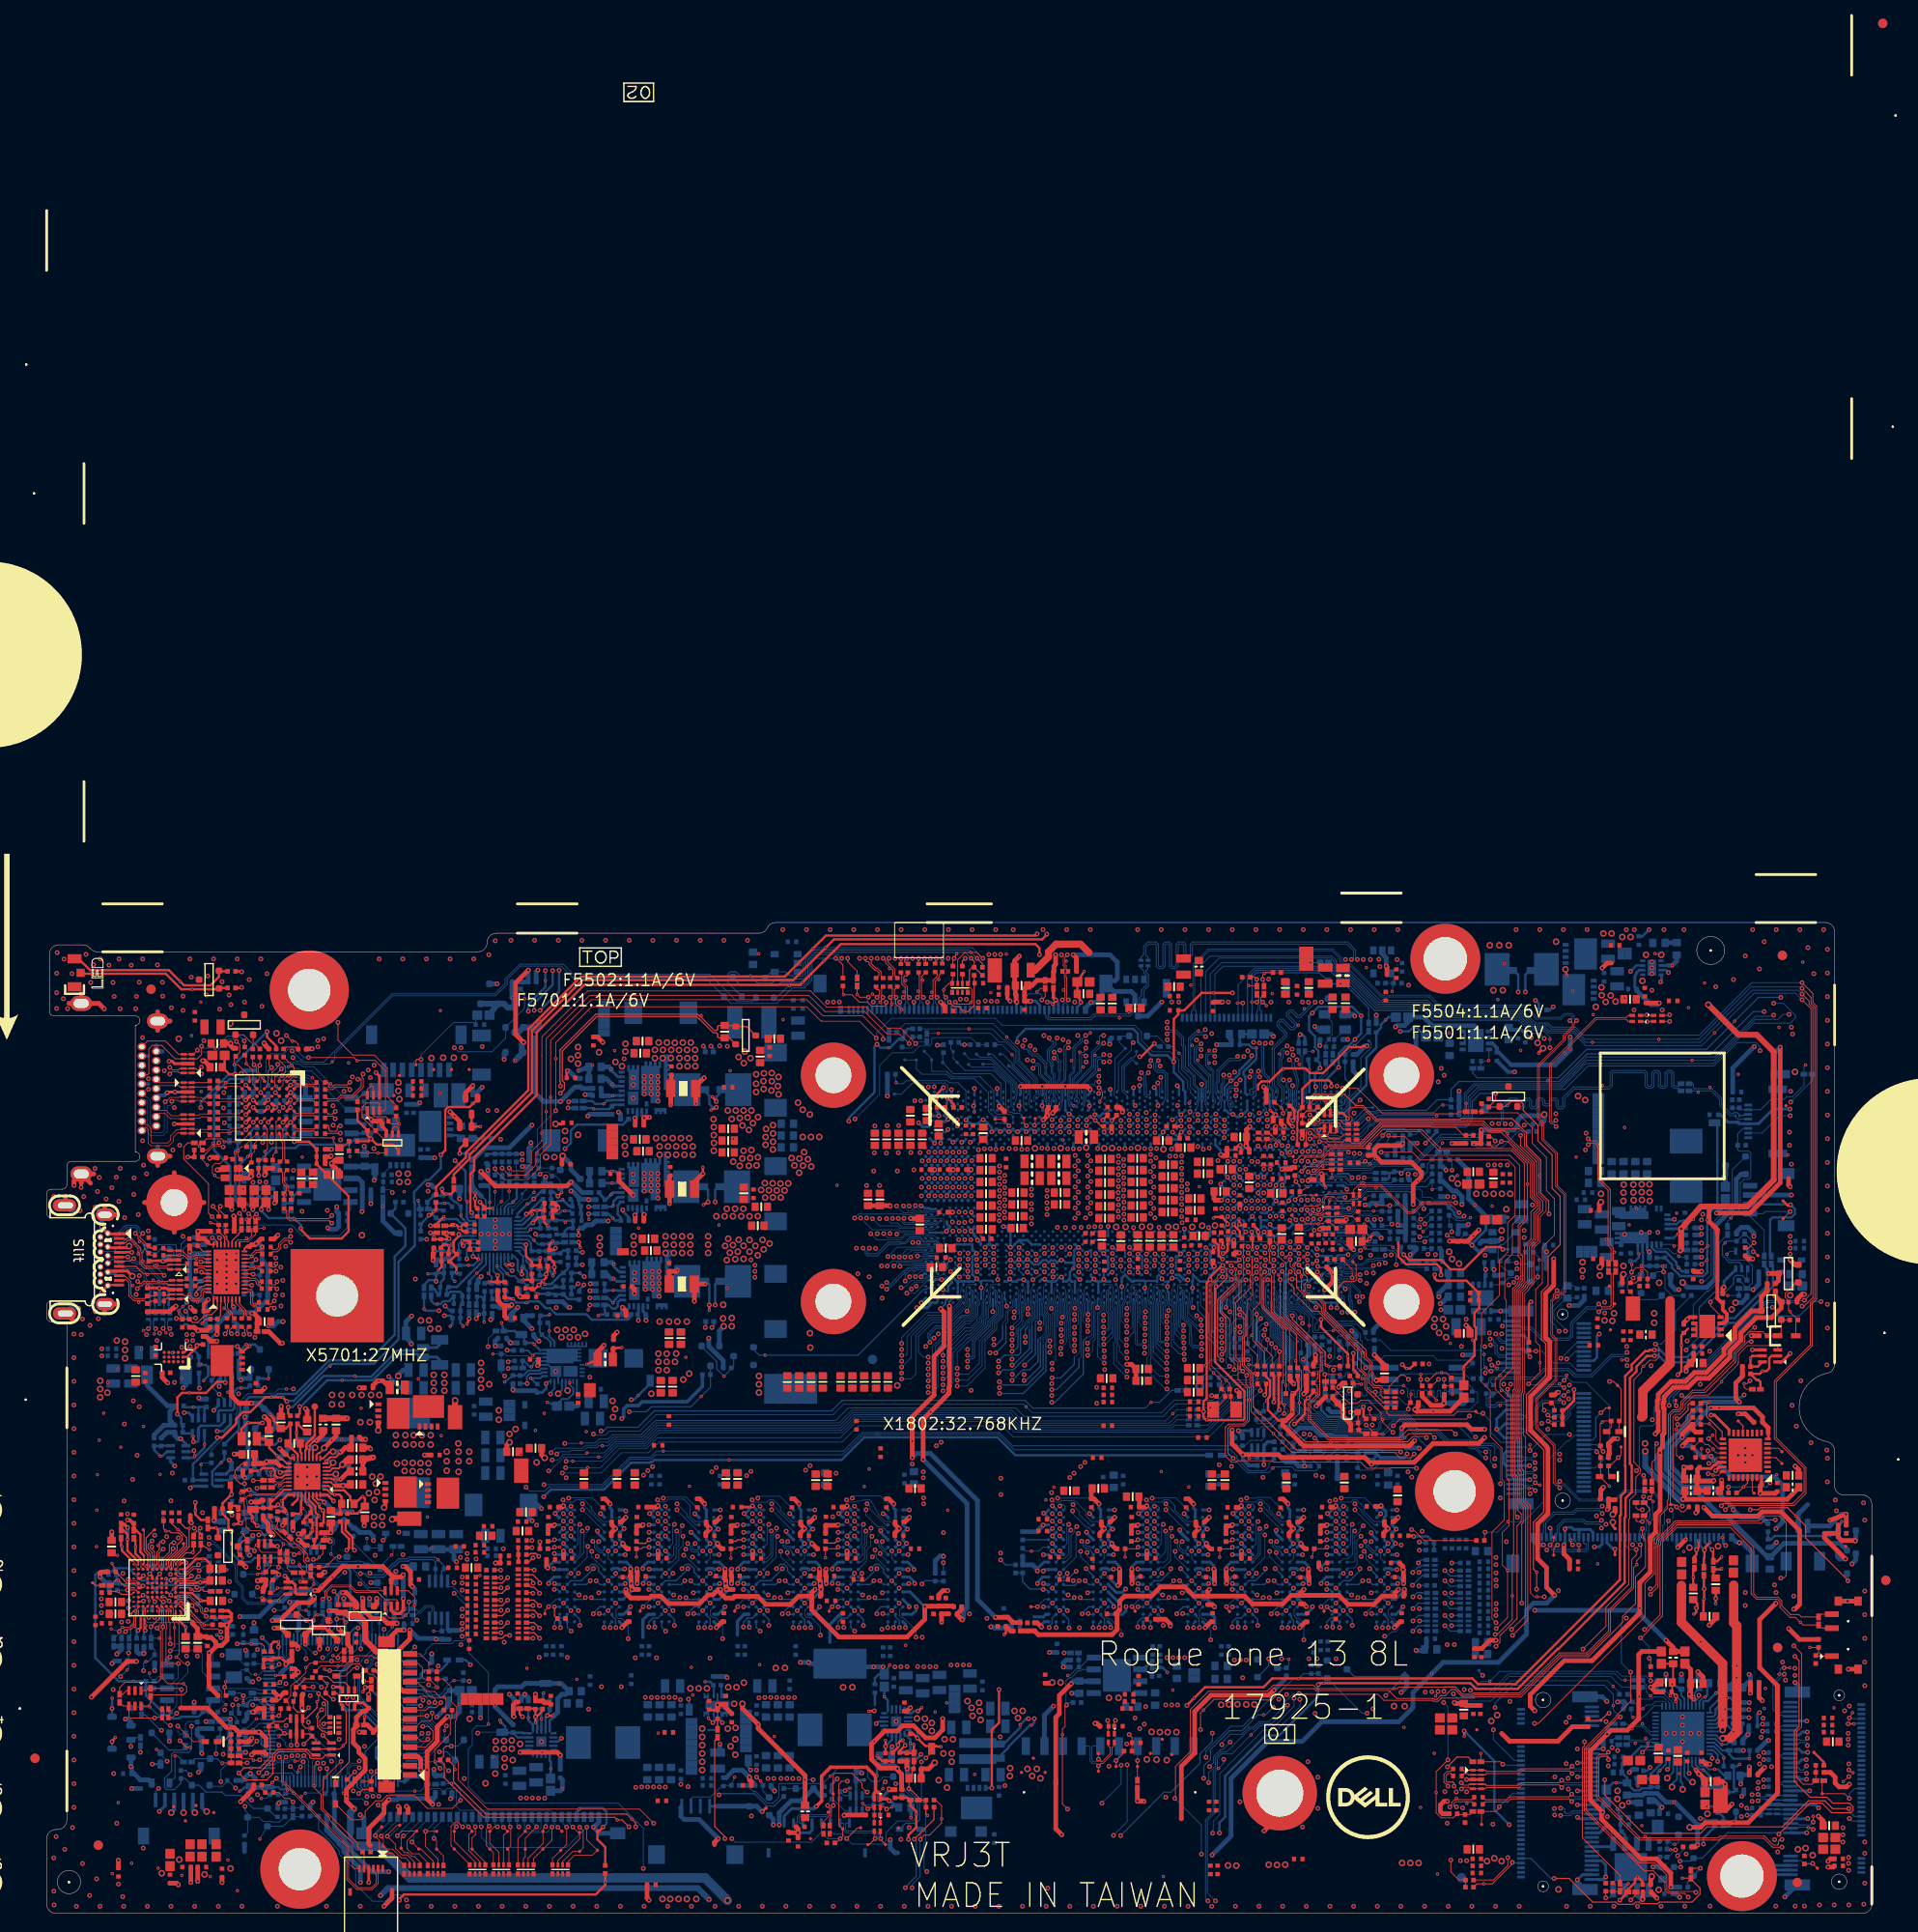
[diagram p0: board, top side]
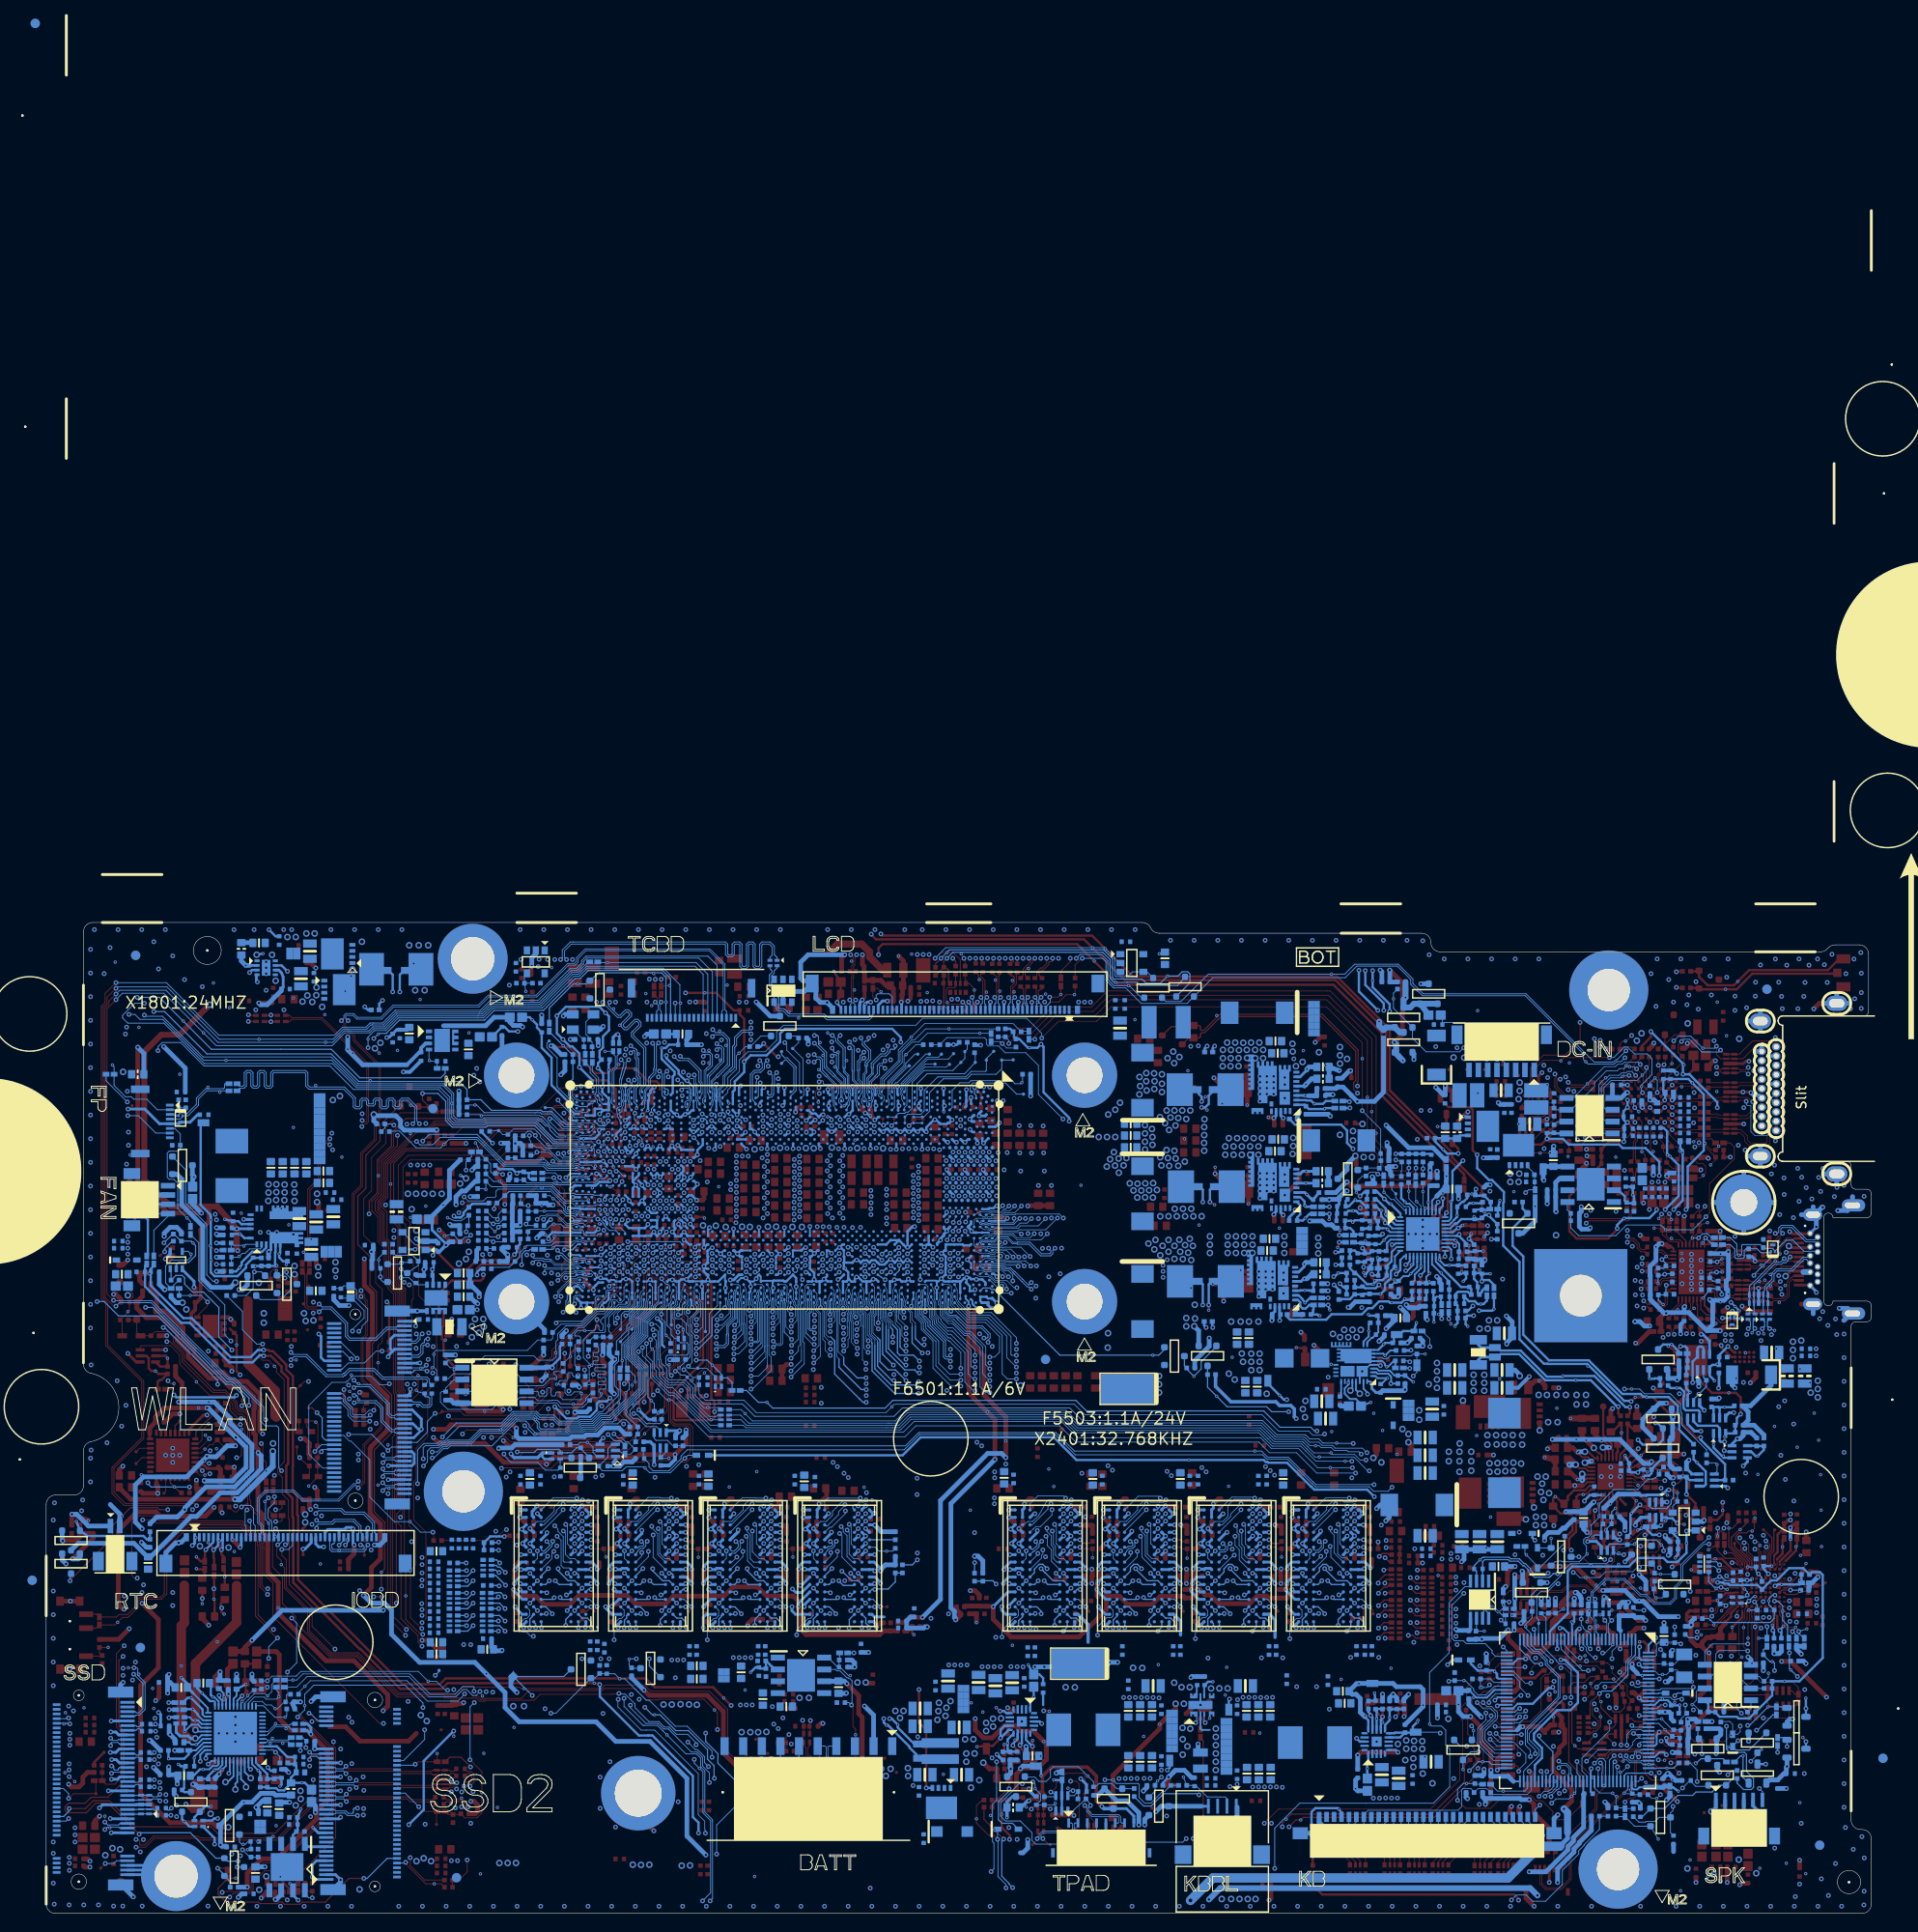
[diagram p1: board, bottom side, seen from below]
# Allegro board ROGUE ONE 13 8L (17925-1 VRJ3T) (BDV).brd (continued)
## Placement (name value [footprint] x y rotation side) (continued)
TP1804  TPAD14-OP-GP  [TPAD14-OP]  133.69 74.92 90 top
TP1806  TPAD14-OP-GP  [TPAD14-OP]  136.34 77.11 90 top
TP1807  TPAD14-OP-GP  [TPAD14-OP]  117.03 92.5 180 bottom
TP1808  TPAD14-OP-GP  [TPAD14-OP]  117.03 91.23 180 bottom
TP1903  TPAD14-OP-GP  [TPAD14-OP]  125.21 62.45 180 bottom
TP2201  TPAD14-OP-GP  [TPAD14-OP]  133.11 62.71 180 bottom
TP2202  TPAD14-OP-GP  [TPAD14-OP]  134.33 61.36 180 bottom
TP2402  TPAD14-OP-GP  [TPAD14-OP]  35.73 31.13 0 bottom
TP4401  TPAD28-2-GP  [TPAD28]  28.79 54.4 270 top
TP4601  TPAD14-OP-GP  [TPAD14-OP]  51.07 77.23 0 bottom
TP7202  TPAD14-OP-GP  [TPAD14-OP]  14.69 39.69 180 top
TP7203  TPAD14-OP-GP  [TPAD14-OP]  11.6 41.17 0 top
TP7204  TPAD14-OP-GP  [TPAD14-OP]  10.38 41.17 0 top
TP7205  TPAD14-OP-GP  [TPAD14-OP]  4.94 35.48 0 top
TP8304  TPAD14-OP-GP  [TPAD14-OP]  26.4 43.88 180 top
TP9101  TPAD14-OP-GP  [TPAD14-OP]  186.35 48.28 270 top
TP9102  TPAD14-OP-GP  [TPAD14-OP]  186.35 49.55 270 top
TP9103  TPAD14-OP-GP  [TPAD14-OP]  183.35 45.1 270 top
TP9104  TPAD14-OP-GP  [TPAD14-OP]  181.65 52.85 0 top
TPAD1  PTWO-CON8-16-GP  [196574-08021-3]  82.7 6.5 180 bottom
U2401  MEC1416-NU-D0-GP  [TQFP128-2H48]  31.54 21.79 180 bottom
U2502  SY6288C20AAC-GP  [SOT-23-5H56]  156.5 72.15 90 bottom
U2601  NCT7718W-GP  [MSOP8-1H44]  42.08 33.67 0 bottom
U2701  ALC3254-VA3-CG-GP  [QFN48J6-G465H40]  175.68 19.32 270 bottom
U4001  TPS22976DPUR-GP  [SON14J3020-G2610H34]  72.05 22.37 0 bottom
U4002  G5027RD1D-GP-U  [DFN8F3-G2517H32]  178.35 63.01 270 top
U4003  G5027RD1D-GP-U  [DFN8F3-G2517H32]  154.13 66.06 180 bottom
U4006  G5027RD1D-GP-U  [DFN8F3-G2517H32]  153.48 93.69 90 bottom
U4008  74LVC1G08GW-1-GP  [SC70-5H44]  182.03 70.12 0 bottom
U4302  S-1004NA23I-M5T1U-GP  [SOT-23-5H52]  20.11 42.06 90 bottom
U5501  SY6288C20AAC-GP  [SOT-23-5H56]  79.41 102 270 bottom
U5503  APL5324BI-TRG-GP  [SOT-23-5H58]  143.42 102.13 0 bottom
U5701  PS175HDMBGA64GTR2-B2-GP  [BGA64D7H51]  23.79 86.51 270 top
U5702  MX25L2006EM1I-12G-GP-U  [SOIC8H69]  30.27 85.62 90 bottom
U5703  TC7SZ08FU-LJ-CT-GP  [SC70-5H44]  37.12 82.7 0 top
U5801  APL5934KAI-TRG-GP-U  [SOIC8-G3530H63]  30.14 78.25 90 bottom
U6402  74LVC1G08GW-1-GP  [SC70-5H44]  32.42 23.06 0 top
U7101  TUSB546-DCIRNQR-1-GP  [QFN40J4060-G2848H32]  19.32 68.85 180 top
U7201  SN1703018ZQZR-GP  [BGA96G60-1H40]  11.85 34.94 180 top
U7202  W25Q80DVSNIG-GP-U  [SOIC8H69]  15.41 24.78 90 bottom
U7418  AON7403-GP-U  [PPAK-8P-3232H36]  18.84 59.33 90 top
U7419  NX20P5090UK-GP  [CSP15G154256H24]  13.63 59.71 270 top
U9102  NPCT750JAAYX-GP  [QFN32G5-G3D6H32]  182.41 49.17 270 top
USB1  SKT-USB30-63-GP  [SKT-USB30-118098-4]  2.02 70.19 270 top
WLAN1  SKT-NGFF75P-70-GP-U1  [40-42258-06741RHF-U1]  162.8 54.3 270 bottom
X1801  XTAL-24MHZ-182-GP  [OSC-3225-4P-3H36]  138.34 95.67 180 bottom
X1802  XTAL-32D768KHZ-98-GP  [SMD49-12H34]  126.51 54.07 90 top
X2401  XTAL-32D768KHZ-98-GP  [SMD49-12H34]  20.11 26.56 0 bottom
X5701  XTAL-27MHZ-192-GP  [SMD-OSC38H32]  19.88 79.44 180 top

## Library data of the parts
AFTP2507 AFTP2508 AFTP2601-AFTP2604 AFTP2901-AFTP2904 AFTP4301-AFTP4316 AFTP5001 AFTP6108-AFTP6114 AFTP6301-AFTP6306 AFTP6501-AFTP6525 AFTP6529-AFTP6539 AFTP6601 AFTP6602 AFTP6607-AFTP6609 = AFTE14P-75: tolerance: ZZ.AFT14.101
BATT1 = 50299-01001-002-U: tolerance: 20.F2460.010
BIOS1 = SOIC8-1H86: tolerance: 072.25128.0D61
C501 C805 C1139-C1142 C1711 C2201 C2206 C2207 C2221 C2406-C2408 C2410-C2414 C2416 C2420-C2423 C2428 C2429 C2502 C2602 C2605 C2608-C2610 C2612 C2614 C2714 C2721 C2722 C2726 C2729 C2740 C2742 C2744 C2746 C4007 C4010 C4034 C4037 C4039 C4040 C5507 C5726 C5736 C5744 C5750-C5752 C5755 C5756 C5761 C5765-C5767 C5773 C5774 C5777 C6101-C6104 C6106 C6307 C6309 C6501 C6502 C6504-C6506 C6605 C7115-C7118 C7206 C7244 C9108 C9112 C9113 EC1707 EC1712 EC1804 PC4438 PC4445 PC4518 PC5215 = C402H22: tolerance: 78.10421.2FLDL
C801-C804 C806 C1102-C1111 C1114 C1116 C1117 C1119 C1121 C1204-C1235 C1255 C1257-C1274 C1280-C1284 C1292-C1299 C1304-C1335 C1337-C1342 C1344-C1369 C1805 C1806 C2202-C2205 C2209-C2217 C2219 C2222-C2224 C2418 C2525 C4031 C4032 C4035 C4038 C4043 C5508 C5535 C5743 C7210 C9201 EC8905 PC4607 PC4708 PC4766 PC4809 PC4812 PC4866 PC4877 PC5108 PC5122 PC5202 PC5401 = C402H22: tolerance: 78.10523.5FLDL
C1112 C1113 C1115 C1118 C1122 C1128-C1135 C2208 C2220 C4041 C4042 C6317 C6318 C7205 PC1001-PC1032 PC1034 PC1036-PC1084 PC4509-PC4512 PC4514-PC4517 PC4525 PC4527 PC4529 PC4542 PC5104 PC5105 PC5107 PC5109 PC5201 PC5203 PC5205 PC5206 PC5404 PC5412 = C603H40: tolerance: 78.22610.5BLDL
C1120 C1123 C1136-C1138 C1237-C1246 C1275-C1279 C1288-C1291 C1371-C1379 C1390-C1399 C2501 C2601 C2727 C2730 C2732 C2733 C2745 C2907-C2909 C4006 C4008 C4012 C4013 C5502 C5517 C5518 C5742 C5746 C5747 C5749 C5764 C6105 C6320 C6323 C7119 C7208 C7211 C9106 C9109 PC5124 PC5402 PC5403 PC5413 PC5414 = C603H36: tolerance: 78.10610.5BLDL
C1201 C1203 C1236 C1286 C1301 C1303 C1336 C1343 C6306 C6308 C6310 C6319 PC4605 PC4630 PC4634 PC4653 = C402H22: tolerance: 078.47322.02FD
C1202 C1302 C2517 PC4420 PC4608 PC4625 PC4626 PC4628 PC4652 = C402H22: tolerance: 78.22321.2FLDL
C1256 C1370 C2409 C4303 C5757 C5758 C5762 C5768-C5770 C5775 C5776 PC4431 PC4613 PC4622 PC4635 PC4637 PC4654 PC5213 = C402H22: tolerance: 78.10322.2FLDL
C1285 C1388 = C402H22: tolerance: 78.3R374.1FL
C1701 C7217 C7218 PC5212 = C402H22: tolerance: 78.22124.2FLDL
C1710 C5753 C5759 C5763 C5771 = C402H22: tolerance: 078.47423.05FD
C1803 C1804 C1807 C1808 = C402H22: tolerance: 78.15034.1FLDL
C2218 C2604 C5503 C5515 C5521 PC4415 PC4421 PC4422 PC4507 PC4520 = C603H36: tolerance: 78.47520.5BLDL
C2405 C2613 = C402H22: tolerance: 78.10134.1FLDL
C2424 C2425 FC1103 FC5501 FC5502 FC5505 FC8911 FC8913 FC8932 FC8934 FC8943 FC8945 FC8946 FC8948 FC8949 FC8951-FC8954 = C402H22: tolerance: 78.18034.1FLDL
C2427 C2737 C4009 C7201-C7203 PC4524 PC5001 = C603H36: tolerance: 78.22523.5BLDL
C2435 C2436 C2441 C2603 C2607 PC4601 PC4611 PC4612 PC4623 PC4632 PC4640 = C402H22: tolerance: 78.22224.2FLDL
C2503 C5748 = C603H36: tolerance: 78.47422.5BLDL
C2606 = C603H36: tolerance: 78.47134.1BL
C2731 C2734-C2736 C2743 C5754 C5760 C5772 = C402-TO0D2H28: tolerance: 078.10610.05FD
C2739 C2741 C4301 C5778 C7301 C7306 PC4416 PC4417 PC4419 PC4425 PC4439 PC4440 PC5410 = C603H36: tolerance: 78.10522.5BLDL
C4001 C4002 PC4614 PC4618 = C402H22: tolerance: 78.47124.2FLDL
C4003 = C402H22: tolerance: 78.22423.5FL
C4004 C4005 C4306 C5514 EC4301 PC4401-PC4405 PC4407-PC4414 PC4427 PC4428 PC4502-PC4505 PC4519 PC4523 PC5002 PC5003 PC5111 PC5115 PC5209-PC5211 PC5216 = C805H58: tolerance: 78.10622.51LDL
C4302 C5512 C5516 C7302-C7304 C7307 EC2201 EC2402 EC2403 EC2712-EC2714 EC4302 EC4308 EC4311 EC4313 EC4701 EC5001 EC5505 EC8901-EC8904 EC8906-EC8934 EC8937-EC8950 PC4406 PC4501 PC4506 PC4508 PC4513 PC4521 PC4522 PC4528 PC4530-PC4532 PC4543 PC4602 PC4603 PC4631 PC4633 PC5004 PC5113 PC5114 PC5116 PC5204 PC5208 PC5214 PC5427 = C402H22: tolerance: 78.10422.5FLDL
C4304 C4305 EC2709-EC2711 PC4615 PC4620 PC4644 = C402H22: tolerance: 78.10324.2FLDL
C4343 C7401 = C402H22: tolerance: 78.15224.2FLDL
C4344 C5513 EC1706 EC2901-EC2904 EC4307 EC4312 PC4432 PC4433 PC4435 PC4526 PC4533 PC4616 PC4617 PC4619 PC4642 PC4643 PC4651 PC4706 PC4810 PC4813 = C402H22: tolerance: 78.10224.2FLDL
C5501 = C402H22: tolerance: 78.10421.2FLDL; signal model: Graser_C5501
C5504 = C402H22: tolerance: 78.10421.2FLDL; signal model: Graser_C5504
C5506 = C402H22: tolerance: 78.10421.2FLDL; signal model: Graser_C5506
C5509 = C402H22: tolerance: 78.10421.2FLDL; signal model: Graser_C5509
C5510 = C402H22: tolerance: 78.10421.2FLDL; signal model: Graser_C5510
C5511 = C402H22: tolerance: 78.10421.2FLDL; signal model: Graser_C5511
C5519 = C402H22: tolerance: 78.10421.2FLDL; signal model: Graser_C5519
C5531 = C402H22: tolerance: 78.10421.2FLDL; signal model: Graser_C5531
C5532 = C402H22: tolerance: 78.10421.2FLDL; signal model: Graser_C5532
C5533 = C402H22: tolerance: 78.10421.2FLDL; signal model: Graser_C5533
C5724 = C0201H13: tolerance: 078.R7574.01S1
C5727 = C402H22: tolerance: 78.10421.2FLDL; signal model: Graser_C5727
C5728 = C402H22: tolerance: 78.10421.2FLDL; signal model: Graser_C5728
C5729 C5730 = C402H22: tolerance: 78.20034.1FLDL
C5731 = C402H22: tolerance: 78.10421.2FLDL; signal model: Graser_C5731
C5732 = C402H22: tolerance: 78.10421.2FLDL; signal model: Graser_C5732
C5733 = C402H22: tolerance: 78.10421.2FLDL; signal model: Graser_C5733
C5734 = C402H22: tolerance: 78.10421.2FLDL; signal model: Graser_C5734
C5735 = C402H22: tolerance: 78.10421.2FLDL; signal model: Graser_C5735
C5737 = C402H22: tolerance: 78.10421.2FLDL; signal model: Graser_C5737
C5738 = C402H22: tolerance: 78.10421.2FLDL; signal model: Graser_C5738
C5739 = C402H22: tolerance: 78.10421.2FLDL; signal model: Graser_C5739
C5740 = C402H22: tolerance: 78.10421.2FLDL; signal model: Graser_C5740
C5741 = C402H22: tolerance: 78.10421.2FLDL; signal model: Graser_C5741
C5745 PC5405 PC5411 = C402H22: tolerance: 78.68034.1FLDL
C6107 = C402H22: tolerance: 78.10421.2FLDL; signal model: Graser_C6107
C6108 = C402H22: tolerance: 78.10421.2FLDL; signal model: Graser_C6108
C6302 = C402H22: tolerance: 078.22423.05FD; signal model: Graser_C6302
C6303 = C402H22: tolerance: 078.22423.05FD; signal model: Graser_C6303
C6304 C6305 C6321 C6322 EC1903 EC5503 EC5504 EC5506 EC6501-EC6504 PC4610 PC4624 PC4639 = C402H22: tolerance: 78.33034.1FLDL
C6311 = C402H22: tolerance: 078.22423.05FD; signal model: Graser_C6311
C6312 = C402H22: tolerance: 078.22423.05FD; signal model: Graser_C6312
C6313 = C402H22: tolerance: 078.22423.05FD; signal model: Graser_C6313
C6314 = C402H22: tolerance: 078.22423.05FD; signal model: Graser_C6314
C6315 = C402H22: tolerance: 078.22423.05FD; signal model: Graser_C6315
C6316 = C402H22: tolerance: 078.22423.05FD; signal model: Graser_C6316
C6324 = C402H22: tolerance: 078.22423.05FD; signal model: Graser_C6324
C6325 = C402H22: tolerance: 078.22423.05FD; signal model: Graser_C6325
C6326 = C402H22: tolerance: 078.22423.05FD; signal model: Graser_C6326
C6327 = C402H22: tolerance: 078.22423.05FD; signal model: Graser_C6327
C6401 = C402H22: tolerance: 78.10421.2FL
C7101 = C402H22: tolerance: 78.10421.2FLDL; signal model: Graser_C7101
C7102 = C402H22: tolerance: 78.10421.2FLDL; signal model: Graser_C7102
C7103 = C402H22: tolerance: 78.10421.2FLDL; signal model: Graser_C7103
C7104 = C402H22: tolerance: 78.10421.2FLDL; signal model: Graser_C7104
C7105 = C402H22: tolerance: 78.10421.2FLDL; signal model: Graser_C7105
C7106 = C402H22: tolerance: 78.10421.2FLDL; signal model: Graser_C7106
C7107 = C402H22: tolerance: 78.10421.2FLDL; signal model: Graser_C7107
C7108 = C402H22: tolerance: 78.10421.2FLDL; signal model: Graser_C7108
C7109 = C402H22: tolerance: 78.10421.2FLDL; signal model: Graser_C7109
C7110 = C402H22: tolerance: 78.10421.2FLDL; signal model: Graser_C7110
C7111 = C402H22: tolerance: 78.10421.2FLDL; signal model: Graser_C7111
C7112 = C402H22: tolerance: 78.10421.2FLDL; signal model: Graser_C7112
C7113 = C402H22: tolerance: 78.10421.2FLDL; signal model: Graser_C7113
C7114 = C402H22: tolerance: 78.10421.2FLDL; signal model: Graser_C7114
C7120 = C402H22: tolerance: 78.33420.5FL; signal model: Graser_C7120
C7121 = C402H22: tolerance: 78.33420.5FL; signal model: Graser_C7121
C7122 = C402H22: tolerance: 78.33420.5FL; signal model: Graser_C7122
C7123 = C402H22: tolerance: 78.33420.5FL; signal model: Graser_C7123
C7161 = C402H22: tolerance: 78.10422.5FLDL; signal model: Graser_C7161
C7162 = C402H22: tolerance: 78.10422.5FLDL; signal model: Graser_C7162
C7163 = C402H22: tolerance: 78.10422.5FLDL; signal model: Graser_C7163
C7164 = C402H22: tolerance: 78.10422.5FLDL; signal model: Graser_C7164
C7204 = C603H40: tolerance: 78.22610.L4L
C7212 = C402H22: tolerance: 078.22423.05FD
C7305 = C805H54: tolerance: 78.47522.51LDL
CN6601 = 300E40-1010RA-G3: tolerance: 020.F0847.0040
CPU1 = BGA1528M2446-1H52: tolerance: ZZ.00CPU.271
D1701 D2403 D4002 D4003 D6101 D6102 = SOD523AKH26: tolerance: 83.R2003.A8M
D2401 D2404 PD4407 = SOD323AKH38: tolerance: 83.R2004.G8F
D2402 D4001 PD4404 = SOD323AKH44: tolerance: 83.00355.G1F
D2501 D2702 D5501 D5502 PD4401 PD4408 = SOT-23-9H44: tolerance: 75.00054.A7D
D2502 = SOD323-2513AKH36: tolerance: 83.R2004.J8F
D2503 D6401 = SOT-23-9H44: tolerance: 75.BAT54.07D
D2601 = SOD323AKH38: tolerance: 83.R5003.H8H
D4301 = D4724AKH44: tolerance: 083.00624.00AM
D4302 ED4304-ED4306 = SOT23-2D4-312H44: tolerance: 75.00099.O7D
D4303 = SOT23-2D4-312H60: tolerance: 83.03024.0A1
D4304 = SOD123AK-2H43: tolerance: 83.SMF18.AAH
D4305 = SOD323AKH38: tolerance: 83.R2004.B8F
D5701 = SOT23-2D4-312H44: tolerance: 83.00056.Y11
D7301 = D4724AKH44: tolerance: 83.3R010.C8M
DB1 = DM-87212-1400N-01: tolerance: ZZ.F0765.01401
DB3 = 50696-00601-001: tolerance: 20.K0691.006
DCIN1 = 3703K-Q08N-03R-U: tolerance: 20.F2120.008
EC1801 EC1901 EC2503 EC2601 EC2602 EC4306 EC4309 EC4310 FC6101 PC4430 = C402H22: tolerance: 78.10034.1FLDL
EC1803 EC2501 EC2502 FC1801 FC8905-FC8910 FC8912 FC8914-FC8931 FC8933 FC8935-FC8942 FC8944 FC8947 FC8950 = C402H22: tolerance: 078.4R7B4.01FD
EC4534 = C805H54: tolerance: 78.22522.21L
EC5501 = C402H22: tolerance: 78.8R064.1FLDL
ED301 ED1701-ED1704 ED1801 ED2403 ED5502 ED6401 = SOT23-2D4-312H46: tolerance: 75.05125.07D
ED5501 = SOT-6H58: tolerance: 075.09904.0A7C
ED5701-ED5703 = DFN10G2510H22: tolerance: 075.01043.0073
ED6301 ED6302 ED7301-ED7303 = SLP2510P8-1H22: tolerance: 075.00550.0071
ED7305 ED7306 ED9202 = SOT883-1D0-321H20: tolerance: 83.05315.0A0
EL4301-EL4304 R2739 R5127 R5509 R5546 R6114 = 0R0805-PAD-1-U: tolerance: ZZ.00PAD.M31
EL5501 = LD85D65-4P-1H20: tolerance: 068.09002.2001; signal model: Graser_EL5501
EL7201 = LD85D65-4P-1H20: tolerance: 068.09002.2001; signal model: Graser_EL7201
EL7202 = LD85D65-4P-1H20: tolerance: 068.09002.2001; signal model: Graser_EL7202
ER2901-ER2904 PR4501 PR4502 PR5111 R1103 R1104 R2202-R2205 R2446 R2516 R2612 R2705 R2707 R2712 R2724 R2749 R2751 R2908 R2910 R4036 R4043 R4317 R5511 R5780-R5785 R6302 R6306-R6308 R9213 = 0R0603-PAD-1-U: tolerance: ZZ.00PAD.M21
ER7301 ER7302 R2522 R5508 = R805H24: tolerance: 63.R0031.16L
F5501 F5502 F5504 F5701 F6501 = POLYSW-2114H30: tolerance: 69.48001.081
F5503 = POLYSW-4633-UH43: tolerance: 69.50007.A31
FAN1 = 50224-0040N-001: tolerance: 20.F1639.004
FC1102 = C402H22: tolerance: 78.22510.5FLDL
FC2738 FC5701-FC5704 = C402H22: tolerance: 78.12034.1FLDL
FP1 = FH52-8S-D5SH: tolerance: 20.K0767.008
FSW1 = MSS3-Q-T-R: tolerance: 62.40018.641
G1801 = CON2O-U: tolerance: ZZ.CON2O.XXX
G5701 PG4401 PG4402 PG4405 PG4406 PG4408 PG4501-PG4513 PG4515-PG4531 PG4707-PG4713 PG4808 PG4809 PG4813 PG4815-PG4825 PG5001-PG5003 PG5011 PG5101-PG5103 PG5110 PG5113 PG5114 PG5116 PG5122 PG5201-PG5212 PG5214 PG5401-PG5404 = GAP-CLOSE-PWR-3: tolerance: ZZ.CLOSE.001
H1 H2 H10 = HOLE335R178: tolerance: ZZ.00PAD.7F1
H3 H5 = HOLE296R182: tolerance: ZZ.00PAD.Y51
H4 = HOLE394X394R174: tolerance: ZZ.00PAD.R61
H6-H9 = HOLE276R150: tolerance: ZZ.00PAD.H91
H12 = STF237R113H62: tolerance: 34.4SE26.201
H13 = HOLE315R197: tolerance: ZZ.00PAD.T61
HDMI1 = SKT-HDMI23-188142: tolerance: 022.10025.00P1
KB1 = 196528-30041-3: tolerance: 020.K0236.0030
KBBL1 = 50698-00401-W01-U: tolerance: 020.K0298.0004
LCD1 = 300E50-1030RA-G4: tolerance: 020.F0688.0050
LED1 = LED3020-3P-19H44: tolerance: 083.1212A.0070
PC4418 PC4434 PC4437 = C805H58: tolerance: 78.22612.51L
PC4423 PC4436 PC4606 PC4707 PC4808 PC4811 PC5005 = C603H36: tolerance: 78.22422.2BLDL
PC4424 PC4426 = C603H36: tolerance: 078.10524.05BD
PC4429 = C402H22: tolerance: 078.47222.02FD
PC4604 PC4629 PC4638 PC4641 = C402H22: tolerance: 78.33124.2FLDL
PC4621 = C402H22: tolerance: 78.68124.2FL
PC4701-PC4704 PC4802-PC4805 PC4814-PC4817 = C603H40: tolerance: 78.10612.5BL
PC5112 = C603H36: tolerance: 78.47520.L0L
PC5117 = C603H38: tolerance: 78.10610.L0L
PC5118 = C402H22: tolerance: 78.15224.2FL
PC5406 = C402H22: tolerance: 78.47224.2FL
PD5101 = SOD323AKH40: tolerance: 083.04024.0AA1
PG5223 = GAP-CLOSE-PWR: tolerance: ZZ.CLOSE.011
PL4401 = L109100-2430-UH119: tolerance: 068.2R210.2351
PL4501 PL4502 = L7066-1830-UH119: tolerance: 68.1R510.10K
PL4701 PL4801 PL4802 = L7366-1930H95: tolerance: 068.R1510.2091
PL5001 = L7066-1830-UH119: tolerance: 68.R4710.10M
PL5101 = L4947-1115H119: tolerance: 68.1R010.20R
PL5201 = L7066-1830-UH95: tolerance: 68.1R010.20G
PQ4405 PQ4415 PQ4416 PQ4418 Q401 Q1702 Q2416 Q2417 Q2601 Q4349 Q5705 Q6504 Q7404 Q7405 = SOT-363H44: tolerance: 75.27002.F7C
PQ4408 = SOT23CBE2D4H44: tolerance: 84.03906.R11
PQ4417 Q502 Q1802 Q2408 Q2414 Q2505 Q2510 Q2602 Q4001 Q6102 Q6503 Q9202 = SOT23DGS2D4H44: tolerance: 84.2N702.J31
PR2455 = R402H16: tolerance: 64.15035.6DL
PR4401 = R1206H24: tolerance: 64.R0205.81L
PR4402 PR4408 PR4705 PR4804 PR4810 PR5001 = R603H22: tolerance: 64.2R205.55L
PR4403 PR4416 = R805H24: tolerance: 63.2R231.16L
PR4404 = R402H16: tolerance: 64.40235.6DL
PR4405 = R402H16: tolerance: 64.4R705.6DL
PR4406 PR4409 PR4417 PR4427 PR4429 PR4435 PR4472 PR4474 PR4487 PR4608 PR4629 PR4821-PR4824 PR5203 PR5402 R1506 R1508 R1510 R1524 R1716 R1718 R1731 R2441 R2444 R4311 R4369 R4370 R4379 R6005 R6305 R7215 R7405 R7406 R7423-R7428 = R402H16: tolerance: 64.10035.6DL
PR4407 = R3720H40: tolerance: 64.R0105.7FL
PR4410 = R402H16: tolerance: 64.10535.60L
PR4411 PR4636 PR4658 R302 R6401 = R402H16: tolerance: 64.49905.6DL
PR4412 PR4462 PR4476 PR4477 PR4483 PR4485 PR4488-PR4494 PR4504 PR4515 PR4516 PR4613 PR5113 PR5209 PR5406 PR5408 PR5417 R504 R709 R732 R1704 R1706 R1713 R1728 R1804 R1806 R1839 R1840 R2019 R2025-R2027 R2119 R2402 R2425 R2440 R2445 R2447 R2459 R2462 R2467 R2468 R2473 R2482 R2602 R2611 R2613 R2614 R2721 R2738 R2754 R2907 R2909 R2921-R2923 R4002 R4010 R4011 R4024 R4029 R4030 R4039 R4301 R4368 R5501 R5503 R5510 R5521-R5523 R6301 R6310 R6311 R6316 R6421 R6422 R6510 R6512 R7009 R7010 R7012 R7013 R7114 R7116 R7124 R7149 R7151 R7153 R7201 R7211 R7212 R7216 R7217 R7220 R7221 R7227 R7229 R7235 R7236 R7403 R9216 R9218 R9806 = 0R0402-PAD-1: tolerance: ZZ.00PAD.M11
PR4413 = R402H16: tolerance: 64.60415.6DL
PR4414 PR4420 = 0R0805-PAD: tolerance: ZZ.R0805.ZZZ
PR4422-PR4425 PR4610 = R402H16: tolerance: 64.1R005.6DL
PR4426 = R402H16: tolerance: 64.19635.6DL
PR4436 PR4513 PR4514 PR5114 R1841 R2567 R7208 R7214 R7231 R7237 R7241 R7242 R7245 R7250 = R402H16: tolerance: 63.10534.1DL
PR4450 PR4486 PR5204 PR5410 R506 R507 R2001 R2448 R2449 R2465 R4333 R5542 R5774 = R402H16: tolerance: 64.10025.6DL
PR4463 PR4484 PR4495 PR4503 PR4530 PR4614 PR4669 PR5112 R404 R1220 R1221 R1339 R1340 R1601 R1602 R1708 R2028 R2102 R2409 R2410 R2418 R2461 R2472 R2479 R2481 R2494 R2495 R2498 R2505 R2512 R2513 R2601 R2615 R2616 R2728 R2746 R4014 R4018 R4019 R4033 R4040 R5502 R5761 R6107 R6108 R6110 R6314 R6315 R6419 R6420 R6505 R6506 R6801-R6803 R7204 R7218 R7219 R9136 R9137 R9139 R9141 R9214 R9217 = R402H16: tolerance: 63.R0034.1DL
PR4473 PR4479 PR4505 PR4510 PR5104 PR5208 R303 R403 R407 R1715 R1727 R1737 R2417 R2434 R2451-R2456 R2480 R2489 R2496 R2497 R2499 R2518 R2520 R2742 R2744 R2747 R4031 R4032 R4309 R4318 R4378 R5504 R5507 R5733 R5764 R6508 R6509 R7101 R7102 R7202 R9212 R9215 = R402H16: tolerance: 63.10434.1DL
PR4475 = R402H16: tolerance: 64.68035.6DL
PR4478 PR4604 PR4607 PR4627 PR4631 PR4639 PR4659 PR4663 R503 R719 R720 R726 R807-R810 R1604 = R402H14: tolerance: 64.10005.6DL
PR4506 PR4507 PR4509 PR4511 PR4603 PR4615 PR4635 PR4645 PR4651 R5760 R9805 = R402H16: tolerance: 64.10015.6DL
PR4508 PR4512 = R402H16: tolerance: 64.20035.L0L
PR4551 = R402H16: tolerance: 64.56035.6DL
PR4601 PR4602 PR4612 PR4623 PR4647 PR4649 PR4665-PR4668 PR4701 PR4702 PR4706 PR4802 PR4806 PR4811 PR4812 PR5004 R5801 = 0R0402-PAD: tolerance: ZZ.R0402.001
PR4605 = R402H16: tolerance: 64.75R05.6DL
PR4606 = R402H16: tolerance: 64.45R35.6DL
PR4609 = R402H15: tolerance: 64.10025.L0L
PR4611 PR4646 PR4650 = NTC-402H22-U: tolerance: 69.60011.201
PR4616 PR4618 PR4643 PR4652 PR4662 = R402H16: tolerance: 64.11025.6DL
PR4617 PR4654 = NTC-402H22-U: tolerance: 069.60012.0001
PR4620 = R402H16: tolerance: 64.43005.6DL
PR4621 = R402H16: tolerance: 64.27425.6DL
PR4622 PR4809 PR4815 PR5108 R2609 = R402H14: tolerance: 64.10R05.6DL
PR4624 R304 R305 R601 R1208 R1330 = R402H16: tolerance: 64.49R95.6DL
PR4625 PR4641 PR4653 = R402H16: tolerance: 64.26115.6DL
PR4626 = R402H16: tolerance: 64.33015.6DL
PR4628 = R402H16: tolerance: 64.93115.6DL
PR4630 PR4657 = R402H16: tolerance: 64.20015.6DL
PR4632 = R402H16: tolerance: 64.30105.6DL
PR4633 = R402H16: tolerance: 64.25515.6DL
PR4637 = R402H16: tolerance: 64.17815.6DL
PR4638 = R402H16: tolerance: 64.20015.L0L
PR4640 = R402H16: tolerance: 64.24915.6DL
PR4642 = R402H16: tolerance: 64.53605.6DL
PR4644 = R402H16: tolerance: 64.41225.6DL
PR4648 = R402H16: tolerance: 64.35705.6DL
PR4655 = R402H16: tolerance: 64.23225.6DL
PR4656 = R402H16: tolerance: 64.28715.6DL
PR4660 = R402H16: tolerance: 64.19115.6DL
PR4661 R4377 = R402H16: tolerance: 64.84525.6DL
PR4703 PR4805 PR4814 = R1206H28: tolerance: 63.2R232.11L
PR4704 PR4803 PR4813 = R402H16: tolerance: 64.2R205.6DL
PR4708 PR4808 PR4816 PR5003 = R402H16: tolerance: 64.36515.6DL
PR4712 PR4817 PR4818 = R402H16: tolerance: 64.51115.6DL
PR5101 = R402H16: tolerance: 64.10225.6DL
PR5102 = R402H16: tolerance: 64.64915.6DL
PR5103 = R402H16: tolerance: 64.51035.6DL
PR5107 = R402H16: tolerance: 64.62015.6DL
PR5110 = R805H24: tolerance: 64.2R205.16L
PR5201 = R402H16: tolerance: 64.88725.6DL
PR5202 = R402H16: tolerance: 64.31615.6DL
PR5210 R1719 R2517 R4308 = R402H16: tolerance: 64.47025.6DL
PR5401 PR5409 = R402H16: tolerance: 63.47334.1DL
PR5403 = R402H16: tolerance: 64.16525.6DL
PR5404 = R402H16: tolerance: 64.13325.6DL
PR5419 = R402H16: tolerance: 64.29425.6DL
PR5420 = R402H16: tolerance: 64.13725.6DL
PT4701 PT4801 PT4803 = CT7343H83: tolerance: 79.33719.20C
PT4805-PT4807 = CT7343H119: tolerance: 080.1073H.0001
PU4301 PU4302 U7418 = PPAK-8P-3232H36: tolerance: 84.07403.037
PU4401 = QFN32J4-G2D85H34: tolerance: 074.09538.0073
PU4403-PU4406 = PPAK-8P-3232H36: tolerance: 084.07380.0037
PU4412 = PPAK-8P-3232H36: tolerance: 84.07401.037
PU4501 = QFN20Z3-G1D1H36: tolerance: 074.08286.0043
PU4502 = QFN20Z3-G1D1H36: tolerance: 074.08288.0B43
PU4601 = QFN40J5-G3D6-DIFF-H34: tolerance: 074.95859.0D33
PU4701 PU4801 PU4802 = QFN31G5-G4P-9H34: tolerance: 074.05038.0A73
PU5001 = DFN8G2-G1710-U1H40: tolerance: 074.95808.0B73
PU5002 PU5003 = PPAK-8P-3232H36: tolerance: 084.07408.0037
PU5101 = QFN32J4-G3PH32: tolerance: 074.05388.0043
PU5201 = QFN22G4-G2PH42: tolerance: 074.02262.0043
PU5401 PU5403 U5801 = SOIC8-G3530H63: tolerance: 074.05934.003D
Q501 Q4301 Q6403 = SOT23DGS2D4H44: tolerance: 084.00138.0A31
Q1701 Q2001 Q6404 Q7406 Q7407 = SOT-363H44: tolerance: 075.00138.0A7C
Q2507 Q4002 Q4348 Q6101 Q6502 Q7401 Q9201 = SOT23DGS2D4H44: tolerance: 084.03415.0031
Q2603 Q4302 = SOT23CBE2D4H46-U: tolerance: 84.T3904.K11
Q4304 = SOT323CBE2D2H40: tolerance: 84.05212.B11
Q4305 = SC70-2D2-312H44: tolerance: 84.00024.01K
Q6401 Q6402 Q6505 = SOT23CBE2D6H62: tolerance: 084.02418.0011
Q6501 = SOT23DGS2D4H44: tolerance: 084.03402.0031
R301 R308 R1502 R1503 R1507 R1517 R1518 R1527 R1702 R1909 R2432 R2463 R2510 R4005 R6513 R7140-R7147 R7152 R7170-R7174 = R402H16: tolerance: 63.10234.1DL
R310 R317 = R402H16: tolerance: 63.51034.1DL
R401 R1203 R1303 = R402H16: tolerance: 64.24R95.6DL
R402 R405 R406 R1519 R1606 R1608 R1701 R1707 R1714 R1717 R1721-R1723 R1726 R1738 R1816 R1819-R1821 R1910 R1911 R2002 R2005 R2008-R2018 R2022 R2029-R2035 R2037 R2038 R2041 R2043-R2046 R2050-R2053 R2107 R2109-R2118 R2414 R2415 R2430 R2431 R2514 R2607 R2743 R4004 R4009 R4034 R4303 R5505 R5741 R5744-R5747 R6106 R6109 R6111 R6118 R6303 R6304 R6312 R6313 R6405 R6406 R6511 R7118 R7222 R7224 R9140 R9148 R9149 = R402H16: tolerance: 63.10334.1DL
R501 = R402H16: tolerance: 64.12105.6DL
R502 = R402H16: tolerance: 64.80R65.6DL
R505 = R402H16: tolerance: 64.47005.6DL
R723 = R402H16: tolerance: 64.54R95.6DL
R727 = R402H16: tolerance: 63.56034.1DL
R728 = R402H16: tolerance: 63.22134.1DL
R811-R815 = R805H16: tolerance: 063.R0007.0101
R1201 R1204 R1205 R1234 R1301 R1304-R1306 = R402H16: tolerance: 64.24006.6DL
R1202 R1302 = R402H16: tolerance: 64.2R705.6DL
R1211 R1224 R1311 R1312 = R402H16: tolerance: 64.36R05.6DL
R1212-R1215 R1331-R1334 = R402H16: tolerance: 64.24005.6DL
R1222 R1223 R1320 R1321 = R402H16: tolerance: 64.18015.6DL
R1225 R1226 R1313 R1314 R1912 R1913 = R402H16: tolerance: 64.33R05.6DL
R1501 R1505 R1515 R1523 R1525 R1552-R1555 R4035 R4041 R4042 R4316 R6112 R6121-R6123 = R402H16: tolerance: 63.20334.1DL
R1504 R1512 R1516 R1521 R1522 R1551 R2511 R2519 R5517 R5518 R5735 R5738-R5740 R5742 R5743 R5754 R5756 R5757 R7121 = R402H16: tolerance: 63.47234.1DL
R1509 R1511 R1513 R1514 R1520 = R402H15: tolerance: 63.47234.L0L
R1603 = R402H16: tolerance: 64.11305.6DL
R1730 = R402H16: tolerance: 63.33434.1DL
R1803 = R402H16: tolerance: 64.60R45.6DL
R1805 = R402H16: tolerance: 64.33R05.6DL; signal model: Graser_R1805
R1815 R2504 = R402H16: tolerance: 63.10634.1DL
R1818 = R402H16: tolerance: 64.82015.6DL
R1837 = R402H16: tolerance: 63.15434.1DL
R1901 R2108 = R402H16: tolerance: 64.20005.6DL
R1908 = 0R0402-PAD-1: tolerance: ZZ.00PAD.M11; signal model: Graser_R1908
R1920 = R402H16: tolerance: 64.33R05.6DL; signal model: Graser_R1920
R1921 = R402H16: tolerance: 64.33R05.6DL; signal model: Graser_R1921
R2048 R2049 R6507 = R402H16: tolerance: 63.51334.1DL
R2101 = R402H16: tolerance: 64.15005.6DL
R2421 R2423 = R402H16: tolerance: 63.33134.1DL
R2424 R4006 R6504 = R402H16: tolerance: 64.20025.6DL
R2437 = R402H16: tolerance: 63.43034.1DL
R2442 R2608 = R402H16: tolerance: 64.27025.6DL
R2443 = R402H16: tolerance: 64.37425.6DL
R2457 = R402H16: tolerance: 64.11535.6DL
R2503 = R402H16: tolerance: 64.15R05.6DL; signal model: Graser_R2503
R2506 = R402H16: tolerance: 64.33R05.6DL; signal model: Graser_R2506
R2507 = R402H16: tolerance: 64.33R05.6DL; signal model: Graser_R2507
R2508 = R402H16: tolerance: 64.33R05.6DL; signal model: Graser_R2508
R2509 = R402H16: tolerance: 64.33R05.6DL; signal model: Graser_R2509
R2603 R2604 = R402H16: tolerance: 64.75015.6DL
R2610 = NTC-603H38: tolerance: 69.60035.041
R2730 = 0R0402-PAD-1: tolerance: ZZ.00PAD.M11; signal model: Graser_R2730
R2741 R7402 R7408-R7410 = R402H16: tolerance: 64.20035.6DL
R2745 R4304 R5751 R5755 = R402H16: tolerance: 63.22234.1DL
R2748 R2750 R5515 R6113 R6502 R9126 R9127 R9143 R9211 = R603H22: tolerance: 63.00000.00L
R4045 = R1206H26: tolerance: 63.R0037.L0L
R4302 R7206 = R402H16: tolerance: 64.15025.6DL
R4305 R4306 R6117 = R402H16: tolerance: 63.33034.1DL
R4307 = R603H22: tolerance: 63.24434.15L
R4315 = R402H16: tolerance: 64.18725.6DL
R4327 R5506 R5543-R5545 = R402H14: tolerance: 63.10134.1DL
R4376 = R402H16: tolerance: 64.47035.6DL
R5541 = R402H16: tolerance: 64.31625.6DL
R5734 = R402H16: tolerance: 64.43015.6DL
R5748 = R402H16: tolerance: 64.15015.6DL
R5749 = R402H15: tolerance: 63.R0034.L0L
R5750 = R402H16: tolerance: 63.10534.L1L
R5762 R5763 = R402H16: tolerance: 64.68R05.6DL
R5765 = R402H16: tolerance: 64.5R105.6DL; signal model: Graser_R5765
R5766 = R402H16: tolerance: 64.5R105.6DL; signal model: Graser_R5766
R5767 = R402H16: tolerance: 64.5R105.6DL; signal model: Graser_R5767
R5768 = R402H16: tolerance: 64.5R105.6DL; signal model: Graser_R5768
R5769 = R402H16: tolerance: 64.5R105.6DL; signal model: Graser_R5769
R5770 = R402H16: tolerance: 64.5R105.6DL; signal model: Graser_R5770
R5771 = R402H16: tolerance: 63.3R034.1DL; signal model: Graser_R5771
R5772 = R402H16: tolerance: 63.3R034.1DL; signal model: Graser_R5772
R5773 = R402H16: tolerance: 64.51015.6DL
R6104 = 0R0402-PAD-1: tolerance: ZZ.00PAD.M11; signal model: Graser_R6104
R6105 = 0R0402-PAD-1: tolerance: ZZ.00PAD.M11; signal model: Graser_R6105
R6119 R6120 = R402H16: tolerance: 64.71525.6DL
R6402 = R402H16: tolerance: 64.68005.6DL
R6503 = R603H22: tolerance: 63.10133.15L
R7119 R7120 R7122 R7123 = R402H16: tolerance: 64.22035.L1L
R7223 = R402H16: tolerance: 64.43025.6DL
R7225 R7226 R7228 R7230 = R402H16: tolerance: 63.33234.1DL
R7243 R7247 = R402H15: tolerance: 63.10334.L0L
R7330 R7331 = R402H16: tolerance: 64.20045.6DL
R7404 R7407 R7411 R7422 = R402H16: tolerance: 64.10045.6DL
R9130 = R402H16: tolerance: 63.R0034.1DL; signal model: Graser_R9130
R9132 = R402H16: tolerance: 63.33034.1DL; signal model: Graser_R9132
R9133 = R402H16: tolerance: 63.33034.1DL; signal model: Graser_R9133
R9138 = R402H16: tolerance: 63.33034.1DL; signal model: Graser_R9138
R9209 = 0R0402-PAD-1: tolerance: ZZ.00PAD.M11; signal model: Graser_R9209
R9210 = 0R0402-PAD-1: tolerance: ZZ.00PAD.M11; signal model: Graser_R9210
R9804 = R402H16: tolerance: 64.47015.6DL
RAM1-RAM8 = BGA96D0914H48-COLAY-4: tolerance: ZZ.00PAD.0Q2
RN401 RN403 RN1811 RN2413 RN2602 RN2703 RN2901 RN6503 RN7206 = ARES2H16: tolerance: 66.22236.04L
RN1202-RN1207 RN1302-RN1307 = ARES8-CN24-UH20: tolerance: 66.36036.08L
RN1601 RN1813 RN2403 RN2404 = ARES8-CN24-MUH20: tolerance: 66.10336.08L
RN1703 RN1704 RN6501 RN7202 = SMD-ARES4H16: tolerance: 66.10336.L0L
RN1801 = SMD-ARES4H20: tolerance: 66.20336.04L
RN1806 = ARES8-CN24-MUH20: tolerance: 66.15035.A8L; signal model: Graser_RN1806
RN1807 = ARES8-CN24-UH20: tolerance: 66.22236.A8L
RN2007 RN2008 RN2702 = SMD-ARES4H18: tolerance: 66.10236.04L
RN2402 = SMD-ARES4H18: tolerance: 66.47236.04L
RN2405 RN2409-RN2412 RN5502 RN7207 = ARES8-CN24H20: tolerance: 66.10436.A8L
RN4302 = SMD-ARES4H18: tolerance: 66.10136.04L
RN5503 RN5504 RN6502 = SMD-ARES4H18: tolerance: 66.33036.04L
RTC1 = 3703K-Q02N-11L-U: tolerance: 20.F1841.002
SPK1 = 50224-0060N-W01: tolerance: 20.F1639.006
SPR1 SPR2 = SPR6035H166: tolerance: 34.49U24.001
SSD1 SSD2 = NFSM0-S6701-TP20: tolerance: 062.10003.00A1
TCBD1 = 51530-02001-W01-U: tolerance: 20.K0637.020
TP302-TP317 TP402 TP618-TP621 TP1201-TP1204 TP1301-TP1304 TP1603 TP1705-TP1714 TP1804 TP1806-TP1808 TP1903 TP2201 TP2202 TP2402 TP4601 TP7202-TP7205 TP8304 TP9101-TP9104 = TPAD14-OP: tolerance: ZZ.PAD14.001
TP4401 = TPAD28: tolerance: ZZ.PAD28.XXX
TPAD1 = 196574-08021-3: tolerance: 020.K0255.0008
U2401 = TQFP128-2H48: tolerance: 071.01416.000G
U2502 U5501 = SOT-23-5H56: tolerance: 074.06288.007B
U2601 = MSOP8-1H44: tolerance: 74.07718.0B9
U2701 = QFN48J6-G465H40: tolerance: 071.03254.M001
U4001 = SON14J3020-G2610H34: tolerance: 074.22976.0091
U4002 U4003 U4006 = DFN8F3-G2517H32: tolerance: 074.05027.0093
U4008 U6402 = SC70-5H44: tolerance: 73.01G08.L04
U4302 = SOT-23-5H52: tolerance: 074.01004.00BF
U5503 = SOT-23-5H58: tolerance: 074.05324.003F
U5701 = BGA64D7H51: tolerance: 071.17564.0C0U
U5702 = SOIC8H69: tolerance: 72.25200.001
U5703 = SC70-5H44: tolerance: 073.7SZ08.000G
U7101 = QFN40J4060-G2848H32: tolerance: 071.00546.M001
U7201 = BGA96G60-1H40: tolerance: 071.17030.000U
U7202 = SOIC8H69: tolerance: 072.25Q80.0C01
U7419 = CSP15G154256H24: tolerance: 074.20509.007Z
U9102 = QFN32G5-G3D6H32: tolerance: 071.00750.0003
USB1 = SKT-USB30-118098-4: tolerance: 062.10009.M028
WLAN1 = 40-42258-06741RHF-U1: tolerance: 062.10003.0401
X1801 = OSC-3225-4P-3H36: tolerance: 082.30006.0531
X1802 X2401 = SMD49-12H34: tolerance: 082.30003.0301
X5701 = SMD-OSC38H32: tolerance: 082.30008.0421

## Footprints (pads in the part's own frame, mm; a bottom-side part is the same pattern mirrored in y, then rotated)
0R0402-PAD
  custom 0.127x0.127 smd: 1(0,0.432) 2(0,-0.432)
0R0402-PAD-1
  custom 0.127x0.127 smd: 1(0,0.432) 2(0,-0.432)
0R0603-PAD-1-U
  custom 0.254x0.254 smd: 1(0,0.66) 2(0,-0.66)
0R0805-PAD
  rect 1.549x1.346 smd: 1(0,0.838) 2(0,-0.838)
0R0805-PAD-1-U
  rect 1.549x1.333 smd: 1(0,0.838) 2(0,-0.838)
40-42258-06741RHF-U1
  round 0.254 hole 1.168 unplated: (-10,0)
  round 0.254 hole 1.651 unplated: (10,0)
  rect 0.305x1.549 smd: 1(-9.25,5.275) 2(-9,-2.275) 3(-8.75,5.275) 4(-8.5,-2.275) 5(-8.25,5.275) 6(-8,-2.275) 7(-7.75,5.275) 8(-7.5,-2.275) 9(-7.25,5.275) 10(-7,-2.275) 11(-6.75,5.275) 12(-6.5,-2.275) 13(-6.25,5.275) 14(-6,-2.275) 15(-5.75,5.275) 16(-5.5,-2.275) 17(-5.25,5.275) 18(-5,-2.275) 19(-4.75,5.275) 20(-4.5,-2.275) 21(-4.25,5.275) 22(-4,-2.275) 23(-3.75,5.275) 32(-1.5,-2.275) 33(-1.25,5.275) 34(-1,-2.275) 35(-0.75,5.275) 36(-0.5,-2.275) 37(-0.25,5.275) 38(0,-2.275) 39(0.25,5.275) 40(0.5,-2.275) 41(0.75,5.275) 42(1,-2.275) 43(1.25,5.275) 44(1.5,-2.275) 45(1.75,5.275) 46(2,-2.275) 47(2.25,5.275) 48(2.5,-2.275) 49(2.75,5.275) 50(3,-2.275) 51(3.25,5.275) 52(3.5,-2.275) 53(3.75,5.275) 54(4,-2.275) 55(4.25,5.275) 56(4.5,-2.275) 57(4.75,5.275) 58(5,-2.275) 59(5.25,5.275) 60(5.5,-2.275) 61(5.75,5.275) 62(6,-2.275) 63(6.25,5.275) 64(6.5,-2.275) 65(6.75,5.275) 66(7,-2.275) 67(7.25,5.275) 68(7.5,-2.275) 69(7.75,5.275) 70(8,-2.275) 71(8.25,5.275) 72(8.5,-2.275) 73(8.75,5.275) 74(9,-2.275) 75(9.25,5.275)
  rect 1.194x2.743 smd: 76(-10.35,4.5) 77(10.35,4.5)
300E40-1010RA-G3
  rect 0.305x0.889 smd: 1(-9.75,2.82) 2(-9.25,2.82) 3(-8.75,2.82) 4(-8.25,2.82) 5(-7.75,2.82) 6(-7.25,2.82) 7(-6.75,2.82) 8(-6.25,2.82) 9(-5.75,2.82) 10(-5.25,2.82) 11(-4.75,2.82) 12(-4.25,2.82) 13(-3.75,2.82) 14(-3.25,2.82) 15(-2.75,2.82) 16(-2.25,2.82) 17(-1.75,2.82) 18(-1.25,2.82) 19(-0.75,2.82) 20(-0.25,2.82) 21(0.25,2.82) 22(0.75,2.82) 23(1.25,2.82) 24(1.75,2.82) 25(2.25,2.82) 26(2.75,2.82) 27(3.25,2.82) 28(3.75,2.82) 29(4.25,2.82) 30(4.75,2.82) 31(5.25,2.82) 32(5.75,2.82) 33(6.25,2.82) 34(6.75,2.82) 35(7.25,2.82) 36(7.75,2.82) 37(8.25,2.82) 38(8.75,2.82) 39(9.25,2.82) 40(9.75,2.82)
  rect 0.559x0.889 smd: 41(-10.65,2.82) 42(10.65,2.82)
  rect 1.397x1.905 smd: 43(-12.849,0) 44(12.849,0)
300E50-1030RA-G4
  rect 0.305x0.889 smd: 1(-12.25,2.82) 2(-11.75,2.82) 3(-11.25,2.82) 4(-10.75,2.82) 5(-10.25,2.82) 6(-9.75,2.82) 7(-9.25,2.82) 8(-8.75,2.82) 9(-8.25,2.82) 10(-7.75,2.82) 11(-7.25,2.82) 12(-6.75,2.82) 13(-6.25,2.82) 14(-5.75,2.82) 15(-5.25,2.82) 16(-4.75,2.82) 17(-4.25,2.82) 18(-3.75,2.82) 19(-3.25,2.82) 20(-2.75,2.82) 21(-2.25,2.82) 22(-1.75,2.82) 23(-1.25,2.82) 24(-0.75,2.82) 25(-0.25,2.82) 26(0.25,2.82) 27(0.75,2.82) 28(1.25,2.82) 29(1.75,2.82) 30(2.25,2.82) 31(2.75,2.82) 32(3.25,2.82) 33(3.75,2.82) 34(4.25,2.82) 35(4.75,2.82) 36(5.25,2.82) 37(5.75,2.82) 38(6.25,2.82) 39(6.75,2.82) 40(7.25,2.82) 41(7.75,2.82) 42(8.25,2.82) 43(8.75,2.82) 44(9.25,2.82) 45(9.75,2.82) 46(10.25,2.82) 47(10.75,2.82) 48(11.25,2.82) 49(11.75,2.82) 50(12.25,2.82)
  rect 1.397x1.905 smd: 51(-15.35,0) 52(15.35,0)
  rect 0.559x0.889 smd: 53(-13.15,2.82) 54(13.15,2.82)
3703K-Q02N-11L-U
  rect 0.61x1.549 smd: 1(-0.5,3.775) 2(0.5,3.775)
  rect 1.194x2.007 smd: 3(-1.8,0) 4(1.8,0)
3703K-Q08N-03R-U
  rect 0.61x1.549 smd: 1(-3.5,3.775) 2(-2.5,3.775) 3(-1.5,3.775) 4(-0.5,3.775) 5(0.5,3.775) 6(1.5,3.775) 7(2.5,3.775) 8(3.5,3.775)
  rect 1.194x2.007 smd: 9(-4.8,0) 10(4.8,0)
50224-0040N-001
  rect 0.61x1.549 smd: 1(-1.5,3.875) 2(-0.5,3.875) 3(0.5,3.875) 4(1.5,3.875)
  rect 1.194x1.803 smd: 5(-2.797,0) 6(2.797,0)
50224-0060N-W01
  rect 0.406x1.549 smd: 1(-2.5,3.875) 2(-1.5,3.875) 3(-0.5,3.875) 4(0.5,3.875) 5(1.5,3.875) 6(2.5,3.875)
  rect 1.194x1.803 smd: 7(-3.8,0) 8(3.8,0)
50299-01001-002-U
  round 0.254 hole 1.803 unplated: (-9.2,0) (9.2,0)
  rect 0.889x1.905 smd: 1(9,4.95) 2(7,4.95) 3(5,4.95) 4(3,4.95) 5(1,4.95) 6(-1,4.95) 7(-3,4.95) 8(-5,4.95) 9(-7,4.95) 10(-9,4.95)
50696-00601-001
  rect 0.305x0.813 smd: 1(1.25,2.5) 2(0.75,2.5) 3(0.25,2.5) 4(-0.25,2.5) 5(-0.75,2.5) 6(-1.25,2.5)
  rect 0.406x0.813 smd: 7(2.25,0) 8(-2.25,0)
50698-00401-W01-U
  rect 0.305x1.6 smd: 1(1.5,5.2) 2(0.5,5.2) 3(-0.5,5.2) 4(-1.5,5.2)
  rect 1.803x2.007 smd: 5(4.21,0) 6(-4.21,0)
51530-02001-W01-U
  rect 0.305x0.838 smd: 1(-4.75,3.175) 2(-4.25,3.175) 3(-3.75,3.175) 4(-3.25,3.175) 5(-2.75,3.175) 6(-2.25,3.175) 7(-1.75,3.175) 8(-1.25,3.175) 9(-0.75,3.175) 10(-0.25,3.175) 11(0.25,3.175) 12(0.75,3.175) 13(1.25,3.175) 14(1.75,3.175) 15(2.25,3.175) 16(2.75,3.175) 17(3.25,3.175) 18(3.75,3.175) 19(4.25,3.175) 20(4.75,3.175)
  rect 0.813x2.007 smd: 21(-6.45,0) 22(6.45,0)
196528-30041-3
  rect 0.508x1.092 smd: 1(-11.6,1.75) 2(-10.8,1.75) 3(-10,1.75) 4(-9.2,1.75) 5(-8.4,1.75) 6(-7.6,1.75) 7(-6.8,1.75) 8(-6,1.75) 9(-5.2,1.75) 10(-4.4,1.75) 11(-3.6,1.75) 12(-2.8,1.75) 13(-2,1.75) 14(-1.2,1.75) 15(-0.4,1.75) 16(0.4,1.75) 17(1.2,1.75) 18(2,1.75) 19(2.8,1.75) 20(3.6,1.75) 21(4.4,1.75) 22(5.2,1.75) 23(6,1.75) 24(6.8,1.75) 25(7.6,1.75) 26(8.4,1.75) 27(9.2,1.75) 28(10,1.75) 29(10.8,1.75) 30(11.6,1.75)
  rect 1.651x1.295 smd: 31(-13.625,0) 32(13.625,0)
196574-08021-3
  rect 0.305x0.991 smd: 1(-3.5,3.2) 2(-2.5,3.2) 3(-1.5,3.2) 4(-0.5,3.2) 5(0.5,3.2) 6(1.5,3.2) 7(2.5,3.2) 8(3.5,3.2)
  rect 0.406x0.991 smd: 9(-5.185,0) 10(5.185,0)
AFTE14P-75
  round 0.356 smd: 1(0,0)
ARES2H16
  rect 0.457x0.635 smd: 1(-0.335,-0.44) 2(0.335,-0.44) 3(0.335,0.44) 4(-0.335,0.44)
ARES8-CN24-MUH20
  rect 0.457x0.61 smd: 1(-0.838,-0.445) 4(0.838,-0.445) 5(0.838,0.445) 8(-0.838,0.445)
  rect 0.305x0.61 smd: 2(-0.25,-0.445) 3(0.25,-0.445) 6(0.25,0.445) 7(-0.25,0.445)
ARES8-CN24-UH20
  rect 0.457x0.61 smd: 1(-0.838,-0.445) 4(0.838,-0.445) 5(0.838,0.445) 8(-0.838,0.445)
  rect 0.305x0.61 smd: 2(-0.25,-0.445) 3(0.25,-0.445) 6(0.25,0.445) 7(-0.25,0.445)
ARES8-CN24H20
  rect 0.457x0.559 smd: 1(-0.838,-0.483) 4(0.838,-0.483) 5(0.838,0.483) 8(-0.838,0.483)
  rect 0.305x0.559 smd: 2(-0.25,-0.483) 3(0.25,-0.483) 6(0.25,0.483) 7(-0.25,0.483)
BGA64D7H51
  round 0.406 smd: A1(-2.8,2.8) A2(-2,2.8) A3(-1.2,2.8) A6(1.2,2.8) A7(2,2.8) A8(2.8,2.8) B1(-2.8,2) B2(-2,2) B3(-1.2,2) B6(1.2,2) B7(2,2) B8(2.8,2) C1(-2.8,1.2) C2(-2,1.2) C3(-1.2,1.2) C6(1.2,1.2) C7(2,1.2) C8(2.8,1.2) F1(-2.8,-1.2) F2(-2,-1.2) F3(-1.2,-1.2) F6(1.2,-1.2) F7(2,-1.2) F8(2.8,-1.2) G1(-2.8,-2) G2(-2,-2) G3(-1.2,-2) G6(1.2,-2) G7(2,-2) G8(2.8,-2) H1(-2.8,-2.8) H2(-2,-2.8) H3(-1.2,-2.8) H6(1.2,-2.8) H7(2,-2.8) H8(2.8,-2.8)
  round 0.356 smd: A4(-0.4,2.8) A5(0.4,2.8) B4(-0.4,2) B5(0.4,2) C4(-0.4,1.2) C5(0.4,1.2) D1(-2.8,0.4) D2(-2,0.4) D3(-1.2,0.4) D4(-0.4,0.4) D5(0.4,0.4) D6(1.2,0.4) D7(2,0.4) D8(2.8,0.4) E1(-2.8,-0.4) E2(-2,-0.4) E3(-1.2,-0.4) E4(-0.4,-0.4) E5(0.4,-0.4) E6(1.2,-0.4) E7(2,-0.4) E8(2.8,-0.4) F4(-0.4,-1.2) F5(0.4,-1.2) G4(-0.4,-2) G5(0.4,-2) H4(-0.4,-2.8) H5(0.4,-2.8)
BGA96D0914H48-COLAY-4
  round 0.356 smd: A1(-3.2,6) A2(-2.4,6) A3(-1.6,6) A7(1.6,6) A8(2.4,6) A9(3.2,6) B1(-3.2,5.2) B2(-2.4,5.2) B3(-1.6,5.2) B7(1.6,5.2) B8(2.4,5.2) B9(3.2,5.2) C1(-3.2,4.4) C2(-2.4,4.4) C3(-1.6,4.4) C7(1.6,4.4) C8(2.4,4.4) C9(3.2,4.4) D1(-3.2,3.6) D2(-2.4,3.6) D3(-1.6,3.6) D7(1.6,3.6) D8(2.4,3.6) D9(3.2,3.6) E1(-3.2,2.8) E2(-2.4,2.8) E3(-1.6,2.8) E7(1.6,2.8) E8(2.4,2.8) E9(3.2,2.8) F1(-3.2,2) F2(-2.4,2) F3(-1.6,2) F7(1.6,2) F8(2.4,2) F9(3.2,2) G1(-3.2,1.2) G2(-2.4,1.2) G3(-1.6,1.2) G7(1.6,1.2) G8(2.4,1.2) G9(3.2,1.2) H1(-3.2,0.4) H2(-2.4,0.4) H3(-1.6,0.4) H7(1.6,0.4) H8(2.4,0.4) H9(3.2,0.4) J1(-3.2,-0.4) J2(-2.4,-0.4) J3(-1.6,-0.4) J7(1.6,-0.4) J8(2.4,-0.4) J9(3.2,-0.4) K1(-3.2,-1.2) K2(-2.4,-1.2) K3(-1.6,-1.2) K7(1.6,-1.2) K8(2.4,-1.2) K9(3.2,-1.2) L1(-3.2,-2) L2(-2.4,-2) L3(-1.6,-2) L7(1.6,-2) L8(2.4,-2) L9(3.2,-2) M1(-3.2,-2.8) M2(-2.4,-2.8) M3(-1.6,-2.8) M7(1.6,-2.8) M8(2.4,-2.8) M9(3.2,-2.8) N1(-3.2,-3.6) N2(-2.4,-3.6) N3(-1.6,-3.6) N7(1.6,-3.6) N8(2.4,-3.6) N9(3.2,-3.6) P1(-3.2,-4.4) P2(-2.4,-4.4) P3(-1.6,-4.4) P7(1.6,-4.4) P8(2.4,-4.4) P9(3.2,-4.4) R1(-3.2,-5.2) R2(-2.4,-5.2) R3(-1.6,-5.2) R7(1.6,-5.2) R8(2.4,-5.2) R9(3.2,-5.2) T1(-3.2,-6) T2(-2.4,-6) T3(-1.6,-6) T7(1.6,-6) T8(2.4,-6) T9(3.2,-6)
BGA96G60-1H40
  oval 0.178x0.33 smd rot 45: A1(-2.5,2.5) L11(2.5,-2.5)
  oval 0.178x0.33 smd: A2(-2,2.5) A3(-1.5,2.5) A4(-1,2.5) A5(-0.5,2.5) A6(0,2.5) A7(0.5,2.5) A8(1,2.5) A9(1.5,2.5) A10(2,2.5) L2(-2,-2.5) L3(-1.5,-2.5) L4(-1,-2.5) L5(-0.5,-2.5) L6(0,-2.5) L7(0.5,-2.5) L8(1,-2.5) L9(1.5,-2.5) L10(2,-2.5)
  oval 0.33x0.178 smd rot 45: A11(2.5,2.5) L1(-2.5,-2.5)
  oval 0.33x0.178 smd: B1(-2.5,2) B11(2.5,2) C1(-2.5,1.5) C11(2.5,1.5) D1(-2.5,1) D11(2.5,1) E1(-2.5,0.5) E11(2.5,0.5) F1(-2.5,0) F11(2.5,0) G1(-2.5,-0.5) G11(2.5,-0.5) H1(-2.5,-1) H11(2.5,-1) J1(-2.5,-1.5) J11(2.5,-1.5) K1(-2.5,-2) K11(2.5,-2)
  round 0.356 smd: B2(-2,2) B3(-1.5,2) B4(-1,2) B5(-0.5,2) B6(0,2) B7(0.5,2) B8(1,2) B9(1.5,2) B10(2,2) C2(-2,1.5) C10(2,1.5) D2(-2,1) D5(-0.5,1) D6(0,1) D7(0.5,1) D8(1,1) D10(2,1) E2(-2,0.5) E4(-1,0.5) E5(-0.5,0.5) E6(0,0.5) E7(0.5,0.5) E8(1,0.5) E10(2,0.5) F2(-2,0) F4(-1,0) F5(-0.5,0) F6(0,0) F7(0.5,0) F8(1,0) F10(2,0) G2(-2,-0.5) G4(-1,-0.5) G5(-0.5,-0.5) G6(0,-0.5) G7(0.5,-0.5) G8(1,-0.5) G10(2,-0.5) H2(-2,-1) H4(-1,-1) H5(-0.5,-1) H6(0,-1) H7(0.5,-1) H8(1,-1) H10(2,-1) J2(-2,-1.5) J10(2,-1.5) K2(-2,-2) K3(-1.5,-2) K4(-1,-2) K5(-0.5,-2) K6(0,-2) K7(0.5,-2) K8(1,-2) K9(1.5,-2) K10(2,-2)
BGA1528M2446-1H52
  round 0.356 smd: A3(-10.396,22.315) A36(10.855,22.315) B2(-10.855,21.855) B37(11.315,21.855) C1(-11.315,21.396) CP1(-11.315,-21.855) CP37(11.315,-21.855) CR2(-10.855,-22.315) CR36(10.855,-22.315)
  round 0.33 smd: A4(-9.746,22.315) A35(10.205,22.315) B3(-10.227,21.687) B36(10.687,21.687) C2(-10.687,21.227) C37(11.315,21.205) CN1(-11.315,-21.205) CN37(11.315,-21.205) CP2(-10.687,-21.687) CP36(10.687,-21.687) CR3(-10.205,-22.315) CR35(10.205,-22.315) D1(-11.315,20.746)
  round 0.305 smd: A5(-9.096,22.292) A6(-8.232,22.315) A32(8.228,22.315) A34(9.555,22.315) AA4(-9.365,10.421) AA9(-6.21,10.624) AA24(3.679,10.481) AA26(4.606,10.481) AA34(9.365,10.719) AB3(-10.334,9.763) AB4(-9.325,9.763) AB5(-8.617,10.162) AB6(-7.967,10.162) AB7(-7.317,10.162) AB8(-6.668,10.162) AB9(-6.21,9.7) AB10(-5.753,10.162) AB25(4.142,10.025) AB27(5.069,10.025) AB28(5.719,10.025) AB29(6.369,10.025) AB30(7.019,10.025) AB31(7.669,10.025) AB32(8.32,10.025) AB33(9.04,10.068) AB34(9.69,10.068) AC4(-9.365,9.106) AC5(-8.617,9.238) AC6(-7.967,9.238) AC7(-7.317,9.238) AC8(-6.668,9.238) AC10(-5.753,9.238) AC24(3.679,9.57) AC25(4.142,9.114) AC26(4.606,9.57) AC27(5.069,9.114) AC28(5.719,9.114) AC29(6.369,9.114) AC30(7.019,9.114) AC31(7.669,9.114) AC32(8.32,9.114) AC34(9.365,9.417) AD4(-9.69,8.543) AD9(-6.21,8.776) AD24(3.679,8.658) AD26(4.606,8.658) AD33(9.04,8.809) AD35(10.245,8.809) AE4(-9.365,7.98) AE5(-8.617,8.314) AE6(-7.967,8.314) AE7(-7.317,8.314) AE8(-6.668,8.314) AE9(-6.21,7.852) AE10(-5.753,8.314) AE24(3.679,7.747) AE25(4.142,8.203) AE26(4.606,7.747) AE27(5.069,8.203) AE28(5.719,8.203) AE29(6.369,8.203) AE30(7.019,8.203) AE31(7.669,8.203) AE32(8.32,8.203) AE34(9.365,8.202) AF3(-10.334,7.322) AF4(-9.325,7.322) AF5(-8.617,7.39) AF6(-7.967,7.39) AF7(-7.317,7.39) AF8(-6.668,7.39) AF10(-5.753,7.39) AF25(4.142,7.291) AF27(5.069,7.291) AF28(5.719,7.291) AF29(6.369,7.291) AF30(7.019,7.291) AF31(7.669,7.291) AF32(8.32,7.291) AF33(9.04,7.551) AF34(9.69,7.551) AG4(-9.365,6.665) AG5(-8.617,6.467) AG6(-7.967,6.467) AG7(-7.317,6.467) AG8(-6.668,6.467) AG9(-6.21,6.929) AG10(-5.753,6.467) AG24(3.679,6.835) AG26(4.606,6.835) AG34(9.365,6.9) AH4(-9.69,6.102) AH9(-6.21,6.005) AH24(3.679,5.924) AH25(4.142,6.38) AH26(4.606,5.924) AH27(5.069,6.38) AH28(5.719,6.38) AH29(6.369,6.38) AH30(7.019,6.38) AH31(7.669,6.38) AH32(8.32,6.38) AH33(9.04,6.293) AH35(10.245,6.293) AJ4(-9.365,5.539) AJ5(-8.617,5.543) AJ6(-7.967,5.543) AJ7(-7.317,5.543) AJ8(-6.668,5.543) AJ10(-5.753,5.543) AJ25(4.142,5.468) AJ27(5.069,5.468) AJ28(5.719,5.468) AJ29(6.369,5.468) AJ30(7.019,5.468) AJ31(7.669,5.468) AJ32(8.32,5.468) AJ34(9.365,5.685) AK3(-10.334,4.882) AK4(-9.325,4.882) AK9(-6.21,5.081) AK24(3.679,5.013) AK26(4.606,5.013) AK33(9.04,5.034) AK34(9.69,5.034) AL4(-9.365,4.224) AL5(-8.617,4.619) AL6(-7.967,4.619) AL7(-7.317,4.619) AL8(-6.668,4.619) AL9(-6.21,4.157) AL10(-5.753,4.619) AL24(3.679,4.101) AL25(4.142,4.557) AL26(4.606,4.101) AL27(5.069,4.557) AL28(5.719,4.557) AL29(6.369,4.557) AL30(7.019,4.557) AL31(7.669,4.557) AL32(8.32,4.557) AL34(9.365,4.383) AM4(-9.69,3.661) AM5(-8.617,3.695) AM6(-7.967,3.695) AM7(-7.317,3.695) AM8(-6.668,3.695) AM10(-5.753,3.695) AM25(4.142,3.646) AM27(5.069,3.646) AM28(5.719,3.646) AM29(6.369,3.646) AM30(7.019,3.646) AM31(7.669,3.646) AM32(8.32,3.646) AM33(9.04,3.775) AM35(10.245,3.775) AN4(-9.365,3.098) AN5(-8.617,2.771) AN6(-7.967,2.771) AN7(-7.317,2.771) AN8(-6.668,2.771) AN9(-6.21,3.233) AN10(-5.753,2.771) AN24(3.679,3.19) AN25(4.142,2.734) AN26(4.606,3.19) AN27(5.069,2.734) AN28(5.719,2.734) AN29(6.369,2.734) AN30(7.019,2.734) AN31(7.669,2.734) AN32(8.32,2.734) AN34(9.365,3.168) AP3(-10.334,2.441) AP4(-9.325,2.441) AP9(-6.21,2.31) AP24(3.679,2.278) AP26(4.606,2.278) AP33(9.04,2.517) AP34(9.69,2.517) AR4(-9.365,1.783) AR5(-8.617,1.848) AR6(-7.967,1.848) AR7(-7.317,1.848) AR8(-6.668,1.848) AR10(-5.753,1.848) AR25(4.142,1.823) AR27(5.069,1.823) AR28(5.719,1.823) AR29(6.369,1.823) AR30(7.019,1.823) AR31(7.669,1.823) AR32(8.32,1.823) AR34(9.365,1.866) AT4(-9.69,1.22) AT9(-6.21,1.386) AT24(3.679,1.367) AT26(4.606,1.367) AT33(9.04,1.259) AT35(10.245,1.259) AU4(-9.365,0.657) AU5(-8.617,0.924) AU6(-7.967,0.924) AU7(-7.317,0.924) AU8(-6.668,0.924) AU9(-6.21,0.462) AU10(-5.753,0.924) AU24(3.679,0.456) AU25(4.142,0.911) AU26(4.606,0.456) AU27(5.069,0.911) AU28(5.719,0.911) AU29(6.369,0.911) AU30(7.019,0.911) AU31(7.669,0.911) AU32(8.32,0.911) AU34(9.365,0.65) AV3(-10.334,0) AV4(-9.325,0) AV5(-8.617,0) AV6(-7.967,0) AV7(-7.317,0) AV8(-6.668,0) AV10(-5.753,0) AV25(4.142,0) AV27(5.069,0) AV28(5.719,0) AV29(6.369,0) AV30(7.019,0) AV31(7.669,0) AV32(8.32,0) AV33(9.04,0) AV34(9.69,0) AW4(-9.365,-0.657) AW5(-8.617,-0.924) AW6(-7.967,-0.924) AW7(-7.317,-0.924) AW8(-6.668,-0.924) AW9(-6.21,-0.462) AW10(-5.753,-0.924) AW24(3.679,-0.456) AW25(4.142,-0.911) AW26(4.606,-0.456) AW27(5.069,-0.911) AW28(5.719,-0.911) AW29(6.369,-0.911) AW30(7.019,-0.911) AW31(7.669,-0.911) AW32(8.32,-0.911) AW34(9.365,-0.65) AY4(-9.69,-1.22) AY9(-6.21,-1.386) AY24(3.679,-1.367) AY26(4.606,-1.367) AY33(9.04,-1.259) AY35(10.245,-1.259) B4(-9.515,21.707) B5(-8.866,21.684) B33(8.901,22.004) B34(9.396,21.582) B35(10.037,21.687) BA4(-9.365,-1.783) BA5(-8.617,-1.848) BA6(-7.967,-1.848) BA7(-7.317,-1.848) BA8(-6.668,-1.848) BA10(-5.753,-1.848) BA25(4.142,-1.823) BA27(5.069,-1.823) BA28(5.719,-1.823) BA29(6.369,-1.823) BA30(7.019,-1.823) BA31(7.669,-1.823) BA32(8.32,-1.823) BA34(9.365,-1.866) BB3(-10.334,-2.441) BB4(-9.325,-2.441) BB9(-6.21,-2.31) BB24(3.679,-2.278) BB26(4.606,-2.278) BB33(9.04,-2.517) BB34(9.69,-2.517) BC4(-9.365,-3.098) BC5(-8.617,-2.771) BC6(-7.967,-2.771) BC7(-7.317,-2.771) BC8(-6.668,-2.771) BC9(-6.21,-3.233) BC10(-5.753,-2.771) BC24(3.679,-3.19) BC25(4.142,-2.734) BC26(4.606,-3.19) BC27(5.069,-2.734) BC28(5.719,-2.734) BC29(6.369,-2.734) BC30(7.019,-2.734) BC31(7.669,-2.734) BC32(8.32,-2.734) BC34(9.365,-3.168) BD4(-9.69,-3.661) BD5(-8.617,-3.695) BD6(-7.967,-3.695) BD7(-7.317,-3.695) BD8(-6.668,-3.695) BD10(-5.753,-3.695) BD25(4.142,-3.646) BD27(5.069,-3.646) BD28(5.719,-3.646) BD29(6.369,-3.646) BD30(7.019,-3.646) BD31(7.669,-3.646) BD32(8.32,-3.646) BD33(9.04,-3.775) BD35(10.245,-3.775) BE4(-9.365,-4.224) BE5(-8.617,-4.619) BE6(-7.967,-4.619) BE7(-7.317,-4.619) BE8(-6.668,-4.619) BE9(-6.21,-4.157) BE10(-5.753,-4.619) BE24(3.679,-4.101) BE25(4.142,-4.557) BE26(4.606,-4.101) BE27(5.069,-4.557) BE28(5.719,-4.557) BE29(6.369,-4.557) BE30(7.019,-4.557) BE31(7.669,-4.557) BE32(8.32,-4.557) BE34(9.365,-4.383) BF3(-10.334,-4.882) BF4(-9.325,-4.882) BF9(-6.21,-5.081) BF24(3.679,-5.013) BF26(4.606,-5.013) BF33(9.04,-5.034) BF34(9.69,-5.034) BG4(-9.365,-5.539) BG5(-8.617,-5.543) BG6(-7.967,-5.543) BG7(-7.317,-5.543) BG8(-6.668,-5.543) BG10(-5.753,-5.543) BG25(4.142,-5.468) BG27(5.069,-5.468) BG28(5.719,-5.468) BG29(6.369,-5.468) BG30(7.019,-5.468) BG31(7.669,-5.468) BG32(8.32,-5.468) BG34(9.365,-5.685) BH4(-9.69,-6.102) BH9(-6.21,-6.005) BH24(3.679,-5.924) BH25(4.142,-6.38) BH26(4.606,-5.924) BH27(5.069,-6.38) BH28(5.719,-6.38) BH29(6.369,-6.38) BH30(7.019,-6.38) BH31(7.669,-6.38) BH32(8.32,-6.38) BH33(9.04,-6.293) BH35(10.245,-6.293) BJ4(-9.365,-6.665) BJ5(-8.617,-6.467) BJ6(-7.967,-6.467) BJ7(-7.317,-6.467) BJ8(-6.668,-6.467) BJ9(-6.21,-6.929) BJ10(-5.753,-6.467) BJ24(3.679,-6.835) BJ26(4.606,-6.835) BJ34(9.365,-6.9) BK3(-10.334,-7.322) BK4(-9.325,-7.322) BK5(-8.617,-7.39) BK6(-7.967,-7.39) BK7(-7.317,-7.39) BK8(-6.668,-7.39) BK10(-5.753,-7.39) BK25(4.142,-7.291) BK27(5.069,-7.291) BK28(5.719,-7.291) BK29(6.369,-7.291) BK30(7.019,-7.291) BK31(7.669,-7.291) BK32(8.32,-7.291) BK33(9.04,-7.551) BK34(9.69,-7.551) BL4(-9.365,-7.98) BL5(-8.617,-8.314) BL6(-7.967,-8.314) BL7(-7.317,-8.314) BL8(-6.668,-8.314) BL9(-6.21,-7.852) BL10(-5.753,-8.314) BL24(3.679,-7.747) BL25(4.142,-8.203) BL26(4.606,-7.747) BL27(5.069,-8.203) BL28(5.719,-8.203) BL29(6.369,-8.203) BL30(7.019,-8.203) BL31(7.669,-8.203) BL32(8.32,-8.203) BL34(9.365,-8.202) BM4(-9.69,-8.543) BM9(-6.21,-8.776) BM24(3.679,-8.658) BM26(4.606,-8.658) BM33(9.04,-8.809) BM35(10.245,-8.809) BN4(-9.365,-9.106) BN5(-8.617,-9.238) BN6(-7.967,-9.238) BN7(-7.317,-9.238) BN8(-6.668,-9.238) BN10(-5.753,-9.238) BN25(4.142,-9.114) BN27(5.069,-9.114) BN28(5.719,-9.114) BN29(6.369,-9.114) BN30(7.019,-9.114) BN31(7.669,-9.114) BN32(8.32,-9.114) BN34(9.365,-9.417) BP3(-10.334,-9.763) BP4(-9.325,-9.763) BP5(-8.617,-10.162) BP6(-7.967,-10.162) BP7(-7.317,-10.162) BP8(-6.668,-10.162) BP9(-6.018,-10.162) BP11(-5.093,-9.786) BP12(-4.253,-9.786) BP14(-3.413,-9.786) BP15(-2.574,-9.786) BP16(-1.734,-9.786) BP18(-0.894,-9.786) BP19(-0.054,-9.786) BP20(0.786,-9.786) BP22(1.626,-9.786) BP23(2.465,-9.786) BP24(3.305,-9.786) BP25(4.145,-9.786) BP27(5.069,-10.025) BP28(5.719,-10.025) BP29(6.369,-10.025) BP30(7.019,-10.025) BP31(7.669,-10.025) BP32(8.32,-10.025) BP33(9.04,-10.068) BP34(9.69,-10.068) BR4(-9.365,-10.421) BR11(-5.093,-10.436) BR12(-4.253,-10.436) BR14(-3.413,-10.436) BR15(-2.574,-10.436) BR16(-1.734,-10.436) BR18(-0.894,-10.436) BR19(-0.054,-10.436) BR20(0.786,-10.436) BR22(1.626,-10.436) BR23(2.465,-10.436) BR24(3.305,-10.436) BR25(4.145,-10.436) BR34(9.365,-10.719) BT4(-9.69,-10.984) BT5(-8.617,-11.086) BT6(-7.967,-11.086) BT7(-7.317,-11.086) BT8(-6.668,-11.086) BT9(-6.018,-11.086) BT11(-5.093,-11.086) BT12(-4.253,-11.086) BT14(-3.413,-11.086) BT15(-2.574,-11.086) BT16(-1.734,-11.086) BT18(-0.894,-11.086) BT19(-0.054,-11.086) BT20(0.786,-11.086) BT22(1.626,-11.086) BT23(2.465,-11.086) BT24(3.305,-11.086) BT25(4.145,-11.086) BT27(5.069,-10.937) BT28(5.719,-10.937) BT29(6.369,-10.937) BT30(7.019,-10.937) BT31(7.669,-10.937) BT32(8.32,-10.937) BT33(9.04,-11.327) BT35(10.245,-11.327) BU4(-9.365,-11.547) BU5(-8.617,-12.009) BU6(-7.967,-12.009) BU7(-7.317,-12.009) BU8(-6.668,-12.009) BU9(-6.018,-12.009) BU11(-5.093,-11.736) BU12(-4.253,-11.736) BU14(-3.413,-11.736) BU15(-2.574,-11.736) BU16(-1.734,-11.736) BU18(-0.894,-11.736) BU19(-0.054,-11.736) BU20(0.786,-11.736) BU22(1.626,-11.736) BU23(2.465,-11.736) BU24(3.305,-11.736) BU25(4.145,-11.736) BU27(5.069,-11.848) BU28(5.719,-11.848) BU29(6.369,-11.848) BU30(7.019,-11.848) BU31(7.669,-11.848) BU32(8.32,-11.848) BU34(9.365,-11.934) BV3(-10.334,-12.204) BV4(-9.325,-12.204) BV11(-5.093,-12.386) BV12(-4.253,-12.386) BV14(-3.413,-12.386) BV15(-2.574,-12.386) BV16(-1.734,-12.386) BV18(-0.894,-12.386) BV19(-0.054,-12.386) BV20(0.786,-12.386) BV22(1.626,-12.386) BV23(2.465,-12.386) BV24(3.305,-12.386) BV25(4.145,-12.386) BV27(5.069,-12.76) BV28(5.719,-12.76) BV29(6.369,-12.76) BV30(7.019,-12.76) BV31(7.669,-12.76) BV32(8.32,-12.76) BV33(9.04,-12.585) BV34(9.69,-12.585) BW4(-9.365,-12.861) BW5(-8.617,-12.933) BW6(-7.967,-12.933) BW7(-7.317,-12.933) BW8(-6.668,-12.933) BW9(-6.018,-12.933) BW11(-5.093,-13.036) BW12(-4.253,-13.036) BW14(-3.413,-13.036) BW15(-2.574,-13.036) BW16(-1.734,-13.036) BW18(-0.894,-13.036) BW19(-0.054,-13.036) BW20(0.786,-13.036) BW22(1.626,-13.036) BW23(2.465,-13.036) BW24(3.305,-13.036) BW25(4.145,-13.036) BW34(9.365,-13.236) BY4(-9.69,-13.424) BY5(-8.617,-13.857) BY6(-7.967,-13.857) BY7(-7.317,-13.857) BY8(-6.668,-13.857) BY9(-6.018,-13.857) BY11(-5.093,-13.686) BY12(-4.253,-13.686) BY14(-3.413,-13.686) BY15(-2.574,-13.686) BY16(-1.734,-13.686) BY18(-0.894,-13.686) BY19(-0.054,-13.686) BY20(0.786,-13.686) BY22(1.626,-13.686) BY23(2.465,-13.686) BY24(3.305,-13.686) BY25(4.145,-13.686) BY27(5.069,-13.671) BY28(5.719,-13.671) BY29(6.369,-13.671) BY30(7.019,-13.671) BY31(7.669,-13.671) BY32(8.32,-13.671) BY33(9.04,-13.844) BY35(10.245,-13.844) C3(-10.059,21.059) C4(-9.213,21.132) C9(-6.305,21.245) C21(1.275,21.245) C25(3.792,21.245) C29(6.309,21.245) C33(8.826,21.245) C34(9.396,20.932) C35(10.037,21.037) C36(10.687,21.037) CA4(-9.365,-13.988) CA11(-5.093,-14.336) CA12(-4.253,-14.336) CA14(-3.413,-14.336) CA15(-2.574,-14.336) CA16(-1.734,-14.336) CA18(-0.894,-14.336) CA19(-0.054,-14.336) CA20(0.786,-14.336) CA22(1.626,-14.336) CA23(2.465,-14.336) CA24(3.305,-14.336) CA25(4.145,-14.336) CA27(5.069,-14.582) CA28(5.719,-14.582) CA29(6.369,-14.582) CA30(7.019,-14.582) CA31(7.669,-14.582) CA32(8.32,-14.582) CA34(9.365,-14.451) CB3(-10.334,-14.645) CB4(-9.325,-14.645) CB5(-8.617,-14.781) CB6(-7.967,-14.781) CB7(-7.317,-14.781) CB8(-6.668,-14.781) CB9(-6.018,-14.781) CB11(-5.093,-14.985) CB12(-4.253,-14.985) CB14(-3.413,-14.985) CB15(-2.574,-14.985) CB16(-1.734,-14.985) CB18(-0.894,-14.985) CB19(-0.054,-14.985) CB20(0.786,-14.985) CB22(1.626,-14.985) CB23(2.465,-14.985) CB24(3.305,-14.985) CB25(4.145,-14.985) CB33(9.04,-15.102) CB34(9.69,-15.102) CC4(-9.365,-15.302) CC5(-8.617,-15.705) CC6(-7.967,-15.705) CC7(-7.317,-15.705) CC8(-6.668,-15.705) CC9(-6.018,-15.705) CC11(-5.093,-15.635) CC12(-4.253,-15.635) CC14(-3.413,-15.635) CC15(-2.574,-15.635) CC16(-1.734,-15.635) CC18(-0.894,-15.635) CC19(-0.054,-15.635) CC20(0.786,-15.635) CC22(1.626,-15.635) CC23(2.465,-15.635) CC24(3.305,-15.635) CC25(4.145,-15.635) CC27(5.069,-15.494) CC28(5.719,-15.494) CC29(6.369,-15.494) CC30(7.019,-15.494) CC31(7.669,-15.494) CC32(8.32,-15.494) CC34(9.365,-15.753) CD4(-9.69,-15.865) CD11(-5.093,-16.285) CD12(-4.253,-16.285) CD14(-3.413,-16.285) CD15(-2.574,-16.285) CD16(-1.734,-16.285) CD18(-0.894,-16.285) CD19(-0.054,-16.285) CD20(0.786,-16.285) CD22(1.626,-16.285) CD23(2.465,-16.285) CD24(3.305,-16.285) CD25(4.145,-16.285) CE4(-9.365,-16.428) CE5(-8.617,-16.628) CE6(-7.967,-16.628) CE7(-7.317,-16.628) CE8(-6.668,-16.628) CE9(-6.018,-16.628) CE27(5.069,-16.405) CE28(5.719,-16.405) CE29(6.369,-16.405) CE30(7.019,-16.405) CE31(7.669,-16.405) CE32(8.32,-16.405) CE33(9.04,-16.36) CE35(10.245,-16.36) CF3(-10.334,-17.086) CF4(-9.325,-17.086) CF11(-5.37,-17.115) CF12(-4.368,-17.115) CF14(-3.33,-17.115) CF15(-2.292,-17.115) CF17(-1.254,-17.115) CF19(-0.216,-17.115) CF20(0.822,-17.115) CF22(1.86,-17.115) CF23(2.898,-17.115) CF25(3.936,-17.115) CF27(5.069,-17.317) CF28(5.719,-17.317) CF29(6.369,-17.317) CF30(7.019,-17.317) CF31(7.669,-17.317) CF32(8.32,-17.317) CF34(9.365,-16.968) CG4(-9.365,-17.743) CG5(-8.617,-17.552) CG6(-7.967,-17.552) CG7(-7.317,-17.552) CG8(-6.668,-17.552) CG9(-6.018,-17.552) CG11(-5.37,-17.765) CG12(-4.368,-17.765) CG14(-3.33,-17.765) CG15(-2.292,-17.765) CG17(-1.254,-17.765) CG19(-0.216,-17.765) CG20(0.822,-17.765) CG22(1.86,-17.765) CG23(2.898,-17.765) CG25(3.936,-17.765) CG33(9.04,-17.619) CG34(9.69,-17.619) CH4(-9.69,-18.306) CH5(-8.617,-18.476) CH6(-7.967,-18.476) CH7(-7.317,-18.476) CH8(-6.668,-18.476) CH9(-6.018,-18.476) CH11(-5.37,-18.415) CH12(-4.368,-18.415) CH14(-3.33,-18.415) CH15(-2.292,-18.415) CH17(-1.254,-18.415) CH19(-0.216,-18.415) CH20(0.822,-18.415) CH22(1.86,-18.415) CH23(2.898,-18.415) CH25(3.936,-18.415) CH27(5.069,-18.228) CH28(5.719,-18.228) CH29(6.369,-18.228) CH30(7.019,-18.228) CH31(7.669,-18.228) CH32(8.32,-18.228) CH34(9.365,-18.27) CJ4(-9.365,-18.869) CJ11(-5.37,-19.065) CJ12(-4.368,-19.065) CJ14(-3.33,-19.065) CJ15(-2.292,-19.065) CJ17(-1.254,-19.065) CJ19(-0.216,-19.065) CJ20(0.822,-19.065) CJ22(1.86,-19.065) CJ23(2.898,-19.065) CJ25(3.936,-19.065) CJ27(5.069,-19.139) CJ28(5.719,-19.139) CJ29(6.369,-19.139) CJ30(7.019,-19.139) CJ31(7.669,-19.139) CJ32(8.32,-19.139) CJ33(9.04,-18.833) CJ35(10.245,-18.878) CK1(-11.315,-19.561) CK3(-9.895,-19.83) CK4(-9.325,-19.518) CK5(-8.617,-19.4) CK6(-7.967,-19.4) CK7(-7.317,-19.4) CK8(-6.668,-19.4) CK9(-6.018,-19.4) CK11(-5.37,-19.715) CK12(-4.368,-19.715) CK14(-3.33,-19.715) CK15(-2.292,-19.715) CK17(-1.254,-19.715) CK19(-0.216,-19.715) CK20(0.822,-19.715) CK22(1.86,-19.715) CK23(2.898,-19.715) CK25(3.936,-19.715) CK33(9.15,-19.504) CK34(9.775,-19.326) CK36(10.612,-19.462) CK37(11.315,-19.374) CL2(-10.896,-20.058) CL35(10.061,-19.91) CL36(10.948,-20.019) CM1(-11.315,-20.555) CM3(-10.333,-20.383) CM4(-9.496,-20.343) CM5(-8.782,-20.365) CM6(-8.132,-20.371) CM7(-7.565,-20.69) CM8(-6.999,-20.371) CM9(-6.305,-20.365) CM10(-5.61,-20.371) CM11(-5.044,-20.69) CM12(-4.478,-20.371) CM13(-3.783,-20.365) CM14(-3.088,-20.371) CM15(-2.522,-20.69) CM16(-1.956,-20.371) CM17(-1.261,-20.365) CM18(-0.566,-20.371) CM19(0,-20.69) CM20(0.566,-20.371) CM21(1.261,-20.365) CM22(1.956,-20.371) CM23(2.522,-20.69) CM24(3.088,-20.371) CM25(3.783,-20.365) CM26(4.478,-20.371) CM27(5.044,-20.69) CM28(5.61,-20.371) CM29(6.305,-20.365) CM30(6.955,-20.365) CM31(7.531,-20.814) CM32(8.176,-20.365) CM33(8.826,-20.365) CM34(9.471,-20.286) CM35(10.447,-20.433) CM37(11.315,-20.555) CN2(-10.752,-20.88) CN3(-10.007,-20.946) CN4(-9.358,-20.978) CN5(-8.794,-21.367) CN9(-6.305,-21.245) CN13(-3.783,-21.245) CN17(-1.261,-21.245) CN21(1.261,-21.245) CN25(3.783,-21.245) CN29(6.305,-21.245) CN33(8.826,-21.245) CN34(9.396,-20.932) CN35(10.037,-21.037) CN36(10.687,-21.037) CP3(-10.037,-21.687) CP4(-9.39,-21.627) CP5(-8.942,-22.099) CP33(8.871,-21.968) CP34(9.396,-21.582) CP35(10.037,-21.687) CR4(-9.555,-22.315) CR6(-8.232,-22.315) CR32(8.321,-22.315) CR34(9.555,-22.315) D2(-10.64,20.579) D4(-9.594,20.605) D5(-8.782,20.365) D6(-8.132,20.371) D7(-7.565,20.69) D8(-6.999,20.371) D9(-6.305,20.505) D21(1.275,20.595) D22(1.883,20.365) D23(2.534,20.69) D24(3.184,20.365) D25(3.792,20.595) D26(4.4,20.365) D27(5.051,20.69) D28(5.701,20.365) D30(6.917,20.365) D31(7.568,20.69) D32(8.218,20.365) D34(9.396,20.282) D35(10.447,20.433) D37(11.315,20.555) E1(-11.315,20.096) E3(-10.008,20.089) E4(-9.365,19.995) E9(-6.21,19.862) E23(2.621,20.04) E27(5.051,20.04) E29(6.309,20.04) E31(7.568,20.04) E33(8.781,20.04) E35(10.061,19.91) E36(10.948,20.019) F2(-11.001,19.527) F3(-10.334,19.527) F4(-9.69,19.432) F5(-8.617,19.4) F6(-7.967,19.4) F7(-7.317,19.4) F8(-6.668,19.4) F21(1.149,19.715) F22(2.058,19.715) F24(3.184,19.715) F25(4.093,19.715) F33(9.15,19.504) F34(9.775,19.326) F36(10.612,19.462) F37(11.315,19.374) G1(-11.315,18.844) G4(-9.365,18.869) G9(-6.21,18.938) G21(1.149,19.065) G22(2.058,19.065) G24(3.184,19.065) G25(4.093,19.065) G27(5.069,19.139) G28(5.719,19.139) G29(6.369,19.139) G30(7.019,19.139) G31(7.669,19.139) G32(8.32,19.139) G33(9.04,18.833) G35(10.245,18.878) H4(-9.69,18.306) H5(-8.617,18.476) H6(-7.967,18.476) H7(-7.317,18.476) H8(-6.668,18.476) H9(-6.21,18.014) H21(1.149,18.415) H22(2.058,18.415) H24(3.184,18.415) H25(4.093,18.415) H27(5.069,18.228) H28(5.719,18.228) H29(6.369,18.228) H30(7.019,18.228) H31(7.669,18.228) H32(8.32,18.228) H34(9.365,18.27) J4(-9.365,17.743) J5(-8.617,17.552) J6(-7.967,17.552) J7(-7.317,17.552) J8(-6.668,17.552) J21(1.149,17.765) J22(2.058,17.765) J24(3.184,17.765) J25(4.093,17.765) J33(9.04,17.619) J34(9.69,17.619) K3(-10.334,17.086) K4(-9.325,17.086) K9(-6.21,17.09) K11(-5.322,17.115) K12(-4.38,17.115) K14(-3.438,17.115) K15(-2.496,17.115) K17(-1.554,17.115) K18(-0.613,17.115) K20(0.329,17.115) K21(1.149,17.115) K22(2.058,17.115) K24(3.184,17.115) K25(4.093,17.115) K27(5.069,17.317) K28(5.719,17.317) K29(6.369,17.317) K30(7.019,17.317) K31(7.669,17.317) K32(8.32,17.317) K34(9.365,16.968) L4(-9.365,16.428) L5(-8.617,16.628) L6(-7.967,16.628) L7(-7.317,16.628) L8(-6.668,16.628) L10(-5.753,16.628) L25(4.142,16.405) L27(5.069,16.405) L28(5.719,16.405) L29(6.369,16.405) L30(7.019,16.405) L31(7.669,16.405) L32(8.32,16.405) L33(9.04,16.36) L35(10.245,16.36) M4(-9.69,15.865) M9(-6.21,16.167) M24(3.679,15.949) M26(4.606,15.949) N4(-9.365,15.302) N5(-8.617,15.705) N6(-7.967,15.705) N7(-7.317,15.705) N8(-6.668,15.705) N9(-6.21,15.243) N10(-5.753,15.705) N25(4.142,15.494) N27(5.069,15.494) N28(5.719,15.494) N29(6.369,15.494) N30(7.019,15.494) N31(7.669,15.494) N32(8.32,15.494) N34(9.365,15.753) P3(-10.334,14.645) P4(-9.325,14.645) P5(-8.617,14.781) P6(-7.967,14.781) P7(-7.317,14.781) P8(-6.668,14.781) P10(-5.753,14.781) P24(3.679,15.038) P26(4.606,15.038) P33(9.04,15.102) P34(9.69,15.102) R4(-9.365,13.988) R9(-6.21,14.319) R24(3.679,14.127) R25(4.142,14.582) R26(4.606,14.127) R27(5.069,14.582) R28(5.719,14.582) R29(6.369,14.582) R30(7.019,14.582) R31(7.669,14.582) R32(8.32,14.582) R34(9.365,14.451) T4(-9.69,13.424) T5(-8.617,13.857) T6(-7.967,13.857) T7(-7.317,13.857) T8(-6.668,13.857) T9(-6.21,13.395) T10(-5.753,13.857) T25(4.142,13.671) T27(5.069,13.671) T28(5.719,13.671) T29(6.369,13.671) T30(7.019,13.671) T31(7.669,13.671) T32(8.32,13.671) T33(9.04,13.844) T35(10.245,13.844) U4(-9.365,12.861) U5(-8.617,12.933) U6(-7.967,12.933) U7(-7.317,12.933) U8(-6.668,12.933) U10(-5.753,12.933) U24(3.679,13.215) U26(4.606,13.215) U34(9.365,13.236) V3(-10.334,12.204) V4(-9.325,12.204) V9(-6.21,12.471) V24(3.679,12.304) V25(4.142,12.76) V26(4.606,12.304) V27(5.069,12.76) V28(5.719,12.76) V29(6.369,12.76) V30(7.019,12.76) V31(7.669,12.76) V32(8.32,12.76) V33(9.04,12.585) V34(9.69,12.585) W4(-9.365,11.547) W5(-8.617,12.009) W6(-7.967,12.009) W7(-7.317,12.009) W8(-6.668,12.009) W9(-6.21,11.548) W10(-5.753,12.009) W25(4.142,11.848) W27(5.069,11.848) W28(5.719,11.848) W29(6.369,11.848) W30(7.019,11.848) W31(7.669,11.848) W32(8.32,11.848) W34(9.365,11.934) Y4(-9.69,10.984) Y5(-8.617,11.086) Y6(-7.967,11.086) Y7(-7.317,11.086) Y8(-6.668,11.086) Y10(-5.753,11.086) Y24(3.679,11.392) Y25(4.142,10.937) Y26(4.606,11.392) Y27(5.069,10.937) Y28(5.719,10.937) Y29(6.369,10.937) Y30(7.019,10.937) Y31(7.669,10.937) Y32(8.32,10.937) Y33(9.04,11.327) Y35(10.245,11.327)
  oval 0.254x0.343 smd: A8(-6.915,22.315) A22(1.883,22.315) A24(3.184,22.315) A26(4.4,22.315) A28(5.701,22.315) A30(6.917,22.315) B6(-8.216,21.665) B7(-7.565,21.99) B8(-6.915,21.665) B9(-6.305,21.895) B21(1.275,21.895) B22(1.883,21.665) B23(2.534,21.99) B24(3.184,21.665) B25(3.792,21.895) B26(4.4,21.665) B27(5.051,21.99) B28(5.701,21.665) B29(6.309,21.895) B30(6.917,21.665) B31(7.568,21.99) B32(8.218,21.665) C6(-8.216,21.015) C7(-7.565,21.34) C8(-6.999,21.021) C22(1.883,21.015) C23(2.534,21.34) C24(3.184,21.015) C26(4.4,21.015) C27(5.051,21.34) C28(5.701,21.015) C30(6.917,21.015) C31(7.568,21.34) C32(8.218,21.015) CN6(-8.216,-21.015) CN7(-7.565,-21.34) CN8(-6.999,-21.021) CN10(-5.61,-21.021) CN11(-5.044,-21.34) CN12(-4.478,-21.021) CN14(-3.088,-21.021) CN15(-2.522,-21.34) CN16(-1.956,-21.021) CN18(-0.566,-21.021) CN19(0,-21.34) CN20(0.566,-21.021) CN22(1.956,-21.021) CN23(2.522,-21.34) CN24(3.088,-21.021) CN26(4.478,-21.021) CN27(5.044,-21.34) CN28(5.61,-21.021) CN30(6.912,-21.014) CN31(7.605,-21.461) CN32(8.219,-21.014) CP6(-8.216,-21.665) CP7(-7.565,-21.99) CP8(-6.915,-21.665) CP9(-6.305,-21.895) CP10(-5.694,-21.665) CP11(-5.044,-21.99) CP12(-4.393,-21.665) CP13(-3.783,-21.895) CP14(-3.172,-21.665) CP15(-2.522,-21.99) CP16(-1.871,-21.665) CP17(-1.261,-21.895) CP18(-0.65,-21.665) CP19(0,-21.99) CP20(0.65,-21.665) CP21(1.261,-21.895) CP22(1.871,-21.665) CP23(2.522,-21.99) CP24(3.172,-21.665) CP25(3.783,-21.895) CP26(4.393,-21.665) CP27(5.044,-21.99) CP28(5.694,-21.665) CP29(6.305,-21.895) CP30(6.983,-21.669) CP31(7.605,-22.19) CP32(8.296,-21.665) CR8(-6.915,-22.315) CR10(-5.694,-22.315) CR12(-4.393,-22.315) CR14(-3.172,-22.315) CR16(-1.871,-22.315) CR18(-0.65,-22.315) CR20(0.65,-22.315) CR22(1.871,-22.315) CR24(3.172,-22.315) CR26(4.393,-22.315) CR28(5.694,-22.315) CR30(6.912,-22.315)
  round 0.406 smd: A11(-5.322,22.315) A12(-4.38,22.315) A14(-3.438,22.315) A15(-2.496,22.315) A17(-1.554,22.315) A18(-0.613,22.315) A20(0.329,22.315) B11(-5.322,21.665) B12(-4.38,21.665) B14(-3.438,21.665) B15(-2.496,21.665) B17(-1.554,21.665) B18(-0.613,21.665) B20(0.329,21.665) C11(-5.322,21.015) C12(-4.38,21.015) C14(-3.438,21.015) C15(-2.496,21.015) C17(-1.554,21.015) C18(-0.613,21.015) C20(0.329,21.015) D11(-5.322,20.365) D12(-4.38,20.365) D14(-3.438,20.365) D15(-2.496,20.365) D17(-1.554,20.365) D18(-0.613,20.365) D20(0.329,20.365) F11(-5.322,19.715) F12(-4.38,19.715) F14(-3.438,19.715) F15(-2.496,19.715) F17(-1.554,19.715) F18(-0.613,19.715) F20(0.329,19.715) G11(-5.322,19.065) G12(-4.38,19.065) G14(-3.438,19.065) G15(-2.496,19.065) G17(-1.554,19.065) G18(-0.613,19.065) G20(0.329,19.065) H11(-5.322,18.415) H12(-4.38,18.415) H14(-3.438,18.415) H15(-2.496,18.415) H17(-1.554,18.415) H18(-0.613,18.415) H20(0.329,18.415) J11(-5.322,17.765) J12(-4.38,17.765) J14(-3.438,17.765) J15(-2.496,17.765) J17(-1.554,17.765) J18(-0.613,17.765) J20(0.329,17.765)
  oval 0.343x0.254 smd: AA1(-11.315,10.421) AA2(-10.665,10.421) AA3(-10.015,10.421) AA35(10.015,10.719) AA36(10.665,10.719) AA37(11.315,10.719) AB2(-10.99,9.763) AB35(10.34,10.068) AB36(10.99,10.068) AC1(-11.315,9.106) AC2(-10.665,9.106) AC3(-10.015,9.106) AC35(10.015,9.417) AC36(10.665,9.417) AC37(11.315,9.417) AD3(-10.34,8.543) AD36(10.895,8.809) AE1(-11.315,7.98) AE2(-10.665,7.98) AE3(-10.015,7.98) AE35(10.015,8.202) AE36(10.665,8.202) AE37(11.315,8.202) AF2(-10.99,7.322) AF35(10.34,7.551) AF36(10.99,7.551) AG1(-11.315,6.665) AG2(-10.665,6.665) AG3(-10.015,6.665) AG35(10.015,6.9) AG36(10.665,6.9) AG37(11.315,6.9) AH3(-10.34,6.102) AH36(10.895,6.293) AJ1(-11.315,5.539) AJ2(-10.665,5.539) AJ3(-10.015,5.539) AJ35(10.015,5.685) AJ36(10.665,5.685) AJ37(11.315,5.685) AK2(-10.99,4.882) AK35(10.34,5.034) AK36(10.99,5.034) AL1(-11.315,4.224) AL2(-10.665,4.224) AL3(-10.015,4.224) AL35(10.015,4.383) AL36(10.665,4.383) AL37(11.315,4.383) AM3(-10.34,3.661) AM36(10.895,3.775) AN1(-11.315,3.098) AN2(-10.665,3.098) AN3(-10.015,3.098) AN35(10.015,3.168) AN36(10.665,3.168) AN37(11.315,3.168) AP2(-10.99,2.441) AP35(10.34,2.517) AP36(10.99,2.517) AR1(-11.315,1.783) AR2(-10.665,1.783) AR3(-10.015,1.783) AR35(10.015,1.866) AR36(10.665,1.866) AR37(11.315,1.866) AT3(-10.34,1.22) AT36(10.895,1.259) AU1(-11.315,0.657) AU2(-10.665,0.657) AU3(-10.015,0.657) AU35(10.015,0.65) AU36(10.665,0.65) AU37(11.315,0.65) AV2(-10.99,0) AV35(10.34,0) AV36(10.99,0) AW1(-11.315,-0.657) AW2(-10.665,-0.657) AW3(-10.015,-0.657) AW35(10.015,-0.65) AW36(10.665,-0.65) AW37(11.315,-0.65) AY3(-10.34,-1.22) AY36(10.895,-1.259) BA1(-11.315,-1.783) BA2(-10.665,-1.783) BA3(-10.015,-1.783) BA35(10.015,-1.866) BA36(10.665,-1.866) BA37(11.315,-1.866) BB2(-10.99,-2.441) BB35(10.34,-2.517) BB36(10.99,-2.517) BC1(-11.315,-3.098) BC2(-10.665,-3.098) BC3(-10.015,-3.098) BC35(10.015,-3.168) BC36(10.665,-3.168) BC37(11.315,-3.168) BD3(-10.34,-3.661) BD36(10.895,-3.775) BE1(-11.315,-4.224) BE2(-10.665,-4.224) BE3(-10.015,-4.224) BE35(10.015,-4.383) BE36(10.665,-4.383) BE37(11.315,-4.383) BF2(-10.99,-4.882) BF35(10.34,-5.034) BF36(10.99,-5.034) BG1(-11.315,-5.539) BG2(-10.665,-5.539) BG3(-10.015,-5.539) BG35(10.015,-5.685) BG36(10.665,-5.685) BG37(11.315,-5.685) BH3(-10.34,-6.102) BH36(10.895,-6.293) BJ1(-11.315,-6.665) BJ2(-10.665,-6.665) BJ3(-10.015,-6.665) BJ35(10.015,-6.9) BJ36(10.665,-6.9) BJ37(11.315,-6.9) BK2(-10.99,-7.322) BK35(10.34,-7.551) BK36(10.99,-7.551) BL1(-11.315,-7.98) BL2(-10.665,-7.98) BL3(-10.015,-7.98) BL35(10.015,-8.202) BL36(10.665,-8.202) BL37(11.315,-8.202) BM3(-10.34,-8.543) BM36(10.895,-8.809) BN1(-11.315,-9.106) BN2(-10.665,-9.106) BN3(-10.015,-9.106) BN35(10.015,-9.417) BN36(10.665,-9.417) BN37(11.315,-9.417) BP2(-10.99,-9.763) BP35(10.34,-10.068) BP36(10.99,-10.068) BR1(-11.315,-10.421) BR2(-10.665,-10.421) BR3(-10.015,-10.421) BR35(10.015,-10.719) BR36(10.665,-10.719) BR37(11.315,-10.719) BT3(-10.34,-10.984) BT36(10.895,-11.327) BU1(-11.315,-11.547) BU2(-10.665,-11.547) BU3(-10.015,-11.547) BU35(10.015,-11.934) BU36(10.665,-11.934) BU37(11.315,-11.934) BV2(-10.99,-12.204) BV35(10.34,-12.585) BV36(10.99,-12.585) BW1(-11.315,-12.861) BW2(-10.665,-12.861) BW3(-10.015,-12.861) BW35(10.015,-13.236) BW36(10.665,-13.236) BW37(11.315,-13.236) BY3(-10.34,-13.424) BY36(10.895,-13.844) CA1(-11.315,-13.988) CA2(-10.665,-13.988) CA3(-10.015,-13.988) CA35(10.015,-14.451) CA36(10.665,-14.451) CA37(11.315,-14.451) CB2(-10.99,-14.645) CB35(10.34,-15.102) CB36(10.99,-15.102) CC1(-11.315,-15.302) CC2(-10.665,-15.302) CC3(-10.015,-15.302) CC35(10.015,-15.753) CC36(10.665,-15.753) CC37(11.315,-15.753) CD3(-10.34,-15.865) CE1(-11.315,-16.428) CE2(-10.665,-16.428) CE3(-10.015,-16.428) CE36(10.895,-16.36) CF2(-10.99,-17.086) CF35(10.015,-16.968) CF36(10.665,-16.968) CF37(11.315,-16.968) CG1(-11.315,-17.743) CG2(-10.665,-17.743) CG3(-10.015,-17.743) CG35(10.34,-17.619) CG36(10.99,-17.619) CH3(-10.34,-18.306) CH35(10.015,-18.27) CH36(10.665,-18.27) CH37(11.315,-18.27) CJ1(-11.315,-18.869) CJ2(-10.665,-18.869) CJ3(-10.015,-18.869) CJ36(10.895,-18.878) CK2(-10.485,-19.555) G2(-10.665,18.869) G3(-10.015,18.869) G36(10.895,18.878) H3(-10.34,18.306) H35(10.015,18.27) H36(10.665,18.27) H37(11.315,18.27) J1(-11.315,17.743) J2(-10.665,17.743) J3(-10.015,17.743) J35(10.34,17.619) J36(10.99,17.619) K2(-10.99,17.086) K35(10.015,16.968) K36(10.665,16.968) K37(11.315,16.968) L1(-11.315,16.428) L2(-10.665,16.428) L3(-10.015,16.428) L36(10.895,16.36) M3(-10.34,15.865) N1(-11.315,15.302) N2(-10.665,15.302) N3(-10.015,15.302) N35(10.015,15.753) N36(10.665,15.753) N37(11.315,15.753) P2(-10.99,14.645) P35(10.34,15.102) P36(10.99,15.102) R1(-11.315,13.988) R2(-10.665,13.988) R3(-10.015,13.988) R35(10.015,14.451) R36(10.665,14.451) R37(11.315,14.451) T3(-10.34,13.424) T36(10.895,13.844) U1(-11.315,12.861) U2(-10.665,12.861) U3(-10.015,12.861) U35(10.015,13.236) U36(10.665,13.236) U37(11.315,13.236) V2(-10.99,12.204) V35(10.34,12.585) V36(10.99,12.585) W1(-11.315,11.547) W2(-10.665,11.547) W3(-10.015,11.547) W35(10.015,11.934) W36(10.665,11.934) W37(11.315,11.934) Y3(-10.34,10.984) Y36(10.895,11.327)
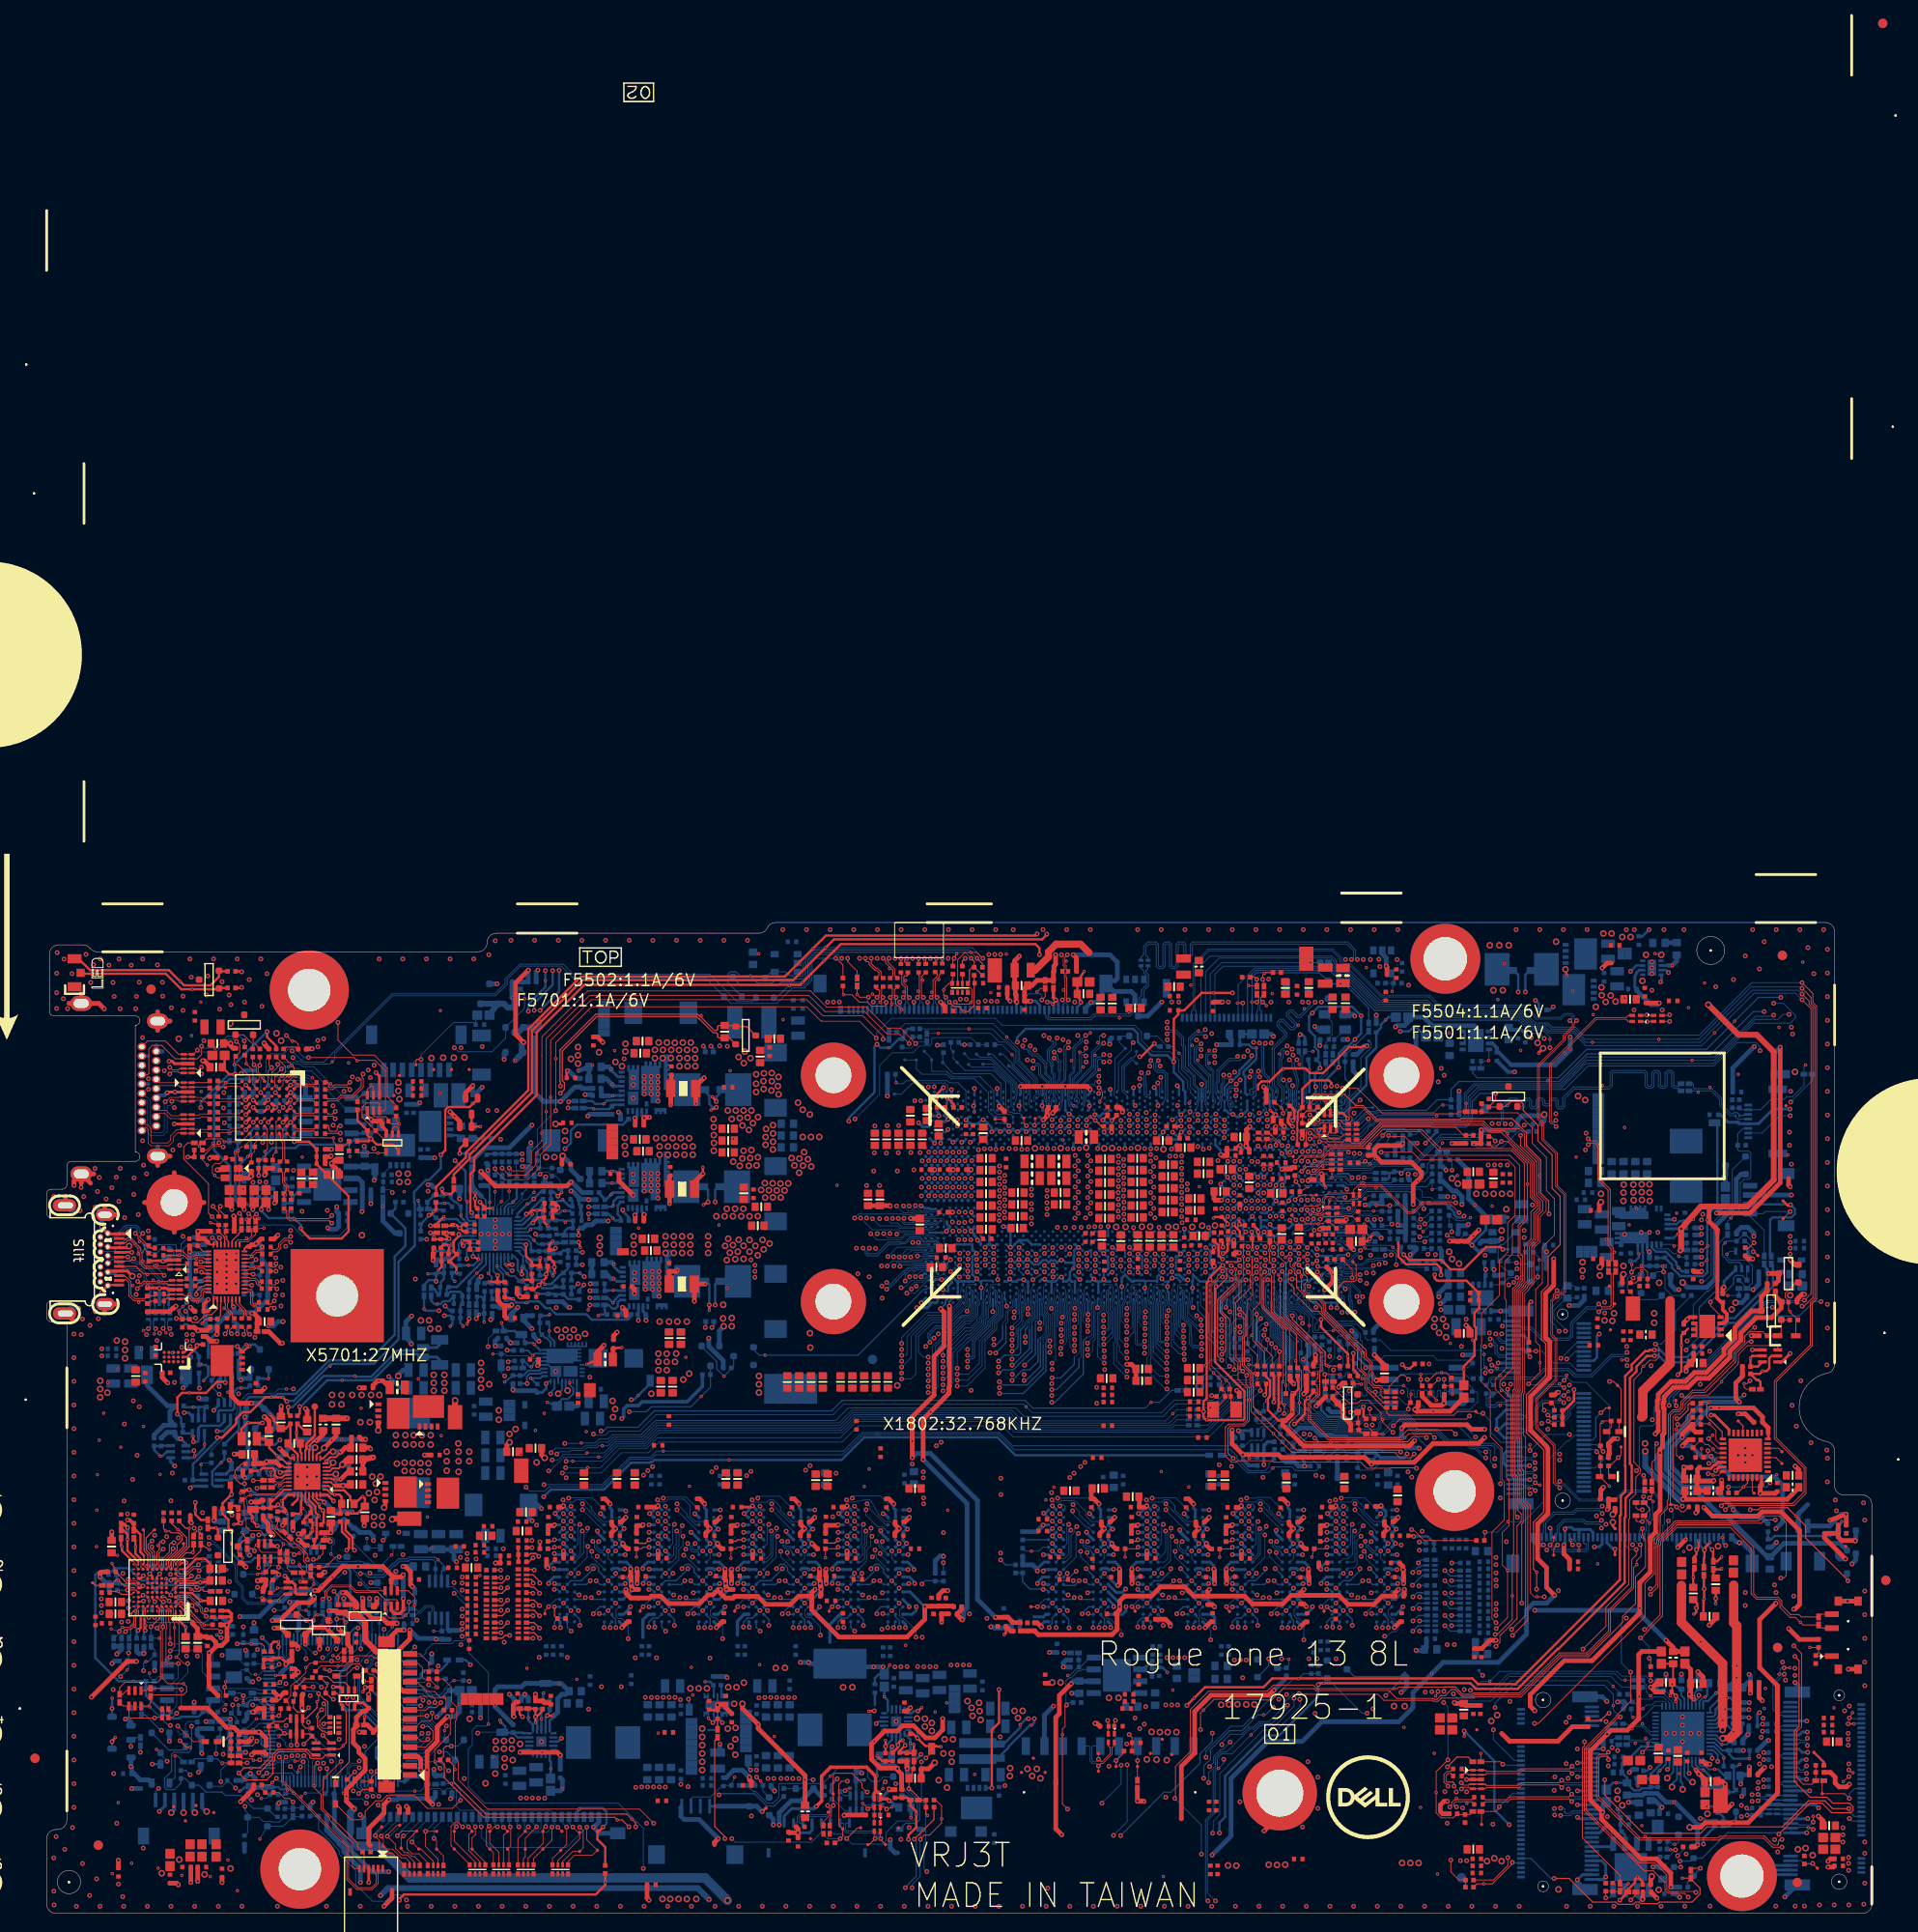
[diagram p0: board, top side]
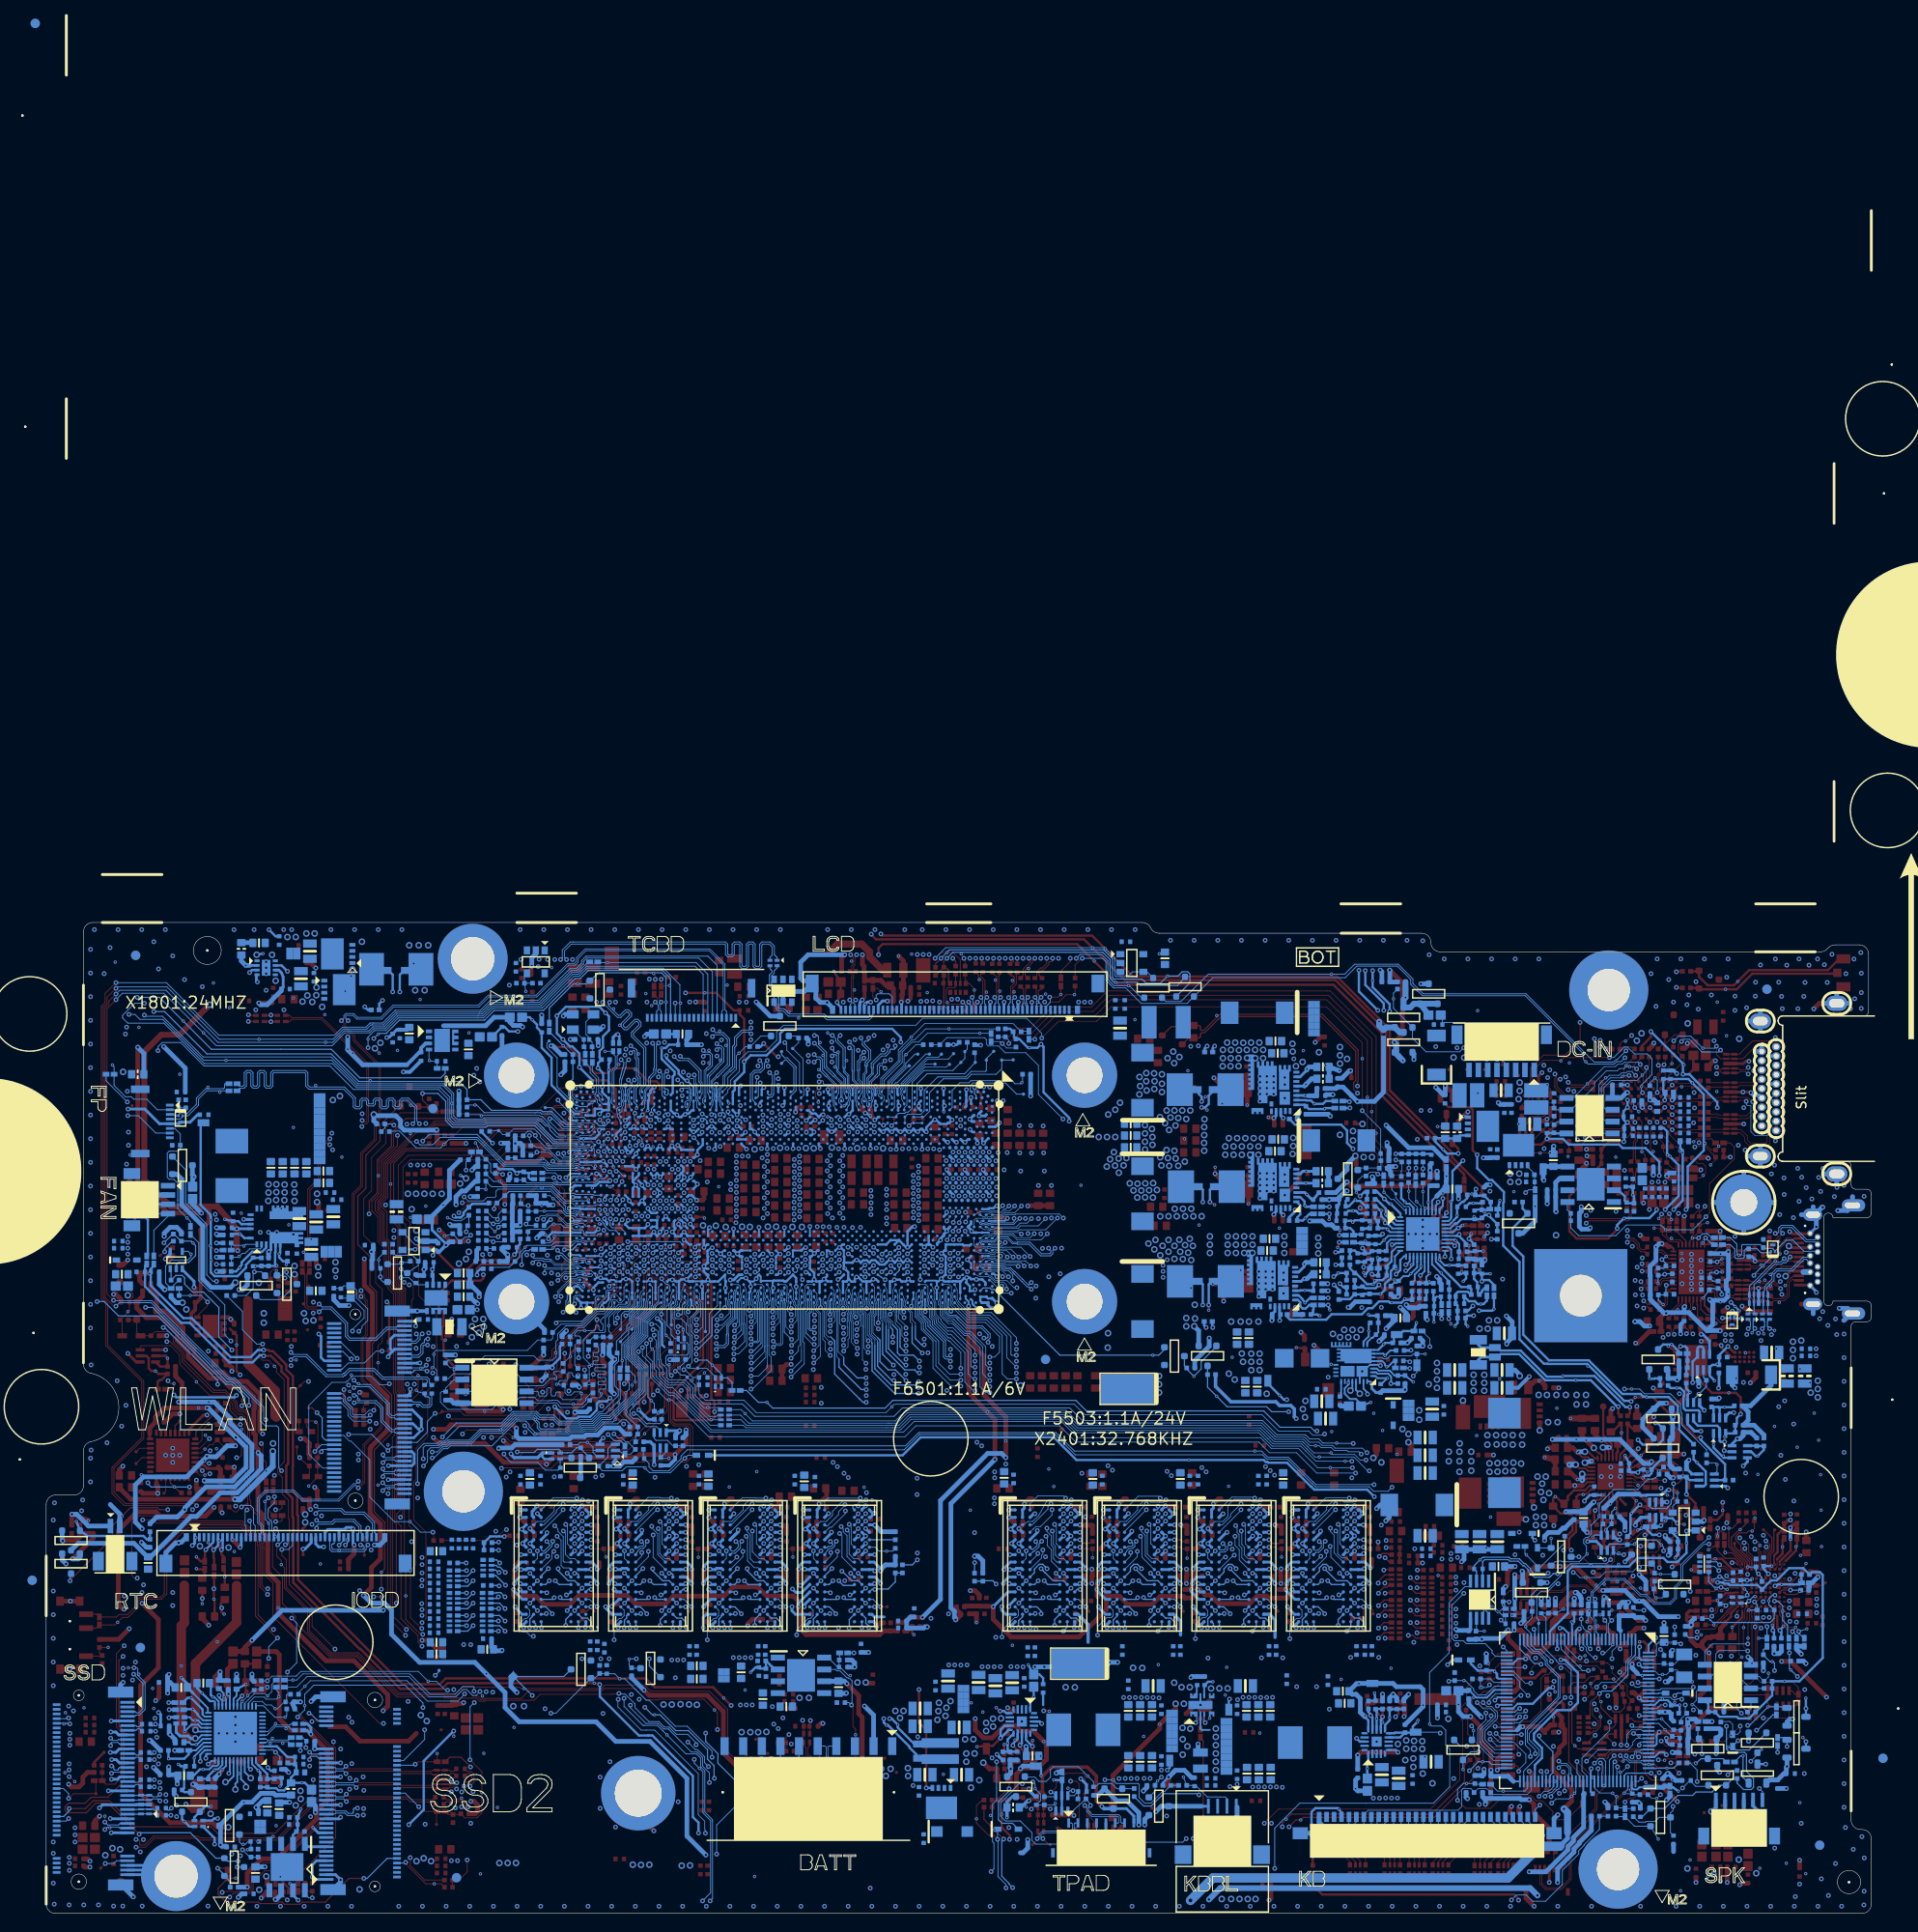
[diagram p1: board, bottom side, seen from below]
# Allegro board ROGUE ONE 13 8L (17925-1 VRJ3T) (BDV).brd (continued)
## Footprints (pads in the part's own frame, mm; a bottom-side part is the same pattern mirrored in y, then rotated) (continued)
C0201H13
  custom 0.076x0.076 smd: 1(0,0.279) 2(0,-0.279)
C402-TO0D2H28
  custom 0.14x0.14 smd: 1(0,0.457) 2(0,-0.457)
C402H22
  custom 0.114x0.114 smd: 1(0,0.457) 2(0,-0.457)
C603H36
  custom 0.197x0.197 smd: 1(0,0.66) 2(0,-0.66)
C603H38
  custom 0.197x0.197 smd: 1(0,0.66) 2(0,-0.66)
C603H40
  custom 0.197x0.197 smd: 1(0,0.66) 2(0,-0.66)
C805H54
  rect 1.473x0.889 smd: 1(0,0.838) 2(0,-0.838)
C805H58
  rect 1.473x0.889 smd: 1(0,0.838) 2(0,-0.838)
CON2O-U
  custom 0.159x0.159 smd: 1(0,0.254) 2(0,-0.254)
CSP15G154256H24
  round 0.356 smd: A1(0.5,1) A2(0,1) A3(-0.5,1) B1(0.5,0.5) B2(0,0.5) B3(-0.5,0.5) C1(0.5,0) C2(0,0) C3(-0.5,0) D1(0.5,-0.5) D2(0,-0.5) D3(-0.5,-0.5) E1(0.5,-1) E2(0,-1) E3(-0.5,-1)
CT7343H83
  rect 2.413x1.905 smd: 1(0,2.959) 2(0,-2.959)
CT7343H119
  rect 2.413x1.905 smd: 1(0,2.959) 2(0,-2.959)
D4724AKH44
  rect 2.007x1.295 smd: A(0,2.094) K(0,-2.094)
DFN8F3-G2517H32
  rect 0.406x0.686 smd: 1(0.975,1.411) 2(0.325,1.411) 3(-0.325,1.411) 4(-0.975,1.411) 5(-0.975,-1.411)
  rect 0.025x0.025 smd: 6(-0.325,-1.411) 8(0.975,-1.411)
  custom 0.171x0.171 smd: 7(0.325,-1.411)
  rect 2.489x1.676 smd: 9(0,0)
DFN8G2-G1710-U1H40
  rect 0.305x0.559 smd: 1(0.75,1.043) 2(0.25,1.043) 3(-0.25,1.043) 4(-0.75,1.043) 5(-0.75,-1.043) 6(-0.25,-1.043) 7(0.25,-1.043) 8(0.75,-1.043)
  rect 1.702x0.94 smd: 9(0,0)
DFN10G2510H22
  rect 0.305x0.66 smd: 1(1,0.43) 5(-1,0.43) 6(-1,-0.43) 10(1,-0.43)
  rect 0.254x0.66 smd: 2(0.521,0.43) 4(-0.521,0.43) 7(-0.521,-0.43) 9(0.521,-0.43)
  rect 0.025x0.025 smd: 3(0,0.43)
  rect 0.406x1.499 smd: 8(0,-0.43)
DM-87212-1400N-01
  rect 0.61x1.549 smd: 1(-6.5,-2.525) 2(-5.5,-2.525) 3(-4.5,-2.525) 4(-3.5,-2.525) 5(-2.5,-2.525) 6(-1.5,-2.525) 7(-0.5,-2.525) 8(0.5,-2.525) 9(1.5,-2.525) 10(2.5,-2.525) 11(3.5,-2.525) 12(4.5,-2.525) 13(5.5,-2.525) 14(6.5,-2.525)
  rect 1.194x1.803 smd: 15(-7.797,0) 16(7.797,0)
FH52-8S-D5SH
  rect 0.305x0.838 smd: 1(-1.75,3.175) 2(-1.25,3.175) 3(-0.75,3.175) 4(-0.25,3.175) 5(0.25,3.175) 6(0.75,3.175) 7(1.25,3.175) 8(1.75,3.175)
  rect 0.813x2.007 smd: 9(3.45,0) 10(-3.45,0)
GAP-CLOSE-PWR
  rect 0.66x0.762 smd: 1(-0.305,0) 2(0.305,0)
GAP-CLOSE-PWR-3
  rect 0.66x0.762 smd: 1(-0.305,0) 2(0.305,0)
HOLE276R150
  round 7.01 hole 3.81: 1(0,0)
HOLE296R182
  round 7.518 hole 4.623: 1(0,0)
HOLE315R197
  round 8.001 hole 5.004: 1(0,0)
HOLE335R178
  round 8.509 hole 4.521: 1(0,0)
HOLE394X394R174
  rect 10.008x10.008 hole 4.42: 1(0,0)
L4947-1115H119
  rect 2.007x2.007 smd: 1(0,1.922) 2(0,-1.922)
L7066-1830-UH95
  rect 3.505x2.667 smd: 1(0,2.653) 2(0,-2.653)
L7066-1830-UH119
  rect 3.505x2.667 smd: 1(0,2.653) 2(0,-2.653)
L7366-1930H95
  rect 3.505x2.819 smd: 1(0,2.729) 2(0,-2.729)
L109100-2430-UH119
  rect 3.505x3.302 smd: 1(0,4.27) 2(0,-4.27)
LD85D65-4P-1H20
  rect 0.533x0.33 smd: 1(0.382,0.29) 2(0.382,-0.29) 3(-0.382,-0.29) 4(-0.382,0.29)
LED3020-3P-19H44
  rect 1.499x0.991 smd: 1(0,1.5) 3(0,-1.5)
  rect 0.889x0.889 smd: 2(0.65,0)
MSOP8-1H44
  rect 0.356x1.397 smd: 1(-0.975,-1.991) 2(-0.325,-1.991) 3(0.325,-1.991) 4(0.975,-1.991) 5(0.975,1.991) 6(0.325,1.991) 7(-0.325,1.991) 8(-0.975,1.991)
MSS3-Q-T-R
  round 0.254 hole 0.965 unplated: (-1.5,0) (1.5,0)
  rect 0.61x1.499 smd: 1(-2.25,1.75) 2(0.751,1.75) 3(2.25,1.75)
  rect 0.991x0.813 smd: 4(-3.65,1.056) 5(-3.65,-1.056) 6(3.65,1.056) 7(3.65,-1.056)
NFSM0-S6701-TP20
  round 0.254 hole 1.168 unplated: (-10,0)
  round 0.254 hole 1.651 unplated: (10,0)
  rect 0.305x1.549 smd: 1(-9.25,5.225) 3(-8.75,5.225) 5(-8.25,5.225) 7(-7.75,5.225) 9(-7.25,5.225) 11(-6.75,5.225) 13(-6.25,5.225) 15(-5.75,5.225) 17(-5.25,5.225) 19(-4.75,5.225) 21(-4.25,5.225) 23(-3.75,5.225) 25(-3.25,5.225) 27(-2.75,5.225) 29(-2.25,5.225) 31(-1.75,5.225) 33(-1.25,5.225) 35(-0.75,5.225) 37(-0.25,5.225) 39(0.25,5.225) 41(0.75,5.225) 43(1.25,5.225) 45(1.75,5.225) 47(2.25,5.225) 49(2.75,5.225) 51(3.25,5.225) 53(3.75,5.225) 55(4.25,5.225) 57(4.75,5.225) 67(7.25,5.225) 69(7.75,5.225) 71(8.25,5.225) 73(8.75,5.225) 75(9.25,5.225)
  rect 0.305x0.838 smd: 2(-9,-2.375) 4(-8.5,-2.375) 6(-8,-2.375) 8(-7.5,-2.375) 10(-7,-2.375) 12(-6.5,-2.375) 14(-6,-2.375) 16(-5.5,-2.375) 18(-5,-2.375) 20(-4.5,-2.375) 22(-4,-2.375) 24(-3.5,-2.375) 26(-3,-2.375) 28(-2.5,-2.375) 30(-2,-2.375) 32(-1.5,-2.375) 34(-1,-2.375) 36(-0.5,-2.375) 38(0,-2.375) 40(0.5,-2.375) 42(1,-2.375) 44(1.5,-2.375) 46(2,-2.375) 48(2.5,-2.375) 50(3,-2.375) 52(3.5,-2.375) 54(4,-2.375) 56(4.5,-2.375) 58(5,-2.375) 68(7.5,-2.375) 70(8,-2.375) 72(8.5,-2.375) 74(9,-2.375)
  rect 1.194x2.743 smd: 76(-10.35,4.5) 77(10.35,4.5)
NTC-402H22-U
  custom 0.127x0.127 smd: 1(0,0.432) 2(0,-0.432)
NTC-603H38
  rect 0.914x0.787 smd: 1(0,0.66) 2(0,-0.66)
OSC-3225-4P-3H36
  rect 1.27x0.914 smd: 1(-1.108,-0.825) 2(1.108,-0.825) 3(1.108,0.825) 4(-1.108,0.825)
POLYSW-2114H30
  rect 1.6x0.889 smd: 1(0,0.865) 2(0,-0.865)
POLYSW-4633-UH43
  rect 3.505x1.626 smd: 1(0,1.834) 2(0,-1.834)
PPAK-8P-3232H36
  rect 0.406x0.66 smd: 1(-0.975,-2.142) 2(-0.325,-2.142) 3(0.325,-2.142) 4(0.975,-2.142)
  rect 3.353x2.438 smd: 5(0,0)
  rect 0.025x0.025 smd: 6(0.65,0.838) 7(0,0.838) 8(-0.65,0.838)
QFN20Z3-G1D1H36
  custom 0.064x0.064 smd: 1(0.9,1.297) 5(-0.9,1.297) 6(-1.297,0.9) 10(-1.297,-0.9) 11(-0.9,-1.297) 15(0.9,-1.297) 16(1.297,-0.9) 20(1.297,0.9)
  rect 0.254x0.914 smd: 2(0.45,1.297) 3(0,1.297) 4(-0.45,1.297) 12(-0.45,-1.297) 13(0,-1.297) 14(0.45,-1.297)
  rect 0.914x0.254 smd: 7(-1.297,0.45) 8(-1.297,0) 9(-1.297,-0.45) 17(1.297,-0.45) 18(1.297,0) 19(1.297,0.45)
  rect 1.092x1.092 smd: 21(0,0)
QFN22G4-G2PH42
  rect 0.305x0.66 smd: 1(1.25,1.924) 2(0.75,1.924) 3(0.25,1.924) 4(-0.25,1.924) 5(-0.75,1.924) 6(-1.25,1.924) 16(0.75,-1.924) 17(1.25,-1.924)
  custom 0.326x0.326 smd: 7(-1.924,1.25)
  rect 0.025x0.025 smd: 8(-1.924,0.75) 9(-1.924,0.25) 10(-1.924,-0.75) 13(-0.75,-1.924) 14(-0.25,-1.924) 15(0.25,-1.924)
  custom 0.232x0.232 smd: 11(-1.924,-1.25)
  custom 0.165x0.165 smd: 12(-1.25,-1.924)
  rect 0.66x0.305 smd: 18(1.924,-1.25) 19(1.924,-0.75) 20(1.924,-0.25) 21(1.924,0.25) 22(1.924,1.25)
QFN31G5-G4P-9H34
  rect 0.305x0.66 smd: 1(1.75,2.424) 2(1.25,2.424) 3(0.75,2.424) 4(0.25,2.424) 5(-0.25,2.424) 6(-0.75,2.424) 7(-1.25,2.424) 8(-1.75,2.424)
  rect 0.025x0.025 smd: 9(-2.424,1.75) 10(-2.424,1.25) 11(-2.424,0.75) 12(-2.424,-0.25) 13(-2.424,-0.75) 14(-2.424,-1.25) 15(-2.424,-1.75) 17(-1.25,-2.424) 18(-0.75,-2.424) 19(-0.25,-2.424) 20(0.25,-2.424) 21(0.75,-2.424) 22(1.25,-2.424) 23(1.75,-2.424) 25(2.424,-1.25) 26(2.424,-0.75)
  custom 0.165x0.165 smd: 16(-1.75,-2.424) 24(2.424,-1.75)
  rect 0.61x0.305 smd: 27(2.424,-0.25)
  rect 0.66x0.305 smd: 28(2.424,0.25) 29(2.424,0.75) 30(2.424,1.25) 31(2.424,1.75)
  rect 1.422x1.143 smd: 32(1.038,1.183)
  custom 0.326x0.326 smd: 33(-1.175,1.183)
  custom 0.542x0.542 smd: 34(-0.669,-0.742)
  rect 0.559x0.406 smd: 35(1.66,-0.25)
QFN32G5-G3D6H32
  rect 0.305x0.66 smd: 1(1.75,2.487) 8(-1.75,2.487) 17(-1.75,-2.487) 24(1.75,-2.487)
  rect 0.305x0.737 smd: 2(1.25,2.449) 3(0.75,2.449) 4(0.25,2.449) 5(-0.25,2.449) 6(-0.75,2.449) 7(-1.25,2.449) 18(-1.25,-2.449) 19(-0.75,-2.449) 20(-0.25,-2.449) 21(0.25,-2.449) 22(0.75,-2.449) 23(1.25,-2.449)
  rect 0.66x0.305 smd: 9(-2.487,1.75) 16(-2.487,-1.75) 25(2.487,-1.75) 32(2.487,1.75)
  rect 0.737x0.305 smd: 10(-2.449,1.25) 11(-2.449,0.75) 12(-2.449,0.25) 13(-2.449,-0.25) 14(-2.449,-0.75) 15(-2.449,-1.25) 26(2.449,-1.25) 27(2.449,-0.75) 28(2.449,-0.25) 29(2.449,0.25) 30(2.449,0.75) 31(2.449,1.25)
  rect 3.607x3.607 smd: 33(0,0)
QFN32J4-G2D85H34
  rect 0.203x0.61 smd: 1(1.4,1.958) 2(1,1.958) 3(0.6,1.958) 4(0.2,1.958) 5(-0.2,1.958) 6(-0.6,1.958) 7(-1,1.958) 8(-1.4,1.958) 17(-1.4,-1.958) 18(-1,-1.958) 19(-0.6,-1.958) 20(-0.2,-1.958) 21(0.2,-1.958) 22(0.6,-1.958) 23(1,-1.958) 24(1.4,-1.958)
  rect 0.61x0.203 smd: 9(-1.958,1.4) 10(-1.958,1) 11(-1.958,0.6) 12(-1.958,0.2) 13(-1.958,-0.2) 14(-1.958,-0.6) 15(-1.958,-1) 16(-1.958,-1.4) 25(1.958,-1.4) 26(1.958,-1) 27(1.958,-0.6) 28(1.958,-0.2) 29(1.958,0.2) 30(1.958,0.6) 31(1.958,1) 32(1.958,1.4)
  rect 2.845x2.845 smd: 33(0,0)
QFN32J4-G3PH32
  rect 0.203x0.559 smd: 1(1.4,1.975) 2(1,1.975) 3(0.6,1.975) 4(0.2,1.975) 5(-0.2,1.975) 6(-0.6,1.975) 7(-1,1.975) 8(-1.4,1.975) 21(0.2,-1.975) 22(0.6,-1.975) 23(1,-1.975) 24(1.4,-1.975)
  rect 0.559x0.203 smd: 9(-1.975,1.4) 10(-1.975,1) 25(1.975,-1.4) 26(1.975,-1) 27(1.975,-0.6) 28(1.975,-0.2) 29(1.975,0.2) 30(1.975,0.6) 31(1.975,1) 32(1.975,1.4)
  rect 0.025x0.025 smd: 11(-1.975,0.6) 12(-1.975,0.2) 13(-1.975,-0.2) 14(-1.975,-0.6) 15(-1.975,-1) 17(-1.4,-1.975) 18(-1,-1.975) 19(-0.6,-1.975) 20(-0.2,-1.975)
  custom 0.14x0.14 smd: 16(-1.975,-1.4)
  rect 1.168x1.219 smd: 33(0.895,0.86)
  rect 1.168x1.524 smd: 34(0.895,-0.72)
  custom 0.401x0.401 smd: 35(-0.762,0)
QFN40J5-G3D6-DIFF-H34
  rect 0.203x0.66 smd: 1(1.8,2.388) 10(-1.8,2.388) 21(-1.8,-2.388) 30(1.8,-2.388)
  rect 0.203x0.737 smd: 2(1.4,2.388) 3(1,2.388) 4(0.6,2.388) 5(0.2,2.388) 6(-0.2,2.388) 7(-0.6,2.388) 8(-1,2.388) 9(-1.4,2.388) 22(-1.4,-2.388) 23(-1,-2.388) 24(-0.6,-2.388) 25(-0.2,-2.388) 26(0.2,-2.388) 27(0.6,-2.388) 28(1,-2.388) 29(1.4,-2.388)
  rect 0.66x0.203 smd: 11(-2.388,1.8) 20(-2.388,-1.8) 31(2.388,-1.8) 40(2.388,1.8)
  rect 0.737x0.203 smd: 12(-2.388,1.4) 13(-2.388,1) 14(-2.388,0.6) 15(-2.388,0.2) 16(-2.388,-0.2) 17(-2.388,-0.6) 18(-2.388,-1) 19(-2.388,-1.4) 32(2.388,-1.4) 33(2.388,-1) 34(2.388,-0.6) 35(2.388,-0.2) 36(2.388,0.2) 37(2.388,0.6) 38(2.388,1) 39(2.388,1.4)
  rect 3.607x3.607 smd: 41(0,0)
QFN40J4060-G2848H32
  rect 0.203x0.635 smd: 1(1.4,2.936) 2(1,2.936) 3(0.6,2.936) 4(0.2,2.936) 5(-0.2,2.936) 6(-0.6,2.936) 7(-1,2.936) 8(-1.4,2.936) 21(-1.4,-2.936) 22(-1,-2.936) 23(-0.6,-2.936) 24(-0.2,-2.936) 25(0.2,-2.936) 26(0.6,-2.936) 27(1,-2.936) 28(1.4,-2.936)
  rect 0.635x0.203 smd: 9(-1.936,2.2) 10(-1.936,1.8) 11(-1.936,1.4) 12(-1.936,1) 13(-1.936,0.6) 14(-1.936,0.2) 15(-1.936,-0.2) 16(-1.936,-0.6) 17(-1.936,-1) 18(-1.936,-1.4) 19(-1.936,-1.8) 20(-1.936,-2.2) 29(1.936,-2.2) 30(1.936,-1.8) 31(1.936,-1.4) 32(1.936,-1) 33(1.936,-0.6) 34(1.936,-0.2) 35(1.936,0.2) 36(1.936,0.6) 37(1.936,1) 38(1.936,1.4) 39(1.936,1.8) 40(1.936,2.2)
  rect 2.794x4.801 smd: 41(0,0)
QFN48J6-G465H40
  rect 0.203x0.711 smd: 1(2.2,2.962) 2(1.8,2.962) 3(1.4,2.962) 4(1,2.962) 5(0.6,2.962) 6(0.2,2.962) 7(-0.2,2.962) 8(-0.6,2.962) 9(-1,2.962) 10(-1.4,2.962) 11(-1.8,2.962) 12(-2.2,2.962) 25(-2.2,-2.962) 26(-1.8,-2.962) 27(-1.4,-2.962) 28(-1,-2.962) 29(-0.6,-2.962) 30(-0.2,-2.962) 31(0.2,-2.962) 32(0.6,-2.962) 33(1,-2.962) 34(1.4,-2.962) 35(1.8,-2.962) 36(2.2,-2.962)
  rect 0.711x0.203 smd: 13(-2.962,2.2) 14(-2.962,1.8) 15(-2.962,1.4) 16(-2.962,1) 17(-2.962,0.6) 18(-2.962,0.2) 19(-2.962,-0.2) 20(-2.962,-0.6) 21(-2.962,-1) 22(-2.962,-1.4) 23(-2.962,-1.8) 24(-2.962,-2.2) 37(2.962,-2.2) 38(2.962,-1.8) 39(2.962,-1.4) 40(2.962,-1) 41(2.962,-0.6) 42(2.962,-0.2) 43(2.962,0.2) 44(2.962,0.6) 45(2.962,1) 46(2.962,1.4) 47(2.962,1.8) 48(2.962,2.2)
  rect 4.648x4.648 smd: 49(0,0)
R402H14
  custom 0.127x0.127 smd: 1(0,0.432) 2(0,-0.432)
R402H15
  custom 0.127x0.127 smd: 1(0,0.432) 2(0,-0.432)
R402H16
  custom 0.127x0.127 smd: 1(0,0.432) 2(0,-0.432)
R603H22
  custom 0.197x0.197 smd: 1(0,0.66) 2(0,-0.66)
R805H16
  rect 1.473x0.889 smd: 1(0,0.838) 2(0,-0.838)
R805H24
  rect 1.473x0.889 smd: 1(0,0.838) 2(0,-0.838)
R1206H24
  rect 1.854x1.016 smd: 1(0,1.346) 2(0,-1.346)
R1206H26
  rect 1.854x1.016 smd: 1(0,1.346) 2(0,-1.346)
R1206H28
  rect 1.854x1.016 smd: 1(0,1.346) 2(0,-1.346)
R3720H40
  rect 4.013x1.041 smd: 1(0,0.867) 2(0,-0.867)
SC70-2D2-312H44
  custom 0.152x0.152 smd: 1(-0.65,-0.864) 2(0.65,-0.864) 3(0,0.864)
SC70-5H44
  rect 0.356x0.762 smd: 1(0.65,0.935) 2(0,0.935) 3(-0.65,0.935) 4(-0.65,-0.935) 5(0.65,-0.935)
SKT-HDMI23-188142
  oval 0.813x0.914 hole 0.559: 1(-4.5,6.5) 2(-4,8.05) 3(-3.5,6.5) 4(-3,8.05) 5(-2.5,6.5) 6(-2,8.05) 7(-1.5,6.5) 8(-1,8.05) 9(-0.5,6.5) 10(0,8.05) 11(0.5,6.5) 12(1,8.05) 13(1.5,6.5) 14(2,8.05) 15(2.5,6.5) 16(3,8.05) 17(3.5,6.5) 18(4,8.05) 19(4.5,6.5)
  oval 1.626x2.311 hole 0.914x1.6: 20(-7.25,8.2) 21(7.25,8.2) 22(-9.15,0) 23(9.15,0)
SKT-USB30-118098-4
  round 0.254 hole 0.813 unplated: (-3.6,5.1) (3.6,5.1)
  oval 1.321x2.057 hole 0.61x1.473: 13(-4.8,4.225) 14(4.8,4.225)
  oval 1.321x2.515 hole 0.61x1.6: 15(-5.8,0) 16(5.8,0)
  rect 0.305x1.092 smd: A1(-2.75,5.76) A2(-2.25,5.76) A3(-1.75,5.76) A4(-1.25,5.76) A5(-0.75,5.76) A6(-0.25,5.76) A7(0.25,5.76) A8(0.75,5.76) A9(1.25,5.76) A10(1.75,5.76) A11(2.25,5.76) A12(2.75,5.76)
  round 0.66 hole 0.406: B1(2.8,4.55) B2(2.4,3.75) B3(1.6,3.75) B4(1.35,4.55) B5(0.8,3.75) B6(0.4,4.55) B7(-0.4,4.55) B8(-0.8,3.75) B9(-1.35,4.55) B10(-1.6,3.75) B11(-2.4,3.75) B12(-2.8,4.55)
SLP2510P8-1H22
  rect 0.305x0.635 smd: 1(-1,-0.437) 5(1,-0.437) 6(1,0.437) 10(-1,0.437)
  rect 0.203x0.635 smd: 2(-0.5,-0.437) 4(0.5,-0.437) 7(0.5,0.437) 9(-0.5,0.437)
  rect 0.406x0.635 smd: 3(0,-0.437) 8(0,0.437)
SMD49-12H34
  rect 1.753x1.27 smd: 1(0,1.231) 2(0,-1.231)
SMD-ARES4H16
  rect 0.356x0.61 smd: 1(-0.325,-0.457) 2(0.325,-0.457) 3(0.325,0.457) 4(-0.325,0.457)
SMD-ARES4H18
  rect 0.356x0.61 smd: 1(-0.325,-0.457) 2(0.325,-0.457) 3(0.325,0.457) 4(-0.325,0.457)
SMD-ARES4H20
  rect 0.356x0.61 smd: 1(-0.325,-0.457) 2(0.325,-0.457) 3(0.325,0.457) 4(-0.325,0.457)
SMD-OSC38H32
  rect 0.965x0.737 smd: 1(-0.706,-0.495) 2(0.706,-0.495) 3(0.706,0.495) 4(-0.706,0.495)
SOD123AK-2H43
  rect 1.143x1.245 smd: A(0,1.631) K(0,-1.631)
SOD323-2513AKH36
  rect 0.559x1.041 smd: A(0,0.987) K(0,-0.987)
SOD323AKH38
  rect 0.559x0.813 smd: A(0,1.1) K(0,-1.1)
SOD323AKH40
  rect 0.559x0.813 smd: A(0,1.1) K(0,-1.1)
SOD323AKH44
  rect 0.559x0.813 smd: A(0,1.1) K(0,-1.1)
SOD523AKH26
  rect 0.559x0.813 smd: A(0,0.66) K(0,-0.66)
SOIC8-1H86
  rect 0.635x1.524 smd: 1(-1.905,-3.442) 2(-0.635,-3.442) 3(0.635,-3.442) 4(1.905,-3.442) 5(1.905,3.442) 6(0.635,3.442) 7(-0.635,3.442) 8(-1.905,3.442)
SOIC8-G3530H63
  rect 0.635x1.524 smd: 1(-1.905,-2.492) 2(-0.635,-2.492) 3(0.635,-2.492) 4(1.905,-2.492) 5(1.905,2.492) 6(0.635,2.492) 7(-0.635,2.492) 8(-1.905,2.492)
  rect 3.505x2.997 smd: 9(0,0)
SOIC8H69
  rect 0.635x1.524 smd: 1(-1.905,-2.477) 2(-0.635,-2.477) 3(0.635,-2.477) 4(1.905,-2.477) 5(1.905,2.477) 6(0.635,2.477) 7(-0.635,2.477) 8(-1.905,2.477)
SON14J3020-G2610H34
  rect 0.025x0.025 smd: 1(1.2,0.978) 6(-0.8,0.978) 9(-0.8,-0.978) 14(1.2,-0.978)
  custom 0.14x0.14 smd: 2(0.8,0.978) 7(-1.2,0.978) 8(-1.2,-0.978) 13(0.8,-0.978)
  rect 0.203x0.559 smd: 3(0.4,0.978) 4(0,0.978) 5(-0.4,0.978) 10(-0.4,-0.978) 11(0,-0.978) 12(0.4,-0.978)
  rect 2.591x0.889 smd: 15(0,0)
SOT23-2D4-312H44
  custom 0.171x0.171 smd: 1(-0.95,-1.069) 2(0.95,-1.069) 3(0,1.069)
SOT23-2D4-312H46
  custom 0.171x0.171 smd: 1(-0.95,-1.069) 2(0.95,-1.069) 3(0,1.069)
SOT23-2D4-312H60
  custom 0.171x0.171 smd: 1(-0.95,-1.069) 2(0.95,-1.069) 3(0,1.069)
SOT23CBE2D4H44
  custom 0.165x0.165 smd: B(-0.95,-1.073) C(0,1.073) E(0.95,-1.073)
SOT23CBE2D4H46-U
  custom 0.165x0.165 smd: B(-0.95,-1.073) C(0,1.073) E(0.95,-1.073)
SOT23CBE2D6H62
  custom 0.165x0.165 smd: B(-0.95,-1.016) C(0,1.016) E(0.95,-1.016)
SOT23DGS2D4H44
  custom 0.171x0.171 smd: D(0,1.069) G(-0.95,-1.069) S(0.95,-1.069)
SOT323CBE2D2H40
  custom 0.152x0.152 smd: B(-0.65,-0.864) C(0,0.864) E(0.65,-0.864)
SOT883-1D0-321H20
  rect 0.203x0.305 smd: 1(0.203,-0.35) 2(-0.203,-0.35)
  rect 0.559x0.305 smd: 3(0,0.35)
SOT-6H58
  rect 0.61x0.813 smd: 1(-0.95,-1.219) 2(0,-1.219) 3(0.95,-1.219) 4(0.95,1.219) 5(0,1.219) 6(-0.95,1.219)
SOT-23-5H52
  rect 0.686x0.864 smd: 1(-0.953,-1.232) 2(0,-1.232) 3(0.953,-1.232) 4(0.953,1.232) 5(-0.953,1.232)
SOT-23-5H56
  rect 0.686x0.864 smd: 1(-0.953,-1.232) 2(0,-1.232) 3(0.953,-1.232) 4(0.953,1.232) 5(-0.953,1.232)
SOT-23-5H58
  rect 0.686x0.864 smd: 1(-0.953,-1.232) 2(0,-1.232) 3(0.953,-1.232) 4(0.953,1.232) 5(-0.953,1.232)
SOT-23-9H44
  custom 0.165x0.165 smd: 1(-0.953,-1.056) 2(0.953,-1.056) 3(0,1.056)
SOT-363H44
  rect 0.356x0.965 smd: 1(-0.65,-0.826) 2(0,-0.826) 3(0.65,-0.826) 4(0.65,0.826) 5(0,0.826) 6(-0.65,0.826)
SPR6035H166
  rect 5.69x3.2 smd: 1(-1.6,0)
STF237R113H62
  round 6.02 hole 2.87: 1(0,0)
TPAD14-OP
  round 0.356 smd: 1(0,0)
TPAD28
  round 0.711 smd: 1(0,0)
TQFP128-2H48
  rect 0.203x1.27 smd: 1(6.2,7.62) 2(5.8,7.62) 3(5.4,7.62) 4(5,7.62) 5(4.6,7.62) 6(4.2,7.62) 7(3.8,7.62) 8(3.4,7.62) 9(3,7.62) 10(2.6,7.62) 11(2.2,7.62) 12(1.8,7.62) 13(1.4,7.62) 14(0.999,7.62) 15(0.599,7.62) 16(0.199,7.62) 17(-0.199,7.62) 18(-0.599,7.62) 19(-0.999,7.62) 20(-1.4,7.62) 21(-1.8,7.62) 22(-2.2,7.62) 23(-2.6,7.62) 24(-3,7.62) 25(-3.4,7.62) 26(-3.8,7.62) 27(-4.2,7.62) 28(-4.6,7.62) 29(-5,7.62) 30(-5.4,7.62) 31(-5.8,7.62) 32(-6.2,7.62) 65(-6.2,-7.62) 66(-5.8,-7.62) 67(-5.4,-7.62) 68(-5,-7.62) 69(-4.6,-7.62) 70(-4.2,-7.62) 71(-3.8,-7.62) 72(-3.4,-7.62) 73(-3,-7.62) 74(-2.6,-7.62) 75(-2.2,-7.62) 76(-1.8,-7.62) 77(-1.4,-7.62) 78(-0.999,-7.62) 79(-0.599,-7.62) 80(-0.199,-7.62) 81(0.199,-7.62) 82(0.599,-7.62) 83(0.999,-7.62) 84(1.4,-7.62) 85(1.8,-7.62) 86(2.2,-7.62) 87(2.6,-7.62) 88(3,-7.62) 89(3.4,-7.62) 90(3.8,-7.62) 91(4.2,-7.62) 92(4.6,-7.62) 93(5,-7.62) 94(5.4,-7.62) 95(5.8,-7.62) 96(6.2,-7.62)
  rect 1.27x0.203 smd: 33(-7.62,6.2) 34(-7.62,5.8) 35(-7.62,5.4) 36(-7.62,5) 37(-7.62,4.6) 38(-7.62,4.2) 39(-7.62,3.8) 40(-7.62,3.4) 41(-7.62,3) 42(-7.62,2.6) 43(-7.62,2.2) 44(-7.62,1.8) 45(-7.62,1.4) 46(-7.62,0.999) 47(-7.62,0.599) 48(-7.62,0.199) 49(-7.62,-0.199) 50(-7.62,-0.599) 51(-7.62,-0.999) 52(-7.62,-1.4) 53(-7.62,-1.8) 54(-7.62,-2.2) 55(-7.62,-2.6) 56(-7.62,-3) 57(-7.62,-3.4) 58(-7.62,-3.8) 59(-7.62,-4.2) 60(-7.62,-4.6) 61(-7.62,-5) 62(-7.62,-5.4) 63(-7.62,-5.8) 64(-7.62,-6.2) 97(7.62,-6.2) 98(7.62,-5.8) 99(7.62,-5.4) 100(7.62,-5) 101(7.62,-4.6) 102(7.62,-4.2) 103(7.62,-3.8) 104(7.62,-3.4) 105(7.62,-3) 106(7.62,-2.6) 107(7.62,-2.2) 108(7.62,-1.8) 109(7.62,-1.4) 110(7.62,-0.999) 111(7.62,-0.599) 112(7.62,-0.199) 113(7.62,0.199) 114(7.62,0.599) 115(7.62,0.999) 116(7.62,1.4) 117(7.62,1.8) 118(7.62,2.2) 119(7.62,2.6) 120(7.62,3) 121(7.62,3.4) 122(7.62,3.8) 123(7.62,4.2) 124(7.62,4.6) 125(7.62,5) 126(7.62,5.4) 127(7.62,5.8) 128(7.62,6.2)
unnamed#2
  round 0.254 hole 4.013 unplated: (0,0)

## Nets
1.8V_RUN_FB: PC5405.2 PR5403.2 PR5404.1 PU5401.2
1V_CPU_CORE: CPU1.AN9 CPU1.AN10 CPU1.AN24 CPU1.AN26 CPU1.AN27 CPU1.AP2 CPU1.AP9 CPU1.AP24 CPU1.AP26 CPU1.AR5 CPU1.AR6 CPU1.AR7 CPU1.AR8 CPU1.AR10 CPU1.AR25 CPU1.AR27 CPU1.AT9 CPU1.AT24 CPU1.AT26 CPU1.AU5 CPU1.AU6 CPU1.AU7 CPU1.AU8 CPU1.AU9 CPU1.AU24 CPU1.AU25 CPU1.AU26 CPU1.AU27 CPU1.AV2 CPU1.AV5 CPU1.AV7 CPU1.AV10 CPU1.AV27 CPU1.AW5 CPU1.AW6 CPU1.AW7 CPU1.AW8 CPU1.AW9 CPU1.AW10 CPU1.AW24 CPU1.AW25 CPU1.AW26 CPU1.AW27 CPU1.AY24 CPU1.AY26 CPU1.BA5 CPU1.BA7 CPU1.BA8 CPU1.BA25 CPU1.BA27 CPU1.BB2 CPU1.BB26 CPU1.BC5 CPU1.BC6 CPU1.BC7 CPU1.BC9 CPU1.BC10 CPU1.BC26 CPU1.BC27 CPU1.BD5 CPU1.BD8 CPU1.BD10 CPU1.BD25 CPU1.BD27 CPU1.BE9 CPU1.BE24 CPU1.BE25 CPU1.BE26 CPU1.BE27 CPU1.BF2 CPU1.BF9 CPU1.BF24 CPU1.BF26 CPU1.BG27 EC8902.1 EC8903.1 EC8904.1 EC8937.1 EC8938.1 PC1002.1 PC1003.1 PC1004.1 PC1005.1 PC1006.1 PC1007.1 PC1008.1 PC1009.1 PC1010.1 PC1011.1 PC1012.1 PC1013.1 PC1014.1 PC1015.1 PC1016.1 PC1017.1 PC1018.1 PC1019.1 PC1020.1 PC1021.1 PC1022.1 PC1023.1 PC1024.1 PC1025.1 PC1026.1 PC1027.1 PC1028.1 PC1029.1 PC1030.1 PC1031.1 PC1032.1 PC1034.1 PC1036.1 PC1079.1 PC1080.1 PC1081.1 PC1082.1 PC1083.1 PC1084.1 PG4809.2 PG4815.2 PL4801.2 PL4802.2 PR4631.2 PT4801.1 PT4803.1 R719.1 R811.1 R813.1 R814.1
1V_GT_CORE: CPU1.AA9 CPU1.AB2 CPU1.AB8 CPU1.AB9 CPU1.AB10 CPU1.AC8 CPU1.AD9 CPU1.AE8 CPU1.AE9 CPU1.AE10 CPU1.AF2 CPU1.AF8 CPU1.AF10 CPU1.AG8 CPU1.AG9 CPU1.AH9 CPU1.AJ8 CPU1.AJ10 CPU1.AK2 CPU1.AK9 CPU1.AL8 CPU1.AL9 CPU1.AL10 CPU1.AM8 CPU1.V2 CPU1.Y8 CPU1.Y10 R811.2 R812.1 R813.2 R814.2 R815.1
1V_VCCGT: C1102.1 C1103.1 C1104.1 C1105.1 C1106.1 C1107.1 CPU1.A5 CPU1.A6 CPU1.A8 CPU1.A11 CPU1.A12 CPU1.A14 CPU1.A15 CPU1.A17 CPU1.A18 CPU1.A20 CPU1.B3 CPU1.B4 CPU1.B6 CPU1.B8 CPU1.B11 CPU1.B14 CPU1.B17 CPU1.B20 CPU1.C2 CPU1.C3 CPU1.C6 CPU1.C7 CPU1.C8 CPU1.C11 CPU1.C12 CPU1.C14 CPU1.C15 CPU1.C17 CPU1.C18 CPU1.C20 CPU1.D4 CPU1.D7 CPU1.D11 CPU1.D12 CPU1.D14 CPU1.D15 CPU1.D17 CPU1.D18 CPU1.D20 CPU1.E4 CPU1.F5 CPU1.F6 CPU1.F7 CPU1.F8 CPU1.F11 CPU1.F14 CPU1.F17 CPU1.F20 CPU1.G11 CPU1.G12 CPU1.G14 CPU1.G15 CPU1.G17 CPU1.G18 CPU1.G20 CPU1.H5 CPU1.H6 CPU1.H7 CPU1.H8 CPU1.H11 CPU1.H12 CPU1.H14 CPU1.H15 CPU1.H17 CPU1.H18 CPU1.H20 CPU1.J7 CPU1.J8 CPU1.J11 CPU1.J14 CPU1.J17 CPU1.J20 CPU1.K2 CPU1.K11 CPU1.L7 CPU1.L8 CPU1.L10 CPU1.M9 CPU1.N7 CPU1.N8 CPU1.N9 CPU1.N10 CPU1.P2 CPU1.P8 CPU1.R9 CPU1.T8 CPU1.T9 CPU1.T10 CPU1.U8 CPU1.U10 CPU1.V9 CPU1.W8 CPU1.W9 EC4701.1 EC8905.1 EC8906.1 PC1001.1 PC1037.1 PC1038.1 PC1039.1 PC1040.1 PC1041.1 PC1042.1 PC1043.1 PC1044.1 PC1045.1 PC1046.1 PC1047.1 PC1048.1 PC1049.1 PC1050.1 PC1051.1 PC1052.1 PC1053.1 PC1054.1 PC1055.1 PC1056.1 PC1057.1 PC1058.1 PC1059.1 PC1060.1 PC1061.1 PC1062.1 PC1063.1 PC1064.1 PC1065.1 PC1066.1 PC1067.1 PC1068.1 PC1069.1 PC1070.1 PG4708.2 PL4701.2 PR4663.1 PT4701.1 R807.1 R812.2 R815.2
1V_VCCIO: C1108.1 C1109.1 C1110.1 C1111.1 C1133.1 C1134.1 C1135.1 CPU1.AK24 CPU1.AK26 CPU1.AL24 CPU1.AL25 CPU1.AL26 CPU1.AL27 CPU1.AM25 CPU1.AM27 CPU1.BH24 CPU1.BH25 CPU1.BH26 CPU1.BH27 CPU1.BJ24 CPU1.BJ26 CPU1.BP16 CPU1.BP18 R401.1 R4045.2
1V_VCCIO_R: C4010.1 R4043.1 R4045.1 U4003.6 U4003.7 U4003.8
1V_VCCSA: CPU1.BG8 CPU1.BG10 CPU1.BH9 CPU1.BJ8 CPU1.BJ9 CPU1.BJ10 CPU1.BK8 CPU1.BK25 CPU1.BK27 CPU1.BL8 CPU1.BL9 CPU1.BL10 CPU1.BL24 CPU1.BL26 CPU1.BM24 CPU1.BN25 EC5001.1 EC8901.1 EC8907.1 PC1071.1 PC1072.1 PC1073.1 PC1074.1 PC1075.1 PC1076.1 PC1077.1 PC1078.1 PG5001.2 PL5001.2 R810.1
1V_VCCST_CPU: C801.1 C805.2 C806.2 CPU1.BP2 CPU1.BP11 CPU1.BR11 CPU1.BT11 PC4602.1 PR4603.1 PR4604.1 PR4605.1 PR4606.1 R308.1 R723.1 R726.1 R727.1 R4036.2
1V_VCCST_CPU_R: C4012.1 R4036.1 U4006.6 U4006.7 U4006.8
1V_VCCSTG: C802.1 CPU1.BG1 CPU1.BG2 CPU1.BG3 R301.1 R310.2 R4043.2
1V_VREF_CPU: C2406.1 R2402.2 U2401.95
3V5V_CT1: C4001.1 U4001.12
3V5V_CT2: C4002.1 U4001.10
3V5V_S0_ON: C4003.2 R4010.2 U4001.3 U4001.5
3V_5V_DSW_OK: D2503.3 PR5210.1 PR5406.1 R2513.2 R2514.2 U2502.4
3V_5V_EN: C4009.1 D4001.A PR4515.1 PR4516.1 R4006.1 R4009.1 R4014.1
3V_5V_POK#: Q1701.5 Q1701.6 R1726.1
3V_5V_POK_C: Q1701.2 R1727.2 R1728.1
3V_5V_PWRGD: C1710.1 D2503.1 ED1703.1 PG4529.1 PG4531.1 R1728.2 R2513.1 R4033.1
3V_S5_EN: PC4532.1 PR4514.1 PR4516.2 PU4501.12
5V_AUX_S5: PG4528.2 PR4510.2
5V_FAN_VCC: AFTP2603.1 C2603.1 C2604.1 C2605.1 D2601.K FAN1.1 R2612.2
5V_HDMI_S0: C5736.2 F5701.2 HDMI1.18
5V_KB_BL: AFTP6529.1 C6501.1 C6506.1 F6501.2 KBBL1.1
5V_S0: C4004.1 C5535.1 D5701.3 EC5505.2 F5701.1 F6501.1 R2612.1 R2705.2 R2707.1 R2712.1 R6510.1 U4001.8 U4001.9 U5503.1 U5503.3
5V_S5: AFTP6608.1 C4031.1 C4032.1 C4043.1 C5743.1 C7204.1 C7205.1 C7206.1 CN6601.23 CN6601.24 CN6601.25 EC8918.1 EC8919.1 EC8920.1 EC8927.1 EC8928.1 EC8929.1 FC8925.1 FC8926.1 FC8927.1 FC8928.1 FC8929.1 FC8930.1 FC8931.1 FC8932.1 FC8933.1 FC8934.1 PC4766.1 PC4866.1 PC4877.1 PC5001.1 PC5112.1 PC5202.1 PC5401.1 PC5410.1 PG4510.2 PG4511.2 PG4512.2 PG4513.2 PG4522.2 PG4523.2 PG4524.2 PG4525.2 PR4610.1 PR4635.2 PR4704.2 PR4803.2 PR4813.2 PR5108.1 PU4701.29 PU4801.29 PU4802.29 PU5001.6 PU5201.21 PU5401.6 PU5403.6 Q6401.E Q6402.E Q6505.E R4303.1 U4001.4 U4001.6 U4001.7 U4002.3 U4003.3 U4006.3 U5801.6 U7201.A11 U7201.B11 U7201.C11 U7201.D11 U7201.H10
5V_S5_EN: PC4531.1 PR4504.2 PR4513.1 PU4502.12
19V_AD+: C4303.1 C4304.1 C4305.1 C4306.1 PD4401.1 PD4408.1 PR4473.1 PU4301.5 PU4301.6 PU4301.7 PU4301.8 PU4302.5 PU4302.6 PU4302.7 PU4302.8 R4311.1 R4316.1
19V_AD_JK: C4301.1 C4302.1 EL4301.2 EL4302.2 PU4301.1 PU4301.2 PU4301.3 Q4305.2 R4307.1 R4376.1
19V_DCBATOUT: PC4402.1 PC4403.1 PC4404.1 PC4405.1 PG4402.1 PR4401.2 PU4403.5 PU4403.6 PU4403.7 PU4403.8
19V_DCBATOUT_LCD: C5512.1 C5513.1 C5514.1 F5503.1 LCD1.1 LCD1.2 LCD1.3 LCD1.4
20V_VCCPD_VBUS: C7302.1 C7303.1 C7304.1 C7305.1 C7306.1 C7307.1 D7301.K ER7301.2 ER7302.2 R7423.1 R7425.1 R7426.1 U7419.B2 U7419.C2 U7419.D2 U7419.E1 U7419.E2 USB1.A4 USB1.A9 USB1.B4 USB1.B9
20V_VCCPD_VBUS_L: C7301.1 ER7301.1 ER7302.1 R7216.1 R7217.1 U7201.H11 U7201.J10 U7201.J11 U7201.K11
+5V_AVDD: C2721.1 C2727.1 R2705.1 U2701.40
+5V_PVDD: C2714.1 C2732.1 C2733.1 C2742.1 R2707.2 R2712.2 U2701.41 U2701.46
DVSS: R2746.2 U2701.13
GND: AFTP2507.1 AFTP2604.1 AFTP4306.1 AFTP4307.1 AFTP4308.1 AFTP6525.1 BATT1.8 BATT1.9 BATT1.10 BIOS1.4 C501.2 C801.2 C802.2 C803.1 C804.2 C805.1 C806.1 C1102.2 C1103.2 C1104.2 C1105.2 C1106.2 C1107.2 C1108.2 C1109.2 C1110.2 C1111.2 C1112.2 C1113.2 C1114.2 C1115.2 C1116.2 C1117.2 C1118.2 C1119.2 C1120.2 C1121.2 C1122.2 C1123.2 C1128.2 C1129.2 C1130.2 C1131.2 C1132.2 C1133.2 C1134.2 C1135.2 C1136.2 C1137.2 C1138.2 C1139.2 C1140.2 C1141.2 C1142.2 C1201.2 C1203.2 C1204.2 C1205.2 C1206.2 C1207.2 C1208.2 C1209.2 C1210.2 C1211.2 C1212.2 C1213.2 C1214.2 C1215.2 C1216.2 C1217.2 C1218.2 C1219.2 C1220.2 C1221.2 C1222.2 C1223.2 C1224.2 C1225.2 C1226.2 C1227.2 C1228.2 C1229.2 C1230.2 C1231.2 C1232.2 C1233.2 C1234.2 C1235.2 C1236.2 C1237.2 C1238.2 C1239.2 C1240.2 C1241.2 C1242.2 C1243.2 C1244.2 C1245.2 C1246.2 C1255.2 C1257.2 C1258.2 C1259.2 C1260.2 C1261.2 C1262.2 C1263.2 C1264.2 C1265.2 C1266.2 C1267.2 C1268.2 C1269.2 C1270.2 C1271.2 C1272.2 C1273.2 C1274.2 C1275.2 C1276.2 C1277.2 C1278.2 C1279.2 C1280.2 C1281.2 C1282.2 C1283.2 C1284.2 C1286.2 C1288.2 C1289.2 C1290.2 C1291.2 C1292.2 C1293.2 C1294.2 C1295.2 C1296.2 C1297.2 C1298.2 C1299.2 C1301.2 C1303.2 C1304.2 C1305.2 C1306.2 C1307.2 C1308.2 C1309.2 C1310.2 C1311.2 C1312.2 C1313.2 C1314.2 C1315.2 C1316.2 C1317.2 C1318.2 C1319.2 C1320.2 C1321.2 C1322.2 C1323.2 C1324.2 C1325.2 C1326.2 C1327.2 C1328.2 C1329.2 C1330.2 C1331.2 C1332.2 C1333.2 C1334.2 C1335.2 C1336.2 C1337.2 C1338.2 C1339.2 C1340.2 C1341.2 C1342.2 C1343.2 C1344.2 C1345.2 C1346.2 C1347.2 C1348.2 C1349.2 C1350.2 C1351.2 C1352.2 C1353.2 C1354.2 C1355.2 C1356.2 C1357.2 C1358.2 C1359.2 C1360.2 C1361.2 C1362.2 C1363.2 C1364.2 C1365.2 C1366.2 C1367.2 C1368.2 C1369.2 C1371.2 C1372.2 C1373.2 C1374.2 C1375.2 C1376.2 C1377.2 C1378.2 C1379.2 C1390.2 C1391.2 C1392.2 C1393.2 C1394.2 C1395.2 C1396.2 C1397.2 C1398.2 C1399.2 C1701.2 C1710.2 C1711.2 C1803.2 C1804.1 C1805.2 C1806.2 C1807.1 C1808.1 C2201.2 C2202.2 C2203.2 C2204.2 C2205.2 C2206.2 C2207.2 C2208.2 C2209.2 C2210.2 C2211.2 C2212.2 C2213.2 C2214.2 C2215.2 C2216.2 C2217.2 C2218.2 C2219.2 C2220.2 C2221.2 C2222.2 C2223.2 C2224.2 C2405.2 C2406.2 C2409.2 C2410.2 C2411.2 C2412.2 C2413.2 C2414.2 C2416.2 C2418.2 C2420.2 C2421.2 C2423.2 C2424.2 C2425.2 C2427.2 C2428.2 C2429.2 C2436.2 C2501.2 C2502.2 C2503.2 C2517.2 C2525.2 C2601.2 C2602.2 C2603.2 C2604.2 C2605.2 C2608.2 C2609.2 C2610.2 C2614.2 C2714.2 C2722.2 C2729.1 C2732.2 C2733.2 C2736.2 C2742.2 C2743.2 C2744.2 C2745.2 C2746.2 C4001.2 C4002.2 C4003.1 C4004.2 C4005.2 C4006.2 C4007.2 C4008.2 C4009.2 C4010.2 C4012.2 C4013.2 C4031.2 C4032.2 C4034.2 C4035.2 C4037.2 C4039.2 C4040.2 C4041.2 C4042.2 C4043.2 C4302.2 C4303.2 C4304.2 C4305.2 C4306.2 C4344.2 C5502.2 C5503.2 C5507.1 C5508.1 C5512.2 C5513.2 C5514.2 C5515.2 C5516.2 C5517.2 C5518.2 C5521.2 C5535.2 C5726.1 C5729.2 C5730.2 C5736.1 C5742.2 C5743.2 C5744.2 C5746.2 C5747.2 C5748.2 C5749.2 C5750.2 C5751.2 C5752.2 C5753.2 C5754.2 C5755.2 C5756.2 C5757.2 C5758.2 C5759.2 C5760.2 C5761.2 C5762.2 C5763.2 C5764.2 C5765.2 C5766.2 C5767.2 C5768.2 C5769.2 C5770.2 C5771.2 C5772.2 C5773.2 C5774.2 C5775.2 C5776.2 C5777.1 C5778.2 C6101.2 C6103.2 C6104.2 C6105.2 C6106.2 C6304.2 C6305.2 C6306.2 C6307.2 C6308.2 C6309.2 C6310.2 C6317.2 C6318.2 C6319.2 C6320.2 C6321.2 C6322.2 C6323.2 C6401.2 C6501.2 C6504.2 C6505.2 C6506.2 C6605.2 C7115.1 C7116.1 C7117.1 C7118.1 C7119.2 C7201.1 C7202.1 C7203.1 C7204.2 C7205.2 C7206.2 C7208.2 C7210.2 C7211.2 C7212.1 C7217.2 C7218.2 C7244.2 C7301.2 C7302.2 C7303.2 C7304.2 C7305.2 C7306.2 C7307.2 C9106.2 C9108.2 C9109.2 C9112.1 C9113.2 C9201.2 CN6601.29 CN6601.32 CN6601.35 CN6601.38 CN6601.41 CN6601.42 CN6601.43 CN6601.44 CPU1.A3 CPU1.A4 CPU1.A32 CPU1.A36 CPU1.AB3 CPU1.AB4 CPU1.AB7 CPU1.AB27 CPU1.AB30 CPU1.AB33 CPU1.AB36 CPU1.AC5 CPU1.AC10 CPU1.AC27 CPU1.AC30 CPU1.AD33 CPU1.AD35 CPU1.AE7 CPU1.AE24 CPU1.AE25 CPU1.AE26 CPU1.AE27 CPU1.AE30 CPU1.AF3 CPU1.AF4 CPU1.AF7 CPU1.AF25 CPU1.AF27 CPU1.AF30 CPU1.AF33 CPU1.AF36 CPU1.AG5 CPU1.AG10 CPU1.AG24 CPU1.AG26 CPU1.AH24 CPU1.AH25 CPU1.AH27 CPU1.AH28 CPU1.AH29 CPU1.AH30 CPU1.AH31 CPU1.AH33 CPU1.AH35 CPU1.AJ7 CPU1.AJ25 CPU1.AJ28 CPU1.AK3 CPU1.AK4 CPU1.AK33 CPU1.AK36 CPU1.AL7 CPU1.AL28 CPU1.AL29 CPU1.AL32 CPU1.AM5 CPU1.AM10 CPU1.AM28 CPU1.AM33 CPU1.AM35 CPU1.AN7 CPU1.AN8 CPU1.AN25 CPU1.AN28 CPU1.AN29 CPU1.AN30 CPU1.AN31 CPU1.AP3 CPU1.AP4 CPU1.AP33 CPU1.AP36 CPU1.AR4 CPU1.AR28 CPU1.AT4 CPU1.AT33 CPU1.AT35 CPU1.AT36 CPU1.AU4 CPU1.AU10 CPU1.AU28 CPU1.AU29 CPU1.AU32 CPU1.AV3 CPU1.AV4 CPU1.AV6 CPU1.AV8 CPU1.AV25 CPU1.AV28 CPU1.AV33 CPU1.AV36 CPU1.AW1 CPU1.AW3 CPU1.AW4 CPU1.AW28 CPU1.AW29 CPU1.AW30 CPU1.AW31 CPU1.AY4 CPU1.AY33 CPU1.AY35 CPU1.B2 CPU1.B5 CPU1.B7 CPU1.B9 CPU1.B12 CPU1.B15 CPU1.B18 CPU1.B21 CPU1.B23 CPU1.B25 CPU1.B27 CPU1.B29 CPU1.B31 CPU1.B34 CPU1.B36 CPU1.B37 CPU1.BA3 CPU1.BA4 CPU1.BA6 CPU1.BA10 CPU1.BA28 CPU1.BB3 CPU1.BB4 CPU1.BB33 CPU1.BB36 CPU1.BC4 CPU1.BC8 CPU1.BC25 CPU1.BC29 CPU1.BC32 CPU1.BD4 CPU1.BD6 CPU1.BD7 CPU1.BD28 CPU1.BD33 CPU1.BD35 CPU1.BD36 CPU1.BE3 CPU1.BE4 CPU1.BE8 CPU1.BE10 CPU1.BE28 CPU1.BE29 CPU1.BE30 CPU1.BE31 CPU1.BF3 CPU1.BF4 CPU1.BF33 CPU1.BF36 CPU1.BG4 CPU1.BG25 CPU1.BG28 CPU1.BH28 CPU1.BH29 CPU1.BH32 CPU1.BH33 CPU1.BH35 CPU1.BJ7 CPU1.BK2 CPU1.BK3 CPU1.BK4 CPU1.BK7 CPU1.BK10 CPU1.BK28 CPU1.BK33 CPU1.BL7 CPU1.BL25 CPU1.BL28 CPU1.BL29 CPU1.BL30 CPU1.BL31 CPU1.BL32 CPU1.BM9 CPU1.BM33 CPU1.BM35 CPU1.BM36 CPU1.BN7 CPU1.BN30 CPU1.BP3 CPU1.BP4 CPU1.BP7 CPU1.BP12 CPU1.BP15 CPU1.BP19 CPU1.BP25 CPU1.BP32 CPU1.BP33 CPU1.BP36 CPU1.BR16 CPU1.BR19 CPU1.BR22 CPU1.BR25 CPU1.BT5 CPU1.BT14 CPU1.BT15 CPU1.BT16 CPU1.BT25 CPU1.BT28 CPU1.BT33 CPU1.BT35 CPU1.BT36 CPU1.BU7 CPU1.BU11 CPU1.BU16 CPU1.BU20 CPU1.BU23 CPU1.BU24 CPU1.BU25 CPU1.BV3 CPU1.BV4 CPU1.BV11 CPU1.BV31 CPU1.BV33 CPU1.BW7 CPU1.BW11 CPU1.BW15 CPU1.BW24 CPU1.BY5 CPU1.BY11 CPU1.BY15 CPU1.BY18 CPU1.BY19 CPU1.BY22 CPU1.BY25 CPU1.BY28 CPU1.BY33 CPU1.BY35 CPU1.BY36 CPU1.C1 CPU1.C4 CPU1.C9 CPU1.C21 CPU1.C25 CPU1.C29 CPU1.C33 CPU1.C36 CPU1.C37 CPU1.CA11 CPU1.CA15 CPU1.CA22 CPU1.CA25 CPU1.CB2 CPU1.CB3 CPU1.CB4 CPU1.CB7 CPU1.CB11 CPU1.CB18 CPU1.CB19 CPU1.CB20 CPU1.CB24 CPU1.CB25 CPU1.CB33 CPU1.CC7 CPU1.CC11 CPU1.CC14 CPU1.CC16 CPU1.CC20 CPU1.CC24 CPU1.CC25 CPU1.CC28 CPU1.CC31 CPU1.CD11 CPU1.CD12 CPU1.CD14 CPU1.CD20 CPU1.CD24 CPU1.CD25 CPU1.CE7 CPU1.CE33 CPU1.CE35 CPU1.CE36 CPU1.CF2 CPU1.CF3 CPU1.CF4 CPU1.CF11 CPU1.CF14 CPU1.CF19 CPU1.CF23 CPU1.CF28 CPU1.CG7 CPU1.CG33 CPU1.CH31 CPU1.CJ2 CPU1.CJ3 CPU1.CJ4 CPU1.CJ11 CPU1.CJ14 CPU1.CJ19 CPU1.CJ23 CPU1.CJ28 CPU1.CJ33 CPU1.CJ35 CPU1.CJ36 CPU1.CK1 CPU1.CK4 CPU1.CK7 CPU1.CK37 CPU1.CL2 CPU1.CM1 CPU1.CM4 CPU1.CM5 CPU1.CM9 CPU1.CM13 CPU1.CM17 CPU1.CM21 CPU1.CM25 CPU1.CM29 CPU1.CM31 CPU1.CM33 CPU1.CM37 CPU1.CN1 CPU1.CN2 CPU1.CN5 CPU1.CN9 CPU1.CN13 CPU1.CN17 CPU1.CN21 CPU1.CN25 CPU1.CN29 CPU1.CN37 CPU1.CP1 CPU1.CP2 CPU1.CP9 CPU1.CP11 CPU1.CP13 CPU1.CP15 CPU1.CP19 CPU1.CP21 CPU1.CP27 CPU1.CP35 CPU1.CP37 CPU1.CR2 CPU1.CR6 CPU1.CR34 CPU1.CR36 CPU1.D1 CPU1.D5 CPU1.D6 CPU1.D8 CPU1.D9 CPU1.D21 CPU1.D25 CPU1.E9 CPU1.E23 CPU1.E27 CPU1.E29 CPU1.E31 CPU1.E33 CPU1.E35 CPU1.F2 CPU1.F3 CPU1.F4 CPU1.F12 CPU1.F15 CPU1.F18 CPU1.F21 CPU1.F24 CPU1.F33 CPU1.G9 CPU1.G21 CPU1.G27 CPU1.G33 CPU1.G35 CPU1.G36 CPU1.H9 CPU1.H21 CPU1.H27 CPU1.J5 CPU1.J6 CPU1.J12 CPU1.J15 CPU1.J18 CPU1.J21 CPU1.J24 CPU1.J33 CPU1.J36 CPU1.K3 CPU1.K4 CPU1.K9 CPU1.K21 CPU1.K22 CPU1.K24 CPU1.K25 CPU1.K27 CPU1.K28 CPU1.K29 CPU1.K30 CPU1.K31 CPU1.K32 CPU1.L6 CPU1.L27 CPU1.L33 CPU1.L35 CPU1.L36 CPU1.N6 CPU1.N25 CPU1.N27 CPU1.P3 CPU1.P4 CPU1.P7 CPU1.P10 CPU1.P33 CPU1.P36 CPU1.R27 CPU1.R28 CPU1.R29 CPU1.R30 CPU1.R31 CPU1.T7 CPU1.T27 CPU1.T30 CPU1.T33 CPU1.T35 CPU1.T36 CPU1.U7 CPU1.U24 CPU1.U26 CPU1.V3 CPU1.V4 CPU1.V26 CPU1.V27 CPU1.V30 CPU1.V33 CPU1.V36 CPU1.W7 CPU1.W10 CPU1.W27 CPU1.W30 CPU1.Y7 CPU1.Y26 CPU1.Y27 CPU1.Y30 CPU1.Y33 CPU1.Y35 D2601.A D4301.A D4302.1 D4303.3 D4304.A D7301.A DB1.3 DB1.15 DB1.16 DB3.4 DB3.7 DB3.8 DCIN1.9 DCIN1.10 EC1706.2 EC1707.2 EC1712.2 EC1801.2 EC1803.1 EC1804.2 EC1901.1 EC1903.2 EC2201.2 EC2402.2 EC2403.2 EC2501.2 EC2502.2 EC2503.2 EC2601.2 EC2602.2 EC2709.2 EC2710.2 EC2711.2 EC2712.2 EC2713.2 EC2714.2 EC2901.2 EC2902.2 EC2903.2 EC2904.2 EC4306.2 EC4307.2 EC4308.2 EC4309.2 EC4310.2 EC4311.2 EC4534.2 EC4701.2 EC5001.2 EC5501.2 EC5503.2 EC5504.2 EC5505.1 EC5506.2 EC6501.2 EC6502.2 EC6503.2 EC6504.2 EC8901.2 EC8902.2 EC8903.2 EC8904.2 EC8905.2 EC8906.2 EC8907.2 EC8908.2 EC8909.2 EC8910.2 EC8911.2 EC8912.2 EC8913.2 EC8914.2 EC8915.2 EC8916.2 EC8917.2 EC8918.2 EC8919.2 EC8920.2 EC8921.2 EC8922.2 EC8923.2 EC8924.2 EC8925.2 EC8926.2 EC8927.2 EC8928.2 EC8929.2 EC8930.2 EC8931.2 EC8932.2 EC8933.2 EC8934.2 EC8937.2 EC8938.2 EC8939.2 EC8940.2 EC8941.2 EC8942.2 EC8943.2 EC8944.2 EC8945.2 EC8946.2 EC8947.2 EC8948.2 EC8949.2 EC8950.2 ED301.3 ED1701.3 ED1702.3 ED1703.3 ED1704.3 ED1801.3 ED2403.3 ED4304.1 ED4305.1 ED4306.1 ED5501.2 ED5502.3 ED5701.3 ED5701.8 ED5702.3 ED5702.8 ED5703.3 ED5703.8 ED6301.3 ED6301.8 ED6302.3 ED6302.8 ED6401.3 ED7301.3 ED7301.8 ED7302.3 ED7302.8 ED7303.3 ED7303.8 ED7305.3 ED7306.3 ED9202.3 EL4303.2 EL4304.2 FAN1.2 FAN1.5 FAN1.6 FC1102.2 FC1103.2 FC1801.1 FC2738.1 FC5501.2 FC5502.2 FC5505.2 FC5701.2 FC5702.2 FC5703.2 FC5704.2 FC6101.2 FC8905.2 FC8906.2 FC8907.2 FC8908.2 FC8909.2 FC8910.2 FC8911.2 FC8912.2 FC8913.2 FC8914.2 FC8915.2 FC8916.2 FC8917.2 FC8918.2 FC8919.2 FC8920.2 FC8921.2 FC8922.2 FC8923.2 FC8924.2 FC8925.2 FC8926.2 FC8927.2 FC8928.2 FC8929.2 FC8930.2 FC8931.2 FC8932.2 FC8933.2 FC8934.2 FC8935.2 FC8936.2 FC8937.2 FC8938.2 FC8939.2 FC8940.2 FC8941.2 FC8942.2 FC8943.2 FC8944.2 FC8945.2 FC8946.2 FC8947.2 FC8948.2 FC8949.2 FC8950.2 FC8951.2 FC8952.2 FC8953.2 FC8954.2 FP1.5 FP1.8 FP1.9 FP1.10 FSW1.4 FSW1.5 FSW1.6 FSW1.7 G1801.1 H1.1 H2.1 H3.1 H4.1 H5.1 H6.1 H7.1 H8.1 H9.1 H10.1 H12.1 H13.1 HDMI1.2 HDMI1.5 HDMI1.8 HDMI1.11 HDMI1.17 HDMI1.20 HDMI1.21 HDMI1.22 HDMI1.23 KB1.1 KB1.31 KB1.32 KBBL1.5 KBBL1.6 LCD1.12 LCD1.15 LCD1.18 LCD1.24 LCD1.25 LCD1.26 LCD1.27 LCD1.28 LCD1.42 LCD1.45 LCD1.51 LCD1.52 LCD1.53 LCD1.54 LED1.3 PC1001.2 PC1002.2 PC1003.2 PC1004.2 PC1005.2 PC1006.2 PC1007.2 PC1008.2 PC1009.2 PC1010.2 PC1011.2 PC1012.2 PC1013.2 PC1014.2 PC1015.2 PC1016.2 PC1017.2 PC1018.2 PC1019.2 PC1020.2 PC1021.2 PC1022.2 PC1023.2 PC1024.2 PC1025.2 PC1026.2 PC1027.2 PC1028.2 PC1029.2 PC1030.2 PC1031.2 PC1032.2 PC1034.2 PC1036.2 PC1037.2 PC1038.2 PC1039.2 PC1040.2 PC1041.2 PC1042.2 PC1043.2 PC1044.2 PC1045.2 PC1046.2 PC1047.2 PC1048.2 PC1049.2 PC1050.2 PC1051.2 PC1052.2 PC1053.2 PC1054.2 PC1055.2 PC1056.2 PC1057.2 PC1058.2 PC1059.2 PC1060.2 PC1061.2 PC1062.2 PC1063.2 PC1064.2 PC1065.2 PC1066.2 PC1067.2 PC1068.2 PC1069.2 PC1070.2 PC1071.2 PC1072.2 PC1073.2 PC1074.2 PC1075.2 PC1076.2 PC1077.2 PC1078.2 PC1079.2 PC1080.2 PC1081.2 PC1082.2 PC1083.2 PC1084.2 PC4401.2 PC4402.2 PC4403.2 PC4404.2 PC4405.2 PC4406.2 PC4407.2 PC4408.2 PC4409.2 PC4410.2 PC4411.2 PC4412.2 PC4413.2 PC4414.2 PC4416.1 PC4417.1 PC4418.2 PC4419.2 PC4420.1 PC4421.2 PC4422.2 PC4424.1 PC4426.1 PC4427.2 PC4428.2 PC4429.2 PC4430.2 PC4431.2 PC4432.2 PC4433.2 PC4434.2 PC4435.2 PC4437.2 PC4439.1 PC4440.1 PC4501.2 PC4502.2 PC4503.2 PC4504.2 PC4505.2 PC4507.2 PC4508.2 PC4509.2 PC4510.2 PC4511.2 PC4512.2 PC4513.2 PC4514.2 PC4515.2 PC4516.2 PC4517.2 PC4518.2 PC4519.2 PC4520.2 PC4522.2 PC4523.2 PC4524.2 PC4525.2 PC4527.2 PC4528.2 PC4529.2 PC4530.2 PC4531.2 PC4532.2 PC4542.2 PC4543.2 PC4601.2 PC4602.2 PC4603.1 PC4604.1 PC4606.2 PC4607.2 PC4610.1 PC4612.2 PC4613.2 PC4614.2 PC4615.1 PC4620.2 PC4621.1 PC4622.2 PC4624.2 PC4629.1 PC4631.2 PC4633.2 PC4637.2 PC4638.2 PC4639.2 PC4640.2 PC4641.2 PC4644.2 PC4651.2 PC4701.2 PC4702.2 PC4703.2 PC4704.2 PC4706.2 PC4708.2 PC4766.2 PC4802.2 PC4803.2 PC4804.2 PC4805.2 PC4809.2 PC4810.2 PC4812.2 PC4813.2 PC4814.2 PC4815.2 PC4816.2 PC4817.2 PC4866.2 PC4877.2 PC5001.2 PC5002.2 PC5003.2 PC5004.2 PC5104.2 PC5105.2 PC5107.2 PC5108.2 PC5109.2 PC5111.2 PC5112.2 PC5113.2 PC5115.2 PC5116.2 PC5117.2 PC5118.2 PC5122.2 PC5124.2 PC5201.2 PC5202.2 PC5203.2 PC5205.2 PC5206.2 PC5208.2 PC5209.2 PC5210.2 PC5211.2 PC5213.2 PC5214.2 PC5215.2 PC5216.2 PC5401.2 PC5402.2 PC5403.2 PC5404.2 PC5406.2 PC5410.2 PC5412.2 PC5413.2 PC5414.2 PC5427.2 PD5101.A PQ4405.1 PQ4405.4 PQ4415.1 PQ4415.4 PQ4416.1 PQ4416.4 PQ4417.S PQ4418.1 PQ4418.4 PR4406.2 PR4410.1 PR4413.2 PR4417.1 PR4426.2 PR4436.2 PR4474.1 PR4475.2 PR4487.1 PR4508.2 PR4512.2 PR4513.2 PR4514.2 PR4530.2 PR4551.2 PR4608.1 PR4614.2 PR4617.2 PR4621.1 PR4627.1 PR4628.2 PR4629.2 PR4639.2 PR4644.2 PR4654.2 PR4655.1 PR4659.1 PR4661.2 PR4712.2 PR4817.2 PR4818.2 PR5101.2 PR5114.2 PR5203.2 PR5204.2 PR5401.2 PR5404.2 PR5409.2 PR5420.2 PT4701.2 PT4801.2 PT4803.2 PT4805.2 PT4806.2 PT4807.2 PU4401.33 PU4404.1 PU4404.2 PU4404.3 PU4406.1 PU4406.2 PU4406.3 PU4501.7 PU4501.8 PU4501.18 PU4501.21 PU4502.7 PU4502.8 PU4502.18 PU4502.21 PU4601.41 PU4701.12 PU4701.13 PU4701.14 PU4701.15 PU4701.28 PU4701.32 PU4701.34 PU4801.12 PU4801.13 PU4801.14 PU4801.15 PU4801.28 PU4801.32 PU4801.34 PU4802.12 PU4802.13 PU4802.14 PU4802.15 PU4802.28 PU4802.32 PU4802.34 PU5001.4 PU5001.9 PU5003.1 PU5003.2 PU5003.3 PU5101.4 PU5101.11 PU5101.12 PU5101.13 PU5101.14 PU5101.15 PU5101.16 PU5101.30 PU5101.32 PU5101.33 PU5201.4 PU5201.12 PU5201.13 PU5201.14 PU5201.15 PU5201.19 PU5401.1 PU5403.1 Q401.1 Q401.4 Q501.S Q502.S Q1701.1 Q1701.4 Q1702.1 Q1702.4 Q1802.S Q2001.1 Q2001.4 Q2408.S Q2505.S Q2510.S Q4001.S Q4302.E Q4304.E Q4349.1 Q4349.4 Q5705.1 Q5705.4 Q6102.S Q6501.S Q6503.S Q7404.1 Q7404.4 Q7405.4 Q7406.1 Q7406.4 Q7407.1 Q7407.4 Q9202.S R304.2 R305.2 R317.2 R403.1 R407.1 R501.2 R502.2 R503.2 R601.2 R720.2 R808.2 R809.2 R1201.2 R1203.2 R1204.2 R1205.2 R1212.2 R1213.2 R1214.2 R1215.2 R1221.1 R1223.1 R1234.2 R1301.2 R1303.2 R1304.2 R1305.2 R1306.2 R1321.1 R1331.2 R1332.2 R1333.2 R1334.2 R1340.1 R1501.1 R1503.2 R1505.2 R1507.2 R1509.1 R1511.1 R1514.2 R1516.2 R1517.2 R1518.2 R1519.2 R1521.2 R1523.2 R1525.2 R1527.2 R1552.2 R1553.2 R1555.2 R1601.2 R1602.2 R1603.2 R1714.2 R1715.2 R1717.2 R1719.2 R1723.2 R1803.2 R1816.2 R1901.2 R1911.2 R2002.1 R2008.2 R2009.2 R2012.2 R2014.2 R2015.2 R2017.2 R2022.2 R2030.2 R2032.2 R2034.2 R2037.2 R2051.2 R2101.2 R2108.2 R2112.2 R2114.2 R2116.2 R2118.2 R2417.2 R2445.1 R2448.2 R2453.1 R2454.2 R2455.2 R2457.2 R2504.2 R2517.2 R2518.2 R2611.2 R2739.2 R2745.2 R2746.1 R4006.2 R4301.1 R4302.2 R4308.2 R4315.1 R4316.2 R4377.2 R4379.2 R5501.2 R5507.2 R5510.2 R5542.2 R5733.1 R5734.2 R5735.1 R5741.2 R5743.1 R5754.1 R5757.1 R5762.2 R5763.2 R5764.1 R5774.2 R6118.2 R6119.2 R6120.2 R6304.2 R6313.2 R6508.2 R6509.2 R7102.1 R7119.1 R7120.1 R7122.1 R7123.1 R7141.2 R7143.2 R7144.2 R7146.2 R7170.2 R7172.2 R7173.2 R7201.1 R7202.2 R7206.2 R7208.1 R7214.1 R7218.2 R7219.2 R7223.2 R7231.1 R7236.2 R7237.1 R7241.1 R7242.1 R7245.1 R7250.1 R7330.2 R7331.2 R7407.2 R7408.2 R7409.2 R7410.2 R7411.2 R7422.2 R7428.2 R9217.2 R9804.2 RAM1.A2 RAM1.A8 RAM1.B2 RAM1.C9 RAM1.D2 RAM1.D8 RAM1.E1 RAM1.E3 RAM1.E8 RAM1.F1 RAM1.G8 RAM1.H1 RAM1.H9 RAM1.K1 RAM1.K9 RAM1.N1 RAM1.T1 RAM2.A2 RAM2.A8 RAM2.B2 RAM2.C9 RAM2.D2 RAM2.D8 RAM2.E1 RAM2.E3 RAM2.E8 RAM2.F1 RAM2.G8 RAM2.H1 RAM2.H9 RAM2.K1 RAM2.K9 RAM2.N1 RAM2.T1 RAM3.A2 RAM3.A8 RAM3.B2 RAM3.C9 RAM3.D2 RAM3.D8 RAM3.E1 RAM3.E3 RAM3.E8 RAM3.F1 RAM3.G8 RAM3.H1 RAM3.H9 RAM3.K1 RAM3.K9 RAM3.N1 RAM3.T1 RAM4.A2 RAM4.A8 RAM4.B2 RAM4.C9 RAM4.D2 RAM4.D8 RAM4.E1 RAM4.E3 RAM4.E8 RAM4.F1 RAM4.G8 RAM4.H1 RAM4.H9 RAM4.K1 RAM4.K9 RAM4.N1 RAM4.T1 RAM5.A2 RAM5.A8 RAM5.B2 RAM5.C9 RAM5.D2 RAM5.D8 RAM5.E1 RAM5.E3 RAM5.E8 RAM5.F1 RAM5.G8 RAM5.H1 RAM5.H9 RAM5.K1 RAM5.K9 RAM5.N1 RAM5.T1 RAM6.A2 RAM6.A8 RAM6.B2 RAM6.C9 RAM6.D2 RAM6.D8 RAM6.E1 RAM6.E3 RAM6.E8 RAM6.F1 RAM6.G8 RAM6.H1 RAM6.H9 RAM6.K1 RAM6.K9 RAM6.N1 RAM6.T1 RAM7.A2 RAM7.A8 RAM7.B2 RAM7.C9 RAM7.D2 RAM7.D8 RAM7.E1 RAM7.E3 RAM7.E8 RAM7.F1 RAM7.G8 RAM7.H1 RAM7.H9 RAM7.K1 RAM7.K9 RAM7.N1 RAM7.T1 RAM8.A2 RAM8.A8 RAM8.B2 RAM8.C9 RAM8.D2 RAM8.D8 RAM8.E1 RAM8.E3 RAM8.E8 RAM8.F1 RAM8.G8 RAM8.H1 RAM8.H9 RAM8.K1 RAM8.K9 RAM8.N1 RAM8.T1 RN1703.1(A) RN1703.2(A) RN5502.1(A) RN5502.2(A) RN5502.3(A) RN5502.4(A) RN7202.3(B) RN7202.4(B) RN7207.2(A) RN7207.3(A) RN7207.4(A) RTC1.2 RTC1.3 RTC1.4 SPK1.5 SPK1.7 SPK1.8 SPR1.1 SPR2.1 SSD1.1 SSD1.3 SSD1.9 SSD1.15 SSD1.21 SSD1.27 SSD1.33 SSD1.39 SSD1.45 SSD1.51 SSD1.57 SSD1.71 SSD1.73 SSD1.75 SSD1.76 SSD1.77 SSD2.1 SSD2.3 SSD2.9 SSD2.15 SSD2.21 SSD2.27 SSD2.33 SSD2.39 SSD2.45 SSD2.51 SSD2.57 SSD2.71 SSD2.73 SSD2.75 SSD2.76 SSD2.77 TCBD1.9 TCBD1.10 TCBD1.11 TCBD1.12 TCBD1.21 TCBD1.22 TPAD1.5 TPAD1.9 TPAD1.10 U2401.17 U2401.51 U2401.64 U2401.84 U2401.100 U2401.124 U2502.2 U2601.5 U2701.49 U4001.11 U4001.15 U4002.5 U4003.5 U4006.5 U4008.3 U4302.3 U5501.2 U5503.2 U5701.B3 U5701.B6 U5701.D4 U5701.D5 U5701.E4 U5701.E5 U5701.G3 U5701.G6 U5702.4 U5703.3 U5801.1 U6402.3 U7101.41 U7201.A1 U7201.A6 U7201.A7 U7201.A8 U7201.B7 U7201.B8 U7201.D8 U7201.E5 U7201.E6 U7201.E7 U7201.E8 U7201.F5 U7201.F6 U7201.F7 U7201.F8 U7201.G5 U7201.G6 U7201.G7 U7201.G8 U7201.H4 U7201.H5 U7201.H8 U7201.L1 U7202.4 U7419.B3 U7419.C3 U7419.D3 U7419.E3 U9102.16 U9102.23 U9102.32 U9102.33 USB1.13 USB1.14 USB1.15 USB1.16 USB1.A1 USB1.A12 USB1.B1 USB1.B12 WLAN1.1 WLAN1.7 WLAN1.13 WLAN1.18 WLAN1.19 WLAN1.33 WLAN1.39 WLAN1.45 WLAN1.51 WLAN1.57 WLAN1.63 WLAN1.69 WLAN1.75 WLAN1.76 WLAN1.77 X1801.2 X1801.4 X5701.2 X5701.4
V0.85A_VID0: CPU1.CB36 TP2201.1
V0.85A_VID1: CPU1.CB35 TP2202.1
VBUS_P_CTRL: Q7404.2 U7201.D7
VBUS_P_CTRL_R: Q7404.5 Q7404.6 R7409.1 R7423.2
VCCCORE_SENSE: CPU1.AN6 PR4665.1 R719.2
VCCDSW_ON: C2525.1 D2503.2 R2520.2 U2401.88
VCCGT_SENSE: CPU1.E3 PR4667.1 R807.2
VCCPD_VBUS_ACK: PR4488.2 R7424.2 U7419.A2
VCCRTCEXT: C2201.1 CPU1.BP24
VCCSA_SENSE: CPU1.BG7 PR4601.2 R810.2
VCCST_PWRGD: D4002.A D4003.A ED1704.1 R1716.1 R2482.2 R4002.1 R4005.2 R4011.2
VCCST_PWRGD_R: C1711.1 CPU1.BJ2 ED1704.2 R1716.2 R1718.1 R1719.1
VCCSTG_EN_L1: R4018.2 R4039.1 U4008.4
VCCSTG_EN_R1: C4040.1 R4004.2 R4039.2 U4002.4 U4003.4
VCCSTU_EN_R: C4034.1 R4024.2 U4006.4
VDD: PC4422.1 PR4405.2 PR4427.1 PR4429.1 PU4401.18
VDDQ_PWRGD: PG5114.1 R4011.1
VSSCORE_SENSE: CPU1.AN5 PR4666.1 R720.1
VSSGT_SENSE: CPU1.D2 PR4668.1 R808.1
VSSSA_SENSE: CPU1.BE7 PR4602.2 R809.1
0D6V_VREF_S0: C1255.1 C1257.1 C1258.1 C1280.1 C1281.1 C1282.1 C1283.1 C1284.1 C1288.1 C1289.1 C1290.1 C1291.1 C1292.1 C1293.1 C1294.1 C1295.1 C1296.1 C1297.1 C1298.1 C1299.1 C1354.1 C1355.1 C1356.1 C1357.1 C1358.1 C1359.1 C1360.1 C1361.1 C1362.1 C1363.1 C1364.1 C1365.1 C1366.1 C1367.1 C1368.1 C1369.1 C1376.1 C1377.1 C1378.1 C1379.1 R1211.2 R1224.2 R1311.2 R1312.2 R5127.1 RN1202.5(B) RN1202.6(B) RN1202.7(B) RN1202.8(B) RN1203.5(B) RN1203.6(B) RN1203.7(B) RN1203.8(B) RN1204.5(B) RN1204.6(B) RN1204.7(B) RN1204.8(B) RN1205.5(B) RN1205.6(B) RN1205.7(B) RN1205.8(B) RN1206.5(B) RN1206.6(B) RN1206.7(B) RN1206.8(B) RN1207.5(B) RN1207.6(B) RN1207.7(B) RN1207.8(B) RN1302.5(B) RN1302.6(B) RN1302.7(B) RN1302.8(B) RN1303.5(B) RN1303.6(B) RN1303.7(B) RN1303.8(B) RN1304.5(B) RN1304.6(B) RN1304.7(B) RN1304.8(B) RN1305.5(B) RN1305.6(B) RN1305.7(B) RN1305.8(B) RN1306.5(B) RN1306.6(B) RN1306.7(B) RN1306.8(B) RN1307.5(B) RN1307.6(B) RN1307.7(B) RN1307.8(B)
1D0V_PWR: PC5201.1 PC5203.1 PC5205.1 PC5206.1 PC5208.1 PG5201.1 PG5202.1 PG5203.1 PG5204.1 PG5205.1 PG5206.1 PG5207.1 PG5208.1 PG5209.1 PG5211.1 PG5223.2 PL5201.2
1D0V_S5: C1112.1 C1114.1 C1115.1 C1116.1 C1117.1 C1118.1 C1119.1 C1120.1 C1121.1 C1128.1 C1129.1 C2212.1 C2214.1 C2215.1 C2216.1 C2217.1 C2223.1 C4008.1 C4013.1 C4041.1 C4042.1 CPU1.BP14 CPU1.BP20 CPU1.BP22 CPU1.BR12 CPU1.BR14 CPU1.BR15 CPU1.BR20 CPU1.BT12 CPU1.BT18 CPU1.BT19 CPU1.BT22 CPU1.BU12 CPU1.BU14 CPU1.BU15 CPU1.BU18 CPU1.BU19 CPU1.BU22 CPU1.BV15 CPU1.BV16 CPU1.BV18 CPU1.BV19 CPU1.BV20 CPU1.BV22 CPU1.BW16 CPU1.BW18 CPU1.BW19 CPU1.BW20 CPU1.BW22 CPU1.BY16 CPU1.BY20 CPU1.CA12 CPU1.CA14 CPU1.CA16 CPU1.CA18 CPU1.CA19 CPU1.CA20 CPU1.CB12 CPU1.CB14 CPU1.CB15 CPU1.CC12 EC2201.1 FC8945.1 PG5201.2 PG5202.2 PG5203.2 PG5204.2 PG5205.2 PG5206.2 PG5207.2 PG5208.2 PG5209.2 PG5211.2 R2202.1 R2203.1 R2205.1 R2402.1 U4003.1 U4003.2 U4003.9 U4006.1 U4006.2 U4006.9
1D0V_S5_EN: PC5215.1 PR5210.2 PU5201.2
1D0V_S5_PWRGD: PR5209.1 R4029.1
1D0V_VCCA_XTAL: C2219.1 CPU1.CP5 R2202.2
1D0V_VCCAMPHYPLL: C2208.1 C2209.1 CPU1.BV2 R2205.2
1D0V_VCCDSW: C2213.1 CPU1.BT24
1D0V_VCCPRIM_MPHY: C2220.1 CPU1.BV12 CPU1.BV14 CPU1.BW12 CPU1.BW14 CPU1.BY12 CPU1.BY14 R2203.2
1D2V_HDMI: C5753.1 C5759.1 C5763.1 C5771.1 FC5704.1 R5781.1 R5782.1 R5783.1 R5784.1 R5785.2
1D2V_HDMI_EN: R5801.1 U5701.G8
1D2V_HDMI_EN_R: C5744.1 FC5702.1 R5801.2 U5801.8
1D2V_HDMI_FB: C5745.2 FC5703.1 R5773.2 R5774.1 U5801.2
1D2V_HDMI_R: C5745.1 C5746.1 C5747.1 R5773.1 R5785.1 U5801.3 U5801.4
1D2V_HDMI_VDD: C5754.1 C5755.1 C5756.1 C5757.1 C5758.1 R5781.2 U5701.D6 U5701.F5
1D2V_HDMI_VDDA: C5760.1 C5761.1 C5762.1 R5782.2 U5701.F4
1D2V_HDMI_VDDRX: C5764.1 C5765.1 C5766.1 C5767.1 C5768.1 C5769.1 C5770.1 R5783.2 U5701.B4 U5701.B5 U5701.B7
1D2V_HDMI_VDDTX: C5772.1 C5773.1 C5774.1 C5775.1 C5776.1 R5784.2 U5701.G5 U5701.G7
1D2V_HDMI_VIN: C5742.1 G5701.2 U5801.5 U5801.9
1D2V_S3: C804.1 C1130.1 C1131.1 C1132.1 C1136.1 C1137.1 C1138.1 C1139.1 C1140.1 C1141.1 C1142.1 C1204.1 C1205.1 C1206.1 C1207.1 C1208.1 C1209.1 C1210.1 C1211.1 C1212.1 C1213.1 C1214.1 C1215.1 C1216.1 C1217.1 C1218.1 C1219.1 C1220.1 C1221.1 C1222.1 C1223.1 C1224.1 C1225.1 C1226.1 C1227.1 C1228.1 C1229.1 C1230.1 C1231.1 C1232.1 C1233.1 C1234.1 C1235.1 C1237.1 C1238.1 C1239.1 C1240.1 C1241.1 C1242.1 C1243.1 C1244.1 C1245.1 C1246.1 C1256.2 C1304.1 C1305.1 C1306.1 C1307.1 C1308.1 C1309.1 C1310.1 C1311.1 C1312.1 C1313.1 C1314.1 C1315.1 C1316.1 C1317.1 C1318.1 C1319.1 C1320.1 C1321.1 C1322.1 C1323.1 C1324.1 C1325.1 C1326.1 C1327.1 C1328.1 C1329.1 C1330.1 C1331.1 C1332.1 C1333.1 C1334.1 C1335.1 C1370.2 C1390.1 C1391.1 C1392.1 C1393.1 C1394.1 C1395.1 C1396.1 C1397.1 C1398.1 C1399.1 C4006.1 C4035.1 CPU1.AD36 CPU1.AH32 CPU1.AH36 CPU1.AM36 CPU1.AN32 CPU1.AW32 CPU1.AY36 CPU1.BE32 CPU1.BH36 CPU1.R32 CPU1.Y36 EC8930.1 EC8931.1 EC8932.1 EC8933.1 EC8934.1 EC8939.1 EC8940.1 EC8941.1 EC8942.1 FC1102.1 FC1103.1 PC5104.1 PC5105.1 PC5107.1 PC5109.1 PG5110.1 PG5113.2 PG5116.1 PL5101.2 R505.1 R1208.2 R1222.1 R1320.1 R1330.2 R4019.1 RAM1.A1 RAM1.A9 RAM1.B3 RAM1.B9 RAM1.C1 RAM1.D1 RAM1.D9 RAM1.E2 RAM1.E7 RAM1.F2 RAM1.F8 RAM1.G1 RAM1.G7 RAM1.G9 RAM1.J1 RAM1.J2 RAM1.J8 RAM1.J9 RAM1.L1 RAM1.L9 RAM1.R1 RAM1.T9 RAM2.A1 RAM2.A9 RAM2.B3 RAM2.B9 RAM2.C1 RAM2.D1 RAM2.D9 RAM2.E2 RAM2.E7 RAM2.F2 RAM2.F8 RAM2.G1 RAM2.G7 RAM2.G9 RAM2.J1 RAM2.J2 RAM2.J8 RAM2.J9 RAM2.L1 RAM2.L9 RAM2.R1 RAM2.T9 RAM3.A1 RAM3.A9 RAM3.B3 RAM3.B9 RAM3.C1 RAM3.D1 RAM3.D9 RAM3.E2 RAM3.E7 RAM3.F2 RAM3.F8 RAM3.G1 RAM3.G7 RAM3.G9 RAM3.J1 RAM3.J2 RAM3.J8 RAM3.J9 RAM3.L1 RAM3.L9 RAM3.R1 RAM3.T9 RAM4.A1 RAM4.A9 RAM4.B3 RAM4.B9 RAM4.C1 RAM4.D1 RAM4.D9 RAM4.E2 RAM4.E7 RAM4.F2 RAM4.F8 RAM4.G1 RAM4.G7 RAM4.G9 RAM4.J1 RAM4.J2 RAM4.J8 RAM4.J9 RAM4.L1 RAM4.L9 RAM4.R1 RAM4.T9 RAM5.A1 RAM5.A9 RAM5.B3 RAM5.B9 RAM5.C1 RAM5.D1 RAM5.D9 RAM5.E2 RAM5.E7 RAM5.F2 RAM5.F8 RAM5.G1 RAM5.G7 RAM5.G9 RAM5.J1 RAM5.J2 RAM5.J8 RAM5.J9 RAM5.L1 RAM5.L9 RAM5.R1 RAM5.T9 RAM6.A1 RAM6.A9 RAM6.B3 RAM6.B9 RAM6.C1 RAM6.D1 RAM6.D9 RAM6.E2 RAM6.E7 RAM6.F2 RAM6.F8 RAM6.G1 RAM6.G7 RAM6.G9 RAM6.J1 RAM6.J2 RAM6.J8 RAM6.J9 RAM6.L1 RAM6.L9 RAM6.R1 RAM6.T9 RAM7.A1 RAM7.A9 RAM7.B3 RAM7.B9 RAM7.C1 RAM7.D1 RAM7.D9 RAM7.E2 RAM7.E7 RAM7.F2 RAM7.F8 RAM7.G1 RAM7.G7 RAM7.G9 RAM7.J1 RAM7.J2 RAM7.J8 RAM7.J9 RAM7.L1 RAM7.L9 RAM7.R1 RAM7.T9 RAM8.A1 RAM8.A9 RAM8.B3 RAM8.B9 RAM8.C1 RAM8.D1 RAM8.D9 RAM8.E2 RAM8.E7 RAM8.F2 RAM8.F8 RAM8.G1 RAM8.G7 RAM8.G9 RAM8.J1 RAM8.J2 RAM8.J8 RAM8.J9 RAM8.L1 RAM8.L9 RAM8.R1 RAM8.T9 U4002.1 U4002.2 U4002.9
1D2V_VCCSFR_OC: C803.2 C4007.1 CPU1.BL27 CPU1.BM26 R4019.2 U4002.6 U4002.7 U4002.8
1D8V_CPVDD: C2730.1 C2740.2 R2724.2 U2701.20
1D8V_EN#: Q4001.D R4034.2 R4035.1
1D8V_EN_R#: C4038.2 Q4002.G R4035.2
1D8V_PWR: PC5402.1 PC5404.1 PC5405.1 PG5403.1 PG5404.1 PR5403.1 PU5401.3 PU5401.4
1D8V_S0: C4039.1 Q4002.D R2052.1 R2724.1 R2748.1 R2750.1 R6406.1
1D8V_S5: C4037.1 C4038.1 C6401.1 PG5403.2 PG5404.2 Q4002.S R1104.2 R1515.1 R2011.1 R2013.1 R2016.1 R2018.1 R2029.1 R2031.1 R2033.1 R2456.1 R2462.2 R4034.1 R6121.2 R6122.2 R6123.2 U6402.5
1D8V_S5_EN: PC5406.1 PR5401.1 PR5406.2 PU5401.8
1D8V_S5_KBC: C2423.1 R2462.1 U2401.54
1D8V_VCCPRIM: C1122.1 C2210.1 C2211.1 CPU1.CC15 CPU1.CC18 CPU1.CC19 CPU1.CD15 CPU1.CD16 CPU1.CD18 CPU1.CD19 CPU1.CP17 CPU1.CP23 R1104.1 R1512.1 R1738.1 R1821.1 R2053.1 R2111.1 R2113.1 R2115.1 R2117.1
1D24V_VCCDPHY: CPU1.BY23 CPU1.BY24 CPU1.CA23 CPU1.CA24
1D24V_VCCDPHY_EC: C2218.1 CPU1.CP25
2D5V_S3: C1259.1 C1260.1 C1261.1 C1262.1 C1263.1 C1264.1 C1265.1 C1266.1 C1267.1 C1268.1 C1269.1 C1270.1 C1271.1 C1272.1 C1273.1 C1274.1 C1275.1 C1276.1 C1277.1 C1278.1 C1279.1 C1337.1 C1338.1 C1339.1 C1340.1 C1341.1 C1342.1 C1344.1 C1345.1 C1346.1 C1347.1 C1348.1 C1349.1 C1350.1 C1351.1 C1352.1 C1353.1 C1371.1 C1372.1 C1373.1 C1374.1 C1375.1 FC8946.1 FC8947.1 FC8948.1 FC8949.1 FC8950.1 FC8951.1 FC8952.1 FC8953.1 FC8954.1 PG5401.2 PG5402.2 RAM1.B1 RAM1.R9 RAM2.B1 RAM2.R9 RAM3.B1 RAM3.R9 RAM4.B1 RAM4.R9 RAM5.B1 RAM5.R9 RAM6.B1 RAM6.R9 RAM7.B1 RAM7.R9 RAM8.B1 RAM8.R9
2D5V_S3_EN: PC5427.1 PR5409.1 PR5417.2 PU5403.8
2D5V_S3_PWRGD: PG5122.1 PR5410.2 PU5403.7
3D3V_1D8V_AVDD: C2722.1 C2729.2 C2743.1 R2742.1 R2743.2 R2744.2 R2748.2 R2749.2 U2701.3
3D3V_1D8V_AVDD_IO: C2744.1 C2745.1 R2750.2 R2751.2 U2701.18
3D3V_AUX_KBC: ED4304.2 ED4305.2 ED4306.2
3D3V_AUX_S5: PG4519.2 PR4503.1 PR4505.1 R1726.2 R1727.1 R1737.1 R2463.1 R2472.2 R2505.1 R2728.1
3D3V_CAMERA_S0: C5503.1 F5502.2 FC5502.1 LCD1.37
3D3V_ECVBAT: C2428.1 R2451.2 R2472.1 R2473.1 R2497.2 U2401.122
3D3V_FLASH: C7211.1 C7244.1 R7204.1 R7222.1 R7225.2 R7226.2 R7228.2 R7230.2 U7201.G1 U7202.8
3D3V_FPR_VDD: C9201.1 FP1.1 R9211.1 R9213.1 R9214.2 R9215.1
3D3V_HDMI_VDD: C5726.2 C5749.1 C5750.1 C5751.1 C5752.1 R5738.1 R5739.1 R5740.2 R5742.2 R5745.1 R5746.1 R5747.2 R5756.1 R5780.2 U5701.B2 U5701.G2 U5701.G4 U5702.8 U5703.5
3D3V_LCDVDD_R: FC5505.1 R5546.2 U5501.1
3D3V_LCDVDD_S0: C5507.2 C5508.2 FC5501.1 LCD1.30 LCD1.31 LCD1.32 LCD1.33 R5546.1
3D3V_LDO_SET: R5541.2 R5542.1 U5503.4
3D3V_MIC_VCC: C5521.1 LCD1.50 R5511.2
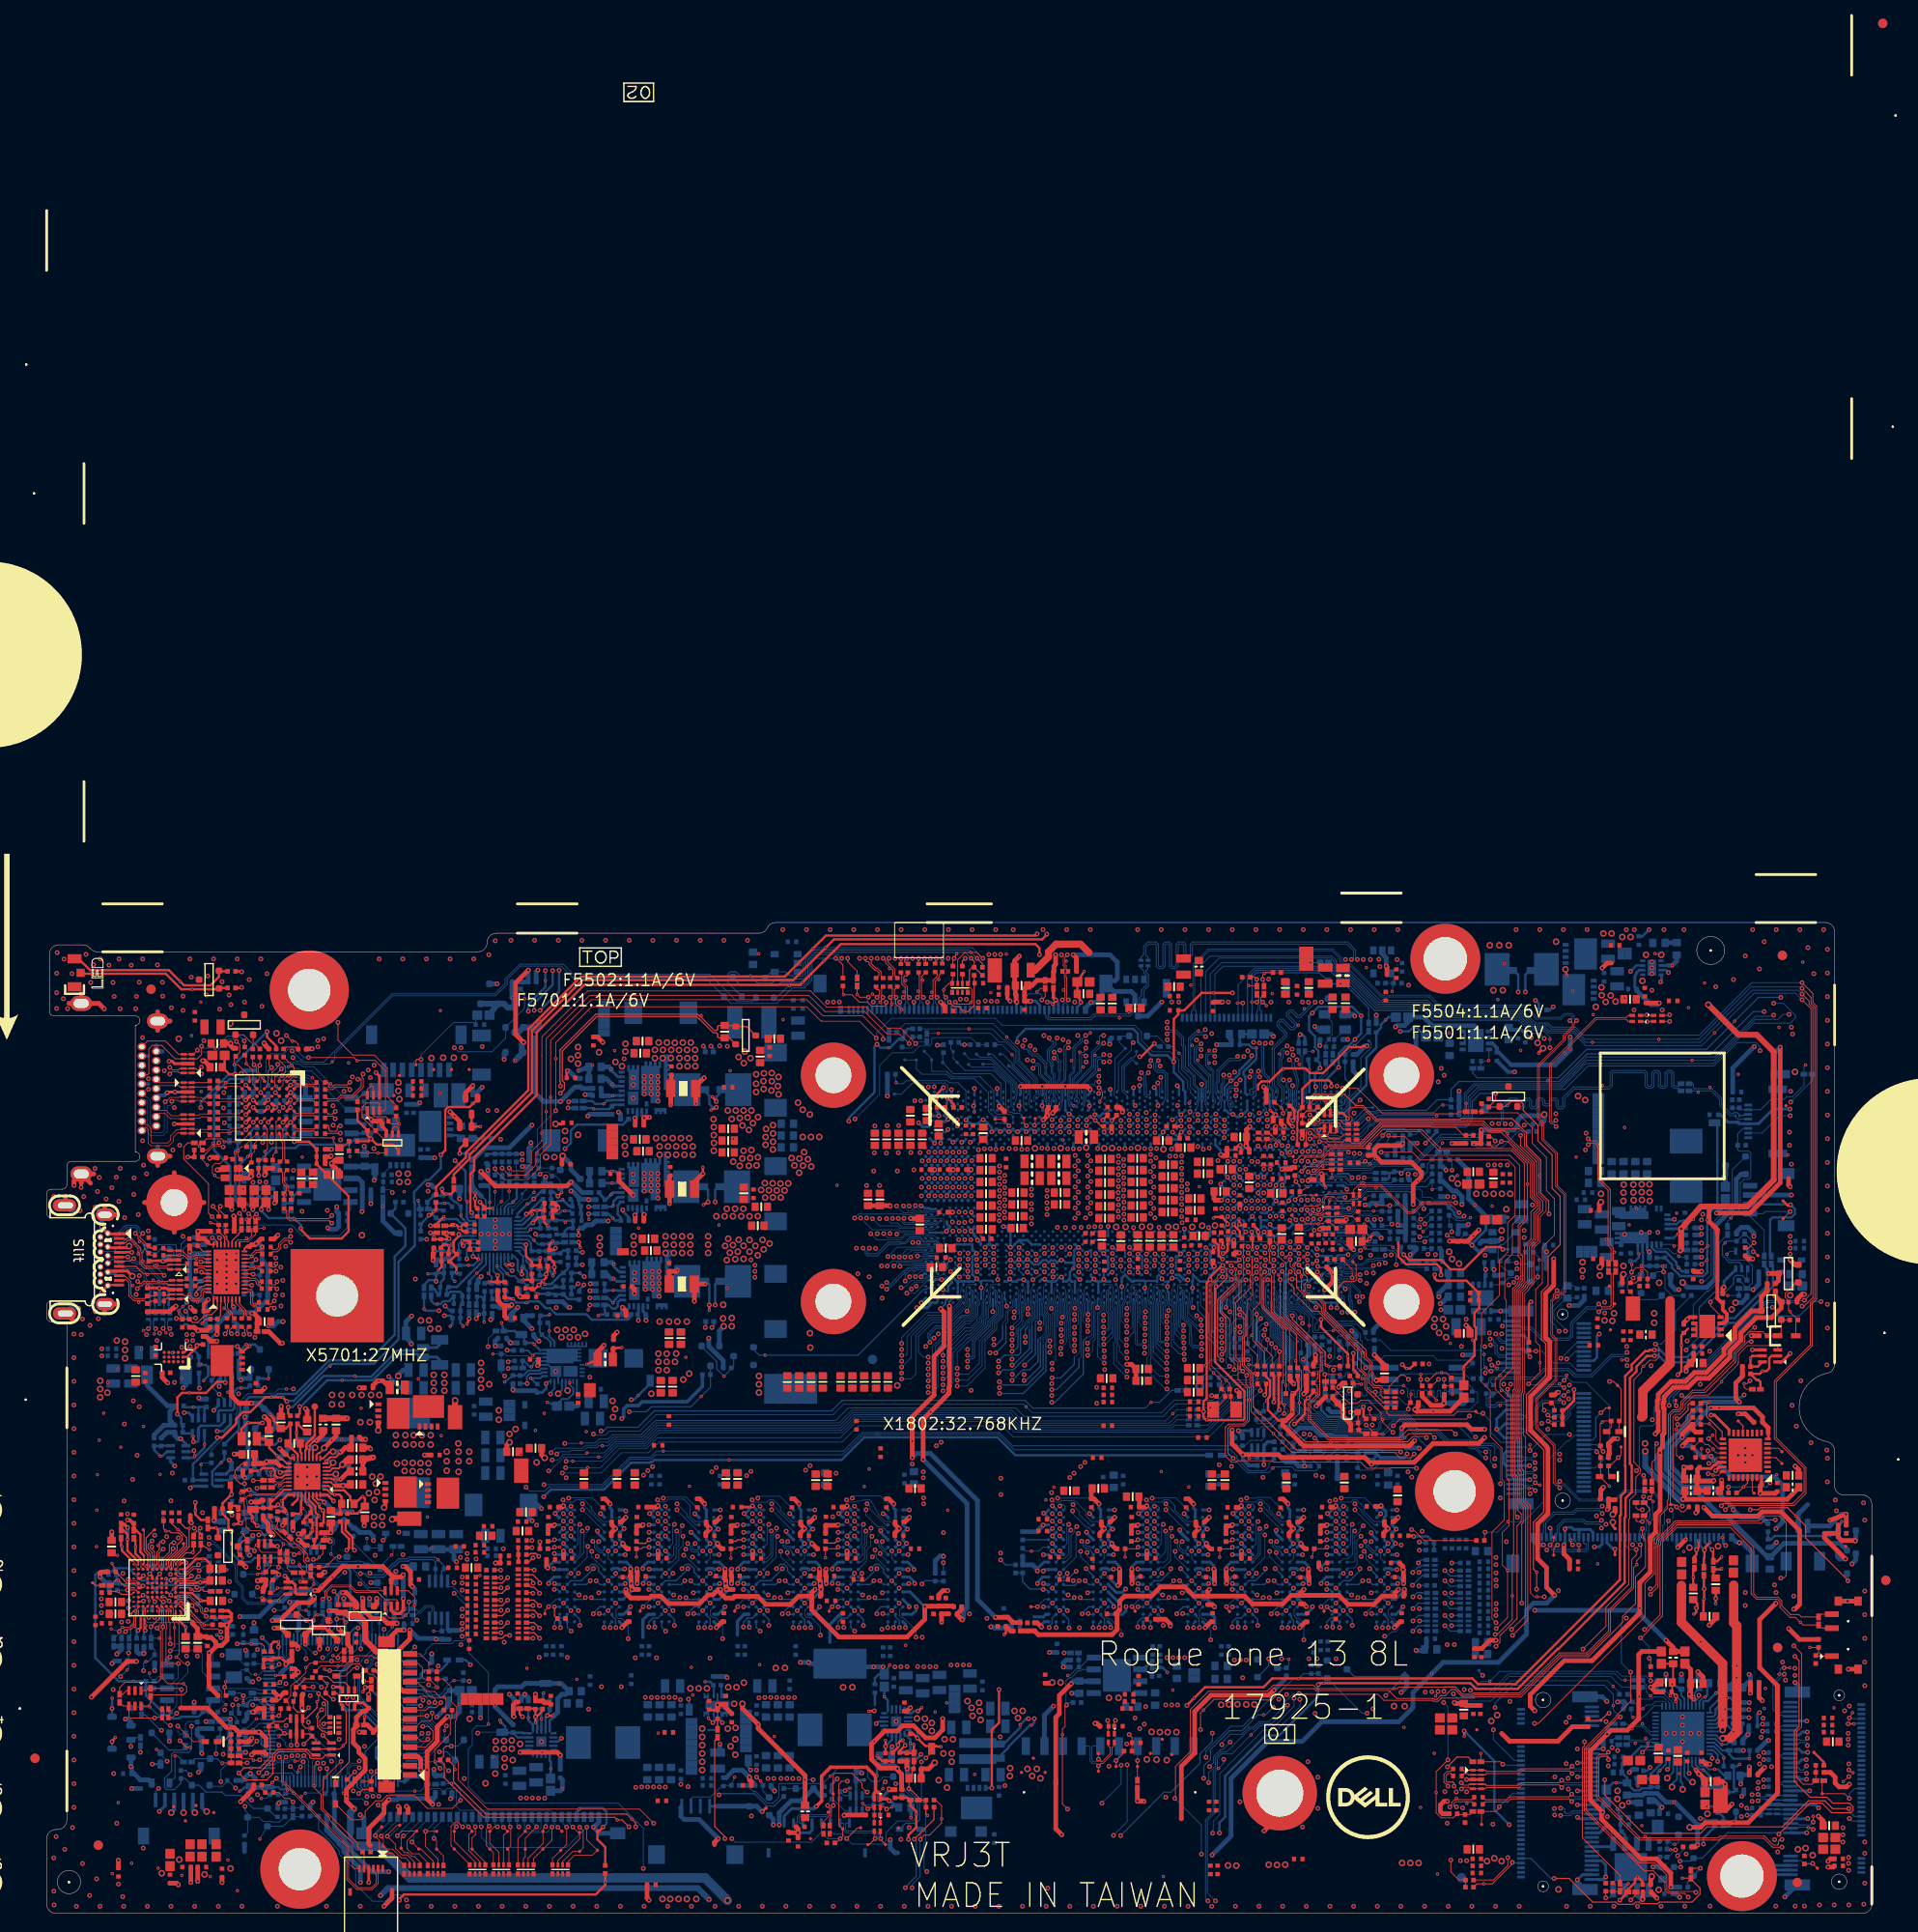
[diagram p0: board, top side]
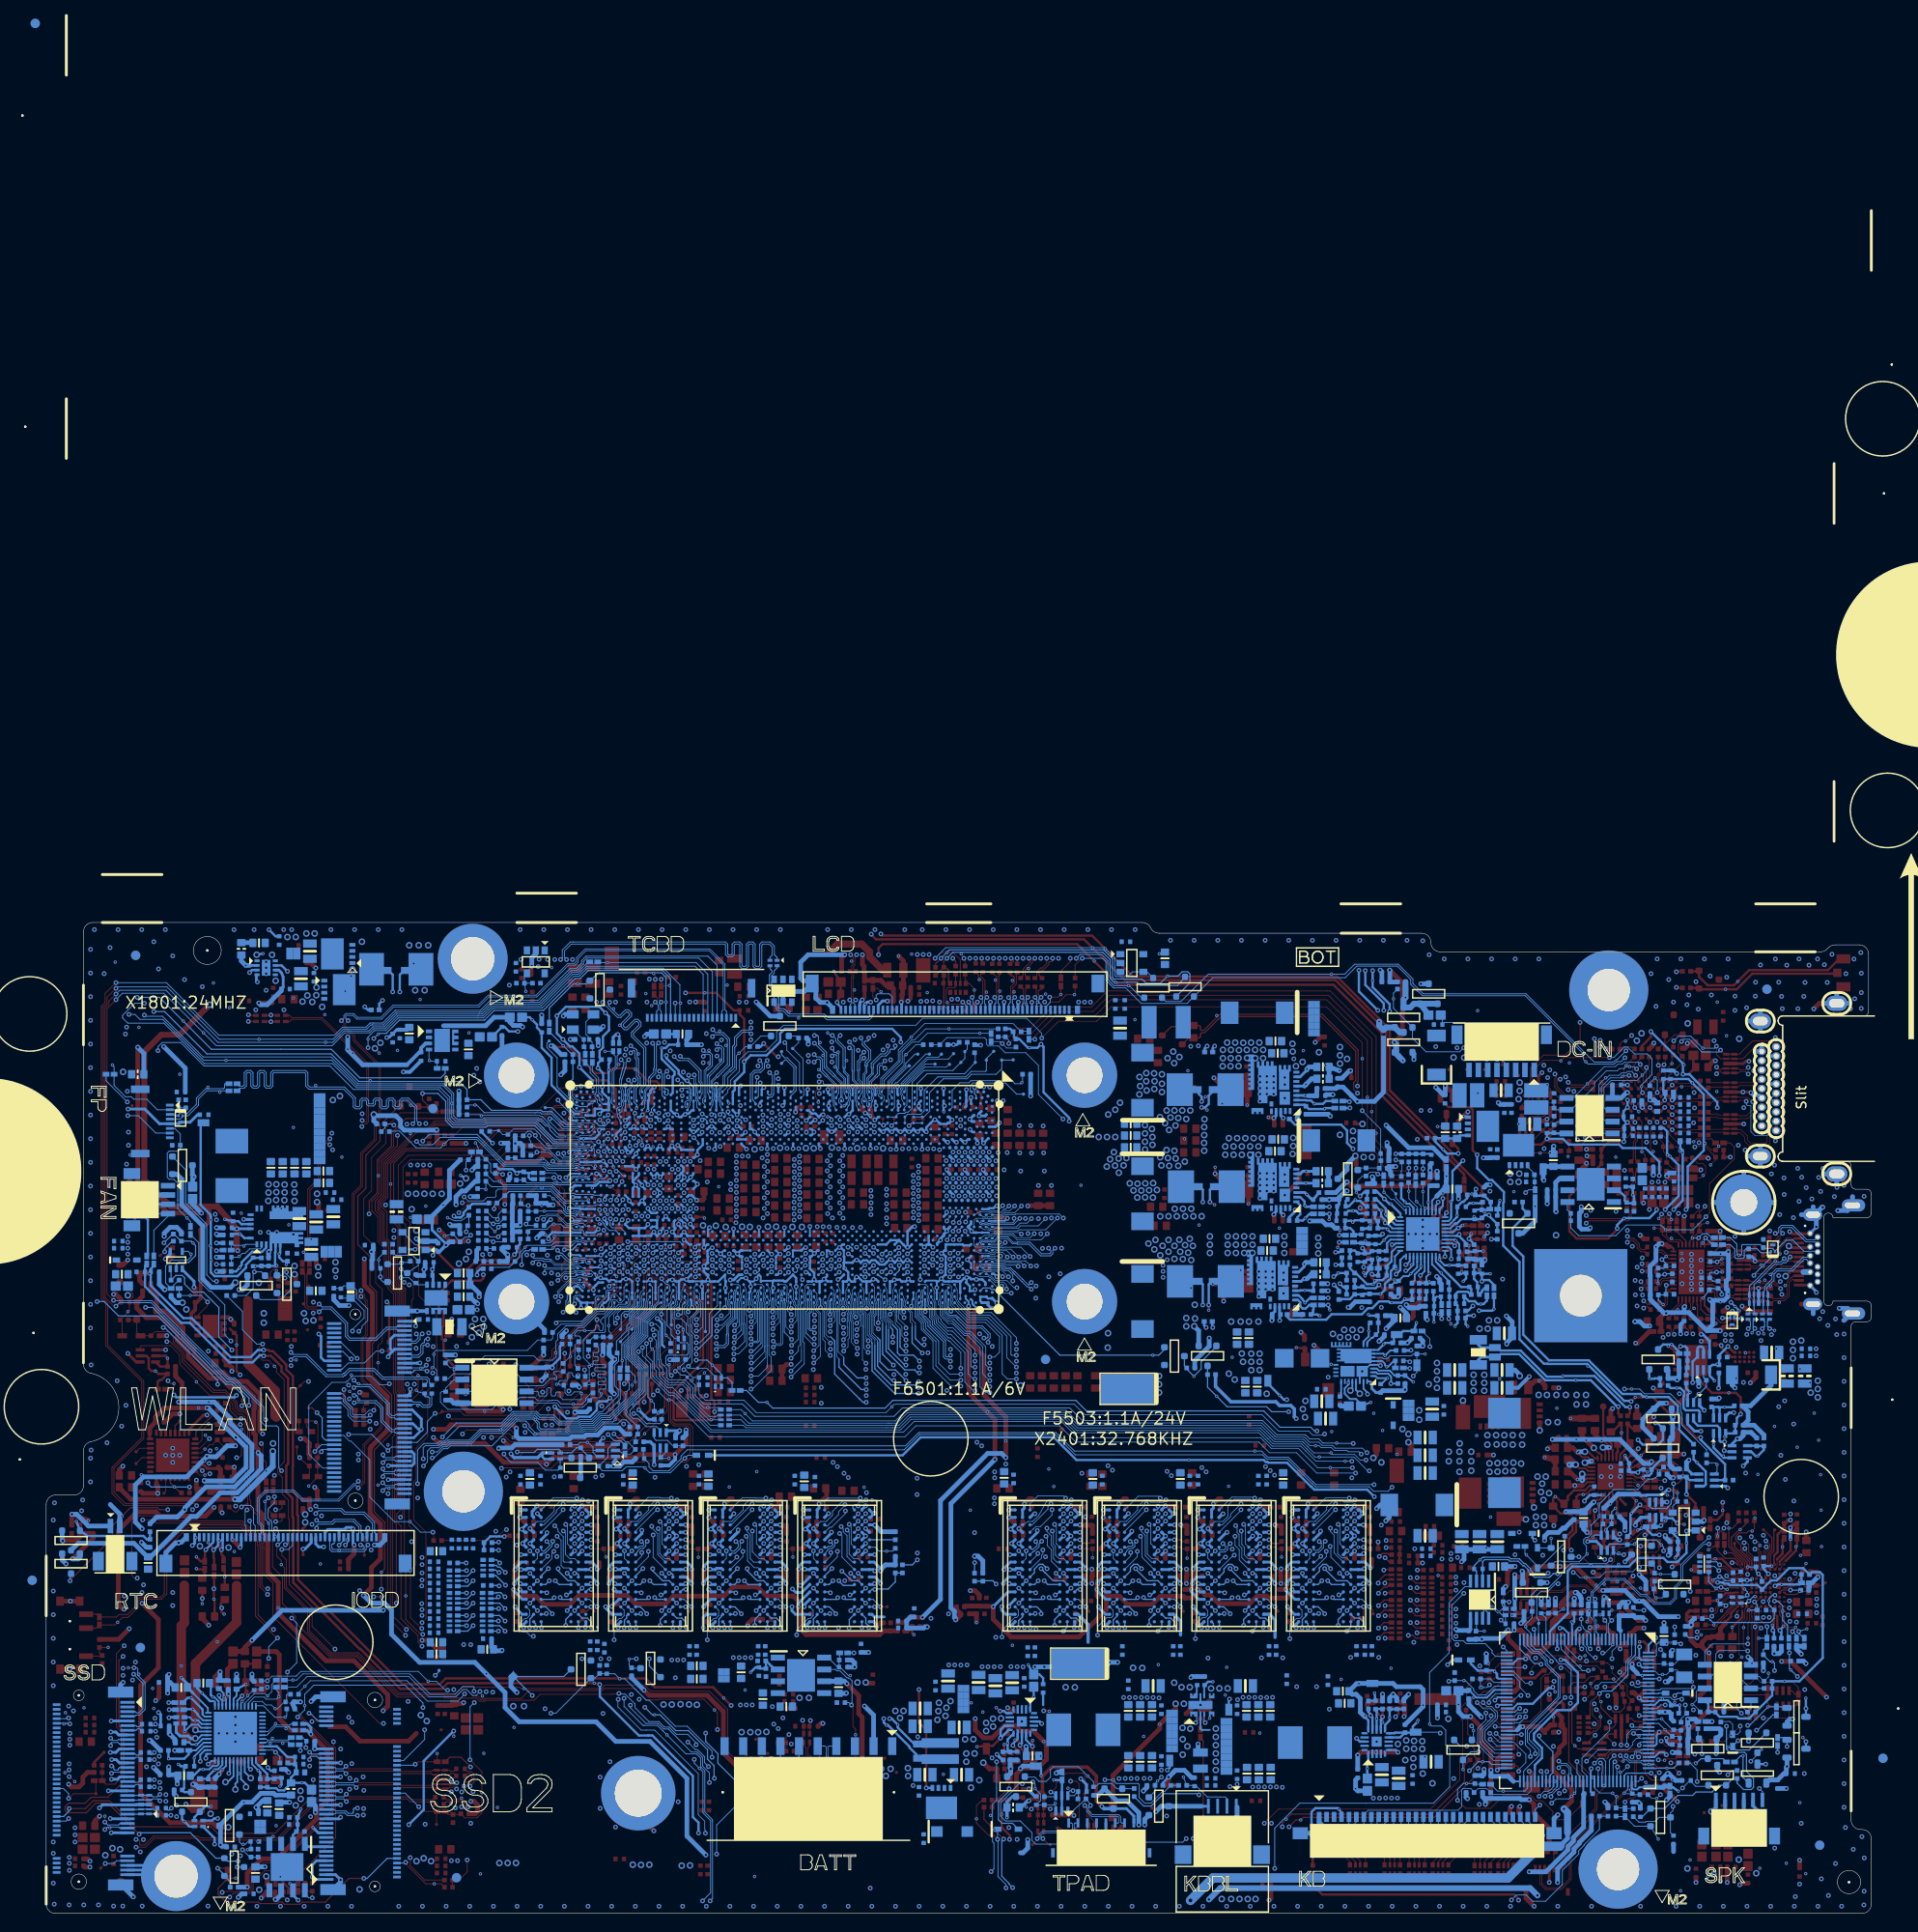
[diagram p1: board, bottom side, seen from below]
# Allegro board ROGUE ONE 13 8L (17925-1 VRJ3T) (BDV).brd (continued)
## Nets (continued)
SSD_SATA_TX_P: C6302.2 CPU1.BJ3
SSD_SATA_TX_P11: C6324.2 CPU1.BN1
SSD_SCP#: R2449.2 R6314.1 R6315.1 U2401.21
SSD_SCP#_1: R6314.2 SSD1.8
SSD_SCP#_2: R6315.2 SSD2.8
SSEQ0_A0: R7145.2 R7146.1 U7101.11
SSEQ1: R7144.1 R7152.2 U7101.3
SUS_CLK: CPU1.BT32 EC1803.2 FC1801.2 R2461.1 R6117.1
SUSACK#_R: CPU1.BY32 R1708.2
SUSCLK_WLAN: R6117.2 WLAN1.50
SVID_ALERT#_CPU: PR4605.2 PR4623.1 R727.2 R728.1
SVID_ALERT#_CPU_R: CPU1.AA3 R728.2
SVID_ALERT#_VR: PR4623.2 PU4601.36
SVID_CLK_CPU: PR4606.2 PR4624.1 R723.2 R732.2
SVID_CLK_CPU_R: CPU1.AA1 R732.1
SVID_CLK_VR: PR4624.2 PU4601.37
SVID_DATA_CPU: PR4604.2 PR4622.1 R709.2
SVID_DATA_CPU_R: CPU1.AA2 R709.1 R726.2
SVID_DATA_VR: PR4622.2 PU4601.35
SYS_LED_MASK#: C2436.1 PR2455.2 R2410.1 R2457.1 U2401.55
SYS_LED_MASK#_R: R2410.2 R2456.2 R6419.1 U6402.2
SYS_PRES1#: AFTP4315.1 BATT1.7 R4301.2
SYS_PWROK: CPU1.CR10 ED1702.1 R1717.1 U2401.28
SYSPWR_PRES: R2454.1 R2463.2 U2401.120
T_CRIT#: R2601.1 R2604.2 U2601.4
TBTA_SENSEN: R7217.2 U7201.A10
TBTA_SENSEP: R7216.2 U7201.B10
TCH_INTR#: ED5502.1 R5523.1 TCBD1.16
TCH_PNL_3D3V_5V: F5501.1 R5508.1 R5509.2 R5541.1 U5503.5
TEST_MODE_1: RAM4.N9 TP1201.1
TEST_MODE_2: RAM1.N9 TP1202.1
TEST_MODE_3: RAM3.N9 TP1203.1
TEST_MODE_4: RAM2.N9 TP1204.1
TEST_MODE_5: RAM6.N9 TP1301.1
TEST_MODE_6: RAM8.N9 TP1302.1
TEST_MODE_7: RAM5.N9 TP1303.1
TEST_MODE_8: RAM7.N9 TP1304.1
THERM_SYS_SHDN#: Q2602.S R2601.2 R2602.1
THERMTRIP#_CPU: CPU1.BJ1 ED301.1 R308.2
TOUCH_DETECT: R2102.1 R5504.1 TCBD1.13
TOUCH_DETECT_R: CPU1.CN14 R2102.2
TOUCH_PANEL_INTR#: CPU1.CN3 R5505.1 R5507.1 R5523.2
TOUCH_PANEL_PD#: CPU1.CC35 TCBD1.15
TOUCH_REPORT_SW: D2402.A TCBD1.14
TP_65982D_RESET_N: R7229.2 TP7205.1
TP_EN#: R6504.1 RN2405.4(A) U2401.49
TP_ON#_GATE: C6502.2 Q6502.G Q6503.G R6504.2
TP_TPM_GPIO1: TP9103.1 U9102.30
TP_TPM_GPIO3: TP9102.1 U9102.6
TP_TPM_PP: TP9101.1 U9102.4
TP_WAKE_KBC#: AFTP6536.1 CPU1.CB34 R303.2 R6511.2 TPAD1.4 U2401.33
TPM_GPIO0: R9141.1 U9102.29
TPM_GPIO4: TP9104.1 U9102.13
TPM_ID: CPU1.CK25 R1910.2 R1911.1
TPM_SPI_IRQ#: CPU1.CF20 R9139.1
TYPEC_DCIN1_EN#: Q7406.2 Q7407.2 R7428.1 U2401.63
TYPEC_SMBCLK: Q2417.1 R2468.2 RN2413.4(B) U2401.91
TYPEC_SMBCLK_Q: Q2417.6 R2468.1 R7220.1 U7201.B5
TYPEC_SMBDA: Q2417.4 R2467.2 RN2413.3(B) U2401.89
TYPEC_SMBDA_Q: Q2417.3 R2467.1 R7221.1 U7201.A5
U3_PD#_EC: CN6601.22 R2479.2
U5703_OUT: R5744.2 U5703.4
UART_2_CRXD_DTXD: CPU1.CR12 R2048.2 R6803.1
UART_2_CRXD_DTXD_CON: DB1.14 R6803.2
UART_2_CTXD_DRXD: CPU1.CP12 R2049.2 R6802.1
UART_2_CTXD_DRXD_CON: DB1.13 R6802.2
UPD1_ALERT_R: R7235.2 U7201.B6
UPD1_SMBINT#: R7215.1 R7235.1 U2401.32
USB1_CC1: C7217.1 ED7305.2 R7211.1 U7201.L9 USB1.A5
USB1_CC2: C7218.1 ED7305.1 R7212.1 U7201.L10 USB1.B5
USB1_SBU1: ED7306.2 R7153.2 R7330.1 USB1.A8
USB1_SBU1_R: R7153.1 U7101.27
USB1_SBU2: ED7306.1 R7151.2 R7331.1 USB1.B8
USB1_SBU2_R: R7151.1 U7101.26
USB1_SSRX_CON_N1: C7121.2 R7120.2 USB1.B10
USB1_SSRX_CON_N2: C7122.2 R7122.2 USB1.A10
USB1_SSRX_CON_P1: C7120.2 R7119.2 USB1.B11
USB1_SSRX_CON_P2: C7123.2 R7123.2 USB1.A11
USB1_SSRX_MUX_N1: C7121.1 ED7301.4 ED7301.7 U7101.31
USB1_SSRX_MUX_N2: C7122.1 ED7302.2 ED7302.9 U7101.39
USB1_SSRX_MUX_P1: C7120.1 ED7301.5 ED7301.6 U7101.30
USB1_SSRX_MUX_P2: C7123.1 ED7302.1 ED7302.10 U7101.40
USB1_SSTX_CON_N1: C7163.1 ED7301.1 ED7301.10 USB1.A3
USB1_SSTX_CON_N2: C7162.1 ED7302.5 ED7302.6 USB1.B3
USB1_SSTX_CON_P1: C7164.1 ED7301.2 ED7301.9 USB1.A2
USB1_SSTX_CON_P2: C7161.1 ED7302.4 ED7302.7 USB1.B2
USB1_SSTX_MUX_N1: C7163.2 U7101.34
USB1_SSTX_MUX_N2: C7162.2 U7101.36
USB1_SSTX_MUX_P1: C7164.2 U7101.33
USB1_SSTX_MUX_P2: C7161.2 U7101.37
USB1_USB20_N: CN6601.34 CPU1.CE3
USB1_USB20_P: CN6601.33 CPU1.CE4
USB1_USB30_RX_N: CN6601.37 CPU1.CB5
USB1_USB30_RX_P: CN6601.36 CPU1.CB6
USB1_USB30_TX_N: CN6601.40 CPU1.CA4
USB1_USB30_TX_P: CN6601.39 CPU1.CA3
USB2_ID: CPU1.CE8 R1601.1
USB2_VBUSSENSE: CPU1.CC6 R1602.1
USB4_USB20_CMC_N1: EL7201.1 U7201.L6
USB4_USB20_CMC_N2: EL7202.1 U7201.L7
USB4_USB20_CMC_P1: EL7201.4 U7201.K6
USB4_USB20_CMC_P2: EL7202.4 U7201.K7
USB4_USB20_CON_N1: ED7303.1 ED7303.10 EL7201.2 USB1.A7
USB4_USB20_CON_N2: ED7303.4 ED7303.7 EL7202.2 USB1.B7
USB4_USB20_CON_P1: ED7303.2 ED7303.9 EL7201.3 USB1.A6
USB4_USB20_CON_P2: ED7303.5 ED7303.6 EL7202.3 USB1.B6
USB4_USB20_N: CPU1.CD3 U7201.K5
USB4_USB20_P: CPU1.CD4 U7201.L5
USB4_USB30_RX_C_N: C7106.2 U7101.4
USB4_USB30_RX_C_P: C7105.2 U7101.5
USB4_USB30_RX_N: C7106.1 CPU1.BW6
USB4_USB30_RX_P: C7105.1 CPU1.BW5
USB4_USB30_TX_C_N: C7104.2 U7101.7
USB4_USB30_TX_C_P: C7103.2 U7101.8
USB4_USB30_TX_N: C7104.1 CPU1.BW2
USB4_USB30_TX_P: C7103.1 CPU1.BW1
USB_ADT: PD4401.2 PD4408.2 R7411.1 U7418.5 U7418.6 U7418.7 U7418.8 U7419.A1 U7419.B1 U7419.C1 U7419.D1
USB_EN#: CN6601.13 R2434.2 U2401.13
USB_OC0#: CN6601.12 CPU1.CK6 RN1601.5(B)
USB_OC1#: CPU1.CK5 RN1601.6(B)
USB_OC2#: CPU1.CK8 RN1601.7(B)
USB_OC3#: CPU1.CK9 RN1601.8(B) U7201.B2
USBCOMP: CPU1.CC5 R1603.1
V_SM_VREF_CNTA: C1202.1 CPU1.F36 R1202.2
V_SM_VREF_CNTB: C1302.1 CPU1.E36 R1302.2
VCI_IN1#: R2497.1 U2401.126
VCREF0: C2409.1 R2424.1 R2448.1 U2401.25
VD_IN1_C: C2612.2 C2613.2 R2610.2 R2611.1
VR_CAP: C2418.1 U2401.18
VR_EN: PU4601.40 R4002.2
VR_RDY: PR4609.2 PU4601.39 TP4601.1
VRALERT#: CPU1.CC36 TP1708.1
VRAM_ID1: CPU1.CE27 R2034.1 R2035.2
VRAM_ID2: CPU1.CN23 R2037.1 R2038.2
VTT_CNTL: PR5113.1 Q502.D R507.2
WHITE_LED_BAT: Q6401.C R6402.2
WIFI_RF_EN: AFTP6110.1 CPU1.CG25 D6102.K R2107.2 R6108.2
WIFI_RF_EN_R: D6102.A R6108.1 R6109.2 WLAN1.56
WLAN_CLK_CPU_N: CPU1.BC1 WLAN1.49
WLAN_CLK_CPU_P: CPU1.BC2 WLAN1.47
WLAN_CLKREQ_CPU_N: AFTP6109.1 CPU1.CE32 RN1813.8(B) WLAN1.53
WLAN_EN#: Q6102.D R6111.2 R6112.1
WLAN_EN_R#: C6102.2 Q6101.G R6112.2
WLAN_PCIE_RX_N: CPU1.BN6 WLAN1.43
WLAN_PCIE_RX_P: CPU1.BN5 WLAN1.41
WLAN_PCIE_TX_CON_N: C6107.1 WLAN1.37
WLAN_PCIE_TX_CON_P: C6108.1 WLAN1.35
WLAN_PCIE_TX_N: C6107.2 CPU1.BR4
WLAN_PCIE_TX_P: C6108.2 CPU1.BR3
XCLK_BIASREF: CPU1.CJ1 R1803.1
XDP_CLK_CPU_N: CPU1.AU1 TP1808.1
XDP_CLK_CPU_P: CPU1.AU2 TP1807.1
XDP_DBRESET#: CPU1.CN10 EC1706.1 R1701.2 TP1712.1
XDP_PRDY#: CPU1.W1 TP306.1
XDP_PREQ#: CPU1.W2 TP305.1
XDP_TCLK: CPU1.P6 CPU1.T6 R317.1 TP309.1
XDP_TDI: CPU1.U5 CPU1.U6 TP310.1 TP315.1
XDP_TDO_CPU: CPU1.W5 CPU1.Y5 R310.1 TP311.1 TP316.1
XDP_TMS: CPU1.P5 CPU1.T5 TP312.1 TP317.1
XDP_TRST#: CPU1.AB6 CPU1.Y6 TP313.1
XTL_24M_X1_CPU: CPU1.CK3 R1839.1
XTL_24M_X1_R: C1807.2 R1839.2 R1841.1 X1801.1
XTL_24M_X2_CPU: CPU1.CK2 R1840.1
XTL_24M_X2_R: C1808.2 R1840.2 R1841.2 X1801.3
XTL_27M_X1_HDMI: C5729.1 R5750.1 U5701.E8 X5701.1
XTL_27M_X2_HDMI: R5748.1 R5750.2 U5701.F8
XTL_27M_X2_R: C5730.1 R5748.2 X5701.3
XTL_32K_X1_CPU: C1804.2 CPU1.BN31 R1815.1 X1802.1
XTL_32K_X2_CPU: C1803.1 CPU1.BN32 R1815.2 X1802.2

Pads without a net: CN6601 28; CPU1 A34 A35 AA4 AA24 AA26 AB25 AC24 AC25 AC26 AD24 AD26 AE28 AE29 AF31 AF32 AG6 AG7 AH26 AJ27 AL1 AL2 AL3 AL4 AL34 AL35 AM3 AM4 AM7 AN1 AN2 AN3 AN4 AR3 AT3 AU3 AW2 AY3 AY9 B35 BB9 BB24 BC24 BC28 BE1 BE2 BH3 BH4 BJ34 BJ36 BK34 BK35 BK36 BL34 BL36 BL37 BP5 BP6 BP8 BP9 BP28 BP29 BP34 BP35 BR1 BR2 BR18 BT3 BT4 BT6 BT7 BT8 BT9 BT31 BU1 BU2 BU3 BU4 BU5 BU6 BU8 BU9 BU29 BV24 BV25 BV30 BW3 BW4 BW8 BW9 BW36 BY3 BY4 BY6 BY7 BY8 BY9 BY31 C34 CA1 CA2 CA32 CB8 CB9 CC27 CC29 CC30 CE1 CE2 CE28 CE31 CF12 CF17 CF22 CF31 CG1 CG2 CG3 CG4 CG14 CG35 CH5 CH6 CH7 CH8 CH9 CH17 CH25 CH30 CH32 CH35 CH36 CJ17 CJ25 CJ29 CK17 CK23 CK34 CL35 CL36 CM16 CM18 CM19 CM20 CM23 CM24 CM27 CM28 CM35 CN16 CN18 CN19 CN22 CN26 CN28 CN35 CN36 CP3 CP4 CP6 CP16 CP18 CP20 CP28 CR3 CR4 CR16 CR18 CR20 CR22 CR24 CR26 CR28 CR35 D34 D35 D37 F34 F37 G1 G2 G3 G4 H3 H4 J1 J2 J3 K12 K14 K15 K17 K18 K20 L1 L2 L3 L4 L5 L25 M3 M4 M24 M26 N1 N2 N3 N4 N5 P24 P26 R1 R2 R4 R24 R25 R26 T3 T4 T25 T29 T31 T32 U34 U35 U37 V24 V25 V28 V29 W3 W25 Y3 Y24 Y25; DB1 1 12; DCIN1 5; ED1701 2; ED1702 2; ED2403 2; ED5501 3 4 5; ED5502 2; HDMI1 14; KB1 2 3; KBBL1 3; LCD1 5 29 34 35 36 38 40 41 49; PU4501 15; PU4701 4 6 27 30 31 35; PU4801 4 6 27 30 31 35; PU4802 4 6 27 30 31 35; PU5101 26; RAM1 T7; RAM2 T7; RAM3 T7; RAM4 T7; RAM5 T7; RAM6 T7; RAM7 T7; RAM8 T7; RN7207 1 8; SSD1 6 20 22 24 26 28 30 32 34 36 40 42 44 46 48 54 56 58 67 68; SSD2 5 6 7 11 13 17 19 20 22 23 24 25 26 28 30 32 34 36 40 42 44 46 48 54 56 58 67 68; TCBD1 2 19; U2401 3 4 10 23 35 70; U2502 3; U2701 1 8 9 10 11 12; U5501 3; U5701 C5 D3 D7 D8 F3 F7; U5801 7; U7201 F4 G4 L11; U9102 2 3 5 7 9 10 11 12 14 15 25 26 27 28 31; WLAN1 6 8 12 16 20 38 40 42 44 46 48 58 60 62 66 68 70

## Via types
v1: diameter 0.356, hole 0.178, TOP to BOTTOM, 982 vias
v2: diameter 0.508, hole 0.254, TOP to BOTTOM, 4201 vias
v3: diameter 0.711, hole 0.406, TOP to BOTTOM, 542 vias

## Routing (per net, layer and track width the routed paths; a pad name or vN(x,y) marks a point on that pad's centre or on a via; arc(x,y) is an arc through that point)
1.8V_RUN_FB: length 4
  BOTTOM w0.254: PU5401.2 169.5,8.41 PR5404.1 169,8.91 PC5405.2 169.03,9.57 PR5403.2 v1(168.64,11.19)
1V_CPU_CORE: length 25.9
  L4SGND w0.508: 77.43,74.72 76.34,73.63 68.29,73.63 67.35,74.57 65.52,74.57 64.89,73.93 61.35,73.93 60.97,74.31 v2(60.31,74.31)
  BOTTOM w0.254: CPU1.AP2 114.28,88.34 114.21,88.41 v2(114.21,88.44) ; CPU1.BB2 119.16,88.41 v2(118.93,88.64) ; CPU1.BF2 121.6,88.64 v2(121.41,88.83) ; CPU1.AV2 v2(116.72,88.62) ; CPU1.BF9 CPU1.BE9
  BOTTOM w0.508: v2(60.31,74.31) 58.97,74.31 58.56,73.91 57.96,73.91 57.91,73.86 57.9,73.86 57.6,73.55 PR4631.2
  vias: v1(73.75,83.13) v2(110.45,81.35) v2(110.43,80.23) v2(110.45,79.14) v2(110.45,77.97) v2(110.45,76.83) v2(110.45,75.71) v2(110.43,74.62) v2(110.78,80.76) v2(110.78,79.7) v2(110.78,78.55) v2(110.78,77.41) v2(110.78,76.27) v2(110.78,75.15) v2(111.57,74.64) v2(111.8,81.35) v2(111.77,80.23) v2(111.8,79.14) v2(111.8,77.97) v2(111.8,76.83) v2(111.8,75.71) v2(112.08,75.1) v2(112.13,80.76) v2(112.13,79.7) v2(112.13,78.55) v2(112.13,77.41) v2(112.13,76.27) v2(112.98,88) v2(115.18,82.09) v2(115.36,85.11) v2(115.36,84.47) v2(115.36,83.84) v2(116.24,85.13) v2(116.45,82.11) v2(117.16,85.16) v2(117.18,84.5) v2(117.16,83.84) v2(117.92,82.09) v2(118.1,85.21) v2(118.12,83.84) v2(118.56,81.45) v2(118.56,80.74) v2(118.53,79.62) v2(118.56,78.53) v2(118.56,77.36) v2(118.56,76.22) v2(118.56,75.1) v2(118.89,80.16) v2(118.89,79.09) v2(118.89,77.95) v2(118.89,76.8) v2(118.89,75.66) v2(119.04,85.08) v2(119.01,84.45) v2(119.01,83.81) v2(119.01,74.64) v2(119.19,82.09) v2(119.11,81.09) v3(73.14,86.17) v3(73.57,85.26) v3(73.72,80.69) v3(74,86.17) v3(74.43,85.36) v3(74.44,80.23) v3(74.73,84.56) v3(74.71,81.03) v3(74.84,86.17) v3(74.84,81.85) v3(75.27,85.42) v3(75.41,84.08) v3(75.4,80.23) v3(75.54,81.07) v3(75.68,86.17) v3(75.69,81.93) v3(75.85,84.81) v3(76.19,90.06) v3(76.18,89.05) v3(76.18,88.16) v3(76.24,80.28) v3(76.39,85.46) v3(76.38,81.16) v3(76.72,77.64) v3(76.98,89.32) v3(77.03,90.16) v3(77,88.48) v3(77.13,78.38) v3(77.15,76.83) v3(77.26,84.19) v3(77.2,83.33) v3(77.2,82.49) v3(77.56,77.62) v3(77.86,90.19) v3(77.87,89.31) v3(77.83,88.32) v3(77.99,81.98) v3(77.97,78.35) v3(77.99,76.85) v3(78,84.6) v3(78,83.71) v3(78,82.82) v3(78.4,77.59) v3(78.59,89.77) v3(78.53,88.79) v3(78.6,87.9) v3(78.8,78.33) v3(78.83,76.83) v3(79.24,77.59) v3(79.64,78.35) v3(80,81.07) v3(80.3,80.28) v3(80.84,81.02) v3(80.81,79.49) v3(81.22,80.26) v3(81.34,81.7) v3(81.75,80.94) v3(82.11,80.16) v3(113.58,82.11) v3(114.42,82.14) v3(114.85,73.68) v3(115.86,73.68) v3(117.18,82.16) v3(117.62,73.7) v3(118.5,73.7) v3(119.93,82.01) v3(120.44,73.68) v3(121.27,73.7)
1V_GT_CORE: length 11.1
  TOP w0.508: v2(104.58,88.76) 104.59,88.77 v2(106.92,88.77) v2(109.4,88.77) 111.72,88.77 112.05,88.44 v2(112.05,88.42)
  BOTTOM w0.203: v2(106.92,88.77) 106.96,88.73 106.96,87.85 CPU1.AB2 ; CPU1.AF2 v2(109.4,88.77)
  BOTTOM w0.254: v2(112.05,88.42) 112.05,88.06 CPU1.AK2 ; v2(104.58,88.76) 104.58,87.92 CPU1.V2
  vias: v1(109.15,83) v1(110.3,86.68) v2(106.87,82.14) v2(107.94,83.86) v2(108.17,82.09) v2(108.88,83.86) v2(109.64,82.06) v2(109.82,83.86) v2(110.91,82.06) v3(106.14,82.11) v3(108.9,82.14) v3(111.64,82.19)
1V_VCCGT: length 32.7
  L3SGND w0.508: v2(47.69,63.72) 48.3,63.72 48.91,64.33 72.07,64.33 72.33,64.59 72.99,64.59 76.06,67.66 v2(76.06,68.27)
  BOTTOM w0.254: CPU1.P2 v2(102.08,88.54) ; CPU1.K2 v2(99.63,88.54)
  BOTTOM w0.508: PR4663.1 47.84,63.87 v2(47.69,63.72)
  vias: v1(84.88,78.15) v2(75.63,70.15) v2(76.06,69.56) v2(76.06,68.9) v2(88.05,78.12) v2(88.89,81.63) v2(88.81,79.67) v2(89.45,78.12) v2(90.18,81.6) v2(91.35,79.67) v2(91.45,81.63) v2(92.8,81.65) v2(93.13,79.8) v2(93.79,81.65) v2(93.94,77.95) v2(93.94,77.01) v2(94.02,80.77) v2(94.02,78.89) v2(94.73,81.71) v2(94.73,78.89) v2(94.73,77.95) v2(95.39,81.71) v2(95.37,80.77) v2(95.37,78.89) v2(95.39,77.95) v2(95.39,77.01) v2(96.03,81.71) v2(96.03,80.77) v2(96.03,78.89) v2(96.03,77.95) v2(96.03,77.01) v2(96.69,81.71) v2(96.69,78.89) v2(96.69,77.95) v2(97.33,81.7) v2(97.35,80.77) v2(97.35,78.89) v2(97.33,77.93) v2(97.33,76.99) v2(97.8,85.18) v2(97.8,84.5) v2(97.98,81.71) v2(97.98,80.77) v2(97.98,78.89) v2(97.98,77.95) v2(97.98,77.01) v2(98.62,81.71) v2(98.62,78.89) v2(98.62,77.95) v2(99.35,80.79) v2(99.3,78.89) v2(99.33,77.95) v2(99.3,77.01) v2(100.06,81.96) v2(100.7,82.06) v2(101.33,82.07) v2(102.63,82.09) v2(103.37,82.09) v2(104.05,82.06) v2(105.32,82.01) v2(105.75,77.72) v2(105.75,77.08) v2(105.75,76.17) v2(105.75,75.53) v2(105.75,74.64) v2(105.75,74.01) v3(72.86,71.64) v3(73.04,70.12) v3(73.19,72.41) v3(73.37,70.91) v3(73.7,71.72) v3(73.94,70.22) v3(74.22,71.01) v3(74.32,72.3) v3(74.84,71.65) v3(74.84,70.25) v3(75.48,72.28) v3(75.48,71.01) v3(76.11,71.65) v3(76.37,70.63) v3(76.87,72.28) v3(77,71.27) v3(77.64,71.9)
1V_VCCIO: length 16.6
  TOP w0.508: R401.1 v2(114.36,83.84)
  L6 w0.508: v2(126.07,78.28) 126.07,79.44 124.35,81.17 123.76,81.17 122.29,82.64 120.53,82.64 120.05,83.13 115.08,83.13 v2(114.36,83.84)
  BOTTOM w0.254: CPU1.BP16 126.39,78.59 v2(126.07,78.28) 126.07,78.19 CPU1.BP18
  vias: v1(150.74,61.18) v2(111.92,73.68) v2(112.56,73.7) v2(113.2,73.7) v2(131.38,74.82) v2(132.68,70.81) v2(136.11,73.32) v3(123.03,73.68) v3(149.06,63.79) v3(149,62.96) v3(149.53,62.31) v3(149.95,63.78) v3(150.28,63.01) v3(150.28,61.84)
1V_VCCIO_R:
  vias: v1(153.13,61.54)
1V_VCCSA:
  vias: v1(122.7,86.96) v1(123.79,78) v1(155.84,98.09) v1(156.53,101.95) v2(122.72,83.81) v2(123.66,83.81) v2(123.62,82.31) v2(124.52,83.84) v2(124.85,82.14) v3(124.09,73.81) v3(125.46,73.83) v3(154.98,103.9) v3(155.36,99.08) v3(156,103.9) v3(156.38,99.08) v3(157.01,103.9)
1V_VCCST_CPU: length 155.4
  TOP w0.254: v2(117.39,91.94) 117.53,91.94 v2(118.95,93.36) ; C806.2 128.23,82.39 v2(128.18,82.44) 128,82.44 C805.2
  L3SGND w0.254: v2(145.35,94.66) 142,91.31 136.36,91.31 135.85,90.8 133.08,90.8 131.81,92.07 v2(129.4,92.07)
  L4SGND w0.254: v2(117.39,91.94) 115.66,91.94 114.67,92.93 114.67,93.78 113.71,94.74 113.29,94.74 113.29,94.73 89.16,94.73 88.58,94.16 88.58,93.74 89.03,93.29 v2(89.17,93.29) ; v2(51.07,81.52) 51,81.52 49.95,82.57 49.95,87.77 57.93,95.75 70.04,95.75 72.28,93.52 v2(72.28,93.11) ; v2(128.18,82.44) 128.18,84.17 126.9,85.45 126.9,87.99 127.17,88.26 v2(127.17,89.37) 124.48,89.37 120.59,93.25 120.12,93.25 120.02,93.36 v2(118.95,93.36)
  L6 w0.254: v2(86.15,85.03) 81.42,85.03 79.71,86.74 79.71,91.49 77.46,93.74 72.91,93.74 v2(72.28,93.11)
  BOTTOM w0.203: CPU1.BP2 126.48,87.85 126.48,88.69 127.17,89.37
  BOTTOM w0.254: v2(128.18,82.44) 127.81,82.06 CPU1.BT11 CPU1.BR11 CPU1.BP11 ; PC4602.1 47.36,81.51 PR4604.1 PR4605.1 PR4606.1 PR4603.1 50.44,81.52 v2(51.07,81.52) ; v2(129.4,92.07) 129.4,91.79 128.08,90.47 128.08,90.11 127.34,89.38 127.17,89.38 127.17,89.37 v2(127.17,89.37) ; R727.1 92.47,94.94 R726.1 92.07,94.54 92.07,94.05 R723.1 91.5,93.85 90.56,92.91 v1(90.41,92.91) 89.55,92.91 v2(89.17,93.29) 88.89,93.01 88.89,88.13 86.15,85.38 v2(86.15,85.03) ; v2(118.95,93.36) 118.95,93.36 119.28,93.03 R308.1 ; R4036.2 C801.1 146.77,95.14 146.29,94.66 v2(145.35,94.66)
1V_VCCST_CPU_R:
  vias: v1(150.6,94.51)
1V_VCCSTG: length 118.8
  TOP w0.254: v2(121.04,91.41) 121.04,96 121.53,96.49 C802.1 122.16,96.92 124.04,98.8 v1(125.26,98.8) v2(127.34,98.8)
  L3SGND w0.254: v2(127.34,98.8) 131.28,98.8 134.2,95.88 138.67,95.88 139.03,95.52 143.65,95.52 144.26,96.13 145.99,96.13 152.57,89.55 154.81,89.55 160.06,84.3 160.06,75.1 159.4,74.44 159.4,68.09 158.01,66.71 158.01,62.39 v2(156.27,60.65)
  L4SGND w0.254: v2(98.57,93.24) 103.95,93.24 v2(104.23,93.52)
  L6 w0.254: v2(149.72,64.79) 150.23,64.79 150.94,64.08 150.94,62.6 153.2,60.34 154.21,60.34 154.23,60.32 154.65,60.32 154.68,60.34 155.97,60.34 v2(156.27,60.65)
  BOTTOM w0.254: CPU1.BG3 CPU1.BG2 CPU1.BG1 122.06,88.37 122.06,89.27 121.04,90.29 v2(121.04,91.41) 120.36,92.09 118.63,92.09 117.18,93.54 117.18,94.43 116.67,94.94 105.15,94.94 104.23,94.02 v2(104.23,93.52) ; R4043.2 v2(149.72,64.79) ; R310.2 98.21,93.24 v2(98.57,93.24) R301.1
1V_VREF_CPU: length 6.1
  BOTTOM w0.203: U2401.95 25.74,13.51 25.53,13.3 25.14,13.3 24.91,13.53 24.32,13.53
  BOTTOM w0.254: v1(20.73,13.12) 21.27,13.51 R2402.2
  BOTTOM w0.508: 24.32,13.53 C2406.1 22.26,13.66 R2402.2
3V5V_CT1: length 1.2
  BOTTOM w0.203: U4001.12 72.45,24.46 C4001.1
3V5V_CT2: length 2.2
  BOTTOM w0.203: U4001.10 71.65,24.45 C4002.1
  BOTTOM w0.254: C4002.1 71.24,24.86 v1(70.7,24.86)
3V5V_S0_ON: length 5.1
  TOP w0.127: C4003.2 72.12,20.9 v2(72.56,20.47) ; C4003.2 R4010.2 ; C4003.2 71.97,20.9 v2(71.54,20.47) v1(71.06,20.95)
  BOTTOM w0.127: v2(72.56,20.47) 72.45,20.57 U4001.3 ; U4001.5 71.65,20.57 v2(71.54,20.47)
3V_5V_DSW_OK: length 108.9
  TOP w0.102: PR5406.1 168.95,4.08 164.93,8.1 164.93,17.76 165.15,17.99 v2(165.15,18.42) ; v2(177.71,69.66) v1(178.3,70.12)
  L4SGND w0.102: v2(157.9,69.18) 157.95,69.23 161.46,69.23 163.64,67.05 166.25,67.05 166.36,67.15 171.07,67.15 171.18,67.05 174.59,67.05 175.12,66.52 175.63,66.52 177.08,67.96 177.08,69.03 v2(177.71,69.66)
  L6 w0.102: v2(177.71,69.66) 177.2,69.16 177.2,67.33 175.68,65.8 175.68,61.74 174.77,60.83 174.77,58.06 173.65,56.94 173.65,52.6 174.16,52.09 174.16,48.92 174.97,48.11 174.97,44.73 173.34,43.1 173.34,37.58 173.34,33.93 166.46,27.04 166.46,19.73 v2(165.15,18.42)
  BOTTOM w0.102: R2513.2 156.05,69.55 D2503.3 157.39,68.73 157.85,69.18 v2(157.9,69.18) ; R2513.2 155.88,70.16 155.88,71.53 156.12,71.77 156.4,71.77 U2502.4 ; R2513.2 156.68,70.63 158.46,70.63 R2514.2 ; PR5210.1 v2(177.71,69.66)
3V_5V_EN: length 13.8
  TOP w0.127: PR4516.1 93.13,15.56 R4006.1 92.94,15.37 92.94,14.94 92.6,14.6 C4009.1 v2(92.6,13.38) 92.77,13.2 92.88,13.2 93.61,12.46 PR4515.1 R4014.1 R4009.1 94.43,10.69 94.53,10.58 94.53,10.57 v1(94.6,10.5)
  BOTTOM w0.127: D4001.A 92.23,9.67 93.36,9.67 93.74,10.05 93.74,11.98 92.6,13.12 v2(92.6,13.38)
3V_5V_POK#: length 3.8
  TOP w0.254: Q1701.6 183.76,58.69 R1726.1 v1(182.97,59.58) 182.97,59.63 183.15,59.81 183.15,59.82 183.17,59.84 Q1701.5
3V_5V_POK_C: length 6.6
  TOP w0.254: Q1701.2 185.23,59.84 184.99,59.59 184.99,58.5 184.7,58.21 v1(184.27,58.21) 183.96,57.9 R1727.2 183.63,57.24 183.83,57.24 184.04,57.04 R1728.1
3V_5V_PWRGD: length 275
  TOP w0.102: v2(186.23,35.98) 186.53,35.98 186.81,36.26 186.81,41.93 186.07,42.66 184.39,42.66 183.86,42.13 175.1,42.13 175.07,42.11 174.89,42.11 172.91,40.12 172.91,39.79 172.85,39.73 172.85,39.67 172.85,35.23 172.48,34.87 172.2,34.87 v2(172.2,34.84) ; v2(22.57,18.5) 22.57,18.46 22.09,17.98 20.97,17.98 R4033.1 ; v2(94.43,16.68) 95.04,17.29 PG4531.1 ; R1728.2 182.51,56.25 182.28,56.48 v1(182.28,56.86) 182.61,56.86 v2(182.92,57.17)
  L4SGND w0.102: v2(172.2,34.84) 171.04,34.84 168.32,32.12 167.31,32.12 163.83,28.64 160.83,28.64 157.3,25.11 143.97,25.11 137.71,18.85 130.99,18.85 129.78,17.65 123.14,17.65 123.1,17.61 100.89,17.61 98.85,15.56 95.22,15.56 94.43,16.36 v2(94.43,16.68) ; v2(46.29,19.35) 45.78,18.84 42.43,18.84 41.44,17.85 38.06,17.85 v2(37.61,18.31) ; v2(20.28,13.45) 20.46,13.45 21.3,14.29 21.3,15.26 22.04,15.99 22.04,16.43 22.57,16.96 v2(22.57,18.5) ; v2(186.23,35.98) 185.56,35.98 185.21,36.33 185.21,45.47 184.44,46.24 184.44,49.71 182.92,51.24 v2(182.92,57.17) 182.16,57.93 182.16,65.8 181.65,66.31 174.6,66.31 174.24,66.67 171.27,66.67 170.99,66.95 166.44,66.95 166.16,66.67 163.56,66.67 161.5,68.73 161.36,68.73 161.13,68.95 158.35,68.95 158.12,68.73 157.65,68.73 157.39,68.98 157.39,69.36 v2(157.85,69.82)
  L6 w0.102: v2(94.43,16.68) 94.35,16.6 94.35,16.11 94.11,15.87 93.68,15.87 92.84,16.71 90.9,16.71 88.61,14.42 86.86,14.42 86.4,14.88 84.7,14.88 84.24,14.42 83.15,14.42 82.61,14.95 77.13,14.95 77.03,14.85 77.03,14.5 76.19,13.66 75.11,13.66 74.17,14.6 68.71,14.6 68.43,14.88 63.07,14.88 62.58,14.39 55.36,14.39 54.79,14.95 53.89,14.95 53.89,14.95 50.03,14.95 49.16,14.09 48.33,14.09 46.29,16.13 v2(46.29,19.35) ; v2(37.61,18.31) 34.97,18.31 34.91,18.36 32.47,18.36 31.92,17.8 28.81,17.8 28.64,17.62 26.43,17.62 26.43,17.62 24.7,17.62 23.83,18.5 v2(22.57,18.5)
  BOTTOM w0.102: PG4529.1 46.39,19.45 v2(46.29,19.35) ; ED1703.1 17.62,13.63 18.86,13.63 19.39,14.17 C1710.1 19.47,14.27 v2(20.28,13.45) ; R2513.1 156.91,69.97 157.01,69.87 157.8,69.87 v2(157.85,69.82) 157.95,69.82 158.09,69.68 D2503.1
3V_S5_EN: length 5
  TOP w0.254: v1(93.12,18.13) 93.12,17.92 PR4516.2 PR4514.1 92.34,17.24 PC4532.1 91.61,17.43 91.68,17.51 91.68,17.52 v2(92.19,18.03)
  BOTTOM w0.254: v2(92.19,18.03) 92.19,18.2 91.68,18.72 PU4501.12
5V_AUX_S5: length 10
  BOTTOM w0.508: PR4510.2 48.13,22.2 v1(48.13,22.34) 48.13,24.01 48.45,24.33 51.02,24.33 51.37,24.68 PG4528.2
5V_FAN_VCC: length 0.9
  TOP w0.508: AFTP2603.1 187.06,78.16 v2(187.23,77.99)
5V_HDMI_S0: length 1.2
  BOTTOM w0.508: 11.77,93.1 HDMI1.18 12.41,92.52
  vias: v1(15.56,94.2) v3(14.19,93.87)
5V_KB_BL: length 6.8
  TOP w0.508: v2(72.12,8.02) 71.72,7.61 AFTP6529.1
  BOTTOM w0.508: v2(72.12,8.02) 70.07,10.08 68.47,10.08 68.11,10.44 68.11,11.41
5V_S0: length 319.2
  L3SGND w0.635: v2(71.13,1.49) 72.43,2.79 72.43,5.73 74.36,7.66 74.36,9.14 v2(75.68,10.46)
  L3SGND w1.016: v3(178.35,10.69) 180.23,10.69 181.42,9.49 182.94,9.49 187.11,13.66 187.11,22.75 188.63,24.28 188.63,33.04 v2(187.62,34.05)
  L4SGND w0.635: v3(19.72,95.52) 19.72,95.19 18.2,93.67 18.2,92.13 18.21,92.11 18.21,89.64 17.31,88.74 17.31,82.75 16.8,82.24 16.8,75.38 15.34,73.92 15.34,72.37 13.88,70.91 13.88,66.7 13.68,66.5 13.33,66.5 12.75,65.92 12.55,65.72 12.55,65.37 10.02,62.84 10.02,56.91 5.69,52.58 5.69,45.73 5.03,45.07 5.03,24.16 5.64,23.55 5.64,22.87 5.17,22.4 5.17,15.84 7.53,13.48 v2(7.53,9.67)
  L4SGND w0.762: v2(145.02,102.38) 145.02,99.79 149.8,95.01 161,95.01 163.03,92.98 173.4,92.98 174.77,94.35 186.39,94.35 188.99,91.75 188.99,89.8 188.61,89.42 188.61,67.71 v3(187.24,66.34)
  L4SGND w1.016: v2(187.62,34.05) 187.88,34.31 187.88,46.24 186.78,47.34 186.78,49.76 185.26,51.29 185.26,61.54 187.24,63.53 v3(187.24,66.34)
  L6 w0.635: v2(35.85,1.92) 35.73,1.8 12.92,1.8 7.53,7.18 v2(7.53,9.67)
  BOTTOM w0.508: F6501.1 72.3,17.52 v2(72.3,18.18) ; R6510.1 87.34,15.18 87.47,15.05 v2(87.54,15.05)
  BOTTOM w0.635: v2(35.85,1.92) 36.64,2.71 69.91,2.71 v2(71.13,1.49)
  vias: v1(69.38,23.44) v3(69.13,24.15) v3(70.02,24.15) v3(70.91,24.15) v3(168.7,13.15) v3(168.67,12.29) v3(169.2,11.59)
5V_S5: length 418.8
  TOP w0.152: U7201.A11 v2(8.93,32.02)
  TOP w0.254: U7201.H10 10.08,35.94 v2(10.38,36.24) ; AFTP6608.1 168.19,41.55 168.19,41.67
  TOP w0.305: v3(168.19,41.98) 168.19,41.67
  TOP w0.406: 179.41,72.99 179.41,66.01 179.82,65.6 C4032.1 180,64.79 180.23,64.56 180.23,64.55 180.43,64.35 180.43,63.65 180.12,63.34 U4002.3
  TOP w0.508: EC8927.1 v2(7.71,5.71) ; v2(56.3,78.5) 55.87,78.07 48.16,78.07 46.65,79.59 v2(46.65,79.65) ; v2(63.16,85.36) 63.21,85.31 PC4877.1 ; 179.41,72.99 179.41,73.37 178.52,74.26 178.52,75.86 ; PC4866.1 63.21,74.9 v2(63.16,74.95) ; v2(110.02,24.66) 108.75,23.39 108.75,21.43 108.37,21.05 108.37,14.32 108.37,14.32 108.37,13.96 108.37,9.09 v2(109.01,8.45) ; EC8919.1 168.42,43.05 v3(168.19,42.82) ; PC5401.1 171.41,1.54 171.39,1.52 v2(171.39,1.49) ; v2(173.17,97.71) 171.72,97.71
  TOP w0.635: v3(178.45,97.53) 181.67,94.3 183.64,94.3 185.47,92.47 185.47,78.71 182.62,75.86 177.62,75.86 v2(175.53,73.48) 175.53,71.24 v2(175.43,71.14)
  L3SGND w0.508: v3(33.86,72.79) v2(33.86,75.32) 33.97,75.43 35.19,75.43 36.11,76.35 42.15,76.35 45.45,79.65 v2(46.65,79.65) ; v2(107.51,2.71) 107.66,2.71 109.01,4.06 v2(109.01,8.45)
  L3SGND w0.635: 168.5,44.4 169.47,45.37 169.47,50.54 169.6,50.67 169.6,54.71 169.91,55.02 169.91,56.38 v2(172.3,58.77) 172.84,58.77 174.16,60.09 174.16,61.49 175.05,62.38 176.95,62.38 177.4,61.93 177.4,59.96 178.03,59.33 178.92,59.33 179.54,59.95 179.54,63.47 176.82,66.19 176.82,69.74 v2(175.43,71.14)
  L4SGND w0.305: v2(154.54,69.12) 154.54,67.39 156.76,65.17 158.28,65.17 161.88,61.57 163.32,61.57 163.32,61.58 164.29,61.58 165.27,60.6 167.15,60.6 169.49,58.25 171.79,58.25 v2(172.3,58.77)
  L4SGND w0.508: v2(63.54,63.65) 62.34,63.65 61.2,64.78 61.2,64.85 60.31,65.75 ; v2(56.3,78.5) 57.8,80 57.8,83.95 55.93,85.82 55.73,85.82 55.36,86.19 55.36,86.99 v2(55.2,87.15) 55.88,87.83 55.92,87.83 56.6,88.51 60.01,88.51 v2(63.16,85.36) 61.35,83.56 61.35,76.91 ; v2(171.39,1.49) 170.58,2.3 166.51,2.3 165.96,1.76 128.7,1.76 126.86,3.6 v3(126.86,5.15) ; 60.31,65.75 59.22,64.66 56.55,64.66 v2(56.17,65.04) 55.23,64.1 53.46,64.1 v2(52.11,62.76) ; 60.31,65.75 58.47,67.58 v2(58.38,67.58) 60.92,70.12 60.92,72.66 59.6,73.98 59.6,75.74 60.78,76.91 61.35,76.91 ; v2(163.62,94.07) 164.28,94.07 165.24,95.04 172.1,95.04 172.56,95.5 172.56,97.1 v2(173.17,97.71) ; 61.35,76.91 63.16,75.11 v2(63.16,74.95) ; v2(8.8,33.55) 9.67,34.41 9.67,35.53 v2(10.38,36.24) ; v3(33.86,72.79) 34.63,72.02 34.63,64.88 32.62,62.87 32.62,62.87 32.54,62.79 29.5,62.79 26.52,59.82 24.66,59.82 v2(20.61,55.77)
  L4SGND w0.635: v2(173.17,97.71) 174.11,97.71 174.26,97.55 178.42,97.55 v3(178.45,97.53)
  L6 w0.508: v2(20.61,55.77) 20.61,55.68 17.62,52.68 17.62,46.84 14.9,44.12 14.9,39.56 13.79,38.45 12.83,38.45 12.79,38.42 11.92,38.42 10.38,36.87 v2(10.38,36.24)
  BOTTOM w0.203: 71.05,19.69 71.9,19.69 72.05,19.83 U4001.4
  BOTTOM w0.254: FC8933.1 154.39,69.26 v2(154.54,69.12)
  BOTTOM w0.305: FC8934.1 170.55,99.41 170.55,100.51 170.73,100.94 171.03,101.24 PU5001.6 ; PU5201.21 v2(175.53,73.48) 175.96,73.48 PC5202.1 ; v2(154.54,69.12) 154.52,69.12 C4043.1 154.45,68.4 U4003.3 ; PU4802.29 63.42,75.21 v2(63.16,74.95) ; v2(63.54,63.65) 63.54,64.18 PC4766.1 63.55,64.39 PU4701.29 ; PU4801.29 63.42,85.63 v2(63.16,85.36)
  BOTTOM w0.406: U4006.3 155.25,93.37 155.74,92.88 C4031.1 155.92,92.42 157.27,91.08
  BOTTOM w0.508: PU5401.6 170.77,2.01 171.29,1.49 v2(171.39,1.49) ; Q6402.E v2(9.06,15.77) 9.13,15.69 FC8929.1 9.39,15 FC8931.1 10.95,14.32 Q6505.E ; v2(56.17,65.04) 56.17,65.04 56.03,65.04 55.41,65.65 53.91,65.65 PR4635.2 ; PR4610.1 46.62,79.62 v2(46.65,79.65) ; Q6401.E 9.06,20.54 8.75,20.85 v2(8.45,20.85) ; PU5403.6 110.94,24.91 PC5410.1 110.3,24.94 v2(110.02,24.66) ; 157.27,91.08 162.01,91.08 163.62,92.68 v1(163.62,92.75) v2(163.62,94.07) ; v2(33.86,75.32) 33.9,75.35 FC8930.1 C5743.1 33.9,78.45 33.47,78.89 U5801.6 ; PR4813.2 57.52,77.36 56.38,78.5 v2(56.3,78.5) ; PR4803.2 57.49,88.54 FC8932.1 57.29,88.69 56.73,88.69 55.82,87.78 55.82,87.77 v2(55.2,87.15) 53.37,87.15 52.39,88.13 R4303.1 ; FC8934.1 170.75,99.04 172.27,97.53 172.99,97.53 v2(173.17,97.71) ; v2(52.11,62.76) 51.25,63.62 PC5112.1 51.5,64.15 PR5108.1 ; PR4704.2 v2(58.38,67.58)
  vias: v2(8.04,31.26) v2(8.75,31.34) v2(8.8,32.78) v3(66.13,1.54) v3(66.97,1.54) v3(67.86,1.54) v3(68.75,1.54) v3(69.76,1.54) v3(70.4,19.83) v3(70.4,18.94) v3(70.4,18.05) v3(70.4,17.16) v3(70.4,16.27) v3(70.4,15.39) v3(127.75,5.12)
5V_S5_EN: length 5
  TOP w0.254: v2(52.49,21.1) 52.62,21.1 53.25,21.74 PR4513.1 ; v2(52.49,21.1) PC4531.1 52.41,21.99 PR4504.2 ; v2(52.49,21.1) v1(52.49,20.49)
  BOTTOM w0.254: PU4502.12 52.68,20.79 52.49,20.97 v2(52.49,21.1)
19V_AD+: length 45.4
  L4SGND w0.508: v2(35.14,82.09) 35.93,81.3 35.93,75.43 35.39,74.89 35.39,64.56 32.94,62.11 32.93,62.11 32.86,62.03 29.82,62.03 26.84,59.05 25.18,59.05 21.27,55.15 v2(21.27,53.28)
  BOTTOM w0.508: R4311.1 21.25,47.69 PR4473.1 21.65,48.1 21.65,50.79 PD4408.1 21.35,51.1 21.35,53.21 v2(21.27,53.28) 21.44,53.45 PD4401.1
  vias: v1(35.57,81.6)
19V_AD_JK: length 66.2
  TOP w0.508: v2(43.32,86.03) v1(43.81,85.54) 44.35,85.01 Q4305.2
  L6 w0.508: v2(43.32,86.03) 40.3,83.01 40.3,77.74 39.45,76.89 39.45,70.59 31.61,62.76 24.08,62.76 23.58,62.26 23.58,57.93 24.05,57.46 24.05,55.86 21.91,53.71 21.91,49.31 21,48.4 20.95,48.4 19.22,46.67 19.22,44.71 21.5,42.43 21.5,38.75 v2(21.81,38.45)
  BOTTOM w0.508: R4376.1 21.63,38.55 21.73,38.45 v2(21.81,38.45)
19V_DCBATOUT: length 1.8
  BOTTOM w0.305: PG4402.1 41.9,59.71 42.2,59.4 42.2,59.2
  vias: v1(39.92,57.37) v3(41.57,57.8) v3(41.57,56.94) v3(41.57,56.1) v3(42.71,57.8) v3(42.71,56.94) v3(42.71,56.1)
19V_DCBATOUT_LCD:
  vias: v1(79.08,95.93)
20V_VCCPD_VBUS: length 18.1
  TOP w0.305: USB1.B4 6.67,68.94 USB1.A9 8.66,68.94 v3(9.21,68.39) ; USB1.B9 6.67,71.44 USB1.A4 8.67,71.44 v3(8.86,71.62)
  L4SGND w0.635: USB1.B9 7.26,71.54 ; USB1.B4 7.27,68.84
  BOTTOM w0.508: R7423.1 11.55,51.35 12.59,52.39 R7425.1 13.23,52.91 13.23,53.85 R7426.1 12.97,54.48 10.77,56.67 D7301.K
  BOTTOM w0.635: USB1.B4 7.29,68.84
  vias: v1(7.66,58.44) v1(10.2,60.6) v3(7.53,61.49) v3(8.42,61.36) v3(8.42,60.47) v3(8.42,59.58)
20V_VCCPD_VBUS_L: length 11.1
  L6 w0.508: v2(7.53,27.83) 7.16,28.2 7.16,31.28 7.51,31.62 7.51,35.81 v2(8.19,36.49)
  BOTTOM w0.508: R7216.1 R7217.1 8.04,28.34 v2(7.53,27.83)
  vias: v1(5.4,43.27) v1(5.35,39.36) v1(5.45,47.08) v1(5.65,50.79) v1(6.14,53.69) v1(6.57,56.96) v3(5.75,57.17) v3(5.75,56.28) v3(5.75,55.39) v3(6.52,55.89)
+5V_AVDD: length 5.2
  TOP w0.508: R2705.1 178.09,14.12 C2727.1 178.04,14.45 177.53,14.95 v2(177.43,14.95) v1(177.1,15.41)
  BOTTOM w0.203: U2701.40 176.68,15.83 177.43,15.08 v2(177.43,14.95)
  BOTTOM w0.508: v2(177.43,14.95) 177.84,14.55 C2721.1
+5V_PVDD: length 2.4
  BOTTOM w0.203: v2(174.05,15.46) 174.28,15.69 U2701.46 ; U2701.41 176.28,15.14 v2(176.39,15.03)
  vias: v1(175.35,15)
DVSS: length 4.6
  BOTTOM w0.102: U2701.13 172.67,22.28 171.44,21.05 v1(170.35,21.05) 170.17,21.23 R2746.2
GND: length 1651.4
  TOP w0.127: v2(125.59,67.28) 125.85,67.28 126.05,67.48 126.71,68.14 126.71,68.49 126.7,68.5 126.7,69.1 126.3,69.5 v2(126.3,69.54)
  TOP w0.178: v2(14.44,31.9) 14.44,32.35 U7201.A1 ; v2(14.96,37.64) 14.55,37.64 U7201.L1
  TOP w0.254: Q401.1 136.84,84.26 136.65,84.06 v2(136.61,84.06) ; v2(130.8,55.64) 130.95,55.8 EC1801.2 ; R305.2 130.1,72.62 v2(130.1,73.13) 130.1,73.36 C2213.2 ; v2(139.71,85.31) 139.71,85.36 139.17,85.91 Q401.4 ; v2(23.77,86.49) 23.76,86.49 23.76,86.48 U5701.E5 ; v2(5.91,66.64) 5.91,66.73 USB1.B1 6.62,67.44 USB1.A12 ; v2(125.11,55.57) 125.19,55.49 C1804.1 ; v2(26.19,88.11) U5701.B3 ; v2(126.3,69.54) 126.2,69.54 124.93,68.26 v2(124.93,68.01) 124.58,67.66 124.58,55.26 124.23,54.92 v2(124.23,53.85) 124.23,53.24 124.53,52.94 128.48,52.94 128.63,53.09 128.63,56.03 125.46,59.19 125.46,67.15 v2(125.59,67.28) ; U5701.E4 v2(23.78,87.3)
  TOP w0.305: C1255.2 C1257.2 ; v2(55.92,90.44) 55.84,90.37 EC8945.2 ; v2(35.37,90.24) 35.74,89.87 Q5705.4 ; PQ4405.4 26.38,35.57 26.71,35.24 26.71,34.41 26.85,34.27 PQ4405.1 ; R7122.1 12.09,67.12 v2(12.12,67.1) 12.87,67.1 13.02,66.95 ED7302.8 ED7302.3 ; v2(5.91,73.68) 5.91,73.65 USB1.B12 6.62,72.94 6.69,72.93 7.71,72.93 USB1.A1 8.47,72.94 8.6,73.07 8.68,73.07 v2(8.78,73.17) ; 184.16,46.2 U9102.32 ; Q5705.1 34.44,85.63 v2(34.84,85.24) ; v2(30.78,24.3) 31.46,24.3 U6402.3 ; ED5701.8 v2(13.7,84.73) ; U9102.16 180.66,51.93 179.11,53.49 v2(178.73,53.49) ; v3(54.65,84.73) 55.33,84.73 EC8909.2 ; C4003.1 71.21,21.81 EC8912.2 ; ED5703.8 13.73,91.2 13.48,91.46 v2(13.15,91.46) ; ED7301.3 ED7301.8 12.87,70.12 12.74,70 v2(12.49,70) 12.43,70.05 11.01,70.05 R7120.1 ; R1201.2 v2(52.97,39.87) ; v2(75.8,43.75) 75.66,43.6 C1234.2 ; PC4604.1 PC4610.1 ; v2(187.23,60.09) 187.24,60.09 187.24,60.09 186.33,59.18 Q1701.1 ; v2(12.94,88.08) 13.02,88.16 v2(13.78,88.16) ED5702.3 ED5702.8 ; U9102.23 179.65,47.92 179.58,47.85 179.54,47.85 179.24,47.54 v2(179.24,47.52) ; Q1701.4 v2(183.17,60.49) ; v2(131.79,54.88) 131.79,57.7 R1723.2 ; v2(34.59,3.32) DB3.4 ; ED6302.8 ED6302.3 v2(152.47,14.37)
  TOP w0.356: v2(24.78,39.41) 24.35,39.41 PQ4416.1 ; 36.03,84.47 36.47,84.03 U5703.3 ; v2(22.76,37.1) PQ4416.4 ; v2(24.93,36.37) 24.65,36.64 PR4474.1 ; PQ4405.4 25.91,35.9 v2(25.59,36.21) ; v2(21.39,84.91) U5701.G6 ; v2(21.39,87.28) 21.79,87.68 U5701.G3 ; U5701.D4 24.19,86.9 v2(24.58,86.5) U5701.D5 ; v2(25.39,84.9) U5701.B6
  TOP w0.406: v2(176.19,63.77) 176.4,63.99 U4002.5 ; C5508.1 103.16,98.21 v2(103.47,97.91)
  TOP w0.508: C1396.2 112.19,45.52 C1331.2 112.47,44.49 v2(113.01,43.96) ; 143.93,100.73 143.93,101.59 v2(143.85,101.67) ; v2(23.41,79.24) 23.51,79.34 R5757.1 R5734.2 ; v2(150.41,12.03) 150.07,12.03 149.67,11.63 149.67,10.94 149.92,10.69 R6313.2 ; 15.43,42.74 15.43,42.02 v2(15.53,41.91) ; v2(38.37,30.4) 37.66,30.4 36.49,29.23 DB1.16 ; C1306.2 138.31,43.6 v2(138.45,43.75) ; C1213.2 65.51,43.6 v2(65.65,43.75) ; C9112.1 183.3,52.72 182.41,53.61 v2(181.65,53.61) ; R403.1 134.84,83.21 134.82,83.19 v2(134.8,83.19) ; v2(33.57,19.45) 34.13,19.45 C2423.2 ; R2739.2 180.51,11.24 v2(180.99,11.73) ; PC4430.2 25.59,41.9 v2(25.34,41.65) ; C5765.2 C5767.2 30.47,81.22 v2(30.54,81.3) ; R2009.2 v2(150.92,82.64) ; v2(135.49,36.95) 135.49,36.13 C1324.2 135.57,36.05 v2(135.57,35.4) ; v2(112.59,20.39) 112.79,20.39 113.09,20.08 EC4310.2 ; HDMI1.21 13.25,95.77 ; HDMI1.21 11.92,96.76 ; HDMI1.21 11.92,94.78 ; R1334.2 136.79,41.59 C1307.2 137.41,41.62 v2(137.49,41.7) ; R2457.2 27.42,23.41 C2436.2 v2(27.42,22.07) ; C1203.2 62.85,34.77 v2(62.85,34.76) 62.85,35.06 62.77,35.14 v2(62.77,35.4) C1211.2 62.65,36.21 62.72,36.29 v2(62.72,36.98) ; C6306.2 191.86,4.97 v2(191.3,4.97) ; v2(72.05,39.7) 72.05,39.56 72.47,39.13 R1234.2 ; v2(143.3,43.76) 143.22,43.68 C1305.2 ; v2(90.46,13.35) 90.54,13.28 PR4530.2 ; v2(126.26,97.82) 125.32,97.82 EC8901.2 ; v2(60.51,43.96) 59.97,44.49 C1204.2 ; v2(18.28,62.15) 18.32,62.19 R7144.2 ; v2(177.71,68.9) 177.67,68.86 176.95,68.86 EC8921.2 ; C1210.2 53.68,37.2 v2(53.81,37.08) ; C1104.2 v2(95.37,79.82) ; v2(36.74,15.26) 36.49,15 DB1.15 ; v2(132.65,79.86) 132.69,79.9 C2211.2 133.64,79.9 133.8,80.05 R2118.2 ; v2(136.72,73.43) 136.73,73.43 136.83,73.53 R2114.2 ; X5701.4 21.68,78.9 21.9,79.11 v2(21.96,79.11) 21.98,79.14 C5729.2 ; v2(59.73,93.49) 59.14,94.07 FC8914.2 ; v2(184.47,15.66) 183.76,14.95 EC2714.2 ; v1(117.84,12.01) 117.79,12.06 v2(117.13,12.06) R4301.1 ; R6120.2 147.71,55.5 148.69,54.53 149.82,54.53 v2(150.05,54.76) 150.08,54.78 R6119.2 ; v2(61.77,30.68) 62.41,31.31 C1208.2 ; v2(145.8,34.76) 145.8,34.15 C1301.2 ; 13.7,73.11 H12.1 ; H12.1 10.51,76.3 ; H12.1 16.89,76.3 ; H12.1 13.7,79.49 ; v2(115.53,86) 115.53,86.2 115.2,86.53 R720.2 ; C4007.2 175.81,63.39 v2(176.19,63.77) ; C1209.2 60.64,40.84 v2(61.1,41.3) 60.67,41.72 C1265.2 ; C2517.2 187.97,65.9 188.13,66.06 188.5,66.43 188.51,66.44 v2(188.76,66.44) ; 2.39,97.67 HDMI1.23 ; HDMI1.23 3.72,98.66 ; HDMI1.23 5.59,97.67 v2(6.18,97.08) ; v2(155.64,29.3) 154.98,29.3 FC8905.2 EC8915.2 ; C7117.1 24.42,72.38 v2(24.83,72.79) ; v2(41.49,70.12) PC4621.1 41.57,70.83 PC4620.2 ; v2(82.99,36.95) 82.99,36.26 C1230.2 82.95,35.83 83.07,35.71 v2(83.07,35.4) 83.07,35.14 83.15,35.06 v2(83.15,34.76) 83.15,34.13 C1201.2 ; v2(167.6,43.35) 167.73,43.48 C6104.2 167.81,44.39 EC8919.2 ; C1236.2 73,34.77 v2(73,34.76) 73,35.06 72.92,35.14 v2(72.92,35.4) 72.92,35.77 72.8,35.9 C1217.2 72.84,36.26 v2(72.84,36.95) ; v2(21.94,44.15) 22.81,44.15 23,44.34 PR4426.2 ; EC8922.2 79.74,8.65 v2(80.68,8.65) ; C5766.2 v2(30.6,82.01) ; C1803.2 128.08,55.85 127.81,56.13 v2(127.81,56.13) ; v3(166.92,76.35) 166.74,76.17 FC8908.2 ; C1214.2 70.12,44.49 v2(70.66,43.96) ; C1259.2 91.12,41.72 v2(91.55,41.3) 91.09,40.84 C1226.2 ; v2(31.36,30.55) 31.92,29.99 C2429.2 C2410.2 32.35,28.82 32.7,28.47 R2611.2 ; v2(27.8,54.18) 27.98,53.99 PC4417.1 ; PC4866.2 64.12,74.95 v2(64.17,75) ; C1341.2 123.4,41.64 v2(123.75,41.3) 123.28,40.83 C1313.2 ; v2(35.45,33.8) 35.45,33.26 D4302.1 ; C1330.2 113.1,40.8 v2(113.6,41.3) 113.25,41.64 C1337.2 ; C1216.2 72.56,31.31 v2(71.92,30.68) ; v2(84.99,41.7) 84.94,41.65 C1220.2 83.65,41.62 R1214.2 ; v2(25.19,54.42) PC4416.1 ; C5749.2 17.54,90.9 16.93,91.51 v2(16.75,91.51) ; v2(180.13,67.2) 180,67.07 C4032.2 ; C1207.2 55.51,38.88 v2(55.5,38.89) ; v3(55.41,81.3) 55.33,81.22 EC8917.2 ; R7102.1 20.16,73.25 20.16,74.77 v2(20.08,74.85) ; v2(27.03,40.09) 27.13,40.09 27.73,39.49 PC4431.2 ; PR4608.1 54.5,76.22 54.9,75.81 v2(54.9,75.71) 54.65,75.46 PC4604.1 ; v2(135.46,78.64) 135.57,78.76 R2108.2 ; PC5117.2 49.42,50.27 v3(49.71,50.56) ; v2(23.36,53.28) 23.44,53.28 23.89,52.83 23.89,51.88 PC4419.2 ; R1555.2 136.03,59.02 136.26,59.25 v2(136.26,59.94) ; PC4640.2 49,65.22 48.43,65.8 PC4639.2 ; PC4640.2 49.19,64.08 FC8917.2 ; PC4640.2 49.85,65.22 v2(49.95,65.32) ; H13.1 132.42,10.53 v2(130.74,8.85) ; EC2901.2 13.96,3.24 v2(14.14,3.07) ; EC8903.2 96.46,97.35 v2(96,97.81) ; ED4306.1 v2(29.32,28.39) ; v2(90.59,75.93) 90.55,75.96 PC1063.2 PC1047.2 ; C5730.2 18.28,81.15 17.62,81.15 v2(17.51,81.04) ; R304.2 127.61,70.9 v2(128.1,70.9) ; C1205.2 55.36,43.6 v2(55.5,43.75) ; EC8913.2 62.22,64.66 v2(61.84,65.04) ; C7115.1 15.84,64.64 v2(15.44,65.04) ; C1229.2 80.94,40.84 v2(81.4,41.3) 80.97,41.72 C1268.2 ; v3(95.37,16.17) 94.7,15.51 R4006.2 93.92,15.49 C4009.2 ; C2744.2 172.78,23.77 172.28,24.28 ; C9106.2 188.15,47.62 v2(187.77,48) ; C5778.2 30.99,80.84 30.66,80.51 v2(30.6,80.51) 30.6,80.35 30.88,80.07 30.96,80.07 31.43,79.6 C5764.2 ; EC8943.2 166.99,69.56 v3(166.79,69.36) ; v2(50.18,21.13) 50.1,21.2 50.1,22.38 50.4,22.67 EC8911.2 ; v2(13.88,65.17) 13.68,64.97 13.56,64.97 13.17,64.58 R7123.1 ; v2(23.36,93.41) 23.36,93.34 23.53,93.17 23.53,93.11 R5741.2 ; EC2902.2 v2(15.48,3.32) ; C805.1 EC2201.2 126.15,81.35 v2(126.07,81.43) ; C1257.2 v2(48.2,37.61) ; C1327.2 132.8,44.47 v2(133.31,43.96) ; v2(132.9,84.45) 132.58,84.77 R1603.2 ; v2(134.57,30.68) 135.18,31.29 C1323.2 ; v2(85.95,43.75) 85.81,43.6 C1221.2 ; C1322.2 128.29,38.89 v2(128.3,38.89) ; v2(193.48,26.21) FSW1.5 ; v2(120.66,30.85) 120.66,31.06 120.16,31.56 C1335.2 ; v2(115.02,35.2) 115.23,35.4 C1332.2 115.23,36.86 115.19,36.9 v2(115.19,36.95) ; DB3.7 37.09,1.63 v2(36.21,0.76) ; v2(191.3,5.61) 191.56,5.86 C6308.2 ; C1392.2 117.34,44.67 C1316.2 118.01,43.6 v2(118.15,43.75) ; 7.52,74.99 USB1.13 6.25,75.83 ; R1601.2 131.94,84.41 v2(131.98,84.45) ; v2(129.2,84.45) 128.84,84.09 PC1072.2 128.84,82.42 v2(128.79,82.36) 129.15,82.01 C806.1 ; C2218.2 139.97,71.62 v2(140.36,71.23) ; C1325.2 133.43,40.83 v2(133.9,41.3) 133.43,41.77 C1346.2 ; v2(18.84,3.32) EC2904.2 ; v2(29.88,36.62) 29.79,36.62 29.46,36.29 PR4475.2 ; v2(177.1,42.99) 177.25,43.15 C6605.2 ; R1602.2 130.98,88.42 v2(130.7,88.7) ; PR4413.2 29.52,40.87 v2(30.52,40.87) PC4426.1 ; PC4435.2 v2(33.57,56.41) ; v2(126.68,36.95) 126.68,36.9 126.67,36.88 126.67,36.16 C1326.2 126.71,36.12 v2(126.71,35.4) ; 20.31,92.86 20.03,92.86 19.76,93.12 v2(19.76,93.39) 19.7,93.39 19.67,93.36 C5748.2 ; v2(172.25,24.28) 172.28,24.28 ; 172.28,24.28 172.46,24.28 172.97,24.78 C2745.2 ; v2(82.2,39.7) 82.21,39.7 R1205.2 ; R1204.2 62.32,39.13 61.9,39.56 v2(61.9,39.7) ; v2(187.24,70.12) 187.74,69.62 Q2510.S ; v2(114.4,39.7) 114.4,39.55 114.81,39.13 R1304.2 ; 6.25,64.55 USB1.14 7.52,65.39 ; v2(18.31,79.8) 18.55,79.8 18.58,79.82 19.06,79.82 X5701.2 ; PC4433.2 27.57,40.94 27.35,40.72 v2(27.01,40.72) ; v2(124.55,39.7) 124.55,39.52 124.96,39.11 R1305.2 ; C803.1 125.26,69.56 v2(125.38,69.45) ; DB1.3 39.84,16.85 40.17,16.53 v2(40.17,15.39) ; v2(63.41,35.4) C1218.2 63.44,36.19 63.44,36.69 63.39,36.74 v2(63.39,36.98) ; C1228.2 80.27,44.49 v2(80.81,43.96) ; v2(92.78,74.6) 92.79,74.59 PC1056.2 ; v2(39.28,35.07) 39.08,35.27 EC8910.2 39.08,36.67 38.52,37.23 v2(38.27,37.23) ; PC5124.2 53.15,49.22 v3(53.48,48.89) ; C1134.2 152.85,62.71 v2(152.43,63.12) ; C4003.1 v2(72.05,22.37) 72.1,22.42 FC8922.2 72.94,22.07 FC8935.2 ; v2(116.01,58.92) 116.5,58.92 C1132.2 C1131.2 ; v2(162.93,39.54) 162.93,38.6 163.54,37.99 FC8906.2 EC8916.2 ; 3.72,78.38 HDMI1.22 ; HDMI1.22 2.93,78.58 v2(2.93,78.15) ; HDMI1.22 5.05,79.37 ; HDMI1.22 4.71,78.38 ; v2(45.76,88.84) 44.98,88.07 Q4304.E ; C1222.2 90.42,44.49 v2(90.96,43.96) ; v2(176.06,58.18) 176.06,58.59 C4006.2 176.87,59.4 C4035.2 ; C501.2 138.11,55.29 ED1701.3 139.23,54.17 v2(139.23,53.76) 139.23,53.33 C1701.2 140.04,52.52 R1715.2 ; v2(145.72,35.4) 145.72,36.07 C1310.2 145.71,36.84 v2(145.64,36.9) 145.64,37.24 C1311.2 ; R7411.2 12.41,57.52 v2(12.99,56.94) ; EC6502.2 85.69,10.56 v2(85.64,10.51) ; v2(172.91,1.64) 172.33,2.23 PC5401.2 ; v2(65.65,38.89) 65.66,38.88 C1215.2 ; PC4532.2 92.34,16.32 PR4514.2 92.37,15.64 92.42,15.59 v2(92.42,15.51) ; v2(125.34,36.95) 125.34,36.9 125.41,36.84 C1312.2 125.42,36.08 v2(125.42,35.4) ; C1106.2 v2(99.28,79.82) ; v2(20.13,49.3) 20.96,49.3 PC4422.2 ; C1231.2 75.81,38.88 v2(75.8,38.89) ; C1315.2 122.62,44.49 v2(123.16,43.96) ; C1107.2 v2(97.35,79.82) ; FC8926.2 64.48,1.62 v2(64.68,1.42) ; C7301.2 v2(7,40.94) ; R1306.2 135.11,39.13 134.7,39.55 v2(134.7,39.7) ; C1336.2 125.18,33.14 v2(125.41,32.91) ; v2(83.71,35.4) 83.71,36.16 C1227.2 83.66,36.85 83.71,36.9 v2(83.71,36.95) ; R1525.2 139.18,56.91 v2(138.75,56.48) ; R7208.1 5.83,36.62 5.73,36.52 v2(5.73,36.11) ; EC5503.2 110.58,101.14 110.58,102.56 v2(110.25,102.89) ; EC8925.2 75.68,14.12 75.48,14.32 v2(75.48,14.62) ; v2(34.84,85.24) 35.04,85.03 C5777.1 36.03,84.8 36.03,84.47 ; EC8908.2 v2(50.84,66.19) 50.51,66.52 PC4633.2 ; C9108.2 185.64,45.08 v2(184.01,45.08) 184.01,45.84 184.16,45.99 184.16,46.2 ; v2(116.53,36.95) 116.53,36.18 C1319.2 116.56,36.15 v2(116.56,35.4) ; C6103.2 169.2,68.47 v3(169.33,68.6) ; v2(190.26,10.43) 190.77,9.92 C6317.2 ; FC8921.2 53.96,22.6 53.46,22.6 PR4513.2 52.52,22.8 PC4531.2 v2(52.49,23.51) ; v2(21.27,46.75) 21.07,46.96 PR4417.1 ; EC2903.2 v2(16.22,3.45) ; v2(126.15,76.55) C2223.2 125.36,76.7 C1128.2 ; R1212.2 53.85,41.59 C1206.2 54.46,41.62 v2(54.54,41.7) ; 2.02,76.9 USB1.15 ; v2(144.72,30.68) 145.36,31.31 C1309.2 ; PC4421.2 34.66,49.98 v2(34.79,49.85) ; v2(118.15,38.89) 118.15,38.89 C1314.2 ; FSW1.7 v2(193.4,33.51) FSW1.6 ; C2501.2 143.65,57.27 142.88,57.27 142.83,57.21 v2(142.79,57.21) ; R1332.2 116.49,41.59 C1317.2 117.11,41.62 v2(117.19,41.7) ; v2(52.72,58.79) 52.82,58.9 FC8918.2 ; 2.83,63.65 2.09,64.39 USB1.16 ; v2(108.34,102.89) 108.34,101.85 108.17,101.67 EC5504.2 108.12,101.06 R5501.2 R5510.2 106.37,100.14 105.81,99.59 C5503.2 105.02,99.26 FC5502.2 EC8904.2 v2(105.68,97.91) ; v2(127.34,41.7) 127.24,41.6 C1320.2 126.64,41.56 R1333.2 ; 13.25,81.27 HDMI1.20 11.92,80.28 ; R7407.2 23.05,56.03 v2(23.42,56.39) ; v2(136.83,36.95) 136.61,37.17 C1308.2 ; R1213.2 63.35,41.59 C1212.2 63.96,41.62 v2(64.04,41.7) ; v2(22.01,17.02) 22.02,17.02 22.29,17.29 23.36,17.29 EC2402.2 ; v2(24.47,76.24) 24.6,76.37 R5763.2 ; v2(80.68,8.65) FC8936.2 ; v2(80.68,8.65) 80.68,9.09 C6505.2 ; v2(34.1,41.61) 34.1,42.31 PC4424.1 ; R6304.2 191.56,15.13 192.06,14.62 192.06,13.99 192.48,13.57 193.3,13.57 v2(193.59,13.86) ; C1103.2 97.28,75.25 v2(97.28,75.26) ; v2(30.47,39.92) 30.32,40.07 PC4432.2 ; R1516.2 161.94,55.64 162.22,55.92 v2(162.35,55.92) ; C1321.2 128.13,43.58 v2(128.3,43.75) ; v2(26.45,41.12) 26.45,41.29 26.43,41.32 PR4410.1 ; R317.2 v2(102.28,86.65) ; ED4305.1 25.2,30.63 v2(24.42,30.63) ; v2(63.12,66.54) 63.12,67.01 FC8916.2 ; FC8915.2 61.46,78.62 v2(62.99,77.09) ; C5507.1 C5508.1 ; C1303.2 134.99,33.22 v2(135.27,32.94) ; v2(28.51,92.8) 27.92,92.8 R5733.1 ; v2(38.65,11.47) 38.65,11.45 38.8,11.3 FC8941.2 ; EC8914.2 107.91,24.71 v3(107.99,24.78) ; v2(73.56,36.95) 73.51,36.9 C1233.2 73.56,36.16 v2(73.56,35.4) ; v2(151.17,22.62) 151.27,22.52 C6323.2 152.39,22.32 C6321.2 C6322.2 ; R2518.2 183.32,61.99 183.31,62.01 v2(183.05,62.01) ; PC4877.2 64.12,85.31 v2(64.17,85.36) 64.25,85.44 v1(64.76,85.44) ; C1318.2 125.06,31.31 v2(124.42,30.68) ; FC8910.2 v2(40.58,49.19) ; C6401.2 v2(34.58,23.51) ; v2(85.95,38.89) 85.96,38.88 C1225.2 ; R601.2 108.42,86.3 108.04,85.92 v2(108.04,85.9) ; v2(184.24,22.83) 183.88,23.18 EC2711.2 ; C1219.2 70.79,40.84 v2(71.25,41.3) 70.82,41.72 C1262.2 ; R1553.2 133.52,57.24 v2(133.92,56.84) ; C1114.2 v2(128.13,75.63) ; v2(92.75,22.07) 92.39,21.71 FC8923.2 ; R1215.2 73.5,41.59 C1235.2 74.09,41.62 v2(74.17,41.7) ; C9109.2 175.81,46.73 v2(175.81,47.9) 175.85,47.85 176.57,47.85 C9113.2 ; C1351.2 143.65,41.69 v2(144.05,41.3) 143.58,40.83 C1304.2 ; v2(61.25,62.38) 60.87,61.99 PC5118.2
  L2SGND w0.381: HDMI1.11 11.06,89.02 ; HDMI1.8 12.05,87.8 12.66,87.8 v2(12.94,88.08) ; HDMI1.17 10.89,92.02 ; HDMI1.5 10.94,86.02
  L2SGND w0.457: 8.24,72.51 7.05,72.51 USB1.B12 5.91,73.65 v2(5.91,73.68) ; v2(5.91,66.64) 5.91,66.73 USB1.B1 7.07,67.89 7.68,67.89
  L2SGND w0.508: HDMI1.2 12.41,84.52 ; HDMI1.2 11.13,84.52 ; HDMI1.2 11.77,83.94 ; HDMI1.21 11.92,96.76 ; HDMI1.21 11.92,94.78 ; HDMI1.21 13.25,95.77 ; 5.05,79.37 HDMI1.22 3.72,78.38 ; 2.02,76.83 USB1.15 3.35,75.99 ; HDMI1.23 5.05,97.67 ; HDMI1.23 2.39,97.67 ; HDMI1.23 3.72,98.66 ; 11.92,80.28 HDMI1.20 ; HDMI1.20 11.92,82.26 ; HDMI1.20 13.25,81.27 ; 6.25,75.83 USB1.13 7.52,74.99 ; USB1.16 2.09,64.39 3.09,63.39 ; H12.1 15.52,76.3 ; H12.1 13.7,78.12 ; H12.1 11.88,76.3 ; H12.1 13.7,74.48 ; 7.52,65.39 USB1.14 6.25,64.55
  L3SGND w0.381: HDMI1.8 12.05,87.8 12.66,87.8 v2(12.94,88.08) ; HDMI1.17 10.89,92.02 ; HDMI1.5 10.94,86.02 ; HDMI1.11 10.94,89.02
  L3SGND w0.457: 7.22,68.04 USB1.B1 5.91,66.73 v2(5.91,66.64) ; 6.97,72.59 USB1.B12 5.91,73.65 v2(5.91,73.68)
  L3SGND w0.508: HDMI1.21 11.92,96.76 ; HDMI1.21 13.25,95.77 ; HDMI1.21 11.92,94.78 ; HDMI1.20 11.92,82.26 ; HDMI1.20 13.25,81.27 ; HDMI1.20 11.92,80.28 ; 13.7,74.48 H12.1 ; H12.1 15.52,76.3 ; H12.1 13.7,78.12 ; H12.1 11.88,76.3 ; USB1.15 1.06,76.95 v2(0.78,76.95) ; USB1.15 2.02,76.83 ; USB1.15 3.35,75.99 ; HDMI1.23 5.05,97.67 ; HDMI1.23 3.72,98.66 ; HDMI1.23 2.39,97.67 ; 7.52,74.99 USB1.13 6.25,75.83 ; HDMI1.2 12.41,84.52 ; HDMI1.2 11.13,84.52 ; HDMI1.2 11.77,83.94 ; 3.72,78.38 HDMI1.22 5.05,79.37 ; 7.52,65.39 USB1.14 6.25,64.55 ; 3.39,63.11 2.11,64.39 USB1.16
  L4SGND w0.381: HDMI1.5 11.19,86.02 ; HDMI1.8 12.05,87.8 12.66,87.8 v2(12.94,88.08) ; HDMI1.11 11.06,89.02 ; HDMI1.17 10.89,92.02
  L4SGND w0.457: v2(5.91,73.68) 5.91,73.65 USB1.B12 6.77,72.79 8.29,72.79 ; v2(5.91,66.64) 5.91,66.73 USB1.B1
  L4SGND w0.508: USB1.15 2.02,76.83 ; USB1.15 3.35,75.99 ; USB1.15 1.06,76.95 v2(0.78,76.95) ; 11.88,76.3 H12.1 ; H12.1 13.7,78.12 ; H12.1 13.7,74.48 ; 5.05,79.37 HDMI1.22 3.72,78.38 ; HDMI1.2 12.41,84.52 ; HDMI1.2 11.77,83.94 ; HDMI1.2 11.13,84.52 ; HDMI1.23 3.72,98.66 ; HDMI1.23 5.05,97.67 ; HDMI1.23 2.39,97.67 ; 6.25,64.44 USB1.14 5.91,65.73 v2(5.91,66.64) ; HDMI1.20 13.25,81.27 ; HDMI1.20 11.92,80.28 ; HDMI1.20 11.92,82.26 ; HDMI1.21 13.25,95.77 ; HDMI1.21 11.92,94.78 ; HDMI1.21 11.92,96.76 ; 3.34,63.16 2.11,64.39 USB1.16 ; 6.25,75.83 USB1.13 7.52,74.99
  L6 w0.381: HDMI1.11 10.94,89.02 ; HDMI1.5 11.07,86.02
  L6 w0.406: v2(5.91,66.64) 5.91,66.73 USB1.B1 ; v2(5.91,73.68) 5.91,73.65 USB1.B12 7.03,72.54
  L6 w0.508: 11.88,76.3 H12.1 ; H12.1 13.7,74.48 ; H12.1 13.7,78.12 ; H12.1 15.52,76.3 ; v2(12.94,88.08) 12.49,88.08 11.93,87.52 HDMI1.8 11.09,87.52 ; 7.52,65.39 USB1.14 6.25,64.55 ; HDMI1.23 3.72,98.66 ; HDMI1.23 2.39,97.67 ; HDMI1.23 5.05,97.67 ; HDMI1.21 13.25,95.77 ; HDMI1.21 11.92,96.76 ; HDMI1.21 11.92,94.78 ; 11.92,82.26 HDMI1.20 11.92,80.28 ; USB1.15 3.35,75.99 ; USB1.15 1.74,75.99 v2(0.78,76.95) ; USB1.15 2.02,76.83 ; 5.05,79.37 HDMI1.22 3.72,78.38 ; HDMI1.2 12.41,84.52 ; HDMI1.2 11.13,84.52 ; HDMI1.2 11.77,83.94 ; USB1.16 2.09,64.39 3.34,63.14 ; 6.25,75.83 USB1.13 7.52,74.99
  BOTTOM w0.09: CPU1.B29 93.51,70.55 v2(93.51,70.55)
  BOTTOM w0.102: v2(109.09,63.99) 109.17,64.08 CPU1.AF36 ; CPU1.AP36 114.2,64.77 114.37,64.61 114.37,62.27 113.78,61.69 v2(113.52,61.69) ; v2(92.2,67.88) 92.2,68.52 92.67,68.99 93.1,68.99 93.41,69.3 94.72,69.3 CPU1.B31 ; CPU1.BD36 120.5,64.73 v2(120.48,64.71) ; v2(106.65,63.39) 106.65,64.18 106.63,64.2 106.63,65.51 106.65,65.57 CPU1.AB36 ; v2(120.31,60.34) 120.05,60.34 119.24,61.16 CPU1.BB36 ; CPU1.CL2 136.59,87.57 136.59,87.24 136.23,86.88 136.13,86.88 ; CPU1.B27 93.82,71.81 v2(93.62,72.01) ; CPU1.AV36 116.72,65.57 116.74,65.52 116.74,62.39 v2(115.95,61.61) ; CPU1.BF36 121.75,63.46 v2(122.08,63.13)
  BOTTOM w0.127: CPU1.J36 99.1,65.05 98.84,64.79 v2(98.84,64.63) ; CPU1.CF4 CPU1.CF3 CPU1.CF2 v2(133.81,88.84) ; CPU1.G36 CPU1.G35
  BOTTOM w0.152: CPU1.BP3 CPU1.BP4 ; v2(140.36,71.23) 139.5,71.23 138.91,71.82 CPU1.CP27 ; CPU1.V36 104.12,65.85 104.12,64.78 v2(103.9,64.56) ; v2(115.46,67.26) 115.46,67.26 CPU1.AT35 CPU1.AT36 ; v2(103.09,65.17) 103.01,65.26 103.01,65.83 CPU1.T36 CPU1.T35
  BOTTOM w0.178: v2(140.2,78.96) 139.75,79.41 139.16,79.41 138.83,79.41 138.81,79.38 CPU1.CP15 ; PU5101.4 53.85,58.87 54.55,58.18 v2(54.68,58.18) ; CPU1.CP11 139.61,81.9 v2(139.81,81.7)
  BOTTOM w0.18: v2(101.6,64.58) 101.62,64.58 CPU1.P36 ; CPU1.B23 94.18,74.33 93.05,74.33 v2(92.78,74.6) ; v2(111.85,64.28) 111.82,64.31 111.82,65.73 CPU1.AK36
  BOTTOM w0.2: CPU1.B25 CPU1.C25 CPU1.D25 ; CPU1.C29 CPU1.B29
  BOTTOM w0.203: CPU1.V30 103.68,70.12 v2(103.52,70.12) 103.33,70.12 CPU1.T30 ; v2(30.09,15.54) 30.14,15.49 U2401.84 30.14,13.05 C2420.2 ; CPU1.CJ33 135.38,67.99 135.01,67.99 134.85,67.82 CPU1.CG33 134.08,68.08 v2(133.74,68.08) 133.34,68.08 CPU1.CE33 CPU1.CE35 133.08,66.19 133.07,66.14 133.08,66.11 CPU1.CE36 ; CPU1.AT33 115.46,67.27 v2(115.46,67.26) ; v2(40.17,15.39) 39.97,15.59 U2401.64 ; v2(124.47,71.44) 124.62,71.44 CPU1.BL28 ; v2(110.81,71.47) 110.92,71.47 CPU1.AJ28 ; CPU1.AU29 CPU1.AU28 CPU1.AR28 ; v2(136.49,69.44) 136.49,69.44 136.49,69.46 136.62,69.33 CPU1.CM31 ; CPU1.CM33 136.88,68.24 136.51,68.24 136.46,68.19 v2(136.46,68.22) ; CPU1.AL29 CPU1.AL28 111.97,71.14 v2(111.67,70.84) ; CPU1.BY28 130.59,71.14 130.81,70.92 130.81,70.92 v2(130.84,70.88) ; 117.25,70.76 117.37,70.76 CPU1.AW29 CPU1.AW30 CPU1.AW31 ; 117.25,70.76 v2(117.18,70.76) ; 117.25,70.76 CPU1.AW28 ; CPU1.E35 96.43,66.8 96.28,66.95 v2(96.25,66.95) ; PU5101.32 53.87,57.1 v2(53.63,56.86) ; PU5101.4 52.87,58.87 52.79,58.79 v2(52.72,58.79) ; CPU1.CP35 138.86,67.28 138.95,67.28 138.97,67.3 CPU1.CR34 139.26,67.3 139.46,67.1 v2(139.46,67.02) ; v2(31.36,30.55) 31.53,30.55 31.73,30.35 U2401.17 ; v2(128.1,70.9) 128.09,70.9 127.85,71.14 CPU1.BT28 ; CPU1.AV25 v2(116.72,73.6) ; U2401.100 23.26,16.79 22.75,17.29 22.29,17.29 22.02,17.02 v2(22.01,17.02) ; v2(135.4,69.49) 135.1,69.19 CPU1.CH31 ; CPU1.CM37 CPU1.CN37 ; v2(124.04,88.99) CPU1.BK2 124.04,87.69 124.04,87.69 124.04,87.2 CPU1.BK3 CPU1.BK4 ; CPU1.BD28 CPU1.BE28 ; CPU1.R28 102.07,71.14 ; CPU1.CC31 132.31,69.19 v2(132.68,69.56) ; v2(117.92,67.12) 117.92,67.3 117.98,67.36 CPU1.AY33 118.05,67.89 119.17,67.89 CPU1.BB33 119.27,67.85 119.27,68.35 CPU1.BC32 119.75,68.25 v2(119.75,68.12) 120.04,67.82 CPU1.BD33 ; CPU1.BC25 v2(119.45,73.63) ; CPU1.BN30 126,69.84 v2(126.3,69.54) ; 126.52,67.85 125.55,67.85 CPU1.BM33 ; CPU1.BD36 CPU1.BD35 120.36,66.75 v2(120.36,67.28) 120.36,67.68 CPU1.BD33 ; CPU1.BE29 CPU1.BE30 CPU1.BE31 ; CPU1.CC28 132.32,71.14 v2(132.67,71.49) ; CPU1.CB33 131.47,67.82 131.28,68.01 v2(131.13,68.01) 130.93,67.82 CPU1.BY33 CPU1.BY35 CPU1.BY36 ; CPU1.AH29 CPU1.AH28 ; PU5101.30 54.94,57.92 v2(54.68,58.18) ; CPU1.CJ35 135.6,66.33 135.61,66.32 135.61,66.05 135.6,66.05 CPU1.CJ36 135.6,65.88 135.94,65.55 CPU1.CK37 136.09,65.54 136.31,65.33 v2(136.31,65.04) ; v2(97.08,70.16) 96.68,69.76 CPU1.E31 ; U2401.124 24.6,26.39 v2(24.96,26.74) ; CPU1.P33 101.53,67.91 100.45,67.91 CPU1.L33 ; U4001.11 v2(72.05,22.37) ; CPU1.CF28 134.17,71.14 v2(134.48,70.83) ; CPU1.L36 CPU1.L35 v2(100.36,67.15) CPU1.L33 ; CPU1.L33 100.18,67.82 v2(99.89,68.12) ; CPU1.BD33 v2(120.87,68.19) 121.38,68.19 CPU1.BF33 ; CPU1.K30 99.4,69.84 CPU1.K29 ; U2401.51 38.07,20.79 v2(37.76,21.1) ; CPU1.BH29 123.24,70.49 123.53,70.78 v2(123.58,70.78) ; CPU1.BV31 129.76,69.47 v2(129.91,69.47) ; CPU1.CN29 CPU1.CM29 136.61,70.56 136.51,70.66 v2(136.44,70.66) 136.31,70.78 136.22,70.78 CPU1.CJ28 ; CPU1.BK28 123.94,71.14 v2(123.58,70.78) ; v2(123.58,70.78) 123.23,71.14 CPU1.BH28 ; CPU1.AN25 v2(113.99,73.73) ; CPU1.BH33 123.1,67.91 CPU1.BH32
  BOTTOM w0.254: v2(106.11,83.89) 105.82,84.18 CPU1.Y7 ; CPU1.BT15 128.11,79.13 128.11,79.04 v2(128.13,79.02) 128.13,79 128.46,78.67 CPU1.BU16 ; CPU1.BT15 127.48,79.11 v2(127.48,78.99) 127.48,78.92 CPU1.BT16 ; CPU1.BT15 127.57,79.67 127.57,80.04 CPU1.BT14 ; CPU1.BP36 126.71,65.79 126.71,65.12 v2(126.63,65.04) ; v2(97.17,88.41) 97.19,88.39 CPU1.F2 CPU1.F3 97.19,86.64 CPU1.F4 ; v2(118.11,84.54) 118.28,84.54 CPU1.BA6 ; v2(128.13,75.63) 128.13,75.75 CPU1.BU20 ; CPU1.BR19 127.01,77.06 126.65,77.06 CPU1.BP19 126.15,76.56 v2(126.15,76.55) ; CPU1.BT33 CPU1.BT35 CPU1.BT36 ; CPU1.BT33 127.82,68.05 v2(127.24,68.05) ; CPU1.BT33 128.39,67.82 128.59,68.01 128.74,68.01 128.76,67.99 v2(128.77,67.99) 128.77,67.99 128.79,68.01 129.11,68.01 CPU1.BV33 ; v2(125.38,69.45) 124.99,69.84 124.96,69.84 ; v2(125.38,69.45) 125.38,69.43 125.39,69.42 125.39,68.92 125.01,68.54 CPU1.BL32 124.92,68.02 v2(124.93,68.01) ; v2(125.38,69.45) 125.12,69.19 CPU1.BL31 ; CPU1.CK4 136.41,86.36 CPU1.CM4 137.09,86.33 CPU1.CM5 138.07,85.64 CPU1.CN5 ; CPU1.CK4 136.24,86.13 136.57,85.8 v2(136.58,85.8) ; CPU1.CK4 136.2,86.23 CPU1.CJ4 CPU1.CJ3 ; CPU1.V26 104.87,71.8 CPU1.W27 ; CPU1.V26 104.42,72.25 CPU1.V27 103.66,71.49 v2(103.5,71.49) ; CPU1.V26 CPU1.Y26 105.78,71.8 CPU1.Y27 CPU1.AB27 ; CPU1.BY22 130.46,75.18 131,75.18 CPU1.CA22 131.38,75.56 v2(131.38,75.66) ; CPU1.CD20 133.01,76.09 v2(133.39,76.47) 133.44,76.52 133.44,76.68 CPU1.CF19 ; CPU1.BW15 129.76,79.32 v2(130.06,79.01) 130.06,79.09 CPU1.BY15 130.71,79.13 v2(130.71,79.01) 131.06,79.36 CPU1.CA15 ; v2(113.53,68.04) 113.31,67.82 CPU1.AM33 ; v2(113.53,68.04) 113.53,68.73 CPU1.AN31 CPU1.AN30 113.96,69.86 113.96,70.47 CPU1.AN29 113.84,70.49 v2(113.5,70.83) ; v2(113.53,68.04) 113.75,67.82 CPU1.AP33 ; v2(124.93,68.01) 124.98,68.01 125.18,67.82 CPU1.BM33 125.59,67.76 v2(125.59,67.28) 125.53,67.22 CPU1.BM35 CPU1.BM36 ; v2(124.93,68.01) 124.74,67.82 CPU1.BK33 123.82,67.82 CPU1.BH32 ; CPU1.AM35 CPU1.AM33 ; CPU1.AM33 112.72,67.82 v2(112.47,68.07) ; v2(89.09,20.37) 89.32,20.59 PU4501.18 ; CPU1.D8 96.53,83.86 96.79,84.11 v2(96.79,84.14) ; CPU1.AY33 117.89,67.91 116.81,67.91 CPU1.AV33 116.53,67.82 CPU1.AU32 115.46,68.19 CPU1.AT33 ; CPU1.CJ14 135.79,80.34 v2(136.18,80.74) 136.22,80.7 136.59,80.7 136.69,80.7 136.69,80.69 136.74,80.64 CPU1.CM13 CPU1.CN13 CPU1.CP13 ; CPU1.AW1 v2(117.38,88.86) ; v2(97.17,68.24) 96.84,68.24 CPU1.E33 96.15,68.08 v2(96.1,68.03) CPU1.C33 95.14,67.7 CPU1.B34 ; v2(97.17,68.24) 97.17,68.24 97.24,68.17 97.43,68.17 97.77,67.82 97.88,67.82 CPU1.G33 ; v2(97.17,68.24) 97.17,67.76 CPU1.F33 96.81,67.3 CPU1.E35 ; CPU1.J6 99.27,84.73 99.99,84.73 CPU1.L6 100.45,85.18 v2(100.57,85.18) 100.66,85.18 CPU1.N6 101.49,84.36 v2(101.49,83.89) ; CPU1.CB18 132.02,78.07 132.02,78.15 v2(132.02,78.15) 132.02,78.26 CPU1.CC16 ; v2(122.75,84.45) 122.92,84.45 CPU1.BJ7 ; v2(172.07,105.58) 171.36,104.87 FC8913.2 ; CPU1.CP9 CPU1.CN9 CPU1.CM9 136.61,83.64 v2(136.61,84.06) 136.5,84.18 CPU1.CK7 ; CPU1.BH33 123.05,67.78 v2(123.05,67.12) 123.05,66.66 CPU1.BH35 ; v2(131.38,73.96) 131.38,73.88 CPU1.CB24 CPU1.CC24 ; CPU1.CC24 CPU1.CD24 133.43,73.56 CPU1.CF23 133.51,74.28 v2(133.51,74.39) ; CPU1.CC24 CPU1.CC25 ; v2(103.5,71.49) CPU1.U26 CPU1.U24 ; v2(103.5,71.49) 103.35,71.49 CPU1.T27 ; CPU1.CC25 CPU1.CB25 CPU1.CA25 131.06,72.83 v2(130.74,73.14) 130.74,73.05 CPU1.BY25 130.1,73.02 v2(130.1,73.13) 129.76,73.48 CPU1.BW24 ; CPU1.CC25 CPU1.CD25 ; PU4502.18 54.93,18.43 v2(55.28,18.79) ; v2(104.71,82.01) CPU1.W10 ; CPU1.AV3 116.72,86.89 v2(116.9,86.71) ; v2(75.48,14.62) 76.09,14.01 R6508.2 ; CPU1.AU10 v2(115.8,82.08) ; CPU1.AC5 107.48,85.49 107.86,85.87 108.01,85.87 v2(108.04,85.9) ; CPU1.CJ33 135.85,68.12 136.36,68.12 v2(136.46,68.22) ; Q1702.4 136.53,50.68 v2(136.18,51.02) ; CPU1.T33 103.15,67.82 v2(103.42,68.09) 103.69,67.82 CPU1.V33 104.33,68.01 v2(104.92,68.01) 105.11,67.82 CPU1.Y33 CPU1.Y35 ; CPU1.BW11 129.76,82.03 v2(130.09,82.36) ; v2(113.5,70.83) 113.19,71.14 CPU1.AM28 ; v2(113.5,70.83) 113.81,71.14 CPU1.AN28 ; CPU1.AV8 116.61,83.53 v2(116.29,83.84) ; CPU1.BL7 124.76,84.45 v2(124.55,84.45) 124.38,84.45 CPU1.BK7 ; CPU1.CP37 138.58,65 v2(138.57,64.99) ; CPU1.CP37 CPU1.CR36 ; CPU1.CP37 CPU1.CN37 v2(137.93,65.02) ; CPU1.CE7 133.17,84.18 v2(132.9,84.45) 132.63,84.18 CPU1.CC7 ; CPU1.C9 95.47,82.8 v2(95.34,82.67) 94.84,83.16 CPU1.B9 ; v2(96.64,73.22) 96.48,73.07 CPU1.D25 ; v2(118.1,70.76) 118.12,70.76 118.17,70.81 118.21,70.81 CPU1.BA28 ; CPU1.K3 99.63,86.79 v2(99.53,86.68) 99.63,86.58 CPU1.K4 ; v2(103.33,83.89) 103.15,83.89 CPU1.T7 ; v2(137.33,88.68) 137.33,89.4 v2(138.74,90.81) 138.74,92.28 139.51,93.06 139.76,93.06 v2(140.5,93.79) 141.16,94.46 v2(141.16,96.33) 140.2,97.3 136.58,97.3 v2(135.93,96.64) 135.57,96.28 135.57,94.77 136.21,94.13 136.21,92.92 136.57,92.56 136.57,91.85 R1803.2 136.74,91.25 v2(136.74,90.72) 136.19,90.17 136.19,88.8 v2(136.28,88.71) CPU1.CK1 136.28,88.13 135.68,87.53 CPU1.CJ2 CPU1.CJ3 ; CPU1.G33 97.84,67.78 CPU1.G35 ; CPU1.G33 98.25,67.82 98.3,67.86 98.6,67.86 98.65,67.82 CPU1.J33 99.56,67.82 99.85,68.12 v2(99.89,68.12) 99.46,68.54 CPU1.K32 99.43,68.57 99.43,69.16 CPU1.K31 99.4,69.31 99.4,69.31 99.4,69.79 99.4,69.79 CPU1.K30 ; CPU1.E9 97.03,83.07 v2(97.33,82.77) ; v2(131.98,84.45) 131.71,84.18 CPU1.CB7 ; CPU1.AH30 CPU1.AH31 110.23,69.19 109.87,68.83 109.87,68.16 109.79,68.09 ; CPU1.AH30 CPU1.AF30 109.17,70.1 108.98,70.1 v2(108.95,70.12) 108.93,70.1 108.77,70.1 CPU1.AE30 108.27,70.09 107.86,70.09 CPU1.AC30 107.35,70.1 106.97,70.1 106.72,69.84 CPU1.AB30 106.49,69.64 105.98,69.64 CPU1.Y30 105.43,70.2 v2(105.32,70.2) 105.23,70.2 CPU1.W30 104.51,70.2 v2(104.41,70.2) 104.32,70.2 CPU1.V30 ; CPU1.AH30 110.3,69.88 110.3,70.45 CPU1.AH29 ; v2(136,76.62) 136,76.62 136,76.86 CPU1.CJ19 ; v2(114.44,71.47) 114.57,71.47 CPU1.AR28 ; CPU1.A36 94.86,66 CPU1.B36 CPU1.C36 95.68,65.71 CPU1.C37 ; CPU1.CC11 132.65,81.66 v2(132.65,81.54) 132.66,81.53 132.66,81.46 CPU1.CD12 ; CPU1.BL25 124.92,73.46 v2(124.78,73.6) ; CPU1.AD33 107.5,67.82 107.25,68.06 v2(107.18,68.06) 106.9,68.06 CPU1.AB33 ; CPU1.AD33 108.32,67.82 108.8,68.29 v2(108.98,68.29) 109.17,68.1 CPU1.AF33 109.18,67.81 109.54,67.81 109.79,68.06 109.79,68.09 ; CPU1.AD33 CPU1.AD35 ; 136.13,86.88 CPU1.CJ3 ; CPU1.AN8 113.81,83.53 113.55,83.79 113.55,83.86 v2(113.55,83.86) 113.55,83.86 113.55,83.92 113.81,84.18 CPU1.AN7 ; CPU1.BL30 124.96,69.84 ; 124.96,69.84 124.96,69.84 124.96,70.45 CPU1.BL29 124.98,70.55 124.98,71.08 CPU1.BL28 ; CPU1.BY18 130.09,77.44 v2(130.09,77.34) 130.09,77.23 CPU1.BY19 ; CPU1.BN7 126.26,83.88 v2(126.47,83.88) 126.48,83.88 126.48,83.88 126.49,83.89 126.59,83.89 CPU1.BP7 ; CPU1.P4 102.28,86.39 v2(102.28,86.65) 102.28,86.99 CPU1.P3 ; CPU1.V3 104.52,86.79 v2(104.41,86.68) 104.52,86.58 CPU1.V4 ; CPU1.AK4 111.98,86.32 v2(111.98,86.68) 111.98,87.06 CPU1.AK3 ; CPU1.K22 99.3,75.1 v2(99.3,75.25) ; CPU1.BC29 119.16,70.78 v2(119.01,70.78) ; CPU1.N27 101.07,71.79 v2(100.78,71.49) ; CPU1.N27 CPU1.N25 ; CPU1.N27 101.42,71.79 v2(101.69,71.52) 101.96,71.79 CPU1.R27 ; v2(136.72,73.43) 136.72,73.43 136.73,73.42 136.74,73.42 CPU1.CM25 CPU1.CN25 ; CPU1.CC14 132.36,80.14 132.64,79.86 v2(132.65,79.86) 133.01,80.22 CPU1.CD14 133.09,80.19 CPU1.CF14 ; v2(93.9,68.33) 94.2,68.63 CPU1.A32 ; CPU1.AF3 CPU1.AF4 v2(109.8,85.78) 109.95,85.78 CPU1.AG5 ; v2(136.05,74.57) 136.05,74.44 135.79,74.17 CPU1.CJ23 ; CPU1.AP4 114.12,86.19 113.78,85.84 113.39,85.84 CPU1.AM5 112.76,85.74 112.58,85.74 v2(112.56,85.72) ; CPU1.E27 96.79,71.7 97.49,71.7 CPU1.G27 CPU1.H27 CPU1.K27 CPU1.K28 99.55,71.14 v2(99.86,70.83) 99.75,70.83 CPU1.K29 ; CPU1.BP4 126.65,86.19 126.99,85.85 127.29,85.85 v2(127.38,85.76) 127.53,85.76 CPU1.BT5 128.04,85.48 v2(128.27,85.7) 128.41,85.85 128.58,85.85 CPU1.BV4 CPU1.BV3 ; CPU1.BG4 122.26,86.17 v2(121.81,85.72) 121.6,85.92 CPU1.BF4 ; v2(102.4,83.9) 102.12,84.18 CPU1.P7 ; CPU1.BB3 119.34,87.01 v2(119.34,86.71) ; v2(120.92,83.84) 121.23,83.53 CPU1.BE8 ; CPU1.BC8 119.62,83.53 119.9,83.81 v2(119.9,83.86) 119.9,83.89 120.19,84.18 CPU1.BD7 CPU1.BD6 ; CPU1.AH28 110.67,71.47 v2(110.81,71.47) 110.49,71.79 CPU1.AH27 ; CPU1.AH35 CPU1.AH33 110.42,67.81 110.04,67.81 110.04,67.84 109.79,68.09 ; CPU1.AT4 115.5,86.03 v2(115.53,86) ; v2(131.39,82.36) 131.06,82.03 CPU1.CA11 ; CPU1.CB4 CPU1.CB3 131.27,87.28 131.27,87.76 CPU1.CB2 131.1,88.11 131.1,88.31 130.85,88.56 130.84,88.56 v2(130.7,88.7) ; v2(139.71,85.31) 139.5,85.09 CPU1.CR6 ; v2(130.14,85.16) 130.46,85.48 CPU1.BY5 ; CPU1.AB4 106.96,86.58 106.9,86.64 106.9,86.69 v2(106.89,86.69) 106.9,86.69 106.9,86.73 106.96,86.79 CPU1.AB3 ; CPU1.CN17 CPU1.CM17 137.01,78.12 136.92,78.21 136.88,78.21 136.58,78.5 135.59,78.5 v2(135.46,78.64) ; v2(127.24,68.05) 127.02,67.82 CPU1.BP33 126.55,67.82 126.52,67.85 ; v2(127.24,68.05) 126.75,68.54 CPU1.BP32 ; v2(112.47,68.07) 112.16,68.38 CPU1.AL32 ; v2(112.47,68.07) 112.34,68.07 112.09,67.82 CPU1.AK33 ; CPU1.AV28 116.65,71.14 116.3,71.49 v2(116.29,71.49) ; CPU1.BK10 124.11,82.12 v2(124.22,82.01) ; v2(128.79,82.36) 128.46,82.03 CPU1.BU11 ; CPU1.AY35 117.98,67.07 v2(117.92,67.12) ; CPU1.CG7 134.8,83.65 v2(134.8,83.19) ; v2(139.84,75.66) 139.82,75.68 138.72,75.68 138.64,75.6 CPU1.CP21 CPU1.CN21 CPU1.CM21 ; v2(93.89,75.93) 94.03,75.93 94.27,75.68 94.72,75.68 CPU1.B21 CPU1.C21 ; CPU1.AV6 116.42,84.52 v2(116.29,84.52) ; CPU1.BP12 126.39,81.11 v2(126.07,81.43) 126.07,81.91 125.5,82.49 CPU1.BM9 ; CPU1.BR16 126.81,78.94 v2(126.81,79.01) 126.51,79.32 CPU1.BP15 ; CPU1.W7 104.89,84.18 v2(105.18,83.89) ; CPU1.BU7 128.93,84.18 v2(129.2,84.45) 129.47,84.18 CPU1.BW7 ; v2(112.87,82.09) 112.87,82.26 113.02,82.42 CPU1.AM10 ; CPU1.BG25 v2(122.19,73.47) ; v2(139.43,76.86) CPU1.CP19 ; CPU1.BR22 126.81,75.58 v2(126.81,75.66) ; v2(135.45,81.78) 135.6,81.93 135.6,81.98 135.79,82.17 CPU1.CJ11 ; CPU1.AG10 v2(110.25,82.06) ; CPU1.P10 v2(101.94,82) ; CPU1.U7 104.08,83.89 v2(104.26,83.89) ; CPU1.BU23 128.59,74.26 128.59,73.69 CPU1.BU24 128.46,73.46 v2(128.77,73.14) 128.46,72.83 CPU1.BU25 128.4,72.66 127.86,72.66 CPU1.BT25 127.81,72.85 127.8,72.85 127.52,73.13 v2(127.5,73.13) 127.49,73.13 127.16,72.79 CPU1.BR25 CPU1.BP25 ; CPU1.BE10 121.34,82.58 v2(120.79,82.03) ; CPU1.AC10 v2(107.48,82.09) ; CPU1.BA10 v2(118.57,82.06)
  BOTTOM w0.279: v2(132.02,76.48) 131.71,76.17 CPU1.CB20 ; v2(166.73,62.18) 166.49,61.94 166.49,59.66 166.13,59.3 WLAN1.18 ; 157.57,48.05 WLAN1.63 156.72,48.05 156.48,48.29 156.48,49.31 156.72,49.55 156.73,49.55 ; WLAN1.51 156.52,51.05 155.72,51.86 v2(155.72,51.96) 156.02,51.96 156.61,52.55 WLAN1.45
  BOTTOM w0.305: v2(121.77,70.78) 121.42,71.14 CPU1.BE28 ; v2(121.77,70.78) 122.13,71.14 CPU1.BG28 ; v2(121.77,70.78) 121.48,70.49 CPU1.BE29 ; RAM1.K1 92.64,36.1 93.22,35.52 v2(93.22,35.4) ; RAM2.B2 RAM2.A2 80.81,43.49 v2(80.81,43.96) ; 65.69,40.5 v2(65.65,40.5) ; 65.69,40.5 65.69,40.46 RAM3.E8 ; 65.69,40.5 65.69,40.54 RAM3.D8 ; RAM6.E8 108.01,40.49 v2(108.01,40.5) 108.06,40.55 108.06,40.56 RAM6.D8 ; v2(98.62,80.78) 98.62,80.9 CPU1.J12 ; v2(133.9,41.3) RAM8.D2 ; 164.65,41.2 165.75,41.2 166.05,40.9 CN6601.29 ; 164.65,41.2 163.98,41.2 163.77,41.42 163.2,41.42 v2(163.05,41.27) CN6601.35 163.05,39.64 162.95,39.54 v2(162.93,39.54) ; 164.65,41.2 164.55,41.11 CN6601.32 ; CPU1.B7 94.07,84.43 v2(93.64,84.85) ; SSD2.1 167.17,3.65 v2(167.43,3.9) 167.43,5.2 166.97,5.65 SSD2.9 ; LCD1.12 91.65,97.76 v2(91.61,97.81) ; RAM8.H1 135.05,37.7 135.49,37.26 v2(135.49,36.95) ; Q2001.1 129.21,51.81 v2(127.98,51.81) ; CPU1.J24 99.28,73.35 v2(99.28,73.22) ; Q1702.1 134.88,48.67 135.09,48.46 v2(135.09,48) ; SSD2.21 166.79,8.65 v1(167.35,9.21) ; RAM8.F1 134.7,39.7 v2(134.7,39.7) RAM8.E1 ; RAM2.E3 79.42,40.88 v2(79.42,41.01) ; v2(180.13,67.2) 180.13,67.84 181.38,69.09 U4008.3 ; CPU1.U7 103.5,83.89 v2(103.33,83.89) ; PU4701.28 64.05,64.61 64.35,64.31 PC4766.2 ; v2(84.36,36.95) 84.36,37.09 84.97,37.7 RAM1.H9 ; CPU1.CC20 132.36,76.14 v2(132.02,76.48) 131.71,76.79 CPU1.CB19 ; v2(80.68,8.65) 81.93,8.65 82.2,8.93 TPAD1.5 ; SSD2.51 v2(164.39,16.15) ; RAM3.B2 RAM3.A2 70.66,43.49 v2(70.66,43.96) ; RAM5.F1 124.55,39.7 v2(124.55,39.7) RAM5.E1 ; v2(97.33,82.77) 97.48,82.77 CPU1.G9 ; RAM8.E3 132.03,40.77 132.03,41.11 v2(132.03,41.11) ; 156.52,63.55 WLAN1.1 ; v2(134.57,30.68) 134.57,31.03 RAM8.T1 ; RAM8.E8 128.31,40.49 v2(128.31,40.5) 128.36,40.55 128.36,40.56 RAM8.D8 ; v2(5.91,73.68) 5.91,73.65 USB1.B12 ; CPU1.J15 99.28,79.68 v2(99.28,79.82) ; v2(105.18,83.89) 105.35,83.89 CPU1.Y7 ; v2(92.22,30.68) 92.22,31.03 RAM1.T1 ; SSD1.39 v2(189.32,13.15) ; v2(15.43,45.66) 15.62,45.85 Q4349.1 ; v2(93.14,36.9) 93.14,37.02 92.46,37.7 RAM1.H1 ; v2(75.8,38.89) 75.81,38.89 RAM2.G8 ; RAM2.E8 75.81,40.49 75.81,40.5 ; RAM8.A8 128.7,43.35 v2(128.3,43.75) ; 158.2,94.84 158.36,94.84 C2215.2 159.12,94.07 159.35,94.07 v2(159.42,94) ; v2(136.83,36.95) 136.83,37.14 137.39,37.7 RAM7.H9 ; v2(85.95,38.89) 85.96,38.89 RAM1.G8 ; v2(95.37,79.82) 95.37,79.67 CPU1.B15 ; RAM6.K1 114.9,35.2 v2(115.02,35.2) ; CPU1.J6 99.05,84.83 v2(98.72,85.16) 99.04,85.48 CPU1.J5 ; 182.2,4.15 SSD1.75 ; 182.2,4.15 H3.1 ; 182.2,4.15 182.7,4.65 ; CPU1.K24 99.61,73.55 v2(99.28,73.22) ; RAM3.E1 v2(72.05,39.7) 72.05,39.7 RAM3.F1 ; v2(52.49,72.92) 52.67,72.74 PC4622.2 53.28,72.71 PR4639.2 ; v2(118.15,43.75) 118.55,43.35 RAM5.A8 ; v2(71.92,30.68) 71.92,31.03 RAM3.T1 ; v2(96.67,77.01) 96.67,77.14 CPU1.F18 ; v2(55.5,38.89) 55.51,38.89 RAM4.G8 ; v2(73,34.76) 73,34.49 72.21,33.7 RAM3.N1 ; v2(183.94,21.56) 183.71,21.33 EC2710.2 ; v2(91.55,41.3) RAM1.D2 ; v2(101.49,83.89) 101.65,83.89 CPU1.P7 ; RAM5.H1 124.94,37.7 125.34,37.3 v2(125.34,36.95) ; v2(64.17,75) 64.17,75.08 64.16,75.09 64.16,75.09 63.99,75.25 63.99,75.26 63.92,75.32 PU4802.28 ; RAM7.C9 v2(137.49,41.7) ; RAM3.H1 72.21,37.7 72.84,37.07 v2(72.84,36.95) ; v2(60.51,43.96) 60.51,43.49 RAM4.A2 RAM4.B2 ; CPU1.T7 102.59,83.9 v2(102.4,83.9) ; v2(93.13,97.81) 93.15,97.79 LCD1.15 ; RAM1.E1 v2(92.35,39.7) 92.35,39.7 RAM1.F1 ; v2(30.47,39.92) 29.53,39.92 29.01,39.4 PQ4418.1 ; v2(53.91,35.4) 53.91,35.52 54.49,36.1 RAM4.K9 ; RAM6.H1 114.73,37.7 115.19,37.24 v2(115.19,36.95) ; v2(62.72,36.98) 62.72,37.24 62.26,37.7 RAM4.H1 ; v2(136.86,35.4) 136.86,35.52 137.44,36.1 RAM7.K9 ; v2(65.65,43.75) 65.65,43.7 RAM3.A8 ; SSD1.71 183.2,5.15 182.7,4.65 ; RAM2.K9 74.79,36.1 74.21,35.52 v2(74.21,35.4) ; CPU1.L27 100.32,71.9 v2(99.96,72.26) 99.96,72.41 CPU1.K25 99.61,72.89 v2(99.28,73.22) ; Q7407.1 18.67,57.31 18.58,57.22 ; v2(75.8,43.75) 76.2,43.35 RAM2.A8 ; RAM3.K1 72.43,36.1 72.92,35.61 v2(72.92,35.4) ; RAM7.A8 138.85,43.35 v2(138.45,43.75) ; v2(83.07,35.4) 83.07,35.52 82.49,36.1 RAM2.K1 ; 158.79,60.34 158.58,60.55 WLAN1.13 ; 158.79,60.34 159.04,60.6 159.04,61.61 158.61,62.05 WLAN1.7 ; 158.79,60.34 159.27,59.86 159.27,59.74 v2(159.28,59.73) ; CPU1.CD11 133.28,81.68 v2(133.52,81.68) 133.64,81.81 133.64,81.97 133.84,82.16 CPU1.CF11 ; RAM7.G8 138.46,38.89 v2(138.45,38.89) ; Q7404.4 13.31,48.47 v2(13.76,48.02) ; v2(99.18,82.77) 99.33,82.77 CPU1.K9 ; RAM5.G8 118.16,38.89 v2(118.15,38.89) ; RAM4.E3 59.14,40.86 v2(59.14,41.04) ; RAM6.E3 111.67,40.83 111.67,40.92 v2(111.67,40.92) ; RAM6.G8 108.01,38.89 v2(108,38.89) ; RAM7.E8 138.46,40.49 v2(138.46,40.5) 138.51,40.55 138.51,40.56 RAM7.D8 ; v2(128.79,82.36) 129.11,82.05 CPU1.BV11 ; C4043.2 v2(155.44,69.11) ; RAM7.E1 v2(144.85,39.7) 144.85,39.7 RAM7.F1 ; PU4801.28 63.92,85.61 v2(64.17,85.36) ; RAM1.D8 85.97,40.52 85.97,40.5 ; v2(109.79,84.5) 109.65,84.5 CPU1.AF7 ; v2(89.57,41.09) 89.57,40.88 RAM1.E3 ; RAM6.E1 v2(114.4,39.7) 114.4,39.7 RAM6.F1 ; PC4615.1 57.44,75.04 PC4614.2 PC4612.2 57.16,76.09 57.16,76.64 ; CPU1.AL7 111.81,83.89 v2(111.65,83.89) 111.47,83.89 CPU1.AJ7 ; v2(96.67,80.78) 96.67,80.9 CPU1.F12 ; SSD2.15 167.91,7.15 PU5401.1 ; v2(61.77,30.68) 61.77,31.03 RAM4.T1 ; v2(144.72,30.68) 144.72,31.03 RAM7.T1 ; RAM2.E1 82.2,39.7 v2(82.2,39.7) RAM2.F1 ; 85.97,40.5 85.97,40.48 RAM1.E8 ; 85.97,40.5 v2(85.95,40.5) ; RAM5.B2 RAM5.A2 123.16,43.49 v2(123.16,43.96) ; v2(135.27,32.94) 134.5,33.7 RAM8.N1 ; RAM5.K1 124.84,36.1 125.42,35.52 v2(125.42,35.4) ; v2(189.02,8.65) SSD1.57 ; RAM8.K1 134.99,36.1 135.57,35.52 v2(135.57,35.4) ; CPU1.U24 102.97,73.72 v2(102.74,73.72) ; v2(164.38,3.6) 164.93,4.15 SSD2.3 ; v2(69.19,40.9) 69.23,40.9 69.23,40.86 69.29,40.86 RAM3.E3 ; RAM1.A8 86.35,43.35 v2(85.95,43.75) ; v2(92.62,32.91) 92.62,33.03 RAM1.N1 ; v2(55.5,43.75) 55.9,43.35 RAM4.A8 ; v2(133.31,43.96) 133.31,43.49 RAM8.A2 RAM8.B2 ; v2(142.23,40.86) 142.23,40.72 RAM7.E3 ; v2(64.06,35.4) 64.06,35.52 64.64,36.1 RAM3.K9 ; v2(27.03,40.09) 27.15,40.09 27.18,40.11 27.28,40.11 27.71,40.54 PQ4418.4 ; v2(143.3,43.76) 143.46,43.59 143.46,43.49 RAM7.A2 143.81,43.14 143.81,42.67 143.65,42.51 RAM7.B2 ; v2(84.36,35.4) 84.36,35.65 84.8,36.1 RAM1.K9 ; CPU1.AE7 108.73,84.5 v2(108.9,84.5) ; R4315.1 19.79,47.69 19.32,47.23 19.32,47.16 19.31,47.15 Q4349.4 ; v2(5.91,66.64) 5.91,66.73 USB1.B1 ; v2(75.8,40.5) 75.81,40.5 ; 75.81,40.5 76.2,40.89 RAM2.D8 ; CPU1.D5 96.41,85.64 v2(96.81,85.24) 96.57,84.99 CPU1.D6 ; v2(106.39,36.75) 106.41,36.76 106.41,37.02 107.09,37.7 RAM6.H9 ; CPU1.AB7 106.27,83.89 v2(106.11,83.89) ; v2(155.87,59.07) 156.12,59.07 156.14,59.05 WLAN1.19 ; WLAN1.33 157.21,55.55 156.91,55.86 156.91,56.25 v2(156.89,56.25) ; v2(62.85,34.76) 62.85,34.65 61.9,33.7 RAM4.N1 ; v2(164.39,10.32) 164.56,10.15 SSD2.27 ; CPU1.W7 104.42,83.89 v2(104.26,83.89) ; v2(189.07,19.47) 188.52,19.47 188.21,19.15 SSD1.15 ; Q7406.1 18.44,54.49 v2(17.95,53.99) ; RAM6.N1 114.59,33.11 v2(114.59,32.91) ; v2(94.6,97.81) 94.65,97.76 LCD1.18 ; CPU1.E29 v2(97.08,70.16) ; CPU1.B12 94.72,80.9 v2(94.72,80.78) ; WLAN1.69 v2(159.27,46.55) ; RAM2.H9 74.84,37.7 74.21,37.07 v2(74.21,36.95) ; RAM7.K1 145.14,36.1 145.72,35.52 v2(145.72,35.4) ; SSD1.27 188.13,16.15 188.48,16.5 v2(188.96,16.5) ; v2(114.27,30.68) 114.27,31.03 RAM6.T1 ; v2(190.29,11.32) 189.96,11.65 SSD1.45 186.35,11.65 186.32,11.68 ED6301.8 ED6301.3 ; v2(113.01,43.96) 113.01,43.49 RAM6.A2 RAM6.B2 ; Q7405.4 15.64,53.35 15.25,53.74 v2(14.77,53.74) ; v2(189.12,17.28) 188.52,17.28 188.15,17.65 SSD1.21 ; 182.7,4.65 SSD1.73 ; v2(105.68,97.91) 105.7,97.94 106.19,97.94 106.65,97.47 LCD1.42 ; v2(155.72,51.96) 155.72,53.07 156.7,54.05 WLAN1.39 ; RAM3.H9 64.52,37.7 64.02,37.2 v2(64.02,37) ; v2(108,43.75) 108.4,43.35 RAM6.A8 ; v2(172.09,71.01) 171.87,71.23 PU5201.4 ; RAM8.G8 128.31,38.89 v2(128.3,38.89) ; WLAN1.57 156.73,49.55 ; v2(161.46,41.34) 161.55,41.25 CN6601.38 ; v2(82.07,30.68) 82.07,31.03 RAM2.T1 ; v2(84.89,14.45) 84.27,13.82 EC6504.2 ; RAM4.D8 55.56,40.56 55.56,40.55 v2(55.51,40.5) 55.51,40.49 RAM4.E8 ; ED7303.3 ED7303.8 12.1,67.09 v2(12.12,67.1) ; v2(18.3,51.76) 18.99,51.76 19.74,52.51 Q7406.4 ; v2(174.79,74.49) 174.78,74.48 PU5201.19 ; v2(126.71,35.4) 126.71,35.52 127.29,36.1 RAM8.K9 ; PU5001.4 173.42,100.07 v2(173.32,99.97) ; RAM5.K9 117.14,36.1 116.56,35.52 v2(116.56,35.4) ; v2(64.69,41.7) RAM3.C9 ; 62.52,74.36 62.52,74.69 61.86,75.35 v2(61.86,75.51) ; v2(98.62,77.01) 98.62,77.14 CPU1.J18 ; v2(82.99,36.95) 82.99,37.33 82.63,37.7 RAM2.H1 ; CPU1.C37 CPU1.B37 94.86,65.3 94.55,64.99 93.46,64.99 v2(93.43,65.02) ; v2(62.77,35.4) 62.77,35.52 62.19,36.1 RAM4.K1 ; SSD2.39 v2(164.39,13.15) ; RAM1.B2 RAM1.A2 90.96,43.49 v2(90.96,43.96) ; CPU1.A36 94.4,66 v2(93.92,65.52) ; RAM7.H1 144.96,37.7 145.64,37.02 v2(145.64,36.9) ; RAM8.H9 127.18,37.7 126.68,37.2 v2(126.68,36.95) ; v2(84.99,41.7) RAM1.C9 ; CPU1.CB11 131.71,82.03 131.49,82.25 131.49,82.26 v2(131.39,82.36) ; v2(145.8,34.76) 145.8,34.65 144.85,33.7 RAM7.N1 ; RAM5.E8 118.16,40.49 v2(118.16,40.5) 118.21,40.55 118.21,40.56 RAM5.D8 ; v2(188.99,14.39) 188.35,14.39 188.1,14.65 SSD1.33 ; v2(159.25,48.05) 157.57,48.05 ; v2(18.28,62.15) 18.1,62.15 17.37,61.42 Q7407.4 ; v2(53.81,37.08) 53.81,37.13 54.38,37.7 RAM4.H9 ; RAM8.C9 v2(127.34,41.7) ; v2(113.6,41.3) RAM6.D2 ; v2(116.53,36.95) 116.53,37.19 117.05,37.7 RAM5.H9 ; v2(71.25,41.3) RAM3.D2 ; PC5113.2 53.2,55.9 53.63,56.33 v2(53.63,56.86) ; v2(12.49,70) 12.49,70.17 12.79,70.48 R7330.2 ; SSD2.33 v2(164.39,11.65) ; CPU1.H9 98.41,82.77 v2(98.25,82.77) ; PC5208.2 179.74,85.72 180.55,84.91 ED9202.3 181.73,84.75 FP1.5 183.83,84.75 185.41,86.33 v2(187.21,86.33) ; v2(130.09,82.36) 130.41,82.05 CPU1.BY11 ; v2(167.17,17.65) SSD2.57 ; RAM6.K9 106.99,36.1 106.41,35.52 v2(106.41,35.4) ; CPU1.B18 94.72,77.14 v2(94.72,77.01) ; v2(144.05,41.3) RAM7.D2 ; RAM4.C9 v2(54.54,41.7) ; v2(107.02,41.67) 107.05,41.7 RAM6.C9 ; CPU1.D9 96,82.95 v2(96,82.67) ; CPU1.E23 96.68,74 CPU1.F24 96.64,73.31 v2(96.64,73.22) ; CPU1.F15 97.35,79.7 v2(97.35,79.82) ; RAM2.C9 v2(74.82,41.7) ; RAM2.N1 82.2,33.7 83.15,34.65 v2(83.15,34.76) ; LCD1.45 108.15,97.49 107.84,97.81 107.46,97.81 107.46,97.81 v2(107.46,97.81) ; SSD2.45 v2(164.39,14.65) ; v2(125.41,32.91) 125.44,32.91 124.65,33.7 RAM5.N1 ; RAM3.G8 65.66,38.89 v2(65.65,38.89) ; RAM4.F1 61.9,39.7 v2(61.9,39.7) RAM4.E1 ; CPU1.C4 95.82,85.84 v2(95.82,85.59) 95.17,85.59 CPU1.B5 ; SSD1.9 v2(189.02,20.65) ; v2(14.39,50.95) 14.96,50.37 Q7404.1 ; RAM5.C9 v2(117.19,41.7) ; SSD1.51 189.09,10.15 v2(189.12,10.18) ; v2(124.42,30.68) 124.42,31.03 RAM5.T1 ; v2(61.1,41.3) RAM4.D2 ; v2(81.4,41.3) RAM2.D2 ; v2(123.75,41.3) RAM5.D2
  BOTTOM w0.356: U2601.5 43.05,30.49 ; v2(121.69,41.15) 121.69,40.96 RAM5.E3 ; v2(25.34,41.65) 25.31,41.65 25.31,41.93 24.74,42.5 PQ4415.4 ; PQ4415.1 v2(21.94,44.15) ; v2(12.1,10.94) 12.7,11.54 SPK1.5 ; v2(26.46,37.74) 25.75,38.45 ED2403.3 ; EC6503.2 89.83,12.57 90.46,13.2 v2(90.46,13.35) ; R2051.2 131.13,50.61 130.71,50.2 Q2001.4 v2(130.71,48.15)
  BOTTOM w0.381: HDMI1.17 10.91,92.02 ; HDMI1.8 12.05,87.8 12.66,87.8 v2(12.94,88.08) ; v2(95.64,93.19) 96.25,93.19 R1517.2 ; C5761.2 C5762.2 21.22,90.47 v2(20.89,90.14) ; HDMI1.11 10.94,89.02
  BOTTOM w0.406: v2(157.65,90.32) 156.93,90.32 C4031.2 ; PC4404.2 37.95,56.41 v2(36.74,57.61) ; C4013.2 157.27,94.84 FC8945.2 158.2,94.84 ; EC1707.2 v2(135.09,48) ; 43.05,30.49 C2602.2 ; v2(156.13,64.65) 156.13,64.65 U4003.5
  BOTTOM w0.457: C7118.1 20.49,63.19 v2(20.49,62.2)
  BOTTOM w0.508: v2(140.73,90.01) 140.3,90.44 R5507.2 ; X1801.4 140.28,96.5 v2(140.47,96.31) ; R5754.1 23.78,87.97 v2(23.78,87.3) 23.31,87.3 C5754.2 ; EC2501.2 137.96,53.82 139.18,53.82 v2(139.23,53.76) ; 2.02,76.93 USB1.15 2.58,75.43 v2(3.6,75.43) ; C4042.2 149.92,65.6 149.83,65.6 v2(149.66,65.44) ; v2(52.01,82.72) 52.01,82.34 51.78,82.11 C1711.2 51.8,81.53 R1719.2 ; v2(146.22,79.37) 146.22,78.86 R1552.2 ; C1710.2 21.02,14.27 21.76,15 v2(21.88,15) 22.39,14.5 C2406.2 ; R7219.2 9.65,28.14 9.78,28 9.89,27.88 v2(10.43,27.88) 10.45,27.91 R7218.2 ; v2(7.02,26.82) 7.29,27.08 R407.1 ; EC2714.2 183.76,14.95 v2(184.47,15.66) ; v2(127.98,51.81) 128.41,51.38 R2002.1 ; USB1.13 6.25,75.83 ; USB1.13 5.91,74.65 v2(5.91,73.68) ; USB1.13 6.09,74.99 5.3,75.79 v2(5.22,75.79) ; USB1.13 7.52,74.99 ; H9.1 147.05,91.52 C801.2 ; v2(160.74,39.54) 160.16,39.54 159.65,40.05 CN6601.42 ; R2032.2 145.91,72.99 R2012.2 ; R2032.2 R2022.2 ; R2032.2 145.78,73.17 R1911.2 ; PC5427.2 v2(109.18,26.43) 109.18,26.89 109.49,27.2 PR5409.2 ; ED301.3 118.25,96.31 v2(119.75,97.81) ; v2(167.17,17.65) 167.17,18.46 FC2738.1 ; v2(53.13,43.45) 52.74,43.83 PT4805.2 51.77,42.5 v2(52.13,42.13) ; R2014.2 R1514.2 146.52,70.02 146.44,70.1 v2(146.44,70.7) 146.52,70.7 147.05,71.23 R2030.2 146.93,71.49 FC8943.2 ; HDMI1.20 13.25,81.27 ; HDMI1.20 11.92,82.26 ; HDMI1.20 11.92,80.28 ; FC8931.2 v2(9.13,13.4) ; R2022.2 145.15,73.83 v2(145.1,73.88) R1503.2 R2037.2 ; R2022.2 R2017.2 R2015.2 145.94,76.12 R2034.2 R1519.2 ; C2214.2 160.87,71.21 v2(161.08,71.01) 160.95,70.89 160.95,70.17 161.02,70.1 C2525.2 ; PR4512.2 51.73,23.13 v2(51.35,23.51) 50.97,23.13 PC4530.2 ; PR4436.2 21.55,46.75 v2(21.27,46.75) ; v2(193.87,37.51) 194.26,37.9 Q2505.S ; PC4602.2 47.38,80.37 v2(47.38,79.75) PC4607.2 ; v2(43.37,12.31) 43.52,12.46 R2453.1 ; FC8940.2 48.17,61.44 v2(48.17,60.9) PR5114.2 ; v2(182.03,12.57) 182.26,12.79 R2745.2 ; C5742.2 34.15,82.29 v2(34.1,82.34) ; PC4651.2 57.16,76.82 56.44,77.54 v2(56.3,77.54) ; PC4651.2 57.16,76.64 ; PC4651.2 57.18,76.64 58.17,76.64 v2(58.21,76.6) PC4812.2 ; 11.92,94.78 HDMI1.21 ; HDMI1.21 11.92,96.76 ; HDMI1.21 13.25,95.77 ; CN6601.43 183.15,38.72 182.1,39.77 v2(181.78,39.77) 181.7,39.85 181.47,39.85 CN6601.41 ; v2(49.95,65.32) 49.62,64.99 PR4655.1 48.65,64.99 PC4641.2 48.48,65.17 PC4644.2 ; v2(40.95,78.2) 41.31,78.2 PC4603.1 ; RTC1.2 188.1,42.87 189.12,43.88 ; v2(19.6,48.66) 19.85,48.41 R4315.1 ; R1507.2 136.18,60.01 v2(136.26,59.94) ; v2(177.71,73.6) 177.69,73.58 PC5202.2 ; C4043.2 156.2,68.47 C4040.2 ; v2(186.65,1.77) 187.93,3.05 SSD1.77 ; EC2601.2 183.86,67.51 183.3,66.95 v2(183.25,66.95) ; PC4507.2 90.74,17.82 90.79,17.87 90.79,17.89 v2(90.78,17.89) ; C2746.2 170.3,15.46 v2(169.97,15.13) ; v2(21.36,28.24) 21.36,28.22 21.5,28.09 C2424.2 ; Q6501.S 78.03,10.1 v2(78.03,9.49) ; v2(16.3,15.15) 16.55,15.4 ED1703.3 ; PC4440.1 30.9,41.25 v2(30.52,40.87) ; v3(72.71,63.01) 72.24,62.54 Q502.S ; PC5113.2 52.49,56.1 50.18,56.1 v2(50.08,56.2) PR5101.2 ; 91.39,6.5 91.1,6.5 90.59,7.01 v2(90.59,7.92) ; LCD1.52 114.6,98.95 116.47,98.95 116.88,98.54 ED5501.2 ; LCD1.52 113.35,99.4 113.35,98.24 112.88,97.77 v2(112.14,97.77) 111.55,97.18 LCD1.54 ; LCD1.52 114.04,100.09 114.72,100.09 114.97,100.35 114.97,102.09 114.17,102.89 v2(110.25,102.89) ; v2(167.55,22.75) 167.05,23.25 SSD2.77 ; v2(49.13,91.65) 49.13,92.26 Q4302.E ; HDMI1.23 3.72,98.66 ; HDMI1.23 5.05,97.67 ; HDMI1.23 2.39,97.67 ; v2(5.73,36.11) 6.36,35.48 R7236.2 6.64,35.07 6.72,34.99 R7250.1 ; v2(52.87,61.41) 52.79,61.49 52.75,61.49 52.29,61.95 PC5108.2 ; H12.1 16.89,76.3 ; H12.1 10.51,76.3 ; H12.1 13.7,73.11 ; H12.1 13.7,79.49 ; R1527.2 142.84,72.97 v2(143.32,72.48) ; v2(147.05,28.24) 147.1,28.19 147.82,28.19 C1379.2 148.17,28.54 C1357.2 ; PC4766.2 64.35,63.67 v2(64.38,63.65) ; R1301.2 R1340.1 105.88,37.41 106.39,36.9 v2(106.39,36.75) ; v2(149.5,66.17) 149.5,66.56 150.4,67.46 C4008.2 C4041.2 ; R2116.2 v2(150.46,76.93) ; FC8933.2 155.31,69.23 v2(155.44,69.11) ; R7409.2 12.92,51.63 R7408.2 13.76,51.3 14.11,50.95 v2(14.39,50.95) ; v2(110.07,23.64) 110.1,23.61 PC5410.2 ; PC4402.2 38.27,58.31 37.76,57.8 v3(37.76,57.68) ; PR4621.1 53.39,78.3 PR4614.2 53.51,78.49 53.51,78.96 v2(53.6,79.05) ; PC4624.2 42.66,70.25 PC4601.2 41.54,70.17 v2(41.49,70.12) 41.82,69.79 PC4631.2 ; C6504.2 72.99,14.57 73.78,15.36 74.74,15.36 74.97,15.13 74.97,15.12 75.34,14.75 75.35,14.75 v2(75.48,14.62) ; v2(14.64,56.41) 14.96,56.72 D7301.A ; C1808.1 136.72,93.74 v2(136.72,93.13) ; KB1.1 59.3,9.77 58.79,9.26 v2(58.71,9.26) 59.38,8.6 KB1.31 ; PC5402.2 170.92,11.92 v2(169.86,11.92) ; C9201.2 181.06,90.72 v2(183.38,93.03) ; v2(187.75,24.78) 188,24.53 SSD1.76 ; R6509.2 77.79,13.54 78.17,13.16 v2(78.17,13.13) ; ED1801.3 138.6,46.8 C1806.2 ; C5771.2 21.71,79.47 21.96,79.22 v2(21.96,79.11) ; v1(23.79,63.04) 24.36,63.04 24.85,63.52 25.39,63.52 25.39,63.51 v2(25.39,63.51) ; C2416.2 C2421.2 v2(46.6,20.97) ; FC8932.2 56.86,89.63 56.05,90.44 v2(55.92,90.44) ; C2418.2 31.92,33.8 v2(31.89,33.8) ; C2614.2 24.8,11.7 v2(24.93,11.83) 25.03,11.93 C2405.2 ; v2(142.79,57.21) 142.83,57.21 C2502.2 ; R4316.2 40.91,81.12 C4303.2 v2(41.67,81.09) ; v2(44.01,37.74) 43.74,38 43.74,38.82 PC4418.2 PC4412.2 PC4411.2 ; v2(156.25,72.41) 156.15,72.41 155.89,72.15 U2502.2 154.14,72.15 C2224.2 ; PC5215.2 v2(177.71,70.43) ; H8.1 142.48,62.65 R1511.1 ; v2(45.76,88.84) 45.76,87.88 C4302.2 45.96,87.85 v2(46.78,88.66) ; v2(147.18,82.67) EC1706.2 R2008.2 ; v2(61.84,65.04) 61.84,64.31 PR4654.2 PR4712.2 ; FC8950.2 103.16,31.82 C1340.2 C1338.2 101.77,30.63 101.64,30.75 v2(101.39,30.75) ; R1518.2 v2(90.29,87.72) ; v2(135.09,48) 134.43,48 133.97,48.46 133.06,48.46 EC1712.2 ; PR4817.2 58.31,85.77 v2(58.1,85.57) ; v3(55.41,81.3) 56.3,80.41 56.3,79.83 ED1704.3 ; v2(172.09,71.01) 172.12,70.98 PR5204.2 ; v2(143.85,101.67) 143.85,102.56 143.42,103 U5503.2 ; v2(177.71,72.92) 177.61,72.81 PC5213.2 ; EC2502.2 152.54,55.09 152.21,54.76 BIOS1.4 v2(150.05,54.76) ; FAN1.2 v2(187.36,77.1) ; v2(22.14,40.56) 22.14,40.4 R4377.2 ; v2(39.19,64.11) 38.57,63.49 PC4401.2 38.57,61.82 39.16,61.23 v2(39.16,61.11) ; PR4661.2 51.32,66.19 v2(50.84,66.19) 50.76,66.26 PC4638.2 ; v2(175.3,66.95) 174.9,66.95 174.39,67.46 Q6102.S ; v2(40.07,87.01) 40.04,87.01 39.87,86.84 C4304.2 C4305.2 ; v2(33.67,10.58) 34.08,10.18 34.08,8.6 ; PC5403.2 v2(172.51,5) ; C4037.2 173.19,11.11 v2(173.46,11.38) 172.73,12.11 PC5404.2 ; PC4508.2 91.76,16.48 PR4508.2 92.5,15.59 v2(92.42,15.51) 92.42,15.07 92.5,14.99 Q6503.S ; PC5112.2 49.92,64.38 v2(50.59,65.04) ; G1801.1 146.09,24.35 v2(145.45,23.72) ; PC4809.2 58.54,87.88 v2(57.82,87.88) ; v2(168.7,22.7) EC1901.1 169.53,22.55 R2746.1 ; R5735.1 24.65,86.57 v2(24.58,86.5) ; 5.05,79.37 HDMI1.22 3.72,78.38 ; v2(52.74,101.24) 52.57,101.06 R4302.2 ; v2(140.15,62.53) 140.6,62.07 R1509.1 ; PC4708.2 v2(58.33,66.82) ; ED4304.1 v2(34.81,35.5) ; v2(125.64,93.24) C2209.2 127.22,93.77 127.01,93.97 C2208.2 ; C2219.2 v2(142.79,96.41) ; v2(46.67,68.34) 46.34,68.02 PC4637.2 46.19,67.56 PR4659.1 ; 2.96,63.65 2.22,64.39 USB1.16 2.57,64.94 v2(3.44,64.94) ; R2455.2 41.82,14.8 C2413.2 41.59,14.93 v2(41.59,15.46) ; v2(114.16,93.3) 114.16,93.77 R1714.2 ; v2(34.81,76.17) FC8930.2 C5743.2 ; WLAN1.76 v2(156.13,64.65) ; PR4551.2 v2(52.49,23.51) ; v2(185.76,39.82) 185.23,39.29 R2517.2 ; v2(61.41,86) 61.63,85.77 PR4617.2 ; v2(136.18,95.19) 136.53,94.85 X1801.2 ; v2(96.31,38.32) 96.28,38.32 96.28,38.35 95.92,38.35 95.42,37.84 R1221.1 ; U7202.4 12.93,27.21 v2(13.25,27.53) ; v2(175.38,1.72) 174.99,2.1 EC8926.2 ; v2(16.35,55.31) 16.45,55.21 R7410.2 ; EC1903.2 173.9,25.11 v2(173.9,25.67) ; PR5203.2 v2(177.71,68.9) ; C5760.2 21.25,87.43 v2(21.39,87.28) ; v2(23.41,79.24) 23.41,80.16 ; C1807.1 v2(139.71,93.79) ; v2(80.94,26.94) v2(81.83,26.94) 81.97,26.8 SPR2.1 84.94,26.46 v2(88.81,26.46) v2(89.83,26.46) ; C2427.2 v2(22.26,31.2) ; v2(107.02,41.67) 106.31,40.96 R1331.2 ; USB1.14 6.25,64.35 ; v2(44.62,30.5) 44.49,30.37 43.27,30.37 C2602.2 ; v2(138.75,56.48) 138.95,56.69 EC2503.2 ; C2414.2 26.33,33.14 26.09,33.38 v2(26.09,33.39) 26.72,33.39 27.09,33.03 C2412.2 ; C2425.2 21.86,24.86 v2(22.14,24.86) ; R1521.2 151.6,72.99 R1523.2 152.52,73.81 v2(152.67,73.96) ; v2(24.93,36.37) 24.22,35.65 R2417.2 ; PC4606.2 v2(44.34,76.7) ; v2(26.19,88.11) 26.29,88.11 26.87,87.52 U5702.4 27.8,87.53 C5752.2 ; C2409.2 v2(35.45,33.8) ; v2(175.55,25.67) C2736.2 ; FC8953.2 v2(107.68,28.01) ; v2(26.45,41.12) 26.45,41.98 PR4487.1 ; 18.58,57.22 18.53,57.17 v2(18.53,56.56) ; v2(31.15,75.84) 31.15,75.33 FC5702.2 C5744.2 31.36,73.7 31.1,73.44 30.32,73.44 v2(30.19,73.58) ; v2(164.38,3.6) 164.38,3.37 SSD2.76 ; EC2403.2 43.22,22.4 v2(41.9,21.08) ; R2448.2 v2(34.68,33.8) ; C2601.2 v2(38.27,37.23) ; D4303.3 v2(48.38,99.77) ; Q4001.S v2(13.18,18.47) ; v2(39.28,35.07) 39.54,34.82 C2609.2 ; v2(150.28,79.77) 149.9,80.16 R2112.2 R1505.2 ; R2445.1 v2(17.11,20.59) ; v2(73.06,25.32) 72.96,25.42 C4001.2 C4002.2 ; C7244.2 v2(15.84,22.67) ; C2610.2 21.25,6.62 ; C2608.2 v2(38.37,30.4)
  vias: v1(7.05,4.26) v1(7.61,38.42) v1(7.68,11.88) v1(7.96,50.03) v1(9.13,5.38) v1(10.4,52.27) v1(11.8,17.59) v1(12.18,47.11) v1(12.51,42.44) v1(13.5,60.17) v1(15.69,38.75) v1(16.4,82.34) v1(16.55,97.81) v1(16.6,88.21) v1(19.34,36.87) v1(20.38,70.83) v1(20.49,2.43) v1(32.42,91.28) v1(33.77,54.22) v1(42.28,96.89) v1(50.94,49.27) v1(72.2,73.88) v1(73.06,67.12) v1(73.39,90.44) v1(76.47,102.99) v1(88.33,47.69) v1(99.61,86.02) v1(107.3,44.38) v1(108.17,45.74) v1(110.2,69.23) v1(119.7,47.41) v1(119.93,3.96) v1(125.85,15.56) v1(149.37,4.23) v1(163.89,98.98) v1(169.46,98.24) v1(170.75,75.66) v1(178.04,99.87) v1(184.44,21.99) v1(184.57,24.15) v1(186.04,95.09) v1(186.98,81.4) v1(188.58,102.1) v2(0.76,5.95) v2(0.78,2.38) v2(0.8,0.91) v2(1.08,100.91) v2(1.08,98.82) v2(1.08,97.12) v2(1.01,8.24) v2(1.13,103.12) v2(1.79,98.16) v2(1.87,102.43) v2(1.94,6.88) v2(2.25,97.1) v2(2.73,100.86) v2(2.78,9.21) v2(2.93,62.18) v2(2.93,59.64) v2(2.93,57.1) v2(2.93,54.56) v2(2.93,52.02) v2(2.93,49.48) v2(2.93,46.94) v2(2.93,44.4) v2(2.93,41.86) v2(2.93,39.32) v2(2.93,36.78) v2(2.93,34.24) v2(2.93,31.7) v2(2.93,29.16) v2(2.93,26.62) v2(2.93,24.08) v2(2.93,21.54) v2(2.93,19) v2(2.93,16.46) v2(2.93,13.92) v2(2.93,11.38) v2(3.19,0.76) v2(3.7,77.92) v2(3.72,62.12) v2(3.85,63.8) v2(3.85,5.35) v2(3.98,76.93) v2(4.23,102.94) v2(4.66,63.11) v2(4.61,1.92) v2(4.74,99.92) v2(5.04,101.82) v2(5.2,79.95) v2(5.22,64.58) v2(5.37,3.7) v2(5.45,77.49) v2(5.55,63.82) v2(5.65,78.99) v2(5.78,102.43) v2(5.73,0.76) v2(5.87,33.75) v2(5.88,33.04) v2(5.88,32.28) v2(5.93,60.6) v2(5.93,59.84) v2(6.39,76.68) v2(6.69,101.77) v2(7,77.89) v2(7.13,99.92) v2(7.15,24.02) v2(7.25,98.42) v2(7.2,15) v2(7.48,79.01) v2(7.77,102.44) v2(7.76,76.42) v2(7.71,3.14) v2(7.89,97.1) v2(7.91,79.96) v2(8.17,1.8) v2(8.27,0.76) v2(8.37,74.67) v2(8.34,52.52) v2(8.32,44.26) v2(8.68,42.87) v2(9.08,101.77) v2(9.23,46.58) v2(9.39,78.94) v2(9.36,77.16) v2(9.31,55.01) v2(9.56,97.1) v2(9.64,98.42) v2(9.61,66.43) v2(9.72,49.17) v2(9.84,75) v2(9.95,99.94) v2(9.95,68.45) v2(9.95,54.37) v2(10.31,102.44) v2(10.3,94) v2(10.3,82.92) v2(10.38,7) v2(10.4,80.31) v2(10.73,79.37) v2(10.73,62.12) v2(10.81,0.76) v2(10.93,89.59) v2(10.93,88.45) v2(10.91,73.25) v2(10.96,31.77) v2(11.6,40.58) v2(11.6,31.77) v2(11.85,61.49) v2(11.9,101.8) v2(12.13,62.27) v2(12.43,99.94) v2(12.46,98.44) v2(12.64,90.44) v2(12.89,40.43) v2(13.3,36.39) v2(13.4,97.2) v2(13.38,62.14) v2(13.35,44.29) v2(13.35,0.76) v2(13.5,47.26) v2(13.7,86.48) v2(13.73,56.99) v2(14.14,40.3) v2(14.52,60.76) v2(14.64,98.44) v2(14.64,96.92) v2(14.64,72.66) v2(15.05,62.12) v2(15.05,61.44) v2(15.03,27.62) v2(15.39,102.44) v2(15.53,100.48) v2(15.69,62.12) v2(15.69,61.49) v2(15.89,0.76) v2(16.19,27.62) v2(16.74,43.01) v2(17.18,98.57) v2(17.31,100.6) v2(17.93,102.44) v2(18.3,70.12) v2(18.3,68.85) v2(18.3,67.58) v2(18.43,0.76) v2(18.58,97.05) v2(18.84,99.99) v2(18.85,27.7) v2(18.99,86.45) v2(19.03,88.1) v2(19.09,84.85) v2(19.32,70.76) v2(19.32,70.12) v2(19.32,69.49) v2(19.32,68.85) v2(19.32,68.22) v2(19.32,67.58) v2(19.32,66.95) v2(19.45,34.56) v2(19.6,98.57) v2(19.65,35.6) v2(19.7,33.55) v2(19.8,97.53) v2(20.33,70.12) v2(20.33,68.85) v2(20.33,67.58) v2(20.47,102.44) v2(20.97,0.76) v2(21.25,97.81) v2(21.76,100.22) v2(22.37,61.82) v2(23.01,102.44) v2(23.13,97.35) v2(23.21,82.75) v2(23.66,100.86) v2(23.84,75.54) v2(24.14,82.77) v2(24.58,66.36) v2(24.6,70.35) v2(24.78,0.76) v2(25.15,69.36) v2(25.16,65.19) v2(25.37,67.93) v2(25.34,66.38) v2(25.67,71.6) v2(26.2,73.3) v2(26.96,46.88) v2(27.42,75.35) v2(27.98,47.9) v2(27.98,46.88) v2(27.98,45.99) v2(29,46.88) v2(29.75,93.88) v2(30.05,0.76) v2(30.14,75.46) v2(30.75,86.68) v2(30.77,84.6) v2(31.56,83.03) v2(31.94,88.23) v2(32.83,89.78) v2(33.67,0.76) v2(34.53,90.52) v2(34.76,89.71) v2(35.17,91.03) v2(35.71,102.44) v2(38.25,102.44) v2(38.27,38.5) v2(38.75,0.76) v2(39.6,68.08) v2(40.79,102.44) v2(40.95,77.51) v2(41.29,0.76) v2(43.33,102.44) v2(43.83,0.76) v2(44.5,92.91) v2(44.63,36.1) v2(44.62,35.45) v2(44.62,34.69) v2(44.62,31.9) v2(44.62,31.13) v2(45.15,38.63) v2(45.15,37.99) v2(45.87,102.44) v2(46.37,0.76) v2(46.65,72.92) v2(46.78,93.03) v2(47.38,86.17) v2(47.49,102.89) v2(47.41,72.92) v2(48.17,104.39) v2(48.17,74.44) v2(48.17,73.68) v2(48.17,72.92) v2(48.17,72.15) v2(48.17,71.39) v2(48.35,86.17) v2(48.76,83.08) v2(48.93,72.92) v2(48.91,0.76) v2(49.7,72.92) v2(49.86,104.44) v2(50.89,12.38) v2(51.45,0.76) v2(51.53,12.38) v2(52.11,40.02) v2(52.16,12.39) v2(52.4,104.44) v2(52.62,65.04) v2(52.62,41.67) v2(52.9,27.48) v2(52.82,12.36) v2(53.13,18.43) v2(53.48,12.36) v2(53.99,0.76) v2(54.73,65.02) v2(54.94,104.44) v2(55.79,46.75) v2(55.92,27.48) v2(56.53,0.76) v2(57.48,104.44) v2(58.21,21.91) v2(59.07,0.76) v2(59.58,24.33) v2(60.02,104.44) v2(61.61,0.76) v2(61.71,24.33) v2(62.56,104.44) v2(62.99,87.5) v2(63.21,27.42) v2(63.26,13.53) v2(63.89,13.57) v2(64.1,47.03) v2(64.18,89.84) v2(64.18,89.21) v2(64.18,88.57) v2(64.18,87.94) v2(64.18,79.43) v2(64.18,78.79) v2(64.18,78.16) v2(64.18,77.52) v2(64.15,0.76) v2(64.31,68.89) v2(64.31,68.25) v2(64.31,67.62) v2(64.31,66.98) v2(64.3,23.18) v2(64.56,47.52) v2(64.53,13.57) v2(64.92,89.84) v2(64.92,89.21) v2(64.92,88.57) v2(64.92,87.94) v2(64.92,79.43) v2(64.92,78.79) v2(64.92,78.16) v2(64.92,77.52) v2(64.94,23.17) v2(65.04,68.89) v2(65.04,68.25) v2(65.04,67.62) v2(65.04,66.98) v2(65.06,47.95) v2(65.1,104.44) v2(65.16,13.57) v2(65.49,27.42) v2(65.57,23.17) v2(65.65,89.84) v2(65.65,89.21) v2(65.65,88.57) v2(65.65,87.94) v2(65.65,87.17) v2(65.65,79.43) v2(65.65,78.79) v2(65.65,78.16) v2(65.65,77.52) v2(65.65,76.76) v2(65.78,68.89) v2(65.78,68.25) v2(65.78,67.62) v2(65.78,66.98) v2(65.78,66.22) v2(65.8,13.57) v2(66.21,23.18) v2(66.43,13.56) v2(66.69,0.76) v2(66.84,23.18) v2(67.48,23.18) v2(67.64,104.44) v2(68.06,22.93) v2(68.11,13.86) v2(68.63,39.1) v2(68.87,13.61) v2(69.23,0.76) v2(70.18,104.44) v2(71.24,27.4) v2(71.44,47.39) v2(71.77,0.76) v2(71.9,47.85) v2(72.72,104.44) v2(74.31,0.76) v2(75.17,46.98) v2(75.26,104.44) v2(75.63,47.44) v2(76.24,15.39) v2(76.49,23.13) v2(76.85,0.76) v2(77.13,23.17) v2(77.46,14.48) v2(77.76,23.17) v2(78.09,14.48) v2(78.4,23.17) v2(78.86,14.48) v2(79.06,105.59) v2(79.03,23.17) v2(79.39,0.76) v2(79.49,14.48) v2(79.67,23.17) v2(80.13,14.48) v2(80.3,23.17) v2(80.79,14.47) v2(81.5,47.57) v2(81.6,105.59) v2(81.98,48.05) v2(81.93,0.76) v2(83.86,97.81) v2(84.14,105.59) v2(84.49,97.81) v2(84.47,0.76) v2(84.77,47.24) v2(85.13,97.81) v2(86.68,105.59) v2(86.96,71.39) v2(87.01,0.76) v2(87.11,68.65) v2(87.29,102.51) v2(88.05,74.63) v2(88.33,68.32) v2(88.69,38.27) v2(88.78,97.81) v2(88.94,84.51) v2(89.02,71.37) v2(89.19,102.51) v2(89.19,72.94) v2(89.22,105.59) v2(89.45,74.57) v2(89.55,0.76) v2(89.66,69.49) v2(89.7,67.33) v2(89.73,66.03) v2(89.7,30.5) v2(90.26,84.55) v2(90.56,72.97) v2(90.84,74.59) v2(90.95,70.48) v2(91.1,102.51) v2(91.1,26.46) v2(91.23,20.59) v2(91.5,84.55) v2(91.76,105.59) v2(91.73,26.47) v2(91.73,7.94) v2(91.81,60.54) v2(91.81,59.27) v2(91.81,58) v2(92.09,0.76) v2(92.39,26.48) v2(92.62,9.21) v2(92.95,48.23) v2(93,102.51) v2(93.23,87.22) v2(93.38,67.33) v2(93.54,26.48) v2(93.87,87.22) v2(94.02,88.66) v2(94.02,29.63) v2(94.15,47.39) v2(94.15,46.75) v2(94.17,44.6) v2(94.17,43.96) v2(94.2,26.47) v2(94.3,105.59) v2(94.41,60.85) v2(94.68,88.69) v2(94.67,59.07) v2(94.67,57.8) v2(94.67,56.53) v2(94.63,0.76) v2(94.86,26.47) v2(94.91,102.51) v2(95.31,88.71) v2(95.49,26.47) v2(95.54,50.18) v2(95.75,62.2) v2(96.05,50.56) v2(96.26,59.27) v2(96.26,58) v2(96.26,56.73) v2(96.31,40.86) v2(96.84,105.59) v2(96.81,102.51) v2(97.12,26.66) v2(97.17,0.76) v2(97.78,26.65) v2(97.98,75.28) v2(98.12,98.13) v2(98.44,26.66) v2(98.64,75.25) v2(98.76,98.11) v2(98.89,60.54) v2(98.89,58.63) v2(99.1,32.15) v2(99.07,26.66) v2(99.28,56.13) v2(99.38,105.59) v2(99.71,0.76) v2(100.06,97.81) v2(100.98,31.67) v2(101.31,60.17) v2(101.72,61.64) v2(101.92,105.59) v2(102.3,75.66) v2(102.3,74.97) v2(102.3,74.34) v2(102.22,58.64) v2(102.25,0.76) v2(102.32,80.21) v2(102.32,79.57) v2(102.32,78.91) v2(102.32,78.25) v2(102.32,77.59) v2(102.32,76.95) v2(102.32,76.29) v2(102.32,56.43) v2(102.48,46.7) v2(102.48,44.95) v2(102.45,38.68) v2(102.88,79.22) v2(102.88,78.55) v2(102.88,77.89) v2(102.88,77.26) v2(102.88,76.6) v2(102.88,75.94) v2(102.86,75.28) v2(102.88,74.64) v2(102.91,13.72) v2(103.67,62.2) v2(103.67,60.95) v2(103.67,59.48) v2(103.69,57.86) v2(103.8,105.58) v2(104.79,0.76) v2(104.97,57.83) v2(105.04,93.72) v2(105.09,61.28) v2(105.32,91.61) v2(106.13,92.68) v2(107,105.59) v2(107.09,94.23) v2(107.33,0.76) v2(107.44,77.59) v2(107.42,76.95) v2(107.42,76.27) v2(107.44,75.63) v2(107.43,75) v2(107.74,60.85) v2(107.99,58.39) v2(107.94,56.85) v2(107.94,55.58) v2(107.91,45.15) v2(108.04,71.47) v2(108.55,73.63) v2(108.8,92.63) v2(108.98,71.49) v2(108.95,62.02) v2(108.92,60.02) v2(109.15,93.78) v2(109.41,73.6) v2(109.54,105.59) v2(109.87,46.78) v2(109.87,0.76) v2(110.24,35.71) v2(110.33,73.63) v2(110.38,63.7) v2(110.38,62.25) v2(110.38,60.97) v2(110.33,47.24) v2(110.4,97.81) v2(110.91,30.65) v2(111.09,73.63) v2(111.04,47.95) v2(111.49,48.41) v2(111.65,93.54) v2(111.62,91.38) v2(111.8,62.45) v2(111.77,60.55) v2(112.08,105.59) v2(112.41,0.76) v2(112.76,56.46) v2(112.76,54.76) v2(112.99,89.86) v2(113.49,63.61) v2(113.58,59.71) v2(113.62,58.37) v2(114.16,92.09) v2(114.15,91.42) v2(114.95,0.76) v2(115.08,77.36) v2(115.08,76.68) v2(115.08,75.38) v2(115.1,81.27) v2(115.1,80.61) v2(115.1,79.95) v2(115.1,79.29) v2(115.1,78.66) v2(115.1,78) v2(115.1,76.04) v2(115.1,74.74) v2(115.66,80.92) v2(115.66,80.26) v2(115.66,79.6) v2(115.66,78.96) v2(115.66,78.3) v2(115.66,77.64) v2(115.63,76.98) v2(115.69,76.35) v2(115.69,75.68) v2(115.69,75.05) v2(115.69,74.41) v2(115.99,60.27) v2(116.29,85.77) v2(116.88,20.97) v2(117.16,105.59) v2(117.15,85.77) v2(117.39,89.58) v2(117.39,19.83) v2(117.49,0.76) v2(117.9,60.12) v2(117.87,20.31) v2(117.95,62.09) v2(118.08,85.95) v2(118.02,22.19) v2(118.15,41.29) v2(118.47,90.93) v2(118.95,69.51) v2(118.95,39.71) v2(119.03,85.69) v2(119.57,90.95) v2(119.7,105.59) v2(119.9,70.76) v2(120.03,0.76) v2(120.18,22.37) v2(120.33,95.67) v2(120.33,93.76) v2(120.34,62.28) v2(120.31,57.04) v2(120.31,27.45) v2(120.61,81.27) v2(120.82,97.81) v2(120.82,22.37) v2(120.94,27.45) v2(121.25,81.27) v2(121.45,86.7) v2(121.45,22.37) v2(121.58,27.45) v2(121.88,81.3) v2(121.88,80.64) v2(121.88,79.98) v2(121.88,79.34) v2(121.88,78.68) v2(121.88,78.02) v2(121.88,77.39) v2(121.88,76.73) v2(121.88,76.09) v2(121.88,75.43) v2(121.88,74.77) v2(121.93,74.14) v2(122.17,59.43) v2(122.24,105.59) v2(122.21,27.45) v2(122.49,78.3) v2(122.49,77.67) v2(122.57,0.76) v2(123.49,93.74) v2(123.51,64.15) v2(123.97,92.02) v2(123.99,59.84) v2(124.03,61.86) v2(124.78,105.59) v2(125.01,78.5) v2(125.11,94.43) v2(125.11,0.76) v2(125.44,91.31) v2(125.54,84.52) v2(125.77,80.79) v2(125.92,48.15) v2(126.89,97.82) v2(127.24,47.97) v2(127.32,105.59) v2(127.57,90.29) v2(127.55,27.2) v2(127.7,87.75) v2(127.65,0.76) v2(128.18,89.45) v2(128.18,27.2) v2(128.14,11.98) v2(128.44,25.29) v2(128.82,27.2) v2(128.99,92.57) v2(129.2,89.78) v2(129.6,93.49) v2(129.86,105.59) v2(130.19,0.76) v2(130.25,89.78) v2(130.62,46.8) v2(131.22,100.27) v2(131.51,93.41) v2(132.4,105.59) v2(132.73,0.76) v2(133.39,97.81) v2(133.74,92.75) v2(133.85,92.12) v2(134.86,97.81) v2(134.86,9.26) v2(134.94,105.59) v2(135.27,0.76) v2(135.45,16.27) v2(135.55,27.32) v2(136.31,47.01) v2(136.44,27.32) v2(136.51,14.62) v2(136.51,11.27) v2(136.89,97.81) v2(137,46.85) v2(137.48,105.59) v2(137.78,44.24) v2(137.81,0.76) v2(138.46,41.3) v2(138.47,27.32) v2(138.57,88.79) v2(139.1,64.51) v2(139.25,39.69) v2(139.49,102.38) v2(140.02,105.59) v2(140.35,0.76) v2(140.97,65.65) v2(141.16,39.44) v2(141.16,38.3) v2(141.39,102.38) v2(141.44,46.86) v2(141.73,68.74) v2(141.75,67.61) v2(142.18,70.64) v2(142.56,105.59) v2(142.89,0.76) v2(143.1,69.67) v2(144.39,70.68) v2(145.1,105.59) v2(145.46,39.54) v2(145.43,0.76) v2(146.19,47.39) v2(146.26,99.63) v2(146.6,46.83) v2(147.97,0.76) v2(148.45,58.97) v2(149.44,89.25) v2(149.77,90.7) v2(150.08,89.96) v2(150.15,13.07) v2(150.41,9.67) v2(150.51,0.76) v2(151.37,13.03) v2(151.83,5.66) v2(152.06,11.32) v2(152.49,13.05) v2(152.49,5.66) v2(153.05,0.76) v2(154.44,60.83) v2(154.49,58) v2(154.8,80.32) v2(154.93,62.3) v2(155.23,84.78) v2(155.49,80.32) v2(155.59,0.76) v2(155.64,38.19) v2(155.64,37.43) v2(155.64,36.54) v2(155.64,35.78) v2(155.66,35.15) v2(155.66,33.24) v2(155.64,32.61) v2(155.64,31.97) v2(156.12,80.32) v2(156.1,44.59) v2(156.33,63.04) v2(156.86,80.32) v2(157.27,84.7) v2(157.8,105.59) v2(158.13,0.76) v2(159.3,45.05) v2(160.34,105.59) v2(161.2,51.96) v2(161.89,13.2) v2(161.96,14.65) v2(161.91,11.24) v2(161.94,10.56) v2(162.07,85.82) v2(162.88,105.59) v2(163.16,20.52) v2(163.18,16.07) v2(163.21,0.76) v2(163.39,14.5) v2(163.45,55.22) v2(163.41,13.33) v2(163.53,56.7) v2(163.51,21.04) v2(164.38,17.65) v2(165.25,81.95) v2(165.32,83.74) v2(165.42,105.59) v2(165.75,0.76) v2(166.43,42.66) v2(167.3,65.6) v2(167.32,64.43) v2(167.46,41.76) v2(167.6,10.38) v2(167.7,15.82) v2(168.29,0.76) v2(169.63,105.58) v2(169.68,60.85) v2(169.71,58.79) v2(170.47,96.97) v2(170.5,105.59) v2(170.83,0.76) v2(172.38,102.13) v2(172.38,101.49) v2(172.38,100.86) v2(172.38,99.08) v2(173.37,0.76) v2(173.5,96.97) v2(173.67,105.58) v2(173.9,19.32) v2(174.79,19.32) v2(175.68,21.1) v2(175.68,20.21) v2(175.68,19.32) v2(175.68,18.43) v2(175.83,105.58) v2(175.91,0.76) v2(176.06,6.37) v2(176.57,19.32) v2(177.46,19.32) v2(178.63,0.78) v2(179.24,99.46) v2(181.14,100.22) v2(181.65,49.17) v2(182,10.38) v2(182,11.59) v2(182.41,102.76) v2(182.41,49.93) v2(182.41,49.17) v2(182.41,48.41) v2(182.41,34.44) v2(182.41,33.04) v2(183.17,49.17) v2(183.15,12.74) v2(183.15,12.03) v2(183.2,105.59) v2(183.76,13.4) v2(183.86,16.86) v2(183.81,14.06) v2(183.94,101.36) v2(183.95,16.05) v2(184.12,18.9) v2(184.32,20.95) v2(184.44,104.29) v2(185.23,15.74) v2(185.55,35.26) v2(185.56,7.92) v2(185.69,0.78) v2(185.74,105.59) v2(185.71,34.44) v2(185.89,6.6) v2(186.42,26.97) v2(186.73,25.04) v2(187.16,83.85) v2(187.16,82.44) v2(187.28,88.23) v2(187.24,72.66) v2(187.24,72.03) v2(187.24,71.39) v2(187.24,70.76) v2(187.36,95.12) v2(187.36,80.41) v2(187.49,94.38) v2(187.44,54.53) v2(187.75,26.31) v2(187.75,25.55) v2(187.77,0.78) v2(187.9,52.29) v2(188.28,105.59) v2(188.38,57.17) v2(188.76,0.78) v2(189.14,103.65) v2(189.47,50.51) v2(189.78,100.86) v2(190.39,0.91) v2(190.82,105.59) v2(191.17,58.87) v2(191.17,49.73) v2(191.24,103.47) v2(191.24,100.93) v2(191.24,98.39) v2(191.24,95.85) v2(191.24,93.31) v2(191.24,90.77) v2(191.24,88.23) v2(191.24,85.69) v2(191.24,83.15) v2(191.24,80.61) v2(191.24,78.07) v2(191.24,75.53) v2(191.24,72.99) v2(191.24,70.45) v2(191.24,67.91) v2(191.24,65.37) v2(191.24,62.83) v2(191.24,48.85) v2(191.24,46.31) v2(191.96,0.91) v2(192.09,44.37) v2(192.2,43.21) v2(193.54,16.05) v2(193.54,0.91) v2(195.11,44.06) v2(195.14,0.98) v2(195.24,42.22) v2(195.24,34.6) v2(195.24,32.06) v2(195.24,29.52) v2(195.24,26.98) v2(195.24,24.44) v2(195.24,7.66) v2(195.24,6.44) v2(195.24,3.24) v3(30.65,55.64) v3(30.65,54.63) v3(31.66,55.64) v3(31.66,54.63) v3(32.81,55.64) v3(33.69,52.72) v3(33.82,55.64) v3(34.61,45.1) v3(34.71,52.72) v3(34.84,55.64) v3(34.96,46.88) v3(35.14,42.56) v3(35.14,41.67) v3(35.22,44.37) v3(35.35,46.12) v3(35.47,45.23) v3(35.73,55.64) v3(35.85,46.88) v3(36.03,42.56) v3(36.03,41.67) v3(46.65,59.07) v3(46.65,58.18) v3(46.65,57.3) v3(46.65,56.41) v3(47.13,13.96) v3(47.54,56.79) v3(48.22,18.48) v3(48.22,17.65) v3(49.11,18.51) v3(49.11,17.67) v3(49.71,51.45) v3(49.95,18.56) v3(49.95,17.67) v3(50.36,51.98) v3(50.84,18.18) v3(52.62,48.41) v3(53.63,81.17) v3(54.52,81.17) v3(54.83,62.63) v3(55.28,61.84) v3(55.67,83.97) v3(55.67,82.95) v3(55.72,62.63) v3(56.17,61.84) v3(56.6,62.63) v3(57.06,61.84) v3(57.82,62.19) v3(60.77,55.01) v3(60.82,53.26) v3(61.05,54.12) v3(64.94,55.77) v3(65.32,92.68) v3(65.32,91.79) v3(65.44,83.2) v3(65.72,93.46) v3(65.83,82.31) v3(65.83,81.43) v3(65.83,63.52) v3(66.18,92.68) v3(66.16,91.79) v3(66.33,83.2) v3(66.46,72.66) v3(66.46,71.77) v3(66.46,70.88) v3(66.61,93.46) v3(66.71,82.31) v3(66.71,81.43) v3(66.84,63.52) v3(67.07,92.68) v3(67.04,91.81) v3(67.22,83.2) v3(67.35,72.66) v3(67.35,71.77) v3(67.35,70.88) v3(67.45,93.44) v3(67.6,82.31) v3(67.6,81.43) v3(67.73,63.52) v3(67.91,92.65) v3(67.96,91.79) v3(67.96,90.92) v3(68.11,83.2) v3(68.24,72.66) v3(68.24,71.77) v3(68.24,70.88) v3(68.31,93.46) v3(68.37,57.3) v3(68.49,82.31) v3(68.49,81.43) v3(68.77,92.68) v3(68.8,91.79) v3(68.75,63.52) v3(68.82,90.92) v3(69,83.2) v3(69,57.93) v3(69.18,93.46) v3(69.13,72.66) v3(69.13,71.77) v3(69.13,70.88) v3(69.38,82.31) v3(69.38,81.43) v3(69.64,92.68) v3(69.64,91.79) v3(69.66,90.92) v3(71.03,72.66) v3(71.03,71.77) v3(71.03,70.88) v3(71.62,85.24) v3(71.64,84.4) v3(71.64,83.53) v3(71.65,82.7) v3(71.64,81.86) v3(71.92,74.82) v3(72.66,65.32) v3(72.63,63.85) v3(72.81,74.82) v3(73.03,75.63) v3(73.57,63.9) v3(73.57,63.01) v3(73.7,74.82) v3(73.92,75.63) v3(74.31,91.92) v3(74.59,74.82) v3(74.87,91.25) v3(74.81,75.63) v3(74.97,92.5) v3(75.48,74.82) v3(75.58,91.79) v3(76.37,74.82) v3(76.49,57.68) v3(76.49,56.79) v3(76.49,55.9) v3(80.68,87.01) v3(81.19,86.25) v3(81.19,83.33) v3(81.95,85.74) v3(81.97,62.27) v3(82.08,83.33) v3(82,60.72) v3(82.97,83.33) v3(91.35,56.66) v3(93.46,20.92) v3(94.32,20.9) v3(94.32,20.06) v3(95.06,20.44) v3(95.06,19.58) v3(95.8,14.29) v3(96.31,17.16) v3(96.43,18.69) v3(96.69,13.51) v3(97.19,17.16) v3(97.19,16.27) v3(97.32,18.69) v3(103.47,15.59) v3(103.44,14.75) v3(103.94,21.74) v3(104.31,20.97) v3(104.81,21.74) v3(108.88,24.78) v3(118.15,16.53) v3(118.66,19.47) v3(119.19,16.5) v3(119.55,19.45) v3(120.28,16.45) v3(120.38,19.45) v3(121.32,19.45) v3(166.79,68.47) v3(166.97,99.38) v3(166.99,98.54) v3(166.92,77.23) v3(167.17,105.17) v3(167.42,97.83) v3(167.96,98.52) v3(168.06,105.17) v3(168.48,97.86) v3(169.36,78.22) v3(169.33,77.36) v3(169.33,76.47) v3(169.33,69.49) v3(170.4,78.22) v3(170.4,77.39) v3(170.42,76.55) v3(171.29,78.25) v3(171.29,77.41) v3(171.31,76.57) v3(172.12,78.25) v3(172.12,77.36) v3(172.15,76.47)
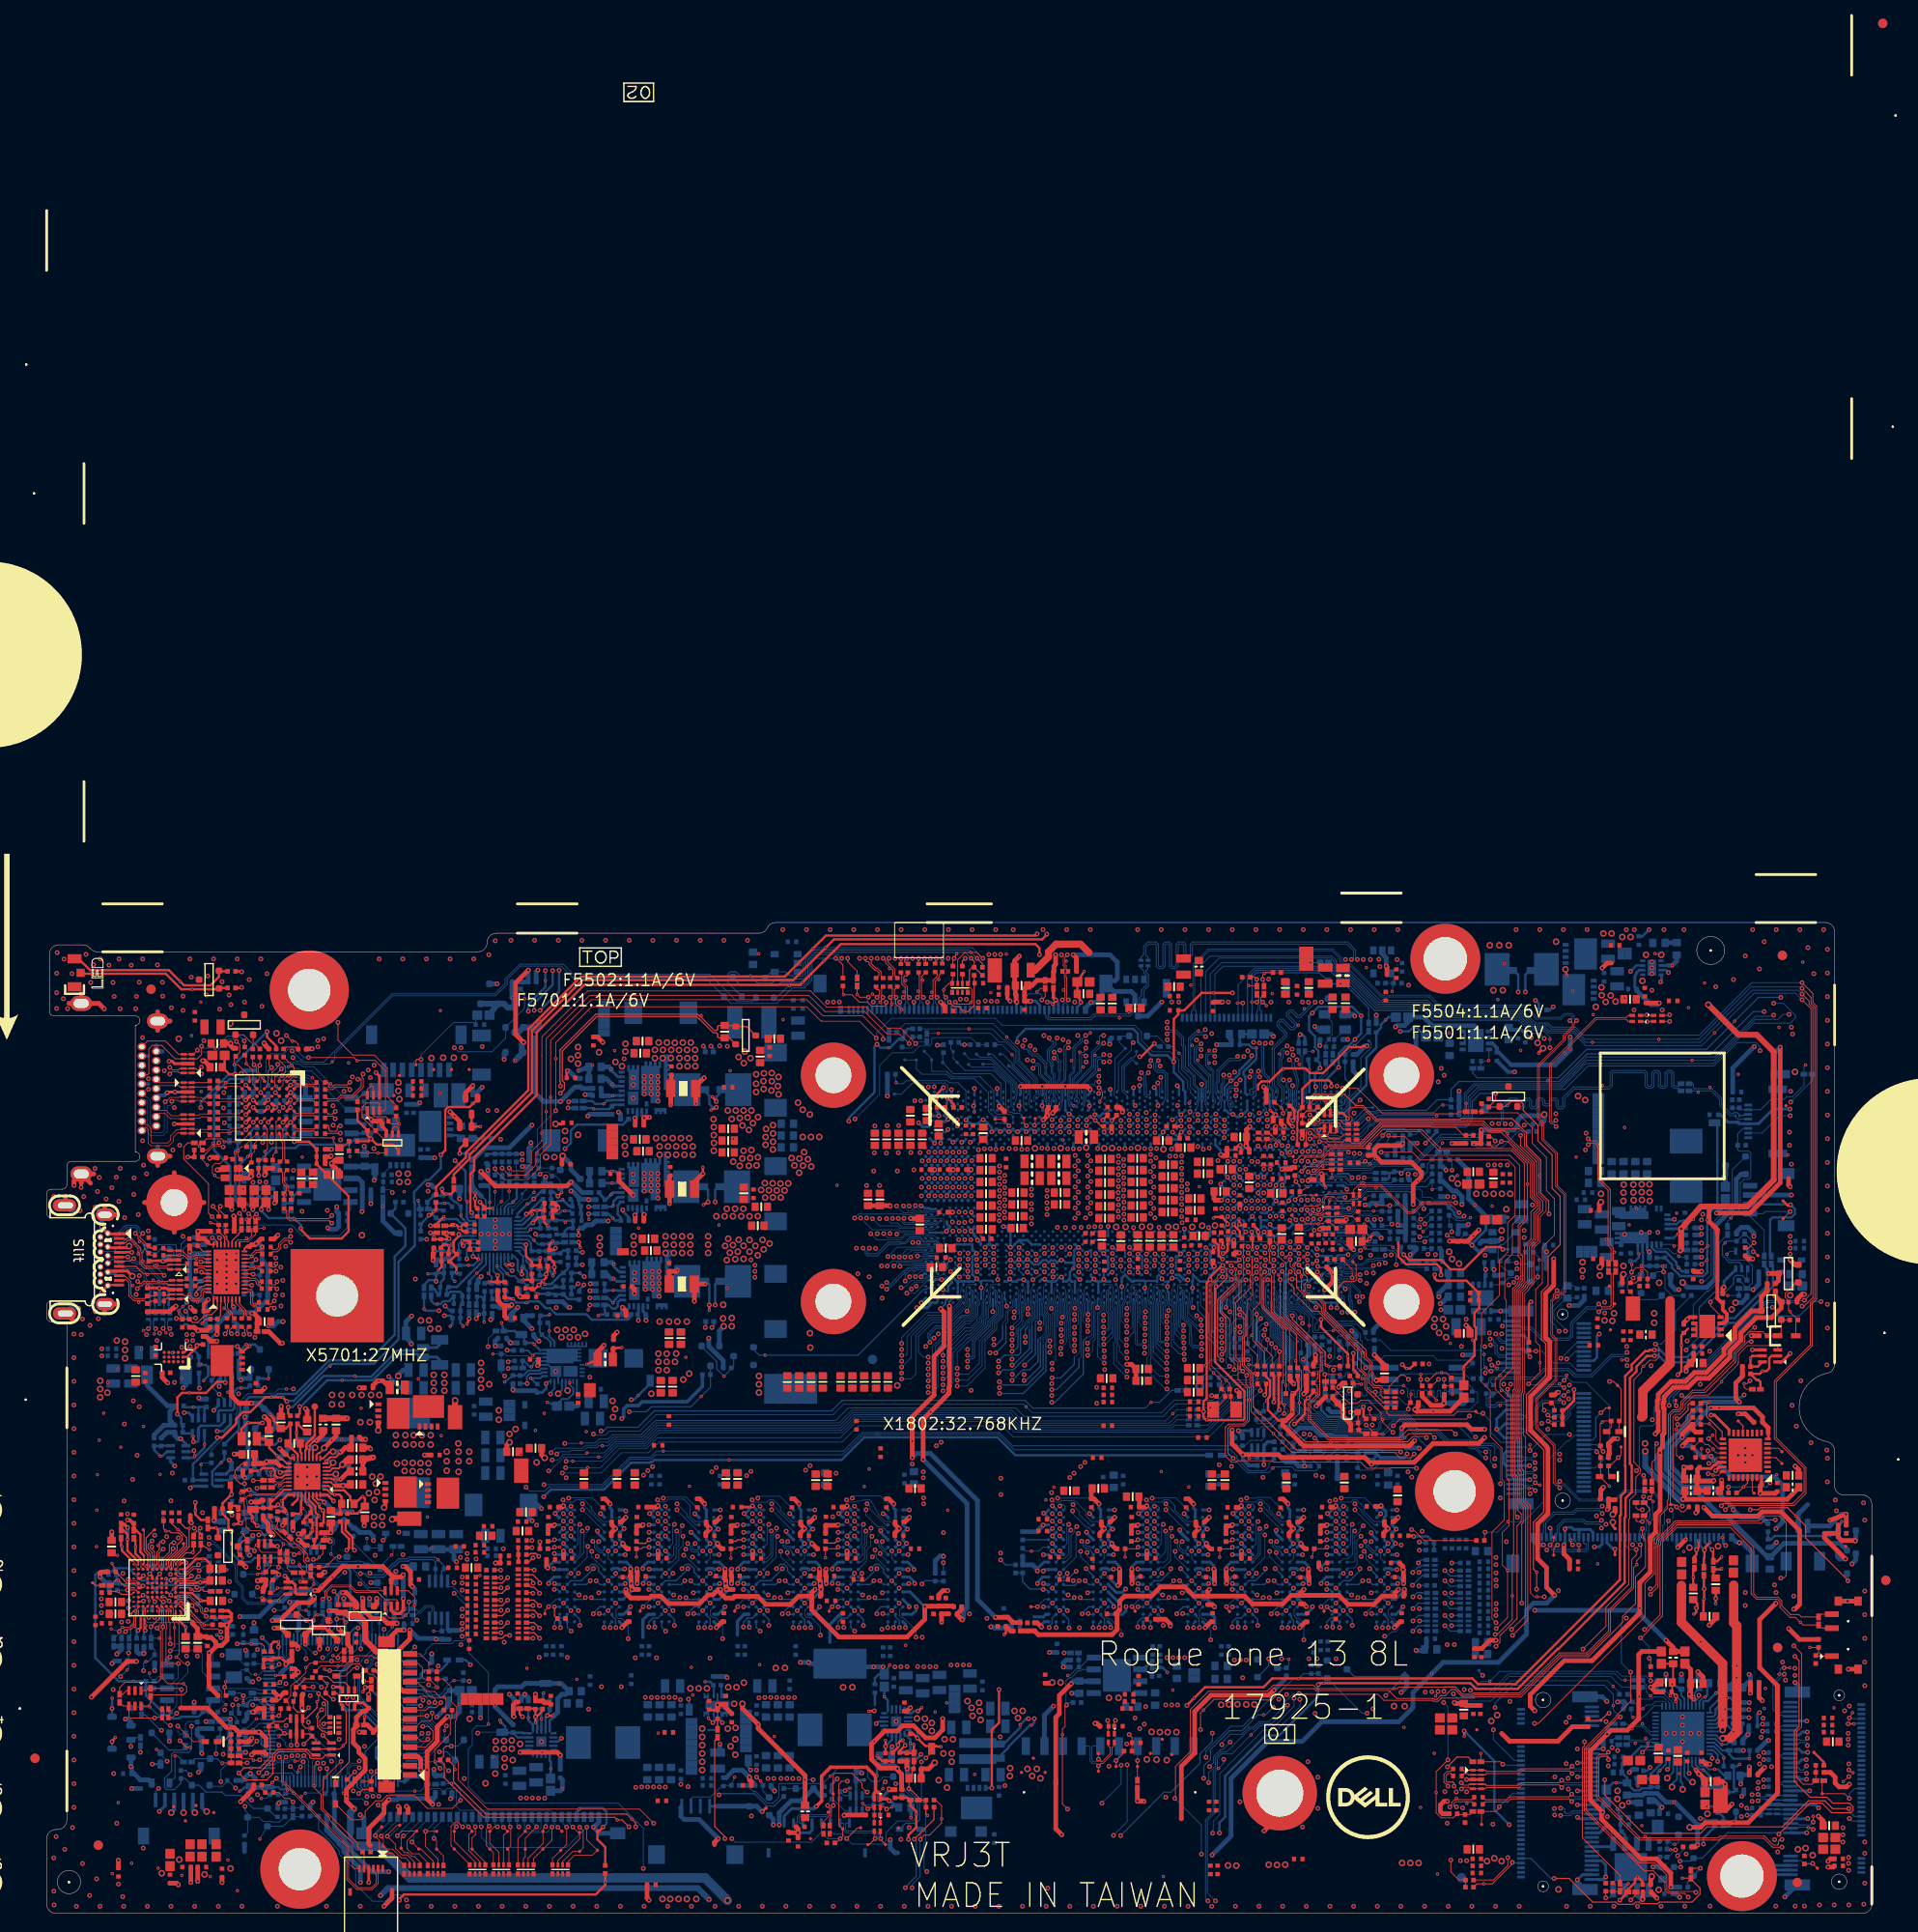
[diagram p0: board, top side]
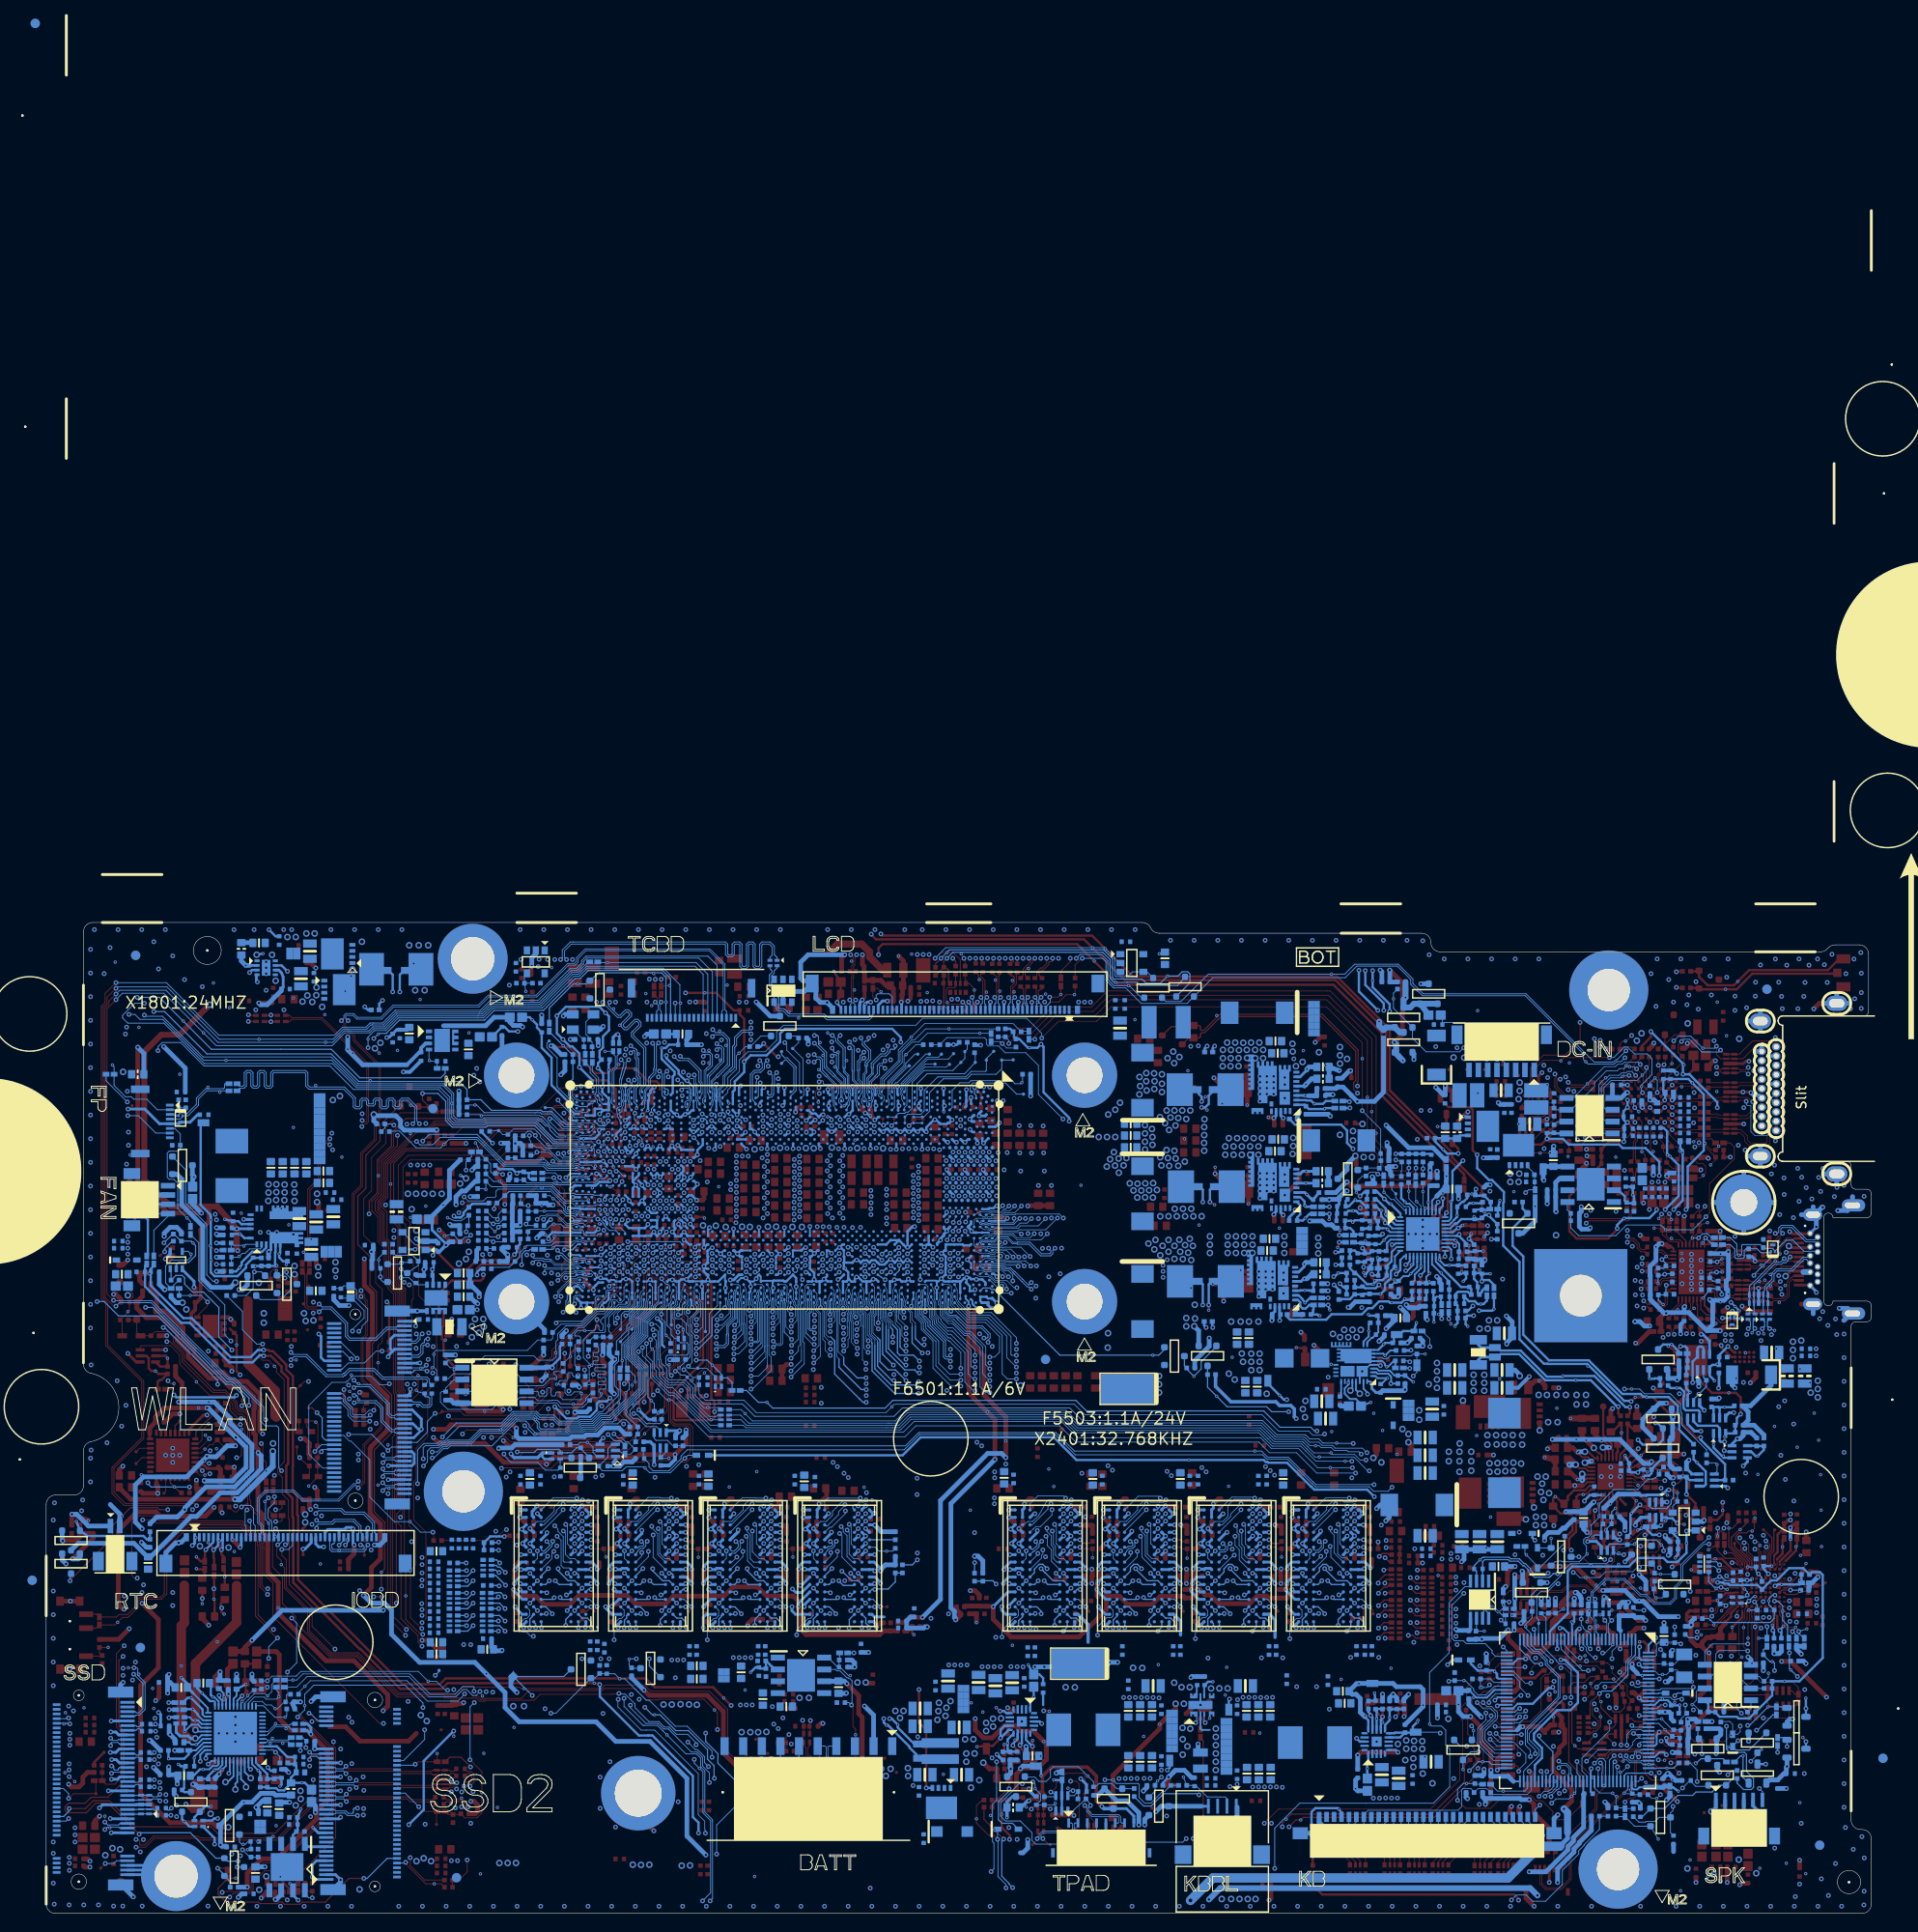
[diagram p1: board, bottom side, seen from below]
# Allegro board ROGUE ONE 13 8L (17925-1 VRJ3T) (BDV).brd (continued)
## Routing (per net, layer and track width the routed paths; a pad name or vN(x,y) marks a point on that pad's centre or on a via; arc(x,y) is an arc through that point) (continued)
V0.85A_VID0: length 3.7
  BOTTOM w0.102: CPU1.CB36 131.82,65.66 131.84,65.63 131.84,65.12 132.98,63.98 132.98,62.83 TP2201.1
V0.85A_VID1: length 6.2
  BOTTOM w0.076: CPU1.CB35 132.05,66.3 132.05,66.08 132.08,65.97 132.09,65.96 132.09,65.78 132.03,65.62 132.03,65.21
  BOTTOM w0.102: TP2202.1 133.44,62.25 133.44,62.86 133.17,63.12 133.17,64.06 133.1,64.13 133.1,64.14 132.03,65.21
VBUS_P_CTRL: length 20
  TOP w0.127: v2(15.81,49.68) v1(15.89,49.09) ; U7201.D7 11.35,33.73 v2(11.62,33.46)
  L4SGND w0.127: v2(11.62,33.46) 12.76,34.61 12.76,37.1 14.67,39.01 14.67,47.29 15.34,47.96 15.34,49.1 15.81,49.57 v2(15.81,49.68)
  BOTTOM w0.127: Q7404.2 15.71,49.55 15.81,49.65 v2(15.81,49.68)
VBUS_P_CTRL_R: length 4.4
  BOTTOM w0.254: Q7404.6 12.35,50.2 R7409.1 R7423.2 11.55,49.74 v1(12.19,49.09) 12.43,49.09 12.89,49.55 Q7404.5
VCCCORE_SENSE: length 64.4
  TOP w0.254: v1(57.07,73.34) v2(57.14,72.79) ; R719.2 113.93,85.66 v2(113.42,85.15)
  L6 w0.254: v2(113.42,85.15) 113.42,84.98 111.8,83.36 107.25,83.36 107.25,83.35 106.85,83.35 106.85,83.36 100.83,83.36 100.53,83.66 89.11,83.66 79.38,73.93 61.53,73.93 61.33,73.73 58.3,73.73 57.36,72.79 v2(57.14,72.79)
  BOTTOM w0.254: PR4665.1 v2(57.14,72.79) ; CPU1.AN6 113.86,84.83 113.59,85.1 113.47,85.1 v2(113.42,85.15)
VCCDSW_ON: length 203.2
  L6 w0.102: v2(29.73,16.12) 30.19,16.12 30.8,15.51 31.28,15.51 32.68,14.12 33.44,14.12 33.81,13.74 38.77,13.74 41.36,11.14 41.53,11.14 41.53,11.14 41.7,11.14 41.7,11.14 41.82,11.14 42.07,10.89 65.75,10.89 66.31,10.33 66.49,10.33 66.52,10.31 74.21,10.31 74.52,10.3 75.08,9.75 76.96,9.75 77.9,10.69 82.24,10.69 82.9,10.03 90.98,10.03 91.89,10.94 94.32,10.94 95.61,9.64 96,9.64 96.04,9.6 105.36,9.6 106.34,9.6 106.34,9.6 106.48,9.6 106.53,9.64 106.55,9.64 107.63,10.73 110.72,10.73 113.24,13.25 113.76,13.25 114.56,13.25 115.73,13.25 117.92,13.25 118.54,13.25 119.35,13.25 119.35,13.25 119.52,13.25 119.69,13.25 119.69,13.25 120.75,13.25 121.06,13.25 122.89,15.08 123.12,15.08 123.16,15.12 123.45,15.12 123.67,15.33 126.05,15.33 129.16,18.45 143.66,18.45 144.38,17.72 148.5,17.72 148.68,17.54 148.95,17.54 149.45,17.04 156.4,17.04 159.27,19.91 159.27,24.48 161.66,26.87 161.66,32.3 163.33,33.97 163.33,35.38 160.31,38.4 160.31,41.25 161.45,42.39 163.45,42.39 164.53,43.47 164.53,43.77 164.53,47.11 163.79,47.85 163.79,49.9 162.73,50.96 162.73,53.49 161.13,55.09 161.13,55.09 160.99,55.23 160.99,60.72 159.96,61.74 159.96,68.17 v2(160.11,68.32)
  BOTTOM w0.102: R2520.2 160.29,70.35 v1(160.29,70.12) 160.29,69.41 C2525.1 v2(160.11,68.32) 160.11,68.06 159.82,67.77 D2503.2 ; U2401.88 28.54,16.32 28.84,16.63 29.22,16.63 v2(29.73,16.12)
VCCGT_SENSE: length 90.3
  TOP w0.254: R807.2 97.4,86.86 v2(96.69,87.57) ; v2(46.14,63.82) v1(46.47,64.31)
  L6 w0.254: v2(46.14,63.82) 45.92,64.04 45.92,66.08 42.46,69.54 42.46,74.47 43.47,75.48 43.47,78.57 45.48,80.58 45.48,85.72 55.13,95.37 77.38,95.37 80.61,92.14 80.61,88.1 82.72,86 90.27,86 92.07,87.8 96.45,87.8 v2(96.69,87.57)
  BOTTOM w0.254: CPU1.E3 96.69,86.92 v2(96.69,87.57) ; v2(46.14,63.82) PR4667.1
VCCPD_VBUS_ACK: length 23.6
  TOP w0.254: v2(15.96,44.11) v1(15.96,43.25) 15.96,42.82 16.55,42.23 PR4488.2 ; R7424.2 16.22,61.05 v2(16.12,60.95) 16.12,60.77 15.05,59.71 U7419.A2
  L4SGND w0.254: v2(15.96,44.11) 15.96,48.89 16.32,49.24 16.32,53.36 15.15,54.53 15.15,56.2 16.12,57.17 v2(16.12,60.95)
VCCRTCEXT: length 2.5
  TOP w0.254: v1(125.31,74.62) 125.43,74.74 C2201.1 126.84,74.11 v2(126.84,73.98)
  BOTTOM w0.254: CPU1.BP24 126.51,73.65 v2(126.84,73.98)
VCCSA_SENSE: length 109.4
  TOP w0.254: v2(121.86,83.85) 121.65,83.65 R810.2 ; PR4601.2 v2(41.21,73.04)
  L4SGND w0.254: v2(121.86,83.85) 121.69,83.85 121.22,84.32 120.25,84.32 119.67,84.9 119.67,86.16 120.13,86.61 120.13,91.47 119.55,92.04 118.47,92.04 117.99,92.52 116.34,92.52 115.58,93.28 115.58,94.35 114.31,95.62 80.83,95.62 79.31,97.15 56.23,97.15 48.5,89.42 48.5,88.43 45.58,85.51 45.58,78.94 42.42,75.78 42.42,73.69 41.96,73.23 41.4,73.23 v2(41.21,73.04)
  BOTTOM w0.254: v2(41.21,73.04) 41.56,72.66 41.56,72.63 v1(41.59,72.6) ; v2(121.86,83.85) 121.93,83.85 CPU1.BG7
VCCST_PWRGD: length 101.3
  TOP w0.089: v2(34.08,24.91) 34.74,24.91 34.86,25.04 ; v2(14.09,20.11) v1(15.09,19.1) 15.76,18.43 D4002.A
  L4SGND w0.089: v2(53,79.34) 53,73.93 52.49,73.42 52.28,73.42 48.93,70.08 48.93,63.24 47.41,61.71 v2(47.41,60.83) 47.41,60.32 48.3,59.43 48.3,56.44 47,55.14 47,48 38.77,39.77 37.89,39.77 36.23,38.12 36.23,33.84 36.23,33.54 34.46,31.77 34.46,27.91 33.85,27.3 33.85,26.66 34.08,26.43 v2(34.08,24.91)
  L6 w0.089: v2(34.08,24.91) 33.69,25.29 24.85,25.29 24.55,25 24.55,24.69 23.25,23.39 21.92,23.39 21.43,23.87 20.53,23.87 19.4,22.74 17.81,22.74 17.06,21.99 15.96,21.99 v2(14.09,20.11)
  BOTTOM w0.089: R4005.2 16.12,20.59 15.2,20.59 14.9,20.29 D4003.A 14.36,19.22 14.09,19.5 v2(14.09,20.11) ; R4002.1 52.5,79.16 52.7,79.22 52.88,79.32 52.98,79.32 v2(53,79.34) 53.05,79.34 53.26,79.56 53.85,79.56 R1716.1 54.65,79.14 55.15,78.63 ED1704.1 ; R4011.2 47.41,61.66 v2(47.41,60.83)
VCCST_PWRGD_R: length 95
  TOP w0.089: v2(54.67,86.15) v1(54.67,91.74) 54.67,93.46 58.51,97.3 81.62,97.3 83.15,95.78 83.22,95.78 83.25,95.75 87.29,95.75 v2(89.09,93.95)
  BOTTOM w0.089: v2(54.67,86.15) 52.69,84.17 C1711.1 52.69,80.82 R1719.1 52.67,80.16 R1718.1 52.95,80 R1716.2 54.94,80 ED1704.2 ; v2(89.09,93.95) 89.09,94.46 90.71,96.07 101.87,96.07 102.62,95.32 116.83,95.32 117.56,94.59 117.56,93.7 118.79,92.47 120.66,92.47 121.58,91.56 121.58,90.34 122.52,89.4 122.52,88.66 122.82,88.36 122.82,88.09 CPU1.BJ2
VCCSTG_EN_L1: length 8.4
  BOTTOM w0.102: R4018.2 181.76,67.96 182.33,67.39 182.33,67.35 182.59,67.1 R4039.1 183.17,67.66 183.17,69.5 182.56,70.12 180.79,70.12 180.45,70.46 v1(180.45,70.75) 180.75,71.06 U4008.4
VCCSTG_EN_R1: length 31.8
  TOP w0.102: U4002.4 179.76,64.14 178.68,65.22 v2(178.68,65.63)
  L4SGND w0.102: v2(178.68,65.63) 178.5,65.8 174.82,65.8 174.16,66.47 171.18,66.47 170.91,66.74 166.52,66.74 166.25,66.47 163.33,66.47 161.05,68.75 158.43,68.75 v2(157.91,68.23)
  BOTTOM w0.102: v2(178.68,65.63) 179.36,66.31 v1(180.53,66.31) R4004.2 R4039.2 ; v2(157.91,68.23) 157.02,68.23 156.45,67.66 C4040.1 156.11,67.47 U4003.4
VCCSTU_EN_R: length 2.8
  BOTTOM w0.102: U4006.4 154.89,91.57 v1(154.85,91.53) 154.78,91.46 C4034.1 154.01,91.43 R4024.2
VDD: length 28.9
  TOP w0.203: PU4401.18 25.52,47.88 25.37,48.03 25.05,48.03
  TOP w0.508: PR4405.2 33.82,50.87 v2(34.25,50.87) ; v2(24.32,40.61) 24.22,40.71 24.22,40.71 23.89,41.04 23.89,41.04 23.79,41.14 23.79,41.8 23.28,42.31 PR4429.1 ; PC4422.1 22.3,48.26 PR4427.1 22.92,48.26 22.96,48.3 23.44,48.3 v2(23.61,48.48) 24.6,48.48 25.05,48.03
  L6 w0.508: v2(24.32,40.61) 23.79,41.14 23.79,43.69 24.3,44.2 24.3,47.8 v2(23.61,48.48)
  BOTTOM w0.508: v2(34.25,50.87) v1(31.69,50.87) 27.01,50.87 24.42,48.28 23.81,48.28 v2(23.61,48.48)
VDDQ_PWRGD: length 2.6
  BOTTOM w0.254: PG5114.1 50.28,62.5 R4011.1 v1(48.86,63.39)
VSSCORE_SENSE: length 65.5
  TOP w0.254: R720.1 114.9,85.61 v2(114.38,85.09) ; v2(57.14,72.03) v1(57.31,71.47)
  L6 w0.254: v2(57.14,72.03) 58.46,73.35 61.49,73.35 61.69,73.55 79.54,73.55 89.27,83.28 100.37,83.28 100.67,82.97 106.69,82.97 106.69,82.97 107.41,82.97 111.96,82.97 114.07,85.09 v2(114.38,85.09)
  BOTTOM w0.254: PR4666.1 v2(57.14,72.03) ; v2(114.38,85.09) 114.36,85.09 113.98,85.48 CPU1.AN5
VSSGT_SENSE: length 92.2
  TOP w0.254: v2(96.31,88.64) 95.62,87.95 R808.1 ; v2(45.38,63.82) v1(45.14,63.26)
  L6 w0.254: v2(45.38,63.82) 45.54,63.98 45.54,65.92 42.08,69.39 42.08,74.62 43.09,75.64 43.09,78.73 45.1,80.74 45.1,85.88 54.97,95.75 77.54,95.75 81,92.3 81,88.26 82.87,86.38 90.11,86.38 91.91,88.18 95.85,88.18 v2(96.31,88.64)
  BOTTOM w0.127: CPU1.D2 96.14,87.8 96.31,87.97 v2(96.31,88.64)
  BOTTOM w0.254: v2(45.38,63.82) PR4668.1
VSSSA_SENSE: length 110
  TOP w0.254: v2(41.21,73.81) PR4602.2 41.9,74.01 v1(42.66,74.77) ; v2(121.82,84.49) 121.81,84.47 R809.1
  L4SGND w0.254: v2(41.21,73.81) 41.4,73.61 41.8,73.61 42.03,73.85 42.03,75.94 45.2,79.1 45.2,85.67 48.12,88.59 48.12,89.57 56.07,97.53 79.46,97.53 80.99,96.01 114.47,96.01 115.96,94.51 115.96,93.44 116.5,92.91 118.15,92.91 118.63,92.43 119.71,92.43 120.51,91.62 120.51,86.45 120.05,86 120.05,85.06 120.41,84.7 121.38,84.7 121.54,84.54 121.6,84.49 v2(121.82,84.49)
  BOTTOM w0.254: CPU1.BE7 121.65,84.49 v2(121.82,84.49)
0D6V_VREF_S0: length 114.9
  L3SGND w0.508: v2(150.41,28.85) 149.82,28.26 148.15,28.26 147.44,27.55 146.11,27.55 145.58,28.09 111.72,28.09 110.94,27.3 106.31,27.3 105.47,28.14 50.1,28.14 v2(49.14,29.1) 48.91,29.1 47.54,30.47 47.54,38.17 48.5,39.13 v2(49.04,39.13)
  vias: v1(92.24,28.77) v2(151.17,28.85)
1D0V_PWR:
  vias: v1(169.46,84.35)
1D0V_S5: length 231.1
  TOP w0.305: v1(160.24,92.32) 160.24,92.38 v3(160.7,92.85)
  TOP w0.508: v2(161.84,70.25) 161.84,67.4 160.97,66.53 160.97,61.79 161.16,61.6 161.42,61.34 161.42,57.54 159.35,55.47 159.35,51.85 161.09,50.12 161.09,50.04 161.21,49.91 161.21,42.91 160.11,41.8 160.11,38.07 161.08,37.1 161.08,34.99 v2(161.94,34.13)
  L3SGND w0.508: v2(144.84,95.14) 141.54,91.84 136.13,91.84 133.82,94.15 131.76,94.15 v2(131.74,94.13)
  L4SGND w0.508: v2(22.01,12.16) 23.08,11.09 28.92,11.09 34.28,5.73 54.22,5.73 55.36,6.88 64.5,6.88 67.68,3.7 92.9,3.7 93.97,2.63 106.36,2.63 107.07,3.35 122.26,3.35 125.16,6.24 v2(125.16,6.27)
  BOTTOM w0.508: v2(144.84,95.14) 145.06,95.29 145.84,95.29 146.22,95.67 R2202.1 147.89,96.18 148.81,95.27 153.33,95.27 ; v2(22.01,12.16) 21.63,12.54 R2402.1 ; v2(125.16,6.27) 127.19,8.3 127.19,14.49 131.16,18.46 134.84,18.46 136.95,20.57 145.2,20.57 146.72,22.09 146.72,23.7 v1(148.74,25.71) 149.97,26.94 155.9,26.94 158.92,29.96 158.92,32.54 159.67,33.29 161.08,33.29 161.91,34.13 v2(161.94,34.13) ; R2205.1 131.48,94.38 v2(131.74,94.13)
  vias: v1(158.28,92.63) v1(160.34,79.16) v1(164.25,81.17) v2(126.18,75.66) v2(126.84,80.71) v2(126.81,76.5) v2(127.48,80.72) v2(127.5,78.17) v2(127.47,76.5) v2(127.51,77.34) v2(128.13,80.71) v2(128.13,79.85) v2(128.13,78.15) v2(128.77,79.86) v2(128.77,76.5) v2(128.79,75.66) v2(129.4,76.5) v2(129.43,75.67) v2(130.06,78.17) v2(130.06,76.5) v2(130.09,75.66) v2(130.7,77.34) v2(130.72,79.88) v2(130.75,78.17) v2(130.72,76.5) v2(130.72,75.66) v2(131.4,79.87) v3(150.62,71.01) v3(150.92,70.23) v3(151.68,69.74) v3(153.53,77.23) v3(154.5,77.23) v3(155.39,77.23) v3(156.27,77.23) v3(157.16,77.23) v3(160.11,93.44) v3(164.45,87.72) v3(165.22,87.29)
1D0V_S5_EN: length 4.8
  BOTTOM w0.102: PR5210.2 176.11,69.69 PC5215.1 175.37,70.43 v1(175.28,70.51) 174.96,70.83 174.64,70.83 174.15,71.32 172.99,71.32 172.87,71.44 PU5201.2
1D0V_S5_PWRGD: length 223.7
  TOP w0.102: R4029.1 21.51,16.15 v2(21.53,16.16) ; v1(178.4,71.65) 178.39,71.59 v2(177.71,71.14)
  L3SGND w0.102: v2(155.31,9.57) 155.31,9.47 154.09,8.25 143.7,8.25 138.75,3.29 124.75,3.29 122.06,5.99 122.06,10.58 v2(120.18,12.46)
  L6 w0.102: v2(177.71,71.14) 176.95,70.38 176.95,67.46 175.48,65.98 175.48,61.82 174.56,60.91 174.56,58.14 173.44,57.02 173.44,52.51 173.91,52.04 173.91,48.88 174.75,48.04 174.75,44.8 173.14,43.19 173.14,37.5 173.14,34.15 165.82,26.84 165.82,19.91 158.13,12.21 158.13,11.93 155.77,9.57 v2(155.31,9.57) ; v2(120.18,12.46) 119.6,13.05 119.44,13.05 119.27,13.05 118.46,13.05 117.83,13.05 115.64,13.05 114.65,13.05 113.67,13.05 113.33,13.05 110.8,10.52 110.63,10.52 108.5,10.52 107.71,10.52 106.63,9.44 106.61,9.44 106.57,9.4 106.42,9.4 95.96,9.4 95.91,9.44 95.53,9.44 94.26,10.71 92.04,10.71 91.15,9.82 82.82,9.82 82.16,10.48 77.99,10.48 77.05,9.54 74.84,9.54 74.39,10 66.26,10 65.57,10.68 41.99,10.68 41.73,10.94 41.44,10.94 41.28,10.94 38.74,13.48 38.34,13.48 33.57,13.48 33.31,13.73 32.3,13.73 31.21,14.83 30.93,14.83 30.91,14.85 25.58,14.85 25.04,15.4 24.41,15.4 24.22,15.59 23.45,15.59 23.19,15.84 22.43,15.84 22.22,16.05 21.64,16.05 v2(21.53,16.16)
  BOTTOM w0.102: PR5209.1 177.66,71.19 v2(177.71,71.14)
1D0V_VCCA_XTAL: length 13.6
  BOTTOM w0.254: CPU1.CP5 139.25,85.8 139.94,86.49 139.94,87.11 141.73,88.9 141.73,91.85 142.79,92.91 C2219.1 143.09,94.86 143.3,95.06 143.3,95.4 v1(143.8,95.9) 144.08,96.18 R2202.2
1D0V_VCCAMPHYPLL: length 10
  BOTTOM w0.254: CPU1.BV2 128.72,88.06 128.72,89.82 128.53,90.01 128.53,90.33 129.91,91.71 v1(129.91,92.88) 129.48,92.88 129.12,93.24 C2209.1 128.13,94.18 C2208.1 R2205.2
1D0V_VCCDSW: length 1.8
  TOP w0.254: v1(128.05,74.53) v2(128.09,73.97) 128.21,73.86 C2213.1
  BOTTOM w0.254: CPU1.BT24 128.08,73.83 128.08,73.97 v2(128.09,73.97)
1D0V_VCCPRIM_MPHY: length 0.7
  BOTTOM w0.254: v3(150.92,78.89) v1(151.5,79.2)
  vias: v2(129.42,80.71) v2(130.06,80.69) v3(151.55,78.33)
1D2V_HDMI:
  vias: v1(21.12,77.74) v2(22.16,78.48) v2(22.87,78.53) v2(23.56,78.48)
1D2V_HDMI_EN: length 5.7
  TOP w0.102: U5701.G8 20.9,82.82 v1(19.08,82.82) 18.77,83.13 17.16,83.13 R5801.1
1D2V_HDMI_EN_R: length 29.1
  TOP w0.102: R5801.2 15.15,82.7 14.72,82.26 14.72,80.97 17.38,78.3 17.38,75.15 v2(17.77,74.77)
  BOTTOM w0.102: v2(17.77,74.77) 19.17,73.37 v1(22.09,73.37) 22.59,73.88 26.3,73.88 27.45,72.74 31.43,72.74 32.27,73.58 C5744.1 FC5702.1 32.66,75.51 U5801.8
1D2V_HDMI_FB: length 5.6
  BOTTOM w0.254: U5801.2 27.14,77.62 26.48,76.95 26.48,76.5 FC5703.1 26.2,76.22 R5774.1 25.49,76.95 v1(25.64,77.11) 25.62,77.13 R5773.2 25.67,78 C5745.2
1D2V_HDMI_R:
  vias: v1(27.45,81.17) v2(26.51,79.75)
1D2V_HDMI_VDD: length 12.3
  TOP w0.254: v2(22.14,75.54) 22.29,75.7 R5781.2 ; U5701.F5 v2(22.18,86.51) ; v2(23.79,84.91) 24.18,85.31 U5701.D6
  BOTTOM w0.254: C5758.1 22.29,84.3 21.93,83.94 21.93,81.55 v1(21.61,81.23) 20.69,80.31 20.69,76.99 v2(22.14,75.54)
1D2V_HDMI_VDDA: length 22
  TOP w0.254: v2(19.9,75.54) 19.62,75.82 R5782.2 ; U5701.F4 22.21,87.28 v2(22.19,87.28)
  BOTTOM w0.254: v2(19.9,75.54) 19.72,75.72 19.72,80.15 18,81.88 18,87.9 v1(19.22,89.12) 19.65,89.55 C5762.1 C5761.1 22.34,88.26 C5760.1 22.14,88.05 22.14,87.34 v2(22.19,87.28)
1D2V_HDMI_VDDRX: length 32.1
  TOP w0.254: v2(23.05,75.53) 23.05,75.81 R5783.2 ; v2(27.29,73.53) 27.29,73.4 28.26,72.43 31.66,72.43 32.42,73.2 32.42,76.98 C5764.1 29,80.41 C5765.1 C5767.1 C5766.1 28.18,82.82 v2(26.58,82.82) ; v2(26.19,84.91) U5701.B7 ; v2(26.19,87.31) U5701.B4 ; v2(26.19,86.51) U5701.B5
  BOTTOM w0.254: 26.56,74.62 23.84,74.62 23.05,75.41 v2(23.05,75.53) ; 26.56,74.62 v1(26.56,74.59) ; 26.56,74.62 27.29,73.89 v2(27.29,73.53) ; v2(26.58,82.82) 26.58,82.87 26.53,82.92 C5769.1 C5768.1 26.53,84.56 v2(26.19,84.91) 26.33,84.91 26.61,85.18 C5770.1 26.61,86.09 v2(26.19,86.51) v2(26.19,87.31)
1D2V_HDMI_VDDTX: length 9.9
  TOP w0.254: v2(21.39,84.1) U5701.G7 ; R5784.2 20.94,75.82 v2(21.22,75.54) ; v2(21.38,85.73) 21.41,85.73 U5701.G5
  BOTTOM w0.254: v2(21.22,75.54) 20.26,76.51 v1(20.26,81.65) 20.26,81.91 20.52,82.17 20.52,82.88
1D2V_HDMI_VIN: length 2.7
  BOTTOM w0.508: G5701.2 C5742.1 34.1,80.18 34.13,80.16 U5801.5
  vias: v1(32.58,81.25)
1D2V_S3: length 184.9
  TOP w0.254: C1256.2 v2(52.11,39.26)
  TOP w0.508: v2(106.83,30.74) 106.39,31.18 R1320.1 ; R1222.1 95.8,34.18 96.25,34.64 v2(96.76,34.64) ; v2(136.34,54.45) R505.1
  L3SGND w0.762: 146.22,48.53 147.87,48.53 149.65,50.31 151.3,50.31 153.81,52.82 157.34,52.82 163.13,58.62 163.59,58.62 165.7,60.72 165.7,65.49 166.68,66.46 174.66,66.46 178.59,62.54 v2(178.59,60.34)
  BOTTOM w0.09: CPU1.Y36 105.39,64.93 v2(105.38,64.92) ; CPU1.AD36 107.91,64.94 v2(107.9,64.92) ; CPU1.AH36 v2(110.43,64.95)
  BOTTOM w0.102: CPU1.BH36 123.01,65.12 v2(123.11,65.02) ; v2(118,64.57) 117.98,64.57 CPU1.AY36
  BOTTOM w0.152: v2(112.85,65.02) 112.85,65.87 CPU1.AM36
  BOTTOM w0.203: CPU1.R32 v2(102.14,68.02)
  BOTTOM w0.254: RAM5.B3 122.15,42.9 v2(122.15,42.9) ; v2(114.41,68.82) 114.26,68.82 CPU1.AN32 ; CPU1.AH32 110.71,68.17 110.83,68.17 v2(110.96,68.04) ; v2(117.18,68.83) 117.47,68.54 CPU1.AW32
  BOTTOM w0.305: RAM6.R1 115.53,32.1 115.91,32.48 v2(115.91,32.91) ; v2(72.84,32.91) 72.84,32.84 72.11,32.1 RAM3.R1 ; v2(74.84,36.95) 75.35,36.95 RAM2.J9 RAM2.J8 ; v2(64.69,35.4) 64.79,35.3 RAM3.L9 ; v2(134.86,36.95) 134.81,36.9 RAM8.J1 134.17,37.03 133.63,37.03 RAM8.J2 ; v2(137.49,35.4) 137.59,35.3 RAM7.L9 ; RAM7.G9 v2(137.49,38.5) ; RAM2.R1 82.26,32.1 82.99,32.84 v2(82.99,32.91) ; RAM2.L9 74.94,35.3 v2(74.84,35.4) ; RAM7.G1 v2(145.01,38.5) ; v2(66.45,38.91) 66.47,38.89 66.47,38.88 RAM3.G7 ; RAM2.G7 76.62,38.88 76.62,38.89 v2(76.6,38.91) ; v2(82.36,36.95) 82.31,36.9 RAM2.J1 81.67,37.03 81.13,37.03 RAM2.J2 ; v2(127.32,36.95) 127.37,36.9 RAM8.J9 RAM8.J8 ; RAM7.A9 137.67,42.92 v2(137.55,42.92) 137.96,42.5 RAM7.B9 ; RAM3.D1 71.65,40.92 72.05,41.32 ; RAM3.J8 RAM3.J9 64.73,36.9 v2(64.68,36.95) ; v2(66.44,40.5) 66.46,40.48 66.47,40.48 RAM3.E7 ; v2(93.38,32.91) 93.38,32.53 92.95,32.1 RAM1.R1 ; RAM3.A1 v2(72.34,43.3) ; RAM8.E2 133.5,40.09 v2(133.9,39.69) 133.5,39.3 RAM8.F2 ; v2(106.83,30.74) 106.83,31 107.14,31.3 RAM6.T9 ; 134.7,41.32 134.3,40.92 RAM8.D1 ; 134.7,41.32 134.32,41.7 RAM8.C1 ; 134.7,41.32 v2(134.78,41.24) ; v2(139.25,38.91) 139.27,38.89 139.27,38.88 RAM7.G7 ; RAM5.D9 v2(117.19,40.9) ; RAM5.G9 v2(117.19,38.5) ; v2(72.21,36.95) 71.7,36.95 RAM3.J1 71.52,37.03 70.98,37.03 RAM3.J2 ; RAM8.G9 v2(127.34,38.5) ; RAM2.D9 v2(74.84,40.9) ; v2(129.1,38.91) 129.12,38.89 129.12,38.88 RAM8.G7 ; RAM3.C1 71.67,41.7 72.05,41.32 ; RAM8.A9 127.52,42.92 v2(127.4,42.92) 127.81,42.5 RAM8.B9 ; v2(115.86,34.82) 115.48,34.44 114.87,34.44 RAM6.L1 ; RAM5.R1 125.11,32.1 125.44,31.77 v2(125.44,30.66) ; RAM6.E2 113.2,40.09 v2(113.6,39.69) 113.21,39.3 RAM6.F2 ; CPU1.BE32 121.61,68.54 122.16,67.99 v2(122.54,67.99) ; RAM3.F8 65.65,39.7 v2(65.65,39.71) ; v2(62.07,36.98) 61.99,36.9 RAM4.J1 61.37,37.03 60.83,37.03 RAM4.J2 ; v2(145.01,43.3) RAM7.A1 ; RAM6.J2 113.33,37.03 113.87,37.03 RAM6.J1 114.51,36.9 v2(114.56,36.95) ; v2(92.59,35.4) 92.48,35.3 RAM1.L1 ; RAM6.D9 v2(108,41.3) ; 72.05,41.32 v2(72.13,41.24) ; RAM5.L1 124.68,35.3 v2(124.79,35.4) ; v2(62.14,35.4) 62.03,35.3 RAM4.L1 ; RAM2.D1 81.8,40.92 82.2,41.32 ; RAM7.C1 144.47,41.7 v2(144.93,41.24) 144.59,40.9 RAM7.D1 ; RAM3.E2 70.85,40.09 v2(71.25,39.69) 70.86,39.3 RAM3.F2 ; RAM7.D9 v2(137.49,40.9) ; v2(107.04,35.4) 107.14,35.3 RAM6.L9 ; v2(117.17,36.95) 117.22,36.9 RAM5.J9 RAM5.J8 ; RAM4.C1 61.66,41.7 62.02,41.34 v2(62.02,41.29) 61.62,40.9 RAM4.D1 ; RAM1.F8 85.95,39.7 v2(85.95,39.71) ; RAM6.E7 108.82,40.48 108.81,40.48 v2(108.79,40.5) ; v2(135.93,32.91) 135.93,32.78 135.25,32.1 RAM8.R1 ; v2(108,39.71) 108,39.7 RAM6.F8 ; RAM4.E7 56.32,40.48 56.31,40.48 v2(56.29,40.5) ; RAM4.L9 54.64,35.3 v2(54.54,35.4) ; v2(59.49,42.91) RAM4.B3 ; RAM6.G9 v2(107.04,38.5) ; v2(124.71,36.95) 124.66,36.9 RAM5.J1 124.02,37.03 123.48,37.03 RAM5.J2 ; RAM4.J8 RAM4.J9 54.55,36.9 v2(54.45,37) ; RAM8.T9 127.9,30.77 v2(127.96,30.72) ; RAM3.G9 v2(64.69,38.5) ; RAM2.B9 75.31,42.5 v2(74.9,42.92) 75.02,42.92 RAM2.A9 ; RAM6.B9 107.51,42.5 v2(107.06,42.95) 107.25,42.95 RAM6.A9 ; 82.2,41.32 81.82,41.7 RAM2.C1 ; 82.2,41.32 v2(82.28,41.24) ; RAM3.L1 72.18,35.3 v2(72.29,35.4) ; RAM4.T9 55.13,31.27 55.13,30.72 v2(55.18,30.67) ; v2(111.99,42.91) RAM6.B3 ; v2(145.64,32.91) 145.64,32.84 144.91,32.1 RAM7.R1 ; RAM7.F2 143.66,39.3 v2(144.05,39.69) 143.65,40.09 RAM7.E2 ; RAM8.L9 127.44,35.3 v2(127.34,35.4) ; RAM1.E2 91.15,40.09 v2(91.55,39.69) 91.16,39.3 RAM1.F2 ; v2(85.61,30.69) 85.55,30.75 RAM1.T9 ; RAM6.J8 RAM6.J9 107.18,36.9 v2(107.02,36.75) ; RAM7.F8 138.45,39.7 v2(138.45,39.71) ; v2(118.15,39.71) 118.15,39.7 RAM5.F8 ; RAM6.C1 114.02,41.7 114.4,41.32 ; v2(114.69,43.3) RAM6.A1 ; v2(132.29,42.91) RAM8.B3 ; v2(117.81,30.72) 117.75,30.77 RAM5.T9 ; RAM4.G1 v2(62.14,38.5) ; RAM7.L1 144.98,35.3 v2(145.09,35.4) ; RAM4.R1 61.96,32.1 62.69,32.84 v2(62.69,32.91) ; RAM6.G1 v2(114.56,38.5) ; v2(139.24,40.5) 139.26,40.48 139.27,40.48 RAM7.E7 ; RAM2.L1 82.33,35.3 v2(82.44,35.4) ; RAM5.D1 124.15,40.92 124.55,41.32 ; v2(54.52,38.63) 54.65,38.5 RAM4.G9 ; v2(76.59,40.5) 76.61,40.48 76.62,40.48 RAM2.E7 ; RAM2.F2 81,39.3 v2(81.4,39.69) 81,40.09 RAM2.E2 ; RAM1.B9 85.46,42.5 v2(85.05,42.92) 85.17,42.92 RAM1.A9 ; RAM6.G7 108.82,38.88 108.82,38.89 v2(108.8,38.91) ; RAM5.G7 118.97,38.88 118.97,38.89 v2(118.95,38.91) ; RAM2.T9 75.4,30.77 v2(75.46,30.72) ; RAM1.D1 92.02,40.9 92.35,41.23 92.35,41.32 ; v2(92.64,43.3) RAM1.A1 ; RAM1.G7 86.77,38.88 86.77,38.89 v2(86.75,38.91) ; 114.4,41.32 v2(114.48,41.24) ; 114.4,41.32 114,40.92 RAM6.D1 ; RAM5.B9 117.66,42.5 v2(117.25,42.92) 117.37,42.92 RAM5.A9 ; v2(129.09,40.5) 129.11,40.48 129.12,40.48 RAM8.E7 ; 92.35,41.32 v2(92.43,41.24) ; 92.35,41.32 91.97,41.7 RAM1.C1 ; RAM1.D9 v2(84.99,40.9) ; RAM5.E7 118.97,40.48 118.96,40.48 v2(118.94,40.5) ; RAM4.F8 55.5,39.7 v2(55.5,39.71) ; v2(65.31,30.72) 65.25,30.77 RAM3.T9 ; RAM2.G1 v2(82.36,38.5) ; 124.55,41.32 v2(124.63,41.24) ; 124.55,41.32 124.17,41.7 RAM5.C1 ; RAM1.G9 v2(84.99,38.5) ; v2(128.3,39.71) 128.3,39.7 RAM8.F8 ; v2(84.99,35.4) 85.09,35.3 RAM1.L9 ; RAM3.B9 65.16,42.5 v2(64.75,42.92) 64.87,42.92 RAM3.A9 ; v2(143.25,42.9) RAM7.B3 ; RAM5.G1 v2(124.71,38.5) ; v2(117.19,35.4) 117.29,35.3 RAM5.L9 ; RAM1.G1 v2(92.51,38.5) ; RAM8.L1 134.83,35.3 v2(134.94,35.4) ; RAM7.T9 138.05,30.77 v2(138.11,30.72) ; v2(75.8,39.71) 76.2,39.31 RAM2.F8 ; RAM1.J2 91.28,37.03 91.82,37.03 RAM1.J1 v2(92.51,36.9) ; RAM5.E2 123.35,40.09 v2(123.75,39.69) 123.36,39.3 RAM5.F2 ; v2(89.83,42.89) 89.96,42.89 RAM1.B3 ; v2(145.01,36.9) RAM7.J1 144.32,37.03 143.78,37.03 RAM7.J2 ; RAM1.E7 86.77,40.48 86.76,40.48 v2(86.74,40.5) ; RAM2.G9 v2(74.84,38.5) ; v2(137.47,36.95) 137.52,36.9 RAM7.J9 RAM7.J8 ; v2(72.21,38.5) RAM3.G1 ; v2(79.79,42.91) RAM2.B3 ; RAM1.J8 RAM1.J9 85.04,36.9 v2(84.99,36.95) ; RAM3.D9 v2(64.69,40.9) ; RAM5.A1 v2(124.84,43.3) ; v2(134.99,43.3) RAM8.A1 ; RAM8.D9 v2(127.34,40.9) ; RAM4.F2 60.7,39.3 v2(61.1,39.69) 60.7,40.09 RAM4.E2 ; RAM4.D9 v2(55.5,41.3) ; RAM8.G1 v2(134.86,38.5) ; RAM2.A1 v2(82.49,43.3) ; RAM4.G7 56.32,38.88 56.32,38.89 v2(56.3,38.91)
  BOTTOM w0.356: v2(69.62,42.89) 69.61,42.89 69.61,42.89 69.66,42.89 RAM3.B3 ; RAM4.A9 54.98,43.3 v2(54.6,42.92) 55.01,42.5 RAM4.B9 ; v2(62.19,43.17) 62.07,43.3 RAM4.A1
  vias: v1(68.64,59.68) v2(84.42,42.56) v3(65.7,60.08) v3(65.7,59.2) v3(65.7,58.31) v3(66.59,60.08) v3(66.59,59.2) v3(66.59,58.31) v3(67.48,59.2) v3(67.6,60.09)
1D2V_VCCSFR_OC: length 68.1
  TOP w0.254: v2(125.36,71.47) 125.26,71.37 C803.2 ; 176.26,62.76 C4007.1 175.55,62.04 v1(175.55,61) 175.55,58.18 v2(175.17,57.8)
  L4SGND w0.254: v2(125.36,71.47) 125.87,71.98 127.12,71.98 127.3,71.8 127.7,71.8 128.2,72.31 130.44,72.31 130.45,72.31 131.22,72.31 131.34,72.43 131.43,72.43 131.59,72.59 133.77,72.59 134.35,72 134.68,72 134.73,71.95 136.48,71.95 139.15,69.28 139.15,68.09 140.46,66.78 142.6,66.78 144.09,68.27 146.58,68.27 148.1,66.75 149.95,66.75 150.41,66.29 150.41,65.07 151.83,63.64 151.83,62.81 152.18,62.45 154.36,62.45 155.45,63.54 158.89,63.54 161.52,60.91 164.02,60.91 165.32,59.61 167.2,59.61 169.22,57.59 174.96,57.59 v2(175.17,57.8)
  BOTTOM w0.254: CPU1.BM26 125.38,71.48 v2(125.36,71.47) 125.04,71.79 CPU1.BL27
1D8V_CPVDD: length 6.2
  TOP w0.508: v1(176.9,22.98) 176.44,23.44 176.44,23.51 v2(176.42,23.54) 176.54,23.67 C2730.1 176.54,26.18 R2724.2
  BOTTOM w0.203: v2(176.42,23.54) 176.42,23.49 176.28,23.35 U2701.20
  BOTTOM w0.508: C2740.2 176.44,23.56 v2(176.42,23.54)
1D8V_EN#: length 173.9
  TOP w0.102: v2(174.92,6.83) v1(174.38,6.83)
  L4SGND w0.102: v2(64.43,9.67) 64.43,9.6 68.82,5.2 95.34,5.2 95.57,4.97 113.39,4.97 113.39,4.98 116.6,4.98 117.01,4.98 119.88,7.84 124.58,7.84 124.76,8.02 126.57,8.02 127.63,6.95 140.58,6.95 141.2,7.58 141.57,7.58 141.57,7.57 157.09,7.57 157.09,7.58 157.26,7.58 157.26,7.57 157.43,7.57 158.05,6.95 174.79,6.95 v2(174.92,6.83)
  L6 w0.102: v2(12.94,16.32) 13.5,15.77 19.52,15.77 19.77,15.51 19.77,15.18 20.38,14.57 23.78,14.57 24.4,15.19 24.95,15.19 25.5,14.65 30.83,14.65 33.03,12.44 33.43,12.44 33.69,12.44 34.24,13 38.54,13 41.08,10.46 41.24,10.46 41.24,10.46 41.53,10.46 41.79,10.2 63.9,10.2 v2(64.43,9.67)
  BOTTOM w0.102: R4034.2 R4035.1 174.13,6.04 v2(174.92,6.83) ; Q4001.D 12.23,17.04 v2(12.94,16.32)
1D8V_EN_R#: length 3.1
  BOTTOM w0.102: R4035.2 174,7.66 C4038.2 174.31,7.71 174.61,7.41 v1(174.84,7.41) 174.99,7.41 175.25,7.66 Q4002.G
1D8V_PWR:
  vias: v1(171.31,9.42)
1D8V_S0: length 99.9
  TOP w0.508: v2(154.42,51.96) 153.02,51.96 152.54,52.44 145.89,52.44 v2(145.5,52.06) ; C4039.1 177.05,7.13 v2(177.28,7.36) ; R2724.1 R2750.1 174.66,28.54 v2(173.9,29.3)
  L3SGND w0.508: v2(173.9,29.3) 173.67,29.08 173.67,26.34 173.27,25.94 173.27,13.45 175.35,11.37 175.35,9.24 177.23,7.36 v2(177.28,7.36)
  L6 w0.508: v2(154.42,51.96) 154.73,51.96 155.61,51.07 155.61,50.44 156.38,49.68 156.38,47.26 158.61,45.03 158.61,34.36 159.81,33.16 v2(159.81,32.53)
  BOTTOM w0.508: v2(173.9,29.3) 170.68,32.53 v2(159.81,32.53) ; R2748.1 171.39,12.69 171.59,12.88 172.95,12.88 173.9,11.93 v1(174.77,11.93) 174.87,11.93 Q4002.D 177.28,9.31 v2(177.28,7.36) 177.14,7.22 176.71,7.22 R6406.1 ; v2(145.5,52.06) 145.5,51.22 145.23,50.95 139.77,50.95 139.55,51.17 138.2,51.17 138.02,51.35 136.77,51.35 136.02,52.1 134.49,52.1 133.82,51.43 R2052.1
1D8V_S5: length 280.1
  TOP w0.254: v2(159.4,65.63) 159.17,65.4 R6121.2 ; R1515.1 162.99,53.99 164.02,55.03 v2(164.02,56.21)
  TOP w0.305: R1515.1 R6122.2 R6123.2 ; U6402.5 33.07,22.46 33.21,22.6 33.98,22.6 34.54,22.04 C6401.1
  TOP w0.508: v3(176.44,9.24) 177.62,9.24 178.11,9.73 182.71,9.73 185.87,12.89 185.87,24.45 183.96,26.36 183.96,31.53 v2(185.7,33.28) ; C6401.1 34.24,21.7 33.93,21.7 33.26,21.03 R2462.2 33.26,20.04 32.93,19.71 32.93,18.3 33.5,17.73 33.5,17.71 33.53,17.68 33.53,17.28 34.2,16.61 34.2,15.37 33.2,14.37 R2456.1 33.11,14.2 32.65,13.73 32.62,13.73 32.2,13.31 v1(32.2,12.57) 32.2,12.03 v2(33.01,11.22) ; v2(150.66,72.15) 152.6,72.15 v2(153.8,73.35)
  L3SGND w1.016: v3(73.11,1.39) 73.55,1.82 116.78,1.82 117.18,2.23 158.87,2.23 159.59,1.5 161.2,1.5 161.43,1.66 v3(162.35,2.58)
  L4SGND w0.254: v2(164.02,56.21) 164.65,55.59 175.57,55.59 v2(175.58,55.59)
  L4SGND w0.508: v2(153.8,73.35) 153.83,73.32 153.83,72.88 156.25,70.46 156.25,67.32 157.18,66.39 158.64,66.39 v2(159.4,65.63) 161.89,63.14 166.15,63.14 166.46,62.82 167.29,62.82 167.84,62.27 176.42,62.27 177.08,61.61 177.08,60.47 181.9,55.64 v2(182.28,55.64) 182.41,55.52 182.41,50.83 183.94,49.3 183.94,46.05 184.78,45.21 184.78,34.2 v2(185.7,33.28)
  BOTTOM w0.254: v2(175.58,55.59) 175.78,55.39 182.03,55.39 v2(182.28,55.64)
  BOTTOM w0.508: R2013.1 149.77,70.17 149.77,71.19 ; 33.46,7.21 32.63,8.04 32.63,8.68
  BOTTOM w0.762: 32.63,8.68 32.63,10.84 v2(33.01,11.22)
  BOTTOM w1.016: v3(73.11,1.39) 70.7,3.8 39.03,3.8 35.62,7.21 33.46,7.21
1D8V_S5_EN: length 4.8
  TOP w0.102: v2(167.43,1.67) PR5401.1 168.16,2.38 PC5406.1 168.92,2.35 PR5406.2 169.03,2.38 v1(169.84,3.19)
  BOTTOM w0.102: PU5401.8 168.23,2.09 167.81,1.67 v2(167.43,1.67)
1D8V_S5_KBC: length 6.8
  TOP w0.254: R2462.1 v1(34.13,21.1)
  TOP w0.508: v2(37.45,20.03) 35.68,20.03 C2423.1 35.07,19.61 34.46,20.21 R2462.1
  BOTTOM w0.203: U2401.54 38.13,19.59 38.01,19.7
  BOTTOM w0.508: v2(37.45,20.03) 37.68,20.03 38.01,19.7
1D8V_VCCPRIM: length 62.4
  TOP w0.254: v2(134,52.52) 134.05,52.52 135.12,53.59 135.12,54.97 v2(135.45,55.31) 135.45,55.31 135.45,55.31 136.03,55.9 R2053.1 ; R1821.1 132.3,57.8 132.3,54.12 v2(132.37,54.04) ; v2(141.39,54.37) 141.39,54.27 141.41,54.25 141.41,53.37 R1512.1
  TOP w0.508: v2(139.56,74.47) 139.41,74.31 R2113.1
  L3SGND w0.508: 153.71,72.28 153.71,66.79 153.46,66.54 153.46,63.34 153.06,62.95 153.06,62.86 152.69,62.49 152.69,62.49 151.68,61.49 151.67,61.49 151.3,61.11 151.3,61.1 150.79,60.59 150.79,57.13 150.31,56.66 145.14,56.66 143.36,54.88 141.9,54.88 v2(141.39,54.37)
  L6 w0.305: v2(132.37,54.04) 132.37,53.33 133.19,52.52 v2(134,52.52)
  BOTTOM w0.203: CPU1.CP23 139.43,74.34 v2(139.56,74.47)
  BOTTOM w0.254: v2(141.39,54.37) 140.15,53.13 139.01,53.13 138.83,53.31 137.59,53.31 136.87,54.02 136.87,54.7 136.61,54.96 135.8,54.96 v2(135.45,55.31) ; v2(132.68,78.17) 133.01,77.85 CPU1.CD18 CPU1.CD19 ; v2(132.68,78.17) 133.01,78.5 CPU1.CD16 ; v2(132.68,78.17) 132.68,78.08 CPU1.CC18 CPU1.CC19 ; 139.16,78.12 CPU1.CP17 ; CPU1.CD16 132.36,79.24 CPU1.CC15 ; CPU1.CD16 CPU1.CD15
  BOTTOM w0.305: 139.16,78.12 139.26,78.12 139.64,77.74 v2(139.64,77.72) ; R1738.1 131.36,53.03 v2(132.37,54.04)
  BOTTOM w0.508: R2111.1 R2115.1 149.93,78.58 150.97,77.54 151.38,77.54 151.99,76.93 151.99,76.09 v2(151.98,76.08)
  vias: v1(156.88,74.69) v3(156.25,73.3)
1D24V_VCCDPHY: length 2.3
  BOTTOM w0.254: CPU1.CA24 130.91,73.7 130.55,73.7 CPU1.BY24 CPU1.BY23 CPU1.CA23
1D24V_VCCDPHY_EC: length 5.4
  TOP w0.254: C2218.1 141.8,72.13 v2(142.05,72.38) v1(142.38,72.84)
  BOTTOM w0.254: CPU1.CP25 141.27,73.08 141.28,73.09 141.62,73.09 141.63,73.08 141.65,73.08 142.05,72.67 v2(142.05,72.38)
2D5V_S3: length 20.9
  TOP w0.508: v2(62.19,42.5) 61.71,42.02 C1265.1 ; v2(72.34,42.5) 71.86,42.02 C1262.1 ; v2(92.64,42.5) 92.16,42.02 C1259.1 ; C1341.1 124.34,42 v2(124.84,42.5) ; v2(114.69,42.5) 114.22,42.03 C1337.1 ; C1268.1 82.01,42.02 v2(82.49,42.5) ; v2(134.99,42.5) 134.49,42 C1346.1 ; C1351.1 144.69,42.06 v2(145.14,42.5)
  BOTTOM w0.305: v2(114.69,42.5) RAM6.B1 ; v2(92.64,42.5) RAM1.B1 ; RAM6.R9 107.32,32.1 107.04,31.82 106.01,31.82 ; v2(145.14,42.5) RAM7.B1 ; RAM8.B1 v2(134.99,42.5) ; 136.83,30.73 136.83,30.73
  BOTTOM w0.356: RAM1.R9 85.21,32.1 84.11,31.01 84.11,29.1 ; 64.03,29.62 64.03,31.5 64.63,32.1 RAM3.R9 ; RAM2.R9 74.92,32.1 74.18,31.37 74.18,29.89
  vias: v1(69.03,45.84) v1(87.8,45.81) v1(96.76,43.27) v1(122.64,45.76)
2D5V_S3_EN: length 5.1
  BOTTOM w0.102: PR5417.2 110.8,27.23 PR5409.1 110.86,27.17 PC5427.1 ; PC5427.1 110.76,26.43 109.85,25.52 v1(109.66,25.52) ; PC5427.1 111.01,26.43 112.03,27.45 PU5403.8
2D5V_S3_PWRGD: length 147.4
  TOP w0.102: v2(109.64,11.19) 109.08,11.75 v1(109.08,19.17) 109.08,19.78 109.36,20.06 109.36,22.19 v2(109.53,22.36)
  L4SGND w0.102: v2(49.19,57.68) 49.19,56.58 47.64,55.03 47.64,47.84 39.01,39.21 38.12,39.21 37.25,38.34 37.25,37.1 36.97,36.82 36.97,34.26 36.79,34.08 36.79,32.83 35.04,31.08 35.04,24.03 35.27,23.8 35.27,23.05 34.82,22.6 34.82,16.92 36.23,15.5 36.23,15.16 36.56,14.83 37.15,14.83 38.44,13.53 40.27,13.53 v2(42.1,11.7)
  L6 w0.102: v2(109.64,11.19) 109.31,11.52 108.14,11.52 106.46,9.85 106.45,9.85 106.4,9.8 106.25,9.8 96.13,9.8 96.08,9.85 95.7,9.85 94.32,11.22 91.89,11.22 90.89,10.23 86.63,10.23 85.92,10.94 77.86,10.94 76.87,9.95 75.2,9.95 74.61,10.53 74.31,10.53 66.61,10.53 66.06,11.09 65.87,11.09 65.85,11.12 42.69,11.12 v2(42.1,11.7)
  BOTTOM w0.102: PU5403.7 111.23,26.18 111.07,26.03 110.76,26.03 110.02,25.29 109.89,25.29 109.79,25.19 109.69,25.19 109.46,24.96 109.46,22.62 109.53,22.56 v2(109.53,22.36) 109.79,22.62 PR5410.2 ; PG5122.1 48.81,58.06 v2(49.19,57.68)
3D3V_1D8V_AVDD: length 14.1
  BOTTOM w0.203: 172.28,17.92 U2701.3
  BOTTOM w0.254: R2748.2 v1(168.54,14.01) 168.21,14.01 167.5,13.3 R2749.2 ; R2748.2 169.71,13.96 170.24,13.43 170.45,13.2 171.06,13.2 171.29,13.43 172.12,13.43 R2742.1 R2744.2 ; R2748.2 169.71,14.57 C2743.1 169.15,15.89 C2729.2 ; C2729.2 C2722.1 170.09,16.78 171.23,17.92 172.28,17.92 ; C2729.2 169.91,16.02 R2743.2
3D3V_1D8V_AVDD_IO: length 6.9
  TOP w0.203: R2751.2 R2750.2 174.66,24.88 C2745.1 174.56,23.84 C2744.1 174.54,23.77 v2(174.97,23.34)
  TOP w0.254: v1(174.97,22.75) v2(174.97,23.34)
  BOTTOM w0.203: U2701.18 175.48,22.82 v2(174.97,23.34)
3D3V_AUX_KBC: length 18.2
  TOP w0.508: v1(27.79,28.87) ED4305.2 28.52,30.68 v2(30.21,30.68) 30.21,30.42 31.22,29.42 ED4306.2
  L3SGND w0.508: v2(37.5,36.72) 37.5,34.96 34.9,32.35 31.02,32.35 30.21,31.55 v2(30.21,30.68)
  BOTTOM w0.508: v2(37.5,36.72) 37.44,36.65 ED4304.2
3D3V_AUX_S5: length 339.5
  TOP w0.508: v2(96.23,20.9) 96.23,19.7 95.37,18.84 94.4,18.84 93.1,20.13 PR4505.1 91.91,20.13 91.35,19.58 89.99,19.58 v1(88.87,18.45) 88.58,18.17 88.58,16.53 89.52,15.59 91.33,15.59 v2(91.38,15.54) 91.38,15.39 91.81,14.95 91.81,13.33 PR4503.1 ; R2463.1 26.56,25.6 26.73,25.6 v2(27.01,25.88) 26.63,26.26 R2472.2 ; R1726.2 R1727.1 182.11,57.65 181.4,56.94 181.4,55.26 v2(181.78,54.88)
  L3SGND w0.508: v2(184.93,18.56) 185.08,18.71 185.08,23.32 184.95,23.44 184.95,30.8 183.43,32.33 183.43,41.19 181.29,43.33 v2(181.12,43.33) 181.12,43.05 180.43,42.36 175.6,42.36 174.18,40.94 174.18,31.67 169.2,26.69 169.2,25.66 152.3,8.76 143.42,8.76 138.42,3.75 125.39,3.75 123.05,6.09 123.05,10.94 121.83,12.16 121.83,13.58 123.13,14.88 123.13,23.09 122.35,23.87 113.68,23.87 111.16,21.35 110.97,21.35 110.46,20.85 107.47,20.85 105.57,22.75 101.23,22.75 100.37,23.61 97.3,23.61 96.23,22.55 ; v2(96.23,20.9) 96.23,22.55 ; 96.23,22.55 95.31,23.46 85.03,23.46 84.11,24.38 76.5,24.38 75.63,23.5 75.63,22.14 75.22,21.74 70.58,21.74 70.33,21.48 65.06,21.48 62.85,23.69 62.17,23.69 62.17,23.69 57.52,23.69 56.88,24.33 49.61,24.33 48.92,23.64 48.82,23.64 39.79,23.64 38.14,25.29 38.14,27.32 36.44,29.02 28.66,29.02 27.01,27.38 v2(27.01,25.88)
  L4SGND w0.508: v2(147.41,49.9) 147.69,50.18 154.05,50.18 154.1,50.13 154.26,50.13 154.28,50.16 154.81,50.16 154.84,50.13 156.07,50.13 158.05,48.15 158.05,45.39 159.11,44.34 160.44,44.34 161.08,44.98 161.08,46.37 162.09,47.39 166.03,47.39 166.59,47.95 169.73,47.95 169.98,48.2 171.87,48.2 174.56,45.51 179.11,45.51 181.12,43.5 v2(181.12,43.33)
  BOTTOM w0.508: R1737.1 145.66,50.31 146.01,49.95 147.36,49.95 v2(147.41,49.9) ; v2(184.93,18.56) 184.79,18.56 183.86,17.63 183.86,17.62 R2728.1 ; PG4519.2 91.1,15.82 v2(91.38,15.54) ; R2505.1 184.14,42.54 181.9,42.54 v2(181.12,43.33) 181.12,43.5 178.84,45.78 175.75,45.78 173.9,47.62 173.9,50.3 176.23,52.63 176.23,53.16 177.96,54.88 v2(181.78,54.88)
3D3V_CAMERA_S0: length 6.1
  TOP w0.508: v2(104.18,97.81) 104.1,97.88 FC5502.1 104.03,98.65 C5503.1 103.95,99.66 F5502.2 103.95,102.23 104.46,102.74 v1(104.46,102.74)
  BOTTOM w0.305: v2(104.18,97.81) 104.15,97.78 LCD1.37
3D3V_ECVBAT: length 7.9
  TOP w0.305: C2428.1 23.28,27.17 R2451.2 R2497.2 24.3,27.42 25.21,27.42 v1(25.25,27.39) 25.69,26.94 v2(25.69,26.75)
  TOP w0.508: v2(25.69,26.75) 26.06,27.12 R2472.1 R2473.1
  BOTTOM w0.203: U2401.122 24.95,25.59 25.11,25.75
  BOTTOM w0.508: 25.11,25.75 25.69,26.33 v2(25.69,26.75)
3D3V_FLASH: length 42.9
  TOP w0.178: 16.13,35.5 16.07,35.44 15.77,35.44 15.76,35.44 14.43,35.44 14.43,35.44 U7201.G1
  TOP w0.254: 16.13,35.5 16.15,35.53 v2(16.51,35.53) 17.23,35.53 C7211.1
  BOTTOM w0.254: v2(16.51,35.53) 15.93,35.53 15.87,35.46 15.86,35.46 15.79,35.39 15.37,35.39 15.21,35.22 13.83,35.22 13.81,35.25 13.45,35.25 12.23,35.25 R7222.1 10.78,35.73 10.17,35.73 8.85,37.05 7.33,37.05 R7204.1 6.39,36.62 5.52,36.62 5.22,36.32 5.22,27.42 7.73,24.91 v1(9.34,24.91) R7225.2 R7230.2 10.66,23.39 R7228.2 13.12,20.92 14.26,20.92 14.44,21.1 16.3,21.1 16.75,21.56 C7244.1 R7226.2 17.51,22.51 U7202.8
3D3V_FPR_VDD: length 27.8
  TOP w0.508: v2(179.33,75.16) 182.91,75.16 186.17,78.42 v2(186.17,92.96)
  BOTTOM w0.508: R9211.1 185.51,92.3 v2(186.17,92.96) ; R9213.1 180.28,76.12 v2(179.33,75.16)
  vias: v1(181.65,90.06)
3D3V_HDMI_VDD: length 69
  TOP w0.254: R5738.1 R5739.1 v2(15.15,81.17) ; v2(34.84,83.13) 35.45,82.52 37.2,82.52 37.77,81.94 U5703.5 ; v2(34.84,83.13) 34.46,83.51 R5746.1 33.39,85.08 R5747.2 ; v2(34.84,83.13) 34.58,82.87 R5745.1 ; U5701.G4 21.39,86.51 v2(21.38,86.51) ; v2(23.67,94.65) 23.67,94.06 24.65,93.08 R5740.2 ; v2(20.23,90.06) 19.62,90.06 C5749.1 19.11,91.08 R5780.2 ; U5701.B2 v2(26.19,88.91) ; v2(21.39,88.91) U5701.G2 ; v2(22.77,79.19) R5756.1
  L3SGND w0.254: v2(26.19,88.91) v2(21.39,88.91) 21.16,88.91 20.56,89.5 20.56,89.6 20.23,89.93 v2(20.23,90.06) ; v2(22.77,79.19) 20.41,81.55 15.53,81.55 v2(15.15,81.17)
  L4SGND w0.254: v2(16.55,86.48) 16.55,82.97 16.07,82.49 16.07,82.09 v2(15.15,81.17)
  BOTTOM w0.254: v2(26.19,88.91) 26.2,88.92 C5752.1 ; v2(22.77,79.19) 22.77,80.66 24.25,82.14 26.71,82.14 27.09,82.52 32.5,82.52 33.11,83.13 v2(34.84,83.13) C5726.2 34.1,83.76 R5742.2 34,83.71 U5702.8 ; v2(16.55,86.48) 16.55,87.07 19.55,90.06 v2(20.23,90.06) 20.23,91.2 v2(23.67,94.65)
  vias: v1(20.37,88.71)
3D3V_LCDVDD_R:
  vias: v1(103.06,102.96) v2(101.18,102.91) v2(101.82,102.91) v2(102.45,102.91)
3D3V_LCDVDD_S0:
  vias: v1(101.39,98.82) v2(100.8,97.94) v2(101.44,97.91) v2(102.07,97.88)
3D3V_LDO_SET: length 2.9
  BOTTOM w0.102: R5542.1 144.64,100.63 U5503.4 ; R5542.1 v1(144.49,98.95) ; R5542.1 R5541.2
3D3V_MIC_VCC: length 4.7
  TOP w0.254: v2(111.06,97.78) 110.96,97.88 110.96,98.11 110.68,98.39 C5521.1 R5511.2 v1(111.42,101.11)
  BOTTOM w0.254: v2(111.06,97.78) 110.96,97.68 110.96,97.55 110.65,97.24 LCD1.50
3D3V_MUX: length 48.3
  TOP w0.203: U7101.20 21.25,71.36 21.46,71.57 21.65,71.57 ; v2(20.05,65.12) 19.92,65.25 U7101.6 ; U7101.1 17.92,65.24 17.51,64.84 ; U7101.28 17.55,71.79 17.34,72
  TOP w0.381: 17.51,64.84 17.31,64.64 C7115.2 16.85,65.37 v2(17.36,65.88)
  TOP w0.508: R7101.1 v2(16.24,73.22) C7116.2 16.93,72.41 17.34,72 ; R7118.1 v2(15.36,71.01) ; 21.65,71.57 21.82,71.57 22.02,71.77 22.39,71.77 v2(22.49,71.87) 23,72.38 C7117.2 ; R7152.1 17.23,62.6 16.32,62.6 v2(16.24,62.53) 15.86,62.91 R7147.1 ; R7124.2 22.59,63.37 C7119.1 22.75,63.9 22.24,64.41 v2(22.04,64.41)
  L4SGND w0.508: v2(15.36,71.01) 16.24,71.9 v2(16.24,73.22)
  BOTTOM w0.508: v2(16.24,62.53) 16.27,62.55 17.67,62.55 ; 17.67,62.55 19.6,64.48 C7118.2 ; 17.67,62.55 17.03,63.19 17.03,65.55 17.29,65.8 ; C7118.2 21.96,64.48 v2(22.04,64.41) 22.24,64.41 23.74,65.91 R7145.1 23.74,68.47 R7171.1 R7174.1 23.76,69.45 23.13,70.09 v1(23.13,71.53) 22.79,71.87 v2(22.49,71.87) ; C7118.2 20.11,65.07 v2(20.05,65.12) ; 17.29,65.8 v2(17.36,65.88) ; 17.29,65.8 15.8,65.8 15.43,66.18 15.43,66.92 R7142.1 R7140.1 15.36,68.09 v2(15.36,71.01) 15.56,70.81 R7121.1
3D3V_OPT: length 10.3
  TOP w0.508: R6005.1 163.84,20.03 162.29,18.48 157.09,18.48 156.25,19.32
  vias: v1(147.54,11.37) v1(149.01,17.18) v3(154.67,5.61) v3(155.13,20.64) v3(155.46,5.91) v3(155.77,21.28) v3(156.24,5.6)
3D3V_RTC: length 236.6
  TOP w0.508: v2(159.82,21.75) 159.32,22.25 159.32,23.47 162.96,27.12 165.89,27.12 165.99,27.14 171.08,32.24 v1(171.08,32.78) 171.08,35.5 172.21,36.63 172.21,39.07 172.21,40.34 172.78,40.91 172.78,42.82 173.27,43.3 173.27,49.12 173.24,49.14 v2(173.24,49.45) 173.24,49.8 173.53,50.09 173.53,51.35 173.7,51.52 173.7,54.16 173.6,54.26 173.6,54.79 173.7,54.89 173.7,55.44 174.71,56.46 176.25,56.46 177.21,57.42 178.49,57.42 180.76,59.69 180.76,60.33 181.93,61.5 181.93,62.28 183.58,63.94 185.24,63.94 186.27,64.97 Q2507.S 185.64,66.25 R2512.1 ; R2473.2 26.71,28.9 26.98,28.63 v2(26.98,28.39)
  L3SGND w0.508: v2(26.98,28.39) 26.98,29.23 27.49,29.74 36.62,29.74 38.77,27.59 38.77,26.94 40.3,25.42 43.97,25.42 45.11,24.28 48.55,24.28 49.24,24.96 70.21,24.96 70.24,24.94 71.34,24.94 72.73,23.54 74.77,23.54 76.24,25.01 87.09,25.01 87.58,24.53 100.52,24.53 101.67,23.39 105.83,23.39 107.74,21.48 110.2,21.48 113.22,24.5 128.87,24.5 130.85,26.48 140.6,26.48 142.43,24.66 v2(142.43,21.96)
  L4SGND w0.508: v2(159.82,21.75) 158.42,21.75 155.74,19.07 154.98,19.07 153.2,20.85 143.55,20.85 v2(142.43,21.96)
  BOTTOM w0.508: v2(173.24,49.45) 172.91,49.12 172.91,47.72 175.49,45.14 177.3,45.14 179.85,42.59 180.46,42.59 184.77,38.27 C2503.1 185.13,38.27 186.58,39.72 192.56,39.72 D2501.3
3D3V_RTC_SYS: length 9.7
  BOTTOM w0.254: v1(192.76,42.07) D2501.1 191.55,40.51 185.56,40.51 185.21,40.15 R2517.1 R2505.2
3D3V_S0: length 662.8
  TOP w0.254: 130.09,88.41 130.09,88.92 130.47,89.3 131.36,89.3 132.75,90.7 135.17,90.7 135.68,90.19 137.07,90.19 139.87,92.98 141.24,92.98 141.36,93.11 v2(141.8,93.11) ; 132.73,52.9 132.27,52.9 131.15,54.02 131.15,55.28 131.31,55.43 131.31,55.47 131.36,55.52 131.36,57.19 130.8,57.75 R1820.1 ; R1818.2 134.43,56.28 134.43,57.05 134.33,57.15 R2043.1
  TOP w0.305: 37.86,25.27 36.13,25.27 35.32,26.08 R2449.1 ; Q2601.5 37,35.49
  TOP w0.356: v2(38.3,33.78) 38.3,32.54 37.95,32.19 37.34,32.19 37,32.53 Q2601.2
  TOP w0.508: 142.61,81.37 143.37,80.61 146.58,80.61 147.61,79.58 147.61,79.05 146.75,78.19 v2(146.75,76.09) ; 142.61,81.37 142.61,81.4 142.6,81.41 142.6,82 143.01,82.41 145.4,82.41 v2(145.63,82.64) ; 142.61,81.37 141.95,81.37 R2044.1 ; v2(4.81,23.21) 8.65,27.04 v2(9.64,27.04) ; v2(28.82,34.66) 29.19,34.66 31.75,37.23 v2(33.44,37.23) 36.1,37.23 37.24,36.09 ; v2(38.3,36.34) 38.04,36.09 37.24,36.09 ; v3(74.72,22.5) 74.72,21.99 v1(76.42,20.29) 76.42,19.83 81.45,14.8 R6502.1 ; R9127.1 179.87,45.59 v2(179.87,46.5) ; v2(39,30.42) 39,29.46 38.09,28.54 38.08,28.54 37.86,28.32 37.86,24.26 38.27,23.85 DB1.10 ; v2(174.41,2.81) 174.41,4.31 172.86,5.86 171.23,5.86 166.97,10.12 166.97,10.71 v2(167.09,10.84) 165.76,12.17 165.76,17.42 v2(167.57,19.23) 168,19.65 169.74,19.65 170.97,20.88 170.97,27.77 171.31,28.11 R2751.1 ; 37.24,36.09 37,35.84 37,35.49 ; R1818.2 133.77,55.62 133.77,53.6 133.07,52.9 132.73,52.9 132.73,52.42 134.99,50.16 146.32,50.16 v2(146.9,50.74) ; v2(154.06,84.09) 154.06,83.84 154.01,83.79 R2109.1 R2110.1 153.99,82.64 R2010.1
  TOP w0.762: F5502.1 106.16,101.24 107.58,102.66 107.58,103.2 108.41,104.03 111.04,104.03 111.93,103.14
  L3SGND w0.508: v2(141.57,76.04) 143.26,76.04 143.97,75.33 144.5,75.33 145.26,76.09 v2(146.75,76.09) ; v2(134.61,94.33) 135.14,93.79 136.98,93.79 138.2,92.58 140.83,92.58 141.36,93.11 v2(141.8,93.11) ; v3(73.19,24.28) 71.87,25.6 49.05,25.6 45.56,25.6 43.3,27.86 v2(41.36,27.86) ; v2(154.06,84.09) 152.95,84.09 152.39,84.65 147.64,84.65 v2(145.63,82.64) ; v2(145.58,55.97) 146.17,55.39 154.6,55.39 155.44,56.23 155.44,57.35 156.76,58.67 156.76,59.87 162.33,65.44 163.29,65.44 v2(163.49,65.25) ; v2(179.87,46.5) 180.13,46.75 180.13,59.54 180.24,59.66 180.24,64.39 ; v2(183.33,72.66) 181.9,72.66
  L3SGND w1.524: 181.9,66.77 181.9,90.32 ; 181.9,90.32 v3(187.75,90.32) ; 181.9,90.32 170.17,90.32 165.9,86.05 163.82,86.05 162.86,87.01 161.2,87.01
  L4SGND w0.508: v2(141.8,93.11) 141.8,93.44 142.15,93.79 v2(142.15,102.38) ; v3(172.63,64.41) 170.6,64.41 168.7,66.31 166.7,66.31 165.78,65.38 163.63,65.38 v2(163.49,65.25) ; v2(51.09,80.16) 51.09,79.75 45.19,73.84 45.19,72.92 44.55,72.28 44.48,72.28 42.96,70.76 41.23,70.76 37.31,66.84 37.31,63.77 33.73,60.19 33.73,60.19 33.65,60.11 32.05,60.11 28.46,56.53 28.46,55.47 28.46,52.36 24.78,48.68 24.78,47.93 24.44,47.59 24.44,47.06 25.03,46.47 25.03,45.69 25.37,45.35 29.21,41.51 29.69,41.51 31.43,41.51 33.69,39.24 33.69,37.48 v2(33.44,37.23) ; v2(151.67,88.27) 151.67,87.47 154.2,84.95 154.2,84.23 v2(154.06,84.09) ; v2(39,30.42) 39,31.6 38.27,32.33 38.27,33.75 v2(38.3,33.78) ; v2(33.69,3.32) 32.55,4.46 32.55,5.28 28.85,8.98 22.34,8.98 17.76,13.57 17.76,16.08 v2(16.68,17.16) 12.23,17.16 9.74,19.65 9.74,26.94 v2(9.64,27.04) ; v2(4.81,23.21) 4.2,23.82 4.2,52.27 9.2,57.26 9.2,63.19 11.48,65.47 11.48,71.23 15.72,75.46 15.72,80.1 15.34,80.49 14.64,80.49 14.44,80.69 14.44,81.58 15.84,82.98 15.84,88.43 17.39,89.98 17.39,91.77 17.37,91.78 17.37,93.34 17.06,93.66 17.06,93.67 v2(16.89,93.67) ; v2(61.76,53.1) 61.13,52.47 52.88,52.47 48.65,48.25 48.65,48.14 48.36,47.84 48.25,47.84 38.9,38.49 38.9,36.95 38.3,36.35 v2(38.3,36.34) ; v2(41.36,27.86) 41.82,28.31 v2(41.82,29.43)
  L4SGND w0.635: v3(188.06,6.87) 187.09,5.9 185.6,5.9 183.83,7.66 180.28,7.66 178.55,5.94 178.55,4.41 177.71,3.57 175.17,3.57 v2(174.41,2.81)
  L6 w0.508: v2(20.74,31.84) 18.73,31.84 17.84,30.96 15.2,30.96 13.81,29.56 13.01,29.56 10.49,27.04 v2(9.64,27.04) ; v2(146.9,50.74) 146.9,51.66 147.79,52.55 147.79,54.12 145.94,55.97 v2(145.58,55.97)
  BOTTOM w0.254: v2(134.61,94.33) 134.45,94.17 RN403.1
  BOTTOM w0.305: v2(166.21,39.34) 166.74,39.34 167.05,39.65 CN6601.27 ; RN2703.4 167.97,20.34 167.57,19.95 v2(167.57,19.23) 167.97,19.63 168.36,19.63 168.41,19.67 RN2703.3 ; v2(134.61,94.33) 134.82,94.33 135.12,94.02 RN403.2
  BOTTOM w0.381: R507.1 70.42,56.56 68.77,54.91 63.95,54.91 63.54,54.5 62.35,54.5 61.96,54.12 61.96,53.31 v2(61.76,53.1)
  BOTTOM w0.406: RN2602.2 38.36,32.69 38.3,32.75 v2(38.3,33.78)
  BOTTOM w0.508: v2(38.3,36.34) v2(38.3,33.78) ; PR4609.1 51.63,79.29 51.63,79.62 R1718.2 51.8,80.16 v2(51.09,80.16) ; C2602.1 42.48,29.41 R2603.1 v2(41.82,29.43) 41.75,29.51 39.92,29.51 v2(39,30.42) ; v3(181.36,65.55) 182.04,65.55 182.59,66.1 R4004.1 ; v2(141.57,76.04) 142.08,76.04 142.25,76.22 R2038.1 143.37,76.24 R2046.1 R2035.1 ; v2(167.09,10.84) 167.09,11.55 R2749.1 ; v2(163.49,65.25) 164.5,65.25 165.11,65.85 R2609.1 ; R2045.1 v2(145.63,82.64) ; v2(145.63,82.64) R2005.1 ; v2(145.63,82.64) 145.07,82.64 R2048.1 R2049.1 ; R2430.2 41.34,27.83 v2(41.36,27.86) ; R2489.2 16.32,19.83 R4005.1 16.17,19.19 Q2414.G 16.62,17.22 v2(16.68,17.16) ; R6405.1 v2(174.41,2.81) ; R1608.1 R402.2 R1606.1 v2(151.67,88.27) ; R2604.1 30.06,8.91 31.36,7.61 31.36,7.51 31.93,6.93 31.93,6.57 33.69,4.81 v2(33.69,3.32) ; v2(28.82,34.66) 26.46,34.66 25.29,33.5 24.49,33.5 22.84,31.84 v2(20.74,31.84) ; R4041.1 181.47,73.12 181.98,73.63 182.7,73.63 183.33,73.01 v2(183.33,72.66) ; v2(154.06,84.09) 154.09,84.07 157.55,84.07 157.95,84.46 157.95,85.11 158.46,85.62 160.69,85.62 v3(160.82,85.74) 160.82,85.06 R5504.2 ; v2(141.8,93.11) 141.62,93.11 140.68,92.17 R5505.2
  vias: v1(145.71,56.63) v1(145.76,19.96) v2(143.07,102.41) v2(161.1,39.01) v3(73.83,22.5) v3(74.08,24.28) v3(74.87,24.76) v3(126.13,22.39) v3(126.96,22.42) v3(127.88,22.45) v3(128.82,22.42) v3(129.71,22.42) v3(144.69,22.24) v3(145.56,5.41) v3(145.84,22.24) v3(146.44,5.41) v3(147.33,5.4) v3(172.63,63.39) v3(180.95,64.82) v3(188.89,7) v3(189.65,6.24)
3D3V_S5: length 348.4
  TOP w0.178: 14.74,32.55 U7201.B1 ; v2(15.55,36.22) 15.27,35.94 U7201.H1
  TOP w0.254: v2(156.38,71.27) 156.12,71.52 154.57,71.52 152.19,69.13 150.76,69.13 149.77,70.12 146.3,70.12 145.73,70.69 v2(145.73,70.7) ; AFTP6607.1 v2(168.42,39.11) ; 15.66,31.27 15.08,31.86 15.08,32.22 14.74,32.55
  TOP w0.305: PR4435.1 21.24,45.28 21.42,45.46 v2(21.76,45.46) ; Q2416.5 26.84,18.13 v2(26.89,18.08)
  TOP w0.356: RN7206.1 18.75,31.82 19.8,31.82 19.83,31.79 ; v2(19.34,30.96) 19.83,31.45 19.83,31.79 ; Q2416.2 Q2416.5 ; 19.83,31.79 19.83,32.17 19.53,32.47 18.75,32.47 RN7206.2
  TOP w0.508: 18.16,28.75 18.16,29.12 17.67,29.61 17.26,29.61 FC8944.1 17.16,29.7 16.23,29.7 C7208.1 16.2,30.58 15.66,31.12 15.66,31.27 ; 18.16,28.75 18.16,28.61 17.51,27.96 v2(17.44,27.96) 17.44,24.35 R2499.1 ; 18.16,28.75 18.79,28.75 19.37,29.32 19.37,30.93 v2(19.34,30.96) 18.71,30.96 R7224.1 ; v2(31.79,34.44) 32.16,34.44 33.25,33.34 D4302.2 33.08,33.14 R4304.1 ; v2(22.02,18.81) 21.64,18.43 R4031.1 ; v2(20.83,11.99) 22.24,13.4 R2431.2 ; v2(25.31,61.21) 25.08,61.21 23.84,62.45 R7124.1 ; R7424.1 17.13,61.92 17.64,61.41 v2(18.28,61.41) ; v2(183.2,70.25) 182.74,70.25 R4042.1 ; v2(154.42,51.07) 153.79,50.44 148.88,50.44 146.85,48.41 142.48,48.41 v2(142.28,48.2) 141.54,48.94 132.58,48.94 132.27,49.24 v2(128.46,49.24) 127.29,50.41 v2(127.29,51.88) ; v2(17.95,42.18) 18.02,42.26 R4378.1 ; v2(131.8,23.96) 131.26,23.41 125.03,23.41 123.28,21.66 123.28,17.21 121.86,15.79 121.86,10.18 121.83,10.15 ; PR5402.1 172.25,3.7 172.35,3.8 172.35,3.98 v3(172.37,3.98) ; R9143.2 188.15,45.68 186.92,44.44 v2(175.73,44.44) 175.91,44.62 R9126.1 ; FC8941.1 37.89,11.32 37.76,11.45 v2(37.76,11.47) ; v2(22.65,35.71) 22.62,35.71 22.64,35.73 22.96,35.73 23.07,35.84 23.47,35.84 PR4472.1 23.53,35.22 23.28,34.97 23.28,34.74 23.23,34.69 PR4450.2 ; v2(21.4,37.18) 20.97,37.61 PR4479.1
  TOP w1.016: 171.29,53.27 171.41,53.4 171.41,56.08 174.33,59 174.33,65.75
  L4SGND w0.508: v2(71.11,61.74) 69.86,61.74 68.9,62.71 62.26,62.71 61.57,63.39 53.66,63.39 51.5,61.23 v2(49.82,61.23) ; v2(154.42,51.07) 154.45,51.05 155.18,51.05 155.2,51.02 159.34,51.02 160.38,49.98 160.74,49.98 162.22,49.98 162.88,50.64 167.72,50.64 168.25,50.11 169.53,50.11 169.86,50.44 v3(171.64,50.44) ; v2(25.31,61.21) 25.61,60.91 26.72,60.91 29.24,63.43 32.28,63.43 32.35,63.51 32.36,63.51 33.99,65.14 33.99,71.04 33.12,71.91 33.12,75.48 35.16,77.52 v2(35.16,78.69)
  L6 w0.254: v2(129.02,59.43) 129.02,59.38 137.63,50.77 137.83,50.77
  L6 w0.508: v2(17.44,27.96) 15.53,26.05 v2(11.6,26.05) ; v2(21.76,45.46) 21.01,45.46 20.61,45.86 20.61,46.99 21.26,47.64 21.33,47.64 24.25,50.55 24.25,54.68 24.82,55.25 24.82,60.71 v2(25.31,61.21) 26.43,60.09 48.27,60.09 48.38,60.19 48.38,60.21 48.81,60.64 48.81,60.71 49.33,61.23 v2(49.82,61.23) ; v2(31.79,34.44) 31.79,34.77 31.26,35.3 25.34,35.3 24.93,35.71 v2(22.65,35.71) ; 137.83,50.77 139.71,50.77 v2(142.28,48.2)
  BOTTOM w0.254: v2(22.02,18.81) 22.02,18.41 21.73,18.13 R2442.1 ; v2(156.38,71.27) 157.01,71.27 ; R1910.1 145.12,71.82 FC8943.1 145.45,70.98 v2(145.73,70.7)
  BOTTOM w0.305: v2(16.41,56.37) 16.36,56.43 16.36,57.99 R7427.1 ; CN6601.26 167.55,39.77 168.21,39.11 v2(168.42,39.11) ; 24.96,45 24.81,44.85 24.16,44.85 24.1,44.91 22.58,44.91 22.39,45.1 22.27,45.1 21.92,45.46 v2(21.76,45.46)
  BOTTOM w0.356: v2(183.2,70.25) 182.68,70.77 U4008.5
  BOTTOM w0.381: PR5208.2 v2(177.71,71.95)
  BOTTOM w0.406: R2001.1 129.1,48.07 128.46,48.71 v2(128.46,49.24)
  BOTTOM w0.508: R7243.1 19.44,30.8 19.34,30.9 v2(19.34,30.96) 19.34,31.31 R7247.1 ; v2(129.02,59.43) 128.23,59.43 R1721.1 ; R2050.2 127.29,51.38 v2(127.29,51.88) ; v2(131.8,23.96) 133.14,25.29 R9212.1 ; v2(71.11,61.74) 71.11,60.87 72.66,59.32 R506.1 ; v2(31.79,34.44) 31.63,34.44 31.26,34.06 31.26,33.9 31.15,33.8 R2434.1 ; PR4486.2 27.2,45 24.96,45 ; G5701.1 35.24,78.77 v2(35.16,78.69) ; C6502.1 83.06,12.67 Q6502.S 81.05,12.08 79.95,12.08 78.67,10.8 v2(78.67,9.49) ; R7215.2 v2(11.6,26.05) ; FC8940.1 49.39,61.66 v2(49.82,61.23) PR5104.1 ; v3(175.68,67.71) 176.2,67.19 178.28,67.19 179.19,68.09 179.19,73.78 181.45,76.04 181.45,78.81 181.97,79.33 Q9201.S ; v2(28.61,11.95) 28.28,11.62 R2607.1 ; v2(17.95,42.18) 18.07,42.06 U4302.2
  BOTTOM w0.635: v2(175.73,44.44) 175.2,44.44 171.67,47.97 v3(171.67,49.6)
  vias: v2(31.41,18.69) v2(158.66,73.3) v2(158.66,72.54) v3(24.68,94.46) v3(25.19,93.67) v3(45.43,20.88) v3(73.14,19.83) v3(73.45,17.93) v3(73.98,19.91) v3(73.95,18.69) v3(73.95,17.04) v3(114.09,23.13) v3(115.1,23.13) v3(131.23,5.23) v3(132.12,5.2) v3(133.01,5.23) v3(173.17,67.68) v3(173.12,2.53)
3D3V_S5_KBC: length 139.6
  TOP w0.508: v2(28.72,33.98) 28.72,33.8 28.7,33.79 28.7,33.77 28.68,33.74 28.68,33.72 28.31,33.35 26.96,33.35 25.05,31.45 v2(24.24,31.45) ; v2(24.93,23.13) 24.94,23.13 25.5,23.69 R2608.1 ; v2(24.93,23.13) 24.68,22.88 R2443.1 ; v2(24.93,23.13) 24.93,23.24 24.4,23.77 C2411.1 ; 14.36,22.04 17.23,22.04 19.32,19.96 20.11,19.96 20.66,19.4 R4032.1 20.92,19.45 v2(22.77,19.45) 22.9,19.45 23.56,18.79 EC2402.1 ; v2(41.44,11.7) 40.86,12.29 v2(40.86,15.39) 40.86,17.37 41.94,18.45 41.94,20.02 v2(43.04,21.13) ; v2(37.63,31.13) 36.58,31.13 36.07,31.64 34.96,31.64 33.98,32.63 33.98,33.77 v2(33.92,33.83) ; v2(36.74,12.21) 36.23,11.7 36.23,10.76 34.58,9.11 34.58,7.46 34.76,7.28
  L3SGND w0.508: v2(28.72,33.98) 28.72,33.7 29.38,33.04 33.14,33.04 v2(33.92,33.83)
  L4SGND w0.508: v2(36.74,12.21) 36.74,12.4 35.91,13.23 34.13,13.23 33.25,14.11 33.21,14.11 32.7,14.11 32.64,14.17 32.55,14.17 31.94,14.78 31.94,15.64 32.25,15.94 32.25,18.75 30.02,20.97 29.52,20.97 28.87,21.62 28.87,22.8 v2(28.31,23.36) ; 24.89,23.13 v2(24.93,23.13) ; 24.89,23.13 24.42,23.6 24.42,25.57 23.41,26.59 23.41,27.69 24.04,28.33 24.04,28.86 23.79,29.11 23.79,31 v2(24.24,31.45) ; 24.89,23.13 24.3,22.54 24.3,20.64 23.1,19.45 v2(22.77,19.45) 21.76,19.45 21.13,18.83 21.13,17.53 v2(21.38,17.29) ; v2(33.44,30.63) 33.92,31.11 v2(33.92,33.83)
  L6 w0.508: v2(24.93,23.13) 28.08,23.13 v2(28.31,23.36)
  BOTTOM w0.203: v2(33.44,30.63) 33.09,30.63 32.53,30.07 U2401.19 ; U2401.22 v2(33.73,28.39) ; U2401.43 40.46,23.99 41.29,23.16 42.41,23.16 EC2403.1 ; v2(24.93,23.13) 24.58,22.79 U2401.115 ; v2(22.77,19.45) 23.05,19.17 23.05,18.19 23.26,17.99 U2401.103 ; C2420.1 30.94,12.93 U2401.82 ; U2401.5 26.94,30.34 ; U2401.65 38.44,14.17
  BOTTOM w0.356: RN2402.1 28.16,33.61 28.48,33.93 28.66,33.93 v2(28.72,33.98) 28.72,33.7 28.81,33.61 RN2402.2
  BOTTOM w0.508: v2(43.04,21.13) 43.83,21.13 44.34,21.63 v1(44.34,22.42) R2446.2 43.3,23.89 EC2403.1 ; 41.57,12.34 37.73,12.34 37.61,12.21 v2(36.74,12.21) ; 41.57,12.34 41.75,12.51 R2452.2 ; 41.57,12.34 41.44,12.21 v2(41.44,11.7) ; R2424.2 v2(33.92,33.83) ; v2(37.63,31.13) 37.3,31.46 R2415.2 ; v2(40.86,15.39) C2413.1 40.82,14.71 38.99,14.71 38.44,14.17 ; C2422.1 20.64,17.26 21.35,17.26 v2(21.38,17.29) ; 26.94,30.34 27.09,30.5 C2412.1 C2414.1 25.59,31.95 R2414.2 25.36,31.77 24.56,31.77 v2(24.24,31.45) ; v2(36.74,4.46) 34.94,4.46 32.57,6.84 32.57,7.2 31.99,7.77 31.99,8.15 30.9,9.24 30.9,12.79 C2420.1
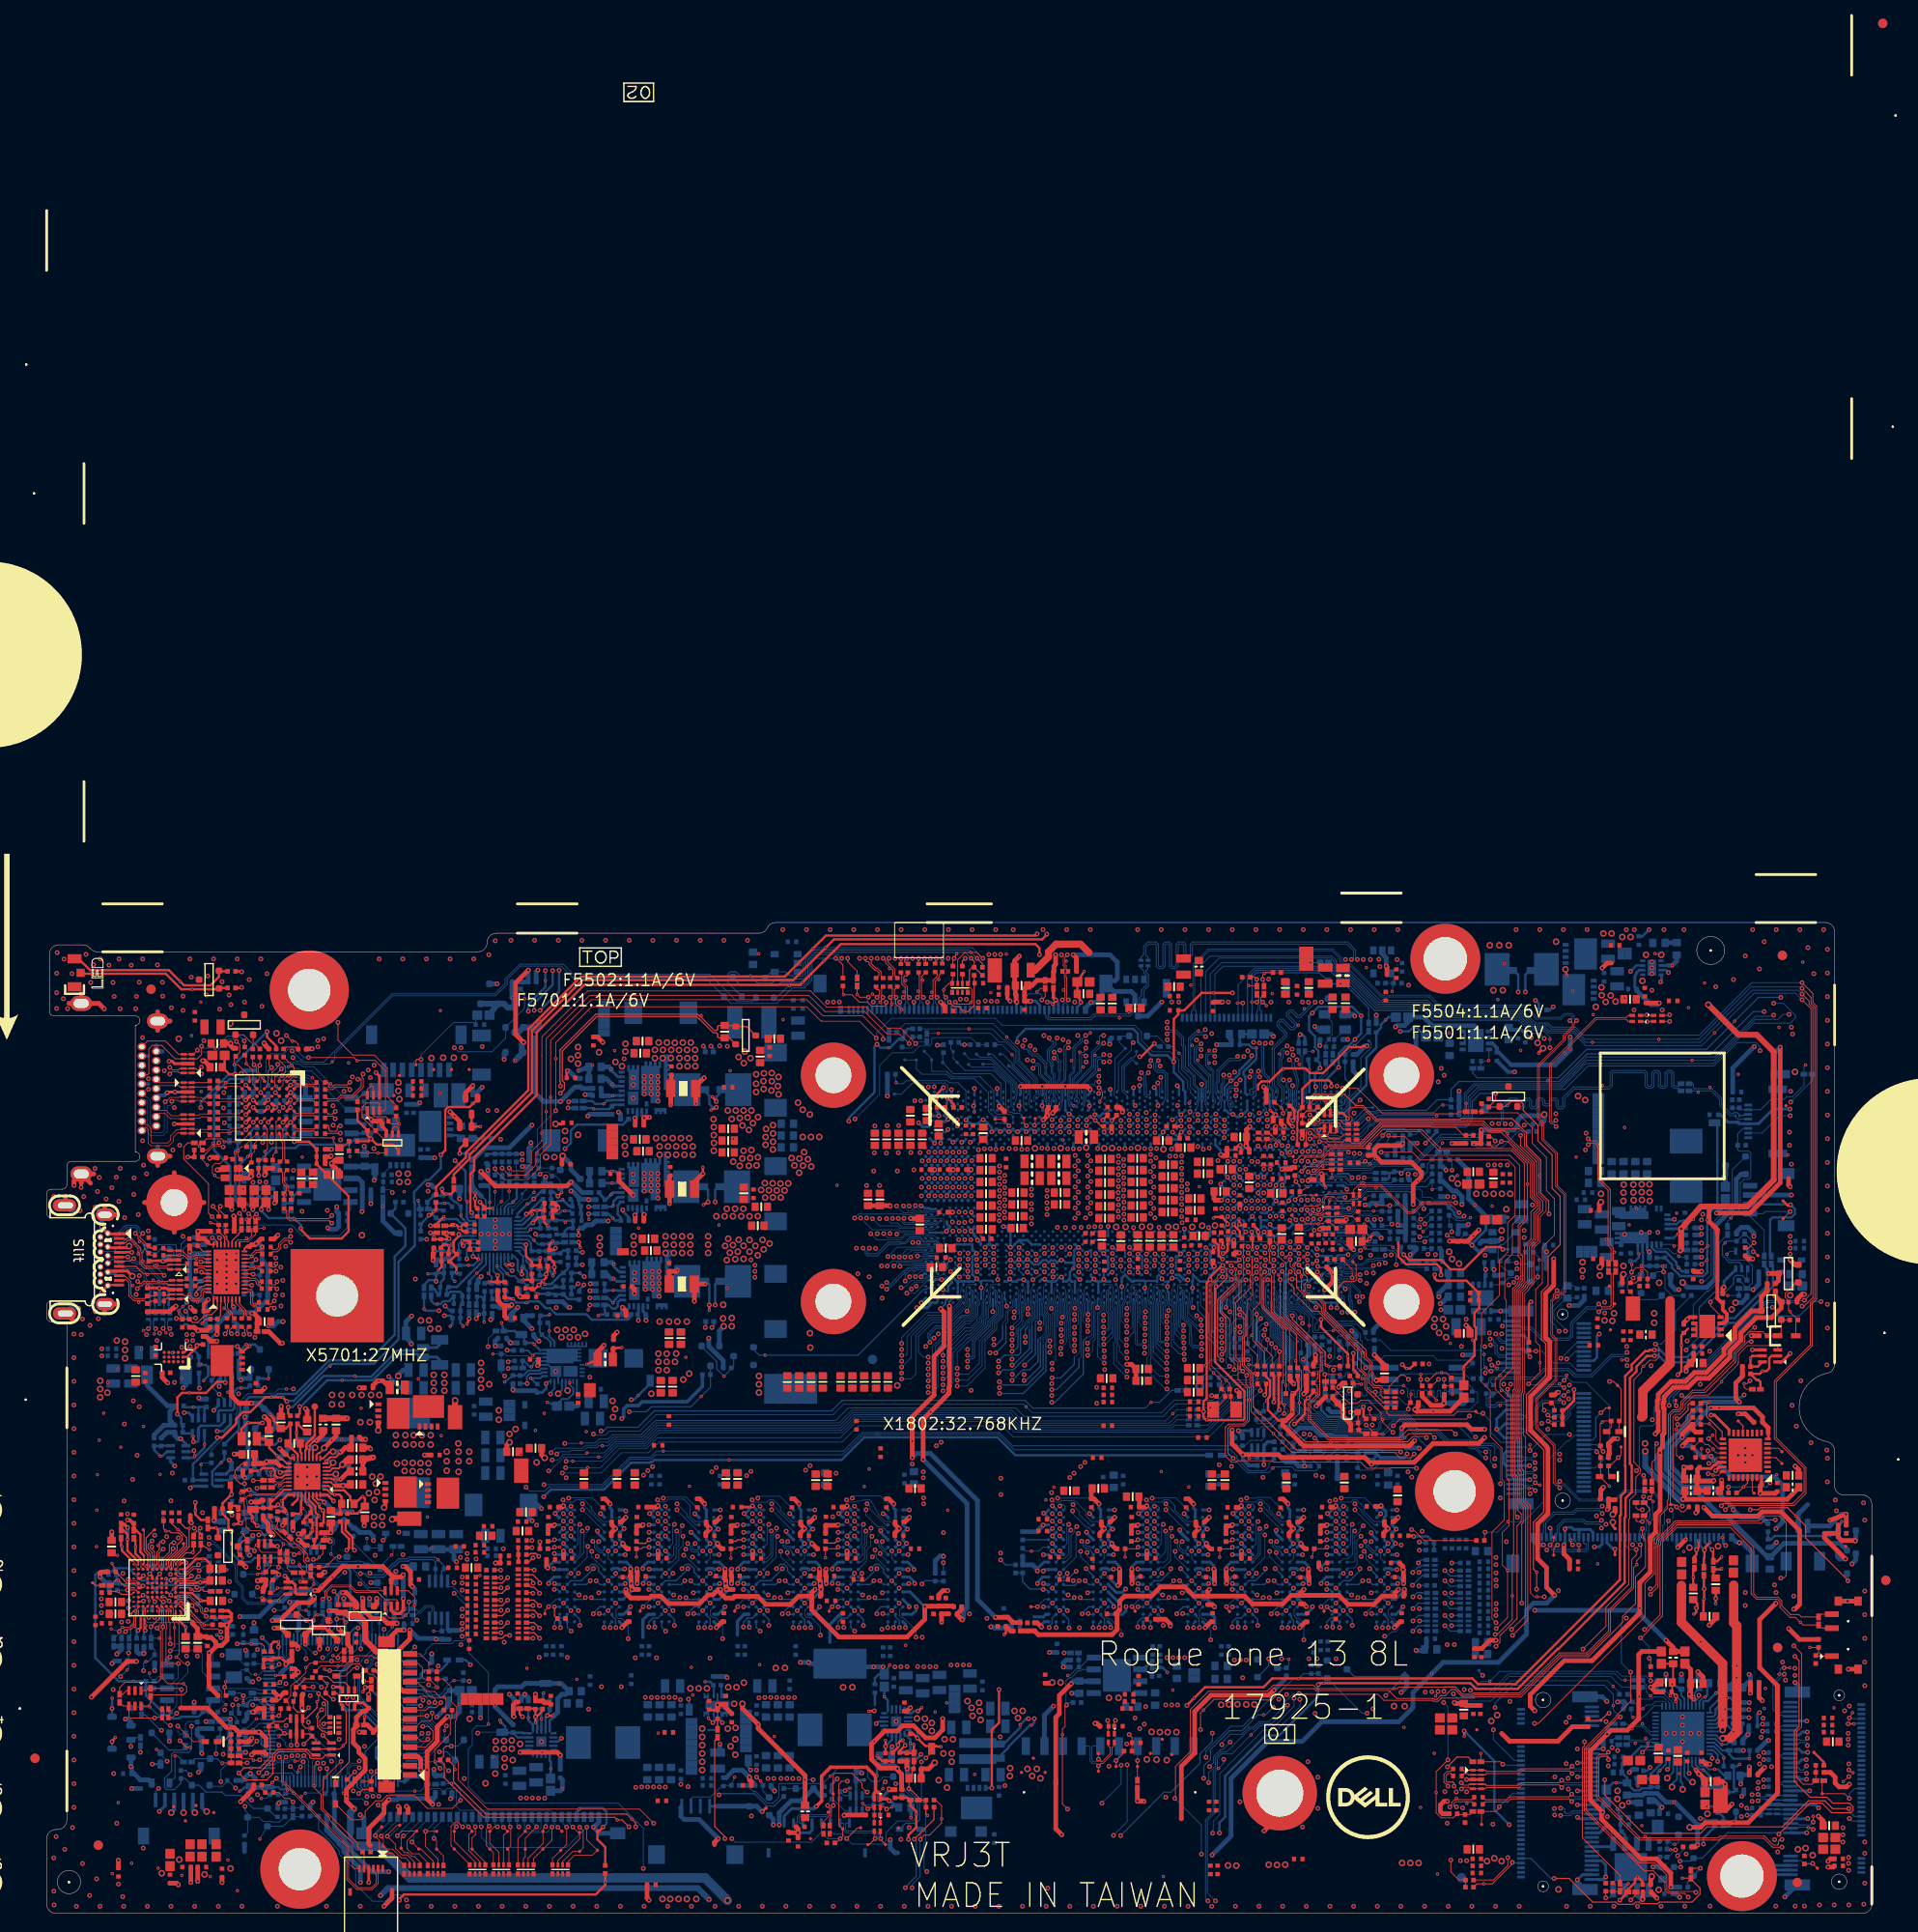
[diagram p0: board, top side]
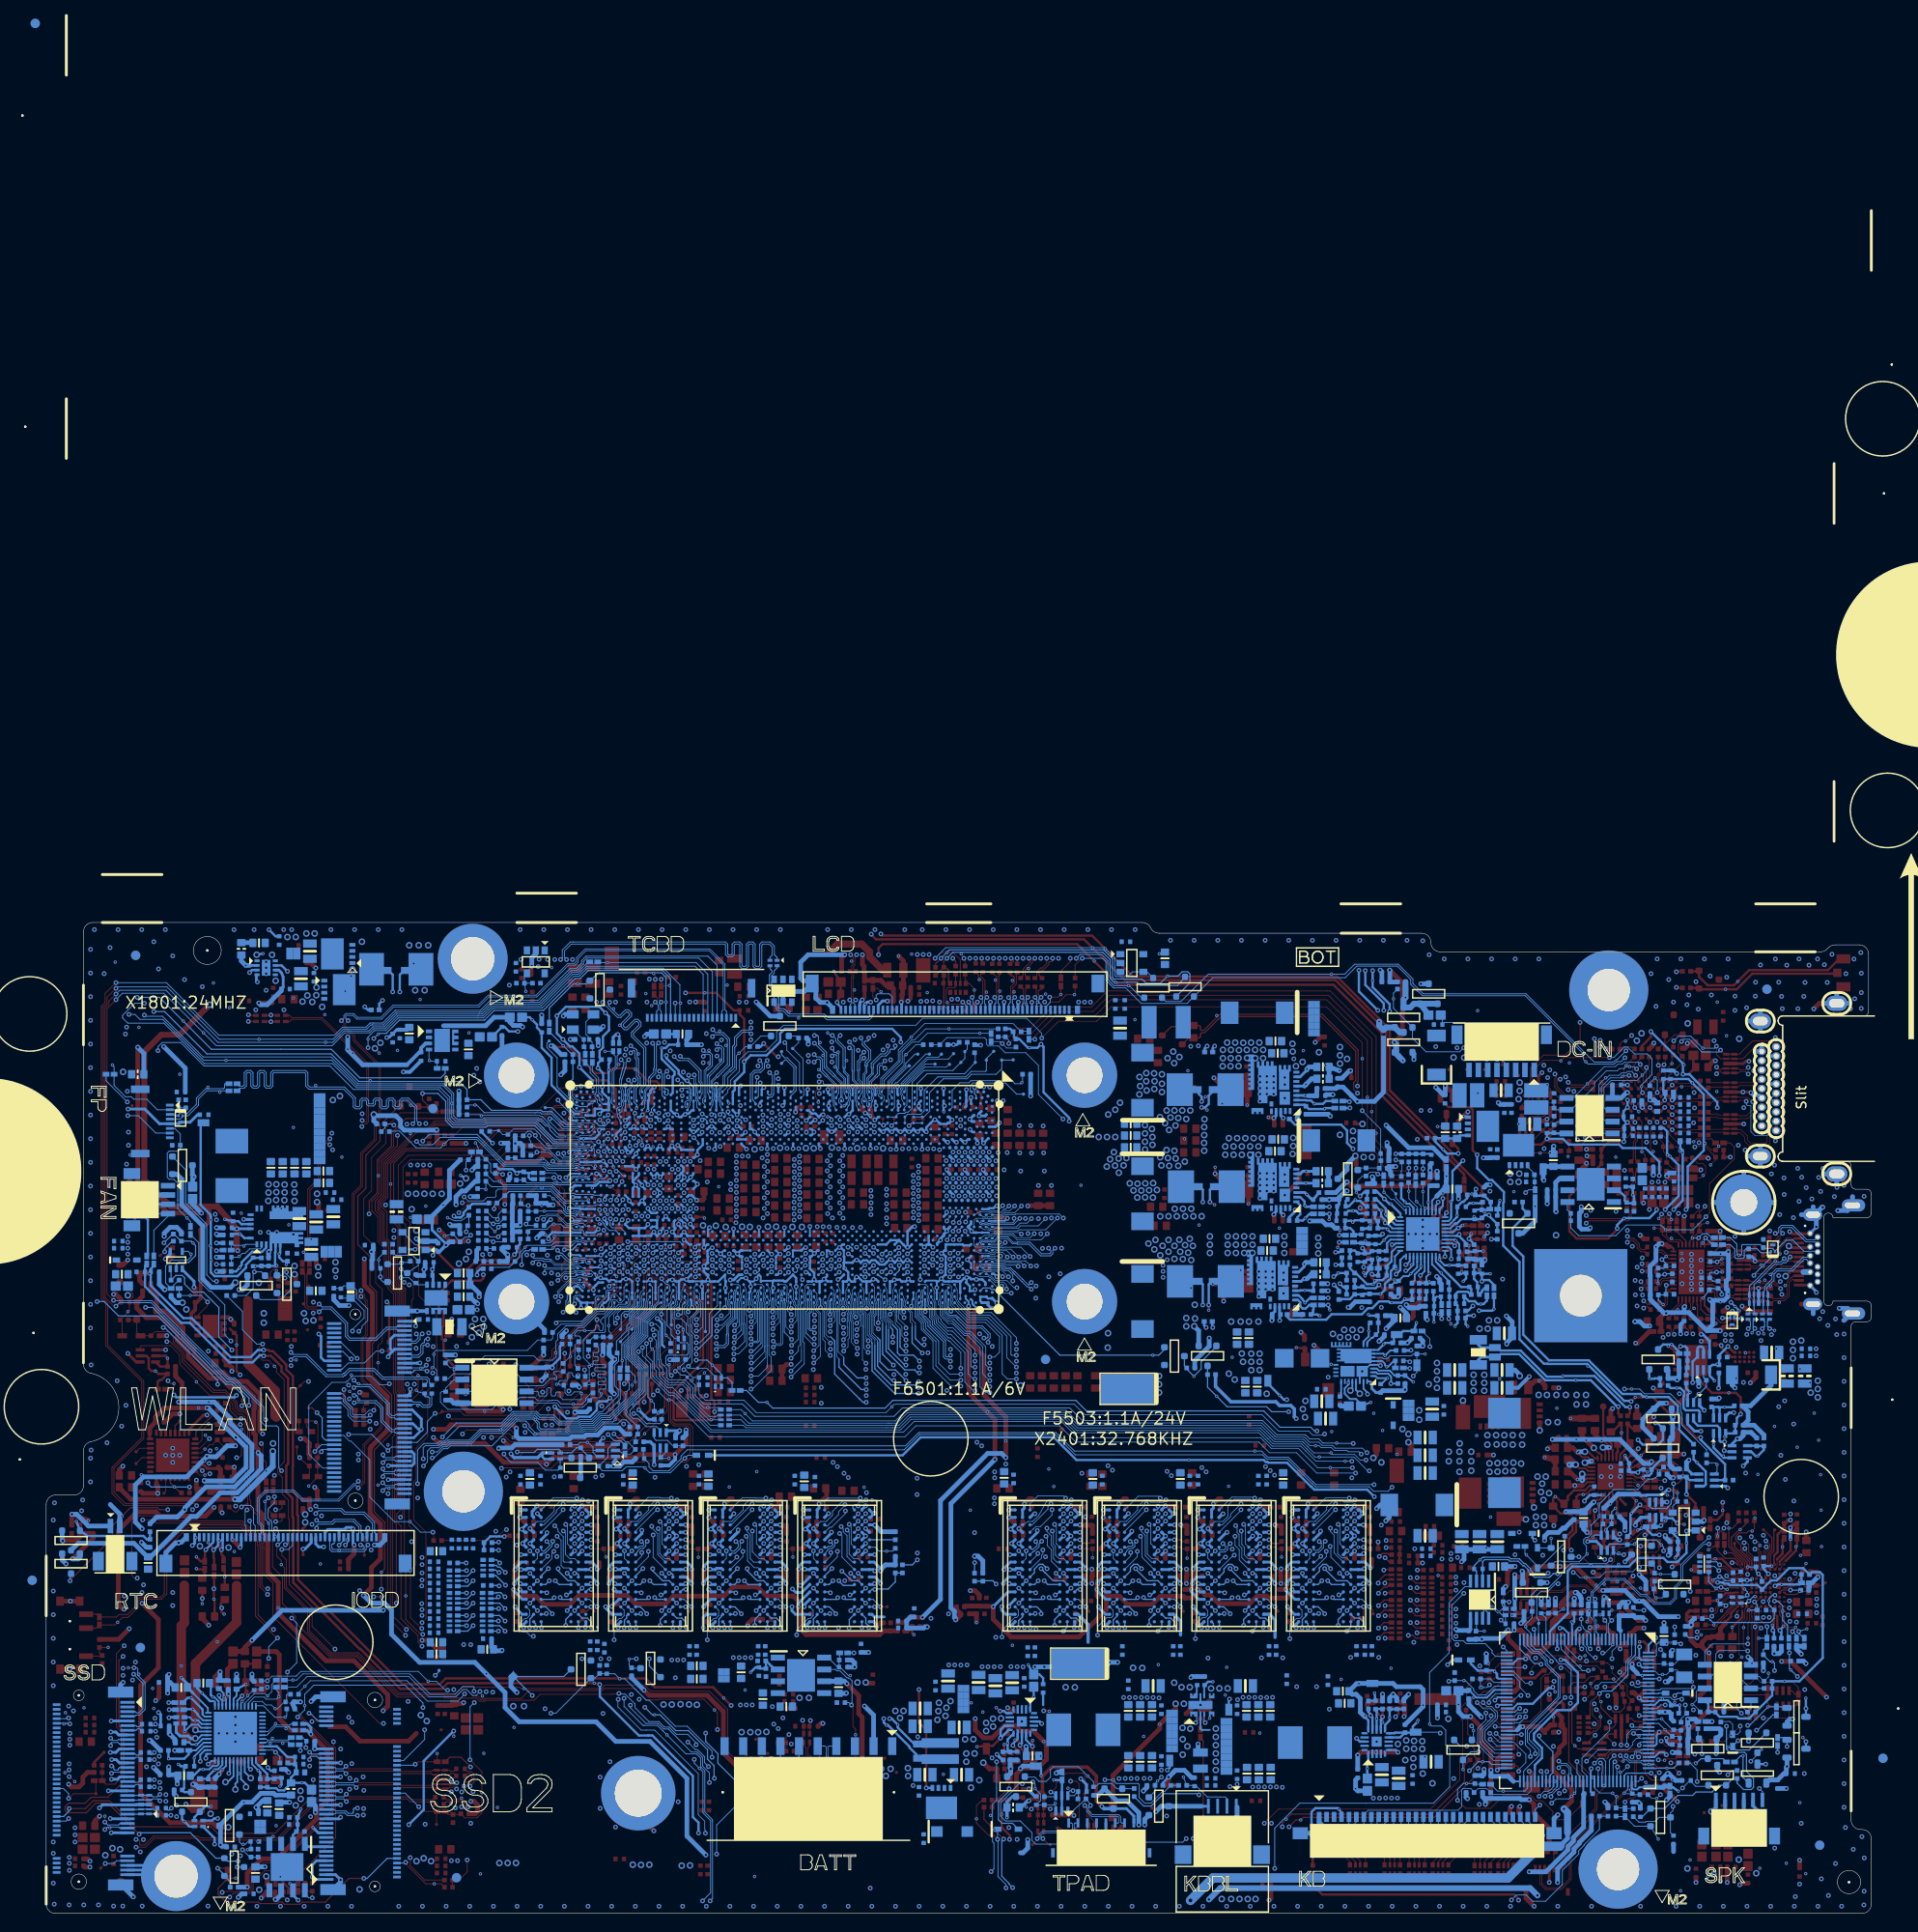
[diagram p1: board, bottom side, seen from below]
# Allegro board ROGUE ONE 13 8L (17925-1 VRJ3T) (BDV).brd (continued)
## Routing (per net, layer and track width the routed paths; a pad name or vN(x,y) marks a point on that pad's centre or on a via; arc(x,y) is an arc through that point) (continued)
3D3V_S5_PCH: length 205.2
  TOP w0.203: R405.1 134.35,86.02 134.35,85.12 134.3,85.07 134.3,82.57 R406.1
  TOP w0.254: v2(137.96,88.79) 137.96,89.15 137.71,89.4 135.78,89.4 134.84,88.46 R405.1 ; v2(149.73,68.52) 149.73,69.22 149.29,69.66 145.99,69.66 145.15,70.5 145.15,72.03
  TOP w0.508: v2(135,55.76) 135.27,56.03 135.27,57.65 R1837.1 ; R9148.1 176.3,50.84 175.68,50.22 v2(175.68,50.18) ; v2(187.08,30.55) 188.23,29.41 R9805.1 ; C2501.1 143.68,58.84 v2(142.58,59.94)
  L3SGND w0.508: v2(134.94,59.45) 135.39,59 141.2,59 v2(141.64,58.57) 141.64,59 v2(142.58,59.94) ; v2(137.96,88.79) 137.96,88.03 140.09,85.9 v2(140.4,85.9) 153.18,85.9 154.98,84.09 156.38,84.09 159.55,80.92 v2(159.55,76.04)
  L3SGND w1.016: v2(152.06,59.94) 152.62,59.94 153.55,60.87 153.55,62.1 153.95,62.49 153.95,62.58 154.34,62.97 154.34,66.17 156.33,68.15 156.33,69.55 157.77,71 157.77,74.55 v3(156.75,75.58)
  L4SGND w0.508: v2(142.58,59.94) 143.21,60.56 150.82,60.56 151.45,59.94 v2(152.06,59.94) 152.21,60.09 155.72,60.09 155.87,59.94 156.43,59.94 157.29,59.07 160.57,59.07 161.9,60.41 163.81,60.41 165.37,58.84 167.25,58.84 169.01,57.09 176.29,57.09 177.7,55.67 177.7,53.06 179.42,51.34 179.42,49.73 178.75,49.06 v2(178.74,49.06) ; v2(187.08,30.55) 186.58,31.06 186.58,34.66 186.86,34.94 186.86,40.12 v2(185.7,41.28) ; v2(159.55,76.04) 159.55,79.62 157.29,81.88 147.83,81.88 145.45,79.5 v2(145.45,79.42)
  BOTTOM w0.254: 142.53,73.83 141.9,74.47 v2(141.82,74.47) ; v2(149.73,68.52) 149.73,68.83 149.35,69.18 R1513.1 ; v2(141.64,58.57) 141.64,58.79 140.83,59.61 140.83,60.88 R1508.1 ; R1504.1 147.36,79.88 145.91,79.88 v2(145.45,79.42) 145.28,79.6 R1551.1 144.6,79.47 144.18,79.47 ; 144.18,79.47 144.18,78.98 144,78.8 RN1811.2 ; 144.18,79.47 RN1811.1 ; R1554.1 148.55,76.14 150.25,76.14 R1522.1 151.17,75.23 151.17,74.99 151.45,74.71 151.47,74.69 152.06,74.69 v2(152.21,74.85)
  BOTTOM w0.508: BIOS1.8 142.38,58.57 C2502.1 141.72,58.64 v2(141.64,58.57) ; R1510.1 v2(142.58,59.94) ; v2(135,55.76) 135.39,56.15 135.39,59 v2(134.94,59.45) 135,59.45 135.53,59.94 R303.1 135.55,60.85 R1506.1 ; v2(175.68,50.18) 176.57,50.18 177.73,49.02 178.69,49.02 v2(178.74,49.06) 178.74,49.06 178.74,49.03 180.92,46.85 185.56,46.85 186.42,45.99 186.42,42 v2(185.7,41.28) ; v2(152.06,59.94) R2519.1
  vias: v1(155.23,75.91)
3D3V_SEN_S0:
  vias: v1(122.87,99.64) v2(121.58,97.81)
3D3V_SSD: length 1.8
  TOP w0.254: R6303.1 190.84,16.22 AFTP6304.1
  vias: v1(191.94,22.07) v2(192.9,9.19) v2(192.9,8.43) v2(192.9,7.66) v2(193.08,21.74) v2(193.46,19.32) v2(193.46,18.69) v2(193.46,18.05) v2(193.59,22.24) v2(193.51,6.01) v2(193.51,5.38) v2(193.51,4.62)
3D3V_TBT: length 1.9
  TOP w0.254: U7201.H2 13.54,35.94 v2(13.35,35.76)
  BOTTOM w0.254: v1(12.79,35.91) 12.94,35.76 v2(13.35,35.76) C7210.1
3D3V_TP_VDD: length 20.7
  TOP w0.356: v2(90.47,12.08) 90.26,12.29 RN6501.1 89.52,12.78 89.27,13.02 89.02,13.02 88.87,12.88 RN6501.2
  TOP w0.381: 89.02,13.02 89.02,14.72 88.05,15.69 84.18,15.69 83.22,14.73 83.22,12.06 v2(82.64,11.47)
  BOTTOM w0.305: Q6502.D 80,11.24 79.2,10.45 TPAD1.8
  BOTTOM w0.381: Q6502.D 82.41,11.24 v2(82.64,11.47) ; v2(90.47,12.08) 90.59,12.08 91.3,11.37 R6503.1
3D3V_TPAN_VDD:
  vias: v1(131.61,98.72) v2(131.48,97.81)
3D3V_TPM: length 33.8
  TOP w0.305: U9102.8 184.9,51.48 184.87,51.5 ; U9102.22 179.5,48.42 179.19,48.11 179.07,48.11 178.71,47.74 177.64,47.74 C9113.1
  TOP w0.508: R9140.1 177.64,51.66 177.08,51.66 176.77,51.96 R9149.2 176.67,52.47 175.63,51.43 v2(175.63,51.07) ; C9109.1 177.46,46.4 178.98,46.4 v2(179.03,46.45) ; C9109.1 177.28,46.68 177.28,47.64 C9113.1 ; C9109.1 R9126.2 R9127.2 ; 184.87,51.5 184.87,52.11 C9112.2 184.27,53.28 183.3,54.25 v1(179.62,54.25) v2(178.73,54.25)
  BOTTOM w0.508: v2(179.03,46.45) 178.99,46.41 176.01,46.41 174.54,47.89 174.54,50.04 175.57,51.07 v2(175.63,51.07) 177.33,52.77 177.33,52.99 178.59,54.25 v2(178.73,54.25)
3D3V_TPM_VSB:
  vias: v1(185.79,47.08)
3D3V_VCCDSW: length 91.8
  TOP w0.254: v2(127.46,73.96) 127.46,73.91 127.47,73.91 127.47,73.89 128.13,73.22 128.13,72.69 R1707.1 ; R1524.1 140.81,57.88 140.32,58.36 v2(140.32,60.11)
  L3SGND w0.305: v2(152.44,63.77) 152.32,63.77 151.42,62.88 151.42,62.03 149.8,60.41
  L3SGND w0.381: v2(153.07,71.72) 152.95,71.6 152.95,67.58 152.44,67.07 v2(152.44,63.77) ; 149.8,60.41 148.44,60.41 146.2,58.17 145.28,58.17 142.94,60.51 140.72,60.51 v2(140.32,60.11) 139.81,60.62 135.39,60.62 132.17,63.85 v2(130.39,63.85)
  L4SGND w0.254: v2(127.46,73.96) 127.46,73.91 127.47,73.91 127.47,73.87 128.26,73.08 128.26,72.97 128.57,72.66 129.2,72.66 129.89,72.66 129.9,72.65 130.3,72.65 130.31,72.66 131.08,72.66 131.2,72.77 131.29,72.77 131.45,72.93 133.91,72.93 134.49,72.34 134.82,72.34 134.87,72.29 136.63,72.29 139.51,69.41 139.51,68.22 140.61,67.12 142.41,67.12 144.01,68.73 146.66,68.73 148.25,67.13 150.35,67.13 150.92,66.57 150.92,65.3 v2(152.44,63.77)
  BOTTOM w0.254: CPU1.BR24 127.44,73.84 127.44,73.94 v2(127.46,73.96) 127.47,73.96 127.47,74.06 CPU1.BT23 ; 129.6,60.77 129.86,61.03 129.86,63.32 v2(130.39,63.85)
  BOTTOM w0.305: v2(153.07,71.72) 153.07,71.87 154.56,73.36 154.56,74.2 R2516.1
  BOTTOM w0.381: v2(153.07,71.72) 153.79,71.01 C2224.1 154.1,71.2 U2502.1
  BOTTOM w0.508: v2(153.07,71.72) 152.72,72.08 R1520.1 ; R2516.1 v1(153.36,76.03) 152.69,76.7 152.69,79.72 R1819.1
3D3V_VCCPRIM: length 67.7
  TOP w0.254: R1731.1 139.74,60.04 136.86,62.92 v2(136.86,63.73)
  L3SGND w0.254: v2(148.07,82.67) 148.65,83.25 152.64,83.25 153.71,82.19 154.85,82.19 154.95,82.09 157.04,82.09 158.48,80.64 158.48,77.03 157.92,76.47 156.14,76.47 155.77,76.09 155.77,75.1 156.86,74.01 156.86,72.28 156.48,71.9 155.74,71.9 v2(154.47,70.63)
  L4SGND w0.254: v2(154.47,70.63) 151.74,67.9 148.57,67.9 146.47,70 145.58,70 144.9,70.68 144.9,70.91 144.6,71.21 144.18,71.21 144.11,71.14 143.54,71.14 143.5,71.09 143.38,71.09 142.41,70.12 141.5,70.12 141.29,69.91 140.56,69.91 v2(139.76,70.71)
  L6 w0.254: v2(136.86,63.73) 136.86,63.76 137.33,64.23 137.33,66.11 139.76,68.55 v2(139.76,70.71)
  L6 w0.305: v2(131.37,78.2) 131.37,76.39 132.02,75.74 v2(132.02,74.84)
  BOTTOM w0.203: v2(139.76,70.71) 139.71,70.66 138.72,70.66 CPU1.CP29
  BOTTOM w0.254: CPU1.CB16 131.37,78.26 v2(131.37,78.2) ; R1701.1 149.24,83.84 v2(148.07,82.67) ; v2(126.84,74.79) 126.84,74.79 126.51,74.46 CPU1.BP23 ; CPU1.BT20 127.47,75.74 v2(127.47,75.63) ; CPU1.BW23 129.76,74.5 129.46,74.79 v2(129.46,74.81) 129.11,74.46 CPU1.BV23
  vias: v1(130.32,74.72) v2(132.68,74.82)
3D3V_VCCPRTC: length 41.7
  TOP w0.254: R2204.2 v1(152.19,58.36) 152.19,58.72 153.33,59.86 153.33,61.47 153.49,61.63 153.49,62.86 153.33,63.03 153.33,64.46 153.84,64.97 153.84,65.75 C2221.1 C2222.1 152.46,67.91 149.31,67.91 149.06,68.17 v2(149.06,68.55)
  L4SGND w0.254: v2(127.49,74.8) 127.52,74.82 127.95,74.82 129.1,73.68 130.48,73.68 130.53,73.62 130.94,73.62 131.29,73.27 134.05,73.27 134.63,72.69 134.97,72.69 135.02,72.64 136.92,72.64 137.78,71.77 141.9,71.77 142.03,71.65 143.89,71.65 143.97,71.72 144.81,71.72 144.92,71.6 146.39,71.6 146.98,71.01 146.98,70.25 148.68,68.55 v2(149.06,68.55)
  BOTTOM w0.254: CPU1.BR23 127.49,74.73 v2(127.49,74.8)
3D3V_WLAN: length 4.2
  TOP w0.508: v2(168.7,50.95) 168.24,50.95 167.73,50.44 R6106.1 167.81,50.11 167.81,49.29 167.73,49.22 R6109.1 ; v2(167.17,45.74) 167.04,45.61 167.04,45.56 166.89,45.41 166.89,44.54 C6104.1
  vias: v3(167.3,63.65) v3(168.13,63.59) v3(168.31,64.41)
65982D_BUSPWR: length 4.5
  TOP w0.254: v2(10.35,35.15) 10.3,35.15 10.1,34.94 U7201.F10
  BOTTOM w0.254: R7204.2 R7236.1 7.68,35.3 v1(9.64,35.3) 10.06,35.3 10.21,35.15 v2(10.35,35.15)
65982D_DBG_CTL1: length 2.2
  TOP w0.127: v2(13.32,34.16) 13.04,34.44 U7201.E4
  BOTTOM w0.127: RN7202.2 13.53,33.95 v2(13.32,34.16) 13.32,34.51 v1(13.63,34.82)
65982D_DBG_CTL2: length 2.8
  TOP w0.127: v2(13.15,33.53) 12.74,33.94 U7201.D5
  BOTTOM w0.127: v1(12.5,34.01) 12.66,34.01 13.14,33.53 v2(13.15,33.53) 13.39,33.29 14,33.29 RN7202.1
65982D_DEBUG1: length 3.4
  TOP w0.127: U7201.L2 13.85,37.59 14.96,38.7 v1(15.71,38.7) 15.79,38.78 R7220.2
65982D_DEBUG2: length 5.5
  TOP w0.089: 14.27,37.7 14.07,37.51 14.07,37.17 U7201.K2
  TOP w0.127: v1(17.49,39.03) R7221.2 16.55,38.95 15.73,38.13 15.7,38.09 14.66,38.09 14.27,37.7
65982D_DIG_AUD_N: length 6.7
  TOP w0.127: R7241.2 14.24,42.03 14.92,41.34 v1(15.3,41.34) 15.3,39.35 13.6,37.65 13.6,37.2 U7201.K3
65982D_DIG_AUD_P: length 6.1
  TOP w0.127: U7201.L3 13.35,37.7 15.04,39.39 15.04,40.32 14.16,41.19 v1(14.09,41.19) 13.42,41.85 R7242.2
65982D_GND: length 2.6
  TOP w0.254: v2(11.05,36.44) 11.04,36.44 11.04,36.42 11.1,36.42 11.35,36.16 U7201.H7
  BOTTOM w0.254: v1(10.68,37.28) C7212.2 11.57,36.96 v2(11.05,36.44)
65982D_GPIO1: length 3.6
  TOP w0.127: v1(16.09,32.48) v2(15.62,33.03) 14.97,33.68 14.09,33.68 U7201.C2
  BOTTOM w0.127: v2(15.62,33.03) 15.78,33.19 R7245.2
65982D_GPIO2: length 11.8
  TOP w0.127: U7201.D10 10.15,33.94 v2(10.35,34.15)
  BOTTOM w0.127: v2(10.35,34.15) 10.64,34.15 11.01,33.77 v1(11.01,33.55) 11.01,33.13 R7231.2 10.44,31.65 10.86,31.22 17.02,31.22 17.27,31.47 17.31,31.47 17.47,31.64 R7247.2
65982D_GPIO3: length 3.4
  TOP w0.127: U7201.G11 8.6,35.44 8.36,35.69 8.36,35.73 7.77,36.32 7.77,36.33 7.48,36.62 R7208.2 v1(7.02,37.55)
65982D_GPIO8: length 3.3
  TOP w0.127: U7201.H6 11.85,36.15 v2(12.13,36.43)
  BOTTOM w0.127: R7222.2 11.75,36.05 v2(12.13,36.43) 12.38,36.69 R7223.1 v1(13.27,37.18)
65982D_HPD_CON: length 5.4
  TOP w0.127: U7201.C10 10.32,33.44 v2(10.4,33.52)
  BOTTOM w0.127: R7227.2 9.01,29.69 9.01,30.93 9.52,31.45 v1(9.52,32.43) 9.52,32.99 10.05,33.52 v2(10.4,33.52)
65982D_HRESET: length 2.8
  TOP w0.127: U7201.D6 12.36,33.44 v2(12.55,33.44)
  BOTTOM w0.127: v2(12.55,33.44) 12.26,33.14 R7202.1 v1(13.15,32.56)
65982D_I2C_ADDR: length 3.7
  TOP w0.127: U7201.F1 15.46,34.94 15.82,34.58 16.39,34.58 v1(16.66,34.85) 16.66,34.8 16.9,34.56 R7201.2
65982D_LDO_1V8A: length 4.4
  TOP w0.178: U7201.K1 14.7,36.94
  TOP w0.254: C7203.2 17.54,37.56 17.06,38.04 16.78,38.04 v1(16.77,38.05) 16.05,38.05 14.94,36.94 14.7,36.94
65982D_LDO_1V8D: length 3.2
  TOP w0.178: U7201.A2 13.85,32.21
  TOP w0.254: C7202.2 14.92,30.6 14.95,30.63 v1(14.95,30.74) 14.91,30.74 13.85,31.8 13.85,32.21
65982D_LDO_BMC: length 3.7
  TOP w0.178: U7201.E1 14.66,34.44 14.72,34.38
  TOP w0.254: C7201.2 16.68,33.55 16.6,33.62 v1(16.54,33.62) 16.54,33.56 16.52,33.55 16.52,33.52 16.52,33.58 16.19,33.85 15.61,34.38 14.72,34.38
65982D_LSRX: length 3.5
  TOP w0.127: U7201.K4 13.09,37.19 13.09,37.77 14.69,39.37 TP7202.1
65982D_LSTX: length 6.9
  TOP w0.127: U7201.L4 12.85,37.83 14.01,38.99 14.01,39.53 14.56,40.08 14.56,40.48 14.18,40.85 13.39,40.85 13.2,41.03 v1(12.81,41.03) 12.56,41.28 R7237.2
65982D_MRESET: length 2.9
  TOP w0.127: U7201.E11 9.14,34.23 8.01,34.23 v1(7.68,34.56) 6.9,34.56 R7214.2
65982D_RESET_N: length 3.1
  TOP w0.127: R7229.1 7.43,35.78 v1(7.68,35.78) 8.34,35.12 8.85,35.12 9.03,34.94 U7201.F11
65982D_ROSC: length 5.2
  TOP w0.127: U7201.G2 14.09,35.68 15.84,35.68 v2(16.3,36.14)
  BOTTOM w0.127: R7206.1 15.66,35.71 15.73,35.78 15.73,35.78 16,36.04 16,36.04 16.09,36.14 v2(16.3,36.14) v1(17.01,35.78)
65982D_SBU1_R: length 4.9
  TOP w0.127: TP7203.1 11.55,41.17 10.68,40.3 10.68,39.01 11.09,38.6 11.09,37.18 U7201.K8
65982D_SBU2_R: length 3.9
  TOP w0.127: TP7204.1 10.47,41.08 10.47,38.89 10.85,38.51 U7201.L8
65982D_UART_RX: length 6.3
  TOP w0.127: v2(16.15,35) 15.97,35.18 14.09,35.18 U7201.F2 U7201.E2
  BOTTOM w0.127: v1(15.48,34.77) v2(16.15,35) 16.86,35 17.46,35.6 RN7207.5
+DC_IN_C:
  vias: v1(42.25,88.03) v3(41.33,91.8) v3(42.58,91.84) v3(43.73,91.84) v3(44.87,91.86)
+RTC_VCC: length 10.9
  TOP w0.508: v2(194.22,39.97) 194.18,40.02 192.75,40.02 192.39,40.38 R2504.1 ; v2(193.18,38.04) 190.92,40.3 AFTP2508.1 R2504.1 ; R2504.1 R2510.1
  BOTTOM w0.508: v2(193.18,38.04) 192.55,38.04 192.36,38.23 Q2505.G ; v2(194.22,39.97) 194.29,40.04 D2501.2
+SDC_IN: length 17.5
  TOP w0.203: PU4401.16 26.15,48.84 25.74,49.24
  TOP w0.508: v2(25.03,49.88) 25.67,49.24 25.74,49.24
  L3SGND w0.508: v2(25.03,49.88) 24.42,50.49 24.42,52.38 24.55,52.51 24.55,53.17 20.87,56.85 v2(20.87,57.25)
  BOTTOM w0.305: PG4401.1 41.9,60.72 42.2,61.03 PR4401.1
  BOTTOM w0.508: Q7401.S 21.83,58.27 R7406.1 21.03,57.42 v2(20.87,57.25) 20.66,57.46 R7404.2 20.66,58.59 C7401.1
  vias: v1(30.44,58.74) v1(38.39,77.46) v3(37.81,79.39) v3(37.89,78.5) v3(38.77,79.39) v3(38.77,78.5) v3(40.18,63.65) v3(41.06,63.65) v3(41.2,62.76) v3(42.08,62.76)
+SDC_IN_SW: length 43.9
  L4SGND w0.102: v2(26.51,56.28) 31.5,61.27 31.91,61.27 33.17,61.27 33.25,61.35 33.25,61.35 36.15,64.25 36.15,74.11 37.12,75.08 v2(37.12,77.36)
  BOTTOM w0.102: PU4302.4 36.91,80.12 36.18,79.39 R4318.2 36.16,79.24 C4343.2 36.16,77.72 R4368.1 36.82,77.67 v2(37.12,77.36) ; R4333.2 17.69,49.75 20.33,52.39 20.33,53.67 20.48,53.81 20.48,54.68 21.57,55.77 24.37,55.77 24.88,56.28 v1(25.74,56.28) v2(26.51,56.28)
+SDC_IN_SW_R1: length 2.3
  BOTTOM w0.102: R4333.1 16.75,48.35 v1(16.57,48.18) 16.57,47.44 Q4349.3
+V_VREF_PATH1: length 1.7
  TOP w0.508: C1202.2 R1203.1 v1(96.1,31.23)
+V_VREF_PATH2: length 2
  TOP w0.254: R1303.1 103.01,30.1 v1(102.82,29.91)
  TOP w0.508: C1302.2 103.54,30.29 103.12,30.71 103.11,30.71 R1303.1
A_ZQ_RAM1: length 3
  TOP w0.102: v2(84.99,39.3) 84.83,39.13 R1205.1 v1(83.63,38.17)
  BOTTOM w0.102: RAM1.F9 v2(84.99,39.3)
A_ZQ_RAM2: length 3
  TOP w0.102: v2(74.84,39.3) 74.19,39.3 74.03,39.13 R1234.1 v1(73.48,38.12)
  BOTTOM w0.102: RAM2.F9 v2(74.84,39.3)
A_ZQ_RAM3: length 2.9
  TOP w0.102: v1(63.33,38.25) R1204.1 63.88,39.13 64.04,39.3 v2(64.69,39.3)
  BOTTOM w0.102: RAM3.F9 v2(64.69,39.3)
A_ZQ_RAM4: length 1.9
  TOP w0.102: v1(55.11,39.31) 55.09,39.3 v2(54.54,39.3) 54.38,39.13 R1201.1
  BOTTOM w0.102: RAM4.F9 v2(54.54,39.3)
AC_DIS: length 114.9
  TOP w0.254: Q4304.B 46.28,87.41 45.41,86.54 43.11,86.54 42.81,86.24 42.81,81.91 v2(42.33,81.43) ; v2(25.8,54.95) v1(25.36,55.39) 23.46,55.39 21.86,53.79 21.06,53.79 20.36,53.09 20.36,52.6 18.84,51.07 v2(18.33,51.07)
  L4SGND w0.254: v2(33.34,27.22) 33.29,27.22 32.93,27.58 32.93,30.84 33.29,31.19 33.29,34.91 33.1,35.1 32.74,35.1 30.22,37.61 30.22,38.29 26.12,42.39 24.87,42.39 23.41,43.86 23.41,46.26 22.82,46.84 22.82,49.85 24.05,51.08 24.05,54.16 24.85,54.95 v2(25.8,54.95)
  BOTTOM w0.203: 36.14,15.54 U2401.69
  BOTTOM w0.254: v2(42.33,81.43) 42.33,79.98 41.06,78.71 40.74,78.71 39.46,77.43 39.46,76.34 39.54,76.27 39.54,71.67 37.78,69.92 37.78,61.61 35.17,59 34.8,59 34.78,58.97 30.5,58.97 26.53,55.01 25.85,55.01 v2(25.8,54.95) ; v2(33.34,27.22) 32.91,27.22 31.52,25.83 31.52,22.61 32.32,21.81 33.72,21.81 36.23,19.3 36.23,18.61 35.37,17.75 35.37,16.68 36.14,15.92 36.14,15.54 ; Q4349.2 R4379.1 15.71,48.21 18.33,50.83 v2(18.33,51.07)
AC_IN#: length 124.9
  TOP w0.254: PR4493.2 20.32,43.75 D4305.K 19.72,42.92 v2(19.9,42.74)
  L4SGND w0.254: v2(44.62,32.66) 47.66,35.71 47.66,38.67 51.03,42.03 51.03,42.37 v2(53.38,44.72)
  L6 w0.254: v2(19.9,42.74) 19.9,41.85 20.31,41.45 20.31,41.3 20.36,41.25 20.36,40.83 20.31,40.78 20.31,39.05 20.41,38.95 20.41,37.05 20.99,36.47 20.99,35.94 22.75,34.18 26.51,34.18 28.03,32.66 v2(44.62,32.66)
  BOTTOM w0.254: D1701.K 104.03,49.17 102.1,51.1 89.58,51.1 89.58,51.1 89.37,51.1 89.37,51.1 89.17,51.1 87.79,51.1 85.36,48.66 v1(73.29,48.66) 65.25,48.66 65.04,48.46 64.85,48.46 64.76,48.37 62.74,48.37 60.19,45.81 60.16,45.81 59.83,45.48 59.58,45.48 54.14,45.48 v2(53.38,44.72)
AC_IN#_G: length 3.3
  BOTTOM w0.254: U4302.5 21.34,40.82 20.77,40.25 R4377.1 R4376.2 20.77,38.52 21.04,38.25 v1(21.04,38.14)
AC_PRESENT: length 39.7
  TOP w0.102: v2(128.86,57.75) 128.8,57.68 128.8,56.76 129.13,56.42 129.13,52.88 128.57,52.32 127.11,52.32 126.86,52.06 126.86,49.4 v2(127.42,48.84)
  BOTTOM w0.076: CPU1.BU35 128.75,66.75 128.84,66.49 128.84,66.49 128.91,66.31 128.91,66.08 128.88,65.99 128.88,65.75 128.94,65.58
  BOTTOM w0.102: Q1702.3 135.2,50.35 135.68,49.88 135.68,48.96 EC1707.1 136.64,47.87 136.28,47.52 134.13,47.52 133.72,47.92 131.81,47.92 v1(131.69,47.8) 131.2,47.31 128.94,47.31 v2(127.42,48.84) 127.09,49.17 D1701.A ; 128.94,65.58 129.11,65.4 129.11,64.96 129.33,64.75 129.33,63.11 128.89,62.68 128.89,62.09 128.49,61.69 RN1704.4 128.13,61.49 127.88,61.24 127.2,61.24 127.04,61.09 127.04,60.1 127.23,59.91 129.27,59.91 129.45,59.73 129.45,59 129.07,58.62 129.07,57.9 128.91,57.75 v2(128.86,57.75)
ACOK#: length 9.6
  TOP w0.127: PR4427.2 20.97,48.25 20.23,47.52 v1(20.23,46.95) 20.23,46.69 20.8,46.12 v2(21.25,46.12)
  BOTTOM w0.127: 23.15,43.45 23.58,43.45 23.8,43.67 PQ4415.3 ; 23.15,43.45 PQ4415.2 ; 23.15,43.45 21.98,43.45 21.86,43.58 21.86,43.61 21.5,43.97 21.5,44.34 21.25,44.6 v2(21.25,46.12)
AD_IA: length 31.3
  TOP w0.102: PR2455.1 28.49,24.28 28.52,24.3 v2(28.61,24.3) ; PR4412.2 29.66,38.6 v1(29.26,38.2) 29.05,37.99 v2(28.64,37.99)
  L4SGND w0.102: v2(28.61,24.3) 28.61,27.08 29.75,28.21 29.75,31.5 31.26,33 31.26,34.73 31.02,34.97 29.67,34.97 28.56,36.07 28.56,37.91 v2(28.64,37.99)
  L6 w0.102: v2(28.61,24.3) 27.04,24.3 26.51,23.77 24.42,23.77 23.43,22.78 21.53,22.78 21.12,22.37 v2(19.98,22.37)
  BOTTOM w0.102: R2421.1 20.44,20.87 R2423.1 19.98,21.63 v2(19.98,22.37)
AD_OFF_L: length 2.3
  TOP w0.254: Q4304.C 45.63,84.46 Q4305.1 v1(46.6,84.45)
AD_OFF_R: length 8.5
  TOP w0.254: v2(44.36,81.55) 44.36,82.09 Q4305.3
  BOTTOM w0.254: PU4301.4 44.17,83.5 R4307.2 C4301.2 45.78,83.2 R4308.1 46.85,82.85 v1(45.99,81.98) 45.56,81.55 v2(44.36,81.55)
ALERT#: length 2.3
  BOTTOM w0.102: U2601.6 42.4,30.35 R2603.2 v1(41.57,30.29)
ALWON: length 104.8
  TOP w0.127: R4009.2 95.29,10.08 v1(94.14,8.93) v2(93.18,7.97)
  L4SGND w0.127: v2(22.77,25.16) 22.94,25 22.94,21.15 22.55,20.77 21.2,20.77 19.77,19.35 19.77,18.63 19.65,18.51 19.65,14.46 19.26,14.07 19.26,12.89 21.92,10.23 28.61,10.23 34.82,4.02 53.67,4.02 55.7,6.05 64.16,6.05 67.34,2.88 67.82,2.88 67.98,2.71 91.05,2.71 91.1,2.76 v2(92.22,2.76)
  BOTTOM w0.127: U2401.121 22.79,25.19 v2(22.77,25.16) ; v2(93.18,7.97) 93.38,7.77 93.38,4 92.61,3.22 92.61,3.15 v2(92.22,2.76)
AMBER_LED_BAT: length 97.7
  TOP w0.254: v2(20.94,101.06) 20.89,101.11 R6401.2 ; v2(7.02,18.43) v1(7.36,18.88)
  L4SGND w0.254: v2(20.94,101.06) 20.94,100.55 20.74,100.35 19.95,100.35 15.18,95.58 15.18,95.26 15.18,92.98 14.39,92.19 14.39,83.71 13.55,82.87 v2(13.55,81.93)
  L6 w0.254: v2(13.55,81.93) 13.55,80.36 16.22,77.69 16.22,74.92 14.87,73.58 13.68,73.58 10.71,70.6 10.71,65.07 9.41,63.77 7.07,63.77 3.98,60.67 3.98,22.62 7.02,19.58 v2(7.02,18.43)
  BOTTOM w0.254: v2(7.02,18.43) Q6402.C
AUD_AGND: length 25.8
  TOP w0.508: v1(176.01,40.11) 175.18,39.29 v2(175.17,39.29) ; 179.36,14.17 179.95,14.17 v2(180.25,13.86) 180.25,13.43 R2739.1 ; C2909.2 179.24,31.64 178.55,30.96 v2(178.55,30.93) ; EC2711.1 182.97,23.65 v2(182.96,23.64) ; EC2714.1 v2(182.84,15.72) ; C2730.2 177.86,25.39 v2(177.33,25.93) ; EC2713.1 177.86,16.32 178.17,16.02 v2(178.6,16.02)
  BOTTOM w0.203: U2701.22 177.08,22.82 177.43,23.17 v2(177.43,23.4) ; U2701.37 178.26,16.36 v2(178.6,16.02)
  BOTTOM w0.305: v2(175.17,39.29) 175.05,39.41 CN6601.11 ; CN6601.1 180.05,39.74 v2(180.3,39.49)
  BOTTOM w0.508: v2(182.82,25.65) 182.97,25.49 EC2711.1 ; v2(180.25,13.86) 180.11,13.86 180,13.76 179.9,13.76 179.67,13.53 C2731.1 179.46,13.56 R2747.1 177.86,13.56 C2721.2 ; C2740.1 177.23,24.99 177.28,25.04 C2734.1 177.33,25.16 v2(177.33,25.93) ; EC2711.1 182.97,23.65 v2(182.96,23.64) ; EC2711.1 182.69,24.78 C2741.2 ; EC2710.1 182.79,19.3 v2(182.68,19.18) 182.18,18.69 182.18,18.41 C2735.2 ; v2(182.84,15.72) EC2714.1 181.98,14.88 181.88,14.78 C2737.1 181.85,14.75 181.93,14.67 v2(181.93,13.89)
AUD_HP1_JACK_L1: length 24
  TOP w0.254: v1(177.38,40) 177.38,39.24 v2(177.18,39.03) 177.18,38.53 176.95,38.3 R2922.2
  L6 w0.254: v2(182.79,21.86) 182.69,21.96 182.52,21.96 181.65,22.83 181.65,28.18 180.94,28.89 180.56,29.27 180.56,32.03 179.9,32.69 179.9,34.92 177.74,37.08 177.74,38.52 177.22,39.03 v2(177.18,39.03)
  BOTTOM w0.254: CN6601.7 177.05,39.2 177.18,39.08 v2(177.18,39.03) ; R2907.1 v2(182.79,21.86)
AUD_HP1_JACK_R1: length 23.2
  TOP w0.254: v1(179.87,38.26) 179.4,37.79 R2921.2 178.96,37.81 178.96,38.85 178.93,38.88 178.93,38.96 v2(178.86,39.04)
  L6 w0.254: v2(182.84,22.62) 182.79,22.62 182.31,23.11 182.31,27.91 182.31,28.46 181.22,29.55 181.22,32.3 180.56,32.96 180.56,35.19 178.4,37.35 178.4,38.4 178.78,38.78 178.78,38.93 178.86,39.01 v2(178.86,39.04)
  BOTTOM w0.254: R2909.1 v2(182.84,22.62) ; v2(178.86,39.04) 178.05,39.84 CN6601.5
AUD_HPJD_N: length 31.3
  TOP w0.254: R2923.2 177.97,34.87 v2(177.99,34.84) v1(177.99,33.72) 177.92,33.65 C2909.1
  L6 w0.254: v2(177.99,34.84) 177.96,34.84 176.57,33.45 176.57,31.92 178.52,29.96 178.52,17.39 177.66,16.53 173.28,16.53 172.42,15.66 v2(172.2,15.66)
  BOTTOM w0.254: R2741.2 171.9,15.31 172.2,15.61 v2(172.2,15.66)
AUD_HPOUT_L: length 3.2
  BOTTOM w0.203: 179.76,21.32 179.16,20.72 U2701.27
  BOTTOM w0.254: R2907.2 181.19,21.91 v1(180.25,21.91) 179.76,21.42 179.76,21.32
AUD_HPOUT_R: length 4
  BOTTOM w0.203: U2701.26 178.99,21.12 179.21,21.35
  BOTTOM w0.254: 179.21,21.35 179.21,21.89 v1(180.46,23.13) 180.81,23.13 R2909.2
AUD_PC_BEEP_C: length 4.6
  BOTTOM w0.254: v1(181.8,15.99) 181.75,15.99 181.55,15.79 C2726.1 181.19,15.61 181.19,13.45 R2745.1 181.16,13.01 D2702.3
AUD_PC_BEEP_R: length 3
  BOTTOM w0.203: C2726.2 v1(180.1,16.68) 180.1,16.85 179.03,17.92 U2701.34
AUD_RING: length 23.3
  TOP w0.508: v3(179.97,19.68) 179.97,20.24
  TOP w1.016: 179.97,20.24 179.97,26.81 v1(177.62,29.16) 175.55,31.23 175.55,35.2
  L3SGND w0.508: v3(179.97,19.68) 182.18,19.68 182.82,20.31 v2(182.82,21)
  BOTTOM w0.203: v3(179.97,19.68) 179.82,19.52 U2701.30
  BOTTOM w0.305: RN2901.3 182.76,21.05 v2(182.82,21)
AUD_SELEEVE: length 22.5
  TOP w0.635: 180.81,18.81 180.13,18.81 180.08,18.77 180,18.77 v3(179.98,18.78)
  TOP w1.016: 181.17,35.22 181.17,31.18 181.5,30.85 v1(181.5,26.56) 181.5,19.5 180.81,18.81
  BOTTOM w0.203: U2701.31 179.32,19.12 179.66,18.78 v3(179.98,18.78)
  BOTTOM w0.305: RN2901.4 182.04,19.43 181.65,19.04 180.75,19.04 180.47,18.77 180,18.77 v3(179.98,18.78)
AUD_SENSE_A: length 5
  BOTTOM w0.203: U2701.48 173.48,16.16 173.2,15.88
  BOTTOM w0.254: 173.2,15.88 173.18,15.88 172.25,14.95 R2742.2 172.23,14.45 R2741.1 171.39,14.55 C2746.1 170.73,13.81 v1(170.88,13.66)
AUD_SPK_L+: length 171
  L6 w0.635: v3(176.75,14.09) 176.82,14.01 176.82,11.32 176.75,11.25
  L6 w1.016: v3(19.75,4.82) 22.61,4.82 23.17,5.38 25.64,7.85 28.49,7.85 32.13,4.21 35.73,4.21 37.53,2.41 65.59,2.41 65.72,2.53 70.17,2.53 70.32,2.38 73.53,2.38 74.24,1.67 121.2,1.67 121.76,2.23 126.2,2.23 126.61,1.82 157.62,1.82 160.62,4.82 170.52,4.82 176.75,11.05 176.75,11.25
  BOTTOM w0.203: U2701.42 175.88,14.73 176.52,14.09 v3(176.75,14.09)
  vias: v1(19.47,5.73)
AUD_SPK_L+_C: length 1.5
  BOTTOM w0.406: v3(17.18,10.94) 17.11,10.94 16.7,11.35 SPK1.1
AUD_SPK_L-: length 171.2
  L6 w0.635: v3(175.68,13.3) 175.68,12.34 175.2,11.85 175.2,11.65
  L6 w1.016: 175.2,11.65 169.89,6.34 159.99,6.34 157.4,3.75 99.19,3.75 99.04,3.6 93.32,3.6 93.3,3.62 92.81,3.62 92.61,3.83 90.61,3.83 75.94,3.81 74.25,3.81 74.16,3.9 70.96,3.9 70.8,4.06 65.09,4.06 64.96,3.93 38.55,3.93 36.74,5.73 32.76,5.73 29.12,9.37 25.01,9.37 24.32,8.69 21.98,6.34 19.12,6.34 v3(16.96,4.18)
  BOTTOM w0.203: v3(175.68,13.3) 175.68,13.91 175.48,14.11 U2701.43
  vias: v1(17.58,3.95)
AUD_SPK_L-_C: length 1.5
  BOTTOM w0.406: v3(15.91,10.81) 15.7,11.03 SPK1.2
AUD_SPK_R+: length 171
  L6 w0.635: 173.19,14.52 v3(174.03,14.52)
  L6 w1.016: v3(14.24,5.77) 14.24,5.78 18.4,9.95 21.27,9.95 24.04,12.72 25.7,12.72 25.82,12.85 30,12.85 33.6,9.24 38.95,9.24 41.19,7 62.55,7 62.78,7.23 71.32,7.23 71.43,7.13 72.04,7.13 72.07,7.1 72.22,6.95 75.42,6.95 75.45,6.93 122.31,6.93 123.08,7.69 130.14,7.69 130.19,7.74 134.05,7.74 134.1,7.69 134.56,7.69 135.29,8.43 136.56,8.43 157.54,8.43 158.51,9.39 168.59,9.39 170.75,11.55 170.75,12.08 173.19,14.52
  BOTTOM w0.203: U2701.45 174.68,15.17 v3(174.03,14.52)
  vias: v1(14.52,4.08)
AUD_SPK_R+_C: length 1.4
  BOTTOM w0.406: SPK1.3 v3(14.7,10.81)
AUD_SPK_R-: length 174.4
  L6 w1.016: v3(12.36,4.31) 12.59,4.08 14.69,4.08 14.86,4.25 14.87,4.25 15.76,5.14 15.76,5.15 19.03,8.43 21.9,8.43 22.8,9.32 24.38,10.9 29.75,10.9 33.39,7.26 37.65,7.26 39.43,5.48 63.48,5.48 63.7,5.71 70.69,5.71 70.79,5.61 71.41,5.61 71.59,5.43 74.79,5.43 74.89,5.33 75.61,5.33 90.61,5.35 90.71,5.35 90.97,5.35 93.83,5.35 93.85,5.38 125.53,5.38 125.55,5.4 125.62,5.4 126.38,6.16 130.77,6.16 130.82,6.22 133.42,6.22 133.47,6.16 135.19,6.16 135.93,6.9 158.18,6.9 158.4,7.13 158.44,7.13 159.18,7.87 169.22,7.87 172.28,10.92 172.28,11.45 173.88,13.05 174.03,13.05 v3(174.54,13.56)
  BOTTOM w0.203: U2701.44 175.08,14.4 174.54,13.86 v3(174.54,13.56)
  vias: v1(11.97,4.85)
AUD_SPK_R-_C: length 1.5
  BOTTOM w0.406: SPK1.4 13.7,11.14 v3(13.37,10.81)
AUD_VREF: length 3.9
  BOTTOM w0.203: U2701.38 177.48,16.01 177.67,15.82 178.11,15.82 178.29,15.64 178.3,15.64 178.48,15.46 v1(179.13,15.46) 179.49,15.46
  BOTTOM w0.254: C2737.2 180.18,14.78 179.49,15.46
AUDIO_47: length 2.3
  BOTTOM w0.203: 173.22,15.33 v1(173.24,15.33) 173.24,15.36 173.88,16 U2701.47
  BOTTOM w0.254: 173.22,15.33 173.01,15.13 R2744.1
AUX_EN_WOWL: length 304.3
  TOP w0.089: 128.27,66.73 128.27,68.08 128.53,68.34 128.53,68.99 128.14,69.37 v2(128.14,69.5)
  TOP w0.102: v2(164.99,28.36) 167.44,30.82 167.44,32.87 169.89,35.32 169.89,42.29 169.99,42.39 169.99,44.36 170.65,45.02 170.65,46.81 171.13,47.29 171.13,47.74 170.45,48.43 170.45,57.27 171.26,58.08 171.26,58.49 v1(171.49,58.71) 172.14,59.36 172.8,59.36 173.14,59.71 173.14,60.72 v2(172.76,61.11) ; 128.27,66.73 127.51,65.97 127.51,59.54 127.94,59.12 127.94,57.33 128.93,56.34 128.93,52.96 128.49,52.52 126.94,52.52 126.58,52.16 126.58,49.1 127.25,48.43 127.75,48.43 127.9,48.58 131.61,48.58 131.76,48.43 141.11,48.43 141.77,47.77 144.29,47.77 144.34,47.82 147.05,47.82 v2(147.11,47.77)
  L4SGND w0.102: v2(152.24,24.02) 152.59,24.38 157.7,24.38 159.55,26.23 162.85,26.23 v2(164.99,28.36)
  L6 w0.102: v2(147.11,47.77) 147.23,47.64 147.23,44.72 153.2,38.75 153.2,28.21 152.24,27.25 v2(152.24,24.02) ; v2(164.99,28.36) 164.99,19.86 155.5,10.37 154.78,10.37 154.45,10.04 150.99,10.04 143.08,17.96 129.36,17.96 125.49,14.09 125.49,13.56 125.49,13.56 125.49,12.29 122.38,9.17 108.02,9.17 107.12,8.27 107.1,8.27 107.05,8.23 106.9,8.23 95.47,8.23 95.43,8.27 95.04,8.27 94.66,8.65 81.65,8.65 80.99,9.31 80.66,9.31 79.67,8.32 74.41,8.32 74.05,8.68 69.75,8.68 69.61,8.54 42.2,8.54 41.16,9.57 40.71,9.57 39.79,10.48 39.54,10.48 39.49,10.53 34.65,10.53 33.23,11.96 32.83,11.96 30.63,14.17 25.24,14.17 25.11,14.04 18.81,14.04 v2(18.71,14.14)
  BOTTOM w0.102: R2409.2 19.47,16.15 18.71,15.39 v2(18.71,14.14) ; CPU1.BT30 127.8,69.84 v2(128.14,69.5) ; v2(172.76,61.11) 173.39,61.11 174.92,62.63 174.92,64.61 R6110.2
AUX_EN_WOWL_R: length 6.1
  TOP w0.102: v2(173.65,68.85) v1(173.52,69.46)
  BOTTOM w0.102: R6110.1 174.54,66.31 173.78,67.07 173.78,68.73 v2(173.65,68.85) 172.9,68.85 Q6102.G
AUX_MODE: length 6.1
  BOTTOM w0.203: R2754.2 179.92,17.49 179.09,18.32 U2701.33
  BOTTOM w0.254: R2754.2 180.68,17.09 181.17,16.6 v1(182.86,16.6) 182.87,16.61 R2728.2
B_ZQ_RAM1: length 2.9
  TOP w0.102: v2(117.19,39.3) 117.03,39.13 R1304.1 v1(115.81,38.25)
  BOTTOM w0.102: RAM5.F9 v2(117.19,39.3)
B_ZQ_RAM2: length 3.1
  BOTTOM w0.102: R1301.1 105.12,38.88 v1(105.75,38.88) 106.57,38.88 106.99,39.3 RAM6.F9
B_ZQ_RAM3: length 2.9
  TOP w0.102: v2(137.49,39.3) 137.33,39.13 R1306.1 v1(135.88,38.25)
  BOTTOM w0.102: RAM7.F9 v2(137.49,39.3)
B_ZQ_RAM4: length 2.9
  TOP w0.102: v2(127.34,39.3) 127.15,39.11 R1305.1 v1(125.97,38.22)
  BOTTOM w0.102: RAM8.F9 v2(127.34,39.3)
BAT1_LED#: length 9.5
  TOP w0.127: v2(25.54,19.31) 25.59,19.26 Q2416.4 ; v2(25.54,19.31) v1(24.96,19.04) ; v2(25.54,19.31) 24.77,20.08 R2498.1 ; v2(29.76,20.34) 29.88,20.46 RN2405.2
  L6 w0.127: v2(25.54,19.31) 25.91,19.68 29.1,19.68 v2(29.76,20.34)
  BOTTOM w0.127: v2(25.54,19.31) 25.42,19.19 U2401.106
BAT2_LED#: length 16.6
  TOP w0.127: R2495.2 27.83,19.88 27.49,20.22 Q2416.1 27.87,20.91 29.03,22.07 v1(29.03,22.72) 29.2,22.89 v2(29.2,23.59) 29.85,22.93 29.94,22.93 30.2,22.67 30.2,21.27 RN2405.1
  BOTTOM w0.127: v2(29.2,23.59) 28.93,23.86 27.86,23.86 26.14,25.58 26.14,26.94 25.34,27.73 25.34,28.81 25.33,28.82 U2401.1
BAT_AMBER: length 18.6
  TOP w0.254: R6401.1 18.57,101.11 ED6401.2 18.51,100.53 17.59,99.61 14.75,99.61 v1(14.34,100.02) 13.12,101.24 4.66,101.24 3.45,102.45 LED1.1
BAT_WHITE: length 16.6
  TOP w0.254: LED1.2 3.98,100.95 4.08,100.86 12.79,100.86 14.47,99.18 v1(15.66,99.18) 18.42,99.18 ED6401.1 18.57,99.33 R6402.1
BATT_WHITE_LED#: length 41
  TOP w0.127: Q2416.6 28.25,19.26 R2495.1 ; R2495.1 28.93,18.57 Q6404.4 ; R2495.1 28.41,18.94 28.39,18.94 v2(27.61,18.16)
  L6 w0.127: v2(42.18,17.34) 39.33,17.34 37.92,18.75 36.2,18.75 36.07,18.62 35.31,18.62 35.19,18.74 32.35,18.74 31.77,18.16 v2(27.61,18.16) 27.25,18.52 25.17,18.52 23.8,19.89 20.89,19.89 20.32,19.32 12.66,19.32 v2(12.33,19.65)
  BOTTOM w0.127: v2(42.18,17.34) 42.99,17.34 Q6403.D v1(43.85,15.44) ; R6422.2 10.58,21.3 12.23,19.65 v2(12.33,19.65)
BATT_WHITE_LED_R#: length 23.9
  TOP w0.127: Q6404.3 30.48,18.3 v2(29.66,19.12)
  L6 w0.127: v2(29.66,19.12) 29.4,18.86 25.26,18.86 25.15,18.98 23.98,20.15 20.78,20.15 20.21,19.58 13.88,19.58 v2(13.29,20.17)
  BOTTOM w0.127: Q6401.B 9.17,22.17 R6422.1 v1(11.09,22.17) 13.02,20.24 13.22,20.24 v2(13.29,20.17)
BEEP: length 158.4
  TOP w0.254: v2(152.24,19.58) v1(152.23,19.02)
  L4SGND w0.254: v2(157.06,9.52) 159.2,7.38 174.54,7.38 175.1,7.94 177.41,7.94 177.48,7.87 177.49,7.87 177.79,7.57 177.79,7.56 v2(177.92,7.43)
  L6 w0.254: v2(40.43,22.88) 40.68,23.13 42.74,23.13 43.9,21.96 54.34,21.96 55.18,22.8 61.08,22.8 63.27,22.8 64.43,21.63 68.8,21.63 69.46,20.97 73.95,20.97 79.31,15.61 88.91,15.61 90.63,17.34 93.03,17.34 93.26,17.57 94.96,17.57 97.14,15.39 99.34,15.39 100.74,16.78 101.27,16.78 106.79,16.78 107.09,17.09 113.21,17.11 114.34,17.11 114.47,16.98 116.1,16.98 116.47,16.98 116.93,17.44 122.14,17.44 122.54,17.84 123.52,18.83 124.23,18.83 125.4,18.83 125.88,19.31 127.55,19.31 128.44,20.2 144.39,20.2 144.78,19.8 152.01,19.8 v2(152.24,19.58)
  BOTTOM w0.203: U2401.45 40.12,23.19 v2(40.43,22.88)
  BOTTOM w0.254: RN2702.1 177.92,8.07 v2(177.92,7.43) ; v2(152.24,19.58) 155.46,16.35 155.46,11.12 v2(157.06,9.52)
BKLT_CTRL: length 33.4
  TOP w0.127: RN5502.5 99.1,99.99 99.1,101.24 99.4,101.54 R5545.2 ; R5545.2 99.61,102.18 v2(99.28,102.51) ; R5545.2 100.47,100.68 R5502.1
  BOTTOM w0.127: D5502.3 74.5,99.59 78.5,99.59 78.84,99.93 79.92,99.93 79.94,99.92 v1(81.17,99.92) 81.32,99.92 81.73,100.32 81.73,100.44 81.73,100.44 81.73,101.01 81.75,101.03 81.75,102.36 82.54,103.15 98.63,103.15 v2(99.28,102.51)
BKLT_IN_EC: length 5.1
  BOTTOM w0.102: U2401.67 36.94,13.41 37.22,13.13 37.32,13.13 37.33,13.12 v1(39.54,13.12) 40.15,13.12 R2440.1
BLON_OUT_C: length 6.8
  TOP w0.102: v2(97.58,97.81) 97.79,97.59 99.06,97.59 99.23,97.76 v1(99.24,97.76) 99.25,97.76 99.25,97.85 99.37,97.96 99.37,99.16 99.17,99.36 98.46,99.36 98.33,99.49 RN5502.6 98.33,100.8 R5544.1
  BOTTOM w0.102: LCD1.23 97.15,97.38 v2(97.58,97.81)
BLUETOOTH_EN: length 69.8
  TOP w0.102: D6101.K 168.85,52.82 R6107.2 169.08,53.05 169.08,56.28 AFTP6112.1 168.26,57.09 v2(167.83,57.09) ; R2109.2 155.08,83.38 v2(155.56,82.9)
  L3SGND w0.102: v2(155.56,82.9) 156,83.33 156.5,83.33 159.04,80.79 159.04,76.85 158.18,75.99 158.18,75.84 159.04,74.97 159.04,73.53 159.09,73.48 159.09,68.22 157.71,66.83 157.71,62.69 155.84,60.83 155.84,60.57 154.98,59.71 v2(154.98,59.45)
  L4SGND w0.102: v2(154.98,59.45) 155.03,59.5 156.05,59.5 157.04,58.51 160.77,58.51 162.23,59.97 163.6,59.97 166.03,57.55 167.37,57.55 v2(167.83,57.09)
  BOTTOM w0.076: CPU1.CP14 138.63,80.03 138.82,80.22 arc(138.89,80.27) 138.97,80.29 139.2,80.29 139.35,80.13 141.98,80.13 142.46,80.61
  BOTTOM w0.102: v2(155.56,82.9) 154.85,83.61 149.73,83.61 146.73,80.61 142.46,80.61
BLUETOOTH_EN_R: length 8.1
  TOP w0.102: v2(167.15,49.57) 166.87,49.85 R6106.2 166.83,50.22 166.83,52.51 v1(167.04,52.72) 167.17,52.85 R6107.1 168.01,52.19 D6101.A
  BOTTOM w0.102: v2(167.15,49.57) 167.15,49.6 166.44,50.3 WLAN1.54
BPM_CPU_N0: length 5
  BOTTOM w0.089: CPU1.U1 103.76,88.27 103.76,88.99 101.59,91.15 TP307.1
BPM_CPU_N1: length 8.4
  BOTTOM w0.076: CPU1.U2 104.01,87.83 104.02,87.85 104.11,88.05 104.11,88.33 104.1,88.37 104.05,88.42 104.05,88.44
  BOTTOM w0.089: 104.05,88.44 104.05,88.45 103.99,88.51 103.99,89.02 101.33,91.69 99.12,91.69 TP308.1
BPM_CPU_N2: length 8
  BOTTOM w0.076: CPU1.U3 104.1,87.35 104.14,87.39 104.14,87.7 104.16,87.75 104.17,87.78 104.28,88.02 104.28,88.42 104.25,88.49 104.24,88.5
  BOTTOM w0.089: TP302.1 100.19,91.89 101.4,91.89 104.18,89.11 104.18,88.58 104.23,88.52 104.23,88.51 104.24,88.5
BPM_CPU_N3: length 8.3
  BOTTOM w0.089: CPU1.U4 103.86,86.45 103.57,86.74 103.57,88.91 101.65,90.82 99.34,90.82 TP303.1
BT+: length 96.3
  L3SGND w0.508: v2(46.11,38.04) 46.11,27.78 47.16,26.74 76.06,26.74 76.54,27.22 79.76,27.22 80.83,26.15 87.57,26.15 87.92,25.8 102.27,25.8 103.93,24.15 106.21,24.15 v2(108.12,22.24)
  L6 w0.508: v2(35.09,40.02) 35.09,39.9 35.73,39.26 45.59,39.26 46.11,38.74 v2(46.11,38.04)
  BOTTOM w0.508: v2(108.12,22.24) 107.15,21.28 BATT1.2 ; v2(35.09,40.02) 35.09,40.48 34.68,40.89 33.6,40.89 33.14,41.34 PR4495.2 32.02,42.26 PR4478.2
  vias: v3(105.32,15.51) v3(105.83,14.75) v3(106.34,15.51) v3(106.72,14.5)
BT_PCMFRM_RSTN: length 20.4
  TOP w0.102: v1(149.24,55.09) 148.58,55.75 R6120.1 R1913.1 148.76,56.61 v2(149.47,57.32)
  L4SGND w0.102: v2(149.47,57.32) 149.87,57.73 150.74,57.73 150.89,57.57 155.21,57.57 155.95,58.31 160.95,58.31 162.21,59.57 v2(162.61,59.57)
  BOTTOM w0.102: WLAN1.10 164.34,61.3 v2(162.61,59.57)
BT_PCMOUT_CLKREQ0: length 19.1
  TOP w0.102: v1(150.97,55.69) 150.97,56.51 R1912.1 150.13,56.61 R6119.1 v2(150.08,57.32)
  L4SGND w0.102: v2(163.23,59.5) 163.23,59.4 162.9,59.07 162.22,59.07 161.18,58.04 155.97,58.04 154.96,57.03 150.36,57.03 v2(150.08,57.32)
  BOTTOM w0.102: WLAN1.14 164.13,60.3 163.34,59.5 v2(163.23,59.5)
BT_USB20_CON_N: length 17.8
  TOP w0.102: R6104.1 168.23,68.64 168.23,65.42 ; 168.23,65.42 AFTP6111.1 ; 168.23,65.42 168.23,65.14 167.95,64.86 166.99,64.86 v2(166.69,64.56)
  BOTTOM w0.102: WLAN1.5 158.2,62.55 158.34,62.69 159.37,62.69 160.54,61.51 163.46,61.51 163.87,61.92 163.87,63.27 165.46,64.86 166.38,64.86 v2(166.69,64.56)
BT_USB20_CON_P: length 17.5
  TOP w0.102: 168,67.33 168,68.64 R6105.1 ; 168,67.33 AFTP6114.1 ; 168,67.33 168,65.24 167.85,65.09 166.99,65.09 v2(166.69,65.4)
  BOTTOM w0.102: WLAN1.3 158.27,63.05 158.4,62.91 159.46,62.91 160.64,61.74 163.36,61.74 163.64,62.02 163.64,63.37 165.37,65.09 166.38,65.09 v2(166.69,65.4)
BT_USB20_N: length 64
  TOP w0.102: v2(165.53,83.14) 165.78,82.9 166.35,82.9 166.8,82.45 166.8,78.82 167.91,77.71 167.91,71.77 168.23,71.46 168.23,70.96 ; 168.23,70.96 v1(168.36,70.96) ; 168.23,70.96 168.23,70.03 R6104.2
  L6 w0.089: v2(130.87,93.39) 130.82,93.39 130.43,93 130.43,92.84 130.57,92.7 131.48,92.7 131.94,93.16 131.94,93.64 132.69,94.39 133.94,94.39 135.65,92.68 141.76,92.68 141.99,92.45 143.92,92.45 148.91,92.45 153.13,88.23 153.13,88.23 154.52,86.85 156.53,86.85 157.3,86.07 159.73,86.07 162.88,82.92 165.32,82.92 165.43,83.04 v2(165.53,83.14)
  BOTTOM w0.076: CPU1.CC3 131.92,86.97 131.92,87.19 131.81,87.31 131.76,87.43 131.76,87.62 131.79,87.71 131.79,87.99 131.76,88.08 131.76,88.37 131.29,88.83 131.29,89.64 131.27,89.67 131.27,89.68 131.26,89.69
  BOTTOM w0.102: 131.26,89.69 131.25,89.7 131.25,89.76 130.77,90.24 130.77,90.65 130.7,90.73 130.7,93.21 v2(130.87,93.39)
BT_USB20_P: length 64.5
  TOP w0.102: 167.68,72.36 167.68,77.62 166.57,78.72 166.57,82.36 166.26,82.67 165.72,82.67 v2(165.55,82.51) ; 167.68,72.36 167.68,71.68 168,71.36 168,70.03 R6105.2 ; 167.68,72.36 v1(167.53,72.36)
  L6 w0.089: v2(130.24,93.41) 130.24,92.76 130.49,92.51 131.56,92.51 132.13,93.08 132.13,93.56 132.77,94.2 133.86,94.2 135.57,92.49 141.68,92.49 141.91,92.26 144,92.26 144,92.26 148.83,92.26 153.05,88.04 153.05,88.04 154.44,86.66 156.45,86.66 157.22,85.88 159.65,85.88 162.8,82.73 165.32,82.73 v2(165.55,82.51)
  BOTTOM w0.076: CPU1.CC4 131.74,86.5 131.74,87.05 131.72,87.11 131.67,87.21 131.67,87.22 131.59,87.39 131.59,87.65 131.63,87.74 131.63,87.96 131.59,88.05 131.59,88.3 131.13,88.77 131.13,89.56 131.02,89.66
  BOTTOM w0.102: 131.02,89.66 130.54,90.14 130.54,90.56 130.47,90.64 130.47,93.18 130.24,93.41 v2(130.24,93.41)
CAD_SNK: length 1.4
  TOP w0.127: R7118.2 16.81,71.05 U7101.29
CAP_LED: length 10.7
  TOP w0.254: R6513.2 59.98,7.1 59.14,7.94 AFTP6538.1 59.3,8.81 v2(59.75,9.26)
  BOTTOM w0.254: v2(59.75,9.26) 60.12,9.63 60.12,10.88 59.7,11.3 57.34,11.3 56.9,10.85 KB1.4
CAP_LED#: length 13.4
  TOP w0.127: v2(23.64,15.05) v1(23.2,14.71)
  L6 w0.127: v2(18.2,17.11) 18.76,16.55 20.46,16.55 21.3,15.72 22.22,15.72 22.33,15.6 23.09,15.6 v2(23.64,15.05)
  BOTTOM w0.127: v2(18.2,17.11) 18.2,18.43 Q2414.S 18.63,18.86 R2489.1 ; v2(23.64,15.05) 26.28,15.05 26.54,14.8 U2401.93
CAP_LED#_R: length 3.6
  BOTTOM w0.127: R6512.1 15.91,16.6 Q2414.D 18.3,16.6 v1(18.84,16.07)
CAP_LED_Q: length 60.9
  TOP w0.254: R6513.1 v1(59.98,3.32) 59.98,3.04 58.97,2.02 38.37,2.02 37.89,1.54 v2(37.89,1.42)
  L4SGND w0.254: v2(37.89,1.42) 37.76,1.42 37.62,1.28 25.83,1.28 18.33,8.78 13.12,8.78 11.34,10.56 v2(11.34,16.02)
  BOTTOM w0.254: Q6505.C v2(11.34,16.02)
CAP_LED_R#: length 4.4
  BOTTOM w0.127: R6512.2 14.03,16.91 v1(13.78,16.91) 13.78,14.59 Q6505.B
CARD1_USB20_N: length 79.6
  TOP w0.102: AFTP6602.1 161.84,39.13 v2(162.24,39.54)
  L6 w0.089: v2(133.85,83.84) 134.38,83.3 134.38,82.89 134.88,82.39 137.17,82.39 138.25,83.47 141.8,83.47 142.88,82.39 144.49,82.39 144.73,82.15 151.36,82.15 153.75,79.76 157.76,79.76 160.83,76.69 160.83,72.52 162.55,70.81 162.55,67.38 164.66,65.27 164.66,48.48 165.24,47.9 165.24,42.49 165.24,42.33 163.4,40.49 162.25,40.49 161.94,40.19 161.94,39.85 v2(162.24,39.54)
  BOTTOM w0.102: CPU1.CG8 v2(133.85,83.84) ; v2(162.24,39.54) 162.02,39.54 161.86,39.39 161.86,39.16 161.96,39.06 165.22,39.06 165.32,39.16 165.32,39.59 165.25,39.67 165.13,39.67 165.05,39.74 CN6601.31
CARD1_USB20_P: length 79.3
  TOP w0.102: AFTP6601.1 161.84,39.92 v2(161.45,39.54)
  L6 w0.089: v2(133.82,83.2) 133.94,83.32 134.07,83.31 134.19,83.19 134.19,82.81 134.8,82.2 137.25,82.2 138.33,83.28 141.72,83.28 142.8,82.2 144.41,82.2 144.65,81.96 151.28,81.96 153.67,79.57 157.68,79.57 160.64,76.61 160.64,72.44 162.36,70.73 162.36,67.3 164.47,65.19 164.47,48.4 165.05,47.82 165.05,42.41 163.32,40.68 162.17,40.68 161.75,40.26 161.75,39.83 v2(161.45,39.54)
  BOTTOM w0.102: CPU1.CG9 v2(133.82,83.2) ; v2(161.45,39.54) 161.63,39.36 161.63,39.07 161.87,38.83 165.31,38.83 165.55,39.07 CN6601.30
CBN: length 3.5
  BOTTOM w0.203: U2701.24 177.88,22.68 177.98,22.79 178.15,22.79
  BOTTOM w0.254: 178.15,22.79 178.41,22.79 v1(179.26,23.64) 179.79,24.17 C2739.1
CBP: length 2.9
  BOTTOM w0.203: v1(178.1,23.22) 177.95,23.22 177.48,22.75 U2701.23
  BOTTOM w0.254: v1(178.1,23.22) 178.32,23.44 178.32,24.55 C2739.2
CCD_USB20_CON_N: length 16.5
  BOTTOM w0.102: LCD1.44 107.65,96.58 107.55,96.48 107.55,96.28 107.7,96.13 112.05,96.13 112.45,96.53 116.19,96.53 116.34,96.67 ; EL5501.2 117.51,101.47 117.83,101.15 117.83,100.91 118.07,100.66 118.07,100.49 ED5501.6 118.1,99.98 118.1,99.63 117.89,99.42 117.89,99.42 117.58,99.11 117.58,98.52 117.35,98.29 117.35,97.33 117.36,97.31 117.36,97.17 117.28,97.09 116.76,97.09 116.34,96.67 ; 116.34,96.67 v1(116.24,96.77)
CCD_USB20_CON_P: length 17.1
  BOTTOM w0.102: 115.2,96.3 116.29,96.3 116.86,96.86 117.38,96.86 117.59,97.08 117.59,97.27 117.83,97.51 ED5501.1 117.83,99.03 118.12,99.32 118.12,99.32 118.33,99.54 118.33,100.73 118.06,101 118.06,101.17 118.28,101.39 EL5501.3 ; 115.2,96.3 v1(115.2,96.11) ; 115.2,96.3 112.54,96.3 112.15,95.91 107.61,95.91 107.32,96.19 107.32,96.39 107.15,96.56 LCD1.43
CCD_USB20_N: length 71.4
  L4SGND w0.089: v2(140.76,102.38) 140.53,102.6 140.53,102.81 140.33,103.01 139.02,103.01 138.72,102.71 138.72,101.88 139.09,101.52 140.12,101.52 140.34,101.29 140.34,100.14 140.06,99.86 139.94,99.86 138.9,100.9 138.62,100.9 138.3,100.58 138.3,100.3 139.34,99.26 139.34,99.13 139.13,98.93 139,98.93 137.96,99.97 137.68,99.97 137.36,99.65 137.36,98.94 137.19,98.76 136.21,98.76 135.77,98.32 135.77,98.19 135.77,98.06 v2(135.5,97.79)
  BOTTOM w0.076: 131.61,88.98 131.61,88.91 132.02,88.5 CPU1.CC1
  BOTTOM w0.102: v2(135.5,97.79) 135.61,97.67 135.61,97.44 135.16,96.99 ; 135.16,96.99 134.56,96.39 134.38,96.39 133.8,96.97 133.47,96.97 133.13,96.64 133.13,96.3 134.03,95.41 134.03,95.27 133.83,95.07 133.68,95.07 132.79,95.96 132.46,95.96 132.26,95.77 132.13,95.63 132.13,95.24 132.93,94.43 132.93,94.23 131.61,92.9 131.61,88.98 ; 135.16,96.99 v1(135.07,97.09) ; EL5501.1 117.51,102.61 117.8,102.9 117.8,103.81 118.26,104.26 119.15,104.26 119.38,104.02 119.38,101.75 119.48,101.64 119.76,101.64 119.86,101.75 119.86,104.02 120.1,104.26 120.57,104.26 120.8,104.02 120.8,101.75 120.91,101.64 121.19,101.64 121.29,101.75 121.29,104.02 121.52,104.26 122.1,104.26 122.34,104.02 122.34,102.99 122.44,102.89 122.72,102.89 122.82,102.99 122.82,104.02 123.05,104.26 139.42,104.26 139.71,104.26 140.58,103.39 140.58,102.56 v2(140.76,102.38)
CCD_USB20_P: length 70.9
  L4SGND w0.089: v2(136.24,97.79) 135.96,98.06 135.96,98.19 135.96,98.24 136.28,98.57 137.27,98.57 137.55,98.86 137.55,99.57 137.76,99.78 137.89,99.78 138.93,98.74 139.21,98.74 139.53,99.05 139.53,99.34 138.49,100.38 138.49,100.5 138.7,100.71 138.82,100.71 139.86,99.67 140.14,99.67 140.53,100.06 140.53,101.37 140.2,101.71 139.17,101.71 138.91,101.96 138.91,102.63 139.1,102.82 140.25,102.82 140.34,102.73 140.34,102.6 v2(140.12,102.38)
  BOTTOM w0.076: 131.84,88.98 131.84,88.93 132.2,88.57 132.2,88.4 132.28,88.32 132.28,88.03 132.28,88.02 132.26,87.94 CPU1.CC2
  BOTTOM w0.102: 134.25,95.32 134.25,95.18 133.92,94.84 133.59,94.84 132.7,95.73 132.55,95.73 132.36,95.54 132.36,95.34 133.03,94.66 133.16,94.53 133.16,94.13 131.84,92.81 131.84,88.98 ; 134.25,95.32 134.25,95.51 133.36,96.4 133.36,96.54 133.56,96.74 133.7,96.74 134.28,96.16 134.66,96.16 136.24,97.74 v2(136.24,97.79) ; 134.25,95.32 v1(134.41,95.32) ; EL5501.4 118.28,102.61 118.03,102.85 118.03,103.71 118.35,104.03 119.05,104.03 119.15,103.93 119.15,101.65 119.39,101.41 119.86,101.41 120.09,101.65 120.09,103.93 120.19,104.03 120.47,104.03 120.58,103.93 120.58,101.65 120.81,101.41 121.28,101.41 121.52,101.65 121.52,103.93 121.62,104.03 122,104.03 122.11,103.93 122.11,102.89 122.34,102.66 122.81,102.66 123.05,102.89 123.05,103.93 123.15,104.03 139.61,104.03 140.35,103.29 140.35,102.61 v2(140.12,102.38)
CFG3: length 10.6
  BOTTOM w0.102: R1517.1 96.23,92.3 TP621.1 97.37,90.11 101.41,90.11 102.48,89.04 102.48,88.37 102.47,88.35 102.47,87.35 102.73,87.09 CPU1.R3
CFG4: length 11.2
  BOTTOM w0.102: CPU1.J4 98.71,86.49 98.71,88.32 97.88,89.15 96.92,89.15 96.7,89.38 92.29,89.38 91.96,89.05 91.35,89.05 v1(91.23,89.17) 91.15,89.25 R1518.1
CFG_RCOMP: length 2.2
  TOP w0.508: v2(107.02,85.16) v1(107.48,85.62) 107.43,85.67 107.43,86.2 107.56,86.33 R601.1
  BOTTOM w0.254: CPU1.AB5 106.65,85.48 106.97,85.16 v2(107.02,85.16)
CHG_AMBER_LED#: length 35.6
  TOP w0.127: Q2416.3 25.76,20.91 25.44,20.59 24.37,20.59 R2498.2 23.86,19.17 24,19.03 24,16.73 22.91,15.64 21.22,15.64 v2(20.64,15.05) 21.35,14.34 v1(21.35,14.32) 23.61,14.32 24.3,15 24.3,16.24 24.51,16.45 24.51,16.94 24.92,17.35 26.75,17.35 26.78,17.38 27.83,17.38 28.26,16.96 28.26,16.74 28.37,16.63 29.59,16.63 29.96,17 Q6404.1
  L6 w0.127: v2(10.07,17.29) 10.58,16.78 13.5,16.78 14.26,16.02 19.98,16.02 20.64,15.36 v2(20.64,15.05)
  BOTTOM w0.127: R6421.1 v2(10.07,17.29)
CHG_AMBER_LED_R#: length 24.6
  TOP w0.127: v2(22.77,15.1) 22.87,15.1 23.74,15.97 v1(23.89,15.97) 23.89,16.19 24.26,16.56 24.26,17.05 24.82,17.61 26.65,17.61 26.67,17.64 27.94,17.64 28.58,17 Q6404.6
  L6 w0.127: v2(22.77,15.1) 22.47,15.1 22.11,15.46 21.17,15.46 20.35,16.27 14.77,16.27 13.75,17.29 10.96,17.29 10.34,17.91 v2(9.06,17.91)
  BOTTOM w0.127: v2(9.06,17.91) Q6402.B 9.3,18.86 R6421.2
CHGR_PSYS_IMVP: length 57.4
  TOP w0.203: v1(29.28,43.93) 29.18,43.93 28.58,44.53 PU4401.30
  TOP w0.254: PR4413.1 29.76,41.98 29.76,43.15 v2(29.66,43.25) 29.28,43.63 v1(29.28,43.93)
  L4SGND w0.254: v2(52.3,76.69) 52.1,76.69 50.76,75.35 50.76,72.56 47.71,69.51 44.36,69.51 40.37,65.52 39.43,65.52 38.62,64.71 38.62,63.29 34.26,58.92 34.25,58.92 34.18,58.84 33.81,58.84 32.58,58.84 29.73,56 29.73,51.83 26.3,48.41 26.3,46.3 29.35,43.25 v2(29.66,43.25)
  BOTTOM w0.203: PU4601.1 50.56,75.09
  BOTTOM w0.254: 50.56,75.09 v1(51.61,76.14) 51.75,76.14 v2(52.3,76.69) 53.09,77.48 PR4614.1
CLK_PCIE_PEG_REQ#: length 19.1
  TOP w0.102: v2(134.43,68.87) 134.74,68.57 v1(134.74,68.34) 134.74,66.95 135.8,65.88 136.59,65.88 137.15,65.32 137.15,64.57 141.35,60.37 141.36,60.37 141.49,60.24 141.49,59.66 142.13,59.02 142.13,58.34 141.97,58.18 141.97,56.96 142.51,56.43 143.07,56.43 143.3,56.2 143.3,55.57 143.5,55.36 RN1813.6
  BOTTOM w0.102: v2(134.43,68.87) 134.1,68.54 CPU1.CF32
CLK_TP_SIO: length 66.1
  TOP w0.089: v1(90.77,11.41) v2(90.21,11.19) 90.01,11.39 89.53,11.39 RN6501.4 89.5,11.35 EC6501.1 89.52,10.54 RN6502.1
  L6 w0.089: v2(90.21,11.19) 89.83,10.81 86.56,10.81 86.07,11.3 85.33,11.3 84.65,11.98 82.48,11.98 81.88,11.38 75.78,11.38 75.3,10.9 74.92,10.9 67.19,10.9 66.63,11.45 66.02,11.45 66,11.48 43.1,11.48 40.38,14.19 36.52,14.19 35.92,14.8 35.92,15.41 35.43,15.89 33.83,15.89 v2(33.57,15.63)
  BOTTOM w0.089: U2401.78 32.53,14.92 32.45,15.01 32.45,15.54 32.81,15.89 33.31,15.89 v2(33.57,15.63)
CLKIN_XTAL_LCP: length 19
  TOP w0.089: v2(139.18,88.59) 140.73,88.59 143.5,85.82 151.4,85.82 151.63,86.05 R1804.1 v1(152.44,86.94)
  BOTTOM w0.089: v2(139.18,88.59) 139.49,88.28 139.49,87.73 139.12,87.36 138.91,87.36 138.74,87.19 CPU1.CM3
CLKRUN#: length 15.6
  TOP w0.102: R1818.1 v1(133.08,56.69) 133.08,62.7 130.72,65.06 130.72,68.18 131.2,68.66 131.2,69.13 v2(130.81,69.53)
  BOTTOM w0.102: CPU1.BY30 130.5,69.84 v2(130.81,69.53)
CMP_VIN0: length 4.6
  TOP w0.089: R2425.2 31.74,28.16 31.28,27.7 v2(31.28,27.42) v1(30.75,27.65)
  BOTTOM w0.089: v2(31.28,27.42) 31.64,27.42 32.93,28.72 U2401.20
CMP_VIN0_R: length 222.3
  TOP w0.089: R2494.1 26,22.52 R2608.2 25.69,22.84 26.21,23.35 26.21,24.39 26.64,24.81 26.81,24.81 27.84,25.85 v1(27.84,26.38) 28.35,26.89 C2613.1 29,27.02 30.52,27.02 v2(30.6,27.09) 30.69,27 31.46,27 31.76,27.3 R2425.1
  L4SGND w0.089: v2(102.4,18.94) 102.63,18.71 114.11,18.71 114.11,18.72 118.1,18.72 118.1,18.71 123.59,18.71 124.3,19.43 124.45,19.78 124.6,19.93 124.63,20 124.71,20.04 124.91,20.24 125.39,20.24 125.39,20.24 125.85,20.24 126.14,19.96 137.33,19.96 143.56,26.19 153.06,26.19 153.28,26.41 156.61,26.41 160.06,29.86 163.56,29.86 166.87,33.17 167.88,33.17 173.6,38.89 173.6,39.97 173.6,40.31 173.6,40.97 174.84,42.2 182.4,42.2 182.41,42.21 182.43,42.21 183.37,43.15 183.37,43.94 180.09,47.22 180.09,54.88 176.25,58.72 173.36,58.72 172.76,59.33 172,59.33 171.11,60.22 171.11,60.98 170.81,61.27 165.3,61.27 164.5,62.08 163.28,62.08 162.52,62.08 162.42,62.17 v2(162.42,62.48)
  L6 w0.089: v2(30.6,27.09) 30.75,26.94 33.02,26.94 33.16,26.8 33.66,26.8 34.48,25.98 35.09,25.98 35.14,25.93 35.81,25.93 35.85,25.98 36.06,25.98 36.31,26.22 36.66,26.22 36.91,25.98 36.91,25.93 37.27,25.57 43.18,25.57 44.27,24.48 57.02,24.48 57.29,24.75 66.65,24.75 66.88,24.75 66.9,24.73 72.6,24.73 72.77,24.89 73.24,24.89 73.63,25.28 76.06,25.28 76.99,24.36 82.22,24.36 83.07,25.2 87.36,25.2 88.06,24.5 94.46,24.5 100.02,18.94 v2(102.4,18.94)
  BOTTOM w0.089: R2609.2 164.4,67.1 C2612.1 164.05,67.35 R2610.1 163.13,67.35 162.68,66.9 162.68,66.08 161.47,64.88 161.47,63.63 162.09,63.01 162.09,62.81 v2(162.42,62.48)
CMP_VOUT0: length 6.5
  BOTTOM w0.089: R2615.2 R2602.2 26.53,11.32 R2607.2 27.42,12.53 v1(27.78,12.9) 27.81,12.92 29.17,12.92 29.74,13.48 U2401.85
CNV_BRI_DT: length 49.6
  TOP w0.089: R6123.1 161.61,52.47 v2(161.25,52.82)
  L6 w0.089: v2(161.25,52.82) 160.97,53.1 160.57,53.1 159.58,54.1 159.58,57.1 158.24,58.44 158.24,60.92 158.24,60.92 158.24,64.22 156.56,65.9 156.13,65.9 153.28,68.75 153.28,70.23 152.61,70.9 152.61,72.98 150.77,74.83 150.77,74.94 148.26,77.46 148.11,77.6 147.86,77.6 142.92,77.6 142.78,77.46 142.35,77.02 141.05,77.02 140.5,76.47 139.61,76.47 139.6,76.46 139.27,76.46 139.26,76.47 136.74,76.47 136.66,76.55 v2(136.61,76.55)
  BOTTOM w0.089: v2(136.61,76.55) 136.51,76.55 135.99,76.04 CPU1.CJ20 ; WLAN1.36 164.31,54.8 163.59,54.08 163.59,53.42 162.99,52.82 v2(161.25,52.82)
CNV_BRI_RSP: length 44.2
  TOP w0.089: R6121.1 159.25,60.34 v2(159.93,60.34)
  L6 w0.089: v2(151.12,76.9) 151.75,76.9 154.93,73.73 155,73.73 155.33,73.4 155.33,71.67 156.95,70.05 156.95,69.42 157.65,68.73 158.13,68.73 158.41,68.45 158.41,65.19 159.06,64.55 159.06,61.22 v2(159.93,60.34)
  BOTTOM w0.089: v2(159.93,60.34) 160.57,60.34 161.84,59.07 163.55,59.07 164.19,58.44 164.25,58.44 164.38,58.3 WLAN1.22 ; v2(151.12,76.9) 150.69,76.47 149.04,76.47 148.65,76.85 147.8,76.85 147.69,76.97 147.69,77.51 147.47,77.74 141.82,77.74 140.3,76.22 139.46,76.22 139.19,75.95 137.03,75.95 136.94,76.04 CPU1.CK20
CNV_RGI_DT: length 53.7
  TOP w0.089: R1515.2 161.91,54.45 R1516.1 160.85,54.78 160.67,54.6 160.67,54.15 v2(160.82,54)
  L6 w0.089: v2(134.74,76.55) 135.78,77.59 137.05,77.59 137.58,78.12 142.28,78.12 142.79,78.63 147.76,78.63 148.31,78.08 151.25,75.14 151.25,75.03 151.89,74.39 152.84,74.39 153.09,74.13 153.09,73.18 153.09,72.85 154.43,71.51 154.43,71.29 156.02,69.71 156.02,67.24 158.81,64.45 158.81,61.12 158.85,61.08 158.85,58.81 160.06,57.6 160.06,57.3 160.08,57.28 160.08,54.74 160.82,54 v2(160.82,54)
  BOTTOM w0.089: CPU1.CG19 134.74,76.83 v2(134.74,76.55) ; WLAN1.32 164.21,55.8 163.87,55.46 163.87,55.04 163.11,54.28 163.11,53.62 163.01,53.52 161.8,53.52 161.32,54 v2(160.82,54)
CNV_RGI_RSP: length 50.6
  TOP w0.089: v2(161.2,53.49) 161.46,53.23 R6122.1
  L6 w0.089: v2(161.2,53.49) 160.53,53.49 159.84,54.18 159.84,57.18 158.48,58.54 158.48,60.82 158.48,60.82 158.48,64.32 156.66,66.14 156.23,66.14 153.52,68.85 153.52,72.08 152.85,72.75 152.85,73.08 151.01,74.93 151.01,75.04 148.5,77.56 148.21,77.84 147.96,77.84 142.82,77.84 142.67,77.69 142.25,77.27 135.98,77.27 135.39,76.67 v2(135.39,76.55)
  BOTTOM w0.089: v2(135.39,76.55) 135.14,76.8 CPU1.CH19 ; v2(161.2,53.49) 161.41,53.28 163.11,53.28 163.35,53.52 163.35,54.18 164.11,54.94 164.11,55.2 164.21,55.3 WLAN1.34
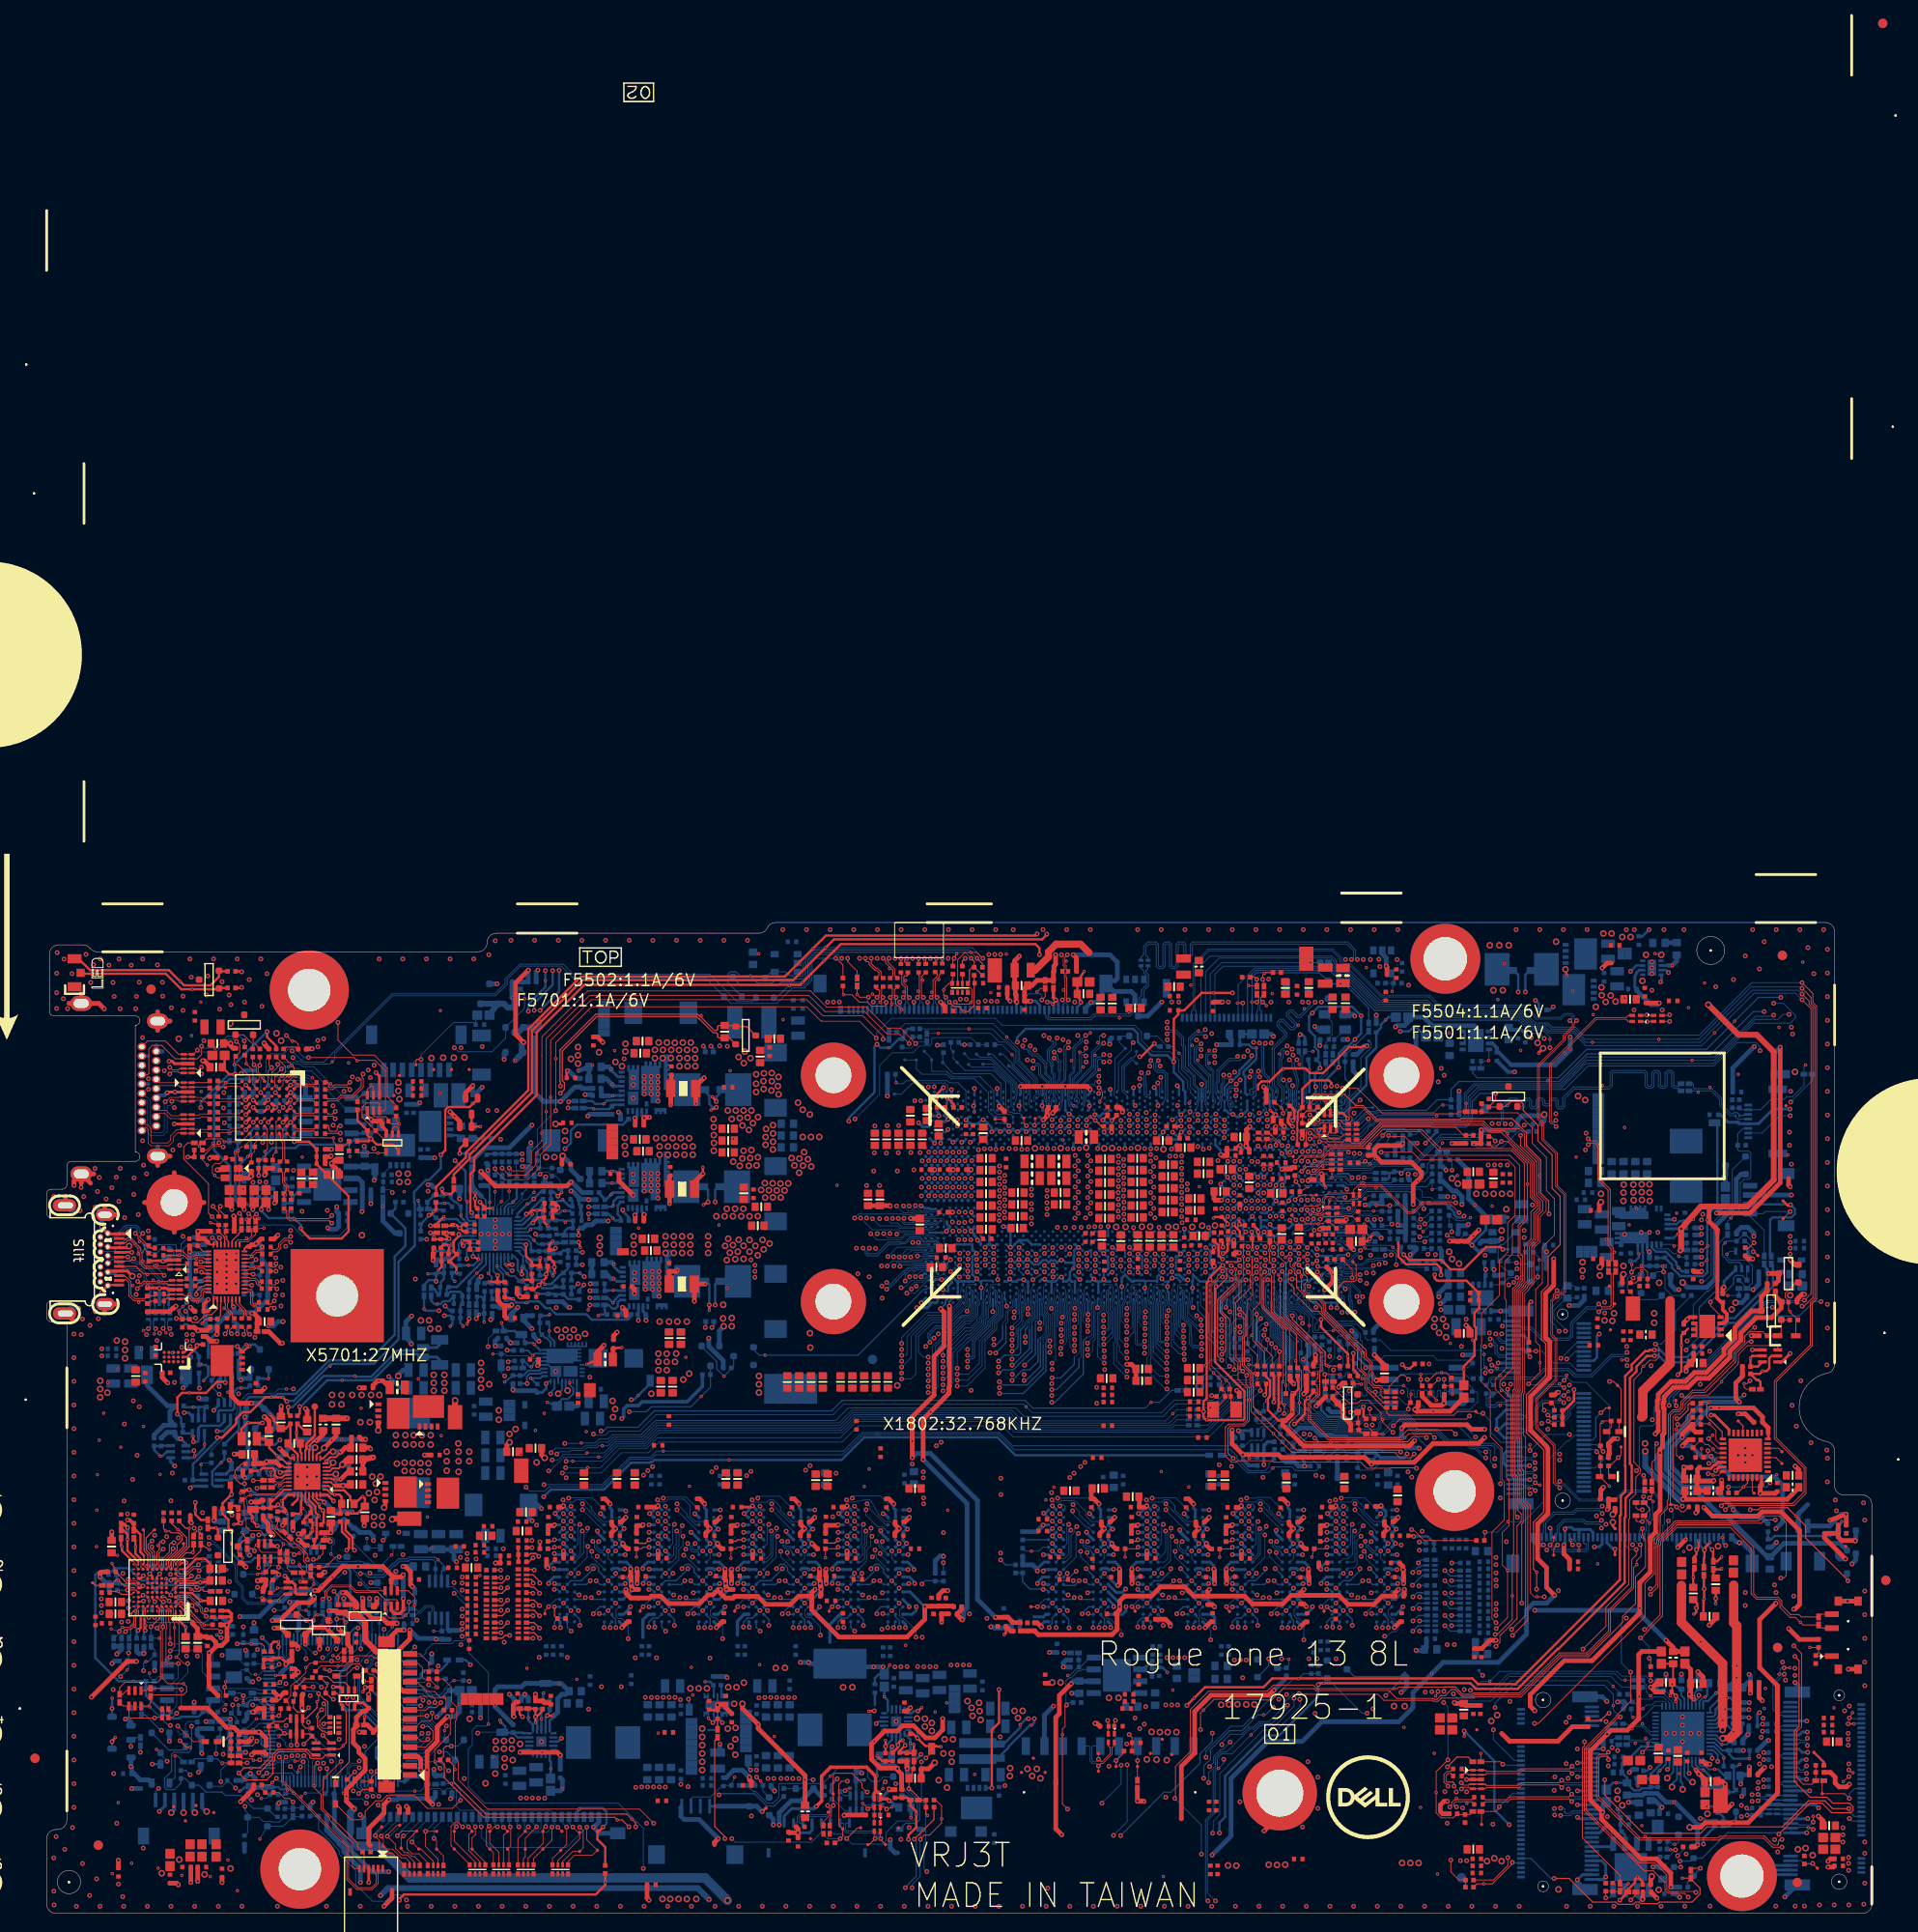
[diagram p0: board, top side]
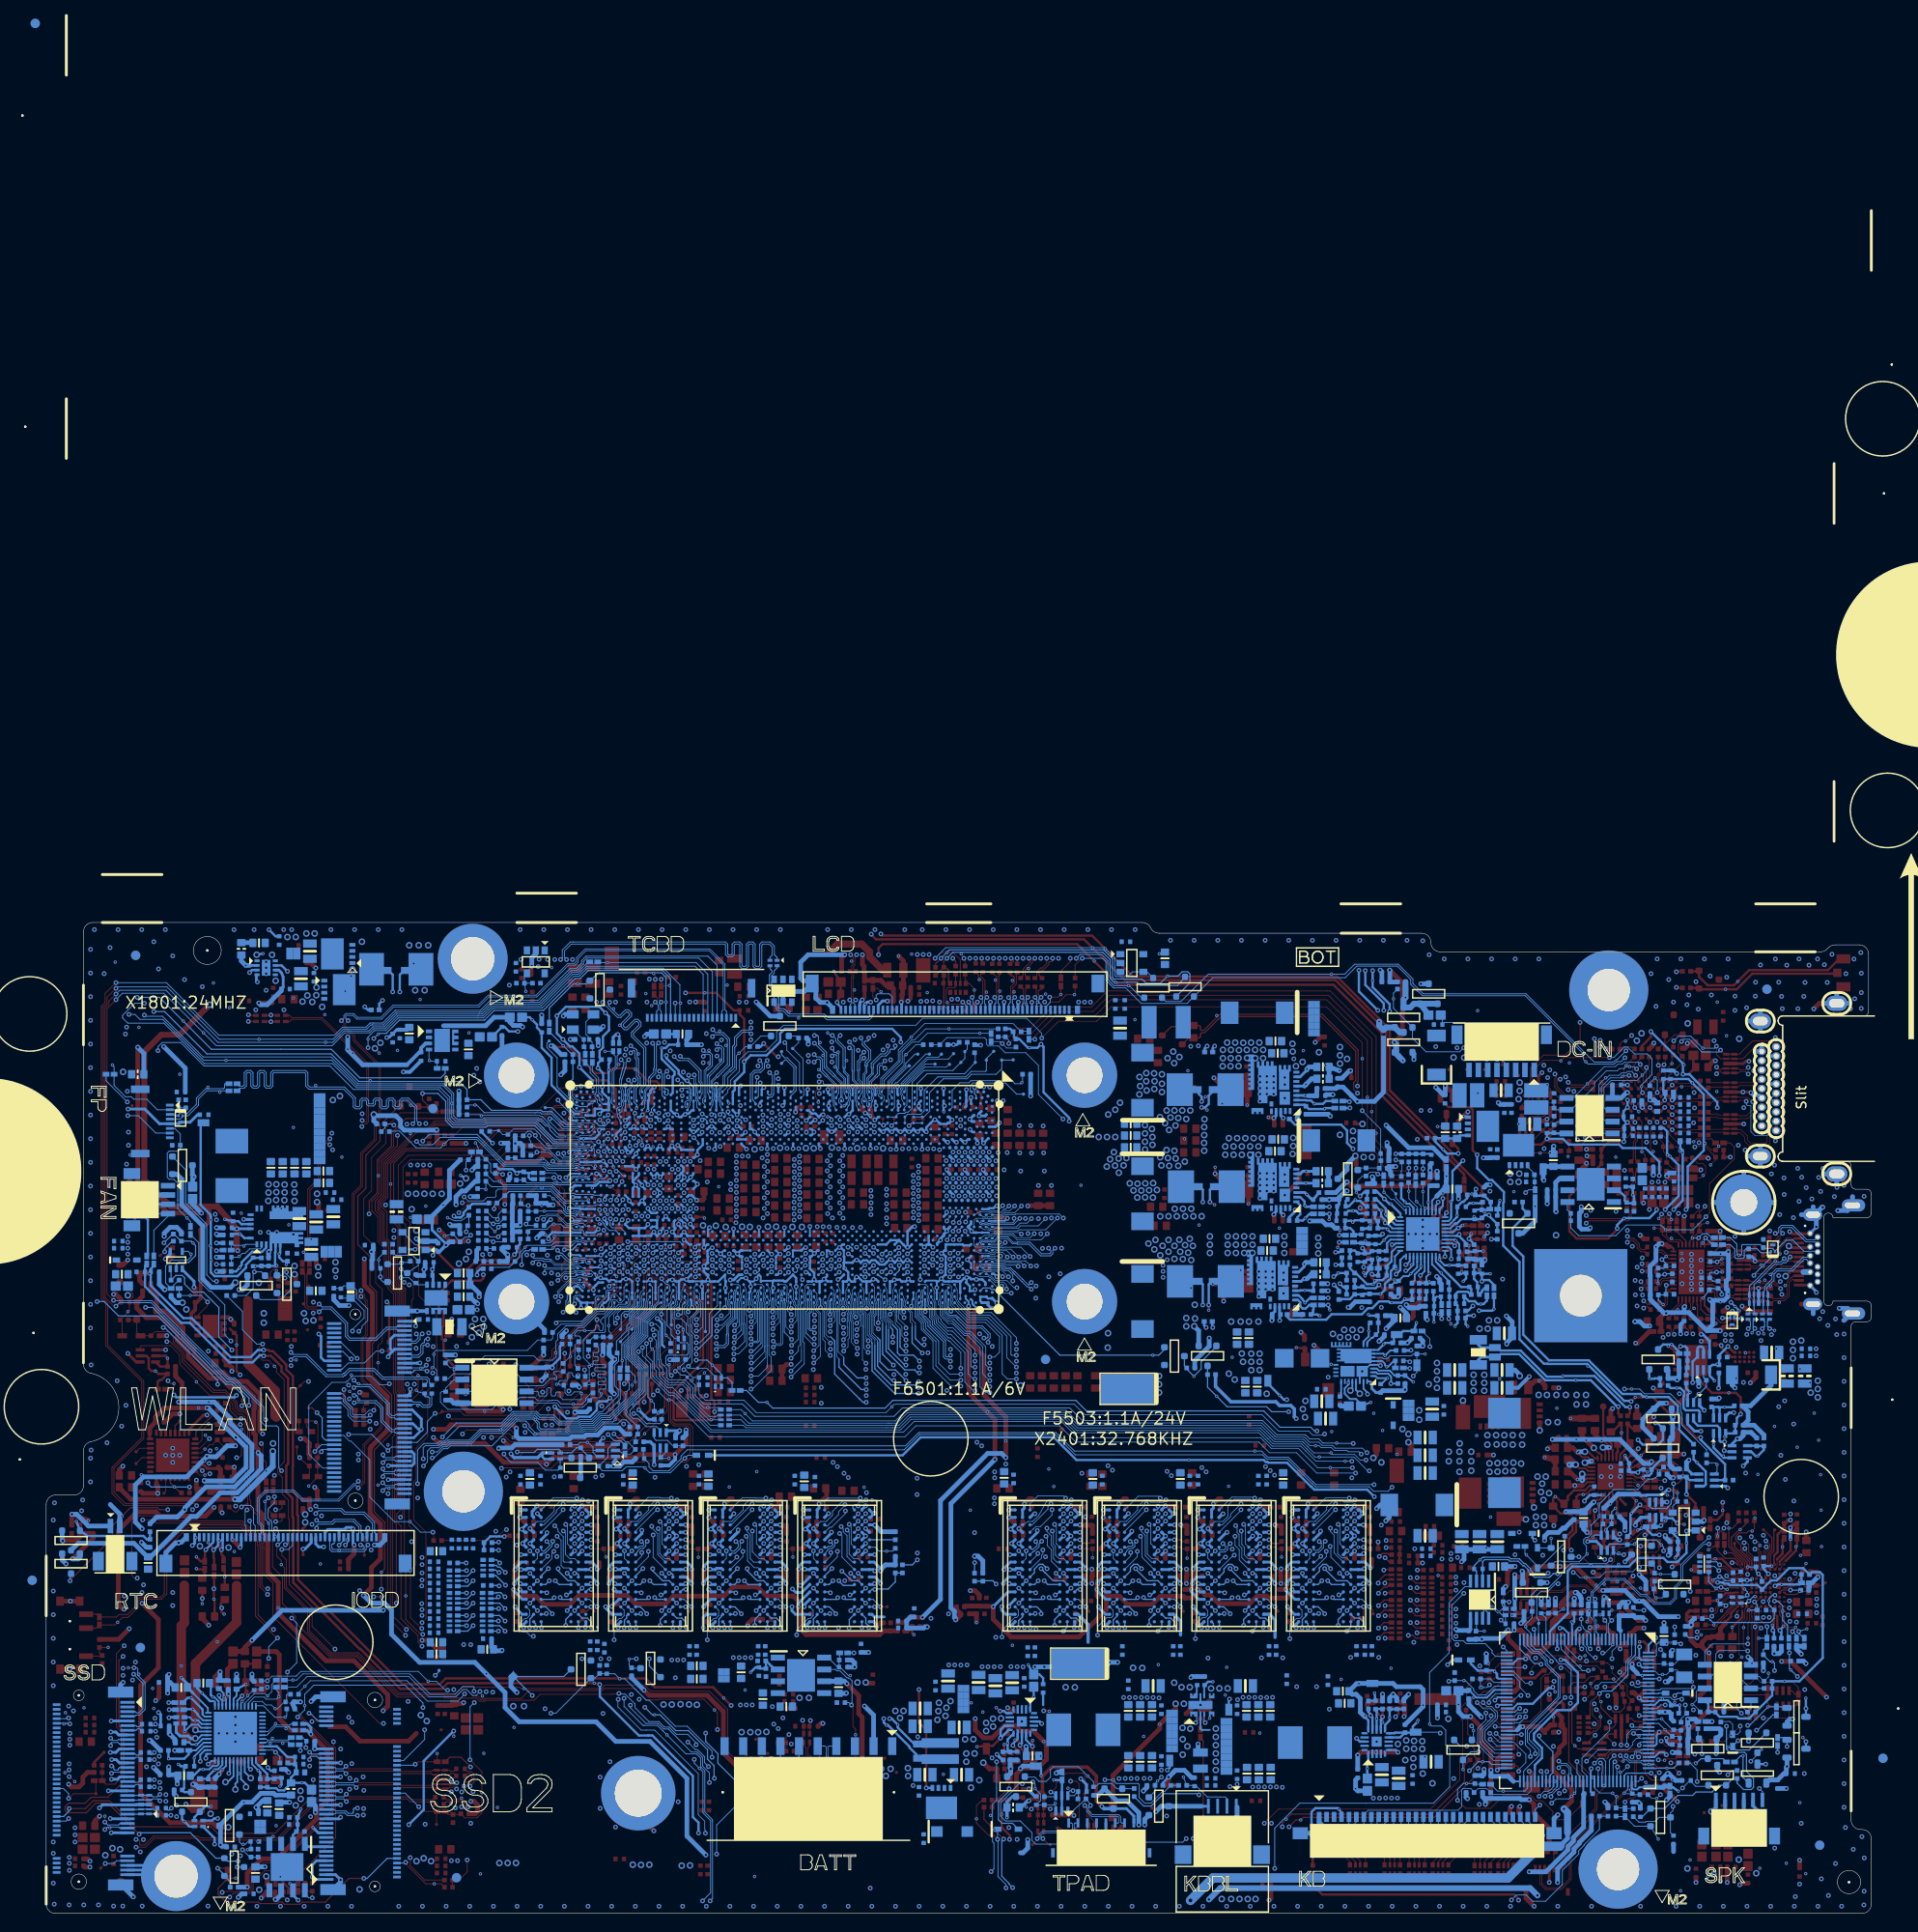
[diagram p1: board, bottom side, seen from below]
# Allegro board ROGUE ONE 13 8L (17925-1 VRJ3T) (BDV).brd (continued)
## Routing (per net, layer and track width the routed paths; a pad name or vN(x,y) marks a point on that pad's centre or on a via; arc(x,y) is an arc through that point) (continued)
CNV_WR_CLK_DN: length 27.7
  TOP w0.102: v1(155.76,58.51) 155.43,58.84 v2(155.18,58.84)
  L6 w0.089: v2(142.48,69.53) 142.78,69.23 143.65,69.23 143.83,69.06 146.83,69.06 148.48,67.4 148.48,62.58 152.21,58.84 v2(155.18,58.84)
  BOTTOM w0.076: v2(142.48,69.53) 142.26,69.31 139.38,69.31 139.17,69.52 138.81,69.52 138.81,69.52 138.76,69.52 138.6,69.36 CPU1.CN31
  BOTTOM w0.102: WLAN1.21 155.47,58.55 v2(155.18,58.84)
CNV_WR_CLK_DP: length 27.6
  TOP w0.102: v2(155.11,58.2) 154.92,58.2 v1(154.55,58.57)
  L6 w0.089: v2(142.48,68.72) 142.48,68.9 142.62,69.04 143.57,69.04 143.75,68.86 146.75,68.86 148.29,67.33 148.29,62.5 152.13,58.65 154.76,58.65 154.85,58.57 154.85,58.45 v2(155.11,58.2)
  BOTTOM w0.076: CPU1.CP31 138.99,69.34 139.1,69.34 139.31,69.13 142.41,69.13 142.48,69.06 v2(142.48,68.72)
  BOTTOM w0.102: v2(155.11,58.2) 155.23,58.32 156.44,58.32 156.54,58.22 156.54,58.16 156.65,58.05 WLAN1.23
CNV_WR_DN0: length 26.4
  L6 w0.089: v2(155.02,61.66) 154.81,61.45 153.38,61.45 151.69,63.14 151.69,66.19 151.69,66.35 150.03,68.01 149.79,68.01 148.95,68.01 146.73,70.23 143.95,70.23 143.75,70.43 v2(143.75,70.63)
  BOTTOM w0.076: 141.91,70.21 141.9,70.21 141.86,70.17 141.83,70.17 141.82,70.16 141.76,70.16 141.33,69.73 139.47,69.73 139.33,69.87 139.11,69.87 CPU1.CR30
  BOTTOM w0.102: WLAN1.15 156.9,60.05 156.76,59.91 156.07,59.91 155.77,60.22 155.77,61 155.53,61.23 155.44,61.23 155.39,61.28 155.39,61.56 155.28,61.66 v2(155.02,61.66) ; 141.91,70.21 142.5,70.21 142.62,70.33 143.65,70.33 143.75,70.43 v2(143.75,70.63)
CNV_WR_DN1: length 27.2
  L6 w0.089: v2(141.09,71.16) 141.37,70.88 141.54,70.88 142.03,71.37 146.98,71.37 148.25,70.1 149.04,70.1 152.49,66.64 152.49,65.27 154.7,63.06 155.4,63.06 155.4,63.06 155.64,63.06 156.02,62.68 156.02,62.43 v2(156.25,62.2)
  BOTTOM w0.076: CPU1.CM30 137.39,70.21 138.03,70.21 138.12,70.31 138.48,70.31 138.54,70.29 138.73,70.29 138.88,70.38 139.36,70.38 139.64,70.1 139.84,70.1 140.17,70.43
  BOTTOM w0.102: v2(156.25,62.2) 156.07,62.02 156.07,61.72 156.37,61.41 156.76,61.41 156.9,61.55 WLAN1.9 ; v2(141.09,71.16) 140.79,70.87 140.61,70.87 140.17,70.43
CNV_WR_DP0: length 26.3
  L6 w0.089: v2(155.06,61) 154.8,61.26 153.3,61.26 151.5,63.06 151.5,66.27 149.95,67.82 149.87,67.82 148.87,67.82 146.65,70.04 143.97,70.04 v2(143.75,69.82)
  BOTTOM w0.076: 141.91,69.98 141.83,69.98 141.4,69.55 139.54,69.55 139.4,69.55 139.3,69.65 139.26,69.68 138.98,69.68 CPU1.CP30
  BOTTOM w0.102: WLAN1.17 156.91,59.55 156.78,59.69 155.97,59.69 155.54,60.12 155.54,60.9 155.44,61 v2(155.06,61) ; v2(143.75,69.82) 143.47,70.1 142.71,70.1 142.6,69.98 141.91,69.98
CNV_WR_DP1: length 27.2
  L6 w0.089: v2(141.09,70.39) 141.39,70.69 141.62,70.69 142.1,71.18 146.9,71.18 148.17,69.91 148.96,69.91 152.3,66.56 152.3,65.19 154.62,62.87 155.48,62.87 155.56,62.87 155.83,62.6 155.83,62.41 v2(155.61,62.2)
  BOTTOM w0.076: CPU1.CN30 137.66,69.95 137.58,69.87 137.58,69.75 137.66,69.68 137.88,69.68 138.04,69.84 138.04,69.99 138.19,70.14 138.46,70.14 138.53,70.13 138.77,70.13 138.92,70.21 139.28,70.21 139.56,69.93 139.95,69.93 140.23,70.21
  BOTTOM w0.102: WLAN1.11 156.89,61.05 156.75,61.19 156.28,61.19 155.84,61.62 155.84,61.99 155.64,62.2 v2(155.61,62.2) ; 140.23,70.21 140.27,70.21 140.7,70.64 140.83,70.64 v2(141.09,70.39)
CNV_WT_CLK_DN: length 40.3
  TOP w0.102: v2(159.86,46.22) 159.96,46.22 160.21,45.97 v1(160.36,45.97)
  L6 w0.089: v2(159.86,46.22) 159.54,45.9 159.17,45.9 157.25,47.83 157.25,50.04 156.49,50.79 156.49,52.67 154.29,54.87 150.96,54.87 148.97,56.86 148.97,57.71 145.9,60.78 145.03,60.78 141.25,64.56 141.25,64.94 140.95,65.25 140.21,65.25 140.21,65.24 140.01,65.04 140.01,64.75 139.96,64.63 v2(139.71,64.53)
  BOTTOM w0.076: 139.82,66.24 139.87,66.33 139.87,67.19 139.63,67.43 139.48,67.58 138.99,67.58 arc(138.93,67.57) 138.87,67.53 138.84,67.51 138.77,67.51 138.74,67.5 138.39,67.15 138.22,67.15 138.14,67.23 138.14,67.39 138.22,67.46 CPU1.CP34
  BOTTOM w0.102: v2(139.71,64.53) 139.97,64.78 139.97,65.61 139.82,65.75 139.82,66.24 ; v2(159.86,46.22) 159.55,45.91 158.63,45.91 158.5,46.05 WLAN1.71
CNV_WT_CLK_DP: length 40.4
  TOP w0.102: v2(159.86,45.38) 159.63,45.61 v1(159.2,45.61)
  L6 w0.089: v2(159.86,45.38) 159.52,45.71 159.09,45.71 157.06,47.75 157.06,49.96 156.3,50.71 156.3,52.59 154.21,54.68 150.88,54.68 148.78,56.78 148.78,57.64 145.83,60.59 144.95,60.59 141.06,64.48 141.06,64.86 140.87,65.05 140.29,65.05 140.2,64.96 140.2,64.82 v2(140.49,64.53)
  BOTTOM w0.076: CPU1.CN34 138.15,67.76 138.27,67.75 138.42,67.75 138.48,67.69 138.74,67.69 138.77,67.7 138.78,67.7 138.79,67.71 138.8,67.71 arc(138.86,67.75) 138.93,67.76 139.55,67.76 139.75,67.56 140.03,67.28 140.05,67.21 140.05,66.24
  BOTTOM w0.102: v2(159.86,45.38) 159.55,45.69 158.63,45.69 158.5,45.55 WLAN1.73 ; 140.05,66.24 140.05,65.85 140.2,65.7 140.2,64.82 v2(140.49,64.53)
CNV_WT_DN0: length 39.5
  L6 w0.089: v2(159.83,47.72) 159.83,47.53 160.05,47.31 160.18,47.31 160.4,47.53 160.4,47.71 160.4,49.48 157.93,51.96 157.93,52.91 154.67,56.16 153.17,56.16 147.19,62.15 145.4,62.15 142.63,64.91 142.63,67.36 141.9,68.1 141.21,68.1 v2(141.05,67.94)
  BOTTOM w0.076: v2(141.05,67.94) 140.32,68.66 139.85,68.66 139.54,68.66 139.38,68.66 139.15,68.81 139.11,68.82 138.98,68.82 138.8,68.79 138.69,68.79 138.6,68.8 138.54,68.8 138.47,68.83 138.41,68.83 138.4,68.82 138.27,68.82 138.2,68.8 138.16,68.77 138.09,68.69 137.99,68.47 137.9,68.4 137.75,68.38 137.43,68.38 137.35,68.46 137.35,68.57 137.43,68.64 CPU1.CN32
  BOTTOM w0.102: WLAN1.65 158.5,47.55 158.63,47.41 159.73,47.41 159.83,47.52 v2(159.83,47.72)
CNV_WT_DN1: length 39.4
  L6 w0.089: v2(159.83,49.22) 159.83,48.98 159.74,48.89 158.32,48.89 157.95,49.26 157.95,50.58 157.35,51.18 157.35,52.78 154.46,55.67 152.92,55.67 152.71,55.88 152.43,55.88 152.12,55.57 151.97,55.57 151.7,55.84 151.7,55.96 151.99,56.24 151.99,56.6 151.68,56.91 151.31,56.91 151.02,56.63 150.9,56.63 150.68,56.84 150.68,56.97 151.01,57.3 151.01,57.58 150.18,58.41 149.82,58.41 149.66,58.25 149.5,58.25 149.17,58.58 149.17,58.7 149.39,58.92 149.39,59.2 148.43,60.16 148.15,60.16 147.86,59.88 147.74,59.88 147.5,60.12 147.5,60.25 147.78,60.53 147.78,60.81 146.99,61.6 145.18,61.6 142.08,64.7 142.08,66.03 141.52,66.59 141.17,66.59 v2(140.7,66.21)
  BOTTOM w0.076: v2(140.7,66.21) 140.92,66.43 140.92,66.68 139.61,67.98 138.69,67.98 CPU1.CP33
  BOTTOM w0.102: v2(159.83,49.22) 159.83,49.02 159.73,48.91 158.63,48.91 158.5,49.05 WLAN1.59
CNV_WT_DP0: length 39.5
  L6 w0.089: v2(159.83,46.88) 160.07,47.12 160.26,47.12 160.59,47.45 160.59,47.79 160.59,49.56 158.12,52.04 158.12,52.98 154.75,56.36 153.25,56.36 147.27,62.34 145.47,62.34 142.83,64.99 142.83,67.44 141.97,68.29 141.3,68.29 v2(141.05,68.55)
  BOTTOM w0.076: CPU1.CM32 137.47,68.96 138.05,69 138.33,69 138.33,69 138.5,69 138.57,68.98 138.61,68.98 138.7,68.97 138.79,68.97 138.97,69 139.17,69 139.19,68.99 139.23,68.98 139.23,68.98 139.44,68.84 139.54,68.84 139.85,68.84 140.4,68.84 140.82,68.41 140.91,68.41 v2(141.05,68.55)
  BOTTOM w0.102: WLAN1.67 158.5,47.05 158.63,47.19 159.73,47.19 159.83,47.08 v2(159.83,46.88)
CNV_WT_DP1: length 39.5
  L6 w0.089: v2(141.31,66.18) 141.5,66.26 141.64,66.2 141.89,65.95 141.89,64.62 145.1,61.41 145.12,61.41 146.91,61.41 147.59,60.73 147.59,60.61 147.31,60.33 147.31,60.04 147.66,59.69 147.94,59.69 148.22,59.97 148.35,59.97 149.2,59.12 149.2,59 148.98,58.78 148.98,58.5 149.42,58.06 149.73,58.06 149.9,58.22 150.1,58.22 150.82,57.5 150.82,57.38 150.49,57.05 150.49,56.76 150.82,56.44 151.1,56.44 151.39,56.72 151.6,56.72 151.8,56.52 151.8,56.32 151.51,56.04 151.51,55.76 151.89,55.38 152.2,55.38 152.51,55.69 152.63,55.69 152.84,55.48 154.38,55.48 157.16,52.7 157.16,51.1 157.76,50.5 157.76,49.18 158.24,48.7 159.51,48.7 v2(159.83,48.38)
  BOTTOM w0.076: CPU1.CN33 138.57,68.28 138.86,68.28 138.98,68.16 139.68,68.16 141.1,66.76 141.1,66.4 v2(141.31,66.18)
  BOTTOM w0.102: WLAN1.61 158.5,48.55 158.63,48.69 159.52,48.69 v2(159.83,48.38)
CNV_WT_RCOMP: length 4.4
  TOP w0.089: v2(140.2,68.22) 140.2,69.11 139.18,70.12 R2101.1
  BOTTOM w0.089: v2(140.2,68.22) 140.04,68.37 139.2,68.37 CPU1.CR32 139.01,68.56 CPU1.CP32
CPU_D4_TP: length 1.3
  TOP w0.102: TP1804.1 133.69,74.9 v2(134.15,74.44)
  BOTTOM w0.102: CPU1.CG23 134.49,74.11 v2(134.15,74.44)
CPU_D6_TP: length 3.2
  TOP w0.102: TP1806.1 134.91,77.11 134.87,77.07 134.54,77.07 v2(134.07,76.6)
  BOTTOM w0.102: CPU1.CG20 134.2,76.32 134.2,76.47 v2(134.07,76.6)
CPU_DP1_CTRL_CLK: length 3.6
  TOP w0.089: v2(132,82.46) 132,82.77 131.65,83.12 RN401.3 v1(130.82,82.26)
  BOTTOM w0.089: v2(132,82.46) 132,83.11 CPU1.CC8
CPU_DP1_CTRL_DATA: length 3
  TOP w0.089: v2(132.68,82.42) 132.63,82.42 132.23,82.81 ; 132.23,82.81 v1(132.35,82.92) ; 132.23,82.81 131.53,83.51 131.53,83.58 131.31,83.79 RN401.4
  BOTTOM w0.089: CPU1.CC9 132.42,82.67 v2(132.68,82.42)
CPU_DP2_CTRL_CLK: length 7.2
  BOTTOM w0.089: v1(135.98,92.51) RN403.3 135.12,92.25 134.88,92.01 134.88,90.86 135.22,90.52 135.22,88.18 135.22,88.05 135.22,87.51 135.32,87.26 135.32,87.01 135.03,86.72 CPU1.CH4
CPU_DP2_CTRL_DATA: length 5.8
  BOTTOM w0.089: 134.68,91.13 134.68,92.03 134.45,92.26 RN403.4 ; 134.68,91.13 v1(134.51,91.13) ; 134.68,91.13 134.68,90.78 135.03,90.44 135.03,88.18 135.03,87.96 CPU1.CH3
CPU_DP_HPD_P: length 7
  TOP w0.102: Q401.3 138.51,83.85 138.39,83.73 137.96,83.73 137.86,83.83 137.86,83.89 ; v1(136.13,82.5) R406.2 135.25,82.55 135.25,83.91 135.54,84.19 135.9,84.19 136.49,83.61 137.58,83.61 137.86,83.89 ; 137.86,83.89 Q401.2
CPU_I2C_SCL_ISH0: length 161.7
  TOP w0.089: v2(134.74,75.51) 135.14,75.91 136.53,75.91 137.01,76.39 137.01,76.7 137.62,77.32 140.12,77.32 RN2007.2 140.33,77.62 140.92,78.21 141.24,78.21 ; v2(151.32,76.27) 150.97,76.27 150.88,76.36 147.76,76.36 146.72,75.32 146.19,75.32 143.3,78.21 141.24,78.21 ; v1(141.24,78.35) 141.24,78.21 ; v2(163.58,95.82) 163.84,95.55 163.84,95.19 162.85,94.2 162.85,93.77 160.1,91.02 160.1,85.27 160.57,84.8 160.57,83.02 162.05,81.54 162.05,78.04 162.94,77.15 162.94,66.78 162.79,66.63 162.41,66.63 v2(162.19,66.85) 162.19,66.78 161.79,66.37 161.79,66.04 161.53,65.79 161.53,62.03 161.98,61.58 161.98,57.3 159.92,55.24 159.92,52.09 161.79,50.22 161.79,46.22 162.08,45.93 162.38,45.93 162.48,45.83 v2(162.48,45.67)
  L4SGND w0.089: v2(162.19,66.85) 162.05,66.7 160.56,66.7 159.68,67.58 157.7,67.58 v2(157.56,67.73)
  L6 w0.089: v2(157.56,67.73) 157.54,67.71 157.39,67.71 156.57,68.53 156.57,69.93 154.98,71.52 154.98,73.04 152.42,75.6 151.53,75.6 151.32,75.81 v2(151.32,76.27)
  BOTTOM w0.089: TCBD1.4 123.45,96.83 123.3,96.98 123.3,101.81 124.8,103.32 138.04,103.32 138.87,102.49 138.87,102.12 139.23,101.76 139.91,101.76 143.31,98.36 144.21,98.36 145.68,98.36 148.45,98.36 149.52,97.29 158.67,97.29 159.98,95.98 162.65,95.98 163.06,96.39 163.74,96.39 163.84,96.28 163.84,96.08 v2(163.58,95.82) ; CN6601.16 172.55,40.7 172.72,40.87 172.72,41.64 173.1,42.02 173.1,44.5 172.38,45.23 169.46,45.23 168.49,44.26 164.57,44.26 162.9,45.93 162.74,45.93 v2(162.48,45.67) ; CPU1.CH20 134.74,75.64 v2(134.74,75.51)
CPU_I2C_SCL_ISH1: length 3.8
  TOP w0.089: v2(135.97,75.51) 135.97,75.29 136.06,75.2 136.32,75.2 136.42,75.11 136.8,75.11 137.12,75.43 137.12,75.63 137.27,75.78 RN2008.1 v1(137.78,76.59)
  BOTTOM w0.089: CPU1.CJ22 135.97,75.19 v2(135.97,75.51)
CPU_I2C_SCL_P0: length 166.7
  L6 w0.089: v2(140.42,81.58) 140.64,81.35 140.64,80.66 141.62,79.69 144.8,79.69 144.98,79.87 147.98,79.87 150.39,77.45 151.71,77.45 155.08,74.08 156.57,74.08 157.31,73.34 157.31,70.97 158.76,69.52 158.76,65.34 159.41,64.69 159.41,61.51 159.96,60.97 160.43,60.49 160.43,55 162,53.44 162,50.91 163.24,49.67 163.24,47.57 163.97,46.84 163.97,43.7 163.22,42.94 161.22,42.94 159.76,41.48 159.76,38.17 162.78,35.15 162.78,34.2 161.11,32.53 161.11,27.15 158.72,24.76 158.72,20.14 156.17,17.59 149.68,17.59 149.17,18.1 148.9,18.1 148.73,18.27 144.61,18.27 143.89,19 128.93,19 127.53,17.59 124,17.59 122.69,16.28 122.68,16.28 122.64,16.24 122.41,16.24 120.58,14.41 120.27,14.41 119.97,14.41 119.8,14.41 118.4,14.41 109.69,14.41 109.22,14.41 105.77,10.97 96.71,10.97 93.15,14.53 90.46,14.53 v2(90.05,14.12)
  BOTTOM w0.076: v2(140.42,81.58) 140.48,81.51 140.49,81.39 140.4,81.22 139.74,81.22 139.27,81.69 138.9,81.69 arc(138.89,81.69) 138.89,81.69 arc(138.85,81.66) 138.8,81.65 arc(138.79,81.65) 138.78,81.65 138.65,81.65 arc(138.57,81.67) 138.49,81.72 138.31,81.9 CPU1.CN11
  BOTTOM w0.089: Q6504.1 87.58,11.55 87.68,11.65 R6505.1 EC6503.1 89.21,12.11 89.21,12.79 v1(89.8,13.38) 89.8,13.87 v2(90.05,14.12)
CPU_I2C_SCL_P1: length 27.4
  TOP w0.089: R5521.2 130.72,100.12 v2(130.59,100.26) 130.59,100.7 v1(130.77,100.88) 130.87,100.98 R5517.2
  L4SGND w0.089: v2(136.09,81.79) 136.31,82.01 136.31,82.21 136.52,82.42 137.05,82.42 137.49,82.86 137.49,85.84 135.4,87.94 135.4,92.61 131.93,96.07 131.93,100.63 131.69,100.88 130.64,100.88 130.37,100.6 130.37,100.48 v2(130.59,100.26)
  BOTTOM w0.089: CPU1.CJ12 135.79,81.43 136.08,81.73 136.08,81.79 v2(136.09,81.79)
CPU_I2C_SCL_TP: length 17.8
  TOP w0.089: v2(88.12,13.02) 88.05,13.02 87.56,13.52 87.56,13.95 86.48,15.03 84.62,15.03 84.47,14.88 AFTP6534.1 v2(84.47,11.58) 84.27,11.38 84.27,10.43 84.09,10.25 RN6503.3
  BOTTOM w0.089: v2(88.12,13.02) 87.98,13.02 Q6504.6 87.7,12.51 R6505.2 ; v2(84.47,11.58) 84.26,11.37 84.26,10.93 83.73,10.41 80.9,10.41 80.8,10.31 80.8,9.79 80.88,9.7 TPAD1.6
CPU_I2C_SCL_TS: length 3.5
  TOP w0.089: v1(130.98,97.43) v2(130.6,97.81) 130.37,98.03 130.37,98.3 R5521.1
  BOTTOM w0.089: TCBD1.18 130.45,96.82 130.3,96.97 130.3,97.51 v2(130.6,97.81)
CPU_I2C_SDA_ISH0: length 160.7
  TOP w0.089: v2(164.3,95.82) 164.03,95.55 164.03,95.11 163.04,94.12 163.04,93.69 160.29,90.94 160.29,85.35 160.76,84.88 160.76,83.1 162.24,81.62 162.24,78.12 163.13,77.23 163.13,66.7 162.87,66.44 162.42,66.44 v2(162.19,66.21) 162.19,66.18 161.72,65.71 161.72,62.11 162.17,61.65 162.17,57.23 160.11,55.16 160.11,52.16 161.98,50.3 161.98,46.3 162.16,46.12 162.38,46.12 162.48,46.22 v2(162.48,46.38) ; v2(136.58,75.51) 137.21,76.14 137.21,76.64 137.5,76.93 138.22,76.93 138.68,76.46 139.89,76.46 140.1,76.67 140.73,76.67 140.98,76.92 RN2007.1 140.98,77.47 140.86,77.59 140.86,77.88 141,78.02 142.76,78.02 ; v2(151.68,75.2) 150.71,76.17 147.84,76.17 146.8,75.13 146.11,75.13 143.22,78.02 142.76,78.02 ; 142.76,78.02 v1(142.76,77.87)
  L4SGND w0.089: v2(162.19,66.21) 161.89,66.51 160.48,66.51 159.79,67.2 157.27,67.2 v2(157.01,67.46)
  L6 w0.089: v2(151.68,75.2) 151.8,75.33 152.42,75.33 154.79,72.96 154.79,71.44 156.38,69.85 156.38,68.09 v2(157.01,67.46)
  BOTTOM w0.089: v2(164.3,95.82) 164.03,96.08 164.03,96.36 163.82,96.58 162.98,96.58 162.57,96.17 160.06,96.17 158.75,97.48 149.6,97.48 148.53,98.55 145.68,98.55 144.21,98.55 143.39,98.55 139.99,101.95 139.31,101.95 139.06,102.2 139.06,102.57 138.12,103.51 124.72,103.51 123.1,101.89 123.1,96.97 122.95,96.82 TCBD1.3 ; CN6601.15 173.05,40.7 172.91,40.84 172.91,41.56 173.3,41.94 173.3,44.58 172.46,45.42 169.38,45.42 168.41,44.45 164.65,44.45 162.98,46.12 162.74,46.12 v2(162.48,46.38) ; CPU1.CK22 136.58,75.15 v2(136.58,75.51)
CPU_I2C_SDA_ISH1: length 3.3
  TOP w0.089: v2(135.36,75.51) 135.36,75.36 v1(135.7,75.02) 135.71,75.01 136.24,75.01 136.34,74.92 136.88,74.92 137.09,75.13 RN2008.2
  BOTTOM w0.089: v2(135.36,75.51) 135.36,75.23 CPU1.CH22
CPU_I2C_SDA_P0: length 171.2
  TOP w0.089: v2(85.73,13.17) 85.99,13.43 v1(86.27,13.43)
  L6 w0.089: v2(141.02,81.55) 140.83,81.36 140.83,80.74 141.7,79.88 144.72,79.88 144.9,80.06 148.05,80.06 150.47,77.64 151.79,77.64 155.15,74.27 156.65,74.27 157.5,73.42 157.5,71.05 158.95,69.6 158.95,65.42 159.6,64.77 159.6,61.59 160.03,61.16 160.62,60.57 160.62,55.08 162.19,53.52 162.19,50.99 163.43,49.75 163.43,47.65 164.17,46.91 164.17,43.62 163.3,42.75 161.3,42.75 159.95,41.4 159.95,38.25 162.97,35.23 162.97,34.12 161.3,32.45 161.3,27.07 158.91,24.68 158.91,20.06 156.25,17.4 149.6,17.4 149.1,17.91 148.83,17.91 148.65,18.08 144.53,18.08 143.81,18.81 129.01,18.81 127.61,17.4 124.08,17.4 122.77,16.09 122.76,16.09 122.72,16.05 122.48,16.05 120.66,14.22 120.35,14.22 120.35,14.22 119.89,14.22 119.73,14.22 119.72,14.22 118.95,14.22 118.94,14.22 118.32,14.22 118.32,14.22 114.16,14.22 114.16,14.22 109.61,14.22 109.61,14.22 109.3,14.22 105.85,10.77 96.63,10.77 93.07,14.34 90.84,14.34 89.12,12.62 86.9,12.62 86.7,12.83 86.08,12.83 v2(85.73,13.17)
  BOTTOM w0.076: v2(141.02,81.55) 141.02,81.54 140.52,81.04 139.67,81.04 139.2,81.51 138.98,81.51 138.97,81.51 138.92,81.51 138.86,81.49 138.85,81.47 138.65,81.47 138.62,81.47 138.61,81.47 138.53,81.49 arc(138.5,81.5) 138.48,81.5 138.47,81.5 arc(138.45,81.51) 138.43,81.51 138.05,81.51 137.66,81.9 CPU1.CM11
  BOTTOM w0.089: R6506.1 85.18,12.31 EC6504.1 85.62,12.63 Q6504.4 86.28,12.94 86.05,13.17 v2(85.73,13.17)
CPU_I2C_SDA_P1: length 28
  TOP w0.089: R5518.2 129.73,100.48 v2(129.95,100.26) 129.96,100.25 R5522.2 v1(129.07,99.59)
  L4SGND w0.089: v2(136.72,81.78) 136.72,81.79 136.5,82.01 136.5,82.13 136.6,82.23 137.13,82.23 137.68,82.78 137.68,85.92 135.59,88.02 135.59,92.69 132.13,96.15 132.13,100.71 131.77,101.07 130.56,101.07 130.18,100.68 130.18,100.48 v2(129.95,100.26)
  BOTTOM w0.089: v2(136.72,81.78) 136.72,81.73 136.44,81.45 CPU1.CK12
CPU_I2C_SDA_TP: length 11.4
  TOP w0.089: 84.08,10.86 84.08,10.51 83.42,9.85 RN6503.4 ; 84.08,10.86 AFTP6535.1 ; 84.08,10.86 84.08,11.35 v2(83.86,11.58)
  BOTTOM w0.089: TPAD1.7 80.52,9.7 80.6,9.79 80.6,10.38 80.82,10.6 83.65,10.6 84.07,11.01 84.07,11.37 v2(83.86,11.58) 83.86,11.73 R6506.2 85.78,10.98 Q6504.3
CPU_I2C_SDA_TS: length 3.4
  TOP w0.089: R5522.1 130.18,98.42 130.18,98.03 v2(129.96,97.81) v1(129.43,97.81)
  BOTTOM w0.089: TCBD1.17 129.95,96.82 130.1,96.97 130.1,97.66 v2(129.96,97.81)
CPU_POPIRCOMP: length 1.6
  TOP w0.508: v2(127.5,72.28) 127.5,71.65 R304.1
  BOTTOM w0.254: CPU1.BP27 126.96,71.79 127.45,72.28 v2(127.5,72.28)
CPU_SMB_ALERT#: length 10.3
  BOTTOM w0.102: R1552.1 144.74,78.71 R1551.2 144.38,78.4 142.75,78.4 142.74,78.4 v1(141.41,78.4) 141.21,78.2 139.71,78.2 139.45,78.46 137.05,78.46 137.03,78.48 136.99,78.48 136.61,78.86 136.08,78.86 CPU1.CJ15
CPU_SMB_ALERT#_P0: length 18.7
  L6 w0.102: v2(134.84,78.63) 134.84,78.66 135.27,79.09 136.11,79.09 136.64,78.55 142.2,78.55 142.53,78.89 146.55,78.89 v2(146.98,79.32)
  BOTTOM w0.102: v1(149.9,82.7) 149.81,82.66 R1806.1 149.47,81.63 R1505.1 148.27,80.43 148.27,79.6 148.1,79.42 R1504.2 147.08,79.42 v2(146.98,79.32) ; v2(134.84,78.63) 134.49,78.98 CPU1.CG15
CPU_SMB_ALERT#_P1: length 12.8
  TOP w0.102: v1(132.3,68.52) v2(132.47,68.02) 132.47,64.12 135.34,61.24 135.34,58.64 R1837.2 135.9,57.88 R1555.1
  BOTTOM w0.102: CPU1.CC34 v2(132.47,68.02)
CPU_SMB_SCL: length 3.1
  TOP w0.089: 136.93,80.3 137.03,80.41 138.02,80.41 RN1807.7 ; 136.93,80.3 v1(137.02,80.21) ; 136.93,80.3 136.35,79.72 v2(136.08,79.72)
  BOTTOM w0.089: v2(136.08,79.72) 136.08,79.75 136.21,79.75 136.44,79.98 CPU1.CK14
CPU_SMB_SCL_P0: length 3.9
  TOP w0.089: v2(135.45,80.71) 135.55,80.71 135.92,80.34 136.41,80.34 137.57,81.5 RN1807.5
  BOTTOM w0.089: v2(135.45,80.71) 135.14,80.4 CPU1.CH14
CPU_SMB_SCL_P1: length 236.4
  TOP w0.089: v2(30.36,33.76) 30.09,34.03 30.09,34.49 30.64,35.04 32.57,35.04 33.18,34.44 35.6,34.44 36.36,33.67 37.56,33.67 37.65,33.58 Q2601.3
  L4SGND w0.089: v2(140.86,78.98) 141.08,79.2 141.08,79.42 142.11,80.46 142.11,80.98 142.57,81.44 142.57,85.47 142.17,85.88 141.56,85.88 140.18,87.25 140.18,89.35 139.97,89.56 139.97,92.64 136.59,96.01 134.66,96.01 133.82,96.85 133.82,100.72 131.93,102.62 127.69,102.62 126.88,101.81 105.7,101.81 102.97,104.54 84.88,104.54 82.96,102.62 49.18,102.62 47.72,101.16 34.83,101.16 28.7,95.03 27.86,95.03 27.05,94.21 27.05,91.03 27.44,90.65 27.41,83.88 27.36,83.83 27.36,75.92 24.65,73.21 24.65,73.21 24.4,72.97 23.92,72.48 23.92,67.67 20.75,64.5 18.94,64.5 17.44,62.99 17.44,42.59 17.12,42.27 17.12,40.67 v2(17.44,40.35)
  BOTTOM w0.076: v2(140.86,78.98) 140.86,78.83 140.56,78.54 140.05,78.54 139.44,79.16 138.92,79.16 138.8,79.12 138.62,79.12 138.39,79.2 CPU1.CN15
  BOTTOM w0.089: 29.43,35.12 30.07,34.48 30.07,34.04 v2(30.36,33.76) 30.14,33.55 30.14,33.34 R2459.2 ; 29.43,35.12 v1(29.53,35.22) ; 29.43,35.12 28.61,35.94 26.46,35.94 24.77,34.25 24.18,34.25 23.29,33.36 21.65,33.36 21.12,33.89 21.12,35.07 20.45,35.74 20.45,37.42 18.04,39.82 17.96,39.82 v2(17.44,40.35) ; RN1811.4 141.35,79.47 v2(140.86,78.98)
CPU_SMB_SCL_THM: length 10.1
  TOP w0.089: v2(39.77,31.47) 39.54,31.7 v1(39.54,33.11) 39.54,33.93 38.84,34.63 Q2601.4
  BOTTOM w0.089: v2(39.77,31.47) 39.38,31.08 C2608.1 39.28,32.01 RN2602.4 39.66,32.02 39.88,32.24 40.13,32.24 40.74,32.85 41.36,32.85 41.42,32.79 41.42,32.51 41.1,32.19 U2601.8
CPU_SMB_SDA: length 4.4
  TOP w0.089: v1(138.01,78.96) 138.01,79.06 RN1807.8 138,79.85 136.77,79.85 136.25,79.32 136.24,79.32 136.23,79.31 135.76,79.31 v2(135.47,79.6)
  BOTTOM w0.089: v2(135.47,79.6) 135.14,79.26 CPU1.CH15
CPU_SMB_SDA_P0: length 5.1
  TOP w0.089: 135.18,79.99 135.34,80.15 136.48,80.15 137.28,80.94 138,80.94 RN1807.6 ; 135.18,79.99 v1(135.07,80.1) ; 135.18,79.99 134.84,79.65 v2(134.79,79.65)
  BOTTOM w0.089: v2(134.79,79.65) 134.53,79.65 134.04,79.15 CPU1.CF15
CPU_SMB_SDA_P1: length 235.9
  TOP w0.089: Q2601.6 33.25,34.63 32.65,35.23 30.56,35.23 29.9,34.56 29.9,33.96 v2(29.66,33.72)
  L4SGND w0.089: v2(17.44,39.64) 17.44,39.69 16.93,40.21 16.93,42.34 17.25,42.67 17.25,63.07 18.86,64.69 20.67,64.69 23.72,67.74 23.72,72.56 24.21,73.04 27.16,76 27.16,83.91 27.22,83.96 27.25,90.57 26.86,90.95 26.86,94.29 27.79,95.22 28.62,95.22 34.75,101.35 47.64,101.35 49.1,102.81 82.88,102.81 84.8,104.73 103.05,104.73 105.78,102 126.8,102 127.61,102.81 132.01,102.81 134.01,100.8 134.01,96.93 134.74,96.2 136.67,96.2 140.16,92.72 140.16,89.64 140.37,89.43 140.37,87.33 141.64,86.07 142.25,86.07 142.76,85.55 142.76,81.36 142.3,80.9 142.3,80.38 141.27,79.35 141.27,79.19 v2(141.49,78.96)
  BOTTOM w0.076: CPU1.CM15 137.71,79.08 138.24,79.08 138.31,79.06 138.32,79.05 138.59,78.95 138.83,78.95 138.94,78.99 139.37,78.99 139.98,78.38 140.91,78.38 v2(141.49,78.96)
  BOTTOM w0.089: 27.27,35.75 28.53,35.75 29.88,34.4 29.88,33.95 v2(29.66,33.72) 29.66,33.7 29.89,33.47 29.89,33.34 R2447.2 ; 27.27,35.75 26.54,35.75 24.85,34.06 24.26,34.06 23.36,33.17 21.57,33.17 20.93,33.81 20.93,34.99 20.26,35.66 20.26,37.34 17.96,39.63 17.44,39.63 v2(17.44,39.64) ; 27.27,35.75 v1(27.27,35.6) ; RN1811.3 142.57,78.96 v2(141.49,78.96)
CPU_SMB_SDA_THM: length 10.4
  TOP w0.089: Q2601.1 36.35,32.16 36.81,31.7 38.27,31.7 v1(38.57,32) 38.9,32.33 v2(38.9,33.42)
  BOTTOM w0.089: U2601.7 41.75,32.22 41.62,32.36 41.62,32.86 41.44,33.04 40.66,33.04 40.05,32.43 39.89,32.43 39.63,32.69 RN2602.3 39.29,33.05 39.54,33.29 C2609.1 38.95,33.47 v2(38.9,33.42)
CPVEE: length 5
  BOTTOM w0.203: 180.23,23.64 178.64,22.06 U2701.25
  BOTTOM w0.305: 180.23,23.64 C2741.1 180.84,24.63 v1(181.5,25.29)
DAT_TP_SIO: length 64.5
  TOP w0.089: RN6502.2 88.87,10.54 EC6502.1 88.89,11.35 RN6501.3 88.33,11.37 v2(88.18,11.22) 88.18,11.28 v1(87.64,11.81)
  L6 w0.089: v2(33.57,16.35) 33.83,16.08 35.51,16.08 36.11,15.49 36.11,14.88 36.6,14.38 40.46,14.38 43.18,11.67 66.08,11.67 66.1,11.64 66.71,11.64 67.26,11.09 74.54,11.09 75.22,11.09 75.7,11.57 81.81,11.57 82.4,12.17 84.73,12.17 85.4,11.49 86.15,11.49 86.63,11 87.96,11 v2(88.18,11.22)
  BOTTOM w0.089: v2(33.57,16.35) 33.31,16.08 32.73,16.08 32.26,15.62 32.26,14.96 32.13,14.84 U2401.79
DBC_EN_R: length 3.8
  TOP w0.102: R5503.1 v1(87.03,98.62) 87.33,98.33 v2(88.24,98.33)
  BOTTOM w0.102: LCD1.6 88.65,97.31 88.18,97.78 88.18,98.19 88.24,98.25 v2(88.24,98.33)
DBC_PANEL_EN: length 168
  TOP w0.102: v2(131.8,68.88) 131.8,64.52 134.23,62.09 134.23,58.67 R2043.2 134.43,58.57 134.74,58.26 134.74,58.08 134.76,58.05 134.76,57.35 134.66,57.25 134.74,57.17 134.74,56.15 134.53,55.95 v1(134.53,54.81) 134.53,53.69 133.8,52.95 133.79,52.95 133.54,52.7 133.49,52.65 133.49,52.27 135.14,50.61 136.03,50.61 136.05,50.59 136.41,50.59 136.44,50.61 145.64,50.61 146.14,50.61 146.7,51.17 148.07,51.17 v2(148.17,51.07) ; v2(86.02,102.51) 86.02,102.15 87.03,101.14 R5503.2
  L3SGND w0.102: v2(86.02,102.51) 86.04,102.51 86.04,102.58 86.96,103.5 102.6,103.5 104.64,101.47 131.43,101.47 131.74,101.16 131.74,98.77 134.33,96.18 138.8,96.18 139.1,95.88 143.02,95.88 143.68,96.54 146.22,96.54 152.57,90.19 154.85,90.19 162,83.04 162,71.07 161.3,70.38 161.3,70.12 162,69.43 162,68.17 164.2,65.96 164.2,62.68 160.08,58.57 157.26,58.57 155.87,57.17 155.87,55.77 154.57,54.48 151.02,54.48 148.17,51.63 v2(148.17,51.07)
  BOTTOM w0.102: v2(131.8,68.88) 131.61,68.88 CPU1.CA31
DC_IN_OFF: length 4.8
  BOTTOM w0.254: R4369.2 19.09,48.74 v1(18.73,48.38) 17.78,47.43 17.78,46.03 17.96,45.85 Q4349.6
DCBATOUT: length 37.9
  TOP w0.203: 31.03,45.92 30.87,45.92 30.51,46.28 PU4401.3
  TOP w0.508: PC4439.2 32.5,45.92 v2(31.84,45.92) 31.03,45.92
  L3SGND w0.508: v2(31.84,45.92) 32.75,45 32.75,41.86 33.93,40.68 37.58,40.68 v2(37.81,40.91)
  L4SGND w0.508: v3(57.06,83.56) 56.4,84.22 56.4,84.27 55.97,84.7 55.72,84.7 54.95,85.46 52.97,85.46 v2(52.11,84.6) ; v3(100.29,20.77) 100.29,18.99 99.24,17.94 94.77,17.94 v2(93.89,17.06)
  BOTTOM w0.305: PR4509.1 93.33,16.48 93.64,16.78 93.64,16.79 93.89,17.04 93.89,17.06 v2(93.89,17.06)
  BOTTOM w0.508: v2(49.7,23.51) 50.2,23.01 PR4511.1 ; PR4612.1 45.82,80.92 47.08,82.17 49.68,82.17 v2(52.11,84.6)
  vias: v1(41.34,39.24) v1(46.52,36.26) v1(51.58,26.31) v1(56.94,25.11) v1(58.61,91.03) v1(69.23,26.41) v1(76.57,26.69) v1(96.66,22.6) v1(166.56,37.51) v1(176.32,97.2) v2(164.91,68.27) v3(42.97,49.55) v3(42.97,48.53) v3(42.97,47.52) v3(44.21,50.44) v3(44.24,49.55) v3(44.24,48.53) v3(44.24,47.39) v3(45.38,49.55) v3(45.38,48.53) v3(48.55,53.99) v3(48.55,52.98) v3(56.3,91.71) v3(57.06,92.98) v3(57.06,92.09) v3(57.06,91.2) v3(59.32,92.42) v3(59.4,72.51) v3(59.4,71.67) v3(59.4,70.83) v3(78.29,26.34) v3(79.29,26.36) v3(85.53,24.26) v3(86.53,24.28) v3(98.89,22.78) v3(99.33,22.07) v3(99.43,21.2) v3(100.13,22.6) v3(100.19,21.71) v3(164.94,69.89) v3(164.94,69) v3(169.2,104.79) v3(170.09,104.79)
DIAGLOOP: length 6.2
  TOP w0.102: v1(106.35,98.91) 106.72,99.28 R5510.1 107.23,98.39 v2(106.87,98.04)
  BOTTOM w0.102: v2(106.87,98.04) 106.87,98.54 106.72,98.7 105.47,98.7 105.15,98.37 LCD1.39
DMIC_SCL_CODEC: length 132.4
  TOP w0.089: v2(193.54,14.68) v1(192.93,14.14) ; v2(174.28,96.44) 174.22,96.38 RN5503.4
  L4SGND w0.089: v2(168.11,17.79) 168.2,17.7 168.21,17.7 168.3,17.61 168.3,17.33 168.31,17.31 168.31,17.3 168.61,17 168.61,15.1 175.33,8.38 179.26,8.38 179.69,8.81 180.2,8.81 180.2,8.81 184.72,8.81 188.41,12.5 188.71,12.5 188.72,12.5 188.91,12.5 189.87,12.5 192.32,14.94 193.27,14.94 v2(193.54,14.68)
  L6 w0.089: v2(193.54,14.68) 193.8,14.94 194.06,14.94 194.5,15.39 194.5,38.24 190.56,42.18 190.56,48.13 186.78,51.91 186.78,58.54 188.08,59.84 188.08,89.19 184.59,92.68 184.59,92.84 182.03,95.4 175.78,95.4 174.99,96.18 174.54,96.18 v2(174.28,96.44)
  BOTTOM w0.089: v2(168.11,17.79) 168.11,17.79 168.11,18.43 FC2738.2 168.44,18.86 R2721.1
DMIC_SCL_CODEC_R: length 3.4
  BOTTOM w0.089: 171.72,18.61 169.94,18.61 R2721.2 ; 171.72,18.61 172.26,18.61 172.37,18.72 U2701.5 ; 171.72,18.61 v1(171.72,18.79)
DMIC_SCL_CON: length 78.7
  TOP w0.089: 109.35,99.1 109.35,98.31 v2(109.08,98.04) ; 109.35,99.1 v1(109.21,99.1) ; 109.35,99.1 109.35,100.34 109.29,100.4 109.29,100.9 EC5504.1 109.3,101.33 109.3,101.63 109.17,101.76 109.17,102.7 v2(108.98,102.89) ; RN5503.1 171.9,96.38 v2(171.86,96.42) 171.83,96.38 RN5504.2
  L6 w0.089: v2(108.98,102.89) 109.42,103.33 109.42,103.64 110.61,104.82 123.41,104.82 123.67,105.08 148.66,105.08 148.95,105.36 151.5,105.36 153.12,103.74 153.12,100.29 156.69,96.72 164.23,96.72 165.58,95.37 169.96,95.37 170.75,96.16 171.6,96.16 v2(171.86,96.42)
  BOTTOM w0.089: v2(109.08,98.04) 109.3,97.82 109.3,97.69 109.15,97.54 LCD1.47
DMIC_SCL_CPU: length 86.7
  TOP w0.089: 161.38,89.38 161.38,91.17 166.36,96.15 169.62,96.15 169.84,96.38 RN5504.3 ; 161.38,89.38 161.38,84.96 161.59,84.75 161.8,84.75 v2(162.1,84.45) ; 161.38,89.38 v1(161.2,89.38)
  L3SGND w0.089: v2(157.22,56.8) 156.94,57.08 156.94,57.35 157.58,57.99 160.29,57.99 164.75,62.45 164.75,66.19 162.55,68.39 162.55,83.33 161.64,84.24 161.64,84.58 161.73,84.67 161.85,84.68 v2(162.1,84.45)
  L6 w0.089: v2(157.22,56.8) 156.94,57.08 156.94,63.29 156.51,63.72 155.91,63.72 155.07,63.72 153.4,65.39 153.4,66.79 152.75,67.45 151.93,68.27 149.87,70.32 149.87,71.4 148.74,72.53 148.74,74.13 147.56,75.3 143.04,75.3 142.84,75.1 142.84,74.73 v2(142.59,74.48)
  BOTTOM w0.076: v2(142.59,74.48) 142.54,74.48 142.16,74.86 141.15,74.86 140.17,73.88 140.02,73.88 140.02,73.88 139.31,73.88 139.25,73.94 138.99,73.94 arc(138.93,73.94) 138.88,73.92 arc(138.84,73.9) 138.81,73.87 138.63,73.69 CPU1.CP24
DMIC_SDA_CODEC: length 129.8
  TOP w0.089: RN5503.3 v2(174.28,95.73) ; v1(193.98,15.1) 193.98,15.1 193.97,15.11 193.82,15.11 v2(193.54,15.39)
  L4SGND w0.089: v2(168.71,17.47) 168.72,17.47 168.8,17.39 168.8,15.18 175.41,8.57 179.18,8.57 179.61,9 180.28,9 184.64,9 188.33,12.69 188.79,12.69 188.99,12.69 189.79,12.69 192.24,15.13 193.27,15.13 v2(193.54,15.39)
  L6 w0.089: v2(174.28,95.73) 174.54,95.99 174.92,95.99 175.7,95.2 181.95,95.2 184.4,92.76 184.4,92.6 187.89,89.11 187.89,59.92 186.59,58.62 186.59,51.83 190.37,48.05 190.37,42.1 194.31,38.17 194.31,15.46 193.98,15.13 193.8,15.13 v2(193.54,15.39)
  BOTTOM w0.089: R2738.1 168.71,17.99 v2(168.71,17.47)
DMIC_SDA_CODEC_R: length 3.4
  BOTTOM w0.089: R2738.2 170,18.42 170.6,18.42 ; 170.6,18.42 172.29,18.42 172.39,18.32 U2701.4 ; 170.6,18.42 v1(170.6,18.26)
DMIC_SDA_CON: length 78.2
  TOP w0.089: v2(109.72,98.04) 109.54,98.21 109.54,100.42 109.48,100.48 109.48,100.9 EC5503.1 109.49,101.31 109.49,101.71 109.36,101.84 109.36,102.2 ; 109.36,102.2 v1(109.51,102.2) ; 109.36,102.2 109.36,102.63 v2(109.61,102.89) ; RN5504.1 171.84,95.73 v2(171.86,95.7) 171.89,95.73 RN5503.2
  L6 w0.089: v2(109.61,102.89) 109.61,103.56 110.68,104.63 123.49,104.63 123.75,104.89 148.74,104.89 149.03,105.17 151.42,105.17 152.93,103.66 152.93,100.21 156.61,96.53 164.15,96.53 165.5,95.18 170.04,95.18 170.83,95.97 171.6,95.97 v2(171.86,95.7)
  BOTTOM w0.089: v2(109.72,98.04) 109.49,97.81 109.49,97.71 109.65,97.54 LCD1.48
DMIC_SDA_CPU: length 87.1
  TOP w0.089: 162.93,92.45 166.44,95.96 169.62,95.96 169.84,95.73 RN5504.4 ; 162.93,92.45 161.57,91.09 161.57,85.04 161.67,84.94 161.9,84.94 v2(162.07,85.11) ; 162.93,92.45 v1(163.05,92.33)
  L3SGND w0.089: v2(156.47,56.8) 156.75,57.08 156.75,57.43 157.5,58.18 160.22,58.18 164.56,62.53 164.56,66.11 162.36,68.32 162.36,83.25 161.45,84.16 161.45,84.66 161.64,84.86 161.84,84.87 v2(162.07,85.11)
  L6 w0.089: v2(156.47,56.8) 156.75,57.08 156.75,63.21 156.43,63.53 155.83,63.53 154.99,63.53 153.21,65.31 153.21,66.71 152.67,67.26 149.68,70.24 149.68,71.32 148.55,72.45 148.55,74.05 147.48,75.11 143.12,75.11 143.03,75.02 143.03,74.73 v2(143.28,74.48)
  BOTTOM w0.076: CPU1.CN24 138.04,73.77 138.33,74.06 138.73,74.06 arc(138.77,74.06) 138.8,74.08 arc(138.86,74.1) 138.93,74.11 139.34,74.11 139.38,74.06 140.1,74.06 141.08,75.04 142.23,75.04 142.39,74.88 142.88,74.88 v2(143.28,74.48)
DP1_AUX_ALS_N: length 3.3
  TOP w0.102: U5701.C8 25.14,83.55 25.14,82.9 25.34,82.71 25.34,80.97 C5741.2
DP1_AUX_ALS_P: length 4.2
  TOP w0.102: U5701.C7 25.37,84.12 25.37,83 25.57,82.8 25.57,80.94 C5740.2
DP1_AUX_C_N: length 3.6
  TOP w0.102: C5741.1 25.32,79.51 25.32,78.4 25.76,77.96 25.76,77.58 R5763.1 25.46,76.62 C5739.2
DP1_AUX_C_P: length 3.6
  TOP w0.102: C5740.1 25.55,79.51 25.55,78.49 25.99,78.06 25.99,77.58 R5762.1 26.28,76.62 C5738.2
DP1_AUX_CPU_N: length 108
  TOP w0.102: v2(30.62,74.08) 30.36,74.34 26.11,74.34 25.78,74.67 25.78,75.4 C5739.1
  L6 w0.089: v2(107.05,83.84) 106.67,84.22 106.67,84.67 105.42,85.91 101.18,85.91 97.84,89.25 88.12,89.25 86.12,87.25 83.14,87.25 81.8,88.59 81.8,92.63 77.87,96.56 77.21,96.56 77.21,96.56 54.57,96.56 52.48,94.47 41.65,94.47 35.82,88.64 35.82,78.47 31.75,74.4 30.95,74.4 v2(30.62,74.08)
  BOTTOM w0.102: v2(107.05,83.84) 107.39,84.18 CPU1.AC7
DP1_AUX_CPU_P: length 107.2
  TOP w0.102: C5738.1 26.01,75.44 26.01,74.77 26.21,74.56 30.28,74.56 v2(30.62,74.91)
  L6 w0.089: v2(107.07,84.53) 105.5,86.1 101.26,86.1 97.92,89.44 88.04,89.44 86.04,87.44 83.22,87.44 81.99,88.67 81.99,92.71 77.95,96.75 77.13,96.75 54.49,96.75 52.4,94.66 41.57,94.66 35.62,88.72 35.62,78.55 31.67,74.59 30.94,74.59 v2(30.62,74.91)
  BOTTOM w0.102: CPU1.AC6 107.37,84.83 v2(107.07,84.53)
DP1_HPD_CPU: length 361.1
  TOP w0.127: 135.62,86.91 136.08,87.37 137.66,87.37 137.86,87.17 Q401.5 ; 135.62,86.91 R404.2 ; 135.62,86.91 135.62,87.44 136.08,87.9 139.38,87.9 140.58,86.7 141.37,86.7 142.87,85.2 151.8,85.2 151.91,85.31 157.37,85.31 158.92,83.76 158.92,82.4 160.44,80.87 160.44,77.31 161.3,76.45 161.3,75.11 v2(161.33,75.08) ; v2(20.71,75.13) 20.92,74.92 R7149.2
  L4SGND w0.127: v2(161.33,75.08) 161.58,74.82 166.89,74.82 167.77,73.93 176.57,73.93 177.08,74.44 v2(177.71,74.44)
  L6 w0.127: v2(20.71,75.13) 20.87,74.97 20.87,65.3 18.72,63.16 18.72,62.01 18.98,61.75 19.31,61.75 20.04,61.02 20.04,60.67 20.3,60.41 20.4,60.41 21.31,59.49 21.31,55.74 20.17,54.6 19.95,54.38 19.95,51.07 18.09,49.21 18.09,42.67 18.34,42.42 18.39,42.37 18.39,42 18.34,41.95 18.34,36.4 15.03,33.09 15.03,31.64 13.39,30 12.83,30 11.92,29.1 9.95,29.1 v2(8.8,27.96) ; v2(7.94,25.42) 7.94,18.4 11.71,14.62 14.26,14.62 16.04,12.85 21.38,12.85 22.28,13.75 23.54,13.75 23.59,13.8 25.17,13.8 25.33,13.95 30.54,13.95 32.82,11.66 33.22,11.66 34.56,10.32 39.4,10.32 39.45,10.27 39.7,10.27 40.62,9.35 41.07,9.35 42.11,8.32 69.7,8.32 69.84,8.46 73.96,8.46 74.4,8.03 81.43,8.03 81.84,8.44 94.57,8.44 94.95,8.06 95.34,8.06 95.39,8.01 104.7,8.01 107.14,8.01 107.19,8.06 107.21,8.06 108.11,8.96 122.46,8.96 125.71,12.2 125.71,14 129.45,17.75 142.99,17.75 150.91,9.83 151.08,9.83 154.54,9.83 154.87,10.16 155.59,10.16 165.61,20.18 165.61,26.93 171.29,32.61 171.29,34.98 172.92,36.62 172.92,37.41 172.92,43.28 174.5,44.85 174.5,47.99 173.7,48.79 173.7,51.95 173.23,52.42 173.23,57.11 174.35,58.23 174.35,61 175.17,61.83 175.17,66.19 176.7,67.72 176.7,73.42 v2(177.71,74.44)
  BOTTOM w0.127: R7227.1 8.85,28.01 v2(8.8,27.96) 8.8,27.22 R407.2 8.8,26.94 8.8,26.28 v1(8.65,26.13) v2(7.94,25.42)
DP1_HPD_CPU_R: length 7.9
  TOP w0.127: v1(137.38,87.03) Q401.6 136.59,86.53 R404.1 136.08,86.12 135.32,86.12 R405.2 R403.2 135.37,84.8 v2(135.65,85.08)
  BOTTOM w0.127: v2(135.65,85.08) 135.65,84.87 135.99,84.52 136.62,84.52 CPU1.CM6
DP2_AUX_C2_N: length 4.3
  TOP w0.102: v2(16.38,36.78) 16.34,36.78 16.3,36.83 16.3,36.84 16.14,37 15.75,37 14.94,36.19 14.11,36.19 U7201.J2
  BOTTOM w0.102: v2(16.38,36.78) 16.83,37.23 RN7207.6
DP2_AUX_C2_P: length 3.7
  TOP w0.102: v2(16.3,37.41) 16.11,37.22 15.66,37.22 14.85,36.42 14.38,36.42 U7201.J1
  BOTTOM w0.102: v2(16.3,37.41) 16.62,37.73 RN7207.7
DP2_AUX_C_N: length 3.3
  TOP w0.102: U7101.25 19.12,72.56 18.46,73.22 R7101.2 18.48,73.25 C7102.1 v1(17.59,74.14)
DP2_AUX_C_P: length 2.3
  TOP w0.102: C7101.1 19.24,73.25 R7102.2 19.1,73.05 19.1,72.91 19.35,72.66 19.35,72.32 19.52,72.15 U7101.24
DP2_AUX_CPU_N: length 130.1
  TOP w0.102: v2(17.87,75.89) 17.87,75.85 18.48,75.23 C7102.2
  L6 w0.089: v2(108.51,93.96) 108.51,94.64 105.86,97.3 102.45,97.3 101.73,97.3 101.57,97.3 99.49,97.3 99.37,97.3 99.29,97.3 99.29,97.3 98.8,97.3 98.76,97.3 88.67,97.3 82.43,103.54 49.3,103.54 47.36,101.59 36.4,101.59 31.13,96.32 18.55,96.32 15.04,92.81 15.04,84.06 15.98,83.12 15.98,79.42 18.16,77.23 18.16,76.18 v2(17.87,75.89)
  BOTTOM w0.076: 108.05,90.94 108.05,90.92 108.02,90.89 108.02,90.31 108.25,90.08 108.25,87.69 108.25,87.62 108.25,87.54 108.44,87.35 108.44,87.09 CPU1.AD4
  BOTTOM w0.102: 108.05,90.94 108.05,91.08 108.05,91.36 107.68,91.73 107.68,92.54 108.37,93.23 108.37,93.81 v2(108.51,93.96)
DP2_AUX_CPU_P: length 130.1
  TOP w0.102: v2(18.66,75.89) 18.48,75.71 18.48,75.56 C7101.2
  L6 w0.089: v2(18.66,75.89) 18.35,76.19 18.35,77.31 16.17,79.49 16.17,83.2 15.23,84.14 15.23,92.73 18.63,96.13 31.2,96.13 36.48,101.4 47.44,101.4 49.38,103.35 82.35,103.35 88.59,97.11 98.84,97.11 98.88,97.11 99.37,97.11 99.49,97.11 99.49,97.11 101.57,97.11 101.73,97.11 102.35,97.11 105.78,97.11 108.32,94.57 108.32,94.37 108.23,94.28 107.76,94.28 107.67,94.2 v2(107.67,93.96)
  BOTTOM w0.076: CPU1.AD3 108.11,87.13 108,87.13 107.92,87.2 107.92,87.38 108.09,87.55 108.09,87.62 108.09,87.65 108.09,90.01 107.86,90.24 107.86,90.89 107.82,90.92 107.82,90.94
  BOTTOM w0.102: 107.82,90.94 107.82,91.17 107.82,91.17 107.82,91.27 107.46,91.64 107.46,92.64 108.14,93.32 108.14,93.52 108.04,93.62 107.77,93.62 107.67,93.71 v2(107.67,93.96)
DP2_DDI_TX_C_N0: length 3.1
  TOP w0.102: C7113.2 22.8,65.55 22.57,65.32 22.31,65.32 22.14,65.5 22.14,66.73 21.9,66.97 21.53,66.97 21.45,67.05 U7101.10
DP2_DDI_TX_C_N1: length 2.4
  TOP w0.102: U7101.13 21.74,68.25 21.82,68.17 22.44,68.17 22.75,67.85 22.75,67.68 22.85,67.58 23,67.58 23.1,67.68 C7107.2
DP2_DDI_TX_C_N2: length 2.1
  TOP w0.102: C7108.2 22.9,69.46 22.34,69.46 22.21,69.33 21.78,69.33 21.66,69.45 U7101.16
DP2_DDI_TX_C_N3: length 2.3
  TOP w0.102: U7101.19 21.74,70.65 21.75,70.64 21.89,70.64 22.44,71.19 22.82,71.19 C7110.2
DP2_DDI_TX_C_P0: length 3.1
  TOP w0.102: U7101.9 21.56,66.65 21.65,66.74 21.81,66.74 21.91,66.64 21.91,65.4 22.22,65.09 22.54,65.09 22.8,64.84 C7112.2
DP2_DDI_TX_C_P1: length 2.5
  TOP w0.102: U7101.12 21.74,67.85 21.82,67.94 22.34,67.94 22.52,67.76 22.52,67.59 22.75,67.35 22.98,67.35 23.1,67.23 C7114.2
DP2_DDI_TX_C_P2: length 2.1
  TOP w0.102: C7109.2 22.82,69.23 22.44,69.23 22.31,69.11 21.71,69.11 21.65,69.05 U7101.15
DP2_DDI_TX_C_P3: length 2.3
  TOP w0.102: C7111.2 22.95,70.96 22.54,70.96 21.99,70.41 21.89,70.41 21.74,70.25 U7101.18
DP2_DDI_TX_N0: length 122.3
  TOP w0.102: C7113.1 23.92,65.37 24.08,65.37 v2(24.45,65.74)
  L6 w0.089: v2(24.45,65.74) 24.18,65.47 24.13,65.47 23.89,65.47 23.52,65.1 23.52,64.56 23.88,64.19 24.04,64.19 25.17,64.19 27.13,66.16 27.13,68.11 29.64,70.63 29.64,70.79 29.64,89.52 35.28,95.17 36.87,95.17 39.92,98.21 49.61,98.21 51.3,99.9 56.71,99.9 57,100.2 79.5,100.2 83.25,96.45 85.51,96.45 87.57,94.39 99.85,94.39 103.24,91 105.63,91 v2(105.93,90.7)
  BOTTOM w0.076: CPU1.AC4 107.49,86.52 107.33,86.67 107.33,87.05 107.31,87.12 107.29,87.15 107.19,87.39 107.19,87.64 107.22,87.74 107.22,87.96 107.21,87.99 107.19,88.06 107.19,88.43 107.38,88.62 107.38,89.21 106.87,89.71 106.83,89.71 106.81,89.73
  BOTTOM w0.102: v2(105.93,90.7) 106.22,90.99 106.42,90.99 106.52,90.89 106.52,90.02 106.74,89.8 106.81,89.73
DP2_DDI_TX_N1: length 118.5
  TOP w0.102: C7107.1 24.02,67.58 24.12,67.48 24.58,67.48 24.75,67.65 v2(24.75,67.81)
  L6 w0.089: v2(104.82,93.11) 105.12,92.81 105.12,92.63 104.75,92.26 103.28,92.26 100.27,95.27 100.03,95.27 87.89,95.27 85.86,97.3 83.65,97.3 79.8,101.15 56.54,101.15 56.15,100.75 50.95,100.75 49.3,99.1 39.57,99.1 36.51,96.04 34.81,96.04 28.79,90.02 28.79,71.29 26.23,68.73 26.23,67.84 25.74,67.35 25.01,67.35 24.75,67.62 v2(24.75,67.81)
  BOTTOM w0.076: 107.17,90.8 107.17,90.78 107.21,90.74 107.21,90.09 107.71,89.58 107.71,88.27 CPU1.AC1
  BOTTOM w0.102: 107.17,90.8 107.17,91.14 106.29,92.02 105.81,92.02 105.39,92.43 105.39,92.65 105.29,92.75 104.92,92.75 104.82,92.86 v2(104.82,93.11)
DP2_DDI_TX_N2: length 123.3
  TOP w0.102: C7108.1 24.04,69.47 24.15,69.36 24.52,69.36 24.63,69.47 v2(24.63,69.72)
  L6 w0.089: v2(24.63,69.72) 24.28,69.37 23.88,69.37 23.71,69.54 23.71,69.62 23.71,72.54 27.61,76.44 27.61,90.48 34.36,97.22 35.88,97.22 39.35,100.69 47.72,100.69 49.66,102.63 82.13,102.63 88.33,96.44 103.97,96.44 107.33,93.07 109.56,93.07 v2(109.73,92.89)
  BOTTOM w0.076: 109.47,90.44 109.47,90.42 109.44,90.38 109.44,89.43 108.98,88.97 108.98,88.59 109.17,88.41 109.17,88.05 109.13,87.96 109.13,87.74 109.17,87.65 109.17,87.39 109.06,87.13 109.04,87.1 109.02,87.05 109.02,86.74 108.98,86.7 CPU1.AE4
  BOTTOM w0.102: 109.47,90.44 109.47,92.73 109.63,92.89 v2(109.73,92.89)
DP2_DDI_TX_N3: length 116.3
  TOP w0.102: v2(26.2,72.66) 26.15,72.66 25.95,72.46 25.52,72.46 24.92,71.86 24.92,71.5 24.66,71.24 24.35,71.24 C7110.1
  L6 w0.089: v2(108.19,92.43) 107.97,92.21 107.53,92.21 103.77,95.97 88.13,95.97 81.93,102.16 49.87,102.16 47.79,100.08 39.58,100.08 36.26,96.75 34.55,96.75 28.08,90.28 28.08,73.35 27.18,72.45 26.42,72.45 v2(26.2,72.66)
  BOTTOM w0.076: CPU1.AE1 108.6,88.32 108.6,89.17 108.85,89.43 108.85,90.44 108.88,90.47 108.88,90.56
  BOTTOM w0.102: v2(108.19,92.43) 108.6,92.03 108.6,91.72 108.88,91.43 108.88,90.56
DP2_DDI_TX_P0: length 122.3
  TOP w0.102: v2(24.45,64.96) 24.27,65.14 24.04,65.14 C7112.1
  L6 w0.089: v2(24.45,64.96) 24.13,65.28 23.97,65.28 23.71,65.02 23.71,64.64 23.96,64.38 25.09,64.38 26.94,66.24 26.94,68.19 29.45,70.71 29.45,89.6 35.21,95.36 36.79,95.36 39.84,98.4 49.53,98.4 51.22,100.09 56.63,100.09 56.92,100.39 79.58,100.39 83.33,96.64 85.59,96.64 87.65,94.58 99.93,94.58 103.32,91.19 105.62,91.19 v2(105.93,91.51)
  BOTTOM w0.076: 106.97,89.89 106.99,89.88 106.99,89.83 107.54,89.27 107.54,88.55 107.35,88.36 107.35,88.08 107.39,87.99 107.39,87.71 107.35,87.62 107.35,87.43 107.43,87.25 107.53,87.22 107.68,87.22 107.89,87.01 107.89,86.68 107.8,86.59 107.69,86.59 107.61,86.67 CPU1.AC3
  BOTTOM w0.102: 106.97,89.89 106.75,90.11 106.75,90.98 106.52,91.22 106.22,91.22 v2(105.93,91.51)
DP2_DDI_TX_P1: length 118.5
  TOP w0.102: v2(24.73,67.02) 24.5,67.25 24.22,67.25 C7114.1
  L6 w0.089: v2(105.62,93.11) 105.31,92.8 105.31,92.55 104.83,92.07 103.2,92.07 100.19,95.08 100.11,95.08 87.82,95.08 85.78,97.11 83.57,97.11 79.72,100.96 56.62,100.96 56.23,100.56 51.03,100.56 49.37,98.91 39.65,98.91 36.59,95.85 34.89,95.85 28.98,89.94 28.98,71.21 26.42,68.65 26.42,67.76 25.82,67.16 24.87,67.16 v2(24.73,67.02)
  BOTTOM w0.076: CPU1.AC2 107.63,87.53 107.88,88.1 107.88,89.65 107.37,90.16 107.37,90.74 107.4,90.78 107.4,90.8
  BOTTOM w0.102: v2(105.62,93.11) 105.62,92.53 105.91,92.25 106.39,92.25 107.4,91.23 107.4,90.8
DP2_DDI_TX_P2: length 123.3
  TOP w0.102: v2(24.63,68.93) C7109.1
  L6 w0.089: v2(109.73,93.53) 109.72,93.53 109.45,93.26 107.41,93.26 104.05,96.63 88.4,96.63 82.21,102.82 49.58,102.82 47.64,100.88 39.27,100.88 35.8,97.41 34.28,97.41 27.42,90.56 27.42,76.52 23.52,72.62 23.52,69.7 23.52,69.46 23.8,69.18 24.37,69.18 v2(24.63,68.93)
  BOTTOM w0.076: 109.24,90.44 109.24,90.42 109.27,90.38 109.27,89.49 108.81,89.04 108.81,88.52 109,88.34 109,88.08 108.97,87.99 108.97,87.71 109,87.62 109,87.43 108.91,87.2 CPU1.AE3
  BOTTOM w0.102: v2(109.73,93.53) 109.24,93.03 109.24,90.44
DP2_DDI_TX_P3: length 116.2
  TOP w0.102: v2(26.2,72.03) 26,72.23 25.61,72.23 25.15,71.77 25.15,71.4 24.75,71.01 24.32,71.01 C7111.1
  L6 w0.089: v2(26.2,72.03) 26.43,72.26 27.26,72.26 28.27,73.27 28.27,90.2 34.63,96.56 36.34,96.56 39.66,99.89 47.87,99.89 49.95,101.97 81.85,101.97 88.05,95.78 103.69,95.78 107.45,92.02 107.97,92.02 v2(108.19,91.8)
  BOTTOM w0.076: 108.66,90.56 108.66,90.54 108.67,90.52 108.67,89.5 108.42,89.25 108.42,88.11 CPU1.AE2
  BOTTOM w0.102: v2(108.19,91.8) 108.66,91.33 108.66,90.56
DPEQ0_A1: length 3.4
  TOP w0.127: v2(22.19,68.6) 22.13,68.65 U7101.14
  BOTTOM w0.127: R7172.1 22.14,68.65 v2(22.19,68.6) 22.29,68.5 22.9,68.5 v1(22.9,67.61)
DPEQ1: length 6.6
  TOP w0.127: v1(14.19,64.67) 14.19,64.28 14.57,63.9 R7170.1 R7147.2 15.69,63.42 16.22,63.42 16.93,64.13 17.13,64.13 17.24,64.24 17.7,64.24 18.32,64.85 U7101.2
EC_AGND: length 13.4
  TOP w0.508: v2(22.14,21.61) 22.27,21.61 22.65,21.99 R2444.2 23.36,21.13 C2408.2
  L6 w0.508: v2(19.72,20.85) 20.49,21.61 v2(22.14,21.61)
  BOTTOM w0.203: 22.77,21.59 U2401.112
  BOTTOM w0.508: 22.77,21.59 22.75,21.61 v2(22.14,21.61) 21.71,21.61 C2441.2 21.5,20.9 C2435.2 ; C2422.2 19.67,18 R2441.2 19.7,18.76 C2407.2 19.65,20.01 v1(19.57,20.08) 19.72,20.24 v2(19.72,20.85) 18.89,20.85 R2445.2
EDP_AUX_CON_N: length 3.3
  TOP w0.102: v1(89.55,97.79) v2(89.8,98.32) 89.68,98.44 89.68,99.32 C5511.1
  BOTTOM w0.102: v2(89.8,98.32) 89.62,98.13 89.62,97.61 89.65,97.57 LCD1.8
EDP_AUX_CON_P: length 3.7
  TOP w0.102: C5510.1 89.07,99.23 89.17,99.13 89.35,99.13 89.45,99.03 89.45,98.6 v2(89.17,98.32) v1(88.68,98.67)
  BOTTOM w0.102: LCD1.7 89.15,97.51 89.39,97.75 89.39,98.1 v2(89.17,98.32)
EDP_AUX_CPU_N: length 52.6
  TOP w0.102: C5511.2 89.6,100.61 89.6,101.06 89.2,101.47 89.03,101.47 88.56,101.94 v2(88.56,102.51)
  L6 w0.089: v2(113.5,93.39) 113.55,93.39 114.35,94.19 114.35,98.43 114.35,99.39 111.37,102.37 108.08,102.37 105.37,105.07 88.36,105.07 86.54,103.25 86.54,101.87 86.92,101.49 87.91,101.49 88.42,102 88.42,102.37 v2(88.56,102.51)
  BOTTOM w0.076: CPU1.AH4 110.62,86.78 110.88,87.05 110.88,87.35 110.7,87.54 110.7,87.62 110.7,87.69 110.7,89.1 111.38,89.79 111.42,89.79 111.44,89.8
  BOTTOM w0.102: 112.43,92.09 112.43,92.32 v2(113.5,93.39) ; 112.43,92.09 v1(112.59,92.09) ; 112.43,92.09 112.43,90.8 111.44,89.8
EDP_AUX_CPU_P: length 52.2
  TOP w0.102: v2(87.92,102.51) 87.92,102.25 88.02,102.15 88.23,102.15 88.33,102.05 88.33,101.84 88.93,101.24 89.1,101.24 89.37,100.97 89.37,100.69 C5510.2
  L6 w0.089: v2(87.92,102.51) 88.23,102.2 88.23,102.08 87.83,101.68 87,101.68 86.73,101.95 86.73,103.17 88.44,104.88 105.29,104.88 108,102.18 111.29,102.18 114.16,99.31 114.16,98.51 114.16,94.26 113.81,93.91 113.59,93.91 113.5,94 v2(113.5,94.23)
  BOTTOM w0.076: 111.28,89.96 111.26,89.95 111.26,89.91 110.53,89.17 110.53,87.69 110.53,87.62 110.53,87.55 110.36,87.38 110.36,87.21 110.44,87.13 110.55,87.13 CPU1.AH3
  BOTTOM w0.102: 111.28,89.96 112.21,90.89 112.21,92.41 113.07,93.28 113.07,93.46 ; v1(112.89,93.46) 113.07,93.46 ; 113.07,93.46 113.07,94.13 113.17,94.23 v2(113.5,94.23)
EDP_HPD_CON: length 4.7
  TOP w0.102: R5506.1 97.32,100.3 97.24,100.22 RN5502.8 96.89,99.81 96.33,99.26 v1(96.33,99.1) 96.33,98.54 v2(96.56,98.32)
  BOTTOM w0.102: v2(96.56,98.32) 96.48,98.24 96.48,97.68 96.18,97.38 96.18,97.38 96.15,97.35 LCD1.21
EDP_HPD_CPU: length 64
  TOP w0.102: R5506.2 97.32,102.38 v2(97.45,102.51) v1(97.73,102.99)
  L4SGND w0.102: v2(141.92,85.29) 141.62,85.29 139.64,87.27 139.64,88.84 137.31,91.17 137.31,93.35 136.77,93.9 135.68,93.9 132.5,97.07 132.5,100.96 131.61,101.85 128,101.85 127.22,101.07 105.39,101.07 103.09,103.37 98.31,103.37 v2(97.45,102.51)
  BOTTOM w0.076: CPU1.CM7 137.7,84.13 138.75,84.13 arc(138.82,84.18) 138.91,84.19 140.53,84.19 140.62,84.28
  BOTTOM w0.102: v2(141.92,85.29) 141.62,85.29 140.62,84.28
EDP_RCOMP_CPU: length 2.4
  TOP w0.127: v1(112.07,85.52) v2(112.6,85.11) 113.24,84.47 R401.2
  BOTTOM w0.127: CPU1.AM6 112.89,84.83 v2(112.6,85.11)
EDP_TX_CON_N0: length 4.7
  TOP w0.102: C5506.1 95.64,100.81 95.64,100.59 95.19,100.13 95.19,98.87 ; 95.19,98.87 95.19,98.52 v2(94.98,98.32) ; 95.19,98.87 v1(95.04,98.87)
  BOTTOM w0.102: LCD1.19 95.15,97.57 95.24,97.66 95.24,98.07 v2(94.98,98.32)
EDP_TX_CON_N1: length 4.4
  TOP w0.102: 93.71,98.98 93.71,98.52 v2(93.51,98.32) ; 93.71,98.98 v1(93.59,98.98) ; 93.71,98.98 93.71,100.63 93.64,100.7 C5501.1
  BOTTOM w0.102: v2(93.51,98.32) 93.79,98.04 93.79,97.71 93.65,97.57 LCD1.16
EDP_TX_CON_N2: length 4.6
  TOP w0.102: 92.19,98.9 92.19,99.38 91.82,99.75 91.82,100.91 C5533.1 ; 92.19,98.9 92.19,98.52 v2(91.99,98.32) ; 92.19,98.9 v1(92.06,98.9)
  BOTTOM w0.102: v2(91.99,98.32) 92.24,98.06 92.24,97.66 92.15,97.57 LCD1.13
EDP_TX_CON_N3: length 3.6
  TOP w0.102: v1(90.75,97.58) v2(90.59,98.32) 90.82,98.54 90.82,99.24 C5532.1
  BOTTOM w0.102: LCD1.10 90.65,97.57 90.79,97.71 90.79,98.12 v2(90.59,98.32)
EDP_TX_CON_P0: length 4.7
  TOP w0.102: v2(95.62,98.32) 95.42,98.52 95.42,100.04 95.7,100.32 ; v1(95.8,100.22) 95.7,100.32 ; 95.7,100.32 95.87,100.49 95.87,100.73 C5509.1
  BOTTOM w0.102: v2(95.62,98.32) 95.46,98.16 95.46,97.71 95.65,97.52 LCD1.20
EDP_TX_CON_P1: length 4.5
  TOP w0.102: v2(94.15,98.32) 93.94,98.52 93.94,100.17 ; 93.94,100.17 93.94,100.54 C5504.1 ; 93.94,100.17 v1(94.07,100.17)
  BOTTOM w0.102: v2(94.15,98.32) 94.01,98.18 94.01,97.71 94.15,97.57 LCD1.17
EDP_TX_CON_P2: length 4.9
  TOP w0.102: v2(92.65,98.29) 92.42,98.52 92.42,99.48 92.05,99.85 92.05,100.12 ; 92.05,100.12 92.05,100.5 92.18,100.63 92.39,100.63 92.5,100.73 C5519.1 ; 92.05,100.12 v1(92.24,100.12)
  BOTTOM w0.102: LCD1.14 92.65,97.57 92.47,97.75 92.47,98.11 v2(92.65,98.29)
EDP_TX_CON_P3: length 4.4
  TOP w0.102: C5531.1 91.05,99.17 91.05,98.49 v2(91.23,98.32) 91.17,97.83 91.17,97.63 91.43,97.38 v1(91.83,97)
  BOTTOM w0.102: LCD1.11 91.15,97.57 91.01,97.71 91.01,98.11 v2(91.23,98.32)
EDP_TX_CPU_N0: length 52.7
  TOP w0.102: C5506.2 v2(95.54,102.51)
  L6 w0.089: v2(95.54,102.51) 95.54,102.05 94.58,101.08 89.14,101.08 88.9,100.84 88.9,99.94 89.18,99.66 97.14,99.66 97.34,99.86 97.34,101.54 97.43,101.63 97.72,101.63 97.81,101.54 97.81,99.86 98.01,99.66 98.46,99.66 98.66,99.86 98.66,101.54 98.75,101.63 99.04,101.63 99.13,101.54 99.13,99.86 99.33,99.66 105.98,99.66 106.83,98.81 110.64,98.81 111.49,97.97 111.49,96.89 110.74,96.14 v2(110.74,94.23)
  BOTTOM w0.076: 110.2,90.75 110.23,90.72 110.23,90.38 109.81,89.95 109.81,88.61 109.63,88.43 109.63,88.02 109.65,87.99 109.66,87.96 109.66,87.74 109.63,87.64 109.63,87.39 109.78,87.05 109.78,86.8 109.8,86.75 109.8,86.75 109.8,86.73 109.88,86.65 CPU1.AG4
  BOTTOM w0.102: 110.2,91.53 110.2,92.92 110.99,93.71 110.99,93.96 111,93.97 v2(110.74,94.23) ; 110.2,91.53 110.2,90.75 ; 110.2,91.53 v1(110.05,91.53)
EDP_TX_CPU_N1: length 49.6
  TOP w0.102: C5501.2 v2(93.64,102.51)
  L6 w0.089: v2(93.64,102.51) 93.85,102.29 93.85,102.01 93.68,101.83 88.94,101.83 87.61,100.5 87.61,99.25 88.05,98.81 105.82,98.81 106.16,98.47 106.16,97.7 107.09,96.77 107.37,96.77 107.82,97.23 107.95,97.23 108.15,97.02 108.15,96.89 107.7,96.44 107.7,96.16 108.02,95.84 108.3,95.84 109.54,97.08 109.67,97.08 109.88,96.87 109.88,96.75 108.64,95.51 108.64,95.22 108.96,94.9 109.24,94.9 109.69,95.36 109.82,95.36 110.02,95.15 110.02,95.02 109.63,94.63 109.63,94.35 110.49,93.49 110.49,92.76 110.49,92.61 110.81,92.28 111.34,92.28 v2(111.6,92.03)
  BOTTOM w0.076: 111.14,90.7 111.13,90.68 111.13,90.35 110.32,89.54 110.32,88.1 110.07,87.53 CPU1.AG2
  BOTTOM w0.102: 111.14,90.7 111.14,90.85 ; 111.14,90.85 111.14,92.09 111.21,92.17 111.45,92.17 v2(111.6,92.03) ; 111.14,90.85 v1(111.32,90.85)
EDP_TX_CPU_N2: length 50.8
  TOP w0.102: v1(113.1,87.06) 113.38,87.71 113.4,87.92 113.38,88.08 113.26,88.4 v2(113.02,88.61) ; C5533.2 v2(91.73,102.51)
  L6 w0.089: v2(91.73,102.51) 91.8,102.57 91.8,103.14 92.41,103.75 103.16,103.75 103.76,103.15 103.76,102 103.45,101.68 100.5,101.68 100.25,101.44 100.25,100.96 100.54,100.68 106.2,100.68 107.13,99.75 111.24,99.75 112.87,98.13 112.87,96.13 112.28,95.55 112.28,91.02 112.54,90.76 113.61,90.76 114.15,90.22 114.15,88.96 113.81,88.61 v2(113.02,88.61)
  BOTTOM w0.076: v2(113.02,88.61) 112.65,88.82 111.78,88.82 111.61,88.65 111.61,88.05 111.58,87.96 111.58,87.74 111.61,87.65 111.61,87.39 111.5,87.13 111.48,87.1 111.46,87.05 111.46,86.74 111.42,86.7 CPU1.AJ4
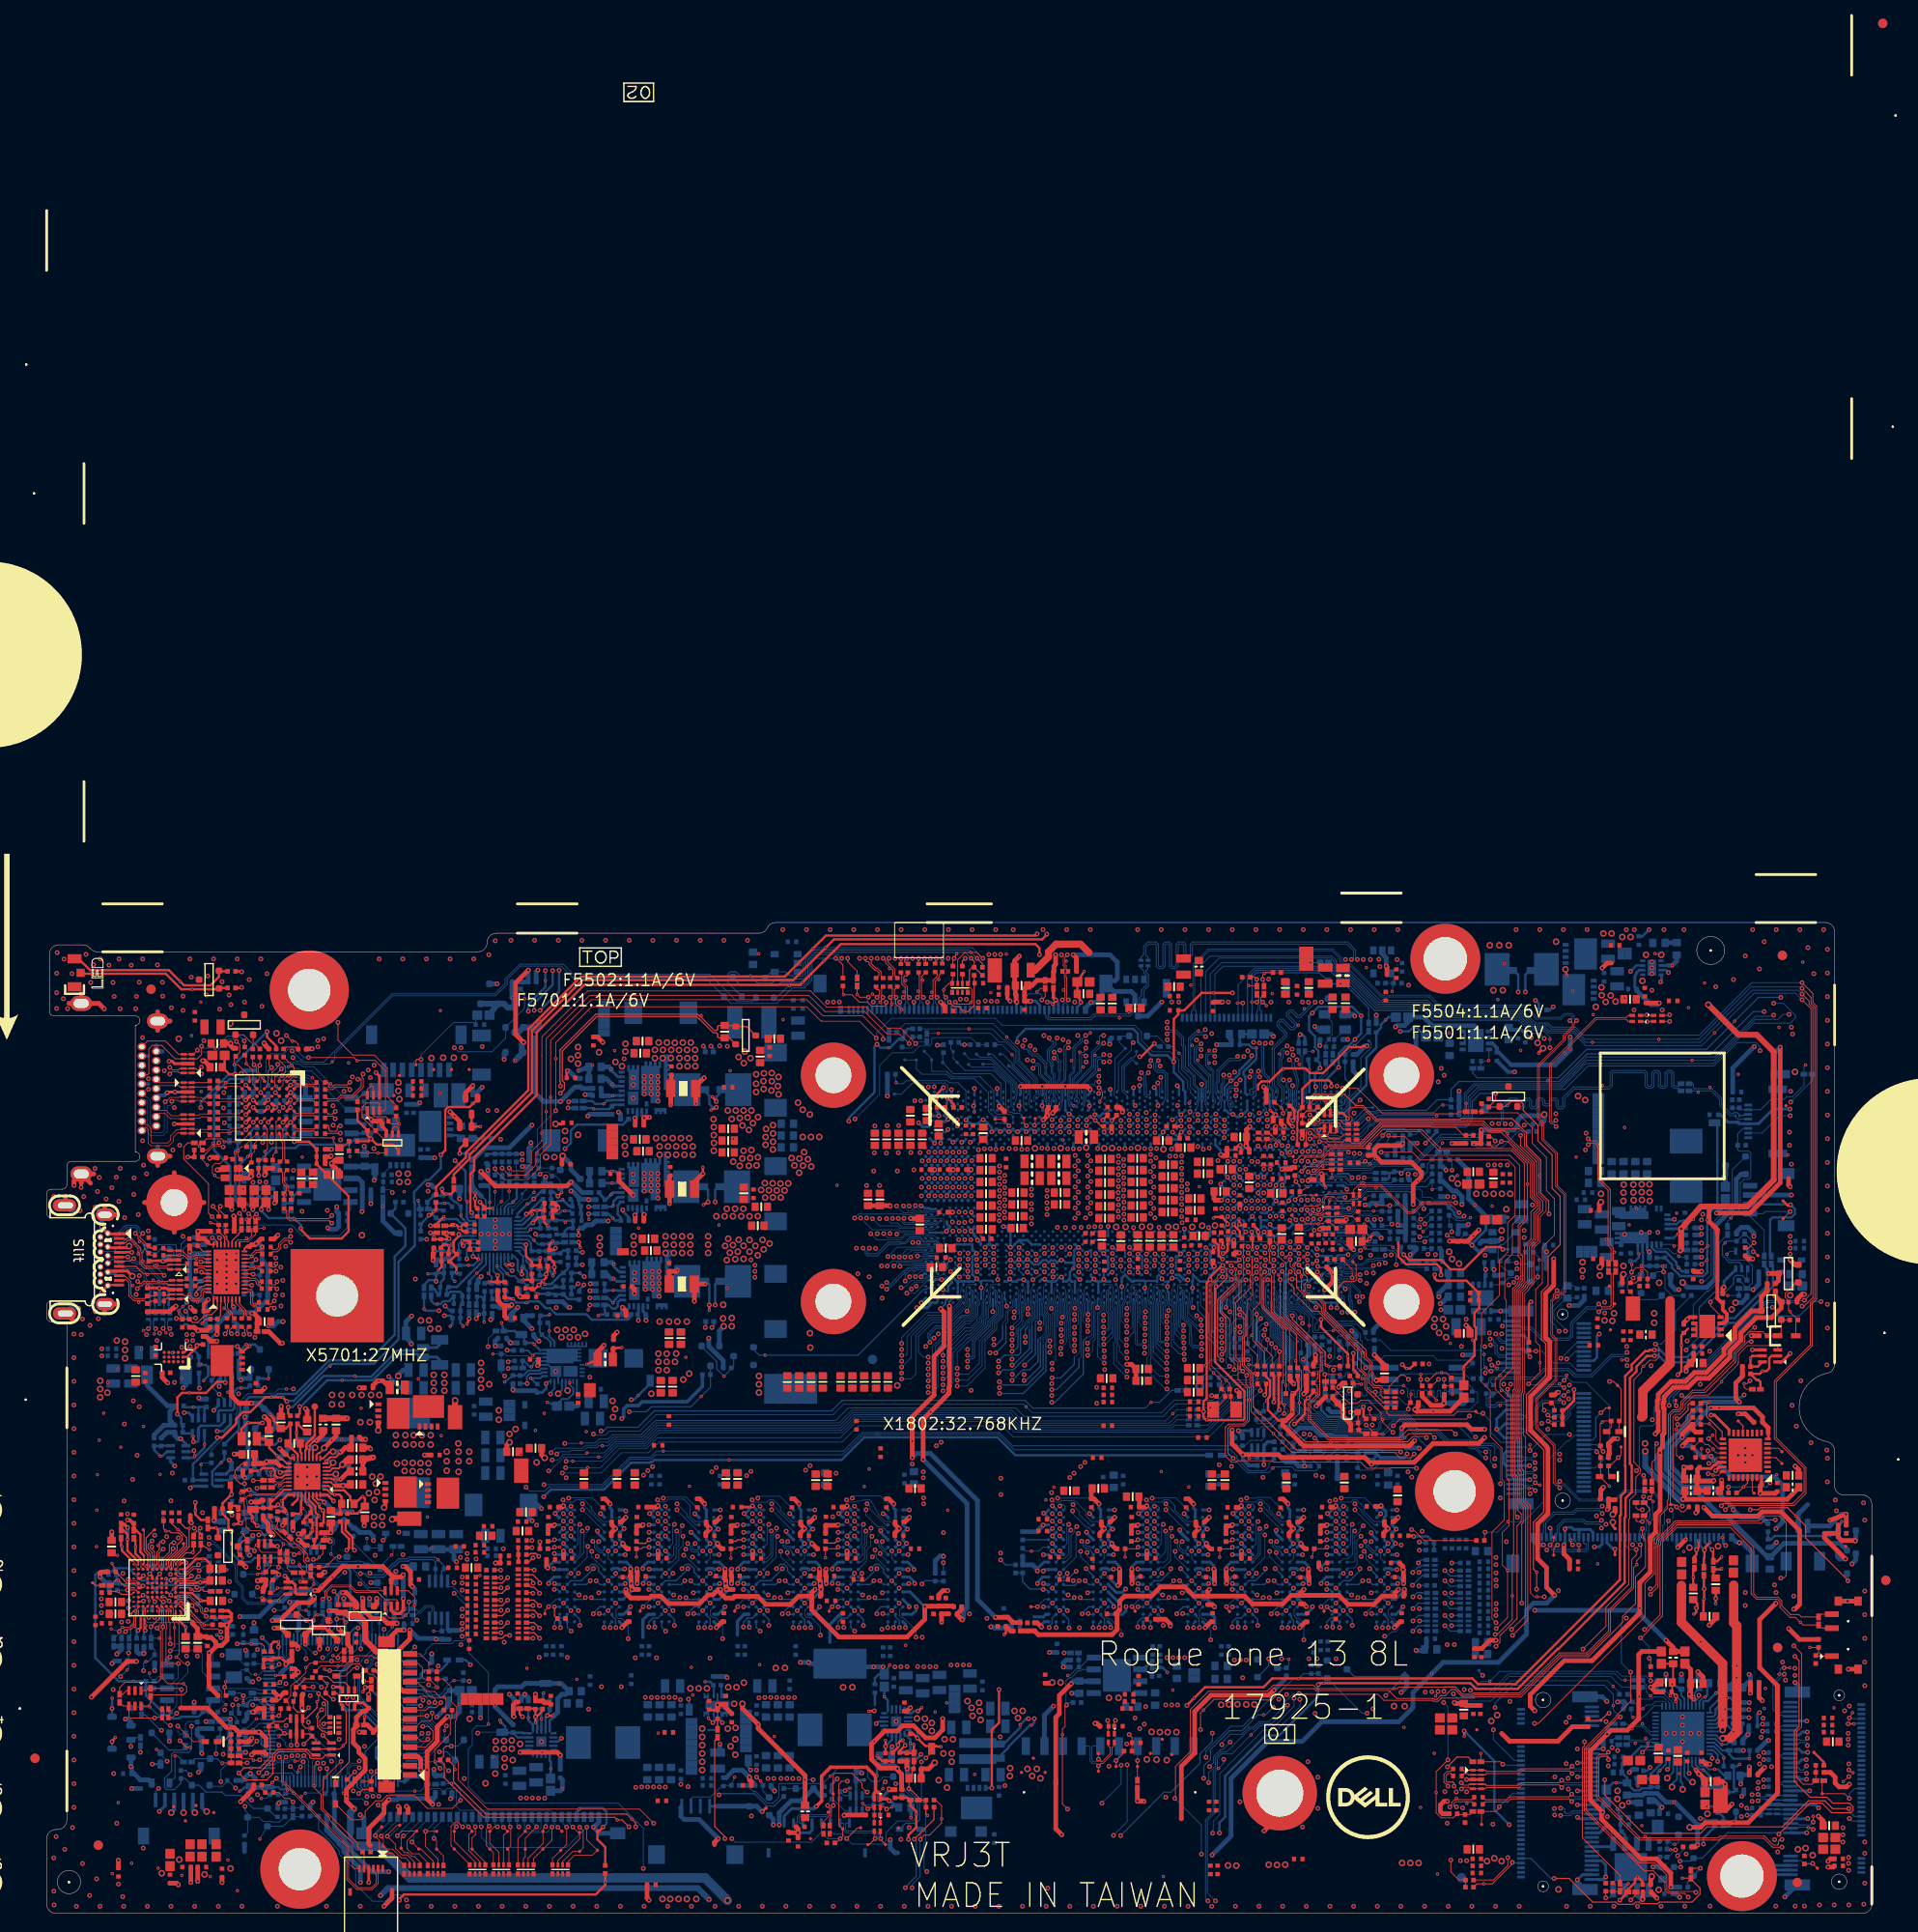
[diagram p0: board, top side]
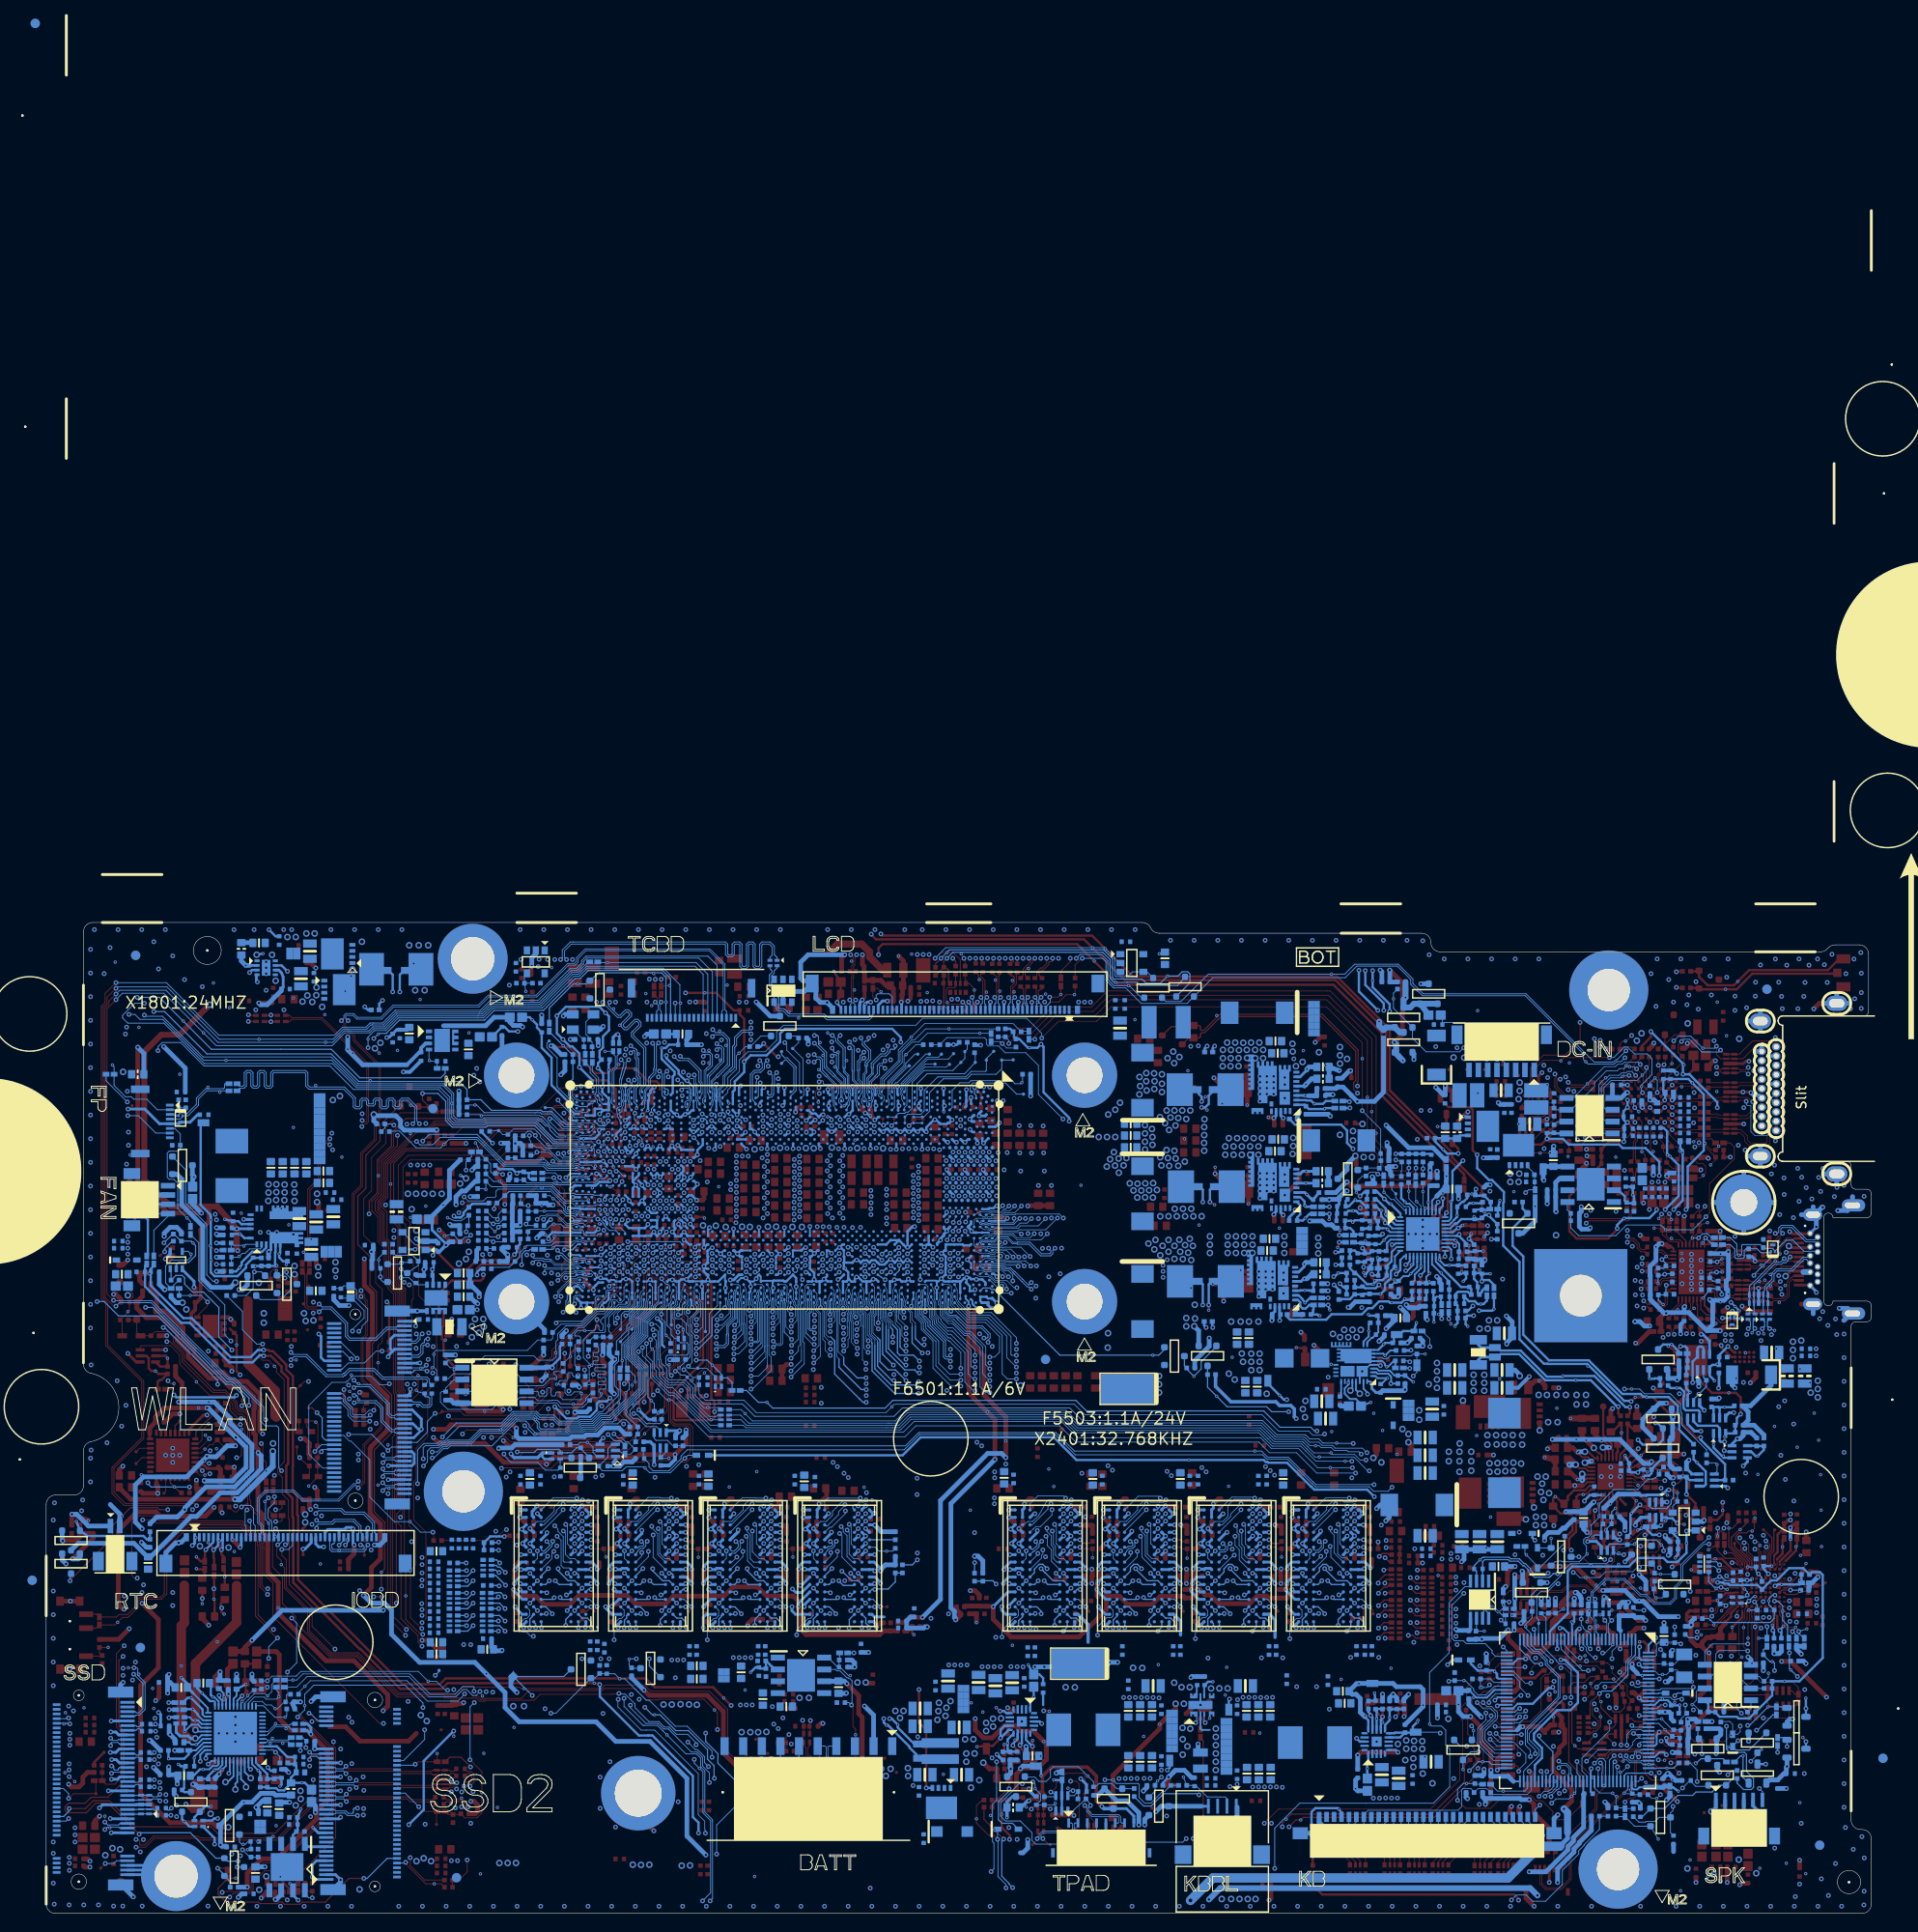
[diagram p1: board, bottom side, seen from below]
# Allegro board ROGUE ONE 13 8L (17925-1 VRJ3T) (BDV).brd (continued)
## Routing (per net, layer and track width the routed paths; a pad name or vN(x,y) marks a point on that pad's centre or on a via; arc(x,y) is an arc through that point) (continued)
EDP_TX_CPU_N3: length 49.2
  TOP w0.102: v2(89.83,102.51) 90.11,102.23 90.11,102.01 90.59,101.52 ; C5532.2 90.87,100.67 90.87,101.24 90.59,101.52 ; 90.59,101.52 v1(90.51,101.41)
  L6 w0.089: v2(89.83,102.51) 89.83,103.39 90.85,104.41 103.51,104.41 107.43,100.49 107.7,100.49 107.79,100.58 107.79,101.44 107.99,101.64 108.44,101.64 108.64,101.44 108.64,100.58 108.73,100.49 109.02,100.49 109.11,100.58 109.11,101.44 109.31,101.64 109.76,101.64 109.96,101.44 109.96,100.58 110.05,100.49 110.34,100.49 110.43,100.58 110.43,101.44 110.63,101.64 111.08,101.64 111.28,101.44 111.28,100.58 111.37,100.49 111.88,100.49 113.53,98.84 113.53,95.66 112.94,95.07 112.94,92.76 v2(113.52,92.18)
  BOTTOM w0.076: CPU1.AJ2 110.91,88.03 110.91,88.74 112.1,89.93 112.1,89.98 112.11,89.99
  BOTTOM w0.102: 112.11,89.99 112.64,90.51 112.64,91.65 112.9,91.92 113.26,91.92 v2(113.52,92.18)
EDP_TX_CPU_P0: length 53.2
  TOP w0.102: C5509.2 v2(96.18,102.51)
  L6 w0.089: v2(111.58,94.23) 111.58,94.47 111.42,94.63 111.02,94.63 110.93,94.72 110.93,96.07 111.68,96.82 111.68,98.05 110.72,99 106.91,99 106.06,99.85 99.41,99.85 99.32,99.94 99.32,101.62 99.12,101.82 98.67,101.82 98.47,101.62 98.47,99.94 98.38,99.85 98.09,99.85 98,99.94 98,101.62 97.8,101.82 97.35,101.82 97.15,101.62 97.15,99.94 97.06,99.85 89.26,99.85 89.09,100.02 89.09,100.77 89.22,100.89 94.66,100.89 95.73,101.97 95.73,101.98 95.75,101.99 95.75,102.08 v2(96.18,102.51)
  BOTTOM w0.076: 110.43,90.75 110.4,90.72 110.4,90.31 109.97,89.88 109.97,88.57 109.96,88.53 109.79,88.36 109.79,88.1 109.81,88.03 109.83,87.99 109.83,87.71 109.79,87.62 109.79,87.43 109.88,87.22 CPU1.AG3
  BOTTOM w0.102: v1(112.08,94.51) 111.8,94.23 v2(111.58,94.23) 111.21,93.86 111.21,93.62 110.43,92.83 110.43,90.75
EDP_TX_CPU_P1: length 49.5
  TOP w0.102: v2(94.27,102.51) 94.4,102.38 C5504.2
  L6 w0.089: v2(111.6,92.87) 111.6,92.56 111.51,92.47 110.89,92.47 110.68,92.69 110.68,93.57 109.82,94.43 109.82,94.55 110.21,94.94 110.21,95.23 109.9,95.55 109.61,95.55 109.16,95.09 109.03,95.09 108.83,95.3 108.83,95.43 110.07,96.67 110.07,96.95 109.75,97.27 109.46,97.27 108.22,96.03 108.1,96.03 107.89,96.24 107.89,96.36 108.34,96.81 108.34,97.1 108.03,97.42 107.74,97.42 107.29,96.96 107.16,96.96 106.35,97.78 106.35,98.55 105.9,99 88.13,99 87.8,99.33 87.8,100.42 89.02,101.64 93.76,101.64 94.04,101.93 94.04,102.28 v2(94.27,102.51)
  BOTTOM w0.076: 110.91,90.7 110.96,90.65 110.96,90.42 110.15,89.61 110.15,88.64 CPU1.AG1
  BOTTOM w0.102: v2(111.6,92.87) 111.45,92.72 111.45,92.5 111.35,92.4 111.12,92.4 111.05,92.33 ; 110.91,90.7 110.91,92.19 111.05,92.33 ; v1(110.94,92.44) 111.05,92.33
EDP_TX_CPU_P2: length 48.8
  TOP w0.102: C5519.2 92.15,102.14 92.12,102.28 92.25,102.48 v2(92.37,102.51)
  L6 w0.089: v2(92.37,102.51) 91.99,102.89 91.99,103.06 92.49,103.56 103.08,103.56 103.57,103.08 103.57,102.08 103.37,101.87 100.42,101.87 100.06,101.52 100.06,100.88 100.46,100.49 106.12,100.49 107.05,99.56 111.16,99.56 112.68,98.05 112.68,96.21 112.09,95.63 112.09,90.94 112.46,90.57 113.53,90.57 113.96,90.14 113.96,89.04 113.73,88.8 113.48,88.8 113.42,88.86 113.42,89.15 113.33,89.25 v2(112.99,89.25)
  BOTTOM w0.076: v2(112.99,89.25) 112.87,89.38 112.64,89.38 112.56,89.3 112.56,89.07 112.48,88.99 111.72,88.99 111.44,88.71 111.44,88.08 111.41,87.99 111.41,87.71 111.45,87.62 111.45,87.43 111.35,87.2 111.34,87.18 CPU1.AJ3
EDP_TX_CPU_P3: length 49.2
  TOP w0.102: v2(90.46,102.51) 90.34,102.38 90.34,102.1 91.1,101.34 91.1,100.64 C5531.2
  L6 w0.089: v2(113.52,91.37) 113.21,91.37 113.12,91.46 113.12,92.31 112.75,92.68 112.75,95.15 113.34,95.74 113.34,98.76 111.8,100.3 111.29,100.3 111.09,100.5 111.09,101.36 111,101.45 110.71,101.45 110.62,101.36 110.62,100.5 110.42,100.3 109.97,100.3 109.77,100.5 109.77,101.36 109.68,101.45 109.39,101.45 109.3,101.36 109.3,100.5 109.1,100.3 108.65,100.3 108.45,100.5 108.45,101.36 108.36,101.45 108.07,101.45 107.98,101.36 107.98,100.5 107.78,100.3 107.35,100.3 103.43,104.22 90.93,104.22 90.02,103.31 90.02,103.03 90.11,102.94 90.56,102.94 90.64,102.85 90.64,102.69 v2(90.46,102.51)
  BOTTOM w0.076: 112.28,89.83 112.26,89.81 112.22,89.81 111.07,88.67 111.07,88.43 CPU1.AJ1
  BOTTOM w0.102: 112.87,90.54 112.87,90.42 112.28,89.83 ; 112.87,90.54 v1(113.04,90.54) ; 112.87,90.54 112.87,91.56 112.99,91.69 113.21,91.69 v2(113.52,91.37)
EDP_VDD_EN: length 76.5
  L4SGND w0.102: v2(85.38,102.51) 86.14,101.75 99.31,101.75 99.31,101.75 99.71,101.75 100.87,100.58 126.93,100.58 129.55,97.96 129.55,97.58 134.67,92.47 134.67,87.88 133.34,86.56 133.34,83.08 133.77,82.64 133.77,82.14 v2(134.15,81.76)
  BOTTOM w0.102: CPU1.CG11 134.49,82.04 134.2,81.76 v2(134.15,81.76) ; v2(85.38,102.51) 84.98,102.91 82.64,102.91 81.99,102.26 81.99,100.93 81.97,100.91 81.97,100.34 81.97,100.34 81.97,100.22 81.52,99.77 81.52,99.77 81.31,99.56 v1(79.77,99.56) 79.67,99.56 78.39,98.28 D5501.1
EMMC_RCOMP: length 2.2
  TOP w0.254: v1(137.35,77.87) R2108.1
  TOP w0.508: v2(136.9,79.39) 137,79.3 R2108.1
  BOTTOM w0.254: v2(136.9,79.39) 136.9,79.39 136.67,79.39 CPU1.CK15
EQ0: length 4.9
  TOP w0.127: U7101.38 17.05,67.45 16.9,67.3 16.6,67.3 16.07,66.77 v2(16.07,66.44)
  BOTTOM w0.127: v2(16.07,66.44) 16.07,66.74 16.4,67.07 R7142.2 17.26,67.07 R7143.1 v1(18.06,66.04)
EQ1: length 3.8
  TOP w0.127: v2(16.62,68.83) 16.8,68.65 U7101.35
  BOTTOM w0.127: R7140.2 17.01,67.86 R7141.1 17.36,68.7 17.26,68.8 16.65,68.8 v2(16.62,68.83) v1(16.02,68.83)
ESPI_ALERT#: length 15.5
  TOP w0.089: v2(132.4,60.29) 132.37,60.27 R1821.2 ; v2(129.91,70.86) v1(130.38,70.39)
  L6 w0.089: v2(129.91,70.86) 129.46,70.41 129.46,67.15 129.15,66.84 129.15,62.78 129.81,62.12 129.81,62.12 130.51,61.42 130.58,61.42 131.71,60.29 v2(132.4,60.29)
  BOTTOM w0.089: CPU1.BV28 129.68,71.14 129.91,70.91 v2(129.91,70.86)
ESPI_CLK: length 126.1
  TOP w0.089: DB1.2 38.1,15.85 37.87,15.62 v2(37.87,15.26) ; R1805.2 130.01,56.86 EC1801.1 130.34,56.53 v2(130.34,56.1)
  L4SGND w0.089: v2(40.98,19.32) 41.95,19.32 42.15,19.52 43.11,19.52 44.43,20.83 44.43,26.75 44.04,27.13 44.04,33.23 47.11,36.3 47.11,40.11 52.55,45.54 53.77,45.54 55.39,47.16 v2(55.39,47.26)
  BOTTOM w0.089: v2(55.39,47.26) 59.55,47.26 61.73,49.44 64.64,49.44 65.78,50.58 85.42,50.58 87.16,52.32 102.6,52.32 103.77,51.15 124.86,51.15 128.82,55.11 v1(129.15,55.11) 129.35,55.11 v2(130.34,56.1) ; v2(37.87,15.26) 37.87,15.41 37.1,16.18 37.1,17.09 38.4,18.39 U2401.57 39.96,18.39 40.9,19.32 v2(40.98,19.32)
ESPI_CPU_CLK_R: length 12.4
  TOP w0.089: v2(129.93,68.82) 129.51,68.4 129.51,66.37 128.96,65.82 128.96,60.96 129.07,60.86 129.07,60.86 130.01,59.91 R1805.1 v1(129.1,58.9)
  BOTTOM w0.089: CPU1.BV32 129.65,68.54 v2(129.93,68.82)
ESPI_CPU_IO0_R: length 22.9
  L4SGND w0.089: v2(130.98,63.24) 131.42,63.24 131.69,63.52 131.69,68.22 131.36,68.55 131.36,69.69 v2(131.8,70.13)
  BOTTOM w0.089: CPU1.CA29 131.44,70.49 v2(131.8,70.13) ; RN1806.1 123.75,54.27 v1(124.96,54.27) 125.37,54.27 126.57,55.47 126.57,56.41 127.43,57.27 129.12,57.27 129.38,57.53 129.38,58.51 129.96,59.1 129.96,59.4 130.08,59.53 130.08,60.89 130.12,60.92 130.12,62.86 130.5,63.24 v2(130.98,63.24)
ESPI_CPU_IO1_R: length 23.5
  L6 w0.089: v2(130.9,70.15) 130.9,70.15 130.9,70.02 131.2,69.72 131.2,69.7 131.21,69.69 131.21,69.36 131.21,69.36 131.21,69.26 131.21,68.7 130.7,68.18 130.7,67.53 131.38,66.85 131.38,63.41 131.38,63.41 131.38,63.08 131.38,63.08 131.38,62.58 130.86,62.06 v2(130.71,62.06)
  BOTTOM w0.089: v2(130.9,70.15) 130.9,70.18 130.58,70.49 CPU1.BY29 ; RN1806.3 v1(124.6,52.98) 124.83,52.98 127.1,55.25 127.1,56.19 127.62,56.71 129.24,56.71 130.14,57.61 130.14,58.36 130.44,58.67 130.44,60.74 130.47,60.77 130.47,61.47 130.72,61.71 130.72,62.05 130.72,62.06 v2(130.71,62.06)
ESPI_CPU_IO2_R: length 26.2
  L4SGND w0.089: v2(130.85,71.54) 131.13,71.54 131.53,71.95 131.92,71.95 132.2,71.66 132.2,68.45 131.99,68.24 131.99,63.57 131.08,62.65 v2(130.83,62.65)
  BOTTOM w0.089: RN1806.2 123.89,53.48 124.04,53.33 124.81,53.33 126.84,55.36 126.84,56.3 127.51,56.98 129.17,56.98 129.76,57.57 v1(129.76,57.98) 129.76,58.41 130.19,58.84 130.19,59.38 130.26,59.45 130.26,60.81 130.3,60.85 130.3,62.44 130.51,62.65 v2(130.83,62.65) ; v2(130.85,71.54) 130.6,71.79 CPU1.BY27
ESPI_CPU_IO3_R: length 25.5
  L6 w0.089: v2(131.1,61.59) 131.09,61.6 130.58,61.6 129.33,62.86 129.33,66.77 130.32,67.76 130.32,68.64 130.33,68.66 130.33,68.99 130.32,69.01 130.32,71.14 130.04,71.42 130.04,71.43 v2(129.99,71.48)
  BOTTOM w0.089: CPU1.BV27 129.66,71.79 129.93,71.52 129.95,71.52 v2(129.99,71.48) ; RN1806.4 124.68,52.39 128.74,56.44 129.32,56.44 130.47,57.6 130.47,58.21 130.7,58.44 130.7,60.34 v1(130.92,60.56) 131.1,60.75 v2(131.1,61.59)
ESPI_CS#: length 138.9
  TOP w0.089: DB1.5 39.8,18.85 40.2,18.46 40.7,18.46 v2(40.93,18.69)
  L4SGND w0.089: v2(40.93,18.69) 39.84,18.69 39.69,18.83 39.69,20.11 40.23,20.65 42.07,20.65 42.09,20.67 42.33,20.91 42.33,21.61 43.07,22.34 43.07,38.51 51.51,46.95 54.08,46.95 55.23,48.09 55.35,48.09 v2(55.79,48.53)
  L6 w0.089: v2(131.53,61.16) 131.79,61.41 131.79,68.19 131.39,68.59 131.39,69.93 131.36,69.96 131.36,70.43 v2(131.76,70.83)
  BOTTOM w0.089: v2(131.53,61.16) 131.53,59.89 130.87,59.23 130.87,57.66 129.09,55.87 128.54,55.87 124.56,51.89 104.25,51.89 103.11,53.03 86.87,53.03 85.43,51.6 65.78,51.6 65.05,50.86 65.05,50.86 64.34,50.15 61.27,50.15 60.73,49.61 59.65,48.53 v1(56.5,48.53) v2(55.79,48.53) ; v2(131.76,70.83) 131.46,71.14 CPU1.CA28 ; v2(40.93,18.69) 40.23,17.99 U2401.58
ESPI_IO0: length 117.2
  TOP w0.089: DB1.9 39.72,22.85 40.16,23.3 41.4,23.3 41.7,23.01 v2(41.7,22.62)
  L4SGND w0.089: v2(54.17,49.45) 54.12,49.5 52.48,49.5 49.08,46.1 49.06,46.1 41.87,38.91 41.87,31.1 40.29,29.52 40.29,24.03 v2(41.7,22.62)
  BOTTOM w0.089: RN1806.8 121.37,54.07 v1(120.94,53.64) 120.16,52.86 104.81,52.86 103.66,54 86.47,54 85.1,52.64 65.46,52.64 64.09,51.26 63.94,51.12 60.87,51.12 60.47,50.72 60.33,50.57 59.32,50.57 58.98,50.23 57.87,50.23 57.57,49.93 54.65,49.93 v2(54.17,49.45) ; U2401.59 40.47,17.59 41.49,18.6 41.49,19.58 40.15,20.92 40.15,21.58 40.76,22.2 41.27,22.2 v2(41.7,22.62)
ESPI_IO1: length 117.7
  TOP w0.089: DB1.8 39.05,21.82 40.71,21.82 41.01,22.12 41.82,22.12 v2(42.33,22.62)
  L4SGND w0.089: v2(54.27,48.66) 54.05,48.66 53.19,47.79 51.15,47.79 42.15,38.8 42.15,30.98 40.57,29.4 40.57,24.34 41.36,23.55 41.4,23.55 v2(42.33,22.62)
  BOTTOM w0.089: v2(42.33,22.62) 41.66,21.96 40.86,21.96 40.39,21.48 40.39,21.02 41.75,19.66 41.75,18.49 40.45,17.19 U2401.60 ; v2(54.27,48.66) 54.9,48.66 55.49,49.25 57.86,49.25 v1(58.03,49.42) 59.86,49.42 60.53,50.09 60.95,50.52 60.95,50.52 61.07,50.63 64.14,50.63 64.57,51.06 65.61,52.1 85.25,52.1 86.67,53.52 103.31,53.52 104.45,52.37 105.26,52.37 120.78,52.37 121.38,52.98 RN1806.6
ESPI_IO2: length 117
  TOP w0.089: DB1.7 39.54,20.85 39.89,21.2 v2(40.83,21.2)
  L4SGND w0.089: v2(40.83,21.2) 40.4,21.2 39.66,21.94 39.66,28.11 39.96,28.42 39.96,28.77 39.94,28.79 39.94,29.57 41.54,31.17 41.54,38.98 48.9,46.34 48.98,46.34 52.57,49.93 54.52,49.93 54.78,49.68 54.78,49.29 v2(54.78,49.29)
  BOTTOM w0.089: v2(40.83,21.2) 40.83,20.92 41.97,19.78 41.97,19.78 41.99,19.76 41.99,18.39 41.97,18.37 41.97,18.2 40.56,16.79 U2401.61 ; RN1806.7 121.43,53.48 120.56,52.61 105.56,52.61 104.62,52.61 103.47,53.76 86.57,53.76 85.18,52.37 65.54,52.37 64.33,51.16 64.04,50.88 60.97,50.88 60.71,50.62 60.29,50.19 v1(59.68,50.19) 59.29,50.19 59.08,49.99 57.97,49.99 57.67,49.69 57.47,49.69 56.31,49.69 56.17,49.55 55.03,49.55 54.78,49.29 54.78,49.29 v2(54.78,49.29)
ESPI_IO3: length 115.7
  TOP w0.089: v2(41.39,21.51) 41.39,20.87 41.15,20.63 40.26,20.63 39.48,19.85 DB1.6
  L4SGND w0.089: v2(53.91,47.49) 53.65,47.23 51.4,47.23 42.77,38.61 42.77,22.43 42.53,22.19 41.8,22.19 41.39,21.79 v2(41.39,21.51)
  BOTTOM w0.089: v2(41.39,21.51) 41.39,20.74 42.28,19.86 42.28,18.13 40.54,16.39 U2401.62 ; v2(53.91,47.49) 54.08,47.49 55.57,48.98 v1(59.27,48.98) 59.76,48.98 60.63,49.85 61.17,50.39 64.24,50.39 64.81,50.96 65.69,51.84 65.88,51.84 85.33,51.84 86.77,53.28 103.21,53.28 104.35,52.13 105.09,52.13 120.88,52.13 121.14,52.39 RN1806.5
ESPI_RESET#: length 138.6
  TOP w0.089: DB1.4 40.7,17.85 41.49,18.64 41.49,19.58 41.01,20.06 v2(40.4,20.06)
  L4SGND w0.089: v2(55.73,47.83) 55.31,47.83 54.18,46.71 54.04,46.71 54,46.67 51.6,46.67 43.33,38.4 43.33,22.25 42.57,21.49 42.57,20.81 42.17,20.41 40.75,20.41 v2(40.4,20.06)
  L6 w0.089: v2(131.74,71.49) 132.2,71.03 132.2,68.55 132.07,68.42 132.07,67.84 132.14,67.77 132.14,60.9 v2(131.97,60.72)
  BOTTOM w0.089: v2(40.4,20.06) 40.33,19.99 U2401.53 ; CPU1.CA27 131.44,71.79 v2(131.74,71.49) ; v2(131.97,60.72) 131.97,59.86 131.12,59.01 131.12,57.56 129.13,55.58 128.62,55.58 128.61,55.57 128.58,55.57 124.66,51.65 103.94,51.65 102.8,52.79 86.97,52.79 85.23,51.05 65.97,51.05 65.97,51.05 65.58,51.05 65.29,50.76 65.29,50.76 64.44,49.91 61.56,49.91 61.53,49.91 59.46,47.83 v1(58.1,47.83) v2(55.73,47.83)
EXT_PWR_GATE#: length 10.3
  TOP w0.127: v2(133.77,64.15) 133.77,63.77 137.3,60.24 137.3,58.94 137.4,58.83 v1(137.42,58.83) 137.5,58.76 138.36,58.76 138.38,58.74 R1731.2
  BOTTOM w0.127: CPU1.CC37 132.47,65.31 133.63,64.15 v2(133.77,64.15)
FAN1_PWM: length 186.6
  TOP w0.254: v2(122.44,22.32) v1(123.23,23.11) 124.4,24.28 130.67,24.28 131.61,25.21 153.1,25.21 153.71,24.61 157.75,24.61 168.95,35.81 168.95,42.68 169.05,42.78 169.05,44.8 169.53,45.28 169.53,48.02 169.51,48.04 169.51,57.66 170.22,58.37 170.22,58.9 171.66,60.34 172.02,60.34 172.14,60.47 v2(172.65,60.47)
  L3SGND w0.254: v2(40.17,22.27) 40.32,22.12 53,22.12 54.56,23.68 56.63,23.68 57.26,23.06 62.59,23.06 64.8,20.85 70.59,20.85 70.85,21.1 75.68,21.1 77.24,22.66 80.51,22.66 80.68,22.83 94.78,22.83 95.59,22.01 95.59,20.74 96.2,20.13 101.7,20.13 101.78,20.21 110.73,20.21 111.23,20.72 111.43,20.72 111.8,21.09 112.72,22.01 116.45,22.01 117.31,22.88 121.88,22.88 v2(122.44,22.32)
  BOTTOM w0.203: U2401.47 40.05,22.39 v2(40.17,22.27)
  BOTTOM w0.254: R2614.1 184.44,69.49 184.77,69.16 EC2601.1 184.77,67.39 181.27,63.89 180.37,63.89 176.19,59.71 174.03,59.71 173.27,60.47 v2(172.65,60.47)
FAN1_TACH: length 5.2
  BOTTOM w0.203: U2401.40 40.07,25.19 40.17,25.29
  BOTTOM w0.254: 40.17,25.29 40.2,25.32 40.2,25.7 v1(40.45,25.95) 40.58,26.08 R2430.1 41.36,26.05 42.26,26.05 43.02,26.81 D2403.A
FAN_PWM1_C: length 10.7
  TOP w0.102: AFTP2602.1 v2(187.24,75.33)
  BOTTOM w0.102: v2(187.24,75.33) 184.57,75.33 184.34,75.1 FAN1.4 182.93,74.81 184.44,73.3 R2614.2
FAN_TACH1: length 197.8
  TOP w0.254: v2(172.65,59.84) 171.87,59.84 170.73,58.69 170.73,58.16 170.02,57.45 170.02,48.25 170.22,48.05 170.22,45.22 169.56,44.56 169.56,42.57 169.46,42.47 169.46,35.49 162.35,28.39 162.27,28.39 157.98,24.1 153.5,24.1 152.89,24.71 v1(137.15,24.71) 136.72,24.71 v2(136.56,24.55)
  L4SGND w0.254: v2(45.51,26.69) 48.68,23.51 48.68,21.2 51.45,18.43 51.45,17.49 56.66,12.29 57.83,12.29 58.8,11.32 71.29,11.32 71.29,11.32 71.64,11.32 71.64,11.32 71.79,11.32 76.23,6.89 96.04,6.89 96.27,6.66 111.46,6.66 113.78,8.98 124.07,8.98 124.35,9.26 125.46,9.26 125.95,8.78 v2(125.95,8.63)
  BOTTOM w0.254: R2613.1 185.38,69.51 EC2602.1 185.38,67.28 181.48,63.38 180.58,63.38 176.35,59.15 173.83,59.15 173.07,59.91 172.71,59.91 172.63,59.84 v2(172.65,59.84) ; v2(125.95,8.63) 125.95,9.74 126.56,10.34 126.56,14.75 130.9,19.09 131.34,19.09 132.36,19.09 136.54,23.27 136.54,24.53 v2(136.56,24.55) ; D2403.K 45,27.2 v2(45.51,26.69)
FAN_TACH1_C: length 13.5
  TOP w0.254: AFTP2601.1 186.98,75.96 187.19,75.96 v2(187.28,76.05)
  BOTTOM w0.254: FAN1.3 187.23,76.1 v2(187.28,76.05) 187.75,75.58 187.75,75.08 187.36,74.69 185.33,74.69 185.08,74.44 185.08,70.68 R2613.2
FFS_INT1: length 66.5
  TOP w0.102: v2(172.9,50.43) 172.73,50.27 172.73,48.76 172.38,48.41 v1(172.38,47.49) R7012.1
  L4SGND w0.102: v2(162.47,49.29) 163.39,50.21 167.54,50.21 168.2,49.55 169.48,49.55 169.99,49.04 172.38,49.04 172.81,49.47 172.81,49.63 172.9,49.71 v2(172.9,50.43)
  L6 w0.102: v2(162.47,49.29) 162.47,49.8 159.68,52.6 159.68,53.36 158.34,54.69 158.34,57.35 157.79,57.91 157.79,64.04 156.38,65.45 155.94,65.45 153.1,68.3 152.71,68.68 152.71,70.16 152.16,70.71 152.16,72.8 150.15,74.8 150.15,74.92 147.92,77.15 147.67,77.15 147.67,77.15 147.16,77.15 143.11,77.15 142.56,76.6 141.52,76.6 139.94,75.02 139.85,75.02 139.81,75.06 139.31,75.06 139.28,75.02 134.56,75.02 v2(134.07,75.51)
  BOTTOM w0.102: CPU1.CG22 134.07,75.41 v2(134.07,75.51)
FFS_INT2: length 83.9
  TOP w0.102: v2(157.95,42.51) 157.74,42.73 157.74,45.43 157.75,45.45 157.75,46.79 157.48,47.07 157.48,56.16 157.63,56.31 157.63,58.29 157.63,66.94 158.17,67.48 158.17,67.61 158.51,67.96 158.51,67.97 158.52,67.97 158.52,68.48 158.51,68.49 158.51,70.47 158.51,70.55 158.23,70.83 158.23,73.7 159.02,74.49 v1(159.02,78.28) 159.02,80.46 157.39,82.09 149.7,82.09 147.66,84.12 143.45,84.12 141.92,82.59 R2044.2 141.82,82.11 137.9,82.11 136.95,81.16 135.18,81.16 v2(134.76,80.74) ; R7013.1 170.68,42.18 170.8,42.06 v2(171.36,42.06)
  L4SGND w0.102: v2(171.36,42.06) 169.03,44.39 166.66,44.39 164.22,41.95 159.05,41.95 158.49,42.51 v2(157.95,42.51)
  BOTTOM w0.102: v2(134.76,80.74) 135.14,81.11 CPU1.CH12
FP1_USB20_CON_N: length 8.7
  BOTTOM w0.102: 178.63,88.51 178.86,88.51 179.87,87.5 179.87,86.84 180.87,85.84 181.09,85.84 181.19,85.94 181.54,85.94 181.65,85.84 181.65,85.84 181.78,85.72 ED9202.1 181.78,85.62 182.16,85.62 182.29,85.75 FP1.3 ; 178.63,88.51 176.95,88.51 176.85,88.61 176.85,88.97 176.77,89.05 R9209.2 ; 178.63,88.51 v1(178.63,88.66)
FP1_USB20_CON_P: length 8.2
  BOTTOM w0.102: 177.36,88.28 178.76,88.28 179.64,87.4 179.64,86.74 180.77,85.61 ED9202.2 181.37,85.49 181.61,85.25 FP1.4 ; 177.36,88.28 v1(177.36,88.13) ; 177.36,88.28 R9210.2
FP1_USB20_N: length 70.5
  L6 w0.089: v2(133.46,91.62) 133.8,91.28 133.8,91.1 134.29,90.61 135.81,90.61 136.44,91.23 140.82,91.23 141.38,90.67 141.38,90.59 141.38,90.59 141.38,89.45 144.04,86.78 144.28,86.78 152.44,86.78 154,85.22 156.01,85.22 156.14,85.1 156.14,84.97 v2(155.92,84.75)
  BOTTOM w0.076: CPU1.CG5 134.45,85.66 134.48,85.79 134.48,85.9 134.43,85.95 134.3,85.95 134.18,86.07 134.18,86.41 134.03,86.73 134.03,87.01 134.07,87.1 134.09,87.14 134.09,87.25 134.03,87.39 134.03,87.61 134.06,87.78 134.06,87.92 134.03,88.09 134.03,88.3 134.2,88.75 134.23,89.4
  BOTTOM w0.102: 167.07,88.69 163.95,88.69 162.8,87.53 162.8,86.68 162.7,86.58 162.42,86.58 162.31,86.68 162.31,87.26 162.08,87.5 161.61,87.5 161.37,87.26 161.37,86.94 161.32,86.89 160.94,86.89 160.89,86.94 160.89,87.26 160.66,87.5 160.19,87.5 159.95,87.26 159.95,86.68 159.85,86.58 159.57,86.58 159.47,86.68 159.47,87.26 159.23,87.5 158.77,87.5 158.53,87.26 158.53,86.68 158.43,86.58 158.15,86.58 158.05,86.68 158.05,87.26 157.81,87.5 157.09,87.5 156.2,86.6 156.2,85.03 v2(155.92,84.75) ; 167.07,88.69 167.7,88.69 167.9,88.89 167.9,90.23 168.14,90.47 171.65,90.47 171.89,90.23 171.89,88.89 171.99,88.79 172.27,88.79 172.37,88.89 172.37,90.23 172.61,90.47 173.07,90.47 173.31,90.23 173.31,88.89 173.41,88.79 173.69,88.79 173.79,88.89 173.79,90.23 174.03,90.47 174.5,90.47 174.73,90.23 174.73,88.89 174.83,88.79 175.25,88.79 R9209.1 ; 167.07,88.69 v1(167.07,88.87) ; v2(133.46,91.62) 133.74,91.33 133.74,90.86 134.23,89.4
FP1_USB20_P: length 70.8
  L6 w0.089: v2(134.26,91.62) 133.99,91.35 133.99,91.18 134.37,90.8 135.74,90.8 136.36,91.42 140.89,91.42 141.57,90.75 141.57,90.51 141.57,89.53 144.12,86.97 144.2,86.97 144.2,86.98 152.52,86.98 154.08,85.41 156.09,85.41 156.33,85.18 156.33,85.05 v2(156.63,84.75)
  BOTTOM w0.076: CPU1.CG6 134.55,85.36 134.59,85.46 134.73,86.1 134.74,86.11 134.74,86.34 134.58,86.5 134.28,86.61 134.21,86.78 134.21,86.97 134.24,87.04 134.25,87.08 134.26,87.11 134.26,87.28 134.21,87.42 134.21,87.59 134.24,87.77 134.24,87.93 134.21,88.11 134.21,88.26 134.37,88.71 134.42,89.39 134.42,89.46
  BOTTOM w0.102: v2(156.63,84.75) 156.43,84.96 156.43,86.5 156.76,86.83 ; R9210.1 175.22,88.56 174.74,88.56 174.5,88.8 174.5,90.14 174.4,90.24 174.12,90.24 174.02,90.14 174.02,88.8 173.79,88.56 173.32,88.56 173.08,88.8 173.08,90.14 172.98,90.24 172.7,90.24 172.6,90.14 172.6,88.8 172.36,88.56 171.89,88.56 171.66,88.8 171.66,90.14 171.56,90.24 168.23,90.24 168.13,90.14 168.13,88.8 167.79,88.46 164.05,88.46 163.03,87.44 163.03,86.59 162.79,86.35 162.32,86.35 162.09,86.59 162.09,87.17 161.98,87.27 161.71,87.27 161.6,87.17 161.6,86.84 161.42,86.66 160.85,86.66 160.66,86.84 160.66,87.17 160.56,87.27 160.28,87.27 160.18,87.17 160.18,86.59 159.95,86.35 159.48,86.35 159.24,86.59 159.24,87.17 159.14,87.27 158.86,87.27 158.76,87.17 158.76,86.59 158.52,86.35 158.05,86.35 157.82,86.59 157.82,87.17 157.72,87.27 157.19,87.27 156.76,86.83 ; 134.42,89.46 133.97,91.14 133.97,91.33 v2(134.26,91.62) ; 156.76,86.83 v1(156.86,86.73)
FP_3D3V: length 2.4
  BOTTOM w0.508: Q9201.D 180.3,79.26 180.13,79.09 v1(180.13,79.04) 180.28,78.89 R9213.2
FP_EN#: length 113.1
  L4SGND w0.102: v2(167.46,20.59) 167.4,20.65 167.4,20.69 167.3,20.8 166.43,20.8 162.37,24.86 159.78,24.86 158.61,23.69 155.87,23.69 153.73,21.56 149.57,21.56 148.04,23.08 v2(148.04,23.74)
  L6 w0.102: v2(167.46,20.59) 167.4,20.65 167.4,20.69 166.97,21.13 166.97,26.76 173.55,33.34 173.55,43.02 175.17,44.65 175.17,48.19 175.12,48.24 175.12,51.66 175.6,52.14 175.6,54.91 174.87,55.64 174.87,56.32 176.62,58.07 176.62,66.4 177.71,67.49 v2(177.71,67.84) ; v2(148.04,23.74) 147.49,24.3 147.49,25.93 145.58,27.83 133.39,27.83 132.88,27.32 v2(132.63,27.32)
  BOTTOM w0.102: Q9202.D 133.08,26.31 R9212.2 133.4,26.62 133.4,27.11 133.4,27.11 v1(133.4,27.27) 133.38,27.27 133.33,27.32 v2(132.63,27.32) ; Q9201.G 181.01,79.81 181.01,76.22 178.75,73.96 178.75,68.52 178.07,67.84 v2(177.71,67.84)
FPR_CL_SIO#: length 13.8
  BOTTOM w0.102: FP1.6 182.19,84.25 181.6,83.66 R9217.1 181.6,81.98 181.78,81.81 182.79,81.81 183,81.6 183,78.99 182.79,78.78 182.28,78.78 181.88,78.38 181.88,76.58 181.88,75.64 v1(180.87,74.63) 180.51,74.26 R9216.1
FPR_PWRBTN#: length 11.1
  BOTTOM w0.102: v1(188.89,91.06) 188.71,90.88 R9218.1 188.71,88.87 187.49,87.65 186.86,87.65 186.6,87.39 185.21,87.39 184.06,86.25 FP1.2 181.98,86.25 R9214.1 R9215.2
FPR_SCAN#: length 232.4
  TOP w0.102: v2(172.23,34.23) 173.05,35.05 173.05,39.42 173.05,39.58 173.11,39.65 173.11,39.87 173.11,40.04 174.98,41.9 181,41.9 181.02,41.88 184.14,41.88 184.49,42.23 v2(185.64,42.23)
  L4SGND w0.102: v2(116.04,15.94) 116.28,15.7 120.72,15.7 122.42,17.4 136.55,17.4 144.05,24.91 157.39,24.91 160.92,28.44 163.91,28.44 167.39,31.92 168.4,31.92 170.71,34.23 v2(172.23,34.23) ; v2(114.57,8.37) 112.42,6.23 96.09,6.23 95.86,6.46 75.9,6.46 71.46,10.89 58.62,10.89 57.66,11.85 50.42,11.85 47.31,14.96 47.31,22.98 v2(45.38,24.91) ; v2(185.64,42.23) 185.84,42.44 185.84,49.55 184.23,51.16 184.23,65.6 185.22,66.58 185.22,83.6 v2(187.24,85.62)
  BOTTOM w0.102: U2401.42 40.46,24.39 41.4,23.44 42.25,23.44 42.71,23.89 42.71,24.1 43.6,24.99 v1(43.75,24.99) R2465.2 45.3,24.99 v2(45.38,24.91) ; v2(187.24,85.62) 186.09,85.62 184.23,83.75 FP1.7 ; v2(114.57,8.37) 116.04,9.85 v2(116.04,15.94)
GPD11/LANPHYPC: length 10.9
  BOTTOM w0.076: CPU1.BU34 128.35,67.19 128.35,66.46 128.32,66.43 128.31,66.36 128.31,65.87 128.23,65.66 128.23,65.3 128.53,65 128.53,63.99 128.36,63.82
  BOTTOM w0.102: v1(128.05,58.55) 127.34,59.25 R1721.2 127.13,59.45 126.85,59.73 126.85,61.93 127.27,62.35 127.27,63.11 127.29,63.14 127.29,63.31 127.8,63.82 128.36,63.82
GPD_7: length 23.9
  TOP w0.102: R1524.2 140.27,57.35 R1525.1 ; v2(139.86,56.06) 140.27,56.47 R1525.1 ; R1525.1 v1(141.19,56.8)
  L4SGND w0.102: v2(129.91,68.12) 129.93,68.12 130.79,67.26 130.79,63.65 130.31,63.17 130.31,61.81 132.23,59.89 133.93,59.89 137.82,56 139.8,56 v2(139.86,56.06)
  BOTTOM w0.102: v2(129.91,68.12) 129.91,68.01 129.43,67.53 129.25,67.53 129.01,67.29 129.01,66.88 129.31,66.59 CPU1.BV35
GPP_B22_GSPI1_MOSI: length 15.5
  TOP w0.102: R2019.2 131.31,72.1 131.31,71.18 131.31,71.18 v1(131.31,71.17) 131.32,71.15 131.32,69.98 v2(131.79,69.5) 131.4,69.11 131.4,68.59 131.53,68.45 131.53,64.51 133.52,62.53 R1553.1
  BOTTOM w0.102: v2(131.79,69.5) 131.79,69.49 131.78,69.5 131.43,69.84 CPU1.CA30
GPP_E1/SATAXPCIE1/SATAGP1: length 7.1
  BOTTOM w0.076: CPU1.CN8 137.58,83.86 137.13,84.31 137.13,84.54 137.34,84.75 137.53,84.82 138.5,84.82 138.59,84.86 138.83,84.86 138.95,84.81 139.52,84.81 139.55,84.84 140.05,84.84 140.23,85.02
  BOTTOM w0.102: 140.23,85.02 141.69,86.48 TP1603.1
GPP_E3/CPU_GP0: length 2.3
  TOP w0.102: v2(133.32,82.37) 133.11,82.16 133.11,81.51 133.37,81.25 TP304.1
  BOTTOM w0.102: v2(133.32,82.37) 133.35,82.39 CPU1.CE9
GPP_E23_STRAP: length 10.5
  BOTTOM w0.102: CPU1.CN4 137.96,85.96 138.49,85.96 138.64,86.11 139.14,86.11 139.66,86.63 139.66,87.26 141.14,88.73 141.14,91.84 142.23,92.93 142.23,93.4 TP402.1
GPP_H1_SFRM: length 22.2
  TOP w0.102: R1913.2 147.56,56.76 v2(147.56,57.32) v1(147.56,57.85)
  L6 w0.102: v2(147.56,57.32) 147.56,57.74 145.57,59.73 143.93,59.73 140.59,63.07 136.26,63.07 135.56,63.77 135.56,66.48 135.14,66.9 135.14,67.48 135.4,67.74 v2(135.4,68.85)
  BOTTOM w0.102: CPU1.CJ32 135.71,68.54 135.4,68.85 135.4,68.85 v2(135.4,68.85)
GPP_H2_CLKREQ0: length 25.7
  TOP w0.102: R1912.2 150.31,58.03 v1(149.8,58.03) 149.26,58.03 148.53,57.3 v2(148.25,57.3)
  L6 w0.102: v2(148.25,57.3) 148.25,57.47 145.6,60.11 143.91,60.11 140.76,63.26 136.34,63.26 135.75,63.85 135.75,66.69 136.01,66.95 136.01,69.56 135.45,70.12 v2(135.4,70.12)
  BOTTOM w0.102: CPU1.CH29 135.03,70.49 v2(135.4,70.12)
GPP_H17_STRAP: length 4.9
  BOTTOM w0.102: CPU1.CP26 138.66,72.75 141.38,72.75 v1(141.45,72.68) 141.45,72.41 141.89,71.96 142.52,71.96 R1527.1
GPP_H21: length 26.1
  L6 w0.102: v2(150.9,73.15) 150.89,73.15 150.75,73.29 150.54,73.29 149.65,74.19 149.65,74.69 148.53,75.81 148.53,75.88 148.16,76.25 148.09,76.25 147.59,76.75 147.5,76.75 143.28,76.75 141.86,75.33 141.01,75.33 139.61,73.93 139.27,73.93 138.89,74.31 137.45,74.31 137.25,74.11 136.94,74.11 136.93,74.11 135.88,74.11 135.45,74.54 v2(135.42,74.54)
  BOTTOM w0.102: v1(152.9,74.67) 152.13,74.34 151.45,74.34 R1522.2 150.61,73.93 R1523.1 150.9,73.65 v2(150.9,73.15) ; v2(135.42,74.54) 135.45,74.52 135.45,73.83 135.19,73.58 134.3,73.58 133.84,73.11 CPU1.CF25
GPP_H23: length 12.8
  BOTTOM w0.076: 139.49,72.05 139.32,72.21 138.96,72.21 arc(138.92,72.22) 138.88,72.23 arc(138.81,72.27) 138.74,72.28 138.67,72.28 arc(138.61,72.27) 138.55,72.23 arc(138.51,72.22) 138.47,72.21 138.07,72.21 137.99,72.13 137.34,72.13 CPU1.CM26
  BOTTOM w0.102: R1513.2 148.04,69.34 146.28,69.34 R1514.1 145.15,70.48 145.15,70.91 v1(144.56,71.49) 144.36,71.7 141.74,71.7 141.39,72.05 139.49,72.05
GPPC_H18_BOOTMPC: length 5
  BOTTOM w0.076: CPU1.CN27 138.24,72 138.37,72 arc(138.44,72.01) 138.51,72.04 arc(138.57,72.06) 138.63,72.07 138.81,72.07 arc(138.85,72.07) 138.88,72.05 138.88,72.05 139.16,72.05 139.33,71.87
  BOTTOM w0.127: R2119.1 141.71,71.27 v1(141.56,71.42) 141.33,71.65 139.56,71.65 139.33,71.87
GPPC_H18_VCCIO_LPM: length 69.8
  TOP w0.127: v2(183.35,71.98) 182.82,71.44 R4042.2
  L4SGND w0.127: v2(183.43,62.88) 183.43,66.5 184.71,67.78 184.71,71.63 184.37,71.98 v2(183.35,71.98) ; v2(144.95,69.61) 145.33,69.23 146.6,69.23 148.38,67.45 152.44,67.45 155.69,64.21 158.68,64.21 161.65,61.23 164.15,61.23 165.34,60.04 167.22,60.04 169.35,57.91 173.73,57.91 174.07,58.25 175.37,58.25 175.88,57.74 176.63,57.74 v2(177.59,56.79)
  BOTTOM w0.127: v2(177.59,56.79) 177.59,57.18 183.29,62.88 v2(183.43,62.88) ; v2(144.95,69.61) 144.91,69.65 144.91,70.79 144.57,71.13 144.16,71.13 144.02,71.27 R2119.2 ; U4008.2 182.03,69.61 181.78,69.87 180.7,69.87 179.96,70.61 179.96,71.68 v1(180.23,71.95) 180.43,72.15 R4040.2 181.52,72.15 182.28,72.92 R4041.2 182.41,72.92 v2(183.35,71.98)
GPU_THM_SMBCLK: length 3.9
  BOTTOM w0.089: 30.39,32.05 29.74,31.39 U2401.12 ; 30.39,32.05 R2459.1 ; 30.39,32.05 30.39,31.46 v1(30.54,31.31)
GPU_THM_SMBDAT: length 3.2
  BOTTOM w0.089: 29.55,30.85 29.55,30.18 29.34,29.97 U2401.11 ; 29.55,30.85 29.55,31.47 29.81,31.73 29.81,32.05 R2447.1 ; 29.55,30.85 v1(29.4,30.85)
GSEN2_INT1: length 6.8
  TOP w0.102: R7009.2 R7012.2 172.38,44.85 v2(172.12,44.6) v1(172.52,44.2)
  BOTTOM w0.102: v2(172.12,44.6) 172.45,44.27 172.45,42.28 172.05,41.88 CN6601.17
GSEN2_INT1_C: length 50.5
  TOP w0.102: v2(171.49,47.01) 171.62,46.88 R7009.1
  L4SGND w0.102: v2(171.49,47.01) 167.7,47.01 163.61,42.92 159.63,42.92 157.42,45.13 157.42,46.83 155.51,48.74 v2(155.51,48.79)
  BOTTOM w0.102: R2025.2 133.59,57.12 133.39,56.91 133.39,56.25 v1(133.77,55.87) 133.77,55.18 135.54,53.41 136.48,53.41 137.29,52.6 138.53,52.6 138.71,52.42 140.99,52.42 141.6,53.03 143.12,53.03 143.55,53.46 145.71,53.46 147.21,51.96 149.39,51.96 150.56,50.79 152.84,50.79 153.14,50.49 153.61,50.49 153.89,50.21 155.28,50.21 155.51,49.98 v2(155.51,48.79)
GSEN2_INT1_ISH: length 10.8
  BOTTOM w0.076: CPU1.CA36 131.17,66.14 131.32,65.86 131.32,65.86 131.43,65.66 131.43,65 131.62,64.81
  BOTTOM w0.102: v1(132.75,57.04) 132.75,57.65 133.52,58.41 R2025.1 133.74,58.57 133.74,59.45 133.95,59.65 133.95,60.99 132.53,62.4 132.53,63.89 132.53,63.89 132.53,63.91 131.62,64.81
GSEN2_INT2: length 8.5
  TOP w0.102: v2(171.49,44.72) 171.49,44.14 R7010.2 172.12,43.5 172.12,43.27 R7013.2 171.54,42.51 172.12,41.93 v1(172.12,41.88)
  BOTTOM w0.102: CN6601.18 171.55,40.87 171.77,41.09 171.77,42.03 172.17,42.44 172.17,43.38 171.49,44.06 v2(171.49,44.72)
GSEN2_INT2_C: length 51.3
  TOP w0.102: R7010.1 170.68,43.55 170.9,43.33 v2(171.36,43.33)
  L4SGND w0.102: v2(171.36,43.33) 169.97,44.72 166.63,44.72 164.06,42.16 159.14,42.16 156.81,44.49 156.81,45.43 v2(156.12,46.12)
  BOTTOM w0.102: v2(156.12,46.12) 156.12,49.75 155.44,50.44 153.96,50.44 153.71,50.69 153.23,50.69 151.65,52.27 147.19,52.27 145.79,53.66 143.42,53.66 142.99,53.23 141.52,53.23 140.91,52.62 138.8,52.62 138.62,52.8 137.38,52.8 136.56,53.61 135.93,53.61 v1(135.44,54.1) 134.35,55.19 134.35,56.91 134.38,56.94 R2026.2
GSEN2_INT2_ISH: length 9.8
  BOTTOM w0.076: 132.72,63.97 131.65,65.04 131.63,65.07 131.63,65.64 131.49,65.9 131.49,66.53 CPU1.CA35
  BOTTOM w0.102: R2026.1 134.14,58.65 v1(134.14,59.33) 134.18,59.37 134.18,61.04 132.75,62.47 132.75,63.94 132.72,63.97
GSEN_INT1: length 216.3
  TOP w0.102: v2(180.28,43.33) 180.71,43.76 183.9,43.76 183.93,43.78 187.64,43.78 188.93,45.06 188.93,47.86 185.74,51.05 185.74,57.07 189.6,60.93 189.6,65.45 190.08,65.93 190.08,97.35 189.68,97.76 189.68,98.72 v2(188.51,99.89)
  L4SGND w0.102: v2(180.28,43.33) 179.68,43.33 178.13,44.87 174.3,44.87 173.94,45.23 170.76,45.23 170.63,45.1 166.72,45.1 163.98,42.36 159.22,42.36 157.01,44.57 157.01,45.87 154.55,48.33 v2(154.55,48.89)
  BOTTOM w0.102: v2(154.55,48.89) 154.35,48.89 153.35,49.88 152.89,49.88 152.58,50.18 150.81,50.18 150.81,50.18 150.31,50.18 150.31,50.18 148.12,50.18 145.45,52.85 144.55,52.85 144.47,52.77 144.44,52.77 144.18,52.52 144.18,52.49 144.13,52.43 144.13,52.24 143.47,51.58 140.04,51.58 139.81,51.81 138.46,51.81 138.28,51.99 137.04,51.99 136.28,52.75 136.11,52.75 135.14,52.75 v1(134.89,53) 134.89,53.2 131.98,56.1 131.98,58.49 133.38,59.89 133.38,60.75 131.96,62.17 131.96,63.65 131.95,63.66 131.95,63.67 130.79,64.83 130.79,65.14 130.25,65.69 130.25,67.2 CPU1.BW34 ; v2(188.51,99.89) 183.1,99.89 177.46,94.25 165.04,94.25 164.17,95.12 161.67,95.12 161.22,95.56 160.88,95.56 159.87,95.56 158.51,96.93 149.37,96.93 148.3,98 145.68,98 144.21,98 143.16,98 139.76,101.4 139.08,101.4 138.51,101.97 138.51,102.26 138.03,102.74 124.93,102.74 123.95,101.75 TCBD1.5
GSEN_INT2: length 212
  TOP w0.102: v2(188.51,99.28) 189.47,98.32 189.47,97.67 189.88,97.27 189.88,66.02 189.4,65.53 189.4,61.01 185.54,57.15 185.54,50.96 188.72,47.77 188.72,45.22 187.49,43.99 180.07,43.99 v2(179.85,43.76)
  L4SGND w0.102: v2(155.49,48.02) 157.21,46.3 157.21,44.65 159.31,42.56 163.89,42.56 166.64,45.31 170.55,45.31 170.73,45.48 173.98,45.48 174.38,45.08 178.52,45.08 v2(179.85,43.76)
  BOTTOM w0.102: CPU1.CA37 131.17,64.99 132.34,63.83 132.34,63.82 132.34,63.81 132.34,62.32 133.76,60.91 133.76,59.73 132.39,58.36 132.39,56.27 135.46,53.21 136.39,53.21 137.21,52.39 138.45,52.39 138.63,52.22 139.98,52.22 140.21,51.99 142.87,51.99 143.07,52.18 143.07,52.68 143.64,53.26 145.62,53.26 147.12,51.76 149.31,51.76 150.48,50.59 152.75,50.59 153.06,50.28 153.52,50.28 153.83,49.98 154.7,49.98 155.06,49.63 155.06,48.46 v2(155.49,48.02) ; TCBD1.6 124.45,101.06 125.92,102.53 137.94,102.53 138.3,102.17 138.3,101.89 139,101.2 139.62,101.2 143.03,97.79 144.21,97.79 145.68,97.79 148.22,97.79 149.29,96.72 149.46,96.72 158.43,96.72 159.79,95.36 160.97,95.36 160.97,95.36 161.14,95.36 161.58,94.91 164.09,94.91 165.18,93.82 v1(173.14,93.82) 177.4,93.82 183.02,99.43 188.35,99.43 v2(188.51,99.28)
GYRO_DRDY: length 172.3
  TOP w0.102: v2(144.62,52.34) 145.33,53.05 152.46,53.05 v2(152.79,53.38) ; v2(188.77,65.8) 188.76,65.8 188.76,65.8 189.47,66.51 189.47,97.1 v2(188.51,98.06)
  L4SGND w0.102: v2(172.43,52.98) 172.3,53.1 166.92,53.1 166.54,52.72 162.99,52.72 161.54,51.28 160.92,51.28 158.96,53.23 152.95,53.23 v2(152.79,53.38)
  BOTTOM w0.102: v2(144.62,52.34) 143.65,51.38 139.95,51.38 139.72,51.61 138.37,51.61 138.2,51.78 136.95,51.78 136.19,52.55 134.63,52.55 134.2,52.98 133.74,52.98 133.34,52.57 R2028.2 ; TCBD1.8 125.45,100.79 126.31,101.65 137.97,101.65 138.83,100.79 139.46,100.79 142.86,97.39 144.21,97.39 145.67,97.39 148.05,97.39 149.12,96.32 149.62,96.32 158.26,96.32 159.62,94.95 160.83,94.95 161.27,94.51 163.92,94.51 165.29,93.13 177.74,93.13 v1(179.11,94.51) 183.36,98.76 187.81,98.76 v2(188.51,98.06) ; v2(188.77,65.8) 188.72,65.75 184.65,65.75 176.38,57.49 175.77,57.49 172.63,54.35 172.63,53.18 v2(172.43,52.98)
GYRO_DRDY_ISH: length 18.4
  BOTTOM w0.102: R2051.1 132.7,51.2 R2052.2 R2028.1 133.74,53.49 v1(133.74,53.82) 133.74,54.05 131.78,56.02 131.78,58.56 133.19,59.97 133.19,60.67 131.77,62.09 131.77,63.57 131.76,63.58 131.76,63.59 130.6,64.75 130.6,65.07 130.12,65.55 CPU1.BW37
GYRO_INT_C: length 17
  BOTTOM w0.102: TCBD1.7 124.95,100.8 126.2,102.05 v1(135.72,102.05) 136.69,102.05 R2027.2
GYRO_INT_ISH: length 182.2
  TOP w0.102: v2(188.51,98.67) 188.68,98.49 188.69,98.49 188.94,98.24 188.94,98.24 189.27,97.91 189.27,97.59 189.68,97.18 189.68,66.1 188.74,65.17 v2(188.51,65.17)
  L4SGND w0.102: v2(170.73,47.52) 169.12,47.52 169.11,47.5 167.91,47.5 163.53,43.12 159.72,43.12 157.62,45.22 157.62,47.97 156.07,49.52 v2(154.55,49.52)
  BOTTOM w0.102: v2(188.51,98.67) 188.1,99.08 183.14,99.08 177.55,93.49 v1(166.01,93.49) 165.23,93.49 164,94.71 161.36,94.71 160.91,95.15 159.71,95.15 158.34,96.52 149.54,96.52 149.2,96.52 148.13,97.59 145.67,97.59 144.21,97.59 142.94,97.59 139.54,101 138.91,101 137.78,102.13 R2027.1 ; v2(170.73,47.52) 171.03,47.82 171.03,52.11 171.24,52.32 172.45,52.32 173.01,52.88 173.01,54.44 175.86,57.28 176.47,57.28 184.74,65.55 188.13,65.55 v2(188.51,65.17) ; CPU1.CA34 130.9,67.23 130.9,65.3 130.98,65.22 130.98,64.91 132.14,63.75 132.14,63.74 132.15,63.73 132.15,62.24 133.57,60.83 133.57,59.81 132.19,58.43 132.19,56.19 135.37,53 136.31,53 137.12,52.19 138.37,52.19 138.54,52.01 139.89,52.01 140.12,51.78 142.96,51.78 143.27,52.1 143.27,52.6 143.73,53.05 145.54,53.05 147.04,51.55 149.22,51.55 150.39,50.39 150.73,50.39 152.67,50.39 152.97,50.08 153.44,50.08 154,49.52 v2(154.55,49.52)
H_CPUPWRGD: length 8.5
  BOTTOM w0.089: ED301.2 115.43,94.17 R1714.1 115.2,93.46 TP1705.1 114.72,91.71 114.72,88.56 114.64,88.48 114.64,87.82 CPU1.AR2
H_PECI: length 3.2
  BOTTOM w0.089: R2437.1 25.57,12.74 C2405.1 26.51,12.85 v1(26.56,12.9) 26.14,13.32 U2401.94
HDA_BITCLK_CODEC: length 5.8
  BOTTOM w0.089: U2701.14 173.88,22.6 173.72,22.75 172.78,22.75 172.4,22.37 171.82,22.37 v1(171.41,21.96) 171.16,21.96 170.42,22.7 EC1901.2 170.22,22.78 170.22,23.42 170.13,23.51 R1920.1
HDA_BITCLK_CPU: length 79.1
  L6 w0.089: v2(151.07,23.56) 150.61,24.02 150.61,26.29 152.69,28.38 152.69,28.99 152.69,38.59 143.75,47.53 143.75,52.97 143.03,53.69 141.24,53.69 140.06,54.87 136.96,54.87 133.29,58.54 131.58,58.54 129.29,60.83 128.03,60.83 126.58,62.28 126.58,62.72 v2(126.16,63.14)
  BOTTOM w0.076: v2(126.16,63.14) 126.33,63.14 126.58,63.39 126.58,63.9 125.9,64.58 125.9,65.3 CPU1.BN37
  BOTTOM w0.089: R1920.2 168.9,23.69 v1(168.22,24.37) 167.62,24.97 157.26,24.97 155.07,22.78 151.8,22.78 151.07,23.51 v2(151.07,23.56)
HDA_RST_N_CPU: length 4.5
  BOTTOM w0.089: TP1903.1 125.21,66.56 CPU1.BL35
HDA_SDIN0_CODEC: length 5.3
  BOTTOM w0.089: R2730.2 171.79,24.53 171.79,23.77 172.23,23.34 v1(172.23,23.34) 172.48,23.59 173.64,23.59 174.27,22.96 174.28,22.96 174.68,22.56 U2701.16
HDA_SDIN0_CPU: length 81.9
  L6 w0.089: v2(126.18,62.53) 126.18,62.43 127.98,60.62 129.24,60.62 131.65,58.21 131.95,58.21 137.05,53.11 142.64,53.11 142.65,53.1 142.66,53.1 143.27,52.49 143.27,52.27 143.27,47.35 152.22,38.39 152.22,28.79 152.22,28.57 150.05,26.4 v2(150.05,23.84)
  BOTTOM w0.076: CPU1.BN35 125.82,66.53 125.82,65.9 125.73,65.74 125.49,65.5 125.49,63.85
  BOTTOM w0.089: v2(150.05,23.84) 150.05,24.26 150.14,24.35 151.27,24.35 152.1,23.52 154.77,23.52 156.95,25.7 168.43,25.7 169.1,25.04 v1(169.51,25.04) R2730.1 ; 125.49,63.85 125.49,62.96 125.92,62.53 v2(126.18,62.53)
HDA_SDOUT_CODEC: length 3.2
  BOTTOM w0.089: U2701.17 175.08,22.59 174.41,23.26 174.41,23.31 v1(174.36,23.36) 173.75,23.97 EC1903.1 173.55,24.1 R1921.1
HDA_SDOUT_CPU: length 83.4
  TOP w0.089: v2(142.08,54.16) 142.08,53.56 R1512.2 ; R1909.2 v2(172.25,24.96)
  L6 w0.089: v2(152.9,23.94) 152.95,24 152.95,27.57 153.64,28.26 153.64,38.7 147.76,44.58 147.76,47.72 147.15,48.32 145.77,48.32 144.99,49.1 144.99,51.65 145.04,51.7 145.04,52.52 143.4,54.16 v2(142.08,54.16) 142.08,54.29 140.91,55.46 137.05,55.46 133.67,58.84 131.53,58.84 129.36,61 128.1,61 126.79,62.32 126.79,63.12 v2(126.16,63.75)
  BOTTOM w0.076: CPU1.BN36 126.14,66.14 125.72,65.37 125.72,64.08 126.05,63.75 v2(126.16,63.75)
  BOTTOM w0.089: v2(152.9,23.94) 153.12,23.94 154.09,24.91 v1(154.98,24.91) 156.04,25.97 168.65,25.97 169.15,25.47 169.15,25.46 171.75,25.46 v2(172.25,24.96) R1921.2
HDA_SPKR_R: length 2.6
  BOTTOM w0.254: v1(178.3,11.47) 178.93,11.47 D2702.2 180.07,10.33 RN2702.3
HDA_SYNC_CODEC: length 5.2
  BOTTOM w0.089: U2701.15 174.28,22.58 174.17,22.69 174.15,22.69 173.63,23.22 172.61,23.22 172.37,22.99 171.28,22.99 v1(171.01,23.26) 171.01,23.7 171.29,23.97 R1908.1
HDA_SYNC_CPU: length 84.4
  TOP w0.089: v2(149.42,23.82) v1(149.16,23.32)
  L6 w0.089: v2(149.42,23.82) 149.42,26.14 151.96,28.68 151.96,38.27 143,47.22 143,47.47 143,52.38 142.69,52.7 142.68,52.7 142.53,52.84 141.52,52.84 141.37,52.7 137.08,52.7 131.8,57.98 131.62,57.98 130.11,59.49 130.11,59.5 129.19,60.42 127.73,60.42 126.28,61.87 v2(126.16,61.87)
  BOTTOM w0.089: R1908.2 169.13,24.28 167.97,25.44 157.06,25.44 154.88,23.25 151.99,23.25 151.22,24.02 150.84,24.02 150.2,23.39 149.85,23.39 v2(149.42,23.82) ; CPU1.BN34 126.4,67.23 126.4,65.39 126.12,65.12 126.12,64.61 126.84,63.9 126.84,63.21 126.72,63.09 126.72,62.43 126.15,61.87 v2(126.16,61.87)
HDMI_CEC: length 4.2
  TOP w0.102: U5701.F2 22.15,88.95 22.15,90.48 v1(21.42,91.2) 21.42,91.97 R5761.1
HDMI_CEC_CON: length 17
  TOP w0.102: R5761.2 21.25,93.62 v2(21.22,93.64) ; v2(16.63,93.07) 16.63,92.18 16.18,91.72 ED5703.4 ED5703.7 13.79,91.72 12.34,93.17 11.37,93.17 10.98,92.78 10.98,90.14 10.86,90.02 HDMI1.13
  BOTTOM w0.102: v2(21.22,93.64) 20.71,94.15 19.39,94.15 v1(18.1,92.86) 16.85,92.86 v2(16.63,93.07)
HDMI_DDI_TX_ALS_N0: length 2.6
  TOP w0.102: U5701.A7 26.9,84.19 28.72,84.19 C5731.2
HDMI_DDI_TX_ALS_N1: length 2.6
  TOP w0.102: C5734.2 28.69,85.84 26.85,85.84 U5701.A5
HDMI_DDI_TX_ALS_N2: length 2.6
  TOP w0.102: U5701.A3 26.87,87.42 28.74,87.42 C5727.2
HDMI_DDI_TX_ALS_N3: length 2.6
  TOP w0.102: U5701.A1 26.92,88.97 28.77,88.97 C5733.2
HDMI_DDI_TX_ALS_P0: length 2.6
  TOP w0.102: U5701.A8 26.85,83.97 28.72,83.97 C5737.2
HDMI_DDI_TX_ALS_P1: length 2.6
  TOP w0.102: U5701.A6 26.9,85.62 28.74,85.62 C5732.2
HDMI_DDI_TX_ALS_P2: length 2.6
  TOP w0.102: U5701.A4 26.87,87.19 28.69,87.19 C5728.2
HDMI_DDI_TX_ALS_P3: length 2.6
  TOP w0.102: C5735.2 28.67,88.74 26.82,88.74 U5701.A2
HDMI_DDI_TX_CMC_N0: length 2.8
  TOP w0.076: R5770.1 18.61,87.44 20.73,87.44 U5701.H3
HDMI_DDI_TX_CMC_N1: length 2.8
  TOP w0.076: R5768.1 18.56,85.81 20.7,85.81 U5701.H5
HDMI_DDI_TX_CMC_N2: length 2.9
  TOP w0.076: R5766.1 18.61,84.09 19.63,84.09 19.8,84.26 20.74,84.26 U5701.H7
HDMI_DDI_TX_CMC_N3: length 2.8
  TOP w0.076: R5772.1 18.48,89.24 19.17,89.24 C5724.2 19.34,89.07 20.75,89.07 U5701.H1
HDMI_DDI_TX_CMC_P0: length 2.8
  TOP w0.076: U5701.H4 20.75,87.14 18.61,87.14 R5769.1
HDMI_DDI_TX_CMC_P1: length 2.8
  TOP w0.076: R5767.1 18.65,85.51 20.78,85.51 U5701.H6
HDMI_DDI_TX_CMC_P2: length 2.9
  TOP w0.076: R5765.1 18.61,83.79 19.76,83.79 19.93,83.95 20.74,83.95 U5701.H8
HDMI_DDI_TX_CMC_P3: length 2.8
  TOP w0.076: R5771.1 18.48,88.69 19.16,88.69 C5724.1 19.34,88.77 20.73,88.77 U5701.H2
HDMI_DDI_TX_CON_N0: length 14.5
  TOP w0.076: R5770.2 17.21,87.67 17,87.46 16.75,87.46 16.64,87.57 16.04,87.57 15.98,87.64 ED5702.7 ED5702.4 14.25,87.64 14.19,87.57 13.26,87.57 12.85,87.16 v2(12.74,87.11)
  BOTTOM w0.076: HDMI1.9 10.63,87.61 10.79,87.61 11.15,87.25 11.15,83.95 11.29,83.81 12.4,83.81 12.63,84.04 12.63,87.01 v2(12.74,87.11)
HDMI_DDI_TX_CON_N1: length 6.3
  TOP w0.076: HDMI1.6 12.09,86.2 12.81,86.2 13.4,85.61 14.23,85.61 14.35,85.73 ED5701.6 ED5701.5 15.62,85.73 15.7,85.65 16.33,85.65 16.47,85.79 17.31,85.79 R5768.2
HDMI_DDI_TX_CON_N2: length 10.1
  TOP w0.076: R5766.2 17.34,84.14 15.65,84.14 ED5701.2 ED5701.9 14.4,84.21 14.31,84.12 13.98,84.12 13.31,83.45 13.31,82.99 13.01,82.69 11.32,82.69 11.2,82.81 11.2,83.88 11.2,84.26 10.79,84.66 10.58,84.66 HDMI1.3
HDMI_DDI_TX_CON_N3: length 6
  TOP w0.076: HDMI1.12 12.13,89.16 ED5702.1 ED5702.10 17.32,89.16 R5772.2
HDMI_DDI_TX_CON_P0: length 14.5
  TOP w0.076: R5769.2 17.26,86.91 17.02,87.15 16.63,87.15 16.61,87.17 16.6,87.17 16.5,87.27 16.02,87.27 15.9,87.16 ED5702.6 ED5702.5 14.25,87.16 14.14,87.27 13.55,87.27 v2(13.43,87.15)
  BOTTOM w0.076: v2(13.43,87.15) 13.42,87.14 13.42,86.84 13.3,86.71 13,86.71 12.94,86.64 12.94,83.91 12.53,83.5 11.16,83.5 10.84,83.82 10.84,87.13 10.67,87.3 10.5,87.3 HDMI1.7
HDMI_DDI_TX_CON_P1: length 6.4
  TOP w0.076: HDMI1.4 12.14,85.89 12.68,85.89 13.27,85.31 14.21,85.31 14.27,85.25 ED5701.7 ED5701.4 15.68,85.34 16.45,85.34 16.6,85.49 17.26,85.49 R5767.2
HDMI_DDI_TX_CON_P2: length 10.2
  TOP w0.076: R5765.2 17.23,83.84 15.69,83.84 ED5701.1 ED5701.10 14.37,83.73 14.29,83.81 14.11,83.81 13.62,83.32 13.62,82.87 13.14,82.39 12.89,82.39 12.89,82.39 11.19,82.39 10.9,82.68 10.9,84 10.9,84.13 10.67,84.36 10.56,84.36 HDMI1.1
HDMI_DDI_TX_CON_P3: length 6
  TOP w0.076: HDMI1.10 12.1,88.85 14.15,88.85 14.33,88.68 ED5702.2 ED5702.9 15.6,88.69 17.41,88.69 R5771.2
HDMI_DDI_TX_N0: length 103.2
  TOP w0.102: C5731.1 30.01,84.57 30.24,84.57 30.32,84.5 30.32,84.1 30.47,83.94 31.08,83.94 31.2,84.07 31.2,84.42 31.31,84.52 v2(31.54,84.52)
  L6 w0.089: v2(111.67,85.16) 111.8,85.16 111.9,85.26 111.9,85.82 111.2,86.52 111.2,87.79 109.11,89.88 102.87,89.88 102.87,89.88 102.72,89.88 100.39,92.21 88.82,92.21 85.24,95.79 82.76,95.79 79.04,99.51 57.81,99.51 57.55,99.24 51.58,99.24 49.86,97.53 40.2,97.53 37.17,94.51 35.56,94.51 30.3,89.25 30.3,84.31 30.69,83.92 31.05,83.92 31.15,84.02 31.15,84.38 31.3,84.52 v2(31.54,84.52)
  BOTTOM w0.102: CPU1.AL5 111.77,85.48 111.67,85.38 v2(111.67,85.16)
HDMI_DDI_TX_N1: length 96.9
  TOP w0.102: C5734.1 30.24,85.79 30.71,85.79 v2(30.99,86.07)
  L6 w0.089: v2(30.99,86.07) 31.28,85.78 31.43,85.78 31.64,85.99 31.64,87.1 30.94,87.8 30.94,89.22 35.73,94.01 37.48,94.01 40.44,96.97 49.98,96.97 51.78,98.77 57.82,98.77 58.01,98.96 78.89,98.96 82.54,95.32 85.04,95.32 88.62,91.74 99.84,91.74 102.17,89.4 107.8,89.4 110.52,86.68 110.52,85.39 v2(110.73,85.18)
  BOTTOM w0.102: v2(110.73,85.18) 110.73,85.48 110.88,85.63 111.03,85.63 CPU1.AJ5
HDMI_DDI_TX_N2: length 93.1
  TOP w0.102: C5727.1 30.14,87.42 31.18,87.42 31.56,87.8 32.81,87.8 33.77,88.76 33.77,89.5 33.67,89.6 33.49,89.6 v2(33.41,89.53)
  L6 w0.089: v2(109.82,85.16) 109.61,85.16 109.36,85.41 109.36,86.4 107.74,88.03 101.89,88.03 98.96,90.96 88.46,90.96 84.77,94.66 82.16,94.66 78.54,98.28 58.52,98.28 58.36,98.11 52.06,98.11 50.1,96.16 40.96,96.16 40.96,96.16 40.81,96.16 37.91,93.26 36.01,93.26 33.27,90.51 33.27,90.13 33.41,89.98 v2(33.41,89.53)
  BOTTOM w0.102: CPU1.AF6 v2(109.82,85.16)
HDMI_DDI_TX_N3: length 89
  TOP w0.102: v2(32.55,89.2) 32.27,88.92 30.91,88.92 30.64,88.65 30.37,88.65 30.27,88.75 30.27,89.08 30.16,89.18 C5733.1
  L6 w0.089: v2(32.55,89.2) 32.85,88.91 34.88,88.91 41.38,95.41 52.18,95.41 54.23,97.45 58.71,97.45 58.83,97.57 78.31,97.57 81.88,94 84.49,94 88.33,90.16 99.06,90.16 101.86,87.37 107.27,87.37 107.57,87.07 107.57,85.53 107.91,85.18 v2(107.96,85.18)
  BOTTOM w0.102: CPU1.AE5 v2(107.96,85.18)
HDMI_DDI_TX_P0: length 103.2
  TOP w0.102: C5737.1 29.91,83.71 31.18,83.71 v2(31.54,83.73)
  L6 w0.089: v2(31.54,83.73) 30.61,83.73 30.11,84.23 30.11,89.33 35.48,94.7 37.09,94.7 40.12,97.72 49.79,97.72 51.5,99.43 57.47,99.43 57.74,99.7 79.12,99.7 82.84,95.98 85.32,95.98 88.9,92.4 100.47,92.4 102.79,90.07 109.19,90.07 111.39,87.87 111.39,86.6 112.09,85.9 112.09,84.99 v2(111.65,84.55)
  BOTTOM w0.102: CPU1.AL6 v2(111.65,84.55)
HDMI_DDI_TX_P1: length 96.9
  TOP w0.102: v2(30.99,85.28) 30.71,85.57 30.09,85.57 C5732.1
  L6 w0.089: v2(110.71,84.5) 110.53,84.82 110.33,85.02 110.33,85.35 110.33,86.6 107.72,89.21 102.09,89.21 99.76,91.55 88.54,91.55 84.96,95.13 82.46,95.13 78.81,98.77 58.09,98.77 57.9,98.58 51.86,98.58 50.06,96.78 40.52,96.78 37.56,93.82 35.81,93.82 31.13,89.14 31.13,87.88 31.83,87.18 31.83,85.91 31.5,85.59 31.29,85.59 v2(30.99,85.28)
  BOTTOM w0.102: CPU1.AJ6 v2(110.71,84.5)
HDMI_DDI_TX_P2: length 93.1
  TOP w0.102: C5728.1 30.19,87.19 31.27,87.19 31.66,87.57 32.91,87.57 34,88.66 34,89.6 33.85,89.75 33.85,89.96 v2(33.97,90.09)
  L6 w0.089: v2(33.97,90.09) 33.58,90.09 33.46,90.21 33.46,90.43 36.09,93.07 37.99,93.07 40.89,95.97 50.18,95.97 52.14,97.92 58.44,97.92 58.6,98.09 78.46,98.09 82.08,94.47 84.69,94.47 88.38,90.77 98.88,90.77 101.81,87.84 107.66,87.84 109.17,86.32 109.17,85.37 v2(108.9,85.11)
  BOTTOM w0.102: CPU1.AF5 109.19,85.61 109.05,85.61 108.9,85.47 v2(108.9,85.11)
HDMI_DDI_TX_P3: length 89
  TOP w0.102: C5735.1 30.74,88.42 31,88.69 32.27,88.69 v2(32.55,88.41)
  L6 w0.089: v2(32.55,88.41) 32.86,88.71 34.96,88.71 41.46,95.22 52.26,95.22 54.31,97.26 58.79,97.26 58.91,97.38 78.24,97.38 81.8,93.81 84.42,93.81 88.25,89.97 98.98,89.97 101.78,87.18 107.19,87.18 107.38,86.99 107.38,85.45 107.53,85.3 107.53,84.96 v2(107.96,84.52)
  BOTTOM w0.102: v2(107.96,84.52) CPU1.AE6
HDMI_HPD_ALS: length 3.5
  TOP w0.102: R5760.2 v1(26.34,91.01) 26.56,90.8 26.56,89.89 25.97,89.31 U5701.B1
HDMI_HPD_CON: length 42.6
  TOP w0.102: HDMI1.19 10.83,93.63 12.76,93.63 14.18,92.2 ED5703.6 ED5703.5 15.75,92.2 v2(16.19,92.65) ; v2(31.28,95.62) 31.28,93.72 32.88,92.12 35.19,92.12 36.59,90.72 36.59,87.67 37.53,86.73 R5749.1 ; v2(20.38,93.58) 20.4,93.58 20.74,93.24 20.74,92.42 R5764.2 20.13,91.81 v1(20.13,91.08) 20.56,91.08 21.79,89.85 U5701.G1
  L6 w0.102: v2(31.28,95.62) 22.16,95.62 20.38,93.85 v2(20.38,93.58)
  BOTTOM w0.102: v2(16.19,92.65) 16.4,92.45 18.17,92.45 19.55,93.82 20.16,93.82 20.38,93.59 v2(20.38,93.58)
HDMI_HPD_CPU: length 142.6
  TOP w0.102: v2(25.74,94.22) 26.34,93.62 v1(26.4,93.62) 26.68,93.62 27.01,93.29 R5733.2 26.79,92.98 25.79,92.98 25.59,92.78 R5760.1
  L4SGND w0.102: v2(141.04,87.29) 141.26,87.52 141.26,90.54 140.93,90.87 140.93,94.58 138.44,97.07 134.88,97.07 134.37,97.58 134.37,100.95 131.91,103.42 108.07,103.42 107.1,102.46 106,102.46 103.36,105.1 84.62,105.1 82.74,103.22 48.76,103.22 47.33,101.8 34.68,101.8 28.51,95.62 27.14,95.62 v2(25.74,94.22)
  BOTTOM w0.102: v2(141.04,87.29) 141.04,87.21 139.27,85.44 138.28,85.44 137.92,85.08 CPU1.CN6
HDMI_SCL_CON: length 22.2
  TOP w0.089: R5755.2 22.9,91.05 v2(22.87,91.03) 22.74,90.89 22.74,90.3 23.01,90.03 23.01,89.75 23.39,89.37 U5701.E1 ; v2(13.23,90.09) 13.49,90.35 14.13,90.35 14.27,90.2 ED5703.10 ED5703.1 16.03,90.2 16.18,90.35 16.38,90.35 v2(16.62,90.11)
  L6 w0.089: HDMI1.15 10.82,91.21 10.88,91.33 10.85,91.41 10.85,93.14 11.26,93.55 12.56,93.55 13.89,92.22 13.89,90.55 13.69,90.35 13.49,90.35 v2(13.23,90.09) ; v2(16.62,90.11) 16.88,90.37 17.73,90.37 18.02,90.67 22.52,90.67 v2(22.87,91.03)
HDMI_SCL_R: length 1.8
  TOP w0.089: D5701.2 22.17,93.53 22.9,92.8 R5755.1
HDMI_SDA_CON: length 20.6
  TOP w0.089: U5701.F1 22.82,89.53 22.82,89.95 22.55,90.22 22.55,90.8 v2(22.26,91.08) 22.14,91.2 R5751.2 ; v2(16.62,90.83) 16.33,90.54 16.18,90.54 16.03,90.68 ED5703.2 ED5703.9 14.27,90.68 14.13,90.54 13.49,90.54 v2(13.23,90.8)
  L6 w0.089: v2(16.62,90.83) 16.88,90.56 17.65,90.56 17.94,90.86 22.05,90.86 v2(22.26,91.08) ; HDMI1.16 11.17,91.33 11.06,91.38 11.04,91.44 11.04,93.06 11.34,93.36 12.49,93.36 13.7,92.15 13.7,90.63 13.61,90.54 13.49,90.54 v2(13.23,90.8)
HDMI_SDA_R: length 2.8
  TOP w0.089: R5751.1 22.14,93.3 21.13,94.3 D5701.1
HOST_DEBUG_TX: length 35.2
  TOP w0.102: DB3.5 34.09,6.43 R2480.1 33.39,7.13 33.39,7.54 29.66,11.26 29.66,14.35 v1(29.91,14.6) v2(31.61,16.3) ; R6801.1 43.52,21 43.35,20.82 43.35,19.25 41.67,17.57 41.67,16.15 v2(42.25,15.56)
  L6 w0.102: v2(42.25,15.56) 41.85,15.97 36.56,15.97 35.83,16.7 35.83,16.71 35.47,17.06 32.93,17.06 32.7,16.83 32.14,16.83 v2(31.61,16.3)
  BOTTOM w0.102: U2401.81 31.31,14.2 31.31,14.72 31.61,15.03 v2(31.61,16.3)
HOST_DEBUG_TX_CON: length 5.9
  TOP w0.102: DB1.11 39.77,24.85 40.81,23.82 41.64,23.82 42.28,23.18 v1(42.71,23.18) 42.89,23.01 42.89,22.04 R6801.2
HPDIN: length 2.2
  TOP w0.127: U7101.32 16.64,69.85 v2(16.56,69.92)
  BOTTOM w0.127: v1(16.04,70.25) v2(16.56,69.92) 16.57,69.92 16.57,69.94 R7121.2
HVA_GATE1: length 4.2
  TOP w0.102: 10.5,31.59 10.5,31.9 10.58,31.97 10.58,32.71 U7201.B9
  TOP w0.254: v2(10.58,30.37) 10.5,30.45 10.5,31.59
  BOTTOM w0.254: R7218.1 10.45,30.24 v2(10.58,30.37) v1(10.64,30.93)
HVA_GATE2: length 3.8
  TOP w0.178: U7201.A9 10.35,32.12 10.1,31.87
  TOP w0.254: v2(9.82,30.37) 10.1,30.65 10.1,31.87
  BOTTOM w0.254: R7219.1 9.67,30.22 v2(9.82,30.37) v1(9.42,30.83)
HW_ACAV_IN: length 17.7
  L4SGND w0.254: v2(23.15,29.58) 23.15,32.43 20.77,34.82 20.77,36.78 20.7,36.84 20.7,38.22 22.77,40.29 v2(22.77,40.62)
  BOTTOM w0.203: v2(23.15,29.58) 23.92,28.82 U2401.128
  BOTTOM w0.254: v1(25.08,41.14) PR4492.2 24.17,41.27 23.53,40.62 v2(22.77,40.62)
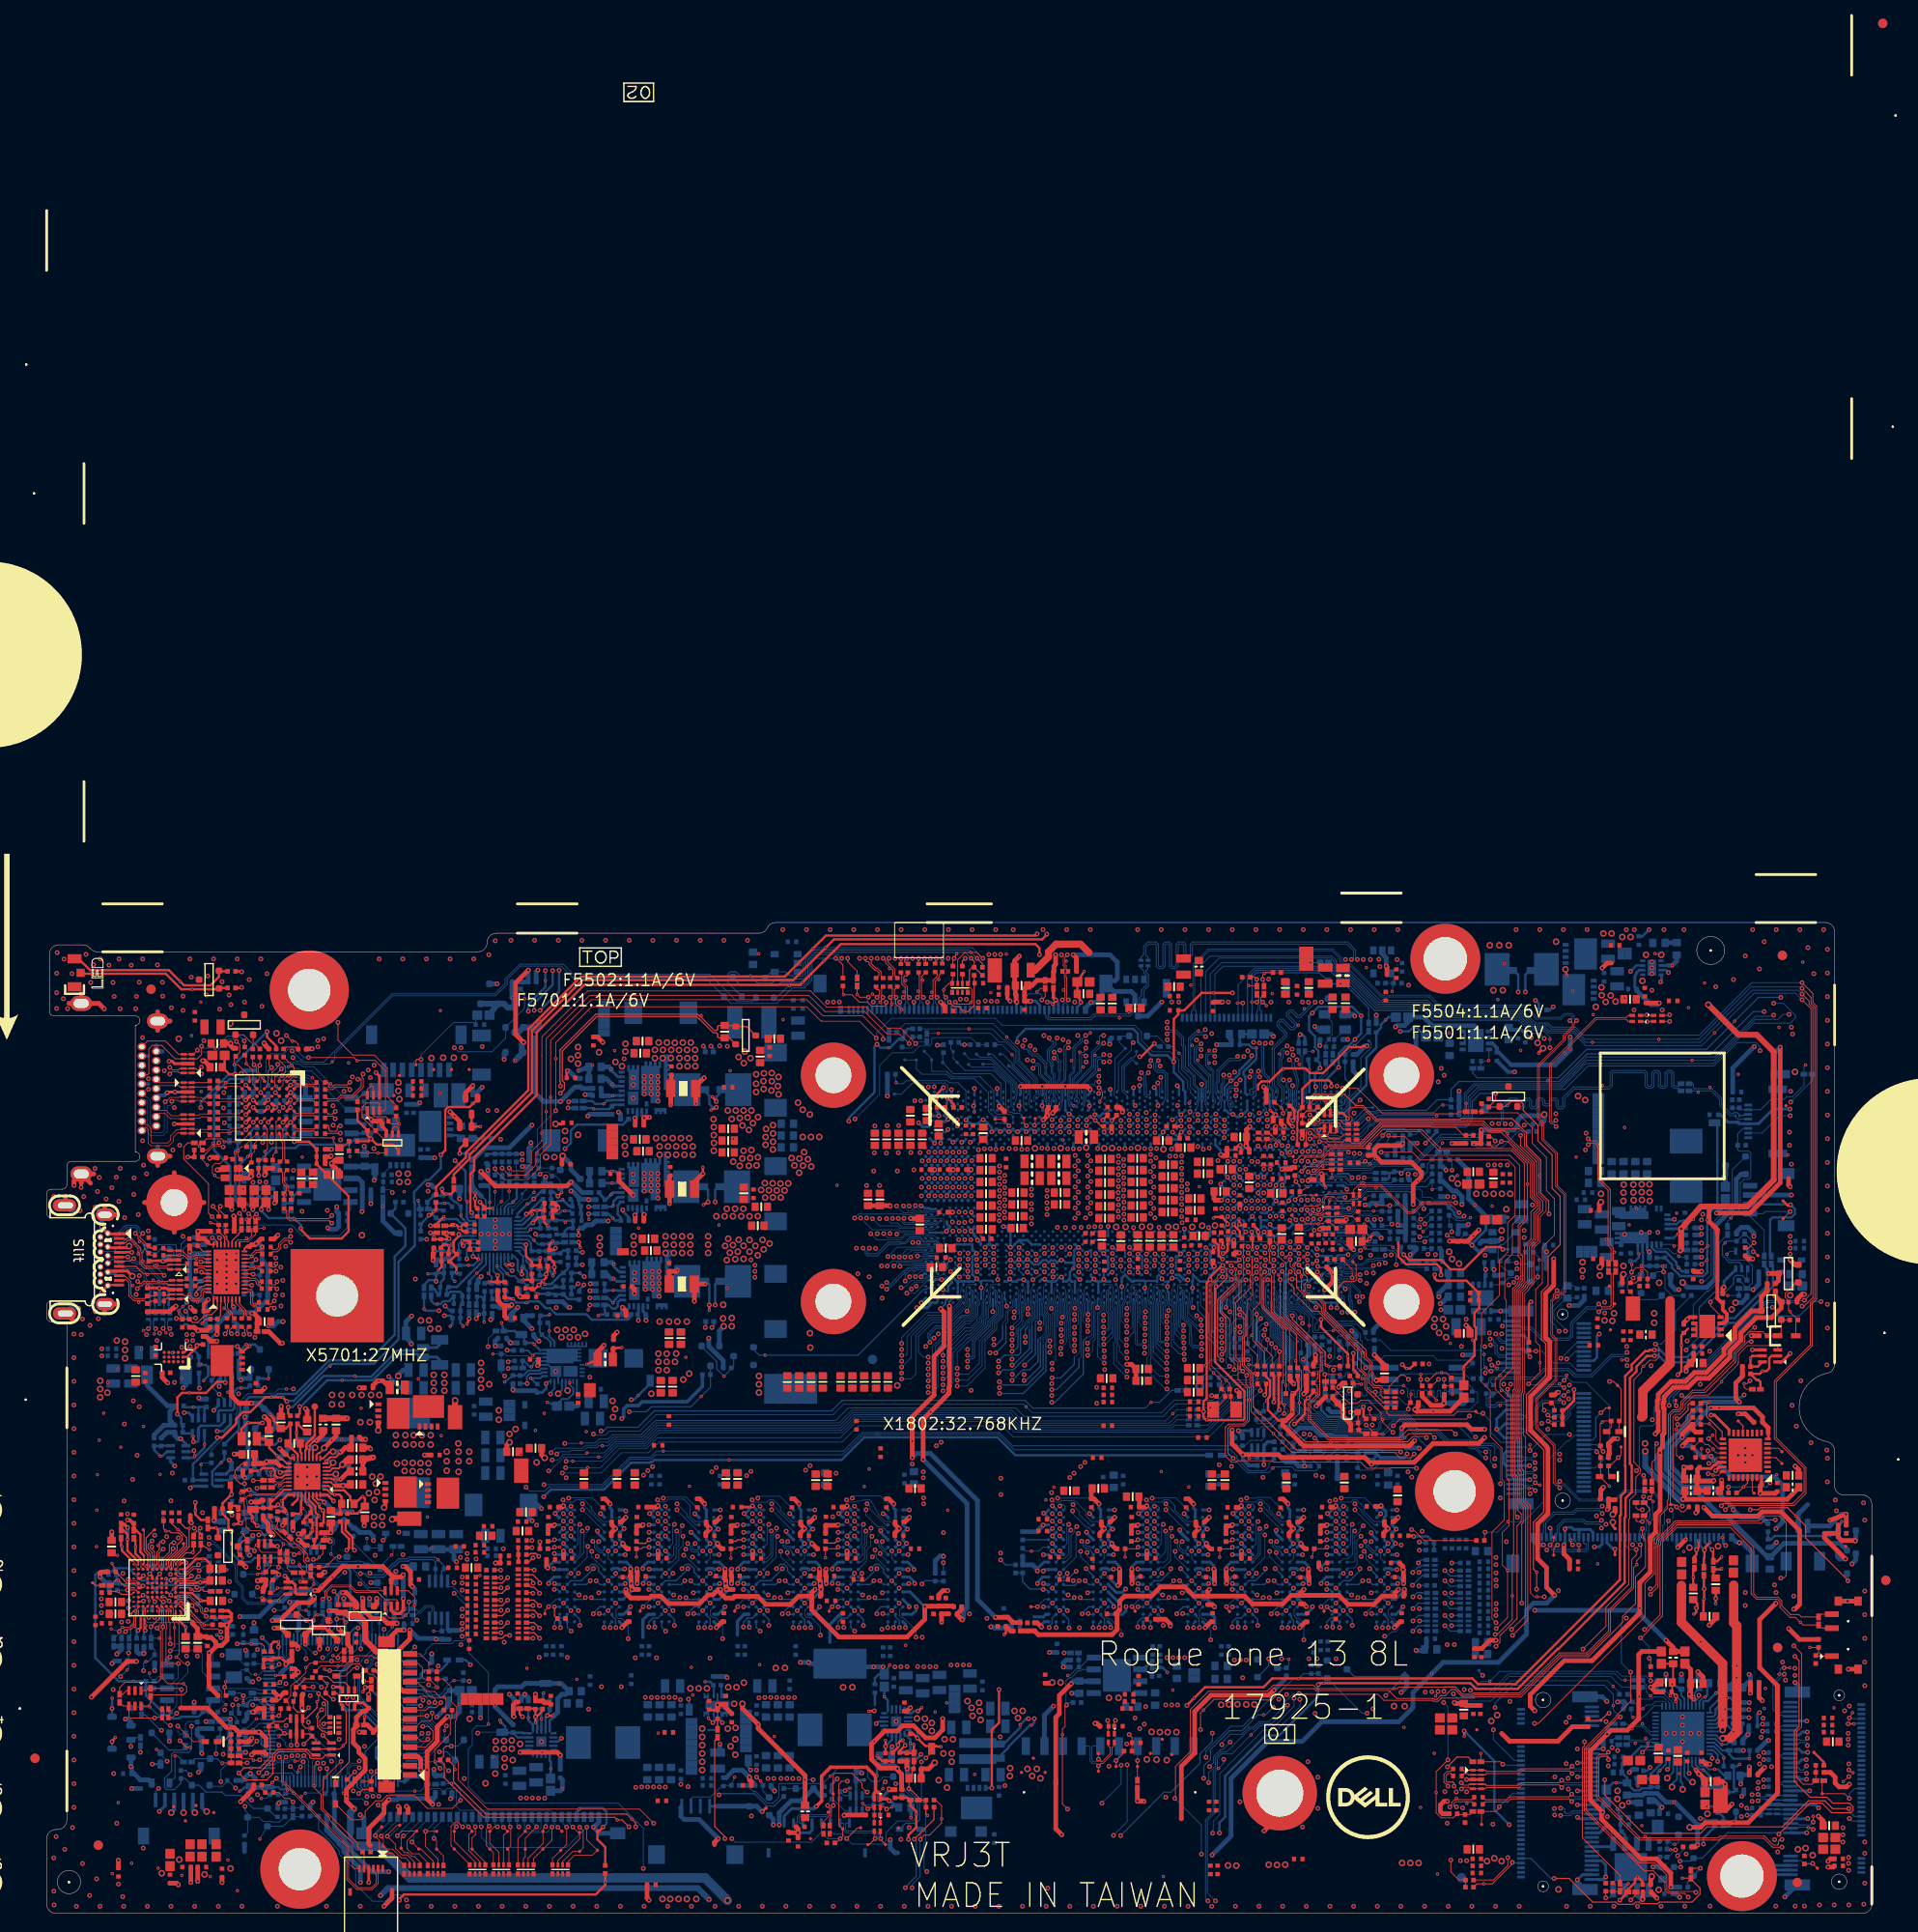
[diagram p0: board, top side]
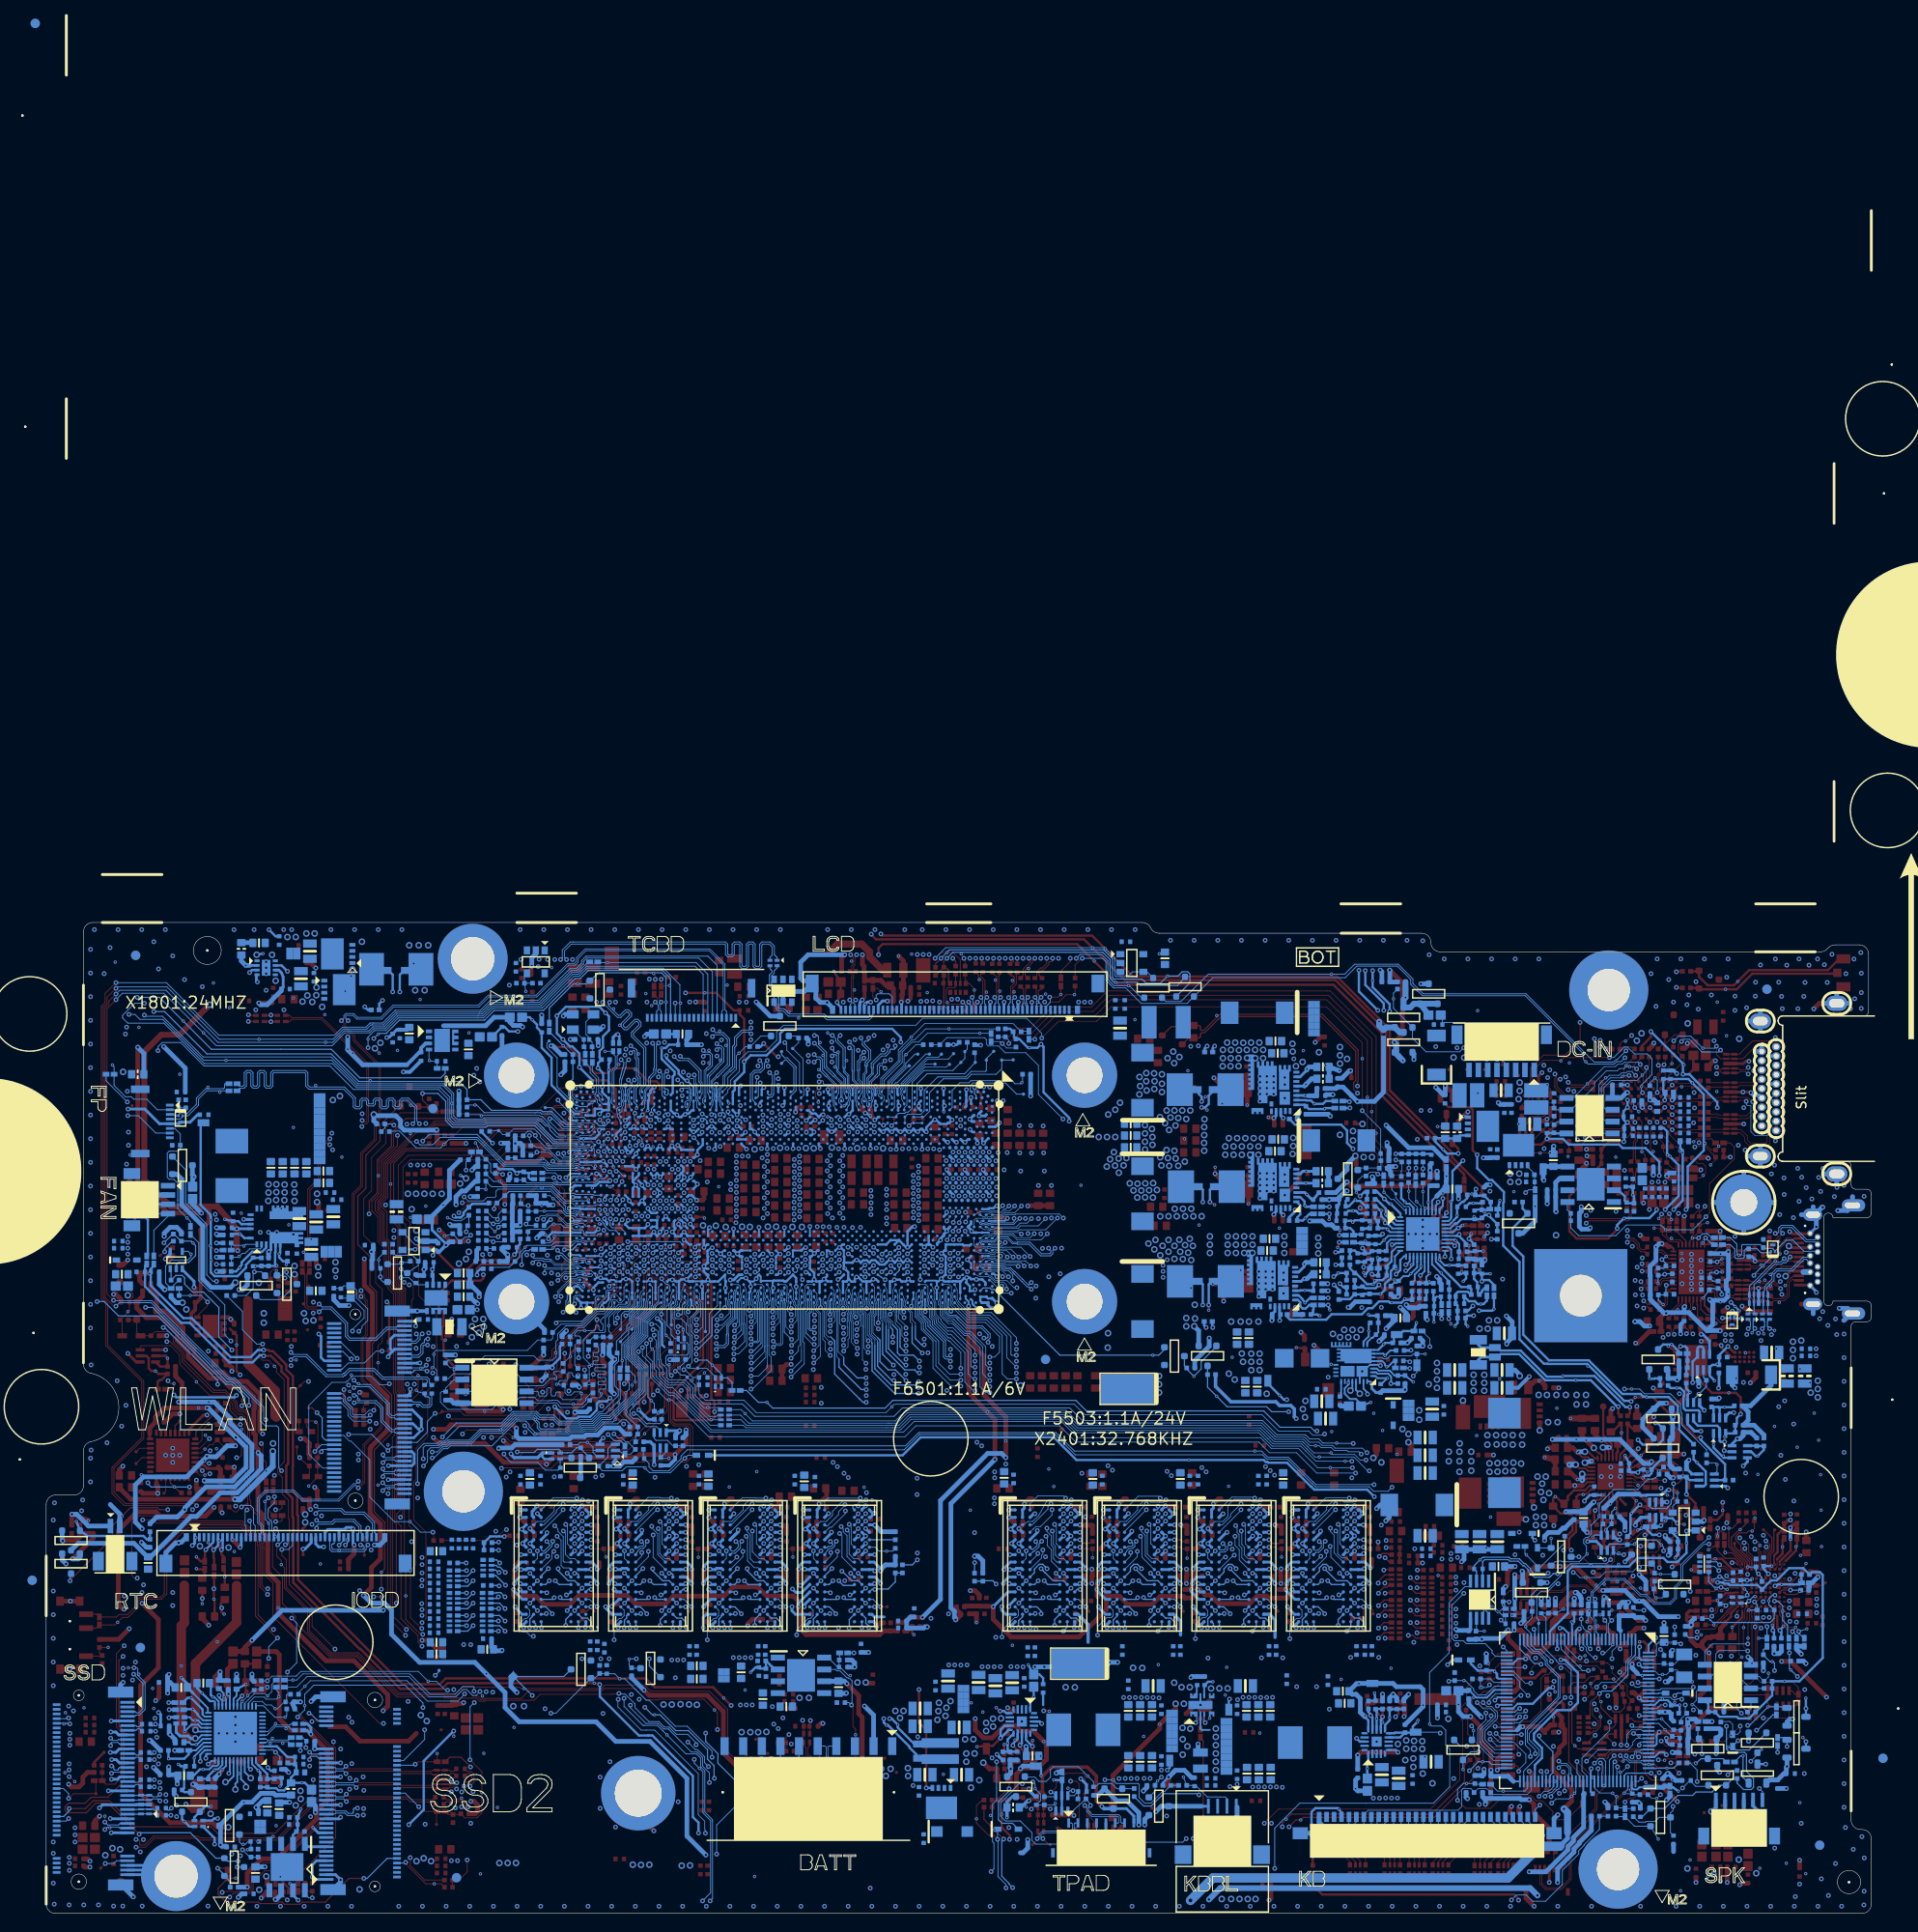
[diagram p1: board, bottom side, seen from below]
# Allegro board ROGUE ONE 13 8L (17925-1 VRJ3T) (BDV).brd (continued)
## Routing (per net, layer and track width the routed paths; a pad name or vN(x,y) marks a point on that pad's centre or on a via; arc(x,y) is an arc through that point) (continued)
HW_ACAVIN_NB: length 35.3
  TOP w0.254: v2(19.85,41.04) 19.52,41.37 19.52,42.26 18.89,42.89 R4378.2 18.89,44.01 v2(19.85,44.98) 19.85,45.82 D4305.A
  BOTTOM w0.203: U2401.24 34.53,30.27
  BOTTOM w0.254: Q4349.5 19.52,46.5 R4315.2 ; R4311.2 R4315.2 ; R4315.2 v2(19.85,44.98) ; U4302.1 19.79,41.1 v2(19.85,41.04) v1(19.85,39.72) 19.85,38.69 20.83,37.71 21.89,37.71 22.33,38.15 25.12,38.15 26.04,37.23 32.13,37.23 32.6,36.75 32.6,32.2 34.53,30.27
I2C_CLK_PD: length 56.2
  TOP w0.089: U7201.D2 14.07,34.17 14.52,34.17 14.56,34.12 15.39,34.12 16.71,32.8 16.71,32.48 16.82,32.38 16.96,32.38 v2(17.16,32.58) 17.25,32.48 RN7206.3 ; v2(22.53,75.05) 22.44,75.05 22.18,74.78 22.18,74.58 R7114.2
  L6 w0.089: v2(22.53,75.05) 22.52,75.05 22.1,74.62 22.1,72.99 22,72.89 22,69.65 23.01,68.64 23.01,56.76 22.31,56.07 22.31,55.95 20.51,54.15 20.51,50.84 18.65,48.98 18.65,44.48 19.17,43.96 19.17,41.74 18.9,41.47 18.9,40.65 19.43,40.13 19.43,37.27 20.49,36.21 20.49,35.57 19.9,34.99 18.39,34.99 16.38,32.98 16.38,32.51 16.47,32.42 16.77,32.42 16.93,32.58 v2(17.16,32.58)
  BOTTOM w0.089: v1(22.83,74.58) v2(22.53,75.05)
I2C_CLK_PD_MUX: length 3.7
  TOP w0.089: v1(23.33,73.55) R7114.1 22.44,72.89 21.65,72.1 20.84,72.1 20.72,71.98 U7101.21
I2C_DATA_PD: length 56
  TOP w0.089: R7116.2 21.98,74.62 21.98,74.8 v2(21.69,75.09) ; U7201.D1 14.36,33.93 15.31,33.93 16.52,32.72 16.52,32.4 16.74,32.19 16.83,32.19 17.13,31.89 v2(17.13,31.89) 17.21,31.81 RN7206.4
  L6 w0.089: v2(17.13,31.89) 16.9,31.89 16.57,32.23 16.39,32.23 16.19,32.43 16.19,33.06 18.31,35.18 19.82,35.18 20.3,35.65 20.3,36.13 19.24,37.19 19.24,40.05 18.71,40.57 18.71,41.55 18.98,41.82 18.98,43.88 18.46,44.4 18.46,49.05 20.32,50.91 20.32,54.22 22.12,56.03 22.12,56.15 22.82,56.84 22.82,68.56 21.81,69.57 21.81,72.97 21.91,73.07 21.91,74.74 21.71,74.95 21.71,75.08 v2(21.69,75.09)
  BOTTOM w0.089: v1(21.46,74.46) v2(21.69,75.09)
I2C_DATA_PD_MUX: length 3.3
  TOP w0.089: R7116.1 22.04,73.09 22.04,72.75 21.57,72.29 21.48,72.29 ; 21.48,72.29 20.55,72.29 20.32,72.05 U7101.22 ; 21.48,72.29 v1(21.48,72.46)
I2CEN: length 3.7
  TOP w0.127: U7101.17 22.17,69.85 v2(22.49,70.17)
  BOTTOM w0.127: 22.9,69.26 22.29,69.26 R7173.1 22.06,69.74 v2(22.49,70.17) v1(22.04,70.5)
I_ADP: length 4
  BOTTOM w0.102: R2421.2 20.49,19.7 C2435.1 21.35,19.7 v1(22.52,20.87) 22.98,20.87 23.06,20.79 U2401.110
I_BATT: length 4.8
  BOTTOM w0.203: U2401.114 23.26,22.39 22.76,22.88 21.88,22.88
  BOTTOM w0.254: 21.88,22.88 21.5,22.5 C2441.1 20.64,22.32 v1(20.59,22.37) 20.59,21.58 R2423.2
IC_DELAY: length 2.3
  BOTTOM w0.102: U4302.4 21.34,43.69 C4344.1 v1(20.82,45.13)
ICSP_CLK: length 24.1
  TOP w0.089: 25.98,13.36 32.23,7.11 32.23,3.62 33.3,2.55 34.96,2.55 35.59,3.18 DB3.2 ; 25.98,13.36 25.24,14.1 25.24,16.52 v2(24.98,16.78) ; 25.98,13.36 v1(25.85,13.23)
  BOTTOM w0.089: U2401.101 24.7,17.19 24.8,17.29 25.21,17.29 25.25,17.25 25.25,16.9 25.13,16.78 v2(24.98,16.78)
ICSP_CLR: length 37.3
  TOP w0.102: DB3.6 33.1,4.8 32.86,5.05 32.86,7.54 30.37,10.03 30.37,10.27 29.46,11.18 29.46,12.76 28.72,13.51 v1(28.72,13.71) 28.72,15.77 v2(29.1,16.15)
  L4SGND w0.102: v2(29.1,16.15) 29.1,17.97 27.03,20.04 26.9,20.04 25.67,21.27 25.67,22.87 26.5,23.7 26.5,24.89 25.08,26.31 24.78,26.31 24.52,26.56 24.52,27.17 25.59,28.24 25.59,31.36 v2(24.42,32.53)
  BOTTOM w0.102: v2(29.1,16.15) 28.89,15.94 28.89,15.11 28.94,15.06 U2401.87 ; v2(24.42,32.53) 25.26,32.53 R2414.1
ICSP_DAT: length 23.8
  TOP w0.089: DB3.3 35.09,4.47 35.4,4.16 35.4,3.26 34.88,2.74 33.38,2.74 32.42,3.7 32.42,7.19 27.21,12.41 ; v2(25.7,16.78) 25.43,16.52 25.43,14.18 27.21,12.41 ; 27.21,12.41 v1(27.34,12.54)
  BOTTOM w0.089: U2401.102 24.7,17.59 24.8,17.48 25.29,17.48 25.44,17.33 25.44,17.04 v2(25.7,16.78)
INPUT3VSEL: length 30.5
  L6 w0.102: v2(133.54,72.09) 133.84,72.09 134.61,72.87 136.97,72.87 138.04,73.93 139,73.93 139.19,73.74 139.69,73.74 141.02,75.08 141.9,75.08 143.36,76.54 147.42,76.54 147.91,76.05 148.08,76.05 148.33,75.79 148.33,75.63 149.39,74.57 149.39,73.81 v2(150.41,72.79)
  BOTTOM w0.102: CPU1.BT27 127.96,72.09 v2(133.54,72.09) ; v2(150.41,72.79) 150.61,72.59 151.04,72.59 R1521.1 R1520.2 v1(153.24,72.69)
IR_CAM_DET#: length 6.8
  BOTTOM w0.076: 139.93,75.09 139.85,75.09 139.84,75.08 139.41,75.08 139.4,75.09 139.35,75.09 139.27,75.16 arc(139.18,75.22) 139.08,75.24 138.99,75.24 arc(138.96,75.24) 138.92,75.23 arc(138.92,75.23) 138.92,75.23 arc(138.87,75.21) 138.82,75.18 138.68,75.04 138.68,74.88 138.61,74.81 arc(138.53,74.75) 138.44,74.73 138.03,74.73 137.93,74.64 137.36,74.64 CPU1.CM22
  BOTTOM w0.102: 139.93,75.09 140.08,75.09 140.41,75.42 140.41,75.64 141.47,76.7 v1(141.57,76.7) 141.9,77.03 R2046.2
ISH_KB_DISABLE: length 20.3
  BOTTOM w0.076: 131.22,63.86 129.95,65.13 129.92,65.13 129.7,65.35 129.7,65.66 129.72,65.72 129.72,66.02 129.7,66.08 129.7,66.31 129.74,66.43 129.74,66.63 CPU1.BW35
  BOTTOM w0.102: 131.22,63.86 131.57,63.51 131.57,63.5 131.58,63.49 131.58,62.01 133,60.59 133,60.04 131.58,58.63 131.58,55.73 v1(132.5,54.8) 133.31,53.99 133.31,53.47 132.97,53.13 132.45,53.13 131.56,52.24 130.47,52.24 130.06,51.83 Q2001.2
IST_TRIG: length 8.2
  TOP w0.102: TP620.1 140.63,69.59 140.63,67.99 140.45,67.81 139.28,67.81 138.72,67.25 138.72,65.96 v2(139.26,65.42)
  BOTTOM w0.102: CPU1.CP36 138.56,66.32 139.17,66.32 139.35,66.14 139.35,65.52 v2(139.26,65.42)
ITP_PMODE: length 8
  BOTTOM w0.102: CPU1.W4 104.91,86.49 104.91,88.51 104.99,88.59 104.99,88.93 104.75,89.16 104.61,89.16 101.55,92.22 TP618.1
JACK_PLUG: length 4.5
  TOP w0.254: v1(178.62,39.8) 178.15,39.33 178.15,39.14 v2(178.02,39.01) 178.02,38.15 177.97,38.09 R2923.1
  BOTTOM w0.254: v2(178.02,39.01) 177.55,39.48 CN6601.6
JGND:
  vias: v3(37.77,89.17) v3(37.77,88.28) v3(37.89,87.39)
JIO3_PCIE_WAKE#: length 44.6
  TOP w0.102: v2(159.3,49.68) v1(159.3,50.28)
  L6 w0.102: v2(163.54,51.4) 163.54,53.03 161.23,55.34 161.23,60.85 160.19,61.89 160.19,67.79 160.54,68.14 160.54,68.53 157.98,71.09 157.98,73.73 157.01,74.69 155.26,74.69 152.31,77.64 152.31,78.35 150.92,79.75 v2(150.92,79.77)
  BOTTOM w0.102: R1806.2 150.33,81.22 R1819.2 150.92,80.64 v2(150.92,79.77) ; WLAN1.55 158.92,50.05 v2(159.3,49.68) 161.02,51.4 v2(163.54,51.4)
KB_BL_CTRL#: length 6.5
  TOP w0.254: AFTP6530.1 77.22,11.3 v2(76.84,10.91)
  BOTTOM w0.305: 71.92,11.5 KBBL1.4
  BOTTOM w0.508: 71.92,11.5 75.31,11.5 75.31,11.5 Q6501.D 76.25,11.5 v2(76.84,10.91)
KB_DET#: length 220.1
  TOP w0.102: v2(155.56,29.94) 155.77,29.94 155.9,30.07 155.91,30.07 157.39,31.55 v1(157.39,34.08) 157.39,38.4 157.53,38.54 157.53,45.52 157.54,45.53 157.54,46.71 157.27,46.98 157.27,55.27 156.06,56.47 156.06,57.11 157.42,58.47 157.42,67.02 157.96,67.56 157.96,67.71 158.31,68.06 158.31,68.4 158.31,68.4 158.31,70.22 158.03,70.5 158.03,73.84 158.69,74.5 158.69,80.5 157.33,81.86 149.54,81.86 147.48,83.92 143.9,83.92 v2(143.47,83.49)
  L6 w0.102: v2(124.78,14.04) 124.78,13.58 125.01,13.35 125.01,12.49 122.18,9.66 107.82,9.66 106.92,8.76 106.9,8.76 106.85,8.71 106.7,8.71 106.7,8.71 104.99,8.71 104.99,8.71 95.67,8.71 95.63,8.76 95.24,8.76 94.66,9.34 93.84,9.34 93.16,10.03 92.32,10.03 91.43,9.14 82.13,9.14 81.47,9.8 80.24,9.8 79.3,8.86 74.56,8.86 74.13,9.29 69.68,9.29 69.43,9.04 64.17,9.04 63.41,9.79 41.62,9.79 41.36,10.05 41.07,10.05 40.91,10.05 39.99,10.97 39.74,10.97 39.69,11.02 36.21,11.02 v2(35.6,11.63) ; v2(155.56,29.94) 155.46,29.94 155.21,29.69 155.21,28.74 155.23,28.72 155.23,24.39 155.23,23.97 152.41,21.15 152.41,21.15 152.23,20.98 145.13,20.98 144.84,21.28 143.96,21.28 142.71,22.52 135.14,22.52 134.96,22.34 v2(133.26,22.34)
  BOTTOM w0.076: 141.14,82.14 138.88,82.14 138.88,82.14 arc(138.85,82.15) 138.81,82.16 138.63,82.16 arc(138.57,82.15) 138.51,82.12 arc(138.44,82.1) 138.37,82.09 arc(138.3,82.1) 138.24,82.13 arc(138.2,82.15) 138.15,82.16 138.13,82.18 137.53,82.18 137.53,82.18 137.29,82.18 137.28,82.18 137.11,82.01 137.11,81.36 CPU1.CM12
  BOTTOM w0.102: R2045.2 144.27,83.95 143.94,83.95 v2(143.47,83.49) 143.47,83.33 142.28,82.14 141.14,82.14 ; v2(35.6,11.63) 36.1,11.12 KB1.30 ; v2(133.26,22.34) 133.26,22.06 131.57,20.38 130.28,20.38 129.7,19.79 129.19,19.79 126.71,17.32 126.08,17.32 125.52,16.75 125.52,15.81 124.79,15.09 124.78,15.06 v2(124.78,14.04)
KB_DISABLE_CPU_R: length 3.2
  BOTTOM w0.102: R2001.2 129.41,49.54 Q2001.6 ; R2001.2 129.91,48.84 v1(129.12,48.84) ; R2001.2 130.06,48.99 Q2001.5
KB_LED_BL_DET: length 161.7
  L4SGND w0.102: v2(141.24,63.37) 143.55,61.05 151.73,61.05 v2(151.93,60.85)
  L6 w0.102: v2(82.31,14.34) 82.87,13.78 88.84,13.78 91.15,16.1 92.5,16.1 93.43,15.16 96.19,15.16 99.72,11.63 105.63,11.63 108.98,14.98 109.76,14.98 109.76,14.98 109.93,14.98 109.93,14.98 113.85,14.98 120.04,14.98 121.87,16.81 122.4,16.81 122.96,17.37 122.98,17.37 123.8,18.19 123.97,18.19 123.97,18.19 125.71,18.19 126.13,18.62 126.27,18.62 126.93,17.96 127.38,17.96 128.78,19.36 144.04,19.36 144.76,18.64 148.88,18.64 149.05,18.46 149.32,18.46 149.83,17.96 155.52,17.96 158.2,20.64 158.2,24.96 160.31,27.07 160.31,33.29 159.06,34.55 159.06,41.69 160.31,42.94 160.31,46.5 161.08,47.26 161.08,49.8 158.66,52.22 158.66,53.14 156.06,55.74 156.06,58.13 156.3,58.36 156.3,59.25 155.59,59.96 152.82,59.96 v2(151.93,60.85)
  BOTTOM w0.102: v2(82.31,14.34) 81.45,14.34 v1(81.42,14.32) 81.04,13.94 78.74,13.94 78.64,13.84 78.64,12.45 78.02,11.83 77.37,11.83 76.11,13.09 75.87,13.09 75.22,13.73 R6507.1 ; v2(141.24,63.37) 141.06,63.54 138.44,63.54 136.97,65.01 136.97,65.73 137.05,65.81 137.05,66.06 136.86,66.25 CPU1.CK36
KB_LED_DET_C: length 6.7
  BOTTOM w0.102: v1(73.88,14.62) R6507.2 72.76,13.73 C6504.1 72.48,13.66 71.31,12.49 69.38,12.49 69.2,12.31 KBBL1.2
KB_LED_PWM: length 47.6
  TOP w0.102: v2(76.24,14.62) v1(76.66,14.2)
  L6 w0.102: v2(41.06,22.62) 41.06,22.32 41.24,22.14 42.97,22.14 44.88,20.22 53.37,20.22 55.51,22.37 60.9,22.37 63.09,22.37 64.26,21.2 64.98,21.2 68.62,21.2 69.36,20.47 70.78,20.47 71.44,19.8 71.44,18.05 75.3,14.19 75.81,14.19 v2(76.24,14.62)
  BOTTOM w0.102: Q6501.G 76.92,13.11 R6509.1 76.92,13.94 v2(76.24,14.62) ; U2401.44 40.35,23.59 41.06,22.88 v2(41.06,22.62)
KBC_BEEP_R: length 2.5
  BOTTOM w0.254: D2702.1 181.41,10.11 v1(181.16,9.86) 180.62,9.32 RN2702.4
KBC_PS2_SCL_TP: length 7.1
  TOP w0.089: RN6502.4 89.52,8.07 v2(89.57,8.02) 89.57,7.89 AFTP6532.1
  BOTTOM w0.089: v2(89.57,8.02) 89.36,8.23 89.36,8.51 89.03,8.84 85.94,8.84 85.8,8.99 85.8,9.61 85.88,9.7 TPAD1.1
KBC_PS2_SDA_TP: length 7.3
  TOP w0.089: RN6502.3 88.87,8.12 v2(88.96,8.02) 88.33,7.38 AFTP6533.1
  BOTTOM w0.089: v2(88.96,8.02) 89.17,8.23 89.17,8.43 88.95,8.65 85.87,8.65 85.61,8.91 85.61,9.61 85.52,9.7 TPAD1.2
KBC_PWRBTN#: length 238.3
  TOP w0.102: v2(183.05,61.37) 182.7,61.37 181.4,60.07 181.4,59.2 178.09,55.9 176.8,55.9 175.69,54.79 175.69,54.25 175.29,53.84 174.73,53.84 174.36,53.47 174.36,53.24 174.36,53.24 174.36,53.04 174.36,53.04 174.36,43.93 AFTP6609.1 174.77,43.88 v2(175.03,43.62) 175.54,43.11 175.82,43.11 C6605.1
  L4SGND w0.102: v2(187.29,87.09) 184.95,84.75 184.95,67.07 183.87,65.99 183.87,61.8 183.44,61.37 v2(183.05,61.37) ; v2(132.32,22.98) 132.32,21.99 133.31,21 136.79,21 142.55,26.75 142.87,26.75 143.19,27.07 151.86,27.07 152.09,27.3 152.76,27.3 152.96,27.3 153.16,27.3 155.97,27.3 160.31,31.64 160.31,34.33 163.46,37.48 170.24,37.48 172.07,39.32 172.07,42.03 173.8,43.76 174.84,43.76 174.98,43.62 v2(175.03,43.62)
  L6 w0.102: v2(132.32,22.98) 132.12,22.78 131.15,22.78 130.83,22.47 130.7,22.47 130.53,22.47 129.93,21.86 128.28,21.86 127.75,21.86 127.44,21.56 126.45,21.56 126.04,21.15 124.4,21.15 124.22,20.97 117.63,20.97 117.12,20.47 115.83,20.47 115.83,20.47 115.66,20.47 115,19.8 103.91,19.8 102.62,21.09 102.62,21.16 101.97,21.81 101.97,23.52 100.09,25.39 97.32,25.39 95.81,26.9 93.77,26.9 93.63,26.92 82.48,26.92 81.7,26.14 80.98,26.14 80.1,27.02 72.45,27.02 71.78,26.35 70.62,26.35 70.61,26.36 66.89,26.36 66.08,26.36 56.6,26.36 56.55,26.32 46.84,26.32 45.51,27.65 43.75,27.65 43.04,28.36 40.53,28.36 40.3,28.14 38.22,28.14 37.58,28.78 35.75,28.78 35.06,29.47 32.23,29.47 32.19,29.43 25.94,29.43 25.25,30.12 24.04,30.12 23.41,30.75 v2(21.12,30.75)
  BOTTOM w0.102: R9218.2 189.57,89.38 v2(187.29,87.09) ; R2432.2 v2(21.12,30.75) ; CN6601.14 173.55,41.61 173.74,41.8 173.74,43.47 174.05,43.78 174.87,43.78 v2(175.03,43.62)
KBC_SMB_SCL_BAT: length 7.5
  TOP w0.089: AFTP4311.1 112.94,15.81 v2(112.96,15.83) 113.22,16.09 113.42,16.09 114.4,17.07 114.4,17.79 114.66,18.05 RN4302.4
  BOTTOM w0.089: v2(112.96,15.83) 112.7,16.08 112.3,16.08 112.05,16.33 112.05,17.86 111.97,17.95 BATT1.4
KBC_SMB_SDA_BAT: length 6.9
  TOP w0.089: RN4302.3 114.01,17.97 114.21,17.77 114.21,17.15 113.34,16.28 113.22,16.28 v2(112.96,16.54) 112.94,16.55 AFTP4310.1
  BOTTOM w0.089: BATT1.5 112.33,17.95 112.25,17.86 112.25,16.41 112.38,16.27 112.69,16.27 v2(112.96,16.54)
KSI0: length 29.8
  TOP w0.089: RN2403.5 42.61,6.16 AFTP6512.1 41.87,7.78 v2(41.59,8.06)
  L4SGND w0.089: v2(26.96,16.94) 26.81,16.78 26.81,15.14 29.59,12.36 29.59,12.03 34.08,7.54 35.76,7.54 35.83,7.61 38.57,7.61 39.16,8.2 40.42,8.2 40.42,8.19 40.93,8.19 40.94,8.2 41.45,8.2 v2(41.59,8.06)
  BOTTOM w0.089: KB1.22 42.5,9.99 41.59,9.09 v2(41.59,8.06) ; U2401.98 24.52,15.99 24.7,16.17 25.97,16.17 26.28,16.48 26.5,16.48 26.96,16.94 v2(26.96,16.94)
KSI1: length 27.8
  TOP w0.089: RN2403.7 41.52,5.58 40.2,6.9 AFTP6501.1 39.23,7.64 v2(39.23,7.66)
  L4SGND w0.089: v2(39.23,7.66) 38.99,7.42 35.91,7.42 35.84,7.35 34,7.35 29.4,11.95 29.4,12.28 26.61,15.07 26.61,16.63 v2(26.33,16.91)
  BOTTOM w0.089: v2(26.33,16.91) 26.33,16.81 25.87,16.36 24.72,16.36 24.69,16.39 U2401.99 ; KB1.24 40.9,10.07 39.41,8.58 39.41,7.85 v2(39.23,7.66)
KSI2: length 39.6
  TOP w0.089: RN2403.8 40.93,5.43 39.97,6.39 39.24,6.39 38.7,6.94 38.7,7.79 AFTP6508.1 38.16,8.83 v2(37.66,8.32)
  L4SGND w0.089: v2(27.85,27.32) 27.47,26.94 27.47,23.3 26.63,22.47 26.63,21.72 27.28,21.08 28.15,21.08 28.61,20.61 28.61,19.45 30.16,17.91 30.16,16.15 30.79,15.52 30.79,13.69 30.85,13.63 30.85,12.12 33.76,9.2 35.27,9.2 37.57,9.2 37.66,9.11 v2(37.66,8.32)
  BOTTOM w0.089: KB1.26 39.3,10.07 37.66,8.43 v2(37.66,8.32) ; v2(27.85,27.32) 27.85,28.12 27.34,28.64 U2401.6
KSI3: length 38.4
  TOP w0.089: RN2403.6 42.02,5.84 40.68,7.18 v2(40.68,8.81) AFTP6509.1
  L4SGND w0.089: v2(40.68,8.81) 39.51,8.81 38.73,9.58 35.43,9.58 31.18,13.84 31.18,18.28 28.86,20.6 28.86,20.78 28.31,21.32 28.11,21.32 27.3,21.32 26.82,21.8 26.82,22.32 27.71,23.2 27.71,25.38 27.7,25.38 27.7,25.57 27.69,25.58 27.69,26.55 28.86,27.72 v2(28.86,27.95)
  BOTTOM w0.089: U2401.7 27.74,28.81 28.6,27.95 v2(28.86,27.95) ; v2(40.68,8.81) 41.7,9.83 KB1.23
KSI4: length 29.1
  TOP w0.089: RN2404.6 39.48,5.51 38.72,6.27 38.16,6.27 37.48,6.95 37.48,7.38 v2(36.59,8.27) 36.59,8.43 37.63,9.47 AFTP6505.1
  L4SGND w0.089: v2(36.59,8.27) 36.12,7.8 35.75,7.8 35.68,7.73 34.16,7.73 29.78,12.11 29.78,13.28 28.28,14.78 28.28,17.24 27.98,17.54 25.44,17.54 v2(24.93,18.05)
  BOTTOM w0.089: v2(36.59,8.27) 36.84,8.27 38.5,9.93 KB1.27 ; U2401.104 24.79,18.39 24.88,18.3 24.88,18.1 v2(24.93,18.05)
KSI5: length 28.8
  TOP w0.089: v2(38.32,8.32) 38.06,8.07 AFTP6506.1 38.06,6.9 38.44,6.52 38.79,6.52 39.2,6.11 39.49,6.11 40.07,5.53 RN2404.5
  L4SGND w0.089: v2(30.59,16.33) 30.98,15.94 30.98,13.77 31.04,13.71 31.04,12.2 33.84,9.39 35.35,9.39 37.91,9.39 38.32,8.98 v2(38.32,8.32)
  BOTTOM w0.089: KB1.25 40.1,9.93 38.49,8.32 v2(38.32,8.32) ; v2(30.59,16.33) 29.37,17.54 26.16,17.54 25.62,18.09 25.62,18.38 25.21,18.79 U2401.105
KSI6: length 28.7
  TOP w0.089: RN2404.7 38.98,5.53 38.55,5.96 38.09,5.96 37.15,6.9 36.46,6.9 AFTP6503.1 36.16,8.07 v2(35.93,8.3)
  L4SGND w0.089: v2(35.93,8.3) 35.93,8.25 35.61,7.92 34.24,7.92 30.28,11.88 30.28,12.36 30.28,13.09 28.49,14.88 28.49,14.89 28.47,14.9 28.47,17.9 27.79,18.59 26.79,18.59 v2(26.25,18.05)
  BOTTOM w0.089: U2401.107 24.59,19.59 24.74,19.73 25.72,19.73 26.25,19.2 v2(26.25,18.05) ; KB1.28 37.7,10.02 35.98,8.3 v2(35.93,8.3)
KSI7: length 28.1
  TOP w0.089: AFTP6502.1 35.29,8.6 v2(35.29,8.35) 35.29,8.27 35.73,7.84 35.73,6.75 36.01,6.47 37.12,6.47 38.39,5.2 RN2404.8
  L4SGND w0.089: v2(35.29,8.35) 35.29,8.64 35.11,8.82 33.61,8.82 30.47,11.96 30.47,12.28 30.47,13.18 28.66,14.98 28.66,18.06 26.92,19.8 26.8,19.8 26.43,20.16 v2(25.72,20.16)
  BOTTOM w0.089: v2(35.29,8.35) 36.9,9.96 KB1.29 ; U2401.108 25.54,19.99 v2(25.72,20.16)
KSO0: length 44.7
  TOP w0.089: RN2412.5 49.65,6.75 AFTP6507.1 49.84,7.25 49.84,9.23 v2(49.78,9.28)
  L4SGND w0.089: v2(29.5,24.28) 30.13,23.65 30.13,22.72 30.27,22.58 30.27,22.36 30.26,22.36 30.26,22.2 30.27,22.2 30.27,21.79 32.67,19.38 32.67,15.77 32.37,15.46 32.37,14.95 32.73,14.59 32.82,14.59 32.87,14.53 33.03,14.53 33.42,14.53 34.28,13.68 36.17,13.68 37.89,11.96 39.21,11.96 41.18,9.99 41.46,9.99 42.01,9.44 42.21,9.44 42.82,8.83 42.82,8.82 43.51,8.13 43.52,8.13 43.78,7.87 48.38,7.87 49.77,9.26 49.77,9.28 v2(49.78,9.28)
  BOTTOM w0.089: v2(29.5,24.28) 29,24.78 27.5,24.78 26.37,25.91 26.37,27.03 25.74,27.67 U2401.2 ; v2(49.78,9.28) 49.7,9.37 KB1.13
KSO1: length 40.9
  TOP w0.089: RN2412.7 48.56,6.57 47.59,7.54 AFTP6511.1 48.08,9.29 v2(48.4,9.29)
  L4SGND w0.089: v2(30.19,28.39) 30.17,28.37 30.17,26.89 31.2,25.85 31.2,23.17 31.22,23.16 31.22,22.8 31.2,22.78 31.2,21.79 32.69,20.31 33.32,20.31 33.99,19.64 33.99,19.26 33.5,18.77 33.5,17.1 34.02,16.58 34.02,15.22 34.02,14.91 34.84,14.1 36.51,14.1 38.15,12.46 39.09,12.46 39.25,12.46 41.34,10.37 41.61,10.37 42.17,9.82 42.37,9.82 43.2,8.99 43.2,8.98 43.67,8.51 43.67,8.51 43.94,8.25 47.51,8.25 48.4,9.14 v2(48.4,9.29)
  BOTTOM w0.089: U2401.14 30.54,28.74 v2(30.19,28.39) ; v2(48.4,9.29) 48.1,9.59 KB1.15
KSO2: length 42.4
  TOP w0.089: v2(49.06,9.24) AFTP6513.1 49.06,8.37 RN2412.6
  L4SGND w0.089: v2(49.06,9.24) 47.88,8.06 43.86,8.06 43.59,8.32 43.59,8.32 43.01,8.9 43.01,8.91 42.29,9.63 42.09,9.63 41.54,10.18 41.26,10.18 39.17,12.27 37.92,12.27 36.28,13.91 34.76,13.91 34.75,13.92 34.68,13.92 33.87,14.72 32.95,14.72 32.89,14.78 32.81,14.78 32.56,15.03 32.56,15.38 32.86,15.69 32.86,19.47 30.46,21.87 30.46,22.66 30.32,22.8 30.32,24.16 29.15,25.33 29.15,26.97 v2(29.63,27.45)
  BOTTOM w0.089: KB1.14 48.9,9.4 v2(49.06,9.24) ; U2401.15 30.94,28.83 30.61,28.51 30.61,28.18 29.88,27.45 v2(29.63,27.45)
KSO3: length 37.6
  TOP w0.089: v2(47.53,9.36) 47.23,9.06 47.23,7.26 AFTP6518.1 47.97,6.52 RN2412.8
  L4SGND w0.089: v2(31.1,28.39) 31.71,27.79 31.71,26.53 31.6,26.42 31.6,21.66 32.77,20.5 33.47,20.5 34.18,19.79 34.18,18.57 33.71,18.1 33.71,17.63 35.98,15.36 35.98,15.13 36.53,14.58 36.91,14.58 38.24,13.25 39.03,13.25 41.51,10.77 41.78,10.77 42.36,10.2 42.53,10.2 43.58,9.14 43.58,9.14 43.83,8.89 43.83,8.89 44.09,8.63 47.02,8.63 47.53,9.14 v2(47.53,9.36)
  BOTTOM w0.089: v2(47.53,9.36) 47.3,9.59 KB1.16 ; v2(31.1,28.39) 31.34,28.62 U2401.16
KSO4: length 33.3
  TOP w0.089: v2(44.67,9.29) 44.21,9.74 43.83,9.74 43.43,9.34 43.43,7.25 AFTP6514.1 45.43,5.25 RN2409.8
  L4SGND w0.089: v2(37.2,26.46) 37.2,24.32 35.95,23.07 35.95,19.79 36.29,19.44 36.29,18.73 35.36,17.8 35.36,16.95 36.34,15.97 37.85,15.97 39.73,14.09 40.59,14.09 44.67,10.01 v2(44.67,9.29)
  BOTTOM w0.089: KB1.20 44.1,9.86 v2(44.67,9.29) ; v2(37.2,26.46) 37.27,26.39 U2401.37
KSO5: length 30.9
  TOP w0.089: RN2409.7 46.02,5.52 43.78,7.76 AFTP6510.1 43.78,9.09 v2(44,9.32)
  L4SGND w0.089: v2(44,9.32) 44,10.4 40.6,13.81 38.72,13.81 37.44,15.08 37.44,15.16 36.84,15.77 36.28,15.77 35.17,16.87 35.17,17.96 36.1,18.89 36.1,19.24 35.76,19.59 35.76,23.87 v2(36.59,24.71)
  BOTTOM w0.089: U2401.38 38.45,25.99 37.17,24.71 v2(36.59,24.71) ; KB1.21 43.3,10.02 v2(44,9.32)
KSO6: length 31.7
  TOP w0.089: RN2409.5 47.11,5.48 AFTP6517.1 45.68,8.1 46.04,8.45 v2(46.04,9.29)
  L4SGND w0.089: v2(46.04,9.29) 46.04,11.3 42.98,14.35 39.81,14.35 39.81,14.36 39.8,14.36 38,16.16 36.42,16.16 35.55,17.03 35.55,17.65 36.6,18.7 36.6,19.47 36.14,19.94 36.14,22.3 36.87,23.03 v2(36.87,23.39)
  BOTTOM w0.089: KB1.18 45.7,9.65 46.04,9.31 v2(46.04,9.29) ; v2(36.87,23.39) 37.76,24.28 37.76,24.89 38.45,25.59 U2401.39
KSO7: length 30
  TOP w0.089: v2(45.3,9.29) 45.68,8.91 AFTP6515.1 45.33,8.46 45.33,6.74 46.52,5.56 RN2409.6
  L4SGND w0.089: v2(37.12,21.74) 36.69,21.3 36.69,20.47 37.03,20.13 37.03,19.86 37.1,19.79 37.1,17.54 37.33,17.31 37.33,16.86 37.65,16.54 38.3,16.54 40.01,14.83 43.34,14.83 47.1,11.07 47.1,8.98 46.94,8.82 45.77,8.82 v2(45.3,9.29)
  BOTTOM w0.089: U2401.50 38.31,21.19 37.97,21.53 37.33,21.53 v2(37.12,21.74) ; KB1.19 44.9,9.69 v2(45.3,9.29)
KSO8: length 44.8
  TOP w0.089: RN2410.5 56,5.56 56.68,6.24 58.61,6.24 AFTP6516.1 58,7.92 v2(58,9.26)
  L4SGND w0.089: v2(37.63,23.39) 36.41,22.17 36.41,20 36.84,19.57 36.84,17.34 37.1,17.09 37.1,16.73 37.48,16.35 38.15,16.35 39.9,14.6 39.91,14.6 39.91,14.59 43.15,14.59 46.62,11.12 46.62,9.34 v2(46.67,9.29)
  BOTTOM w0.089: U2401.46 38.49,22.79 37.89,23.39 v2(37.63,23.39) ; KB1.17 46.5,9.46 v2(46.67,9.29) 46.67,8.17 47.77,7.08 55.82,7.08 v2(58,9.26)
KSO9: length 24.1
  TOP w0.089: AFTP6504.1 v2(54.9,9.24)
  BOTTOM w0.089: v2(54.9,9.24) 54.5,9.64 KB1.7 54.5,10.59 54.03,11.07 44.39,11.07 43.99,11.47 43.99,13.25 43.84,13.4 43.01,13.4 42.66,13.05 R2453.2 42.23,13.4 41.31,13.4 R2452.1 40.69,12.78 36.94,12.78 36.54,13.18 U2401.68
KSO10: length 34
  TOP w0.089: RN2410.7 54.91,5.66 57.24,7.99 AFTP6523.1 57.09,8.68 v2(56.5,9.26)
  L4SGND w0.089: v2(34.85,15.23) 35.71,14.36 36.82,14.36 38.15,13.03 38.94,13.03 41.42,10.56 41.69,10.56 42.24,10.01 42.45,10.01 43.39,9.07 43.39,9.06 43.75,8.7 43.75,8.7 44.02,8.44 47.21,8.44 47.96,9.19 47.96,9.75 48.73,10.51 55.25,10.51 v2(56.5,9.26)
  BOTTOM w0.089: v2(34.85,15.23) 34.85,15.12 34.93,15.03 U2401.72 ; v2(56.5,9.26) 56.1,9.67 KB1.5
KSO11: length 33.9
  TOP w0.089: v2(55.84,9.26) 55.84,7.41 AFTP6522.1 54.32,5.89 RN2410.8
  L4SGND w0.089: v2(35.68,12.57) 35.17,12.06 35.17,11.45 36.28,10.35 39.58,10.35 40.1,9.82 40.76,9.82 41.07,9.82 41.1,9.8 41.38,9.8 41.93,9.24 42.13,9.24 42.63,8.75 42.63,8.75 43.43,7.94 43.44,7.94 43.7,7.68 48.78,7.68 50.21,9.11 50.21,9.55 50.99,10.32 54.78,10.32 v2(55.84,9.26)
  BOTTOM w0.089: U2401.74 34.13,13.59 34.54,13.18 34.58,13.18 34.66,13.11 35.14,13.11 v2(35.68,12.57) ; KB1.6 55.3,9.81 v2(55.84,9.26)
KSO12: length 36.6
  TOP w0.089: v2(57.24,9.24) 57.62,8.86 57.62,7.03 AFTP6519.1 56.5,6.65 55.41,5.55 RN2410.6
  L4SGND w0.089: v2(57.24,9.24) 57.24,9.04 56.99,8.78 55.54,8.78 55.33,8.99 55.33,9.5 54.69,10.13 51.43,10.13 50.71,9.42 v2(50.71,9.29) 50.71,9.05 49.15,7.49 43.62,7.49 43.36,7.75 43.35,7.75 42.44,8.67 42.44,8.67 42.05,9.05 41.85,9.05 41.3,9.61 41.02,9.61 41,9.63 40.84,9.63 40.84,9.63 39.91,9.63 39.39,10.16 36.2,10.16 34.98,11.37 34.98,12.51 v2(35.04,12.57)
  BOTTOM w0.089: U2401.75 33.73,13.59 34.33,12.99 34.5,12.99 34.58,12.91 34.69,12.91 v2(35.04,12.57) ; v2(50.71,9.29) 50.5,9.5 KB1.12
KSO13: length 30.4
  TOP w0.089: RN2411.8 50.61,8.02 AFTP6520.1 51.4,8.96 v2(51.73,9.29)
  L4SGND w0.089: v2(34.4,12.53) 34.75,12.17 34.75,11.33 36.12,9.97 39.2,9.97 39.72,9.44 40.92,9.44 40.94,9.42 41.03,9.42 41.03,9.42 41.22,9.42 41.77,8.86 41.97,8.86 42.25,8.59 42.25,8.59 43.28,7.56 43.28,7.56 43.54,7.3 49.73,7.3 v2(51.73,9.29)
  BOTTOM w0.089: KB1.9 53.07,10.18 53.07,9.14 52.79,8.86 52.15,8.86 v2(51.73,9.29) ; U2401.76 33.33,13.59 33.37,13.55 33.37,13.55 33.56,13.36 33.58,13.36 33.59,13.34 33.77,13.27 34.4,12.64 v2(34.4,12.53)
KSO14: length 32
  TOP w0.089: RN2411.6 51.7,5.91 53.3,7.51 AFTP6521.1 53.3,9.04 v2(53.58,9.31)
  L4SGND w0.089: v2(53.58,9.31) 53.18,9.71 52.29,9.71 52.15,9.58 52.15,9.11 50.15,7.1 43.46,7.1 43.2,7.37 43.2,7.37 42.06,8.51 42.06,8.51 41.89,8.67 41.5,8.67 40.95,9.22 40.86,9.22 40.84,9.25 39.47,9.25 38.94,9.77 35.75,9.77 32.93,12.59 v2(32.93,13.15)
  BOTTOM w0.089: v2(53.58,9.31) 53.7,9.43 KB1.8 ; v2(32.93,13.15) U2401.77
KSO15: length 37.1
  TOP w0.089: RN2411.7 51.2,5.86 51.4,6.06 AFTP6524.1 51.4,8.07 v2(52.62,9.29)
  L4SGND w0.089: v2(52.62,9.29) 52.62,9.16 50.37,6.91 43.38,6.91 43.12,7.18 43.12,7.18 41.87,8.43 41.87,8.43 41.82,8.48 40.96,8.48 40.86,8.38 40.5,8.38 40.5,8.39 39.08,8.39 38.59,7.9 37.48,7.9 37.23,8.15 37.23,8.24 36.46,9.01 35.67,9.01 33.69,9.01 30.66,12.04 30.66,12.2 30.66,13.44 29.35,14.75 v2(29.35,15.54)
  BOTTOM w0.089: U2401.86 29.34,15.54 v2(29.35,15.54) ; v2(52.62,9.29) 52.1,9.81 KB1.10
KSO16: length 45
  TOP w0.089: RN2411.5 52.29,5.89 AFTP6539.1 54.27,7.87 v2(54.27,9.26)
  L4SGND w0.089: v2(26.18,15.77) 26.4,15.54 26.4,15.01 29.21,12.2 29.21,11.87 33.92,7.16 35.92,7.16 35.99,7.23 42.58,7.23 43.09,6.72 51.83,6.72 54.27,9.16 v2(54.27,9.26)
  BOTTOM w0.089: U2401.92 26.94,15.01 v2(26.18,15.77) ; KB1.11 51.3,8.92 51.55,8.67 53.68,8.67 v2(54.27,9.26)
L_BKLT_CTRL: length 86.6
  TOP w0.127: v2(99.91,102.51) 100.5,101.92 R5502.2
  L4SGND w0.127: v2(134.84,81.76) 134.28,82.31 134.28,86.62 134.96,87.31 134.96,92.51 131.04,96.44 131.04,98.01 128.23,100.82 101.59,100.82 v2(99.91,102.51)
  BOTTOM w0.127: CPU1.CH11 134.84,81.93 v2(134.84,81.76) ; v2(99.91,102.51) 99.01,103.41 82.85,103.41 82.44,103.41 81.5,102.47 81.5,101.48 81.47,101.46 81.47,100.42 81.33,100.28 78.33,100.28 77.89,99.84 76.34,99.84 v1(75.58,100.6) 74.46,100.6 74,101.06 73.41,101.06 73.18,100.83 73.18,99.88 D5502.1
L_BKLT_EN: length 230.2
  TOP w0.102: D2404.A 32.72,10.05 33.82,10.05 34.2,10.43 34.2,10.94 35.35,12.08 35.98,12.08 36.54,12.64 39.51,12.64 40.88,11.27 43.57,11.27 v2(44.44,12.13) ; v2(136.69,82.82) 137.3,82.82 137.63,82.49 141.13,82.49 143.23,84.59 154.17,84.59 154.24,84.52 154.24,84.52 154.5,84.27 154.5,84.26 154.94,83.82 156.23,83.82 159.55,80.5 159.55,76.94 160.19,76.3 160.19,75.63 159.7,75.15 159.7,72.39 159.02,71.71 159.02,67.9 158.57,67.45 158.57,67.31 158.03,66.77 158.03,56.14 157.91,56.01 157.91,50.81 158,50.72 158,49.93 158.01,47.3 158.15,47.15 158.15,43.96 158.56,43.55 158.56,41.95 158.41,41.8 v2(158.41,33.29)
  L6 w0.102: v2(158.41,33.29) 158.71,32.99 158.71,26.98 158.71,26.98 158.71,26.5 158.71,26.33 158,25.62 158,21.07 155.39,18.46 149.61,18.46 149.41,18.66 149.14,18.66 148.96,18.84 144.85,18.84 144.12,19.56 128.7,19.56 127.52,18.38 v2(127.09,18.38) ; v2(124.88,15.75) 123.8,15.75 123.37,15.32 123.07,15.32 123.04,15.28 122.8,15.28 120.97,13.45 120.67,13.45 119.61,13.45 118.63,13.45 118,13.45 115.81,13.45 114.48,13.45 113.84,13.45 109.61,13.45 106.17,10.01 105.53,10.01 96.21,10.01 96.17,10.05 95.78,10.05 94.23,11.6 89.7,11.6 89.65,11.65 86.5,11.65 86.3,11.85 85.55,11.85 84.88,12.53 82.25,12.53 81.66,11.93 75.55,11.93 75.07,11.45 67.41,11.45 66.81,12.06 66.58,12.28 54.48,12.28 53.72,13.05 50.8,13.05 49.88,12.13 v2(44.44,12.13)
  BOTTOM w0.102: v2(124.88,15.75) 125.31,16.19 125.31,16.83 126.05,17.57 126.28,17.57 v2(127.09,18.38) ; v2(136.69,82.82) 136.44,82.57 CPU1.CK11 ; v2(44.44,12.13) 44.44,13.3 43.8,13.94 v1(43.47,13.94) R2455.1 42.51,13.86 R2440.2
LAN_WAKE#: length 3.7
  TOP w0.102: v2(129.05,68.83) 128.55,69.32 128.55,69.99 128.51,70.03 128.51,70.47 v1(128.5,70.49) 128.51,70.51 128.51,71.44 R1707.2
  BOTTOM w0.102: CPU1.BU32 128.76,68.54 v2(129.05,68.83)
LCD_BRIGHTNESS: length 7.6
  TOP w0.127: v2(96.94,97.81) 97.4,97.35 97.93,97.35 v1(98.49,96.8) 98.95,96.8 99.61,97.45 99.61,99.79 EC5501.1 99.61,99.89 R5545.1
  BOTTOM w0.127: v2(96.94,97.81) 96.94,97.68 96.65,97.39 LCD1.22
LCD_TST: length 174.7
  TOP w0.102: v2(84.75,102.51) 84.8,102.51 85.51,101.8 R5543.2
  L4SGND w0.102: v2(26.46,91.84) 26.46,90.77 26.88,90.35 26.86,84.11 25.64,82.9 25.64,75.42 23.28,73.06 23.28,67.81 21.2,65.73 18.68,65.73 16.9,63.95 16.9,63.24 16.89,63.22 16.89,45.82 16.83,45.76 16.83,43.88 15.09,42.14 15.09,38.83 14.53,38.27 14.53,33.03 15.46,32.1 15.46,27.27 16.93,25.8 16.93,24.54 19.11,22.36 v2(19.11,21.84)
  L6 w0.102: v2(19.11,21.84) 19.24,21.71 19.24,20.72 19.55,20.41 20.16,20.41 20.54,20.8 23.31,20.8 25.08,22.57 29,22.57 29.32,22.9 29.99,22.9 30.77,22.12 32.51,22.12 32.76,22.37 32.76,22.73 32.31,23.18 v2(32.25,23.18)
  BOTTOM w0.102: v2(84.75,102.51) 82.54,102.51 82.2,102.17 82.2,100.85 82.17,100.83 82.17,100.14 81.73,99.69 81.73,99.68 81.4,99.36 81.39,99.36 81.37,99.33 80.07,99.33 78.41,97.67 73.48,97.67 D5502.2 70.72,100.42 56.5,100.42 55.26,101.67 50.9,101.67 49.47,100.24 49.47,99.71 48.71,98.95 48.66,98.95 48.21,98.49 37.17,98.49 30.92,92.25 30.92,91.66 v1(30.67,91.4) 30.42,91.16 27.6,91.16 27.35,91.41 26.88,91.41 v2(26.46,91.84) ; U2401.26 35.33,28.7 33.85,27.21 33.85,27.15 33.77,27.07 33.77,27.04 33.52,26.79 32.91,26.79 32.25,26.13 v2(32.25,23.18)
LCD_TST_C: length 7.2
  TOP w0.102: v2(90.15,97.78) 90.15,97.55 89.97,97.37 88.61,97.37 88.17,97.81 87.26,97.81 86.47,98.61 v1(85.57,98.61) 85.51,98.67 R5543.1
  BOTTOM w0.102: v2(90.15,97.78) LCD1.9
LCD_VCC_TEST_EN: length 143.5
  L4SGND w0.102: v2(22.14,22.37) 21.15,21.38 18.99,21.38 14.59,25.77 14.59,28.01 14.87,28.29 14.87,32.07 14.32,32.62 14.32,38.36 14.89,38.92 14.89,42.22 16.63,43.96 16.63,54.04 15.66,55.01 15.66,56.23 16.68,57.25 16.68,63.31 16.7,63.33 16.7,64.04 18.6,65.93 21.11,65.93 23.03,67.85 23.03,73.1 25.44,75.51 25.44,82.81 25.44,82.98 26.65,84.2 26.68,90.04 25.97,90.75 25.97,92.19 v2(26.35,92.58)
  BOTTOM w0.102: U2401.113 23.03,21.99 22.65,22.37 v2(22.14,22.37) ; D5501.2 75.77,97.87 74.14,97.87 71.21,100.81 v1(57.98,100.81) 56.55,100.81 55.49,101.87 50.81,101.87 49.23,100.29 49.23,99.81 48.12,98.7 37.09,98.7 29.75,91.36 27.68,91.36 27.43,91.62 27.31,91.62 v2(26.35,92.58)
LDO1_CAP: length 3.6
  BOTTOM w0.203: U2701.39 177.08,15.94 177.56,15.46 177.84,15.46 ; R2747.2 178.63,14.45 C2731.2
  BOTTOM w0.254: R2747.2 178.6,14.72 177.94,15.39 v1(177.92,15.39) 177.84,15.46
LDO2_CAP: length 2.2
  BOTTOM w0.203: U2701.21 176.68,22.99 176.89,23.19 v1(176.89,23.22) 176.95,23.29 176.95,23.61 C2734.2
LDO3_CAP: length 3
  BOTTOM w0.203: C2736.1 175.55,23.36 175.88,23.03 U2701.19
  BOTTOM w0.254: C2736.1 v1(174.56,24.58)
LID_CL_SIO#: length 227.6
  TOP w0.102: v2(29.76,22.49) 29.96,22.29 29.96,21.3 29.33,20.67 29.33,20.16 29.63,19.86 30.32,19.86 RN2405.3 ; D2402.K 33.07,25.25 U6402.1 33.07,23.38 32.87,23.17 v2(32.89,23.17) ; v2(171.36,41.3) v1(171.36,40.43) 171.69,40.1 171.69,37.18 170.63,36.11 170.63,33.26 169.23,31.86 169.23,31.22 165.56,27.55 162.65,27.55 158.32,23.22 153.36,23.22 153.24,23.11 149.77,23.11 149.43,22.76 148.92,22.76 148.82,22.86 143.61,22.86 142.96,23.51 135.27,23.51 135.24,23.54 134.56,23.54 v2(134.5,23.6)
  L3SGND w0.102: v2(171.36,41.3) 171.36,41.3 171.36,41.29 170.88,41.29 170.09,42.08 170.09,54.5 175.25,59.66 175.25,60.52 v2(176.16,61.44)
  L6 w0.102: v2(29.76,22.49) 30.33,21.91 32.59,21.91 32.97,22.28 32.97,23.1 v2(32.89,23.17) 33.27,23.17 34.02,22.42 37.94,22.42 38.77,21.58 38.77,18.84 39.57,18.04 42.73,18.04 45.61,15.16 45.61,13.63 46.01,13.23 49,13.23 50.32,14.55 54.06,14.55 54.06,14.55 54.62,14.55 55.19,13.98 62.75,13.98 63.19,14.42 68.25,14.42 68.55,14.12 74.08,14.12 74.97,13.23 76.54,13.23 76.89,13.58 88.94,13.58 90.29,14.93 96.13,14.93 99.63,11.42 105.71,11.42 109.07,14.78 109.84,14.78 119.95,14.78 120.12,14.78 121.95,16.6 122.49,16.6 123.05,17.16 123.06,17.16 123.88,17.99 126.09,17.99 v2(126.2,18.1)
  BOTTOM w0.102: v2(126.2,18.1) 126.2,18.31 127.12,19.22 128.33,19.22 129.1,20 129.61,20 130.2,20.58 131.27,20.58 132.77,22.08 132.77,22.48 133.83,23.54 134.44,23.54 v2(134.5,23.6) ; CN6601.19 171.05,40.99 v2(171.36,41.3) ; v2(32.89,23.17) 36.74,19.32 36.74,18.64 35.68,17.57 35.68,16.94 37.34,15.28 U2401.66 ; v2(176.16,61.44) 176.82,62.1 176.82,65.3 178.28,66.76 178.46,66.76 179.62,67.91 179.62,71.98 R9216.2
LID_CL_SIO_TAB#: length 156.7
  TOP w0.102: v2(123.91,19.73) 123.91,21.51 v1(124.23,21.82) 125.39,22.98 130.29,22.98 130.36,22.9 131.53,22.9 132.75,24.12 136.1,24.12 136.3,23.92 144.13,23.92 144.98,23.07 148.91,23.07 149.01,22.97 149.3,22.97 149.7,23.36 150.18,23.36 150.84,24.02 151.27,24.02 151.97,23.31 153.16,23.31 153.31,23.46 158.26,23.46 162.55,27.75 165.48,27.75 167.93,30.21 167.93,32.45 170.42,34.93 170.42,37.1 v1(170.75,37.43) 170.75,37.86 171.23,38.34 171.23,39.47 v2(171.13,39.57)
  L6 w0.102: v2(41.01,24.53) 41.72,23.82 43.22,23.82 44.29,22.75 53.4,22.75 54.14,23.49 61.36,23.49 62.85,23.49 63.03,23.67 68.14,23.67 68.49,23.31 68.49,22.8 68.8,22.5 69.53,22.5 70.09,21.94 79.77,21.94 81.32,23.49 94.35,23.49 100.06,17.78 106.81,17.78 106.82,17.78 106.83,17.8 114.62,17.8 114.75,17.67 116.19,17.67 116.65,18.13 121.86,18.13 123.46,19.73 v2(123.91,19.73)
  BOTTOM w0.102: v2(171.13,39.57) 171.01,39.57 170.55,40.02 CN6601.20 ; U2401.41 40.53,24.79 40.91,25.16 R2496.1 41.97,24.4 v1(41.82,24.25) 41.29,24.25 v2(41.01,24.53)
LINE1-L_C: length 2.1
  TOP w0.254: R2922.1 176.82,36.92 v1(176.82,36.11) C2907.2
LINE1-L_R: length 2
  TOP w0.254: v1(179.87,37) 179.82,37 179.82,36.92 R2921.1 178.98,36.24 C2908.2
LINE1_L: length 21.3
  TOP w0.254: v1(176.89,32.12) 176.95,32.12 177.15,32.32 v2(177.15,32.78) 177.25,32.78 177.25,33.24 C2907.1
  L6 w0.254: v2(177.15,32.78) 177.93,32.78 179.24,31.48 179.24,22.55 180.61,21.18 180.61,18.49 178.86,16.74 v2(178.86,16.64)
  BOTTOM w0.203: v2(178.86,16.64) 178.86,16.91 U2701.36
LINE1_R: length 22.2
  TOP w0.254: v1(179.24,33.24) v2(179.24,33.8) C2908.1
  L6 w0.254: v2(179.45,16.31) 181.27,18.13 181.27,21.51 179.9,22.88 179.9,31.75 179.24,32.41 v2(179.24,33.8)
  BOTTOM w0.203: v2(179.45,16.31) 179.45,17.03 178.96,17.52 U2701.35
LPS_SW: length 5.5
  TOP w0.254: v1(21.82,60.88) U7418.4 20.98,60.36 v2(20.49,60.85)
  BOTTOM w0.254: v2(20.49,60.85) 19.98,60.85 19.77,60.65 R7403.1 19.77,59.35 C7401.2 19.75,58.59 R7404.1 19.85,58.49 R7402.2
LPS_SW_A: length 2.4
  BOTTOM w0.254: R7402.1 19.88,56.34 v1(19.47,55.93) 19.72,55.68 19.72,54.83 Q7406.3
LPS_SW_B: length 3
  BOTTOM w0.254: Q7401.D 22.37,61.05 v1(21.45,61.05) 21.41,61.05 20.66,60.31 R7403.2
LPS_SW_C: length 2.9
  BOTTOM w0.254: Q7401.G 23.85,57.43 v1(23.8,57.38) 23.32,57.38 23.28,57.42 R7406.2 R7405.1
LPS_SW_D: length 6.4
  BOTTOM w0.254: R7405.2 21.55,56.38 v1(20.89,56.38) 20.5,56.38 20.11,55.98 20.11,55.56 20.17,55.49 20.17,54.23 19.93,53.99 18.58,53.99 18.44,53.85 Q7406.6
LVDS_VDD_EN_R: length 32.6
  TOP w0.102: v2(100.55,102.51) 100.52,102.51 99.89,103.14 v1(99.25,103.14) 98.62,103.14 97.83,102.36 RN5502.7
  BOTTOM w0.102: D5501.3 77.79,101.05 U5501.4 79.35,101.05 79.73,100.67 80.04,100.67 80.15,100.55 81.14,100.55 81.23,100.64 81.23,101.56 81.26,101.58 81.26,102.57 82.34,103.65 99.4,103.65 v2(100.55,102.51)
M2_OPT_PEDET: length 185.5
  TOP w0.102: v2(167.78,21.48) 167.68,21.48 AFTP6305.1 165.7,20.72 R6005.2
  L4SGND w0.102: v2(185.46,97.68) 187.17,97.68 190.46,94.39 190.46,68.75 190.03,68.32 190.03,60.99 186.75,57.72 186.75,51.92 189.38,49.3 189.38,23.75 188.05,22.42 188.05,13.28 184.46,9.7 180.45,9.7 179.13,11.01 179.13,11.01 178.67,11.47 178.67,11.47 178.52,11.63 175.71,11.63 173.33,14.01 173.33,17.73 173.32,18.05 169.89,21.48 v2(167.78,21.48)
  BOTTOM w0.076: 140.6,83.05 138.91,83.05 138.77,82.91 138.68,82.91 138.6,82.82 137.44,82.82 CPU1.CM10
  BOTTOM w0.102: 140.6,83.05 141.42,83.05 142.58,84.22 142.58,84.27 142.69,84.37 142.71,84.37 143.33,84.99 148.78,84.99 148.95,84.83 152.21,84.83 152.65,85.27 152.65,87.61 153.68,88.64 162.7,88.64 165.27,91.2 179.01,91.2 183.35,95.55 187.24,95.55 187.8,96.11 187.8,96.37 186.49,97.68 v2(185.46,97.68) ; SSD2.69 166.8,20.65 167.63,21.48 v2(167.78,21.48)
M2_PCIE_LED2#: length 24.9
  TOP w0.127: v2(161.89,3.75) 163.49,3.75 166.03,1.21 168.53,1.21 168.76,0.97 170.41,0.97 170.65,1.21 171.02,1.21 171.18,1.05 173.03,1.05 173.19,1.21 176.68,1.21 177.55,2.07 177.55,2.7 176.57,3.68 R6316.2 v1(175.65,3.78)
  BOTTOM w0.127: v2(161.89,3.75) 161.53,3.75 159.38,5.9 SSD2.10
M2_PCIE_LED#: length 34.2
  TOP w0.127: v2(177.59,4.84) 176.77,4.84 R6316.1 ; v2(193.46,20.34) v1(194.1,20.34)
  L4SGND w0.127: v2(177.59,4.84) 177.59,6.18 179.85,8.44 180.05,8.44 184.88,8.44 188.56,12.12 188.76,12.12 190.07,12.12 191.29,13.34 191.35,13.34 194.12,13.34 194.49,13.71 194.49,19.22 193.46,20.25 v2(193.46,20.34)
  BOTTOM w0.127: v2(177.59,4.84) 176.86,4.12 D6401.2 176.24,3.39 R6405.2 ; v2(193.46,20.34) 193.52,20.4 SSD1.10
M2_SSD_PEDET: length 182.5
  TOP w0.102: R6305.2 189.6,5.3 v2(189.65,5.35) AFTP6303.1 ; v2(176.29,1.75) 175.88,2.15 174.16,2.15 173.78,2.53 173.78,3.33 172.54,4.56 171.57,4.56 165.13,11.01 165.13,17.68 168.59,21.14 168.59,21.24 170.09,22.74 v2(170.09,25.9)
  L4SGND w0.102: v2(177.85,75.03) 178.51,75.03 184.7,81.22 184.7,91.66 184,92.36 v2(184,92.59)
  L6 w0.102: v2(176.29,1.75) 176.7,2.15 176.7,2.52 178.09,3.92 178.09,4.97 180.63,7.51 184.15,7.51 186.31,5.35 v2(189.65,5.35) ; v2(169.63,31.69) 171.07,33.13 171.07,35.07 172.71,36.71 172.71,36.75 172.71,43.37 174.28,44.94 174.28,47.77 173.48,48.57 173.48,48.95 173.42,49.01 173.06,49.01 172.81,49.27 172.81,49.63 173.06,49.88 173.42,49.88 173.48,49.94 173.48,51.86 173.01,52.33 173.01,57.2 174.13,58.32 174.13,61.09 174.87,61.83 174.87,72.17 177.7,75 177.8,75 177.84,75.03 v2(177.85,75.03)
  BOTTOM w0.076: 141.19,82.82 141.17,82.81 138.98,82.81 arc(138.89,82.79) 138.82,82.74 138.63,82.55 CPU1.CP10
  BOTTOM w0.102: v2(170.09,25.9) 169.1,26.89 169.1,31.16 v2(169.63,31.69) ; v2(189.65,5.35) 188.74,5.35 188.44,5.65 SSD1.69 ; v2(184,92.59) 184,93.02 183.56,93.46 181.56,93.46 179.04,90.95 165.52,90.95 163.01,88.44 153.86,88.44 152.86,87.43 152.86,85.19 152.29,84.63 148.86,84.63 148.7,84.79 143.42,84.79 142.91,84.29 142.91,84.28 141.46,82.82 141.19,82.82
M_A_A0: length 103.3
  TOP w0.14: v2(49.5,31.21) 48.91,30.62 RN1203.3
  L4SGND w0.142: v2(49.5,31.21) 52.27,31.21 52.53,31.47 53.51,31.47 53.76,31.72 58.27,31.72 v2(58.71,32.15) 59.15,31.71 68.42,31.71 v2(68.86,32.15) 69.3,31.71 78.57,31.71 v2(79.01,32.15) 79.45,31.71 84.14,31.71 84.15,31.72 88.72,31.72 v2(89.16,32.15) 89.58,31.73 97.1,31.73 97.36,31.98 97.36,32.18 96.81,32.73 96.81,32.93 97.01,33.13 97.21,33.13 97.76,32.58 97.96,32.58 98.16,32.78 98.16,32.99 97.61,33.53 97.61,33.74 97.81,33.94 98.01,33.94 98.56,33.39 98.76,33.39 98.96,33.59 98.96,33.79 98.42,34.34 98.42,34.54 98.62,34.74 98.82,34.74 99.37,34.19 99.57,34.19 99.77,34.39 99.77,34.6 99.22,35.14 99.22,35.34 99.42,35.55 99.62,35.55 100.17,35 100.37,35 101.15,35.78 101.15,48.34 105.62,52.82 105.62,56.69 105.12,57.19 v2(104.97,57.19)
  BOTTOM w0.076: 106.72,61.33 106.72,61.49 107.39,62.16 107.39,64.16 107.14,64.41 107.14,65.38 CPU1.AC37
  BOTTOM w0.14: v2(104.97,57.19) 105.18,57.19 106.72,58.73 106.72,61.33 ; v2(58.71,32.15) 58.71,32.21 59.4,32.9 RAM4.P3 ; RAM2.P3 79.7,32.9 79.01,32.21 v2(79.01,32.15) ; RAM3.P3 69.55,32.9 68.86,32.21 v2(68.86,32.15) ; v2(89.16,32.15) 89.16,32.44 89.61,32.9 RAM1.P3
M_A_A1: length 98.3
  TOP w0.14: v2(52.93,33.03) 52.34,33.62 RN1205.4
  L6 w0.142: v2(52.93,33.03) 53.05,33.03 54.05,32.04 56.64,32.04 v2(57.1,32.5) 57.94,32.5 58.4,32.96 60.64,32.96 61.49,32.11 65.81,32.11 65.88,32.04 66.79,32.04 v2(67.25,32.5) 68.09,32.5 68.55,32.96 70.79,32.96 71.64,32.11 75.96,32.11 76.03,32.04 76.94,32.04 v2(77.4,32.5) 78.24,32.5 78.7,32.96 80.94,32.96 81.86,32.04 87.09,32.04 v2(87.55,32.5) 88.39,32.5 88.84,32.95 91.1,32.95 91.59,32.46 94.49,32.46 94.75,32.72 94.75,33.57 95.9,34.71 95.9,36.83 96.04,36.98 96.34,36.98 96.48,36.83 96.48,35.63 96.58,35.53 97.58,35.53 98.03,35.98 98.03,36.32 97.89,36.47 97.32,36.47 97.17,36.62 97.17,36.88 97.31,37.03 98.16,37.03 98.34,37.2 98.34,37.48 98.19,37.62 97.01,37.62 96.86,37.76 96.86,38.07 96.99,38.19 98.19,38.19 98.34,38.33 98.34,52.29 101.88,55.83 101.88,56.24 101.87,56.24 101.87,56.63 v2(102.31,57.07)
  BOTTOM w0.076: 107.01,60.98 107.01,61.54 107.58,62.11 107.58,64.21 107.3,64.48 107.3,65.14 107.56,65.4 107.56,65.66 107.46,65.86 107.46,65.86 107.3,66.15 CPU1.AC36
  BOTTOM w0.14: v2(67.25,32.5) RAM3.P7 ; 107.01,60.98 107.01,58.45 105.27,56.71 102.68,56.71 102.51,56.88 102.49,56.88 v2(102.31,57.07) ; v2(77.4,32.5) RAM2.P7 ; v2(57.1,32.5) RAM4.P7 ; v2(87.55,32.5) RAM1.P7
M_A_A2: length 102.3
  TOP w0.14: RN1203.4 v2(48.79,31.21)
  L6 w0.142: v2(48.79,31.21) 49.25,31.67 49.69,31.67 49.92,31.45 58.66,31.45 59.34,32.13 v2(59.34,32.18) 59.8,31.72 60.94,31.72 61.14,31.52 65.57,31.52 65.64,31.45 68.81,31.45 69.49,32.13 v2(69.49,32.18) 69.95,31.72 71.09,31.72 71.29,31.52 75.72,31.52 75.79,31.45 78.96,31.45 79.64,32.13 v2(79.64,32.18) 80.1,31.72 81.24,31.72 81.51,31.45 89.07,31.45 89.34,31.72 89.38,31.72 89.79,32.13 v2(89.79,32.18) 90.25,31.72 95.68,31.72 95.82,31.86 95.82,32.3 95.96,32.44 96.25,32.44 96.39,32.3 96.39,31.86 96.53,31.72 97.14,31.72 97.4,31.97 97.4,32.17 96.53,33.04 96.53,33.24 96.73,33.44 96.93,33.44 97.8,32.57 98,32.57 98.2,32.78 98.2,32.98 97.34,33.84 97.34,34.04 97.54,34.24 97.74,34.24 98.6,33.38 98.81,33.38 99.18,33.75 99.18,34.36 99.03,34.5 98.61,34.5 98.46,34.64 98.46,34.93 98.61,35.07 99.03,35.07 99.18,35.21 99.18,49.93 103.67,54.42 v2(103.67,57.19)
  BOTTOM w0.076: CPU1.AC34 107.04,67.23 107.04,66.11 107.08,65.99 107.08,65.75 106.97,65.45 106.97,64.34 107.21,64.1 107.21,62.28 106.73,61.8
  BOTTOM w0.14: v2(69.49,32.18) 69.49,32.18 69.57,32.1 RAM3.R3 ; v2(89.79,32.18) 89.79,32.18 89.87,32.1 RAM1.R3 ; v2(79.64,32.18) 79.64,32.18 79.72,32.1 RAM2.R3 ; RAM4.R3 59.42,32.1 59.34,32.18 v2(59.34,32.18) ; v2(103.67,57.19) 104.81,58.34 105.58,58.34 106.47,59.23 106.47,61.54 106.73,61.8
M_A_A3: length 104
  TOP w0.14: RN1206.3 48.91,33.03 v2(49.5,33.62)
  L4SGND w0.142: v2(102.33,55.8) 102.33,51.81 99.66,49.14 99.66,43.55 98.47,42.37 98.47,42.17 99.58,41.06 99.58,40.86 99.38,40.66 99.18,40.66 98.07,41.77 97.87,41.77 97.59,41.49 97.59,41.29 98.64,40.24 98.64,40.04 98.44,39.84 98.23,39.84 97.19,40.89 96.99,40.89 96.79,40.68 96.79,40.48 97.51,39.76 97.51,39.56 97.31,39.36 97.11,39.36 96.39,40.08 96.19,40.08 95.39,39.28 95.39,35.17 94.18,33.96 93.08,33.96 92.94,33.82 92.94,33.51 92.79,33.37 92.51,33.37 92.37,33.51 92.37,33.82 92.22,33.96 89.53,33.96 89.15,34.34 88.75,34.34 v2(88.31,33.9) 88.13,33.72 86.19,33.72 86.14,33.76 85.76,33.76 85.71,33.72 82.05,33.72 81.71,34.06 80.82,34.06 80.71,33.95 79.39,33.95 78.99,34.35 78.6,34.35 78.16,33.9 v2(78.16,33.9) 77.98,33.72 77.29,33.72 77.25,33.76 74.74,33.76 74.7,33.72 71.9,33.72 71.72,33.9 71.56,34.06 70.67,34.06 70.52,33.9 69.29,33.9 68.84,34.35 68.45,34.35 68.01,33.9 v2(68.01,33.9) 67.83,33.72 65.89,33.72 65.84,33.76 65.46,33.76 65.41,33.72 61.75,33.72 61.41,34.06 60.52,34.06 60.41,33.95 59.09,33.95 58.69,34.35 58.3,34.35 57.86,33.9 v2(57.86,33.9) 57.68,33.72 55.74,33.72 55.69,33.76 55.31,33.76 55.26,33.72 54.22,33.72 54.06,33.88 49.76,33.88 v2(49.5,33.62)
  BOTTOM w0.076: CPU1.AC35 107.62,66.53 107.62,65.9 107.73,65.7 107.73,65.33 107.47,65.07 107.47,64.55 107.75,64.27 107.75,62.03 107.34,61.62 107.34,61.29 107.34,61.29 107.34,61.24
  BOTTOM w0.14: v2(68.01,33.9) 67.81,33.7 RAM3.N7 ; v2(57.86,33.9) 57.66,33.7 RAM4.N7 ; 107.34,61.24 107.31,61.21 107.31,58.23 104.88,55.8 v2(102.33,55.8) ; RAM1.N7 88.11,33.7 v2(88.31,33.9) ; v2(78.16,33.9) 77.96,33.7 RAM2.N7
M_A_A4: length 103.5
  TOP w0.14: RN1206.2 v2(48.79,32.53)
  L6 w0.142: v2(102.22,58.01) 101.46,58.01 101.16,57.7 101.16,56.18 97.58,52.6 97.58,48.79 97.43,48.64 96.41,48.64 96.27,48.5 96.27,48.22 96.41,48.07 97.43,48.07 97.58,47.93 97.58,47.65 97.43,47.51 96.41,47.51 96.27,47.36 96.27,47.08 96.41,46.94 97.43,46.94 97.58,46.79 97.58,46.51 97.43,46.37 96.41,46.37 96.27,46.22 96.27,45.94 96.41,45.8 97.43,45.8 97.58,45.66 97.58,45.37 97.43,45.23 96.41,45.23 96.27,45.09 96.27,44.8 96.41,44.66 97.43,44.66 97.58,44.52 97.58,40.07 97.09,39.59 95.95,39.59 95.04,38.68 95.04,35.07 93.77,33.8 90.2,33.8 90.09,33.69 89.14,33.69 v2(88.94,33.88) 88.94,33.88 88.5,33.43 86.47,33.43 86.14,33.76 85.76,33.76 85.71,33.72 81.64,33.72 81.59,33.76 80.02,33.76 79.91,33.65 79.02,33.65 v2(78.79,33.88) 78.79,33.88 78.35,33.43 76.32,33.43 75.99,33.76 75.61,33.76 75.56,33.72 71.49,33.72 71.44,33.76 69.87,33.76 69.76,33.65 68.87,33.65 v2(68.64,33.88) 68.64,33.88 68.2,33.43 66.17,33.43 65.84,33.76 65.46,33.76 65.41,33.72 61.34,33.72 61.29,33.76 59.72,33.76 59.61,33.65 58.72,33.65 v2(58.49,33.88) 58.49,33.88 58.05,33.43 56.02,33.43 55.69,33.76 55.31,33.76 55.26,33.72 53.69,33.72 53.54,33.88 50.53,33.88 49.81,33.16 49.42,33.16 v2(48.79,32.53)
  BOTTOM w0.076: CPU1.AA35 106.1,66.75 106.27,66.29 106.27,66.1 106.22,65.99 106.22,65.75 106.28,65.59 106.28,63.92 105.81,63.44 105.81,63.04
  BOTTOM w0.14: v2(102.22,58.01) 102.4,58.01 102.73,58.34 103.8,58.34 105.81,60.34 105.81,63.04 ; v2(68.64,33.88) 68.83,33.7 RAM3.N3 ; v2(58.49,33.88) 58.68,33.7 RAM4.N3 ; RAM1.N3 89.13,33.7 v2(88.94,33.88) ; v2(78.79,33.88) 78.98,33.7 RAM2.N3
M_A_A5: length 96.8
  TOP w0.14: RN1205.2 52.34,32.53 v2(52.93,31.95)
  L4SGND w0.142: v2(52.93,31.95) 53.13,32.15 54.9,32.15 55.02,32.03 55.83,32.03 55.87,32.07 v2(56.3,32.5) 56.77,32.03 57.29,32.03 57.9,32.64 59.53,32.64 59.8,32.37 59.8,32.33 60.1,32.03 65.98,32.03 66.02,32.07 v2(66.45,32.5) 66.92,32.03 67.44,32.03 68.05,32.64 69.68,32.64 69.95,32.37 69.95,32.33 70.26,32.02 76.12,32.02 v2(76.6,32.5) 77.07,32.03 77.59,32.03 78.2,32.64 79.83,32.64 80.1,32.37 80.1,32.33 80.4,32.03 86.28,32.03 86.32,32.07 v2(86.75,32.5) 87.2,32.05 87.76,32.05 88.34,32.63 89.98,32.63 90.25,32.35 90.25,32.35 90.56,32.04 95.46,32.04 100.79,37.37 100.79,48.49 105.25,52.95 105.25,53.34 105.1,53.48 103.99,53.48 103.85,53.62 103.85,54.01 103.99,54.15 105.12,54.15 105.27,54.29 105.27,54.57 105.12,54.72 103.94,54.72 103.8,54.86 103.8,55.14 103.94,55.29 105.12,55.29 105.27,55.43 105.27,55.71 105.12,55.85 104.47,55.85 104.33,56 104.33,61.92 105.14,62.73 v2(106.63,62.73)
  BOTTOM w0.076: v2(106.63,62.73) 107.04,63.14 107.04,63.22 107.05,63.23 107.05,63.55 107.04,63.56 107.04,63.66 107.05,63.67 107.05,64.02 107.04,64.02 107.04,64.04 106.81,64.27 106.81,65.48 106.92,65.78 106.92,65.96 106.75,66.42 CPU1.AB35
  BOTTOM w0.14: RAM4.P8 v2(56.3,32.5) ; RAM2.P8 v2(76.6,32.5) ; RAM1.P8 v2(86.75,32.5) ; RAM3.P8 v2(66.45,32.5)
M_A_A6: length 100.6
  TOP w0.14: RN1205.1 v2(52.22,31.95)
  L6 w0.142: v2(103.67,58.85) 103.16,58.34 103.16,54.42 102.91,54.17 102.71,54.17 101.81,55.06 101.61,55.06 101.41,54.86 101.41,54.66 102.31,53.77 102.31,53.57 102.1,53.36 101.9,53.36 101.01,54.26 100.81,54.26 100.61,54.06 100.61,53.86 101.5,52.96 101.5,52.76 101.3,52.56 101.1,52.56 100.21,53.45 100,53.45 99.8,53.25 99.8,53.05 100.7,52.16 100.7,51.96 100.5,51.76 100.29,51.76 99.4,52.65 99.2,52.65 99,52.45 99,52.25 99.89,51.35 99.89,51.15 98.79,50.05 98.79,36.01 97.55,34.77 97.35,34.77 96.97,35.15 96.61,35.15 96.28,34.82 96.28,34.44 96.66,34.05 96.66,33.88 96.35,33.56 96.15,33.56 95.87,33.84 95.66,33.84 95.46,33.64 95.46,33.44 95.74,33.16 95.74,32.96 94.88,32.1 91.14,32.1 v2(90.75,32.5) 90.6,32.64 88.95,32.64 88.05,31.74 81.63,31.74 80.88,32.5 v2(80.6,32.5) 80.45,32.64 78.8,32.64 77.9,31.74 75.91,31.74 75.84,31.82 71.4,31.82 70.73,32.5 v2(70.45,32.5) 70.3,32.64 68.65,32.64 67.75,31.74 65.76,31.74 65.69,31.82 61.25,31.82 60.58,32.5 v2(60.3,32.5) 60.15,32.64 58.5,32.64 57.6,31.74 53.79,31.74 53.12,32.41 52.68,32.41 v2(52.22,31.95)
  BOTTOM w0.076: CPU1.AA37 106.11,65.43 106.11,64 105.54,63.43 105.54,62.65
  BOTTOM w0.14: v2(60.3,32.5) RAM4.P2 ; v2(103.67,58.85) 103.79,58.85 105.54,60.6 105.54,62.65 ; v2(90.75,32.5) RAM1.P2 ; v2(70.45,32.5) RAM3.P2 ; v2(80.6,32.5) RAM2.P2
M_A_A7: length 99.1
  TOP w0.14: RN1204.3 v2(52.22,30.62)
  L4SGND w0.142: 84.97,30.7 85.63,31.36 97.32,31.36 98.78,32.82 98.99,32.82 99.16,32.64 99.37,32.64 99.57,32.85 99.57,33.05 99.39,33.23 99.39,33.43 99.59,33.63 99.79,33.63 99.99,33.42 100.2,33.42 100.4,33.63 100.4,33.83 100.19,34.03 100.19,34.23 100.39,34.43 100.59,34.43 100.8,34.23 101,34.23 101.2,34.43 101.2,34.63 101,34.84 101,35.04 101.51,35.55 101.51,48.19 105.98,52.67 105.98,61 v2(105.09,61.89) ; 84.97,30.7 84.73,30.7 84.07,31.36 75.44,31.36 v2(74.82,30.73) 74.65,30.9 74.65,30.92 74.2,31.37 65.3,31.37 65.12,31.18 65.11,31.18 64.84,30.91 64.84,30.9 v2(64.67,30.73) 64.67,30.89 64.19,31.37 55.14,31.37 54.78,31.01 54.78,30.91 v2(54.54,30.68) 54.33,30.89 54.33,30.94 54.13,31.14 53.72,31.14 53.67,31.09 52.69,31.09 v2(52.22,30.62) ; 84.97,30.7 v2(84.97,30.68)
  BOTTOM w0.076: 105.32,62.89 105.32,63.42 105.37,63.47 105.37,63.5 105.94,64.07 105.94,64.45 105.94,65.19 105.73,65.39 105.73,65.65 105.74,65.65 105.74,65.66 105.78,65.74 105.84,65.8 106,66.13 CPU1.AA36
  BOTTOM w0.14: RAM1.R8 85.94,31.69 85.39,31.69 84.97,31.28 84.97,30.71 85,30.68 85,30.68 v2(84.97,30.68) ; RAM2.R8 75.79,31.69 75.25,31.69 74.82,31.26 v2(74.82,30.73) ; 105.32,62.89 105.09,62.66 v2(105.09,61.89) ; v2(54.54,30.68) 54.54,31.28 54.95,31.69 55.49,31.69 RAM4.R8 ; v2(64.67,30.73) 64.67,31.28 65.09,31.69 65.64,31.69 RAM3.R8
M_A_A8: length 107.1
  TOP w0.14: RN1203.1 48.91,29.53 49.22,29.84 v2(49.72,29.84)
  L6 w0.142: v2(49.72,29.84) 51.89,29.84 52.03,29.98 53.12,29.98 53.27,29.84 56.76,29.84 59.09,30.55 59.67,31.14 60.69,31.14 61.14,30.7 v2(61.14,30.68) 61.14,30.66 61.58,30.21 61.96,30.21 62.01,30.25 65.78,30.25 66.28,30.76 66.66,30.76 66.98,30.44 69.13,30.44 69.82,31.14 70.84,31.14 71.29,30.7 v2(71.29,30.68) 71.29,30.66 71.69,30.25 71.7,30.25 71.73,30.22 72.11,30.22 72.14,30.25 75.79,30.25 76.3,30.76 76.81,30.76 77.18,30.4 79.23,30.4 79.97,31.14 80.99,31.14 81.44,30.7 v2(81.44,30.68) 81.44,30.66 81.88,30.21 82.27,30.21 82.72,30.66 83.57,30.66 84.02,30.21 86.03,30.21 86.58,30.76 86.96,30.76 87.28,30.44 88.88,30.44 89.58,31.14 91.14,31.14 91.59,30.7 v2(91.59,30.68) 91.59,30.67 92.03,30.22 92.42,30.22 92.71,30.5 95.47,30.5 95.75,30.78 96.37,30.78 96.64,30.5 96.94,30.5 97.21,30.78 97.51,30.78 97.78,30.5 98.14,30.5 99.99,32.35 99.99,48.6 100.44,49.06 100.44,49.26 100.19,49.5 100.19,49.7 100.4,49.9 100.6,49.9 100.84,49.66 101.04,49.66 101.24,49.86 101.24,50.06 100.95,50.36 100.95,50.56 101.15,50.76 101.35,50.76 101.65,50.47 101.85,50.47 102.05,50.67 102.05,50.87 101.75,51.16 101.75,51.36 101.95,51.56 102.16,51.56 102.45,51.27 102.65,51.27 102.85,51.47 102.85,51.67 102.56,51.97 102.56,52.17 102.76,52.37 102.96,52.37 103.25,52.07 103.46,52.07 103.66,52.28 103.66,52.48 103.41,52.72 103.41,52.92 103.61,53.12 103.82,53.12 104.06,52.88 104.26,52.88 104.51,53.13 104.51,58.7 104.66,58.84 v2(105.02,58.84)
  BOTTOM w0.076: CPU1.AB34 106.39,66.91 106.39,66.44 106.43,66.32 106.43,66.08 106.39,65.96 106.39,65.78 106.45,65.62 106.45,63.8 106.18,63.54 106.18,63.3
  BOTTOM w0.14: RAM4.R2 60.7,31.94 61.11,31.53 61.11,30.71 v2(61.14,30.68) ; 106.18,63.3 106.18,60.01 v2(105.02,58.84) ; RAM3.R2 70.85,32 71.26,31.6 71.26,30.71 v2(71.29,30.68) ; RAM1.R2 91.15,31.84 91.58,31.42 91.58,31.14 91.59,31.13 v2(91.59,30.68) ; v2(81.44,30.68) 81.41,30.71 81.41,31.5 81,31.91 RAM2.R2
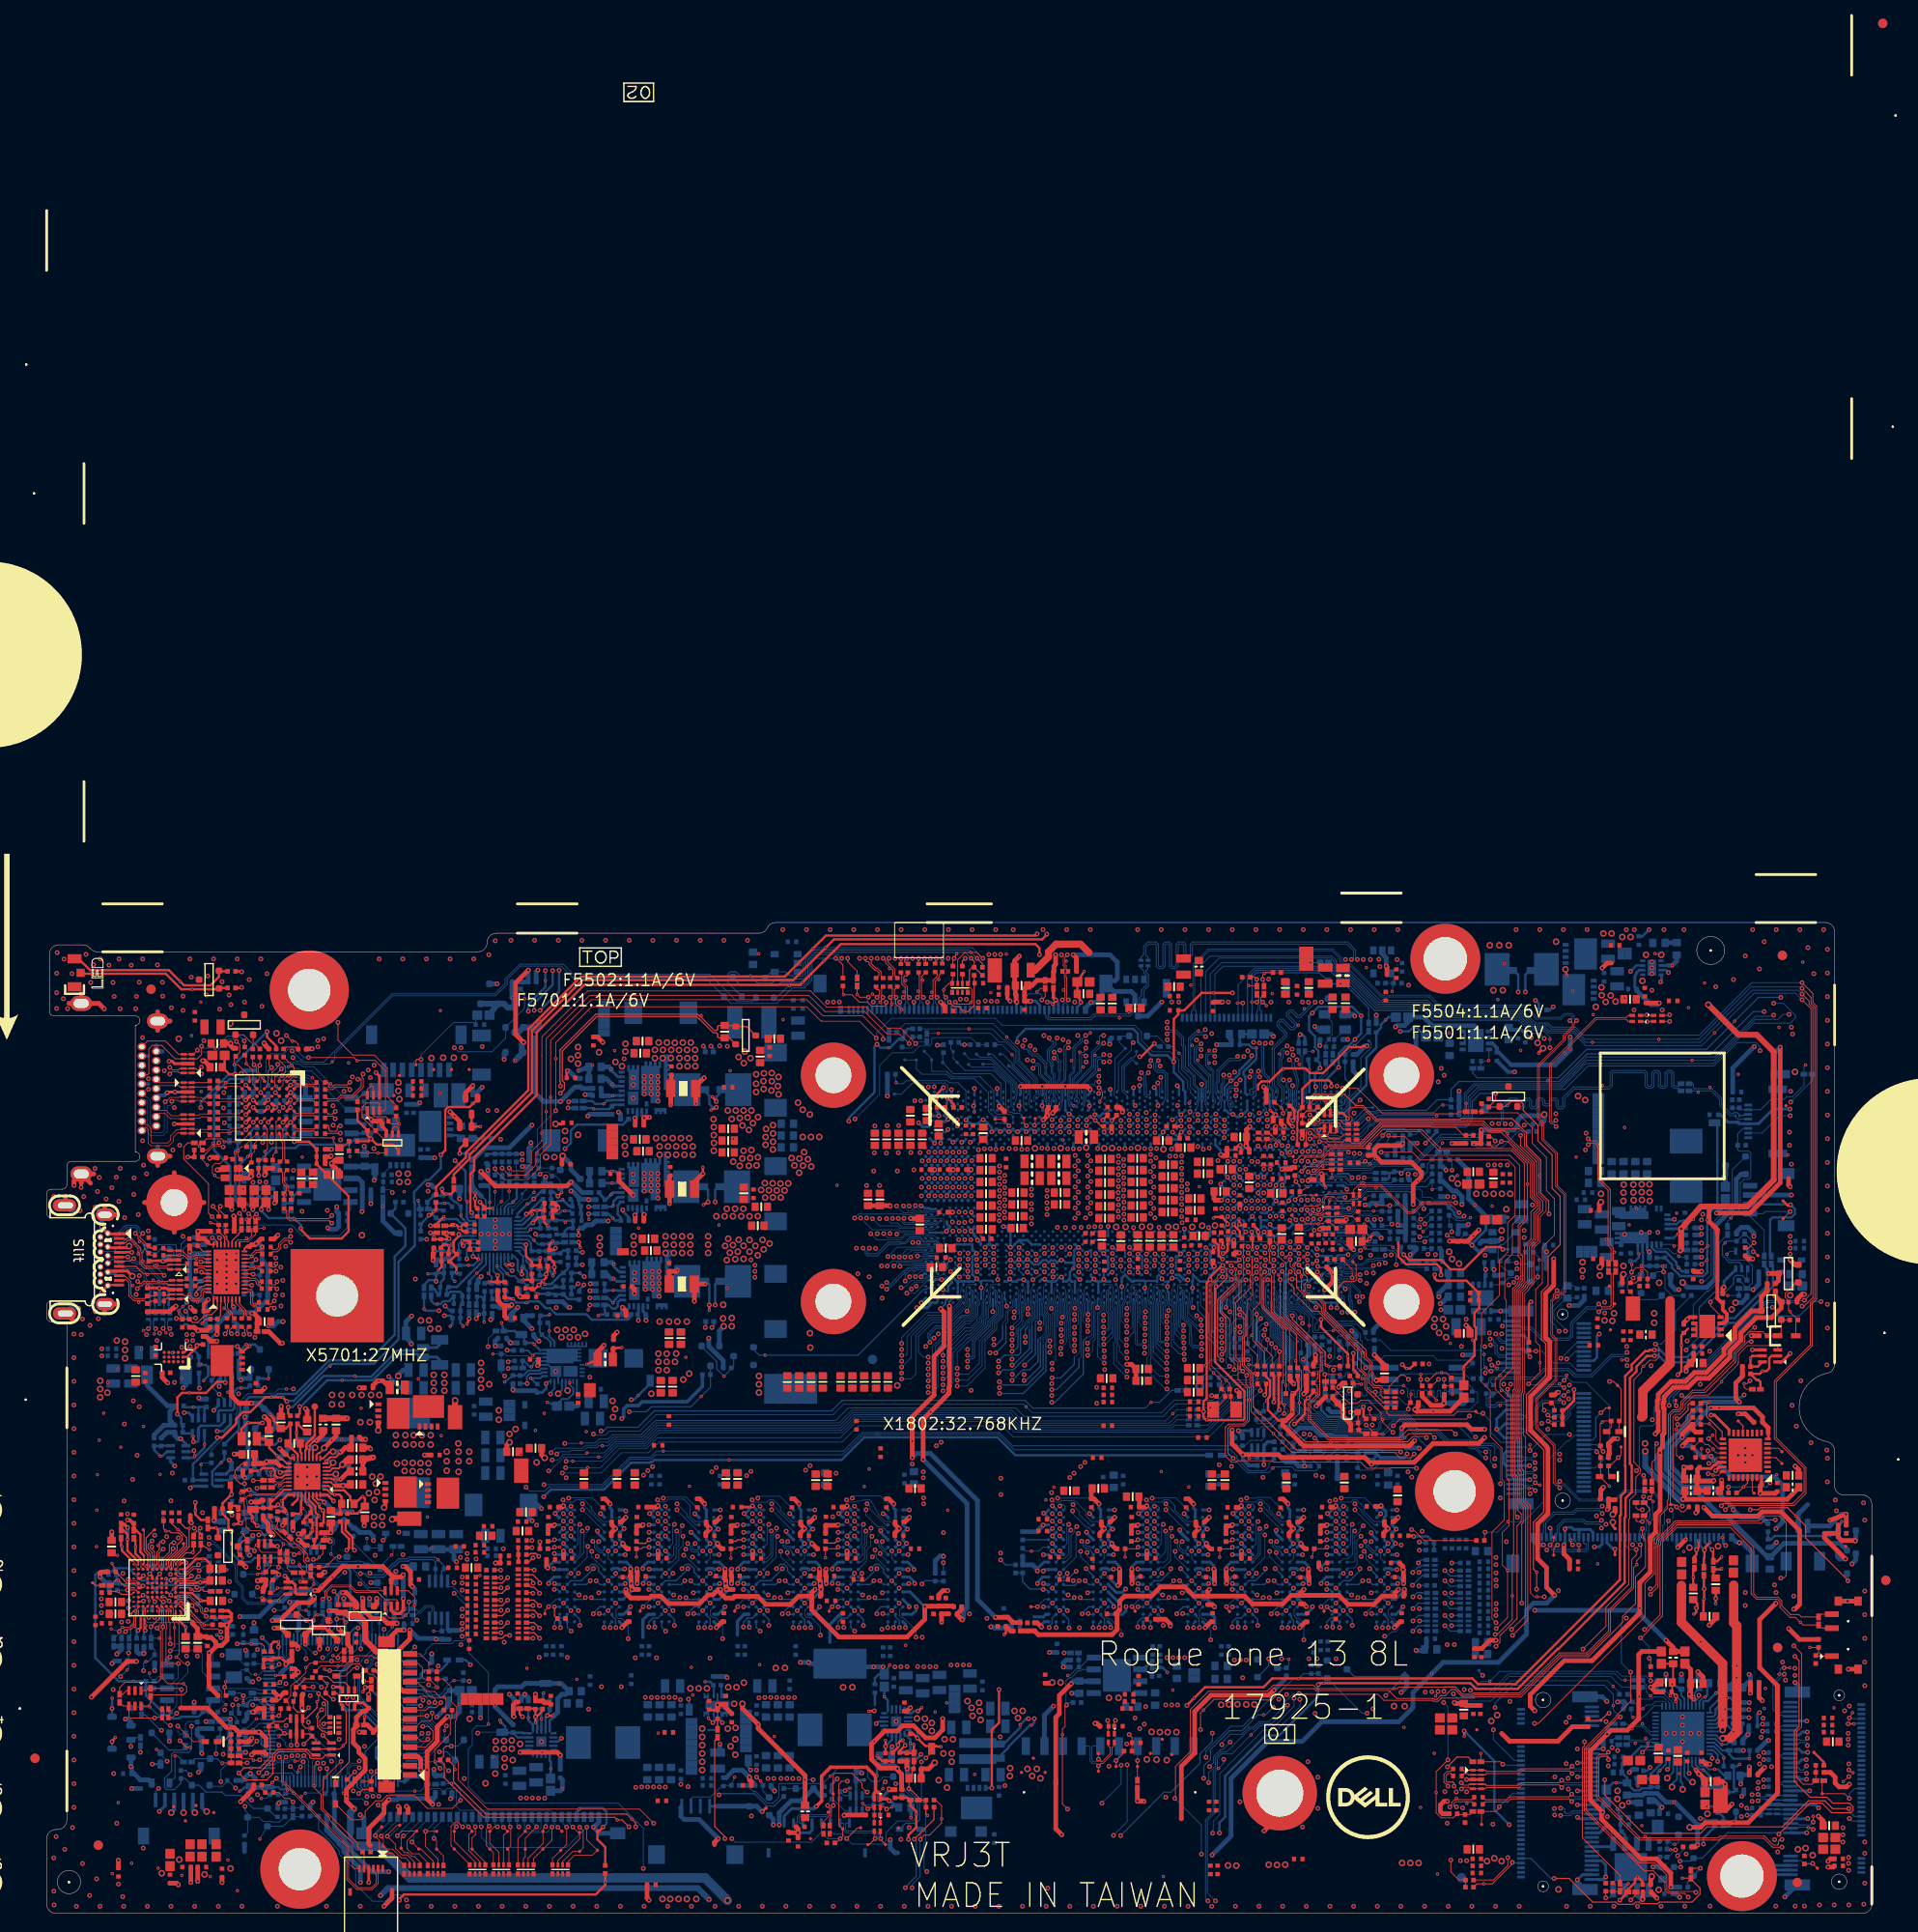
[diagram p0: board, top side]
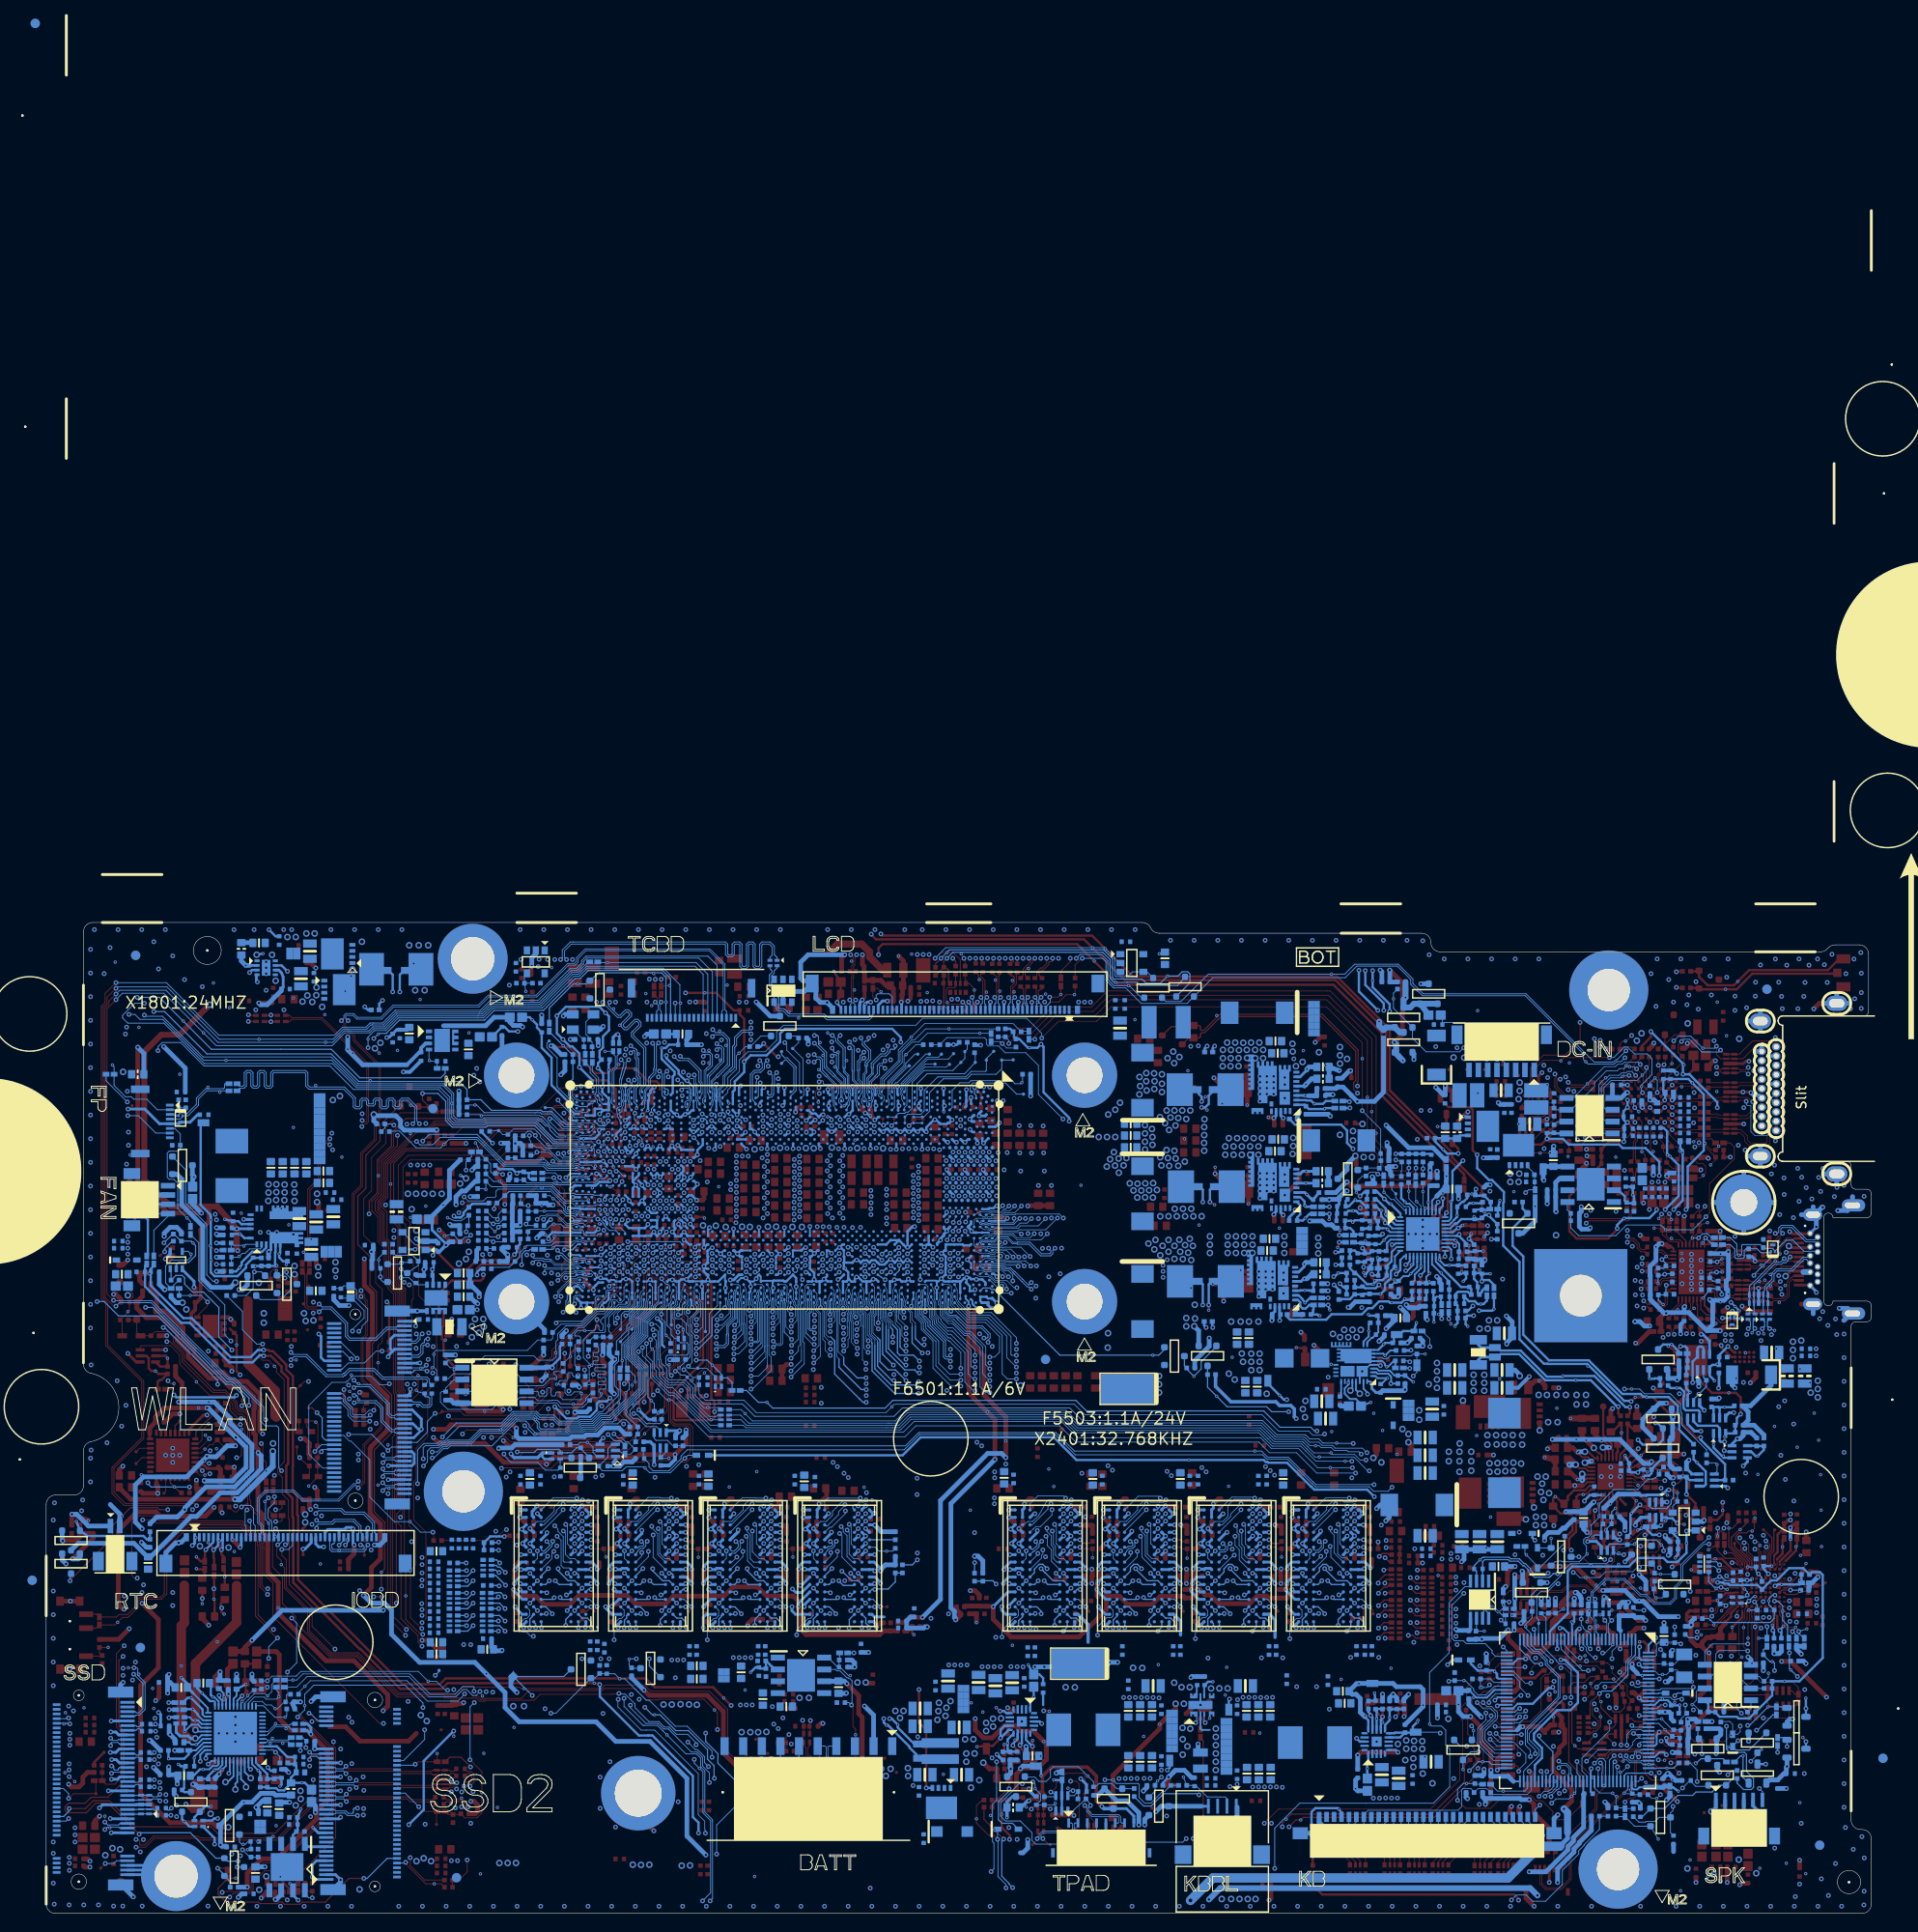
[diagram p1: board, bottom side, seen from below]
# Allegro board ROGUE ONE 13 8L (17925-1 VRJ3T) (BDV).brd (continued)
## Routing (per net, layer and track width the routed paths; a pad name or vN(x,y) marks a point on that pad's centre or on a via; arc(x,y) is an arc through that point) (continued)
M_A_A9: length 97.7
  TOP w0.14: RN1204.4 52.34,31.21 v2(52.93,30.62)
  L6 w0.142: v2(52.93,30.62) 53.46,31.15 57.02,31.15 v2(57.26,30.9) 59.03,30.9 59.55,31.43 60.81,31.43 61.02,31.23 65.45,31.23 65.52,31.16 67.15,31.16 v2(67.41,30.9) 69.18,30.9 69.7,31.43 70.96,31.43 71.17,31.23 75.6,31.23 75.67,31.16 77.3,31.16 v2(77.56,30.9) 79.33,30.9 79.85,31.43 81.11,31.43 81.39,31.16 87.45,31.16 v2(87.71,30.9) 88.93,30.9 89.44,31.41 91.29,31.41 91.43,31.27 97.26,31.27 99.56,33.57 99.56,49.78 104.12,54.34 104.12,59.6 105.55,61.03 105.55,62.07 105.3,62.32 104.76,62.32 104.38,61.94 104.38,61.05 v2(103.67,60.34)
  BOTTOM w0.076: 104.31,62.69 104.35,62.8 104.82,63.27 104.82,64.16 104.81,64.17 104.81,64.5 104.82,64.51 104.82,65.17 104.89,65.25 105.05,65.4 105.05,65.66 104.93,65.88 104.93,65.89 104.79,66.14 104.79,66.14 CPU1.W36
  BOTTOM w0.14: v2(77.56,30.9) 77.56,31.54 RAM2.R7 ; 104.31,62.69 104.31,60.8 103.84,60.34 v2(103.67,60.34) ; v2(57.26,30.9) 57.26,31.54 RAM4.R7 ; v2(67.41,30.9) 67.41,31.54 RAM3.R7 ; v2(87.71,30.9) 87.71,31.54 RAM1.R7
M_A_A10: length 97.2
  TOP w0.14: v2(52.93,34.36) 52.93,34.43 52.37,34.99 52.06,34.99 51.8,35.25 RN1202.1
  L4SGND w0.142: v2(106.26,68.85) 106.33,68.78 106.33,67.84 104.88,66.39 103.71,66.39 102.5,65.18 102.5,60.12 102.1,59.71 101.39,59.71 100.9,59.23 100.9,58.58 101.04,58.44 101.65,58.44 101.8,58.3 101.8,58.01 101.65,57.87 101.04,57.87 100.9,57.73 100.9,57.44 101.04,57.3 101.65,57.3 101.8,57.16 101.8,56.88 101.65,56.73 101.04,56.73 100.9,56.59 100.9,56.31 101.04,56.16 101.65,56.16 101.8,56.02 101.8,55.74 101.65,55.6 101.04,55.6 100.9,55.45 100.9,55.17 101.04,55.03 101.65,55.03 101.8,54.88 101.8,54.6 101.65,54.46 101.04,54.46 100.9,54.32 100.9,54.03 101.04,53.89 101.65,53.89 101.8,53.75 101.8,53.46 101.65,53.32 101.04,53.32 100.9,53.18 100.9,52.89 101.04,52.75 101.6,52.75 101.74,52.61 101.74,52.32 101.6,52.18 101.04,52.18 100.9,52.04 100.9,50.89 99.28,49.27 99.28,44.6 95.01,40.32 95.01,35.68 93.74,34.41 v2(89.74,34.41) 89.51,34.64 87.09,34.64 86.5,34.06 84.77,34.06 84.72,34.01 82.17,34.01 81.77,34.41 v2(79.59,34.41) 79.36,34.64 76.94,34.64 76.35,34.06 74.62,34.06 74.57,34.01 72.02,34.01 71.62,34.41 v2(69.44,34.41) 69.21,34.64 66.79,34.64 66.2,34.06 64.47,34.06 64.42,34.01 61.87,34.01 61.47,34.41 v2(59.29,34.41) 59.06,34.64 56.64,34.64 56.05,34.06 54.49,34.06 54.19,34.36 v2(52.93,34.36)
  BOTTOM w0.14: v2(89.74,34.41) 89.83,34.5 RAM1.M3 ; RAM4.M3 59.38,34.5 v2(59.29,34.41) ; v2(79.59,34.41) 79.68,34.5 RAM2.M3 ; CPU1.Y31 v2(106.26,68.85) ; RAM3.M3 69.53,34.5 v2(69.44,34.41)
M_A_A11: length 101.3
  TOP w0.14: RN1203.2 v2(48.79,30.12)
  L6 w0.142: 90.95,30.67 90.97,30.65 91.67,29.95 92.57,29.95 92.74,30.12 98.75,30.12 100.34,31.72 100.34,48.46 104.87,52.98 104.87,56.42 105.52,57.07 105.52,59.35 106.16,59.99 106.16,62.25 105.56,62.85 105.56,63.15 106.89,64.47 106.89,64.67 106.6,64.95 106.4,64.95 105.76,64.31 v2(105.37,64.31) ; 90.95,30.67 90.95,30.66 90.13,29.83 83.99,29.83 83.45,30.37 82.84,30.37 82.39,29.92 81.54,29.92 80.97,30.48 80.97,30.5 80.8,30.67 ; 90.95,30.67 v2(90.95,30.68) ; 80.8,30.67 80.8,30.66 79.98,29.83 73.36,29.83 73.35,29.84 73.15,29.84 73.05,29.95 72.26,29.95 72.23,29.92 71.39,29.92 70.65,30.66 70.65,30.66 ; 80.8,30.67 v2(80.8,30.68) ; 60.5,30.67 60.32,30.49 60.32,30.49 60.05,30.22 60.05,30.22 58.9,29.07 49.84,29.07 v2(48.79,30.12) ; 60.5,30.67 60.68,30.49 60.68,30.49 60.95,30.22 60.95,30.22 61.25,29.92 62.08,29.92 62.11,29.95 62.9,29.95 63.01,29.83 69.83,29.83 70.65,30.66 ; 60.5,30.67 v2(60.5,30.68) ; 70.65,30.66 v2(70.65,30.68)
  BOTTOM w0.076: v2(105.37,64.31) 104.98,64.7 104.98,65.11 105.2,65.33 105.21,65.34 105.21,65.7 105.09,65.92 105.09,66.87 104.79,67.49 CPU1.W34
  BOTTOM w0.14: v2(70.65,30.68) 70.65,31.1 RAM3.T2 ; RAM1.T2 v2(90.95,30.68) ; v2(80.8,30.68) 80.8,31.12 80.98,31.3 RAM2.T2 ; RAM4.T2 60.5,31.1 v2(60.5,30.68)
M_A_A12: length 99.7
  TOP w0.14: RN1206.4 v2(48.79,33.62)
  L6 w0.142: v2(102.22,59.28) 101.99,59.5 101.17,59.5 100.8,59.13 100.8,56.4 97.19,52.79 97.19,49.6 96.81,49.22 96.06,49.22 95.91,49.08 95.91,44.18 96.06,44.04 96.92,44.04 97.07,43.9 97.07,43.61 96.92,43.47 96.06,43.47 95.91,43.33 95.91,43.04 96.06,42.9 96.92,42.9 97.07,42.76 97.07,42.48 96.92,42.33 96.06,42.33 95.91,42.19 95.91,41.72 96.14,41.5 96.91,41.5 97.14,41.27 97.14,40.48 96.84,40.18 95.82,40.18 94.63,38.98 94.63,36.61 94.49,36.47 94,36.47 93.86,36.33 93.86,36.04 94,35.9 94.49,35.9 94.63,35.76 94.63,35.25 93.54,34.16 93.18,34.16 93.04,34.3 93.04,34.75 92.89,34.89 92.61,34.89 92.47,34.75 92.47,34.3 92.33,34.16 90.15,34.16 89.95,33.96 89.54,33.96 89.15,34.35 87.81,34.35 v2(87.64,34.18) 87.51,34.06 85.64,34.06 85.59,34.01 81.83,34.01 81.79,34.06 79.9,34.06 79.79,33.95 79.4,33.95 78.99,34.36 77.67,34.36 v2(77.49,34.18) 77.36,34.06 75.49,34.06 75.44,34.01 71.68,34.01 71.64,34.06 69.75,34.06 69.64,33.95 69.25,33.95 68.84,34.36 67.52,34.36 v2(67.34,34.18) 67.21,34.06 65.34,34.06 65.29,34.01 61.46,34.01 61.06,34.41 59.95,34.41 59.49,33.95 59.1,33.95 58.69,34.36 57.37,34.36 v2(57.19,34.18) 57.06,34.06 55.19,34.06 55.14,34.01 54.2,34.01 53.39,34.82 50.03,34.82 49.69,34.48 49.65,34.48 v2(48.79,33.62)
  BOTTOM w0.076: CPU1.AA34 106,67.49 105.69,66.84 105.69,65.9 105.66,65.86 105.65,65.84 105.57,65.71 105.57,65.69 105.57,65.69 105.57,65.33 105.78,65.12 105.78,64.15 105.12,63.49 105.12,63.19 105.07,63.14
  BOTTOM w0.14: v2(102.22,59.28) 102.86,59.91 104.33,59.91 104.59,60.17 104.59,62.65 105.07,63.14 ; v2(77.49,34.18) 77.32,34.18 RAM2.M7 ; RAM1.M7 v2(87.64,34.18) ; RAM3.M7 67.17,34.18 v2(67.34,34.18) ; RAM4.M7 57.02,34.18 v2(57.19,34.18)
M_A_A13: length 96.8
  TOP w0.14: RN1204.2 52.34,30.12 v2(52.93,29.53)
  L4SGND w0.142: v2(52.93,29.53) 53.01,29.61 53.45,29.61 53.58,29.74 55.76,29.74 v2(56.32,30.29) 56.7,29.92 62.08,29.92 62.13,29.96 66.14,29.96 v2(66.47,30.29) 66.85,29.92 72.23,29.92 72.28,29.96 76.29,29.96 v2(76.62,30.29) 77,29.92 82.39,29.92 82.84,30.37 83.41,30.37 83.86,29.92 86.2,29.92 86.58,30.29 v2(86.77,30.29) 87.09,29.98 92.59,29.98 92.83,30.22 98.01,30.22 101.87,34.08 101.87,48.04 106.36,52.55 106.36,61.23 107.15,62.02 107.15,67.3 107.64,67.79 107.64,68.48 v2(108.07,68.92)
  BOTTOM w0.14: v2(86.77,30.29) 86.35,30.72 RAM1.T8 ; RAM2.T8 76.2,30.72 v2(76.62,30.29) ; v2(66.47,30.29) 66.05,30.72 RAM3.T8 ; v2(56.32,30.29) 55.9,30.72 RAM4.T8 ; CPU1.AC32 v2(108.07,68.92)
M_A_A14: length 99.5
  TOP w0.14: v2(52.25,35.45) 52.25,35.64 52.05,35.84 RN1202.2
  L4SGND w0.142: v2(107.15,69.54) 106.35,69.54 105.78,68.97 105.78,68.6 105.4,68.22 105.4,67.89 104.58,67.07 104.07,67.07 102.2,65.21 102.2,60.91 101.89,60.6 101.14,60.6 100.54,60 100.54,51.03 98.92,49.42 98.92,48.56 98.78,48.42 98.17,48.42 98.03,48.27 98.03,47.99 98.17,47.85 98.78,47.85 98.92,47.71 98.92,47.42 98.78,47.28 98.17,47.28 98.03,47.14 98.03,46.85 98.17,46.71 98.78,46.71 98.92,46.57 98.92,46.28 98.78,46.14 98.17,46.14 98.03,46 98.03,45.71 98.17,45.57 98.78,45.57 98.92,45.43 98.92,44.77 98.47,44.32 98.27,44.32 97.82,44.76 97.62,44.77 97.42,44.56 97.42,44.36 97.86,43.92 97.86,43.71 97.66,43.51 97.46,43.51 97.01,43.96 96.81,43.96 96.61,43.76 96.61,43.56 97.06,43.11 97.06,42.91 96.86,42.71 96.66,42.71 96.21,43.16 96.01,43.16 95.81,42.95 95.81,42.75 96.25,42.31 96.25,42.11 96.05,41.9 95.85,41.9 95.4,42.35 95.2,42.35 95,42.15 95,41.95 95.45,41.5 95.45,41.3 95.25,41.1 95.05,41.1 94.6,41.55 94.4,41.55 94.2,41.35 94.2,41.14 94.64,40.7 94.64,40.5 94.53,40.38 94.53,37.27 93.17,35.91 90.96,35.91 v2(90.75,35.7) 90.29,35.24 86.29,35.24 85.66,35.87 80.77,35.87 v2(80.6,35.7) 80.14,35.24 76.14,35.24 75.51,35.87 70.62,35.87 v2(70.45,35.7) 69.99,35.24 65.99,35.24 65.36,35.87 60.47,35.87 v2(60.3,35.7) 59.84,35.24 55.84,35.24 55.13,35.95 52.74,35.95 v2(52.25,35.45)
  BOTTOM w0.14: v2(90.75,35.7) RAM1.L2 ; v2(70.45,35.7) RAM3.L2 ; v2(80.6,35.7) RAM2.L2 ; v2(60.3,35.7) RAM4.L2 ; CPU1.AC31 v2(107.15,69.54)
M_A_A15: length 98.9
  TOP w0.14: RN1207.2 v2(48.79,34.95)
  L6 w0.142: v2(48.79,34.95) 49.42,35.57 49.69,35.57 50.03,35.91 53.39,35.91 53.39,35.91 54.69,35.91 55.5,35.1 v2(55.5,34.91) 55.54,34.94 58.69,34.94 58.99,35.24 60.49,35.24 60.68,35.43 61.35,35.43 61.79,35.87 61.97,35.87 61.97,35.87 64.88,35.87 65.65,35.1 v2(65.65,34.91) 67.02,34.91 67.05,34.94 68.84,34.94 69.14,35.24 70.64,35.24 70.86,35.45 71.61,35.45 72.02,35.87 75.03,35.87 75.8,35.1 v2(75.8,34.91) 77.17,34.91 77.2,34.94 78.99,34.94 79.29,35.24 80.79,35.24 81.13,35.57 81.91,35.57 82.21,35.87 85.18,35.87 85.95,35.1 v2(85.95,34.91) 87.32,34.91 87.35,34.94 89.14,34.94 89.44,35.24 89.64,35.24 90.56,36.15 90.98,36.15 91.09,36.05 92.41,36.05 92.81,36.45 93.33,36.45 94.17,37.29 94.17,39.39 95.56,40.77 95.56,49.26 96.81,50.51 96.81,52.96 100.44,56.58 100.44,57.52 100.45,57.53 100.45,61.03 100.97,61.55 100.97,61.75 100.51,62.21 100.51,62.41 100.71,62.62 100.91,62.62 101.37,62.16 101.57,62.16 101.77,62.36 101.77,62.56 101.31,63.02 101.31,63.22 101.52,63.42 101.72,63.42 102.18,62.96 102.38,62.96 102.58,63.16 102.58,63.36 102.12,63.82 102.12,64.02 102.32,64.22 102.52,64.22 102.98,63.77 103.18,63.77 103.39,63.98 103.39,64.74 103.72,65.07 103.72,65.83 103.9,66.01 104.38,66.01 104.62,66.24 104.62,66.98 104.76,67.12 105.04,67.12 105.18,66.98 105.18,66.15 105.33,66.01 106.7,66.01 106.85,66.15 106.85,66.6 106.7,66.74 106.05,66.74 105.91,66.89 v2(105.91,68.01)
  BOTTOM w0.14: v2(65.65,34.91) 65.69,34.87 65.69,34.87 RAM3.M8 ; RAM4.M8 55.54,34.87 55.54,34.87 v2(55.5,34.91) ; RAM2.M8 75.84,34.87 75.84,34.87 v2(75.8,34.91) ; v2(85.95,34.91) 85.99,34.87 85.99,34.87 RAM1.M8 ; CPU1.AB32 v2(105.91,68.01)
M_A_A16: length 108.3
  TOP w0.14: R1211.1 v2(48.75,36.85)
  L4SGND w0.142: v2(105.32,68.83) 104.94,68.44 104.74,68.44 99.38,63.08 99.38,56.91 99.76,56.53 99.76,53.63 94.15,48.02 94.14,48.02 93.01,46.9 91.95,46.9 91.81,46.75 91.81,46.47 91.95,46.33 93.01,46.33 93.16,46.18 93.16,45.9 93.01,45.76 91.95,45.76 91.81,45.62 91.81,45.33 91.95,45.19 93.01,45.19 93.16,45.05 93.16,44.76 93.01,44.62 91.95,44.62 91.81,44.48 91.81,44.19 91.95,44.05 93.01,44.05 93.16,43.91 93.16,42.08 93,41.92 93,38.35 92.03,37.38 91.54,37.38 91.38,37.55 91.38,38.26 91.23,38.4 90.95,38.4 90.81,38.26 90.81,37.52 90.67,37.38 89.3,37.38 89.16,37.24 v2(89.16,37) 88.21,37.95 79.96,37.95 v2(79.01,37) 79.01,37.02 78.08,37.95 69.81,37.95 v2(68.86,37) 68.86,37.02 67.93,37.95 59.66,37.95 v2(58.71,37) 58.71,37.02 57.78,37.95 53.13,37.95 52.88,37.69 49.6,37.69 v2(48.75,36.85)
  BOTTOM w0.14: RAM3.L8 66.45,35.7 67.6,35.7 68.86,36.97 v2(68.86,37) ; RAM1.L8 86.75,35.7 87.86,35.7 88.7,36.54 88.71,36.54 88.98,36.81 88.98,36.82 v2(89.16,37) ; v2(58.71,37) 58.71,36.98 57.43,35.7 56.3,35.7 RAM4.L8 ; RAM2.L8 76.6,35.7 77.75,35.7 79.01,36.97 v2(79.01,37) ; CPU1.Y32 v2(105.32,68.83)
M_A_ACT_N: length 104.4
  TOP w0.14: v2(49.5,36.04) 48.91,35.45 RN1207.3
  L2SGND w0.089: v2(89.47,35.7) 90.18,35.7 90.31,35.83 90.31,36.12 90.22,36.21 89.33,36.21 89.24,36.29 89.24,36.47 89.33,36.56 90.2,36.56 90.31,36.67 90.31,37.22 90.4,37.31 90.59,37.31 90.68,37.22 90.68,36.25 90.77,36.16 90.95,36.16 91.04,36.25 91.04,37.22 91.12,37.31 91.56,37.31 91.65,37.22 91.65,37.01 91.74,36.92 91.92,36.92 92.01,37.01 92.01,37.24 92.1,37.33 94.07,37.33 99.31,42.57 99.31,42.87 99.22,42.96 98.83,42.96 98.74,43.05 98.74,43.23 98.83,43.32 99.22,43.32 99.31,43.41 99.31,43.59 99.22,43.67 98.83,43.67 98.74,43.76 98.74,43.94 98.83,44.03 99.22,44.03 99.31,44.12 99.31,44.3 99.22,44.39 98.83,44.39 98.74,44.47 98.74,44.65 98.83,44.74 99.22,44.74 99.31,44.83 99.31,45.01 99.22,45.1 98.83,45.1 98.74,45.19 98.74,45.36 98.83,45.45 99.22,45.45 99.31,45.54 99.31,45.72 99.22,45.81 98.83,45.81 98.74,45.9 98.74,46.08 98.83,46.16 99.22,46.16 99.31,46.25 99.31,46.43 99.22,46.52 98.83,46.52 98.74,46.61 98.74,46.79 98.83,46.88 99.22,46.88 99.31,46.96 99.31,47.14 99.22,47.23 98.83,47.23 98.74,47.32 98.74,47.5 98.83,47.59 99.22,47.59 99.31,47.68 99.31,47.85 99.22,47.94 98.83,47.94 98.74,48.03 98.74,48.21 98.83,48.3 99.22,48.3 99.31,48.39 99.31,48.56 99.22,48.65 98.83,48.65 98.74,48.74 98.74,48.92 98.83,49.01 99.22,49.01 99.31,49.1 99.31,49.28 99.22,49.36 98.83,49.36 98.74,49.45 98.74,49.63 98.83,49.72 99.22,49.72 99.31,49.81 99.31,49.99 99.22,50.08 98.83,50.08 98.74,50.16 98.74,50.34 98.83,50.43 99.22,50.43 99.31,50.52 99.31,50.7 99.22,50.79 98.83,50.79 98.74,50.88 98.74,53.41 101.21,55.87 101.21,59.43 v2(101.92,60.14)
  L6 w0.142: v2(89.47,35.7) 89.47,35.68 89.02,35.24 86.36,35.24 85.43,36.16 81.9,36.16 81.7,35.96 81.07,35.96 80.81,36.21 80.46,36.21 79.94,35.7 v2(79.32,35.7) 79.32,35.68 78.87,35.24 76.17,35.24 75.25,36.16 71.82,36.16 71.51,35.86 71.13,35.86 70.8,36.19 70.28,36.19 69.79,35.7 v2(69.17,35.7) 69.17,35.68 68.72,35.24 66.09,35.24 65.16,36.16 61.42,36.16 61.29,36.04 60.91,36.04 60.71,36.24 60.18,36.24 59.64,35.7 v2(59.02,35.7) 59.02,35.68 58.57,35.24 56,35.24 55.07,36.16 55.04,36.2 53.51,36.2 53.42,36.29 49.76,36.29 v2(49.5,36.04)
  BOTTOM w0.076: 103.01,62.98 103.01,63.32 103.21,63.51 103.21,64.48 103.91,65.19 103.91,65.67 103.87,65.78 103.87,65.97 104.04,66.42 CPU1.V35
  BOTTOM w0.14: RAM1.L3 89.86,35.3 v2(89.47,35.7) ; 103.01,62.98 103.01,61.23 v2(101.92,60.14) ; RAM2.L3 79.71,35.3 v2(79.32,35.7) ; RAM3.L3 69.57,35.3 v2(69.17,35.7) ; RAM4.L3 59.41,35.3 v2(59.02,35.7)
M_A_ALERT_N: length 80.6
  TOP w0.14: R1208.1 54.54,31.95 v2(54.54,32.9)
  L2SGND w0.089: v2(84.99,32.9) 85.02,32.87 86.47,32.87 86.56,32.96 90.21,32.96 91.17,33.93 93.23,33.93 100.67,41.37 100.67,53.13 103.11,55.57 103.11,61 v2(103.67,61.56)
  L4SGND w0.142: v2(54.54,32.9) 55.24,32.9 55.31,32.84 55.69,32.84 55.82,32.96 60.78,32.96 61.3,32.45 64.25,32.45 64.69,32.89 v2(64.69,32.9) 65.39,32.9 65.46,32.84 65.84,32.84 65.97,32.96 70.93,32.96 71.45,32.45 74.01,32.45 74.4,32.45 74.67,32.72 74.67,32.72 74.84,32.89 v2(74.84,32.9) 75.54,32.9 75.61,32.84 75.99,32.84 76.12,32.96 81.08,32.96 81.62,32.42 84.52,32.42 84.54,32.45 84.55,32.45 84.82,32.72 84.82,32.73 v2(84.99,32.9)
  BOTTOM w0.076: v2(103.67,61.56) 104.1,61.99 104.1,62.98 104.65,63.53 104.65,64.09 104.64,64.1 104.64,64.57 104.65,64.57 104.65,65.41 CPU1.W37
  BOTTOM w0.14: RAM3.P9 v2(64.69,32.9) ; RAM2.P9 v2(74.84,32.9) ; RAM1.P9 v2(84.99,32.9) ; v2(54.54,32.9) RAM4.P9
M_A_BA0: length 99.7
  TOP w0.14: v2(49.5,32.53) 48.91,31.95 RN1206.1
  L6 w0.142: v2(104.39,69.57) 104.89,69.06 104.89,68.65 105.15,68.4 105.5,68.4 105.54,68.44 106.08,68.44 107.07,67.46 107.61,67.46 107.91,67.15 107.91,65.8 107.62,65.51 105.14,65.51 104.74,65.11 104.74,63.87 104.28,63.42 103.52,63.42 102.86,62.76 102.86,58.04 102.34,57.52 102.12,57.52 101.51,56.91 101.51,56.03 97.96,52.47 97.96,39.44 97.47,38.96 96.13,38.96 95.44,38.27 95.44,34.94 93.89,33.39 91.64,33.39 v2(91.55,33.3) 88.78,33.3 88.62,33.14 86.45,33.14 85.74,32.44 82.26,32.44 v2(81.4,33.3) 78.63,33.3 78.47,33.14 76.3,33.14 75.59,32.44 72.11,32.44 v2(71.25,33.3) 68.48,33.3 68.32,33.14 66.15,33.14 65.44,32.44 61.96,32.44 v2(61.1,33.3) 58.33,33.3 58.17,33.14 56,33.14 55.69,32.84 55.31,32.84 54.77,33.38 53.62,33.38 53.5,33.5 50.69,33.5 49.73,32.53 v2(49.5,32.53)
  BOTTOM w0.14: v2(104.39,69.57) 104.39,69.03 CPU1.W32 ; v2(81.4,33.3) RAM2.N2 ; v2(61.1,33.3) RAM4.N2 ; v2(71.25,33.3) RAM3.N2 ; v2(91.55,33.3) RAM1.N2
M_A_BA1: length 93
  TOP w0.14: RN1205.3 v2(52.22,33.03)
  L4SGND w0.142: v2(52.22,33.03) 52.68,33.5 53.58,33.5 53.7,33.38 55.42,33.38 v2(55.5,33.3) 60.18,33.3 60.65,33.76 61.29,33.76 61.68,33.38 65.57,33.38 v2(65.65,33.3) 70.33,33.3 70.8,33.76 71.44,33.76 71.83,33.38 75.72,33.38 v2(75.8,33.3) 80.48,33.3 80.95,33.76 81.59,33.76 81.98,33.38 85.87,33.38 v2(85.95,33.3) 90.71,33.3 91.55,32.46 94.81,32.46 95.82,33.47 95.82,38.58 96.13,38.88 97,38.88 97.15,38.74 97.15,38.23 97.29,38.09 97.57,38.09 97.72,38.23 97.72,38.74 97.86,38.88 98.26,38.88 98.62,39.24 98.82,39.24 99.1,38.96 99.3,38.96 99.5,39.16 99.5,39.36 99.22,39.64 99.22,39.84 100.06,40.68 100.06,48.94 102.8,51.67 102.8,64.06 104.44,65.7 104.53,65.7 106.74,67.92 106.74,68.45 v2(107.15,68.85)
  BOTTOM w0.14: RAM3.N8 v2(65.65,33.3) ; CPU1.AB31 v2(107.15,68.85) ; RAM2.N8 v2(75.8,33.3) ; RAM4.N8 v2(55.5,33.3) ; RAM1.N8 v2(85.95,33.3)
M_A_BG0: length 99.6
  TOP w0.14: RN1202.3 52.24,36.34 52.96,35.62 v2(52.96,35.45)
  L2SGND w0.089: v2(103.87,63.95) 104.31,64.38 104.31,65.64 104.4,65.73 105.14,65.73 105.31,65.89 105.31,66.78 105.22,66.87 105.04,66.87 104.95,66.78 104.95,66.45 104.86,66.37 104.69,66.37 104.6,66.45 104.6,66.76 104.51,66.85 104.33,66.85 104.24,66.76 104.24,66.45 104.15,66.37 103.7,66.37 102.48,65.14 102.48,63.99 102.36,63.88 101.7,63.88 101.61,63.79 101.61,63.61 101.7,63.52 102.39,63.52 102.48,63.43 102.48,63.28 102.36,63.17 101.7,63.17 101.61,63.08 101.61,62.9 101.7,62.81 102.39,62.81 102.48,62.72 102.48,62.57 102.36,62.45 101.7,62.45 101.61,62.37 101.61,62.19 101.7,62.1 102.39,62.1 102.48,62.01 102.48,60.1 101.52,59.14 101.52,55.76 99.62,53.85 99.62,53.14 99.53,53.05 99.14,53.05 99.05,52.96 99.05,52.78 99.14,52.69 99.53,52.69 99.62,52.6 99.62,52.43 99.53,52.34 99.14,52.34 99.05,52.25 99.05,52.07 99.14,51.98 99.53,51.98 99.62,51.89 99.62,51.72 99.53,51.63 99.14,51.63 99.05,51.54 99.05,51.36 99.14,51.27 99.53,51.27 99.62,51.18 99.62,42.58 93.44,36.39 92.37,36.39 91.56,35.58 v2(91.56,34.9)
  L6 w0.142: v2(52.96,35.45) 53.18,35.45 54.32,34.3 54.99,34.3 55.05,34.36 56.71,34.36 56.97,34.62 56.99,34.62 57.02,34.65 58.81,34.65 59.07,34.9 v2(61.11,34.9) 61.71,34.3 65.14,34.3 65.2,34.36 66.86,34.36 67.12,34.62 67.14,34.62 67.17,34.65 68.96,34.65 69.22,34.9 v2(71.26,34.9) 71.86,34.3 75.29,34.3 75.35,34.36 77.01,34.36 77.27,34.62 77.29,34.62 77.32,34.65 79.11,34.65 79.37,34.9 v2(81.4,34.9) 82.01,34.3 85.44,34.3 85.5,34.36 87.16,34.36 87.42,34.62 87.44,34.62 87.47,34.65 89.26,34.65 89.52,34.9 v2(91.56,34.9)
  BOTTOM w0.076: CPU1.V34 104.39,66.92 104.39,66.4 104.35,66.3 104.35,66.08 104.37,66.05 104.39,65.99 104.39,65.75 104.32,65.57 104.32,64.71 104.31,64.7 104.31,64.39 v2(103.87,63.95)
  BOTTOM w0.14: v2(91.56,34.9) RAM1.M2 ; v2(71.26,34.9) RAM3.M2 ; v2(61.11,34.9) RAM4.M2 ; v2(81.4,34.9) RAM2.M2
M_A_BG1: length 35.2
  L4SGND w0.142: v2(103.67,62.83) 103.22,62.38 103.22,51.43 101.51,49.71 100.44,48.64 100.44,39.48 98.61,37.65 v2(96.29,37.65)
  BOTTOM w0.076: v2(103.67,62.83) 103.67,63.04 104.49,63.85 104.49,64.02 104.48,64.03 104.48,64.63 104.49,64.64 104.49,65.54 104.56,65.75 104.56,65.99 104.52,66.11 104.52,66.12 104.52,66.27 104.56,66.4 104.56,66.41 104.69,66.75 CPU1.W35
  BOTTOM w0.14: R1220.1 96.31,37.65 v2(96.29,37.65)
M_A_BG1_E9_1: length 1.3
  TOP w0.14: R1212.1 54.37,39.93 v2(54.54,40.1)
  BOTTOM w0.14: RAM4.E9 v2(54.54,40.1)
M_A_BG1_E9_2: length 2.1
  TOP w0.14: R1213.1 63.56,39.72 64.31,39.72 v2(64.69,40.1)
  BOTTOM w0.14: RAM3.E9 v2(64.69,40.1)
M_A_BG1_E9_3: length 2.1
  TOP w0.14: R1214.1 83.84,39.74 84.63,39.74 v2(84.99,40.1)
  BOTTOM w0.14: RAM1.E9 v2(84.99,40.1)
M_A_BG1_E9_4: length 2
  TOP w0.14: v2(74.84,40.1) 74.19,40.1 74.02,39.93 R1215.1
  BOTTOM w0.14: RAM2.E9 v2(74.84,40.1)
M_A_BG1_M9_R: length 53.2
  TOP w0.14: v2(52.22,34.36) 52.14,34.44 R1224.1
  L4SGND w0.142: v2(93.99,35.35) 93.99,35.04 93.82,34.87 92.25,34.87 91.75,35.37 91.36,35.37 90.94,34.94 86.64,34.94 86.14,34.45 85.29,34.45 v2(84.97,34.77) 84.5,34.3 82.33,34.3 81.98,34.65 81.98,34.99 81.6,35.37 81.21,35.37 80.79,34.94 76.49,34.94 75.99,34.45 75.14,34.45 v2(74.82,34.77) 74.35,34.3 72.18,34.3 71.83,34.65 71.83,34.99 71.45,35.37 71.06,35.37 70.64,34.94 66.34,34.94 65.84,34.45 64.99,34.45 v2(64.67,34.77) 64.2,34.3 62.03,34.3 61.68,34.65 61.68,34.99 61.3,35.37 60.91,35.37 60.49,34.94 56.19,34.94 55.69,34.45 54.84,34.45 v2(54.52,34.77) 54.46,34.82 52.68,34.82 v2(52.22,34.36)
  BOTTOM w0.14: RAM2.M9 75.12,34.78 74.83,34.78 v2(74.82,34.77) ; R1220.2 R1221.2 95.37,35.71 94.35,35.71 v2(93.99,35.35) ; v2(84.97,34.77) 84.98,34.78 85.27,34.78 RAM1.M9 ; v2(54.52,34.77) 54.53,34.78 54.82,34.78 RAM4.M9 ; RAM3.M9 64.97,34.78 64.68,34.78 v2(64.67,34.77)
M_A_CKE0: length 97.1
  TOP w0.14: RN1207.1 48.91,34.36 v2(49.5,34.95)
  L4SGND w0.142: v2(49.5,34.95) 49.5,35.38 50.43,36.31 55.46,36.31 56.04,35.74 57.45,35.74 57.9,36.19 60.79,36.19 v2(61.1,36.5) 61.21,36.39 64.99,36.39 65.13,36.54 65.13,36.96 65.28,37.1 65.84,37.1 65.98,36.96 65.98,35.97 66.21,35.74 67.34,35.74 67.82,36.21 70.96,36.21 v2(71.25,36.5) 71.42,36.33 75.47,36.33 76.05,35.74 77.49,35.74 77.97,36.21 81.11,36.21 v2(81.4,36.5) 81.57,36.33 85.62,36.33 86.2,35.74 87.64,35.74 88.37,36.47 89.81,36.47 90.19,36.85 91.2,36.85 v2(91.55,36.5) 91.6,36.45 93.33,36.45 93.73,36.84 93.73,42.3 95.35,43.92 95.35,44.12 94.92,44.54 94.92,44.74 95.13,44.94 95.33,44.94 95.75,44.52 95.95,44.52 96.15,44.72 96.15,44.92 95.73,45.34 95.73,45.54 95.93,45.74 96.13,45.74 96.55,45.32 96.75,45.32 97.12,45.69 97.12,46.46 96.98,46.6 95.43,46.6 95.29,46.75 95.29,47.03 95.43,47.17 96.98,47.17 97.12,47.32 97.12,47.6 96.98,47.74 95.43,47.74 95.29,47.88 95.29,48.17 95.43,48.31 96.69,48.31 100.14,51.76 100.14,60.37 100.8,61.03 v2(101.72,61.03)
  BOTTOM w0.076: CPU1.U36 103.48,65.97 103.71,65.75 103.75,65.64 103.75,65.26 103.03,64.54 103.03,63.72 102.66,63.35 102.66,63.01
  BOTTOM w0.14: RAM4.K2 60.96,36.1 61.1,36.24 v2(61.1,36.5) ; v2(81.4,36.5) RAM2.K2 ; v2(91.55,36.5) RAM1.K2 ; v2(101.72,61.03) 101.99,61.03 102.66,61.69 102.66,63.01 ; v2(71.25,36.5) RAM3.K2
M_A_CLK: length 1.5
  TOP w0.254: R1225.2 R1226.2 50.64,38.52 C1256.1
M_A_CLK0: length 87.7
  TOP w0.14: v2(52.22,38.17) 51.79,37.74 R1225.1 ; C1285.1 v2(87.55,36.5)
  L6 w0.089: v2(87.55,36.5) 87,36.06 86.54,36.06 85.08,37.52 78.17,37.52 77.71,37.05 77.7,37.05 v2(77.4,36.5) 76.84,36.05 76.84,36.05 76.45,36.05 74.97,37.53 68.08,37.53 67.51,36.96 v2(67.25,36.5) 66.7,36.06 66.3,36.06 64.75,37.61 57.66,37.61 57.46,37.41 57.46,37.01 57.1,36.66 v2(57.1,36.5) 56.66,36.06 56.12,36.06 54.59,37.58 52.92,37.58 52.34,38.17 v2(52.22,38.17)
  L6 w0.137: v2(87.55,36.5) 87.55,36.66 88.38,37.48 92.72,37.48 93.37,38.13 93.37,39.52 94.96,41.11 94.96,50.64 96.16,51.84 96.16,53.09 98.72,55.64 98.72,56.41 99.58,57.27 99.58,62.4 100.27,63.09 100.27,63.87 104.23,67.83 104.23,68.78 v2(103.52,69.49)
  BOTTOM w0.14: v2(103.52,69.49) 103.81,69.19 CPU1.V31 ; RAM4.K7 v2(57.1,36.5) ; RAM2.K7 v2(77.4,36.5) ; RAM1.K7 v2(87.55,36.5) ; RAM3.K7 v2(67.25,36.5)
M_A_CLK#0: length 86.9
  TOP w0.14: C1285.2 v2(86.75,36.5) ; R1226.1 51.85,38.5 51.97,38.63 52.53,38.63 v2(52.84,38.31)
  L6 w0.089: v2(52.84,38.31) 52.84,37.93 53,37.78 54.67,37.78 55.94,36.5 v2(56.3,36.5) 56.3,36.9 56.4,37 57.17,37 57.27,37.09 57.27,37.49 57.58,37.8 64.83,37.8 66.12,36.5 v2(66.45,36.5) 66.45,36.84 66.59,36.98 67.25,36.98 68,37.72 75.05,37.72 76.27,36.5 v2(76.6,36.5) 76.6,36.84 76.82,37.05 77.43,37.05 78.09,37.71 85.16,37.71 86.37,36.5 v2(86.75,36.5)
  L6 w0.137: v2(103.49,68.83) 103.84,68.83 103.99,68.68 103.99,67.93 100.03,63.97 100.03,63.19 99.34,62.5 99.34,57.37 98.48,56.51 98.48,55.74 95.93,53.19 95.93,52.99 95.93,51.94 94.72,50.74 94.72,41.21 93.13,39.62 93.13,38.23 92.62,37.72 88.28,37.72 87.53,36.98 87.03,36.98 86.75,36.7 v2(86.75,36.5)
  BOTTOM w0.14: v2(66.45,36.5) 66.22,36.5 66.05,36.34 RAM3.K8 ; CPU1.V32 103.78,68.54 v2(103.49,68.83) ; v2(56.3,36.5) 56.04,36.5 55.9,36.37 RAM4.K8 ; RAM1.K8 v2(86.75,36.5) ; RAM2.K8 v2(76.6,36.5)
M_A_CS#0: length 94.9
  TOP w0.14: v2(52.36,36.85) 52.16,36.85 52.08,36.92 RN1202.4
  L2SGND w0.089: v2(88.83,35.7) 89.59,34.94 89.98,34.94 90.44,34.48 91.73,34.48 92.01,34.76 92.01,35.43 92.41,35.83 93.94,35.83 95.57,37.46 95.57,38.19 96.24,38.85 96.91,38.85 100.14,42.08 100.14,53.36 101.84,55.06 101.84,57.2 102.14,57.5 102.48,57.5 102.79,57.82 102.79,62.52 103.54,63.26 103.82,63.26 104.84,64.28 104.84,64.94 105.27,65.37 105.73,65.37 108.07,67.71 v2(108.07,68.31)
  L6 w0.142: v2(52.36,36.85) 53.33,36.85 53.68,36.49 55.16,36.49 55.95,35.7 v2(58.38,35.7) 58.38,35.72 58.82,36.16 59.69,36.16 60.51,36.98 61.3,36.98 61.81,36.47 65.42,36.47 66.19,35.7 v2(68.53,35.7) 68.53,35.72 68.97,36.16 69.84,36.16 70.68,37 71.47,37 72,36.47 75.48,36.47 76.24,35.7 v2(78.68,35.7) 78.68,35.72 79.12,36.16 79.99,36.16 80.83,37 81.62,37 82.16,36.47 85.61,36.47 86.38,35.7 v2(88.83,35.7)
  BOTTOM w0.14: v2(88.83,35.7) 88.43,35.3 RAM1.L7 ; RAM3.L7 68.13,35.3 v2(68.53,35.7) ; CPU1.AE32 v2(108.07,68.31) ; RAM2.L7 78.28,35.3 v2(78.68,35.7) ; v2(58.38,35.7) 57.98,35.3 RAM4.L7
M_A_DQ0: length 59.6
  L4SGND w0.089: v2(55.45,44.38) 55.45,44.58 65.29,54.42 68.39,54.42 69.81,55.85 69.81,56.9 77.87,64.96 77.87,66.24 84.58,72.94 v2(88.49,72.94)
  BOTTOM w0.076: 89.98,72.3 91.76,72.3 92.2,72.75 94.12,72.75 CPU1.A26
  BOTTOM w0.089: RAM4.C2 60.34,42.06 59.74,42.06 58.5,43.3 58.5,43.6 57.72,44.39 56.83,44.39 56.58,44.14 55.69,44.14 v2(55.45,44.38) ; v2(88.49,72.94) 89.14,72.3 89.98,72.3
M_A_DQ1: length 59.6
  L4SGND w0.089: v2(55.5,42.1) 55.03,42.57 55.03,43.1 54.71,43.42 54.71,44.67 65.06,55.02 65.1,55.02 65.11,55.03 67.12,55.03 77.26,65.17 77.26,66.46 84.49,73.7 91.31,73.7 v2(93.01,72.01)
  BOTTOM w0.076: CPU1.D26 96.36,71.67 96.2,71.52 95.39,71.52 95.37,71.52 95.37,71.52 95.18,71.59 94.93,71.59 94.82,71.55 94.64,71.55 94.46,71.61 93.4,71.61 v2(93.01,72.01)
  BOTTOM w0.089: v2(55.5,42.1) RAM4.C8
M_A_DQ2: length 59.9
  L4SGND w0.089: v2(92.79,70.44) 92.24,69.89 89.05,69.89 88.23,69.08 84.16,69.08 80.41,65.33 80.41,62.48 75.05,57.12 75.05,57 75.41,56.64 75.41,56.52 75.28,56.39 75.16,56.39 74.8,56.75 74.68,56.75 74.55,56.62 74.55,56.5 74.91,56.14 74.91,56.01 74.78,55.89 74.65,55.89 74.3,56.24 74.17,56.24 74.05,56.12 74.05,55.99 74.4,55.64 74.4,55.51 74.28,55.38 74.15,55.38 73.79,55.74 73.67,55.74 73.54,55.62 73.54,55.49 73.9,55.13 73.9,55.01 73.77,54.88 73.65,54.88 73.29,55.24 73.17,55.24 69.81,51.88 66.2,51.88 58.74,44.42 58.74,43.61 57.71,42.58 57.49,42.58 56.74,41.83 56.74,41.74 v2(56.31,41.3)
  BOTTOM w0.076: v2(92.79,70.44) 93.3,70.95 93.97,70.95 94.18,70.73 94.56,70.73 94.81,70.87 95.75,70.87 CPU1.D28
  BOTTOM w0.089: v2(56.31,41.3) 56.7,40.91 RAM4.D7
M_A_DQ3: length 59.8
  L4SGND w0.089: v2(56.3,42.1) 57.1,42.89 57.71,42.89 58.41,43.59 58.41,44.54 66.05,52.19 69.7,52.19 78.27,60.75 78.27,60.88 77.57,61.57 77.57,61.7 77.7,61.82 77.82,61.82 78.52,61.13 78.64,61.13 78.77,61.26 78.77,61.38 78.08,62.08 78.08,62.2 78.2,62.33 78.33,62.33 79.02,61.63 79.15,61.63 79.35,61.84 79.35,61.96 79.04,62.28 79.04,62.41 79.16,62.53 79.29,62.53 79.61,62.22 79.73,62.22 80.1,62.59 80.1,65.45 84.03,69.37 88.09,69.37 89.01,70.29 90.13,70.29 v2(90.34,70.5)
  BOTTOM w0.076: CPU1.C28 95.7,71.16 95.6,71.26 95.18,71.41 94.94,71.41 94.9,71.4 94.88,71.38 94.61,71.38 94.43,71.45 93.25,71.45 93.2,71.5
  BOTTOM w0.089: 93.2,71.5 91.33,71.5 v2(90.34,70.5) ; RAM4.C7 v2(56.3,42.1)
M_A_DQ4: length 58
  L4SGND w0.089: v2(89.9,72.96) 88.84,71.9 83.94,71.9 78.18,66.13 78.18,64.87 78.16,64.86 78.16,64.84 70.69,57.36 70.69,57.24 70.97,56.95 70.97,56.83 70.85,56.7 70.72,56.7 70.44,56.99 70.31,56.99 70.11,56.78 70.11,55.73 68.49,54.11 65.4,54.11 56.07,44.78 v2(56.07,44.57)
  BOTTOM w0.076: CPU1.B26 94.85,72.55 94.5,72.73 94.17,72.91 92.13,72.91 91.74,72.52 90.34,72.52 90.31,72.54
  BOTTOM w0.089: v2(89.9,72.96) 90.31,72.54 ; RAM4.A3 58.6,44.6 56.1,44.6 v2(56.07,44.57)
M_A_DQ5: length 58.8
  L4SGND w0.089: v2(55.5,42.9) 55.5,43.13 55.03,43.6 55.03,44.57 65.18,54.73 68.21,54.73 68.64,55.15 68.64,55.28 68.27,55.64 68.27,55.77 68.4,55.9 68.52,55.9 68.89,55.53 69.01,55.53 69.14,55.66 69.14,55.78 68.77,56.15 68.77,56.27 68.98,56.48 69.11,56.48 69.23,56.36 69.36,56.36 69.48,56.48 69.48,56.61 69.36,56.73 69.36,56.86 77.56,65.06 77.56,66.34 84.59,73.37 90.82,73.37 v2(91.28,72.91)
  BOTTOM w0.076: CPU1.C26 95.22,72.78 94.76,72.78 94.21,73.08 91.45,73.08 v2(91.28,72.91)
  BOTTOM w0.089: RAM4.B8 v2(55.5,42.9)
M_A_DQ6: length 58.9
  L4SGND w0.089: v2(92.16,70.44) 92.16,70.71 91.56,71.32 89.62,71.32 89.19,70.88 88.78,70.88 87.85,69.96 83.72,69.96 79.49,65.72 79.49,64.44 75.52,60.47 75.52,60.34 76.03,59.83 76.03,59.7 75.91,59.58 75.78,59.58 75.27,60.09 75.14,60.09 75.02,59.97 75.02,59.84 75.59,59.26 75.59,59.14 75.47,59.01 75.34,59.01 74.76,59.59 74.64,59.59 74.51,59.46 74.51,59.34 75.09,58.76 75.09,58.64 69.26,52.8 65.76,52.8 57.54,44.59 v2(57.54,43.96)
  BOTTOM w0.076: CPU1.B28 95,71.16 94.72,71.01 94.72,71.01 94.52,70.9 94.25,70.9 94.03,71.12 92.84,71.12 92.52,70.8
  BOTTOM w0.089: v2(57.54,43.96) 58.26,43.24 58.26,43.18 59.74,41.7 RAM4.C3 ; v2(92.16,70.44) 92.52,70.8
M_A_DQ7: length 58.6
  L4SGND w0.089: v2(57.54,43.33) 58.09,43.88 58.09,44.69 65.9,52.49 69.6,52.49 76.77,59.66 76.77,59.79 76.07,60.48 76.07,60.61 76.2,60.74 76.32,60.74 77.02,60.04 77.14,60.04 77.27,60.17 77.27,60.29 76.57,60.99 76.57,61.11 76.7,61.24 76.83,61.24 77.27,60.79 77.4,60.79 77.52,60.92 77.52,61.04 77.08,61.49 77.08,61.62 79.8,64.33 79.8,65.62 83.85,69.67 87.97,69.67 88.89,70.59 89.31,70.59 89.63,70.9 91.09,70.9 v2(91.55,70.44)
  BOTTOM w0.076: CPU1.A28 94.28,71.28 92.4,71.28
  BOTTOM w0.089: v2(57.54,43.33) 59.9,40.97 RAM4.D3 ; v2(91.55,70.44) 92.4,71.28
M_A_DQ8: length 55.6
  L4SGND w0.089: v2(57.51,41.04) 57.51,41.37 59.06,42.92 59.06,43.14 66.1,50.17 73.45,50.17 89.01,65.73 89.01,67.62 89.99,68.6 90.39,68.6 90.97,69.18 v2(90.97,69.49)
  BOTTOM w0.076: CPU1.B30 95,70 94.52,70.2 94.2,70.2 93.99,69.99 93.13,69.99 92.99,69.85 92.57,69.85
  BOTTOM w0.089: v2(90.97,69.49) 91.33,69.85 92.57,69.85 ; v2(57.51,41.04) 57.31,40.84 57.31,38.62 56.84,38.15 56.35,38.15 RAM4.H8
M_A_DQ9: length 56.3
  L4SGND w0.089: v2(58.12,39.39) 59.36,39.39 59.73,39.75 59.73,40.15 60.36,40.79 60.36,41.95 62.02,43.6 62.29,43.6 66.26,47.57 70.12,47.57 71.12,48.57 73.93,48.57 91.35,65.99 91.35,67.6 92.08,68.32 v2(92.67,68.32)
  BOTTOM w0.076: CPU1.D30 96.36,69.21 96.16,69.01 95.49,69.01 95.34,69.01 95.33,69.02 95.21,69.06 94.9,69.06 94.83,69.04 94.62,69.04 94.55,69.07 94.52,69.08 93.45,69.08 92.69,68.32 v2(92.67,68.32)
  BOTTOM w0.089: v2(58.12,39.39) 58.04,39.31 58.04,38.24 RAM4.J7
M_A_DQ10: length 54.9
  L4SGND w0.089: v2(92.37,66.57) 92.37,65.37 73.59,46.59 70.17,46.59 70.08,46.5 70.08,46.11 69.99,46.02 69.82,46.02 69.73,46.11 69.73,46.5 69.64,46.59 69.42,46.59 69.33,46.5 69.33,45.67 69.24,45.59 69.07,45.59 68.98,45.67 68.98,46.55 68.89,46.64 68.71,46.64 68.62,46.55 68.62,45.67 68.53,45.59 68.36,45.59 68.27,45.67 68.27,46.55 68.18,46.64 68,46.64 67.91,46.55 67.91,45.67 67.82,45.59 65.79,45.59 63.3,43.09 63.3,41.61 61.86,40.17 60.97,40.17 60.66,39.86 60.66,39.26 v2(60.31,38.9)
  BOTTOM w0.089: v2(92.37,66.57) 93.24,66.57 94.63,67.96 CPU1.B33 ; RAM4.H2 60.31,38.09 v2(60.31,38.9)
M_A_DQ11: length 54.4
  L4SGND w0.089: v2(61.1,38.9) 61.7,38.9 63.61,40.81 63.61,42.99 65.91,45.28 70.37,45.28 70.46,45.37 70.46,46.21 70.55,46.3 70.73,46.3 70.82,46.21 70.82,45.37 70.91,45.28 71.09,45.28 71.17,45.37 71.17,46.21 71.26,46.3 71.44,46.3 71.53,46.21 71.53,45.37 71.62,45.28 71.8,45.28 71.89,45.37 71.89,45.45 71.97,45.53 72.15,45.53 72.24,45.45 72.24,45.37 72.33,45.28 72.71,45.28 92.86,65.43 v2(92.86,67.01)
  BOTTOM w0.076: v2(92.86,67.01) 92.86,67.43 93.19,67.75 94.12,67.75 94.46,68.1 94.46,68.11 94.57,68.21 94.87,68.35 95.76,68.35 CPU1.D32
  BOTTOM w0.089: RAM4.G2 v2(61.1,38.9)
M_A_DQ12: length 54.7
  L4SGND w0.089: v2(91.63,69.45) 91.63,69.15 90.69,68.22 90.02,68.22 89.3,67.49 89.3,65.61 73.57,49.88 66.32,49.88 65.8,49.36 65.8,49.24 65.96,49.07 65.96,48.95 65.84,48.82 65.71,48.82 65.55,48.98 65.42,48.98 61.02,44.59 61.02,43.84 58.52,41.34 v2(58.09,41.34)
  BOTTOM w0.076: CPU1.A30 94.29,69.83 93.2,69.83 92.97,69.6 92.72,69.6
  BOTTOM w0.089: v2(91.63,69.45) 91.78,69.6 92.72,69.6 ; v2(58.09,41.34) 58.09,40.99 57.69,40.6 57.69,38.69 RAM4.H7
M_A_DQ13: length 55.3
  L4SGND w0.089: v2(57.26,41.75) 66.3,50.79 72.04,50.79 72.12,50.7 72.12,50.55 72.21,50.46 72.39,50.46 72.48,50.55 72.48,50.7 72.57,50.79 72.75,50.79 72.84,50.7 72.84,50.55 72.92,50.46 73.1,50.46 73.19,50.55 73.19,50.7 73.28,50.79 73.66,50.79 88.72,65.85 88.72,67.93 v2(90.27,69.48)
  BOTTOM w0.076: CPU1.C30 95.56,69.94 95.21,70.3 94.71,70.3 94.56,70.36 94.13,70.36 93.93,70.16 93.06,70.16 92.94,70.03 92.8,70.03
  BOTTOM w0.089: RAM4.F7 57.08,39.68 57.08,41.56 v2(57.26,41.75) ; 92.8,70.03 90.82,70.03 v2(90.27,69.48)
M_A_DQ14: length 53.9
  L4SGND w0.089: v2(58.53,38.85) 59.25,38.85 60.23,39.84 60.23,40.04 60.8,40.6 61.01,40.6 61.53,41.13 61.53,41.41 61.87,41.75 62.04,41.75 62.64,42.35 62.64,43.26 66.61,47.22 70.26,47.22 71.31,48.28 72.59,48.28 72.68,48.19 72.68,47.73 72.77,47.64 72.95,47.64 73.04,47.73 73.04,48.11 73.2,48.28 74.05,48.28 91.61,65.83 91.61,67 v2(91.76,67.16)
  BOTTOM w0.076: CPU1.B32 95.04,68.65 94.77,68.49 94.49,68.36 94.47,68.35 94.3,68.18 94.3,68.17 94.05,67.92 92.83,67.92 92.07,67.16 v2(91.76,67.16)
  BOTTOM w0.089: v2(58.53,38.85) 58.53,38.27 RAM4.J3
M_A_DQ15: length 53.6
  L4SGND w0.089: v2(93.29,68.34) 93.29,68.12 91.86,66.69 91.86,65.3 73.49,46.93 67.55,46.93 67.46,46.84 67.46,46.31 67.38,46.22 67.2,46.22 67.11,46.31 67.11,46.84 67.02,46.93 66.73,46.93 62.99,43.2 62.99,41.67 61.71,40.39 60.89,40.39 60.45,39.95 60.45,39.65 v2(59.12,38.32)
  BOTTOM w0.076: CPU1.C32 95.43,68.8 95.24,68.87 95.24,68.88 95.18,68.9 94.93,68.9 94.87,68.88 94.86,68.87 94.85,68.86 94.6,68.86 94.57,68.88 94.57,68.88 94.49,68.91 93.87,68.91 v2(93.29,68.34)
  BOTTOM w0.089: RAM4.H3 59.74,37.7 v2(59.12,38.32)
M_A_DQ16: length 58.5
  L6 w0.089: v2(68.34,40.47) 68.34,41.09 69.3,42.06 70.07,42.06 70.49,42.47 70.49,43.52 70.23,43.77 70.23,44.22 81.15,55.14 81.15,66.3 86.73,71.87 91.83,71.87 92.83,72.87 93.33,72.87 93.36,72.9 93.67,72.9 94.82,74.06 96.13,74.06 96.14,74.06 96.79,74.06 97.17,73.68 98.92,73.68 99.28,74.03 v2(99.28,74.31)
  BOTTOM w0.089: RAM3.J7 67.88,37.93 67.88,39.03 68.34,39.49 v2(68.34,40.47) ; CPU1.J22 v2(99.28,74.31)
M_A_DQ17: length 60.6
  L6 w0.089: v2(98.59,72.31) 98.19,71.91 95.84,71.91 93.76,69.83 92.96,69.83 91.82,68.69 89.99,68.69 88.81,67.51 88.81,65.27 82.98,59.44 82.98,53.14 82.83,52.99 82.7,52.99 82.23,53.46 82.11,53.46 81.98,53.33 81.98,53.21 82.48,52.71 82.48,52.58 82.29,52.4 82.16,52.4 81.66,52.9 81.53,52.9 81.4,52.78 81.4,52.65 81.91,52.15 81.91,52.02 81.79,51.89 81.66,51.89 81.15,52.4 81.03,52.4 80.9,52.27 80.9,52.15 81.41,51.64 81.41,51.52 81.28,51.39 81.16,51.39 80.65,51.9 80.53,51.9 80.4,51.77 80.4,51.65 80.91,51.14 80.91,51.01 80.78,50.89 80.65,50.89 80.15,51.39 80.02,51.39 79.9,51.27 79.9,51.14 80.4,50.64 80.4,50.51 80.28,50.39 80.15,50.39 79.64,50.89 79.52,50.89 79.39,50.77 79.39,50.64 79.9,50.13 79.9,50.01 79.77,49.88 79.65,49.88 79.14,50.39 79.02,50.39 78.89,50.26 78.89,50.14 79.4,49.63 79.4,49.51 73.08,43.19 73.08,41.28 72.02,40.21 71.17,40.21 70.46,39.5 v2(70.46,38.9)
  BOTTOM w0.089: v2(70.46,38.9) 70.85,38.51 RAM3.G2 ; CPU1.H25 v2(98.59,72.31)
M_A_DQ18: length 57.8
  L6 w0.089: v2(67.67,41.04) 67.67,41.4 67.84,41.57 67.84,41.82 69.54,43.52 69.54,44.73 72.71,47.9 72.71,48.8 72.92,49.01 73.04,49.01 73.3,48.74 73.43,48.74 73.55,48.87 73.55,49 73.29,49.26 73.29,49.38 80.57,56.66 80.57,66.58 86.45,72.46 91.78,72.46 92.55,73.22 93.18,73.22 94.37,74.41 96.28,74.41 96.43,74.41 96.63,74.62 97.47,74.62 v2(97.96,74.14)
  BOTTOM w0.089: RAM3.H8 66.05,37.78 66.33,38.06 66.92,38.06 67.34,38.48 67.34,39.33 67.61,39.59 67.61,40.98 v2(67.67,41.04) ; CPU1.G22 v2(97.96,74.14)
M_A_DQ19: length 57.3
  L6 w0.089: v2(67.41,41.75) 67.46,41.75 69.25,43.53 69.25,45.86 69.46,46.07 69.58,46.07 69.8,45.85 69.92,45.85 70.05,45.97 70.05,46.1 69.83,46.32 69.83,46.44 69.96,46.57 70.08,46.57 70.33,46.33 70.45,46.33 70.58,46.45 70.58,46.58 70.33,46.82 70.33,46.95 80.28,56.89 80.28,66.72 86.45,72.89 87.62,72.89 88.13,73.4 93.1,73.4 94.3,74.59 96.36,74.59 96.58,74.82 97.93,74.82 v2(98.59,74.16)
  BOTTOM w0.089: RAM3.F7 67.22,39.67 67.22,41.56 v2(67.41,41.75) ; CPU1.H22 v2(98.59,74.16)
M_A_DQ20: length 60.9
  L6 w0.089: v2(97.32,73.22) 97.27,73.22 96.86,73.63 95.16,73.63 94.65,73.12 94.14,73.12 93.74,72.73 93.44,72.73 93.4,72.69 92.93,72.69 91.89,71.65 89.9,71.65 89.14,70.89 88.5,70.89 88.41,70.8 88.41,70.36 88.32,70.27 88.14,70.27 88.05,70.36 88.05,70.8 87.96,70.89 87.79,70.89 87.7,70.8 87.7,69.86 87.61,69.77 87.43,69.77 87.34,69.86 87.34,70.8 87.25,70.89 87.08,70.89 86.99,70.8 86.99,69.86 86.9,69.77 86.72,69.77 86.63,69.86 86.63,70.8 86.54,70.89 86.25,70.89 81.45,66.08 81.45,54.96 71.08,44.6 71.08,42.5 70.24,41.65 69.3,41.65 68.76,41.11 68.76,40.27 68.11,39.62 68.11,38.75 v2(68.42,38.45)
  BOTTOM w0.089: v2(68.42,38.45) 68.5,38.45 RAM3.J3 ; v2(97.32,73.22) CPU1.F25
M_A_DQ21: length 59.2
  L6 w0.089: v2(71.25,38.9) 71.85,38.9 73.39,40.44 73.39,43.08 74.22,43.91 74.34,43.91 74.45,43.81 74.58,43.81 74.7,43.93 74.7,44.06 74.6,44.17 74.6,44.29 74.72,44.42 74.85,44.42 74.96,44.31 75.08,44.31 75.21,44.43 75.21,44.56 75.1,44.67 75.1,44.79 75.22,44.92 75.35,44.92 75.46,44.81 75.58,44.81 75.71,44.94 75.71,45.06 75.6,45.17 75.6,45.3 75.73,45.42 75.85,45.42 75.96,45.31 76.09,45.31 76.21,45.44 76.21,45.57 76.1,45.67 76.1,45.8 76.31,46.01 76.44,46.01 76.61,45.83 76.74,45.83 76.86,45.96 76.86,46.08 76.69,46.26 76.69,46.38 76.81,46.51 76.94,46.51 77.12,46.33 77.24,46.33 77.37,46.46 77.37,46.59 77.19,46.76 77.19,46.89 77.32,47.01 77.44,47.01 77.62,46.84 77.74,46.84 77.87,46.96 77.87,47.09 77.69,47.26 77.69,47.39 77.82,47.52 77.95,47.52 78.12,47.34 78.25,47.34 78.37,47.47 78.37,47.59 78.2,47.77 78.2,47.89 78.32,48.02 78.45,48.02 78.62,47.84 78.75,47.84 78.88,47.97 78.88,48.09 78.7,48.27 78.7,48.4 78.83,48.52 78.95,48.52 79.13,48.35 79.25,48.35 79.38,48.47 79.38,48.6 79.2,48.77 79.2,48.9 79.33,49.02 79.45,49.02 79.63,48.85 79.76,48.85 79.88,48.97 79.88,49.1 79.71,49.28 79.71,49.4 79.83,49.53 79.96,49.53 80.13,49.35 80.26,49.35 80.38,49.48 80.38,49.6 80.21,49.78 80.21,49.9 80.34,50.03 80.46,50.03 80.64,49.85 80.76,49.85 80.89,49.98 80.89,50.11 80.71,50.28 80.71,50.41 80.84,50.53 80.96,50.53 81.14,50.36 81.26,50.36 81.39,50.48 81.39,50.61 81.21,50.78 81.21,50.91 81.34,51.04 81.47,51.04 81.64,50.86 81.77,50.86 81.89,50.99 81.89,51.11 81.72,51.29 81.72,51.41 83.29,52.98 83.29,59.32 89.12,65.15 89.12,67.4 90.19,68.47 91.86,68.47 93,69.61 93.8,69.61 95.88,71.7 98.67,71.7 v2(99.25,72.28)
  BOTTOM w0.089: RAM3.H2 71.25,38.1 v2(71.25,38.9) ; CPU1.J25 v2(99.25,72.28)
M_A_DQ22: length 58
  L6 w0.089: v2(97.93,72.31) 95.97,72.31 93.71,70.04 92.79,70.04 91.73,68.98 89.87,68.98 88.48,67.59 88.48,65.37 82.68,59.57 82.68,54.46 78.41,50.2 78.41,50.07 78.92,49.57 78.92,49.44 78.79,49.31 78.67,49.31 78.16,49.82 78.03,49.82 77.83,49.61 77.83,49.49 78.33,48.98 78.33,48.86 78.21,48.73 78.08,48.73 77.58,49.24 77.45,49.24 77.24,49.03 77.24,48.9 77.74,48.41 77.74,48.28 77.61,48.15 77.49,48.15 76.99,48.65 76.87,48.65 76.74,48.53 76.74,48.4 77.24,47.9 77.24,47.78 77.11,47.65 76.99,47.65 76.49,48.15 76.36,48.15 76.24,48.02 76.24,47.9 76.73,47.4 76.73,47.27 76.28,46.82 76.16,46.82 75.95,47.03 75.82,47.03 75.7,46.91 75.7,46.78 75.91,46.57 75.91,46.45 72.78,43.32 72.78,41.28 72,40.51 71.15,40.51 69.36,38.71 v2(69.36,38.25)
  BOTTOM w0.089: CPU1.G25 v2(97.93,72.31) ; RAM3.H3 69.51,38.25 v2(69.36,38.25)
M_A_DQ23: length 57.8
  L6 w0.089: v2(68.26,41.62) 69,42.36 69.79,42.36 70.14,42.72 70.14,43.45 69.94,43.65 69.94,44.34 75.38,49.78 75.38,49.91 75.07,50.21 75.07,50.34 75.2,50.47 75.33,50.47 75.63,50.16 75.76,50.16 75.88,50.29 75.88,50.41 75.54,50.75 75.54,50.88 75.67,51.01 75.79,51.01 76.13,50.66 76.26,50.66 80.86,55.26 80.86,66.44 86.59,72.17 91.8,72.17 92.67,73.04 93.25,73.04 94.45,74.24 96.21,74.24 96.86,74.24 96.89,74.21 v2(97.27,74.21)
  BOTTOM w0.089: v2(68.26,41.62) 68.11,41.47 68.11,40.87 67.9,40.65 67.9,39.49 67.6,39.19 67.6,38.17 67.13,37.7 RAM3.H7 ; CPU1.F22 v2(97.27,74.21)
M_A_DQ24: length 58.1
  L6 w0.089: v2(93.29,75.96) 91.8,77.44 86.03,77.44 76.65,68.05 76.65,62.39 73.5,59.24 73.5,57.85 67.41,51.76 67.41,51.63 67.53,51.51 67.53,51.38 67.41,51.26 67.28,51.26 67.16,51.38 67.03,51.38 66.9,51.25 66.9,51.13 67.08,50.95 67.08,50.83 66.95,50.7 66.83,50.7 66.65,50.88 66.53,50.88 66.4,50.75 66.4,50.63 66.6,50.43 66.6,50.31 66.47,50.18 66.34,50.18 66.15,50.37 66.02,50.37 65.6,49.95 65.6,47.32 64.89,46.6 64.89,43.38 65.17,43.09 65.17,42.58 v2(65.65,42.1)
  BOTTOM w0.076: CPU1.D22 95.7,75.29 95.7,75.3 94.76,75.3 94.57,75.4 93.84,75.4 93.58,75.66
  BOTTOM w0.089: v2(93.29,75.96) 93.58,75.66 ; RAM3.C8 v2(65.65,42.1)
M_A_DQ25: length 58.2
  L6 w0.089: v2(66.22,44.57) 66.52,44.87 66.52,48.36 68.61,50.45 68.61,50.58 68.43,50.76 68.43,50.88 68.56,51.01 68.68,51.01 68.86,50.83 68.99,50.83 69.11,50.96 69.11,51.08 68.93,51.26 68.93,51.39 69.06,51.51 69.18,51.51 69.36,51.33 69.49,51.33 69.61,51.46 69.61,51.58 69.44,51.76 69.44,51.89 69.56,52.01 69.69,52.01 69.87,51.84 69.99,51.84 70.12,51.96 70.12,52.09 69.94,52.27 69.94,52.39 70.06,52.52 70.19,52.52 70.37,52.34 70.49,52.34 70.62,52.46 70.62,52.59 70.44,52.77 70.44,52.89 70.57,53.02 70.69,53.02 70.87,52.84 71,52.84 71.12,52.97 71.12,53.09 70.94,53.27 70.94,53.4 74.37,56.83 74.37,58.88 77.56,62.06 77.56,67.72 86.19,76.35 90.84,76.35 v2(91.27,75.93)
  BOTTOM w0.076: CPU1.C22 95.45,74.82 95.34,74.78 95.33,74.78 95.17,74.72 94.94,74.72 94.88,74.75 94.58,74.75 94.52,74.72 93.49,74.72 93.02,75.19 92.96,75.19
  BOTTOM w0.089: RAM3.A3 68.68,44.67 66.32,44.67 v2(66.22,44.57) ; 92.96,75.19 92,75.19 v2(91.27,75.93)
M_A_DQ26: length 57.9
  L6 w0.089: v2(87.41,74.63) 86.83,74.06 86.02,74.06 79.11,67.15 79.11,61.49 75.96,58.34 75.96,54.42 70.59,49.05 70.47,49.05 70.09,49.42 69.97,49.42 69.84,49.3 69.84,49.17 70.21,48.8 70.21,48.67 70.09,48.54 69.96,48.54 69.5,49.01 69.38,49.01 69.25,48.88 69.25,48.76 69.71,48.29 69.71,48.17 69.59,48.04 69.46,48.04 69,48.5 68.87,48.5 68.75,48.38 68.75,48.25 69.21,47.79 69.21,47.67 69.08,47.54 68.96,47.54 68.49,48 68.37,48 68.24,47.88 68.24,47.75 68.71,47.29 68.71,47.16 68.13,46.59 68.13,43.76 v2(67.69,43.33)
  BOTTOM w0.076: CPU1.C24 95.25,73.38 94.8,73.38 94.57,73.26 91.65,73.26 91.54,73.37
  BOTTOM w0.089: 91.54,73.37 88.67,73.37 v2(87.41,74.63) ; RAM3.D3 67.69,43.26 v2(67.69,43.33)
M_A_DQ27: length 58.6
  L6 w0.089: v2(86.77,74.63) 86.17,74.63 78.81,67.27 78.81,61.61 75.58,58.38 75.58,54.45 72.27,51.14 72.15,51.14 71.75,51.54 71.63,51.54 71.5,51.41 71.5,51.29 71.9,50.89 71.9,50.77 71.77,50.64 71.64,50.64 71.16,51.13 71.03,51.13 70.91,51 70.91,50.87 71.39,50.39 71.39,50.26 71.27,50.14 71.14,50.14 70.66,50.62 70.53,50.62 70.41,50.5 70.41,50.37 70.89,49.89 70.89,49.76 70.76,49.63 70.64,49.63 70.15,50.12 70.03,50.12 67.83,47.92 67.83,44.63 67.69,44.5 v2(67.69,43.96)
  BOTTOM w0.076: 92.97,74.99 93.41,74.55 94.52,74.55 94.61,74.58 94.85,74.58 94.94,74.55 95.17,74.55 95.33,74.61 95.44,74.61 96.16,74.61 96.36,74.42 CPU1.D24
  BOTTOM w0.089: v2(86.77,74.63) 87.2,75.06 91.88,75.06 91.94,75 92.96,75 92.97,74.99 ; v2(67.69,43.96) 68.81,42.84 68.81,42.59 69.7,41.7 RAM3.C3
M_A_DQ28: length 57.2
  L6 w0.089: v2(65.6,44.38) 65.6,46.46 66.22,47.08 66.22,48.56 68.01,50.34 68.01,50.87 74.08,56.95 74.08,59 77.26,62.17 77.26,67.83 86.28,76.85 91.07,76.85 v2(92,75.92)
  BOTTOM w0.076: CPU1.A22 93.47,74.98 93.06,75.38 92.54,75.38 v2(92,75.92)
  BOTTOM w0.089: RAM3.C2 70.49,42.06 69.64,42.06 69.1,42.6 69.1,43.78 68.43,44.46 66.7,44.46 66.39,44.14 65.84,44.14 v2(65.6,44.38)
M_A_DQ29: length 57
  L6 w0.089: v2(65.65,42.9) 65.65,43.1 65.18,43.57 65.18,46.46 65.91,47.19 65.91,49.2 71.15,54.44 71.15,54.57 70.96,54.76 70.96,54.88 71.09,55.01 71.21,55.01 71.4,54.82 71.52,54.82 71.65,54.95 71.65,55.07 71.46,55.26 71.46,55.38 71.59,55.51 71.72,55.51 71.9,55.32 72.03,55.32 72.15,55.45 72.15,55.57 71.97,55.76 71.97,55.89 72.09,56.01 72.22,56.01 72.4,55.83 72.53,55.83 72.66,55.95 72.66,56.08 72.47,56.26 72.47,56.39 72.6,56.52 72.72,56.52 72.91,56.33 73.03,56.33 73.16,56.45 73.16,56.58 72.97,56.77 72.97,56.89 73.1,57.02 73.22,57.02 73.41,56.83 73.54,56.83 73.66,56.96 73.66,57.08 73.48,57.27 73.48,57.4 73.79,57.71 73.79,59.12 76.95,62.28 76.95,67.94 86.15,77.15 91.39,77.15 v2(92.61,75.93)
  BOTTOM w0.076: CPU1.B22 94.78,75.1 94.53,75.24 93.49,75.24 93.23,75.49
  BOTTOM w0.089: RAM3.B8 v2(65.65,42.9) ; 93.23,75.49 93.14,75.58 92.96,75.58 v2(92.61,75.93)
M_A_DQ30: length 56.7
  L6 w0.089: v2(90.2,74.57) 89.54,73.91 87.71,73.91 87.18,73.39 86.17,73.39 79.69,66.91 79.69,60.23 79.6,60.14 78.84,60.14 78.75,60.05 78.75,59.87 78.84,59.78 79.6,59.78 79.69,59.69 79.69,59.52 79.6,59.43 78.77,59.43 78.68,59.34 78.68,59.16 78.77,59.07 79.6,59.07 79.69,58.98 79.69,58.81 79.6,58.72 78.87,58.72 78.78,58.63 78.78,58.45 78.87,58.36 79.6,58.36 79.69,58.27 79.69,58.09 79.6,58.01 78.89,58.01 78.8,57.92 78.8,57.74 78.89,57.65 79.6,57.65 79.69,57.56 79.69,57.24 68.74,46.29 68.74,43.47 67.62,42.35 67.41,42.35 66.92,41.86 66.92,41.76 v2(66.46,41.3)
  BOTTOM w0.076: CPU1.A24 94.38,73.69 91.81,73.69 91.69,73.8
  BOTTOM w0.089: v2(90.2,74.57) 90.68,74.09 91.41,74.09 91.69,73.8 ; RAM3.D7 66.85,40.91 v2(66.46,41.3)
M_A_DQ31: length 57.9
  L6 w0.089: v2(88.69,74.57) 88.32,74.2 87.59,74.2 87.06,73.68 86.05,73.68 79.4,67.03 79.4,61.36 78.37,60.34 78.37,59.41 78.28,59.32 77.8,59.32 77.71,59.23 77.71,59.05 77.8,58.97 78.28,58.97 78.37,58.88 78.37,58.58 78.28,58.5 77.32,58.5 77.23,58.41 77.23,58.23 77.32,58.14 78.28,58.14 78.37,58.05 78.37,57.87 78.28,57.78 77.32,57.78 77.23,57.7 77.23,57.52 77.32,57.43 78.28,57.43 78.37,57.34 78.37,57.16 78.28,57.07 77.32,57.07 77.23,56.98 77.23,56.81 77.32,56.72 78.28,56.72 78.37,56.63 78.37,56.34 68.42,46.39 68.42,43.45 67.61,42.64 67,42.64 v2(66.46,42.1)
  BOTTOM w0.076: 91.62,73.54 91.64,73.52 94.16,73.52 94.26,73.42 94.53,73.42 94.58,73.45 94.83,73.58 CPU1.B24
  BOTTOM w0.089: v2(88.69,74.57) 89.46,73.79 91.37,73.79 91.62,73.54 ; RAM3.C7 v2(66.46,42.1)
M_A_DQ32: length 40.6
  L4SGND w0.089: v2(91.81,58.63) 88.33,58.63 75.75,46.05 v2(75.75,44.38)
  BOTTOM w0.076: 97.28,64.34 98.1,65.15 98.15,65.24 CPU1.H37
  BOTTOM w0.089: 97.28,64.34 96.9,63.95 94.84,63.95 92.85,61.97 92.85,59.67 v2(91.81,58.63) ; v2(75.75,44.38) 76,44.13 76.42,44.13 76.42,44.13 77.4,44.13 77.65,44.39 78.03,44.39 78.8,43.62 78.8,43.28 80.02,42.06 80.64,42.06 RAM2.C2
M_A_DQ33: length 41.1
  L4SGND w0.089: v2(91.81,61.17) 91.19,61.17 91.09,61.08 91.09,60.28 91.01,60.19 90.83,60.19 90.74,60.28 90.74,61.08 90.65,61.17 90,61.17 89.73,60.9 89.73,60.72 89.96,60.49 89.96,60.37 89.85,60.27 89.73,60.27 89.48,60.52 89.35,60.52 75.01,46.18 75.01,43.48 75.33,43.16 75.33,42.21 75.44,42.1 v2(75.8,42.1)
  BOTTOM w0.076: CPU1.H34 98.17,66.92 98.17,65.97 97.99,65.64 97.1,64.75
  BOTTOM w0.089: RAM2.C8 v2(75.8,42.1) ; 97.1,64.75 96.83,64.48 94.5,64.48 91.99,61.97 91.81,61.79 v2(91.81,61.17)
M_A_DQ34: length 43.1
  L4SGND w0.089: v2(94.67,59.71) 93.79,58.83 93.79,57.35 91.89,55.44 91.85,55.44 91.82,55.41 88.11,55.41 88.02,55.32 88.02,54.56 87.93,54.48 87.75,54.48 87.66,54.56 87.66,55.32 87.57,55.41 87.28,55.41 77.92,46.05 77.92,44.02 v2(77.86,43.96)
  BOTTOM w0.076: CPU1.K34 99.02,67.5 98.78,67.26 98.78,66.58 98.81,66.52 98.81,66.52 98.88,66.32 98.88,66.08 98.84,65.96 98.84,65.78 98.88,65.67 98.88,65.24 98.44,64.8
  BOTTOM w0.089: 98.44,64.8 97.08,63.43 95.15,63.43 93.62,61.91 93.62,60.23 94.14,59.71 v2(94.67,59.71) ; RAM2.C3 80.04,41.7 78.56,43.18 78.56,43.26 v2(77.86,43.96)
M_A_DQ35: length 42.1
  L4SGND w0.089: v2(94.67,55.9) 93.58,55.9 90.05,52.37 89.76,52.37 89.67,52.46 89.67,53.31 89.58,53.4 89.4,53.4 89.32,53.31 89.32,52.46 89.23,52.37 85.48,52.37 78.93,45.82 78.93,43.49 78.02,42.58 77.79,42.58 77.04,41.83 77.04,41.74 v2(76.61,41.3)
  BOTTOM w0.076: 98.69,63.32 99.14,63.32 100,64.18 100,65.15 100.18,65.32 100.18,65.69 100.04,65.94 100.04,66.55 CPU1.K35
  BOTTOM w0.089: v2(76.61,41.3) 77,40.91 RAM2.D7 ; v2(94.67,55.9) 95.1,55.9 95.71,56.51 95.71,60.71 97.02,62.01 97.39,62.01 98.69,63.32
M_A_DQ36: length 40.4
  L4SGND w0.089: v2(75.8,42.9) 75.8,43.13 75.32,43.61 75.32,46.05 88.44,59.17 88.64,59.17 88.73,59.09 88.85,59.09 88.98,59.21 88.98,59.34 88.89,59.42 88.89,59.63 89.17,59.9 89.84,59.9 89.93,59.81 89.93,59.11 90.02,59.02 90.2,59.02 90.28,59.11 90.28,59.81 90.37,59.9 90.55,59.9 90.64,59.81 90.64,59.01 90.73,58.92 90.91,58.92 91,59.01 91,59.81 91.08,59.9 v2(91.81,59.9)
  BOTTOM w0.076: 97.19,64.55 98.05,65.41 98.45,66.14 CPU1.H36
  BOTTOM w0.089: v2(91.81,59.9) 92.31,59.9 92.4,59.99 92.4,61.92 94.69,64.21 96.86,64.21 97.19,64.55 ; RAM2.B8 v2(75.8,42.9)
M_A_DQ37: length 42
  L4SGND w0.089: v2(91.81,57.36) 91.32,57.85 89.75,57.85 89.66,57.76 89.66,57.54 89.57,57.45 89.4,57.45 89.31,57.54 89.31,57.76 89.22,57.85 89.04,57.85 88.95,57.76 88.95,57.54 88.86,57.45 88.69,57.45 88.6,57.54 88.6,57.76 88.51,57.85 87.99,57.85 76.37,46.23 v2(76.37,44.57)
  BOTTOM w0.076: CPU1.H35 98.55,66.75 98.64,66.49 98.64,66.49 98.71,66.29 98.71,66.1 98.67,65.99 98.67,65.75 98.71,65.64 98.71,65.4 97.52,64.2
  BOTTOM w0.089: RAM2.A3 78.73,44.77 76.57,44.77 v2(76.37,44.57) ; 97.52,64.2 97.04,63.72 95.02,63.72 93.34,62.04 93.34,57.91 92.79,57.36 v2(91.81,57.36)
M_A_DQ38: length 41.6
  L4SGND w0.089: v2(94.67,57.17) 94.44,57.17 90.96,53.69 87.92,53.69 87.83,53.6 87.83,52.81 87.75,52.72 87.57,52.72 87.48,52.81 87.48,53.6 87.39,53.69 87.21,53.69 87.12,53.6 87.12,52.81 87.03,52.72 86.86,52.72 86.77,52.81 86.77,53.6 86.68,53.69 86.39,53.69 78.6,45.9 78.6,43.47 78.02,42.89 77.4,42.89 v2(76.6,42.1)
  BOTTOM w0.076: 98.68,63.57 99.15,63.57 99.84,64.25 99.84,65.21 100.02,65.39 100.02,65.64 99.75,66.13 CPU1.K36
  BOTTOM w0.089: RAM2.C7 v2(76.6,42.1) ; v2(94.67,57.17) 95.42,57.92 95.42,60.82 96.84,62.24 97.36,62.24 98.68,63.57
M_A_DQ39: length 40.7
  L4SGND w0.089: v2(94.67,58.44) 94.15,57.92 94.15,57.29 90.88,54.02 89.81,54.02 89.73,54.11 89.73,54.72 89.64,54.81 89.46,54.81 89.37,54.72 89.37,54.11 89.28,54.02 89.1,54.02 89.01,54.11 89.01,54.72 88.93,54.81 88.75,54.81 88.66,54.72 88.66,54.11 88.57,54.02 86.3,54.02 78.29,46.01 78.29,43.76 v2(77.86,43.33)
  BOTTOM w0.076: 98.52,63.74 98.6,63.82 99.13,63.82 99.66,64.35 99.66,65.45 CPU1.K37
  BOTTOM w0.089: v2(94.67,58.44) 95.11,58.88 95.11,60.83 96.75,62.47 97.25,62.47 98.52,63.74 ; RAM2.D3 80.2,40.98 v2(77.86,43.33)
M_A_DQ40: length 44.3
  L4SGND w0.089: v2(77.81,41.04) 77.81,41.38 79.36,42.93 79.36,43.09 79.8,43.53 79.8,44.74 84.49,49.43 86.66,49.43 86.75,49.52 86.75,49.79 86.84,49.88 87.02,49.88 87.11,49.79 87.11,49.52 87.19,49.43 87.49,49.43 87.58,49.52 87.58,49.94 87.66,50.03 87.84,50.03 87.93,49.94 87.93,49.52 88.02,49.43 88.2,49.43 88.29,49.52 88.29,49.94 88.38,50.03 89.1,50.03 93.54,54.48 93.57,54.49 94.27,54.49 95.52,55.74 95.52,57.89 v2(96.26,58.63)
  BOTTOM w0.076: CPU1.N36 100.97,66.14 100.64,65.53 100.64,64.22 100.19,63.78 100.19,63.52
  BOTTOM w0.089: RAM2.H8 76.36,37.7 76.72,38.06 77.25,38.06 77.76,38.57 77.76,40.98 v2(77.81,41.04) ; 100.19,63.52 99.17,62.5 98.7,62.5 96.69,60.49 96.69,58.72 96.6,58.63 v2(96.26,58.63)
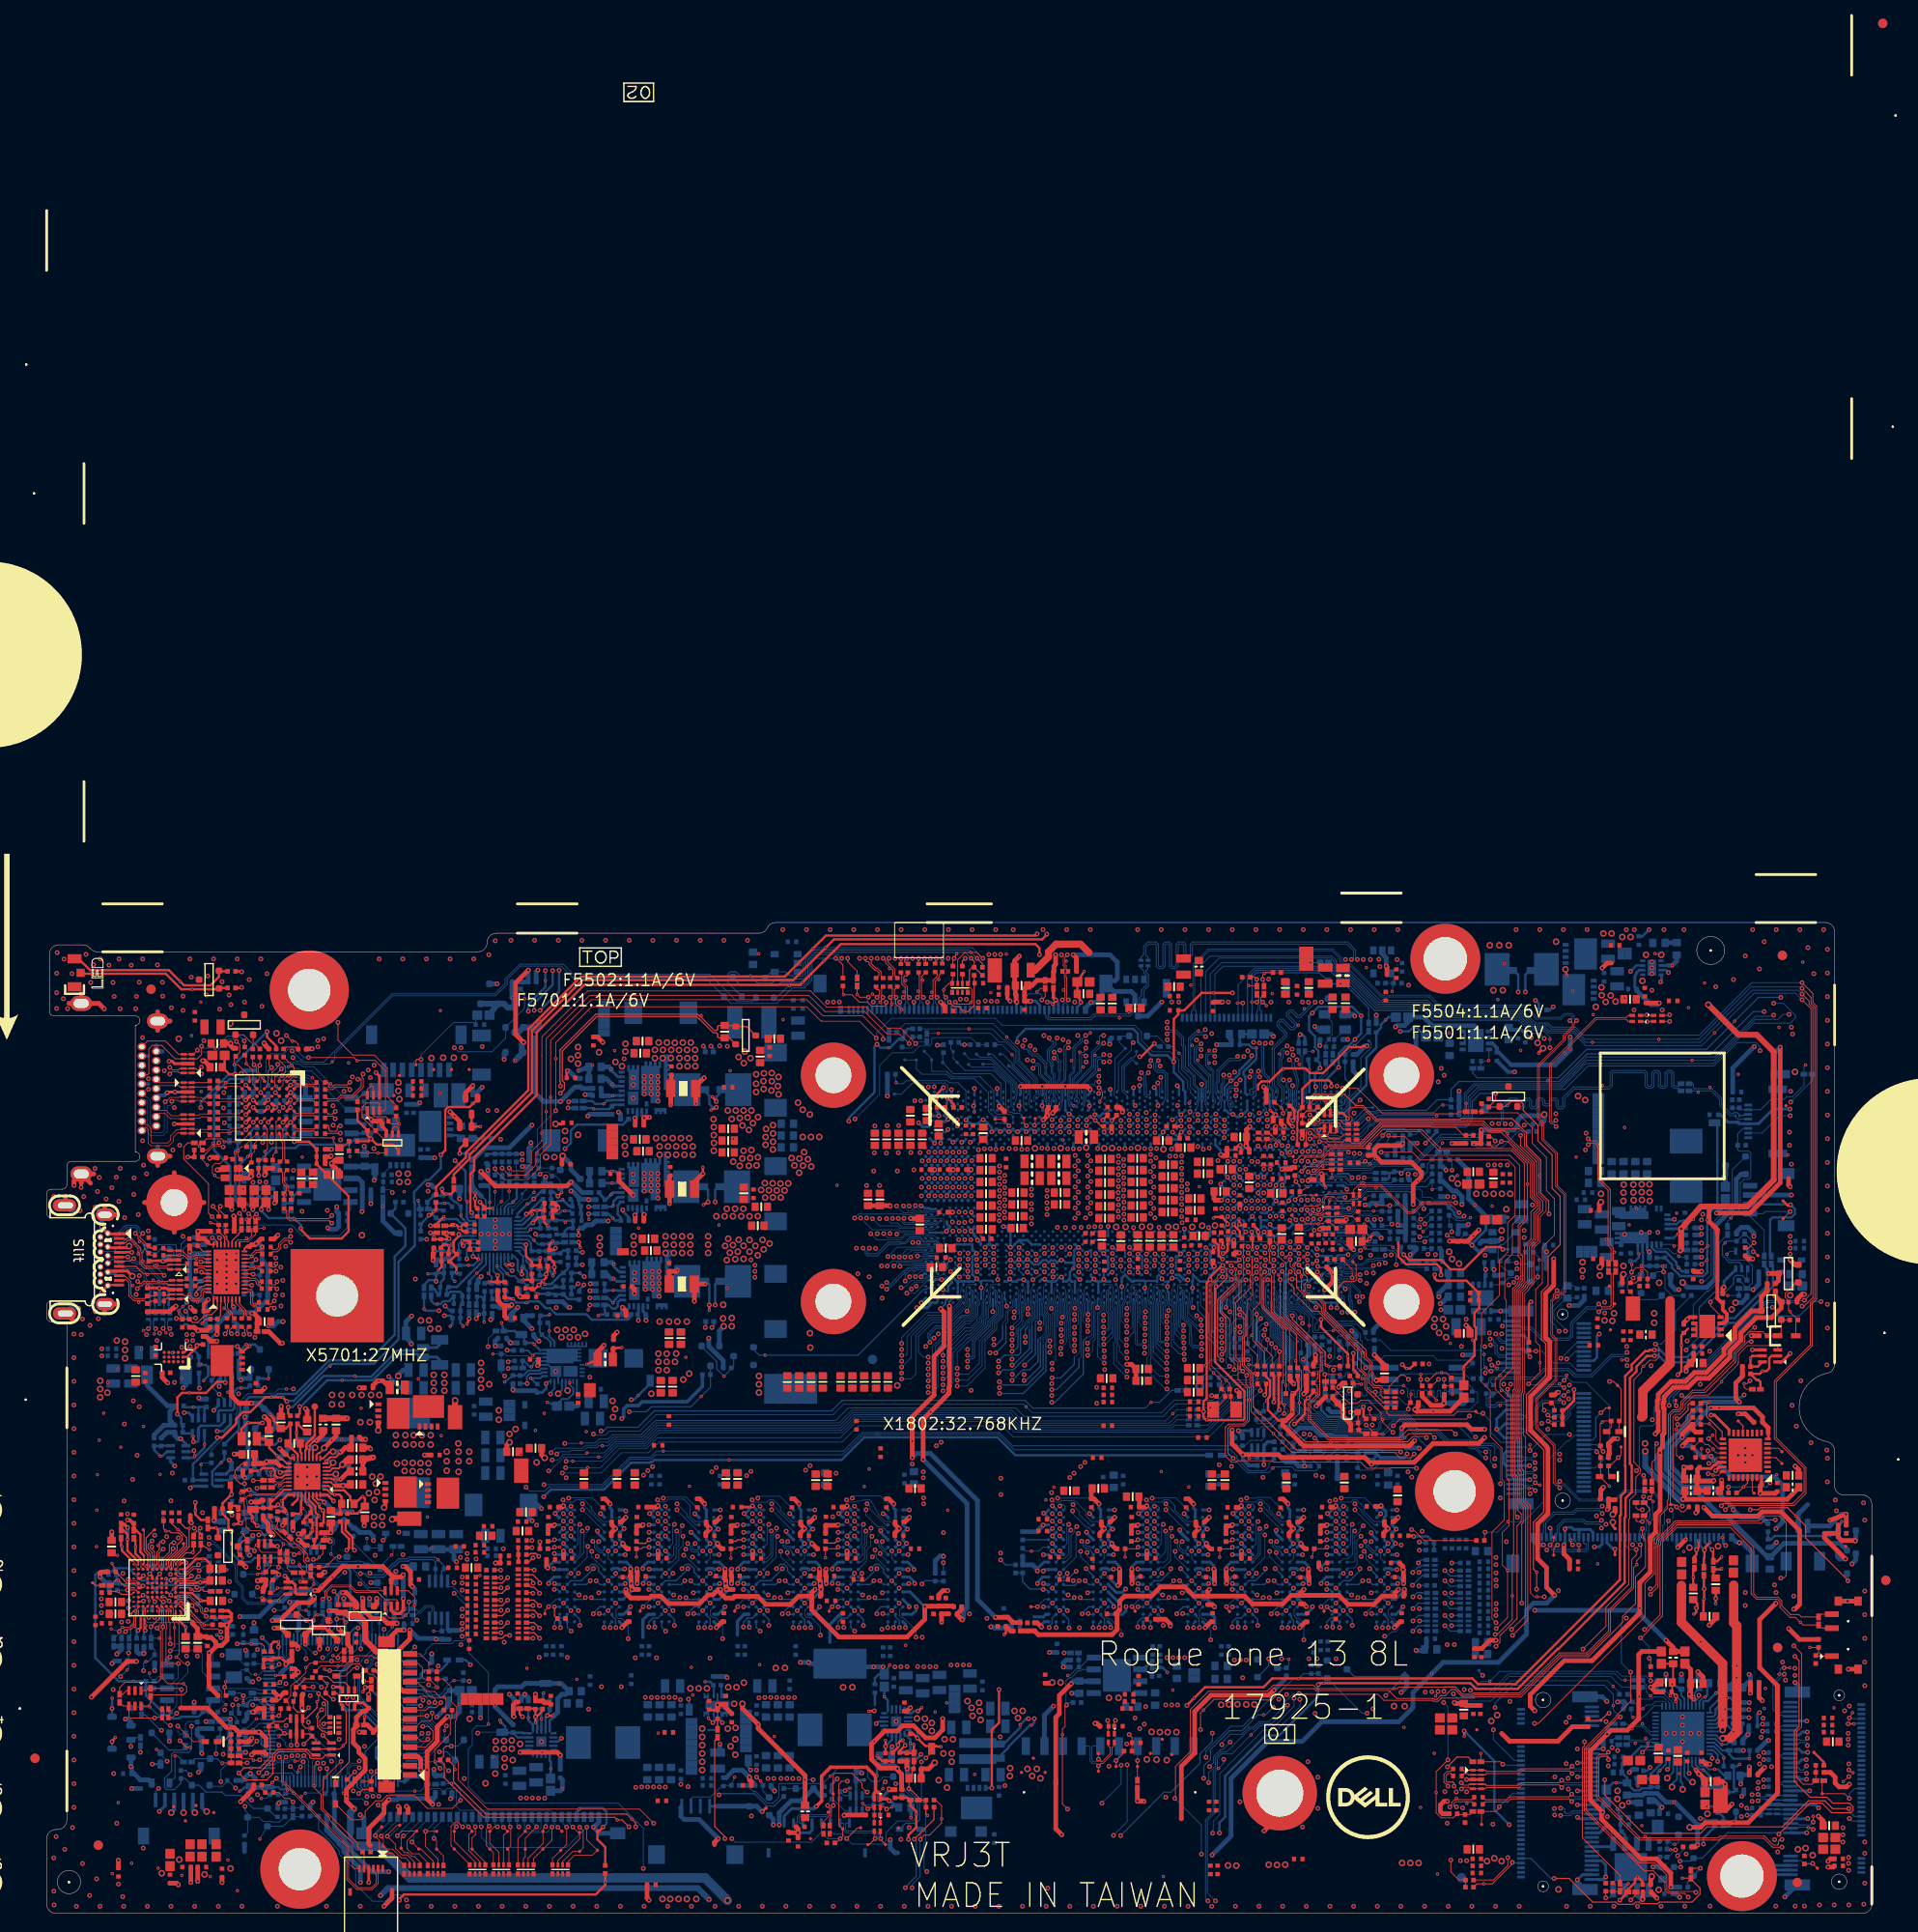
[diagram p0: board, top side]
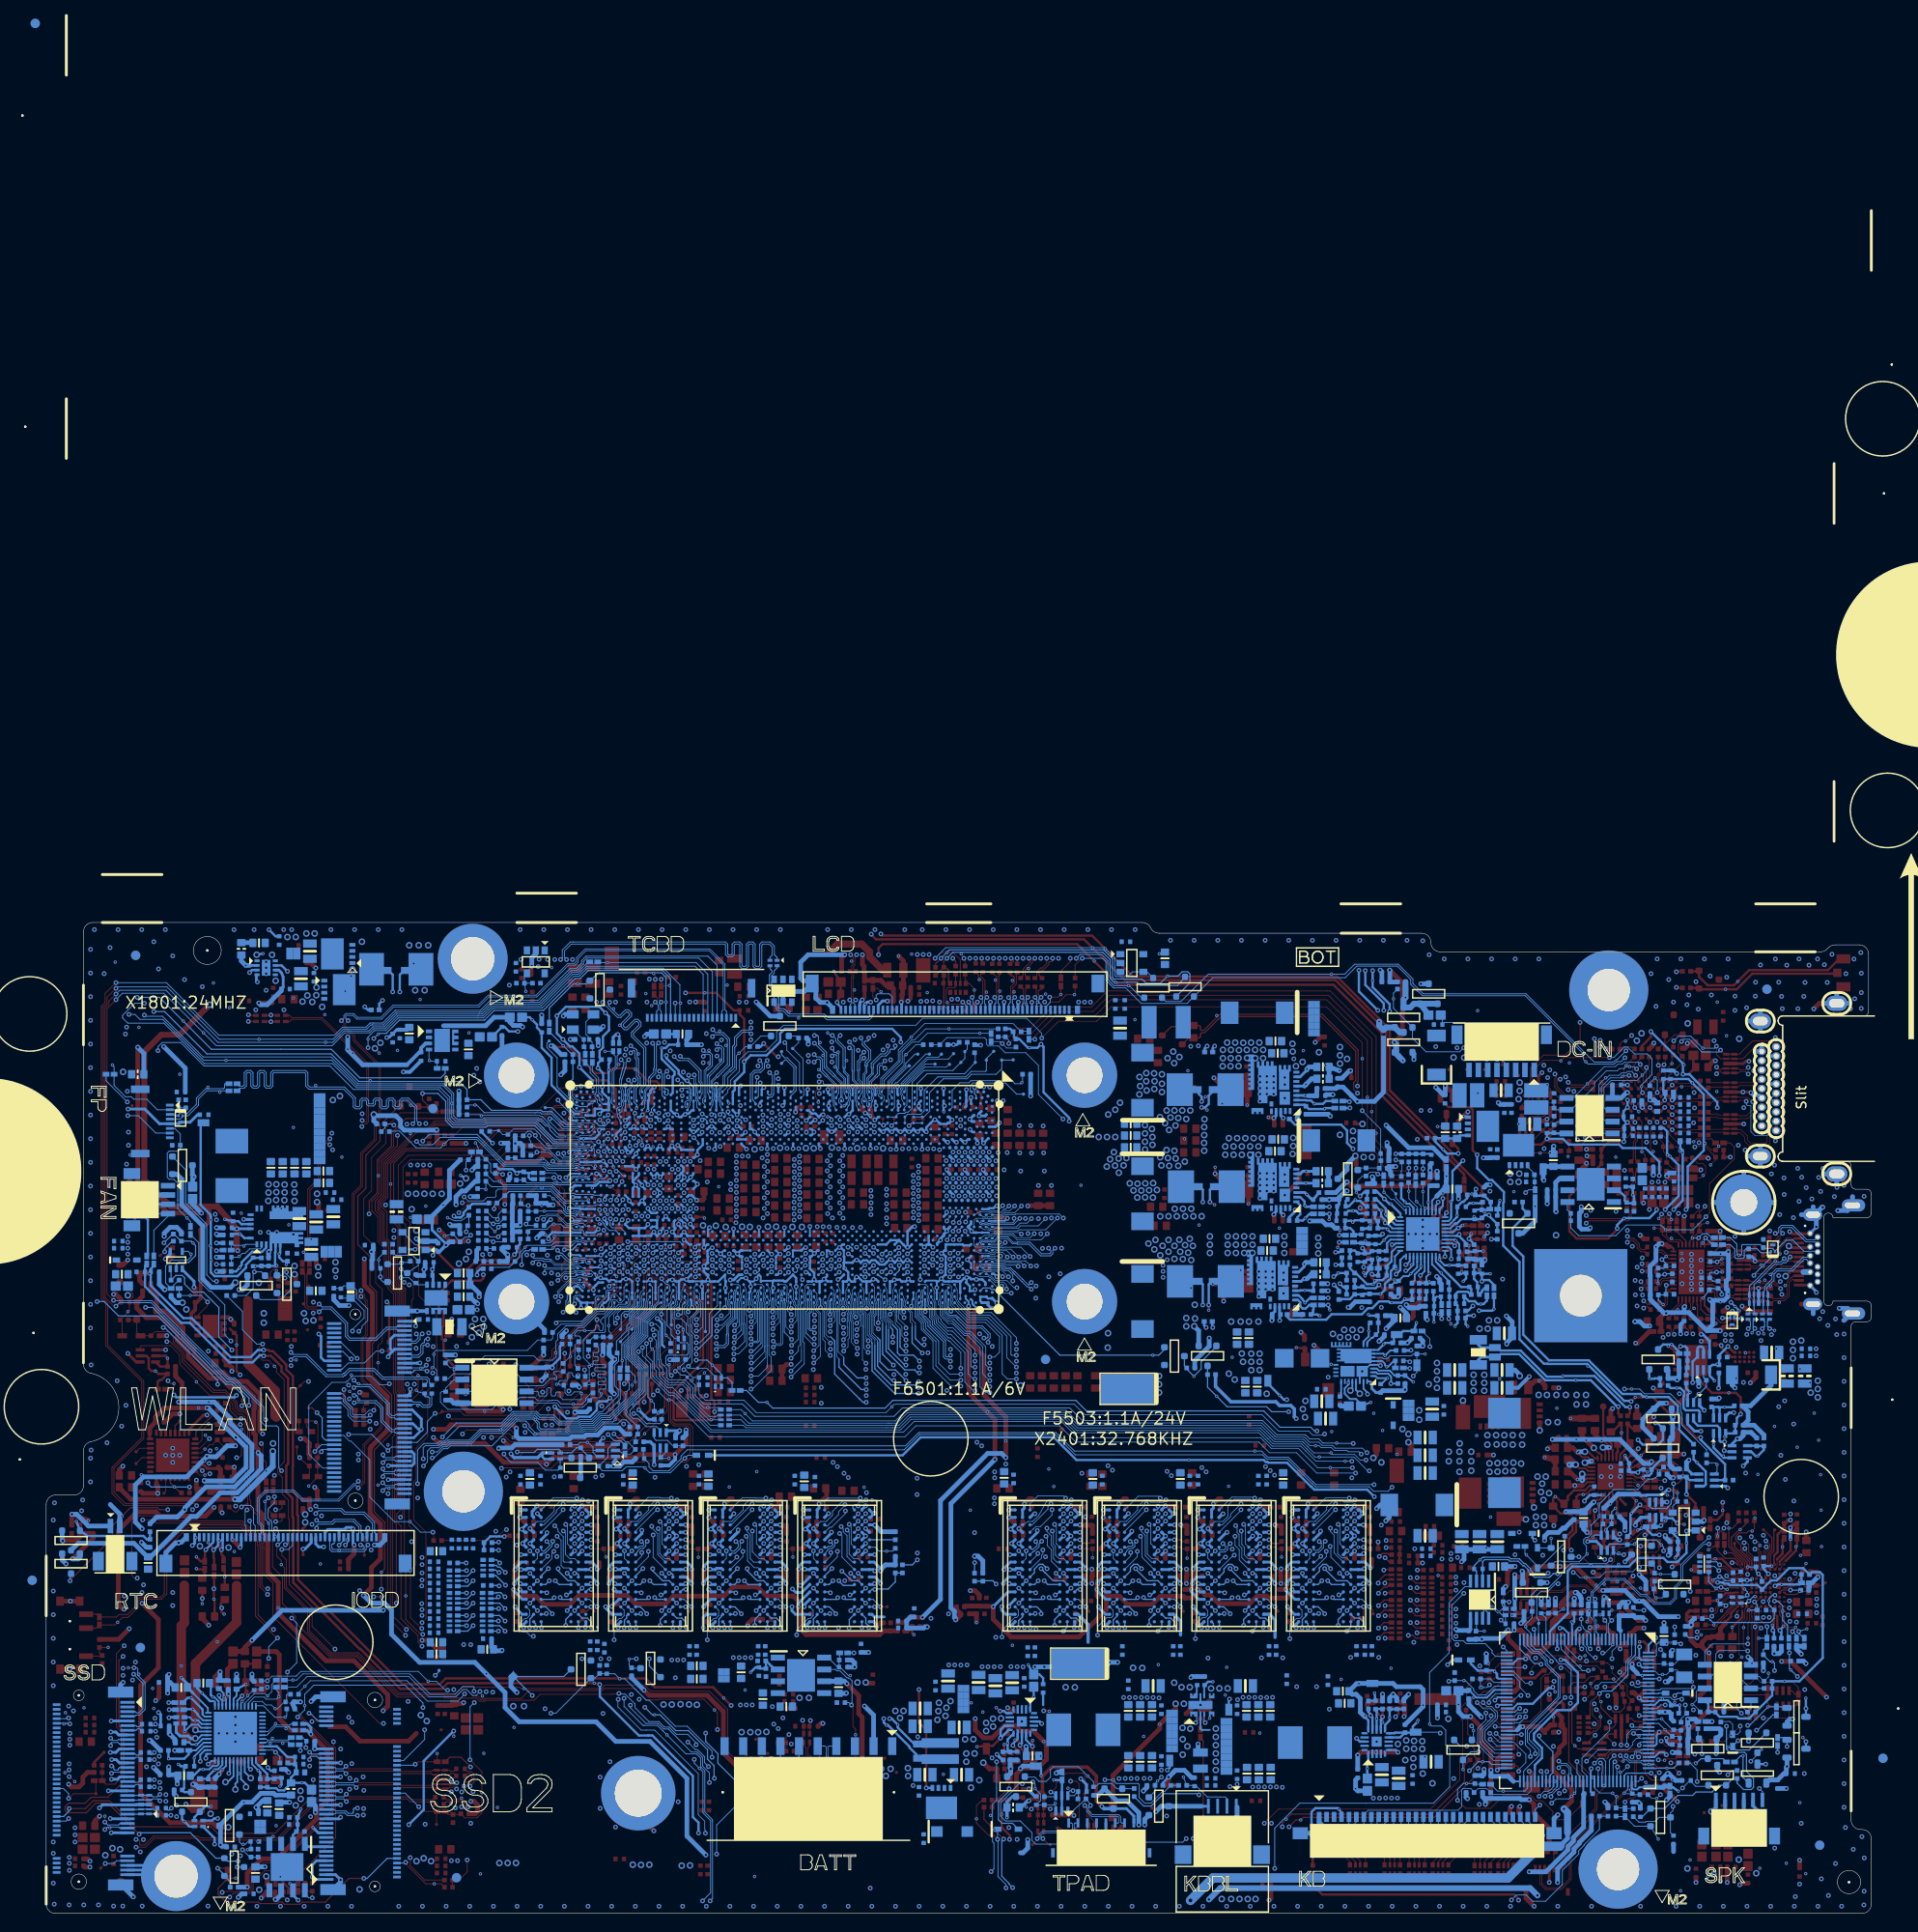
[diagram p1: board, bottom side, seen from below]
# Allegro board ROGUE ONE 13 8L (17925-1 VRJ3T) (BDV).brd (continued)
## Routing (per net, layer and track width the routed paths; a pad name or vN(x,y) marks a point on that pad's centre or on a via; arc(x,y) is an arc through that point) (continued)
M_A_DQ41: length 43.9
  L4SGND w0.089: v2(96.26,59.9) 95.53,59.9 95.23,59.6 95.23,55.86 94.15,54.78 93.43,54.78 88.97,50.32 86.58,50.32 86.46,50.2 86.46,49.78 86.4,49.73 86.17,49.73 86.11,49.79 86.11,50.41 86.02,50.5 85.83,50.5 85.74,50.41 85.74,49.83 85.65,49.74 85.42,49.74 85.33,49.83 85.33,50.23 85.24,50.32 84.97,50.32 79.46,44.82 79.46,43.65 v2(77.56,41.75)
  BOTTOM w0.076: 99.63,63.27 99.91,63.55 99.91,63.76 100.47,64.32 100.47,65.58 100.65,65.9 100.65,66.49 100.65,66.49 100.65,66.74 100.65,66.74 100.65,66.84 CPU1.N34
  BOTTOM w0.089: v2(77.56,41.75) 77.38,41.56 77.38,39.68 RAM2.F7 ; 99.63,63.27 99.22,62.86 98.63,62.86 96.26,60.48 v2(96.26,59.9)
M_A_DQ42: length 43.9
  L4SGND w0.089: v2(97.78,57.87) 98.5,57.15 98.5,54.58 96.05,52.14 94.53,52.14 89.02,46.63 87.14,46.63 86.63,46.12 86.5,46.12 86.12,46.5 85.99,46.5 85.87,46.37 85.87,46.25 86.25,45.87 86.25,45.74 86.12,45.62 86,45.62 85.62,46 85.49,46 85.36,45.87 85.36,45.75 85.75,45.36 85.75,45.24 85.62,45.11 85.5,45.11 85.11,45.49 84.99,45.49 84.86,45.37 84.86,45.24 85.24,44.86 85.24,44.74 83.24,42.73 83.24,41.05 82.38,40.2 81.3,40.2 80.96,39.86 80.96,39.26 v2(80.61,38.9)
  BOTTOM w0.089: v2(80.61,38.9) 81,38.51 RAM2.G2 ; CPU1.R37 102.35,65.47 102.35,64.19 101.54,63.38 101.54,62.81 100.16,61.43 100.16,59.05 98.98,57.87 v2(97.78,57.87)
M_A_DQ43: length 44.2
  L4SGND w0.089: v2(97.78,58.5) 98.79,57.49 98.79,54.46 96.16,51.83 94.69,51.83 88.58,45.73 88.41,45.73 88.1,46.04 87.97,46.04 87.85,45.92 87.85,45.79 88.16,45.48 88.16,45.35 87.83,45.03 87.01,45.03 86.92,45.12 86.92,45.47 86.84,45.56 86.66,45.56 86.57,45.47 86.57,45.12 86.48,45.03 85.95,45.03 83.54,42.62 83.54,40.44 82.01,38.9 v2(81.4,38.9)
  BOTTOM w0.076: 100.84,63.52 100.84,63.65 101.14,63.95 101.14,64.94 101.4,65.2 101.4,65.67 101.35,65.78 101.35,65.96 101.4,66.08 101.4,66.32 101.31,66.56 101.31,67.27 101.33,67.29 101.53,67.5 CPU1.R34
  BOTTOM w0.089: v2(97.78,58.5) 97.78,60.21 99.02,61.45 99.11,61.45 100.84,63.17 100.84,63.52 ; RAM2.H2 81.4,38.1 v2(81.4,38.9)
M_A_DQ44: length 44
  L4SGND w0.089: v2(78.39,41.34) 78.82,41.34 80.21,42.73 80.21,43.29 80.17,43.33 80.17,44.69 84.61,49.14 84.91,49.14 85,49.05 85,48.77 85.08,48.68 85.26,48.68 85.35,48.77 85.35,49.05 85.44,49.14 85.62,49.14 85.71,49.05 85.71,48.77 85.8,48.68 85.97,48.68 86.06,48.77 86.06,49.05 86.15,49.14 86.33,49.14 86.42,49.05 86.42,48.77 86.51,48.68 86.68,48.68 86.77,48.77 86.77,49.05 86.86,49.14 87.04,49.14 87.13,49.05 87.13,48.82 87.22,48.74 87.4,48.74 87.48,48.82 87.48,49.05 87.57,49.14 88.62,49.14 93.67,54.2 94.39,54.2 95.81,55.61 95.81,56.92 v2(96.26,57.36)
  BOTTOM w0.076: 100.41,63.61 100.41,63.74 100.81,64.14 100.81,65.38 CPU1.N37
  BOTTOM w0.089: 100.41,63.61 100.41,63.4 99.16,62.15 98.84,62.15 97,60.3 97,57.92 96.44,57.36 v2(96.26,57.36) ; v2(78.39,41.34) 78.39,40.99 77.97,40.58 77.97,38.39 77.28,37.7 RAM2.H7
M_A_DQ45: length 43.9
  L4SGND w0.089: v2(78.49,40.47) 78.91,40.89 78.91,41.11 80.61,42.81 80.61,43.45 80.38,43.68 80.38,44.5 82.65,46.76 82.77,46.76 82.95,46.58 83.08,46.58 83.2,46.71 83.2,46.83 83.02,47.01 83.02,47.14 84.28,48.39 84.69,48.39 88.28,48.39 93.8,53.9 94.52,53.9 96.26,55.65 v2(96.26,56.09)
  BOTTOM w0.076: CPU1.N35 101.06,66.75 101.23,66.28 101.23,66.1 101.19,65.99 101.19,65.75 101.23,65.64 101.23,65.31 100.97,65.05 100.97,64.04 100.63,63.69 100.63,63.62
  BOTTOM w0.089: RAM2.J7 78.34,38.24 78.34,40.33 v2(78.49,40.47) ; v2(96.26,56.09) 96.42,56.09 97.35,57.02 97.35,60.2 98.91,61.77 99.11,61.77 100.63,63.28 100.63,63.62
M_A_DQ46: length 44.8
  L4SGND w0.089: v2(97.78,57.23) 98.21,56.81 98.21,54.7 95.93,52.43 94.41,52.43 88.89,46.92 85.98,46.92 83.98,44.92 83.98,44.79 84.23,44.53 84.23,44.41 84.11,44.28 83.98,44.28 83.72,44.54 83.6,44.54 83.47,44.41 83.47,44.29 83.82,43.94 83.82,43.82 83.69,43.69 83.57,43.69 83.22,44.04 83.1,44.04 82.97,43.91 82.97,43.78 83.31,43.44 83.31,43.31 82.93,42.93 82.93,41.28 82.15,40.51 81.3,40.51 80.66,39.86 80.66,39.85 v2(79.54,38.73)
  BOTTOM w0.076: CPU1.R36 102.35,66.11 102.35,66 102.53,65.66 102.53,64.12 101.79,63.37
  BOTTOM w0.089: v2(79.54,38.73) 79.54,38.36 RAM2.H3 ; v2(97.78,57.23) 98.92,57.23 100.45,58.77 100.45,61.38 101.79,62.72 101.79,63.37
M_A_DQ47: length 44.2
  L4SGND w0.089: v2(97.78,56.6) 97.78,54.69 95.81,52.72 94.29,52.72 88.77,47.21 85.8,47.21 81.84,43.25 81.84,41.14 81.51,40.81 81.1,40.81 79.67,39.39 79.36,39.39 v2(78.83,38.85)
  BOTTOM w0.076: CPU1.R35 102.28,66.85 102.59,66.54 102.59,65.9 102.7,65.7 102.7,64.03 102.01,63.35
  BOTTOM w0.089: 102.01,63.35 102.01,62.67 100.77,61.43 100.77,58.52 98.84,56.6 v2(97.78,56.6) ; v2(78.83,38.85) 78.83,38.27 RAM2.J3
M_A_DQ48: length 41.4
  L6 w0.089: v2(88.1,43.97) 88.1,44.85 86.65,46.3 86.65,46.59 86.74,46.68 87.05,46.68 87.14,46.77 87.14,46.94 87.05,47.03 86.74,47.03 86.65,47.12 86.65,47.3 86.74,47.39 87.05,47.39 87.14,47.48 87.14,47.66 87.05,47.74 86.74,47.74 86.65,47.83 86.65,48.01 86.74,48.1 87.05,48.1 87.14,48.19 87.14,48.37 87.05,48.46 86.74,48.46 86.65,48.54 86.65,48.72 86.74,48.81 87.05,48.81 87.14,48.9 87.14,49.08 87.05,49.17 86.74,49.17 86.65,49.26 86.65,49.43 86.74,49.52 87.05,49.52 87.14,49.61 87.14,49.79 87.05,49.88 86.74,49.88 86.65,49.97 86.65,50.14 86.74,50.23 87.05,50.23 87.14,50.32 87.14,50.5 87.05,50.59 86.74,50.59 86.65,50.68 86.65,50.86 86.74,50.95 87.05,50.95 87.14,51.03 87.14,51.21 87.05,51.3 86.74,51.3 86.65,51.39 86.65,51.57 86.74,51.66 87.05,51.66 87.14,51.75 87.14,51.92 87.05,52.01 86.74,52.01 86.65,52.1 86.65,52.28 86.74,52.37 87.05,52.37 87.14,52.46 87.14,52.63 87.05,52.72 86.74,52.72 86.65,52.81 86.65,55.62 87.12,56.08 87.12,59.35 92.35,64.58 93.57,64.58 94.91,65.92 94.91,66.42 96.01,67.52 96.16,67.52 96.5,67.87 96.5,68.31 v2(97.07,68.88)
  BOTTOM w0.089: v2(88.1,43.97) 88.43,43.64 88.43,43.38 90.11,41.7 RAM1.C3 ; CPU1.G31 v2(97.07,68.88)
M_A_DQ49: length 43.7
  L6 w0.089: v2(87.99,43.33) 88.21,43.55 88.3,43.55 88.53,43.78 88.53,44.93 87.43,46.03 87.43,53.08 87.34,53.16 87.03,53.16 86.95,53.25 86.95,53.43 87.03,53.52 87.34,53.52 87.43,53.61 87.43,53.79 87.34,53.88 87.03,53.88 86.95,53.96 86.95,54.14 87.03,54.23 87.34,54.23 87.43,54.32 87.43,54.5 87.34,54.59 87.03,54.59 86.95,54.68 86.95,54.85 87.03,54.94 87.34,54.94 87.43,55.03 87.43,55.21 87.34,55.3 87.15,55.3 87.06,55.39 87.06,55.57 87.15,55.65 87.34,55.65 87.43,55.74 87.43,56.03 87.52,56.12 88.09,56.12 88.18,56.21 88.18,56.39 88.09,56.48 87.52,56.48 87.43,56.57 87.43,56.75 87.52,56.84 88.09,56.84 88.18,56.92 88.18,57.1 88.09,57.19 87.52,57.19 87.43,57.28 87.43,57.46 87.52,57.55 88.09,57.55 88.18,57.64 88.18,57.81 88.09,57.9 87.52,57.9 87.43,57.99 87.43,58.17 87.52,58.26 88.09,58.26 88.18,58.35 88.18,58.52 88.09,58.61 87.53,58.61 87.44,58.7 87.44,58.91 87.55,59.02 87.92,59.02 88.02,59.12 88.02,59.84 92.41,64.23 93.46,64.23 95.09,65.85 95.09,66.34 96.09,67.35 97.07,67.35 v2(98.03,68.31)
  BOTTOM w0.089: v2(87.99,43.33) 87.99,42.75 89.22,41.52 89.74,41.52 89.99,41.27 89.99,41.26 RAM1.D3 ; v2(98.03,68.31) CPU1.G32
M_A_DQ50: length 42.5
  L6 w0.089: v2(98.95,70.22) 98.54,70.63 98.54,70.95 98.24,71.26 97.06,71.26 94.53,68.72 94.53,67.91 92.78,66.16 91.34,66.16 84.25,59.07 84.25,48.67 84.19,48.6 83.82,48.6 83.73,48.52 83.73,48.34 83.82,48.25 84.19,48.25 84.25,48.19 84.25,47.93 83.94,47.62 83.57,47.62 83.48,47.53 83.48,47.35 83.57,47.26 83.94,47.26 84.02,47.17 84.02,47 83.94,46.91 83.57,46.91 83.48,46.82 83.48,46.64 83.57,46.55 83.94,46.55 84.02,46.46 84.02,46.28 83.94,46.2 83.57,46.2 83.48,46.11 83.48,45.93 83.57,45.84 83.94,45.84 84.02,45.75 84.02,45.05 85.95,43.13 v2(85.95,42.9)
  BOTTOM w0.089: CPU1.H29 v2(98.95,70.22) ; RAM1.B8 v2(85.95,42.9)
M_A_DQ51: length 42.3
  L6 w0.089: v2(85.95,42.1) 85.57,42.1 85.48,42.19 85.48,43.1 84.79,43.8 84.66,43.8 84.53,43.67 84.4,43.67 84.28,43.79 84.28,43.92 84.41,44.05 84.41,44.18 84.28,44.3 84.16,44.3 84.03,44.17 83.9,44.17 83.78,44.3 83.78,44.42 83.91,44.55 83.91,44.68 83.78,44.8 83.65,44.8 83.52,44.67 83.4,44.67 83.27,44.8 83.27,44.93 83.4,45.06 83.4,45.18 83.17,45.41 83.17,48.58 83.96,49.37 83.96,59.19 91.25,66.48 91.25,67.48 91.8,68.03 91.8,68.04 92.03,68.28 92.05,68.28 92.5,68.73 93.12,68.73 93.13,68.74 93.46,68.74 93.47,68.73 93.73,68.73 93.74,68.73 94.07,68.73 94.08,68.73 94.15,68.73 96.86,71.43 98.37,71.43 v2(98.95,70.86)
  BOTTOM w0.089: CPU1.H28 v2(98.95,70.86) ; v2(85.95,42.1) RAM1.C8
M_A_DQ52: length 41.5
  L6 w0.089: v2(98.07,70.86) 96.91,70.86 94.86,68.8 94.86,67.98 92.63,65.75 91.35,65.75 84.54,58.95 84.54,47.69 84.32,47.47 84.32,45.97 v2(85.9,44.38)
  BOTTOM w0.089: v2(85.9,44.38) 86.15,44.13 86.54,44.13 87.94,44.4 88.37,44.4 88.6,44.18 89.41,42.71 90.06,42.06 90.54,42.06 RAM1.C2 ; CPU1.G28 v2(98.07,70.86)
M_A_DQ53: length 43.1
  L6 w0.089: v2(86.52,44.57) 85.43,45.65 85.15,45.65 85.06,45.74 85.06,45.92 85.15,46 85.35,46 85.43,46.09 85.43,46.27 85.32,46.39 84.74,46.39 84.65,46.47 84.65,46.65 84.74,46.74 85.35,46.74 85.43,46.83 85.43,47.44 85.35,47.52 85.24,47.52 85.15,47.61 85.15,47.79 85.24,47.88 85.35,47.88 85.43,47.97 85.43,48.21 85.35,48.3 84.94,48.3 84.85,48.39 84.85,48.61 84.94,48.7 85.36,48.7 85.45,48.78 85.45,48.96 85.36,49.05 84.94,49.05 84.85,49.14 84.85,49.32 84.94,49.41 85.36,49.41 85.45,49.5 85.45,49.67 85.36,49.76 84.94,49.76 84.85,49.85 84.85,58.84 91.46,65.45 92.57,65.45 95.09,67.96 95.09,68.41 96.43,69.76 97.61,69.76 v2(98.06,70.2)
  BOTTOM w0.089: v2(86.52,44.57) 86.75,44.8 89.52,44.8 90.35,43.97 RAM1.A3 ; CPU1.G29 v2(98.06,70.2)
M_A_DQ54: length 42.7
  L6 w0.089: v2(98.92,68.92) 98.51,68.51 98.51,68.22 98.43,68.14 96.81,66.52 96.1,66.52 93.59,64 92.6,64 88.47,59.87 88.47,55.75 88.38,55.66 88.06,55.66 87.97,55.57 87.97,55.39 88.06,55.3 88.38,55.3 88.47,55.21 88.47,55.04 88.38,54.95 87.81,54.95 87.72,54.86 87.72,54.68 87.81,54.59 88.38,54.59 88.47,54.5 88.47,54.32 88.38,54.24 87.81,54.24 87.72,54.15 87.72,53.97 87.81,53.88 88.38,53.88 88.47,53.79 88.47,53.61 88.38,53.52 87.81,53.52 87.72,53.44 87.72,53.26 87.81,53.17 88.38,53.17 88.47,53.08 88.47,52.9 88.38,52.81 87.81,52.81 87.72,52.72 87.72,52.55 87.81,52.46 88.38,52.46 88.47,52.37 88.47,52.19 88.38,52.1 87.81,52.1 87.72,52.01 87.72,51.84 87.81,51.75 88.38,51.75 88.47,51.66 88.47,51.48 88.38,51.39 87.81,51.39 87.72,51.3 87.72,46.15 88.74,45.13 88.74,43.47 88.16,42.89 87.55,42.89 v2(86.75,42.1)
  BOTTOM w0.089: v2(98.92,68.92) CPU1.H31 ; RAM1.C7 v2(86.75,42.1)
M_A_DQ55: length 43.9
  L6 w0.089: v2(98.95,68.31) 96.88,66.24 96.07,66.24 93.66,63.82 92.83,63.82 88.76,59.75 88.76,51.03 88.67,50.95 88.14,50.95 88.05,50.86 88.05,50.68 88.14,50.59 88.67,50.59 88.76,50.5 88.76,50.32 88.67,50.23 88.14,50.23 88.05,50.15 88.05,49.97 88.14,49.88 88.67,49.88 88.76,49.79 88.76,49.61 88.67,49.52 88.14,49.52 88.05,49.43 88.05,49.26 88.14,49.17 88.67,49.17 88.76,49.08 88.76,48.9 88.67,48.81 88.14,48.81 88.05,48.72 88.05,48.55 88.14,48.46 88.67,48.46 88.76,48.37 88.76,48.19 88.67,48.1 88.14,48.1 88.05,48.01 88.05,47.83 88.14,47.75 88.67,47.75 88.76,47.66 88.76,47.48 88.67,47.39 88.14,47.39 88.05,47.3 88.05,47.12 88.14,47.03 88.67,47.03 88.76,46.95 88.76,46.77 88.67,46.68 88.19,46.68 88.1,46.59 88.1,46.41 88.19,46.32 88.67,46.32 88.76,46.23 88.76,45.56 89.05,45.27 89.05,43.48 88.24,42.66 88.02,42.66 87.29,41.93 87.29,41.57 87.49,41.37 87.49,41.14 87.31,40.96 86.97,40.96 86.85,41.08 v2(86.76,41.3)
  BOTTOM w0.089: v2(98.95,68.31) CPU1.H32 ; RAM1.D7 87.15,40.91 v2(86.76,41.3)
M_A_DQ56: length 45.5
  L6 w0.089: v2(88.54,41.34) 89.66,42.46 90.03,42.46 90.3,42.73 90.3,46.23 90.21,46.32 90.02,46.32 89.93,46.41 89.93,46.59 90.02,46.68 90.21,46.68 90.3,46.77 90.3,46.94 90.21,47.03 90.02,47.03 89.93,47.12 89.93,47.3 90.02,47.39 90.21,47.39 90.3,47.48 90.3,47.66 90.21,47.74 90.02,47.74 89.93,47.83 89.93,48.01 90.02,48.1 90.21,48.1 90.3,48.19 90.3,48.37 90.21,48.46 90.02,48.46 89.93,48.54 89.93,48.72 90.02,48.81 90.21,48.81 90.3,48.9 90.3,49.08 90.21,49.17 90.02,49.17 89.93,49.26 89.93,49.43 90.02,49.52 90.21,49.52 90.3,49.61 90.3,49.79 90.21,49.88 90.02,49.88 89.93,49.97 89.93,50.14 90.02,50.23 90.21,50.23 90.3,50.32 90.3,50.5 90.21,50.59 90.02,50.59 89.93,50.68 89.93,50.86 90.02,50.94 90.21,50.94 90.3,51.03 90.3,51.21 90.21,51.3 90.02,51.3 89.93,51.39 89.93,51.57 90.02,51.66 90.21,51.66 90.3,51.74 90.3,51.92 90.21,52.01 90.02,52.01 89.93,52.1 89.93,52.28 90.02,52.37 90.21,52.37 90.3,52.46 90.3,52.63 90.21,52.72 90.02,52.72 89.93,52.81 89.93,52.99 90.02,53.08 90.21,53.08 90.3,53.17 90.3,53.34 90.21,53.43 90.02,53.43 89.93,53.52 89.93,53.7 90.02,53.79 90.21,53.79 90.3,53.88 90.3,54.23 92.77,56.71 92.77,61.79 95.21,64.23 96.61,64.23 99.12,66.74 99.73,66.74 99.94,66.95 99.94,67.33 100.46,67.85 100.46,67.85 100.47,67.86 100.47,68.95 v2(99.89,69.54)
  BOTTOM w0.089: v2(88.54,41.34) 88.54,40.99 88.06,40.51 88.06,39.5 87.83,39.27 87.83,38.08 87.45,37.7 RAM1.H7 ; CPU1.L31 v2(99.89,69.54)
M_A_DQ57: length 46.4
  L6 w0.089: v2(99.91,68.88) 100.29,68.5 100.29,67.95 100.05,67.72 99.69,67.72 97.55,65.58 96.12,65.58 92.39,61.85 92.39,56.81 91.15,55.57 90.88,55.57 90.79,55.66 90.79,56.85 90.7,56.94 89.73,56.94 89.64,56.85 89.64,56.54 89.73,56.45 90.27,56.45 90.36,56.36 90.36,56.18 90.27,56.1 89.73,56.1 89.64,56.01 89.64,55.83 89.73,55.74 90.27,55.74 90.36,55.65 90.36,55.47 90.27,55.38 89.73,55.38 89.64,55.3 89.64,55.12 89.75,55 90.25,55 90.34,54.91 90.34,54.74 90.25,54.65 89.73,54.65 89.64,54.56 89.64,46.11 89.98,45.76 89.98,43.7 89.37,43.09 89.37,42.8 87.97,41.39 v2(87.97,41.04)
  BOTTOM w0.089: CPU1.L32 v2(99.91,68.88) ; RAM1.H8 86.71,38.06 87.21,38.06 87.62,38.47 87.62,39.39 87.84,39.61 87.84,40.92 v2(87.97,41.04)
M_A_DQ58: length 44.2
  L6 w0.089: v2(101.69,70.17) 102.32,70.17 102.6,69.89 102.6,67.33 97.8,62.52 97.8,62.4 98.07,62.13 98.07,62 97.94,61.88 97.81,61.88 97.55,62.14 97.42,62.14 97.27,61.99 97.27,61.87 97.76,61.37 97.76,61.24 97.64,61.12 97.51,61.12 97.02,61.61 96.89,61.61 96.74,61.46 96.74,60.83 96.83,60.74 97.21,60.74 97.3,60.65 97.3,60.47 97.21,60.38 96.83,60.38 96.74,60.29 96.74,55.52 93.31,52.1 93.31,50.51 93.22,50.42 93.09,50.42 93,50.33 93,50.15 93.09,50.07 93.22,50.07 93.31,49.98 93.31,49.8 93.22,49.71 92.91,49.71 92.82,49.62 92.82,49.44 92.91,49.35 93.22,49.35 93.38,49.19 93.38,41.27 92.57,40.45 91.33,40.45 90.76,39.89 v2(90.76,38.9)
  BOTTOM w0.089: CPU1.N29 v2(101.69,70.17) ; v2(90.76,38.9) 90.76,38.9 90.76,38.09 RAM1.H2
M_A_DQ59: length 44
  L6 w0.089: v2(91.55,38.9) 91.12,39.34 91.12,39.87 91.38,40.14 92.68,40.14 93.7,41.15 93.7,49.36 93.61,49.45 93.61,51.99 97.32,55.7 97.32,58.92 97.44,59.03 98.32,59.03 98.49,59.2 98.49,59.42 98.4,59.5 97.28,59.5 97.19,59.59 97.19,59.77 97.28,59.86 98.4,59.86 98.49,59.95 98.49,60.13 98.4,60.22 97.89,60.22 97.8,60.3 97.8,60.48 97.89,60.57 98.4,60.57 98.49,60.66 98.49,62.71 99.56,63.77 99.56,64.03 102.86,67.33 102.86,70.53 102.55,70.83 v2(101.69,70.83)
  BOTTOM w0.089: CPU1.N28 v2(101.69,70.83) ; RAM1.G2 v2(91.55,38.9)
M_A_DQ60: length 42.2
  L6 w0.089: v2(88.64,40.47) 89.06,40.89 89.06,41.31 89.88,42.13 90.18,42.13 90.53,42.47 90.53,44.15 90.62,44.24 90.62,54.09 93.23,56.71 93.23,61.82 95.31,63.9 96.58,63.9 99.1,66.41 100.27,66.41 100.85,67 100.85,68.93 100.37,69.41 100.37,70.4 v2(100.8,70.83)
  BOTTOM w0.089: CPU1.L28 v2(100.8,70.83) ; v2(88.64,40.47) 88.49,40.33 88.49,39.47 88.05,39.03 88.05,37.8 RAM1.J7
M_A_DQ61: length 43.3
  L6 w0.089: v2(99.86,70.2) 99.43,69.77 99.43,68.22 97.19,65.98 96.07,65.98 93.28,63.19 93.23,63.19 89.35,59.31 89.35,58.49 89.43,58.41 90.76,58.41 90.84,58.32 90.84,58.14 90.76,58.05 89.43,58.05 89.35,57.96 89.35,57.78 89.43,57.69 90.81,57.69 90.89,57.61 90.89,57.43 90.81,57.34 89.43,57.34 89.35,57.25 89.35,45.94 89.65,45.64 89.65,43.69 v2(87.71,41.75)
  BOTTOM w0.089: RAM1.F7 87.53,39.68 87.53,41.56 v2(87.71,41.75) ; CPU1.L29 v2(99.86,70.2)
M_A_DQ62: length 44.6
  L6 w0.089: v2(89.5,38.63) 89.71,38.63 90.46,39.38 90.46,39.99 91.33,40.86 91.76,40.86 91.98,41.08 91.98,41.49 92.19,41.7 92.55,41.7 93.07,42.22 93.07,47.5 92.53,48.04 92.53,50.9 92.62,50.99 92.93,50.99 93.02,51.07 93.02,51.25 92.93,51.34 92.62,51.34 92.53,51.43 92.53,51.61 92.62,51.7 92.93,51.7 93.02,51.79 93.02,51.96 92.93,52.05 92.62,52.05 92.53,52.14 92.53,52.6 92.73,52.81 92.86,52.81 93.17,52.5 93.3,52.5 93.42,52.62 93.42,52.75 93.11,53.06 93.11,53.19 93.24,53.31 93.36,53.31 93.67,53 93.8,53 93.93,53.13 93.93,53.25 93.61,53.56 93.61,53.69 93.74,53.82 93.87,53.82 94.18,53.5 94.3,53.5 94.81,54.01 96.13,55.33 96.13,55.57 95.77,55.92 95.77,61 99,64.23 99.17,64.23 101.74,66.8 101.74,68.19 102.32,68.78 102.32,69.58 102.24,69.67 101.87,69.67 v2(101.69,69.49)
  BOTTOM w0.089: RAM1.H3 89.5,38.55 v2(89.5,38.63) ; CPU1.N31 v2(101.69,69.49)
M_A_DQ63: length 46.1
  L6 w0.089: v2(101.69,68.8) 101.49,68.6 101.49,66.81 100.23,65.54 99.19,65.54 97.75,64.11 97.75,63.49 95.31,61.05 95.31,55.85 95.63,55.53 95.63,55.4 95.4,55.17 95.28,55.17 95.01,55.44 94.88,55.44 94.65,55.21 94.65,55.08 94.94,54.79 94.94,54.66 94.82,54.54 94.69,54.54 94.4,54.83 94.27,54.83 94.15,54.7 94.15,54.58 94.48,54.25 94.48,54.12 94.35,54 94.23,54 93.89,54.33 93.77,54.33 92.22,52.77 92.22,52.33 92.13,52.24 91.91,52.24 91.82,52.15 91.82,51.97 91.91,51.88 92.13,51.88 92.22,51.79 92.22,51.62 92.13,51.53 91.91,51.53 91.82,51.44 91.82,51.26 91.91,51.17 92.13,51.17 92.22,51.08 92.22,50.91 92.13,50.82 91.91,50.82 91.82,50.73 91.82,50.55 91.91,50.46 92.13,50.46 92.22,50.37 92.22,50.19 92.13,50.11 91.91,50.11 91.82,50.02 91.82,49.84 91.91,49.75 92.13,49.75 92.22,49.66 92.22,49.48 92.13,49.39 91.91,49.39 91.82,49.31 91.82,49.13 91.91,49.04 92.13,49.04 92.22,48.95 92.22,48.77 92.13,48.68 91.91,48.68 91.82,48.59 91.82,48.42 91.91,48.33 92.13,48.33 92.22,48.24 92.22,47.9 92.75,47.36 92.75,44.04 92.2,43.48 92.2,42.58 90.62,41 90.62,40.56 90.17,40.11 90.17,39.74 89.89,39.46 89.42,39.46 v2(88.97,39.01)
  BOTTOM w0.089: v2(88.97,39.01) 88.97,38.59 89.11,38.45 89.11,38.14 RAM1.J3 ; CPU1.N32 v2(101.69,68.8)
M_A_DQS_DN0: length 60
  L4SGND w0.089: v2(56.3,43.7) 56.3,43.45 56.41,43.35 56.84,43.35 56.93,43.44 56.93,44.7 56.93,44.94 65.47,53.49 65.47,53.49 65.63,53.49 65.63,53.49 68.77,53.49 71.9,56.61 71.9,56.74 71.48,57.17 71.48,57.45 71.84,57.82 72.17,57.82 72.62,57.36 72.75,57.36 72.97,57.59 72.97,57.71 72.48,58.2 72.48,58.46 72.85,58.82 73.13,58.82 73.59,58.36 73.72,58.36 73.94,58.58 73.94,58.71 73.55,59.1 73.55,59.47 78.78,64.7 78.78,65.98 83.44,70.64 87.57,70.64 87.67,70.75 v2(87.67,71.39)
  BOTTOM w0.076: 91.69,71.82 91.7,71.82 91.74,71.86 92.22,71.86 92.78,72.42 93.78,72.42 94.16,72.03 94.53,72.03 94.64,72.07 94.82,72.07 94.94,72.03 95.17,72.03 95.3,72.08 95.46,72.08 95.59,72.03 95.61,71.98 95.63,71.94 95.59,71.81 95.49,71.77 CPU1.C27
  BOTTOM w0.102: 91.69,71.82 90.45,71.82 89.21,70.57 88.13,70.57 87.9,70.81 87.9,71.16 v2(87.67,71.39) ; RAM4.A7 56.48,43.3 56.3,43.47 v2(56.3,43.7)
M_A_DQS_DN1: length 55.5
  L4SGND w0.089: v2(90.21,67.71) 90.45,67.47 90.72,67.47 90.97,67.22 90.97,66.31 73.78,49.12 68.58,49.12 68.49,49.03 68.49,48.59 68.29,48.39 67.81,48.39 67.61,48.59 67.61,49.03 67.52,49.12 67.11,49.12 59.98,41.99 59.98,40.9 59.47,40.39 59.38,40.39 59.29,40.3 v2(59.29,39.91)
  BOTTOM w0.076: CPU1.D31 95.94,69.29 95.81,69.43 95.71,69.65 95.5,69.72 95.26,69.72 95.15,69.68 94.96,69.68 94.83,69.73 94.63,69.73 94.4,69.64 93.27,69.64 92.96,69.33 92.46,69.33 92.04,68.91 91.99,68.91
  BOTTOM w0.102: v2(59.29,39.91) 59.07,39.73 59.07,39.34 59.43,38.98 59.8,38.98 59.9,39.08 RAM4.F3 ; 91.99,68.91 91.14,68.05 90.56,67.47 90.45,67.47 v2(90.21,67.71)
M_A_DQS_DN2: length 57.9
  L6 w0.089: v2(69.64,39.69) 69.37,39.96 69.37,40.18 71.64,42.45 71.64,44.14 72.45,44.95 72.59,44.95 72.93,44.61 73.24,44.61 73.58,44.95 73.58,45.24 73.24,45.58 73.24,45.74 73.47,45.97 73.61,45.97 74,45.57 74.3,45.57 74.63,45.9 74.63,46.22 74.25,46.6 74.25,46.79 82.18,54.72 82.18,59.8 82.96,60.58 82.96,60.88 82.39,61.45 82.39,61.61 82.61,61.83 82.75,61.83 83.33,61.25 83.63,61.25 83.97,61.59 83.97,61.91 83.43,62.44 83.43,62.6 83.64,62.81 83.81,62.81 84.37,62.25 84.65,62.25 87.89,65.49 87.89,68.66 90.34,71.11 93.98,71.11 95.41,72.55 97.52,72.55 97.72,72.75 98.15,72.75 v2(98.62,73.22)
  BOTTOM w0.102: RAM3.F3 70.05,39.12 69.95,39.01 69.5,39.01 69.36,39.16 69.36,39.41 v2(69.64,39.69) ; v2(98.62,73.22) 98.62,73.36 CPU1.H24
M_A_DQS_DN3: length 56.9
  L6 w0.089: v2(92.06,74.59) 91.83,74.82 91.83,75.01 91.46,75.39 85.93,75.39 78.12,67.58 78.12,61.89 74.87,58.63 74.87,56.55 74.14,55.82 74.14,55.56 74.66,55.03 74.66,54.88 74.43,54.65 74.3,54.65 73.78,55.17 73.43,55.17 73.11,54.85 73.11,54.57 73.65,54.03 73.65,53.87 73.45,53.68 73.27,53.68 72.77,54.17 72.45,54.17 72.12,53.84 72.12,53.68 72.12,53.54 72.63,53.03 72.63,52.85 72.44,52.65 72.24,52.65 72.05,52.85 71.79,52.85 70.76,51.81 70.75,51.81 67.02,48.08 67.02,43.48 66.84,43.3 66.65,43.3 66.46,43.49 v2(66.46,43.7)
  BOTTOM w0.076: v2(92.06,74.59) 92.06,74.22 92.17,74.11 94.33,74.11 94.52,74.11 94.64,74.06 94.81,74.06 94.95,74.11 95.15,74.11 95.28,74.06 95.47,74.06 95.58,74.1 95.63,74.2 95.59,74.32 95.55,74.34 CPU1.C23
  BOTTOM w0.102: v2(66.46,43.7) 66.46,43.51 66.66,43.3 RAM3.A7
M_A_DQS_DN4: length 40.9
  L4SGND w0.089: v2(94.85,61.3) 95.17,61.3 95.31,61.15 95.31,60.75 94.98,60.42 93.87,60.42 92.94,59.49 92.94,57.5 91.54,56.09 90.43,56.09 90.34,56.18 90.34,56.5 90.14,56.7 89.34,56.7 89.13,56.49 89.13,56.18 89.04,56.09 87,56.09 77.23,46.33 77.23,43.5 76.98,43.25 76.85,43.25 76.6,43.5 v2(76.6,43.7)
  BOTTOM w0.076: CPU1.J35 99.08,66.54 99.08,66.68 99.11,66.73 99.23,66.77 99.33,66.72 99.38,66.59 99.38,66.44 99.32,66.29 99.32,66.08 99.37,65.96 99.37,65.78 99.29,65.58 99.29,64.53 98.97,64.2 98.29,64.2 98.08,64 98.04,63.96 98.01,63.96 98,63.95
  BOTTOM w0.102: 98,63.95 97.09,63.05 95.47,63.05 94.63,62.21 94.63,61.76 94.85,61.54 v2(94.85,61.3) ; v2(76.6,43.7) 76.6,43.42 76.69,43.33 76.81,43.3 RAM2.A7
M_A_DQS_DN5: length 43.6
  L4SGND w0.089: v2(98.89,59.27) 98.6,59.27 98.51,59.36 98.51,59.65 98.45,59.71 97.57,59.71 97.27,59.41 97.27,54.88 95.61,53.22 94.08,53.22 88.57,47.71 84.56,47.71 84.14,47.28 84.14,46.46 81.46,43.78 81.46,42.18 79.45,40.18 79.45,40.05 v2(79.59,39.91)
  BOTTOM w0.076: CPU1.P34 101.62,67.08 101.75,66.95 101.97,66.85 102.05,66.64 102.05,66.4 102.01,66.29 102.01,66.1 102.05,65.99 102.05,65.75 102.03,65.69 102.01,65.64 102.01,65.28 102.16,65.13 102.16,64.34 101.8,63.98 101.8,63.93 101.79,63.92
  BOTTOM w0.102: v2(98.89,59.27) 99.12,59.5 99.41,59.5 99.65,59.73 99.65,61.36 101.31,63.02 101.31,63.44 101.63,63.76 101.79,63.92 ; RAM2.F3 80.12,39.22 79.98,39.22 79.81,39.39 79.42,39.39 79.32,39.49 79.32,39.7 79.38,39.76 79.38,39.76 79.54,39.91 v2(79.59,39.91)
M_A_DQS_DN6: length 42.3
  L6 w0.089: v2(98.05,69.54) 98.31,69.27 98.31,69.06 98.16,68.92 97.95,68.92 97.33,69.54 96.49,69.54 95.4,68.45 95.4,67.93 92.61,65.14 91.92,65.14 86.37,59.6 86.37,58.75 86.28,58.65 85.63,58.65 85.4,58.42 85.4,57.97 85.61,57.76 86.28,57.76 86.37,57.66 86.37,57.12 86.26,57 85.58,57 85.35,56.78 85.35,56.32 85.56,56.11 85.85,56.11 85.95,56.02 85.95,55.68 85.86,55.59 85.59,55.59 85.36,55.37 85.36,54.89 85.56,54.69 85.85,54.69 85.95,54.59 85.95,54.25 85.86,54.17 85.59,54.17 85.36,53.94 85.36,53.46 85.57,53.25 85.86,53.25 85.96,53.16 85.96,52.84 85.85,52.73 85.58,52.73 85.35,52.51 85.35,52.05 85.57,51.83 85.86,51.83 85.95,51.75 85.95,51.29 85.86,51.21 85.59,51.21 85.36,50.98 85.36,50.52 85.59,50.29 85.86,50.29 85.96,50.19 85.96,45.9 87.47,44.39 87.47,43.71 87.11,43.35 86.98,43.35 86.75,43.58 v2(86.75,43.7)
  BOTTOM w0.102: CPU1.G30 97.58,69.63 97.79,69.43 97.94,69.43 v2(98.05,69.54) ; v2(86.75,43.7) RAM1.A7
M_A_DQS_DN7: length 43.7
  L6 w0.089: v2(89.74,39.91) 89.74,40.23 90.25,40.74 90.25,41.33 91.61,42.68 91.61,44.23 91.75,44.38 92.03,44.38 92.23,44.57 92.23,45.5 92.02,45.7 91.42,45.7 91.31,45.82 91.31,46.12 91.4,46.21 92.02,46.21 92.23,46.42 92.23,47.1 91.97,47.36 91.44,47.36 91.31,47.49 91.31,52.63 91.81,53.14 91.81,53.44 91.45,53.81 91.45,53.93 91.69,54.18 91.84,54.18 92.18,53.83 92.52,53.83 92.85,54.16 92.85,54.47 92.48,54.84 92.48,54.96 92.73,55.21 92.87,55.21 93.22,54.85 93.54,54.85 93.94,55.25 93.94,57 93.94,57.01 93.94,61.42 95.25,62.73 96.06,62.73 99.07,65.74 100.14,65.74 101.22,66.82 101.22,69.55 101.23,69.56 101.23,69.77 v2(100.8,70.2)
  BOTTOM w0.102: v2(89.74,39.91) 89.74,39.84 89.6,39.7 89.6,39.47 89.99,39.08 90.13,39.06 90.27,39.14 RAM1.F3 ; CPU1.L30 v2(100.8,70.2)
M_A_DQS_DP0: length 60
  L4SGND w0.089: v2(88.35,71.39) 88.35,71.16 87.65,70.45 83.52,70.45 78.97,65.9 78.97,64.62 73.74,59.39 73.74,59.18 74.13,58.79 74.13,58.5 73.8,58.17 73.51,58.17 73.05,58.63 72.93,58.63 72.67,58.38 72.67,58.28 73.16,57.79 73.16,57.51 72.83,57.17 72.54,57.17 72.09,57.63 71.92,57.63 71.67,57.37 71.67,57.24 72.09,56.82 72.09,56.54 68.85,53.3 65.55,53.3 65.55,53.3 57.12,44.86 57.12,44.78 57.12,43.36 56.92,43.16 56.55,43.16 v2(56.3,42.9)
  BOTTOM w0.076: CPU1.D27 95.94,71.81 95.81,71.95 95.71,72.16 95.49,72.24 95.27,72.24 95.15,72.2 94.96,72.2 94.85,72.24 94.61,72.24 94.5,72.2 94.23,72.2 93.84,72.58 92.72,72.58 92.15,72.02 91.73,72.02 91.71,72.04 91.69,72.04
  BOTTOM w0.102: v2(56.3,42.9) RAM4.B7 ; 91.69,72.04 90.36,72.04 89.11,70.8 88.23,70.8 88.13,70.9 88.13,71.16 v2(88.35,71.39)
M_A_DQS_DP1: length 55.4
  L4SGND w0.089: v2(90.21,66.99) 90.5,67.28 90.64,67.28 90.78,67.14 90.78,66.39 73.7,49.31 68.5,49.31 68.3,49.11 68.3,48.67 68.21,48.58 67.89,48.58 67.8,48.67 67.8,49.11 67.6,49.31 67.03,49.31 59.79,42.07 59.79,40.97 59.4,40.58 59.3,40.58 59.09,40.37 59.09,40.37 v2(58.65,39.94)
  BOTTOM w0.076: 92.16,68.75 92.16,68.75 92.16,68.8 92.53,69.16 93.03,69.16 93.34,69.48 94.43,69.48 94.64,69.56 94.66,69.56 94.8,69.56 94.94,69.52 95.17,69.52 95.29,69.56 95.47,69.56 95.59,69.52 95.63,69.42 95.59,69.3 95.49,69.25 CPU1.C31
  BOTTOM w0.102: RAM4.G3 59.65,38.75 59.34,38.75 58.84,39.24 58.84,39.75 v2(58.65,39.94) ; v2(90.21,66.99) 90.46,67.24 90.65,67.24 91.23,67.82 92.02,68.61 92.16,68.75
M_A_DQS_DP2: length 57.9
  L6 w0.089: v2(68.85,39.69) 69.18,40.02 69.18,40.26 71.45,42.53 71.45,44.06 71.45,44.06 71.45,44.22 72.37,45.14 72.67,45.14 73.01,44.8 73.16,44.8 73.39,45.03 73.39,45.16 73.05,45.5 73.05,45.82 73.39,46.16 73.69,46.16 74.08,45.76 74.23,45.76 74.44,45.98 74.44,46.14 74.05,46.53 74.05,46.87 81.94,54.75 81.94,54.75 81.99,54.8 81.99,59.88 82.77,60.66 82.77,60.8 82.2,61.37 82.2,61.69 82.53,62.02 82.83,62.02 83.41,61.44 83.55,61.44 83.78,61.67 83.78,61.83 83.24,62.36 83.24,62.68 83.56,63 83.88,63 84.44,62.44 84.57,62.44 87.69,65.56 87.69,68.73 90.26,71.3 93.9,71.3 95.33,72.74 97.44,72.74 97.64,72.94 97.7,72.94 v2(98.01,73.25)
  BOTTOM w0.102: v2(68.85,39.69) 69.13,39.41 69.13,39.06 69.41,38.79 69.95,38.79 70.05,38.68 RAM3.G3 ; v2(98.01,73.25) 98.01,73.32 CPU1.G24
M_A_DQS_DP3: length 56.9
  L6 w0.089: v2(91.45,74.59) 91.64,74.78 91.64,74.94 91.38,75.2 86.01,75.2 78.31,67.5 78.31,61.81 75.06,58.56 75.06,56.47 74.33,55.74 74.33,55.64 74.85,55.11 74.85,54.81 74.51,54.46 74.35,54.46 74.22,54.46 73.7,54.98 73.51,54.98 73.3,54.77 73.3,54.65 73.84,54.11 73.84,53.79 73.53,53.49 73.19,53.49 72.7,53.98 72.53,53.98 72.31,53.76 72.31,53.62 72.82,53.11 72.82,52.77 72.52,52.46 72.16,52.46 71.97,52.66 71.87,52.66 70.83,51.62 70.83,51.62 67.21,48 67.21,43.4 66.92,43.11 66.65,43.11 v2(66.45,42.9)
  BOTTOM w0.076: v2(91.45,74.59) 92.1,73.94 94.33,73.94 94.49,73.94 94.61,73.89 94.84,73.89 94.98,73.94 95.12,73.94 95.25,73.9 95.5,73.9 95.71,73.97 95.81,74.19 95.87,74.25 CPU1.D23
  BOTTOM w0.102: v2(66.45,42.9) RAM3.B7
M_A_DQS_DP4: length 40.9
  L4SGND w0.089: v2(95.3,61.75) 95.3,61.43 95.5,61.23 95.5,60.67 95.06,60.23 93.95,60.23 93.13,59.41 93.13,57.42 91.62,55.9 90.35,55.9 90.15,56.1 90.15,56.42 90.06,56.51 89.42,56.51 89.32,56.41 89.32,56.1 89.12,55.9 87.08,55.9 77.42,46.25 77.42,43.43 77.05,43.06 76.88,43.06 v2(76.6,42.9)
  BOTTOM w0.076: CPU1.J34 99.1,67.08 99.23,66.95 99.46,66.84 99.54,66.62 99.54,66.41 99.49,66.26 99.49,66.1 99.53,65.99 99.53,65.75 99.46,65.55 99.46,64.46 99.04,64.04 98.36,64.04 98.16,63.84 98.16,63.79
  BOTTOM w0.102: v2(95.3,61.75) 94.97,61.75 94.86,61.85 94.86,62.12 95.56,62.82 97.19,62.82 98.16,63.79 ; v2(76.6,42.9) RAM2.B7
M_A_DQS_DP5: length 43.6
  L4SGND w0.089: v2(98.89,59.9) 97.49,59.9 97.08,59.49 97.08,54.96 95.53,53.41 94,53.41 88.49,47.9 84.48,47.9 83.95,47.36 83.95,46.54 81.27,43.86 81.27,42.26 78.95,39.95 v2(78.95,39.94)
  BOTTOM w0.076: CPU1.P35 101.62,66.7 101.66,66.74 101.75,66.77 101.84,66.73 101.88,66.61 101.88,66.43 101.84,66.32 101.84,66.08 101.88,65.96 101.88,65.78 101.86,65.73 101.86,65.72 101.84,65.67 101.84,65.22 101.99,65.06 101.99,64.4 101.69,64.1 101.64,64.1 101.63,64.08
  BOTTOM w0.102: v2(98.89,59.9) 99.07,59.72 99.32,59.72 99.42,59.83 99.42,61.46 101.08,63.12 101.08,63.53 101.63,64.08 ; v2(78.95,39.94) 79.09,39.8 79.09,39.4 79.33,39.16 79.72,39.16 79.97,38.91 79.97,38.86 RAM2.G3
M_A_DQS_DP6: length 42.3
  L6 w0.089: v2(86.74,42.9) 87,43.16 87.19,43.16 87.66,43.63 87.66,44.47 86.15,45.98 86.15,50.27 85.94,50.48 85.67,50.48 85.55,50.6 85.55,50.9 85.67,51.01 85.94,51.01 86.14,51.21 86.14,51.83 85.94,52.02 85.65,52.02 85.54,52.13 85.54,52.43 85.66,52.54 85.93,52.54 86.15,52.76 86.15,53.24 85.94,53.45 85.65,53.45 85.55,53.54 85.55,53.86 85.67,53.98 85.94,53.98 86.14,54.17 86.14,54.67 85.93,54.88 85.64,54.88 85.55,54.96 85.55,55.29 85.67,55.4 85.94,55.4 86.14,55.6 86.14,56.09 85.93,56.3 85.64,56.3 85.54,56.4 85.54,56.7 85.66,56.81 86.34,56.81 86.56,57.04 86.56,57.74 86.36,57.95 85.69,57.95 85.59,58.05 85.59,58.35 85.71,58.46 86.36,58.46 86.56,58.67 86.56,59.52 92,64.95 92.69,64.95 95.59,67.85 95.59,68.37 96.57,69.35 97.25,69.35 97.87,68.73 98.24,68.73 98.5,68.98 98.5,69.12 v2(98.92,69.54)
  BOTTOM w0.102: RAM1.B7 v2(86.74,42.9) ; v2(98.92,69.54) CPU1.H30
M_A_DQS_DP7: length 43.7
  L6 w0.089: v2(100.8,69.56) 100.93,69.56 101.03,69.46 101.03,66.9 100.06,65.93 98.99,65.93 95.98,62.92 95.17,62.92 93.75,61.5 93.75,57.01 93.75,57.01 93.75,55.33 93.46,55.04 93.3,55.04 92.95,55.4 92.65,55.4 92.29,55.04 92.29,54.76 92.66,54.4 92.66,54.23 92.44,54.02 92.26,54.02 91.91,54.37 91.61,54.37 91.26,54.01 91.26,53.73 91.62,53.36 91.62,53.22 91.12,52.71 91.12,47.41 91.36,47.17 91.89,47.17 92.04,47.03 92.04,46.5 91.94,46.4 91.32,46.4 91.12,46.2 91.12,45.74 91.34,45.51 91.94,45.51 92.04,45.42 92.04,44.65 91.95,44.57 91.67,44.57 91.42,44.31 91.42,42.76 90.06,41.41 90.06,40.82 89.58,40.35 89.51,40.35 v2(89.1,39.94)
  BOTTOM w0.102: v2(89.1,39.94) 89.37,39.67 89.37,39.37 89.88,38.86 90,38.85 RAM1.G3 ; v2(100.8,69.56) 101.08,69.84 CPU1.N30
M_A_ODT0: length 101.2
  TOP w0.14: RN1207.4 v2(48.79,36.04)
  L2SGND w0.089: v2(88.52,37) 89.27,37.74 93.84,37.74 98.29,42.18 98.29,53.74 100.52,55.97 100.52,64.08 104.05,67.61 107.33,67.61 107.58,67.86 107.58,69.11 v2(108.07,69.59)
  L4SGND w0.142: v2(48.79,36.04) 50.07,37.31 53.03,37.31 53.38,37.66 57.41,37.66 v2(58.07,37) 58.07,36.98 58.52,36.54 59.65,36.54 60.65,37.53 67.69,37.53 v2(68.22,37) 68.22,36.98 68.67,36.54 69.81,36.54 70.92,37.66 77.71,37.66 v2(78.37,37) 78.37,36.98 78.82,36.54 79.95,36.54 81.07,37.66 87.86,37.66 v2(88.52,37)
  BOTTOM w0.14: RAM1.K3 89.88,36.57 89.88,36.95 89.35,37.47 89,37.47 88.98,37.45 88.97,37.45 88.71,37.19 88.71,37.18 v2(88.52,37) ; v2(58.07,37) 58.07,37.01 58.52,37.46 58.9,37.46 59.27,37.09 59.27,36.73 RAM4.K3 ; v2(68.22,37) 68.22,37.01 68.67,37.46 69.05,37.46 69.52,36.99 69.52,36.63 RAM3.K3 ; CPU1.AE31 v2(108.07,69.59) ; v2(78.37,37) 78.37,37.03 78.81,37.47 79.2,37.47 79.57,37.11 79.57,36.73 RAM2.K3
M_A_PARITY: length 95.7
  TOP w0.14: RN1204.1 v2(52.22,29.53)
  L2SGND w0.089: v2(105.3,69.51) 106.25,69.51 106.75,70.02 108.21,70.02 108.48,69.75 108.48,66.83 104.46,62.81 104.46,56.36 100.98,52.88 100.98,41.34 93.13,33.5 92.6,33.5 90.32,31.22 v2(90.32,30.68)
  L4SGND w0.142: v2(90.32,30.68) 90.01,30.98 88.91,30.98 88.3,30.37 87.35,30.37 86.96,30.76 86.33,30.76 85.78,30.21 83.98,30.21 83.53,30.66 82.72,30.66 82.27,30.21 80.61,30.21 80.17,30.66 v2(80.17,30.68) 78.17,30.68 77.94,30.44 77.13,30.44 76.81,30.76 76.15,30.76 75.65,30.25 72.16,30.25 72.11,30.21 70.46,30.21 70.02,30.66 v2(70.02,30.68) 68.02,30.68 67.79,30.44 66.98,30.44 66.66,30.76 66,30.76 65.5,30.25 62.01,30.25 61.96,30.21 60.31,30.21 59.87,30.66 v2(59.87,30.68) 57.87,30.68 57.64,30.44 56.83,30.44 56.51,30.76 55.93,30.76 55.29,30.12 53.42,30.12 53.3,30 52.68,30 v2(52.22,29.53)
  BOTTOM w0.14: RAM1.T3 v2(90.32,30.68) ; RAM4.T3 59.87,31.27 v2(59.87,30.68) ; v2(80.17,30.68) 80.17,31.27 RAM2.T3 ; CPU1.W31 v2(105.3,69.51) ; RAM3.T3 70.02,31.27 v2(70.02,30.68)
M_B_A0: length 96.4
  L4SGND w0.142: v2(146.72,31.38) 146.64,31.46 146.08,31.46 145.82,31.72 142.38,31.72 142.37,31.71 142.1,31.71 v2(141.66,32.15) 141.23,31.72 132.23,31.72 132.22,31.71 131.95,31.71 v2(131.51,32.15) 131.07,31.72 122.08,31.72 122.07,31.71 121.8,31.71 v2(121.36,32.15) 120.93,31.72 111.93,31.72 111.92,31.71 111.65,31.71 v2(111.21,32.15) 110.82,31.76 106.92,31.76 105.31,33.37 105.31,45.24 109.38,49.31 109.38,49.52 108.92,49.98 108.92,50.2 109.16,50.44 109.36,50.44 109.83,49.97 110.03,49.97 110.27,50.21 110.27,51.16 110.13,51.31 109.6,51.31 109.46,51.45 109.46,51.73 109.6,51.87 110.13,51.87 110.27,52.02 110.27,52.3 110.13,52.44 109.6,52.44 109.46,52.59 109.46,52.87 109.6,53.01 110.13,53.01 110.27,53.15 110.27,53.51 110.12,53.66 109.6,53.66 109.46,53.81 109.46,61.51 109.39,61.58 109.39,63.52 109.5,63.64 109.81,63.64 109.95,63.49 109.95,62.01 v2(110.39,61.57)
  BOTTOM w0.076: CPU1.AG36 109.82,66.14 109.96,65.89 109.96,65.89 110.08,65.66 110.08,65.4 109.84,65.16 109.84,64.53 109.98,64.39 109.98,63.86 109.98,63.53 109.99,63.53 109.99,62.98 109.92,62.91 109.92,62.04 v2(110.39,61.57)
  BOTTOM w0.14: v2(131.51,32.15) 131.51,32.21 132.2,32.9 RAM8.P3 ; RN1304.4 147.31,31.97 v2(146.72,31.38) ; RAM6.P3 111.9,32.9 111.21,32.21 v2(111.21,32.15) ; RAM5.P3 122.05,32.9 121.36,32.21 v2(121.36,32.15) ; RAM7.P3 142.35,32.9 141.66,32.21 v2(141.66,32.15)
M_B_A1: length 98.5
  L6 w0.142: v2(108.89,60.65) 108.44,60.2 108.44,58.24 108.14,57.94 107.81,57.94 107.48,57.6 107.48,52.29 104.36,49.17 104.36,47.91 104.21,47.77 103.79,47.77 103.65,47.63 103.65,47.31 103.79,47.16 104.42,47.16 104.56,47.02 104.56,46.74 104.42,46.6 103.79,46.6 103.65,46.45 103.65,46.17 103.79,46.03 104.42,46.03 104.56,45.88 104.56,45.6 104.42,45.46 103.79,45.46 103.65,45.32 103.65,45.03 103.79,44.89 104.42,44.89 104.56,44.75 104.56,44.46 104.42,44.32 103.79,44.32 103.65,44.18 103.65,43.89 103.79,43.75 104.42,43.75 104.56,43.61 104.56,43.32 104.42,43.18 103.79,43.18 103.65,43.04 103.65,42.76 103.79,42.61 104.42,42.61 104.56,42.47 104.56,42.19 104.42,42.04 103.79,42.04 103.65,41.9 103.65,41.62 103.79,41.47 104.42,41.47 104.56,41.33 104.56,41.05 104.42,40.91 103.79,40.91 103.65,40.76 103.65,40.48 103.79,40.34 104.42,40.34 104.56,40.19 104.56,39.91 104.42,39.77 103.79,39.77 103.65,39.63 103.65,39.34 103.79,39.2 104.42,39.2 104.56,39.06 104.56,38.77 104.42,38.63 103.79,38.63 103.65,38.49 103.65,38.2 103.79,38.06 104.42,38.06 104.56,37.92 104.56,37.63 104.42,37.49 103.79,37.49 103.65,37.35 103.65,36.99 108.59,32.05 109.15,32.05 v2(109.6,32.5) 110.44,32.5 110.9,32.96 113.14,32.96 113.96,32.14 118.27,32.14 118.38,32.04 119.29,32.04 v2(119.75,32.5) 120.59,32.5 121.05,32.96 123.29,32.96 124.11,32.14 128.42,32.14 128.53,32.04 129.44,32.04 v2(129.9,32.5) 130.74,32.5 131.2,32.96 133.44,32.96 134.09,32.31 135.9,32.31 136.06,32.14 138.57,32.14 138.68,32.04 139.59,32.04 v2(140.05,32.5) 140.89,32.5 141.35,32.96 143.59,32.96 144.1,32.45 145.85,32.45 146.11,32.71 v2(146.72,32.71)
  BOTTOM w0.076: CPU1.AG35 109.72,66.75 109.6,66.41 109.6,66.4 109.56,66.29 109.56,66.1 109.6,65.99 109.6,65.75 109.51,65.51 109.51,64.38 109.65,64.24 109.65,63.63 109.51,63.49 109.51,61.69 109.56,61.64 109.56,61.31 108.9,60.65 v2(108.89,60.65)
  BOTTOM w0.14: RN1306.2 147.31,33.3 v2(146.72,32.71) ; v2(140.05,32.5) RAM7.P7 ; v2(119.75,32.5) RAM5.P7 ; v2(129.9,32.5) RAM8.P7 ; v2(109.6,32.5) RAM6.P7
M_B_A2: length 99.5
  L6 w0.142: v2(150.15,31.97) 150.03,31.85 142.62,31.85 v2(142.29,32.18) 142.29,32.13 141.61,31.45 138.44,31.45 138.33,31.56 134.36,31.56 134.2,31.72 132.6,31.72 v2(132.14,32.18) 132.14,32.13 131.46,31.45 128.29,31.45 128.18,31.56 123.75,31.56 123.28,32.03 122.75,32.03 122.61,32.18 v2(121.99,32.18) 121.99,32.13 121.49,31.63 120.22,31.63 120.04,31.45 118.14,31.45 118.03,31.56 113.6,31.56 113.13,32.03 112.6,32.03 112.46,32.18 v2(111.84,32.18) 111.84,32.15 111.19,31.5 106.68,31.5 101.85,36.33 101.85,39.1 101.99,39.25 102.79,39.25 102.93,39.38 102.93,39.68 102.79,39.81 102.02,39.81 101.85,39.98 101.85,40.32 101.99,40.46 102.84,40.46 102.93,40.55 102.93,40.93 102.84,41.03 102.02,41.03 101.85,41.19 101.85,41.45 101.99,41.6 102.84,41.6 102.93,41.69 102.93,42.07 102.84,42.16 102.02,42.16 101.85,42.33 101.85,42.59 101.99,42.73 102.84,42.73 102.93,42.83 102.93,43.21 102.84,43.3 102.02,43.3 101.85,43.47 101.85,45.34 101.99,45.48 102.34,45.48 102.48,45.63 102.48,46.02 102.32,46.17 101.99,46.17 101.85,46.32 101.85,47.72 106.69,52.57 106.69,58.57 108.17,60.04 108.17,60.55 v2(108.99,61.37)
  BOTTOM w0.076: v2(108.99,61.37) 109.35,61.73 109.35,63.56 109.48,63.69 109.48,64.16 109.35,64.29 109.35,65.54 109.43,65.78 109.43,65.96 109.39,66.08 109.39,66.32 109.43,66.43 109.43,66.91 CPU1.AF34
  BOTTOM w0.14: RN1307.3 150.74,31.38 v2(150.15,31.97) ; RAM5.R3 122.07,32.1 121.99,32.18 v2(121.99,32.18) ; v2(111.84,32.18) 111.84,32.18 111.92,32.1 RAM6.R3 ; RAM8.R3 132.22,32.1 132.14,32.18 v2(132.14,32.18) ; RAM7.R3 142.37,32.1 142.29,32.18 v2(142.29,32.18)
M_B_A3: length 99.2
  L4SGND w0.142: v2(110.36,60.36) 110.63,60.09 110.63,59.64 110.49,59.49 109.96,59.49 109.82,59.35 109.82,59.07 109.96,58.93 110.49,58.93 110.63,58.78 110.63,58.5 110.49,58.36 109.96,58.36 109.82,58.21 109.82,57.93 109.96,57.79 110.49,57.79 110.63,57.65 110.63,57.36 110.49,57.22 109.96,57.22 109.82,57.08 109.82,56.79 109.96,56.65 110.49,56.65 110.63,56.51 110.63,56.22 110.49,56.08 109.96,56.08 109.82,55.94 109.82,55.65 109.96,55.51 110.49,55.51 110.63,55.37 110.63,55.09 110.49,54.94 109.96,54.94 109.82,54.8 109.82,54.52 109.96,54.37 110.49,54.37 110.63,54.23 110.63,50.06 108.91,48.34 108.91,48.14 109.27,47.78 109.27,47.58 109.07,47.38 108.87,47.38 108.51,47.73 108.31,47.73 108.11,47.53 108.11,47.33 108.47,46.97 108.47,46.77 108.27,46.57 108.06,46.57 107.71,46.93 107.5,46.93 107.18,46.61 107.18,46.41 107.49,46.1 107.49,45.9 107.29,45.7 107.09,45.7 106.78,46.01 106.58,46.01 105.74,45.16 105.74,44.71 105.88,44.57 106.85,44.57 107.02,44.39 107.02,44.14 106.85,43.96 105.85,43.96 105.67,43.78 105.67,43.39 105.81,43.25 106.18,43.25 106.33,43.11 106.33,42.7 106.19,42.56 105.83,42.56 105.67,42.4 105.67,42.02 105.81,41.88 106.43,41.88 106.57,41.73 106.57,41.36 106.43,41.22 105.81,41.22 105.67,41.07 105.67,34.42 106.32,33.76 109.45,33.76 109.48,33.73 110.19,33.73 v2(110.36,33.9) 110.36,33.9 110.8,34.35 111.19,34.35 111.59,33.95 113.18,33.95 113.29,34.06 113.91,34.06 114.25,33.72 117.91,33.72 117.96,33.76 119.6,33.76 119.65,33.72 120.33,33.72 v2(120.51,33.9) 120.51,33.9 120.95,34.35 121.34,34.35 121.74,33.95 123.33,33.95 123.44,34.06 124.06,34.06 124.4,33.72 128.06,33.72 128.11,33.76 129.75,33.76 129.8,33.72 130.48,33.72 v2(130.66,33.9) 130.66,33.9 131.1,34.35 131.49,34.35 131.89,33.95 133.48,33.95 133.59,34.06 134.21,34.06 134.6,33.67 134.93,33.67 134.96,33.69 135.58,33.69 135.6,33.67 138.16,33.67 138.26,33.76 139.9,33.76 139.95,33.72 140.63,33.72 v2(140.81,33.9) 140.81,33.9 141.25,34.35 141.64,34.35 142.04,33.95 143.63,33.95 143.74,34.06 144.36,34.06 144.72,33.7 146.46,33.7 v2(146.73,33.97)
  BOTTOM w0.076: v2(110.36,60.36) 109.89,60.83 109.89,61.61 109.74,61.77 109.74,63.48 109.81,63.55 109.81,64.32 109.68,64.45 109.68,65.4 CPU1.AG37
  BOTTOM w0.14: RAM8.N7 130.46,33.7 v2(130.66,33.9) ; v2(110.36,33.9) 110.16,33.7 RAM6.N7 ; v2(140.81,33.9) 140.61,33.7 RAM7.N7 ; RAM5.N7 120.31,33.7 v2(120.51,33.9) ; v2(146.73,33.97) 147.19,34.43 147.63,34.43 147.67,34.38 RN1306.4
M_B_A4: length 103.1
  L2SGND w0.089: v2(110.99,33.88) 110.58,33.47 108.49,33.47 107.95,34 106.74,34 104.21,36.53 104.21,47.65 109.44,52.88 109.44,54.48 109.3,54.61 108.48,54.61 108.39,54.7 108.39,54.88 108.48,54.97 109.3,54.97 109.39,55.06 109.39,55.23 109.3,55.32 108.48,55.32 108.39,55.41 108.39,55.59 108.48,55.68 109.3,55.68 109.39,55.77 109.39,55.95 109.3,56.03 108.48,56.03 108.39,56.12 108.39,56.3 108.48,56.39 109.3,56.39 109.39,56.48 109.39,56.66 109.3,56.75 108.48,56.75 108.39,56.83 108.39,57.01 108.48,57.1 109.3,57.1 109.39,57.19 109.39,57.37 109.3,57.46 108.48,57.46 108.39,57.55 108.39,57.72 108.48,57.81 109.3,57.81 109.39,57.9 109.39,58.08 109.3,58.17 108.48,58.17 108.39,58.26 108.39,58.43 108.48,58.52 109.3,58.52 109.39,58.61 109.39,58.79 109.3,58.88 108.48,58.88 108.39,58.97 108.39,59.15 108.48,59.23 109.3,59.23 109.39,59.32 109.39,62.22 v2(108.95,62.65)
  L6 w0.142: v2(150.15,34.38) 149.29,33.52 146.92,33.52 146.92,33.52 146.54,33.52 146.54,33.52 146.52,33.52 146.33,33.72 144.74,33.72 144.73,33.72 144.69,33.76 143.86,33.76 143.75,33.65 141.67,33.65 v2(141.44,33.88) 141.44,33.88 141,33.43 138.97,33.43 138.64,33.76 138.26,33.76 138.21,33.72 134.14,33.72 134.09,33.76 132.52,33.76 132.41,33.65 131.52,33.65 v2(131.29,33.88) 131.29,33.88 130.85,33.43 128.82,33.43 128.49,33.76 128.11,33.76 128.06,33.72 123.99,33.72 123.94,33.76 122.37,33.76 122.26,33.65 121.37,33.65 v2(121.14,33.88) 121.14,33.88 120.7,33.43 118.67,33.43 118.34,33.76 117.96,33.76 117.91,33.72 113.84,33.72 113.79,33.76 112.22,33.76 112.11,33.65 111.22,33.65 v2(110.99,33.88)
  BOTTOM w0.076: CPU1.AE35 108.78,66.59 108.78,66.1 108.74,65.99 108.74,65.75 108.8,65.58 108.8,64.53 108.49,64.22 108.49,63.12 v2(108.95,62.65)
  BOTTOM w0.14: RAM7.N3 141.63,33.7 v2(141.44,33.88) ; v2(150.15,34.38) 150.74,33.8 RN1303.3 ; RAM8.N3 131.48,33.7 v2(131.29,33.88) ; RAM6.N3 111.18,33.7 v2(110.99,33.88) ; RAM5.N3 121.33,33.7 v2(121.14,33.88)
M_B_A5: length 101.7
  L2SGND w0.089: v2(108.8,32.5) 108.13,32.5 107.26,33.37 105.74,33.37 103.56,35.55 103.56,49.01 105.07,50.52 105.07,50.65 104.04,51.68 104.04,51.8 104.17,51.93 104.3,51.93 105.33,50.9 105.45,50.9 105.58,51.02 105.58,51.15 104.55,52.18 104.55,52.3 104.67,52.43 104.8,52.43 105.83,51.4 105.95,51.4 106.08,51.53 106.08,51.65 105.05,52.68 105.05,52.81 105.18,52.93 105.3,52.93 106.33,51.9 106.46,51.9 106.58,52.03 106.58,52.15 105.55,53.18 105.55,53.31 105.68,53.44 105.8,53.44 106.83,52.41 106.96,52.41 107.18,52.62 107.18,58.82 107.8,59.45 107.99,59.45 108.48,59.94 108.48,62.87 v2(108.95,63.34)
  L4SGND w0.142: v2(108.8,32.5) 109.27,32.03 109.79,32.03 110.4,32.64 112.03,32.64 112.3,32.37 112.3,32.33 112.6,32.03 118.48,32.03 v2(118.95,32.5) 119.42,32.03 119.94,32.03 120.55,32.64 122.18,32.64 122.45,32.37 122.45,32.33 122.75,32.03 128.63,32.03 v2(129.1,32.5) 129.57,32.03 130.09,32.03 130.7,32.64 132.33,32.64 132.6,32.37 132.6,32.33 132.9,32.03 138.78,32.03 v2(139.25,32.5) 139.72,32.03 140.24,32.03 140.85,32.64 142.48,32.64 142.75,32.37 142.75,32.33 143.05,32.03 147.88,32.03 148.65,32.81 150.38,32.81 v2(150.87,33.3)
  BOTTOM w0.076: v2(108.95,63.34) 108.93,63.34 108.66,63.61 108.66,64.14 108.97,64.45 108.97,65.61 108.9,65.78 108.9,65.96 109.07,66.42 CPU1.AF35
  BOTTOM w0.14: RAM7.P8 v2(139.25,32.5) ; RAM6.P8 v2(108.8,32.5) ; RN1303.2 v2(150.87,33.3) ; RAM5.P8 v2(118.95,32.5) ; RAM8.P8 v2(129.1,32.5)
M_B_A6: length 98.3
  L6 w0.142: v2(150.15,33.3) 149.06,32.2 146.12,32.2 146.07,32.16 143.58,32.16 v2(143.25,32.5) 143.1,32.64 141.45,32.64 140.55,31.74 138.56,31.74 138.45,31.85 135.07,31.85 134.7,31.85 134.54,32.02 133.58,32.02 v2(133.1,32.5) 132.95,32.64 131.3,32.64 130.4,31.74 128.41,31.74 128.3,31.85 123.87,31.85 123.23,32.5 v2(122.95,32.5) 122.8,32.64 121.15,32.64 120.43,31.92 120.1,31.92 119.92,31.74 118.26,31.74 118.15,31.85 113.72,31.85 113.08,32.5 v2(112.8,32.5) 112.66,32.63 110.99,32.63 110.47,32.11 109.86,32.11 109.52,31.77 106.91,31.77 105.61,33.07 105.61,33.28 106.1,33.76 106.1,33.97 105.9,34.17 105.69,34.17 105.2,33.68 105,33.68 104.8,33.88 104.8,34.08 105.29,34.57 105.29,34.77 105.09,34.97 104.89,34.97 104.4,34.48 104.2,34.48 103.95,34.74 103.95,34.94 104.47,35.46 104.47,35.66 104.27,35.86 104.07,35.86 103.54,35.34 103.34,35.34 103.14,35.54 103.14,35.74 103.66,36.27 103.66,36.47 103.46,36.67 103.26,36.67 102.74,36.14 102.54,36.14 102.24,36.44 102.24,36.64 103.29,37.68 103.29,43.64 103.15,43.78 102.34,43.78 102.21,43.92 102.21,44.22 102.34,44.35 103.15,44.35 103.29,44.49 103.29,45.73 103.15,45.88 103.07,45.88 102.93,46.02 102.93,46.3 103.07,46.44 103.15,46.44 103.29,46.59 103.29,46.87 103.15,47.01 103.07,47.01 102.93,47.16 102.93,48.3 107.1,52.47 107.1,58.18 v2(107.96,59.05)
  BOTTOM w0.076: v2(107.96,59.05) 107.96,59.05 108.34,59.43 108.34,63.03 108.33,63.05 108.33,64.28 108.34,64.3 108.34,64.35 108.63,64.63 108.63,65.43 CPU1.AE37
  BOTTOM w0.14: v2(133.1,32.5) RAM8.P2 ; v2(122.95,32.5) RAM5.P2 ; v2(150.15,33.3) 150.74,32.71 RN1303.1 ; v2(143.25,32.5) RAM7.P2 ; v2(112.8,32.5) RAM6.P2
M_B_A7: length 108.1
  L4SGND w0.142: v2(108.07,70.83) 108.85,70.83 109.41,70.27 109.41,67.88 108.44,66.91 108.44,59.51 108.58,59.37 108.96,59.37 109.1,59.23 109.1,58.94 108.96,58.8 108.58,58.8 108.44,58.66 108.44,58.38 108.58,58.23 108.96,58.23 109.1,58.09 109.1,57.81 108.96,57.66 108.58,57.66 108.44,57.52 108.44,57.24 108.58,57.1 108.96,57.1 109.1,56.95 109.1,56.67 108.96,56.53 108.58,56.53 108.44,56.38 108.44,56.1 108.58,55.96 108.96,55.96 109.1,55.82 109.1,55.53 108.96,55.39 108.58,55.39 108.44,55.25 108.44,54.96 108.58,54.82 108.96,54.82 109.1,54.68 109.1,54.39 108.96,54.25 108.58,54.25 108.44,54.11 108.44,53.82 108.58,53.68 108.96,53.68 109.1,53.54 109.1,53.26 108.96,53.11 108.58,53.11 108.44,52.97 108.44,52.69 108.58,52.54 108.96,52.54 109.1,52.4 109.1,52.12 108.96,51.98 108.58,51.98 108.44,51.83 108.44,48.88 105.19,45.63 105.19,45.61 105.17,45.61 104.95,45.39 104.95,33.22 106.91,31.26 107.07,31.26 v2(107.66,30.68) 108.41,31.42 112.04,31.42 112.05,31.43 116.5,31.43 117.17,30.76 v2(117.17,30.74) 117.85,31.42 122.19,31.42 122.2,31.43 126.63,31.43 127.32,30.75 v2(127.32,30.74) 128,31.42 130.6,31.42 130.76,31.26 130.76,30.92 130.93,30.75 131.26,30.75 131.42,30.92 131.42,31.26 131.59,31.42 132.34,31.42 132.35,31.43 136.78,31.43 137.47,30.75 v2(137.47,30.74) 138.15,31.42 142.49,31.42 142.5,31.43 145.64,31.43 146.15,30.92 147.78,30.92 148.37,31.51 150.4,31.51 v2(150.87,31.97)
  BOTTOM w0.14: RAM6.R8 107.98,31.68 107.98,31.14 107.66,30.82 v2(107.66,30.68) ; v2(117.17,30.74) 117.17,31.28 117.59,31.69 118.14,31.69 RAM5.R8 ; RN1307.4 v2(150.87,31.97) ; RAM7.R8 138.44,31.69 137.89,31.69 137.47,31.28 v2(137.47,30.74) ; v2(127.32,30.74) 127.32,31.28 127.74,31.69 128.29,31.69 RAM8.R8 ; CPU1.AC29 v2(108.07,70.83)
M_B_A8: length 100.6
  L6 w0.142: v2(150.15,30.88) 149.1,29.83 146.28,29.83 145.9,30.21 144.53,30.21 144.09,30.66 v2(144.09,30.68) 144.09,30.7 143.64,31.14 142.62,31.14 141.7,30.21 134.38,30.21 133.94,30.66 v2(133.94,30.68) 133.94,30.7 133.49,31.14 132.47,31.14 131.55,30.21 124.23,30.21 123.79,30.66 v2(123.79,30.68) 123.79,30.7 123.34,31.14 122.32,31.14 121.4,30.21 116.37,30.21 115.93,30.64 114.91,30.64 114.48,30.21 114.08,30.21 113.64,30.66 v2(113.64,30.68) 113.64,30.68 113.19,31.13 112.15,31.13 111.19,30.17 106.76,30.17 105.57,31.37 105.57,31.57 105.73,31.74 105.73,31.94 105.53,32.14 105.33,32.14 105.16,31.97 104.96,31.97 104.76,32.17 104.76,32.37 104.93,32.54 104.93,32.74 104.73,32.94 104.52,32.94 104.36,32.78 104.16,32.78 103.96,32.98 103.96,33.18 104.12,33.34 104.12,33.55 103.92,33.75 103.72,33.75 103.55,33.58 103.35,33.58 103.15,33.78 103.15,33.98 103.32,34.15 103.32,34.35 103.12,34.55 102.91,34.55 102.75,34.39 102.55,34.39 102.35,34.59 102.35,34.79 102.51,34.95 102.51,35.15 102.31,35.36 102.11,35.36 101.94,35.19 101.74,35.19 101.49,35.44 101.49,47.87 106.31,52.7 106.31,58.79 v2(107.74,60.22)
  BOTTOM w0.076: v2(107.74,60.22) 108.18,60.66 108.18,62.96 108.16,62.98 108.16,64.35 108.18,64.37 108.18,64.42 108.45,64.69 108.45,65.19 108.26,65.39 108.26,65.66 108.37,65.87 108.37,65.88 108.52,66.14 CPU1.AE36
  BOTTOM w0.14: v2(123.79,30.68) 123.76,30.71 123.76,31.6 123.52,31.84 123.52,31.94 RAM5.R2 ; RAM6.R2 113.2,32 113.61,31.6 113.61,30.71 v2(113.64,30.68) ; v2(133.94,30.68) 133.91,30.71 133.91,31.45 133.66,31.7 133.66,31.94 RAM8.R2 ; v2(150.15,30.88) 150.74,30.29 RN1307.1 ; v2(144.09,30.68) 144.06,30.71 144.06,31.6 143.82,31.84 143.82,31.94 RAM7.R2
M_B_A9: length 95.6
  L4SGND w0.142: v2(106.26,70.12) 108.14,70.12 108.5,69.76 108.5,67.63 107.47,66.6 107.47,61.8 107.28,61.61 107.28,52.16 104.23,49.12 104.23,32.19 106.47,29.95 109.12,29.95 v2(109.79,30.63)
  L6 w0.142: v2(109.79,30.63) 110.3,31.13 111.75,31.13 112.05,31.43 113.31,31.43 113.48,31.27 117.91,31.27 118.02,31.16 119.65,31.16 v2(119.91,30.9) 120.34,31.34 122.11,31.34 122.2,31.43 123.46,31.43 123.63,31.27 128.06,31.27 128.17,31.16 129.8,31.16 v2(130.06,30.9) 131.51,30.9 132.04,31.43 133.77,31.43 133.93,31.27 138.21,31.27 138.32,31.16 139.95,31.16 v2(140.21,30.9) 141.98,30.9 142.5,31.43 145.94,31.43 146.46,30.92 146.97,30.92 v2(147.44,31.38)
  BOTTOM w0.14: v2(130.06,30.9) 130.06,31.54 RAM8.R7 ; v2(119.91,30.9) 119.91,31.54 RAM5.R7 ; RAM7.R7 140.21,31.54 v2(140.21,30.9) ; RN1304.3 v2(147.44,31.38) ; RAM6.R7 109.76,31.54 109.76,30.66 v2(109.79,30.63) ; CPU1.AB29 v2(106.26,70.12)
M_B_A10: length 99.5
  L4SGND w0.142: v2(150.87,35.71) 150.33,35.17 148.48,35.17 147.74,34.44 146.54,34.44 146.11,34.01 144.85,34.01 144.45,34.41 v2(142.24,34.41) 142.01,34.64 139.59,34.64 139,34.06 138.14,34.06 138.09,34.01 134.67,34.01 134.27,34.41 v2(132.09,34.41) 131.86,34.64 129.44,34.64 128.85,34.06 127.12,34.06 127.07,34.01 124.52,34.01 124.12,34.41 v2(121.94,34.41) 121.71,34.64 119.29,34.64 118.7,34.06 116.97,34.06 116.92,34.01 114.37,34.01 113.97,34.41 v2(111.79,34.41) 111.57,34.63 109.12,34.63 108.67,34.18 106.57,34.18 105.94,34.81 105.94,37.08 106.08,37.22 106.08,37.23 106.65,37.23 106.8,37.37 106.8,37.79 106.62,37.97 106.35,37.97 106.21,38.11 106.21,39.07 106.35,39.21 107.3,39.21 107.51,39.42 107.51,39.83 107.37,39.97 106.26,39.97 106.11,40.12 106.11,40.65 106.25,40.8 107.37,40.8 107.51,40.94 107.51,44.18 107.46,44.23 107.46,45.36 107.99,45.89 108.19,45.89 109.45,44.63 109.65,44.63 110.02,45 110.02,45.26 108.9,46.37 108.9,46.7 109.91,47.71 109.91,48.14 110.99,49.22 110.99,63.75 111.27,64.03 111.27,64.71 109.86,66.12 109.65,66.12 109.21,65.68 109.21,65.48 v2(110.39,64.31)
  BOTTOM w0.076: v2(110.39,64.31) 110.01,64.69 110.01,65.08 110.25,65.32 110.25,65.7 110.12,65.93 110.12,66.87 CPU1.AG34
  BOTTOM w0.14: v2(121.94,34.41) 122.03,34.5 RAM5.M3 ; RN1305.2 v2(150.87,35.71) ; v2(111.79,34.41) 111.88,34.5 RAM6.M3 ; RAM8.M3 132.18,34.5 v2(132.09,34.41) ; RAM7.M3 142.33,34.5 v2(142.24,34.41)
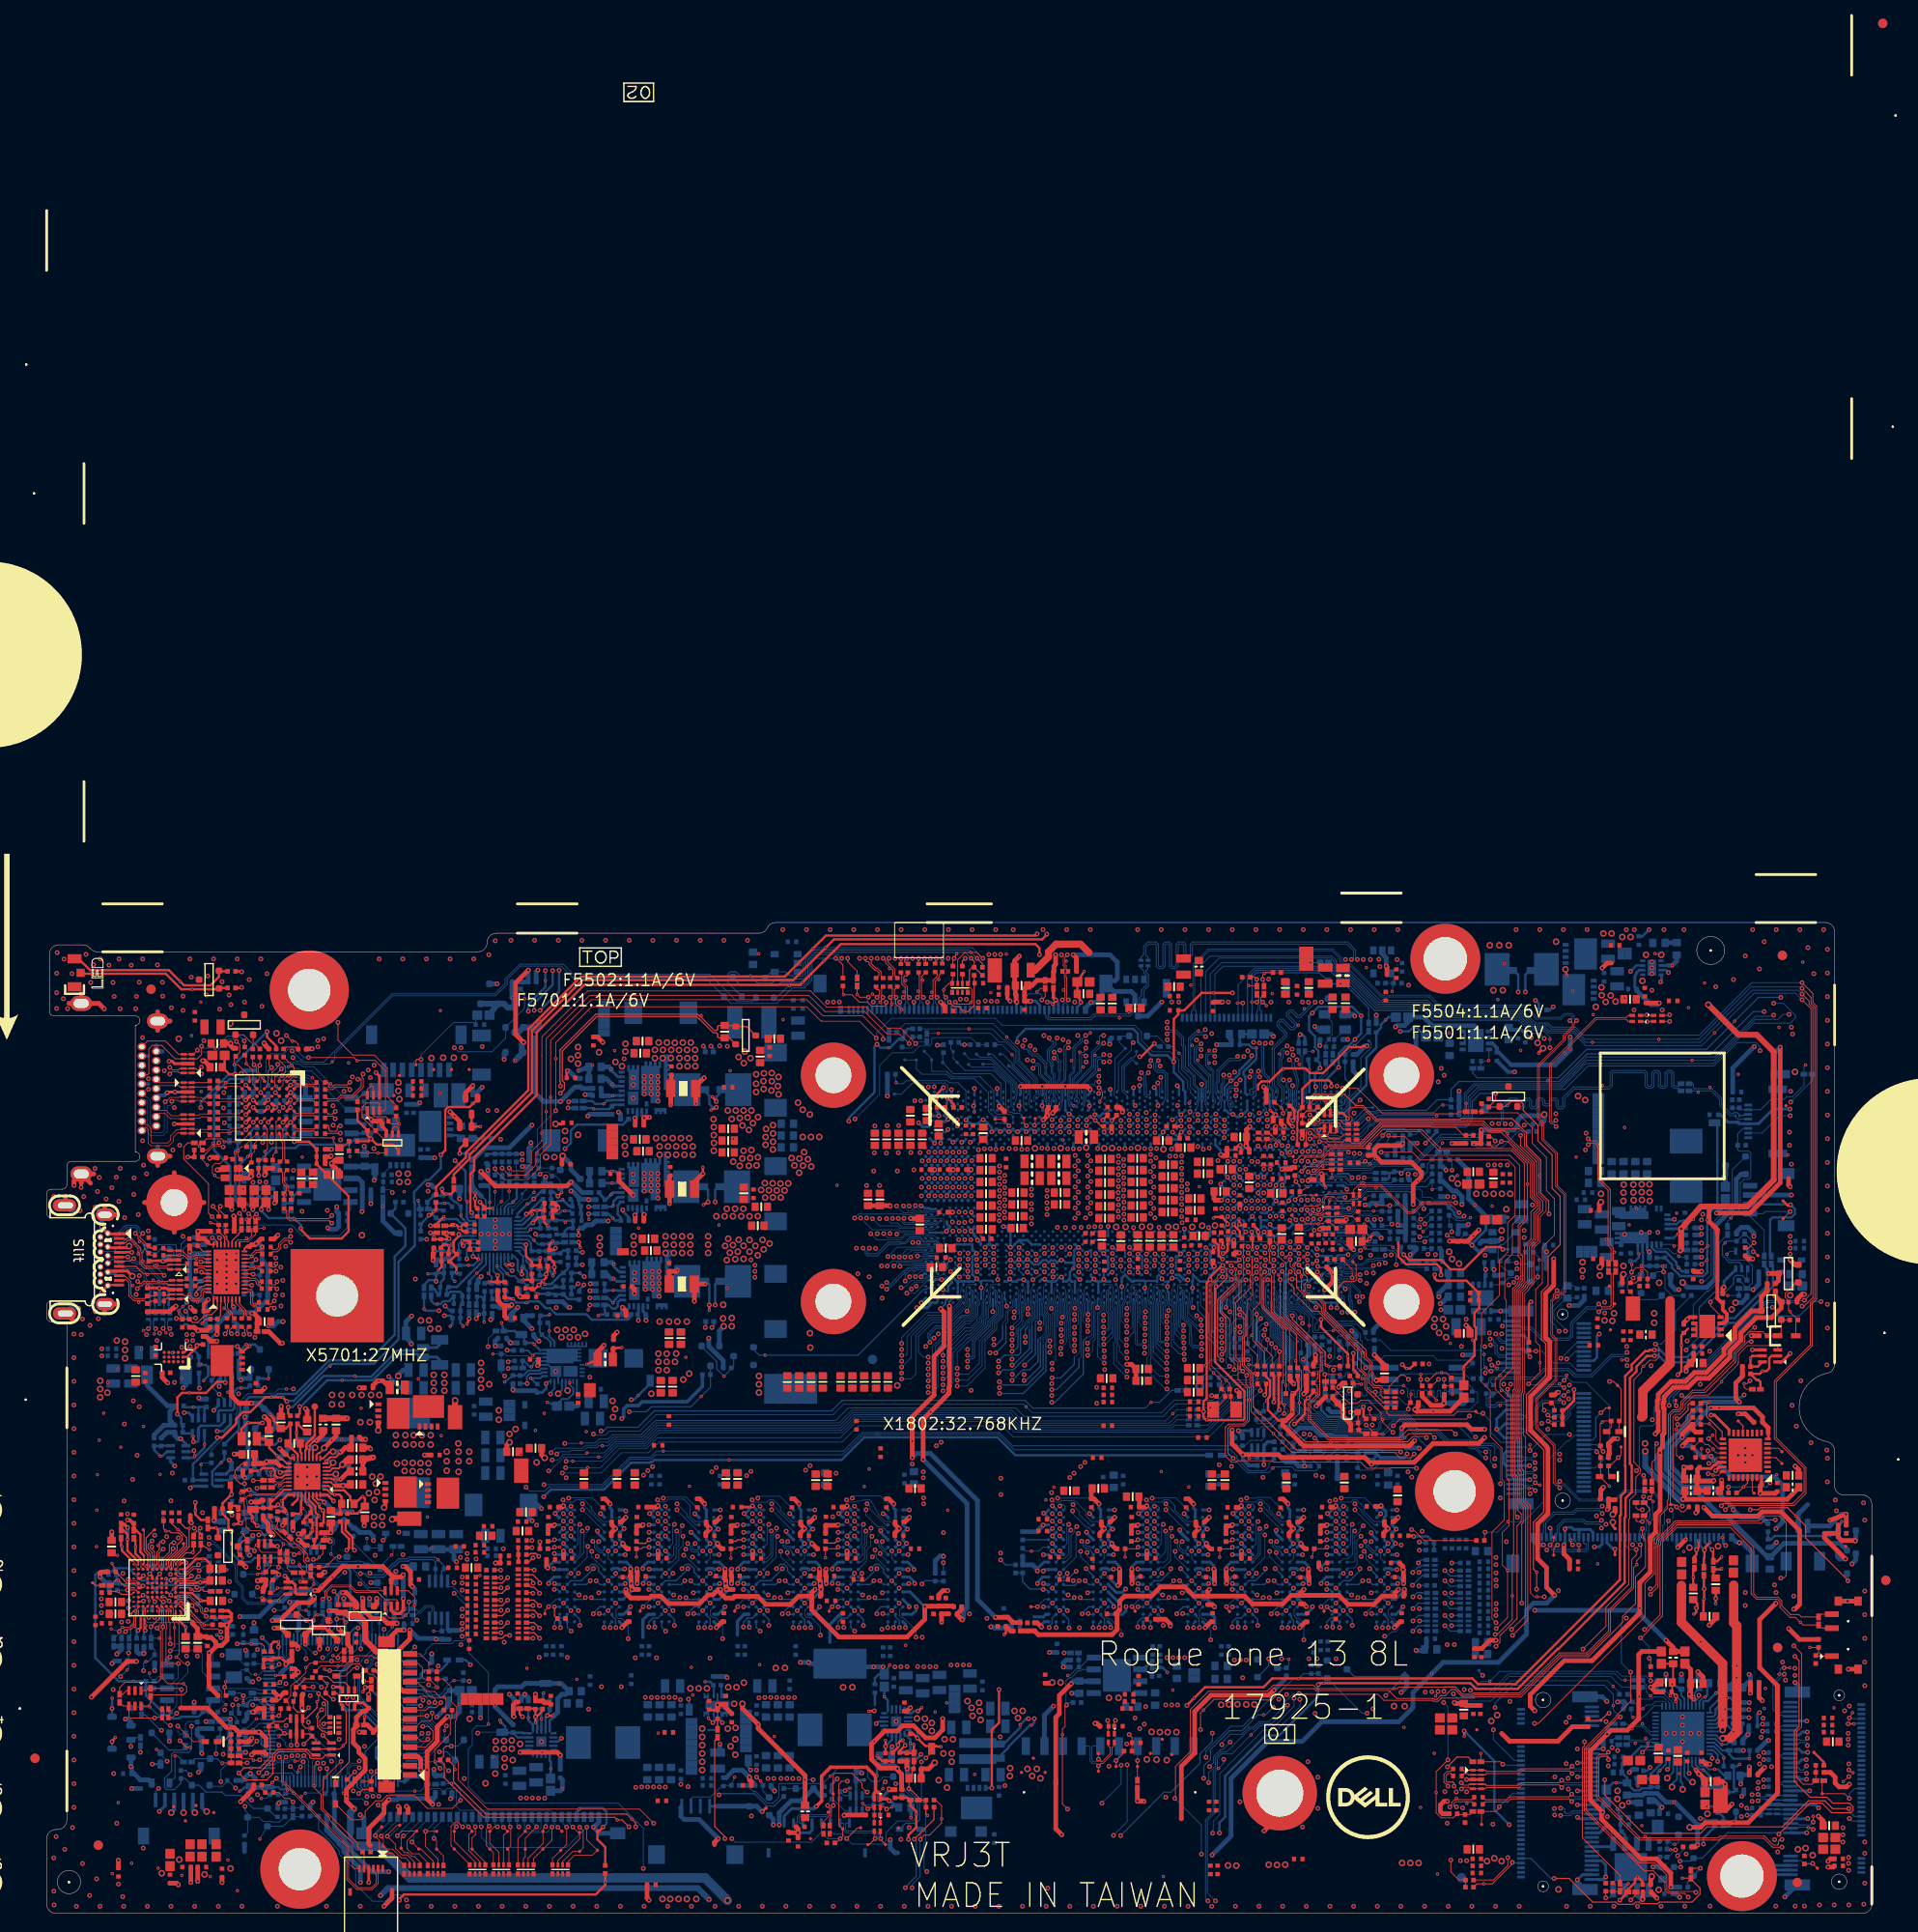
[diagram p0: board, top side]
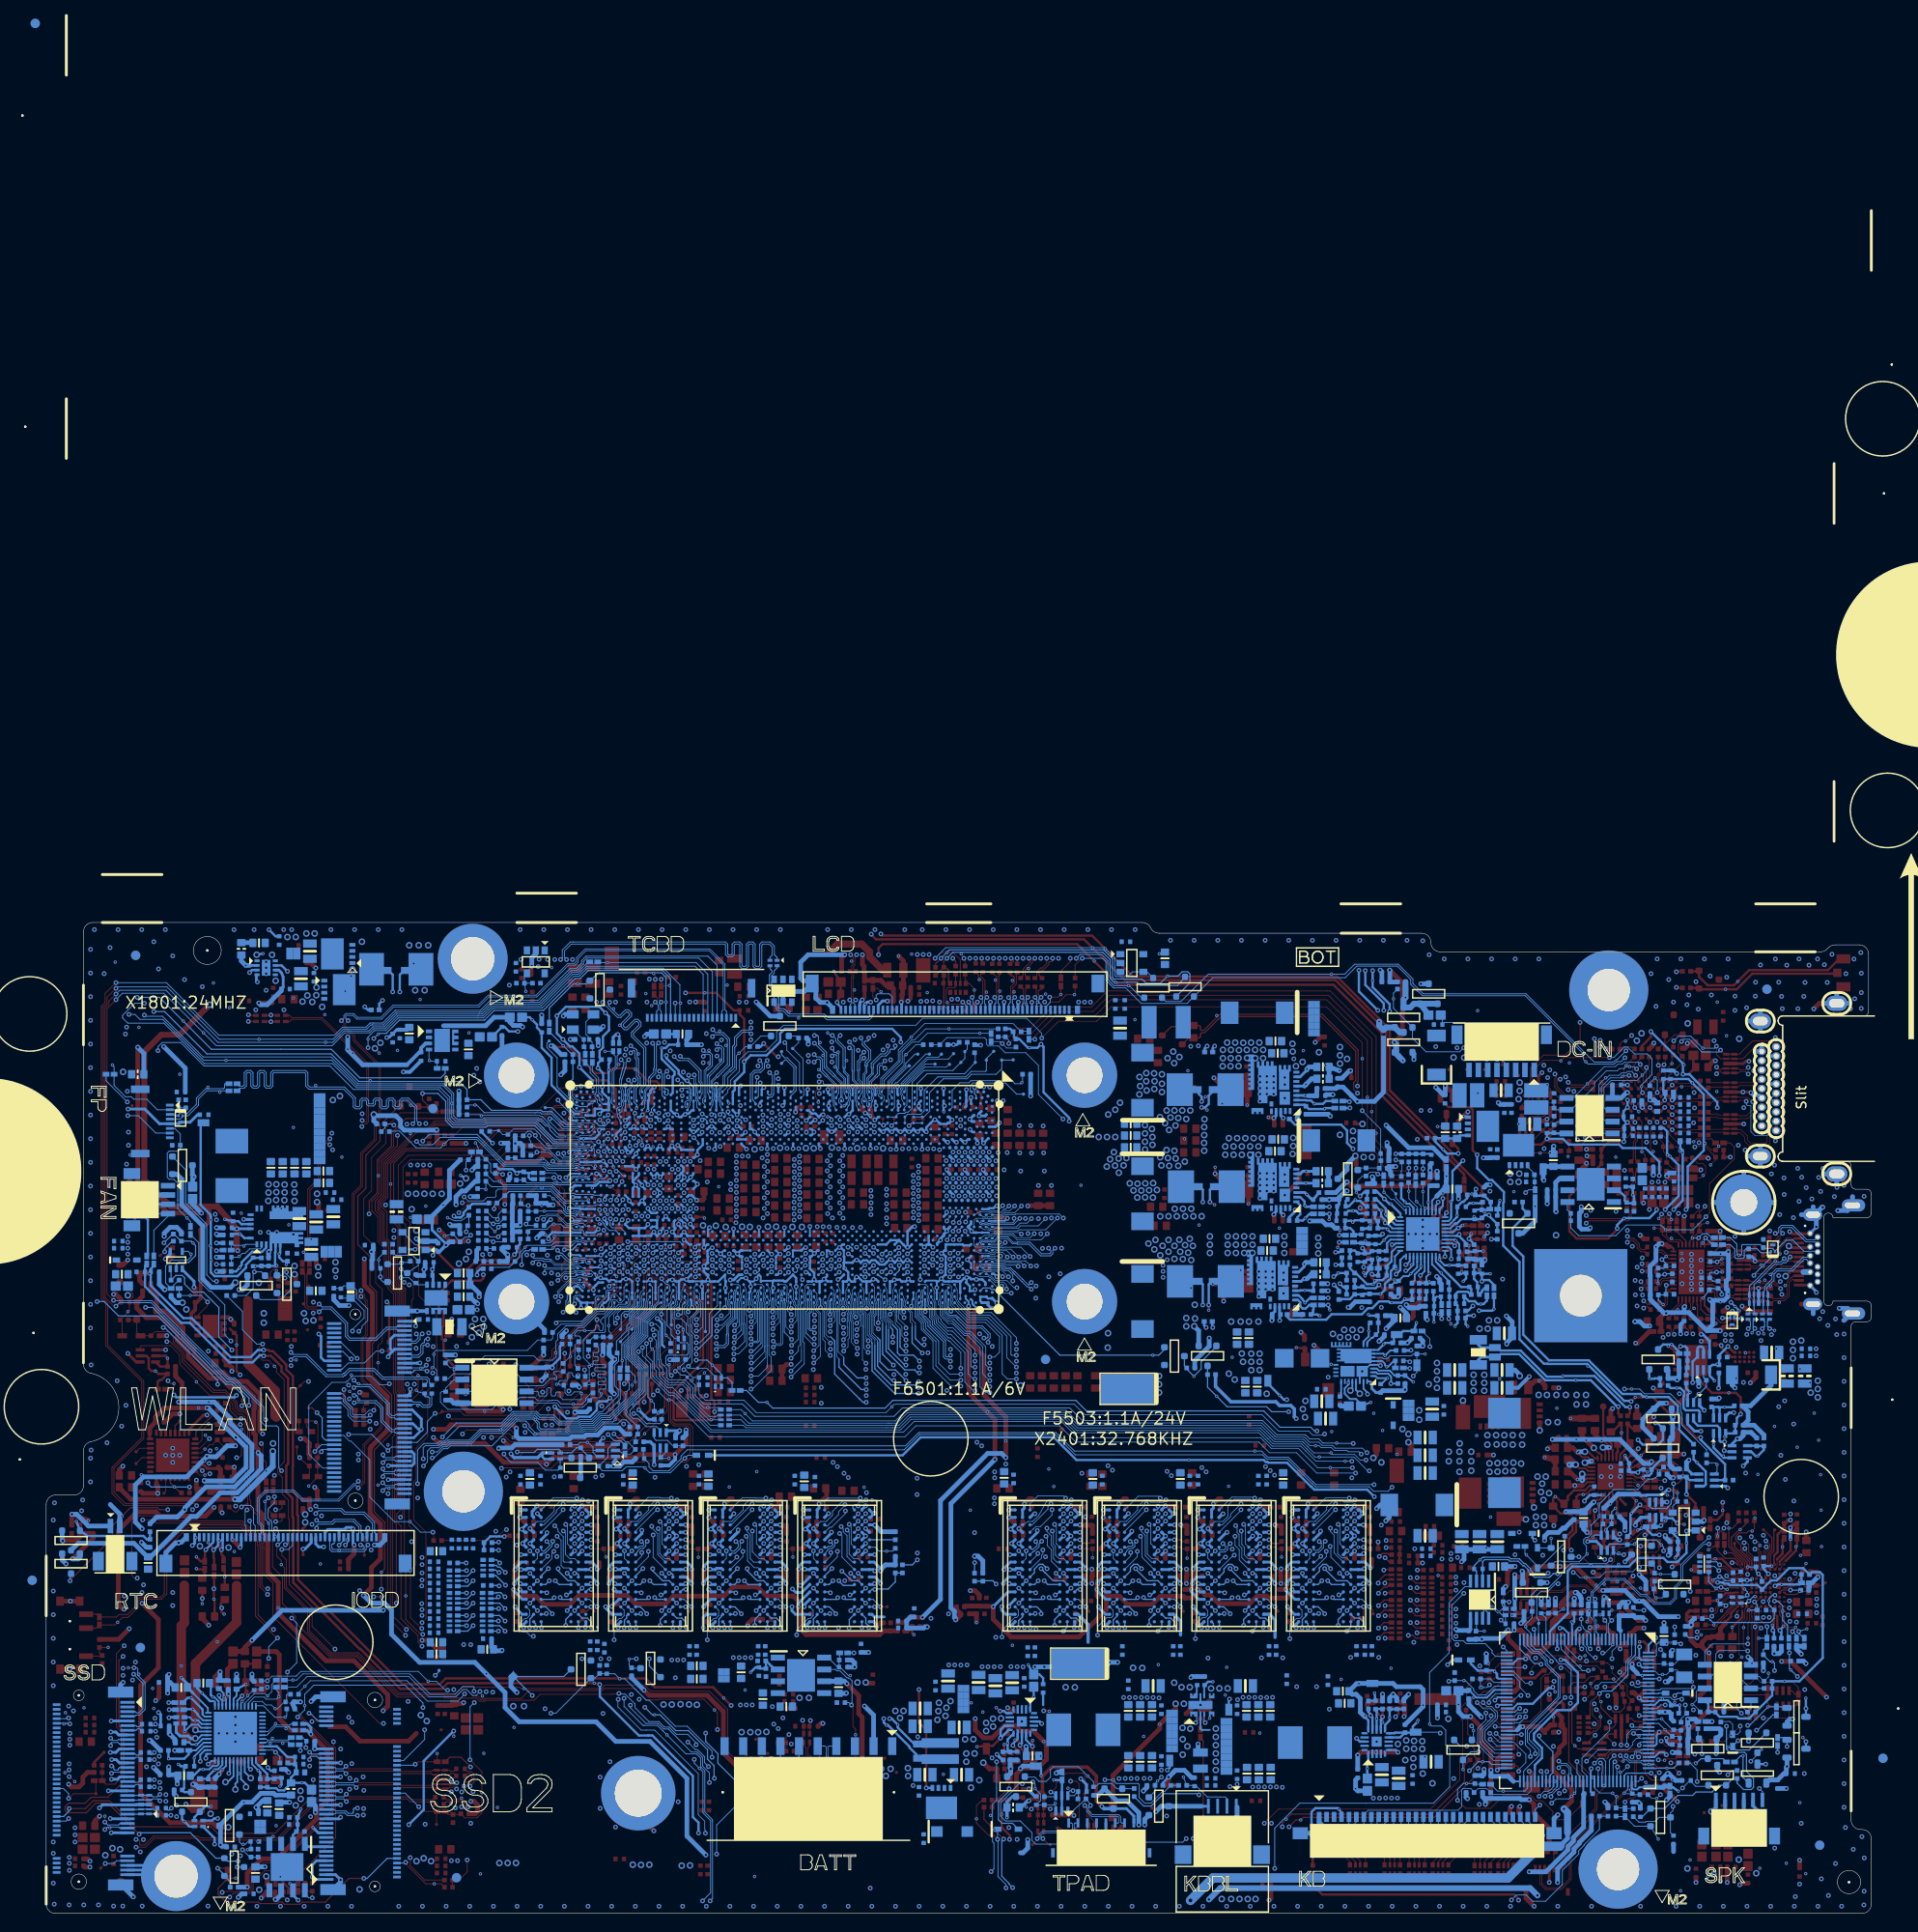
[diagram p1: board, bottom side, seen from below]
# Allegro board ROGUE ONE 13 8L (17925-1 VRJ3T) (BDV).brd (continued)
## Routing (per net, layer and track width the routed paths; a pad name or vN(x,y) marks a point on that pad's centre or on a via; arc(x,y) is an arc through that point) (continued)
M_B_A11: length 99.6
  L6 w0.142: 143.45,30.67 143.45,30.66 142.72,29.92 134.04,29.92 133.3,30.66 ; 143.45,30.67 143.62,30.5 143.62,30.48 144.19,29.92 145.65,29.92 146.12,29.45 149.43,29.45 v2(150.87,30.88) ; 143.45,30.67 v2(143.45,30.68) ; 133.3,30.66 v2(133.3,30.68) ; 133.3,30.66 132.57,29.92 123.9,29.92 123.6,30.22 123.6,30.22 123.33,30.49 123.33,30.49 123.15,30.67 ; v2(107.15,70.83) 107.15,70.81 107.66,70.3 108.07,70.3 108.52,69.84 108.52,63.82 107.2,62.5 107.2,60.42 105.96,59.17 105.96,57.52 105.95,57.52 105.95,52.87 101.13,48.05 101.13,35.22 106.56,29.79 112.14,29.79 113,30.66 113,30.67 ; 123.15,30.67 v2(123.15,30.68) ; 123.15,30.67 123.15,30.55 122.52,29.92 116.24,29.92 115.81,30.35 115.04,30.35 114.6,29.92 113.74,29.92 113.17,30.48 113.17,30.5 113,30.67 ; 113,30.67 v2(113,30.68)
  BOTTOM w0.14: RAM6.T2 113,31.1 v2(113,30.68) ; RAM5.T2 123.15,31.1 v2(123.15,30.68) ; CPU1.AC28 v2(107.15,70.83) ; v2(143.45,30.68) 143.45,31.1 RAM7.T2 ; RAM8.T2 133.3,31.1 v2(133.3,30.68) ; RN1307.2 v2(150.87,30.88)
M_B_A12: length 97.4
  L2SGND w0.089: v2(109.69,34.18) 109.6,34.27 106.92,34.27 104.52,36.67 104.52,47.5 104.73,47.72 104.86,47.72 105.17,47.41 105.29,47.41 105.42,47.54 105.42,47.66 105.11,47.97 105.11,48.1 105.23,48.22 105.36,48.22 105.67,47.91 105.8,47.91 105.92,48.04 105.92,48.16 105.61,48.47 105.61,48.6 105.74,48.72 105.86,48.72 106.17,48.42 106.3,48.42 106.42,48.54 106.42,48.67 106.11,48.98 106.11,49.1 106.24,49.23 106.37,49.23 106.68,48.92 106.8,48.92 106.93,49.04 106.93,49.17 106.62,49.48 106.62,49.6 106.74,49.73 106.87,49.73 107.18,49.42 107.3,49.42 107.43,49.55 107.43,49.67 107.12,49.98 107.12,50.11 107.25,50.23 107.37,50.23 107.68,49.92 107.81,49.92 107.93,50.05 107.93,50.18 107.62,50.48 107.62,50.61 107.75,50.74 107.88,50.74 108.18,50.43 108.31,50.43 108.44,50.55 108.44,50.68 108.13,50.99 108.13,51.11 108.25,51.24 108.38,51.24 108.61,51.01 108.74,51.01 108.86,51.13 108.86,51.26 108.63,51.49 108.63,51.62 108.76,51.74 108.88,51.74 109.01,51.61 109.14,51.61 109.26,51.74 109.26,51.86 109.13,51.99 109.13,52.12 109.77,52.75 109.77,70.14 108.57,71.33 108.57,71.5 108.21,71.87 107.53,71.87 v2(107.15,71.49)
  L6 w0.142: v2(109.69,34.18) 109.87,34.36 111.19,34.36 111.6,33.95 111.99,33.95 112.1,34.06 113.99,34.06 114.03,34.01 117.79,34.01 117.84,34.06 119.71,34.06 v2(119.84,34.18) 120.02,34.36 121.34,34.36 121.75,33.95 122.14,33.95 122.25,34.06 124.14,34.06 124.18,34.01 127.94,34.01 127.99,34.06 129.86,34.06 v2(129.99,34.18) 130.17,34.36 131.49,34.36 131.9,33.95 132.29,33.95 132.4,34.06 134.29,34.06 134.33,34.01 138.09,34.01 138.14,34.06 140.01,34.06 v2(140.14,34.18) 140.32,34.36 141.64,34.36 142.05,33.95 142.44,33.95 142.55,34.06 144.81,34.06 144.85,34.01 144.86,34.01 146.11,34.01 146.54,34.43 146.98,34.43 v2(147.44,33.97)
  BOTTOM w0.14: RAM7.M7 139.97,34.18 v2(140.14,34.18) ; CPU1.AB28 v2(107.15,71.49) ; v2(119.84,34.18) 119.67,34.18 RAM5.M7 ; RAM8.M7 129.82,34.18 v2(129.99,34.18) ; v2(147.44,33.97) 147.61,33.8 RN1306.3 ; RAM6.M7 109.52,34.18 v2(109.69,34.18)
M_B_A13: length 102.3
  L4SGND w0.142: v2(107.94,54.86) 107.94,52.24 106.25,50.56 106.25,50.36 106.59,50.02 106.79,50.02 107.39,50.63 107.59,50.63 107.8,50.43 107.8,50.23 107.19,49.62 107.19,49.42 107.73,48.88 107.73,48.68 107.53,48.48 107.33,48.48 105.85,49.95 105.65,49.95 105.45,49.75 105.45,49.55 106.93,48.08 106.93,47.87 106.73,47.67 106.52,47.67 105.05,49.15 104.85,49.15 104.59,48.89 104.59,48.23 104.74,48.09 105.15,48.09 105.3,47.95 105.3,47.67 105.15,47.52 104.74,47.52 104.59,47.38 104.59,47.1 104.74,46.95 105.41,46.95 105.55,46.81 105.55,46.53 105.41,46.39 104.74,46.39 104.59,46.24 104.59,32.34 106.71,30.22 107.95,30.22 v2(108.4,30.68) 108.84,31.11 112.15,31.11 112.17,31.14 115.47,31.14 116.35,30.25 118.13,30.25 v2(118.55,30.68) 118.88,30.35 121.53,30.35 122.32,31.14 125.62,31.14 126.5,30.25 128.28,30.25 v2(128.7,30.68) 129.03,30.35 131.68,30.35 132.47,31.14 135.77,31.14 136.65,30.25 138.43,30.25 v2(138.85,30.68) 139.18,30.35 141.83,30.35 142.62,31.14 144.97,31.14 145.63,30.47 146.55,30.47 v2(146.72,30.29)
  BOTTOM w0.076: 111.75,61.87 112,61.87 112.27,62.13 112.27,64.48 112.08,64.66 112.08,65.77 111.96,66.11 111.88,66.33 CPU1.AK35
  BOTTOM w0.14: v2(118.55,30.68) RAM5.T8 ; v2(146.72,30.29) 147.31,30.88 RN1304.2 ; v2(108.4,30.68) RAM6.T8 ; v2(107.94,54.86) 108.29,54.86 108.64,55.21 108.64,55.21 111.32,57.89 111.32,61.44 111.75,61.87 ; v2(128.7,30.68) RAM8.T8 ; v2(138.85,30.68) RAM7.T8
M_B_A14: length 93.4
  L4SGND w0.142: v2(111.8,63.06) 111.35,62.61 111.35,49.02 110.58,48.26 110.58,47.71 111.49,46.8 111.49,46.45 111.35,46.3 110.82,46.3 110.68,46.16 110.68,45.88 110.82,45.74 111.35,45.74 111.49,45.59 111.49,45.31 111.35,45.17 110.82,45.17 110.68,45.02 110.68,44.74 110.82,44.6 111.35,44.6 111.49,44.46 111.49,44.17 111.35,44.03 110.82,44.03 110.68,43.89 110.68,43.6 110.82,43.46 111.35,43.46 111.49,43.32 111.49,42.43 111.3,42.23 109.61,42.23 109.31,41.94 109.31,40.39 109.45,40.25 110.42,40.25 110.56,40.11 110.56,39.82 110.42,39.68 109.45,39.68 109.31,39.54 109.31,39.25 109.45,39.11 110.42,39.11 110.56,38.97 110.56,38.58 110.42,38.44 107.68,38.44 107.48,38.25 107.48,37.91 107.71,37.69 109.37,37.69 109.56,37.49 109.56,37.15 109.39,36.98 107.66,36.98 107.48,36.8 107.48,35.69 107.62,35.55 109.61,35.55 109.92,35.25 112.35,35.25 v2(112.8,35.7) 112.97,35.87 117.22,35.87 117.38,35.87 117.88,35.37 118.34,35.37 118.48,35.24 122.49,35.24 v2(122.95,35.7) 123.12,35.87 128.01,35.87 128.64,35.24 132.64,35.24 v2(133.1,35.7) 133.27,35.87 138.16,35.87 138.79,35.24 142.79,35.24 v2(143.25,35.7) 143.42,35.87 144.48,35.87 144.76,36.14 145.57,36.14 145.63,36.09 146.85,36.09 v2(147.36,36.59)
  BOTTOM w0.076: CPU1.AJ35 111.13,66.75 111.26,66.41 111.26,66.4 111.3,66.29 111.3,66.1 111.26,65.99 111.26,65.75 111.39,65.39 111.39,64.61 111.28,64.5 111.28,63.58 v2(111.8,63.06)
  BOTTOM w0.14: v2(112.8,35.7) RAM6.L2 ; v2(122.95,35.7) RAM5.L2 ; RN1302.2 147.72,36.85 147.46,36.59 v2(147.36,36.59) ; v2(143.25,35.7) RAM7.L2 ; v2(133.1,35.7) RAM8.L2
M_B_A15: length 101.2
  L2SGND w0.089: v2(108,34.91) 108.69,34.91 108.98,35.2 108.98,35.65 108.75,35.88 105.83,35.88 104.82,36.89 104.82,37.2 104.91,37.29 105.09,37.29 105.18,37.37 105.18,37.55 105.09,37.64 104.91,37.64 104.82,37.73 104.82,37.91 104.91,38 105.09,38 105.18,38.09 105.18,38.26 105.09,38.35 104.91,38.35 104.82,38.44 104.82,38.62 104.91,38.71 105.09,38.71 105.18,38.8 105.18,38.98 105.09,39.06 104.91,39.06 104.82,39.15 104.82,39.33 104.91,39.42 105.09,39.42 105.18,39.51 105.18,39.69 105.09,39.78 104.91,39.78 104.82,39.86 104.82,40.04 104.91,40.13 105.09,40.13 105.18,40.22 105.18,40.4 105.09,40.49 104.91,40.49 104.82,40.58 104.82,40.75 104.91,40.84 105.09,40.84 105.18,40.93 105.18,41.11 105.09,41.2 104.91,41.2 104.82,41.29 104.82,41.46 104.91,41.55 105.09,41.55 105.18,41.64 105.18,41.82 105.09,41.91 104.91,41.91 104.82,42 104.82,42.18 104.91,42.26 105.09,42.26 105.18,42.35 105.18,42.53 105.09,42.62 104.91,42.62 104.82,42.71 104.82,42.89 104.91,42.98 105.09,42.98 105.18,43.06 105.18,43.24 105.09,43.33 104.91,43.33 104.82,43.42 104.82,43.6 104.91,43.69 105.09,43.69 105.18,43.78 105.18,43.95 105.09,44.04 104.91,44.04 104.82,44.13 104.82,44.31 104.91,44.4 105.09,44.4 105.18,44.49 105.18,44.66 105.09,44.75 104.91,44.75 104.82,44.84 104.82,45.02 104.91,45.11 105.03,45.11 105.12,45.2 105.12,45.33 105.09,45.36 105.09,45.4 105.03,45.46 104.91,45.46 104.82,45.55 104.82,46.51 105.26,46.95 105.39,46.95 105.66,46.68 105.78,46.68 105.91,46.81 105.91,46.93 105.64,47.2 105.64,47.33 105.77,47.45 105.89,47.45 106.16,47.18 106.28,47.18 106.41,47.31 106.41,47.43 106.14,47.7 106.14,47.83 106.27,47.95 106.39,47.95 106.66,47.69 106.79,47.69 106.91,47.81 106.91,47.94 106.65,48.21 106.65,48.33 106.77,48.46 106.9,48.46 107.16,48.19 107.29,48.19 107.42,48.31 107.42,48.44 107.15,48.71 107.15,48.83 107.27,48.96 107.4,48.96 107.67,48.69 107.79,48.69 107.92,48.82 107.92,48.94 107.65,49.21 107.65,49.34 107.78,49.46 107.9,49.46 108.17,49.19 108.3,49.19 108.42,49.32 108.42,49.45 108.15,49.71 108.15,49.84 108.28,49.97 108.41,49.97 108.67,49.7 108.8,49.7 108.93,49.82 108.93,49.95 108.66,50.22 108.66,50.34 108.87,50.56 109,50.56 109.27,50.29 109.39,50.29 109.52,50.42 109.52,50.54 109.25,50.81 109.25,50.94 109.38,51.06 109.5,51.06 109.77,50.79 109.9,50.79 110.02,50.92 110.02,51.04 109.75,51.31 109.75,51.44 110.1,51.78 110.1,60.05 109.96,60.18 109.96,63.04 110.21,63.28 110.66,63.28 110.94,63.01 111.16,63.01 v2(111.82,63.67)
  L6 w0.142: v2(146.7,36.59) 146.31,36.21 146.02,36.21 145.9,36.09 144.29,36.09 143.44,35.24 141.94,35.24 141.64,34.94 139.85,34.94 139.82,34.91 v2(138.45,34.91) 137.96,35.4 137.96,35.59 137.68,35.87 134.74,35.87 134.3,35.43 133.49,35.43 133.29,35.24 131.79,35.24 131.49,34.94 129.7,34.94 129.67,34.91 v2(128.3,34.91) 127.8,35.4 127.8,35.59 127.53,35.87 124.52,35.87 124.15,35.49 123.39,35.49 123.14,35.24 121.64,35.24 121.34,34.94 119.55,34.94 119.52,34.91 v2(118.15,34.91) 117.66,35.4 117.66,35.59 117.38,35.87 114.39,35.87 113.99,35.46 113.46,35.46 113.24,35.24 111.49,35.24 111.19,34.94 108.04,34.94 v2(108,34.91)
  BOTTOM w0.076: CPU1.AK34 111.51,66.99 111.42,66.9 111.42,66.45 111.42,66.44 111.42,66.43 111.46,66.32 111.46,66.08 111.42,65.96 111.42,65.78 111.55,65.42 111.55,64.54 111.44,64.44 111.44,64.06 111.82,63.68 v2(111.82,63.67)
  BOTTOM w0.14: RAM8.M8 128.34,34.87 128.34,34.87 v2(128.3,34.91) ; RAM7.M8 138.49,34.87 138.49,34.87 v2(138.45,34.91) ; RAM5.M8 118.19,34.87 118.19,34.87 v2(118.15,34.91) ; RAM6.M8 108.04,34.87 108.04,34.87 v2(108,34.91) ; v2(146.7,36.59) 147.26,37.15 147.49,37.15 147.69,37.35 RN1302.3
M_B_A16: length 109.5
  L2SGND w0.089: v2(110.55,36.72) 110.33,36.95 108.42,36.95 107.76,36.29 106.03,36.29 105.4,36.92 105.4,45.87 111.19,51.66 111.19,52.1 111.1,52.19 110.49,52.19 110.4,52.28 110.4,52.46 110.49,52.55 111.1,52.55 111.19,52.63 111.19,52.81 111.1,52.9 110.49,52.9 110.4,52.99 110.4,53.17 110.49,53.26 111.1,53.26 111.19,53.35 111.19,53.52 111.1,53.61 110.49,53.61 110.4,53.7 110.4,53.88 110.49,53.97 111.1,53.97 111.19,54.06 111.19,54.23 111.1,54.32 110.49,54.32 110.4,54.41 110.4,54.59 110.49,54.68 111.1,54.68 111.19,54.77 111.19,54.95 111.1,55.03 110.49,55.03 110.4,55.12 110.4,55.3 110.49,55.39 111.1,55.39 111.19,55.48 111.19,55.66 111.1,55.75 110.49,55.75 110.4,55.83 110.4,56.01 110.49,56.1 111.1,56.1 111.19,56.19 111.19,56.37 111.1,56.46 110.49,56.46 110.4,56.55 110.4,56.72 110.49,56.81 111.1,56.81 111.19,56.9 111.19,57.08 111.1,57.17 110.49,57.17 110.4,57.26 110.4,57.43 110.49,57.52 111.1,57.52 111.19,57.61 111.19,57.79 111.1,57.88 110.49,57.88 110.4,57.97 110.4,58.15 110.49,58.23 111.08,58.23 111.16,58.32 111.16,58.58 111.08,58.67 110.58,58.67 110.5,58.74 110.5,58.96 110.79,59.24 110.79,62.47 v2(110.38,62.88)
  L4SGND w0.142: v2(150.15,36.8) 149.03,36.8 147.75,38.07 146.39,38.07 145.98,37.66 143.72,37.66 142.61,36.54 141.48,36.54 v2(141.02,37) 140.36,37.66 133.42,37.66 132.31,36.54 131.33,36.54 v2(130.87,37) 130.21,37.66 123.39,37.66 122.28,36.54 121.18,36.54 v2(120.72,37) 120.06,37.66 113.2,37.66 112.08,36.54 111.03,36.54 110.85,36.72 v2(110.55,36.72)
  BOTTOM w0.076: CPU1.AJ34 111.03,67.49 110.74,66.88 110.74,65.94 110.67,65.82 110.63,65.74 110.61,65.7 110.61,65.34 110.85,65.09 110.85,64.78 110.78,64.71 110.78,63.29 v2(110.38,62.88)
  BOTTOM w0.14: RAM8.L8 129.1,35.7 129.79,35.7 130.87,36.79 v2(130.87,37) ; v2(141.02,37) 141.02,36.79 139.94,35.7 139.25,35.7 RAM7.L8 ; v2(150.15,36.8) 150.74,36.21 RN1305.3 ; RAM6.L8 108.8,35.7 109.49,35.7 110.51,36.72 v2(110.55,36.72) ; v2(120.72,37) 120.72,36.79 119.64,35.7 118.95,35.7 RAM5.L8
M_B_ACT_N: length 99.9
  L6 w0.142: v2(104.43,71.47) 104.43,71.75 105.12,72.43 106.22,72.43 106.37,72.58 106.37,72.77 106.51,72.92 106.79,72.92 106.93,72.77 106.93,72.58 107.08,72.43 109.11,72.43 109.41,72.13 109.41,70.64 109.77,70.27 109.77,59.47 109.59,59.3 109.59,51.1 105.71,47.21 105.71,36.79 106.23,36.26 107.43,36.26 108.45,35.25 111.07,35.25 111.52,35.7 v2(111.52,35.7) 112.14,35.7 112.61,36.16 112.99,36.16 112.99,36.16 113.09,36.16 113.45,35.81 113.83,35.81 114.19,36.16 117.64,36.16 118.57,35.24 121.22,35.24 121.67,35.68 v2(121.67,35.7) 122.29,35.7 122.83,36.24 123.15,36.24 123.51,35.88 124.07,35.88 124.35,36.16 127.72,36.16 128.65,35.24 131.37,35.24 131.82,35.68 v2(131.82,35.7) 132.44,35.7 132.96,36.21 133.39,36.21 133.72,35.88 134.25,35.88 134.53,36.16 137.89,36.16 138.81,35.24 141.52,35.24 141.97,35.68 v2(141.97,35.7) 142.59,35.7 143.86,36.96 144.29,36.96 144.82,36.44 145.84,36.44 146.5,37.1 148.66,37.1 149.42,36.33 150.4,36.33 v2(150.87,36.8)
  BOTTOM w0.14: v2(121.67,35.7) 122.07,35.3 RAM5.L3 ; CPU1.W28 v2(104.43,71.47) ; RN1305.4 v2(150.87,36.8) ; RAM8.L3 132.21,35.3 v2(131.82,35.7) ; RAM6.L3 111.91,35.3 v2(111.52,35.7) ; v2(141.97,35.7) 142.36,35.3 RAM7.L3
M_B_ALERT_N: length 83.3
  TOP w0.14: R1330.1 137.94,32.45 v2(137.49,32.9)
  L2SGND w0.089: v2(107.04,32.9) 106.63,32.49 106.19,32.49 103.26,35.42 103.26,51.45 106.82,55.01 106.82,58.74 108.21,60.12 108.21,64.09 109.59,65.47 109.59,70.05 109.12,70.52 108.47,70.52 108.38,70.43 106.99,70.43 106.64,70.78 106.64,70.92 106.4,71.16 105.65,71.16 v2(105.35,70.86)
  L4SGND w0.142: v2(137.49,32.9) 137.49,32.89 137.05,32.45 136.12,32.45 133.8,32.45 133.28,32.96 128.8,32.96 128.68,32.84 127.4,32.84 v2(127.34,32.9) 127.34,32.89 126.9,32.45 126.17,32.45 126.16,32.45 125.78,32.45 125.78,32.45 125.63,32.45 125.25,32.45 125.25,32.45 123.79,32.45 123.27,32.96 118.47,32.96 118.34,32.84 117.37,32.84 117.31,32.9 117.2,32.9 ; 117.2,32.9 116.65,32.35 113.84,32.35 113.23,32.96 108.32,32.96 108.19,32.84 107.1,32.84 v2(107.04,32.9) ; 117.2,32.9 v2(117.19,32.9)
  BOTTOM w0.14: RAM5.P9 v2(117.19,32.9) ; RAM7.P9 v2(137.49,32.9) ; RAM8.P9 v2(127.34,32.9) ; RAM6.P9 v2(107.04,32.9) ; CPU1.Y29 v2(105.35,70.86)
M_B_BA0: length 94.3
  L6 w0.142: v2(147.41,32.71) 146.95,33.17 146.22,33.17 145.98,33.4 145.2,33.4 145.1,33.3 v2(144.06,33.3) 141.28,33.3 141.12,33.14 139.23,33.14 138.53,32.44 136.6,32.44 136.39,32.65 136.39,33.04 136.39,33.1 136.08,33.42 134.02,33.42 v2(133.9,33.3) 133.89,33.3 133.89,33.29 133.89,33.3 131.13,33.3 130.97,33.14 129.08,33.14 128.38,32.44 125,32.44 124.14,33.3 123.77,33.3 123.76,33.29 123.76,33.3 v2(123.75,33.3) 123.75,33.3 120.98,33.3 120.82,33.14 118.93,33.14 118.23,32.44 114.18,32.44 113.6,33.01 113.6,33.24 113.63,33.27 113.63,33.3 v2(113.61,33.3) 113.6,33.3 108.74,33.3 108.12,33.93 107.22,33.93 104.92,36.23 104.92,47.64 105.29,48.02 105.29,48.22 104.72,48.8 104.72,49 104.92,49.2 105.12,49.2 105.7,48.63 105.9,48.63 106.1,48.83 106.1,49.03 105.51,49.61 105.51,49.82 105.71,50.02 105.92,50.02 106.5,49.43 106.7,49.43 106.9,49.63 106.9,49.83 106.32,50.42 106.32,50.62 106.52,50.82 106.72,50.82 107.31,50.23 107.51,50.23 107.71,50.44 107.71,50.64 107.19,51.16 107.19,51.36 107.39,51.56 107.59,51.56 108.11,51.04 108.31,51.04 108.85,51.58 108.85,52.24 108.71,52.38 108.11,52.38 107.96,52.52 107.96,52.81 108.11,52.95 108.71,52.95 108.85,53.09 108.85,53.47 108.71,53.62 108.05,53.62 107.91,53.76 107.91,54.04 108.05,54.18 108.68,54.18 108.85,54.35 108.85,54.64 108.71,54.78 108.53,54.78 108.39,54.92 108.39,55.21 108.53,55.35 108.71,55.35 108.85,55.49 108.85,56.07 108.71,56.21 v2(107.94,56.21)
  BOTTOM w0.076: 110.86,59.5 111.11,59.76 111.11,64.57 111.19,64.65 111.19,65.39 CPU1.AJ37
  BOTTOM w0.14: RN1306.1 v2(147.41,32.71) ; 110.86,59.5 110.86,58.62 108.47,56.23 107.94,56.23 v2(107.94,56.21) ; v2(133.9,33.3) 133.89,33.3 133.89,33.31 RAM8.N2 ; RAM5.N2 v2(123.75,33.3) ; v2(144.06,33.3) RAM7.N2 ; v2(113.61,33.3) RAM6.N2
M_B_BA1: length 103.2
  L2SGND w0.089: v2(108,33.3) 107.6,33.7 105.86,33.7 103.88,35.68 103.88,48.89 104.1,49.11 104.22,49.11 104.67,48.66 104.79,48.66 104.92,48.79 104.92,48.92 104.47,49.36 104.47,49.49 104.6,49.61 104.73,49.61 105.17,49.17 105.3,49.17 105.42,49.29 105.42,49.42 104.98,49.87 104.98,49.99 105.1,50.12 105.23,50.12 105.67,49.67 105.8,49.67 105.93,49.8 105.93,49.92 105.48,50.37 105.48,50.49 105.61,50.62 105.73,50.62 106.18,50.17 106.3,50.17 106.43,50.3 106.43,50.42 105.98,50.87 105.98,51 106.11,51.12 106.23,51.12 106.68,50.68 106.81,50.68 106.93,50.8 106.93,50.93 106.49,51.37 106.49,51.5 106.61,51.63 106.74,51.63 107.18,51.18 107.31,51.18 107.43,51.3 107.43,51.43 106.99,51.88 106.99,52 107.11,52.13 107.24,52.13 107.69,51.68 107.81,51.68 107.94,51.81 107.94,51.93 107.51,52.36 107.51,53.02 107.6,53.11 109.04,53.11 109.13,53.2 109.13,53.37 109.04,53.46 107.6,53.46 107.51,53.55 107.51,53.73 107.6,53.82 109.04,53.82 109.13,53.91 109.13,54.09 109.04,54.17 107.6,54.17 107.51,54.26 107.51,57.03 v2(107.96,57.48)
  L4SGND w0.142: v2(108,33.3) 112.95,33.3 113.41,33.76 113.79,33.76 114.06,33.49 114.18,33.38 118.07,33.38 v2(118.15,33.3) 123.09,33.3 123.56,33.76 123.94,33.76 124.33,33.38 128.22,33.38 v2(128.3,33.3) 133.24,33.3 133.71,33.76 134.09,33.76 134.48,33.38 135.05,33.38 135.08,33.4 135.46,33.4 135.48,33.38 138.37,33.38 v2(138.45,33.3) 143.39,33.3 143.86,33.76 144.24,33.76 144.6,33.41 147.98,33.41 148.33,33.76 150.24,33.76 v2(150.87,34.38)
  BOTTOM w0.076: CPU1.AJ36 111.04,66.19 111.02,66.15 110.9,65.9 110.9,65.89 110.81,65.72 110.78,65.67 110.78,65.4 111.02,65.16 111.02,64.71 110.95,64.64 110.95,60.28 110.35,59.68
  BOTTOM w0.14: 110.35,59.68 110.35,58.92 108.9,57.47 107.97,57.47 v2(107.96,57.48) ; RAM5.N8 v2(118.15,33.3) ; RAM6.N8 v2(108,33.3) ; RAM7.N8 v2(138.45,33.3) ; RN1303.4 v2(150.87,34.38) ; RAM8.N8 v2(128.3,33.3)
M_B_BG0: length 92.3
  L6 w0.142: v2(104.41,70.83) 104.71,70.83 105.8,71.93 108.41,71.93 108.55,71.78 108.55,71.17 109.54,70.18 109.54,60.98 109.49,60.92 109.49,59.75 109.21,59.48 109.21,51.38 105.32,47.49 105.32,36.47 105.91,35.88 107.25,35.88 107.5,35.63 107.5,34.69 107.79,34.41 108.85,34.41 109.1,34.65 111.31,34.65 111.57,34.9 v2(113.61,34.9) 114.21,34.3 117.64,34.3 117.7,34.36 119.36,34.36 119.62,34.62 119.64,34.62 119.67,34.65 121.46,34.65 121.72,34.9 v2(123.76,34.9) 124.36,34.3 127.79,34.3 127.85,34.36 129.51,34.36 129.77,34.62 129.79,34.62 129.82,34.65 131.61,34.65 131.87,34.9 v2(133.9,34.9) 134.51,34.3 137.94,34.3 138,34.36 139.66,34.36 139.92,34.62 139.94,34.62 139.97,34.65 141.76,34.65 142.02,34.9 v2(144.06,34.9) 144.37,34.9 144.98,34.3 145.99,34.3 146.26,34.57 146.26,35.04 146.44,35.22 v2(146.67,35.22)
  BOTTOM w0.14: v2(133.9,34.9) RAM8.M2 ; v2(113.61,34.9) RAM6.M2 ; v2(146.67,35.22) 147.71,36.26 RN1302.1 ; v2(123.76,34.9) RAM5.M2 ; CPU1.W29 v2(104.41,70.83) ; v2(144.06,34.9) RAM7.M2
M_B_BG1: length 40.9
  L2SGND w0.089: v2(102.45,37.94) 101.82,38.58 101.82,51.99 105.75,55.92 105.75,63.59 109.41,67.25 109.41,69.09 108.29,70.21 106.78,70.21 v2(106.24,70.76)
  BOTTOM w0.14: v2(106.24,70.76) 105.85,71.14 CPU1.Y28 ; v2(102.45,37.94) 102.99,37.41 R1339.1
M_B_BG1_E9_1: length 2.8
  BOTTOM w0.14: R1331.1 RAM6.E9
M_B_BG1_E9_2: length 1.3
  TOP w0.14: R1332.1 117.02,39.93 v2(117.19,40.1)
  BOTTOM w0.14: RAM5.E9 v2(117.19,40.1)
M_B_BG1_E9_3: length 1.3
  TOP w0.14: v2(127.34,40.1) 127.15,39.9 R1333.1
  BOTTOM w0.14: RAM8.E9 v2(127.34,40.1)
M_B_BG1_E9_4: length 1.3
  TOP w0.14: R1334.1 137.32,39.93 v2(137.49,40.1)
  BOTTOM w0.14: RAM7.E9 v2(137.49,40.1)
M_B_BG1_M9_R: length 53.8
  L4SGND w0.142: v2(107.02,34.77) 107.34,34.45 108.19,34.45 108.69,34.94 112.99,34.94 113.41,35.37 113.8,35.37 114.18,34.99 114.18,34.65 114.53,34.3 116.7,34.3 v2(117.17,34.77) 117.49,34.45 118.34,34.45 118.84,34.94 123.14,34.94 123.56,35.37 123.95,35.37 124.33,34.99 124.33,34.65 124.68,34.3 126.85,34.3 v2(127.32,34.77) 127.64,34.45 128.49,34.45 128.99,34.94 133.29,34.94 133.71,35.37 134.1,35.37 134.48,34.99 134.48,34.65 134.83,34.3 137,34.3 v2(137.47,34.77) 137.79,34.45 138.64,34.45 139.14,34.94 143.44,34.94 143.86,35.37 144.25,35.37 144.53,35.08 144.53,34.74 144.98,34.3 145.99,34.3 146.26,34.57 146.26,34.58 146.41,34.73 146.94,34.73 v2(147.36,35.15)
  BOTTOM w0.14: v2(117.17,34.77) 117.43,34.5 RAM5.M9 ; v2(127.32,34.77) 127.33,34.78 127.62,34.78 RAM8.M9 ; RAM7.M9 137.77,34.78 137.48,34.78 v2(137.47,34.77) ; R1339.2 R1340.2 104.81,35.58 105.58,34.82 106.97,34.82 v2(107.02,34.77) 107.03,34.78 107.32,34.78 RAM6.M9 ; R1312.1 147.41,35.2 v2(147.36,35.15)
M_B_CKE0: length 93.3
  L4SGND w0.142: v2(150.15,35.71) 149.56,35.71 148.2,37.08 146.5,37.08 145.86,36.44 144.82,36.44 144.75,36.5 v2(144.05,36.5) 143.76,36.21 141.11,36.21 140.63,35.74 139.13,35.74 138.7,36.16 138.7,36.99 138.56,37.14 138.15,37.14 137.93,36.92 137.93,36.52 137.73,36.33 134.07,36.33 v2(133.9,36.5) 133.61,36.21 130.48,36.21 130,35.74 128.55,35.74 127.97,36.33 123.92,36.33 v2(123.75,36.5) 123.49,36.24 120.33,36.24 119.8,35.71 118.02,35.71 117.4,36.33 113.77,36.33 v2(113.6,36.5) 113.37,36.27 110.37,36.27 110.1,36.53 110.1,37.06 110.58,37.53 111.6,37.53 112.36,38.29 112.36,39.09 112.44,39.18 112.44,54.16 112.28,54.33 112.28,64.46 109.8,66.94 109.8,70.21 108.94,71.06 108.81,71.06 108.55,71.32 108.55,71.56 108.19,71.92 104.28,71.92 103.93,71.57 103.93,71.2 v2(103.52,70.78)
  BOTTOM w0.14: v2(144.05,36.5) RAM7.K2 ; v2(133.9,36.5) RAM8.K2 ; CPU1.T28 v2(103.52,70.78) ; v2(150.15,35.71) 150.74,35.12 RN1305.1 ; v2(123.75,36.5) RAM5.K2 ; v2(113.6,36.5) RAM6.K2
M_B_CLK: length 3.8
  TOP w0.254: v2(146.8,40.45) 146.72,40.53 C1370.1
  BOTTOM w0.254: v2(146.8,40.45) 148.31,40.45 R1314.2 R1313.2
M_B_CLK0: length 102.6
  TOP w0.14: C1388.1 v2(109.6,36.5)
  L6 w0.089: v2(109.6,36.5) 109.78,36.92 110.4,37.55 117.3,37.55 118.77,36.07 119.21,36.07 v2(119.75,36.5) 119.94,36.95 120.51,37.52 127.49,37.52 128.93,36.08 129.37,36.08 v2(129.9,36.5) 130.09,36.95 130.68,37.53 137.61,37.53 139.08,36.06 139.42,36.06 139.48,36.05 139.7,36.23 139.71,36.23 139.73,36.25 v2(140.05,36.5) 139.62,36.93 139.62,37.35 139.93,37.66 143.08,37.66 143.2,37.78 145.34,37.78 146.93,39.36 147.28,39.36 147.41,39.24 v2(147.41,38.98)
  L6 w0.137: v2(109.6,36.5) 108.92,35.98 108.29,35.98 107.8,36.48 107.8,36.77 107.8,36.77 107.8,37.31 107.66,37.45 106.53,37.45 106.25,37.72 106.25,39.07 106.54,39.36 107.09,39.36 107.23,39.5 107.23,40.65 107.06,40.82 106.53,40.82 106.25,41.1 106.25,46.64 110.26,50.66 110.26,57.7 110.85,58.29 110.85,65.97 111.13,66.25 114.12,66.25 114.43,65.94 114.43,64.11 114.56,63.98 115.07,63.98 115.2,64.11 115.2,66.55 114.53,67.22 110.51,67.22 110.05,67.68 110.05,70.6 109.87,70.78 v2(109.87,70.78)
  BOTTOM w0.14: v2(129.9,36.5) RAM8.K7 ; CPU1.AF29 v2(109.87,70.78) ; RAM6.K7 v2(109.6,36.5) ; R1313.1 147.43,38.99 v2(147.41,38.98) ; RAM7.K7 v2(140.05,36.5) ; RAM5.K7 v2(119.75,36.5)
M_B_CLK#0: length 102.8
  TOP w0.14: C1388.2 v2(108.8,36.5)
  L6 w0.089: v2(147.41,39.85) 147.13,39.55 146.85,39.55 145.26,37.97 143.12,37.97 143,37.85 139.85,37.85 139.43,37.43 139.43,36.68 v2(139.25,36.5) 138.9,36.5 137.68,37.72 130.6,37.72 129.91,37.04 129.21,37.04 129.1,36.94 v2(129.1,36.5) 128.77,36.5 127.57,37.71 120.44,37.71 119.76,37.04 119.12,37.04 118.95,36.87 v2(118.95,36.5) 118.61,36.5 117.38,37.74 110.33,37.74 109.63,37.04 108.94,37.04 108.8,36.9 v2(108.8,36.5)
  L6 w0.137: v2(108.8,36.5) 108.8,36.36 108.67,36.22 108.39,36.22 108.04,36.58 108.04,36.67 108.04,36.68 108.04,37.41 107.76,37.69 106.63,37.69 106.49,37.82 106.49,38.97 106.64,39.12 107.19,39.12 107.47,39.4 107.47,40.75 107.16,41.06 106.63,41.06 106.49,41.2 106.49,46.54 110.5,50.56 110.5,57.6 111.09,58.19 111.09,65.87 111.23,66.01 114.02,66.01 114.19,65.84 114.19,64.01 114.46,63.74 115.16,63.74 115.44,64.01 115.44,66.64 114.63,67.46 110.61,67.46 110.29,67.77 110.29,71.36 110.16,71.49 v2(109.89,71.49)
  BOTTOM w0.14: R1314.1 147.48,39.78 v2(147.41,39.85) ; RAM7.K8 138.85,36.37 138.99,36.5 v2(139.25,36.5) ; v2(109.89,71.49) 109.57,71.49 109.43,71.35 CPU1.AF28 ; RAM5.K8 v2(118.95,36.5) ; v2(129.1,36.5) 128.84,36.5 128.7,36.37 RAM8.K8 ; RAM6.K8 v2(108.8,36.5)
M_B_CS#0: length 99.9
  L2SGND w0.089: v2(110.88,35.7) 110.98,35.8 110.98,36.9 110.6,37.28 106.16,37.28 105.77,37.67 105.77,44.03 105.78,44.06 106.6,44.88 106.6,45.01 106.39,45.21 106.39,45.34 106.52,45.46 106.65,45.46 106.85,45.26 106.98,45.26 107.1,45.38 107.1,45.51 106.66,45.96 106.66,46.08 106.78,46.21 106.91,46.21 107.35,45.76 107.48,45.76 107.6,45.89 107.6,46.01 107.16,46.46 107.16,46.58 107.28,46.71 107.41,46.71 107.86,46.26 107.98,46.26 108.11,46.39 108.11,46.52 107.66,46.96 107.66,47.09 107.79,47.21 107.91,47.21 108.36,46.77 108.48,46.77 108.61,46.89 108.61,47.02 108.16,47.46 108.16,47.59 108.29,47.72 108.42,47.72 108.86,47.27 108.99,47.27 109.11,47.4 109.11,47.52 108.67,47.97 108.67,48.09 108.79,48.22 108.92,48.22 109.37,47.77 109.49,47.77 109.62,47.9 109.62,48.02 109.17,48.47 109.17,48.6 109.3,48.72 109.42,48.72 109.87,48.28 109.99,48.28 110.12,48.4 110.12,48.53 109.67,48.97 109.67,49.1 109.8,49.22 109.92,49.22 110.37,48.78 110.5,48.78 110.62,48.9 110.62,49.03 110.18,49.48 110.18,49.6 110.3,49.73 110.43,49.73 110.81,49.35 110.94,49.35 111.06,49.47 111.06,49.6 110.68,49.98 110.68,50.1 110.81,50.23 110.98,50.23 111.1,50.11 111.22,50.11 111.38,50.27 111.38,50.4 111.25,50.53 111.25,50.68 111.93,51.35 111.93,59.05 111.37,59.6 111.37,61.12 111.46,61.21 v2(111.77,61.21)
  L6 w0.142: v2(110.88,35.7) 110.88,35.72 111.32,36.16 112.19,36.16 113.01,36.98 113.83,36.98 114.34,36.47 117.87,36.47 118.64,35.7 v2(121.03,35.7) 121.03,35.72 121.47,36.16 122.31,36.16 123.21,37.07 123.85,37.07 124.45,36.47 127.93,36.47 128.7,35.7 v2(131.18,35.7) 131.18,35.72 131.62,36.16 132.49,36.16 133.31,36.98 134.15,36.98 134.66,36.47 138.16,36.47 138.93,35.7 v2(141.33,35.7) 141.33,35.72 141.77,36.16 142.64,36.16 143.86,37.38 145.89,37.38 146.11,37.61 v2(147.3,37.61)
  BOTTOM w0.076: v2(111.77,61.21) 111.77,61.26 112.43,61.92 112.43,64.61 112.25,64.8 112.25,65.45 CPU1.AL37
  BOTTOM w0.14: RAM5.L7 120.63,35.3 v2(121.03,35.7) ; RN1302.4 147.63,37.94 v2(147.3,37.61) ; v2(110.88,35.7) 110.88,35.68 110.4,35.2 109.3,35.2 RAM6.L7 ; v2(141.33,35.7) 140.93,35.3 RAM7.L7 ; v2(131.18,35.7) 130.78,35.3 RAM8.L7
M_B_DQ0: length 31.8
  L6 w0.089: v2(108.57,44.57) 108.88,44.88 108.88,46.42 112.46,50.01 112.46,54.17 112.61,54.32 113.13,54.32 113.22,54.41 113.22,55.35 113.13,55.43 112.55,55.43 112.46,55.52 112.46,55.7 112.55,55.79 113.13,55.79 113.22,55.88 113.22,58.98 113.31,59.07 v2(113.58,59.07)
  BOTTOM w0.076: 112.85,60.6 112.85,64.43 113.29,64.87 113.29,65.16 113.12,65.32 113.12,65.7 113.23,65.9 113.23,66.53 CPU1.AN35
  BOTTOM w0.089: v2(108.57,44.57) 112.08,44.57 112.4,44.25 RAM6.A3 ; v2(113.58,59.07) 112.85,59.8 112.85,60.6
M_B_DQ1: length 29.3
  L6 w0.089: v2(108,42.9) 108,43.13 107.49,43.64 107.49,45.9 111.88,50.28 111.88,57.45 112.64,58.21 112.64,58.43 112.64,58.43 112.64,60.18 v2(113.53,61.07)
  BOTTOM w0.076: CPU1.AN34 114.29,67.5 114.32,67.46 114.5,67.28 114.5,66.54 114.42,66.32 114.42,66.08 114.47,65.96 114.47,65.78 114.42,65.67 114.42,65.02 114.56,64.89 114.56,61.95 114.39,61.78
  BOTTOM w0.089: RAM6.B8 v2(108,42.9) ; v2(113.53,61.07) 113.68,61.07 114.39,61.78
M_B_DQ2: length 31.3
  L6 w0.089: v2(108.8,41.29) 109.24,41.73 109.24,41.83 109.95,42.54 110.42,42.54 110.83,42.95 110.83,43.21 111.27,43.64 111.27,45.13 116.01,49.87 116.01,50.16 115.92,50.25 115.41,50.25 115.32,50.34 115.32,50.52 115.41,50.61 115.92,50.61 116.01,50.69 v2(116.01,57.56)
  BOTTOM w0.076: 114.72,61.36 114.72,64.96 114.59,65.09 114.59,65.64 114.63,65.75 114.63,65.99 114.62,66.03 114.59,66.1 114.59,66.29 114.76,66.75 CPU1.AR35
  BOTTOM w0.089: 114.72,61.36 114.59,61.23 114.59,58.98 v2(116.01,57.56) ; v2(108.8,41.29) 108.81,41.29 RAM6.D7
M_B_DQ3: length 31.8
  L6 w0.089: v2(115.95,60.97) 114.82,59.84 114.82,57.7 114.44,57.32 114.44,51.51 114.35,51.43 113.97,51.43 113.88,51.34 113.88,51.16 113.97,51.07 114.35,51.07 114.44,50.98 114.44,50.8 114.35,50.71 113.95,50.71 113.86,50.63 113.86,50.45 113.95,50.36 114.35,50.36 114.44,50.27 114.44,49.6 110.22,45.39 v2(110.22,43.88)
  BOTTOM w0.076: CPU1.AR34 115.12,66.95 115.12,66 115.28,65.7 115.28,65.32 115.22,65.26 115.22,61.64 115.37,61.49
  BOTTOM w0.089: v2(110.22,43.88) 110.22,43.78 110.91,43.1 110.91,42.79 112.14,41.56 112.26,41.56 RAM6.C3 ; v2(115.95,60.97) 115.89,60.97 115.37,61.49
M_B_DQ4: length 30
  L6 w0.089: v2(113.49,64.22) 112.31,63.03 112.31,58.36 111.58,57.64 111.58,57.21 111.49,57.12 111.25,57.12 111.16,57.04 111.16,56.86 111.25,56.77 111.49,56.77 111.58,56.68 111.58,56.5 111.49,56.41 111.25,56.41 111.16,56.32 111.16,56.15 111.25,56.06 111.49,56.06 111.58,55.97 111.58,55.79 111.49,55.7 111.25,55.7 111.16,55.61 111.16,55.44 111.25,55.35 111.49,55.35 111.58,55.26 111.58,55.08 111.49,54.99 111.25,54.99 111.16,54.9 111.16,54.72 111.25,54.64 111.49,54.64 111.58,54.55 111.58,54.37 111.49,54.28 111.35,54.28 111.27,54.19 111.27,54.01 111.35,53.92 111.49,53.92 111.58,53.84 111.58,50.42 107.15,45.99 107.15,45.33 107.15,43.48 107.53,43.1 107.53,42.57 v2(108,42.1)
  BOTTOM w0.076: v2(113.49,64.22) 113.62,64.34 113.62,65.39 113.55,65.46 CPU1.AN37
  BOTTOM w0.089: v2(108,42.1) RAM6.C8
M_B_DQ5: length 31.5
  L6 w0.089: v2(113.58,60.39) 113.49,60.39 112.93,59.82 112.93,58.02 112.17,57.26 112.17,50.14 108.45,46.42 108.45,45.06 108.13,44.75 108.13,44.56 v2(107.95,44.38)
  BOTTOM w0.076: CPU1.AN36 113.55,66.14 113.29,65.66 113.29,65.39 113.45,65.23 113.45,64.8 113.01,64.36 113.01,60.95 v2(113.58,60.39)
  BOTTOM w0.089: v2(107.95,44.38) 108.19,44.14 108.74,44.14 108.91,44.31 110.4,44.31 111.56,43.15 111.56,42.72 112.22,42.06 112.84,42.06 RAM6.C2
M_B_DQ6: length 32
  L6 w0.089: v2(116.01,59.59) 115.29,58.87 115.29,56.89 115.2,56.8 114.82,56.8 114.73,56.71 114.73,56.54 114.82,56.45 115.2,56.45 115.29,56.36 115.29,56.18 115.2,56.09 114.82,56.09 114.73,56 114.73,55.83 114.82,55.74 115.2,55.74 115.29,55.65 115.29,55.47 115.2,55.38 114.82,55.38 114.73,55.29 114.73,55.11 114.82,55.03 115.11,55.03 115.2,54.94 115.2,54.76 115.11,54.67 114.82,54.67 114.73,54.58 114.73,49.46 110.66,45.39 110.66,43.68 v2(110.17,43.2)
  BOTTOM w0.076: CPU1.AR36 114.85,66.14 115.12,65.66 115.12,65.39 115.06,65.33 115.06,61 115.22,60.83
  BOTTOM w0.089: RAM6.D3 111.97,41.33 111.96,41.33 111.86,41.44 111.65,41.44 110.17,42.92 v2(110.17,43.2) ; 115.22,60.83 115.22,60.36 115.99,59.59 v2(116.01,59.59)
M_B_DQ7: length 31.6
  L6 w0.089: v2(116.02,58.21) 115.58,57.77 115.58,54.32 115.49,54.23 115.11,54.23 115.02,54.14 115.02,53.96 115.11,53.87 115.49,53.87 115.58,53.78 115.58,53.6 115.49,53.52 115.11,53.52 115.02,53.43 115.02,53.25 115.11,53.16 115.49,53.16 115.58,53.07 115.58,52.89 115.49,52.8 115.11,52.8 115.02,52.72 115.02,52.54 115.11,52.45 115.49,52.45 115.58,52.36 115.58,52.18 115.49,52.09 115.11,52.09 115.02,52 115.02,51.83 115.11,51.74 115.37,51.74 115.46,51.65 115.46,51.47 115.37,51.38 115.11,51.38 115.02,51.29 115.02,49.3 110.96,45.24 110.96,43.66 110.6,43.3 110.6,43.03 110.34,42.76 109.47,42.76 v2(108.8,42.1)
  BOTTOM w0.076: 114.89,60.34 114.89,65.51 CPU1.AR37
  BOTTOM w0.089: RAM6.C7 v2(108.8,42.1) ; 114.89,60.34 114.89,59.35 v2(116.02,58.21)
M_B_DQ8: length 34.9
  L6 w0.089: v2(110.8,40.78) 110.8,40.95 111.75,41.91 111.99,42.01 113.43,43.45 113.43,44.17 115.34,46.08 115.34,46.21 115.26,46.29 115.26,46.41 115.38,46.54 115.51,46.54 115.59,46.46 115.72,46.46 115.94,46.68 115.94,47.1 117.7,48.86 117.7,59.14 117.21,59.63 117.21,63.06 v2(115.99,64.28)
  BOTTOM w0.076: v2(115.99,64.28) 116.4,64.69 116.4,65.09 116.32,65.16 116.32,65.66 116.3,65.71 116.3,65.72 116.3,66.02 116.3,66.03 116.32,66.08 116.32,66.31 116.3,66.36 116.3,66.37 116.25,66.52 116.25,66.53 116.17,66.75 CPU1.AU35
  BOTTOM w0.089: v2(110.8,40.78) 110.54,40.52 110.54,38.24 RAM6.J7
M_B_DQ9: length 34.9
  L6 w0.089: v2(109.99,41.14) 110.1,41.14 110.19,41.23 110.19,41.68 110.49,41.98 110.79,41.98 111.52,42.71 111.52,43.07 112.15,43.71 112.15,44.14 117.12,49.1 117.12,58.7 116.7,59.12 116.7,62.3 v2(115.99,63.01)
  BOTTOM w0.076: v2(115.99,63.01) 115.39,63.61 115.39,65.19 115.57,65.38 115.57,65.57 115.58,65.58 115.64,65.69 115.64,65.7 115.74,65.88 115.78,65.95 115.78,66.89 116.07,67.49 CPU1.AU34
  BOTTOM w0.089: RAM6.H8 108.76,38.06 109.27,38.06 109.77,38.56 109.77,40.93 v2(109.99,41.14)
M_B_DQ10: length 36.4
  L6 w0.089: v2(117.97,63.96) 118.13,63.96 119.67,62.43 119.67,58.6 119.84,58.43 119.84,46.74 116.73,43.63 116.73,43.3 116.64,43.21 116.56,43.21 116.47,43.13 116.47,42.95 116.56,42.86 116.64,42.86 116.73,42.77 116.73,42.59 116.64,42.5 116.56,42.5 116.47,42.41 116.47,42.24 116.56,42.15 116.64,42.15 116.73,42.06 116.73,41.88 116.64,41.79 116.56,41.79 116.47,41.7 116.47,41.53 116.56,41.44 116.64,41.44 116.73,41.35 116.73,38.91 116.45,38.63 115.03,38.63 114.45,39.21 113.91,39.21 v2(113.6,38.9)
  BOTTOM w0.076: CPU1.AW35 117.68,66.54 117.68,65.92 117.7,65.88 117.79,65.72 117.79,65.04 117.61,64.85 117.61,64.33 v2(117.97,63.96)
  BOTTOM w0.089: v2(113.6,38.9) 113.6,38.1 RAM6.H2
M_B_DQ11: length 34.6
  L6 w0.089: v2(115.99,62.38) 116.45,61.92 116.45,58.92 116.83,58.54 116.83,49.39 116.37,48.92 116.24,48.92 116.15,49.02 116.02,49.02 115.89,48.89 115.89,48.77 115.99,48.67 115.99,48.55 115.86,48.42 115.74,48.42 115.64,48.52 115.52,48.52 115.39,48.39 115.39,48.26 115.49,48.17 115.49,48.04 115.36,47.92 115.23,47.92 115.14,48.01 115.01,48.01 114.89,47.89 114.89,47.76 114.98,47.67 114.98,47.54 114.86,47.42 114.73,47.42 114.64,47.51 114.51,47.51 114.38,47.38 114.38,47.26 114.48,47.16 114.48,47.04 111.7,44.26 111.7,43.75 111.06,43.12 111.06,42.84 110.53,42.31 110.32,42.31 v2(109.76,41.75)
  BOTTOM w0.076: CPU1.AW34 116.64,67.5 116.43,67.29 116.43,66.5 116.45,66.46 116.45,66.45 116.49,66.34 116.49,66.04 116.49,66.04 116.47,65.99 116.47,65.75 116.48,65.72 116.5,65.67 116.56,65.49 116.56,62.95 v2(115.99,62.38)
  BOTTOM w0.089: v2(109.76,41.75) 109.76,41.72 109.55,41.52 109.55,39.65 RAM6.F7
M_B_DQ12: length 34.7
  L6 w0.089: v2(116,64.93) 117.44,63.49 117.44,59.89 118.02,59.3 118.02,48.28 117.79,48.05 117.67,48.05 117.55,48.17 117.42,48.17 117.3,48.04 117.3,47.92 117.42,47.8 117.42,47.67 117.29,47.55 117.16,47.55 117.05,47.66 116.92,47.66 116.8,47.54 116.8,47.41 116.91,47.29 116.91,47.17 116.79,47.04 116.66,47.04 116.54,47.16 116.42,47.16 116.29,47.04 116.29,46.91 116.41,46.79 116.41,46.67 113.66,43.92 113.66,43.59 113.65,43.58 113.65,43.54 113.65,43.36 111.93,41.63 111.68,41.53 111.24,41.09 111.24,40.62 111.02,40.4 111.02,40.4 110.73,40.11 110.73,39.16 v2(111.03,38.85)
  BOTTOM w0.089: v2(111.03,38.85) 111.03,38.27 RAM6.J3 ; CPU1.AU37 116.07,64.99 v2(116,64.93)
M_B_DQ13: length 34.4
  L6 w0.089: v2(115.99,63.65) 116.96,62.68 116.96,59.4 117.41,58.95 117.41,48.98 114.53,46.1 114.53,45.97 114.61,45.89 114.61,45.77 114.49,45.64 114.36,45.64 114.28,45.72 114.16,45.72 114.03,45.59 114.03,45.47 114.11,45.39 114.11,45.26 113.98,45.14 113.86,45.14 113.78,45.22 113.65,45.22 113.53,45.09 113.53,44.96 113.61,44.89 113.61,44.76 113.48,44.63 113.36,44.63 113.28,44.71 113.15,44.71 112.54,44.1 112.54,42.85 112.16,42.48 111.59,42.48 v2(110.63,41.51)
  BOTTOM w0.076: v2(115.99,63.65) 115.55,64.08 115.55,65.13 115.74,65.31 115.74,65.53 115.8,65.65 115.8,65.66 115.85,65.74 116.08,66.15 CPU1.AU36
  BOTTOM w0.089: RAM6.H7 109.39,37.7 110,38.31 110,40.55 110.41,40.96 110.41,41.3 v2(110.63,41.51)
M_B_DQ14: length 34.9
  L6 w0.089: v2(112.81,38.9) 113.07,38.9 113.16,38.99 113.16,39.99 113.39,40.21 114.78,40.21 114.99,40.01 114.99,39.38 115.08,39.29 115.85,39.29 115.94,39.38 115.94,43.4 119.53,47 119.53,58.43 119.47,58.5 119.47,61.86 v2(117.97,63.35)
  BOTTOM w0.076: CPU1.AW36 117.37,66.14 117.6,65.72 117.62,65.68 117.62,65.28 117.44,65.09 117.44,63.89 v2(117.97,63.35)
  BOTTOM w0.089: RAM6.G2 113.2,38.51 v2(112.81,38.9)
M_B_DQ15: length 34.6
  L6 w0.089: v2(111.74,38.73) 112.48,39.48 112.48,39.87 113.3,40.68 114.72,40.68 114.91,40.87 114.91,41.53 115,41.62 115.49,41.62 115.58,41.71 115.58,41.89 115.49,41.97 115.21,41.97 115.12,42.06 115.12,42.24 115.21,42.33 115.55,42.33 115.63,42.42 115.63,42.6 115.55,42.69 115.21,42.69 115.12,42.77 115.12,43.07 119.24,47.19 119.24,61.47 v2(117.96,62.74)
  BOTTOM w0.076: CPU1.AW37 117.26,65.43 117.26,63.45 v2(117.96,62.74)
  BOTTOM w0.089: RAM6.H3 111.74,38.36 v2(111.74,38.73)
M_B_DQ16: length 37.1
  L4SGND w0.089: v2(110.83,70.81) 110.03,70 110.03,67.65 112.05,65.63 112.8,65.63 113.25,65.18 113.25,64.66 113.09,64.51 113.09,57.65 113.88,56.86 113.88,46.88 115.15,45.61 115.15,45.49 114.97,45.31 114.97,45.18 115.1,45.06 115.22,45.06 115.4,45.24 115.53,45.24 115.65,45.11 115.65,44.99 115.42,44.75 115.42,44.63 115.55,44.5 115.67,44.5 115.91,44.73 116.03,44.73 116.16,44.61 116.16,44.48 115.93,44.25 115.93,44.13 116.05,44 116.18,44 116.41,44.23 116.53,44.23 116.66,44.11 116.66,43.98 116.43,43.75 116.43,43.62 116.55,43.5 116.68,43.5 116.91,43.73 117.04,43.73 117.68,43.09 117.68,42.57 v2(118.15,42.1)
  BOTTOM w0.089: RAM5.C8 v2(118.15,42.1) ; CPU1.AJ29 v2(110.83,70.81)
M_B_DQ17: length 37.4
  L4SGND w0.089: v2(118.15,42.9) 118.15,43.13 117.32,43.95 117.32,44.07 117.6,44.35 117.6,44.45 117.43,44.62 117.31,44.62 117.03,44.34 116.91,44.34 116.78,44.46 116.78,44.59 117.06,44.87 117.06,44.99 116.93,45.12 116.81,45.12 116.53,44.84 116.4,44.84 116.28,44.97 116.28,45.09 116.55,45.37 116.55,45.5 116.43,45.62 116.3,45.62 116.03,45.34 115.9,45.34 115.77,45.47 115.77,45.6 116.05,45.87 116.05,46 115.93,46.12 115.8,46.12 115.52,45.85 115.4,45.85 115.27,45.97 115.27,46.1 115.55,46.38 115.55,46.5 115.42,46.63 115.3,46.63 115.02,46.35 114.89,46.35 114.77,46.48 114.77,46.6 115.05,46.88 115.05,47 114.2,47.85 114.2,64.48 112.72,65.96 111.97,65.96 110.21,67.73 110.21,69.93 110.42,70.15 v2(110.81,70.15)
  BOTTOM w0.089: CPU1.AJ30 v2(110.81,70.15) ; RAM5.B8 v2(118.15,42.9)
M_B_DQ18: length 38
  L4SGND w0.089: v2(120.19,43.96) 120.23,44 120.23,45.82 116.5,49.55 116.5,49.84 116.41,49.93 116.09,49.93 116,50.02 116,50.2 116.09,50.28 116.41,50.28 116.5,50.37 116.5,50.55 116.41,50.64 116.09,50.64 116,50.73 116,50.91 116.09,51 116.41,51 116.5,51.08 116.5,51.26 116.41,51.35 116.09,51.35 116,51.44 116,51.62 116.09,51.71 116.41,51.71 116.5,51.8 116.5,51.97 116.41,52.06 116.09,52.06 116,52.15 116,52.33 116.09,52.42 116.41,52.42 116.5,52.51 116.5,52.68 116.41,52.77 116.09,52.77 116,52.86 116,53.04 116.09,53.13 116.41,53.13 116.5,53.22 116.5,53.4 116.41,53.48 116.09,53.48 116,53.57 116,53.75 116.09,53.84 116.41,53.84 116.5,53.93 116.5,65 116.1,65.4 114.87,65.4 112.97,67.3 112.68,67.3 112.07,67.9 112.07,68.34 v2(112.61,68.88)
  BOTTOM w0.089: v2(120.19,43.96) 120.91,43.24 120.91,43.23 122.44,41.7 RAM5.C3 ; CPU1.AM32 v2(112.61,68.88)
M_B_DQ19: length 38.2
  L4SGND w0.089: v2(120.19,43.33) 120.62,43.75 120.62,44.34 120.57,44.39 120.57,45.89 119.9,46.56 119.9,46.68 120.07,46.85 120.07,46.97 119.94,47.1 119.81,47.1 119.65,46.93 119.53,46.93 119.4,47.06 119.4,47.19 119.55,47.34 119.55,47.46 119.42,47.59 119.3,47.59 119.15,47.44 119.02,47.44 118.9,47.56 118.9,47.69 119.06,47.85 119.06,47.98 118.93,48.1 118.81,48.1 118.64,47.94 118.52,47.94 118.39,48.07 118.39,48.19 118.57,48.37 118.57,48.49 118.44,48.62 118.32,48.62 118.14,48.44 118.02,48.44 117.89,48.57 117.89,48.69 118.07,48.87 118.07,49 117.94,49.12 117.81,49.12 117.64,48.95 117.51,48.95 117.39,49.07 117.39,49.2 117.6,49.41 117.6,49.53 117.47,49.66 117.35,49.66 117.14,49.45 117.01,49.45 116.8,49.66 116.8,64.95 116.15,65.6 115,65.6 112.95,67.65 112.95,68.65 113.01,68.71 113.01,69.14 v2(112.61,69.54)
  BOTTOM w0.089: RAM5.D3 120.19,43.26 v2(120.19,43.33) ; CPU1.AM31 v2(112.61,69.54)
M_B_DQ20: length 38.8
  L4SGND w0.089: v2(118.96,42.1) 119.23,42.1 120.03,42.89 120.36,42.89 120.86,43.39 120.86,46.69 120.85,46.69 120.85,46.69 120.53,47.01 120.53,47.14 120.66,47.27 120.66,47.39 120.53,47.52 120.41,47.52 120.28,47.39 120.16,47.39 119.95,47.6 119.95,47.72 120.17,47.95 120.17,48.07 120.05,48.2 119.92,48.2 119.7,47.97 119.57,47.97 119.45,48.1 119.45,48.23 119.67,48.45 119.67,48.58 119.55,48.7 119.42,48.7 119.19,48.48 119.07,48.48 118.94,48.6 118.94,48.73 119.17,48.95 119.17,49.08 119.04,49.21 118.92,49.21 118.69,48.98 118.57,48.98 118.44,49.11 118.44,49.23 118.67,49.46 118.67,49.58 118.54,49.71 118.41,49.71 118.19,49.48 118.06,49.48 117.94,49.61 117.94,49.73 118.16,49.96 118.16,50.09 118.04,50.21 117.91,50.21 117.69,49.99 117.56,49.99 117.1,50.45 117.1,64.9 115.97,66.03 114.97,66.03 113.13,67.87 113.13,68.57 113.19,68.64 113.19,69.59 v2(112.61,70.17)
  BOTTOM w0.089: CPU1.AM30 v2(112.61,70.17) ; RAM5.C7 v2(118.96,42.1)
M_B_DQ21: length 39.1
  L4SGND w0.089: v2(118.96,41.3) 119.48,41.83 119.48,41.92 120.22,42.66 120.43,42.66 121.07,43.3 121.07,44.01 121.15,44.09 121.15,47.51 120.02,48.64 120.02,48.77 120.23,48.97 120.23,49.1 120.1,49.22 119.97,49.22 119.79,49.04 119.62,49.04 119.48,49.18 119.48,49.31 119.63,49.46 119.63,49.59 119.51,49.71 119.38,49.71 119.23,49.56 119.1,49.56 118.98,49.68 118.98,49.81 119.16,49.99 119.16,50.12 119.03,50.24 118.91,50.24 118.73,50.06 118.6,50.06 118.47,50.19 118.47,50.31 118.65,50.49 118.65,50.62 118.53,50.74 118.4,50.74 118.22,50.56 118.1,50.56 117.97,50.69 117.97,50.82 118.2,51.05 118.2,51.17 118.08,51.3 117.95,51.3 117.72,51.07 117.59,51.07 117.39,51.27 117.39,64.86 116.04,66.21 115.19,66.21 114.88,66.52 114.88,66.52 114.14,67.27 114.14,68.02 113.63,68.53 113.63,69.81 v2(112.64,70.81)
  BOTTOM w0.089: v2(118.96,41.3) 119.35,40.91 RAM5.D7 ; CPU1.AM29 v2(112.64,70.81)
M_B_DQ22: length 36.6
  L4SGND w0.089: v2(110.83,69.49) 110.47,69.49 110.38,69.4 110.38,67.8 111.96,66.22 112.71,66.22 114.49,64.44 114.49,47.99 v2(118.1,44.38)
  BOTTOM w0.089: RAM5.C2 123.35,41.97 123.26,42.06 122.39,42.06 121.15,43.3 121.15,43.75 120.52,44.39 120,44.39 119.75,44.14 118.34,44.14 v2(118.1,44.38) ; CPU1.AJ31 v2(110.83,69.49)
M_B_DQ23: length 36.2
  L4SGND w0.089: v2(118.72,44.57) 118.48,44.81 118.12,44.81 117.92,45 117.92,45.13 118.07,45.27 118.07,45.4 117.94,45.53 117.82,45.53 117.67,45.38 117.54,45.38 117.42,45.5 117.42,45.63 117.56,45.78 117.56,45.9 117.44,46.03 117.31,46.03 117.17,45.88 117.04,45.88 116.91,46.01 116.91,46.13 117.06,46.28 117.06,46.41 116.94,46.53 116.81,46.53 116.66,46.38 116.54,46.38 116.41,46.51 116.41,46.64 116.49,46.71 116.49,46.84 116.36,46.97 116.24,46.97 116.16,46.89 116.03,46.89 115.91,47.01 115.91,47.14 116,47.23 116,47.35 115.87,47.48 115.75,47.48 115.66,47.39 115.53,47.39 115.41,47.52 115.41,47.64 115.5,47.73 115.5,47.86 115.37,47.98 115.24,47.98 115.15,47.89 115.03,47.89 114.82,48.1 114.82,64.36 112.69,66.49 111.94,66.49 110.56,67.87 110.56,68.56 v2(110.83,68.83)
  BOTTOM w0.089: RAM5.A3 121.25,44.6 119.87,44.6 119.84,44.57 v2(118.72,44.57) ; v2(110.83,68.83) CPU1.AJ32
M_B_DQ24: length 38.6
  L4SGND w0.089: v2(114.48,69.55) 114.72,69.31 114.72,69.07 115.37,68.43 115.37,68 117.86,65.51 118.39,65.51 119.27,64.63 119.27,58.74 119.11,58.59 119.11,54.32 122.59,50.84 122.59,42.66 121.27,41.33 121.27,41.24 120.84,40.81 v2(120.84,40.47)
  BOTTOM w0.089: RAM5.J7 119.55,37.1 119.95,37.1 120.69,37.84 120.69,40.33 v2(120.84,40.47) ; CPU1.AR31 v2(114.48,69.55)
M_B_DQ25: length 38.3
  L4SGND w0.089: v2(114.79,68.01) 114.79,67.12 115.23,66.67 115.34,66.57 116.3,66.57 117.72,65.15 118.24,65.15 118.66,64.73 118.66,59.17 118.34,58.86 118.34,54.27 118.69,53.92 118.69,53.8 118.47,53.57 118.47,53.45 118.59,53.32 118.72,53.32 118.94,53.55 119.07,53.55 119.19,53.42 119.19,53.29 118.97,53.07 118.97,52.95 119.09,52.82 119.22,52.82 119.44,53.04 119.57,53.04 121.94,50.67 121.94,43.79 121.51,43.35 121.51,43.12 121.5,43.12 121.5,43.1 120.35,41.94 120.35,41.57 120.17,41.39 v2(120.17,41.04)
  BOTTOM w0.089: v2(120.17,41.04) 120.17,38.82 119.41,38.06 118.91,38.06 RAM5.H8 ; v2(114.79,68.01) 114.77,68.01 114.9,68.14 CPU1.AR32
M_B_DQ26: length 41
  L4SGND w0.089: v2(122.96,38.9) 122.96,39.5 123.67,40.21 124.21,40.21 125.48,41.49 125.48,43.82 124.98,44.31 124.98,51.08 124.01,52.05 124.01,52.17 124.23,52.39 124.23,52.51 124.1,52.64 123.97,52.64 123.76,52.43 123.64,52.43 123.51,52.55 123.51,52.68 123.86,53.03 123.86,53.15 123.73,53.28 123.61,53.28 123.26,52.93 123.13,52.93 123.01,53.05 123.01,53.18 123.35,53.53 123.35,53.65 121.54,55.47 121.54,58.86 121.32,59.07 121.32,64.94 120.61,65.65 120.16,65.65 117.54,68.27 117.18,68.27 116.69,68.75 116.69,69.7 v2(116.27,70.12)
  BOTTOM w0.089: CPU1.AV30 116.44,70.12 v2(116.27,70.12) ; v2(122.96,38.9) 122.96,38.09 RAM5.H2
M_B_DQ27: length 41.9
  L4SGND w0.089: v2(116.29,70.81) 117.62,69.49 117.62,68.45 120.23,65.83 120.68,65.83 121.58,64.93 121.58,59.23 121.83,58.97 121.83,55.59 125.31,52.11 125.31,51.82 125.4,51.73 125.71,51.73 125.79,51.64 125.79,51.47 125.71,51.38 125.4,51.38 125.31,51.29 125.31,51.11 125.4,51.02 125.71,51.02 125.79,50.93 125.79,50.75 125.71,50.67 125.4,50.67 125.31,50.58 125.31,50.4 125.4,50.31 125.71,50.31 125.79,50.22 125.79,50.04 125.71,49.95 125.4,49.95 125.31,49.87 125.31,49.69 125.4,49.6 125.71,49.6 125.79,49.51 125.79,49.33 125.71,49.24 125.4,49.24 125.31,49.15 125.31,47.47 125.4,47.38 125.6,47.38 125.69,47.29 125.69,47.11 125.6,47.02 125.4,47.02 125.31,46.94 125.31,44.72 125.7,44.34 125.7,40.25 124.35,38.9 v2(123.75,38.9)
  BOTTOM w0.089: CPU1.AV29 116.61,70.49 v2(116.29,70.81) ; RAM5.G2 v2(123.75,38.9)
M_B_DQ28: length 39.9
  L4SGND w0.089: v2(114.47,70.17) 114.01,69.72 114.01,68.65 114.25,68.41 114.96,68.41 115.19,68.18 115.19,67.77 115.06,67.64 115.06,67.1 115.41,66.74 116.37,66.74 117.79,65.33 118.31,65.33 118.94,64.7 118.94,58.95 118.63,58.64 118.63,54.39 122.24,50.79 122.24,43.68 121.73,43.17 121.73,43.17 121.73,42.66 120.74,41.67 v2(120.74,41.34)
  BOTTOM w0.089: v2(120.74,41.34) 120.74,40.99 120.4,40.65 120.4,38.08 120.02,37.7 RAM5.H7 ; v2(114.47,70.17) 114.8,69.84 CPU1.AR30
M_B_DQ29: length 40.1
  L4SGND w0.089: v2(119.91,41.75) 120.13,41.97 120.13,42.05 121.29,43.21 121.29,43.5 121.65,43.86 121.65,49.79 120.68,50.75 120.68,50.88 120.85,51.04 120.85,51.17 120.72,51.29 120.59,51.29 120.43,51.13 120.3,51.13 120.18,51.25 120.18,51.38 120.43,51.64 120.43,51.76 120.31,51.89 120.18,51.89 119.93,51.63 119.8,51.63 119.67,51.76 119.67,51.88 119.93,52.14 119.93,52.27 119.81,52.39 119.68,52.39 119.42,52.13 119.3,52.13 118.05,53.38 118.05,59.07 118.4,59.42 118.4,64.74 118.17,64.97 117.63,64.97 116.22,66.39 115.27,66.39 115.06,66.6 114.39,67.26 114.39,68.02 113.83,68.58 113.83,70.23 v2(114.44,70.83)
  BOTTOM w0.089: v2(119.91,41.75) 119.73,41.56 119.73,39.68 RAM5.F7 ; CPU1.AR29 114.78,70.49 v2(114.44,70.83)
M_B_DQ30: length 39.2
  L4SGND w0.089: v2(116.28,68.81) 116.28,68.2 117.99,66.49 118.76,66.49 119.77,65.47 120.53,65.47 121.07,64.94 121.07,59.02 121.25,58.84 121.25,55.26 122.29,54.22 122.29,54.09 122.05,53.84 122.05,53.72 122.17,53.59 122.3,53.59 122.55,53.84 122.67,53.84 122.8,53.71 122.8,53.59 122.54,53.33 122.54,53.1 124.68,50.97 124.68,44.08 125.27,43.49 125.27,42.32 124.61,41.67 124.46,41.67 124.2,41.4 124.2,41.08 121.83,38.72 v2(121.83,38.25)
  BOTTOM w0.089: CPU1.AV32 116.56,68.54 v2(116.28,68.81) ; RAM5.H3 122.38,37.7 v2(121.83,38.25)
M_B_DQ31: length 39.9
  L4SGND w0.089: v2(121.18,38.85) 121.66,39.34 121.96,39.34 123,40.38 123,41.22 124.37,42.59 124.37,44.65 124.05,44.97 124.05,51.09 121.63,53.51 121.63,54.4 120.89,55.14 120.89,64.86 120.46,65.3 119.61,65.3 118.65,66.26 117.95,66.26 116.1,68.11 116.1,68.12 115.91,68.31 115.91,68.65 115.88,68.68 115.88,69.37 115.97,69.46 v2(116.29,69.46)
  BOTTOM w0.089: v2(121.18,38.85) 121.18,38.27 RAM5.J3 ; v2(116.29,69.46) 116.45,69.46 CPU1.AV31
M_B_DQ32: length 34.2
  L6 w0.089: v2(120.28,59.07) 120.31,59.07 120.31,58.95 121.37,57.88 121.37,49.85 126.85,44.38 v2(128.25,44.38)
  BOTTOM w0.076: 119.09,60.04 118.89,60.25 118.89,60.79 118.89,60.8 118.89,65.51 118.81,65.76 118.81,65.98 118.81,65.98 118.81,65.99 118.85,66.1 118.85,66.29 118.76,66.53 118.76,66.54 118.68,66.75 CPU1.BA35
  BOTTOM w0.089: v2(120.28,59.07) 120.31,59.07 120.06,59.07 119.09,60.04 ; v2(128.25,44.38) 128.49,44.14 129.9,44.14 130.15,44.39 130.52,44.39 131.3,43.6 131.3,43.3 132.54,42.06 133.14,42.06 RAM8.C2
M_B_DQ33: length 34
  L6 w0.089: v2(120.31,56.28) 120.47,56.12 120.47,48.5 125.13,43.84 125.25,43.84 125.48,44.07 125.61,44.07 125.73,43.94 125.73,43.82 125.5,43.59 125.5,43.46 125.63,43.34 125.76,43.34 125.95,43.53 126.07,43.53 126.2,43.4 126.2,43.28 126.01,43.09 126.01,42.96 126.48,42.49 127.24,42.49 128.43,41.3 v2(129.11,41.3)
  BOTTOM w0.076: 118.15,59.45 118.15,59.71 118.39,59.95 118.39,61 118.4,61.01 118.4,64.84 118.17,65.07 118.17,65.71 118.21,65.79 118.21,65.8 118.27,65.9 118.27,66.85 CPU1.BA34
  BOTTOM w0.089: v2(129.11,41.3) 129.5,40.91 RAM8.D7 ; 118.15,59.45 118.15,58.27 120.14,56.28 v2(120.31,56.28)
M_B_DQ34: length 33.4
  L6 w0.089: v2(120.32,64.11) 121.69,62.74 121.69,59.34 123.55,57.48 123.55,52.03 127.18,48.4 127.71,48.4 128.06,48.05 128.06,47.92 127.93,47.79 127.93,47.66 128.06,47.54 128.18,47.54 128.32,47.67 128.44,47.67 128.91,47.2 129.04,47.2 129.24,47.4 129.37,47.4 129.49,47.27 129.49,47.15 129.31,46.97 129.31,46.85 129.44,46.72 129.57,46.72 129.74,46.9 129.87,46.9 129.99,46.77 129.99,46.65 129.79,46.44 129.79,46.32 130.98,45.13 130.98,43.36 130.44,42.82 129.83,42.82 v2(129.1,42.1)
  BOTTOM w0.076: CPU1.BC35 120.21,66.53 120.21,65.9 120.31,65.71 120.31,65.31 120.09,65.09 120.09,64.34 v2(120.32,64.11)
  BOTTOM w0.089: RAM8.C7 v2(129.1,42.1)
M_B_DQ35: length 34.3
  L6 w0.089: v2(128.87,44.57) 128.53,44.9 127.94,44.9 127.85,44.99 127.85,45.38 127.76,45.46 127.58,45.46 127.49,45.38 127.49,44.99 127.41,44.9 126.86,44.9 121.76,50 121.76,51.36 121.76,57.82 120.68,58.9 120.68,59.33 v2(120.31,59.71)
  BOTTOM w0.076: CPU1.BC34 119.15,67.5 118.95,67.29 118.92,67.27 118.92,66.56 119.01,66.32 119.01,66.08 118.97,65.96 118.97,65.78 119.06,65.54 119.06,60.83 119.17,60.72
  BOTTOM w0.089: v2(128.87,44.57) 129.99,44.57 130.06,44.64 131.36,44.64 RAM8.A3 ; v2(120.31,59.71) 120.18,59.71 119.17,60.72
M_B_DQ36: length 32.2
  L6 w0.089: v2(120.28,58.38) 121.05,57.61 121.05,49.74 121.44,49.36 121.44,49.23 121.18,48.97 121.18,48.84 121.3,48.72 121.43,48.72 121.69,48.98 121.82,48.98 121.94,48.85 121.94,48.73 121.68,48.46 121.68,48.34 121.81,48.21 121.93,48.21 122.19,48.48 122.32,48.48 122.45,48.35 122.45,48.22 122.18,47.96 122.18,47.84 122.31,47.71 122.43,47.71 122.7,47.97 122.82,47.97 122.95,47.85 122.95,47.72 122.69,47.46 122.69,47.33 122.81,47.21 122.94,47.21 123.2,47.47 123.33,47.47 123.45,47.34 123.45,47.22 123.19,46.96 123.19,46.83 123.31,46.7 123.44,46.7 123.7,46.97 123.83,46.97 127.24,43.56 127.66,43.56 128.09,43.14 128.09,42.96 128.15,42.9 v2(128.3,42.9)
  BOTTOM w0.076: CPU1.BA37 118.73,65.4 118.73,60.87 118.72,60.86 118.72,59.69 118.83,59.58
  BOTTOM w0.089: 118.83,59.58 120.03,58.38 v2(120.28,58.38) ; RAM8.B8 v2(128.3,42.9)
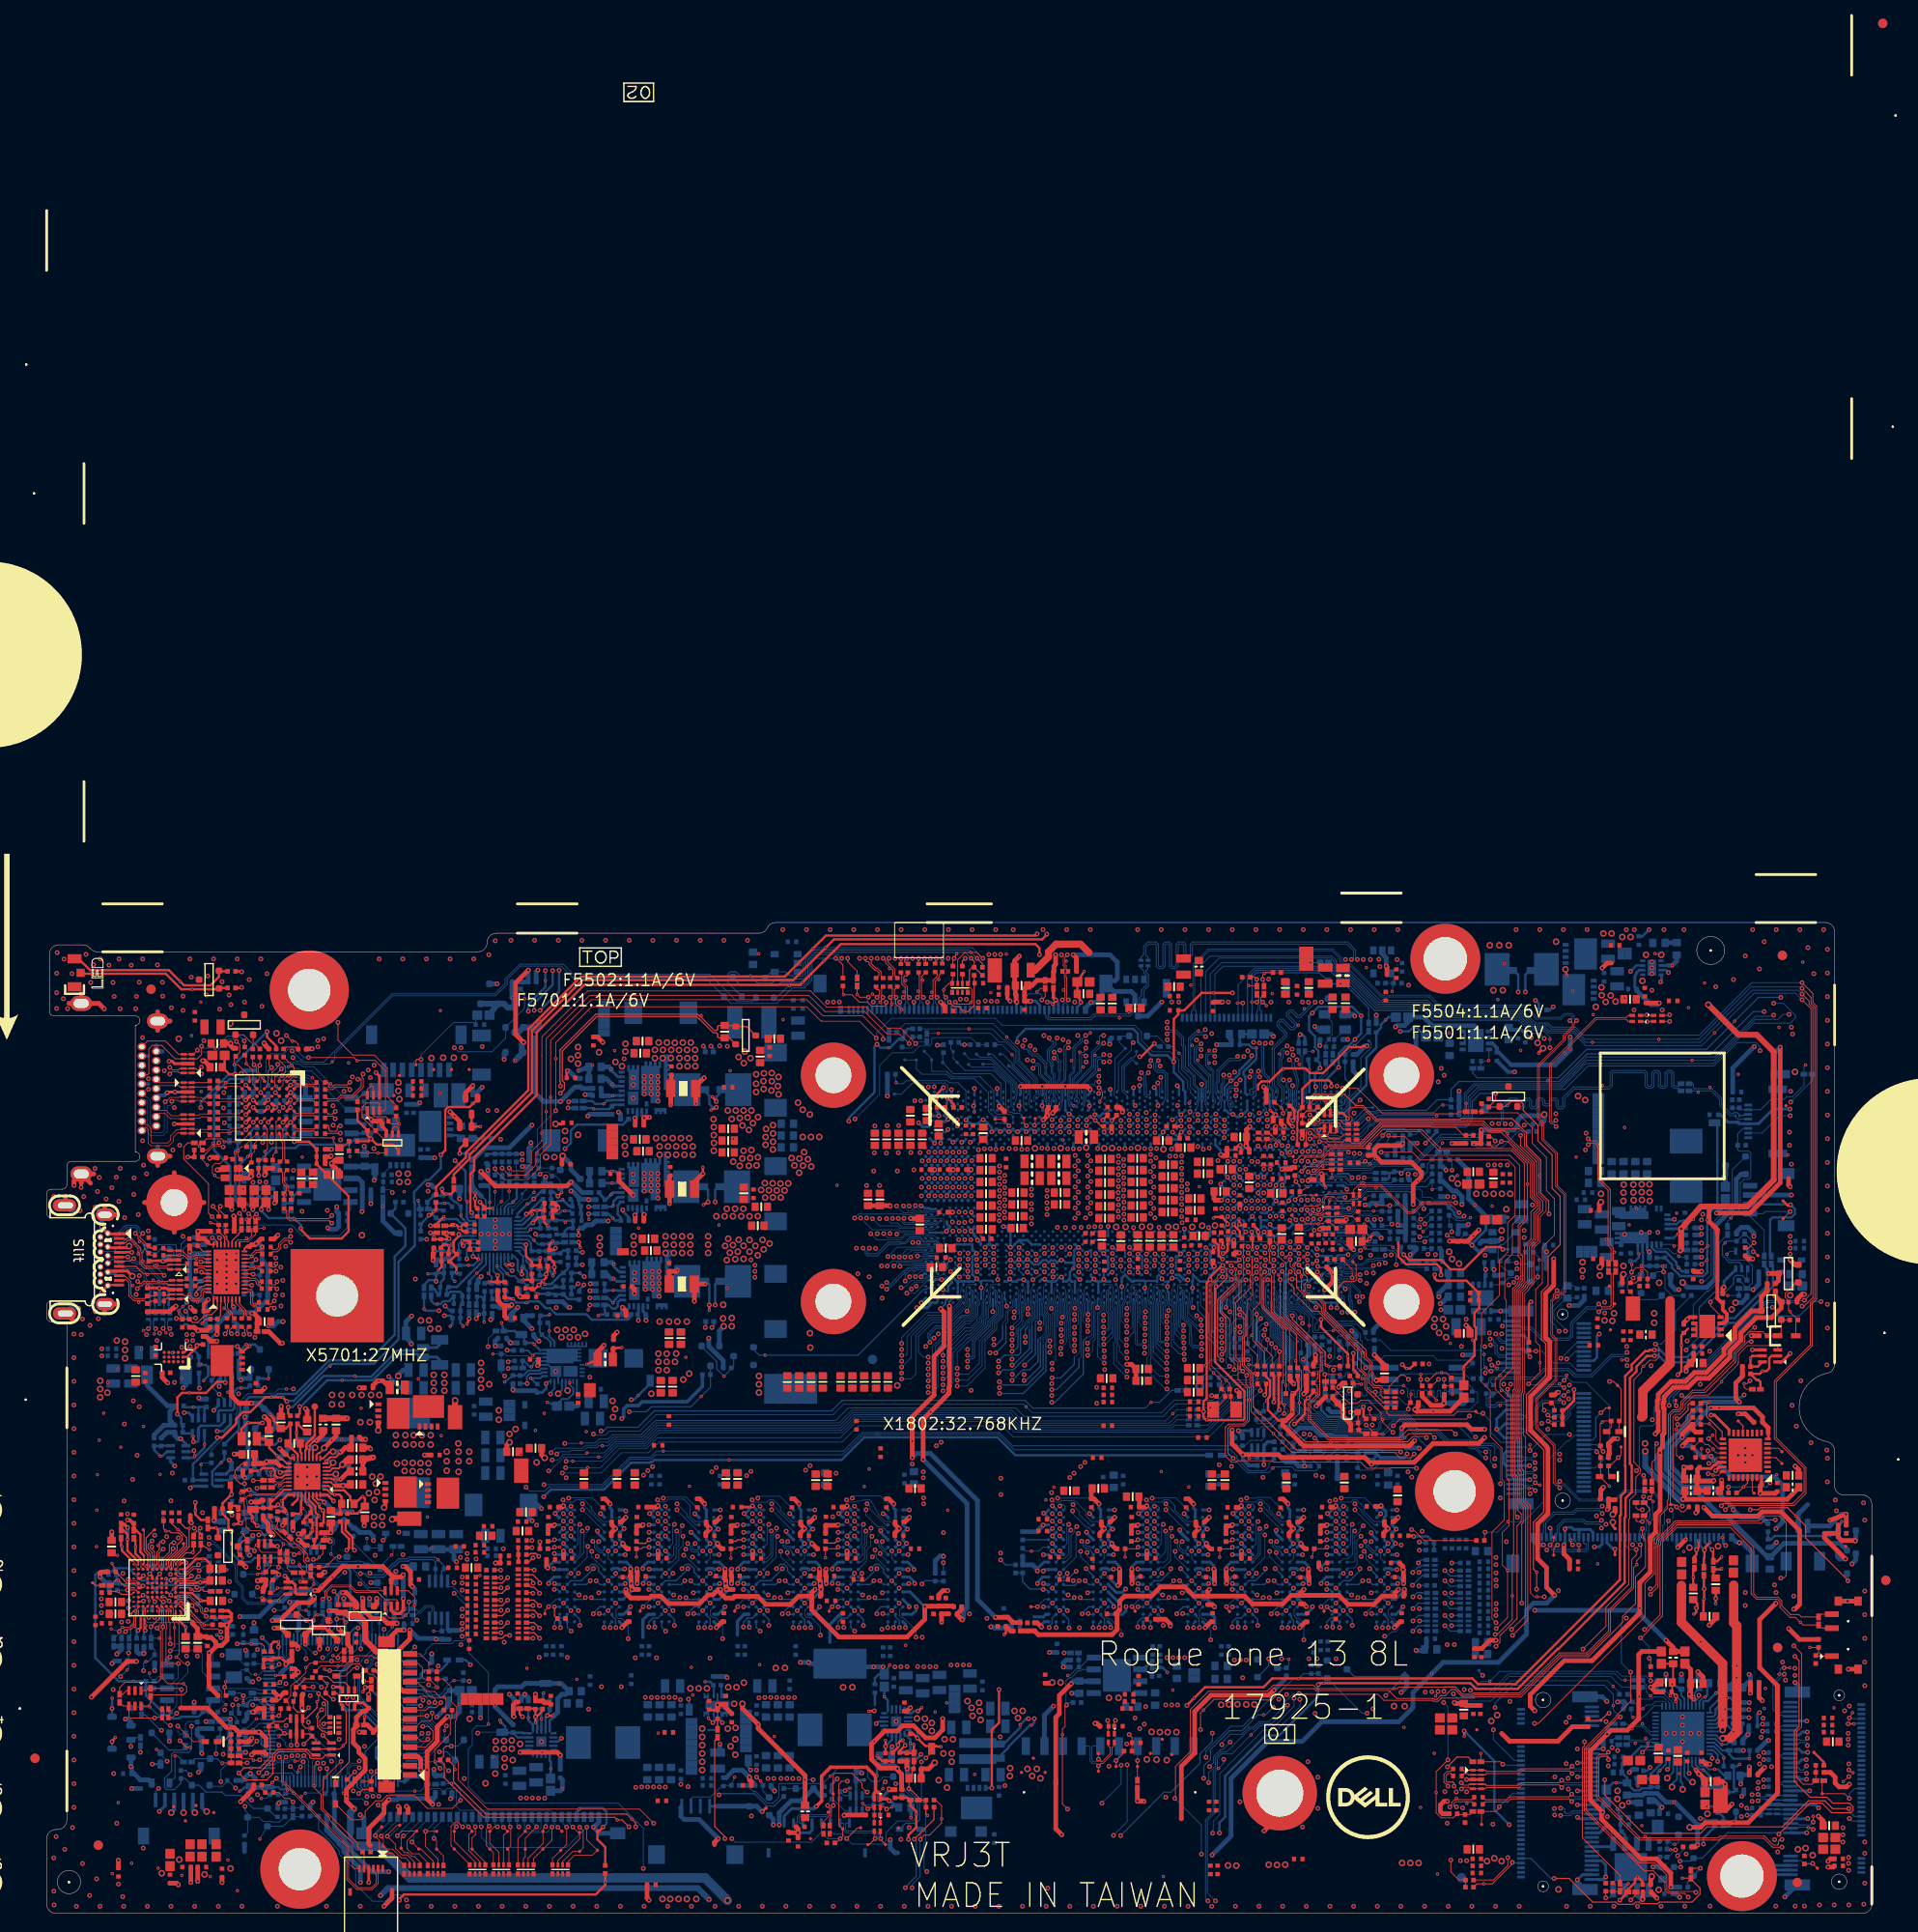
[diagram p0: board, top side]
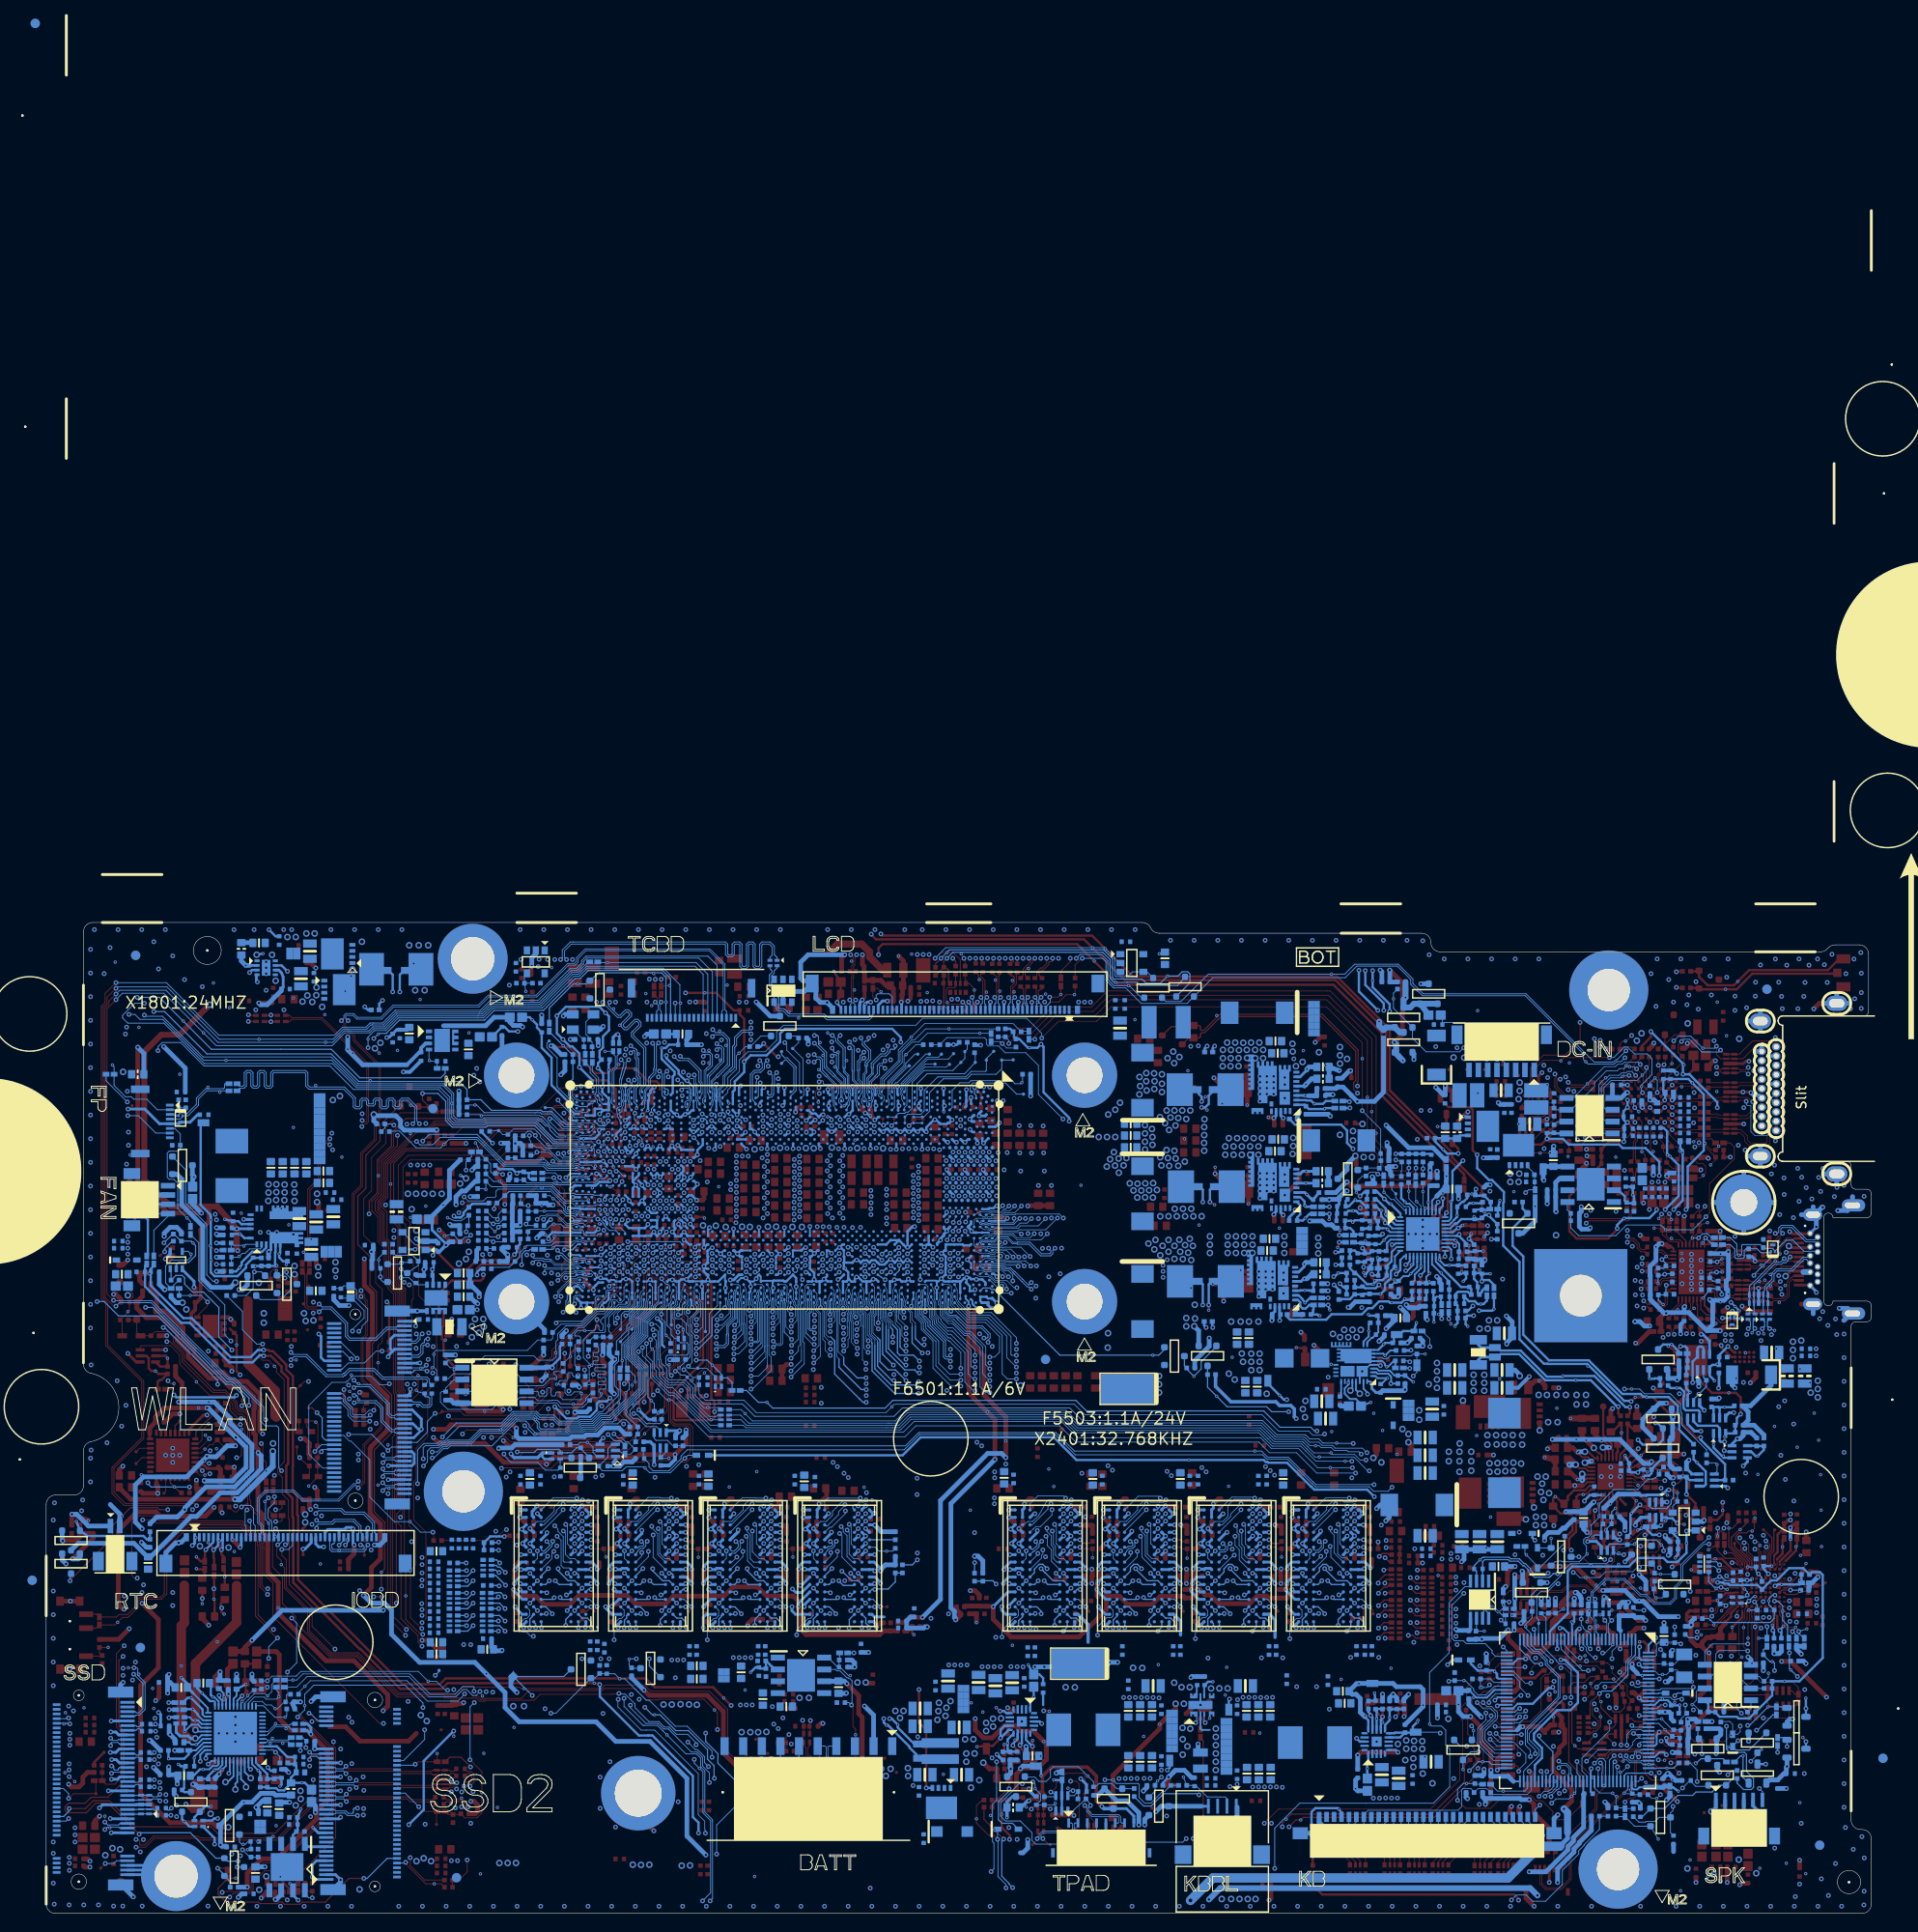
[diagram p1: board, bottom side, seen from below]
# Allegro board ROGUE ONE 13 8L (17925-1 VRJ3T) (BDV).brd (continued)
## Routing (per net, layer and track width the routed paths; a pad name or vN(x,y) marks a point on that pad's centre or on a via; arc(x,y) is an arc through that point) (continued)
M_B_DQ37: length 32.8
  L6 w0.089: v2(120.31,57.68) 120.76,57.23 120.76,48.69 123.05,46.4 123.89,46.4 124.1,46.19 124.1,46.07 123.84,45.81 123.84,45.68 123.97,45.56 124.09,45.56 124.35,45.81 124.47,45.81 124.6,45.69 124.6,45.56 124.34,45.31 124.34,45.18 124.47,45.06 124.6,45.06 124.85,45.31 124.98,45.31 125.1,45.19 125.1,45.06 124.85,44.8 124.85,44.68 124.97,44.55 125.1,44.55 125.35,44.81 125.48,44.81 126.94,43.34 127.57,43.34 127.87,43.05 127.87,42.53 v2(128.3,42.1)
  BOTTOM w0.076: CPU1.BA36 118.59,66.14 118.44,65.87 118.44,65.86 118.38,65.77 118.38,65.75 118.36,65.72 118.33,65.67 118.33,65.4 118.56,65.16 118.56,60.94 118.56,60.93 118.56,59.14
  BOTTOM w0.089: 118.56,59.14 118.56,58.62 119.5,57.68 v2(120.31,57.68) ; v2(128.3,42.1) RAM8.C8
M_B_DQ38: length 32
  L6 w0.089: v2(130.34,43.33) 130.77,43.75 130.77,44.93 128.7,47 127.24,47 126.73,47.5 126.73,48.43 123.26,51.9 123.26,57.52 121.45,59.33 121.45,62.33 v2(120.28,63.5)
  BOTTOM w0.076: CPU1.BC36 119.89,66.14 120.04,65.86 120.04,65.86 120.14,65.67 120.14,65.38 119.92,65.16 119.92,63.86 v2(120.28,63.5)
  BOTTOM w0.089: v2(130.34,43.33) 130.42,43.33 132.7,41.05 RAM8.D3
M_B_DQ39: length 31.3
  L6 w0.089: v2(130.34,43.96) 130.34,44.39 130.34,44.94 128.58,46.7 127.12,46.7 126.38,47.44 126.38,48.33 123.85,50.85 123.73,50.85 123.4,50.52 123.27,50.52 123.15,50.65 123.15,50.77 123.48,51.1 123.48,51.23 122.97,51.74 122.97,51.86 122.97,57.56 122.65,57.87 122.65,57.87 121.27,59.25 121.27,59.25 121.27,59.4 121.27,59.4 121.27,61.99 120.38,62.89 v2(120.3,62.89)
  BOTTOM w0.076: v2(120.3,62.89) 119.75,63.45 119.75,65.41 CPU1.BC37
  BOTTOM w0.089: v2(130.34,43.96) 131.06,43.24 131.06,43.23 132.59,41.7 RAM8.C3
M_B_DQ40: length 37.7
  L6 w0.089: v2(130.82,40.62) 131.39,41.19 131.39,41.38 132.72,42.7 132.72,43.11 132.5,43.33 132.5,47.57 128.79,51.28 127.27,51.28 126.58,51.96 126.58,52.51 126.67,52.59 126.85,52.59 126.94,52.68 126.94,52.86 126.85,52.95 126.67,52.95 126.58,53.04 126.58,53.52 126.15,53.96 126.15,56.08 125.05,57.18 125.05,57.73 123.36,59.42 123.36,61.05 122.54,61.87 v2(122.09,61.87)
  BOTTOM w0.076: CPU1.BE35 121.2,66.75 121.29,66.49 121.29,66.49 121.36,66.31 121.36,66.08 121.32,65.99 121.32,65.75 121.39,65.58 121.39,63.22
  BOTTOM w0.089: RAM8.J7 130.82,38.22 v2(130.82,40.62) ; v2(122.09,61.87) 121.39,62.57 121.39,63.22
M_B_DQ41: length 37.4
  L6 w0.089: v2(130.09,42.06) 131.48,43.45 131.48,47.04 131.12,47.4 130.43,47.4 129.68,48.15 129.68,49.09 128.46,50.31 126.82,50.31 125.16,51.97 125.16,52.1 125.25,52.19 125.5,52.19 125.59,52.28 125.59,52.46 125.5,52.55 124.94,52.55 124.85,52.63 124.85,52.81 124.94,52.9 125.5,52.9 125.59,52.99 125.59,53.17 125.5,53.26 124.94,53.26 124.85,53.35 124.85,54.9 124.17,55.59 124.17,57.47 122.72,58.92 122.72,59.47 v2(122.15,60.04)
  BOTTOM w0.076: 120.77,64.19 120.87,64.29 120.87,65.13 120.67,65.33 120.67,65.7 120.76,65.86 120.81,65.95 120.81,66.89 CPU1.BE34
  BOTTOM w0.089: RAM8.F7 129.85,39.65 129.85,41.82 v2(130.09,42.06) ; 120.77,64.19 120.77,60.91 121.65,60.04 v2(122.15,60.04)
M_B_DQ42: length 37.6
  L6 w0.089: v2(123.94,63.72) 124.37,63.72 125.74,62.34 125.74,59.12 126.59,58.28 127.04,58.28 127.36,57.96 127.5,57.96 129.17,56.28 129.17,54.83 132.07,51.94 132.07,51.07 134.63,48.51 134.63,45.85 135.94,44.53 135.94,39.71 135.4,39.16 134.16,39.16 v2(133.9,38.9)
  BOTTOM w0.076: 122.66,64.4 122.66,65.15 122.83,65.32 122.83,65.7 122.72,65.9 122.72,66.53 CPU1.BG35
  BOTTOM w0.089: v2(133.9,38.9) 133.9,38.1 RAM8.H2 ; v2(123.94,63.72) 123.33,63.72 122.66,64.4
M_B_DQ43: length 38.3
  L6 w0.089: v2(122.1,62.52) 122.71,62.52 123.59,61.63 123.59,59.6 125.34,57.85 125.34,57.3 126.45,56.18 126.45,54.15 132.8,47.8 132.8,43.86 132.96,43.71 132.96,42.46 132.17,41.67 131.99,41.67 131.61,41.29 131.61,40.78 130.85,40.02 130.85,39.26 131.26,38.85 v2(131.33,38.85)
  BOTTOM w0.076: CPU1.BG34 121.67,67.5 121.63,67.46 121.46,67.28 121.46,66.52 121.53,66.32 121.53,66.08 121.49,65.96 121.49,65.78 121.57,65.57 121.57,63.73
  BOTTOM w0.089: 121.57,63.73 121.57,63.05 v2(122.1,62.52) ; RAM8.J3 131.33,38.27 v2(131.33,38.85)
M_B_DQ44: length 36
  L6 w0.089: v2(130.98,41.55) 131.3,41.87 131.3,41.99 131.2,42.1 131.2,42.22 131.32,42.35 131.45,42.35 131.55,42.25 131.68,42.25 131.84,42.41 131.84,43.1 132.06,43.32 132.06,47.55 128.66,50.95 127.18,50.95 126.29,51.84 126.29,53.4 125.72,53.97 125.72,55.05 125.86,55.19 125.86,55.95 124.75,57.06 124.75,57.61 123.1,59.26 123.1,60.24 123,60.34 122.73,60.34 122.62,60.45 122.62,60.68 122.71,60.77 122.91,60.77 123.04,60.9 123.04,61.11 122.89,61.26 v2(122.12,61.26)
  BOTTOM w0.076: CPU1.BE37 121.22,65.43 121.22,63.31 121.18,63.27 121.18,63.22
  BOTTOM w0.089: 121.18,63.22 121.18,62.19 v2(122.12,61.26) ; v2(130.98,41.55) 130.98,41.39 130.33,40.75 130.33,38.53 RAM8.H7
M_B_DQ45: length 37.1
  L6 w0.089: v2(130.28,41.29) 130.28,41.65 130.51,41.88 130.51,42.07 131.77,43.33 131.77,47.23 131.31,47.69 130.55,47.69 130.17,48.08 130.17,48.2 130.29,48.33 130.29,48.33 130.39,48.43 130.39,48.8 128.54,50.65 127.06,50.65 126,51.72 126,53.28 125.43,53.85 125.43,55.17 125.57,55.31 125.57,55.83 125.1,56.3 124.97,56.3 124.84,56.17 124.71,56.17 124.59,56.29 124.59,56.42 124.72,56.55 124.72,56.68 124.46,56.94 124.46,57.59 122.92,59.12 122.92,59.87 v2(122.14,60.65)
  BOTTOM w0.076: 120.99,63.22 120.99,63.31 121.04,63.36 121.04,65.2 120.85,65.39 120.85,65.68 121.1,66.14 CPU1.BE36
  BOTTOM w0.089: 120.99,63.22 120.99,61.37 121.72,60.65 v2(122.14,60.65) ; RAM8.H8 129.06,38.06 129.56,38.06 130.12,38.62 130.12,41.13 v2(130.28,41.29)
M_B_DQ46: length 37.3
  L6 w0.089: v2(133.11,38.9) 133.11,39.92 133.39,40.2 135.34,40.2 135.64,40.49 135.64,44.28 134.34,45.58 134.34,48.39 131.49,51.23 131.49,51.36 131.73,51.59 131.73,51.72 131.6,51.84 131.48,51.84 131.24,51.61 131.11,51.61 130.91,51.81 130.91,51.94 131.2,52.23 131.2,52.36 128.84,54.71 128.84,56.2 126.94,58.1 126.51,58.1 125.39,59.23 125.39,61.71 v2(123.99,63.11)
  BOTTOM w0.076: CPU1.BG36 122.4,66.14 122.56,65.86 122.56,65.86 122.66,65.67 122.66,65.38 122.49,65.21 122.49,64.07 122.56,64
  BOTTOM w0.089: v2(123.99,63.11) 123.44,63.11 122.56,64 ; RAM8.G2 133.5,38.51 v2(133.11,38.9)
M_B_DQ47: length 36.2
  L6 w0.089: v2(123.99,62.5) 125.11,61.38 125.11,59.38 125.21,59.28 125.21,59.15 126.44,57.92 126.69,57.92 128.49,56.13 128.49,54.65 130.6,52.55 130.6,51.71 134.04,48.26 134.04,45.14 135.42,43.76 135.42,41.27 134.68,40.53 133.16,40.53 132.7,40.07 132.7,39.36 v2(132.04,38.73)
  BOTTOM w0.076: CPU1.BG37 122.27,65.41 122.27,63.99 122.53,63.73
  BOTTOM w0.089: RAM8.H3 132.04,38.36 v2(132.04,38.73) ; 122.53,63.73 123.76,62.5 v2(123.99,62.5)
M_B_DQ48: length 40.6
  L4SGND w0.089: v2(118.1,68.85) 118.1,68.22 120.31,66.01 120.76,66.01 122.01,64.75 122.01,63.9 122.75,63.16 122.75,58.36 124.61,56.5 124.61,55.21 124.98,54.83 125.79,54.83 128.79,51.83 128.79,50.72 133.44,46.07 133.57,46.07 133.71,46.21 133.83,46.21 133.96,46.08 133.96,45.96 133.82,45.82 133.82,45.69 133.94,45.57 134.07,45.57 134.22,45.71 134.34,45.71 134.47,45.59 134.47,45.46 134.32,45.31 134.32,45.19 134.45,45.06 134.57,45.06 134.71,45.2 134.84,45.2 134.96,45.08 134.96,44.95 134.82,44.81 134.82,44.69 134.95,44.56 135.07,44.56 135.2,44.68 135.32,44.68 135.45,44.56 135.45,44.43 135.33,44.31 135.33,44.18 135.45,44.06 135.58,44.06 135.66,44.14 135.79,44.14 135.91,44.01 135.91,43.89 135.83,43.81 135.83,43.68 136.06,43.45 136.18,43.45 136.27,43.54 136.39,43.54 136.52,43.41 136.52,43.29 136.43,43.2 136.43,43.08 137.38,42.13 137.67,42.13 137.69,42.1 v2(138.45,42.1)
  BOTTOM w0.089: RAM7.C8 v2(138.45,42.1) ; CPU1.BA32 v2(118.1,68.85)
M_B_DQ49: length 41.3
  L4SGND w0.089: v2(138.45,42.9) 136.55,44.8 135.69,44.8 133.75,46.74 133.62,46.74 133.59,46.71 133.46,46.71 133.33,46.83 133.33,46.96 133.37,46.99 133.37,47.12 133.24,47.25 133.12,47.25 132.98,47.11 132.86,47.11 132.73,47.24 132.73,47.36 132.87,47.5 132.87,47.62 132.74,47.75 132.61,47.75 132.48,47.61 132.35,47.61 132.23,47.74 132.23,47.86 132.36,48 132.36,48.12 132.24,48.25 132.11,48.25 131.98,48.12 131.85,48.12 131.72,48.24 131.72,48.37 131.86,48.5 131.86,48.63 131.73,48.75 131.61,48.75 131.47,48.62 131.35,48.62 131.22,48.74 131.22,48.87 131.36,49.01 131.36,49.13 131.23,49.26 131.11,49.26 130.97,49.12 130.84,49.12 130.72,49.25 130.72,49.37 130.85,49.51 130.85,49.63 130.73,49.76 130.6,49.76 130.47,49.62 130.34,49.62 130.22,49.75 130.22,49.88 130.35,50.01 130.35,50.14 130.23,50.26 130.1,50.26 129.96,50.13 129.84,50.13 129.71,50.25 129.71,50.38 129.85,50.51 129.85,50.64 129.72,50.77 129.6,50.77 129.46,50.63 129.34,50.63 129.21,50.76 129.21,50.88 129.35,51.02 129.35,51.14 129.08,51.4 129.08,52.45 122.98,58.56 122.98,63.33 122.29,64.02 122.29,64.73 120.83,66.19 120.38,66.19 118.99,67.57 118.99,68.57 v2(118.1,69.46)
  BOTTOM w0.089: CPU1.BA31 v2(118.1,69.46) ; RAM7.B8 v2(138.45,42.9)
M_B_DQ50: length 42.8
  L4SGND w0.089: v2(120.82,69.54) 121.18,69.54 121.27,69.45 121.27,68.67 121.55,68.39 121.55,67.49 122.78,66.26 122.93,66.26 122.93,66.26 123.59,66.26 123.61,66.24 125.52,64.33 125.52,58.93 125.92,58.53 125.92,58.41 125.84,58.33 125.84,58.2 125.96,58.08 126.09,58.08 126.17,58.15 126.29,58.15 127.5,56.94 127.63,56.94 127.74,57.06 127.97,57.06 129.02,56.01 129.02,55.79 128.9,55.67 128.9,55.54 129.03,55.42 129.15,55.42 129.27,55.53 129.4,55.53 129.52,55.41 129.52,55.28 129.41,55.17 129.41,55.04 129.53,54.92 129.66,54.92 129.77,55.03 129.9,55.03 130.02,54.9 130.02,54.78 129.91,54.66 129.91,54.54 130.04,54.41 130.16,54.41 130.28,54.53 130.4,54.53 130.53,54.4 130.53,54.28 130.41,54.16 130.41,54.04 130.54,53.91 130.66,53.91 130.78,54.03 130.9,54.03 136.27,48.66 137.28,48.66 137.77,48.16 140.8,45.14 140.8,44.27 140.92,44.14 140.92,43.47 140.78,43.33 v2(140.49,43.33)
  BOTTOM w0.089: v2(140.49,43.33) 140.49,43.26 RAM7.D3 ; v2(120.82,69.54) CPU1.BD31
M_B_DQ51: length 43.3
  L4SGND w0.089: v2(120.84,68.85) 121.37,68.32 121.37,67.42 122.73,66.06 123.5,66.06 125.31,64.24 125.31,58.36 125.99,57.68 126.35,57.68 127.38,56.65 127.97,56.65 128.52,56.1 128.52,55.52 130.42,53.62 130.73,53.62 131,53.35 131,53.04 131.12,52.91 131.25,52.91 131.36,53.03 131.49,53.03 131.62,52.9 131.62,52.78 131.5,52.66 131.5,52.53 131.63,52.41 131.75,52.41 131.87,52.52 131.99,52.52 132.12,52.4 132.12,52.27 132,52.16 132,52.03 132.13,51.91 132.25,51.91 132.37,52.02 132.5,52.02 132.62,51.89 132.62,51.77 132.51,51.65 132.51,51.53 132.63,51.4 132.76,51.4 132.87,51.52 133,51.52 133.12,51.39 133.12,51.27 133.01,51.15 133.01,51.03 133.13,50.9 133.26,50.9 133.38,51.01 133.5,51.01 133.63,50.89 133.63,50.76 133.51,50.65 133.51,50.52 133.64,50.4 133.76,50.4 133.88,50.51 134,50.51 134.13,50.39 134.13,50.26 134.01,50.14 134.01,50.02 134.14,49.89 134.27,49.89 134.38,50.01 134.51,50.01 134.63,49.88 134.63,49.76 134.52,49.64 134.52,49.52 134.64,49.39 134.77,49.39 134.88,49.51 135.01,49.51 135.14,49.38 135.14,49.25 135.02,49.14 135.02,49.01 135.15,48.89 135.27,48.89 135.39,49 135.51,49 135.64,48.88 135.64,48.75 135.52,48.64 135.52,48.51 135.73,48.3 137.2,48.3 140.49,45.01 v2(140.49,43.96)
  BOTTOM w0.089: v2(140.49,43.96) 141.21,43.24 141.21,43.05 142.56,41.7 RAM7.C3 ; v2(120.84,68.85) CPU1.BD32
M_B_DQ52: length 42.8
  L4SGND w0.089: v2(118.1,70.1) 118.5,69.69 118.5,69.37 119.17,68.7 119.17,67.65 120.46,66.36 120.9,66.36 122.57,64.7 122.57,64.43 123.31,63.7 123.31,58.65 129.38,52.57 129.38,51.53 135.82,45.08 137.71,45.08 v2(138.4,44.38)
  BOTTOM w0.089: v2(138.4,44.38) 138.64,44.14 140.05,44.14 140.3,44.39 140.67,44.39 141.45,43.6 141.45,43.16 142.55,42.06 143.29,42.06 RAM7.C2 ; CPU1.BA30 v2(118.1,70.1)
M_B_DQ53: length 43.3
  L4SGND w0.089: v2(139.02,44.57) 138.1,45.48 137.89,45.48 137.8,45.57 137.8,45.8 137.71,45.89 137.54,45.89 137.45,45.8 137.45,45.62 137.36,45.53 137.18,45.53 137.09,45.62 137.09,45.95 137,46.04 136.82,46.04 136.74,45.95 136.74,45.62 136.65,45.53 136.47,45.53 136.38,45.62 136.38,46.03 136.29,46.12 136.11,46.12 136.02,46.03 136.02,45.67 135.93,45.59 135.73,45.59 129.67,51.65 129.67,52.7 124.47,57.89 124.47,64.22 123.22,65.47 122.24,65.47 121.17,66.54 120.53,66.54 119.35,67.72 119.35,69.79 v2(119.01,70.12)
  BOTTOM w0.089: v2(139.02,44.57) 139.05,44.6 141.55,44.6 RAM7.A3 ; v2(119.01,70.12) CPU1.BA29
M_B_DQ54: length 43.8
  L4SGND w0.089: v2(139.26,41.3) 139.69,41.74 139.69,41.83 140.09,42.23 140.31,42.23 141.36,43.28 141.36,45.41 136.17,50.6 135.93,50.6 135.66,50.87 134.94,50.87 134.58,51.22 134.58,51.73 134.86,52.01 134.86,52.25 133.81,53.31 133.31,53.31 133.11,53.1 132.71,53.1 129.92,55.9 129.92,55.94 127.98,57.88 127.63,57.88 127.39,57.88 127.04,58.24 126.96,58.24 126.61,58.58 126.61,63.17 126.75,63.31 126.75,63.73 125.98,64.5 125.93,64.5 123.76,66.67 122.94,66.67 121.91,67.7 121.91,68.54 121.68,68.77 121.68,69.88 120.96,70.6 120.38,70.6 v2(119.93,70.15)
  BOTTOM w0.089: CPU1.BD29 v2(119.93,70.15) ; v2(139.26,41.3) 139.65,40.91 RAM7.D7
M_B_DQ55: length 43.5
  L4SGND w0.089: v2(139.25,42.1) 140.05,42.89 140.66,42.89 141.14,43.37 141.14,45.21 136.93,49.42 136.77,49.42 136.41,49.06 136.28,49.06 136.06,49.29 136.06,49.41 136.39,49.75 136.39,49.87 136.27,50 136.14,50 135.83,49.69 135.65,49.69 135.53,49.81 135.53,49.94 135.79,50.2 135.79,50.32 135.66,50.45 135.54,50.45 135.28,50.19 135.15,50.19 133.8,51.55 133.8,51.67 133.97,51.84 133.97,51.97 133.84,52.09 133.71,52.09 133.54,51.92 133.42,51.92 133.29,52.05 133.29,52.2 133.44,52.35 133.44,52.47 133.31,52.6 133.19,52.6 133.08,52.49 132.91,52.49 129.62,55.78 129.62,55.82 127.86,57.59 127.27,57.59 125.69,59.17 125.69,64.41 125.67,64.43 123.66,66.44 122.92,66.44 121.73,67.63 121.73,68.47 121.5,68.69 121.5,69.49 v2(120.79,70.2)
  BOTTOM w0.089: RAM7.C7 v2(139.25,42.1) ; v2(120.79,70.2) CPU1.BD30
M_B_DQ56: length 45.4
  L4SGND w0.089: v2(141.39,41.6) 142.82,43.03 142.82,45.39 142.91,45.48 143.13,45.48 143.22,45.57 143.22,45.75 143.13,45.84 142.91,45.84 142.82,45.93 142.82,46.1 142.91,46.19 143.08,46.19 143.17,46.28 143.17,46.46 143.08,46.55 142.91,46.55 142.82,46.64 142.82,46.98 141.75,48.05 141.75,48.71 139.21,51.25 137.9,51.25 135.41,53.74 135.38,53.74 132.79,56.32 131.5,57.61 131.5,57.61 129.78,59.33 129.78,59.8 127.66,61.93 127.66,65.62 127.09,66.19 125.33,66.19 123.6,67.91 123.6,68.24 123.13,68.71 123.13,69.06 v2(122.64,69.54)
  BOTTOM w0.089: CPU1.BG31 122.3,69.19 v2(122.64,69.54) ; v2(141.39,41.6) 141.04,41.25 141.04,40.99 140.48,40.43 140.48,37.81 140.36,37.7 RAM7.H7
M_B_DQ57: length 44.7
  L4SGND w0.089: v2(141.14,40.47) 140.96,40.64 140.96,41.78 142.53,43.34 142.53,46.82 141.39,47.95 141.39,48.56 139.52,50.43 139.39,50.43 139.3,50.34 139.18,50.34 139.05,50.46 139.05,50.59 139.09,50.63 139.09,50.75 138.95,50.89 137.81,50.89 131.38,57.32 131.29,57.32 131.27,57.34 130.89,57.34 129.53,58.7 129.53,59.76 127.47,61.82 127.47,65.45 126.96,65.96 125.3,65.96 123.42,67.84 123.42,68.03 122.66,68.79 v2(122.66,68.84)
  BOTTOM w0.089: CPU1.BG32 122.36,68.54 v2(122.66,68.84) ; RAM7.J7 139.83,37.08 140.45,37.08 140.7,37.33 140.7,40.04 v2(141.14,40.47)
M_B_DQ58: length 44.9
  L4SGND w0.089: v2(124.45,68.83) 124.45,67.85 125.51,66.79 127.42,66.79 128.99,65.22 128.99,61.43 132.19,58.23 133.18,58.23 137.36,54.05 137.36,53.63 138.54,52.46 139.74,52.46 144.43,47.77 144.43,42.32 143.32,41.22 142.72,39.79 142.49,39.56 v2(141.48,38.85)
  BOTTOM w0.089: v2(124.45,68.83) 124.16,68.54 CPU1.BK32 ; v2(141.48,38.85) 141.69,38.64 141.69,38.06 RAM7.J3
M_B_DQ59: length 45.3
  L4SGND w0.089: v2(142.16,38.33) 142.16,38.71 143.97,40.52 144.82,40.52 145.57,41.27 145.57,43.69 144.72,44.54 144.72,47.89 139.86,52.75 138.66,52.75 137.66,53.75 137.66,54.17 133.26,58.57 132.22,58.57 129.86,60.92 129.17,61.61 129.17,65.42 127.55,67.05 126.49,67.05 125.98,67.56 125.54,68 125.54,68 125.38,68.16 125.38,68.46 124.78,69.06 124.78,69.2 v2(124.47,69.51)
  BOTTOM w0.089: v2(142.16,38.33) 142.78,37.7 RAM7.H3 ; v2(124.47,69.51) 124.15,69.19 CPU1.BK31
M_B_DQ60: length 45.6
  L4SGND w0.089: v2(140.21,41.75) 141.94,43.48 141.94,45.67 140.37,47.24 140.37,47.36 140.61,47.61 140.61,47.73 140.49,47.86 140.36,47.86 140.12,47.62 139.99,47.62 139.87,47.74 139.87,47.87 140.11,48.11 140.11,48.24 139.99,48.36 139.86,48.36 139.62,48.12 139.49,48.12 139.37,48.25 139.37,48.37 139.61,48.61 139.61,48.74 139.48,48.86 139.36,48.86 139.11,48.62 138.99,48.62 138.86,48.75 138.86,48.87 139.03,49.04 139.03,49.17 138.9,49.29 138.78,49.29 138.61,49.12 138.49,49.12 136.79,50.82 136.79,51.06 131.15,56.71 130.52,56.71 126.99,60.24 126.99,63.77 123.23,67.53 122.43,67.53 122.37,67.59 122.09,67.88 122.09,68.61 121.88,68.82 121.88,70.02 v2(122.64,70.78)
  BOTTOM w0.089: RAM7.F7 140.03,39.68 140.03,41.56 v2(140.21,41.75) ; v2(122.64,70.78) 122.35,70.49 CPU1.BG29
M_B_DQ61: length 45.3
  L4SGND w0.089: v2(140.47,41.04) 140.74,41.32 140.74,41.87 142.23,43.36 142.23,46.7 140.66,48.28 140.66,48.4 140.82,48.57 140.82,48.69 140.7,48.82 140.57,48.82 140.4,48.65 140.28,48.65 140.15,48.78 140.15,48.9 140.32,49.07 140.32,49.2 140.19,49.32 140.07,49.32 139.9,49.16 139.78,49.16 138.67,50.26 138.03,50.26 131.26,57.03 130.71,57.03 127.17,60.57 127.17,63.84 123.13,67.88 123.13,67.97 122.66,68.44 122.49,68.44 122.26,68.67 122.26,68.69 122.24,68.71 122.24,69.75 v2(122.67,70.17)
  BOTTOM w0.089: v2(122.67,70.17) 122.34,69.84 CPU1.BG30 ; v2(140.47,41.04) 140.25,40.82 140.25,38.55 139.76,38.06 139.21,38.06 RAM7.H8
M_B_DQ62: length 46.4
  L4SGND w0.089: v2(124.47,70.17) 124.96,69.68 124.96,69.13 125.59,68.51 125.59,68.2 125.71,68.07 126.51,67.28 127.75,67.28 129.35,65.68 129.35,61.69 132.14,58.9 133.34,58.9 137.95,54.29 137.95,53.87 138.78,53.04 139.98,53.04 145.01,48.01 145.01,47.77 145.01,44.68 145.84,43.86 145.84,40.22 145.75,40.13 143.88,40.13 143.61,39.86 143.61,39.25 v2(143.26,38.9)
  BOTTOM w0.089: RAM7.H2 143.26,38.09 v2(143.26,38.9) ; v2(124.47,70.17) 124.14,69.84 CPU1.BK30
M_B_DQ63: length 46.9
  L4SGND w0.089: v2(124.5,70.83) 124.7,70.83 125.87,69.67 125.87,68.17 125.89,68.15 126.12,67.91 126.13,67.91 126.53,67.51 127.93,67.51 129.53,65.91 129.53,61.89 132.27,59.15 133.5,59.15 138.24,54.41 138.24,53.99 138.9,53.33 140.1,53.33 145.35,48.08 145.35,44.77 146.14,43.99 146.14,38.96 145.98,38.8 145.64,38.8 145.33,39.11 145,39.11 144.59,38.7 144.26,38.7 v2(144.05,38.9)
  BOTTOM w0.089: CPU1.BK29 124.35,70.83 v2(124.5,70.83) ; RAM7.G2 v2(144.05,38.9)
M_B_DQS_DN0: length 30.7
  L6 w0.089: v2(108.81,43.72) 109.11,43.43 109.24,43.43 109.45,43.63 109.45,45.57 109.64,45.76 109.64,45.77 112.97,49.11 112.97,52.02 113.19,52.23 113.53,52.23 113.63,52.33 113.63,52.65 113.51,52.77 113.24,52.77 113.02,52.99 113.02,53.45 113.23,53.66 113.62,53.66 113.73,53.77 113.73,57.64 114.18,58.08 114.18,60.84 114.82,61.48 114.82,62.08 114.36,62.53 113.72,62.53 v2(113.49,62.3)
  BOTTOM w0.076: CPU1.AP35 114.2,66.7 114.16,66.74 114.08,66.77 113.98,66.73 113.94,66.61 113.94,66.43 113.98,66.32 113.98,66.08 113.94,65.96 113.94,65.78 113.98,65.67 113.98,64.62 114.16,64.45 114.16,62.73 113.97,62.53 113.73,62.53 v2(113.49,62.3)
  BOTTOM w0.102: RAM6.A7 109.37,43.47 109.37,43.67 109.17,43.87 108.96,43.87 v2(108.81,43.72)
M_B_DQS_DN1: length 34.5
  L6 w0.089: v2(111.79,39.91) 111.95,40.08 111.95,40.33 114.07,42.45 114.07,43.33 114.63,43.88 115.16,43.88 115.62,44.35 115.62,44.75 116.09,45.22 116.18,45.22 116.49,45.22 116.84,45.56 116.84,45.94 117.1,46.19 117.47,46.19 117.77,46.49 117.77,46.87 117.97,47.07 118.35,47.07 118.74,47.46 118.74,60.23 118.33,60.65 118.33,61.01 v2(117.92,61.42)
  BOTTOM w0.076: v2(117.92,61.42) 117.9,61.42 117.62,61.13 117.18,61.13 117.1,61.22 117.1,65.58 117.14,65.71 117.15,65.72 117.16,65.74 117.16,66 117.15,66.02 117.12,66.1 117.12,66.29 117.15,66.37 117.16,66.39 117.16,66.62 117.12,66.75 117.12,66.79 116.98,66.92 116.8,66.92 116.72,67 CPU1.AV34
  BOTTOM w0.102: RAM6.F3 112.32,39.22 112.18,39.22 112.01,39.39 111.68,39.39 111.54,39.53 111.54,39.67 v2(111.79,39.91)
M_B_DQS_DN2: length 36.7
  L4SGND w0.089: v2(111.7,69.49) 111.78,69.4 111.78,69.13 111.58,68.93 111.58,67.35 112.16,66.77 112.82,66.77 115.32,64.28 115.32,48.85 115.69,48.48 115.97,48.48 116.22,48.73 116.34,48.73 116.57,48.5 116.57,48.38 116.32,48.13 116.32,47.85 116.69,47.47 116.98,47.47 117.23,47.72 117.35,47.72 117.58,47.5 117.58,47.37 117.33,47.12 117.33,46.84 117.66,46.5 117.95,46.5 118.2,46.75 118.32,46.75 118.55,46.53 118.55,46.4 118.3,46.15 118.3,45.87 118.64,45.53 118.92,45.53 119.17,45.78 119.29,45.78 119.52,45.56 119.52,45.43 119.27,45.18 119.27,44.9 119.54,44.63 119.54,43.37 119.45,43.28 119.16,43.28 118.96,43.48 v2(118.96,43.7)
  BOTTOM w0.102: RAM5.A7 119.46,43.41 119.46,43.56 119.21,43.81 119.07,43.81 v2(118.96,43.7) ; v2(111.7,69.49) 111.59,69.31 111.65,69.05 111.79,68.96 112.05,69.02 CPU1.AL31
M_B_DQS_DN3: length 39.2
  L4SGND w0.089: v2(115.33,69.46) 115.15,69.29 115.15,69.16 115.74,68.58 115.74,68.18 117.88,66.04 118.52,66.04 119.81,64.75 119.81,54.63 120.1,54.33 120.23,54.33 120.42,54.53 120.7,54.53 121.04,54.19 121.04,53.91 120.85,53.71 120.85,53.59 123.55,50.89 123.55,44.78 124,44.33 124,42.93 122.52,41.45 122.52,40.89 122.15,40.52 121.74,40.52 121.65,40.43 121.65,40.2 v2(121.94,39.91)
  BOTTOM w0.102: RAM5.F3 122.55,39.06 122.36,38.88 122.12,38.88 121.68,39.31 121.68,39.66 v2(121.94,39.91) ; CPU1.AU31 115.81,68.97 115.64,68.8 115.47,68.8 115.33,68.94 v2(115.33,69.46)
M_B_DQS_DN4: length 32.9
  L6 w0.089: v2(120.31,61.04) 120.56,61.29 120.76,61.29 120.87,61.18 120.87,58.99 122.28,57.58 122.28,53.35 122.28,50.26 123.94,48.6 124.17,48.6 124.28,48.6 124.59,48.91 124.7,48.91 124.94,48.67 124.94,48.54 124.64,48.24 124.64,47.94 126.6,45.98 128.16,45.98 129.71,44.43 129.71,43.53 129.62,43.44 129.36,43.44 v2(129.1,43.7)
  BOTTOM w0.076: CPU1.BB35 119.24,66.68 119.3,66.75 119.36,66.77 119.46,66.73 119.51,66.58 119.51,66.46 119.45,66.28 119.45,66.11 119.5,65.96 119.5,65.78 119.42,65.55 119.42,61.43 119.59,61.26 120.09,61.26 v2(120.31,61.04)
  BOTTOM w0.102: v2(129.1,43.7) 129.32,43.91 129.5,43.91 129.71,43.71 129.71,43.51 RAM8.A7
M_B_DQS_DN5: length 37.4
  L6 w0.089: v2(132.09,39.91) 131.89,40.1 131.89,40.33 132.03,40.46 132.28,40.46 134.04,42.22 134.04,44.16 133.54,44.65 133.54,48.06 129.66,51.93 129.66,52.07 129.82,52.22 129.82,52.59 129.52,52.89 129.21,52.89 129.02,52.7 128.88,52.7 128.66,52.92 128.66,53.06 128.8,53.2 128.8,53.59 128.51,53.87 128.19,53.87 128.03,53.71 127.89,53.71 127.14,54.46 127.14,56.47 126.99,56.62 126.99,56.63 126.03,57.59 126.03,57.66 126.03,57.66 126.03,57.81 124.73,59.11 124.73,60.13 124.48,60.39 124.48,60.74 v2(124.04,61.17)
  BOTTOM w0.076: CPU1.BF34 121.75,67.08 121.89,66.95 122.11,66.85 122.2,66.59 122.2,66.45 122.14,66.29 122.14,66.1 122.2,65.95 122.18,65.92 122.18,65.75 122.1,65.51 122.1,63.91 122.93,63.08 122.93,62.19 122.96,62.16 122.96,62.14
  BOTTOM w0.102: RAM8.F3 132.62,39.22 132.48,39.22 132.31,39.39 131.98,39.39 131.84,39.53 131.84,39.67 v2(132.09,39.91) ; 122.96,62.14 122.96,61.21 123.21,60.95 123.83,60.95 v2(124.04,61.17)
M_B_DQS_DN6: length 42.4
  L4SGND w0.089: v2(139.25,43.7) 139.25,43.48 139.45,43.29 139.62,43.29 139.8,43.47 139.8,44.52 139.8,44.52 139.8,44.63 139.8,44.73 139.18,45.35 136.94,47.59 136.14,47.59 135.58,47.03 134.98,47.03 134.13,47.89 134.13,48.17 134.39,48.43 134.39,48.56 134.17,48.78 134.04,48.78 133.78,48.52 133.5,48.52 133.16,48.86 133.16,49.14 133.39,49.37 133.39,49.5 133.16,49.72 133.04,49.72 132.81,49.49 132.52,49.49 132.19,49.83 132.19,50.11 132.39,50.32 132.39,50.44 132.17,50.67 132.04,50.67 131.84,50.46 131.55,50.46 131.22,50.8 131.22,51.08 131.44,51.3 131.44,51.43 131.21,51.65 131.09,51.65 130.87,51.43 130.58,51.43 130.2,51.81 130.2,52.86 124.85,58.21 124.85,64.18 123.36,65.68 122.75,65.68 122.67,65.68 122.55,65.68 120.23,67.99 120.23,68.83 120.12,68.94 119.99,68.94 v2(119.88,68.83)
  BOTTOM w0.102: v2(119.88,68.83) 119.58,68.81 119.4,68.97 119.39,69.11 CPU1.BC31 ; v2(139.25,43.7) 139.33,43.77 139.47,43.77 139.72,43.52 139.72,43.37 RAM7.A7
M_B_DQS_DN7: length 44.9
  L4SGND w0.089: v2(123.56,69.49) 123.56,68.97 123.97,68.56 123.97,68.07 125.47,66.57 127.28,66.57 128.75,65.1 128.75,61.36 138.15,51.96 139.54,51.96 143.93,47.56 143.93,42.5 143.07,41.64 142.33,41.64 141.75,41.06 141.75,40.57 141.96,40.35 142.35,40.35 142.45,40.25 142.45,40.13 v2(142.24,39.91)
  BOTTOM w0.102: CPU1.BH31 123.1,69.06 123.2,68.96 123.4,68.96 123.56,69.12 v2(123.56,69.49) ; v2(142.24,39.91) 141.94,39.62 141.94,39.47 142.43,38.99 142.43,38.99 142.54,38.88 142.66,38.88 142.85,39.07 RAM7.F3
M_B_DQS_DP0: length 30.7
  L6 w0.089: v2(113.49,62.94) 113.72,62.72 114.44,62.72 115.01,62.16 115.01,61.4 114.37,60.76 114.37,58 113.92,57.56 113.92,53.69 113.7,53.47 113.31,53.47 113.21,53.37 113.21,53.07 113.32,52.96 113.59,52.96 113.82,52.73 113.82,52.25 113.61,52.04 113.27,52.04 113.16,51.94 113.16,49.03 109.83,45.69 109.83,45.68 109.64,45.49 109.64,43.55 109.32,43.24 109.15,43.24 v2(108.8,42.89)
  BOTTOM w0.076: v2(113.49,62.94) 113.73,62.7 113.9,62.7 113.99,62.79 113.99,64.38 113.81,64.55 113.81,65.64 113.77,65.75 113.77,65.99 113.81,66.1 113.81,66.29 113.77,66.4 113.77,66.64 113.85,66.85 114.06,66.94 114.2,67.09 CPU1.AP34
  BOTTOM w0.102: RAM6.B7 108.81,42.89 v2(108.8,42.89)
M_B_DQS_DP1: length 34.5
  L6 w0.089: v2(111.15,39.94) 111.56,40.35 111.69,40.35 111.83,40.49 111.84,40.49 113.88,42.53 113.88,43.41 114.55,44.07 115.08,44.07 115.43,44.42 115.43,44.83 116.01,45.41 116.18,45.41 116.41,45.41 116.65,45.64 116.65,46.02 117.02,46.38 117.39,46.38 117.58,46.57 117.58,46.95 117.9,47.26 118.27,47.26 118.55,47.54 118.55,60.16 v2(117.92,60.78)
  BOTTOM w0.076: CPU1.AV35 116.72,66.66 116.8,66.74 116.91,66.74 116.94,66.72 116.94,66.7 116.98,66.59 116.98,66.46 116.97,66.45 116.97,66.42 116.97,66.4 116.94,66.32 116.94,66.06 116.94,66.05 116.98,65.94 116.98,65.8 116.97,65.77 116.94,65.69 116.94,65.68 116.94,65.68 116.92,65.62 116.92,61.14 117.11,60.95 117.75,60.95 v2(117.92,60.78)
  BOTTOM w0.102: RAM6.G3 112.12,38.96 111.92,39.16 111.58,39.16 111.31,39.43 111.31,39.78 v2(111.15,39.94)
M_B_DQS_DP2: length 36.7
  L4SGND w0.089: v2(111.7,70.15) 112.1,69.75 112.1,69.18 111.77,68.85 111.77,67.43 112.24,66.96 112.9,66.96 115.51,64.36 115.51,48.93 115.76,48.67 115.89,48.67 116.14,48.93 116.42,48.93 116.76,48.58 116.76,48.31 116.51,48.05 116.51,47.93 116.77,47.66 116.9,47.66 117.15,47.91 117.43,47.91 117.77,47.58 117.77,47.29 117.52,47.04 117.52,46.92 117.74,46.69 117.87,46.69 118.12,46.94 118.4,46.94 118.74,46.61 118.74,46.32 118.49,46.07 118.49,45.95 118.71,45.72 118.84,45.72 119.09,45.97 119.37,45.97 119.71,45.64 119.71,45.35 119.46,45.1 119.46,44.98 119.73,44.7 119.73,43.29 119.53,43.09 119.13,43.09 v2(118.95,42.9)
  BOTTOM w0.102: CPU1.AL30 v2(111.7,70.15) ; v2(118.95,42.9) RAM5.B7
M_B_DQS_DP3: length 39.2
  L4SGND w0.089: v2(115.36,70.15) 114.93,69.72 114.93,69.12 115.55,68.5 115.55,68.1 117.8,65.85 118.44,65.85 119.62,64.67 119.62,54.55 120.02,54.14 120.31,54.14 120.5,54.34 120.62,54.34 120.85,54.11 120.85,53.99 120.66,53.79 120.66,53.51 123.36,50.81 123.36,44.7 123.81,44.25 123.81,43.01 122.33,41.52 122.33,40.97 122.07,40.71 121.66,40.71 121.46,40.51 121.46,40.1 v2(121.3,39.94)
  BOTTOM w0.102: v2(121.3,39.94) 121.45,39.79 121.45,39.22 122.02,38.65 122.4,38.65 RAM5.G3 ; CPU1.AU30 v2(115.36,70.15)
M_B_DQS_DP4: length 32.8
  L6 w0.089: v2(120.31,61.67) 120.51,61.48 120.84,61.48 121.06,61.26 121.06,59.07 122.47,57.66 122.47,53.27 122.47,50.34 124.02,48.79 124.1,48.79 124.1,48.79 124.2,48.79 124.52,49.1 124.78,49.1 125.13,48.75 125.13,48.46 124.83,48.16 124.83,48.02 126.68,46.17 128.24,46.17 129.9,44.51 129.9,43.45 129.7,43.25 129.44,43.25 v2(129.1,42.9)
  BOTTOM w0.076: v2(120.31,61.67) 120.06,61.42 119.66,61.42 119.58,61.5 119.58,65.53 119.67,65.75 119.67,65.99 119.61,66.14 119.61,66.25 119.68,66.43 119.68,66.61 119.64,66.72 119.59,66.85 119.37,66.95 119.24,67.08 CPU1.BB34
  BOTTOM w0.102: v2(129.1,42.9) RAM8.B7
M_B_DQS_DP5: length 37.5
  L6 w0.089: v2(131.45,39.94) 131.7,40.19 131.7,40.41 131.95,40.66 132.2,40.66 133.85,42.3 133.85,44.08 133.35,44.58 133.35,47.98 129.47,51.85 129.47,52.15 129.63,52.3 129.63,52.51 129.44,52.7 129.29,52.7 129.1,52.51 128.8,52.51 128.47,52.84 128.47,53.14 128.61,53.28 128.61,53.51 128.44,53.68 128.27,53.68 128.11,53.51 127.81,53.51 126.95,54.38 126.95,56.39 126.8,56.54 126.8,56.55 125.84,57.51 125.84,57.58 125.84,57.73 124.54,59.03 124.54,60.06 124.29,60.31 124.29,60.45 124.2,60.54 v2(124.04,60.54)
  BOTTOM w0.076: 122.73,62.14 122.73,62.16 122.76,62.19 122.76,63.01 121.93,63.84 121.93,65.54 122.02,65.78 122.02,65.96 122.01,65.97 121.98,66.08 121.98,66.32 122.04,66.48 122.04,66.56 121.98,66.73 121.88,66.77 121.76,66.73 121.74,66.68 121.74,66.54 CPU1.BF35
  BOTTOM w0.102: v2(124.04,60.54) 123.86,60.72 123.12,60.72 122.73,61.12 122.73,62.14 ; RAM8.G3 132.42,38.96 132.22,39.16 131.88,39.16 131.61,39.44 131.61,39.76 131.6,39.77 131.6,39.79 v2(131.45,39.94)
M_B_DQS_DP6: length 42.4
  L4SGND w0.089: v2(139.25,42.9) 139.46,43.1 139.7,43.1 139.99,43.39 139.99,44.6 139.99,44.63 139.99,44.81 139.23,45.57 137.02,47.78 136.06,47.78 135.5,47.22 135.06,47.22 134.32,47.97 134.32,48.09 134.58,48.35 134.58,48.64 134.24,48.97 133.96,48.97 133.7,48.71 133.57,48.71 133.35,48.94 133.35,49.06 133.58,49.29 133.58,49.58 133.24,49.91 132.96,49.91 132.73,49.68 132.6,49.68 132.38,49.91 132.38,50.03 132.58,50.24 132.58,50.52 132.25,50.86 131.96,50.86 131.76,50.65 131.63,50.65 131.41,50.88 131.41,51 131.63,51.22 131.63,51.5 131.29,51.84 131.01,51.84 130.79,51.62 130.66,51.62 130.39,51.89 130.39,52.94 125.05,58.29 125.05,64.26 123.44,65.87 122.75,65.87 122.67,65.87 122.63,65.87 120.42,68.07 120.42,68.94 v2(119.85,69.51)
  BOTTOM w0.102: v2(139.25,42.9) 139.26,42.9 139.26,42.89 RAM7.B7 ; CPU1.BC30 v2(119.85,69.51)
M_B_DQS_DP7: length 44.9
  L4SGND w0.089: v2(141.6,39.94) 141.77,40.11 141.77,40.28 141.56,40.49 141.56,41.14 142.25,41.83 142.99,41.83 143.74,42.58 143.74,47.49 139.46,51.77 138.08,51.77 128.56,61.28 128.56,65.02 127.2,66.38 125.39,66.38 123.78,67.99 123.78,68.48 123.37,68.89 123.37,69.1 123.16,69.31 123.16,69.72 v2(123.56,70.12)
  BOTTOM w0.102: CPU1.BH30 v2(123.56,70.12) ; RAM7.G3 142.7,38.65 142.44,38.65 142.33,38.76 142.33,38.76 141.71,39.38 141.71,39.57 141.6,39.68 v2(141.6,39.94)
M_B_ODT0: length 101.5
  L2SGND w0.089: v2(111.8,59.89) 112.14,59.89 112.23,59.8 112.23,59.58 112.32,59.49 112.52,59.49 112.61,59.4 112.61,59.23 112.52,59.14 112.32,59.14 112.23,59.05 112.23,58.87 112.32,58.78 112.52,58.78 112.61,58.69 112.61,58.51 112.52,58.43 112.32,58.43 112.23,58.34 112.23,58.16 112.32,58.07 112.37,58.07 112.46,57.98 112.46,57.8 112.37,57.71 112.32,57.71 112.23,57.63 112.23,57.45 112.32,57.36 112.42,57.36 112.51,57.27 112.51,57.09 112.42,57 112.32,57 112.23,56.91 112.23,56.03 112.32,55.94 112.75,55.94 112.84,55.85 112.84,55.68 112.75,55.59 112.32,55.59 112.23,55.5 112.23,54.26 112.32,54.17 112.75,54.17 112.84,54.08 112.84,53.91 112.75,53.82 112.32,53.82 112.23,53.73 112.23,53.55 112.32,53.46 112.75,53.46 112.84,53.37 112.84,53.19 112.75,53.11 112.32,53.11 112.23,53.02 112.23,52.84 112.32,52.75 112.75,52.75 112.84,52.66 112.84,52.48 112.75,52.39 112.32,52.39 112.23,52.31 112.23,52.13 112.32,52.04 112.75,52.04 112.84,51.95 112.84,51.77 112.75,51.68 112.32,51.68 112.23,51.59 112.23,51.42 112.32,51.33 112.75,51.33 112.84,51.24 112.84,51.06 112.75,50.97 112.32,50.97 112.23,50.88 112.23,50.71 112.32,50.62 112.75,50.62 112.84,50.53 112.84,50.35 112.75,50.26 112.08,50.26 111.67,49.85 111.67,49.71 111.9,49.47 111.9,49.35 111.78,49.22 111.65,49.22 111.58,49.3 111.45,49.3 108.79,46.64 108.79,46.51 108.84,46.46 108.84,46.34 108.72,46.21 108.59,46.21 108.54,46.26 108.41,46.26 108.29,46.14 108.29,45.92 108.45,45.76 108.45,45.61 108.32,45.48 108.19,45.48 107.98,45.7 107.85,45.7 107.31,45.16 107.31,45.03 107.55,44.79 107.55,44.66 107.42,44.54 107.3,44.54 107.05,44.78 106.93,44.78 106.58,44.43 106.58,44.28 106.78,44.07 106.78,43.95 106.65,43.82 106.53,43.82 106.31,44.04 106.19,44.04 105.98,43.83 105.98,43.51 106.07,43.42 106.25,43.42 106.34,43.33 106.34,43.15 106.25,43.06 106.07,43.06 105.98,42.98 105.98,40.45 106.09,40.34 106.33,40.34 106.41,40.25 106.41,40.08 106.33,39.99 106.1,39.99 106.01,39.9 106.01,39.72 106.1,39.63 106.33,39.63 106.41,39.54 106.41,39.37 106.33,39.28 106.1,39.28 106.01,39.19 106.01,39.01 106.1,38.92 106.38,38.92 106.47,38.83 106.47,38.65 106.38,38.57 106.07,38.57 105.98,38.47 105.98,37.84 106.29,37.53 106.59,37.53 106.68,37.62 106.68,37.95 106.77,38.04 106.95,38.04 107.04,37.95 107.04,37.62 107.13,37.53 111.09,37.53 v2(111.62,37.01)
  L4SGND w0.142: v2(111.62,37.01) 112.57,37.95 120.83,37.95 v2(121.77,37.01) 122.72,37.95 130.98,37.95 v2(131.92,37.01) 132.87,37.95 140.75,37.95 141.69,37.01 v2(142.07,37.01) 143.02,37.95 145.73,37.95 146.24,38.45 147.91,38.45 148.76,37.61 v2(150.9,37.61)
  BOTTOM w0.076: v2(111.8,59.89) 112.33,60.42 112.33,61.36 112.6,61.63 112.6,64.68 112.41,64.87 112.41,65.21 112.59,65.4 112.59,65.82 112.45,66.09 CPU1.AL36
  BOTTOM w0.14: v2(142.07,37.01) 142.85,36.23 RAM7.K3 ; v2(111.62,37.01) 112.4,36.23 RAM6.K3 ; RAM5.K3 122.55,36.23 v2(121.77,37.01) ; RAM8.K3 132.7,36.23 v2(131.92,37.01) ; R1311.1 v2(150.9,37.61)
M_B_PARITY: length 92.5
  L2SGND w0.089: v2(107.73,61.46) 106.47,60.19 106.47,55.09 102.95,51.57 102.95,41.92 102.86,41.83 102.39,41.83 102.3,41.74 102.3,41.56 102.39,41.48 102.86,41.48 102.95,41.39 102.95,41.18 102.86,41.09 102.21,41.09 102.12,41.01 102.12,40.83 102.21,40.74 102.86,40.74 102.95,40.65 102.95,40.47 102.86,40.38 102.21,40.38 102.12,40.29 102.12,40.12 102.21,40.03 102.86,40.03 102.95,39.94 102.95,39.76 102.86,39.67 102.21,39.67 102.12,39.58 102.12,39.41 102.21,39.32 102.86,39.32 102.95,39.23 102.95,35.3 106.53,31.72 111.32,31.72 v2(112.37,30.68)
  L4SGND w0.142: v2(112.37,30.68) 112.37,30.65 112.54,30.48 112.81,30.21 114.46,30.21 114.75,30.5 115.48,30.5 116.02,29.96 121.8,29.96 v2(122.52,30.68) 122.52,30.66 123.21,29.96 131.95,29.96 v2(132.67,30.68) 132.67,30.66 133.36,29.96 142.1,29.96 v2(142.82,30.68) 142.82,30.66 143.26,30.21 144.6,30.21 144.98,29.83 146.97,29.83 v2(147.44,30.29)
  BOTTOM w0.076: CPU1.AE34 108.52,67.29 108.21,66.98 108.21,65.91 108.09,65.7 108.09,65.32 108.29,65.13 108.29,65.09 108.29,64.76 107.95,64.43 107.95,61.68 v2(107.73,61.46)
  BOTTOM w0.14: RN1304.1 v2(147.44,30.29) ; RAM7.T3 142.82,31.27 v2(142.82,30.68) ; v2(122.52,30.68) 122.52,31.27 RAM5.T3 ; RAM6.T3 112.37,31.27 v2(112.37,30.68) ; RAM8.T3 132.67,31.27 v2(132.67,30.68)
M_VREF_CA_DIMMA: length 49.5
  TOP w0.508: v2(62.22,34.77) 62.22,34.36 62.73,33.85 C1203.1 64.73,33.85 64.94,34.05 65.95,34.05 66.76,33.25 70.1,33.25 71.03,34.18 71.54,34.18 72.13,34.77 v2(72.37,34.77) 72.37,34.37 72.89,33.85 C1236.1 73.88,34.03 76.37,34.03 77.23,33.17 79.87,33.17 80.76,34.05 C1201.1 ; C1201.1 82.16,32.58 85.08,29.66 92.39,29.66 94.3,31.56 v2(94.3,32.91) 94.35,32.96 C1286.1 95.77,32.96 R1222.2 R1223.2 97.32,32.99 R1202.1 ; C1201.1 82.16,34.41 v2(82.52,34.77)
  BOTTOM w0.305: RAM4.M1 61.95,34.5 v2(62.22,34.77) ; v2(82.52,34.77) 82.25,34.5 RAM2.M1 ; v2(72.37,34.77) 72.1,34.5 RAM3.M1 ; RAM1.M1 92.71,34.5 v2(94.3,32.91)
M_VREF_CA_DIMMB: length 53.2
  TOP w0.508: C1336.1 124.7,34.6 v2(124.87,34.77) ; C1336.1 128.64,34.05 129.48,33.22 132.73,33.22 133.64,34.13 C1303.1 ; C1336.1 123.2,34.05 122.21,35.04 119.62,35.04 118.63,34.05 115.76,34.05 115.23,33.52 v2(115.23,32.91) 115.23,32.58 C1343.1 114.95,32 114.95,30.46 114.41,29.91 106.49,29.91 R1320.2 R1321.2 R1302.1 ; v2(135.02,34.77) 134.66,34.41 C1303.1 ; C1303.1 138.77,34.13 139.74,33.17 142.53,33.17 143.42,34.05 C1301.1 144.79,34.4 v2(145.17,34.77)
  BOTTOM w0.305: RAM8.M1 134.75,34.5 v2(135.02,34.77) ; v2(124.87,34.77) 124.6,34.5 RAM5.M1 ; v2(145.17,34.77) 144.9,34.5 RAM7.M1 ; v2(115.23,32.91) 115.23,33.27 RAM6.M1
MASK_BASE_LEDS#: length 9.6
  TOP w0.127: Q6404.5 Q6404.2 31.48,17.65 31.76,17.93 31.77,17.93 v1(31.84,17.99) 31.84,18 32.17,18.33 32.17,21.63 U6402.4 31.54,22.36 31.54,23.26 31.15,23.64 R6419.2
MASK_SATA_LED#: length 160.4
  L4SGND w0.102: v2(94.53,4.49) 105.73,4.49 106.01,4.77 113.47,4.77 113.48,4.77 116.51,4.77 117.1,4.77 119.96,7.64 124.66,7.64 124.84,7.82 126.48,7.82 127.55,6.75 127.72,6.75 140.66,6.75 141.28,7.37 141.48,7.37 157.18,7.37 157.34,7.37 157.97,6.75 174.16,6.75 174.71,6.19 v2(175.15,6.19)
  L6 w0.102: v2(93.94,16.27) 93.71,16.5 93.64,16.5 93.23,16.91 90.81,16.91 88.53,14.62 86.96,14.62 86.42,15.16 77.04,15.16 76.8,14.91 76.8,14.61 76.05,13.86 75.22,13.86 74.28,14.8 68.8,14.8 68.47,15.13 63.03,15.13 62.5,14.59 55.44,14.59 54.65,15.39 51.93,15.39 51.5,15.82 51.5,18.41 50.15,19.75 43.3,19.75 v2(42.93,20.12) 42.89,20.16 41.14,20.16 v2(40.3,19.32)
  BOTTOM w0.102: Q6403.G 42.74,18.78 v1(42.74,19.62) 42.74,20.01 42.89,20.16 42.89,20.12 v2(42.93,20.12) ; v2(40.3,19.32) 39.76,18.79 U2401.56 ; R6406.2 175.76,6.8 v2(175.15,6.19) ; v2(93.94,16.27) 93.94,12.12 94.38,11.68 94.38,7.7 94.22,7.54 94.22,4.79 v2(94.53,4.49)
ME_FWP: length 193.8
  TOP w0.102: v2(171.59,30.47) 171.69,30.47 173.25,32.03 173.25,39.5 173.32,39.57 173.32,39.95 175.06,41.7 180.91,41.7 183.32,39.3 183.32,34.3 183.7,33.91 185.96,33.91 186.34,33.54 186.34,33.02 187.28,32.07 188.18,32.07 188.43,31.82 R9806.2 190.58,32.11 FSW1.3
  L4SGND w0.102: v2(171.59,30.47) 170.78,31.29 167.7,31.29 167.61,31.37 167.13,31.37 163.99,28.24 163.11,27.35 160.11,27.35 157.47,24.71 144.14,24.71 136.63,17.2 122.5,17.2 120.8,15.5 115.79,15.5 v2(115.39,15.9)
  L6 w0.102: v2(113.32,11.83) 113.32,10.71 112.47,9.86 107.73,9.86 106.83,8.96 106.81,8.96 106.77,8.91 106.62,8.91 95.76,8.91 95.71,8.96 95.33,8.96 94.58,9.7 93.77,9.7 93.24,10.23 92.24,10.23 91.35,9.34 82.33,9.34 81.67,10 80.15,10 79.21,9.06 74.64,9.06 74.21,9.49 69.6,9.49 69.34,9.24 64.26,9.24 63.5,10 41.7,10 41.45,10.25 41.16,10.25 41.16,10.25 41,10.25 39.12,12.13 37.71,12.13 37.2,12.64 36.36,12.64 35.82,12.1 34.6,12.1 v2(34.33,11.83)
  BOTTOM w0.102: U2401.80 31.73,13.03 v1(31.87,12.9) 32.47,12.29 33.87,12.29 v2(34.33,11.83) ; v2(115.39,15.9) 115.39,13.9 v2(113.32,11.83)
ME_FWP_SW: length 41.4
  TOP w0.102: FSW1.2 190.63,30.61 R9806.1 188.61,30.96 v1(188.33,31.24) 187.8,31.77 187.21,31.77 186.13,32.85 186.13,33.46 185.88,33.71 183.62,33.71 183.05,34.28 183.05,39.18 180.81,41.42 175.07,41.42 173.52,39.87 173.52,31.92 172,30.4 172,30.3 171.25,29.56 v2(171.16,29.56) ; R1909.1 172.25,27.22 v2(172.1,27.37)
  BOTTOM w0.102: v2(172.1,27.37) 172.1,28.62 v2(171.16,29.56)
ME_SUS_PWR_ACK_R: length 16.4
  BOTTOM w0.076: CPU1.BV34 129.56,66.92 129.56,66.4 129.54,66.34 129.54,66.05 129.56,65.99 129.56,65.75 129.54,65.69 129.54,65.26 131.13,63.67
  BOTTOM w0.102: 131.13,63.67 131.14,63.67 131.38,63.43 131.38,63.42 131.39,63.41 131.39,61.93 132.8,60.51 132.8,60.12 131.37,58.69 131.37,55.38 v1(131.03,55.03) 130.7,54.7 R1738.2 R1708.1
MEC_XTAL1_R: length 4.5
  BOTTOM w0.089: X2401.1 20.9,26.13 C2425.1 21.99,25.64 v1(22.42,25.64) 22.87,25.64 23.21,25.99 U2401.123
MEC_XTAL2: length 4.3
  BOTTOM w0.089: U2401.125 22.29,26.79 R2461.2 22.19,26.74 C2424.1 21.16,26.74 X2401.2
MEM_CHA_EN: length 16.5
  TOP w0.102: v1(136.92,68.5) 136.79,68.5 v2(136.46,68.83)
  L6 w0.102: v2(148.34,70.74) 147.23,71.85 147.18,71.85 147.17,71.86 145.61,71.86 145.6,71.84 142.72,71.84 142.66,71.79 139.78,71.79 136.82,68.83 v2(136.46,68.83)
  BOTTOM w0.102: v2(136.46,68.83) 136.1,69.19 CPU1.CJ31 ; R2030.1 R2031.2 148.73,71.14 v2(148.34,70.74)
MEM_CHB_EN: length 15.9
  TOP w0.102: v2(136.41,71.32) v1(137.03,71.13)
  L6 w0.102: v2(147.46,72.61) 147.37,72.52 145.7,72.52 145.43,72.25 144.24,72.25 143.52,72.97 140.8,72.97 140.24,72.41 139.8,72.41 138.78,71.39 136.49,71.39 v2(136.41,71.32)
  BOTTOM w0.102: CPU1.CJ27 135.96,71.79 136.41,71.34 v2(136.41,71.32) ; R2032.1 147.05,73.02 v2(147.46,72.61) 148.32,72.61 R2033.2
MESW1_B: length 3.7
  TOP w0.102: v1(189.35,28.54) R9805.2 190.29,27.98 R9804.1 190.05,27.61 FSW1.1
MIC2_VREFO_L: length 2.8
  BOTTOM w0.203: RN2901.2 180.59,21.05 180.25,20.72 v1(180,20.72) 179.69,20.72 179.29,20.32 U2701.28
MIC2_VREFO_R: length 3.9
  BOTTOM w0.203: RN2901.1 v1(181.16,19.5) 180.4,20.26 179.7,20.26 179.36,19.92 U2701.29
MIC_CAP: length 2.9
  BOTTOM w0.203: U2701.32 179.2,18.72 179.79,18.13 179.89,18.13 v1(179.89,18.13) 179.92,18.13 179.92,18.13 180.4,18.13 180.63,18.36
  BOTTOM w0.254: C2735.1 180.63,18.36
MIC_GND: length 3.1
  TOP w0.254: v1(108.03,97.59) 108.37,97.94 v2(108.37,98.04)
  TOP w0.381: v2(108.37,98.04) 108.12,98.29 R5501.1
  BOTTOM w0.305: v2(108.37,98.04) 108.55,97.86 108.55,97.82 108.62,97.74 108.62,97.53 108.65,97.5 LCD1.46
MSATA_DEVSLP_R: length 6.6
  TOP w0.102: v2(193.59,12.34) 193.08,12.85 AFTP6301.1 190.67,14.06 R6301.2
  BOTTOM w0.102: v2(193.59,12.34) 193.59,12.85 194.14,13.4 SSD1.38
MUX_HPD_CON: length 2.1
  TOP w0.127: R7149.1 20.92,73.23 20.62,72.94 20.62,72.91 19.92,72.21 U7101.23
NB_MODE#: length 110.5
  L4SGND w0.102: v2(53.4,46.02) 52.35,46.02 46.6,40.27 46.6,37.64 45.91,36.95 44.49,36.95 44.08,36.54 44.08,36.03 44.16,35.96 44.16,34.75 v2(43.76,34.35)
  BOTTOM w0.102: v2(53.4,46.02) 59.65,46.02 59.95,46.32 59.98,46.32 62.62,48.96 64.83,48.96 65.49,49.62 v1(66.21,49.62) 85.57,49.62 87.56,51.6 88.96,51.6 88.96,51.6 89.16,51.6 89.16,51.61 89.37,51.61 102.31,51.61 103.73,50.18 R2050.1 R2002.2 128.69,50.18 129.27,50.77 130.49,50.77 130.71,50.99 Q2001.3 ; U2401.34 40.36,27.59 40.73,27.96 40.73,28.21 41.47,28.95 43.5,28.95 43.8,29.25 44.77,29.25 45.05,29.53 45.05,33.06 v2(43.76,34.35)
NB_MUTE#: length 165.2
  TOP w0.102: v2(171.36,17.29) 171.95,17.87 v1(171.95,18.26)
  L4SGND w0.102: v2(114.09,15.79) 114.58,15.3 120.98,15.3 121.98,16.3 124.85,16.3 125.54,16.99 137.77,16.99 139.22,18.43 163.49,18.43 164.12,19.07 166.84,19.07 167.5,18.41 170.24,18.41 v2(171.36,17.29)
  L6 w0.102: v2(114.09,15.79) 113.71,15.42 110.06,15.42 109.13,16.35 100.92,16.35 99.52,14.95 96.96,14.95 96.35,15.56 93.7,15.56 92.76,16.5 90.98,16.5 88.69,14.22 86.69,14.22 86.31,14.6 85.67,14.6 85.06,13.99 83.25,13.99 82.49,14.75 81.98,14.75 81.07,13.84 76.86,13.84 76.48,13.45 75.03,13.45 74.11,14.37 68.59,14.37 68.33,14.62 63.1,14.62 62.66,14.19 55.27,14.19 54.71,14.75 53.97,14.75 50.23,14.75 49.37,13.89 48.12,13.89 43.63,18.38 42.91,18.38 42.79,18.26 40.75,18.26 39.01,20 39.01,21.64 38.02,22.62 34.2,22.62 31.84,24.99 26.03,24.99 v2(25.69,24.66)
  BOTTOM w0.102: R2743.1 170.9,16.83 v2(171.36,17.29) 171.59,17.52 U2701.2 ; U2401.119 24.82,24.39 24.93,24.28 25.31,24.28 v2(25.69,24.66)
NC_EC_SLP_S0IX#: length 3.4
  TOP w0.102: v1(33.97,14.17) R2481.2 34.86,14.6 35.48,15.22 v2(35.48,15.26)
  BOTTOM w0.102: U2401.71 35.33,15.12 35.47,15.26 v2(35.48,15.26)
NC_SIO_SLP_S4#_EC: length 3.5
  BOTTOM w0.127: R2409.1 21.23,15.59 v1(21.96,15.59) U2401.97
NC_THERMAL_T8: length 6.5
  TOP w0.102: R2499.2 19.11,23.54 v2(19.11,24.28) 19.22,24.38 v1(19.22,24.86)
  BOTTOM w0.102: U2401.118 22.7,23.99 22.57,24.12 19.27,24.12 v2(19.11,24.28)
NC_U3_PD#_EC: length 3.6
  TOP w0.102: v2(24.68,14.5) 24.67,14.5 v1(24.22,14.05) 23.96,13.78 R2431.1 23.1,13.35 R2479.1
  BOTTOM w0.102: U2401.96 25.01,14.17 v2(24.68,14.5)
NCT7718_DXN: length 110.7
  TOP w0.127: v2(55.18,88.03) 55.6,88.45 55.6,89.16 55.37,89.39 55.37,92.55 59.08,96.26 69.81,96.26 70.08,95.99 70.11,95.99 71.59,94.52 71.92,94.52 72.05,94.39 72.05,94.1 72.17,93.97 C2606.2 73.3,93.97 Q2603.E
  L4SGND w0.127: v2(34.71,36.52) 34.37,36.86 34.37,36.99 34.52,37.14 34.52,39.59 31.77,42.33 29.55,42.33 25.86,46.03 25.86,48.22 25.86,48.22 25.86,48.59 29.29,52.02 29.29,55.82 29.29,55.82 29.29,56.18 32.39,59.29 33.99,59.29 34.07,59.37 34.07,59.37 38.13,63.43 38.13,65.19 42.43,69.49 43.71,69.49 44.18,69.96 44.2,69.96 46.01,71.77 46.01,73.5 51.92,79.41 51.92,79.45 52.16,79.69 52.16,81.7 50.94,82.92 50.94,86.61 52.57,88.23 54.98,88.23 v2(55.18,88.03)
  BOTTOM w0.127: U2601.3 42.4,36.72 C2607.2 42.66,37.32 v1(42.03,37.95) 41.78,38.19 41.66,38.19 41.63,38.22 38.89,38.22 38.73,38.05 37.8,38.05 37.3,37.55 37.16,37.55 36.61,37 36.61,36.86 36.08,36.33 34.9,36.33 v2(34.71,36.52)
NCT7718_DXP: length 113.3
  TOP w0.127: Q2603.C 75.19,95.18 Q2603.B 73.88,95.29 C2606.1 72.17,95.29 72.05,95.17 72.05,94.87 71.95,94.77 71.69,94.77 70.22,96.25 70.18,96.25 ; v2(55.18,88.79) 55.18,89.22 55.12,89.28 55.12,92.66 58.97,96.51 69.91,96.51 70.18,96.25 ; 70.18,96.25 v1(70.3,96.36)
  L4SGND w0.127: v2(33.69,36.47) 34.11,36.89 34.11,37.09 34.27,37.25 34.27,39.48 31.67,42.08 29.45,42.08 25.6,45.92 25.6,48.12 25.6,48.69 29.03,52.12 29.03,55.71 29.03,55.71 29.03,56.29 32.29,59.54 33.89,59.54 33.96,59.62 33.97,59.62 37.88,63.53 37.88,65.3 42.33,69.74 43.6,69.74 44.07,70.21 44.1,70.21 45.76,71.87 45.76,73.61 51.66,79.51 51.66,79.56 51.91,79.8 51.91,81.59 50.69,82.81 50.69,83.02 50.69,86.71 52.46,88.49 54.88,88.49 v2(55.18,88.79)
  BOTTOM w0.127: v2(33.69,36.47) 34.15,36.47 34.48,36.14 34.5,36.14 34.56,36.08 36.18,36.08 36.87,36.76 36.87,36.89 37.27,37.29 37.4,37.29 37.91,37.8 38.83,37.8 39,37.97 41.53,37.97 41.75,37.75 C2607.1 41.75,36.97 U2601.2
NRB_BIT: length 15.6
  TOP w0.102: v2(133.57,70.78) v1(133.02,70.4)
  L6 w0.102: v2(144.46,73.98) 144.46,74.01 144.44,73.98 140.47,73.98 139.85,73.36 138,73.36 137.13,72.48 134.87,72.48 133.95,71.56 133.95,71.16 v2(133.57,70.78)
  BOTTOM w0.102: v2(133.57,70.78) 133.28,70.49 CPU1.CE29 ; v2(144.46,73.98) 144.46,74.01 ; 144.46,74.01 144.29,73.83 R1502.2 ; 144.46,74.01 144.23,74.24 R1503.1
OPT_CLK_CPU_N: length 207
  TOP w0.102: v2(167.71,16.51) 167.71,16.76 167.61,16.86 166.9,16.86 166.68,16.63 166.68,12.55 171.13,8.1 171.64,8.1 ; v1(171.64,8.25) 171.64,8.1 ; 171.64,8.1 179.09,8.1 179.5,8.1 179.7,8.29 184.48,8.29 185.44,7.33 185.87,7.33 185.97,7.43 185.97,7.74 186.16,7.93 v2(186.35,7.93)
  L6 w0.089: v2(186.35,7.93) 186.64,7.93 186.69,7.88 186.69,7.38 186.78,7.29 187.12,7.29 188.33,8.5 188.33,8.58 188.33,10.55 191.71,13.93 191.71,22.22 191.21,22.71 191.21,25.94 191.7,26.43 191.7,36.89 189.02,39.58 189.02,47.54 185.27,51.28 185.27,59.71 185.8,60.24 185.8,88.4 181.05,93.15 163.14,93.15 161.08,95.21 156.01,95.21 152.33,98.89 148.53,98.89 145.84,101.59 145.84,102.48 144.77,103.55 124.36,103.55 118.99,98.18 118.99,94.55 119.64,93.9 119.64,93.17 118.76,92.3 118.76,92.05 118.85,91.96 119.4,91.96 119.54,91.82 119.54,91.7 v2(119.38,91.53)
  BOTTOM w0.102: v2(167.71,16.51) 167.71,16.73 167.59,16.86 166.94,16.86 166.73,16.65 SSD2.53 ; v2(119.38,91.53) 119.1,91.26 119.1,90.76 119.37,90.49 119.95,90.49 120.38,90.06 CPU1.BD3
OPT_CLK_CPU_P: length 207
  TOP w0.102: 173.27,7.87 179,7.87 179.6,7.87 179.79,8.06 184.39,8.06 185.34,7.1 v2(186.35,7.1) ; 173.27,7.87 171.04,7.87 166.45,12.45 166.45,16.73 166.81,17.09 167.5,17.09 v2(167.71,17.3) ; 173.27,7.87 v1(173.27,7.71)
  L6 w0.089: v2(118.57,91.53) 118.57,92.38 119.44,93.25 119.44,93.82 118.8,94.47 118.8,98.26 124.28,103.74 124.44,103.74 124.44,103.74 144.85,103.74 146.03,102.56 146.03,101.66 148.61,99.08 152.41,99.08 156.08,95.4 161.16,95.4 163.22,93.34 181.13,93.34 185.99,88.48 185.99,60.17 185.46,59.63 185.46,51.36 189.21,47.62 189.21,39.66 191.89,36.97 191.89,26.35 191.4,25.86 191.4,22.79 191.9,22.3 191.9,13.85 188.52,10.47 188.52,8.66 188.52,8.42 187.2,7.1 v2(186.35,7.1)
  BOTTOM w0.102: v2(167.71,17.3) 167.5,17.09 166.82,17.09 166.75,17.15 SSD2.55 ; CPU1.BC3 120.15,87.39 120.15,89.97 119.86,90.26 119.27,90.26 118.87,90.66 118.87,90.76 118.88,90.76 118.88,91.1 118.87,91.1 118.87,91.23 v2(118.57,91.53)
OPT_CLKREQ_CPU_N: length 70.2
  TOP w0.102: v2(146.24,57.32) 145.81,57.75 145.38,57.75 144.16,56.53 144.16,56.22 RN1813.5 143.19,56.65 142.62,56.65 142.36,56.91 v1(142.36,57.93) 142.36,59.1 141.69,59.76 141.69,60.45 140.66,61.49 140.52,61.49 137.35,64.65 137.35,65.41 136.67,66.08 135.89,66.08 135.12,66.85 135.12,67.57 135.37,67.82 135.37,68.27 134.95,68.69 134.95,69.1 134.93,69.12 134.93,69.13 134.76,69.3 134.76,69.31 v2(134.48,69.59)
  L6 w0.102: v2(146.24,57.32) 146.26,57.3 146.26,57.03 148.88,54.41 148.88,53.79 148.88,53.79 148.88,53.31 149.95,52.24 149.95,50.93 154.3,46.58 154.3,42.8 155.49,41.61 155.49,39.51 156.45,38.55 156.45,30.78 156.83,30.41 156.83,26.38 156.53,26.08 156.53,20.87 v2(155.36,19.7)
  BOTTOM w0.102: v2(134.48,69.59) 134.23,69.84 CPU1.CF30 ; SSD2.52 157.62,16.4 155.36,18.66 v2(155.36,19.7)
OPT_DEVSLP: length 209.9
  TOP w0.102: v2(150.48,16.48) 149.21,15.21 v1(149.21,12.97) 149.21,10.79 149.75,10.25 151.04,10.25 R6313.1 151.55,10.61 R6312.2 152.82,10.61 R6311.1
  L4SGND w0.102: v2(185.46,96.41) 185.94,96.89 187.28,96.89 189.98,94.19 189.98,68.95 189.5,68.47 189.5,61.14 186.27,57.92 186.27,52.32 186.27,51.72 188.89,49.1 188.89,29.36 187.24,27.7 187.24,23.89 187.85,23.28 187.85,13.37 184.38,9.9 180.53,9.9 179.34,11.09 179.34,11.1 178.76,11.68 178.75,11.68 178.6,11.83 176.4,11.83 175.15,13.08 175.15,16.51 169.44,22.22 165.69,22.22 162.57,25.34 159.58,25.34 158.41,24.17 155.45,24.17 153.4,22.12 150.53,22.12 v2(150.03,22.62)
  BOTTOM w0.076: 140.34,83.52 139.29,83.52 CPU1.CR8
  BOTTOM w0.102: v2(185.46,96.41) 185.33,96.28 183.51,96.28 179.14,91.92 165.4,91.92 162.53,89.05 153.29,89.05 152.25,88 152.25,85.6 151.88,85.24 149.12,85.24 148.95,85.4 143.16,85.4 143.03,85.26 142.84,85.26 142.27,84.69 142.04,84.69 141.37,84.02 141.37,83.97 140.91,83.52 140.34,83.52 ; v2(150.03,22.62) 150.48,22.17 v2(150.48,16.48)
OPT_DEVSLP_R: length 6.6
  TOP w0.102: v2(156,11.45) 156,11.32 155.61,10.94 R6311.2 154.09,10.86 AFTP6302.1
  BOTTOM w0.102: v2(156,11.45) 157.45,12.9 SSD2.38
OPT_RST#: length 5.4
  TOP w0.102: v1(154.01,17.16) R6310.2 156.1,16.27 156.35,16.02 156.35,16 v2(156.37,16)
  BOTTOM w0.102: SSD2.50 156.47,15.9 v2(156.37,16)
PANEL_BKEN: length 182.2
  TOP w0.127: v2(98.64,102.51) 98.34,102.2 R5544.2 ; D2404.K 31.03,14.75 32.49,16.21 32.49,22.39 v2(32.33,22.55) ; v1(21.12,22.62) v2(21.12,23.36)
  L4SGND w0.127: v2(98.64,102.51) 98.2,102.06 87.1,102.06 86.21,102.95 84.43,102.95 83.29,101.81 49.61,101.81 47.23,99.43 35.72,99.43 30.69,94.4 28.21,94.4 27.67,93.87 27.67,91.43 28.06,91.05 28.06,75.97 28.09,75.94 28.09,72.09 26.26,70.26 26.26,65.35 24.6,63.68 20.02,63.68 18.72,62.38 18.72,58.86 18.09,58.22 18.09,54.92 19.11,53.89 19.11,49.47 18.9,49.25 18.9,46.92 19.05,46.76 19.05,39.4 18.04,38.39 18.04,29.26 18.12,29.17 18.12,24.25 18.89,23.49 20.99,23.49 v2(21.12,23.36)
  L6 w0.127: v2(21.12,23.36) 21.41,23.07 23.38,23.07 24.46,24.15 26.07,24.15 26.67,24.75 31.11,24.75 31.51,24.35 31.51,23.29 32.25,22.55 v2(32.33,22.55)
  BOTTOM w0.127: v2(21.12,23.36) 20.84,23.64 D2401.K
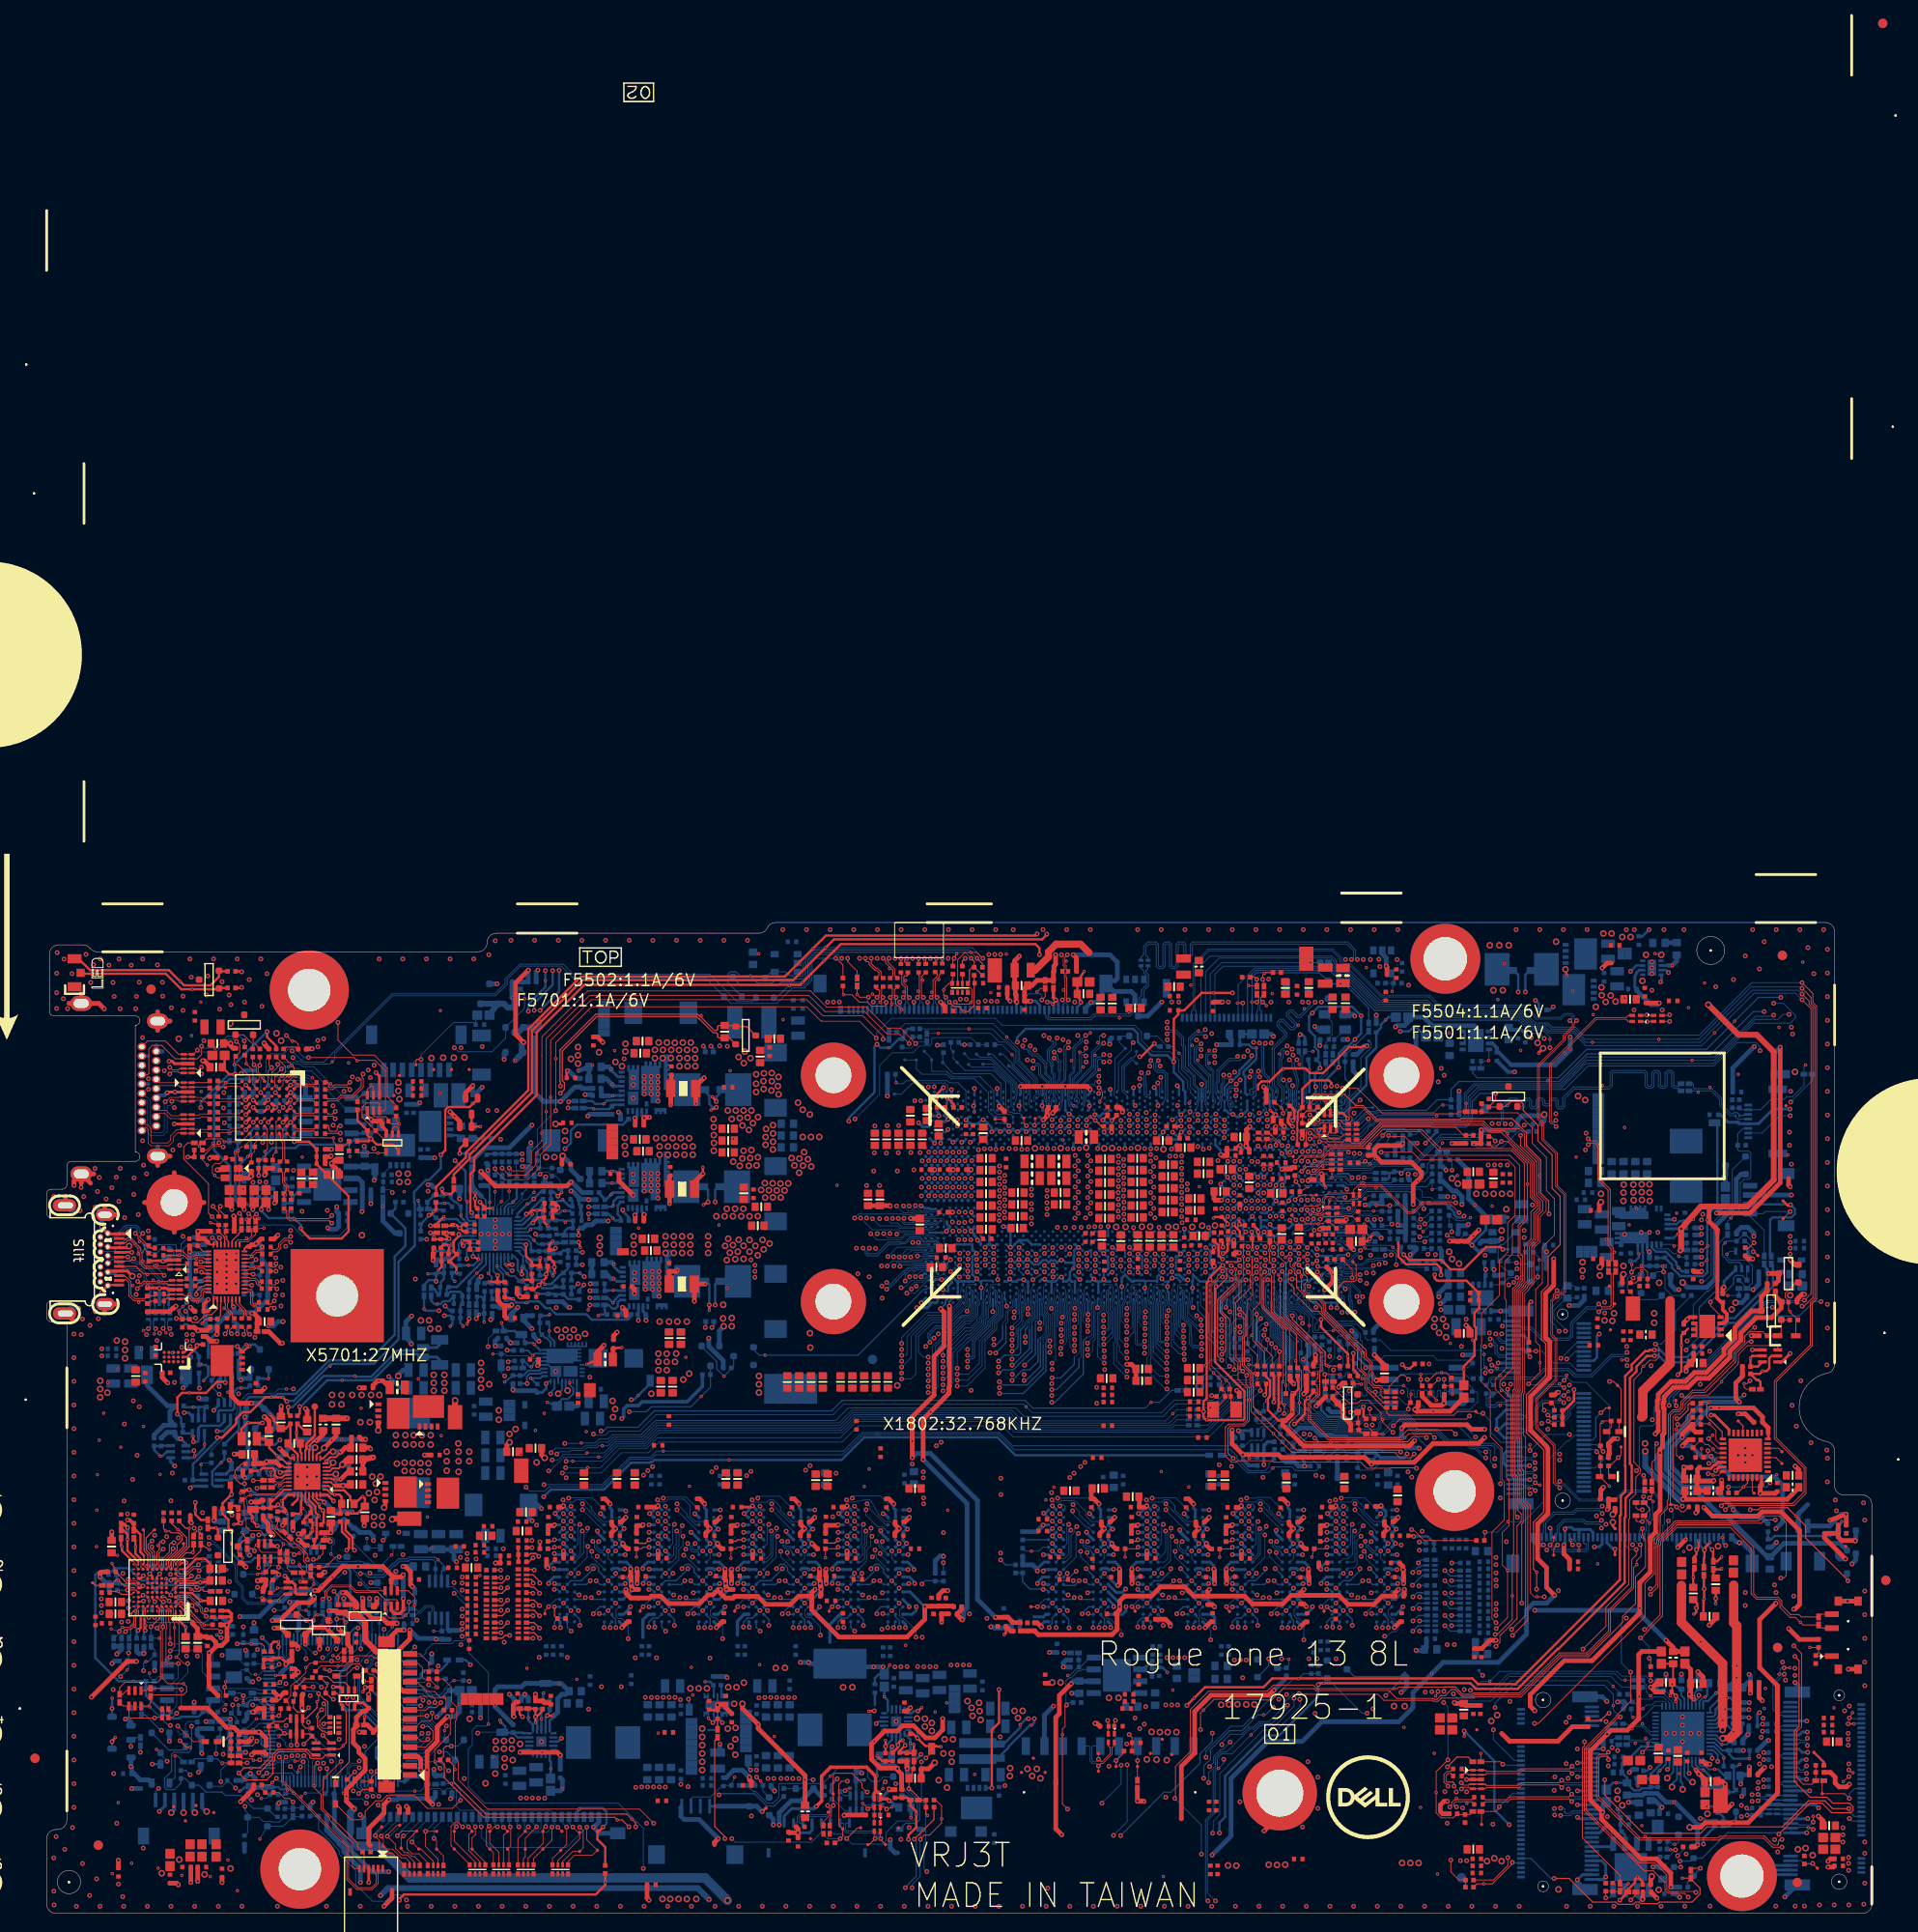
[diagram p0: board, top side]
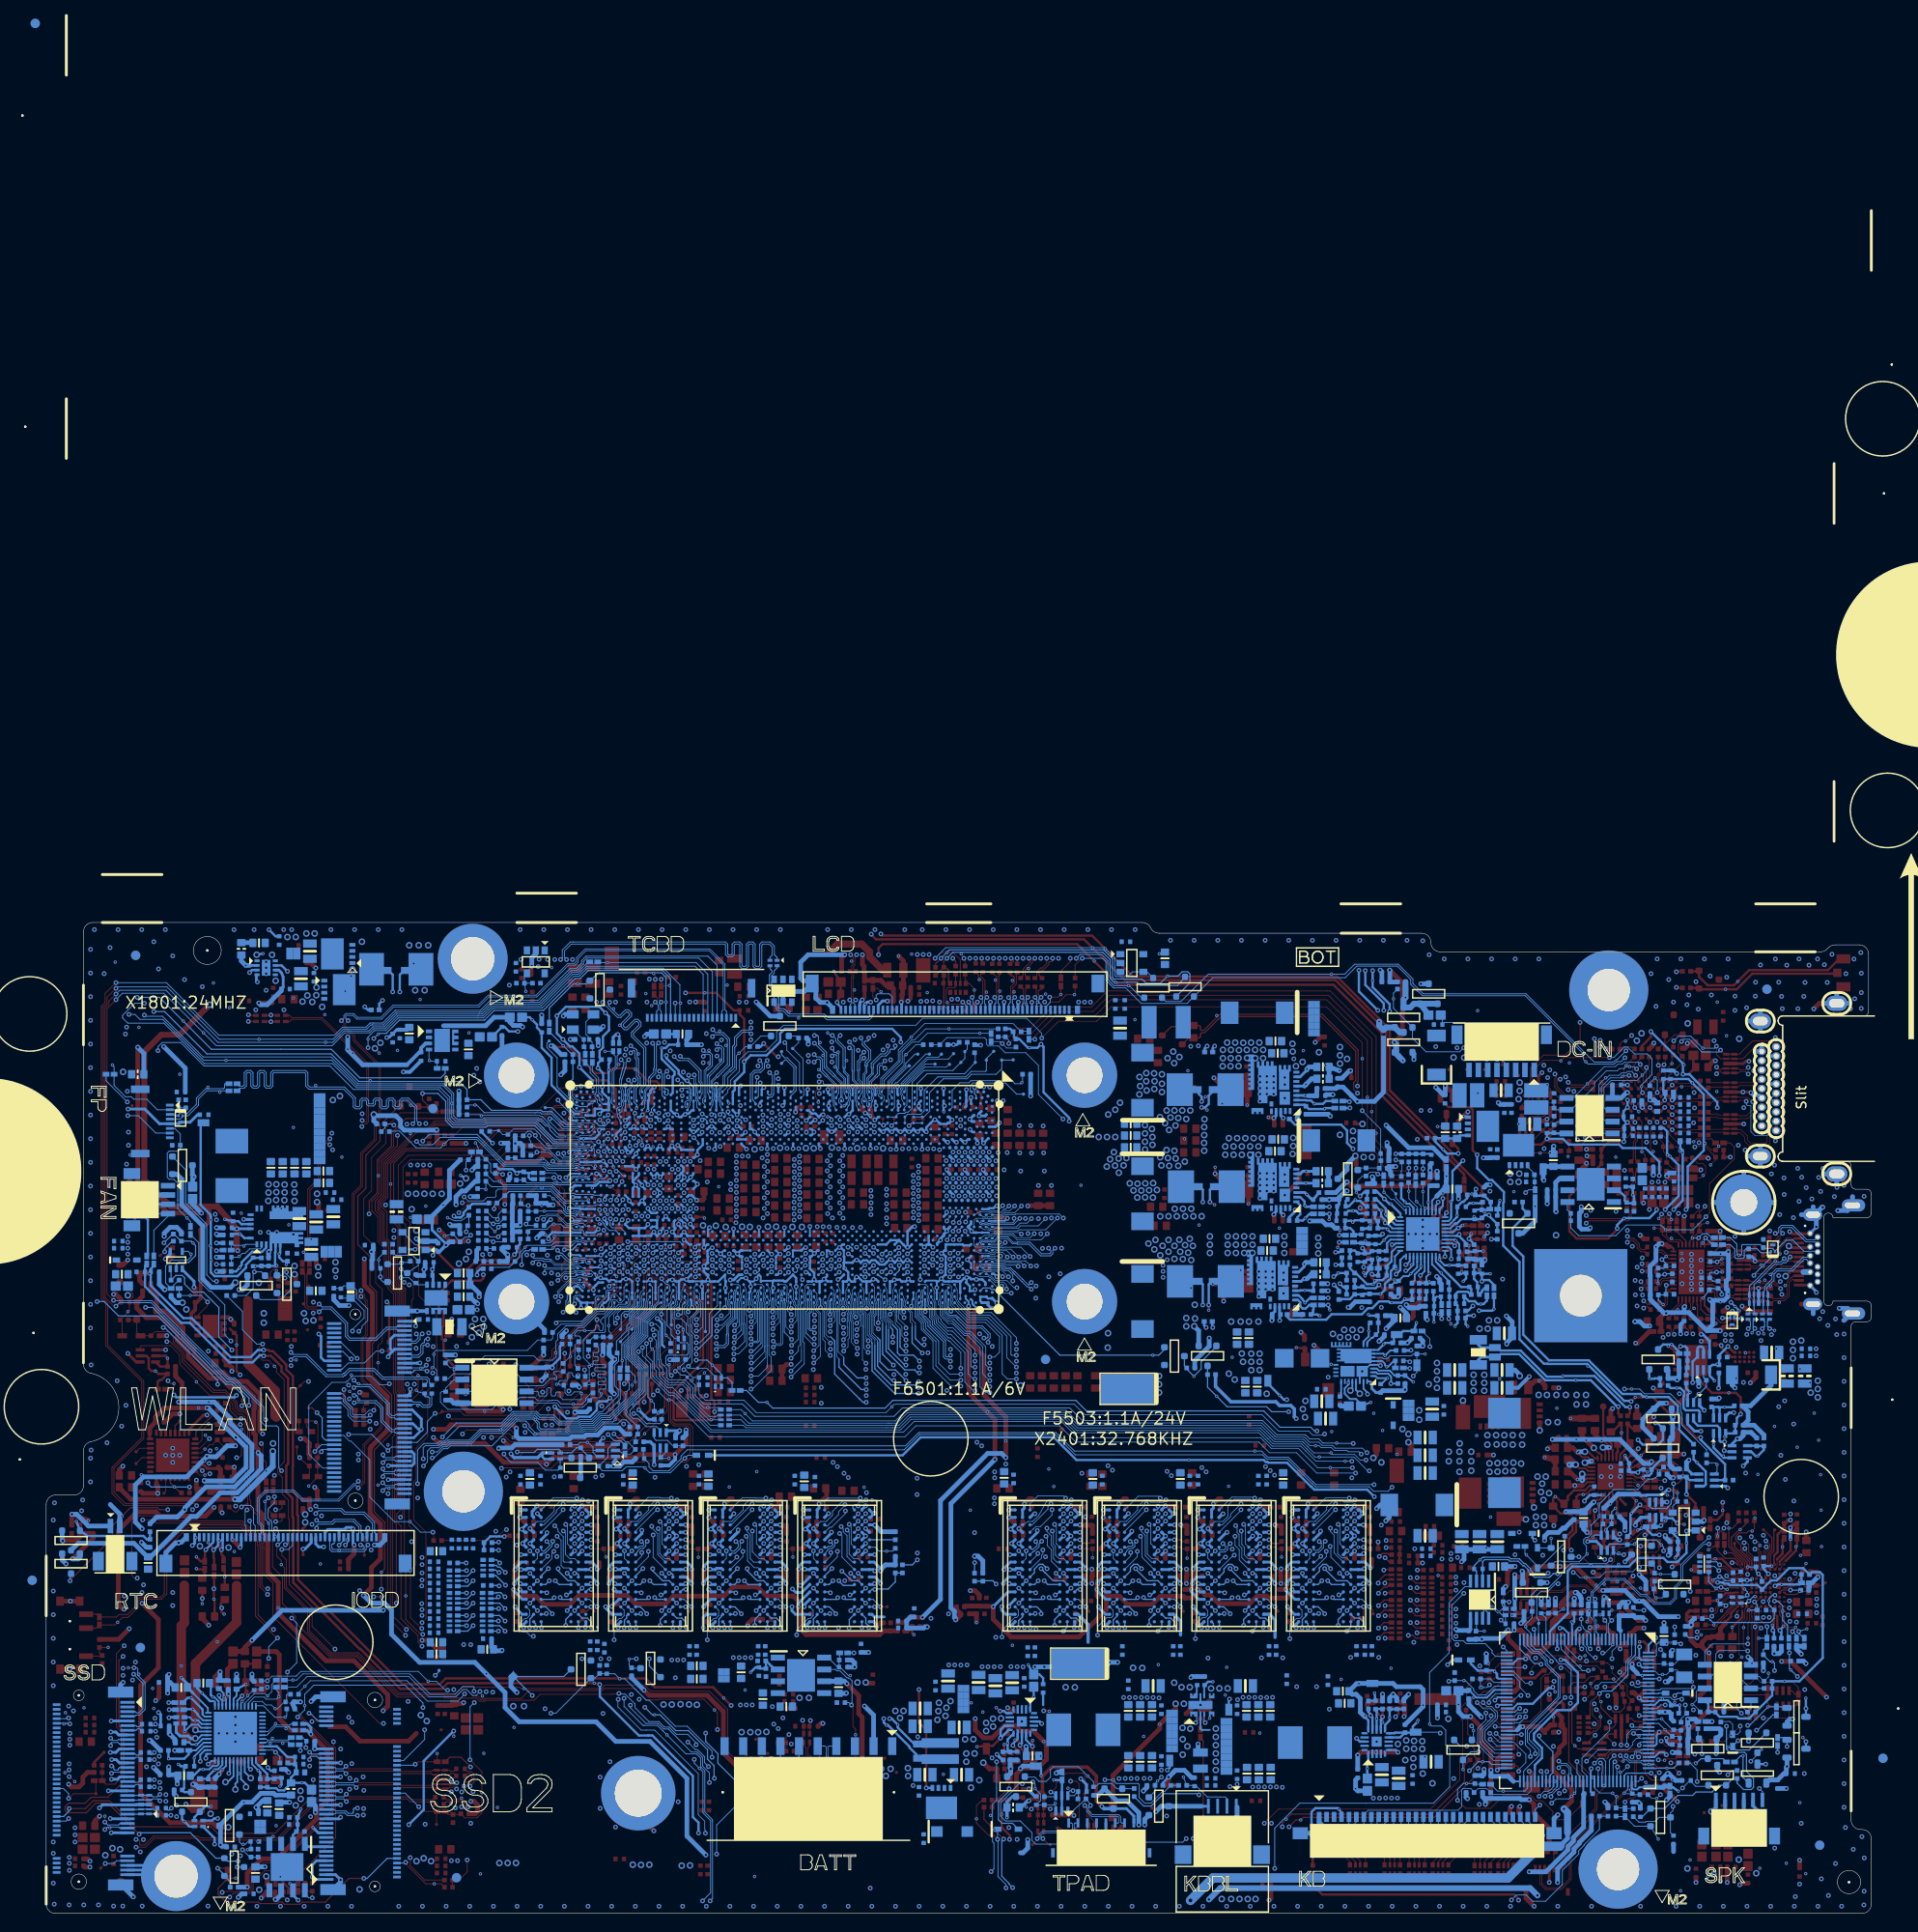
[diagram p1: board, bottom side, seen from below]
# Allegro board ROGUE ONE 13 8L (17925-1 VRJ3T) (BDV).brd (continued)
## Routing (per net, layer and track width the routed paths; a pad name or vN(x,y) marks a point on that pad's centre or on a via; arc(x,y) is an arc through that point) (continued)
PANEL_BKEN_EC: length 1.8
  BOTTOM w0.127: D2401.A 22.85,23.64 22.9,23.59 U2401.117
PBAT_CHG_SMBCLK: length 118.7
  TOP w0.089: v2(22.58,45.64) 22.66,45.71 PR4491.2 ; RN4302.1 114.66,20.06 EC4309.1 114.64,20.59 v2(114.77,20.72) ; ED4306.3 29.66,32.05 v1(29.12,32.05) 28.94,32.05 28.61,31.72 v2(28.61,31.44)
  L4SGND w0.089: v2(22.58,45.64) 22.37,45.43 22.37,44.59 22.56,44.41 22.56,43.79 24.69,41.66 24.73,41.64 25.02,41.35 27.47,38.9 27.47,34.23 28.36,33.34 28.36,31.69 v2(28.61,31.44)
  L6 w0.089: v2(28.61,31.44) 28.34,31.17 28.34,30.95 29.22,30.07 35.24,30.07 35.98,29.33 40.53,29.33 40.86,29 43.35,29 43.9,28.45 45.55,28.45 47.12,26.87 56.33,26.87 56.37,26.92 66.09,26.92 66.89,26.91 70.84,26.91 70.85,26.9 71.55,26.9 72.22,27.57 99.98,27.57 103.18,24.38 103.18,21.32 104.12,20.38 105.77,20.38 106.9,20.38 107.61,21.09 114.4,21.09 v2(114.77,20.72)
  BOTTOM w0.089: RN2402.3 28.81,31.64 v2(28.61,31.44) 28.41,31.24 28.41,30.14 28.54,30.02 U2401.9
PBAT_CHG_SMBDAT: length 119.6
  TOP w0.089: v2(22.19,46.45) 22.21,46.47 PR4490.2 ; v2(27.88,31.44) 27.24,32.08 ED4305.3 26.84,32.28 27.09,32.53 v1(27.88,32.53) ; RN4302.2 114.01,20.06 EC4310.1 114.03,20.59 v2(113.93,20.69)
  L4SGND w0.089: v2(22.19,46.45) 22.19,46.04 22.18,46.04 22.18,44.51 22.37,44.33 22.37,43.71 24.58,41.5 24.61,41.47 24.64,41.47 24.89,41.22 27.28,38.82 27.28,34.15 28.17,33.26 28.17,31.73 v2(27.88,31.44)
  L6 w0.089: v2(27.88,31.44) 28.15,31.17 28.15,30.87 29.14,29.88 35.16,29.88 35.9,29.14 40.45,29.14 40.78,28.81 43.27,28.81 43.82,28.26 45.47,28.26 47.05,26.68 56.4,26.68 56.45,26.73 66.09,26.73 66.89,26.72 70.76,26.72 70.77,26.71 71.63,26.71 72.3,27.38 99.91,27.38 102.99,24.3 102.99,21.24 104.04,20.19 105.77,20.19 106.98,20.19 107.69,20.9 113.72,20.9 v2(113.93,20.69)
  BOTTOM w0.089: U2401.8 28.14,30.04 28.22,30.13 28.22,31.1 v2(27.88,31.44) 28.16,31.72 RN2402.4
PBAT_PRES1#: length 3.7
  TOP w0.102: R4327.2 115.69,17.24 v2(114.85,16.4) AFTP4309.1
  BOTTOM w0.102: BATT1.6 115.15,16.7 v2(114.85,16.4)
PBAT_PRES#: length 111.8
  TOP w0.102: v2(28,37.97) 28,38.58 27.11,39.47 26.93,39.47 26.15,40.25 PR4494.2 ; R4327.1 EC4306.1 116.55,18.89 v2(116.24,19.2)
  L6 w0.102: v2(116.24,19.2) 115.65,18.6 103.41,18.6 102.53,19.47 100.3,19.47 94.86,24.91 88.22,24.91 87.53,25.6 82.89,25.6 82.06,24.76 77.15,24.76 76.11,25.81 72.95,25.81 72.28,25.14 70.12,25.14 70.11,25.15 66.88,25.15 66.65,25.15 57.11,25.15 57.07,25.11 46.01,25.11 45.54,25.57 45.02,25.57 44.61,25.98 37.93,25.98 37.63,26.28 37.63,26.64 37.38,26.89 37.02,26.89 36.75,26.62 36.15,26.62 35.9,26.38 35.68,26.38 35.64,26.33 35.3,26.33 35.26,26.38 35.02,26.38 v2(34.35,27.04)
  BOTTOM w0.102: v2(28,37.97) 28.44,37.53 32.3,37.53 33.29,36.54 33.29,36.3 33.81,35.78 33.81,35.78 34.05,35.54 34.05,35.54 34.63,34.96 35.71,34.96 36.49,34.18 ED4304.3 36.49,32.45 R2415.1 36.44,31.72 37.12,31.03 v1(37.12,30.78) 37.12,30.63 36.54,30.04 U2401.29 36.54,28.82 36.06,28.34 35.5,28.34 34.35,27.19 v2(34.35,27.04)
PCB_ID: length 5.7
  TOP w0.102: R2494.2 25.13,21.43 v2(24.93,21.23) 24.8,21.1 C2408.1 24.25,21.96 R2444.1 23.36,22.85 R2443.2 v1(22.44,23.03)
  BOTTOM w0.102: v2(24.93,21.23) 24.89,21.19 U2401.111
PCB_ID1: length 21.9
  TOP w0.102: R2010.2 R2009.1 152.16,83.51 151.28,84.39 143.36,84.39 141.28,82.3 137.43,82.3 137.35,82.23 v1(137.33,82.23) 137.33,82.21 137.17,82.06 137.17,81.65 136.87,81.35 134.71,81.35 v2(134.07,80.71)
  BOTTOM w0.102: v2(134.07,80.71) 134.49,81.12 CPU1.CG12
PCB_ID2: length 10
  BOTTOM w0.076: 139.43,80.31 139.28,80.46 138.84,80.46 138.81,80.43 arc(138.76,80.4) 138.7,80.39 138.61,80.3 137.44,80.3 CPU1.CM14
  BOTTOM w0.102: 139.43,80.31 141.85,80.31 142.52,80.98 v1(142.74,80.98) 142.85,80.87 145.4,80.87 R2005.2 R2008.1
PCH_BATLOW#: length 11.6
  TOP w0.102: v2(129.93,64.31) 129.99,64.25 129.99,64.02 129.98,64.02 129.98,61.46 131.61,59.83 R1723.1
  BOTTOM w0.102: R1722.2 128.94,61.56 v1(129.43,62.04) 129.53,62.15 129.53,63.44 129.93,63.85 v2(129.93,64.31) 129.93,64.61 129.31,65.24 CPU1.BV36
PCH_DPWROK: length 27.4
  TOP w0.089: 127.52,67.25 127.84,67.57 127.84,68.28 127.7,68.42 v1(127.7,69.13) 127.32,69.51 v2(127.21,69.51)
  TOP w0.127: 127.52,67.25 126.03,65.76 126.03,64.5 126.62,63.91 126.62,60.43 v2(126.2,60.01)
  L6 w0.127: v2(135.66,51.4) 135.66,52.15 128.26,59.56 126.84,59.56 126.38,60.01 v2(126.2,60.01)
  BOTTOM w0.127: CPU1.BP30 126.79,69.84 127.12,69.51 v2(127.21,69.51) ; R1704.2 133.85,50.25 134.31,50.72 134.98,50.72 v2(135.66,51.4)
PCH_JTAG_TCK: length 1.5
  TOP w0.102: TP314.1 104.94,84.82 v2(105.21,84.55)
  BOTTOM w0.102: v2(105.21,84.55) 104.93,84.83 CPU1.W6
PCH_PLTRST#: length 28.4
  TOP w0.089: v2(141.69,52.42) 142.23,51.88 142.29,51.88 142.58,51.58 R1713.2 143.48,51.45 v1(143.5,51.43)
  L6 w0.089: v2(141.69,52.42) 137.04,52.42 137.03,52.43 136.85,52.43 131.05,58.23 130.99,58.23 129.83,59.38 129.83,59.52 129.19,60.17 127.29,60.17 v2(126.2,61.26)
  BOTTOM w0.089: v2(126.2,61.26) 125.82,61.26 124.78,62.3 124.78,64.38 123.91,65.25 123.91,66.55 CPU1.BJ35
PCH_POPIRCOMP: length 2.5
  TOP w0.203: R305.1 129.5,72.36 129.5,71.3 v1(129.48,71.28)
  TOP w0.254: R305.1 129.43,73.12 129.4,73.14 v2(129.4,73.14)
  BOTTOM w0.203: CPU1.BW25 129.4,73.07 v2(129.4,73.14)
PCH_RSMRST#: length 120
  L4SGND w0.102: v2(43.75,35.5) 43.65,35.5 43.57,35.58 43.57,38.17 51.14,45.74 v2(51.47,45.74)
  L6 w0.102: v2(33.64,35.37) 34.08,35.81 34.51,35.81 34.64,35.94 34.99,35.94 35.12,35.81 37.86,35.81 38.01,35.65 38.58,35.65 38.74,35.81 40.58,35.81 42.08,34.31 43.14,34.31 43.65,34.82 43.65,35.4 v2(43.75,35.5)
  BOTTOM w0.102: U2401.27 35.74,31.12 TP2402.1 35.73,31.51 35.93,31.72 35.93,34.1 35.47,34.56 34.74,34.56 33.92,35.37 v2(33.64,35.37) ; R1702.2 131.87,48.89 EC1712.1 131.27,48.29 131.27,47.94 130.85,47.52 129.1,47.52 127.83,48.79 127.83,49.09 127.17,49.75 103.87,49.75 102.22,51.4 89.45,51.4 89.25,51.4 89.05,51.4 87.67,51.4 85.48,49.22 65.38,49.22 64.92,48.76 62.7,48.76 60.06,46.12 60.04,46.12 59.71,45.79 53.94,45.79 53.46,45.31 51.91,45.31 v2(51.47,45.74)
PCH_SATA_LED#: length 314.1
  TOP w0.127: v2(187.75,27.58) 188.19,27.13 188.19,20.08 187.68,19.57 187.68,14.16 189.38,12.46 191.17,12.46 191.81,11.83 193.58,11.83 193.98,11.43 193.98,11.06 193.72,10.8 191.69,10.8 190.67,11.83 189.35,11.83 v2(186.02,8.5) ; R6420.1 43.7,15.9 43.7,14.13 47.15,10.68 47.24,10.68 47.26,10.66 62.29,10.66 v1(62.84,10.11) 63.26,9.7 v2(63.26,9.29)
  L4SGND w0.127: v2(187.75,27.58) 189.13,28.97 189.13,49.2 186.51,51.82 186.51,52.22 186.51,52.22 186.51,57.82 189.78,61.08 189.78,68.41 190.22,68.85 190.22,94.29 187.38,97.13 184.79,97.13 v2(184.44,96.79) ; v2(63.26,9.29) 64.15,8.4 64.81,8.4 64.95,8.26 65.42,8.26 68.72,4.96 93.43,4.96 94.34,4.04 105.62,4.04 106.11,4.53 113.57,4.53 113.58,4.53 116.41,4.53 117.2,4.53 120.06,7.4 124.76,7.4 124.94,7.57 126.38,7.57 127.45,6.51 127.82,6.51 140.76,6.51 141.38,7.13 156.74,7.13 157.24,7.13 157.87,6.51 174.02,6.51 174.92,5.61 v2(175.4,5.61)
  BOTTOM w0.076: CPU1.CN7 138.28,84.65 138.5,84.65 138.62,84.69 138.8,84.69 138.95,84.64 139.64,84.64
  BOTTOM w0.127: 139.64,84.64 140.13,84.64 140.31,84.82 140.33,84.82 140.49,84.98 140.66,84.98 141.73,86.05 142.7,86.05 142.84,86.19 148.18,86.19 149.32,87.33 R1606.2 150.81,88.43 151.66,89.29 162.43,89.29 165.39,92.25 178.74,92.25 183.29,96.79 v2(184.44,96.79) ; v2(186.02,8.5) 185.87,8.65 180.51,8.65 177.78,5.92 D6401.1 176.55,5.61 v2(175.4,5.61)
PCIE_RCOMPN: length 2.2
  TOP w0.305: v2(133.8,84.47) 133.61,84.59 133.31,84.89 133.31,85.31 R1604.1
  BOTTOM w0.305: CPU1.CE6 133.61,84.59 v2(133.8,84.47)
PCIE_RCOMPP: length 2.5
  TOP w0.305: R1604.2 133.79,86.45 133.99,86.2 133.99,85.26 v2(133.82,85.1)
  BOTTOM w0.305: CPU1.CE5 v2(133.82,85.1)
PCIE_WAKE#_CPU: length 13.5
  L6 w0.102: v2(128.13,62.98) 128.33,62.98 128.69,63.34 128.69,66.95 127.67,67.96 127.67,71.11 127.95,71.39 128.39,71.39 128.61,71.16 128.61,70.58 v2(128.99,70.2)
  BOTTOM w0.102: RN1704.3 127.6,61.81 v1(127.6,62.63) 127.6,62.81 127.78,62.98 v2(128.13,62.98) ; v2(128.99,70.2) 128.94,70.2 128.59,69.84 CPU1.BU30
PD4403_A: length 2.5
  BOTTOM w0.102: PD4404.A 35.83,39.22 PQ4408.B v1(34.39,40.25)
PD4403_K: length 7.7
  BOTTOM w0.102: PR4477.2 37.2,38.63 v1(37.05,38.47) 35.85,37.28 PD4404.K 35.66,37.04 32.93,39.77 PR4495.1
PD_IRQ1: length 4.6
  TOP w0.127: R7224.2 17,30.96 v1(16.9,30.96) 15.55,32.31 15.55,32.43 14.54,33.44 U7201.C1
PD_OVP_TRIP_P1: length 24.1
  TOP w0.127: U7201.E10 9.59,34.7 v2(8.68,34.7) ; v2(18.73,29.58) v1(18.28,29.89)
  L6 w0.127: v2(8.68,34.7) 9.37,34 9.37,30.13 8.38,29.14 8.38,27.67 9.46,26.6 12.95,26.6 15.93,29.58 v2(18.73,29.58)
  BOTTOM w0.127: v2(18.73,29.58) 19.62,29.58 R7243.2 ; v2(8.68,34.7) 8.66,34.69 R7250.2
PD_VBUS_C_CTRL1: length 24.9
  TOP w0.089: U7201.G10 9.59,35.71 8.93,35.71 v2(8.78,35.86)
  TOP w0.254: v2(15.76,50.61) v1(15.74,51.17)
  L4SGND w0.254: v2(15.76,50.61) 15.76,50.41 15.03,49.68 15.03,48.09 14.35,47.42 14.35,42.78 12.38,40.81 12.38,40.48 11.82,39.92 11.82,38.91 v2(8.78,35.86)
  BOTTOM w0.254: v2(15.76,50.61) 16.19,50.61 16.3,50.72 Q7405.2 16.3,52.09 16.55,52.34 18.63,52.34 19.09,52.8 Q7406.5
PD_VBUS_C_CTRL1_A: length 4
  BOTTOM w0.254: Q7404.3 15.86,48.9 16.95,49.99 v1(16.95,50.34) Q7405.1
PD_VBUS_C_CTRL1_R: length 5
  BOTTOM w0.254: 16.45,54.33 16.3,54.18 Q7405.5 ; 16.45,54.33 16.47,54.35 R7410.1 16.95,54.14 Q7405.6 ; 16.45,54.33 v1(15.76,54.33) 14.87,54.33 R7426.2
PD_VBUS_C_EN: length 6.2
  TOP w0.254: v2(15.41,60.85) 14.76,60.21 U7419.A3
  BOTTOM w0.254: v2(15.41,60.85) 16.35,59.91 R7422.1 16.35,58.9 R7427.2 17.08,58.87 17.37,58.58 Q7407.3 17.37,57.72 16.85,57.2 v1(16.85,57.17)
PD_VBUS_C_EN_A: length 16.3
  TOP w0.254: v2(14.03,53.59) 14.03,55.36 14.53,55.86 v1(15.31,55.86) 17.12,55.86 18.32,57.07 19.09,57.07 v2(19.19,56.96)
  BOTTOM w0.254: Q7405.3 14.73,51.52 R7408.1 R7425.2 14.44,52.57 14.44,53.18 v2(14.03,53.59) ; Q7407.5 18.02,60.65 18.2,60.83 18.5,60.83 18.67,60.66 Q7407.6 18.67,59.74 19.19,59.23 v2(19.19,56.96)
PECI_CPU: length 187.7
  L4SGND w0.089: v2(22.65,12.74) 20.39,12.74 19.86,13.28 19.86,13.87 20.21,14.22 20.21,18.27 20.34,18.4 20.34,19.1 21.44,20.2 22.79,20.2 23.54,20.96 23.54,25.38 21.84,27.09 21.84,32.78 20.07,34.55 20.07,35.42 20.07,35.43 20.07,35.78 20.07,35.78 20.07,40.24 21.27,41.44 21.27,42.75 20.44,43.57 20.44,45 20.26,45.18 20.26,48.7 20.56,48.99 20.56,49.6 20.19,49.97 20.19,54.49 19.8,54.88 19.8,56.3 20.26,56.76 20.26,57.73 24.19,61.66 26.34,61.66 28.46,63.78 28.46,68.74 31.65,71.94 31.65,81.72 33.69,83.76 33.69,86.63 43.37,96.31 49.8,96.31 51.82,98.34 79.85,98.34 81.19,97 115.23,97 117.23,94.99 117.23,94.02 v2(116.68,93.46)
  BOTTOM w0.089: v2(22.65,12.74) v1(23.05,12.34) 23.58,12.34 R2437.2 ; v2(116.68,93.46) 116.47,93.25 116.47,92.65 115.1,91.28 115.1,88.34 CPU1.AR1
PIRQA#: length 68.7
  TOP w0.102: v2(175.55,48.91) 175.3,48.91 175.02,49.19 175.02,51.47 176.45,52.9 176.49,52.9 176.77,53.18 R9137.1 ; v2(132.68,68.9) 132.88,68.7 132.88,66.71 132.89,66.7 132.89,64.01 136.79,60.12 136.79,59.2 136.78,59.19 136.78,58.76 136.79,58.75 136.79,58.34 136.51,58.06 136.51,57.42 R2053.2 136.46,56.51 136.46,55.69 135.5,54.73 135.5,52.95 137.63,50.82 145.61,50.82 v1(145.85,51.06) 146.27,51.48 148.63,51.48 v2(149.04,51.07)
  L4SGND w0.102: v2(149.04,51.07) 149.16,50.95 152.7,50.95 153.29,51.53 159.44,51.53 160.56,50.41 161.9,50.41 163.32,51.83 166.92,51.83 167.09,52.01 171.44,52.01 172.5,50.95 173.52,50.95 v2(175.55,48.91)
  BOTTOM w0.102: CPU1.CC32 132.58,68.9 v2(132.68,68.9)
PLT_RST#_Q_TPM2: length 5.7
  TOP w0.127: R9136.2 177.76,54.88 v1(178.55,54.88) 178.28,54.62 178.28,53.29 178.66,52.91 178.7,52.91 179.92,51.69 U9102.17
PLTRST#_CPU: length 304.5
  TOP w0.127: v2(166.92,53.74) 167.43,54.25 AFTP6108.1 ; v2(167.32,14.34) 167.32,12.7 171.4,8.62 171.79,8.62 171.82,8.59 177.6,8.59 178.3,9.29 186.41,9.29 189.21,12.08 190.95,12.08 191.78,11.24 v2(193.54,11.24) ; v2(175.07,53.1) 175.08,53.1 175.34,53.1 176.26,54.02 176.26,54.57 176.45,54.76 R9136.1 ; v2(150.43,15.72) 150.43,15.74 151.46,16.77 152.66,16.77 R6310.1 ; v2(140.02,53.78) 140.08,53.84 140.75,53.84 ED1701.1 140.83,53.76 C1701.1 140.91,52.57 R1715.1 141.21,51.58 R1713.1
  L4SGND w0.127: v2(167.32,14.34) 165.07,16.59 152.63,16.59 151.75,15.72 v2(150.43,15.72) ; v2(140.02,53.78) 140.09,53.71 145,53.71 145.85,54.56 147.27,54.56 148.48,53.36 151.93,53.36 152.69,54.12 158.41,54.12 161.02,51.52 161.44,51.52 162.9,52.98 166.16,52.98 v2(166.92,53.74) 173.6,53.74 173.88,53.46 174.77,53.46 175.07,53.15 v2(175.07,53.1)
  L6 w0.127: v2(166.92,53.74) 166.83,53.65 166.83,50.53 167.59,49.76 167.59,49.39 167.5,49.3 167.5,46.5 168.34,45.66 168.34,43.81 168.73,43.41 168.73,41.75 167.56,40.58 164.2,40.58 163.41,39.79 163.41,38.32 164.35,37.38 164.35,33.93 161.91,31.5 161.91,22.37 160.67,21.13 160.67,20.65 156.47,16.45 155.84,16.45 155.11,15.72 v2(150.43,15.72) 148.85,17.3 148.58,17.3 148.4,17.48 144.28,17.48 143.56,18.2 129.26,18.2 125.25,14.19 125.25,13.66 125.25,12.39 122.28,9.42 107.92,9.42 107.02,8.51 107,8.51 106.95,8.47 106.8,8.47 95.57,8.47 95.53,8.51 95.14,8.51 94.56,9.1 93.7,9.1 93.14,9.66 92.41,9.66 91.64,8.9 81.84,8.9 81.18,9.56 80.47,9.56 79.53,8.62 75.17,8.62 74.97,8.62 74.46,8.62 74.15,8.92 69.65,8.92 69.51,8.78 42.3,8.78 41.26,9.81 40.81,9.81 39.89,10.72 39.64,10.72 39.59,10.77 34.75,10.77 33.33,12.2 33.13,12.2 32.93,12.2 30.73,14.41 25.4,14.41 24.87,14.94 24.49,14.94 23.88,14.33 19.64,14.33 19.29,14.67 15.61,14.67 v2(15.41,14.88)
  BOTTOM w0.127: SSD1.50 194.13,10.4 193.56,10.97 193.56,11.22 v2(193.54,11.24) ; WLAN1.52 166.01,50.8 166.36,51.15 166.36,53.18 v2(166.92,53.74) ; v2(15.41,14.88) 14.95,15.33 R2616.1
PM_PCH_PWROK: length 17.2
  TOP w0.089: v2(127.23,68.89) 127.23,68.64 127.66,68.2 127.66,67.75 127.32,67.4
  TOP w0.127: v2(126.2,59.38) 125.74,59.84 125.74,65.83 127.32,67.4
  BOTTOM w0.127: R1706.2 122.34,56.99 122.82,57.47 RN1703.3 123.49,57.86 v1(124.46,58.83) 125.01,59.38 v2(126.2,59.38) ; CPU1.BP31 126.9,69.19 127.22,68.88 127.22,68.89 v2(127.23,68.89)
PM_RSMRST#: length 104
  TOP w0.089: Q1701.3 185.9,60.81 185.79,60.93 182.64,60.93 181.67,59.96 181.67,59.09 181.64,59.05 181.64,58.93 179.87,57.17 v1(179.87,57.04) 178.46,55.62 176.91,55.62 175.97,54.68 175.97,54.14 175.4,53.57 174.94,53.57 174.65,53.28 174.65,44.72 v2(175.66,43.71)
  L4SGND w0.089: v2(175.66,43.71) 175.3,44.07 173.72,44.07 171.8,42.14 171.8,41.11 171.16,40.47 155.8,40.47 154.85,39.52 149.39,39.52 147.89,41.01 v2(147.71,41.01)
  L6 w0.089: v2(127.04,58.72) 127.04,58.95 127.19,59.1 128.31,59.1 135.09,52.32 135.09,51.53 v2(135.03,51.47) 135.03,51.11 136.03,50.11 139.59,50.11 146.09,43.6 146.09,42.64 v2(147.71,41.01)
  BOTTOM w0.076: CPU1.BR36 127.44,65.95 127.31,65.82 127.25,65.76 arc(127.2,65.69) 127.18,65.6 127.18,65.38 127.46,65.1 127.46,64.4 127.12,64.05 127.12,63.22 127.08,63.19 127.08,63.18 127.01,63.11
  BOTTOM w0.089: Q1702.2 134.48,49.7 134.08,49.29 R1704.1 133.24,49.29 R1702.1 133.55,50.63 133.79,50.63 134.19,51.02 134.59,51.02 v2(135.03,51.47) ; 127.01,63.11 126.91,63.01 126.91,62.25 126.66,62.01 126.66,62 126.65,61.98 126.65,59.11 v2(127.04,58.72) 126.84,58.51 TP1713.1 125.06,58.51 124.14,57.59 RN1703.4
PM_RSMRST#_M: length 5
  BOTTOM w0.102: 137.28,49.7 137.28,49.47 136.85,49.05 Q1702.6 ; 137.28,49.7 137.28,50.03 137.78,50.54 v1(137.88,50.54) 138.67,50.54 138.9,50.31 R1737.2 ; 137.28,49.7 Q1702.5
PM_SLP_A#: length 2.5
  BOTTOM w0.127: TP1706.1 128.88,63.18 128.88,65.32 CPU1.BU37
PM_SLP_S0#: length 280.2
  TOP w0.127: R2481.1 33.94,13.3 v2(33.51,12.87) ; TP1711.1 183.35,71.01 v2(183.27,71.01) ; R9141.2 v2(180.61,45.76)
  L4SGND w0.127: v2(142.36,52.42) 142.8,52.86 145.44,52.86 147.68,50.63 154.24,50.63 154.26,50.6 154.99,50.6 155.02,50.58 159.16,50.58 161.52,48.21 165.72,48.21 165.89,48.38 166.39,48.38 166.4,48.39 169.55,48.39 169.8,48.65 172.53,48.65 175.22,45.95 180.42,45.95 v2(180.61,45.76) 181.88,44.49 181.88,43.18 181.57,42.87 179.8,42.87 178.25,44.42 177.05,44.42 175.5,42.87 174.56,42.87 174.54,42.84 173.67,42.84 172.63,41.8 172.63,41.59 172.63,39.26 170.07,36.7 163.72,36.7 161.27,34.24 161.27,32.25 156.07,27.06 152.86,27.06 152.63,26.83 143.29,26.83 142.97,26.51 142.74,26.51 136.98,20.76 133.07,20.76 v2(131.71,22.12) ; v2(185.08,46.21) 185.08,49.42 183.97,50.53 183.97,56.88 182.6,58.25 182.6,67.01 183.64,68.05 183.64,70.64 v2(183.27,71.01)
  L6 w0.127: v2(126.18,60.62) 126.35,60.62 127.01,59.96 129.1,59.96 129.5,59.56 129.5,59.34 137.09,51.76 141.69,51.76 v2(142.36,52.42) ; v2(124.25,14.5) 124.12,14.5 123.74,14.88 123.26,14.88 123.22,14.84 122.99,14.84 120.63,12.48 120.63,12.28 120.28,11.93 118.61,11.93 117.73,12.81 116.42,12.81 116.42,12.81 115.54,12.81 115.54,12.81 114.75,12.81 114.75,12.81 113.57,12.81 113.43,12.81 110.9,10.28 110.53,10.28 109.81,10.28 109.8,10.27 107.8,10.27 106.73,9.2 106.71,9.2 106.67,9.16 106.52,9.16 95.86,9.16 95.81,9.2 95.43,9.2 94.57,10.05 93.76,10.05 93.34,10.47 92.14,10.47 91.25,9.58 82.58,9.58 81.92,10.24 78.11,10.24 77.17,9.3 74.74,9.3 74.3,9.75 66,9.75 65.31,10.44 41.89,10.44 41.63,10.7 41.34,10.7 41.34,10.7 41.18,10.7 38.64,13.24 38.44,13.24 33.87,13.24 v2(33.51,12.87)
  BOTTOM w0.127: v2(126.18,60.62) 125.9,60.62 124.5,62.02 124.5,63.85 123.62,64.73 CPU1.BJ37 ; v2(124.25,14.5) 124.25,14.62 124.28,14.66 124.28,15.85 124.98,16.55 124.98,17.57 127.03,19.61 128.38,19.61 130.07,21.3 v1(130.67,21.3) 130.9,21.3 v2(131.71,22.12) ; v2(180.61,45.76) 184.72,45.76 185.08,46.12 v2(185.08,46.21) ; v2(183.27,71.01) 183.27,71.34 182.46,72.15 R4040.1
PM_SLP_S3#: length 357.1
  TOP w0.127: v2(14.31,18.53) 15.03,17.82 v1(15.41,17.82) ; v2(72.84,8.02) 72.84,8.22 71.74,9.31 71.74,18.51 72.05,18.81 R4010.1
  L4SGND w0.127: v2(34.14,17.93) 34.58,18.37 34.58,22.7 35.03,23.15 35.03,23.7 34.8,23.93 34.8,31.35 36.55,33.1 36.55,33.98 36.55,37.98 38.02,39.45 38.91,39.45 47.32,47.87 47.32,55.06 48.62,56.35 48.62,58.25 v2(49.57,59.2) ; v2(125.18,19.35) 125.59,19.35 125.85,19.09 137.61,19.09 143.89,25.38 153.39,25.38 153.55,25.55 v2(154.22,25.55) 157.39,25.55 160.82,28.97 163.82,28.97 167.21,32.36 168.22,32.36 170.94,35.09 174.41,38.56 174.41,40.63 175.17,41.39 182.76,41.39 184.18,42.81 184.18,43.16 184.18,44.28 180.9,47.56 180.9,55.63 v2(176.06,60.47) ; v2(115.33,8.35) 112.97,5.99 95.99,5.99 95.76,6.22 73.98,6.22 72.84,7.36 v2(72.84,8.02) 72.84,8.25 70.97,10.11 58.64,10.11 58.44,10.11 57.32,11.23 47.61,11.23 44.87,13.97 44.87,14.45 v2(44.84,14.47)
  L6 w0.127: v2(128.16,62.38) 129.02,62.38 131.76,59.64 131.83,59.59 134.21,59.59 136.4,57.4 140.15,57.4 142.28,55.26 143.71,55.26 144.92,56.47 146.07,56.47 148.44,54.1 148.44,53.98 148.44,53.04 149.51,51.97 149.51,50.75 149.72,50.53 149.72,50.53 153.85,46.4 153.85,39.25 154.18,38.93 154.18,28.34 154.22,28.3 v2(154.22,25.55) ; v2(14.31,18.53) 14.54,18.31 21.76,18.31 22.02,18.05 23.93,18.05 24.6,17.38 26.53,17.38 26.53,17.38 28.74,17.38 28.9,17.54 32.17,17.54 32.55,17.93 v2(34.14,17.93) 34.28,17.79 38.21,17.79 39.18,16.82 43.21,16.82 44.84,15.18 v2(44.84,14.47)
  BOTTOM w0.076: v2(128.16,62.38) 128.54,62.76 128.54,63.72 128.69,63.87 128.69,65.07 128.39,65.37 128.39,65.62 128.48,65.84 128.48,66.02 CPU1.BU36
  BOTTOM w0.127: TP1707.1 153.81,25.95 v2(154.22,25.55) ; v2(176.06,60.47) 177.46,61.87 177.46,65.04 179.12,66.69 180.28,66.69 181.14,67.56 181.14,68.22 181.4,68.47 182.08,68.47 R4018.1 182.59,69.1 U4008.1 ; v2(125.18,19.35) 125.18,18.46 123.86,17.13 123.86,16.12 120.74,13 119.98,13 v2(115.33,8.35) ; PR5112.1 49.67,59.3 v2(49.57,59.2) ; Q4001.G 13.12,17.53 14.53,17.53 D4003.K 14.9,17.95 v2(14.31,18.53)
PM_SLP_S4#: length 309.6
  TOP w0.127: TP1709.1 174.94,54.58 175,54.52 v2(175,54.48)
  L4SGND w0.127: v2(186.22,98.32) 186.88,98.32 190.7,94.49 190.7,68.65 190.54,68.49 v2(190.54,65.67) 190.54,61.16 187,57.62 187,52.02 189.62,49.4 189.62,23.65 188.29,22.32 188.29,13.18 184.56,9.45 180.35,9.45 178.89,10.91 178.89,10.91 178.57,11.23 175.77,11.23 173.09,13.91 173.09,17.23 170.35,19.97 169.25,19.97 168.18,21.04 166.53,21.04 162.47,25.1 159.68,25.1 158.51,23.93 155.77,23.93 153.71,21.87 150.15,21.87 148.76,23.27 v2(148.76,23.79) ; v2(175,54.48) 174.58,54.06 173.96,54.06 173.8,54.22 173.6,54.22 172.87,54.22 172.68,54.41 172.48,54.41 165.48,54.41 164.63,53.57 164.38,53.57 164.37,53.57 162.39,53.57 160.96,55 152.34,55 151.34,53.99 148.38,53.99 147.38,54.98 145.17,54.98 144.94,54.76 142.22,54.76 139.91,57.07 137.4,57.07 135.8,58.67 135.8,59.96 133.1,62.67 133.1,71.81 132.82,72.09 132.05,72.09 132,72.15 131.45,72.15 131.33,72.03 129.49,72.03 129.05,71.59 129.05,71.58 v2(129.03,71.56)
  L6 w0.127: v2(109.26,27.96) 130.09,27.96 130.72,27.32 v2(131.23,27.32) 131.98,28.07 145.68,28.07 147.94,25.81 147.94,24.61 v2(148.76,23.79)
  BOTTOM w0.127: R4024.1 153.15,90.16 153.63,89.68 162.32,89.68 165.38,92.74 170.77,92.74 178.26,92.74 v1(181.28,95.77) 183.83,98.32 v2(186.22,98.32) ; v2(131.23,27.32) 131.23,26.55 Q9202.G ; v2(190.54,65.67) 189.77,65.67 188.22,64.12 184.03,64.12 176.7,56.79 176.06,56.79 174.67,55.39 174.67,54.81 v2(175,54.48) ; CPU1.BU27 128.79,71.79 129.01,71.57 129.02,71.57 v2(129.03,71.56) ; PR5417.1 v2(109.26,27.96)
PM_SLP_S5#: length 2
  TOP w0.127: TP1710.1 126.79,69.94 127.87,69.94 v2(128.08,70.15)
  BOTTOM w0.127: CPU1.BT29 127.74,70.49 v2(128.08,70.15)
POWER_SW_IN#: length 8.4
  TOP w0.102: R2451.1 23.36,28.69 23.13,28.92 v1(21.98,28.92) v2(20.46,28.92)
  BOTTOM w0.102: U2401.127 23.2,27.59 23.08,27.71 23.08,28.87 22.85,29.1 C2427.1 21.17,29.1 R2432.1 20.59,29.05 v2(20.46,28.92)
PQ3802_1: length 13.2
  TOP w0.508: v2(51.73,101.24) 50.36,99.87 50.36,94.35 v2(51.22,93.49)
  BOTTOM w0.508: R4309.2 R4302.1 51.7,101.21 v2(51.73,101.24)
  BOTTOM w0.635: v2(51.22,93.49) 51.03,93.3 51.03,92.57 Q4302.B 50.75,91.99 50.75,91.98 v1(50.32,91.55)
PQ4348_D: length 4.8
  BOTTOM w0.508: Q4348.D 37.43,72.99 36.11,74.31 v1(36.11,75.89) R4368.2
PQ4405_2: length 11.1
  TOP w0.102: PQ4405.2 28.36,34.92 28.69,35.25 v1(28.69,35.35) 28.69,35.96 PR4462.1 28.3,36.29 27.94,36.65 27.94,37.46 27.59,37.8 27.59,38.71 27.03,39.27 26.47,39.27 25.61,40.14 25.42,40.14 24.22,41.33 24.22,41.98 24.04,42.16 PR4463.1
PQ4405_3: length 2.1
  TOP w0.089: PQ4405.3 27.56,35.92 27.45,36.04 PR4476.1 27.45,36.9 27.15,37.19 v1(27.15,37.46)
PQ4405_5: length 3.6
  TOP w0.102: PQ4405.5 v1(24.79,34.92) 24.28,34.41 PC4438.1 24.02,35.5 PR4474.2
PQ4405_6: length 3.2
  TOP w0.102: PQ4405.6 25.45,34.27 24.93,33.75 v1(24.93,33.57) 24.85,33.5 PC4438.2 23.71,33.5 23.53,33.67 PR4450.1
PQ4408_C: length 4.3
  TOP w0.102: PR4462.2 PR4475.1 29.93,37.15 v1(30.14,37.36) 31.05,38.27 v2(31.41,38.27)
  BOTTOM w0.102: PQ4408.C v2(31.41,38.27)
PQ4408_E: length 19.5
  BOTTOM w0.102: PQ4408.E 33.97,37.74 33.7,37.74 33.62,37.81 33.26,37.81 33.18,37.74 31.37,37.74 v1(30.53,38.57) 30.6,38.63 30.6,39.44 30.9,39.74 30.9,40.1 30.65,40.35 30.42,40.35 30.09,40.68 30.09,41.65 29.22,42.51 29.22,43.93 27.67,45.48 25.08,45.48 23.97,46.6 23.47,46.6 23.41,46.66 23.34,46.66 23.25,46.75 23.18,46.75 PR4436.1 22.8,47.41 PR4473.2
PQ4415_5: length 3.9
  TOP w0.254: v2(22.59,41.62) 22.09,42.13 v1(22.09,42.16) 22.09,42.66 21.86,42.89 PG4408.2
  BOTTOM w0.254: PQ4415.5 23.15,41.95 23.31,41.8 PR4492.1 22.72,41.5 v2(22.59,41.62)
PQ4415_6: length 3.5
  TOP w0.254: PR4493.1 20.59,42.13 v2(20.84,41.88) v1(20.09,41.75)
  BOTTOM w0.254: v2(20.84,41.88) 21.38,42.41 21.87,42.41 21.96,42.5 PQ4415.6
PQ4416_3: length 4
  TOP w0.089: PQ4416.3 22.8,39.66 22.8,39.05 23.1,38.75 PR4489.1 v1(25.41,39.66)
PQ4417_D: length 3.3
  TOP w0.127: v1(21,40.87) PR4483.2 21.17,40.02 PQ4417.D 20.54,38.7 PR4479.2
PQ4417_G: length 2
  TOP w0.254: PQ4417.G 18.4,41.17 v1(18.2,41.37) PR4488.1
PQ4418_2: length 8.4
  TOP w0.127: v2(22.31,38.91) 22.06,39.16 PR4483.1
  BOTTOM w0.127: v2(22.31,38.91) 22.31,39.31 v1(22.54,39.54) 23.08,40.07 25.03,40.07 25.52,39.59 PR4484.1 26.25,39.64 28.11,39.64 28.36,39.39 PQ4418.2
PQ4418_3: length 2.7
  TOP w0.089: v1(27.12,38.68) v2(26.58,38.5) 26.33,38.75 PR4485.1
  BOTTOM w0.089: v2(26.58,38.5) 27.27,38.5 PQ4418.3
PQ4418_5: length 3.2
  BOTTOM w0.127: v1(27.5,43.48) 27.9,43.07 PR4487.2 PC4445.1 28.36,41.34 PQ4418.5
PQ4418_6: length 3.1
  BOTTOM w0.127: v1(29.92,40.39) 29.71,40.59 PQ4418.6 29.01,41.61 PC4445.2 28.82,42.51 PR4486.1
PRD_CC1: length 3.7
  TOP w0.089: U7201.K9 10.13,37.17 10.13,38.01
  TOP w0.254: 10.13,38.01 9.54,38.6 v1(9.54,39.34) 9.54,40.07 R7211.2
PRD_CC2: length 4.2
  TOP w0.089: 9.18,37.86 9.24,37.86 9.63,37.48 9.63,37.17 U7201.K10
  TOP w0.254: 9.18,37.86 9.16,37.86 8.09,38.93 v1(8.09,39.36) 7.99,39.46 R7212.2
PRIM_PWRGD: length 194.7
  TOP w0.102: v2(22.87,16.48) 22.83,16.43 v1(22.21,16.43) 22.06,16.58 20.99,16.58 R4030.1 ; PR5408.1 170.65,1.97 v2(170.12,1.44)
  L4SGND w0.102: v2(125.52,1.34) 125.62,1.24 167.57,1.24 168.18,1.85 169.71,1.85 v2(170.12,1.44)
  L6 w0.102: v2(22.87,16.48) 23.94,16.48 24.59,15.83 25.48,15.83 26.02,15.29 27.5,15.29 27.9,15.69 27.9,15.91 29.02,17.04 32.47,17.04 32.7,17.26 35.95,17.26 v2(36.08,17.14) 36.08,16.73 36.64,16.17 42.94,16.17 43.83,15.28 43.83,13.33 44.82,12.34 49.51,12.34 50.42,13.25 54.09,13.25 54.65,12.69 66.75,12.69 67.68,11.75 75.09,11.75 75.54,12.21 81.52,12.21 82.06,12.74 84.98,12.74 85.66,12.06 86.38,12.06 86.58,11.85 89.63,11.85 90.29,12.51 90.65,12.51 91.1,12.06 94.06,12.06 95.87,10.25 96.25,10.25 96.3,10.21 105.61,10.21 106.08,10.21 109.53,13.66 113.93,13.66 114.39,13.66 114.4,13.66 115.89,13.66 115.9,13.66 116.06,13.66 118.71,13.66 119.66,13.66 119.66,13.66 120.59,13.66 120.89,13.66 122.72,15.49 122.95,15.49 122.99,15.52 123.09,15.52 123.76,16.2 126.07,16.2 v2(126.4,16.53)
  BOTTOM w0.102: v2(36.08,17.14) 36.08,17.54 36.95,18.41 36.95,19.65 33.44,23.15 33.44,25.43 33.81,25.8 33.82,25.8 34.81,26.79 34.81,27.2 35.74,28.14 36.28,28.14 36.94,28.79 U2401.30 ; v2(126.4,16.53) 126.4,16.13 125.48,15.2 125.48,10.79 124.65,9.97 124.65,2.2 v2(125.52,1.34)
PROCHOT: length 30.4
  L4SGND w0.089: v2(28.11,20.52) 27.1,20.52 26.14,21.47 26.14,22.64 27,23.49 27,25.08 26.46,25.62 26.46,31.89 23.35,35 v2(22.65,35)
  BOTTOM w0.089: R2418.1 23.28,34.89 R2417.1 23.36,34.12 v1(23.1,33.86) 22.46,33.86 Q2408.G 22.07,34.43 v2(22.65,35) ; U2401.83 30.54,14.74 31.08,15.29 31.08,16.65 28.11,19.62 v2(28.11,20.52)
PROCHOT#_CPU: length 157.5
  TOP w0.089: v2(24.91,37.15) 24.91,37.74 PR4489.2 PR4485.2 25.82,37.05 26.3,36.57 PR4476.2
  L4SGND w0.089: v2(73.09,93.06) 73.17,93.13 73.17,93.44 70.3,96.3 58.15,96.3 57.7,96.3 49.4,88 49.4,82.34 49.95,81.79 49.95,81.58 50.66,80.87 v2(51.07,80.87) 51.07,80.77 49.36,79.06 47.75,79.06 43.24,74.56 43.24,73.37 42.02,72.15 41.66,72.15 36.63,67.12 36.63,64.05 33.45,60.87 33.45,60.87 33.37,60.79 31.77,60.79 27.78,56.81 27.78,56.68 27.78,56.33 26.61,55.16 26.61,51.77 25.15,50.3 24.86,50.3 24.1,49.55 24.1,48.21 23.76,47.87 23.76,46.78 24.35,46.19 24.35,45.05 30.77,38.63 30.77,37.84 v2(32.02,36.59)
  L6 w0.089: v2(73.09,93.06) 73.22,93.19 77.2,93.19 79.16,91.23 79.16,86.51 81.22,84.45 86.63,84.45 86.81,84.63 v2(86.81,85.26)
  BOTTOM w0.089: PR4607.1 50.48,79.68 50.41,79.75 50.41,80.63 PR4603.2 50.63,80.65 50.81,80.83 50.99,80.83 51.02,80.87 v2(51.07,80.87) ; v2(32.02,36.59) 31.87,36.59 31.31,36.04 v1(30.7,36.04) 29.17,36.04 28.54,36.68 25.61,36.68 25.13,37.15 v2(24.91,37.15) 24.7,37.36 23.8,37.36 ED2403.1 23.28,37.22 R2418.2 23.16,36.39 Q2408.D ; v2(86.81,85.26) 89.45,87.9 89.45,91.01 90.81,92.37 93.01,92.37 93.73,93.1 94.83,93.1 95.04,93.3 95.04,93.79 95.23,93.99 99.28,93.99 R301.2 R302.1
PROCHOT#_CPU_R: length 8.9
  BOTTOM w0.089: R302.2 102.6,93.24 v1(103.67,92.17) 103.87,91.97 103.87,91.01 105.62,89.26 105.62,87.5 105.48,87.35 105.48,86.81 CPU1.Y4
PROJECT_ID0: length 5
  TOP w0.102: v2(134.81,74.49) 135.29,74.01 v1(136.58,74.01) 136.59,74.01 136.61,74.03 137.05,74.03 137.33,74.31 R2113.2 137.68,74.31 138.03,73.96 138.09,73.96 R2114.1
  BOTTOM w0.102: CPU1.CH23 135.14,74.22 134.86,74.49 v2(134.81,74.49)
PROJECT_ID1: length 14.1
  BOTTOM w0.102: CPU1.CK19 137.17,77.08 137.25,77.16 139.16,77.16 139.28,77.28 140.77,77.28 141.67,78.19 146.92,78.19 v1(147.28,78.56) 147.97,78.56 R2111.2 R2112.1
PROJECT_ID2: length 3.5
  TOP w0.102: v1(135.45,77.97) R2117.2 134.58,78.11 v2(134.15,78.54) 134.15,78.54 134.05,78.64 R2118.1
  BOTTOM w0.102: CPU1.CG17 134.15,78.45 v2(134.15,78.54)
PROJECT_ID3: length 13.8
  BOTTOM w0.102: R2116.1 148.88,77.79 v1(148.78,77.69) R2115.2 148.19,77.99 141.74,77.99 140.2,76.45 139.28,76.45 139.26,76.48 137.92,76.48 CPU1.CN20
PS175_CEC_EN: length 4.7
  TOP w0.102: U5701.E7 23.71,84.19 23.71,82.03 v1(23.43,81.76) 23.51,81.67 R5757.2 R5756.2
PS175_CSCL: length 9.6
  TOP w0.089: U5701.E6 23.37,85.31 23.01,84.95 23.01,84.93 v2(23.01,84.93) ; v1(17.26,80.33) 16.73,80.87 R5739.2 17.88,82.32 18.82,82.32 v2(18.96,82.26)
  L6 w0.089: v2(18.96,82.26) 19.24,82.54 19.55,82.54 20.19,83.19 21.49,83.19 22.71,84.41 22.7,84.61 22.7,84.61 22.7,84.61 v2(23.01,84.93)
PS175_CSDA: length 8.1
  TOP w0.089: 17.87,82.51 18.26,82.51 18.32,82.54 v2(18.5,82.72) ; 17.87,82.51 v1(17.87,82.64) ; 17.87,82.51 17.8,82.51 17.22,81.93 R5738.2 ; v2(22.19,84.9) 22.19,84.93 22.57,85.31 U5701.F6
  L6 w0.089: v2(22.19,84.9) 22.51,84.6 22.52,84.48 21.42,83.38 20.11,83.38 19.47,82.73 18.52,82.73 v2(18.5,82.72)
PS175_GPIO0: length 2
  TOP w0.102: v2(25.41,86.49) U5701.C4
  BOTTOM w0.102: R5735.2 25.52,86.6 v2(25.41,86.49) v1(24.97,86.05)
PS175_GPIO2: length 3.3
  TOP w0.102: v2(22.99,88.11) U5701.E3
  BOTTOM w0.102: v2(22.99,88.11) 22.99,89.41 v1(23.24,89.67) 23.79,89.12 R5754.2
PS175_PD#: length 34.6
  TOP w0.102: U5701.C3 24.98,87.7 24.58,88.11 24.58,88.09 v2(24.57,88.08) ; v2(28.12,91.86) 32.99,91.86 v1(33.34,91.51) 33.39,91.56 35.24,91.56 36.39,90.42 36.39,86.33 36.18,86.12 35.78,86.12 Q5705.3 35.74,86.89 35.64,86.99 34.35,86.99 33.87,86.51 33.87,85.46 R5746.2 35.32,83.98 36.22,83.08 36.84,83.08 37.12,83.36 U5703.2 37.12,84.22 37.33,84.42 37.58,84.42 37.77,84.23 U5703.1
  BOTTOM w0.102: v2(28.12,91.86) 27.66,91.86 26.54,92.98 26.19,92.98 25.45,92.24 24.06,92.24 23.56,91.74 23.56,90.04 24.69,88.9 v1(24.69,88.75) 24.69,88.22 24.57,88.1 v2(24.57,88.08)
PS175_RST#: length 8.9
  TOP w0.102: R5744.1 R5745.2 31.76,82.16 C5778.1 30.79,82.8 v1(30.79,83.23) 29.68,83.23 29.66,83.25 26.24,83.25 U5701.B8
PS_ID: length 12.5
  TOP w0.508: v1(30.29,32.48) 31.13,32.48 R4305.2
  TOP w0.635: v2(37.12,27.32) 37.12,27.47 36.49,28.11 35.4,28.11 35.14,28.37 35.14,28.39 34.2,29.33 D4302.3 34.2,31.29 33.57,31.92 32.47,31.92 32.12,32.28 R4304.2 R4305.2
  BOTTOM w0.203: U2401.36 38.5,26.79 37.96,27.32 v2(37.12,27.32)
PS_ID_R: length 11.8
  TOP w0.102: v2(40.2,91.66) 39.76,91.66 39.66,91.56 AFTP4304.1
  BOTTOM w0.102: R4317.1 46.06,96.23 EC4311.1 45.84,95.62 43.7,95.62 40.2,92.12 v2(40.2,91.66) 39.74,91.66 39.2,91.12 DCIN1.4
PS_ID_R1: length 97
  TOP w0.102: R4305.1 31.33,34.08 v2(30.85,34.56)
  L4SGND w0.102: v2(43.78,92.91) 40.75,92.91 36.62,88.77 36.62,74.85 35.95,74.19 35.95,64.33 33.17,61.55 33.16,61.55 33.09,61.47 31.99,61.47 30.94,61.47 21.86,52.39 21.86,48.89 20.82,47.85 20.82,45.41 20.99,45.23 20.99,44.49 23.89,41.6 23.94,41.6 26.02,39.52 26.02,34.89 27.27,33.65 27.27,31.48 27.71,31.03 28.78,31.03 30.85,33.1 v2(30.85,34.56)
  BOTTOM w0.102: R4306.2 51.32,98.77 v1(51.32,98.16) 51.32,97.15 49.82,95.65 49.82,95.63 Q4301.S 49.28,93.94 47.82,92.47 44.21,92.47 v2(43.78,92.91)
PS_ID_R2: length 8.2
  BOTTOM w0.635: R4309.1 R4306.1 v1(50.03,98.29) 50.23,98.09 Q4301.D 49.52,97.23 49.11,97.63 D4303.1 ; D4303.2 D4303.1 ; D4303.1 48.11,97.21 R4317.2
PSID_DISABLE#_R_C: length 3.6
  BOTTOM w0.635: v1(52.86,95.71) 52.86,95.28 R4303.2 52.11,95.09 Q4301.G 50.65,94.56 Q4302.C
PTP_DIS#: length 91.5
  TOP w0.102: v2(85.92,8.02) 87.06,9.16 AFTP6537.1
  L6 w0.102: v2(91.17,13.91) 91.17,13.28 90.82,12.92 90.12,12.92 89.46,12.26 86.75,12.26 86.55,12.46 85.87,12.46 85.15,13.18 81.62,13.18 81.12,12.67 75.43,12.67 74.97,12.21 67.8,12.21 66.92,13.09 54.82,13.09 54.1,13.81 50.41,13.81 49.34,12.74 44.99,12.74 44.29,13.45 44.29,15.4 43.11,16.58 39.08,16.58 38.11,17.54 35.73,17.54 35.65,17.47 32.58,17.47 32.4,17.29 28.99,17.29 27.97,16.27 v2(27.55,16.27)
  BOTTOM w0.102: v2(27.55,16.27) 27.74,16.09 U2401.90 ; v2(91.17,13.91) 91.53,13.91 92.16,13.28 92.16,13.2 93.5,11.87 93.5,10.43 92.98,9.91 91.39,9.91 90.13,8.66 90.13,7.82 89.75,7.43 86.5,7.43 v2(85.92,8.02) 85.43,8.5 84.52,8.5 84.2,8.82 TPAD1.3
PU4348_G: length 40.1
  BOTTOM w0.254: R4370.2 37.45,75.65 Q4348.G 38.52,73.54 38.52,71.65 37.38,70.5 37.38,62.11 34.62,59.35 30.34,59.35 26.73,55.75 24.78,55.75 24.5,55.47 24.17,55.47 v1(24.12,55.42) 21.77,55.42 20.78,54.43 20.78,53.69 20.64,53.54 20.64,51.91 R4369.1
PULSAR_38P4M_REFCLK: length 55.9
  TOP w0.089: v2(159.14,56.84) 160.36,58.05 v1(160.36,59.1) 160.36,60.9 159.91,61.35 159.91,66.97 160.62,67.69 160.62,71.5 161.91,72.79 161.91,76.71 161.06,77.56 161.06,81.13 159.53,82.65 159.53,84.34 157.95,85.93 154.21,85.93 R6118.1 R1804.2
  BOTTOM w0.089: v2(159.14,56.84) 159.25,56.74 160.19,56.74 161.1,57.65 163.13,57.65 163.65,57.13 163.7,57.13 163.84,56.99 165.31,56.99 167.81,54.5 167.81,49.29 166.31,47.8 WLAN1.64
PURE_HW_SHUTDOWN#: length 96.7
  TOP w0.102: v2(93.84,7.94) 93.84,7.99 94.25,8.4 94.81,8.4 96.1,9.7 v1(96.1,10.15) 96.1,11.55 95.49,12.16 R4014.2
  L4SGND w0.102: v2(21.3,11.48) 22.2,10.58 28.71,10.58 34.19,5.1 54.3,5.1 55.57,6.37 64.29,6.37 67.47,3.19 92.47,3.19 v2(92.93,2.74)
  BOTTOM w0.102: Q2602.D 21.58,10.76 21.3,11.04 v2(21.3,11.48) ; Q2602.D 21.58,8.68 C2610.1 ; Q2602.D 22.8,10.31 23.23,9.88 24.16,9.88 24.23,9.8 24.98,9.8 R2615.1 ; v2(92.93,2.74) 92.93,3.09 93.79,3.96 93.79,7.89 v2(93.84,7.94) 93.84,8.99 D4001.K
PWR_1D0V_BT: length 2.9
  BOTTOM w0.254: v1(176.82,74.49) PC5204.1 175.35,74.29 175.05,73.98 174.97,73.98 174.96,73.98 PU5201.20
PWR_1D0V_FB: length 4.9
  BOTTOM w0.254: PC5212.2 173.75,69.49 PR5202.2 PR5204.1 171.27,69.49 v1(171.24,69.52) 171.42,69.7 171.42,70.93 171.37,70.97 PU5201.5
PWR_1D0V_FB_A: length 23.1
  BOTTOM w0.254: PR5202.1 173.75,70.35 PC5212.1 174.54,69.61 174.54,69.31 175.45,68.39 177.92,68.39 178.32,68.79 v1(178.32,74.44) 178.32,74.79 178.36,74.82 178.36,74.98 179.41,76.04 PG5223.1
PWR_1D0V_PFM: length 5.4
  BOTTOM w0.254: 175.22,69.3 175.62,68.9 PR5203.1 ; 175.22,69.3 v1(175.22,69.3) ; 175.22,69.3 175.22,69.39 175.01,69.6 175.01,69.88 173.87,71.01 172.81,71.01 172.37,71.45 PU5201.3
PWR_1D0V_PG: length 3.7
  BOTTOM w0.102: PR5209.2 PR5208.1 175.88,71.7 174.84,71.7 v1(174.77,71.62) 174.58,71.81 PU5201.1
PWR_1D0V_PH:
  vias: v1(175.05,75.15)
PWR_1D0V_SS: length 2.2
  BOTTOM w0.254: PC5213.1 175.96,72.92 v1(175.2,72.92) 175.15,72.92 174.71,72.48 PU5201.22
PWR_1D0V_TON: length 2.5
  BOTTOM w0.254: PR5201.2 170.57,70 170.98,70.4 v1(170.98,70.77) 170.87,70.88 PU5201.6
PWR_1D8V_POK: length 5.7
  TOP w0.254: PR5402.2 171.39,3.39 v1(170.85,3.93) 170.57,3.65 170.57,3.32 169.79,2.53 PR5408.2 169.79,2.25 168.95,1.42 v2(168.95,1.42)
  BOTTOM w0.254: v2(168.95,1.42) 168.95,1.42 169.5,1.96 PU5401.7
PWR_2D5V:
  vias: v1(120.94,23.97)
PWR_2D5V_FB: length 4.4
  BOTTOM w0.254: PU5403.2 117.59,26.18 118.2,26.6 118.2,26.62 118.65,27.07 118.7,27.07 118.73,27.09 PR5420.1 118.71,27.07 PR5419.2 119.34,26.28 PC5411.2 119.82,26.41 v1(120.35,25.88)
PWR_3D3V:
  vias: v1(78.14,18.99)
PWR_3D3V_BOOT: length 2.6
  BOTTOM w0.254: PU4501.1 90.33,22.86 89.96,23.23 v1(89.96,23.26) PR4501.1
PWR_3D3V_BOOT_A: length 3
  BOTTOM w0.254: PC4506.1 88.94,25.24 89.35,25.65 PR4501.2 v1(90.54,26.67)
PWR_3D3V_EN: length 3.9
  BOTTOM w0.254: PR4508.1 92.75,17.59 v1(92.75,18.26) 92.75,18.67 PU4501.11 ; PR4508.1 PR4509.2 ; PR4508.1 92.47,17.37 PC4508.1
PWR_3D3V_FB: length 3.2
  TOP w0.254: PC4533.1 91.1,17.49 91.1,17.5 91.43,17.83 v2(91.43,18.05) 91.59,18.46 v1(91.96,18.61)
  BOTTOM w0.254: v2(91.43,18.05) 91.23,18.26 PU4501.13
PWR_3D3V_FB2: length 1.9
  TOP w0.254: PC4533.2 90.82,16.35 PR4506.2 89.73,16.35 v1(89.19,16.88)
PWR_3D3V_LDO: length 1.1
  BOTTOM w0.254: v1(89.17,14.78) 89.17,15.56 PG4519.1
PWR_3D3V_PH: length 9.7
  TOP w0.254: v2(88.89,21.74) v1(88.28,21.7) ; v2(93.56,21.71) v1(93.98,22.08)
  L6 w0.508: v2(88.89,21.74) 90.03,22.88 93.18,22.88 93.56,22.5 v2(93.56,21.71)
  BOTTOM w0.254: 88.94,22.37 PC4506.2 ; PU4501.6 92.89,21.49 93.11,21.71 v2(93.56,21.71)
PWR_3D3V_VOUT: length 20.7
  TOP w0.254: v1(90.08,18.56) v2(90.08,17.93) PR4506.1
  L4SGND w0.254: v2(75.6,15.39) 75.6,15.59 75.91,15.89 76.98,15.89 77.43,15.44 86.2,15.44 86.6,15.84 89.47,15.84 90.08,16.45 v2(90.08,17.93)
  BOTTOM w0.254: PU4501.14 90.78,18.62 v2(90.08,17.93) ; v2(75.6,15.39) 75.35,15.64 PG4530.1
PWR_3V_PG: length 7.3
  TOP w0.254: v1(96.05,17.89) 95.54,17.93 95.45,17.95 PG4531.2 94.35,17.98 v2(93.51,18.81) 93.05,19.27 PR4505.2
  BOTTOM w0.254: PU4501.9 93.07,20.14 93.51,19.7 v2(93.51,18.81) 92.63,19.69 PU4501.10
PWR_5V:
  vias: v1(65.67,19.35)
PWR_5V_BOOT: length 2.7
  BOTTOM w0.254: PU4502.1 54.03,16.39 54.14,16.27 v1(54.14,15.54) 54.14,15.18 54.12,15.16 PR4502.1
PWR_5V_BOOT_A: length 2.6
  BOTTOM w0.508: PR4502.2 55.16,13.15 v1(55.39,13.38) 55.39,14.32 PC4521.1
PWR_5V_EN: length 4
  BOTTOM w0.254: PU4502.11 52.23,20.22 51.73,20.72 v1(51.73,21) PR4512.1 51.7,21.91 PC4530.1 50.23,21.91 PR4511.2
PWR_5V_EN1_R: length 56.4
  TOP w0.254: v2(51.09,21.1) 50.79,21.4 PR4504.1 ; PR4530.1 PR4503.2 92.5,12.41 PR4515.2 92.75,11.58 93.38,10.94 v1(93.38,10.64) 93.38,9.24 92.55,8.4 v2(92.55,7.94)
  L4SGND w0.254: v2(51.09,21.1) 51.09,19.51 51.96,18.64 51.96,17.7 56.87,12.79 58.05,12.79 59.01,11.83 71.07,11.83 71.07,11.83 72,11.83 72,11.83 72.05,11.83 76.48,7.4 92,7.4 v2(92.55,7.94)
PWR_5V_FB: length 3
  BOTTOM w0.254: PU4502.13 v1(53.13,20.87) 53.13,21.74 53.25,21.86 PC4526.1 53.23,21.94 PR4551.1
PWR_5V_FB_A: length 1.6
  BOTTOM w0.254: PR4507.1 53.99,22.83 PC4526.2 v1(53.35,23.64)
PWR_5V_LDO: length 7.8
  BOTTOM w0.254: 54.4,21.1 54.03,20.73 PU4502.15
  BOTTOM w0.508: 54.4,21.1 54.88,21.58 54.88,23.07 55.32,23.51 55.77,23.51 PC4520.1 55.28,24.66 v1(55.03,24.66) 55,24.68 PG4528.1
PWR_5V_PG: length 5.9
  BOTTOM w0.254: PU4502.9 50.59,18.88 PR4510.1 ; PR4510.1 49.29,19.4 PG4529.2 49.24,20.06 v1(48.77,20.53) ; PR4510.1 51.14,19.4 51.21,19.33 PU4502.10
PWR_5V_PH: length 7.1
  TOP w0.508: v2(55.16,16.99) 54.85,17.29 v1(53.23,17.29) v2(50.84,17.29)
  BOTTOM w0.254: v2(50.84,17.29) 51.08,17.53 PU4502.6
  BOTTOM w0.508: PC4521.2 v2(55.16,16.99)
PWR_5V_VOUT: length 20.1
  TOP w0.254: v2(53.76,21.23) v1(54.37,21.23)
  L4SGND w0.254: v2(68.92,23.01) 68.31,22.4 64.15,22.4 63.79,22.75 55.28,22.75 v2(53.76,21.23)
  BOTTOM w0.254: v2(68.92,23.01) 69,22.93 PG4527.1 ; PU4502.14 53.58,21.04 v2(53.76,21.23) 53.76,21.35 54.01,21.61 PR4507.2
PWR_CHG_ACIN: length 4.5
  TOP w0.203: PU4401.19 25.75,47.48 25.68,47.41 25.16,47.41 v2(25.07,47.33)
  BOTTOM w0.254: v1(26.46,49.14) PC4420.2 26.02,48.25 PR4406.1 25.83,47.33 v2(25.07,47.33) 25.03,47.37 25.03,47.41 24.8,47.64 PR4404.2
PWR_CHG_ACOK: length 9.8
  TOP w0.203: PU4401.24 25.5,45.48 24.36,44.34 PR4426.1
  TOP w0.254: PR4463.2 PR4429.2 22.62,43.5 PG4408.1 ; PR4463.2 24.19,43.66 24.65,43.66 v2(24.85,43.86) ; PR4463.2 24.04,44.29 PR4426.1
  BOTTOM w0.254: PR4484.2 25.87,40.79 25.87,42.84 v1(25.77,42.94) v2(24.85,43.86)
PWR_CHG_AIN: length 3.3
  BOTTOM w0.254: v1(24.55,46.73) 24.3,46.98 23.86,46.98 23.61,47.24 PR4404.1 23.61,47.68 PD4408.3
PWR_CHG_AMON: length 6.3
  TOP w0.203: PU4401.29 28.18,44.39 28.87,43.7 28.87,43.04 v1(29.25,42.66)
  TOP w0.254: v1(29.25,42.66) 29,42.41 29,40.33 PC4432.1 28.74,39.36 PR4412.1
PWR_CHG_ASGATE: length 6
  TOP w0.203: 27.85,49.78 27.78,49.71 PU4401.13
  TOP w0.254: 27.85,49.78 27.89,49.82 27.89,50.39 28.53,51.03 28.53,51.03 28.79,51.29 TP4401.1
PWR_CHG_BATGONE: length 3.7
  TOP w0.254: PU4401.25 25.89,44.92 25.29,44.32 25.29,44.28 v1(25.25,44.28) 25.36,44.17 25.36,43.66 25.59,43.43 PC4430.1 24.83,43.15 PR4409.1
PWR_CHG_BATGONE_L: length 2
  TOP w0.102: PR4409.2 24.8,41.83 24.68,41.7 v1(24.68,41.34) 25.11,40.91 PR4494.1
PWR_CHG_BGATE: length 103
  TOP w0.254: v2(101.5,13.46) 101.5,19.69 102.27,20.47 v2(102.27,24.02) ; PU4401.32 30.14,44.92 v2(30.81,44.25)
  L3SGND w0.254: v2(35.28,38.44) 31.08,42.64 31.08,44.14 30.96,44.25 v2(30.81,44.25) ; v2(102.27,24.02) 101.75,24.02 100.73,25.04 87.79,25.04 87.3,25.52 76.38,25.52 75.8,26.1 46.89,26.1 45.48,27.52 45.48,35.97 44.51,36.93 44.51,38.13 v2(44.44,38.21)
  L6 w0.254: v2(44.44,38.21) 44.44,38.22 44.29,38.37 42.66,38.37 41.72,37.43 38.78,37.43 38.48,37.74 38.06,37.74 37.75,37.43 36.29,37.43 v2(35.28,38.44)
  BOTTOM w0.254: v1(28.82,44.9) PC4429.1 30.24,44.9 30.81,44.33 v2(30.81,44.25) ; PU4412.4 v2(101.5,13.46)
PWR_CHG_BOOT1: length 3.8
  TOP w0.203: v1(28.97,50.74) 28.74,50.74 28.25,50.25 28.25,49.68 28.18,49.61 PU4401.12
  TOP w0.508: v1(28.97,50.74) 29.02,50.74 29.68,51.4 PR4402.2
PWR_CHG_BOOT2: length 3.1
  TOP w0.203: PU4401.4 30.57,46.68 30.67,46.58 v1(31.56,46.58)
  TOP w0.508: v1(31.56,46.58) 32.42,47.44 PR4408.2
PWR_CHG_BT1_R: length 2.6
  TOP w0.635: v1(32.27,53.13) PC4436.2 PR4402.1
PWR_CHG_BT2_R: length 2.4
  TOP w0.508: PR4408.1 PC4423.1
  TOP w0.635: PC4423.1 v1(35.07,48.94)
PWR_CHG_COMP: length 3.5
  TOP w0.203: PU4401.28 27.78,44.19 v1(28.02,43.95)
  TOP w0.254: v1(28.02,43.95) 28.39,43.59 28.39,43.02 PR4411.1 27.65,42.28 PC4433.1
PWR_CHG_COMP_R: length 2
  TOP w0.254: PR4411.2 28.54,41.95 v1(28.54,41.14) 28.54,40.96 PC4431.1
PWR_CHG_CSIN: length 5.4
  TOP w0.203: 27.38,49.39 PU4401.14
  TOP w0.254: 27.38,49.39 27.24,49.52 PC4415.1 26.84,50.84 v1(26.84,51.58) 26.84,52.39 26.96,52.52 ; 26.96,52.52 27.8,51.68 PC4417.2 ; 26.96,52.52 PR4423.2
PWR_CHG_CSIN_R: length 16.5
  TOP w0.254: v2(27.18,54.39) 27.18,53.65 PR4423.1
  BOTTOM w0.254: v2(27.18,54.39) 27.26,54.48 27.38,54.48 30.12,57.22 v1(31.74,57.22) 35.01,57.22 37.82,60.02 39.8,60.02 PG4402.2
PWR_CHG_CSIP: length 7.4
  TOP w0.203: 26.98,49.25 PU4401.15
  TOP w0.254: 26.98,49.25 25.92,50.3 PC4415.2 26.18,50.69 PR4422.2 25.67,52.04 PC4416.2 24.4,52.86 24.4,53.05 v1(24.02,53.56)
PWR_CHG_CSIP_R: length 17.9
  TOP w0.254: PR4422.1 25.94,53.65 v2(25.94,54.33)
  BOTTOM w0.254: PG4401.2 39.8,60.4 37.66,60.4 34.86,57.6 33.19,57.6 v1(33.11,57.68) 29.74,57.68 26.4,54.33 v2(25.94,54.33)
PWR_CHG_CSON: length 5.1
  TOP w0.203: 30.72,45.03 30.57,45.03 30.12,45.48 PU4401.1
  TOP w0.254: PC4426.2 30.85,42.89 31.54,42.89 PR4425.2 31.54,43.81 PC4425.2 31.66,43.99 31.66,44.72 31.43,44.95 v1(30.95,44.95) 30.8,44.95 30.72,45.03
PWR_CHG_CSON_R: length 98.9
  TOP w0.254: v2(32.23,38.98) 32.47,39.23 32.47,40.2 31.71,40.96 31.71,41.88 PR4425.1
  L6 w0.254: v2(106.06,20.9) 106.06,21.74 105.96,21.84 105.96,22.27 104.84,23.39 104.84,25.42 101.87,28.39 101.56,28.39 46.88,28.39 46.44,28.82 46.44,32.28 45,33.72 44.69,33.72 39.85,33.72 38.81,34.77 38.5,34.77 33.12,34.77 30.54,37.34 30.54,38.54 31.19,39.18 32.02,39.18 v2(32.23,38.98)
  BOTTOM w0.254: v2(106.06,20.9) 106.06,20.49 v1(105.77,20.2) 105.59,20.2 103.29,17.89 103.29,17.8 102.58,17.09 PG4406.2
PWR_CHG_CSOP: length 8.7
  TOP w0.203: 30.76,45.41 30.74,45.42 30.27,45.88 PU4401.2
  TOP w0.254: PR4424.2 33.39,42.92 PC4424.2 34.18,44.51 v1(33.95,44.73) 33.87,44.73 33.1,43.96 PC4425.1 32.6,44.37 32.6,44.75 31.94,45.41 30.76,45.41
PWR_CHG_CSOP_R: length 98.9
  TOP w0.254: v2(33.06,38.98) 32.86,39.18 32.86,40.36 32.09,41.12 32.09,41.85 PR4424.1
  L6 w0.254: v2(33.06,38.98) 32.47,39.57 31.03,39.57 30.16,38.7 30.16,38.39 30.16,37.18 32.96,34.38 38.65,34.38 39.7,33.34 44.84,33.34 46.06,32.12 46.06,28.66 46.72,28.01 101.72,28.01 104.46,25.27 104.46,23.23 105.58,22.12 105.58,21.13 105.55,21.11 105.55,21.02 v2(105.42,20.9)
  BOTTOM w0.254: v2(105.42,20.9) 105.2,20.9 v1(104.55,20.25) 104.55,19.95 102.78,18.18 PG4405.2
PWR_CHG_DCIN: length 4.8
  TOP w0.203: 25.33,48.74 25.78,48.28 PU4401.17
  TOP w0.254: PR4403.1 23.48,50.95 PC4419.1 23.92,49.95 v1(24.73,49.14) 25.13,48.74 25.33,48.74
PWR_CHG_DCIN_R: length 27.1
  TOP w0.254: PR4403.2 20.92,52.01 21.55,52.65 v1(21.65,52.65) v2(23.18,52.65)
  L6 w0.254: v2(36.13,40.05) 35.65,40.53 33.81,40.53 30.3,44.04 30.3,44.39 29.84,44.85 28.28,44.85 25.82,47.31 25.82,50.06 v2(25.06,50.82)
  BOTTOM w0.254: v2(25.06,50.82) 24.55,50.31 22.9,50.31 22.39,50.82 PD4401.3 22.99,52.65 v2(23.18,52.65) ; PD4407.K 36.4,40.32 v2(36.13,40.05)
PWR_CHG_HG1_R:
  vias: v1(42.38,51.28)
PWR_CHG_HG2_R:
  vias: v1(40.9,42.54)
PWR_CHG_LGATE1: length 9
  TOP w0.203: v3(30.76,49.55) 30.75,49.55 30.75,49.5 30.36,49.5 29.7,48.84 PU4401.9
  TOP w0.508: PU4404.4 v3(35.62,51.83)
  L6 w0.635: v3(30.76,49.55) 31.03,49.55 33.31,51.83 v3(35.62,51.83)
  BOTTOM w0.508: v3(30.76,49.55) v1(31.43,49.55)
PWR_CHG_LGATE2: length 12.2
  TOP w0.203: PU4401.7 30.35,47.88 30.77,48.3 v3(30.77,48.38)
  TOP w0.406: PU4406.4 36.38,43.72 36.23,43.58 v3(36.23,43.57)
  L6 w0.635: v3(36.23,43.57) 33.45,43.57 31.92,45.1 31.58,45.1 29.99,46.69 29.99,47.63 30.74,48.38 v3(30.77,48.38)
  BOTTOM w0.508: v3(30.77,48.38) v1(30.04,48.56)
PWR_CHG_OTGEN: length 5.1
  TOP w0.203: 24.78,46.78 25.27,46.78 25.56,47.07 25.8,47.07 25.81,47.08 PU4401.20
  TOP w0.254: PR4417.2 22.83,47.49 v1(22.85,47.47) 23.17,47.8 24.25,47.8 24.5,47.54 24.5,47.06 24.78,46.78
PWR_CHG_OTGPG: length 1.3
  TOP w0.203: 26.98,44.46 PU4401.26
  TOP w0.254: TP8304.1 26.98,44.46
PWR_CHG_PHASE1: length 16.4
  TOP w0.203: 29.81,49.9 29.3,49.4 29.18,49.4 28.98,49.19 PU4401.10
  TOP w0.508: PC4436.1 31.08,51.22 v1(30.63,50.78) v3(29.81,49.95) 29.81,49.9
  L6 w0.635: v3(29.81,49.95) 29.81,50.11 33.26,53.56 37.78,53.56 39.41,51.94 v3(39.41,51.33)
  vias: v3(37.5,51.33) v3(37.5,50.31) v3(38.52,51.33) v3(38.52,50.31) v3(39.41,50.34) v3(40.3,51.33) v3(40.25,50.34) v3(41.24,51.33) v3(41.24,50.31)
PWR_CHG_PHASE2: length 10.3
  TOP w0.203: v3(31.75,48.16) 31.36,47.77 30.71,47.77 30.42,47.48 PU4401.6
  TOP w0.635: PC4423.2 32.3,48.71 v3(31.75,48.16)
  L6 w0.635: v3(37.61,48.28) 37.06,48.82 32.41,48.82 v3(31.75,48.16)
  BOTTOM w0.635: v3(31.75,48.16) v1(32.45,48.16)
  vias: v3(38.44,48.38) v3(38.44,47.49) v3(39.31,48.35) v3(39.31,47.47) v3(40.15,48.33) v3(40.14,47.41) v3(41.01,48.3) v3(41.01,47.39)
PWR_CHG_PROCHOT#: length 12
  TOP w0.089: PQ4416.2 23.41,40.56 23.21,40.75 23.21,40.76 23.2,40.77 23.2,40.8 22.93,41.06 21.88,41.06 21.42,41.53 21.42,42.42 21.22,42.61 21.22,44.19 PR4435.2 21.2,44.42 21.61,44.83 21.84,44.83 v1(21.91,44.9) 22.6,44.9 22.73,45.03 24.66,45.03 25.52,45.88 PU4401.23
PWR_CHG_PROCHOT#_R: length 4.1
  TOP w0.089: v1(22.65,36.41) 22.68,36.41 22.79,36.52 23.41,36.52 PR4472.2 ; PQ4416.5 23.41,36.77 PR4472.2 ; PR4472.2 23.69,36.8 23.69,36.9 24.05,37.25 24.06,37.25 PQ4416.6
PWR_CHG_PROG: length 3
  TOP w0.203: PU4401.27 27.38,44.3
  TOP w0.254: 27.38,44.3 27.32,44.24 v1(27.32,42.89) 26.51,42.89 PR4410.2
PWR_CHG_SCL: length 2.3
  TOP w0.089: PR4491.1 24.3,45.71 24.69,46.11 25.06,46.11 ; 25.06,46.11 25.29,46.11 25.46,46.28 PU4401.22 ; 25.06,46.11 v1(25.06,45.94)
PWR_CHG_SDA: length 3
  TOP w0.089: v1(24.07,47.36) PR4490.1 24.47,46.47 24.65,46.3 25.21,46.3 25.59,46.68 PU4401.21
PWR_CHG_SNB: length 2.5
  TOP w0.508: PR4416.2 36.11,57.17 v1(35.65,57.17) 35.55,57.17 35.04,56.66 PC4435.1
PWR_CHG_UGATE1: length 20.3
  TOP w0.203: PU4401.11 28.58,49.75 v3(28.83,50.01)
  TOP w0.635: PR4414.1 v3(43.85,55.05)
  L6 w0.635: v3(43.85,55.05) 43.26,54.45 32.83,54.45 28.83,50.45 v3(28.83,50.01)
  BOTTOM w0.508: v3(28.83,50.01) v1(28.13,50.01)
PWR_CHG_UGATE2: length 14.4
  TOP w0.203: PU4401.5 30.97,47.08 31.05,47.16 v3(31.06,47.16)
  TOP w0.635: PR4420.2 37.17,42.36 v3(37.1,42.28)
  L6 w0.635: v3(31.06,47.16) 32.36,47.16 32.88,47.68 36.18,47.68 37.63,46.23 37.63,42.82 v3(37.1,42.28)
  BOTTOM w0.635: v3(31.06,47.16) v1(31.06,46.5)
PWR_CHG_VBAT1: length 4.8
  TOP w0.203: v2(29.79,44.14) 29.54,44.39 29.18,44.39 28.98,44.59 PU4401.31
  BOTTOM w0.508: v2(29.79,44.14) 29.86,44.14 PC4440.2 30.93,43.12 PR4478.1 32.81,43.12 v1(32.83,43.1)
PWR_CHG_VBATIN:
  vias: v1(99.66,14.93)
PWR_CHG_VDDP: length 4.7
  TOP w0.203: PU4401.8 29.94,48.46 30.44,48.96 31.05,48.96 31.54,49.45
  TOP w0.508: PR4405.1 32.73,50.08 PC4421.1 32.07,49.98 v1(31.55,49.46) 31.54,49.45
PWR_DCBATOUT_1D0V:
  vias: v1(169.94,73.91) v2(169.46,72.88) v2(171.24,73.09) v2(172.12,73.09) v2(173.01,73.09)
PWR_DCBATOUT_3D3V:
  vias: v1(95.42,21.61)
PWR_DCBATOUT_5V:
  vias: v1(47.94,16.81) v1(48.68,20.74) v3(48.17,15) v3(49.19,16.63) v3(49.19,15.72) v3(50.05,16.45)
PWR_DCBATOUT_VCCGTA:
  vias: v1(61,92.6) v2(62.02,91.71) v2(62.99,89.71) v2(62.99,88.95) v2(62.99,79.3) v2(62.99,78.54) v3(61.08,91.38) v3(61.79,90.92) v3(62.09,83.23) v3(62.09,82.36) v3(62.17,93.34) v3(62.14,92.5) v3(62.15,81.5)
PWR_DCBATOUT_VCCSA: length 1.2
  TOP w0.508: v2(167.04,101.47) 167.58,102 AFTP5001.1
PWR_DCBATOUT_VCORE:
  vias: v1(63.56,73.55) v2(63.12,68.76) v2(63.12,68) v3(63.04,72.66) v3(63.04,71.77) v3(63.04,70.88)
PWR_DCBATOUT_VDDQ: length 10.8
  L4SGND w0.305: v2(58.33,57.55) 52.62,57.55 49.72,60.44 v2(49.44,60.44)
  BOTTOM w0.305: PR5103.1 49.47,60.42 v2(49.44,60.44)
  vias: v1(53.43,53.67) v1(57.95,51.71)
PWR_VCCGT_BOOTA: length 2.6
  BOTTOM w0.305: PU4801.5 60.88,88.79
  BOTTOM w0.508: 60.72,88.97 v1(60.73,88.98) ; 60.72,88.97 60.11,89.58 PR4804.2 ; 60.72,88.97 60.72,88.94 60.88,88.79
PWR_VCCGT_BOOTA_RC: length 2.5
  BOTTOM w0.508: PR4804.1 PC4808.1 58.2,90.86 57.16,90.45 v1(57.11,90.47)
PWR_VCCGT_BOOTB: length 2.1
  BOTTOM w0.305: PR4810.2 59.63,78.37 v1(60.72,78.37) PU4802.5
PWR_VCCGT_BOOTB_RC: length 1.3
  BOTTOM w0.508: PC4811.1 PR4810.1
PWR_VCCGT_BOOTRA: length 2.7
  BOTTOM w0.305: PU4801.7 61.34,89.79 60.62,90.51
  BOTTOM w0.508: PC4808.2 60.39,90.85 v1(60.62,90.62) 60.62,90.51
PWR_VCCGT_BOOTRB: length 2.2
  BOTTOM w0.305: PC4811.2 60.64,79.65 60.66,79.66 v1(60.69,79.66) 61.04,79.66 61.32,79.37 PU4802.7
PWR_VCCGT_COMP: length 6.7
  TOP w0.254: v2(52.21,74.11) 52.79,74.69 PC4610.2 53.43,74.19 v1(53.81,73.81)
  BOTTOM w0.203: 51.74,73.82 51.44,73.52 PU4601.4
  BOTTOM w0.254: PR4626.2 53.17,75.88 52.64,75.35 52.64,74.81 52.6,74.81 52.21,74.41 v2(52.21,74.11) 52.03,74.11 51.74,73.82
PWR_VCCGT_COMP1: length 3.7
  BOTTOM w0.254: PC4651.1 56.45,76.45 PC4612.1 56.12,75.89 v1(55.41,76.6) 55.28,76.47 54.89,76.47 54.3,75.88 PR4626.1
PWR_VCCGT_FB: length 4.4
  BOTTOM w0.203: 52.46,73.54 52.07,73.54 v1(51.96,73.42) 51.96,73.4 51.67,73.12 PU4601.5
  BOTTOM w0.254: PR4630.2 53.3,74.55 53.05,74.3 PR4633.2 PR4636.2 52.46,73.54
PWR_VCCGT_FB1: length 2.5
  BOTTOM w0.254: PC4614.1 56.17,75.4 v1(55.63,75.4) 55.33,75.4 55.04,75.11 PR4630.1
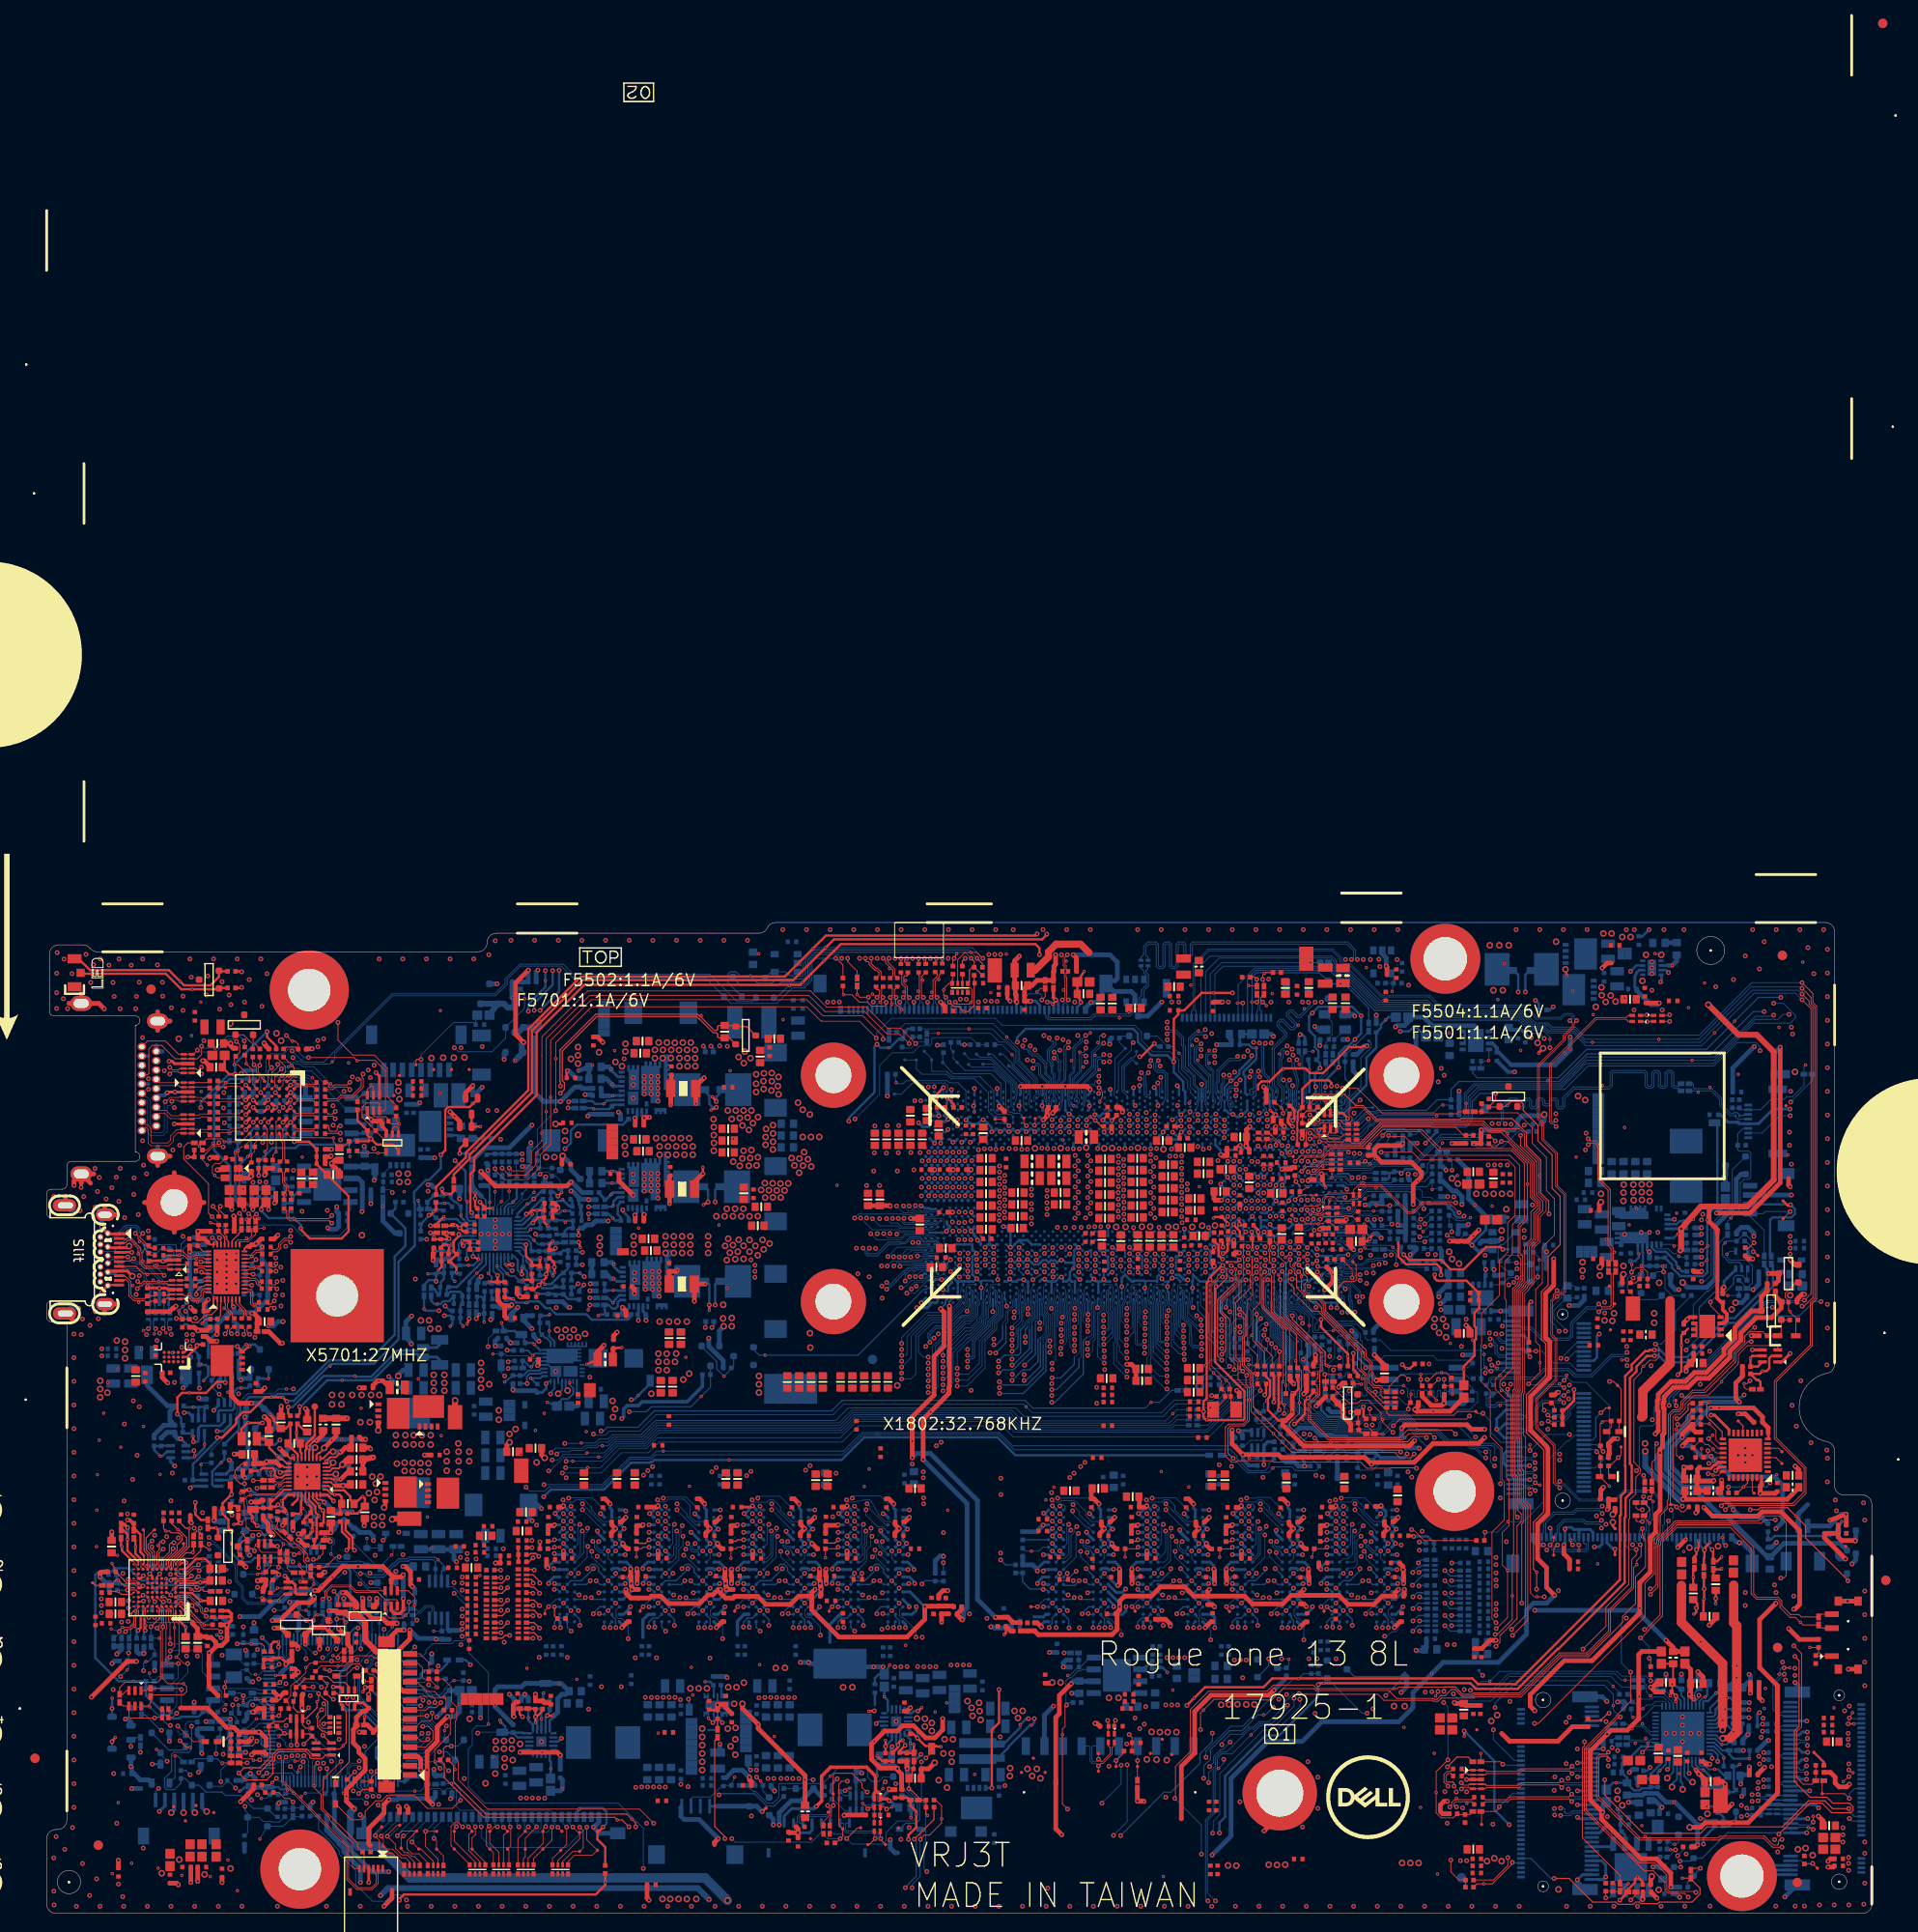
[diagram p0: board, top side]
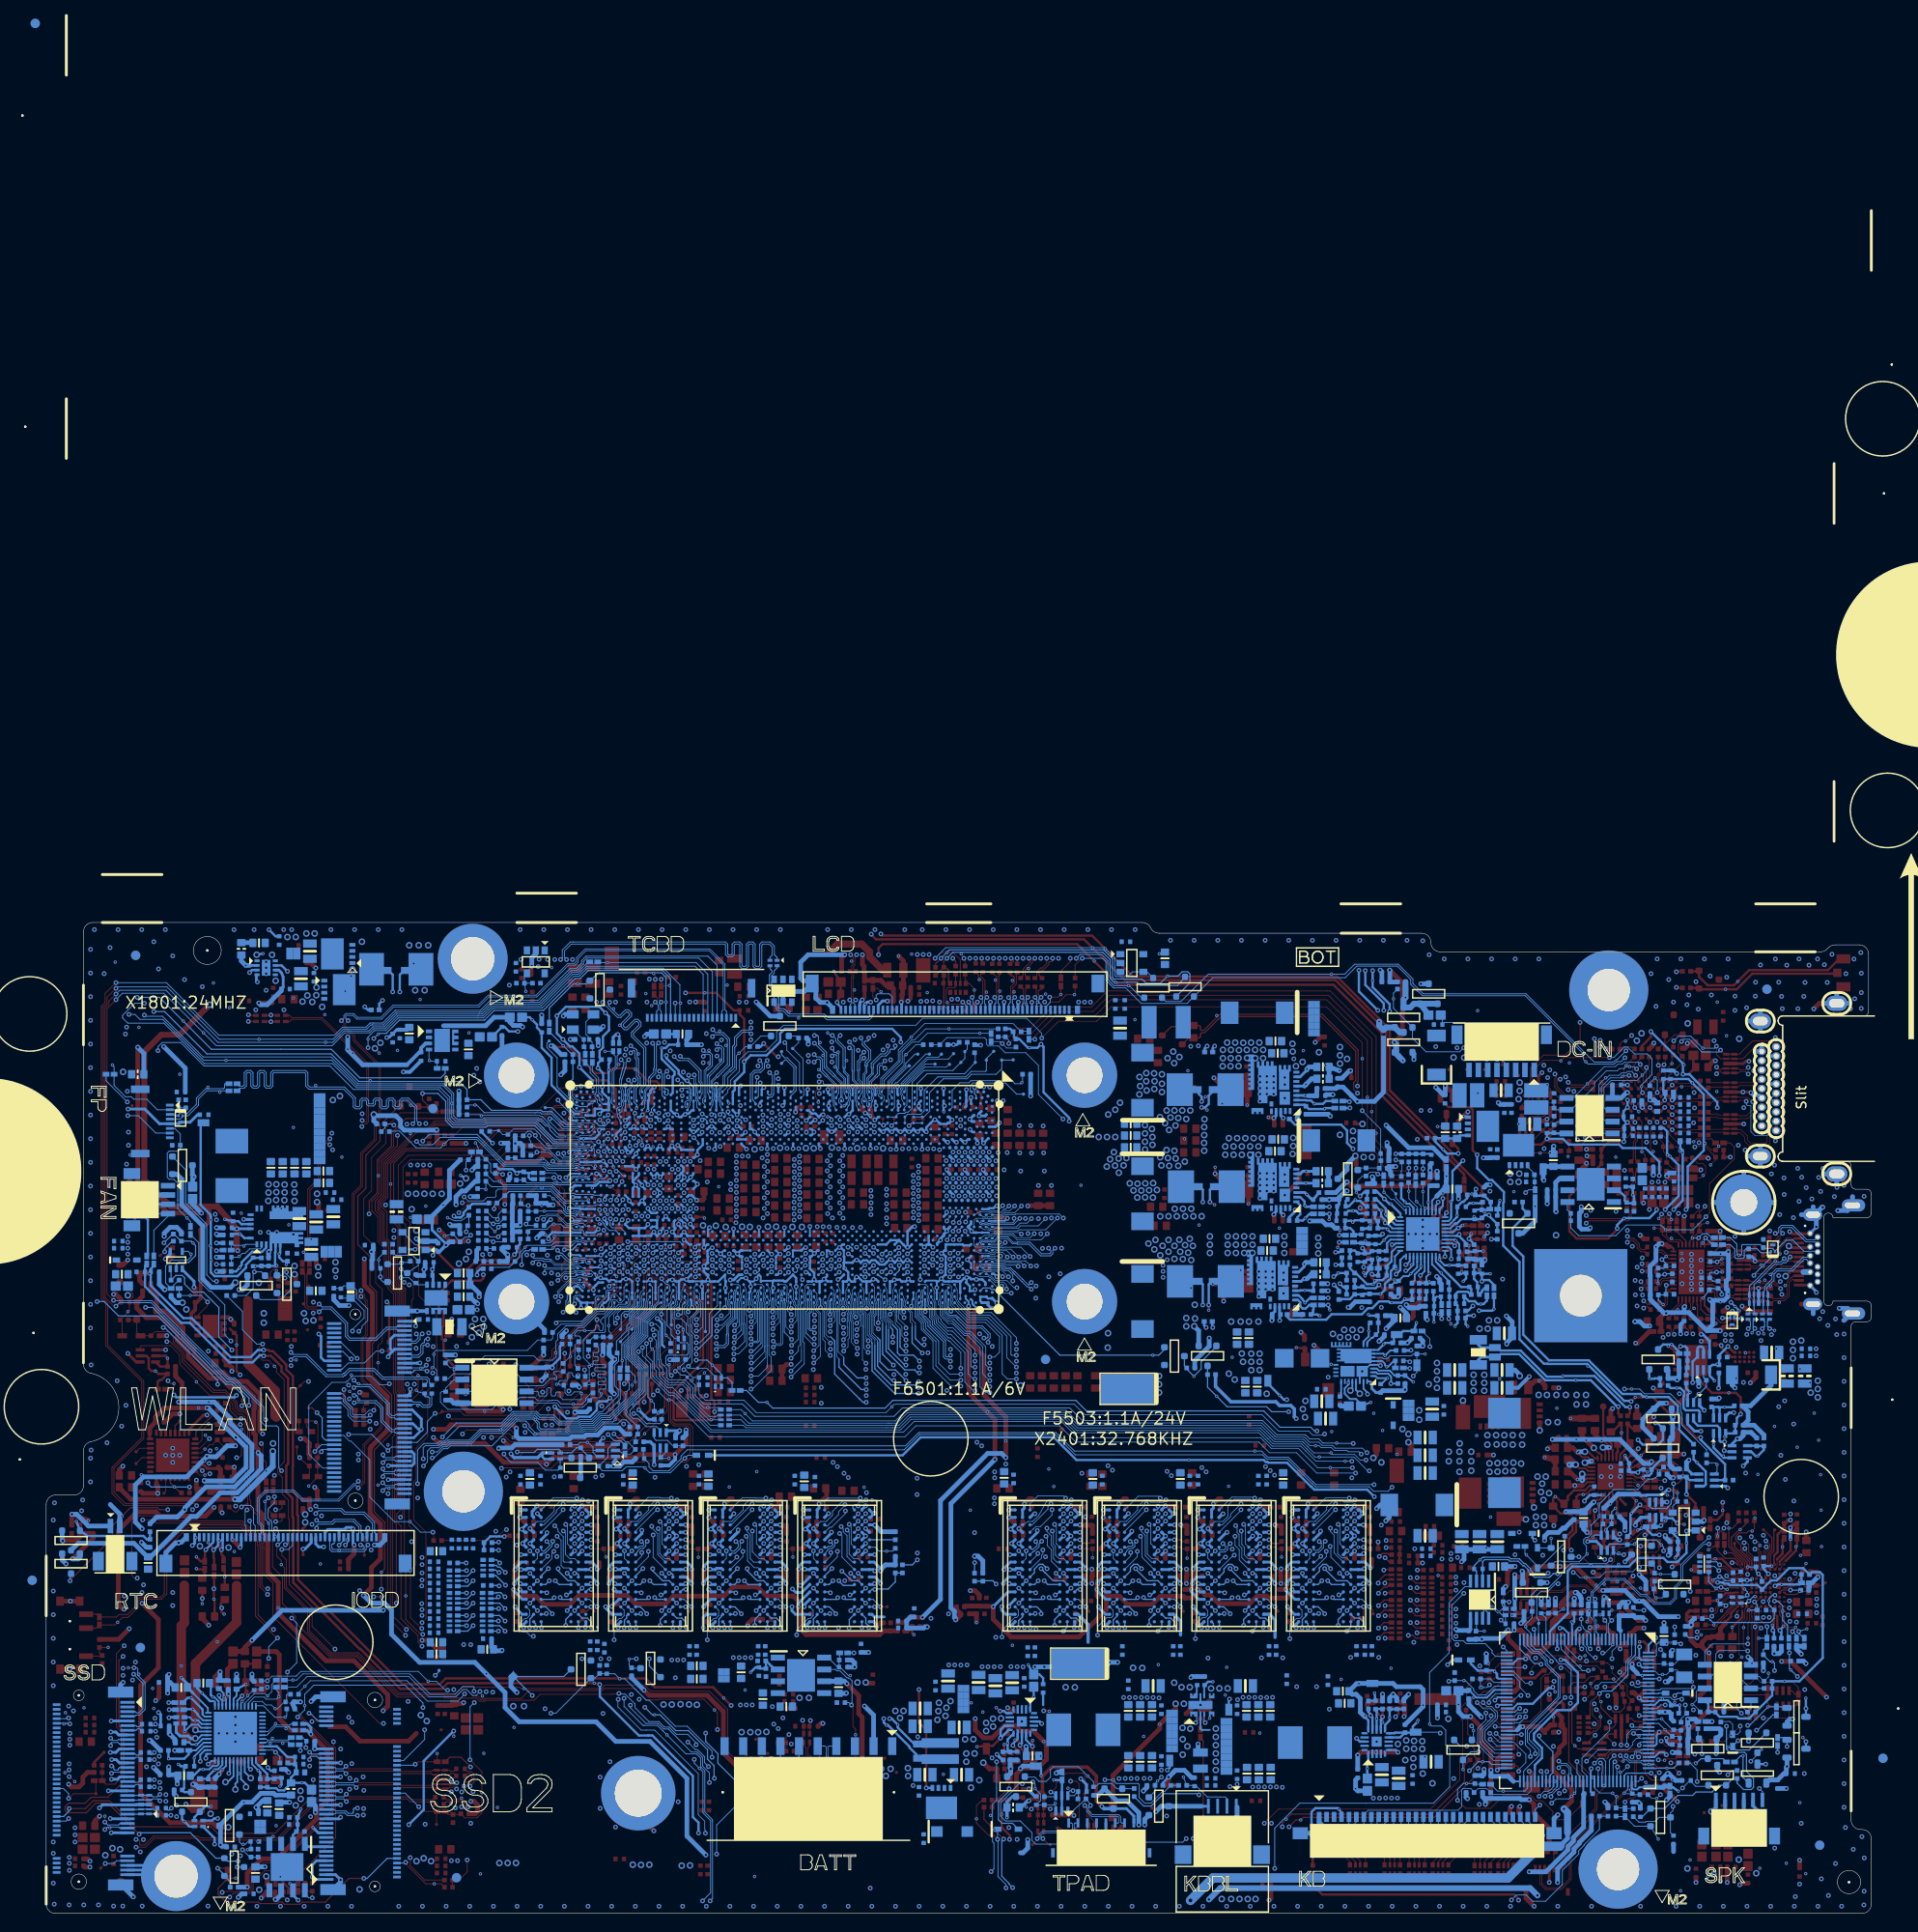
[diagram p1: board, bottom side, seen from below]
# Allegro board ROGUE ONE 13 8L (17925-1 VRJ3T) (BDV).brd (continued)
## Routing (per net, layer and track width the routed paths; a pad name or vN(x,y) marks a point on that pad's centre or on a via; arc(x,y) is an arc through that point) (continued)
PWR_VCCGT_FB2: length 6
  BOTTOM w0.254: PR4633.1 53.95,74.39 PC4618.2 55.49,74.39 v1(55.69,74.18) 55.85,74.34 PC4615.2 56.53,73.6 PR4631.1 55.97,73.55 55.61,73.2 PR4665.2 55.54,72.87 PC4619.1
PWR_VCCGT_FB_RC: length 0.8
  BOTTOM w0.254: PC4618.1 54.27,73.47 54.2,73.54 PR4636.1
PWR_VCCGT_FCCM#: length 29.4
  TOP w0.254: v2(51.04,68.6) v1(51.04,69.21)
  L4SGND w0.254: v2(56.06,87.11) 57.28,87.11 58.71,85.67 58.71,76.35 v2(58.21,75.84) 58.71,75.33 58.71,74.86 58.18,74.33 56.77,74.33 v2(51.04,68.6)
  BOTTOM w0.203: PU4601.11 50.18,70.53 50.59,70.12
  BOTTOM w0.254: v2(51.04,68.6) 50.59,69.05 50.59,70.12 ; v2(56.06,87.11) 56.14,87.19 PR4806.2 ; PR4812.2 v2(58.21,75.84)
PWR_VCCGT_FCCM#_RA: length 4.4
  BOTTOM w0.254: PR4806.1 58.59,87.19 58.89,86.89 v1(59.82,86.89) 60.18,87.24 60.68,87.24 60.72,87.29 PU4801.2
PWR_VCCGT_FCCM#_RB: length 2.5
  BOTTOM w0.254: PU4802.2 61.32,76.87 60.87,76.42 60.87,75.99 v1(60.82,75.94) 60.72,75.84 PR4812.1
PWR_VCCGT_IMON: length 4.4
  TOP w0.254: PR4608.2 53.46,75.48 PC4604.2 v1(52.64,75.46) 52.09,75.46 51.76,75.13 51.45,75.13 51.45,75.06 v2(51.51,75.06)
  BOTTOM w0.203: v2(51.51,75.06) 51.51,74.88 50.95,74.32 PU4601.2
PWR_VCCGT_ISEN1: length 9.4
  BOTTOM w0.203: 51.52,70.07 51.52,70.96 50.97,71.52 PU4601.9
  BOTTOM w0.254: PR4821.1 56,69.23 PR4824.2 55.36,68.73 54.16,67.53 v1(53.49,67.53) 53.49,67.56 53.08,67.96 52.49,67.96 52.03,68.42 PC4625.1 PR4669.2 52.03,69.49 51.52,70 51.52,70.07
PWR_VCCGT_ISEN2: length 10.4
  BOTTOM w0.203: PR4669.1 51.17,70.51 PU4601.10
  BOTTOM w0.254: PR4823.1 56.89,65.88 56.84,65.93 56,65.93 PR4822.2 54.73,66.44 PC4626.1 54.52,66.49 PR4635.1 v1(52.74,66.49) 52.67,66.49 52.24,66.92 52.24,67.56 51.83,67.96 51.8,67.96 51.6,68.17 51.6,68.93 PR4669.1
PWR_VCCGT_ISUMN: length 56.4
  TOP w0.254: PC4633.1 52.06,67.07 PR4645.2 52.44,67.02 v2(52.87,67.46) v1(53.33,67.91) 53.63,68.22 v2(53.63,68.6) 53.63,68.73 53.81,68.9 PR4642.2
  L6 w0.254: v2(71.34,93.08) 71.34,93.47 70.33,94.48 61.23,94.48 61.23,94.48 58.64,94.48 58.51,94.35 58.12,94.35 55.74,94.35 53,91.62 53,82.72 52.03,81.76 52.03,78.86 53.53,77.36 53.53,70.27 53.96,69.84 53.96,68.93 v2(53.63,68.6)
  BOTTOM w0.254: v2(71.34,93.08) 71.59,92.83 PR4646.2 ; PC4630.2 52.85,70.17 PR4643.2 52.95,70.12 PR4647.1 PC4625.2 53.51,68.47 v2(53.63,68.6) ; v2(52.87,67.46) 53.23,67.1 54.37,67.1 54.55,67.28 PC4626.2 54.73,67.2 PR4809.2 PR4815.2
PWR_VCCGT_ISUMN_GA: length 35.7
  TOP w0.254: v2(71.92,87.14) v1(71.5,87.64)
  L6 w0.254: v2(57.06,67.58) 56.94,67.71 56.94,69.61 55.64,70.91 55.64,76.05 57.6,78 57.6,81.58 60.68,84.67 62.39,84.67 69.37,84.67 71.84,87.14 v2(71.92,87.14)
  BOTTOM w0.254: v2(57.06,67.58) 56.68,67.2 PR4809.1 PR4822.1 ; PG4809.1 72.25,87.98 71.92,87.65 v2(71.92,87.14)
PWR_VCCGT_ISUMN_GB: length 24.1
  L3SGND w0.254: v2(57.74,68.34) 58.08,68.68 58.08,70.96 58.15,71.03 58.15,73.14 58.38,73.37 61.26,73.37 61.94,74.06 69.64,74.06 71.79,76.22 v2(71.79,76.35)
  BOTTOM w0.254: PR4815.1 PR4824.1 v1(57.27,68.73) 57.65,68.34 v2(57.74,68.34) ; PG4815.1 71.79,77.67 v2(71.79,76.35)
PWR_VCCGT_ISUMN_P_1: length 3.6
  BOTTOM w0.254: v1(54.37,68.42) 54.14,68.81 PR4647.2 53.81,69.54 53.63,69.72 PC4653.2 54.14,70.17 PC4628.2 PC4654.2
PWR_VCCGT_ISUMN_P_2: length 44.9
  TOP w0.254: v1(54.52,68.75) v2(54.52,69.36) 54.52,69.82 PR4641.2
  L6 w0.254: v2(70.52,93.08) 70.52,93.74 70.17,94.1 58.81,94.1 58.69,93.97 55.89,93.97 53.38,91.46 53.38,82.39 52.46,81.48 52.46,79.01 53.99,77.49 53.99,70.5 54.52,69.96 v2(54.52,69.36)
  BOTTOM w0.254: v2(70.52,93.08) 70.73,92.88 PR4646.1
PWR_VCCGT_ISUMN_RC: length 1.7
  TOP w0.254: v1(51.19,67.99) 52.01,67.99 PR4645.1 PC4623.1
PWR_VCCGT_ISUMNB: length 5.2
  TOP w0.254: v1(53.02,70.38) PR4642.1 52.87,69.56 PC4623.2 52.11,69.92 51.47,70.55 v2(51.47,71.77)
  BOTTOM w0.203: v2(51.47,71.77) 51.22,71.77 51.08,71.92 PU4601.8
PWR_VCCGT_ISUMP: length 9.9
  TOP w0.254: v1(54.34,72.15) 53.99,71.8 PR4641.1 54.46,71.21 v2(54.64,71.4)
  BOTTOM w0.203: PU4601.7 51.63,72.32 52,71.95
  BOTTOM w0.254: v2(54.64,71.4) 54.4,71.15 PC4628.1 ; PC4628.1 PC4654.1 55.46,71.14 PR4816.1 PR4808.1 ; PC4628.1 53.89,70.83 PC4653.1 52.9,71.09 PR4643.1 52.85,71.09 PC4630.1 52,71.19 52,71.95
PWR_VCCGT_ISUMP_GA: length 33.9
  TOP w0.254: v2(71.92,86.51) v1(71.34,86.22)
  L6 w0.254: v2(71.92,86.51) 71.74,86.51 69.52,84.29 60.84,84.29 57.98,81.42 57.98,77.84 56.02,75.89 56.02,71.11 v2(57.52,69.61)
  BOTTOM w0.254: PG4808.1 70.83,88.11 71.16,87.78 71.16,86.89 71.54,86.51 v2(71.92,86.51) ; PR4808.2 PR4821.2 v2(57.52,69.61)
PWR_VCCGT_ISUMP_GB: length 25.4
  TOP w0.254: v1(70.53,76.06) 70.77,76.19 v2(71.03,76.35)
  L3SGND w0.254: v2(57.7,67.46) 57.7,67.66 57.57,67.79 57.57,67.79 57.27,68.09 57.27,68.09 56.81,68.55 56.81,70.23 v2(57.54,70.95) 57.77,71.19 57.77,73.3 58.22,73.75 61.1,73.75 61.79,74.44 69.48,74.44 71.03,76 v2(71.03,76.35)
  BOTTOM w0.254: PR4823.2 57.19,66.95 v2(57.7,67.46) ; PG4813.1 71.03,77.67 v2(71.03,76.35) ; PR4816.2 56.99,71.14 57.17,70.95 v2(57.54,70.95)
PWR_VCCGT_NTC: length 4.3
  BOTTOM w0.203: 51.25,74.03 51.13,73.92 PU4601.3
  BOTTOM w0.254: 52.13,75.05 v1(52.16,75.05) ; 52.13,75.05 52.13,74.92 51.25,74.03 ; 52.13,75.05 52.13,75.63 53.14,76.64 PR4616.1
PWR_VCCGT_NTC1: length 17.2
  TOP w0.254: v2(54.9,76.98) v1(55.31,77.39)
  L6 w0.254: v2(54.9,76.98) 55.67,77.74 55.67,80.01 56.15,80.49 56.15,81.81 55.89,82.06 v2(55.67,82.06)
  BOTTOM w0.254: v2(54.9,76.98) 54.45,77.44 PR4621.2 54.14,76.66 PR4616.2 ; PR4617.1 61.89,84.65 56.94,84.65 56.3,84.02 56.3,82.7 v2(55.67,82.06)
PWR_VCCGT_PWMA: length 24
  TOP w0.254: v2(50,69.61) v1(49.37,69.61)
  L4SGND w0.254: v2(56,86.45) 56.3,86.45 58.31,84.45 58.31,77.89 50.03,69.61 v2(50,69.61)
  BOTTOM w0.203: PU4601.12 49.57,69.99 49.95,69.61 v2(50,69.61)
  BOTTOM w0.254: v2(56,86.45) 56.02,86.43 PR4802.2
PWR_VCCGT_PWMA_RA: length 4.4
  BOTTOM w0.254: PR4802.1 58.65,86.43 v1(58.72,86.36) 58.75,86.33 60.41,86.33 PR4817.1 60.87,86.79 PU4801.1
PWR_VCCGT_PWMB: length 14.2
  L4SGND w0.254: v2(50,68.98) 50.46,68.98 56.55,75.08 v2(58.21,75.08)
  BOTTOM w0.203: v2(50,68.98) 49.82,68.98 49.17,69.63 PU4601.13
  BOTTOM w0.254: v1(58.23,74.48) 58.21,74.5 v2(58.21,75.08) PR4811.2
PWR_VCCGT_PWMB_RA: length 4.4
  BOTTOM w0.254: PU4802.1 61.71,76.37 61.33,76 61.33,75.02 61.66,74.69 PR4818.1 61.05,74.36 v1(60.8,74.62) 60.34,75.08 PR4811.1
PWR_VCCGT_RTN: length 5.5
  BOTTOM w0.203: PU4601.6 51.88,72.72 v1(52.34,72.26) 52.77,71.82 PC4622.1
  BOTTOM w0.254: PC4622.1 53.28,71.85 PR4639.1 54.39,71.85 54.49,71.95 PC4619.2 55.54,71.95 PR4666.2
PWR_VCCGT_SNB1: length 3.3
  TOP w0.508: v1(67.02,86.76) PR4805.2 67.1,88.61 PC4810.1
PWR_VCCGT_SNB2: length 3.1
  TOP w0.508: v1(66.89,76.17) PR4814.2 66.89,79.11 PC4813.1
PWR_VCCGT_SWA: length 3.1
  TOP w0.508: v2(70.6,89.68) 69.71,88.79 PR4805.1 v1(69.71,86.91)
PWR_VCCGT_SWB: length 2.7
  TOP w0.254: v2(70.48,79.39) v1(70.47,80.08)
  TOP w0.508: v2(70.48,79.39) 69.58,78.5 PR4814.1
PWR_VCCGT_VCCDA: length 3
  BOTTOM w0.305: PU4801.3 60.91,87.79 60.87,87.75 v1(60.78,87.75) 60.47,87.75
  BOTTOM w0.508: PR4803.1 59.55,88.51 PC4809.1 59.79,87.78 59.82,87.75 60.47,87.75
PWR_VCCGT_VCCDB: length 3.1
  BOTTOM w0.305: PR4813.1 59.91,76.62 PC4812.1 60.07,76.6 v1(60.63,77.16) 60.84,77.37 PU4802.3
PWR_VCCSA_BST: length 2.5
  BOTTOM w0.305: PU5001.2 174.15,101.74
  BOTTOM w0.508: PR5001.2 175.05,102.22 v1(174.56,101.74) 174.15,101.74
PWR_VCCSA_BST_RC: length 1.3
  BOTTOM w0.508: PR5001.1 173.83,104.18 PC5005.1
PWR_VCCSA_COMP: length 3.3
  BOTTOM w0.203: PU4601.24 44.73,72.32 v1(44.61,72.2) 44.26,71.85 44.26,71.04 PR4640.1 44.31,70.99 PC4624.1
PWR_VCCSA_COMP_RC: length 1.8
  BOTTOM w0.254: PR4640.2 42.66,71.01 PC4601.1 v1(41.7,71.09)
PWR_VCCSA_DRVH: length 13
  L3SGND w1.016: v3(162.09,104.29) 162.57,103.8 170.59,103.8 170.94,104.16 172.27,104.16 173.39,103.03 v3(173.39,102.89)
  BOTTOM w0.254: v3(173.39,102.89) v1(172.71,103.02)
PWR_VCCSA_DRVL: length 7
  L6 w1.016: v3(166.36,97.3) 166.68,96.98 166.88,96.98 167.03,96.84 168.93,96.84 170.73,98.63 170.73,99.21 171.36,99.84 v3(171.36,100.09)
  vias: v1(166.08,96.46)
PWR_VCCSA_FB: length 8.1
  TOP w0.254: v2(44.26,72.89) 44.26,72.69 43.7,72.13 43.7,71.06 PR4632.2 44.01,70.71 PR4638.2 43.35,69.97 43.98,69.33 43.98,69.28 44.01,69.26 v1(44.01,68.83)
  BOTTOM w0.203: 44.62,72.72 PU4601.25
  BOTTOM w0.254: PR4637.1 43.52,71.95 44.26,72.69 v2(44.26,72.89) 44.44,72.72 44.62,72.72
PWR_VCCSA_FB1: length 1.8
  TOP w0.254: v1(42.08,69.06) 42.41,69.39 PR4638.1 PC4621.2
PWR_VCCSA_FB2: length 4.8
  TOP w0.254: PC4616.2 43.52,73.04 PR4601.1 42.76,72.87 v2(43.22,72.41) 43.17,72.36 PC4617.2 PC4620.1
  BOTTOM w0.254: v1(42.99,72.94) v2(43.22,72.41) 42.66,71.85 PR4637.2
PWR_VCCSA_FB_RC: length 2
  TOP w0.254: PC4617.1 42.33,71.52 42.58,71.77 43.05,71.77 43.18,71.65 v1(43.22,71.65) 43.22,71.24 43.14,71.16 PR4632.1
PWR_VCCSA_FCCM: length 159.1
  L3SGND w0.254: v2(170.09,101.11) 170.09,97.83 168.67,96.41 150.8,96.41 145.78,101.43 145.78,101.86 145.78,101.86 145.78,102.18 145.78,102.18 145.78,102.42 144.58,103.62 105.07,103.62 104.64,104.06 83.63,104.06 82.72,103.14 55.28,103.14 54.78,102.63 54.78,101.47 v2(55.03,101.22)
  L4SGND w0.254: v2(53,96.92) 53,96.84 43.85,87.69 v2(43.85,80.79)
  BOTTOM w0.203: 45.12,74.69 45.19,74.63 45.19,74.52 45.39,74.32 PU4601.29
  BOTTOM w0.254: PU5001.7 170.72,101.74 v2(170.09,101.11) ; 45.15,76.4 v1(45.17,76.4) ; 45.15,76.4 44.98,76.56 44.98,79.66 v2(43.85,80.79) ; 45.15,76.4 45.12,76.37 45.12,74.69 ; v2(55.03,101.22) 55.03,98.95 v2(53,96.92)
PWR_VCCSA_IMON: length 3.4
  TOP w0.254: PR4644.1 45.45,72 PC4629.2 45.26,72.19 v1(44.63,72.19) 44.59,72.16 44.59,71.8 v2(44.74,71.65)
  BOTTOM w0.203: v2(44.74,71.65) 45.01,71.92 PU4601.23
PWR_VCCSA_ISUMN: length 150.2
  TOP w0.254: PR5004.2 43.73,77.51 43.42,77.21 v1(42.91,77.21) 42.71,77.21 42.46,77.46 v2(42.46,77.74)
  L3SGND w0.254: v2(161.79,97.3) 160.19,97.3 159.93,97.05 150.71,97.05 146.17,101.59 146.17,102.02 146.17,102.02 146.17,102.58 144.53,104.21 105.17,104.21 104.94,104.44 83.25,104.44 82.36,103.55 55.15,103.55 54.34,102.74 v2(54.34,101.19)
  L4SGND w0.254: v2(52.36,96.92) 52.36,96.75 42.81,87.2 42.81,83.64 43.22,83.23 43.22,78.5 v2(42.46,77.74)
  BOTTOM w0.254: v2(52.36,96.92) 52.36,97.68 54.34,99.66 v2(54.34,101.19) ; PC4605.1 42.51,75.53 41.85,75.53 PR4618.2 41.06,75.51 PR4613.1 40.88,75.68 PR4615.1 PC4603.2 42.46,77.03 PR4620.1 42.53,77.67 v2(42.46,77.74) ; PR4611.1 161.46,96.97 v2(161.79,97.3)
PWR_VCCSA_ISUMN_P_1: length 1.7
  BOTTOM w0.254: PC4608.2 40.12,74.95 PR4613.2 v1(39.89,76.52)
PWR_VCCSA_ISUMN_P_2: length 149.3
  L3SGND w0.254: v2(159.88,97.99) 159.32,97.43 150.86,97.43 146.55,101.75 146.55,102.74 144.49,104.79 108.09,104.79 107.89,104.59 105.5,104.59 105.04,105.05 83.22,105.05 82.11,103.93 54.99,103.93 53.96,102.9 53.96,101.59 v2(53.56,101.19)
  L4SGND w0.254: v2(40.81,72.36) 40.51,72.65 40.51,76.18 41.82,77.49 41.82,78.25 42.84,79.27 42.84,83.08 42.43,83.48 42.43,87.53 v2(51.73,96.83)
  BOTTOM w0.254: v2(51.73,96.83) 51.73,97.59 53.56,99.41 v1(53.56,100.12) v2(53.56,101.19) ; PR4611.2 160.24,97.63 v2(159.88,97.99) ; PR4625.2 v2(40.81,72.36)
PWR_VCCSA_ISUMN_R: length 136.7
  TOP w0.254: v2(107.4,105.1) 107.4,105.05 106.9,104.54 84.54,104.54 v1(83.64,103.64) 80.18,100.17 57.54,100.17 52.11,94.74 52.11,88.11 45.4,81.4 45.4,80.99 43.73,79.32 PR5004.1
  L4SGND w0.254: v2(158.03,98.9) 157.44,98.32 149.8,98.32 147.31,100.81 147.31,103.12 145.35,105.07 107.43,105.07 v2(107.4,105.1)
  BOTTOM w0.254: PG5001.1 158.03,100.74 v2(158.03,98.9)
PWR_VCCSA_ISUMN_RC: length 2
  BOTTOM w0.254: PR4615.2 41.87,76.22 v1(42.74,76.22) 43.17,76.22 PC4611.1
PWR_VCCSA_ISUMNB: length 4.5
  BOTTOM w0.203: 44.83,74.41 45.32,73.92 PU4601.28
  BOTTOM w0.254: PR4620.2 43.4,76.78 43.8,76.37 43.95,76.37 44.46,75.86 PC4611.2 44.49,75.81 v1(44.49,74.92) 44.49,74.75 44.83,74.41
PWR_VCCSA_ISUMP: length 9.2
  TOP w0.254: v2(41.06,74.95) 41.21,74.95 v1(41.56,75.29) 41.82,75.56 PR5003.2
  BOTTOM w0.203: PU4601.27 45.21,73.52 44.7,74.03
  BOTTOM w0.254: PR4625.1 PC4608.1 41.06,74.87 v2(41.06,74.95) 41.52,74.95 PR4618.1 41.95,74.52 PC4605.2 44.03,74.52 44.49,74.06 44.66,74.06 44.7,74.03
PWR_VCCSA_ISUMP_R: length 140.4
  TOP w0.254: v2(106.36,105.12) 106.19,104.95 83.68,104.95 v1(82.28,103.54) 79.29,100.55 57.38,100.55 51.73,94.9 51.73,94.62 51.73,88.35 45.02,81.65 45.02,81.15 41.82,77.95 PR5003.1
  L4SGND w0.254: v2(106.36,105.12) 106.36,105.07 106.92,104.51 145.15,104.51 146.88,102.79 146.88,100.7 149.77,97.81 157.7,97.81 v2(158.79,98.9)
  BOTTOM w0.254: PG5011.1 158.79,100.74 v2(158.79,98.9)
PWR_VCCSA_PWM: length 157.7
  TOP w0.254: v2(106.62,102.89) 106.62,103.6 106.19,104.03 85.28,104.03 v1(83.45,102.2) 80.91,99.66 57.75,99.66 52.62,94.53 52.62,87.83 45.91,81.12 45.91,79.75 45.51,79.34 45.51,75.33 v2(45.63,75.2)
  L4SGND w0.254: v2(174.16,100.98) 174.16,99.69 170.8,96.33 150.29,96.33 146.2,100.42 146.2,102.66 144.93,103.93 107.66,103.93 v2(106.62,102.89)
  BOTTOM w0.203: PU4601.30 45.78,75.05 v2(45.63,75.2)
  BOTTOM w0.254: PU5001.3 173.9,101.24 174.16,100.99 v2(174.16,100.98)
PWR_VCCSA_RTN: length 5.6
  TOP w0.254: PC4613.1 44.74,73.93 v2(44.36,73.55) ; v2(44.36,73.55) 44.74,73.17 PR4627.2 ; v2(44.36,73.55) 44.03,73.88 PC4616.1 43.52,73.81 PR4602.1
  BOTTOM w0.203: PU4601.26 44.92,73.12 44.49,73.55 v2(44.36,73.55)
  BOTTOM w0.254: v2(44.36,73.55) 43.9,73.84 43.9,73.85 v1(43.89,73.85)
PWR_VCCSA_SW: length 10
  TOP w0.254: v3(163.11,101.32) v1(163.25,100.6)
  L3SGND w1.016: v3(171.74,102.89) 171.36,102.51 164.3,102.51 v3(163.11,101.32)
PWR_VCORE_BOOT: length 2.3
  BOTTOM w0.305: v1(60.88,68.12) 60.95,68.12 61.24,67.83 PU4701.5
  BOTTOM w0.508: PR4705.2 60.14,68.6 60.62,68.12 v1(60.88,68.12)
PWR_VCORE_BOOT_RC: length 1.3
  BOTTOM w0.508: PR4705.1 PC4707.1
PWR_VCORE_BOOTR: length 2.6
  BOTTOM w0.305: v1(60.9,69.69) 60.9,69.43 61.5,68.83 PU4701.7
  BOTTOM w0.508: PC4707.2 60.72,69.87 v1(60.9,69.69)
PWR_VCORE_COMP: length 4.7
  TOP w0.254: PR4656.1 49.16,67.79 PC4639.1 ; v2(48.43,68.47) PC4639.1 ; PC4639.1 v1(47.49,67.79)
  BOTTOM w0.203: PU4601.16 47.97,69.97 47.97,69.97 47.97,68.93 v2(48.43,68.47)
PWR_VCORE_COMP1: length 1.7
  TOP w0.254: PR4656.2 PC4640.1 v1(50.1,65.96)
PWR_VCORE_FB: length 4.6
  BOTTOM w0.203: PU4601.17 47.57,68.84 v1(47.43,68.69) 47.79,68.33 PR4658.1
  BOTTOM w0.254: PR4660.1 PR4658.1 PR4657.1
PWR_VCORE_FB1: length 0.8
  BOTTOM w0.254: PR4657.2 PC4641.1
PWR_VCORE_FB2: length 5.1
  BOTTOM w0.203: PR4667.2 46.22,65.42 PC4642.2 46.7,66.19 PC4643.2
  BOTTOM w0.254: PR4660.2 47.03,66.01 PC4643.2 PC4644.1 46.98,65.14 PR4663.2 v1(46.98,63.47)
PWR_VCORE_FB_RC: length 0.9
  BOTTOM w0.254: PR4658.2 47.79,66.01 PC4643.1
PWR_VCORE_FCCM#: length 17.6
  TOP w0.254: v2(45.78,70.5) v1(46.39,70.17)
  L6 w0.254: v2(45.78,70.5) 45.78,68.51 46.85,67.44 50.77,67.44 50.77,67.45 51.19,67.45 52.57,66.06 v2(58.33,66.06)
  BOTTOM w0.203: PU4601.21 v2(45.78,70.5)
  BOTTOM w0.254: PR4706.2 v2(58.33,66.06)
PWR_VCORE_FCCM#_R: length 2.6
  BOTTOM w0.254: PU4701.2 61.5,66.33 61.1,65.93 v1(60.82,65.52) 60.29,66.06 PR4706.1
PWR_VCORE_IMON: length 4.9
  BOTTOM w0.203: PU4601.14 48.77,69.97 48.78,69.97 48.78,69.34 v1(49.47,68.65) 49.72,68.39 50.25,68.39 PC4638.1 50.97,67.68 51.25,67.68 PR4661.1
PWR_VCORE_ISUMN: length 44.8
  L6 w0.254: v2(70.73,62.88) 70.43,62.88 70.07,62.53 63.01,62.53 62.27,63.26 50.39,63.26 48.62,61.49 44.29,61.49 41.57,64.21 41.57,67.58 v2(41.82,67.84)
  BOTTOM w0.254: PR4648.2 PR4651.2 ; PR4651.2 41.9,68.73 PC4631.1 ; PR4651.2 42.66,68.09 42.33,67.76 42.33,67.3 PC4634.1 42.25,66.57 PR4652.2 41.8,66.72 41.8,66.85 41.5,67.15 PR4649.2 ; PR4650.1 70.78,62.93 v2(70.73,62.88) ; v1(40.93,68.65) PC4631.1 ; PC4631.1 v2(41.82,67.84) 41.68,67.97 41.05,67.97 40.53,67.46 PR4701.2
PWR_VCORE_ISUMN_G: length 38.4
  L6 w0.254: v2(42.13,64.69) 42.94,64.69 43.35,64.28 43.35,63.51 44.61,62.25 48.3,62.25 50.2,64.15 54.33,64.15 54.36,64.13 55.09,64.13 55.12,64.15 70.37,64.15 71.06,64.15 71.68,64.77 71.68,65.18 v2(71.79,65.3)
  BOTTOM w0.254: v2(71.79,65.3) 71.79,67.51 PG4708.1 ; PR4701.1 v1(40.53,64.86) 40.7,64.69 v2(42.13,64.69)
PWR_VCORE_ISUMN_P_1: length 4.2
  BOTTOM w0.254: PR4649.1 41.29,65.75 41.64,65.4 v1(41.95,65.4) 42.27,65.4 42.58,65.7 43.22,65.7 PC4652.1 PC4635.1
PWR_VCORE_ISUMN_P_2: length 34.3
  L6 w0.254: v2(71.44,62.88) 71.44,63.14 71.18,63.39 70.4,63.39 69.91,62.91 63.16,62.91 62.43,63.65 50.24,63.65 48.46,61.87 44.45,61.87 42.96,63.35 42.96,63.9 v2(42.71,64.15)
  BOTTOM w0.254: v2(71.44,62.88) 71.64,63.09 PR4650.2 ; v1(43.35,63.01) 43.57,63.24 PR4653.2 43.57,64 43.42,64.15 v2(42.71,64.15)
PWR_VCORE_ISUMN_RC: length 1.9
  BOTTOM w0.254: PC4632.1 44.03,68.65 43.96,68.73 PR4651.1 43.52,68.14 v1(43.83,67.84)
PWR_VCORE_ISUMNA: length 3.5
  BOTTOM w0.203: 45.84,69.56 46.37,70.1 PU4601.20
  BOTTOM w0.254: PR4648.1 43.6,69.56 PC4632.2 v1(45.3,69.56) 45.84,69.56
PWR_VCORE_ISUMP: length 11.8
  BOTTOM w0.203: PU4601.19 46.77,69.94 46.57,69.74
  BOTTOM w0.254: v1(44.72,63.01) 44.72,63.11 44.69,63.11 44.44,63.37 PR4653.1 PR4708.2 44.44,65.25 PC4635.2 PC4652.2 44.64,66.46 44.39,66.72 43.35,66.72 43.04,66.41 PR4652.1 42.97,67.02 PC4634.2 44.05,67.23 46.57,69.74
PWR_VCORE_ISUMP_G: length 35.6
  TOP w0.254: v2(71.16,65.3) v1(71.16,64.74)
  L6 w0.254: v2(71.16,65.3) 71.23,65.22 71.23,64.86 70.91,64.53 54.96,64.53 54.94,64.51 54.51,64.51 54.49,64.53 50,64.53 48.1,62.63 44.77,62.63 43.73,63.67 43.73,64.44 43,65.17 42.79,65.17 42.79,65.19 v2(42.79,65.19)
  BOTTOM w0.254: PG4707.1 71.16,67.51 v2(71.16,65.3) ; PR4708.1 43.32,64.66 v2(42.79,65.19)
PWR_VCORE_NTC: length 3.3
  BOTTOM w0.203: PR4662.1 49.04,67.94 49.04,68.57 48.37,69.24 v1(48.37,69.49) PU4601.15
PWR_VCORE_NTC1: length 15.7
  BOTTOM w0.254: PR4654.1 62.73,64.03 62.42,63.72 58.54,63.72 57.96,64.31 54.7,64.31 54.05,64.95 53.59,64.95 52.87,65.68 51.83,65.68 51.7,65.55 v1(51.5,65.55) 50.46,65.55 50.15,65.85 PR4655.2 49.32,66.11 49.34,66.13 PR4662.2
PWR_VCORE_PROG1: length 2.9
  TOP w0.254: v1(47.89,75.67) PR4629.1 47,75.86 v2(46.52,76.35)
  BOTTOM w0.203: PU4601.32 46.77,75.97 46.52,76.22 v2(46.52,76.35)
PWR_VCORE_PROG2: length 3.3
  TOP w0.254: v1(46.01,77.31) v2(46.01,76.73) 46.01,75.9 PR4628.1
  BOTTOM w0.203: v2(46.01,76.73) 46.01,75.93 46.37,75.57 PU4601.31
PWR_VCORE_PWM: length 19.4
  L6 w0.254: v2(45.12,70.25) 45.12,68.45 46.64,66.94 50.98,66.94 52.36,65.55 58.08,65.55 v2(58.33,65.3)
  BOTTOM w0.203: PU4601.22 45.37,71.52 45.12,71.27 v2(45.12,70.25)
  BOTTOM w0.254: v1(58.16,64.77) v2(58.33,65.3) PR4702.2
PWR_VCORE_PWM_R: length 4.9
  BOTTOM w0.254: PU4701.1 61.57,65.83 61.33,65.59 61.33,65.17 61.08,64.92 60.75,64.92 60.36,65.3 PR4702.1 59.91,64.81 59.96,64.76 59.96,64.51 PR4712.1 59.5,64.28 59.37,64.15 v1(59.22,64.15)
PWR_VCORE_RTN: length 6
  BOTTOM w0.203: PR4668.2 45.3,65.42 PC4642.1 45.33,66.21 PR4659.2 45.33,67.61 PC4637.1 45.43,67.91 46.19,68.67 v1(46.19,68.73) 46.24,68.73 47.17,69.66 PU4601.18
PWR_VCORE_SNB: length 2.3
  TOP w0.508: PR4703.2 66.87,68.88 PC4706.1 67.6,68.9 v1(67.73,69.03)
PWR_VCORE_SW: length 3
  TOP w0.508: v1(70.73,67.54) PR4703.1 v2(69.56,65.7)
PWR_VCORE_VCC: length 3.6
  BOTTOM w0.203: PU4601.34 47.57,76.3 v1(47.59,76.32) 47.57,76.34 47.57,77.9 PC4607.1
  BOTTOM w0.508: PC4607.1 47.36,78.11 PR4610.2
PWR_VCORE_VCC_R: length 2.8
  BOTTOM w0.254: PU4701.3 61.34,66.83 61.3,66.87 v1(60.85,66.87) 60.35,66.87 60.3,66.82 PC4708.1 59.91,66.85 PR4704.1
PWR_VCORE_VIN: length 5.6
  BOTTOM w0.203: PU4601.33 47.17,76.51 46.7,76.98 46.65,76.98
  BOTTOM w0.508: PR4612.2 v1(45.63,79.11) 45.63,78.66 45.66,78.63 PC4606.1 45.9,77.74 46.65,76.99 46.65,76.98
PWR_VCORE_VRHOT#: length 3.7
  BOTTOM w0.203: PU4601.38 49.17,75.74 49.59,76.17 49.9,76.17 v1(50.08,76.35)
  BOTTOM w0.254: PR4607.2 50.48,76.75 v1(50.08,76.35)
PWR_VDDQ_BOOT: length 5
  BOTTOM w0.203: PU5101.27 56.14,56.77 56.55,56.36 56.55,55.77 56,55.21 55.35,55.21 54.8,54.66 PR5111.1 v1(53.76,54.85)
PWR_VDDQ_BOOTA: length 1
  BOTTOM w0.508: PR5111.2 56.96,54.45 PC5114.2
PWR_VDDQ_BOOTB: length 1.7
  BOTTOM w0.203: PC5114.1 56.94,55.59 PU5101.25
PWR_VDDQ_CS: length 2.6
  BOTTOM w0.203: PU5101.10 54.54,61.37 53.98,61.93 v1(53.98,62.5) 53.98,63.23 PR5102.2
PWR_VDDQ_EN: length 6.8
  BOTTOM w0.102: v1(47.92,60.04) PR5114.1 ; PR5114.1 PG5122.2 ; PR5114.1 49.2,60.04 49.4,59.84 51.7,59.84 52.02,59.51 52.36,59.51 52.4,59.56 52.43,59.56 52.55,59.67 PU5101.6
PWR_VDDQ_FB: length 4.9
  BOTTOM w0.203: PU5101.3 53.11,58.47 52.9,58.25 51.72,58.25 51.19,57.73 PR5107.2 PR5101.1 v1(49.19,57.04)
PWR_VDDQ_PG: length 3.4
  BOTTOM w0.203: PU5101.8 52.96,60.47
  BOTTOM w0.254: PG5114.2 51.27,61.36 PR5104.2 52.21,61.23 v1(52.36,61.08) 52.36,61.07 52.96,60.47
PWR_VDDQ_PH: length 3.1
  TOP w0.254: v1(58.01,58.93) PR5110.1
  TOP w0.508: PR5110.1 59.14,60.27 v2(59.86,60.98)
PWR_VDDQ_SNB: length 2.1
  TOP w0.254: PC5118.1 v1(61.76,60.72)
  TOP w0.508: PC5118.1 60.82,60.6 PR5110.2
PWR_VDDQ_TON: length 2.8
  BOTTOM w0.203: PR5103.2 51.67,60.42 v1(52.22,59.87) 52.42,60.07 PU5101.7
PWR_VDDQ_VCC: length 4.7
  BOTTOM w0.203: PR5102.1 52.95,62.38 PC5108.1 53.55,61.77 53.67,61.77 54.14,61.3 PU5101.9
  BOTTOM w0.254: PR5102.1 52.95,64.05 PR5108.2 53.91,64.15 54.01,64.25 v1(54.01,64.28)
PWR_VDDQ_VDDQ: length 19.6
  L4SGND w0.254: v2(62.78,55.14) 61.79,56.13 59.96,56.13 58.45,54.62 53.82,54.62 51.6,56.85 v2(51.6,56.86)
  BOTTOM w0.203: PU5101.2 53.18,58.07 53.03,57.92 51.89,57.92 51.57,57.61 51.57,56.89 v2(51.6,56.86) PR5107.1
  BOTTOM w0.254: PG5113.1 v1(63.54,55.6) 63.08,55.14 v2(62.78,55.14)
PWR_VDDQ_VLDOIN: length 1.1
  BOTTOM w0.203: v3(55.94,56.11) 55.93,56.11 55.74,56.31 PU5101.28
  vias: v1(56.17,56.94)
PWR_VDDQ_VTT: length 3
  BOTTOM w0.203: v3(54.94,55.78) 55.34,56.18 PU5101.29 ; PU5101.31 54.54,56.32 54.11,55.89 v2(54.11,55.73)
  vias: v1(52.49,51.83)
PWR_VDDQ_VTTREF: length 2.7
  BOTTOM w0.203: PU5101.1 53.25,57.67 53.02,57.44 v1(51.98,57.44) 52.61,56.81 PC5113.1
PWR_VTT_EN: length 3.8
  BOTTOM w0.203: PU5101.5 52.92,59.27 52.92,59.28 52.52,59.28 52.24,58.99 52.24,58.84 v1(52.05,58.66) 51.91,58.66 51.27,59.3 PR5112.2 PR5113.2
Q502_G: length 6.8
  BOTTOM w0.127: Q502.G 70.34,60.84 71.97,59.2 71.97,58.43 v1(72.75,57.65) 73.52,58.43 R506.2 73.77,58.79 Q501.D
Q5705_2: length 4.8
  TOP w0.102: R5749.2 37.53,85.06 v1(37.86,84.73) 37.02,84.73 C5777.2 36.72,85.21 36.41,85.51 35.21,85.51 35.09,85.63 Q5705.2
Q5705_5_6: length 4
  TOP w0.102: R5747.1 33.39,87.37 33.83,87.81 Q5705.6 34.44,88.42 34.81,88.79 v1(34.81,88.94) 35.09,88.66 Q5705.5
Q6204_G: length 4.2
  BOTTOM w0.254: Q6504.2 Q6504.5 R6510.2 v1(87.8,14.32)
Q6205_Q: length 2.9
  BOTTOM w0.305: R6503.2 92.83,11.96 92.24,12.54 Q6503.D
  BOTTOM w0.381: v1(92.83,10.28) R6503.2
RESET_OUT#: length 162.4
  L4SGND w0.127: v2(59.54,51.77) 59.54,51.52 58.92,50.89 52.85,50.89 48.78,46.83 48.67,46.83 40.76,38.91 40.76,35.91 39.07,34.23 38.11,34.23 37.82,33.94 37.82,32.15 38.08,31.9 38.08,30.95 36.55,29.43 36.55,26.63 35.28,25.35 35.28,24.13 35.51,23.9 35.51,22.95 35.4,22.83 35.4,19.35 v2(35.68,19.07)
  L6 w0.127: v2(15.56,20.08) 15.81,19.83 20.11,19.83 20.83,20.55 25.48,20.55 25.89,20.96 30.34,20.96 31.41,19.89 34.85,19.89 v2(35.68,19.07)
  BOTTOM w0.127: R1706.1 120.79,56.13 119.52,54.86 v1(118.61,54.86) 117.98,54.23 105.91,54.23 105.08,55.06 85.42,55.06 84.29,53.93 65.25,53.93 63.5,52.18 60.2,52.18 59.79,51.77 v2(59.54,51.77) ; v2(15.56,20.08) 15.56,17.6 15.23,17.28 13.63,17.28 13.41,17.06 13.41,15.25 12.66,14.49 12.66,13.52 12.89,13.29 13.72,13.29 14.42,13.99 R2616.2 14.89,14.47 ED1703.2 16.37,13.76 17.1,13.02 18.84,13.02 19.19,12.67 20.78,12.67 22.2,11.25 Q2602.G 24.61,10.36 C2614.1 ; U2401.73 34.53,14.78 34.2,15.11 34.2,17.36 35.7,18.86 35.7,19.04 v2(35.68,19.07)
REXT: length 4.8
  TOP w0.102: U5701.C6 24.65,84.96 v1(24.65,81.76) 24.3,81.41 24.3,80.87 R5734.1
RING2_R:
  vias: v1(175.81,38.83) v3(176.42,39.26)
RSMRST_PWRGD#: length 5.7
  TOP w0.102: v1(18.89,16.15) R4029.2 R4030.2 19.82,16.93 19.82,17.65 R4033.2 R4031.2 R4032.2 19.72,19.2 18.96,18.43 D4002.K
RTC_3P3_EN_D: length 2.3
  TOP w0.508: v1(184.9,68.67) Q2510.D 185.97,67.92 R2511.1
RTC_3P3_EN_G: length 7.1
  TOP w0.102: Q2510.G 187.87,67.72 186.7,66.56 186.7,66.12 187.06,65.76 C2517.1 187.06,64.75 v1(187.22,64.58) 187.22,64.52 R2567.2 187.84,63.49 D2502.A
RTC_AUX_S5: length 120.4
  TOP w0.508: v2(177.97,43.58) 178.91,42.64 183.76,42.64 184.21,43.1 186.25,43.1 188.25,41.09 188.25,33.17 187.75,32.66 v2(187.62,32.66) ; R2204.1 150.71,53.89 v1(148.91,53.89) 147.11,53.89 v2(146.93,54.07) 147.31,54.45 R1730.1 ; R2511.2 R2512.2 184.14,66.18 Q2507.D 183.09,64.66 181.29,62.87 181.29,61.77 180.13,60.6 180.13,59.95 178.23,58.06 176.95,58.06 175.98,57.09 174.98,57.09 174.45,57.09 173.06,55.7 173.06,55.15 172.96,55.05 172.96,54 173.06,53.9 173.06,51.78 v2(172.75,51.47)
  L3SGND w0.508: v2(177.97,43.58) 174.92,46.63 174.92,49.29 173.53,50.68 173.53,50.69 173.16,51.06 173.15,51.06 v2(172.75,51.47)
  L4SGND w0.508: v2(146.93,54.07) 148.27,52.72 158.86,52.72 160.74,50.84 161.72,50.84 163.17,52.29 166.72,52.29 166.87,52.44 171.77,52.44 v2(172.75,51.47) ; v2(187.62,32.66) 188.13,32.15 188.13,30.24 185.71,27.83 185.71,18.45 185.19,17.93 182.82,17.93 182.39,17.49 v2(182.21,17.49)
  L6 w0.508: v2(146.93,54.07) 146.93,52.59 146.09,51.75 v2(146.09,49.32)
  BOTTOM w0.254: 142.71,49.42 142.71,48.99 142.49,48.77 RN1801.2
  BOTTOM w0.356: RN1801.1 142.71,49.42 143.21,48.91 145.73,48.91 146.09,49.27 v2(146.09,49.32)
  BOTTOM w0.508: R2754.1 v2(182.21,17.49)
RTC_DET#: length 103.6
  TOP w0.127: v2(182.94,43.33) 183.81,43.33 184.03,43.54 186.95,43.54 v1(187.85,42.63) 188.89,41.6 188.89,40.3 193.43,35.76 v2(193.43,35.69)
  L4SGND w0.127: v2(162.35,34.64) 162.42,34.64 164.22,36.44 170.24,36.44 172.89,39.08 172.89,41.7 173.78,42.59 174.64,42.59 174.67,42.61 175.6,42.61 177.15,44.16 178.14,44.16 179.69,42.61 182.23,42.61 v2(182.94,43.33)
  L6 w0.127: v2(162.35,34.64) 161.96,35.02 161.96,35.32 159.39,37.9 159.39,41.64 161.32,43.57 161.32,49.94 159.04,52.22 159.04,53.23 157.9,54.37 157.9,57.17 157.32,57.75 157.32,63.45 156.67,64.1 156.06,64.1 154.34,65.81 154.34,66.42 152.23,68.53 152.23,69.96 151.23,70.96 151.23,71.2 150.79,71.65 150.15,71.65 149.11,72.69 149.11,74.4 v2(147.9,75.61)
  BOTTOM w0.076: CPU1.CP22 138.39,75.09 138.64,75.35 138.67,75.35 arc(138.76,75.36) 138.83,75.41 139.33,75.41 139.47,75.27 140,75.27 140.23,75.5 140.23,75.91 141.8,77.48 141.89,77.48
  BOTTOM w0.127: Q2505.D 193.43,35.93 v2(193.43,35.69) ; 141.89,77.48 146.31,77.48 R1519.1 146.8,77.03 R1554.2 147.9,75.93 v2(147.9,75.61)
RTC_RST#: length 91
  TOP w0.127: v2(128.11,64.86) 128.11,64.86 128.77,64.21 128.77,62.02 128.6,61.85 128.6,58.89 129.52,57.97 129.52,56.66 129.58,56.6 129.58,54.36 v1(130.25,53.69) 134.22,49.71 145.23,49.71 v2(145.42,49.52)
  L6 w0.127: v2(143.8,23.39) 143.9,23.28 145.12,23.28 145.53,22.88 147.99,22.88 148.76,22.12 151.7,22.12 153.44,23.86 153.44,26.9 153.93,27.38 153.93,38.82 148.04,44.7 148.04,47.84 147.27,48.61 145.89,48.61 145.42,49.08 v2(145.42,49.52)
  BOTTOM w0.076: 128,65.34 128,65.45 127.74,65.93 127.74,66.87 CPU1.BR34
  BOTTOM w0.127: v2(145.42,49.52) 145.42,49.53 145.36,49.47 143.6,49.47 143.27,49.8 140.93,49.8 140.81,49.68 RN1801.4 140.05,49.42 140.02,49.45 139.56,49.45 139.03,49.98 C1806.1 138.6,49.88 137.7,48.98 ED1801.1 ; v2(128.11,64.86) 128,64.97 128,65.34 ; Q1802.D 140.41,25.42 G1801.2 145.58,25.16 v2(143.8,23.39)
RTC_VCC_C: length 7.7
  TOP w0.508: R2510.2 193.26,42.82 v2(193.23,42.84) v1(191.48,42.18)
  BOTTOM w0.508: RTC1.1 191.47,41.57 192.73,42.84 v2(193.23,42.84)
RTCRST_ON: length 214.7
  TOP w0.102: v2(159.78,20.39) 160.19,20.39 171.64,31.84 171.64,35.45 172.64,36.45 172.64,39.25 172.64,39.25 172.64,39.75 172.64,40.16 173.27,40.78 173.27,42.69 174.03,43.45 174.03,44.26 174.16,44.39 174.16,53.33 174.16,53.55 174.65,54.05 175.2,54.05 175.49,54.34 175.49,54.87 176.77,56.15 177.97,56.15 181.19,59.38 181.19,60.16 182.36,61.32 182.36,61.93 182.87,62.44 184.3,62.44 R2518.1 D2502.K 186.27,62.4 Q2507.G 187.17,63.71 R2567.1
  L4SGND w0.102: v2(141.8,21.48) 143.07,20.21 153.23,20.21 154.8,18.64 158.03,18.64 v2(159.78,20.39)
  L6 w0.102: v2(36.62,16.83) 37.07,16.38 43.02,16.38 44.08,15.31 44.08,13.36 44.9,12.54 49.43,12.54 50.49,13.61 54.02,13.61 54.74,12.89 66.83,12.89 67.77,11.96 75,11.96 75.51,12.46 81.37,12.46 81.85,12.95 85.06,12.95 85.75,12.26 86.46,12.26 86.67,12.06 89.54,12.06 90.2,12.72 90.73,12.72 91.19,12.26 94.15,12.26 95.95,10.46 96.34,10.46 96.38,10.41 105.7,10.41 106,10.41 109.45,13.86 109.46,13.86 114.01,13.86 114.31,13.86 114.31,13.86 118.17,13.86 118.17,13.86 118.79,13.86 119.09,13.86 119.1,13.86 119.14,13.86 119.14,13.86 119.44,13.86 119.44,13.86 119.57,13.86 119.58,13.86 119.74,13.86 120.5,13.86 120.5,13.86 120.81,13.86 122.63,15.69 122.87,15.69 122.91,15.73 123,15.73 124.03,16.76 v2(124.5,16.76)
  BOTTOM w0.102: v2(141.8,21.48) 141.26,21.48 Q1802.G 137.07,25.24 R1816.1 136.54,25.72 EC1804.1 134.96,25.72 v1(134.41,25.18) 133.86,25.18 131.56,22.88 131.23,22.88 128.44,20.08 127.15,20.08 124.5,17.43 v2(124.5,16.76) ; U2401.31 37.34,28.8 36.46,27.93 35.83,27.93 35.01,27.12 35.01,26.71 33.91,25.6 33.9,25.6 33.64,25.34 33.64,23.24 37.15,19.73 37.15,18.05 36.62,17.52 v2(36.62,16.83)
RUNPWROK: length 7.2
  TOP w0.254: v1(33.96,23.77) v2(34.2,24.28) 34.23,24.3 34.74,24.3 R2482.1
  BOTTOM w0.203: U2401.48 38.5,21.99 37.98,22.5
  BOTTOM w0.254: v2(34.2,24.28) 34.3,24.17 34.68,24.17 36.36,22.5 37.98,22.5
SATA_PCIE_LED#: length 147.3
  TOP w0.127: v2(62.53,9.29) 61.79,10.03 v1(61.28,10.03) 61,10.31 46.95,10.31 42.7,14.56 42.7,16.03 R6420.2 42.62,16.85 42.62,17.68 42.89,17.95 v2(43.45,17.95)
  L4SGND w0.127: v2(62.53,9.29) 62.53,9.28 63.79,8.02 64.83,8.02 64.84,8.01 65.32,8.01 68.62,4.7 93.23,4.7 94.14,3.79 105.52,3.79 105.73,3.79 106.21,4.27 113.68,4.27 113.68,4.28 116.31,4.28 117.3,4.28 120.1,7.07 124.22,7.07 124.65,7.07 124.72,7.14 124.87,7.14 125.05,7.32 126.28,7.32 127.34,6.25 127.92,6.25 143.35,6.25 143.7,6.61 150.89,6.61 151.24,6.25 152.19,6.25 152.81,6.88 157.14,6.88 157.76,6.25 173.76,6.25 175.05,4.97 v2(175.49,4.97)
  BOTTOM w0.127: Q6403.S 44.14,17.95 v2(43.45,17.95) ; D6401.3 v2(175.49,4.97)
SD_RCOMP: length 4.6
  TOP w0.508: v2(137.24,66.91) 138.14,67.82 138.14,68.55 v1(138.14,68.55) 138.14,68.7 R1901.1
  BOTTOM w0.254: v2(137.24,66.91) 137.24,67.16 CPU1.CM34 136.68,67.71 CPU1.CK33
SD_READ_MODE#: length 68.5
  TOP w0.102: R2019.1 131.51,73.02 131.81,72.71 131.81,72.08 132.25,71.65 132.25,70.58 133.08,69.74 133.08,64.09 136.98,60.19 136.98,59.12 136.97,59.11 136.97,58.84 136.98,58.83 136.98,58.26 136.72,58 136.72,55.67 136.67,55.62 136.67,55.61 135.73,54.67 135.73,53.03 137.73,51.02 145.28,51.02 146.14,51.88 v1(147.18,51.88) 150.86,51.88 v2(151.3,51.45)
  L4SGND w0.102: v2(156.76,39.9) 156.87,40.01 169.7,40.01 170.14,39.57 v2(170.32,39.57)
  L6 w0.102: v2(151.3,51.45) 151.55,51.2 151.55,50.99 155.47,47.07 155.47,43.47 156.76,42.18 v2(156.76,39.9)
  BOTTOM w0.102: v2(170.32,39.57) 170.15,39.57 170.05,39.67 CN6601.21
SDRAM_ID0: length 18.9
  TOP w0.102: v2(134.48,71.52) v1(133.99,71.18)
  L6 w0.102: v2(147.54,74.49) 147.36,74.67 146.7,74.67 145.5,73.47 145.37,73.34 144.33,73.34 143.89,73.78 140.54,73.78 139.93,73.17 139.23,73.17 138.51,72.45 137.68,72.45 137.52,72.45 137.36,72.45 137.21,72.29 135.26,72.29 v2(134.48,71.52)
  BOTTOM w0.102: CPU1.CF27 134.21,71.79 v2(134.48,71.52) ; R2015.1 147.08,75.41 147.44,75.05 147.44,74.59 v2(147.54,74.49) 147.71,74.67 148.02,74.67 R2016.2
SDRAM_ID1: length 19.9
  TOP w0.102: v1(133.93,69.55) 134.12,69.81 v2(134.48,70.2)
  L6 w0.102: v2(134.48,70.2) 134.96,70.68 134.96,71.61 135.46,72.1 137.29,72.1 137.44,72.26 137.6,72.26 138.84,72.26 139.56,72.98 140.01,72.98 140.6,73.58 143.8,73.58 144.25,73.13 145.45,73.13 146.35,74.03 147.24,74.03 147.27,74.06 147.6,74.06 147.63,74.03 147.79,74.03 147.83,73.99 147.98,73.99 v2(147.99,74.01)
  BOTTOM w0.102: R2017.1 147.36,74.06 147.94,74.06 v2(147.99,74.01) 148.15,74.01 R2018.2 ; v2(134.48,70.2) 134.19,70.49 CPU1.CF29
SDRAM_ID2: length 16.8
  L6 w0.102: v2(135.38,71.46) 135.84,71.91 137.37,71.91 137.52,72.07 138.92,72.07 139.64,72.79 140.09,72.79 140.67,73.37 143.69,73.37 144.41,72.66 145.26,72.66 146.38,73.78 147.26,73.78 147.38,73.65 v2(147.44,73.65)
  BOTTOM w0.102: R2022.1 147.21,73.83 147.38,73.65 v2(147.44,73.65) 147.44,73.55 v1(147.82,73.17) 148.45,73.81 R2029.2 ; CPU1.CH27 135.05,71.79 v2(135.38,71.46)
SDRAM_ID3: length 18.2
  TOP w0.102: v2(135.42,70.78) v1(134.97,70.46)
  L6 w0.102: v2(147.99,72.08) 147.99,72.66 147.64,73.02 145.91,73.02 145.35,72.45 144.33,72.45 143.61,73.17 142.83,73.17 142.82,73.18 142.82,73.17 140.74,73.17 140.16,72.6 139.72,72.6 138.92,71.8 137.52,71.8 137.44,71.72 136.12,71.72 135.95,71.56 135.95,71.32 v2(135.42,70.78)
  BOTTOM w0.102: CPU1.CH28 135.06,71.14 v2(135.42,70.78) ; R2011.2 148.15,72.23 v2(147.99,72.08) 146.95,72.08 R2012.1
SDRAM_ID4: length 16.9
  TOP w0.102: v1(135.95,69.69) v2(136.41,70.05)
  L6 w0.102: v2(136.41,70.05) 137.71,70.05 139.64,71.98 142.58,71.98 142.65,72.05 145.51,72.05 145.53,72.06 147.44,72.06 147.83,71.67 148.17,71.67 v2(149.14,70.71)
  BOTTOM w0.102: v2(136.41,70.05) 136.21,69.84 CPU1.CJ30 ; v2(149.14,70.71) 149.01,70.58 R2013.2 R2014.1
SIO_EXT_SCI#: length 13.3
  BOTTOM w0.076: 140.95,84.03 138.98,84.03 arc(138.89,84.01) 138.82,83.96 138.63,83.78 CPU1.CP8
  BOTTOM w0.089: R1608.2 149.4,85.73 v1(149.26,85.59) 149.18,85.67 143.05,85.67 142.91,85.54 142.74,85.54 142.09,84.89 141.81,84.89 140.95,84.03
SIO_EXT_SMI#: length 13.2
  BOTTOM w0.102: CPU1.CP7 140.39,84.43 141.77,85.81 142.8,85.81 142.94,85.95 148.96,85.95 149.77,86.76 v1(149.95,86.76) 150.59,86.76 R402.1
SIO_EXT_WAKE#: length 228.6
  TOP w0.102: v1(142.13,80.43) v2(141.59,80.72) 141.44,80.56 R2041.2
  L4SGND w0.102: v2(20.36,22.98) 18.95,22.98 17.88,24.05 17.88,29.07 17.78,29.18 17.78,38.48 18.81,39.5 18.81,46.66 18.63,46.84 18.63,49.45 18.87,49.69 18.87,53.78 17.84,54.81 17.84,62.89 18.88,63.92 24.5,63.92 26.02,65.45 26.02,70.36 27.85,72.19 27.85,75.84 27.82,75.87 27.82,90.77 27.42,91.17 27.42,94.07 28.01,94.66 28.84,94.66 34.96,100.78 48.1,100.78 49.58,102.26 83.11,102.26 84.68,103.83 103.06,103.83 105.55,101.34 126.92,101.34 127.84,102.25 131.78,102.25 132.7,101.33 132.7,97.3 134.35,95.65 136.36,95.65 139.56,92.44 139.56,89.47 139.89,89.14 139.89,87.28 141.48,85.69 142.09,85.69 142.33,85.45 142.33,81.45 v2(141.59,80.72)
  BOTTOM w0.076: CPU1.CN12 138.09,80.99 138.66,80.99 138.73,80.92 arc(138.98,80.74) 139.28,80.67 139.31,80.67 139.49,80.49 141.36,80.49 v2(141.59,80.72)
  BOTTOM w0.102: U2401.116 22.58,23.19 22.57,23.18 21.55,23.18 21.3,22.93 20.94,22.93 20.84,23.03 20.36,23.03 v2(20.36,22.98)
SIO_PWRBTN#: length 133.2
  TOP w0.102: v2(129.02,70.9) 129.02,70.78 129.45,70.35 129.45,68.66 129.27,68.47 129.27,67.12 127.7,65.55 127.7,63.15 127.72,63.12 127.72,59.66 128.18,59.2 128.18,58.92 128.18,58.45 v2(128.44,58.19)
  L4SGND w0.102: v2(37.12,21.1) 37.55,21.53 37.91,21.53 38.3,21.92 38.3,28.85 41.01,31.56 41.01,38.82 48.77,46.59 48.88,46.59 52.73,50.44 v2(55.64,50.44)
  BOTTOM w0.102: CPU1.BU28 128.79,71.14 129.02,70.91 v2(129.02,70.9) ; v2(37.12,21.1) 37.76,20.47 38.27,20.47 38.34,20.39 U2401.52 ; v2(55.64,50.44) 57.38,50.44 v1(57.42,50.48) 58.88,50.48 59.32,50.92 60.32,50.92 60.77,51.36 63.84,51.36 65.37,52.9 84.74,52.9 86.08,54.25 104.05,54.25 104.95,53.35 119.9,53.35 121.24,54.68 124.65,54.68 124.66,54.69 125.39,54.69 126.3,55.59 126.3,56.68 TP1714.1 127.39,57.77 127.83,57.77 128.22,58.16 128.42,58.16 v2(128.44,58.19)
SIO_RCIN#: length 13
  TOP w0.089: v2(129.88,70.15) 130.34,69.69 130.34,69.16 v1(130.34,69.16) 130.34,69.16 130.34,69.08 130.33,69.07 130.33,65.54 129.53,64.74 129.53,61.48 130.8,60.22 R1820.2
  BOTTOM w0.089: CPU1.BV29 129.54,70.49 v2(129.88,70.15)
SKTOCC#: length 7
  BOTTOM w0.102: CPU1.E1 96.76,88.31 96.76,88.84 96.48,89.12 92.98,89.12 91.78,87.93 TP619.1
SKU_ID: length 4.8
  BOTTOM w0.102: U2401.109 22.84,20.39 v1(22.16,19.71) 21.45,18.99 R2442.2 20.74,18.99 C2407.1 R2441.1
SLEEVE_R:
  vias: v1(179.92,40.33) v3(179.49,39.41)
SM_DRAMRST#: length 160.1
  TOP w0.089: v2(144.57,51.63) 143.47,52.73 v1(143.47,53) 143.3,53.17 143.3,53.72 143.02,54 143.01,54 142.22,54.79 142.22,54.8 141.97,55.05 141.11,55.05 140.86,54.81 139.82,54.81 139.62,55.01 C501.1 138.11,57.02 R504.2
  L4SGND w0.089: v2(144.57,51.63) 144.57,49.72 146.63,47.66 146.63,47.65 146.68,47.6 146.68,47.59 146.93,47.34 146.93,47.34 147.14,47.14 147.14,40.85 149.76,38.23 151.16,38.23 151.53,37.87 151.53,37.35 151.33,37.15 151.33,30.74 149.95,29.37 144.07,29.37 v2(143.68,29.75)
  L6 w0.089: v2(62.44,29.48) 62.54,29.38 72.49,29.38 v2(72.59,29.48) 82.59,29.48 82.97,29.86 v2(83.1,29.86) 83.55,29.41 93.1,29.41 v2(93.36,29.66) 93.86,29.16 105.64,29.16 114.68,29.16 v2(115.41,29.89) 115.99,29.3 124.95,29.3 v2(125,29.36) v2(135.01,29.36) 143.29,29.36 v2(143.68,29.75)
  BOTTOM w0.089: v2(83.1,29.86) 83.1,30.75 82.11,31.74 81.61,31.74 81.44,31.91 81.44,32.54 RAM2.P1 ; v2(115.41,29.89) 115.41,30.41 114.15,31.66 113.93,31.66 113.64,31.95 113.64,32.54 RAM6.P1 ; v2(135.01,29.36) 135.01,31.1 134.45,31.66 134.23,31.66 133.94,31.95 133.94,32.54 RAM8.P1 ; RAM1.P1 91.6,32.55 91.6,31.96 91.81,31.75 91.99,31.75 93.36,30.39 v2(93.36,29.66) ; v2(72.59,29.48) 72.59,30.98 71.84,31.74 71.8,31.74 71.77,31.75 71.51,31.75 71.32,31.94 71.29,31.95 71.29,32.54 RAM3.P1 ; RAM5.P1 123.79,32.54 123.79,31.95 124.08,31.66 124.3,31.66 124.91,31.05 124.91,30.49 125,30.4 v2(125,29.36) ; RAM4.P1 61.14,32.54 61.14,31.88 61.37,31.66 61.75,31.66 62.44,30.96 v2(62.44,29.48) ; v2(143.68,29.75) 143.97,29.75 144.46,30.24 144.9,30.24 145.16,30.49 145.16,31.1 144.6,31.66 144.38,31.66 144.09,31.95 144.09,32.54 RAM7.P1
SM_DRAMRST#_CPU: length 21.6
  TOP w0.089: R505.2 R504.1 137.33,57.78 v2(137.25,57.85) v1(138.88,57.83)
  L6 w0.089: v2(137.25,57.85) 137.25,58.01 135.36,59.89 131.81,59.89 131.01,60.69 131,60.71 130.88,60.8 129.58,62.1 128.97,62.71 128.97,66.92 129.2,67.15 129.2,68.29 129.06,68.43 128.88,68.43 128.65,68.66 128.65,69.16 v2(129.02,69.54)
  BOTTOM w0.089: CPU1.BU31 128.67,69.19 v2(129.02,69.54)
SM_INTRUDER#: length 28.9
  TOP w0.102: v1(146.52,55.72) R1730.2 146.22,54.6 v2(146.22,54.12)
  L6 w0.102: v2(146.22,54.12) 143.83,54.12 143.51,54.43 142.45,54.43 139.76,57.12 136.11,57.12 133.84,59.38 131.73,59.38 129.7,61.41 128.13,61.41 127.22,62.32 127.22,64.42 v2(127.07,64.57)
  BOTTOM w0.076: CPU1.BR35 127.44,66.76 127.1,66.43 127.1,65.85 arc(127.04,65.74) 127.02,65.63 127.02,65.24 127.17,65.09 127.17,64.66 v2(127.07,64.57)
SM_PGCNTL: length 23.4
  BOTTOM w0.127: CPU1.C35 95.38,67.13 94.66,67.13 94.51,66.98 94.21,66.98 87.14,59.91 v1(77.15,59.91) 76.52,59.91 75.91,60.52 Q501.G
SM_RCOMP_0: length 2.5
  TOP w0.254: R501.1 126.84,72.28 126.84,71.16 126.53,70.86 126.33,70.86 126.3,70.83 126.3,70.83 v2(126.33,70.83)
  BOTTOM w0.203: CPU1.BN28 125.99,71.14 126.3,70.83 126.3,70.83 v2(126.33,70.83)
SM_RCOMP_1: length 1.4
  TOP w0.254: R502.1 126.31,72.02 126.31,71.51 v2(126.33,71.49)
  BOTTOM w0.203: v2(126.33,71.49) 126.32,71.51 126.32,71.53 126.06,71.79 CPU1.BN27
SM_RCOMP_2: length 2.9
  TOP w0.254: v2(126.28,70.22) 126.26,70.22 125.85,70.63 125.85,71.29 125.85,71.29 125.85,71.67 125.36,72.15 R503.1
  BOTTOM w0.203: CPU1.BN29 125.98,70.49 126.26,70.22 v2(126.28,70.22)
SPI_CLK_CPU: length 12.3
  BOTTOM w0.089: R2508.2 139.23,58.82 139.23,60.95 R9138.1 138.62,61.56 138.62,61.84 138.75,61.97 139.15,61.97 139.23,62.04 139.23,62.25 138.93,62.55 v1(138.16,62.55) 137.16,62.55 137.02,62.69 137.02,63.02 136.93,63.11 136.73,63.11 136.64,63.02 136.64,62.68 136.51,62.55 136.3,62.55 136.21,62.64 136.21,63.21 136.46,63.47 136.46,63.67 136.21,63.92 134.99,65.14 CPU1.CH37
SPI_CLK_HDMI: length 14.4
  TOP w0.089: U5701.D2 24.51,88.83 24.51,89.93 v2(25.22,90.64)
  BOTTOM w0.089: FC5701.1 R5743.2 33.9,86.25 U5702.6 32.23,86.25 29.73,88.75 29.73,89.16 28.47,90.42 27.29,90.42 27.04,90.67 26.55,90.67 26.35,90.87 v1(25.97,90.87) 25.45,90.87 v2(25.22,90.64)
SPI_CLK_PD: length 11.5
  TOP w0.089: U7201.A3 13.35,31.56 13.72,31.2 v1(13.72,30.68) 13.74,30.65 13.74,28.63 v2(13.27,28.16)
  BOTTOM w0.089: U7202.6 17.21,25.42 16.7,25.93 16.7,27.85 16.34,28.21 13.32,28.21 v2(13.27,28.16)
SPI_CLK_ROM: length 16.2
  BOTTOM w0.089: BIOS1.6 143.22,56.03 143.12,55.92 143.12,55.62 143.02,55.52 142.36,55.52 142.25,55.62 142.25,56.25 142.08,56.43 141.91,56.43 141.77,56.29 141.77,55.64 141.67,55.54 141.39,55.54 141.29,55.64 141.29,55.85 141.19,55.95 140.87,55.95 140.81,55.89 140.81,55.43 140.51,55.14 138.62,55.14 138.53,55.23 v1(138.53,55.8) 138.53,55.9 138.6,55.97 139.27,55.97 139.61,55.64 140.04,55.64 140.29,55.89 140.29,56.55 EC2503.1 140.83,56.69 140.93,56.79 140.93,57.07 140.81,57.19 140.09,57.19 139.99,57.3 139.99,57.93 139.89,58.03 139.59,58.03 139.49,57.93 139.49,57.75 139.36,57.63 R2508.1
SPI_CLK_TPM: length 49.3
  TOP w0.089: U9102.19 179.5,49.92 v2(178.47,50.95) 178.52,50.95 v1(178.91,51.33)
  L4SGND w0.089: v2(178.47,50.95) 178.47,50.95 176.75,52.67 176.75,55.28 175.9,56.14 166.39,56.14 164.88,57.65 162.14,57.65 161.79,57.3 156.27,57.3 155.27,56.29 147.91,56.29 146.04,58.16 144.87,58.16 144.01,59.02 139.43,59.02 v2(138.82,59.63)
  BOTTOM w0.089: R9138.2 v2(138.82,59.63)
SPI_CS2_TPM: length 5.4
  TOP w0.089: U9102.20 179.32,49.42 178.96,49.78 v1(178.96,49.83) 178.93,49.83 178.44,50.31 178.14,50.31 R9140.2 R9148.2 176.8,49.9 177.2,49.5 177.2,49.07 R9130.2
SPI_CS_CPU_N0: length 26.3
  BOTTOM w0.076: CPU1.CG36 134.34,65.95 134.88,66.49 135.1,66.49 135.31,66.28 135.31,65.9 135.6,65.36 135.6,65.14
  BOTTOM w0.089: 135.6,65.14 136.11,64.64 136.82,64.64 138.39,63.06 140.18,63.06 141.06,62.18 141.06,61.56 141.26,61.36 v1(141.26,60.17) 141.26,59.71 141.59,59.38 143.17,59.38 143.63,59.84 148.91,59.84 149.37,59.38 152.82,59.38 153.12,59.07 152.62,58.57 BIOS1.1
SPI_CS_CPU_N2: length 59.1
  TOP w0.089: v2(178.39,49.65) 178.39,49.34 177.99,48.94 R9130.1 177.71,49.17 v1(177.71,49.88)
  L4SGND w0.089: v2(135.54,67.31) 135.54,63.89 139.92,59.5 146.67,59.5 149.42,56.76 155.07,56.76 156.08,57.76 161.42,57.76 161.77,58.12 165.08,58.12 166.58,56.61 176.09,56.61 177.22,55.48 177.22,52.86 178.94,51.14 178.94,50.2 v2(178.39,49.65)
  BOTTOM w0.089: v2(135.54,67.31) 135.54,67.31 135.35,67.5 CPU1.CH34
SPI_CS_HDMI: length 14.4
  TOP w0.089: R5740.1 24.65,91.89 25.62,90.92 25.62,90.24 v2(25.31,89.93) 24.99,89.61 U5701.C1
  BOTTOM w0.089: U5702.1 28.74,83.71 29.26,84.23 29.26,88.96 v1(28.54,89.68) 28.41,89.68 28.15,89.95 27.1,89.95 26.84,90.2 26.36,90.2 26.2,90.36 25.74,90.36 v2(25.31,89.93)
SPI_CS_PD: length 14.9
  TOP w0.089: v2(15.15,26.82) 14.74,26.82 14.05,27.5 v1(13.91,27.5) 14.21,27.81 14.21,31.04 13.59,31.67 13.59,32.7 U7201.B3
  BOTTOM w0.089: v2(15.15,26.82) 15.15,25.8 13.96,24.61 13.96,22.27 R7228.1 12.93,21.98 U7202.1
SPI_HOLD_CPU: length 26.7
  BOTTOM w0.089: R2503.2 154.06,58.29 154.36,58.58 v1(154.36,59.99) 154.36,60.21 154.15,60.42 144.34,60.42 143.22,61.54 R1510.2 141.8,61.54 141.62,61.71 R1511.2 140.73,63.24 138.49,63.24 136.74,64.98 136.74,65.3 136.08,65.96 136.06,65.96 135.88,66.14 135.88,66.73 135.72,66.9 135.35,66.9 135.08,67.17 CPU1.CG34
SPI_HOLD_HDMI: length 1.5
  BOTTOM w0.089: U5702.7 33.74,84.98 R5742.1
SPI_HOLD_PD: length 3.9
  BOTTOM w0.089: R7226.1 18.38,21.7 19.07,22.4 v1(19.26,22.4) 18.82,22.84 18.82,23.27 18.81,23.27 18.81,23.79 18.45,24.15 U7202.7
SPI_HOLD_ROM: length 9.2
  BOTTOM w0.089: BIOS1.7 144.84,57.3 145.46,57.91 152.28,57.91 152.79,57.4 R2503.1
SPI_IRQ#_TPM2: length 5.4
  TOP w0.089: U9102.18 179.67,50.42 179.26,50.82 179.26,51.83 v1(178.55,52.55) 177.71,52.55 R9149.1 R9137.2 R9139.2
SPI_SI_CPU: length 8.4
  BOTTOM w0.076: CPU1.CF36 133.51,66.02 133.51,65.84 133.43,65.62 133.43,65.39 133.65,65.17 134.41,65.17 134.68,64.89
  BOTTOM w0.089: R9133.1 137.25,61.87 135.4,61.87 135.4,62.3 135.58,62.49 v1(135.58,63.09) 135.58,63.99 134.68,64.89
SPI_SI_HDMI: length 11.7
  TOP w0.089: U5701.D1 24.19,90.21 24.8,90.82 24.8,91.12 v2(24.81,91.12)
  BOTTOM w0.089: v2(24.81,91.12) 25.03,91.34 26.54,91.34 26.75,91.14 27.23,91.14 27.49,90.89 28.66,90.89 30.2,89.35 30.2,89.34 v1(30.5,89.04) 32.02,87.52 U5702.5
SPI_SI_PD: length 10.6
  TOP w0.089: U7201.B4 13.09,32.7 13.09,31.39 13.25,31.23 v1(13.25,29.53) 13.25,28.95 v2(13.27,28.92)
  BOTTOM w0.089: U7202.5 17.88,28.12 17.07,28.92 v2(13.27,28.92)
SPI_SI_ROM: length 22.8
  BOTTOM w0.089: R2509.1 136.69,60.72 136.69,60.29 136.79,60.19 137.17,60.19 137.24,60.13 137.24,59.85 137.15,59.76 136.78,59.76 136.69,59.67 136.69,59.4 136.79,59.3 137.19,59.3 137.28,59.21 137.28,59.05 137.15,58.93 136.02,58.93 135.93,58.84 135.93,58.66 136.02,58.57 136.98,58.57 137.1,58.46 137.1,58.3 137.01,58.22 136.01,58.22 135.92,58.13 135.92,57.92 135.98,57.86 136.68,57.86 136.77,57.77 136.77,57.59 136.68,57.5 135.99,57.5 135.9,57.42 135.9,57.25 136.06,57.1 136.65,57.1 136.74,57.01 136.74,56.83 136.65,56.74 135.98,56.74 135.9,56.65 135.9,56.37 135.98,56.28 136.55,56.28 136.64,56.19 136.64,56 v1(136.39,55.75) 136.39,55.54 136.59,55.34 137.35,55.34 EC2501.1 138.4,54.3 140.78,54.3 140.96,54.47 140.96,54.54 141.21,54.8 141.57,54.8 141.61,54.76 BIOS1.5
SPI_SI_TPM: length 49.9
  TOP w0.089: v2(178.5,48.3) 178.73,48.3 179,48.57 v1(179.01,48.57) 179.02,48.58 179.02,48.6 179.34,48.92 U9102.21
  L4SGND w0.089: v2(137.78,59.78) 139.51,58.06 140.04,57.92 142.07,57.92 144.99,56.94 147.69,55.82 161.28,55.82 162.73,54.37 164.04,54.37 164.73,55.06 164.88,55.22 172.15,55.22 172.15,55.22 173.02,55.22 175.24,55.22 175.39,55.06 176.28,54.17 176.28,52.2 176.83,51.65 v2(178.5,48.3)
  BOTTOM w0.089: v2(137.78,59.78) 137.76,59.81 R9133.2
SPI_SO_CPU: length 13.3
  BOTTOM w0.089: CPU1.CF37 133.69,65.46 133.78,65.37 134.51,65.37 135.95,63.93 135.95,62.45 136.08,62.32 137.55,62.32 138.32,61.56 138.32,59.66 137.68,59.02 v1(137.68,58.69) 137.68,57.19 R9132.1 138.09,56.74 R2506.1
SPI_SO_HDMI: length 10.1
  TOP w0.089: v2(26.02,89.93) 25.89,89.93 25.74,89.78 25.74,89.76 25.49,89.51 25.46,89.51 25.38,89.42 25.38,88.89 U5701.C2
  BOTTOM w0.089: U5702.2 28.49,84.98 28.99,85.48 28.99,88.73 28.04,89.68 26.87,89.68 v1(26.72,89.83) 26.61,89.93 v2(26.02,89.93)
SPI_SO_PD: length 11.6
  TOP w0.089: U7201.A4 12.85,31.88 12.82,31.85 12.82,31.02 12.91,30.93 12.91,30.58 12.82,30.49 v1(12.82,26.84) 12.85,26.82 v2(14.14,26.82)
  BOTTOM w0.089: R7230.1 U7202.2 12.98,24.15 14.14,25.3 v2(14.14,26.82)
SPI_SO_ROM: length 22.4
  BOTTOM w0.089: R2506.2 137.47,55.87 137.66,55.68 137.66,55.67 138.06,55.27 138.06,55.04 138.43,54.67 v1(139.39,54.67) 140.7,54.67 141.1,55.07 141.68,55.07 141.72,55.02 143.2,55.02 143.57,55.39 145.15,55.39 145.91,54.63 147.59,54.63 148.12,54.09 152.87,54.09 153.66,54.88 153.66,55.87 153.53,56 EC2502.1 153.1,56.38 152.19,57.3 BIOS1.2
SPI_SO_TPM: length 49.8
  TOP w0.089: U9102.24 179.54,47.03 v1(178.96,47.03) 178.96,47.04 178.82,47.19 v2(178.42,47.19)
  L4SGND w0.089: v2(178.42,47.19) 176.02,51.78 176.02,54.06 175.13,54.95 172.91,54.95 172.9,54.95 172.26,54.95 165,54.95 164.15,54.11 162.62,54.11 161.17,55.55 144.89,55.55 141.03,57.65 139.94,57.65 138.43,58.1 v2(138.19,58.34)
  BOTTOM w0.089: R9132.2 138.11,58.26 v2(138.19,58.34)
SPI_WP_CPU: length 13
  BOTTOM w0.076: CPU1.CF34 133.94,67.24 133.95,67.22 133.95,65.85 134.23,65.57 134.53,65.57 134.81,65.85 135.12,65.85 135.17,65.81 135.25,65.66 135.25,65.16
  BOTTOM w0.089: R2507.1 v1(139.71,59.78) 139.71,61.08 R1508.2 R1509.2 139.74,61.99 138.85,62.88 138.27,62.88 136.81,64.34 136.07,64.34 135.25,65.16
SPI_WP_HDMI: length 12.7
  TOP w0.089: U5701.E2 23.79,88.91 23.79,90.41 v2(24.16,90.78) 23.86,91.08 R5741.1
  BOTTOM w0.089: U5702.3 28.49,86.25 28.72,86.49 28.72,88.62 27.94,89.4 25.17,89.4 v1(24.6,89.96) 24.16,90.41 v2(24.16,90.78)
SPI_WP_PD: length 2.7
  BOTTOM w0.089: v1(11.05,25.78) 11.05,25.38 R7225.1 12.03,25.42 U7202.3
SPI_WP_ROM: length 20.5
  BOTTOM w0.089: R2507.2 141.38,58.16 141.48,58.06 141.48,57.89 141.38,57.79 141.29,57.79 141.18,57.69 141.18,57.49 v1(141.29,57.39) 141.86,57.39 142.61,56.64 144.94,56.64 144.97,56.61 145.84,56.61 146.14,56.31 146.14,55.48 146.23,55.39 146.41,55.39 146.49,55.48 146.49,56.06 146.58,56.15 146.76,56.15 146.85,56.06 146.85,55.48 146.94,55.39 147.12,55.39 147.21,55.48 147.21,56.06 147.29,56.15 147.47,56.15 147.56,56.06 147.56,55.48 147.65,55.39 147.83,55.39 147.92,55.48 147.92,56.06 148.01,56.15 148.18,56.15 148.27,56.06 148.27,55.48 148.36,55.39 148.54,55.39 148.63,55.48 148.63,56.06 148.72,56.15 148.89,56.15 148.98,56.06 148.98,55.48 149.07,55.39 149.25,55.39 149.34,55.48 149.34,56.06 149.43,56.15 149.61,56.15 149.69,56.06 149.69,55.48 149.78,55.39 149.96,55.39 150.05,55.48 150.05,56.06 150.14,56.15 150.28,56.15 150.41,56.03 BIOS1.3
SPK_ID: length 257.4
  TOP w0.102: v2(155.64,28.67) 156.07,29.1 156.07,29.81 157.9,31.64 157.9,41.58 158.36,42.04 158.36,42.87 157.95,43.27 157.95,46.88 157.68,47.15 157.68,50.7 157.7,50.73 157.7,56.1 157.83,56.23 157.83,66.85 158.37,67.39 158.37,67.53 158.72,67.88 158.72,71.69 159.4,72.37 159.4,75.28 159.98,75.86 159.98,76.22 159.35,76.85 159.35,80.42 156.92,82.85 v2(156.22,82.85) 155.66,82.29 155.21,82.29 R2110.2
  L4SGND w0.102: v2(155.64,28.67) 155.21,28.24 152.06,28.24 151.58,27.75 142.91,27.75 142.59,27.44 140.6,27.44 139.1,25.94 134.57,25.94 133.95,25.32 v2(133.95,23.08) ; v2(12.03,13.4) 11.65,13.02 11.65,10.76 13.3,9.11 20.74,9.11 21.42,8.43 28.72,8.43 32.12,5.02 32.12,3.08 32.52,2.69 52.68,2.69 55.6,5.61 64.27,5.61 67.24,2.63 67.7,2.63 68.14,2.2 107.76,2.2 108.47,2.91 122.44,2.91 122.67,3.14 122.9,3.14 v2(124.7,1.34)
  BOTTOM w0.102: v2(133.95,23.08) 133.95,22.22 131.9,20.17 131.79,20.17 131.79,20.17 130.37,20.17 129.78,19.59 129.77,19.59 v1(129.34,19.16) 127.29,17.11 126.17,17.11 125.72,16.66 125.72,15.73 125.27,15.29 125.27,10.88 124.45,10.05 124.45,9.88 124.45,1.59 v2(124.7,1.34) ; CPU1.CR14 139.11,79.96 142.08,79.96 142.53,80.41 146.82,80.41 149.69,83.28 153.69,83.28 154.48,82.49 155.87,82.49 v2(156.22,82.85) ; SPK1.6 11.7,13.08 v2(12.03,13.4)
SPK_SCL_CODEC: length 3.9
  BOTTOM w0.089: U2701.7 172.18,19.52 171.73,19.96 171.5,20.2 171.36,20.2 ; 171.36,20.2 v1(171.36,20.36) ; 171.36,20.2 169.85,20.2 169.71,20.34 RN2703.1
SPK_SDA_CODEC: length 4.1
  BOTTOM w0.089: 170.24,20.01 171.42,20.01 172.31,19.12 U2701.6 ; 170.24,20.01 169.94,20.01 169.6,19.67 RN2703.2 ; 170.24,20.01 v1(170.24,19.83)
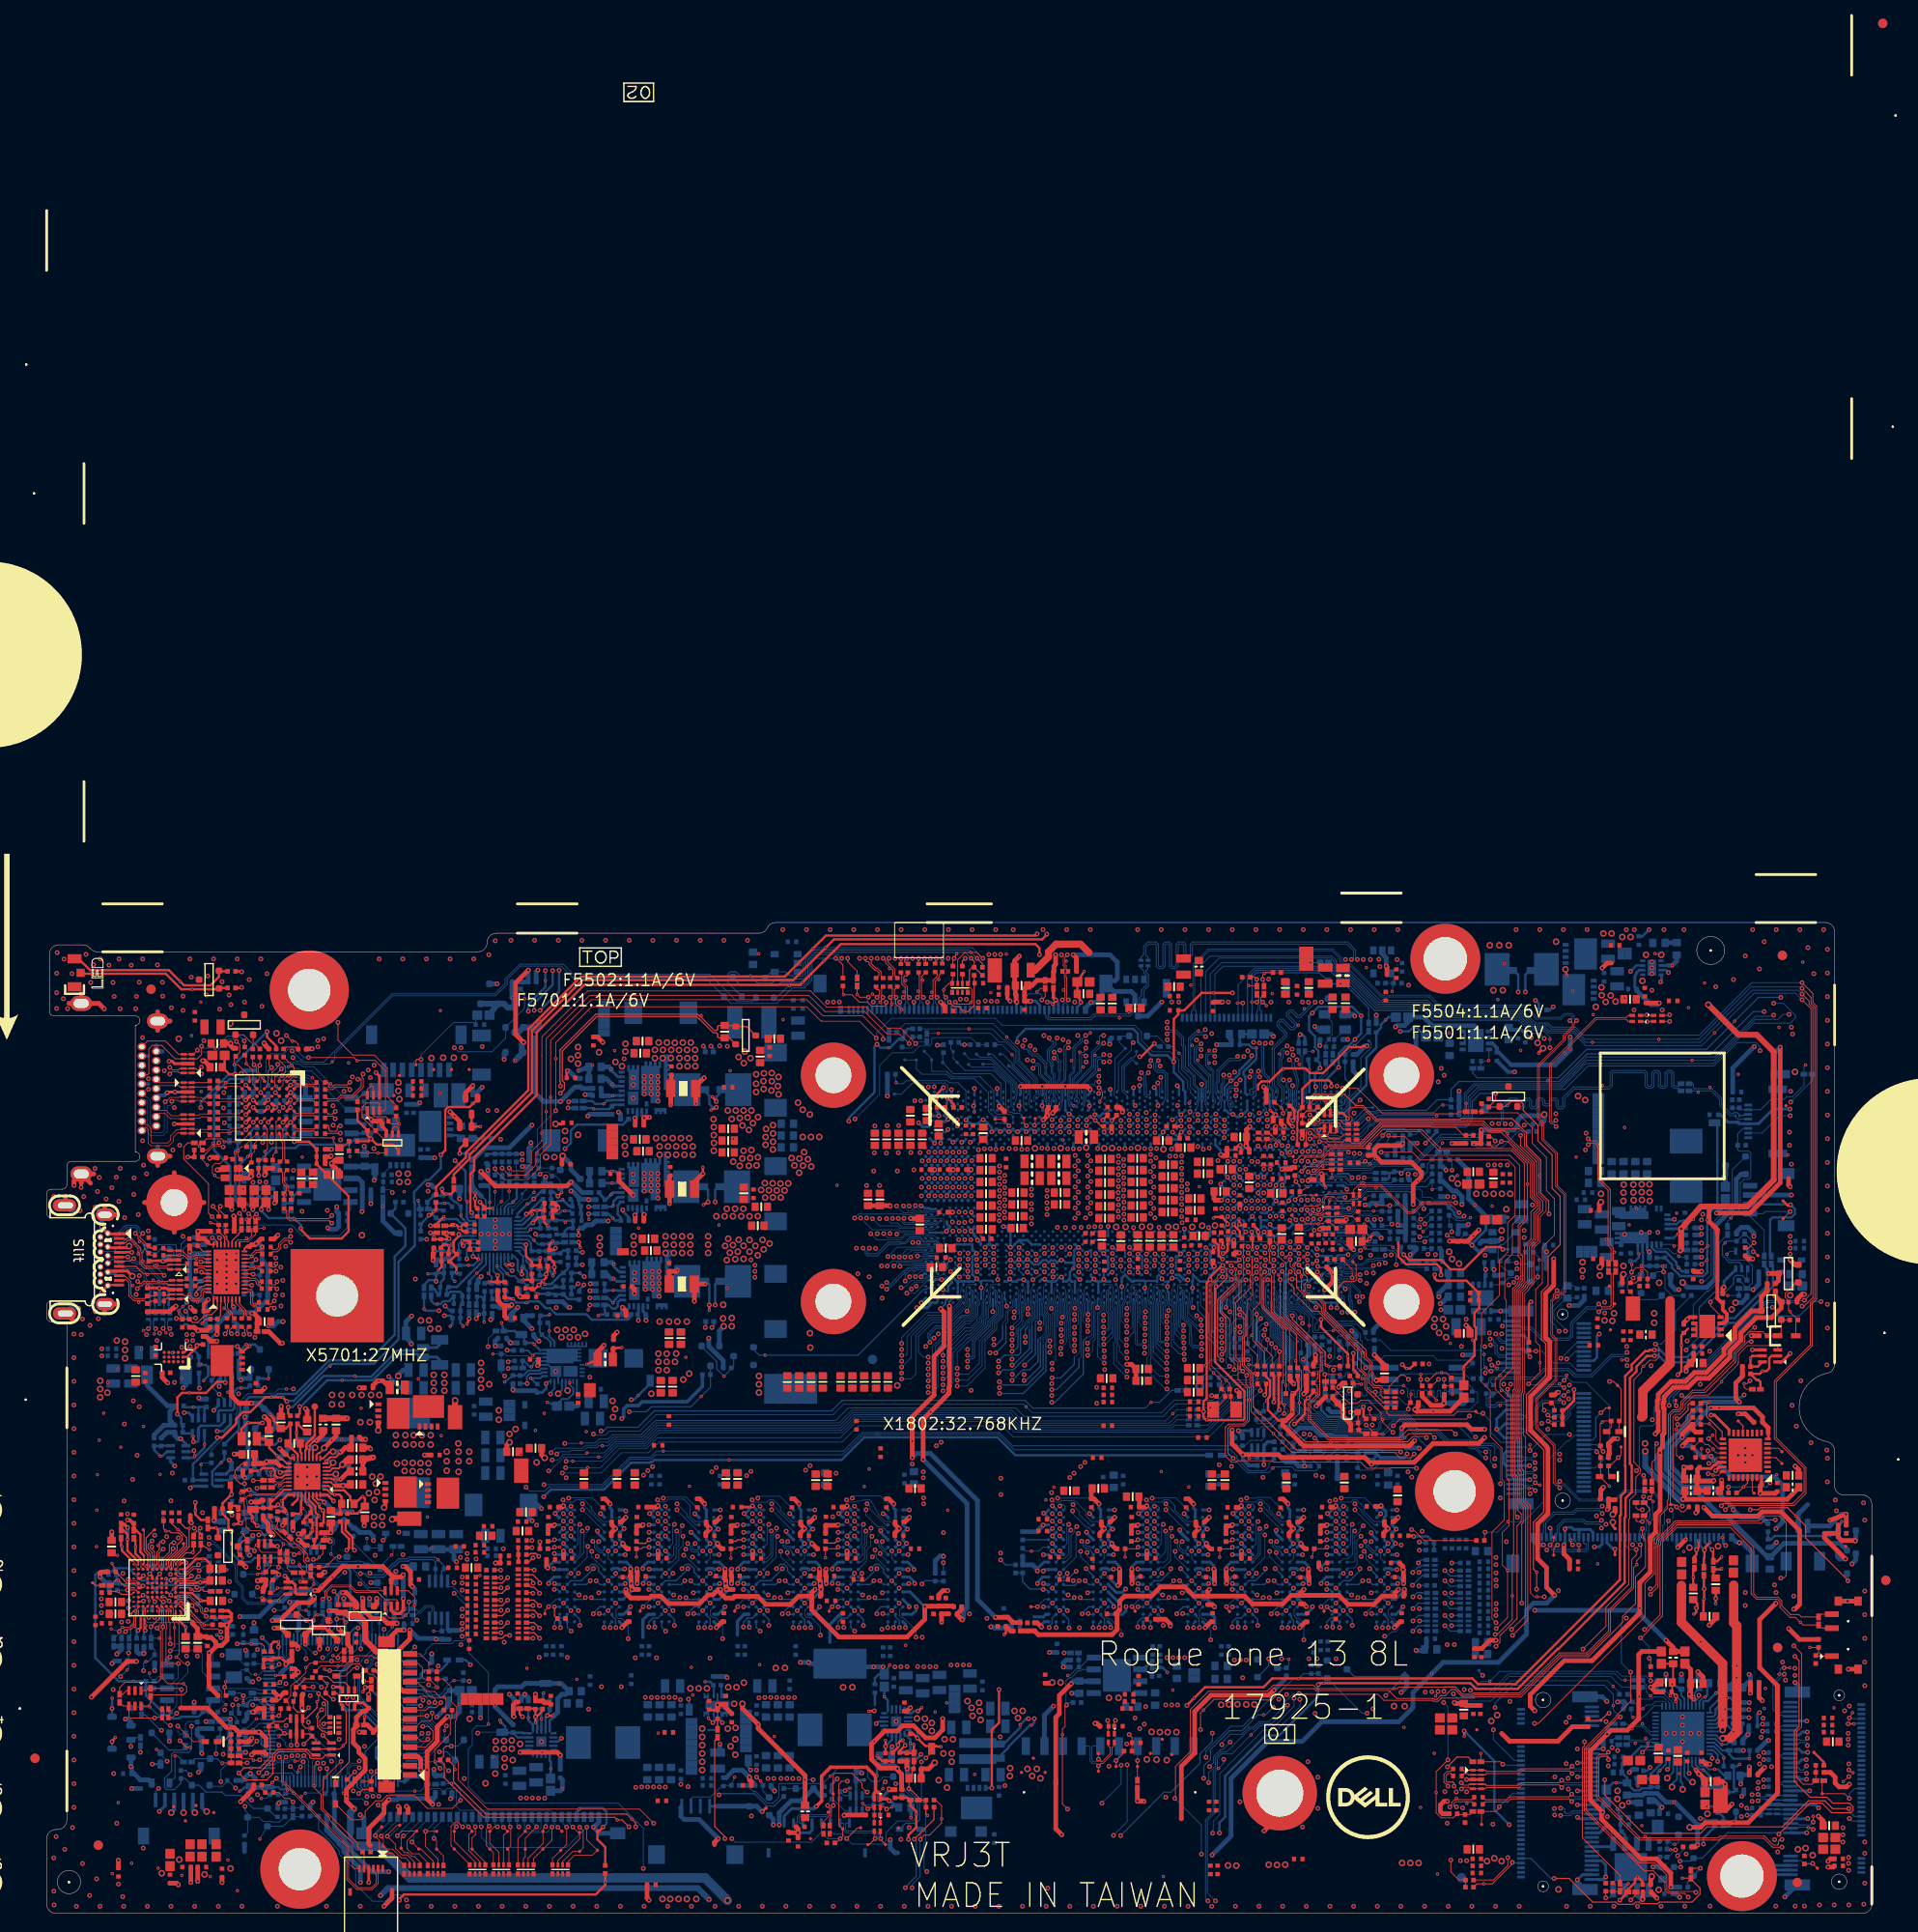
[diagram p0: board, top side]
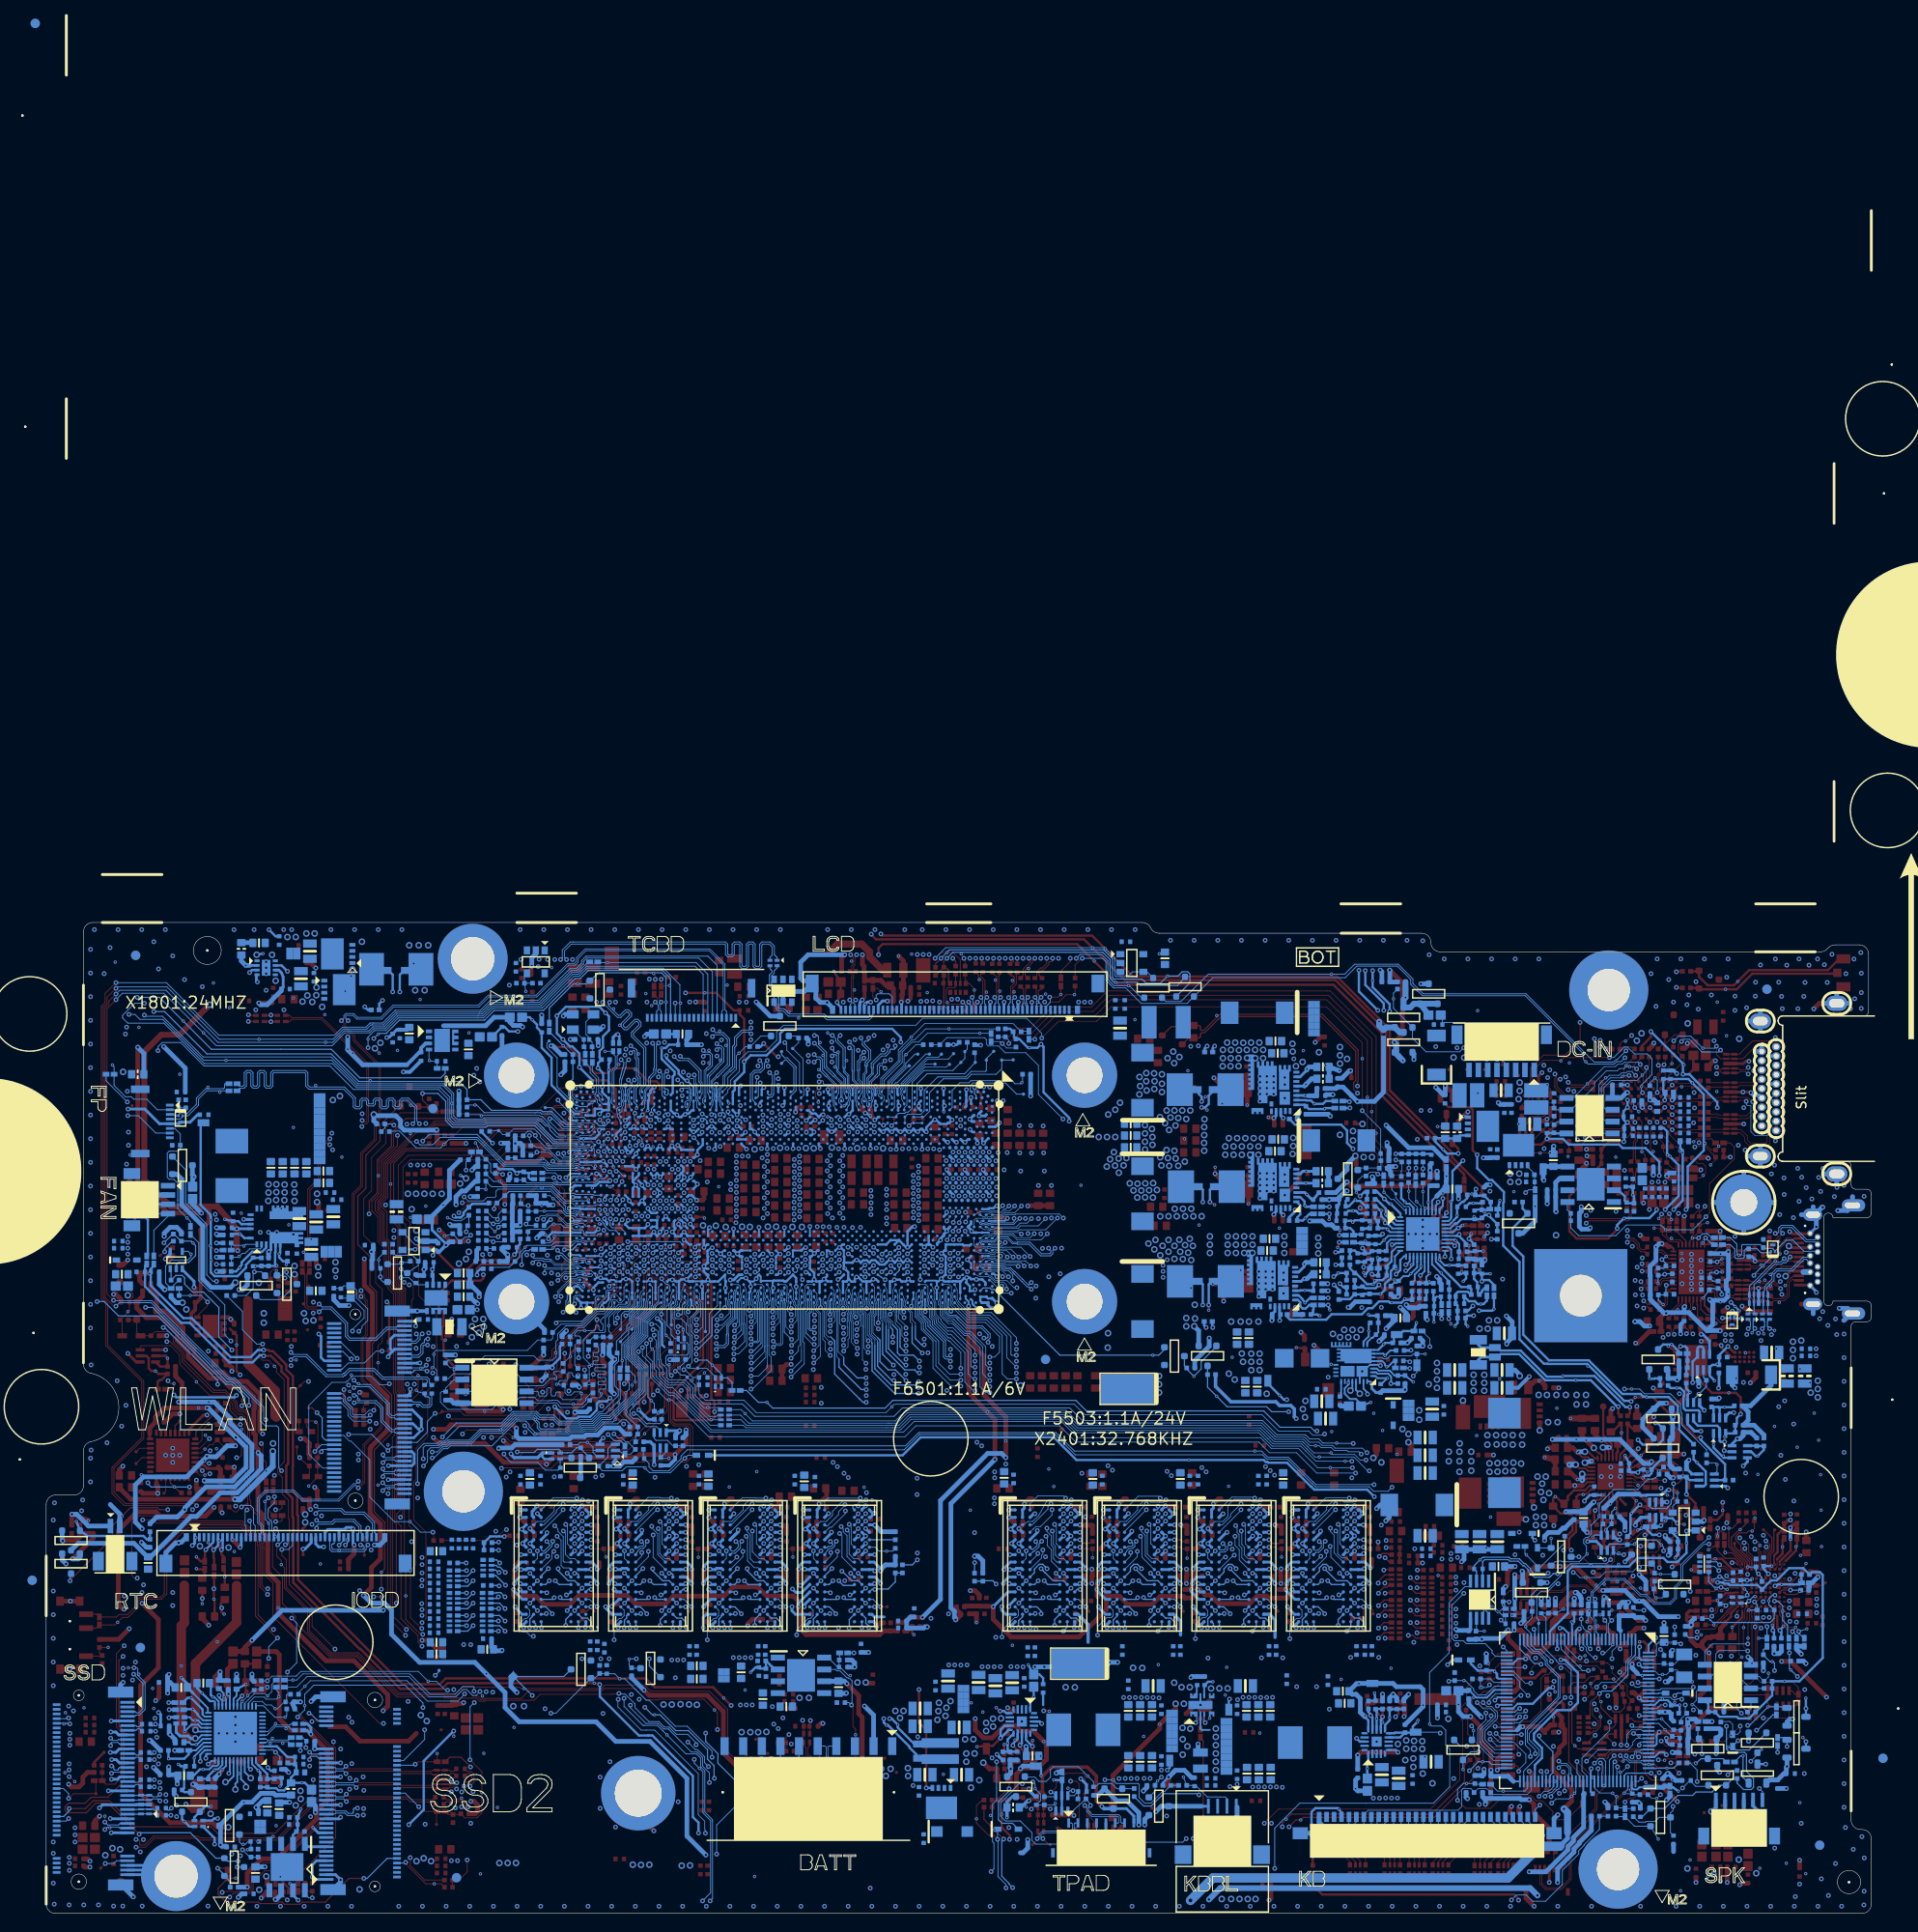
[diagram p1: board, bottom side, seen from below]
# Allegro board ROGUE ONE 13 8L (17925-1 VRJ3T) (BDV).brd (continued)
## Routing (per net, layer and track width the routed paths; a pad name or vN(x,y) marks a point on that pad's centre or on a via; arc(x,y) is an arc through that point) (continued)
SPKR: length 92.6
  TOP w0.254: R1501.2 146.42,58.49 v1(146.03,58.49) 145.99,58.49 v2(145.58,58.9)
  L3SGND w0.254: v2(145.58,58.9) 143.24,61.23 142.32,61.23 142.19,61.11 136.06,61.11 134.86,62.3 v2(134.86,63.34)
  L4SGND w0.254: v2(177.59,10.18) 175.98,10.18 171.69,14.46 171.69,15.88 172.42,16.61 172.42,17.06 170.11,19.37 168.14,19.37 167.78,19.73 166.51,19.73 162.08,24.16 159.9,24.16 158.5,22.75 v2(157.14,22.75)
  L6 w0.254: v2(157.14,22.75) 157.11,22.78 157.11,25.84 157.93,26.65 157.93,31.31 157.04,32.2 157.04,38.79 156.96,38.87 156.17,39.65 156.07,39.76 156.07,41.85 154.88,43.04 154.88,46.83 150.53,51.18 150.53,52.48 149.47,53.55 149.47,54.65 146.84,57.27 146.84,57.63 v2(145.58,58.9)
  BOTTOM w0.076: v2(134.86,63.34) 135.05,63.53 135.05,64.25 134.31,64.99 133.59,64.99 133.26,65.32 133.26,65.66 133.33,65.85 133.33,66.23 133.37,66.26 133.37,66.69 133.52,66.85 CPU1.CF35
  BOTTOM w0.254: RN2702.2 178.17,9.97 177.97,10.18 v2(177.59,10.18)
SRTC_RST#: length 41.7
  TOP w0.102: v2(146.85,49.3) 146.43,48.89 145.35,48.89 144.77,49.47 133.74,49.47 v1(131.74,51.48) 129.34,53.88 129.34,56.5 129.28,56.56 129.28,57.92 128.4,58.81 128.4,61.94 128.56,62.1 128.56,63.82 v2(128.13,64.25)
  BOTTOM w0.102: CPU1.BR37 127.7,65.28 127.7,64.36 127.8,64.25 v2(128.13,64.25) ; v2(146.85,49.3) 146.85,49.3 146.85,49.16 146.1,48.41 143.22,48.41 142.38,47.57 141.03,47.57 C1805.1 140.81,47.85 RN1801.3 140.68,48.89 ED1801.2
SSD_CLK_CPU_N: length 178.7
  TOP w0.102: v2(189.7,9.8) v1(189.7,10.43)
  L6 w0.089: v2(118.31,90.24) 118.31,90.46 118.2,90.57 117.84,90.57 117.75,90.66 117.75,91.36 118.05,91.66 118.05,98.17 124.1,104.23 144.98,104.23 146.75,102.46 146.75,101.52 148.69,99.58 152.58,99.58 156.28,95.87 161.98,95.87 162.93,94.93 164.08,94.93 165.2,93.81 181.64,93.81 186.46,88.98 186.46,88.67 186.46,88.67 186.46,88.28 186.46,59.69 185.93,59.15 185.93,51.56 189.69,47.79 189.69,41.22 192.36,38.55 192.36,25.14 193.59,23.92 193.59,23.15 192.39,21.95 192.39,10.74 190.85,9.2 190.15,9.2 190.08,9.26 190.08,9.71 189.99,9.8 v2(189.7,9.8)
  BOTTOM w0.102: v2(118.31,90.24) 118.02,89.95 118.02,89.05 118.1,88.97 118.1,87.97 118.2,87.84 118.21,87.84 118.24,87.83 118.4,87.83 118.5,87.93 CPU1.BA1 ; SSD1.53 188.07,9.65 188.23,9.49 189.4,9.49 v2(189.7,9.8)
SSD_CLK_CPU_P: length 178.6
  TOP w0.102: v2(189.7,9.01) v1(189.17,9.19)
  L6 w0.089: v2(117.56,90.24) 117.56,90.8 117.56,90.8 117.56,91.44 117.86,91.74 117.86,98.25 124.02,104.42 145.06,104.42 146.94,102.54 146.94,101.59 148.77,99.77 152.65,99.77 156.36,96.06 162.06,96.06 163.01,95.12 164.16,95.12 165.28,94 181.72,94 186.65,89.06 186.65,88.75 186.65,88.75 186.65,88.2 186.65,88.2 186.65,59.61 186.12,59.07 186.12,51.64 189.89,47.87 189.89,41.3 192.55,38.63 192.55,25.22 193.78,24 193.78,23.07 192.58,21.87 192.58,10.66 190.93,9.01 v2(189.7,9.01)
  BOTTOM w0.102: CPU1.BA2 118.07,87.63 118.07,87.63 118.02,87.7 117.87,87.89 117.87,88.87 117.79,88.95 117.79,90 v2(117.56,90.24) ; SSD1.55 188.1,9.15 188.21,9.26 189.44,9.26 v2(189.7,9.01)
SSD_CLKREQ_CPU_N: length 134.8
  TOP w0.102: RN1813.7 143.49,54.86 142.69,55.67 v2(142.69,55.95) 142.25,55.95 141.76,56.44 141.76,57.84 141.15,58.45 141.15,60.28 136.91,64.52 136.91,65.02 136.29,65.64 135.76,65.64 134.23,67.16 134.23,68.5 134.03,68.71 134.03,68.99 133.74,69.28 133.73,69.28 133.54,69.47 v2(133.54,70.17) ; v2(169,21.07) 168.87,20.95 168.68,20.95 165.33,17.6 165.33,11.09 171,5.43 172.68,5.43 173.98,4.13 173.98,2.63 174.26,2.35 177,2.35 v2(177.1,2.25)
  L6 w0.102: v2(177.1,2.25) 177.1,2.64 178.3,3.83 178.3,4.89 180.72,7.31 184.06,7.31 186.42,4.95 189.82,4.95 190.72,5.84 190.72,7.94 192.95,10.18 v2(193.59,10.18) ; v2(142.69,55.95) 143.9,57.17 145.73,57.17 148.68,54.22 148.68,53.88 148.68,53.21 149.75,52.14 149.75,50.85 154.1,46.5 154.1,42.71 155.11,41.7 155.11,39.34 156.22,38.22 156.22,30.73 156.62,30.33 156.62,26.47 156.33,26.17 156.33,22.88 v2(155.54,22.09)
  BOTTOM w0.102: v2(169,21.07) 168.24,21.84 v1(168.24,22.29) 168.24,23.51 167.26,24.49 157.46,24.49 155.83,22.86 155.54,22.57 v2(155.54,22.09) ; v2(133.54,70.17) 133.21,69.84 CPU1.CE30 ; SSD1.52 193.87,9.9 v2(193.59,10.18)
SSD_DEVSLP: length 148.2
  TOP w0.102: v2(187.62,28.72) 188.46,27.89 188.46,20.01 187.92,19.47 187.92,14.57 188.63,13.86 189.6,13.86 R6301.1 R6304.1 R6303.2
  L4SGND w0.102: v2(187.11,96.49) 189.76,93.83 189.76,91.4 189.76,69.02 189.29,68.55 189.29,64.43 186.07,61.21 186.07,52.41 186.07,52.41 186.07,51.64 188.69,49.02 188.69,29.79 v2(187.62,28.72)
  BOTTOM w0.076: CPU1.CM8 137.44,83.51 138.56,83.51 arc(138.64,83.49) 138.71,83.44 138.75,83.4 arc(138.81,83.37) 138.85,83.33 140.26,83.33
  BOTTOM w0.102: 140.26,83.33 140.26,83.33 141.14,83.33 141.92,84.12 141.92,84.31 142.12,84.5 142.36,84.5 142.91,85.06 143.11,85.06 143.25,85.2 148.87,85.2 149.03,85.03 152.02,85.03 152.45,85.46 152.45,87.91 153.38,88.84 162.62,88.84 165.33,91.56 v1(176.7,91.56) 179.08,91.56 183.47,95.95 185.94,95.95 186.48,96.49 v2(187.11,96.49)
SSD_PCIE_RX_N1: length 160.5
  L6 w0.089: v2(122.78,86.04) 122.61,85.88 122.5,85.88 122.34,86.04 122.34,89.09 121.68,89.75 121.68,96.06 127.09,101.47 137.99,101.47 138.38,101.07 141.97,101.07 142.71,100.34 143.75,100.34 147,97.08 151.52,97.08 155.52,93.08 158.4,93.08 160.32,91.17 178.84,91.17 183.81,86.2 183.81,66.82 183.24,66.25 183.24,64.31 182.18,63.26 182.18,56.77 182.86,56.1 182.86,50.31 185.07,48.1 185.07,47.53 186.91,45.69 186.91,38.82 189,36.72 189,21.94 189.66,21.28 189.66,15.39 189.49,15.22 189.4,15.22 189.17,15.45 189.17,15.73 189.08,15.82 v2(188.99,15.82)
  BOTTOM w0.102: CPU1.BG5 122.26,85.59 122.36,85.69 122.68,85.69 122.78,85.79 v2(122.78,86.04) ; SSD1.29 188.14,15.65 188.23,15.56 188.23,15.46 188.23,15.46 188.31,15.38 188.65,15.38 188.74,15.47 188.74,15.75 188.81,15.82 v2(188.99,15.82)
SSD_PCIE_RX_N2: length 155.1
  L6 w0.089: v2(123.64,85.11) 123.47,85.34 123.19,85.62 123.19,89.21 122.15,90.25 122.15,95.8 127.25,100.91 137.35,100.91 137.69,100.56 141.86,100.56 142.56,99.87 143.66,99.87 146.84,96.69 151.25,96.69 155.39,92.55 158.27,92.55 160.12,90.7 178.53,90.7 183.33,85.9 183.33,73.27 182.77,72.71 182.77,66.49 182.77,64.51 181.4,63.14 181.4,55.5 181.2,55.31 181.2,48.8 186.44,43.57 186.44,38.7 186.44,38.62 188.41,36.65 188.41,18.71 188.56,18.56 188.85,18.56 v2(189.08,18.79)
  BOTTOM w0.102: CPU1.BJ6 v2(123.64,85.11) ; v2(189.08,18.79) 188.85,18.57 188.34,18.57 188.26,18.65 SSD1.17
SSD_PCIE_RX_N3: length 150
  TOP w0.102: v1(186.04,25.67) v2(186.6,25.67)
  L6 w0.089: v2(186.6,25.67) 187.2,26.27 187.2,28.14 186.35,28.99 186.35,31.73 185.05,33.02 185.05,43.34 182.45,45.94 182.45,46.43 182.45,46.58 180.54,48.49 180.54,55.58 180.71,55.75 180.71,63.47 182.08,64.84 182.08,72.98 182.67,73.56 182.67,85.62 178.25,90.04 159.84,90.04 159.83,90.05 158.83,91.04 158.76,91.11 158.73,91.14 158.36,91.5 158.25,91.61 158.13,91.74 158.13,91.74 158.01,91.85 155.26,91.85 151.01,96.09 146.6,96.09 143.44,99.26 142.33,99.26 141.8,99.79 127.11,99.79 122.87,95.55 122.87,91.95 124.7,90.12 124.7,90.04 124.7,88.38 124.07,87.75 124.07,85.57 v2(124.55,85.08)
  BOTTOM w0.102: v2(186.6,25.67) 185.61,24.68 185.61,21.97 186.07,21.51 186.31,21.51 186.44,21.65 SSD1.5 ; CPU1.BK6 v2(124.55,85.08)
SSD_PCIE_RX_N12: length 158.7
  L6 w0.089: v2(162.57,10.51) 163.97,10.51 164.47,11 164.72,11 165.3,11.59 167.15,11.59 167.51,11.95 167.51,13.38 170.82,16.68 170.82,27.6 174.3,31.08 174.3,41.1 176.56,43.36 176.56,56.89 177.31,57.63 177.31,66.02 179.44,68.15 179.44,74.21 179.97,74.74 179.97,83.84 178.13,85.68 164.08,85.68 162.36,87.39 157.85,87.39 156.27,88.97 154.27,88.97 149.62,93.62 144.07,93.62 143.27,94.42 136.35,94.42 134.47,96.3 130.19,96.3 126.67,92.78 126.67,91.85 125.58,90.76 125.58,87.57 124.95,86.95 124.95,84.11 124.95,84.1 124.95,83.45 125.37,83.02 125.9,83.02 126.13,83.26 v2(126.45,83.26)
  BOTTOM w0.102: v2(162.57,10.51) 163.66,10.51 163.91,10.76 164.88,10.76 165.15,10.65 SSD2.29 ; CPU1.BN10 125.96,82.77 v2(126.45,83.26)
SSD_PCIE_RX_P1: length 160.6
  L6 w0.089: v2(188.99,15.03) 189.57,15.03 189.85,15.31 189.85,21.35 189.19,22.01 189.19,36.64 189.19,36.64 189.19,36.8 187.1,38.9 187.1,45.77 185.26,47.61 185.26,48.18 183.05,50.39 183.05,56.18 182.37,56.85 182.37,63.18 183.43,64.23 183.43,66.17 184,66.74 184,86.28 178.92,91.36 160.4,91.36 158.48,93.27 155.6,93.27 151.6,97.27 147.08,97.27 143.83,100.53 142.79,100.53 142.05,101.26 138.46,101.26 138.07,101.66 127.01,101.66 121.49,96.13 121.49,89.67 122.15,89.01 122.15,85.96 122.37,85.74 122.39,85.72 v2(122.7,85.18)
  BOTTOM w0.102: SSD1.31 188.87,15.15 v2(188.99,15.03) ; CPU1.BG6 v2(122.7,85.18)
SSD_PCIE_RX_P2: length 155.1
  L6 w0.089: v2(189.08,18.01) 189.08,18.24 188.95,18.37 188.48,18.37 188.22,18.63 188.22,36.57 186.25,38.54 186.25,38.78 186.25,43.49 181.01,48.72 181.01,55.39 181.2,55.58 181.2,63.22 182.58,64.59 182.58,65.85 182.58,65.85 182.58,66.57 182.58,72.79 183.14,73.35 183.14,85.82 178.45,90.51 160.04,90.51 158.19,92.36 155.31,92.36 151.17,96.5 146.76,96.5 143.58,99.67 142.48,99.67 141.78,100.37 137.62,100.37 137.27,100.72 127.33,100.72 122.34,95.73 122.34,90.33 123.38,89.29 123.38,86 v2(123.64,85.74)
  BOTTOM w0.102: SSD1.19 188.1,18.15 188.28,18.34 188.98,18.34 189.08,18.24 v2(189.08,18.01) ; v2(123.64,85.74) 123.45,85.93 123.24,85.93 123.07,85.76 123.07,85.59 CPU1.BJ5
SSD_PCIE_RX_P3: length 150.1
  TOP w0.102: v1(187.19,26.36) v2(186.58,26.36)
  L6 w0.089: v2(186.58,26.36) 186.73,26.2 186.86,26.2 187.01,26.35 187.01,28.06 186.16,28.91 186.16,31.65 184.86,32.94 184.86,43.26 182.26,45.87 182.26,46.5 180.35,48.41 180.35,55.51 180.35,55.66 180.52,55.83 180.52,63.55 181.89,64.92 181.89,73.06 182.47,73.64 182.47,85.54 178.17,89.85 159.76,89.85 159.64,89.97 158.7,90.91 158.63,90.97 158.6,91 158.23,91.37 158.18,91.42 158.17,91.42 158.05,91.55 158.05,91.55 157.94,91.66 155.18,91.66 150.94,95.9 146.52,95.9 143.36,99.07 142.25,99.07 141.72,99.6 127.19,99.6 123.06,95.47 123.06,92.03 124.89,90.2 124.89,89.96 124.89,88.31 124.26,87.67 124.26,85.83 124.35,85.74 v2(124.55,85.74)
  BOTTOM w0.102: SSD1.7 186.48,21.15 186.34,21.29 185.97,21.29 185.38,21.88 185.38,24.78 186.17,25.56 186.17,26.26 186.27,26.36 v2(186.58,26.36) ; CPU1.BK5 124.11,85.74 124.21,85.85 124.44,85.85 v2(124.55,85.74)
SSD_PCIE_RX_P12: length 158.6
  L6 w0.089: v2(162.57,11.3) 162.87,11.3 162.95,11.21 162.95,10.78 163.04,10.7 163.89,10.7 164.39,11.19 164.64,11.19 165.23,11.78 167.07,11.78 167.32,12.03 167.32,13.45 170.63,16.76 170.63,27.68 174.11,31.16 174.11,41.18 176.37,43.44 176.37,56.96 177.12,57.71 177.12,66.1 179.25,68.23 179.25,74.29 179.78,74.82 179.78,83.76 178.05,85.49 164,85.49 162.28,87.2 157.77,87.2 156.2,88.78 154.19,88.78 149.54,93.43 143.99,93.43 143.19,94.23 136.27,94.23 134.39,96.11 130.26,96.11 126.86,92.7 126.86,91.77 125.77,90.68 125.77,87.5 125.14,86.87 125.14,84.03 125.14,84.02 125.14,83.53 125.45,83.21 125.82,83.21 126.02,83.42 126.02,83.74 125.92,83.85 v2(125.56,83.85)
  BOTTOM w0.102: v2(162.57,11.3) 162.9,11.3 163.01,11.19 163.01,10.84 163.11,10.73 163.56,10.73 163.82,10.99 164.91,10.99 165.07,11.15 SSD2.31 ; CPU1.BN8 125.66,83.53 125.56,83.63 v2(125.56,83.85)
SSD_PCIE_TX_CON_N1: length 1.6
  BOTTOM w0.102: SSD1.35 186.51,14.15 186.42,14.06 186.12,14.06 C6312.1
SSD_PCIE_TX_CON_N2: length 1.6
  BOTTOM w0.102: SSD1.23 186.49,17.15 186.32,16.99 186.12,16.99 C6314.1
SSD_PCIE_TX_CON_N3: length 1.7
  BOTTOM w0.102: C6316.1 185.99,20.03 186.24,20.03 186.35,20.15 SSD1.11
SSD_PCIE_TX_CON_N12: length 12.2
  TOP w0.102: C6327.1 154.48,11.97 156.9,11.97 157.21,12.29 163.49,12.29 v2(163.77,12.01)
  BOTTOM w0.102: v2(163.77,12.01) 164.05,12.29 164.87,12.29 165,12.15 SSD2.35
SSD_PCIE_TX_CON_P1: length 1.6
  BOTTOM w0.102: SSD1.37 186.56,13.65 186.37,13.84 186.09,13.84 C6311.1
SSD_PCIE_TX_CON_P2: length 1.6
  BOTTOM w0.102: SSD1.25 186.48,16.65 186.37,16.76 186.09,16.76 C6313.1
SSD_PCIE_TX_CON_P3: length 1.7
  BOTTOM w0.102: SSD1.13 186.35,19.65 186.2,19.8 185.97,19.8 C6315.1
SSD_PCIE_TX_CON_P12: length 12.2
  TOP w0.102: C6326.1 154.48,12.2 156.8,12.2 157.12,12.51 163.49,12.51 v2(163.77,12.79)
  BOTTOM w0.102: v2(163.77,12.79) 164.05,12.51 164.87,12.51 165,12.65 SSD2.37
SSD_PCIE_TX_N1: length 154.5
  L6 w0.089: v2(184.39,14.34) 184.67,14.06 185.33,14.06 186.16,14.89 186.16,23.82 185.47,24.5 185.47,31.4 184.2,32.67 184.2,42.99 181.6,45.59 181.6,46.22 179.59,48.23 179.59,56.14 179.72,56.27 179.72,64.94 181.23,66.45 181.23,73.35 181.8,73.92 181.8,85.23 177.85,89.18 159.49,89.18 157.78,90.89 155.03,90.89 150.59,95.32 146.19,95.32 143.21,98.3 143.04,98.3 142.04,98.3 141.42,98.93 129.05,98.93 126.1,95.98 124.58,95.98 123.76,95.17 123.76,94.67 123.94,94.5 124.29,94.5 124.42,94.63 v2(124.42,94.85)
  BOTTOM w0.076: 123.9,89.75 123.91,89.74 123.96,89.74 124.45,89.25 124.45,88.69 124.27,88.51 124.27,88.06 124.3,87.98 124.31,87.96 124.31,87.74 124.27,87.64 124.27,87.39 124.42,87.05 124.42,86.8 124.46,86.7 CPU1.BL4
  BOTTOM w0.102: 123.9,89.75 122.62,91.03 122.62,93.87 123.28,94.53 123.69,94.53 ; 123.69,94.53 v1(123.69,94.71) ; 123.69,94.53 124.1,94.53 v2(124.42,94.85) ; C6312.2 v2(184.39,14.34)
SSD_PCIE_TX_N2: length 146.9
  L6 w0.089: v2(123.98,92.7) 124.23,92.95 124.72,92.95 129.26,97.5 129.26,97.85 129.68,98.27 141.12,98.27 141.67,97.72 142.2,97.72 142.92,97.72 145.93,94.71 150.38,94.71 154.95,90.14 156.84,90.14 158.46,88.52 177.46,88.52 181.13,84.85 181.13,74.19 180.57,73.63 180.57,66.72 179.01,65.16 179.01,56.51 177.76,55.26 177.76,46.47 178.55,45.69 179.63,45.69 183.54,41.77 183.54,32.39 184.79,31.15 184.79,24.24 185.5,23.53 185.5,17.2 185.28,16.99 184.67,16.99 v2(184.39,17.26)
  BOTTOM w0.076: CPU1.BL2 124.72,87.53 124.96,88.1 124.96,89.73 124.98,89.74 124.98,89.9 124.94,89.94 124.96,89.96 124.96,89.98 124.95,89.98
  BOTTOM w0.102: 123.46,91.59 123.46,92.74 123.64,92.92 123.76,92.92 v2(123.98,92.7) ; 123.46,91.59 123.46,91.51 124.17,90.79 124.17,90.76 124.95,89.98 ; 123.46,91.59 v1(123.64,91.59) ; C6314.2 184.73,17.07 184.59,17.07 v2(184.39,17.26)
SSD_PCIE_TX_N3: length 140.6
  L6 w0.089: v2(125.44,91.98) 125.68,92.22 126.04,92.22 126.09,92.28 126.24,92.42 126.24,93.03 130.37,97.16 141.16,97.16 144.28,94.04 150.05,94.04 153.3,90.78 153.3,90.78 154.63,89.46 154.81,89.46 155.13,89.46 155.38,89.46 155.44,89.46 156.58,89.46 158.18,87.86 162.65,87.86 164.32,86.19 178.29,86.19 180.46,84.03 180.46,74.48 179.91,73.93 179.91,67.96 177.9,65.95 177.9,59.76 178.26,59.4 178.26,56.74 177.04,55.52 177.04,55.29 177.04,45.33 180,42.37 180.54,42.37 182.87,40.05 182.87,32.13 184.05,30.95 184.05,24.04 184.84,23.26 184.84,20.15 184.7,20.01 184.56,20.01 v2(184.27,20.31)
  BOTTOM w0.076: 125.11,90.67 125.12,90.66 125.13,90.66 125.13,90.67 125.34,90.46 125.34,87.69 125.34,87.62 125.34,87.54 125.53,87.35 125.53,87.05 125.26,86.78 CPU1.BM4
  BOTTOM w0.102: v2(184.27,20.31) 184.46,20.12 184.6,20.12 C6316.2 ; 124.69,91.28 124.69,91.08 125.11,90.67 ; 124.69,91.28 v1(124.83,91.28) ; 124.69,91.28 124.69,92.08 124.82,92.21 125.21,92.21 v2(125.44,91.98)
SSD_PCIE_TX_N12: length 145.9
  TOP w0.102: 152.52,11.98 151.29,11.98 151.11,11.81 151.11,11.55 151.24,11.43 v2(151.4,11.43) ; 152.52,11.98 v1(152.52,11.8) ; 152.52,11.98 153.02,11.98 C6327.2
  L6 w0.089: v2(127.01,89.96) 127,89.96 126.59,90.36 126.59,90.57 127.49,91.46 127.49,92.4 130.54,95.45 134.11,95.45 135.99,93.57 137.35,93.57 137.77,93.15 140.97,93.15 141.36,93.54 142.56,93.54 143.26,92.84 149.19,92.84 154.66,87.37 156.67,87.37 157.5,86.54 162.01,86.54 163.95,84.6 165.78,84.6 166.48,83.91 166.48,81.15 165.91,80.59 165.91,74.89 165.91,74.73 172.19,68.46 172.19,66.27 173.34,65.12 173.34,62.72 172.04,61.41 172.04,59.48 170.69,58.14 170.69,48.45 172.63,46.51 172.63,44.24 172.04,43.65 172.04,36.98 164.11,29.06 164.11,20.65 154.18,10.71 151.27,10.71 151,10.98 151,11.14 151.29,11.43 v2(151.4,11.43)
  BOTTOM w0.076: CPU1.BN4 126.11,86.51 126.11,86.79 126.13,87.09 126.2,87.25 126.26,87.39 126.26,87.65 126.22,87.74 126.22,87.96 126.25,88.05 126.25,88.87 126.44,89.06 126.44,89.53 126.52,89.6 126.85,89.6 127.01,89.77 v2(127.01,89.96)
SSD_PCIE_TX_P1: length 154.5
  L6 w0.089: v2(184.39,13.58) 184.68,13.87 185.41,13.87 186.35,14.81 186.35,23.89 185.66,24.58 185.66,31.48 184.39,32.75 184.39,43.07 181.79,45.67 181.79,46.3 179.78,48.31 179.78,56.06 179.91,56.19 179.91,64.86 181.42,66.37 181.42,73.27 181.99,73.84 181.99,85.31 177.93,89.38 159.57,89.38 159.17,89.77 157.86,91.08 155.11,91.08 150.67,95.51 146.27,95.51 143.29,98.49 143.04,98.49 142.12,98.49 141.49,99.12 128.97,99.12 126.02,96.17 124.5,96.17 123.57,95.25 123.57,94.59 123.86,94.3 124.25,94.3 v2(124.45,94.1)
  BOTTOM w0.076: CPU1.BL3 124.67,86.93 124.53,87.22 124.44,87.43 124.44,87.62 124.47,87.71 124.47,87.99 124.46,88.03 124.44,88.08 124.44,88.44 124.61,88.62 124.61,89.32 124.05,89.88 124.07,89.9 124.07,89.91 124.06,89.92
  BOTTOM w0.102: v2(124.45,94.1) 124.25,94.3 123.37,94.3 122.85,93.78 122.85,93.16 ; v1(123.03,93.16) 122.85,93.16 ; 122.85,93.16 122.85,91.13 124.06,89.92 ; C6311.2 v2(184.39,13.58)
SSD_PCIE_TX_P2: length 146.8
  L6 w0.089: v2(123.98,93.34) 124.17,93.15 124.64,93.15 129.07,97.58 129.07,97.93 129.6,98.46 141.2,98.46 141.75,97.91 142.2,97.91 143,97.91 146.01,94.9 150.46,94.9 155.03,90.33 156.92,90.33 158.53,88.71 177.53,88.71 181.32,84.93 181.32,74.11 180.76,73.55 180.76,66.64 179.2,65.09 179.2,56.43 177.95,55.18 177.95,46.55 178.63,45.88 179.71,45.88 183.73,41.85 183.73,32.47 184.98,31.23 184.98,24.32 185.69,23.61 185.69,17.12 185.36,16.79 184.68,16.79 v2(184.39,16.5)
  BOTTOM w0.076: CPU1.BL1 124.79,88.41 124.79,89.82
  BOTTOM w0.102: v2(184.39,16.5) C6313.2 ; 124.79,89.82 123.95,90.66 123.95,90.7 123.23,91.41 123.23,92.83 123.55,93.15 123.79,93.15 v2(123.98,93.34)
SSD_PCIE_TX_P3: length 140.7
  L6 w0.089: v2(125.44,92.62) 125.65,92.41 125.68,92.41 125.96,92.41 126.05,92.5 126.05,93.11 130.29,97.35 141.24,97.35 144.36,94.23 150.13,94.23 153.38,90.98 153.38,90.98 154.7,89.65 154.89,89.65 156.66,89.65 158.26,88.05 162.73,88.05 164.4,86.38 178.37,86.38 180.65,84.1 180.65,74.4 180.1,73.86 180.1,67.88 178.09,65.87 178.09,59.84 178.45,59.48 178.45,56.66 177.23,55.44 177.23,55.37 177.23,45.41 180.07,42.56 180.62,42.56 183.06,40.13 183.06,32.21 184.24,31.03 184.24,30.87 184.24,24.12 185.03,23.34 185.03,20.08 184.78,19.82 184.54,19.82 v2(184.27,19.55)
  BOTTOM w0.076: CPU1.BM3 125.22,87.41 125.16,87.47 125.16,87.62 125.16,87.69 125.16,90.38 125.07,90.48 124.91,90.54
  BOTTOM w0.102: 124.83,92.44 124.73,92.44 124.47,92.18 124.47,90.99 124.91,90.54 ; 124.83,92.44 125.26,92.44 v2(125.44,92.62) ; 124.83,92.44 v1(124.83,92.63) ; v2(184.27,19.55) C6315.2
SSD_PCIE_TX_P12: length 145.9
  TOP w0.102: 151.4,12.21 151.19,12.21 150.89,11.9 150.89,11.62 v2(150.69,11.42) ; 151.4,12.21 153.05,12.21 C6326.2 ; 151.4,12.21 v1(151.4,12.36)
  L6 w0.089: v2(126.4,89.98) 126.4,90.65 127.3,91.54 127.3,92.48 130.46,95.64 134.19,95.64 136.07,93.76 137.43,93.76 137.85,93.34 140.89,93.34 141.29,93.73 142.64,93.73 143.34,93.03 149.27,93.03 154.74,87.56 156.75,87.56 157.58,86.73 162.09,86.73 164.03,84.79 165.86,84.79 166.67,83.99 166.67,81.07 166.1,80.51 166.1,74.81 172.38,68.54 172.38,66.35 173.53,65.2 173.53,62.64 172.23,61.33 172.23,59.4 170.88,58.06 170.88,48.53 172.82,46.59 172.82,44.17 172.23,43.57 172.23,36.9 164.3,28.98 164.3,20.57 154.26,10.52 151.19,10.52 150.81,10.9 150.81,11.3 v2(150.69,11.42)
  BOTTOM w0.076: v2(126.4,89.98) 126.26,89.63 126.26,89.11 126.09,88.94 126.09,88.08 126.06,87.99 126.06,87.71 126.09,87.62 126.09,87.43 126.03,87.28 125.97,87.16 125.97,87.16 125.85,86.92 CPU1.BN3
SSD_SATA_RX_N: length 171.6
  L6 w0.089: v2(183.78,12.08) 185,12.08 185.95,13.04 188.59,13.04 190.51,14.96 190.51,21.63 190.01,22.14 190.01,22.89 190.01,36.92 187.76,39.17 187.76,46.07 186.26,47.57 186.26,48.42 183.87,50.81 183.87,61.7 184.21,62.04 184.21,66.02 184.66,66.46 184.66,86.63 179.28,92.02 160.67,92.02 158.71,93.97 155.77,93.97 151.85,97.88 147.3,97.88 144.06,101.12 143.05,101.12 142.25,101.92 138.9,101.92 138.46,102.37 126.78,102.37 120.79,96.38 120.79,93.02 120.21,92.43 120.21,90.91 120.21,90.76 120.78,90.19 120.78,86.2 121.1,85.88 121.1,85.39 v2(120.89,85.18)
  BOTTOM w0.102: v2(183.78,12.08) 183.99,12.29 184.57,12.29 184.68,12.18 ED6301.4 ED6301.7 185.85,12.15 SSD1.43 ; CPU1.BE5 v2(120.89,85.18)
SSD_SATA_RX_N11: length 139.2
  TOP w0.102: v2(151.92,14.01) 152.17,13.76 152.69,13.76 152.79,13.87 ED6302.4 ED6302.7 154.48,13.87 154.62,13.73 158.03,13.73 158.31,14.01 162.42,14.01 v2(162.7,14.3)
  L6 w0.089: v2(125.56,85.16) 126.73,86.33 129.49,86.33 131.84,88.67 131.84,89.35 132.53,90.04 133.55,90.04 134.12,89.46 139.43,89.46 143.47,85.43 151.84,85.43 153.94,83.32 156.35,83.32 156.79,82.89 159.51,82.89 163.91,78.49 163.91,73.37 167.34,69.94 167.34,67.17 169.84,64.67 169.84,63.12 168.28,61.56 168.28,58.64 169.33,57.58 169.33,46.58 169.97,45.94 169.97,41.34 169.04,40.42 169.04,36.02 162.5,29.48 162.5,22.26 161.8,21.56 161.8,20.38 155.14,13.72 152.17,13.72 151.92,13.98 v2(151.92,14.01)
  BOTTOM w0.102: CPU1.BL6 125.03,85.06 125.27,85.3 125.42,85.3 v2(125.56,85.16) ; SSD2.43 165,14.15 164.87,14.01 162.98,14.01 v2(162.7,14.3)
SSD_SATA_RX_P: length 171.6
  L6 w0.089: v2(121.81,85.11) 121.45,85.11 121.29,85.27 121.29,85.96 120.97,86.28 120.97,90.26 120.4,90.84 120.4,92.35 120.98,92.94 120.98,96.3 126.86,102.18 138.38,102.18 138.82,101.73 142.17,101.73 142.97,100.93 143.98,100.93 147.22,97.69 151.78,97.69 155.69,93.78 158.63,93.78 160.59,91.83 179.2,91.83 179.75,91.27 184.47,86.56 184.47,66.54 184.02,66.1 184.02,65.94 184.02,62.12 183.68,61.78 183.68,50.73 186.07,48.34 186.07,47.49 187.57,45.99 187.57,39.09 189.82,36.84 189.82,22.97 189.81,22.97 189.81,22.06 190.32,21.55 190.32,15.04 188.51,13.23 185.88,13.23 184.92,12.27 184.28,12.27 v2(183.78,12.77)
  BOTTOM w0.102: SSD1.41 185.85,12.65 ED6301.6 ED6301.5 184.71,12.68 184.54,12.51 184.04,12.51 v2(183.78,12.77) ; v2(121.81,85.11) 121.68,85.24 121.53,85.24 121.34,85.05 CPU1.BE6
SSD_SATA_RX_P11: length 139.2
  TOP w0.102: v2(162.7,13.51) 162.42,13.79 158.4,13.79 158.12,13.5 154.62,13.5 154.48,13.37 ED6302.6 ED6302.5 152.85,13.37 152.69,13.53 152.11,13.53 v2(151.93,13.35)
  L6 w0.089: v2(151.93,13.35) 152.11,13.53 155.22,13.53 161.99,20.3 161.99,21.48 162.69,22.18 162.69,29.4 169.23,35.94 169.23,40.34 170.16,41.26 170.16,46.02 169.52,46.65 169.52,57.66 168.47,58.72 168.47,61.48 170.03,63.04 170.03,64.75 167.53,67.25 167.53,70.02 164.1,73.45 164.1,78.57 159.59,83.08 156.87,83.08 156.43,83.51 154.02,83.51 151.92,85.62 143.55,85.62 139.51,89.65 134.2,89.65 133.63,90.23 132.45,90.23 131.65,89.43 131.65,88.75 129.41,86.52 126.66,86.52 125.93,85.8 v2(125.55,85.8)
  BOTTOM w0.102: SSD2.41 165,13.65 164.87,13.79 162.98,13.79 v2(162.7,13.51) ; CPU1.BL5 v2(125.55,85.8)
SSD_SATA_TX_CON_N: length 3.5
  BOTTOM w0.102: C6303.1 184.06,11.18 184.2,11.04 184.35,11.04 184.48,11.18 ED6301.2 ED6301.9 185.85,11.15 SSD1.47
SSD_SATA_TX_CON_N11: length 14.6
  TOP w0.102: v2(163.81,15.01) 163.53,15.29 158.38,15.29 158.1,15 154.62,15 154.48,14.87 ED6302.9 ED6302.2 152.68,14.87 152.54,15 152.21,15 C6325.1
  BOTTOM w0.102: v2(163.81,15.01) 164.09,15.29 164.87,15.29 165,15.15 SSD2.47
SSD_SATA_TX_CON_P: length 3.5
  BOTTOM w0.102: SSD1.49 185.85,10.65 ED6301.10 ED6301.1 184.48,10.68 184.35,10.81 184.2,10.81 184.06,10.67 C6302.1
SSD_SATA_TX_CON_P11: length 14.6
  TOP w0.102: C6324.1 152.24,15.23 152.54,15.23 152.68,15.37 ED6302.1 ED6302.10 154.48,15.37 154.62,15.23 158,15.23 158.28,15.51 163.53,15.51 v2(163.81,15.79)
  BOTTOM w0.102: SSD2.49 165,15.65 164.87,15.51 164.09,15.51 v2(163.81,15.79)
SSD_SATA_TX_N: length 174.2
  L6 w0.089: v2(120.31,95.03) 120.06,94.79 119.9,94.79 119.72,94.96 119.72,95.98 120.38,96.64 120.38,97.99 120.68,98.28 126.5,102.85 143.56,102.85 144.67,101.75 144.83,101.75 148.27,98.3 152.09,98.3 155.95,94.44 160.91,94.44 162.87,92.49 180.64,92.49 182.79,90.34 185.14,86.94 185.14,66.28 184.68,65.83 184.68,61.67 184.39,61.37 184.39,51.12 186.81,48.71 186.81,47.69 188.28,46.22 188.28,39.35 190.48,37.15 190.48,22.47 190.98,21.96 190.98,14.88 190.95,14.75 190.16,13.33 189.16,12.34 187.81,11.81 186.14,11.81 183.03,11.04 182.84,11.02 v2(182.56,11.3)
  BOTTOM w0.076: 122.65,90.53 123.31,89.88 123.31,88.99 123.81,88.49 123.81,88.05 123.78,87.96 123.78,87.74 123.81,87.65 123.81,87.39 123.7,87.13 123.68,87.1 123.66,87.05 123.66,86.77 CPU1.BJ4
  BOTTOM w0.102: v2(182.56,11.3) 182.78,11.08 182.93,11.08 C6303.2 ; 122.65,90.53 122.29,90.89 122.29,93.05 122.09,93.25 122.09,94.02 121.3,94.8 120.54,94.8 v2(120.31,95.03)
SSD_SATA_TX_N11: length 136.3
  TOP w0.102: C6325.2 150.78,15.02 150.51,15.02 150.28,14.79 150.28,14.18 150.37,14.09 151.03,14.09 151.13,13.99 v2(151.13,13.66)
  L6 w0.089: v2(151.13,13.66) 150.9,13.43 150.9,12.77 151.07,12.6 152.78,12.6 152.78,12.6 154.97,12.6 162.51,20.14 162.51,21.23 163.41,22.13 163.41,29.42 169.7,35.71 169.7,40.14 170.63,41.07 170.63,46.35 169.99,46.98 169.99,58.38 171.37,59.76 171.37,68.32 165.24,74.45 165.24,79.17 159.26,85.15 157.02,85.15 156.17,86 154.16,86 152.71,87.45 144.35,87.45 142.22,89.58 142.22,89.74 142.22,90.99 141.39,91.81 135.3,91.81 133.58,93.54 133.05,93.54 132.79,93.28 132.79,92.57 131.41,91.19 128.46,91.19 128.21,91.44 128.21,91.76 127.97,91.99 v2(127.9,91.99)
  BOTTOM w0.076: 125.67,89.26 125.55,89.14 125.55,88.03 CPU1.BN2
  BOTTOM w0.102: 125.67,89.26 125.67,90.47 126.97,91.76 127.67,91.76 v2(127.9,91.99)
SSD_SATA_TX_P: length 174.2
  L6 w0.089: v2(182.61,10.53) 182.91,10.83 183.06,10.85 186.16,11.62 187.85,11.62 189.27,12.17 190.31,13.22 191.13,14.68 191.17,14.85 191.17,22.04 190.67,22.55 190.67,37.23 188.47,39.43 188.47,46.3 187,47.77 187,48.79 184.58,51.2 184.58,61.3 184.87,61.59 184.87,65.75 185.33,66.2 185.33,87 182.94,90.46 180.72,92.68 162.95,92.68 160.99,94.63 156.03,94.63 152.17,98.49 148.35,98.49 144.91,101.94 144.75,101.94 143.64,103.04 126.44,103.04 120.56,98.43 120.57,98.44 120.19,98.07 120.19,96.72 119.53,96.06 119.53,94.88 119.82,94.59 120.11,94.59 v2(120.31,94.4)
  BOTTOM w0.076: 122.49,90.37 122.58,90.37 123.14,89.81 123.14,88.93 123.65,88.42 123.65,88.08 123.61,87.99 123.61,87.71 123.65,87.62 123.65,87.43 123.55,87.2 123.54,87.18 CPU1.BJ3
  BOTTOM w0.102: v2(182.61,10.53) C6302.2 ; 122.49,90.37 122.06,90.8 122.06,92.96 121.86,93.16 121.86,93.92 121.2,94.57 120.48,94.57 v2(120.31,94.4)
SSD_SATA_TX_P11: length 136.4
  TOP w0.102: C6324.2 150.78,15.25 150.41,15.25 150.05,14.88 150.05,14.09 v2(150.48,13.66)
  L6 w0.089: v2(150.48,13.66) 150.71,13.43 150.71,12.69 150.99,12.41 152.7,12.41 152.7,12.41 155.04,12.41 162.7,20.06 162.7,21.15 163.63,22.08 163.63,22.14 163.6,22.17 163.6,29.34 169.89,35.63 169.89,40.06 170.82,40.99 170.82,46.43 170.18,47.06 170.18,58.3 171.57,59.68 171.57,68.39 165.43,74.53 165.43,79.25 159.34,85.34 157.1,85.34 156.25,86.19 154.24,86.19 152.79,87.64 144.43,87.64 142.41,89.66 142.41,91.07 141.47,92 135.38,92 133.66,93.73 132.97,93.73 132.6,93.36 132.6,92.65 132.3,92.35 132.3,92.35 131.33,91.38 128.54,91.38 128.4,91.52 128.4,91.8 v2(128.56,91.97)
  BOTTOM w0.076: 125.9,89.31 125.9,89.3 125.89,89.29 125.89,89.21 125.73,89.05 125.73,88.4 CPU1.BN1
  BOTTOM w0.102: v2(128.56,91.97) 128.13,91.53 127.06,91.53 125.9,90.37 125.9,89.31
SSD_SCP#: length 147.6
  TOP w0.102: v2(37.86,17.06) 38.01,17.22 38.01,20.09 37.51,20.59 36.62,20.59 35.47,21.74 35.47,25.21 35.04,25.65 34.68,25.65 R2449.2 33.54,26.79 32.76,26.79 32.02,26.05 v2(30.39,26.05) 29.99,26.05 v1(29.83,26.21) ; v2(150.79,5.73) 150.79,4.46 151.64,3.61 152.4,3.61 R6314.1 R6315.1
  L4SGND w0.102: v2(150.79,5.73) 150.79,5.99 150.41,6.37 143.8,6.37 143.3,5.86 127.19,5.86 126,7.05 125.24,7.05 124.98,6.8 120.53,6.8 117.73,4.01 106.64,4.01 106.06,3.42 94.17,3.42 93.13,4.46 68.52,4.46 65.22,7.77 62.57,7.77 60.59,9.75 57.01,9.75 55.77,10.99 47.51,10.99 43.75,14.75 43.75,16.35 43.35,16.76 41.82,16.76 41.62,16.96 37.96,16.96 v2(37.86,17.06)
  BOTTOM w0.102: U2401.21 33.33,28.6 33.3,28.57 33.3,28.35 31,26.05 v2(30.39,26.05)
SSD_SCP#_1: length 58.5
  TOP w0.102: R6314.2 153.3,3.58 155.03,3.58 155.36,3.57 156.91,5.12 v2(156.91,5.99) ; v2(193.59,20.97) v1(193.93,21.55)
  L4SGND w0.102: v2(193.59,20.97) 194.73,19.83 194.73,13.61 194.22,13.1 191.45,13.1 190.23,11.88 188.66,11.88 184.98,8.2 179.95,8.2 178.02,6.27 178.02,4.66 177.99,4.64 177.99,4.62 177.46,4.08 175.05,4.08 173.14,5.99 v2(156.91,5.99)
  BOTTOM w0.102: v2(193.59,20.97) 193.84,20.97 193.91,20.9 SSD1.8
SSD_SCP#_2: length 6.3
  TOP w0.102: v2(157.39,5.48) 157.39,5.32 155.24,3.17 v1(154.32,3.17) 153.58,3.17 R6315.2
  BOTTOM w0.102: v2(157.39,5.48) 157.47,5.4 SSD2.8
SSEQ0_A0: length 3.9
  TOP w0.127: U7101.11 21.99,67.45 v2(22.03,67.42)
  BOTTOM w0.127: v2(22.03,67.42) 22.06,67.38 R7146.1 22.11,66.39 R7145.2 22.87,65.85 v1(22.37,65.35)
SSEQ1: length 4.1
  TOP w0.127: U7101.3 18.72,65.34 18.67,65.3 18.67,64.14 R7144.1 R7152.2 17.05,63.75 v1(16.68,63.31)
SUS_CLK: length 173.9
  TOP w0.089: v2(128.13,68.8) 128.06,68.73 128.06,67.51 126.23,65.68 126.23,64.58 127.09,63.72 127.09,59.53 127.53,59.09 v2(127.53,58.36) ; v2(146.57,41.19) 146.75,41.19 147.92,40.02 R6117.1
  L4SGND w0.089: v2(58.71,51.45) 58.57,51.31 52.67,51.31 48.61,47.24 48.5,47.24 40.32,39.06 40.32,36.82 40.12,36.62 40.12,36.6 38.76,35.24 38.74,35.24 38.17,34.66 37.94,34.66 37.39,34.12 37.39,34.08 37.21,33.9 37.21,32.66 37.2,32.65 37.2,32.6 35.6,31.01 35.6,27.72 35.92,27.41 v2(36.06,27.41)
  L6 w0.089: v2(22.65,28.33) 22.65,28.26 22.9,28.01 25.95,28.01 26.09,27.86 27.18,27.86 27.5,28.18 28.12,28.18 28.77,28.82 34.1,28.82 35.51,27.41 v2(36.06,27.41) ; v2(146.57,41.19) 145.71,42.06 145.71,43.38 143.63,45.46 142.24,45.46 139.39,48.3 136.64,48.3 131.41,53.54 131.41,54.32 129.86,55.87 129.86,56.15 127.65,58.36 v2(127.53,58.36)
  BOTTOM w0.089: v2(128.13,68.8) 127.87,68.54 CPU1.BT32 ; v2(22.65,28.33) 22.26,27.95 R2461.1 ; v2(127.53,58.36) 127.41,58.36 126.57,57.52 EC1803.2 FC1801.2 125.9,55.75 125.23,55.09 121.08,55.09 119.74,53.75 105.81,53.75 v1(105.18,54.37) 104.91,54.65 85.59,54.65 84.46,53.52 84.12,53.52 65.42,53.52 63.67,51.76 60.42,51.76 59.98,51.33 58.84,51.33 v2(58.71,51.45)
SUSACK#_R: length 20.8
  TOP w0.102: v2(130.8,68.85) 130.53,68.59 130.53,64.98 132.8,62.7 132.8,57.09 132.65,56.94 132.65,54.83 v1(132.91,54.58) v2(132.91,53.64)
  BOTTOM w0.102: v2(130.8,68.85) 130.49,68.54 CPU1.BY32 ; v2(132.91,53.64) 132.8,53.54 132.53,53.54 131.56,52.57 130.06,52.57 129.91,52.72 R1708.2
SUSCLK_WLAN: length 18.2
  TOP w0.089: v2(154.47,40.91) 154.39,40.84 R6117.2
  BOTTOM w0.089: WLAN1.50 164.05,51.3 163.44,50.69 163.27,50.69 161.25,48.68 161.25,44.69 158.61,42.05 v1(156.93,42.05) 155.8,40.91 v2(154.47,40.91)
SVID_ALERT#_CPU: length 64.7
  TOP w0.089: v2(92.62,93.36) 91.65,94.34 90.3,94.34 87.84,96.8 83.57,96.8 81.84,98.53 58.3,98.53 53.65,93.89 53.65,93.27 53.65,92.25 v1(53.65,86.05) 53.65,82.74 53.64,82.73 53.64,82.7 52.53,81.59 52.53,80.32 51.42,79.22 49.68,79.22 v2(48.91,79.99)
  BOTTOM w0.089: R728.1 R727.2 92.62,93.69 v2(92.62,93.36) ; PR4605.2 v2(48.91,79.99) 48.93,79.96 PR4623.1
SVID_ALERT#_CPU_R: length 18.6
  BOTTOM w0.076: CPU1.AA3 106.3,86.98 106.01,87.27 106.01,87.67 106.21,87.88 106.44,87.88 106.51,87.95 106.55,88.05 106.55,88.29 106.53,88.36 106.19,88.7 106.19,89.56
  BOTTOM w0.089: R728.2 93.77,94.93 v1(99.05,94.93) 101.56,94.93 102.76,93.73 103.07,93.73 104.3,92.5 104.3,91.44 106.19,89.56
SVID_ALERT#_VR: length 3.2
  BOTTOM w0.089: PR4623.2 48.93,76.5 v1(48.83,76.4) 48.37,75.94 PU4601.36
SVID_CLK_CPU: length 65.8
  TOP w0.089: v2(49.67,79.99) 49.97,79.69 51.23,79.69 52.06,80.52 52.06,81.79 53.17,82.9 53.17,82.93 53.18,82.94 v1(53.18,83.74) 53.18,92.06 53.18,94.08 58.1,99 58.39,99 82.03,99 83.76,97.27 86.2,97.27 86.2,97.27 88.03,97.27 90.29,95.01 91.68,95.01 v2(93.33,93.36)
  BOTTOM w0.089: PR4624.1 49.7,79.96 v2(49.67,79.99) PR4606.2 ; R723.2 91.96,92.88 92.85,92.88 v2(93.33,93.36) 93.54,93.57 R732.2
SVID_CLK_CPU_R: length 15.6
  BOTTOM w0.089: CPU1.AA1 106.3,88.27 105.99,88.58 105.99,89.42 104.08,91.33 104.08,92.45 103.01,93.51 102.32,93.51 101.37,94.46 v1(95.75,94.46) 94.56,94.46 R732.1
SVID_CLK_VR: length 3.5
  BOTTOM w0.089: PR4624.2 49.7,77.54 v1(49.67,77.51) 49.67,76.7 48.77,75.8 PU4601.37
SVID_DATA_CPU: length 61.6
  TOP w0.089: v2(89.83,93.82) 89.82,93.82 89.82,94.15 87.64,96.33 83.37,96.33 81.64,98.06 58.49,98.06 54.12,93.69 54.12,93.46 54.12,92.45 v1(54.12,87.6) 54.12,82.55 54.11,82.54 54.11,82.51 53,81.4 53,80.08 51.67,78.75 49.17,78.75 48.15,79.77 v2(48.15,79.93)
  BOTTOM w0.089: v2(89.83,93.82) R709.2 ; PR4604.2 v2(48.15,79.93) 48.15,79.24 PR4622.1
SVID_DATA_CPU_R: length 21.9
  BOTTOM w0.076: CPU1.AA2 106.4,87.53 106.58,87.7 106.6,87.75 106.61,87.78 106.72,88.02 106.72,88.32 106.67,88.45 106.39,88.74 106.39,89.61
  BOTTOM w0.089: 106.39,89.61 104.48,91.51 104.48,92.68 v1(103.1,94.06) 101.64,95.52 92.19,95.52 R726.2 91.25,94.68 R709.1
SVID_DATA_VR: length 3.2
  BOTTOM w0.089: PU4601.35 47.97,75.79 48.16,75.97 48.16,76.99 v1(48.16,77.46) 48.16,78.19 48.15,78.2 48.15,78.38
SYS_LED_MASK#: length 18.8
  TOP w0.127: v2(28.13,22.07) 27.69,21.62 26.95,21.62 26.51,22.07 C2436.1 26.66,22.9 R2457.1 26.66,24.15 PR2455.2 26.86,24.28 27.67,25.09 v1(27.67,25.16) 28.39,25.16 R2410.1
  L6 w0.127: v2(28.13,22.07) 28.89,21.3 30.85,21.3 31.75,20.4 36.37,20.4 v2(37.58,19.2)
  BOTTOM w0.127: U2401.55 37.63,19.19 37.63,19.2 v2(37.58,19.2)
SYS_LED_MASK#_R: length 17
  TOP w0.127: R2456.2 33.06,15.18 v2(33.1,15.18) ; v2(30.8,22.98) 30.67,22.98 30.01,23.64 R6419.1 29.96,24.18 30.14,24.36 v1(30.14,24.68) 30.04,24.68 R2410.2 29.5,25.42 30.19,25.42 30.82,24.78 32.02,24.78 32.42,24.38 U6402.2
  L4SGND w0.127: v2(30.8,22.98) 30.8,21.86 33.1,19.57 v2(33.1,15.18)
SYS_PRES1#: length 3.7
  TOP w0.102: v2(117.15,16.4) 117.13,16.38 AFTP4315.1 R4301.2
  BOTTOM w0.102: BATT1.7 v2(117.15,16.4)
SYS_PWROK: length 213.7
  TOP w0.127: v2(160.01,34.79) v1(160.01,36.62) 159.67,36.96 159.67,41.99 160.77,43.09 160.77,49.73 158.91,51.59 158.91,55.66 160.97,57.72 160.97,61.16 160.52,61.61 160.52,66.72 161.23,67.43 161.23,70.48 162.53,71.78 162.53,76.96 161.67,77.82 161.67,81.38 160.15,82.91 160.15,84.6 158.57,86.18 158.57,86.83 158.24,87.16 157.29,87.16 156.73,86.6 ED1702.1 155.97,86.54 154.89,86.54 R1717.1 154.88,86.58 155.59,87.29 v2(155.59,88)
  L4SGND w0.127: v2(44.62,29.74) 46.01,28.34 50.86,28.34 51.21,28.68 126.02,28.68 126.91,27.79 138.98,27.79 139.87,28.68 149.56,28.68 149.9,28.34 151.29,28.34 153.09,30.14 153.09,31.78 155.12,33.81 159.03,33.81 v2(160.01,34.79)
  L6 w0.127: v2(36.23,30.5) 37.62,30.5 38,30.87 43.48,30.87 v2(44.62,29.74)
  BOTTOM w0.127: U2401.28 36.14,30.4 v2(36.23,30.5) ; v2(155.59,88) 153.94,88 153.1,87.16 153.1,85.09 152.39,84.38 148.76,84.38 148.6,84.55 143.52,84.55 141.59,82.62 139.1,82.62 CPU1.CR10
SYSPWR_PRES: length 3.7
  TOP w0.102: R2454.1 24.85,24.58 v2(25.06,24.79) 25.52,25.24 R2463.2 25.41,25.52 v1(24.6,25.52)
  BOTTOM w0.102: U2401.120 v2(25.06,24.79)
T_CRIT#: length 94.1
  L4SGND w0.102: v2(64.07,4.82) 60.69,1.44 v2(38.65,1.44)
  BOTTOM w0.102: R2601.1 R2604.2 29.2,9.02 30.85,7.37 30.85,7.3 31.42,6.72 31.42,6.36 33.19,4.6 33.19,3.11 34.99,1.3 36.37,1.3 37.05,1.97 38.11,1.97 v2(38.65,1.44) ; v2(64.07,4.82) 64.07,9.14 61.39,11.82 54.26,11.82 47.04,11.82 45.28,13.58 45.28,17.65 45.71,18.08 45.71,19.65 46.17,20.11 47.23,20.11 v1(47.44,20.31) 47.44,25.85 45.35,27.93 45.35,33.34 44.18,34.51 44.18,34.54 43.65,35.07 43.15,35.07 43.05,35.17 U2601.4
TBTA_SENSEN: length 4.5
  TOP w0.089: 9.85,32.22 U7201.A10
  TOP w0.102: 9.85,32.22 9.86,32.22 9.86,32.03 9.58,31.75 9.58,31.28 9.58,31 9.05,30.47 8.7,30.47 v2(8.47,30.24)
  BOTTOM w0.102: R7217.2 7.99,29.58 7.99,29.81 8.42,30.24 v2(8.47,30.24) v1(8.14,30.7)
TBTA_SENSEP: length 5.9
  TOP w0.089: 9.63,32.12 9.63,32.61 9.85,32.83 U7201.B10
  TOP w0.102: 9.63,32.12 9.35,31.84 9.35,31.19 9.35,31.1 8.95,30.7 8.14,30.7 7.8,30.36 v2(7.8,30.26)
  BOTTOM w0.102: R7216.2 7.26,29.53 7.79,30.07 7.79,30.2 7.8,30.21 v2(7.8,30.26) v1(6.93,30.53)
TCH_INTR#: length 20.2
  BOTTOM w0.127: TCBD1.16 129.45,100.47 129.93,100.95 136.63,100.95 ED5502.1 137.95,99.76 v1(138.93,99.76) 139.38,99.76 141.97,97.17 R5523.1
TCH_PNL_3D3V_5V:
  vias: v1(141.72,101.52) v2(143.17,101.62)
TEST_MODE_1: length 2.5
  TOP w0.102: v2(53.91,32.91) 53.51,32.51 TP1201.1
  BOTTOM w0.102: v2(53.91,32.91) 54.69,33.7 RAM4.N9
TEST_MODE_2: length 2.1
  TOP w0.102: v2(84.36,32.91) 84.04,32.6 TP1202.1
  BOTTOM w0.102: v2(84.36,32.91) 85.14,33.7 RAM1.N9
TEST_MODE_3: length 2.1
  TOP w0.102: TP1203.1 63.74,32.6 v2(64.06,32.91)
  BOTTOM w0.102: RAM3.N9 64.84,33.7 v2(64.06,32.91)
TEST_MODE_4: length 2.2
  TOP w0.102: TP1204.1 73.89,32.59 v2(74.21,32.91)
  BOTTOM w0.102: v2(74.21,32.91) 74.21,33.06 74.84,33.7 RAM2.N9
TEST_MODE_5: length 2.2
  TOP w0.102: TP1301.1 106.4,32.91 v2(106.41,32.91)
  BOTTOM w0.102: RAM6.N9 107.19,33.7 v2(106.41,32.91)
TEST_MODE_6: length 2.2
  TOP w0.102: TP1302.1 126.71,32.72 v2(126.71,32.91)
  BOTTOM w0.102: RAM8.N9 127.49,33.7 v2(126.71,32.91)
TEST_MODE_7: length 2.1
  TOP w0.102: v2(116.56,32.91) 116.88,32.6 TP1303.1
  BOTTOM w0.102: v2(116.56,32.91) 117.34,33.7 RAM5.N9
TEST_MODE_8: length 2.1
  TOP w0.102: TP1304.1 137.17,32.6 v2(136.86,32.91)
  BOTTOM w0.102: v2(136.86,32.91) 137.64,33.7 RAM7.N9
THERM_SYS_SHDN#: length 5.8
  BOTTOM w0.102: R2601.2 27.37,10.38 R2602.1 25.43,9.36 Q2602.S v1(22.89,7.98)
THERMTRIP#_CPU: length 9.1
  BOTTOM w0.089: CPU1.BJ1 122.8,88.76 122.8,89.68 121.88,90.6 121.88,92.05 v1(121.6,92.32) 120.89,93.03 R308.2 120.38,93.03 119.24,94.17 ED301.1
TOUCH_DETECT: length 53.4
  L4SGND w0.102: v2(158.67,84.61) 158.92,84.85 158.92,89.55 161.33,91.97 161.33,92.81 161.43,92.92 v2(161.44,92.92)
  BOTTOM w0.102: v2(158.67,84.61) 158.79,84.73 R5504.1 159.63,84.3 R2102.1 ; TCBD1.13 127.95,99.67 129.73,101.45 137.88,101.45 138.74,100.59 139.32,100.59 142.72,97.19 144.19,97.18 147.96,97.18 149.03,96.11 149.71,96.11 158.17,96.11 159.54,94.75 160.74,94.75 161.44,94.05 v1(161.44,93.82) v2(161.44,92.92)
TOUCH_DETECT_R: length 24
  BOTTOM w0.076: CPU1.CN14 138.06,79.95 138.17,79.85 arc(138.23,79.8) 138.31,79.78 138.47,79.78 arc(138.51,79.78) 138.55,79.8 arc(138.61,79.83) 138.67,79.84 138.74,79.84 arc(138.81,79.83) 138.88,79.8 arc(138.98,79.76) 139.08,79.75 142.18,79.75
  BOTTOM w0.102: 142.18,79.75 142.63,80.21 146.9,80.21 149.77,83.08 152.74,83.08 v1(153.28,82.54) 153.66,82.16 156.26,82.16 158.06,83.97 159.09,83.97 R2102.2
TOUCH_PANEL_INTR#: length 11.2
  BOTTOM w0.127: CPU1.CN3 137.94,86.59 138.78,86.59 138.91,86.72 139.14,86.72 139.41,86.99 139.41,87.32 139.9,87.81 139.9,89.08 139.43,89.55 R5507.1 R5505.1 139.51,92.17 v1(140.47,93.13) 141.97,94.63 R5523.2
TOUCH_PANEL_PD#: length 163.3
  L4SGND w0.127: v2(160.82,93.9) 161.1,93.9 162.78,92.22 180.26,92.22 181.52,93.48 186.27,93.48 188.29,91.46 188.29,90.09 187.81,89.61 187.81,69.04 185.46,66.69 185.46,65.17 v2(185.33,65.04) ; v2(174.23,54.53) 173.62,54.53 173.48,54.67 172.79,54.67 165.37,54.67 164.53,53.83 164.27,53.83 164.27,53.82 162.5,53.82 161.07,55.25 145.07,55.25 144.83,55.01 142.33,55.01 139.99,57.35 138.37,57.35 136.73,58.98 136.73,60.06 136.42,60.37 136.03,60.37 134.44,61.96 134.44,63.7 v2(134.65,63.91)
  BOTTOM w0.076: v2(134.65,63.91) 134.66,63.92 134.66,64.41 134.27,64.8 133.53,64.8 132.9,65.43 132.9,65.7 132.79,65.9 132.79,66.53 CPU1.CC35
  BOTTOM w0.127: v2(185.33,65.04) 184.57,65.04 176.57,57.04 175.96,57.04 174.22,55.3 174.22,54.54 v2(174.23,54.53) ; v2(160.82,93.9) 160.35,94.36 v1(160.34,94.36) 160.27,94.44 159.5,94.44 158.07,95.87 148.93,95.87 147.88,96.92 146.42,96.92 142.61,96.92 139.18,100.35 138.64,100.35 137.78,101.21 129.83,101.21 128.95,100.33 TCBD1.15
TOUCH_REPORT_SW: length 236
  TOP w0.102: v2(158.28,83.5) 158.28,82.4 160,80.69 160,77.12 160.67,76.45 160.67,75.43 160.15,74.91 160.15,72.19 159.47,71.51 159.47,67.73 159.02,67.28 159.02,67.15 158.48,66.61 158.48,55.94 158.35,55.82 158.35,50.94 158.41,50.89 158.41,49.93 158.41,47.74 158.59,47.56 158.59,44.16 159.04,43.7 159.04,31.46 v2(157.42,29.84) ; v2(33.34,26.36) 32.96,26.36 32.07,25.47 D2402.A ; v1(127.88,97.71) v2(128.45,97.71)
  L3SGND w0.102: v2(128.45,97.71) 131.02,95.14 135.47,95.14 135.85,94.76 143.34,94.76 144.15,95.57 145.91,95.57 153.84,87.65 154.95,87.65 158.28,84.31 v2(158.28,83.5)
  L4SGND w0.102: v2(157.42,29.84) 157.42,29.08 155.88,27.54 153.26,27.54 153.26,27.54 151.99,27.54 151.78,27.32 143.1,27.32 142.77,26.99 142.13,26.99 136.59,21.46 v2(136.21,21.46)
  L6 w0.102: v2(33.34,26.36) 33.36,26.36 33.72,26 33.82,26 36.42,23.4 36.42,23.2 36.68,22.94 39.86,22.94 40.49,23.58 42.98,23.58 44.08,22.47 54.07,22.47 54.84,23.25 61.26,23.25 63.45,23.25 64.62,22.08 68.98,22.08 69.64,21.42 74.37,21.42 79.73,16.06 88.72,16.06 89.64,16.97 89.64,18.11 90.06,18.53 93.14,18.53 93.63,18.05 99.23,18.05 100.05,17.23 100.56,17.23 105.33,17.23 105.56,17.46 106.83,17.46 106.93,17.56 114.52,17.56 114.65,17.43 116.29,17.43 116.75,17.89 121.96,17.89 123.34,19.27 124.25,19.27 124.91,19.93 125.64,19.93 125.81,19.75 127.36,19.75 128.25,20.64 130.49,20.64 131.03,21.18 135.93,21.18 v2(136.21,21.46)
  BOTTOM w0.102: v2(128.45,97.71) TCBD1.14
TP_65982D_RESET_N: length 1.2
  TOP w0.127: TP7205.1 5.22,35.2 R7229.2
TP_EN#: length 63.9
  TOP w0.127: RN2405.4 30.03,19.37 29.84,19.56 29.58,19.56 29.08,20.06 v1(29.08,21.1) 29.08,21.42 v2(29.53,21.86)
  L6 w0.127: v2(72.2,12.72) 72.07,12.85 67.98,12.85 66.71,14.12 63.22,14.12 62.85,13.74 55.09,13.74 54.52,14.31 54.16,14.31 50.52,14.31 49.2,12.98 45.91,12.98 45.37,13.53 45.37,15.06 42.63,17.8 39.38,17.8 38.42,18.76 38.42,21.33 v2(37.76,21.99) 37.57,22.18 33.42,22.18 32.87,21.63 29.76,21.63 v2(29.53,21.86)
  BOTTOM w0.127: v2(37.76,21.99) 37.89,21.99 38.29,21.59 U2401.49 ; R6504.1 78.14,11.52 77.33,11.52 76.01,12.85 72.33,12.85 v2(72.2,12.72)
TP_ON#_GATE: length 14.7
  BOTTOM w0.102: Q6503.G 90.86,14.62 89.83,14.62 89.37,14.17 88.61,14.17 88.15,14.62 88.15,15.41 87.82,15.74 85.15,15.74 v1(84.14,14.73) 83.53,14.12 C6502.2 83.3,13.58 82.94,13.94 81.57,13.94 81.02,13.38 Q6502.G 79.18,13.38 R6504.2
TP_TPM_GPIO1: length 1.7
  TOP w0.102: TP9103.1 183.16,45.29 U9102.30
TP_TPM_GPIO3: length 1.6
  TOP w0.102: U9102.6 185.98,49.92 TP9102.1
TP_TPM_PP: length 1.8
  TOP w0.102: U9102.4 185.71,48.92 TP9101.1
TP_WAKE_KBC#: length 219.5
  TOP w0.102: R6511.2 84.77,7.56 v2(85.23,8.02) 85.48,8.27 AFTP6536.1 85.08,9.47 85.08,13.89 85.38,14.19 v2(85.99,14.19)
  L4SGND w0.102: v2(73.57,8.02) 71.24,10.36 58.54,10.36 57.42,11.47 50.51,11.47 46.8,15.18 46.8,19.68 46.57,19.91 45.99,19.91 45.12,19.04 42.35,19.04 41.36,18.05 40.12,18.05 39.41,18.76 39.41,28.47 v2(39.54,28.59)
  L6 w0.102: v2(153.46,51.12) 153.46,49.37 155.67,47.15 155.67,43.78 157.27,42.19 157.27,39.39 157.54,39.11 157.62,39.03 157.62,32.44 158.51,31.55 158.51,26.9 158.51,26.41 157.8,25.7 157.8,21.57 155.11,18.88 149.21,18.88 149.05,19.04 144.93,19.04 144.21,19.77 128.61,19.77 127.73,18.88 126.1,18.88 125.62,18.39 124.05,18.39 124.05,18.4 123.72,18.4 123.7,18.39 122.97,17.66 122.32,17.01 121.78,17.01 120.99,16.22 120.99,16.22 119.95,15.18 113.76,15.18 113.76,15.18 110.01,15.18 109.05,16.15 101,16.15 99.61,14.75 96.88,14.75 96.27,15.36 94.79,15.36 93.61,15.36 92.67,16.3 91.06,16.3 88.78,14.01 86.17,14.01 v2(85.99,14.19)
  BOTTOM w0.076: 133.29,64.21 133.29,64.22 132.22,65.29 132.22,65.66 132.25,65.75 132.25,65.99 132.24,66.03 132.22,66.08 132.22,66.5 132.16,66.65 131.82,66.99 CPU1.CB34
  BOTTOM w0.102: v2(39.54,28.59) 39.16,28.21 U2401.33 ; 133.29,64.21 133.36,64.13 133.36,64.11 133.36,63.37 133.64,63.09 133.64,62.53 134.76,61.41 134.76,60.22 R303.2 134.53,59.99 134.53,59.29 134.94,58.88 134.94,56.61 134.57,56.24 134.57,55.58 136.33,53.82 136.65,53.82 137.46,53 138.7,53 138.88,52.82 140.82,52.82 141.48,53.49 142.96,53.49 143.34,53.87 145.88,53.87 147.11,52.63 151.95,52.63 v2(153.46,51.12) ; 83.2,8.7 83.88,8.02 v2(85.23,8.02) ; 83.2,8.7 TPAD1.4 ; 83.2,8.7 82.13,7.64 73.95,7.64 v2(73.57,8.02)
TPM_GPIO0: length 2.2
  TOP w0.127: R9141.1 181.59,45.13 v1(182.24,45.78) 182.66,46.2 U9102.29
TPM_GPIO4: length 1.4
  TOP w0.127: TP9104.1 182.16,52.34 U9102.13
TPM_ID: length 9.6
  BOTTOM w0.102: R1910.2 144.26,72.41 R1911.1 144.01,73.42 142.21,73.42 141.65,73.98 v1(141.49,73.98) 140.75,73.98 140.39,73.63 139.59,73.63 139.33,73.37 138.49,73.37 138.27,73.15 138.27,72.97 138.26,72.96 138.06,72.76 136.84,72.76 136.68,72.92 CPU1.CK25
TPM_SPI_IRQ#: length 66.8
  TOP w0.102: R9139.1 176.24,53.46 176.24,53.08 175.5,52.34 175.27,52.34 v2(175.15,52.47) v1(174.99,51.94)
  L4SGND w0.102: v2(160.57,52.6) 160.77,52.39 161.76,52.39 162.6,53.23 165.65,53.23 166.59,54.17 172.58,54.17 172.77,53.98 173.7,53.98 173.86,53.82 175.38,53.82 175.6,53.59 175.6,52.8 175.27,52.47 v2(175.15,52.47)
  L6 w0.102: v2(160.57,52.6) 159.88,53.28 159.88,53.44 158.55,54.78 158.55,57.44 157.99,58 157.99,61.02 157.99,61.03 157.99,64.12 156.46,65.65 156.03,65.65 153.18,68.5 152.95,68.73 152.95,70.21 152.36,70.8 152.36,72.88 150.52,74.72 150.52,74.84 148.01,77.35 147.75,77.35 147.08,77.35 147.08,77.35 143.03,77.35 142.48,76.8 141.42,76.8 141.33,76.79 140.63,76.09 134.02,76.09 v2(133.47,75.53)
  BOTTOM w0.102: v2(133.47,75.53) 133.84,75.9 CPU1.CF20
TYPEC_DCIN1_EN#: length 82.8
  L4SGND w0.127: v2(18.53,55.72) 18.53,54.93 19.37,54.09 19.37,49.34 19.15,49.13 19.15,47.02 19.31,46.87 19.31,39.3 18.29,38.28 18.29,29.37 18.38,29.28 18.38,24.36 18.93,23.81 22.33,23.81 22.68,23.45 22.68,21.39 22.31,21.02 21.09,21.02 19.04,18.97 19.04,17.16 v2(18.96,17.09)
  L6 w0.127: v2(43.17,15.31) 43.17,14.95 42.97,14.76 37.65,14.76 37.19,15.22 37.19,15.44 36.93,15.7 36.42,15.7 35.36,16.76 32.99,16.76 32.6,16.38 32.6,16.2 32.09,15.69 31.63,15.69 31.03,16.28 31.03,16.51 30.77,16.78 29.66,16.78 29.55,16.68 29,16.68 28.11,15.8 28.11,15.54 27.64,15.07 25.81,15.07 25.26,15.61 24.5,15.61 24.05,16.06 22.56,16.06 22.04,16.58 20.79,16.58 20.29,17.09 v2(18.96,17.09)
  BOTTOM w0.127: Q7407.2 18.02,57.52 R7428.1 17.72,56.53 v2(18.53,55.72) 19.09,55.16 Q7406.2 ; v2(43.17,15.31) 42.2,16.27 v1(41.75,16.27) 41.06,16.27 40.77,15.99 U2401.63
TYPEC_SMBCLK: length 36.1
  TOP w0.089: v1(26.99,15.16) 26.99,15.17 26.99,15.46 v2(27.26,15.73) ; Q2417.1 10.64,23.91 10.88,24.15 R2468.2 14.34,24.15 v2(14.47,24.02) ; RN2413.4 13.52,21.04 v2(13.96,21.48)
  L6 w0.089: v2(27.26,15.73) 27.26,15.74 27.26,16 27.15,16.11 27.15,16.12 27.07,16.19 24.74,16.19 23.44,17.49 21.78,17.49 21.53,17.74 12.31,17.74 10.22,19.83 10.22,21.91 10.69,22.39 12.51,22.39 12.87,22.03 12.87,21.67 13.06,21.48 v2(13.96,21.48)
  BOTTOM w0.089: v2(13.96,21.48) 14.47,21.99 v2(14.47,24.02) ; v2(27.26,15.73) 27.34,15.66 U2401.91
TYPEC_SMBCLK_Q: length 31.3
  TOP w0.089: v2(15.84,41.34) 16.07,41.11 16.07,40.96 16.02,40.91 15.89,40.91 15.79,40.8 R7220.1 ; U7201.B5 12.57,32.72 12.57,31.14 12.49,31.05 v2(12.49,30.75) 12.49,30.65 12.47,30.63 12.47,30.48 12.42,30.43 12.42,25.25 13.02,24.66 v1(14.69,24.66) 15.03,24.32 15.03,23.79 14.69,23.46 11.34,23.46 R2468.1 11.16,22.57 10.85,22.26 Q2417.6
  L6 w0.089: v2(12.49,30.75) 12.67,30.57 13.16,30.57 13.69,31.1 13.69,32.97 14.26,33.55 14.26,38.05 16.07,39.85 16.07,40.92 15.84,41.15 v2(15.84,41.34)
TYPEC_SMBDA: length 35.2
  TOP w0.089: v2(27.62,16.93) 27,16.33 v1(26.66,16.34) ; RN2413.3 11.66,21.04 v2(11.6,20.97) 8.95,20.97 8.84,21.09 Q2417.4 8.23,22.26 R2467.2
  L6 w0.089: v2(11.6,20.97) 12.13,20.98 12.68,21.56 12.68,21.95 12.43,22.19 10.77,22.19 10.41,21.83 10.41,19.91 12.39,17.93 21.61,17.93 21.86,17.68 23.52,17.68 24.82,16.38 27.07,16.38 v2(27.62,16.93)
  BOTTOM w0.089: v2(27.62,16.93) 28.14,16.42 U2401.89
TYPEC_SMBDA_Q: length 30.2
  TOP w0.089: v2(16.5,41.34) 16.26,41.11 16.26,40.96 16.27,40.96 16.33,40.91 16.46,40.91 16.55,40.82 R7221.1 ; Q2417.3 8.56,23.91 8.17,23.51 7.84,23.51 7.84,24.22 8.42,24.81 11.9,24.81 12.23,25.14 12.23,30.24 v2(11.85,30.63) 12.09,30.86 12.09,30.92 12.38,31.21 12.38,32.23 12.35,32.26 U7201.A5
  L6 w0.089: v2(16.5,41.34) 16.5,41.15 16.26,40.92 16.26,39.78 14.45,37.97 14.45,33.47 13.88,32.9 13.88,31.02 13.24,30.38 12.67,30.38 12.63,30.34 12.14,30.34 v2(11.85,30.63)
  BOTTOM w0.089: v2(16.5,41.34) 16.52,41.32 v1(16.52,40.51)
U3_PD#_EC: length 185.2
  TOP w0.102: v2(26.46,11.96) 26.07,12.34 25.57,12.34 24.93,12.97 R2479.2 ; v2(121.15,12.34) 121.15,12.44 121.22,12.51 121.22,15.77 122.82,17.37 122.82,21.89 124.78,23.84 131.08,23.84 131.62,24.39 131.65,24.39 131.76,24.5 136,24.5 136.39,24.12 v1(144.69,24.12) 145.05,24.12 145.2,24.28 151.3,24.28 152.06,23.51 153.08,23.51 153.23,23.67 158.15,23.67 162.45,27.96 165.39,27.96 167.73,30.29 167.73,32.53 170.22,35.02 170.22,37.97 170.7,38.45 v2(170.7,39.06)
  L4SGND w0.102: v2(124,6.36) 123.89,6.47 120.49,6.47 117.82,3.8 106.9,3.8 106.16,3.07 94.17,3.07 93.08,4.16 68.26,4.16 64.86,7.56 55.44,7.56 54.14,6.27 42.91,6.27 42.74,6.44 34.25,6.44 29.48,11.22 29.4,11.22 29.1,11.52 28.13,11.52 27.7,11.96 v2(26.46,11.96)
  BOTTOM w0.102: v2(170.7,39.06) 169.98,39.06 169.55,39.49 CN6601.22 ; v2(121.15,12.34) 124,9.48 v2(124,6.36)
U5703_OUT: length 3.3
  TOP w0.102: R5744.2 33.54,81.63 v1(34.49,81.63) 36.34,81.63 U5703.4
UART_2_CRXD_DTXD: length 206.1
  TOP w0.089: v2(155.66,30.57) 155.71,30.57 156.88,31.75 v1(156.88,36.82) 156.33,37.38 156.33,40.89 157.03,41.59 157.03,45.73 157.04,45.74 157.04,46.5 156.77,46.77 156.77,50.61 156.77,55.06 155.56,56.27 155.56,57.32 156.75,58.51 156.75,65.81 156.59,65.98 156.59,69.95 157.4,70.76 157.4,73.92 158.19,74.71 158.19,80.3 157.12,81.36 147.89,81.36 145.87,83.38 144.22,83.38 v2(144.11,83.49) ; v2(42.05,26.56) 41.9,26.41 R6803.1
  L6 w0.089: v2(155.66,30.57) 156.06,30.17 156.06,29.94 156.07,29.94 156.07,29.53 156.06,29.53 156.06,26.62 155.82,26.38 155.82,23.84 152.42,20.44 144.96,20.44 144.63,20.78 141.79,20.78 140.55,22.02 135.4,22.02 135.14,21.76 131.96,21.76 131.89,21.69 131.54,21.69 131.47,21.76 130.82,21.76 130.22,21.16 128.04,21.16 127.15,20.27 126.24,20.27 126.03,20.27 125.85,20.45 124.69,20.45 124.51,20.27 123.29,20.27 121.79,18.77 117.43,18.77 116.44,19.76 115.95,19.76 115.29,19.1 103.61,19.1 101.92,20.79 101.92,20.86 101.26,21.52 101.26,21.55 101.26,21.56 101.26,22.95 99.68,24.53 96.05,24.53 95.17,25.42 93.17,25.42 90.23,25.42 90.23,25.42 89.14,25.42 88.43,25.42 87.72,26.13 82.7,26.13 81.84,25.27 77.37,25.27 76.32,26.31 72.74,26.31 72.07,25.64 70.91,25.64 70.74,25.64 70.74,25.64 70.33,25.64 70.32,25.65 66.88,25.65 66.08,25.66 56.92,25.66 56.9,25.66 56.85,25.61 55.09,25.61 55.08,25.61 46.21,25.61 45.63,26.19 45.24,26.19 44.74,26.69 42.18,26.69 v2(42.05,26.56)
  BOTTOM w0.089: CPU1.CR12 139.19,81.1 139.39,81.01 139.45,81.01 139.64,80.83 140.87,80.83 141.99,81.95 142.55,81.95 142.8,82.2 143.38,82.2 143.57,82.39 R2048.2 143.96,82.87 144.11,83.03 v2(144.11,83.49)
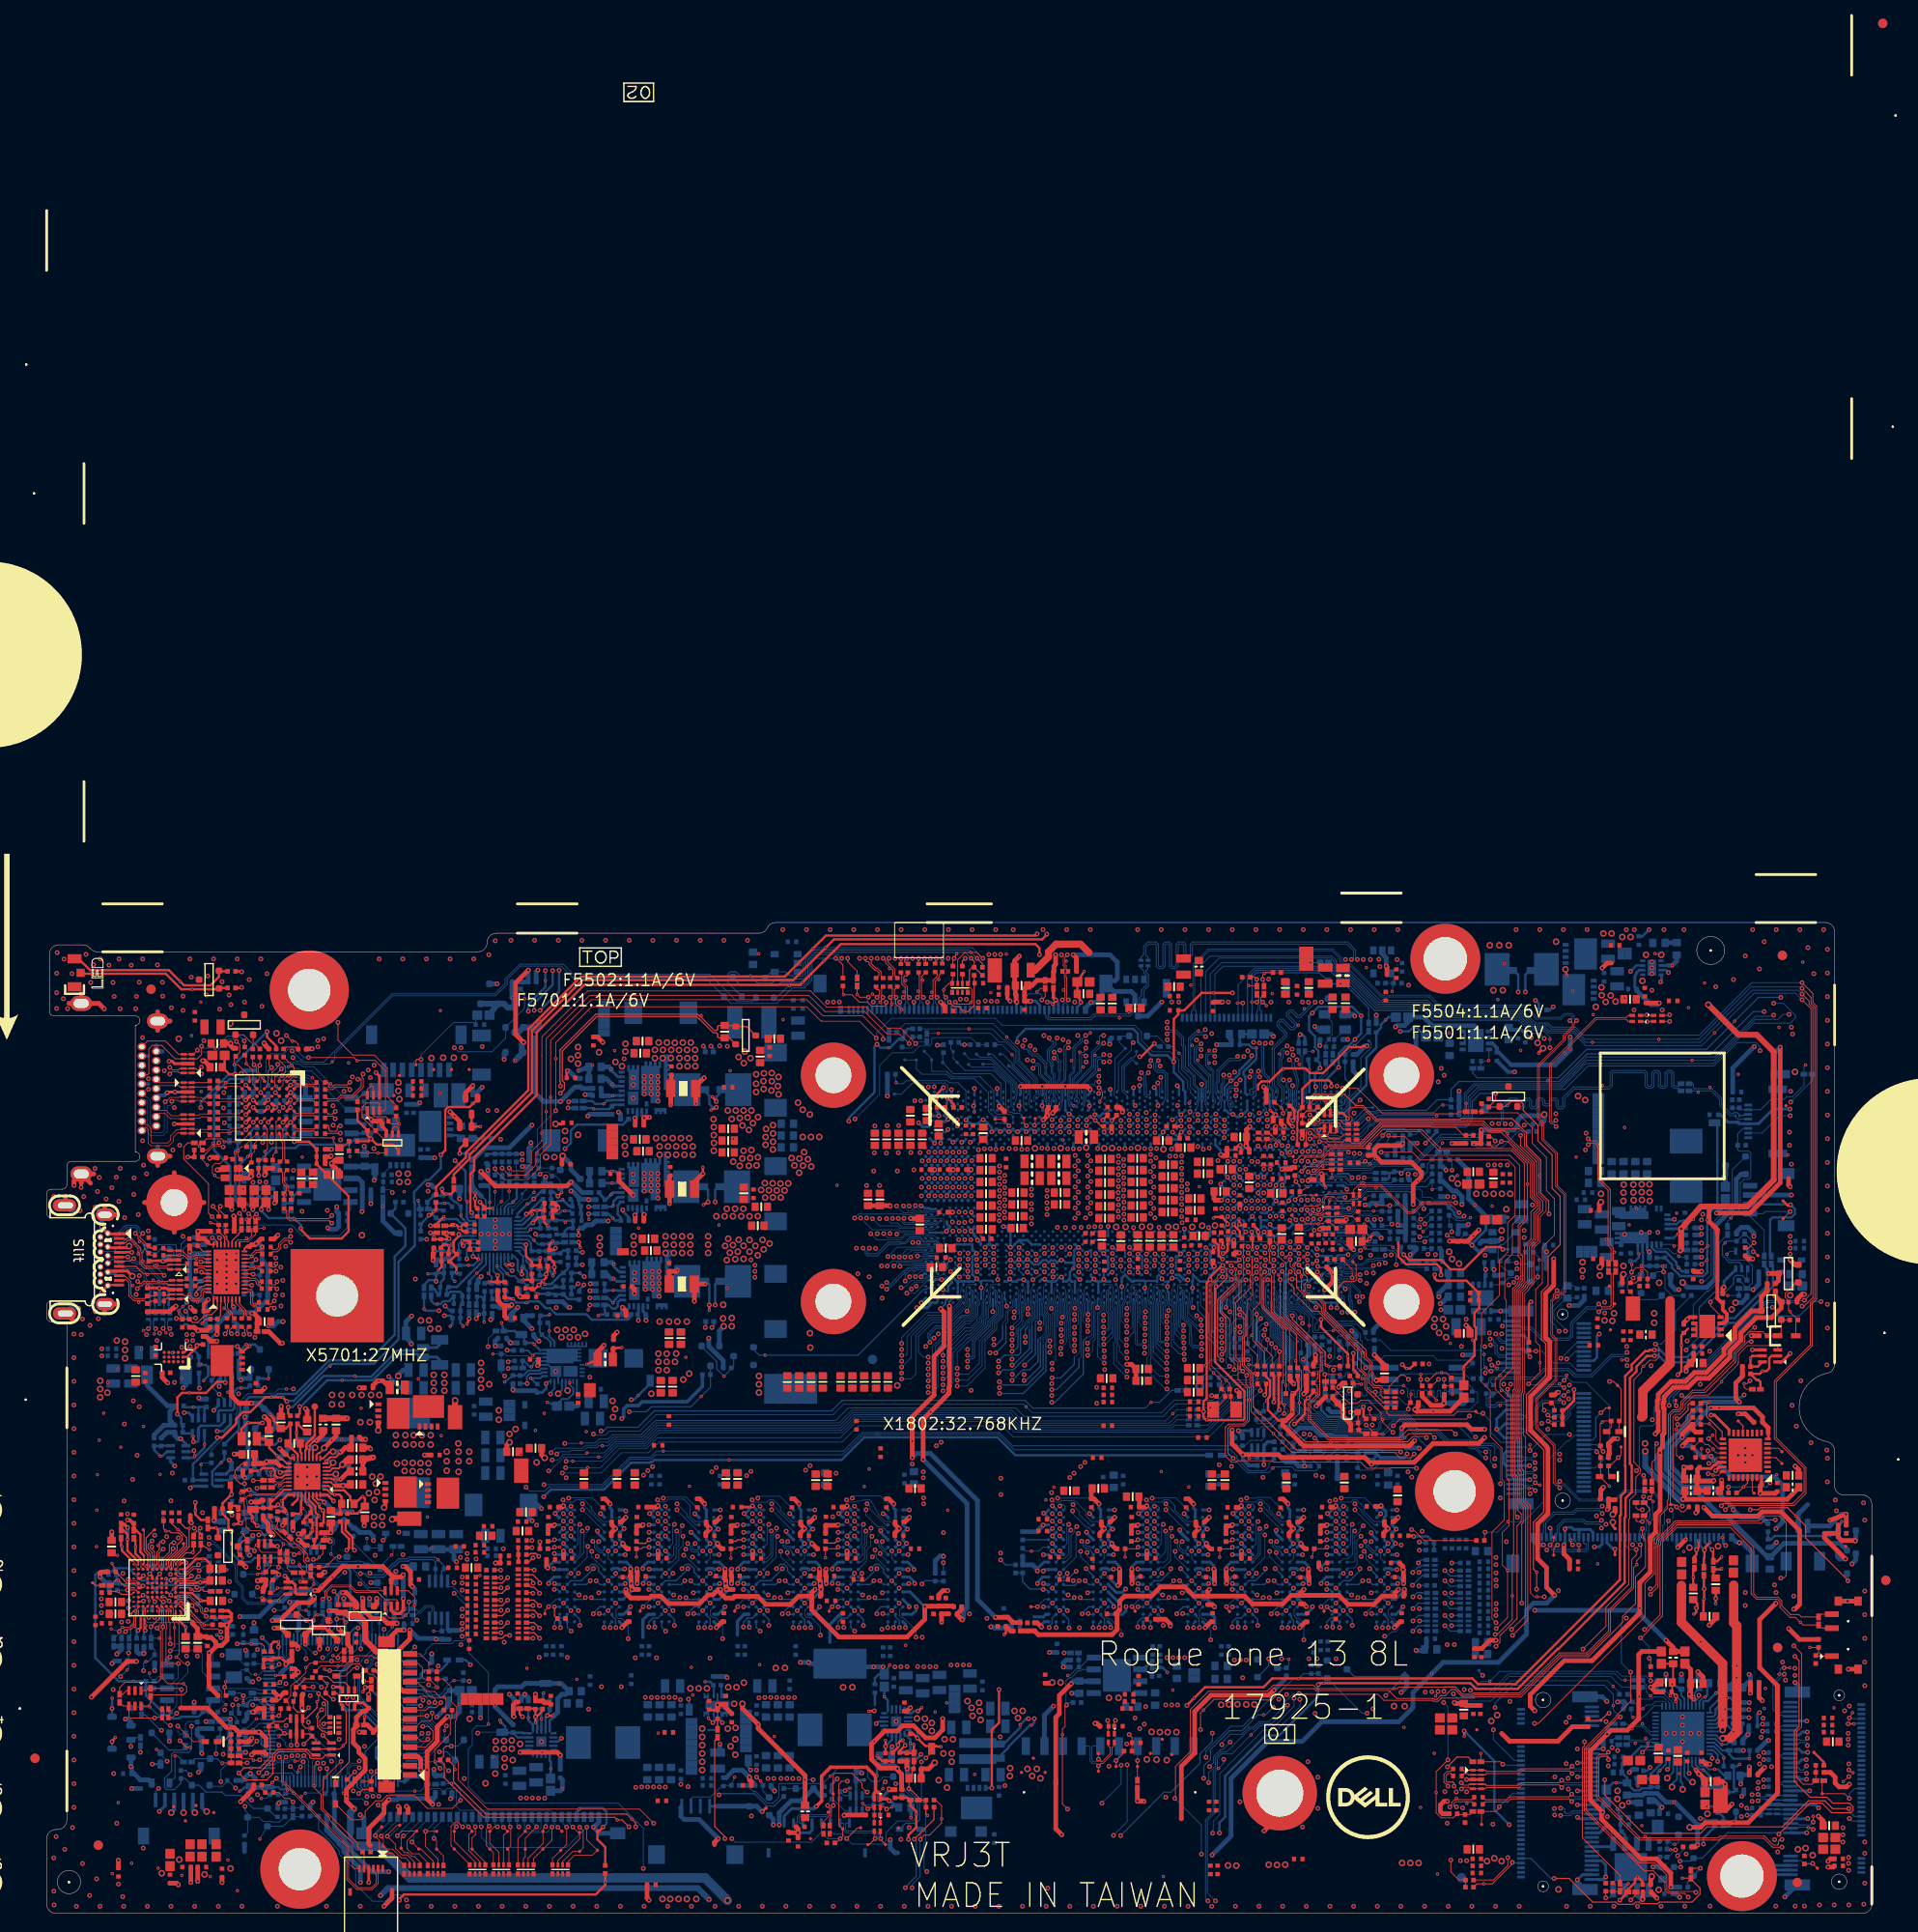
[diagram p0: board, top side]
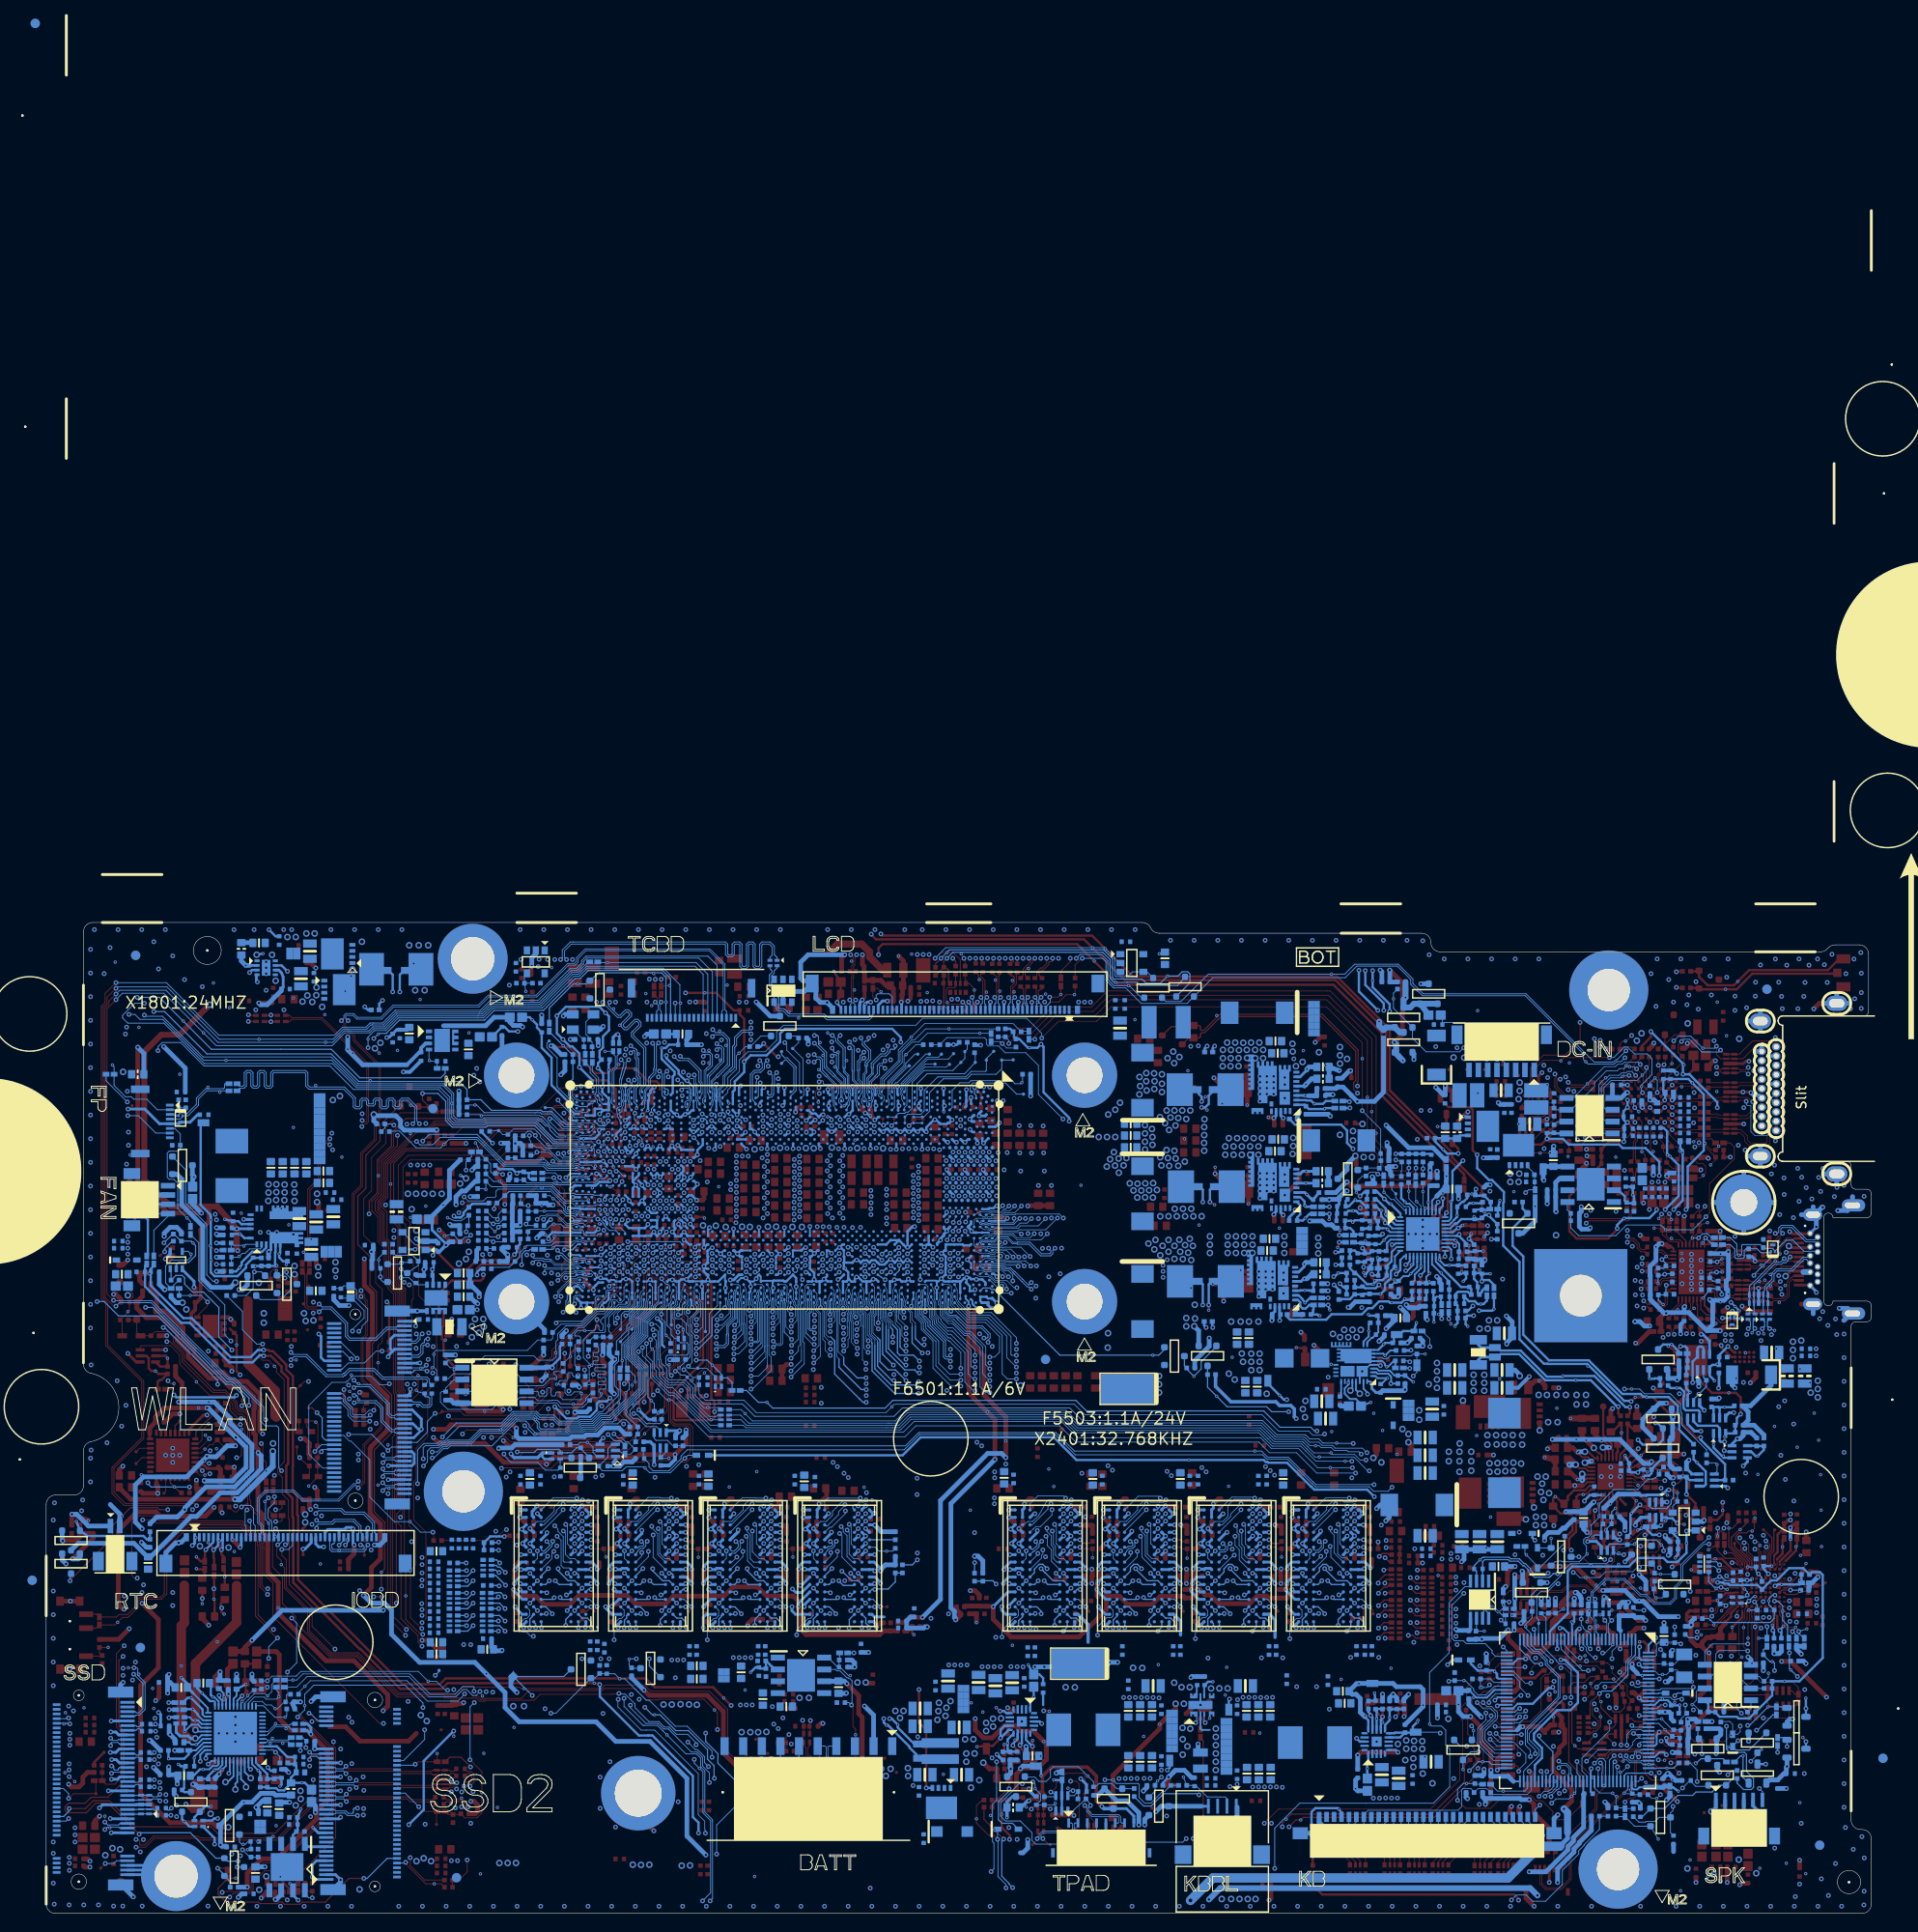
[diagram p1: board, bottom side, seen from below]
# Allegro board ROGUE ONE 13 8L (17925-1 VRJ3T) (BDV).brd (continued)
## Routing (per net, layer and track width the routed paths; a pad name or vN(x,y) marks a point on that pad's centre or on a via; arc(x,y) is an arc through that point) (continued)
UART_2_CRXD_DTXD_CON: length 3.5
  TOP w0.089: R6803.2 41.03,26.71 v1(41.14,26.82) 40.12,27.83 40.12,27.85 DB1.14
UART_2_CTXD_DRXD: length 221.6
  TOP w0.089: v2(65.19,9.67) 63.67,11.19 v1(57.19,11.19) 47.36,11.19 44.21,14.34 44.21,16.3 43.88,16.63 43.88,20.64 44.03,20.79 44.03,22.15 43.47,22.7 43.47,24.26 42.57,25.16 R6802.1 ; v2(155.64,31.21) 155.21,31.63 155.21,40.92 156.54,42.24 156.54,45.93 156.55,45.94 156.55,46.3 156.27,46.57 156.27,49.94 155.03,51.18 155.03,56.1 154.02,57.11 154.02,61 154.09,61.08 154.09,64.41 156.01,66.32 156.01,70.08 156.9,70.97 156.9,74.13 157.69,74.92 157.69,80.09 156.91,80.87 147.49,80.87 146.65,81.7 v2(143.3,81.7)
  L4SGND w0.089: v2(65.19,9.67) 65.19,9.54 69.03,5.7 95.55,5.7 95.78,5.47 113.18,5.47 113.19,5.48 116.8,5.48 119.67,8.34 124.37,8.34 124.7,8.67 125.14,8.67 v2(125.21,8.6)
  L6 w0.089: v2(134.57,22.97) 134.69,23.08 142.86,23.08 143.92,22.02 144.06,22.02 144.17,22.13 144.17,22.46 144.47,22.77 144.91,22.77 145.22,22.46 145.22,22.02 145.76,21.48 152.03,21.48 154.73,24.19 154.73,28.51 154.71,28.54 154.71,30.28 v2(155.64,31.21)
  BOTTOM w0.076: 142,81.7 140.95,80.65 139.57,80.65 139.38,80.84 139.36,80.84 arc(139.07,80.9) 138.82,81.06 138.63,81.25 CPU1.CP12
  BOTTOM w0.089: v2(134.57,22.97) 134.61,22.93 134.61,22.17 132.11,19.67 131.58,19.67 130.66,19.67 125.98,14.99 125.98,10.58 125.29,9.89 125.29,9.01 125.21,8.93 v2(125.21,8.6) ; 142,81.7 v2(143.3,81.7) 143.63,81.37 R2049.2
UART_2_CTXD_DRXD_CON: length 4.7
  TOP w0.089: DB1.13 39.85,26.85 40.37,26.33 40.37,25.32 40.53,25.16 R6802.2 41.09,25.16 v1(42.01,24.24)
UPD1_ALERT_R: length 4.8
  TOP w0.127: v2(11.2,30.76) 12.09,31.65 12.09,32.7 U7201.B6
  BOTTOM w0.127: v1(12.1,29.53) R7235.2 11.2,29.55 v2(11.2,30.76)
UPD1_SMBINT#: length 36.8
  L6 w0.127: v2(35.47,26.74) 35.47,26.82 34.39,27.89 29.44,27.89 29.02,27.48 28.33,27.48 28.04,27.77 27.67,27.77 27.35,27.45 22.56,27.45 22.06,27.95 22.06,28.85 21.3,29.61 19.8,29.61 15.8,25.61 10.85,25.61 v2(10.4,26.05)
  BOTTOM w0.127: v2(35.47,26.74) 35.55,26.82 36.18,26.82 36.68,27.31 36.68,27.51 36.94,27.77 37.14,27.77 37.74,28.37 U2401.32 ; v2(10.4,26.05) 10.4,26.87 10.55,27.02 v1(10.66,27.02) 10.88,27.02 11.6,27.73 R7215.1 11.6,28.29 R7235.1
USB1_CC1: length 43.5
  TOP w0.178: U7201.L9 10.45,37.55 10.45,38.4
  TOP w0.254: USB1.A5 8.45,70.94 8.48,70.96 9.13,70.96 v2(9.15,70.95) ; R7211.1 9.61,41.12 10.07,40.66 10.07,38.78 10.45,38.4
  TOP w0.381: R7211.1 C7217.1 9.27,41.88 8.93,42.22 v2(8.69,42.22)
  L3SGND w0.381: v2(15.08,65.58) 15.1,65.6 15.1,66.87 12.87,69.11 12.08,69.11 10.2,70.99 9.19,70.99 v2(9.15,70.95)
  L4SGND w0.381: v2(8.69,42.22) 9.39,42.22 11.91,44.74 11.91,59.73 13.95,61.76 13.95,63.83 v2(13.93,63.85)
  BOTTOM w0.203: v2(13.93,63.85) 14.69,63.85 14.74,63.89 ED7305.2 14.75,64.05 14.31,64.48 14.31,64.81 v1(14.63,65.13) v2(15.08,65.58)
USB1_CC2: length 46.6
  TOP w0.178: 9.85,37.75 U7201.L10
  TOP w0.254: R7212.1 8.23,41.14 8.49,40.89 8.5,40.89 8.68,40.71 8.68,38.93 9.85,37.75
  TOP w0.381: R7212.1 C7218.1 8.15,41.74 8.37,41.74 8.7,41.42 v2(8.7,41.39)
  L3SGND w0.089: USB1.B5 5.85,69.31 7.2,69.31
  L3SGND w0.381: v2(14.92,64.64) 14.49,65.07 14.49,65.58 10.97,69.09 7.42,69.09 7.2,69.31
  L4SGND w0.381: v2(15.99,63.9) 14.47,62.38 14.47,61.56 12.42,59.52 12.42,44.53 9.16,41.27 8.8,41.27 8.7,41.37 v2(8.7,41.39)
  BOTTOM w0.203: v2(14.92,64.64) 15.15,64.41 ED7305.1 15.98,63.89 v2(15.99,63.9)
  BOTTOM w0.381: v2(8.7,41.39) v1(8.7,40.15)
USB1_SBU1: length 16
  TOP w0.102: USB1.A8 9.6,69.44 10.39,68.65 12.43,68.65 v2(12.61,68.47)
  BOTTOM w0.102: v2(12.61,68.47) 12.61,68.54 v1(11.64,69.51) 10.78,70.37 ED7306.2 10.92,70.91 11.85,70.91 12.28,71.34 R7330.1 13.45,71.34 13.65,71.14 13.65,70.41 13.77,70.3 14.57,70.3 14.67,70.4 14.67,71.3 15.15,71.77 R7153.2
USB1_SBU1_R: length 2.9
  TOP w0.102: v2(17.8,72.51) 17.89,72.51 18.32,72.08 U7101.27
  BOTTOM w0.102: v1(18.1,71.93) v2(17.8,72.51) 17.07,71.77 R7153.1
USB1_SBU2: length 14
  BOTTOM w0.089: USB1.B8 5.84,71.06 5.85,71.07 6.76,71.07 7.23,71.06
  BOTTOM w0.102: 7.23,71.06 8.42,72.26 9.16,72.26 ED7306.1 10.38,71.14 10.61,71.37 11.5,71.37 R7331.1 11.61,71.47 11.93,71.79 13.83,71.79 13.93,71.68 13.93,70.76 14.03,70.66 v1(14.24,70.66) 14.34,70.66 14.44,70.76 14.44,71.83 15.15,72.54 R7151.2
USB1_SBU2_R: length 3.5
  TOP w0.102: U7101.26 18.72,72.35 v2(18.56,72.51)
  BOTTOM w0.102: R7151.1 17.18,72.54 17.59,72.94 18.12,72.94 v2(18.56,72.51) 18.58,72.48 v1(19.22,72.48)
USB1_SSRX_CON_N1: length 8.9
  TOP w0.102: v1(9.97,72.11) 10.06,72.2 ; 10.06,72.2 10.53,71.73 10.53,71.29 R7120.2 11.19,70.63 C7121.2 ; 10.06,72.2 9.8,72.46 9.8,72.72 v2(9.53,72.99)
  BOTTOM w0.102: USB1.B10 6.05,72.07 7.02,72.07 8.56,73.62 9.58,73.62 9.72,73.48 9.72,73.17 v2(9.53,72.99)
USB1_SSRX_CON_N2: length 6.2
  TOP w0.102: USB1.A10 8.35,68.44 8.54,68.25 8.6,68.25 9.06,67.79 9.06,67.39 ; 9.06,67.39 9.06,66.38 9.19,66.25 9.45,65.98 10.53,65.98 R7122.2 11.44,66.26 C7122.2 ; 9.06,67.39 v1(9.26,67.39)
USB1_SSRX_CON_P1: length 8.6
  TOP w0.102: C7120.2 11.24,71.39 R7119.2 10.91,71.67 10.03,72.55 10.03,72.7 v2(10.32,72.99)
  BOTTOM w0.102: USB1.B11 6.06,72.3 6.92,72.3 8.33,73.71 8.47,73.85 9.68,73.85 9.95,73.58 9.95,73.14 10.1,72.99 v2(10.32,72.99)
USB1_SSRX_CON_P2: length 6.1
  TOP w0.102: C7123.2 11.24,65.73 10.96,65.45 R7123.2 10.5,65.75 9.89,65.75 ; USB1.A11 8.3,67.94 8.37,68.02 8.51,68.02 8.83,67.7 8.83,66.29 9.36,65.75 9.89,65.75 ; 9.89,65.75 v1(9.89,65.58)
USB1_SSRX_MUX_N1: length 5.1
  TOP w0.102: C7121.1 12.54,70.62 ED7301.7 ED7301.4 14.73,70.62 15.1,70.25 15.89,70.25 16.01,70.38 16.85,70.38 16.98,70.25 U7101.31
USB1_SSRX_MUX_N2: length 6
  TOP w0.102: v1(15.33,66.46) 15.33,66.29 ; 15.33,66.29 14.82,66.29 14.66,66.45 ED7302.2 ED7302.9 13.18,66.45 13.07,66.34 12.74,66.34 C7122.1 ; 15.33,66.29 15.4,66.29 15.7,65.98 16.26,65.98 16.57,66.3 16.57,66.73 16.81,66.97 17,66.97 17.09,67.05 U7101.39
USB1_SSRX_MUX_P1: length 5.4
  TOP w0.102: 16.19,70.6 16.88,70.6 16.93,70.65 U7101.30 ; 16.19,70.6 15.92,70.6 15.79,70.48 15.2,70.48 14.56,71.12 ED7301.5 ED7301.6 12.83,71.12 12.56,71.39 C7120.1 ; 16.19,70.6 v1(16.19,70.76)
USB1_SSRX_MUX_P2: length 5.9
  TOP w0.102: U7101.40 17.1,66.65 17.01,66.74 16.9,66.74 16.8,66.64 16.8,66.2 16.35,65.75 16.22,65.75 ; 16.22,65.75 15.61,65.75 15.3,66.06 14.77,66.06 14.66,65.95 ED7302.1 ED7302.10 13.1,65.95 13.03,66.02 12.88,66.02 C7123.1 ; 16.22,65.75 v1(16.22,65.63)
USB1_SSTX_CON_N1: length 9.8
  TOP w0.102: 9.92,70.89 10.02,70.79 10.02,69.72 10.51,69.23 10.7,69.23 12.99,69.23 13.1,69.12 ED7301.10 ED7301.1 14.96,69.12 C7163.1 ; 9.92,70.89 v1(9.82,70.78) ; 9.92,70.89 9.82,71 9.82,71.37 9.39,71.8 9.39,71.87 9,72.26 8.73,72.26 8.42,71.94 USB1.A3
USB1_SSTX_CON_N2: length 10.3
  TOP w0.102: v2(9.77,67.82) 10.01,67.58 10.15,67.58 10.38,67.81 11.44,67.81 ; 11.44,67.81 v1(11.44,67.96) ; 11.44,67.81 12.97,67.81 13.1,67.95 ED7302.6 ED7302.5 14.88,67.95 C7162.1
  L6 w0.089: v2(9.77,67.82) 9.51,67.56 8.64,67.56 7.97,68.23 6.13,68.23 USB1.B3
USB1_SSTX_CON_P1: length 9.8
  TOP w0.102: 11.85,69.46 12.97,69.46 13.13,69.62 ED7301.9 ED7301.2 14.98,69.62 C7164.1 ; 11.85,69.46 v1(11.85,69.59) ; 11.85,69.46 10.61,69.46 10.25,69.82 10.25,70.89 10.05,71.09 10.05,71.46 9.62,71.89 9.62,71.96 9.09,72.48 8.64,72.48 8.52,72.37 8.36,72.37 8.29,72.44 USB1.A2
USB1_SSTX_CON_P2: length 10.1
  TOP w0.102: v2(9.74,67.06) 10.04,67.35 10.24,67.35 10.47,67.58 12.94,67.58 13.08,67.45 ED7302.7 ED7302.4 14.96,67.45 C7161.1
  L6 w0.089: v2(9.74,67.06) 9.43,67.37 8.56,67.37 7.89,68.04 6.02,68.04 USB1.B2
USB1_SSTX_MUX_N1: length 1.6
  TOP w0.102: C7163.2 16.3,69.26 16.85,69.26 17.06,69.05 U7101.34
USB1_SSTX_MUX_N2: length 1.6
  TOP w0.102: C7162.2 16.14,67.94 16.68,67.94 16.99,68.25 U7101.36
USB1_SSTX_MUX_P1: length 1.5
  TOP w0.102: C7164.2 16.27,69.49 16.95,69.49 16.98,69.45 U7101.33
USB1_SSTX_MUX_P2: length 1.6
  TOP w0.102: U7101.37 16.91,67.85 16.77,67.71 16.32,67.71 C7161.2
USB1_USB20_N: length 87
  TOP w0.102: v1(163.69,40.07) 163.69,39.72 163.87,39.54 v2(163.87,39.54)
  L6 w0.089: v2(163.87,39.54) 164.39,40.07 167.74,40.07 169.3,41.63 169.3,45.53 168.08,46.76 168.08,50.21 167.48,50.82 167.48,56.03 167.18,56.33 167.18,61.42 169.1,63.34 169.1,64.41 165.9,67.61 165.9,70.44 163.23,73.1 163.23,78.11 159.21,82.14 158.79,82.14 154.12,82.14 151.49,84.77 143.19,84.77 142.26,85.69 141.27,85.69 139.23,87.72 133.68,87.72 133.2,88.2 133.2,89.09 v2(132.83,89.45)
  BOTTOM w0.076: CPU1.CE3 133.3,87.17 133.41,87.43 133.41,87.62 133.38,87.71 133.38,87.99 133.41,88.08 133.41,88.33 133.07,88.67 133.07,89.21 v2(132.83,89.45)
  BOTTOM w0.102: v2(163.87,39.54) 163.55,39.86 CN6601.34
USB1_USB20_P: length 87
  TOP w0.102: v2(164.54,39.53) v1(164.54,38.96)
  L6 w0.089: v2(133.48,89.44) 133.39,89.35 133.39,88.28 133.76,87.91 139.31,87.91 141.35,85.88 142.34,85.88 143.26,84.96 151.57,84.96 154.19,82.33 157.75,82.33 159.28,82.33 163.42,78.19 163.42,73.18 166.09,70.52 166.09,67.69 169.29,64.49 169.29,63.26 167.37,61.34 167.37,56.41 167.67,56.11 167.67,50.9 168.27,50.29 168.27,46.84 169.5,45.61 169.5,41.55 167.82,39.88 165.42,39.88 v2(164.54,39.53)
  BOTTOM w0.076: v2(133.48,89.44) 133.24,89.2 133.24,88.74 133.58,88.4 133.58,88.05 133.54,87.96 133.54,87.74 133.58,87.65 133.58,87.39 133.45,87.1 133.44,87.07 133.43,87.05 133.43,86.78 CPU1.CE4
  BOTTOM w0.102: CN6601.33 164.05,40.02 v2(164.54,39.53)
USB1_USB30_RX_N: length 80.2
  L6 w0.089: v2(131.08,85.16) 131.2,85.04 132.53,85.04 134.01,86.52 136.78,86.52 139.1,84.19 142.09,84.19 143.22,83.06 144.93,83.06 145.3,83.43 151.11,83.43 153.56,80.98 157.5,80.98 162,76.47 162,75.99 162,72.35 163.21,71.14 163.21,67.66 165.33,65.54 165.33,48.8 165.92,48.2 165.92,42.39 166.41,41.91 166.69,41.91 v2(166.97,42.19)
  BOTTOM w0.102: CPU1.CB5 v2(131.08,85.16) ; CN6601.37 162.05,40.72 162.19,40.86 162.19,41.56 162.92,42.29 165.05,42.29 165.34,42 166.79,42 v2(166.97,42.19)
USB1_USB30_RX_P: length 80.2
  L6 w0.089: v2(131.09,84.48) 131.46,84.85 132.61,84.85 134.09,86.33 136.7,86.33 139.03,84 142.01,84 143.14,82.87 145.01,82.87 145.38,83.24 151.03,83.24 153.48,80.79 157.42,80.79 161.81,76.4 161.81,75.99 161.81,72.27 163.02,71.06 163.02,67.58 165.14,65.46 165.14,48.72 165.73,48.12 165.73,42.31 166.33,41.72 166.61,41.72 v2(166.97,41.35)
  BOTTOM w0.102: CN6601.36 162.55,40.68 162.42,40.81 162.42,41.46 163.02,42.06 164.96,42.06 165.24,41.78 166.79,41.78 166.97,41.6 v2(166.97,41.35) ; v2(131.09,84.48) CPU1.CB6
USB1_USB30_TX_N: length 82.2
  L6 w0.089: v2(130.21,85.9) 130.49,86.17 130.49,86.35 131.33,87.19 131.49,87.19 131.49,87.19 137.2,87.19 139.51,84.88 142.41,84.88 143.05,84.23 151.36,84.23 153.95,81.64 157.78,81.64 162.71,76.7 162.71,72.69 163.87,71.53 163.87,67.96 165.99,65.84 165.99,49.07 166.6,48.46 166.6,43.64 166.73,43.51 166.86,43.51 v2(167.05,43.71)
  BOTTOM w0.102: v2(167.05,43.71) 166.79,43.45 164.28,43.45 163.9,43.07 161.84,43.07 160.74,41.98 160.74,40.91 160.55,40.72 CN6601.40 ; v2(130.21,85.9) 130.49,85.9 130.71,86.11 CPU1.CA4
USB1_USB30_TX_P: length 82.1
  L6 w0.089: v2(131.01,85.81) 130.68,86.14 130.68,86.27 131.41,87 137.12,87 139.43,84.69 142.33,84.69 142.97,84.04 151.28,84.04 153.87,81.45 157.7,81.45 162.52,76.62 162.52,72.61 163.68,71.46 163.68,67.88 165.8,65.76 165.8,48.99 166.41,48.39 166.41,43.56 v2(167.05,42.92)
  BOTTOM w0.102: CPU1.CA3 130.71,86.65 131.01,86.35 131.01,85.82 131,85.82 131,85.81 v2(131.01,85.81) ; v2(167.05,42.92) 166.75,43.22 164.37,43.22 164,42.84 161.93,42.84 160.97,41.88 160.97,40.79 161.05,40.71 CN6601.39
USB2_ID: length 1.3
  TOP w0.102: R1601.1 132.8,83.28 v2(132.88,83.2)
  BOTTOM w0.102: CPU1.CE8 133.21,83.53 v2(132.88,83.2)
USB2_VBUSSENSE: length 2.9
  TOP w0.102: v2(132.77,85.88) 132.77,86.26 v1(132.6,86.43) 131.97,87.06 R1602.1
  BOTTOM w0.102: v2(132.77,85.88) 132.8,85.85 132.8,85.81 132.83,85.78 132.83,85.23 CPU1.CC6
USB4_USB20_CMC_N1: length 28.1
  TOP w0.102: v2(12.51,39.89) 12.21,39.89 12.1,39.79 12.1,39.49 ; U7201.L6 11.85,38.76 12.1,39.02 12.1,39.49 ; 12.1,39.49 v1(11.95,39.49)
  L6 w0.089: v2(13.22,62.76) 12.93,62.47 12.93,61.46 11.66,60.19 11.66,41.92 12.24,41.33 12.24,40.16 v2(12.51,39.89)
  BOTTOM w0.102: v2(13.22,62.76) 12.99,62.99 12.99,63.51 EL7201.1
USB4_USB20_CMC_N2: length 28.2
  TOP w0.102: U7201.L7 11.35,38.7 10.88,39.17 10.88,39.57 11.29,39.97 v2(11.32,39.97)
  L6 w0.089: v2(11.32,39.97) 10.68,40.61 10.68,61.01 11.39,61.72 11.39,62.44 v2(11.71,62.76)
  BOTTOM w0.102: EL7202.1 11.47,63.53 11.47,63 v2(11.71,62.76) 11.57,62.24 11.56,62.23 v1(11.56,62.2)
USB4_USB20_CMC_P1: length 29
  TOP w0.102: v2(12.51,39.1) 12.51,39.1 12.08,38.67 12.08,37.17 U7201.K6
  L6 w0.089: v2(12.51,39.1) 12.37,39.1 12.05,39.41 12.05,41.25 11.47,41.84 11.47,60.27 12.74,61.54 12.74,62.55 v2(12.51,62.78)
  BOTTOM w0.102: EL7201.4 12.71,63.54 12.71,62.98 v2(12.51,62.78) v1(12.81,62.31)
USB4_USB20_CMC_P2: length 28.5
  TOP w0.102: U7201.K7 11.58,37.17 11.58,38.8 11.29,39.09 v2(11.29,39.34)
  L6 w0.089: v2(11.29,39.34) 10.77,39.86 10.77,40.25 10.49,40.53 10.49,60.93 10.49,60.93 10.49,61.08 11.2,61.8 11.2,62.48 v2(10.92,62.76)
  BOTTOM w0.102: EL7202.4 11.16,63.53 11.16,63 v2(10.92,62.76) v1(10.39,62.57)
USB4_USB20_CON_N1: length 9.8
  TOP w0.102: v2(9.36,70.27) 9.26,70.17 8.9,70.02 8.4,70.02 8.32,69.94 USB1.A7
  BOTTOM w0.102: 10.33,69.89 9.74,69.89 v2(9.36,70.27) ; 10.33,69.89 v1(10.33,70.02) ; 10.33,69.89 10.5,69.89 13.1,67.29 ED7303.10 ED7303.1 13.1,64.49 EL7201.2
USB4_USB20_CON_N2: length 9.8
  BOTTOM w0.102: USB1.B7 6.73,70.43 7.33,70.43 8.57,69.18 10.21,69.18 10.68,68.71 10.68,68.57 ; v1(10.83,68.57) 10.68,68.57 ; 10.68,68.57 10.68,68.06 11.45,67.29 11.45,66.87 11.6,66.72 ED7303.7 ED7303.4 11.6,64.44 EL7202.2
USB4_USB20_CON_P1: length 9.5
  TOP w0.102: USB1.A6 8.7,70.44 v2(8.72,70.46)
  BOTTOM w0.102: v2(8.72,70.46) 8.72,70.46 8.72,70.46 8.93,70.25 8.93,70.1 9.18,69.84 9.47,69.84 9.65,69.66 10.41,69.66 12.13,67.94 ; 12.13,67.94 v1(12.03,67.84) ; 12.13,67.94 12.6,67.47 ED7303.9 ED7303.2 12.6,64.46 EL7201.3
USB4_USB20_CON_P2: length 9.6
  BOTTOM w0.102: EL7202.3 11.1,64.51 ED7303.5 ED7303.6 11.1,66.72 11.22,66.83 11.22,67.2 10.95,67.47 ; v1(10.83,67.35) 10.95,67.47 ; 10.95,67.47 10.45,67.96 10.45,68.62 10.11,68.95 8.48,68.95 7.23,70.2 6.98,70.2 USB1.B6
USB4_USB20_N: length 192.9
  TOP w0.102: U7201.K5 12.58,37.17 12.58,37.86 13.41,38.68 13.41,38.97 v2(13.58,39.15)
  L4SGND w0.089: v2(133.21,93.11) 132.09,93.11 131.78,92.79 129.64,92.79 122.33,100.11 100.68,100.11 100.33,100.45 50.84,100.45 49.15,98.76 35.74,98.76 30.42,93.45 29.37,93.45 v2(29.12,93.69)
  L6 w0.089: v2(13.58,39.15) 13.36,39.49 13.24,39.61 13.24,39.99 13.34,40.08 13.34,42.73 12.18,43.88 12.18,59.8 14.07,61.69 14.07,62.83 13.06,63.85 13.06,70.07 15.37,72.38 16.18,72.38 16.25,72.38 19.27,75.4 19.27,77.06 16.82,79.51 16.82,83.56 15.8,84.57 15.8,91.61 16.67,92.49 25.31,92.49 26.24,93.41 28.84,93.41 v2(29.12,93.69)
  BOTTOM w0.102: v1(132.4,92.25) 132.55,92.25 ; 132.55,92.25 132.55,92.64 132.62,92.71 132.76,92.86 132.96,92.86 v2(133.21,93.11) ; 132.55,92.25 132.55,91.89 132.39,91.73 132.39,89.91 132.2,89.72 132.2,88.99 132.65,88.54 132.65,87.27 CPU1.CD3
USB4_USB20_P: length 193
  TOP w0.102: v2(13.67,39.78) 13.39,39.78 13.18,39.57 13.18,38.78 12.35,37.95 U7201.L5
  L4SGND w0.089: v2(29.12,93.01) 29.37,93.26 30.5,93.26 35.82,98.57 49.23,98.57 50.92,100.26 100.25,100.26 100.6,99.92 122.25,99.92 129.56,92.6 131.86,92.6 132.17,92.92 132.67,92.92 132.76,92.83 132.76,92.52 132.92,92.36 v2(133.21,92.36)
  L6 w0.089: v2(13.67,39.78) 13.53,39.92 13.53,42.81 12.37,43.96 12.37,59.72 14.26,61.61 14.26,62.91 13.25,63.92 13.25,70 15.44,72.19 16.1,72.19 16.33,72.19 19.46,75.32 19.46,77.14 17.01,79.59 17.01,83.63 15.99,84.65 15.99,91.53 16.75,92.3 25.39,92.3 26.32,93.22 28.91,93.22 v2(29.12,93.01)
  BOTTOM w0.102: v1(132.78,90.59) 132.61,90.59 ; 132.61,90.59 132.61,91.63 132.78,91.8 132.78,92.55 132.86,92.63 132.94,92.63 v2(133.21,92.36) ; 132.61,90.59 132.61,89.81 132.42,89.62 132.42,89.09 132.88,88.63 132.88,87.07 132.59,86.78 CPU1.CD4
USB4_USB30_RX_C_N: length 2.6
  TOP w0.102: U7101.4 19.12,65.55 19.19,65.47 19.19,64.94 ; C7106.2 19.69,64.2 19.69,64.34 19.19,64.85 19.19,64.94 ; 19.19,64.94 v1(19.04,64.94)
USB4_USB30_RX_C_P: length 2.4
  TOP w0.102: C7105.2 19.92,64.11 19.92,64.44 19.42,64.94 19.42,65.45 19.52,65.55 U7101.5
USB4_USB30_RX_N: length 151.5
  TOP w0.102: v2(19.17,62.2) 19.39,62.43 19.39,62.93 C7106.1
  L4SGND w0.089: v2(129.2,85.08) 129,85.37 128.8,85.58 128.75,85.74 128.75,85.92 128.6,86.07 128.6,89.87 127.75,90.72 127.01,90.72 126.11,91.62 126.11,94.09 121.74,98.47 99.61,98.47 99.14,98.94 51.57,98.94 49.59,96.96 36.82,96.96 29.63,89.77 29.63,71.15 27.89,69.41 27.89,63.99 26.11,62.21 23.84,62.21 22.64,61 21.46,61 21.09,61.37 19.76,61.37 19.41,61.73 19.41,61.96 v2(19.17,62.2)
  BOTTOM w0.102: CPU1.BW6 v2(129.2,85.08)
USB4_USB30_RX_P: length 151.5
  TOP w0.102: C7105.1 20,62.96 19.62,62.58 19.62,62.45 v2(19.85,62.22)
  L4SGND w0.089: v2(19.85,62.22) 19.6,61.97 19.6,61.81 19.84,61.56 21.17,61.56 21.54,61.19 22.56,61.19 23.76,62.4 26.03,62.4 27.7,64.07 27.7,69.49 29.44,71.23 29.44,89.85 36.74,97.15 49.51,97.15 51.49,99.13 99.22,99.13 99.69,98.66 121.82,98.66 126.3,94.17 126.3,91.7 127.09,90.91 127.83,90.91 128.79,89.95 128.79,86.15 v2(129.2,85.74)
  BOTTOM w0.102: v2(129.2,85.74) 129.36,85.9 129.5,85.9 129.75,85.65 129.75,85.58 CPU1.BW5
USB4_USB30_TX_C_N: length 2.7
  TOP w0.102: 20.91,64.9 20.32,65.49 U7101.7 ; 20.91,64.9 21.17,64.64 21.17,64.1 C7104.2 ; 20.91,64.9 v1(20.79,64.79)
USB4_USB30_TX_C_P: length 2.5
  TOP w0.102: U7101.8 20.72,65.41 21.4,64.73 21.4,64.23 C7103.2
USB4_USB30_TX_N: length 148.6
  TOP w0.102: C7104.1 21.3,62.6 21.3,62.27 v2(21.17,62.15)
  L4SGND w0.089: v2(130.14,90.39) 129.83,90.7 129.83,91.08 129.38,91.53 127.32,91.53 126.96,91.89 126.96,94.45 122.08,99.33 100.11,99.33 99.65,99.79 51.22,99.79 49.24,97.81 37.01,97.81 36.46,97.81 36.46,97.81 28.78,90.12 28.78,71.72 27.04,69.98 27.04,64.34 25.76,63.06 21.73,63.06 21.35,62.68 21.35,62.32 v2(21.17,62.15)
  BOTTOM w0.102: CPU1.BW2 129.86,87.8 129.86,88.22 129.85,88.23 129.85,90.1 v2(130.14,90.39)
USB4_USB30_TX_P: length 148.5
  TOP w0.102: C7103.1 21.53,62.73 21.53,62.43 21.81,62.15 21.83,62.15 21.83,62.15 v2(21.81,62.15)
  L4SGND w0.089: v2(21.81,62.15) 21.54,62.42 21.54,62.6 21.81,62.87 25.84,62.87 27.23,64.26 27.23,69.91 28.97,71.65 28.97,90.05 34.76,95.84 36.54,97.62 49.32,97.62 51.3,99.6 99.57,99.6 100.03,99.14 122,99.14 126.77,94.37 126.77,91.81 127.24,91.34 129.3,91.34 129.64,91 129.64,90.7 v2(129.33,90.39)
  BOTTOM w0.102: CPU1.BW1 129.58,87.94 129.47,87.83 129.33,87.83 129.2,87.95 129.2,88.36 129.33,88.49 129.55,88.49 129.62,88.55 129.62,90.1 v2(129.33,90.39)
USB_ADT: length 10.3
  TOP w0.508: v2(22.01,54.76) 20.64,54.76 19.85,55.54 19.85,57.55
  BOTTOM w0.508: PD4408.2 24.55,52.17 24.55,53.04 23.43,54.16 PD4401.2 22.75,54.76 v2(22.01,54.76)
  vias: v1(14.52,57.42) v1(16.55,58.95)
USB_EN#: length 166.3
  TOP w0.102: v1(32.2,31.29) 31.89,31.59 v2(31.15,31.59)
  L4SGND w0.102: v2(44.49,28.85) 45.24,28.1 50.96,28.1 51.31,28.44 125.64,28.44 127.32,26.76 127.57,26.76 130.6,23.74 130.6,20.74 130.93,20.41 136.98,20.41 142.84,26.27 143.07,26.27 143.39,26.59 152.73,26.59 152.96,26.82 156.18,26.82 159.91,30.54 163.67,30.54 169.34,36.2 170.34,36.2 173.13,38.98 173.13,41.1 v2(174.16,42.13)
  L6 w0.102: v2(31.15,31.59) 31.18,31.56 31.22,31.6 34.52,31.6 36.23,29.89 43.45,29.89 v2(44.49,28.85)
  BOTTOM w0.102: U2401.13 30.14,30.01 30.39,30.27 30.6,30.27 30.93,30.6 30.93,30.73 31.15,30.96 v2(31.15,31.59) R2434.2 ; v2(174.16,42.13) 174.16,42 174.05,41.9 CN6601.13
USB_OC0#: length 101.8
  TOP w0.089: v2(160.82,33.98) v1(160.06,33.98) 159.75,33.98 159.34,34.39 159.34,43.73 158.82,44.25 158.82,47.87 158.82,51.09 158.59,51.33 158.59,55.73 158.71,55.86 158.71,66.49 159.25,67.02 159.25,67.16 159.7,67.62 159.7,68.18 159.7,71.43 160.38,72.11 160.38,74.77 161.02,75.4 161.02,76.43 160.23,77.22 160.23,80.78 158.71,82.31 158.71,83.68 158.17,84.22 155.11,84.22 154.41,84.92 154.4,84.92 154.29,85.03 152.16,85.03 152.12,84.99 142.8,84.99 141.29,86.51 140.09,86.51 139.87,86.28 139.87,85.72 140.2,85.39 140.2,85.15 RN1601.5 139.31,84.73 138.9,85.13 136.56,85.13 v2(136.54,85.16)
  L4SGND w0.089: v2(160.82,33.98) 160.82,34.56 163.51,37.25 170.3,37.25 172.27,39.23 172.27,41.95 173.81,43.49 174.24,43.49 174.41,43.33 174.41,43.31 v2(174.44,43.31)
  BOTTOM w0.089: CN6601.12 174.55,41.53 174.64,41.62 174.64,43.1 v2(174.44,43.31) ; v2(136.54,85.16) 136.21,84.83 CPU1.CK6
USB_OC1#: length 5.8
  TOP w0.089: RN1601.6 139.25,84.14 138.9,84.49 138.9,84.72 138.74,84.87 136.82,84.87 136.7,84.76 v1(136.16,84.76) 136.14,84.78 136.14,85.22 v2(135.66,85.7)
  BOTTOM w0.089: v2(135.66,85.7) 135.88,85.48 CPU1.CK5
USB_OC2#: length 5.1
  TOP w0.102: v2(135.66,83.74) 135.65,83.74 135.65,83.74 135.78,83.74 136.09,83.42 136.28,83.42 136.28,83.42 137.57,83.42 137.85,83.14 v1(138.29,83.14) 138.81,83.14 139.31,83.64 RN1601.7
  BOTTOM w0.102: CPU1.CK8 135.91,83.74 v2(135.66,83.74)
USB_OC3#: length 238.4
  TOP w0.102: v2(135.66,83.12) 135.77,83.23 137.22,83.23 137.64,82.81 139.22,82.81 139.46,83.05 RN1601.8 139.8,83.05 140.17,82.68 141.03,82.68 143.14,84.8 154.25,84.8 154.32,84.73 154.33,84.73 155.03,84.02 156.55,84.02 v1(156.88,83.68) 156.88,83.46 159.75,80.59 159.75,77.02 160.39,76.39 160.39,75.51 159.91,75.02 159.91,72.31 159.23,71.63 159.23,67.81 158.78,67.36 158.78,67.22 158.24,66.68 158.24,56.06 158.11,55.93 158.11,50.9 158.2,50.8 158.2,49.93 158.21,47.65 158.21,47.53 158.36,47.39 158.36,44.04 158.81,43.59 158.81,31.97 v2(157.32,30.47) ; v2(18.71,30.22) 18.4,30.52 16.87,30.52 16.57,30.82 16.57,30.97 15.34,32.2 15.34,32.35 14.52,33.17 14.08,33.17 U7201.B2
  L4SGND w0.102: v2(157.32,30.47) 156.99,30.14 156.99,29.01 155.76,27.78 153.36,27.78 153.16,27.78 152.56,27.78 151.89,27.78 151.66,27.55 142.99,27.55 142.67,27.23 141.61,27.23 137.25,22.88 136.77,22.88 136.39,22.5 133.96,22.5 133.16,23.29 v2(133.16,23.49)
  L6 w0.102: v2(133.16,23.49) 132.73,23.06 132.73,22.81 132.49,22.57 131.23,22.57 130.92,22.26 130.62,22.26 130.01,21.66 128.36,21.66 128.36,21.66 127.83,21.66 127.53,21.35 126.53,21.35 126.12,20.95 124.48,20.95 124.31,20.77 117.72,20.77 117.21,20.26 115.74,20.26 115.08,19.6 103.82,19.6 102.42,21 102.42,21.07 101.77,21.73 101.77,21.9 101.77,23.43 100.16,25.04 96.26,25.04 95.38,25.93 92.96,25.93 90.44,25.93 88.93,25.93 88.64,25.93 87.93,26.64 82.49,26.64 81.63,25.77 77.58,25.77 76.54,26.82 72.53,26.82 71.86,26.15 70.7,26.15 70.54,26.15 70.53,26.15 66.89,26.15 66.08,26.16 56.71,26.16 56.68,26.16 56.64,26.12 56.47,26.12 46.75,26.12 45.42,27.45 41.82,27.45 41.47,27.09 38.98,27.09 37.5,28.57 35.67,28.57 34.98,29.26 32.31,29.26 32.27,29.23 24.64,29.23 23.7,30.17 18.76,30.17 v2(18.71,30.22)
  BOTTOM w0.102: v2(135.66,83.12) 135.88,83.12 CPU1.CK9
USBCOMP: length 2
  TOP w0.254: v2(131.97,85.72) v1(131.41,86.17)
  TOP w0.508: v2(131.97,85.72) 131.97,85.7 131.71,85.45 R1603.1
  BOTTOM w0.254: v2(131.97,85.72) 132.21,85.48 CPU1.CC5
V_SM_VREF_CNTA: length 40.1
  TOP w0.508: v2(94.12,48.71) 94.12,53.02 v1(94.93,53.82) 96.32,55.22 96.32,55.26 96.89,55.83 96.89,56.46 96.96,56.53 96.96,65.16 v2(96.95,65.17) ; R1202.2 98.26,32.63 C1202.1 97.78,32.02 98.29,31.51 v2(98.34,31.51)
  BOTTOM w0.203: v2(96.95,65.17) 96.95,65.66 97.26,65.97 CPU1.F36
  BOTTOM w0.508: v2(94.12,48.71) 98.85,43.99 98.85,32.79 98.46,32.41 98.46,31.74 98.34,31.62 v2(98.34,31.51)
V_SM_VREF_CNTB: length 44.4
  TOP w0.508: v2(101.89,31.77) 103.24,31.77 C1302.1 104.53,31.21 R1302.2 ; v2(96,64.89) 96.36,64.53 96.36,60.87 95.3,59.81 95.3,55.64 92.95,53.28 v1(92.95,50.69) v2(92.95,48.91)
  BOTTOM w0.203: v2(96,64.89) 96.43,65.32 96.43,65.33 96.53,65.42 96.53,65.74 CPU1.E36
  BOTTOM w0.508: v2(92.95,48.91) 93.4,49.36 94.91,49.36 99.96,44.3 99.96,33.7 v2(101.89,31.77)
VCI_IN1#: length 4.6
  TOP w0.254: v2(24.9,28.59) v1(24.9,29.15) 24.4,29.15 24.12,28.87 R2497.1
  BOTTOM w0.203: U2401.126 24.73,27.19 24.93,27.39 24.93,28.59 v2(24.9,28.59)
VCREF0: length 5.5
  BOTTOM w0.102: U2401.25 34.93,31.69 C2409.1 35.42,32.23 R2448.1 R2424.1 v1(33.03,32.66)
VD_IN1_C: length 212.7
  TOP w0.089: C2613.2 29.45,26.56 31.25,26.56 31.28,26.53 v1(31.28,26.53) 31.34,26.59 31.99,26.59 R2611.1 32.94,27.53 33.03,27.53 33.14,27.65 34.92,27.65 35.13,27.44 35.37,27.44 36.49,26.32 v2(36.49,25.8)
  L4SGND w0.089: v2(115.99,18.18) 118.92,18.18 119.06,18.32 123.75,18.32 124.64,19.21 124.78,19.56 125.08,19.85 125.69,19.85 125.94,19.6 125.94,19.58 125.96,19.56 137.49,19.56 143.72,25.79 153.22,25.79 153.45,26.02 156.78,26.02 160.19,29.43 163.69,29.43 167.04,32.78 168.04,32.78 174,38.73 174,40.13 174,40.13 174,40.8 175,41.81 182.57,41.81 182.57,41.81 182.59,41.81 183.76,42.99 183.76,44.11 180.49,47.38 180.49,55.08 173.91,61.67 165.47,61.67 164.63,62.5 v2(163.11,62.5)
  L6 w0.089: v2(115.99,18.18) 114.81,18.18 114.79,18.2 106.67,18.2 106.65,18.18 100.22,18.18 94.31,24.1 87.89,24.1 87.18,24.81 83.25,24.81 82.54,24.1 82.39,23.94 76.04,23.94 75.6,23.51 69.01,23.51 68.4,24.12 62.96,24.12 62.9,24.07 62.87,24.07 62.69,23.89 57.04,23.89 56.86,24.07 44.11,24.07 43,25.18 37.11,25.18 v2(36.49,25.8)
  BOTTOM w0.089: v2(163.11,62.5) 163.11,62.67 161.87,63.91 161.87,64.72 163.18,66.03 R2610.2 164.25,66.03 C2612.2
VR_CAP: length 2.9
  BOTTOM w0.203: 32.07,31.13 32.14,31.06 32.14,30.42 32.13,30.41 U2401.18
  BOTTOM w0.254: 32.07,31.13 32.04,31.16 v1(32.04,31.18) 31.92,31.31 C2418.1
VR_EN: length 4.2
  BOTTOM w0.102: PU4601.40 51.29,76.62 51.58,76.62 v1(52.34,77.39) 52.34,77.51 52.36,77.54 R4002.2
VR_RDY: length 4.1
  BOTTOM w0.102: PR4609.2 51.5,77.67 TP4601.1 51.07,76.78 50.15,75.86 49.7,75.86 49.57,75.74 PU4601.39
VRALERT#: length 4.5
  BOTTOM w0.076: 132.91,65.17 132.73,65.34 132.73,65.66 132.63,65.86 132.63,65.86 132.47,66.14 CPU1.CC36
  BOTTOM w0.102: 132.91,65.17 133.47,64.6 133.9,64.6 134.25,64.25 134.25,63.78 134.25,63.5 134.25,63.5 134.25,62.76 TP1708.1
VRAM_ID1: length 16.5
  TOP w0.102: v2(144.23,75.96) v1(142.79,75.99)
  L6 w0.102: v2(133.54,71.47) 134.75,72.67 137.05,72.67 138.12,73.74 138.92,73.74 139.11,73.55 139.77,73.55 141.1,74.88 141.98,74.88 142.8,75.71 143.98,75.71 v2(144.23,75.96)
  BOTTOM w0.102: v2(133.54,71.47) 133.22,71.79 CPU1.CE27 ; R2035.2 145.07,76.22 R2034.1 144.82,75.96 v2(144.23,75.96)
VRAM_ID2: length 6.6
  BOTTOM w0.076: CPU1.CN23 138.29,74.34 138.49,74.54 arc(138.55,74.58) 138.62,74.59 139.04,74.59 139.32,74.87
  BOTTOM w0.102: R2037.1 R2038.2 143.37,75.38 v1(142.51,75.38) 140.67,75.38 140.16,74.87 139.32,74.87
VTT_CNTL: length 29.6
  L4SGND w0.127: v2(62.57,53.84) 62.57,54.35 61.3,55.62 60.34,55.62 58.71,53.99 53.73,53.99 49.57,58.16 v2(49.57,58.49)
  BOTTOM w0.127: v2(62.57,53.84) 64.4,53.84 64.94,54.37 69.18,54.37 v1(70.3,55.5) 71.29,56.48 R507.2 Q502.D ; v2(49.57,58.49) 49.62,58.54 PR5113.1
WHITE_LED_BAT: length 93.3
  TOP w0.254: v2(20.94,99.38) 20.89,99.33 R6402.2
  L4SGND w0.254: v2(14.29,82.44) 14.29,82.47 15.2,83.38 15.2,92.11 15.56,92.46 15.56,95.42 20.1,99.97 20.84,99.97 20.94,99.87 v2(20.94,99.38)
  L6 w0.254: v2(14.29,82.44) 14.29,80.26 16.7,77.84 16.7,75.55 16.6,75.45 16.6,74.76 15.03,73.2 14.34,73.2 13.91,73.2 11.44,70.73 11.44,64.76 9.72,63.04 7.28,63.04 4.87,60.62 4.87,24.15 v2(7.02,21.99)
  BOTTOM w0.254: Q6401.C v2(7.02,21.99) v1(7.04,23.1)
WIFI_RF_EN: length 64.6
  TOP w0.102: R2107.2 140.58,74.47 140.25,74.8 139.81,74.8 139.73,74.87 139.39,74.87 139.32,74.8 137.12,74.8 136.84,74.52 136.77,74.52 v2(136.77,74.51) ; AFTP6110.1 169.08,49.22 v2(168.77,48.91) 167.88,48.02 R6108.2 167.73,47.24 D6102.K
  L4SGND w0.102: v2(168.77,48.91) 168.36,48.91 168.19,49.09 162.9,49.09 v2(162.47,48.66)
  L6 w0.102: v2(136.77,74.51) 136.77,74.52 136.89,74.52 137.2,74.82 139.34,74.82 139.39,74.87 139.73,74.87 139.78,74.82 140.23,74.82 140.99,75.58 141.83,75.58 143.2,76.95 147.25,76.95 147.84,76.95 149.9,74.89 149.9,74.77 151.96,72.71 151.96,70.58 152.47,70.06 152.47,68.63 155.99,65.12 156.28,65.12 157.58,63.81 157.58,57.83 158.14,57.27 158.14,54.51 159.42,53.23 159.42,52.51 161.96,49.97 161.96,49.17 v2(162.47,48.66)
  BOTTOM w0.102: CPU1.CG25 134.86,73.3 135.51,73.3 135.89,73.67 135.91,73.67 136.08,73.84 136.08,74.02 136.57,74.51 v2(136.77,74.51)
WIFI_RF_EN_R: length 5.9
  TOP w0.102: v1(167.81,45.87) 166.79,46.88 D6102.A 166.87,46.98 R6108.1 R6109.2 166.87,49.14 v2(166.46,49.55)
  BOTTOM w0.102: v2(166.46,49.55) 166.46,49.7 166.36,49.8 WLAN1.56
WLAN_CLK_CPU_N: length 103.2
  TOP w0.102: v2(162.93,54.8) 162.6,55.14 v1(162.47,55.14)
  L6 w0.089: v2(119.65,89.74) 119.24,89.62 118.58,89.62 118.3,89.34 118.3,88.32 118.17,88.19 115.43,88.19 115.22,87.98 115.22,87.34 115.42,87.14 119.57,87.14 119.79,86.92 119.79,84.78 120.32,84.24 120.32,83.53 120.66,83.19 124.42,83.19 125.44,82.17 127.22,82.17 128.02,82.97 129.25,82.97 129.36,82.86 129.36,82.04 129.27,81.95 128.86,81.95 128.65,81.75 128.65,81.31 128.86,81.11 130.35,81.11 131.05,80.41 133.25,80.41 133.53,80.12 137.43,80.12 137.66,79.9 137.66,79.09 137.91,78.84 139.46,78.84 139.69,79.06 139.69,79.47 139.49,79.67 138.72,79.67 138.63,79.76 138.63,80.09 138.72,80.18 140.05,80.18 140.25,80.38 140.25,80.87 140.05,81.07 138.27,81.07 138.18,81.16 138.18,81.48 138.81,82.11 141.12,82.11 142.84,80.4 144.57,80.4 144.75,80.57 150.78,80.57 153.11,78.24 157.1,78.24 158.08,77.26 158.08,74.93 159.23,73.78 159.23,70.55 161.04,68.75 161.04,67.92 160.68,67.57 160.68,62.17 161.71,61.14 161.71,55.6 162.21,55.09 162.64,55.09 v2(162.93,54.8)
  BOTTOM w0.102: WLAN1.49 158.45,51.55 158.58,51.69 158.95,51.69 160.06,52.8 160.06,54.2 160.67,54.8 v2(162.93,54.8) ; CPU1.BC1 119.75,88.24 119.75,89.15 v2(119.65,89.74)
WLAN_CLK_CPU_P: length 103.2
  TOP w0.102: v2(162.93,55.59) 162.98,55.59 v1(163.41,56.03)
  L6 w0.089: v2(119.32,89.14) 119.26,89.35 119.16,89.43 118.66,89.43 118.49,89.26 118.49,88.24 118.25,88 115.51,88 115.41,87.9 115.41,87.42 115.5,87.33 119.65,87.33 119.98,87 119.98,84.85 120.51,84.32 120.51,83.61 120.74,83.38 124.5,83.38 125.52,82.36 127.14,82.36 127.94,83.16 129.33,83.16 129.55,82.94 129.55,81.96 129.35,81.76 128.93,81.76 128.85,81.67 128.85,81.39 128.93,81.3 130.43,81.3 131.13,80.6 133.33,80.6 133.61,80.31 137.51,80.31 137.85,79.98 137.85,79.17 137.99,79.03 139.38,79.03 139.5,79.14 139.5,79.39 139.41,79.48 138.64,79.48 138.44,79.68 138.44,80.17 138.64,80.37 139.97,80.37 140.06,80.46 140.06,80.79 139.97,80.88 138.19,80.88 137.99,81.08 137.99,81.56 138.73,82.3 141.2,82.3 142.91,80.59 144.49,80.59 144.67,80.76 150.85,80.76 153.19,78.43 157.18,78.43 158.27,77.34 158.27,75.01 159.42,73.86 159.42,70.63 161.23,68.83 161.23,67.85 160.87,67.49 160.87,62.25 161.9,61.22 161.9,55.68 162.29,55.28 162.62,55.28 v2(162.93,55.59)
  BOTTOM w0.102: v2(162.93,55.59) 162.65,55.59 162.55,55.49 162.55,55.13 162.45,55.03 160.57,55.03 159.83,54.29 159.83,54.1 159.83,52.89 158.85,51.91 158.58,51.91 158.45,52.05 WLAN1.47 ; CPU1.BC2 119.61,87.58 119.53,87.7 119.53,88.93 v2(119.32,89.14)
WLAN_CLKREQ_CPU_N: length 36.7
  TOP w0.102: v2(133.57,68.88) 133.34,68.65 133.34,67.71 133.96,67.09 133.96,66.55 135.87,64.64 136.53,64.64 137.27,63.9 137.27,63.83 140.76,60.34 140.76,58.56 141.56,57.76 141.56,56.32 142.82,55.05 142.82,55.04 143.26,54.6 143.27,54.6 143.6,54.27 RN1813.8 143.9,54.26 143.9,53.73 144.18,53.46 151.09,53.46 151.5,53.87 AFTP6109.1 153.68,53.66 v2(154.24,53.66)
  BOTTOM w0.102: CPU1.CE32 133.23,68.54 v2(133.57,68.88) ; v2(154.24,53.66) 154.74,53.17 154.74,53.14 155.08,52.8 155.08,51.63 156.16,50.55 WLAN1.53
WLAN_EN#: length 10.8
  TOP w0.102: R6111.2 R6112.1 171.92,68.81 171.42,69.31 170.68,69.31 170.22,68.85 ; 170.22,68.85 v2(170.19,68.83) ; 170.22,68.85 v1(170.22,69.64)
  BOTTOM w0.102: v2(170.19,68.83) 170.19,68.6 169.76,68.17 169.76,66.9 170.78,65.88 173.02,65.88 Q6102.D
WLAN_EN_R#: length 3.7
  TOP w0.102: v1(171.29,68.98) R6112.2 170.63,67.66 C6102.2 170.09,67.91 v2(170.37,68.19)
  BOTTOM w0.102: v2(170.37,68.19) 170.66,68.48 Q6101.G
WLAN_PCIE_RX_N: length 70.3
  TOP w0.102: v1(162.45,56.84) 162.85,56.43 v2(162.95,56.43)
  L6 w0.089: v2(162.95,56.43) 162.38,57.14 162.38,57.91 163.7,59.23 163.7,60.1 161.34,62.46 161.34,67.16 161.7,67.52 161.7,69.09 159.98,70.81 159.98,76.3 157.38,78.91 153.39,78.91 151.07,81.23 144.87,81.23 144.87,81.23 144.48,81.23 144.33,81.09 143.05,81.09 142.69,81.45 142.69,81.48 141.5,82.67 138.66,82.67 137.13,81.14 133.83,81.14 133.62,80.93 131.61,80.93 130.67,81.87 130.67,82.42 129.34,83.75 128.27,83.75 127.29,84.73 126.7,84.73 v2(126.48,84.51)
  BOTTOM w0.102: WLAN1.43 158.45,53.05 158.58,53.19 158.97,53.19 159.37,53.59 159.37,54.63 161.28,56.53 162.85,56.53 v2(162.95,56.43) ; v2(126.48,84.51) CPU1.BN6
WLAN_PCIE_RX_P: length 70.2
  TOP w0.102: v1(163.23,57.77) 163.23,57.49 v2(162.95,57.22)
  L6 w0.089: v2(162.95,57.22) 162.88,57.14 162.66,57.14 162.57,57.23 162.57,57.83 163.89,59.15 163.89,60.18 161.53,62.54 161.53,67.08 161.89,67.44 161.89,69.17 160.17,70.89 160.17,76.38 157.46,79.1 153.47,79.1 151.15,81.43 144.95,81.43 144.95,81.43 144.4,81.43 144.25,81.28 143.13,81.28 142.88,81.53 142.88,81.56 141.58,82.86 138.58,82.86 137.05,81.33 133.75,81.33 133.54,81.12 131.69,81.12 130.86,81.95 130.86,82.49 129.42,83.94 128.35,83.94 127.37,84.92 126.73,84.92 126.5,85.15 v2(126.49,85.15)
  BOTTOM w0.102: v2(126.49,85.16) CPU1.BN5 ; WLAN1.41 158.45,53.55 158.58,53.41 158.88,53.41 159.14,53.68 159.14,54.72 161.18,56.76 162.5,56.76 v2(162.95,57.22)
WLAN_PCIE_TX_CON_N: length 4.6
  BOTTOM w0.102: C6107.1 154.6,54.56 154.83,54.32 155.59,54.32 155.92,54.65 156.08,54.65 ; v1(156.08,54.51) 156.08,54.65 ; 156.08,54.65 156.6,54.65 156.71,54.55 WLAN1.37
WLAN_PCIE_TX_CON_P: length 5.5
  BOTTOM w0.102: v1(156.25,56.15) 156.2,56.1 156.2,56.1 156.11,55.98 C6108.1 155.36,55.52 155.28,55.44 154.95,55.44 154.83,55.31 154.83,54.65 154.93,54.55 155.49,54.55 155.82,54.88 156.57,54.88 156.74,55.05 WLAN1.35
WLAN_PCIE_TX_N: length 86.7
  L6 w0.089: v2(169.71,60.21) 169.41,59.91 169.29,59.91 169.17,60.03 169.17,61.09 170.88,62.81 170.88,64.93 168.26,67.55 168.26,70.33 164.77,73.82 164.77,78.83 159.42,84.18 154.89,84.18 154.32,84.75 153.81,84.75 152.24,86.31 143.81,86.31 139.94,90.19 134.34,90.19 133.76,90.76 131.9,90.76 129.93,88.79 127.98,88.79 v2(127.76,89.01)
  BOTTOM w0.076: CPU1.BR4 126.86,86.78 126.86,87.05 126.79,87.21 126.79,87.22 126.71,87.39 126.71,87.65 126.72,87.67 126.75,87.74 126.75,87.96 126.73,88 126.72,88.03 126.72,88.45 127.08,88.82
  BOTTOM w0.102: v2(169.71,60.21) 169.49,59.99 168.01,59.99 165.85,57.82 164.19,57.82 164.05,57.96 163.99,57.96 163.99,57.97 163.92,58.03 163.48,58.48 160.75,58.48 160.27,57.99 159.84,57.57 156.06,57.57 ; v1(156.06,57.72) 156.06,57.57 ; 156.06,57.57 155.11,57.57 154.85,57.31 154.85,56.96 C6107.2 ; v2(127.76,89.01) 127.56,88.82 127.08,88.82
WLAN_PCIE_TX_P: length 87
  TOP w0.102: v1(169.15,59.4) v2(169.71,59.42)
  L6 w0.089: v2(127.76,88.38) 127.98,88.6 130.01,88.6 131.98,90.57 133.69,90.57 134.26,90 139.86,90 143.73,86.12 152.17,86.12 153.73,84.56 154.24,84.56 154.81,83.99 159.34,83.99 164.58,78.75 164.58,73.74 168.07,70.25 168.07,67.47 170.69,64.85 170.69,62.89 168.97,61.17 168.97,59.95 169.21,59.72 169.41,59.72 v2(169.71,59.42)
  BOTTOM w0.076: CPU1.BR3 127.14,86.6 127.23,86.52 127.33,86.52 127.42,86.61 127.42,87.02 127.25,87.19 127.04,87.19 126.93,87.31 126.88,87.43 126.88,87.62 126.91,87.71 126.91,87.99 126.89,88.05 126.89,88.06 126.89,88.38 127.09,88.59 127.11,88.59
  BOTTOM w0.102: 127.11,88.59 127.55,88.59 v2(127.76,88.38) ; C6108.2 155.08,56.99 155.08,57.21 155.21,57.34 159.94,57.34 160.49,57.9 160.85,58.25 163.38,58.25 163.82,57.81 163.9,57.73 163.95,57.73 164.09,57.6 165.94,57.6 168.1,59.76 169.37,59.76 v2(169.71,59.42)
XCLK_BIASREF: length 3.5
  BOTTOM w0.254: CPU1.CJ1 v1(135.59,90.54) 135.59,91.19 135.5,91.28 R1803.1
XDP_CLK_CPU_N: length 4.7
  BOTTOM w0.102: CPU1.AU1 116.06,88.17 115.92,88.17 115.71,88.38 115.71,90.79 116.52,91.6 116.66,91.6 TP1808.1
XDP_CLK_CPU_P: length 6
  BOTTOM w0.102: TP1807.1 117.03,92.17 116.69,91.83 116.42,91.83 115.48,90.89 115.48,90.7 115.48,88.28 116.06,87.7 CPU1.AU2
XDP_DBRESET#: length 12.1
  BOTTOM w0.076: 140.98,82.39 139.3,82.39 arc(139.28,82.38) 139.25,82.37 arc(139.2,82.32) 139.12,82.3 138.96,82.3 arc(138.92,82.31) 138.88,82.32 arc(138.81,82.35) 138.74,82.36 138.67,82.36 arc(138.61,82.35) 138.55,82.32 arc(138.51,82.31) 138.47,82.3 138.31,82.3 arc(138.23,82.32) 138.17,82.37 arc(137.96,82.44) CPU1.CN10
  BOTTOM w0.089: R1701.2 148.3,84.02 TP1712.1 146.98,83.58 EC1706.1 145.78,84.23 143.61,84.23 143.3,83.91 143.3,83.91 142.94,83.56 142.94,83.3 v1(142.15,82.52) 142.02,82.39 140.98,82.39
XDP_PRDY#: length 3.6
  BOTTOM w0.102: TP306.1 103.38,90.98 105.17,89.18 105.17,89.01 105.18,89 105.18,88.51 105.17,88.5 CPU1.W1
XDP_PREQ#: length 6.2
  BOTTOM w0.102: TP305.1 102.7,92.22 103.69,91.23 103.69,90.94 105.44,89.19 105.44,87.92 105.17,87.65 CPU1.W2
XDP_TCLK: length 3.4
  TOP w0.102: TP309.1 102.83,85.24 R317.1 102.86,85.01 v2(103.34,84.53)
  BOTTOM w0.102: v2(103.34,84.53) 103.04,84.83 CPU1.T6 CPU1.P6
XDP_TDI: length 15.1
  BOTTOM w0.102: TP315.1 95.04,91.74 TP310.1 95.04,90.47 95.14,90.37 96.66,90.37 97.24,89.78 100.26,89.78 101.71,88.33 101.71,86.14 102.08,85.77 103.49,85.77 CPU1.U5 CPU1.U6
XDP_TDO_CPU: length 14.4
  BOTTOM w0.102: CPU1.Y5 CPU1.W5 104.71,85.64 104.48,85.87 103.8,85.87 103.67,86 103.44,86 103,86.43 103,89.21 101.74,90.47 98.64,90.47 TP311.1 97.35,91.76 TP316.1 97.09,92.75 R310.1
XDP_TMS: length 15
  BOTTOM w0.102: CPU1.T5 CPU1.P5 101.75,85.48 101.13,86.1 101.13,86.41 101.15,86.43 101.15,88.07 99.64,89.58 97.12,89.58 96.64,90.06 93.99,90.06 93.38,90.67 TP317.1 92.19,91.59 TP312.1
XDP_TRST#: length 1.9
  TOP w0.102: v2(106.09,84.6) 106.16,84.67 TP313.1
  BOTTOM w0.102: CPU1.Y6 105.86,84.6 106.08,84.6 v2(106.09,84.6) 106.09,84.6 106.33,84.6 CPU1.AB6
XTL_24M_X1_CPU: length 5.4
  BOTTOM w0.089: R1839.1 137.58,90.8 137.58,90.21 136.92,89.55 136.92,88.13 136.99,88.06 136.99,88.06 137.07,87.97 137.07,87.6 136.82,87.34 136.82,87.02 CPU1.CK3
XTL_24M_X1_R: length 3.3
  BOTTOM w0.089: X1801.1 139.38,94.85 138.33,93.79 C1807.2 138.24,93.77 R1841.1 138.11,92.88 R1839.2
XTL_24M_X2_CPU: length 4.4
  BOTTOM w0.089: R1840.1 137.35,90.34 136.68,89.67 136.68,88.1 136.28,87.69 CPU1.CK2
XTL_24M_X2_R: length 4.9
  BOTTOM w0.089: R1840.2 137.35,92.98 R1841.2 137.38,93.49 C1808.2 137.68,93.96 138.04,94.32 138.04,95.69 X1801.3
XTL_27M_X1_HDMI: length 5.4
  TOP w0.089: U5701.E8 22.34,82.66 R5750.1 22.34,81.78 21.93,81.37 v1(21.91,81.37) 21.98,81.3 C5729.1 21.34,79.94 X5701.1
XTL_27M_X2_HDMI: length 4
  TOP w0.089: R5748.1 20.57,81.21 v1(20.57,81.83) 20.57,81.93 20.93,82.29 R5750.2 21.48,82.59 U5701.F8
XTL_27M_X2_R: length 4.9
  TOP w0.089: X5701.3 18.32,78.95 v1(18.05,79.21) 17.79,79.47 17.79,80.18 18.1,80.49 18.64,80.49 C5730.1 19.83,81.09 R5748.2
XTL_32K_X1_CPU: length 17.3
  TOP w0.089: v2(126.28,68.93) 125.7,68.35 125.7,68.2 124.85,67.36 124.85,58.46 v1(125.31,58.01) 126.18,57.14 R1815.1 126.56,55.9 C1804.2 126.56,55.24 125.39,54.07 X1802.1
  BOTTOM w0.089: CPU1.BN31 126.01,69.19 v2(126.28,68.93)
XTL_32K_X2_CPU: length 16.6
  TOP w0.089: v2(126.29,68.31) 126.06,68.31 125.06,67.31 125.06,58.82 v1(126.64,57.23) 127.04,56.84 R1815.2 127.17,56.15 C1803.1 127.17,54.64 X1802.2
  BOTTOM w0.089: v2(126.29,68.31) 126.06,68.54 CPU1.BN32

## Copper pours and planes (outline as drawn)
1V_CPU_CORE on TOP: outline of 83 points within 73.32,72.28 121.71,97.68 ; 70 cut-outs
1V_CPU_CORE on BOTTOM: 72.81,76.09 72.68,76.22 72.68,80.41 72.81,80.54 72.81,90.19 73.19,90.57 78.65,90.57 79.54,89.68 79.54,81.81 79.82,81.53 80.68,81.53 81.22,82.06 81.95,82.06 82.84,81.17 82.84,80.28 78.65,76.09 ; 8 cut-outs
1V_CPU_CORE on BOTTOM: 113.45,81.81 113.32,81.93 113.32,83.08 113.45,83.2 114.34,83.2 114.72,83.58 114.72,84.22 114.59,84.35 114.59,85.49 114.72,85.62 115.86,85.62 116.12,85.36 116.37,85.36 116.63,85.62 116.75,85.62 117.01,85.36 117.26,85.36 117.51,85.62 118.66,85.62 118.91,85.36 119.17,85.36 119.42,85.62 120.44,85.62 120.56,85.49 120.56,85.24 120.18,84.85 120.18,84.47 119.29,83.58 119.29,83.46 119.42,83.33 119.8,83.33 120.18,83.71 120.56,83.71 120.94,83.33 121.83,83.33 121.96,83.2 121.96,82.82 121.2,82.82 120.18,81.81
1V_CPU_CORE on BOTTOM: 113.65,71.44 113.37,71.72 113.37,73.25 114.31,74.19 121.71,74.19 121.96,73.93 121.96,72.59 122.37,72.18 122.37,71.54 122.26,71.44
1V_CPU_CORE on L3SGND: 92.75,74.57 77.26,74.57 72.84,78.99 72.84,87.27 79.19,93.62 114.47,93.62 119.55,88.54 119.55,83.46 120.44,82.57 120.44,75.46 121.71,74.19 121.71,73.55 121.45,73.3 114.59,73.3 113.83,74.06 108.5,74.06 107.1,72.66 94.65,72.66
1V_CPU_CORE on L4SGND: 92.88,74.57 77.26,74.57 72.81,79.01 72.81,87.27 79.16,93.62 93.77,93.62 94.53,94.38 106.85,94.38 107.61,93.62 113.83,93.62 115.86,91.59 117.26,91.59 117.77,91.08 117.77,90.19 119.42,88.54 119.42,83.84 120.31,82.95 120.31,80.92 121.45,79.77 121.45,74.31 121.71,74.06 121.71,73.42 120.94,72.66 94.65,72.66 93,74.31 93,74.44
1V_GT_CORE on TOP: 106.21,78.12 105.96,78.38 105.96,80.16 105.83,80.28 105.83,82.7 106.59,83.46 107.1,83.46 108.12,84.47 108.12,85.49 108.88,86.25 108.88,88.79 109.13,89.05 111.93,89.05 112.31,88.66 112.31,87.78 111.42,86.89 111.42,84.22 111.8,83.84 111.8,82.7 111.93,82.57 111.93,81.93 111.8,81.81 109.01,81.81 108.88,81.68 108.88,78.63 108.37,78.12
1V_GT_CORE on BOTTOM: 105.96,81.81 105.83,81.93 105.83,82.19 105.45,82.57 105.45,83.58 105.58,83.71 105.7,83.71 105.83,83.58 106.34,83.58 106.47,83.71 106.59,83.71 106.72,83.58 107.23,83.58 107.74,84.09 108.12,84.09 108.24,83.97 108.62,83.97 108.75,84.09 109.01,84.09 109.13,83.97 109.51,83.97 109.64,84.09 110.4,84.09 110.78,83.71 111.29,83.71 111.42,83.58 111.93,83.58 112.05,83.71 113.07,83.71 113.2,83.58 113.2,83.33 112.69,82.82 112.69,82.7 111.8,81.81
1V_VCCGT on TOP: outline of 87 points within 72.3,57.3 106.21,88.79 ; 73 cut-outs
1V_VCCGT on BOTTOM: 73.06,65.04 72.68,65.42 72.68,68.47 72.43,68.73 72.43,72.15 73.06,72.79 79.03,72.79 79.67,73.42 79.67,76.85 82.97,80.16 82.97,81.3 86.02,84.35 86.53,84.35 88.81,86.63 92.88,86.63 93.38,86.12 94.53,86.12 94.78,86.38 94.78,87.14 95.42,87.78 95.54,87.78 95.67,87.65 95.67,87.14 96.43,86.38 96.81,86.38 97.45,85.74 98.34,85.74 98.46,85.62 98.46,84.6 98.59,84.47 101,84.47 101.77,83.71 102.02,83.71 102.15,83.58 102.66,83.58 102.78,83.71 102.91,83.71 103.04,83.58 103.54,83.58 103.67,83.71 103.93,83.71 104.05,83.58 104.43,83.58 104.56,83.71 104.81,83.71 105.32,83.2 105.32,82.44 105.58,82.19 105.58,81.93 105.45,81.81 101.26,81.81 100.62,81.17 100.62,76.22 100.37,75.96 94.27,75.96 93.51,76.73 90.21,76.73 89.45,75.96 87.03,75.96 85.51,74.44 85.51,71.27 83.56,69.32 81.82,68.33 80.83,66.59 79.29,65.04
1V_VCCGT on L6: 105.45,82.44 106.21,81.68 106.21,74.31 104.05,72.15 101,72.15 100.24,72.92 100.24,75.08 99.23,76.09 95.8,76.09 95.29,76.6 93.64,76.6 92.24,78 87.8,78 87.67,78.12 87.67,80.79 89.32,82.44
1V_VCCIO on TOP: 150.03,60.85 148.38,62.5 148.38,63.52 149.14,64.28 150.92,64.28 151.93,63.26 151.93,61.74 151.68,61.49 151.68,61.18 151.35,60.85 ; 2 cut-outs
1V_VCCIO on TOP: 122.85,71.39 122.72,71.52 122.72,71.9 122.47,72.15 121.96,72.15 121.83,72.28 121.83,72.79 122.09,73.04 122.47,73.04 122.59,73.17 122.59,73.81 122.85,74.06 123.23,74.06 123.61,73.68 123.61,72.28 123.36,72.03 123.36,71.52 123.23,71.39 ; 1 cut-out
1V_VCCIO on TOP: 112.69,72.54 112.56,72.66 111.29,72.66 111.29,73.42 111.8,73.93 113.2,73.93 113.83,73.3 113.83,72.54 ; 2 cut-outs
1V_VCCIO on BOTTOM: 122.98,71.65 122.47,72.15 122.47,73.93 122.59,74.06 123.61,74.06 123.74,73.93 123.74,72.15 123.23,71.65
1V_VCCIO on BOTTOM: 150.51,61.26 150.5,61.27 148.64,61.27 148.25,61.66 148.25,63.65 148.88,64.28 150,64.28 150.38,63.9 151.85,63.9 151.88,63.87 151.88,61.69 151.45,61.26
1V_VCCIO on BOTTOM: 112.13,71.57 111.55,72.15 111.55,73.88 111.85,74.19 113.2,74.19 113.48,73.91 113.48,73.55 113.29,73.36 113.29,71.71 113.15,71.57
1V_VCCIO on L3SGND: 151.17,62.25 150.03,61.11 136.18,61.11 135.29,61.99 135.29,63.9 134.66,64.53 131.61,64.53 124.63,71.52 111.55,71.52 111.04,72.03 111.04,73.3 111.67,73.93 113.45,73.93 114.21,73.17 121.58,73.17 122.34,73.93 122.34,75.2 125.77,78.63 126.28,78.63 126.91,78 131.36,78 131.74,77.62 131.74,76.6 132.12,76.22 132.5,76.22 133.52,75.2 137.2,75.2 140.25,72.15 148.38,72.15 151.17,69.36
1V_VCCIO on L6: 111.55,73.68 111.55,72.15 111.93,71.77 125.26,71.77 125.9,71.14 128.44,71.14 129.2,71.9 131.61,71.9 132.37,71.14 132.37,70.76 132.63,70.5 133.14,70.5 133.26,70.63 133.26,72.28 133.52,72.54 134.02,72.54 134.41,72.92 136.31,72.92 136.44,73.04 136.44,73.68 136.18,73.93 135.8,73.93 135.55,74.19 134.41,74.19 134.28,74.31 132.88,74.31 132.63,74.57 132.12,74.57 131.48,75.2 131.1,75.2 130.72,75.58 124.37,75.58 122.21,73.42 113.83,73.42 113.2,74.06 111.93,74.06
1V_VCCIO_R on BOTTOM: 152.99,61.32 152.57,61.74 152.57,63.9 152.44,64.03 151.68,64.03 151.3,64.41 151.3,65.3 151.42,65.42 152.44,65.42 152.87,64.99 154.65,64.99 154.65,64.23 154.75,64.13 155.23,64.13 155.33,64.03 155.33,62.74 155.28,62.69 154.71,62.69 154.55,62.53 154.55,61.84 154.03,61.32 ; 1 cut-out
1V_VCCSA on TOP: 123.95,73.46 123.23,74.19 123.1,74.19 123.1,74.82 123.23,74.95 123.23,77.49 122.98,77.74 122.98,78.38 122.21,79.14 122.21,83.33 121.96,83.58 121.96,84.6 121.71,84.85 121.71,93.49 122.47,94.25 122.47,94.76 125.01,97.3 136.18,97.3 136.31,97.43 140.76,97.43 141.52,98.19 152.95,98.19 154.47,99.71 154.47,104.29 154.98,104.79 158.79,104.79 159.3,104.29 159.3,96.92 155.74,93.36 139.1,93.36 136.88,91.14 132.25,91.14 131.61,90.51 131.61,90.44 131.36,90.19 130.34,90.19 128.82,88.66 128.82,84.09 126.15,81.43 124.5,81.43 124.37,81.3 124.37,78.76 124.63,78.5 124.63,75.84 125.82,74.64 125.82,73.6 125.68,73.46 ; 27 cut-outs
1V_VCCSA on BOTTOM: 154.73,97.94 154.34,98.32 154.34,104.54 154.6,104.79 157.01,104.79 157.52,104.29 157.52,98.32 157.14,97.94
1V_VCCSA on BOTTOM: 123.99,71.65 123.86,71.77 123.86,74.06 123.99,74.19 125.77,74.19 126.02,73.93 126.02,72.66 125.9,72.54 125.52,72.54 124.63,71.65
1V_VCCSA on BOTTOM: 122.85,81.43 122.09,82.19 122.09,83.71 122.47,84.09 124.75,84.09 125.26,83.58 125.26,81.81 124.88,81.43
1V_VCCST_CPU_R on BOTTOM: 149.04,93.06 148.91,93.19 148.91,95.17 149.01,95.27 152.26,95.27 152.41,95.12 152.41,93.16 152.31,93.06 ; 3 cut-outs
5V_FAN_VCC on BOTTOM: 188.18,66.87 188,67.05 188,71.14 188.38,71.52 188.38,76.6 187.36,77.62 182.26,77.62 182.26,78.43 182.33,78.5 189.02,78.5 189.52,78 189.52,67.84 189.51,67.82 189.51,67.29 189.09,66.87 ; 5 cut-outs
5V_HDMI_S0 on TOP: 13.76,92.98 13.5,93.24 13.5,94 15.66,96.16 17.31,96.16 17.44,96.03 17.44,94.38 17.31,94.25 15.91,94.25 14.64,92.98 ; 2 cut-outs
5V_HDMI_S0 on BOTTOM: 11.47,92.09 11.22,92.35 11.22,93.87 11.34,94 13.25,94 13.63,94.38 14.9,94.38 15.03,94.25 15.03,92.73 14.9,92.6 13.63,92.6 13.12,92.09
5V_KB_BL on BOTTOM: 67.68,10.58 67.58,10.69 67.58,12.72 68.03,13.18 69.05,13.18 69.23,13.35 70.91,13.35 71.03,13.48 71.03,14.75 71.16,14.88 71.16,15.89 71.29,16.02 72.81,16.02 72.94,15.89 72.94,15.13 72.81,15 72.43,15 72.18,14.75 72.18,12.87 72,12.69 69.3,12.69 69.13,12.51 68.75,12.51 68.57,12.34 68.57,10.61 68.54,10.58 ; 3 cut-outs
5V_S0 on TOP: 144.44,100.98 144.31,101.11 144.31,102.13 145.07,102.89 145.71,102.89 145.84,102.76 145.84,101.24 145.58,100.98 ; 2 cut-outs
5V_S0 on TOP: 18.33,94.25 18.2,94.38 18.2,96.28 18.33,96.41 20.11,96.41 20.49,96.79 22.14,96.79 22.52,96.41 22.52,95.52 21.88,94.89 19.98,94.89 19.34,94.25
5V_S0 on TOP: 171.24,9.16 169.2,11.19 168.82,11.19 168.06,11.96 168.06,16.91 168.31,17.16 170.09,17.16 170.35,16.91 170.35,15.39 170.6,15.13 171.36,15.13 171.74,14.75 171.74,13.35 172.12,12.97 175.05,12.97 175.68,12.34 178.47,12.34 178.73,12.08 178.73,10.43 178.6,10.31 176.44,10.31 175.3,9.16 ; 3 cut-outs
5V_S0 on BOTTOM: 144.95,101.49 144.44,102 144.44,102.51 144.06,102.89 144.06,103.78 143.8,104.03 142.91,104.03 142.79,103.9 142.79,102.89 142.03,102.89 142.03,104.16 142.53,104.67 144.69,104.67 145.96,103.4 145.96,101.62 145.84,101.49 ; 1 cut-out
5V_S0 on BOTTOM: 186.86,65.93 186.73,66.06 186.73,67.71 186.86,67.84 187.75,67.84 187.75,65.93
5V_S0 on BOTTOM: 69.13,23.13 68.87,23.39 67.86,23.39 67.6,23.64 67.6,25.16 70.65,25.16 71.29,24.53 71.29,23.13
5V_S0 on L4SGND: 170.09,12.46 170.09,8.91 168.82,7.64 159.6,7.64 157.29,9.95 156.83,9.95 156.63,9.75 156.63,9.16 155.49,8.02 143.55,8.02 143.47,8.1 141.06,8.1 140.06,7.09 128.09,7.09 125.52,9.67 123.99,9.67 123.61,9.29 113.2,9.29 111.16,7.26 95.42,7.26 94.4,8.27 76.87,8.27 74.21,10.94 72.56,10.94 71.41,12.08 70.91,12.08 68.75,14.24 68.75,22.12 69.25,22.62 69.25,23.01 68.49,23.77 68.49,24.66 69.25,25.42 71.41,25.42 73.06,23.77 73.06,18.05 77,14.12 85.64,14.12 87.03,15.51 88.94,15.51 91.61,12.85 108.12,12.85 110.66,15.39 116.5,15.39 116.52,15.36 121.45,15.36 122.11,16.02 126.61,16.02 127.12,16.53 138.34,16.53 142.53,12.34 153.33,12.34 153.71,12.72 159.17,12.72 161.71,10.18 165.14,10.18 165.52,10.56 165.52,11.07 168.19,13.73 168.82,13.73
5V_S5 on TOP: 65.83,1.16 65.19,1.8 65.19,10.69 66.21,11.7 66.21,12.34 66.84,12.97 66.84,16.27 66.85,16.29 66.85,20.27 67.02,20.44 70.65,20.44 71.16,19.93 71.16,16.4 71.41,16.15 71.41,7 74.72,3.7 111.57,3.7 115.57,7.7 126.87,7.7 128.16,6.42 128.16,4.91 128.03,4.78 116.64,4.78 113.02,1.16 ; 9 cut-outs
5V_S5 on TOP: 170.6,97.3 170.22,97.68 170.22,98.57 170.35,98.7 171.74,98.7 172,98.44 172,97.43 171.87,97.3 ; 2 cut-outs
5V_S5 on TOP: 5.25,29.74 4.87,30.12 4.87,31.13 4.99,31.26 5.37,31.26 5.63,31.01 5.63,30.63 5.75,30.5 6.14,30.5 6.52,30.88 6.52,31.26 6.64,31.39 7.28,31.39 7.53,31.64 7.53,33.8 7.79,34.05 8.14,34.05 8.17,34.03 9.08,34.03 9.13,34.08 9.41,34.08 9.51,33.98 9.51,32.33 9.23,32.05 9.23,31.21 8.88,30.85 8.01,30.85 6.9,29.74 ; 3 cut-outs
5V_S5 on BOTTOM: 69.38,14.88 69.38,21.35 69.76,21.74 71.41,21.74 71.41,18.56 71.03,18.18 71.03,15.26 70.65,14.88
5V_S5 on BOTTOM: 7.66,31.01 7.53,31.13 7.53,33.67 7.67,33.81 9.07,33.81 9.23,33.65 9.23,31.46 8.78,31.01 ; 2 cut-outs
5V_S5 on BOTTOM: 167.93,39.87 167.88,39.92 167.88,41.22 167.81,41.29 167.81,43.07 168.06,43.33 169.08,43.33 169.58,42.82 169.58,41.27 169.2,40.89 169.2,39.92 169.18,39.9 168.34,39.9 168.31,39.87
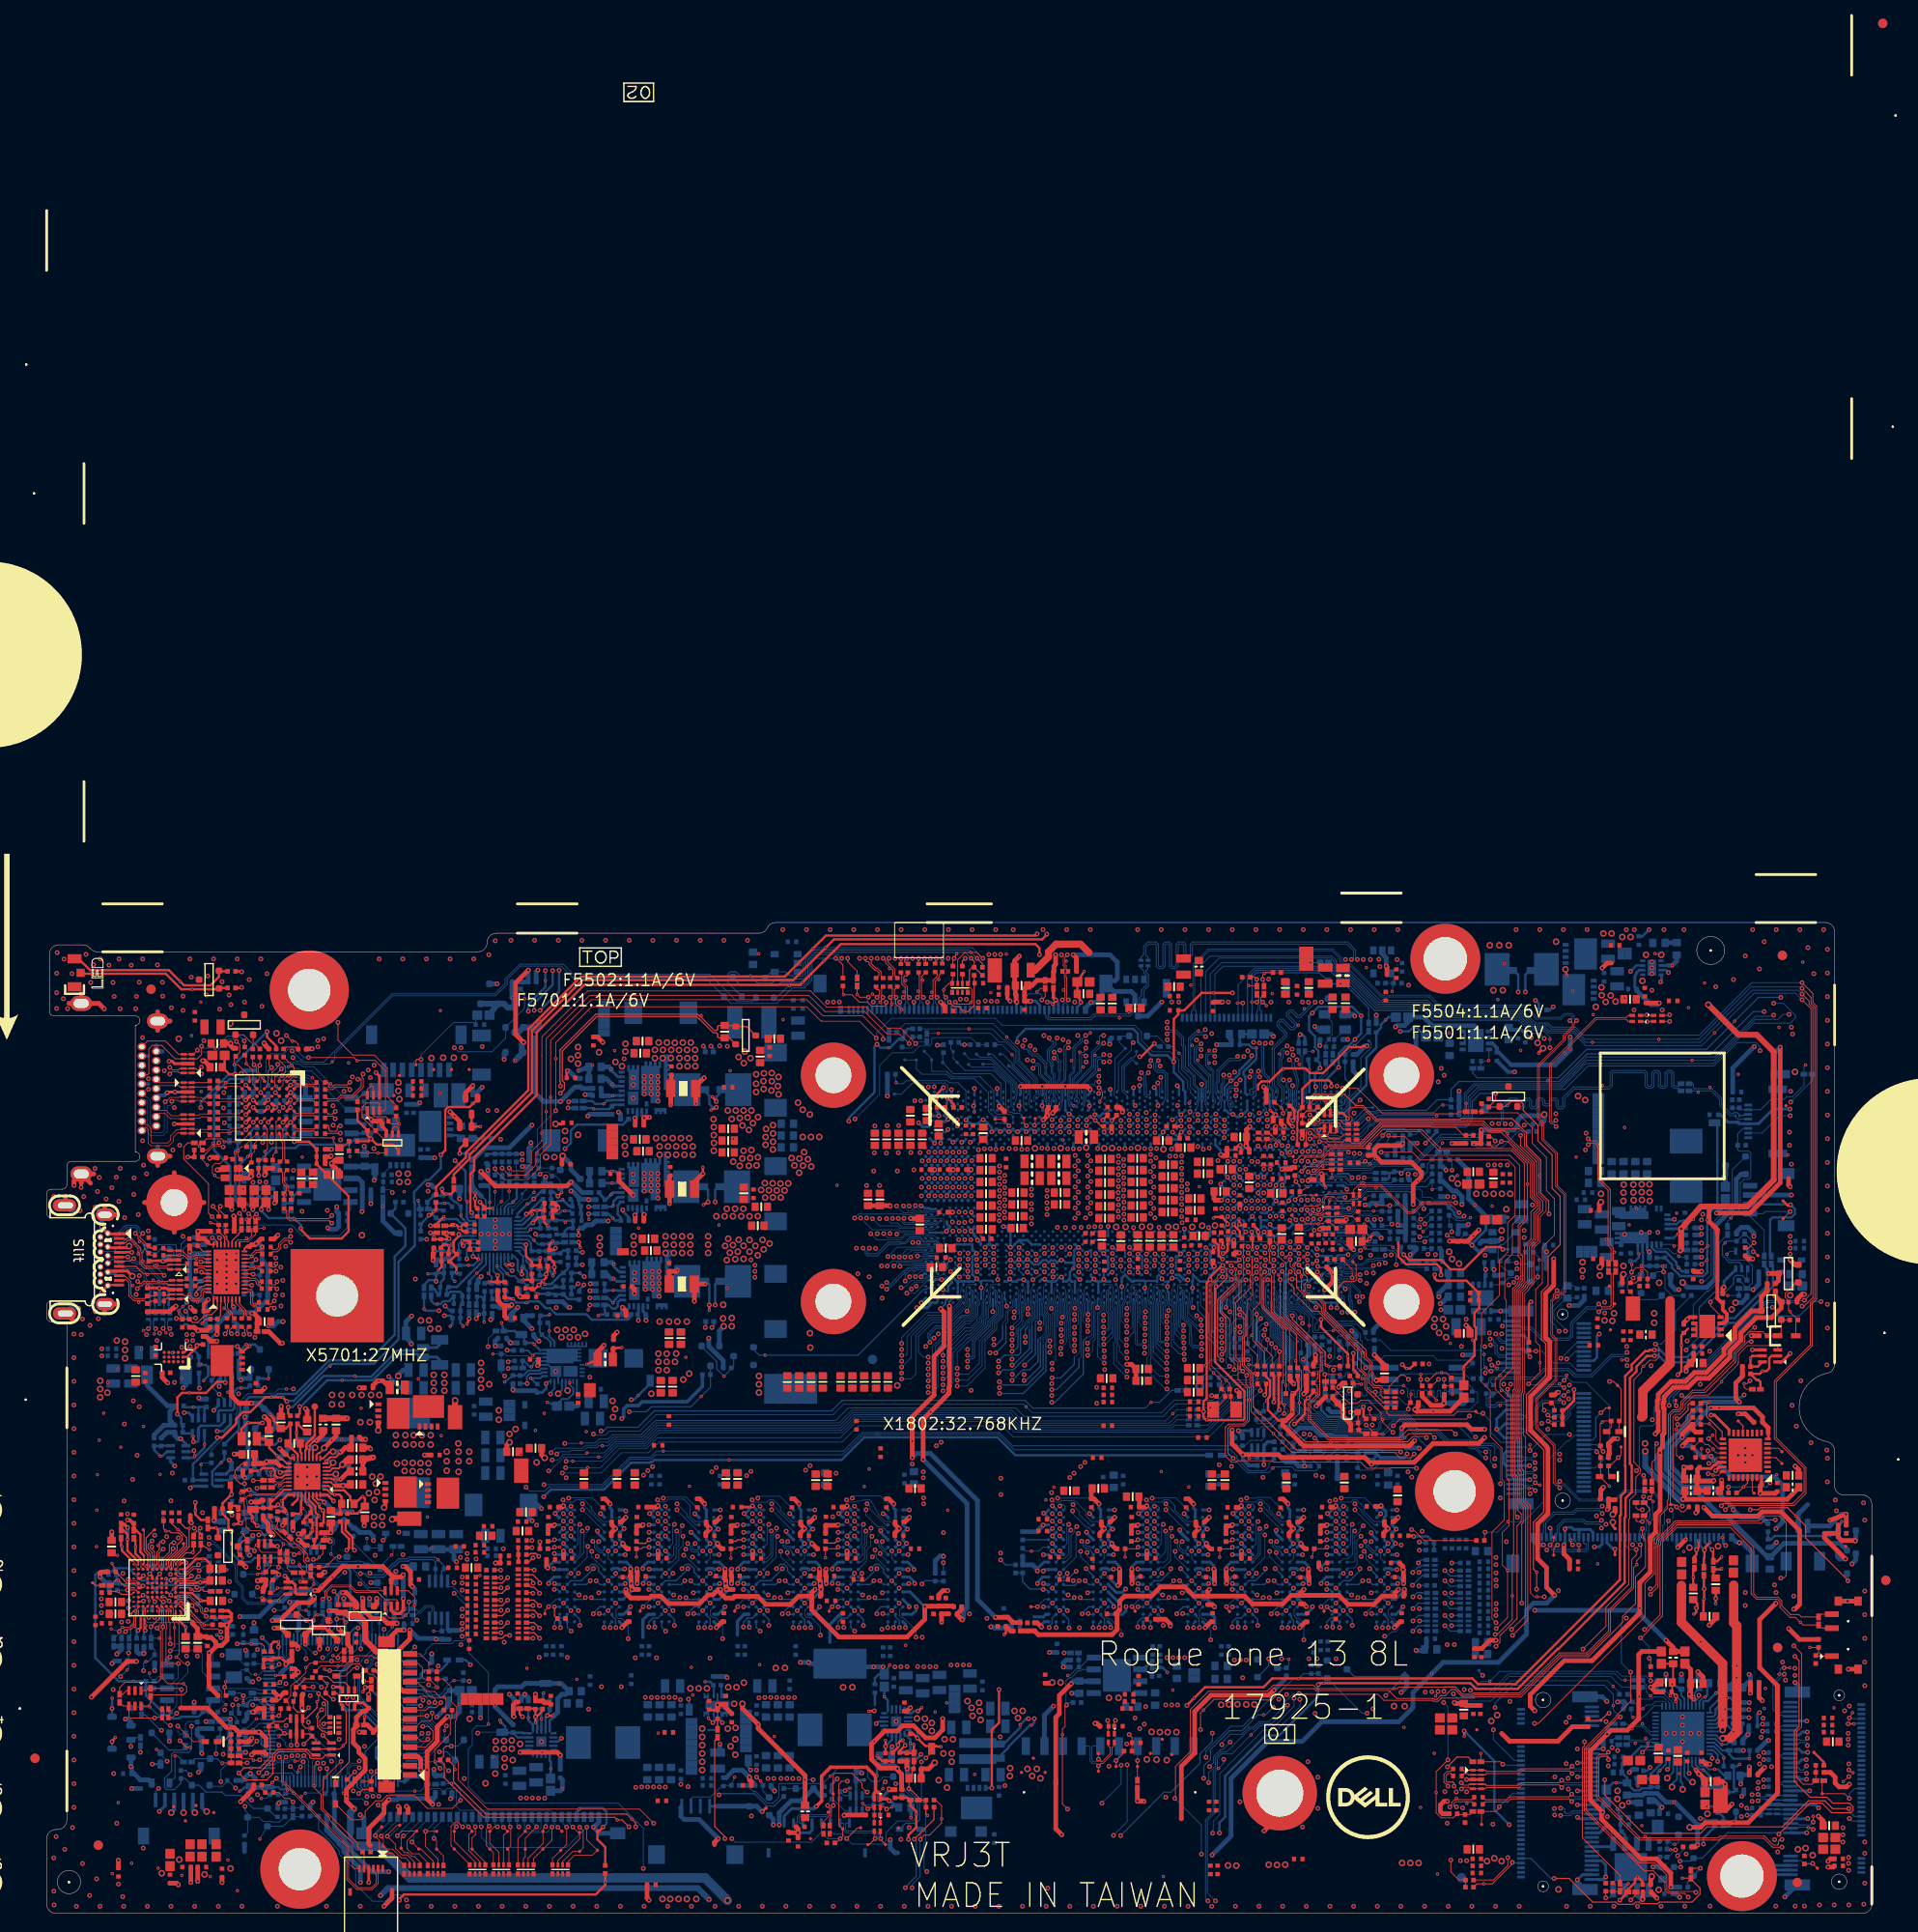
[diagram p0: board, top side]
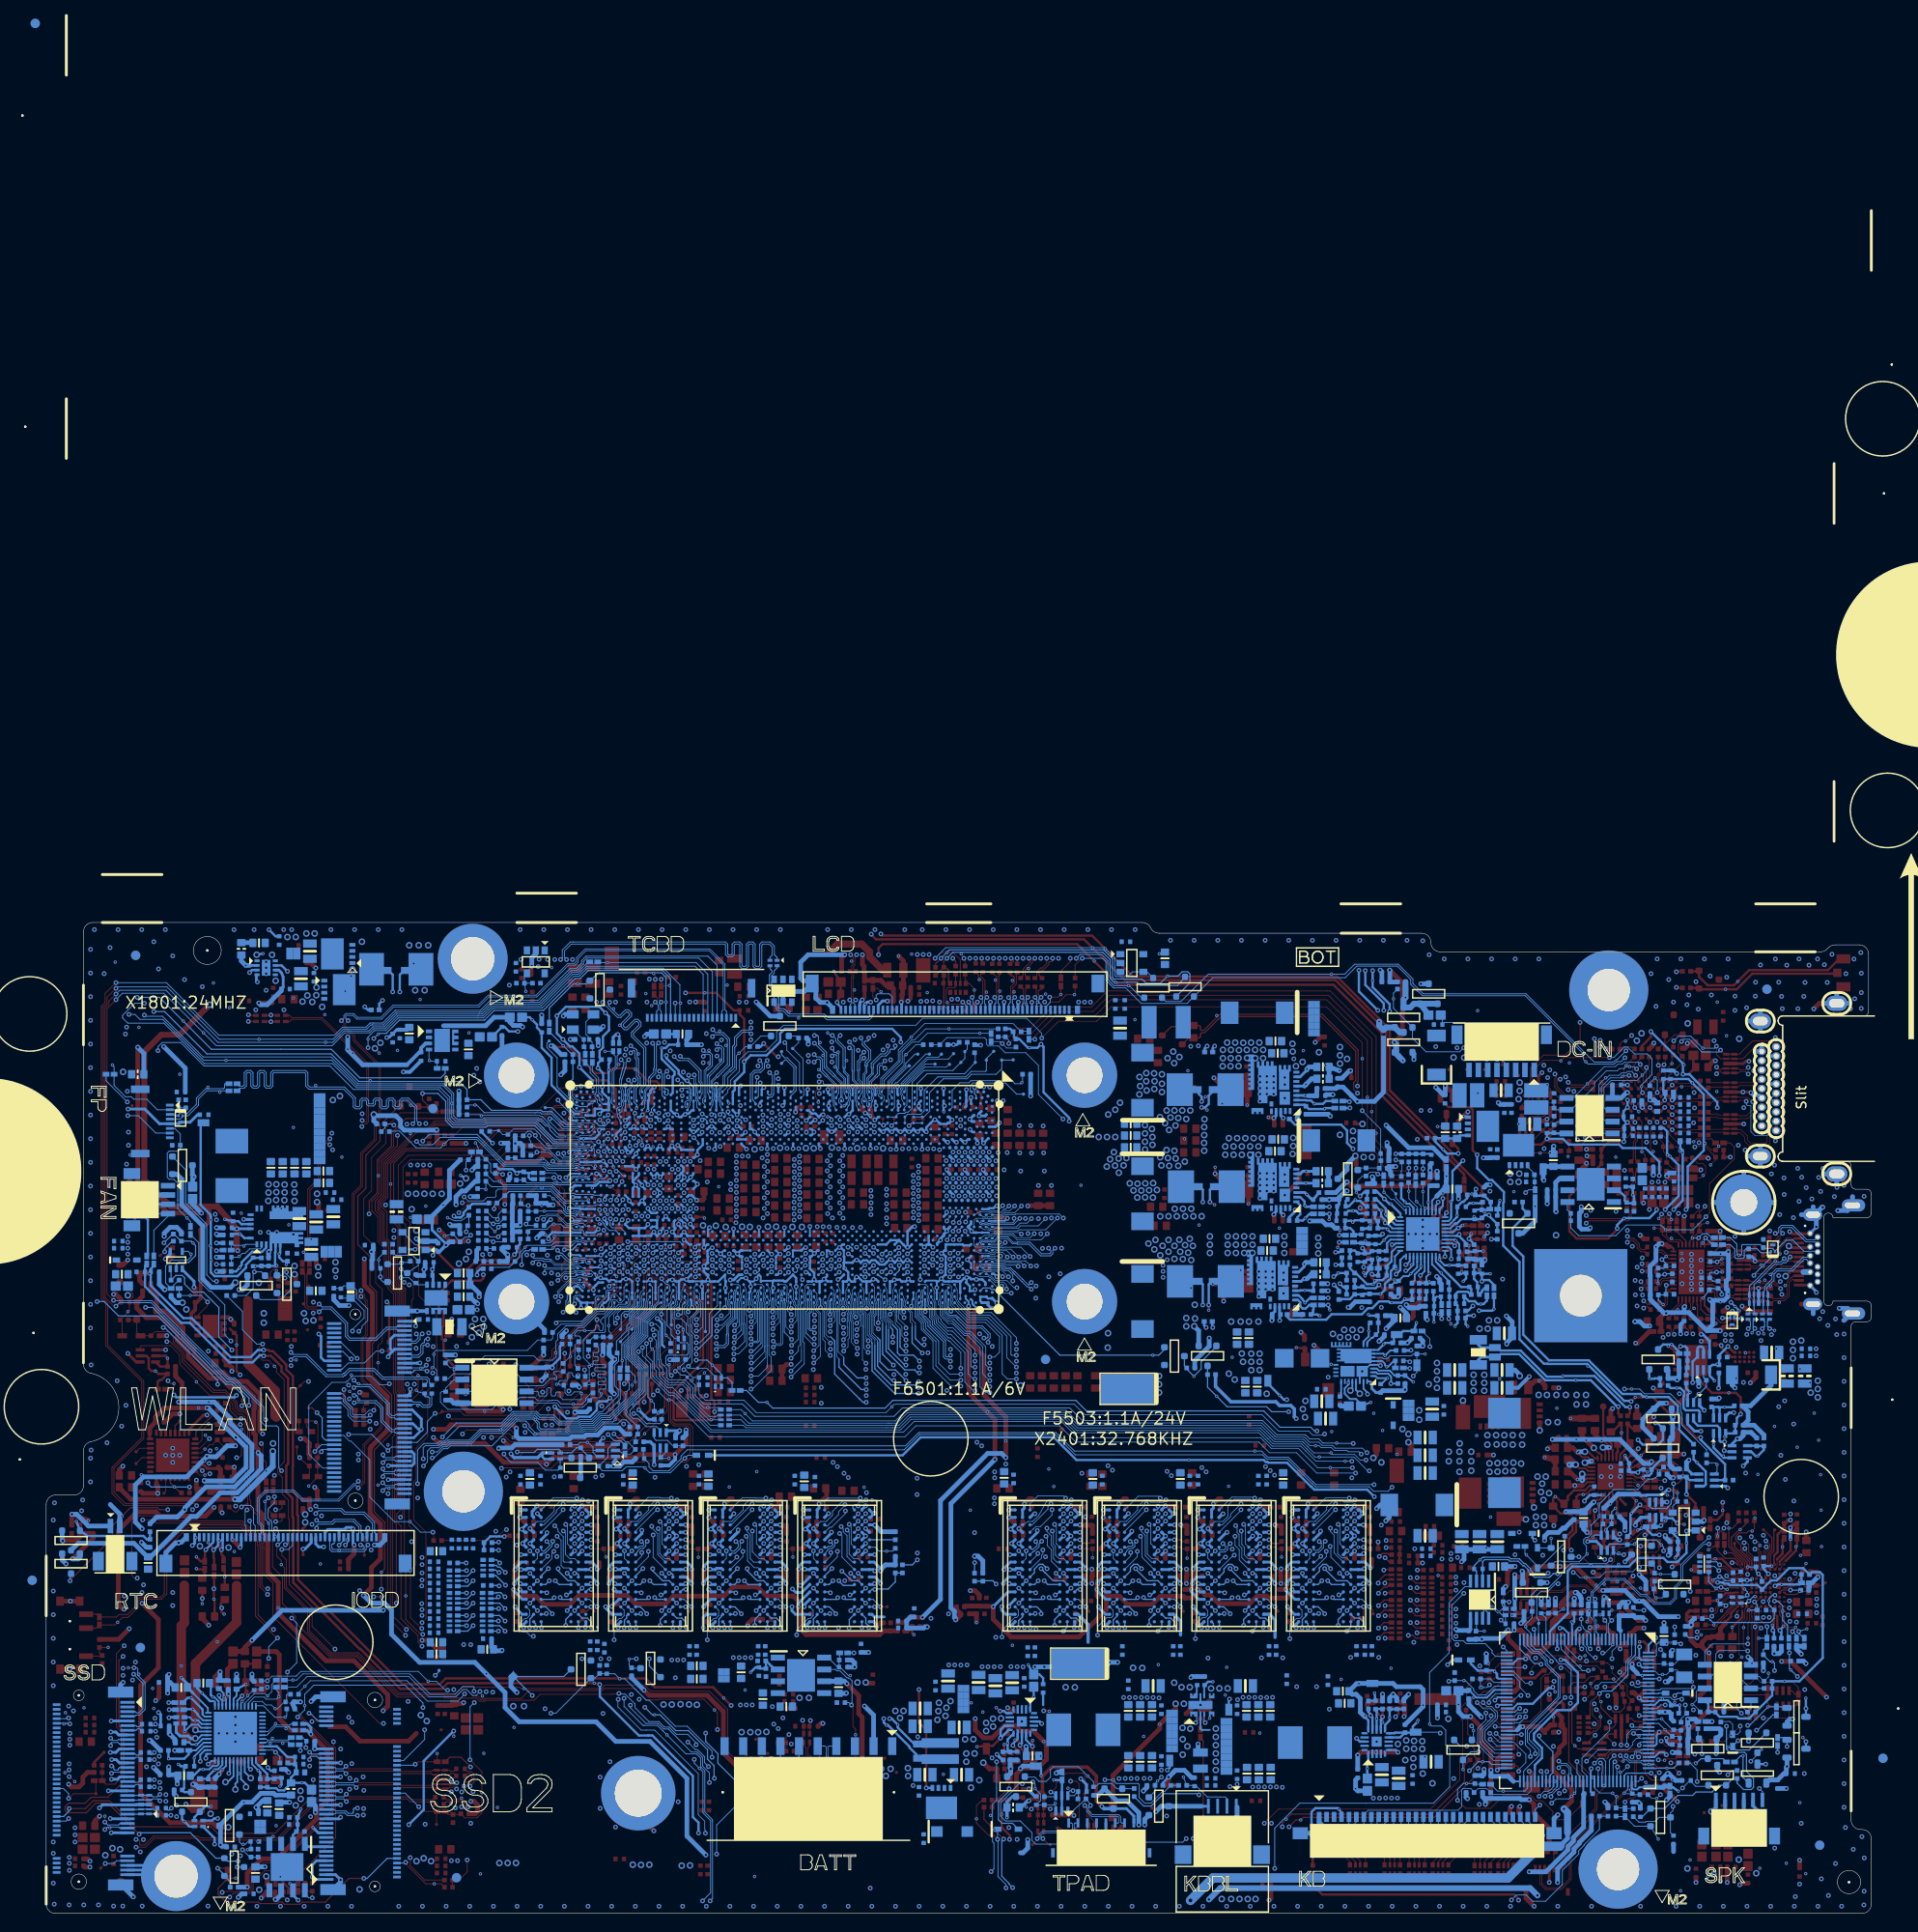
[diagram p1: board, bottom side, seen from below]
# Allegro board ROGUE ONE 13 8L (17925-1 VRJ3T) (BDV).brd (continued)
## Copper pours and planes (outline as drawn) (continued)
5V_S5 on L3SGND: 70.27,1.16 10.2,1.16 3.72,7.64 3.72,29.99 6.26,32.53 6.26,33.29 6.77,33.8 9.06,33.8 9.69,33.17 9.69,11.07 10.83,9.92 18.71,9.92 18.84,9.8 19.85,9.8 20.99,10.94 29.83,10.94 33.9,6.88 42.33,6.88 42.97,6.24 69.25,6.24 71.29,4.21 71.29,2.18
5V_S5 on L3SGND: 169.97,43.71 169.97,41.29 167.68,39.01 167.68,34.31 164.63,31.26 164.63,27.2 156.12,18.69 152.82,18.69 152.77,18.64 147.28,18.64 146.44,17.8 133.08,17.8 129.45,14.17 129.45,5.05 128.99,4.59 125.36,4.59 124.22,5.73 124.22,12.44 124.98,13.2 124.98,14.93 130.65,20.59 130.67,20.59 130.85,20.77 142.2,20.77 143.17,21.74 146.42,21.74 147.05,22.37 152.69,22.37 153.84,23.51 154.85,23.51 160.57,29.23 160.57,30.24 165.27,34.94 165.27,40.02 164.76,40.53 164.76,44.21 165.65,45.1 168.57,45.1
19V_AD+ on BOTTOM: 35.09,81.17 34.88,81.39 34.88,82.48 36.21,83.81 36.69,83.81 36.95,84.07 36.95,85.36 37.25,85.67 37.96,85.67 38.32,86.02 38.32,86.17 38.42,86.28 40.4,86.28 40.55,86.12 42.46,86.12 42.46,82.87 41.24,81.65 40.02,81.65 39.54,81.17 ; 5 cut-outs
19V_AD_JK on BOTTOM: 42.97,83.84 42.71,84.09 42.71,86.12 42.46,86.38 41.7,86.38 41.44,86.63 41.44,87.52 41.57,87.65 45,87.65 45.25,87.39 46.14,87.39 46.83,86.71 46.83,83.97 46.7,83.84 ; 8 cut-outs
19V_DCBATOUT on TOP: 39.41,53.1 39.28,53.23 39.28,57.93 40.55,59.2 43.09,59.2 43.47,58.82 43.47,55.52 42.71,54.76 42.71,53.23 42.58,53.1
19V_DCBATOUT on BOTTOM: 40.17,55.52 40.04,55.64 40.04,59.07 41.19,59.07 41.44,59.33 41.95,59.33 42.08,59.45 43.22,59.45 43.35,59.33 44.11,59.33 44.36,59.07 44.36,55.77 44.11,55.52
19V_DCBATOUT_LCD on BOTTOM: 76.62,93.74 76.37,94 76.37,97.17 76.62,97.43 82.46,97.43 83.61,96.28 85.64,96.28 85.89,96.54 85.89,97.55 86.15,97.81 87.42,97.81 87.8,97.43 87.8,95.78 87.03,95.01 78.91,95.01 78.53,94.63 78.53,94 78.27,93.74 ; 4 cut-outs
20V_VCCPD_VBUS on TOP: 7.79,57.55 7.02,58.31 7.02,61.61 7.28,61.87 9.82,61.87 11.34,60.34 11.98,60.34 12.49,59.84 14.26,59.84 14.26,59.45 12.87,59.45 12.74,59.33 12.74,59.07 11.22,57.55 ; 7 cut-outs
20V_VCCPD_VBUS on BOTTOM: 10.07,56.79 9.95,56.91 9.95,57.55 9.69,57.8 6.39,57.8 6.26,57.93 6.26,59.07 6.39,59.2 6.77,59.2 7.02,59.45 7.02,62.38 6.64,62.76 6.64,63.65 7.41,64.41 7.53,64.41 7.79,64.66 7.79,67.07 6.14,68.73 6.14,68.98 6.39,69.23 8.55,69.23 9.82,67.96 9.82,63.01 10.33,62.5 10.33,59.58 10.71,59.2 11.47,59.2 11.72,58.95 11.72,57.04 11.47,56.79 ; 3 cut-outs
20V_VCCPD_VBUS on L4SGND: 6.44,71.98 9.21,71.98 10.58,70.6 10.58,65.45 8.8,63.67 8.8,58.82 8.73,58.74 7.61,58.74 6.44,59.91 6.44,64.03 7.28,64.86 7.28,66.74 6.44,67.58
20V_VCCPD_VBUS_L on TOP: 8.45,35.83 7.81,36.47 6.01,36.47 5.88,36.59 4.23,36.59 3.47,37.36 3.47,56.41 4.74,57.68 7.15,57.68 7.53,57.3 7.53,39.01 9.56,36.98 9.56,36.85 9.95,36.47 9.95,36.34 9.44,35.83 ; 3 cut-outs
20V_VCCPD_VBUS_L on BOTTOM: 5.53,54.88 5.21,55.2 5.21,57.26 5.6,57.65 9.56,57.65 9.82,57.4 9.82,56.28 9.61,56.08 9.34,56.08 8.14,54.88
+5V_PVDD on TOP: 172.12,13.61 172.12,14.62 171.36,15.39 171.11,15.39 170.73,15.77 170.73,16.91 170.85,17.04 172.76,17.04 172.89,16.91 175.68,16.91 175.93,16.66 176.44,16.66 176.57,16.53 176.57,15.26 176.7,15.13 176.7,14.88 176.44,14.62 174.66,14.62 174.28,15 173.9,15 173.52,14.62 173.52,13.86 173.27,13.61 ; 6 cut-outs
+5V_PVDD on BOTTOM: 176.29,14.75 176.14,14.9 176.14,15.18 176.19,15.23 176.19,16.73 176.21,16.76 176.37,16.76 176.39,16.73 176.39,15.46 176.67,15.18 176.67,14.9 176.52,14.75
GND on TOP: 64.94,65.93 63.92,66.95 63.92,69.74 64.43,70.25 64.56,70.25 65.06,70.76 65.06,71.77 64.81,72.03 64.81,72.92 65.06,73.17 69.76,73.17 70.14,72.79 70.14,70.25 69.38,69.49 66.84,69.49 66.21,68.85 66.21,66.19 65.95,65.93 ; 5 cut-outs
GND on TOP: 153.76,78.99 153.68,79.06 153.68,80.56 153.81,80.69 157.19,80.69 157.54,80.33 157.54,79.16 157.37,78.99 ; 5 cut-outs
GND on TOP: 35.09,41.04 34.84,41.29 34.84,44.16 34.74,44.26 34.56,44.26 34.43,44.39 34.43,44.72 34.1,45.05 33.59,45.05 33.44,45.2 33.44,46.5 33.69,46.75 34.46,46.75 34.84,47.14 34.84,48.41 35.09,48.66 36.49,48.66 36.74,48.41 36.74,44.72 35.85,44.72 35.6,44.47 35.6,43.2 35.85,42.94 36.23,42.94 36.36,42.82 36.36,41.29 36.11,41.04 ; 1 cut-out
GND on TOP: 23.89,62.81 23.61,63.09 23.61,64.1 23.94,64.43 24.45,64.43 24.75,64.74 24.75,65.88 24.52,66.11 24.25,66.11 24.17,66.19 24.17,70.58 25.54,71.95 34.46,71.95 35.32,71.09 35.32,64.74 33.39,62.81 ; 1 cut-out
GND on TOP: 147.49,58.44 147.49,59.33 147.11,59.71 143.55,59.71 141.26,61.99 140.37,61.99 137.58,64.79 137.58,65.8 139.49,67.71 140.5,67.71 141.39,68.6 141.39,71.27 144.44,71.27 144.82,70.88 144.82,70.38 145.84,69.36 147.36,69.36 149.26,67.46 152.57,67.46 153.2,66.82 153.2,65.17 152.57,64.53 149.01,64.53 148.12,63.65 148.12,62.12 149.77,60.47 149.77,58.95 149.26,58.44 ; 5 cut-outs
GND on TOP: 123.23,70.5 123.1,70.63 123.1,71.01 123.48,71.39 123.48,72.03 123.86,72.41 123.86,73.04 124.12,73.3 125.77,73.3 125.92,73.45 125.92,74.01 125.97,74.06 126.4,74.06 126.45,74.01 126.45,73.75 126.79,73.42 127.6,73.42 127.8,73.22 127.8,72.79 127.67,72.66 125.01,72.66 124.88,72.54 124.88,71.39 124.63,71.14 124.25,71.14 124.12,71.01 124.12,70.76 123.86,70.5 ; 3 cut-outs
GND on TOP: 132.88,97.55 132.37,98.06 132.37,98.95 132.5,99.08 140.25,99.08 141.9,100.73 145.84,100.73 146.47,100.09 146.47,99.08 146.09,98.7 141.64,98.7 140.5,97.55 ; 15 cut-outs
GND on TOP: 57.7,52.72 56.43,53.99 56.43,54.76 56.81,55.14 60.24,55.14 60.36,55.26 61.25,55.26 61.63,54.88 61.63,53.49 60.87,52.72 ; 2 cut-outs
GND on TOP: 175.81,16.91 175.55,17.16 172.89,17.16 172.38,17.67 172.38,20.72 173.14,21.48 177.71,21.48 177.97,21.23 177.97,17.04 176.44,17.04 176.32,16.91 ; 7 cut-outs
GND on TOP: 7.79,41.8 7.66,41.93 7.66,56.53 8.55,57.42 10.96,57.42 13.37,55.01 14.31,55.01 14.89,55.58 17.88,55.58 18.45,55.01 18.45,53.36 17.18,52.09 17.18,50.31 18.33,49.17 18.33,43.71 17.18,42.56 14.77,42.56 14.64,42.69 10.96,42.69 10.07,41.8 9.18,41.8 9.06,41.93 8.42,41.93 8.29,41.8 ; 10 cut-outs
GND on TOP: 18.33,32.91 17.95,33.29 17.95,38.75 18.07,38.88 18.71,38.88 19.22,38.37 19.98,38.37 20.36,37.99 20.36,33.29 19.98,32.91 ; 9 cut-outs
GND on TOP: 147.87,40.4 146.09,42.18 146.09,44.34 145.58,44.85 144.18,44.85 142.66,46.37 124.88,46.37 124.25,47.01 124.25,51.76 123.41,52.6 123.41,58.87 123.48,58.95 123.48,59.84 123.74,60.09 124.12,60.09 124.25,59.96 124.25,55.52 123.89,55.16 123.89,52.95 124.37,52.47 125.9,52.47 126.57,51.8 126.57,49 127.17,48.41 128.31,48.41 128.45,48.54 131.34,48.54 131.48,48.41 142.36,48.41 142.86,47.9 146.6,47.9 149.39,50.69 155.49,50.69 156.25,49.93 156.25,43.07 153.58,40.4 ; 17 cut-outs
GND on TOP: 166.54,60.6 166.28,60.85 166.28,63.26 166.66,63.26 168.06,61.87 170.35,61.87 170.47,61.74 170.47,60.72 170.35,60.6 ; 3 cut-outs
GND on TOP: outline of 324 points within 0.51,0.51 195.49,105.84 ; 33 cut-outs
GND on TOP: 32.68,52.34 32.42,52.6 32.42,53.36 31.79,53.99 30.65,53.99 30.27,54.37 30.27,55.64 30.65,56.03 35.6,56.03 36.11,55.52 36.11,53.36 35.85,53.1 35.22,53.1 35.09,52.98 35.09,52.6 34.84,52.34
GND on TOP: 64.81,76.47 63.92,77.36 63.92,83.58 64.05,83.71 69.38,83.71 70.02,83.08 70.02,80.79 69.25,80.03 66.71,80.03 66.08,79.39 66.08,76.73 65.83,76.47 ; 5 cut-outs
GND on TOP: 81.83,46.75 81.19,47.39 81.19,47.77 81.7,48.28 84.37,48.28 85.13,47.52 85.13,47.01 84.88,46.75 ; 3 cut-outs
GND on TOP: 190.79,17.8 189.78,18.81 189.78,19.45 188.76,20.47 188.76,21.1 189.02,21.35 191.05,21.35 191.17,21.23 191.17,19.32 191.68,18.81 191.68,18.05 191.43,17.8 ; 3 cut-outs
GND on TOP: 136.18,67.84 135.83,68.19 135.83,71.29 135.37,71.75 133.29,71.75 133.19,71.65 133.19,71.24 133.11,71.16 132.45,71.16 132.35,71.27 132.35,71.7 132.3,71.75 132.14,71.75 132.07,71.82 132.07,72.61 132.17,72.71 134.94,72.71 135.34,72.31 135.78,72.31 135.8,72.28 138.32,72.28 138.44,72.15 138.44,70.68 138.65,70.48 138.65,70 138.37,69.72 137.28,69.72 137.07,69.51 137.07,68.09 136.82,67.84 ; 5 cut-outs
GND on TOP: 51.35,39.64 51.22,39.77 51.22,42.31 51.47,42.56 51.47,44.21 51.73,44.47 52.24,44.47 52.62,44.09 52.62,43.33 52.87,43.07 52.87,41.55 52.62,41.29 52.62,40.4 52.49,40.28 52.49,39.9 52.24,39.64 ; 7 cut-outs
GND on TOP: 55.41,46.63 55.28,46.75 55.28,47.39 56.68,48.79 56.68,49.8 56.94,50.06 57.44,50.06 57.82,49.68 59.98,49.68 60.36,50.06 60.36,51.2 60.49,51.33 61.25,51.33 61.89,50.69 62.4,50.69 63.79,52.09 63.79,55.64 64.56,56.41 67.6,56.41 67.73,56.28 67.73,54.5 67.1,53.87 67.1,53.1 66.97,52.98 66.33,52.98 65.44,52.09 65.44,48.28 65.32,48.15 65.32,47.77 64.3,46.75 57.06,46.75 56.94,46.63 ; 11 cut-outs
GND on TOP: 88.43,83.2 88.18,83.46 88.18,84.6 88.43,84.85 91.73,84.85 92.62,85.74 95.42,85.74 96.18,86.51 96.18,86.76 96.81,86.76 96.81,86.12 97.07,85.87 97.07,84.09 96.94,83.97 95.29,83.97 94.53,83.2 ; 15 cut-outs
GND on TOP: outline of 161 points within 75.73,29.48 122.47,82.19 ; 84 cut-outs
GND on TOP: 104.94,82.44 104.81,82.57 104.81,83.46 104.69,83.58 101.39,83.58 101.26,83.71 100.24,83.71 99.86,84.09 98.46,84.09 98.34,84.22 98.34,85.36 98.46,85.49 98.85,85.49 99.23,85.87 99.23,86.76 99.48,87.01 100.75,87.01 101.26,86.51 101.26,85.11 102.15,84.22 106.21,84.22 106.47,83.97 106.47,83.58 105.7,82.82 105.7,82.57 105.58,82.44 ; 5 cut-outs
GND on TOP: 65.44,61.99 65.19,62.25 65.19,63.77 65.44,64.03 69,64.03 69.25,63.77 69.25,62.88 68.37,61.99 ; 3 cut-outs
GND on TOP: 5.88,30.75 5.75,30.88 5.75,31.39 5.63,31.51 5.12,31.51 4.99,31.64 4.99,34.69 5.14,34.84 6.14,34.84 6.24,34.74 6.24,34.08 6.26,34.05 6.77,34.05 7.15,33.67 7.15,31.64 7.02,31.51 6.52,31.51 6.26,31.26 6.26,30.88 6.14,30.75 ; 3 cut-outs
GND on TOP: 21.63,23.39 19.72,25.29 18.45,25.29 18.2,25.55 18.2,27.58 19.09,28.47 21.76,28.47 22.65,27.58 22.65,26.56 23.15,26.05 23.66,26.05 23.79,26.18 23.79,26.56 23.92,26.69 24.42,26.69 24.8,27.07 25.06,27.07 25.19,26.94 25.19,26.69 23.92,25.42 23.92,23.64 23.66,23.39 ; 1 cut-out
GND on TOP: 14.85,27.32 14.39,27.78 14.39,29.1 14.52,29.23 17.44,29.23 17.57,29.1 17.57,28.67 16.22,27.32 ; 3 cut-outs
GND on TOP: 10.96,31.13 10.58,31.51 10.58,35.93 10.78,36.14 10.94,36.14 11.09,35.98 11.09,35.71 11.98,35.71 12.23,35.96 12.23,36.09 12.87,36.72 13.25,36.72 13.63,36.34 13.63,35.58 13.37,35.32 13.25,35.32 12.99,35.58 12.74,35.58 12.49,35.32 12.49,34.31 12.36,34.18 11.22,34.18 11.09,34.05 11.09,33.55 11.85,32.78 11.85,32.66 11.98,32.53 11.98,31.64 11.47,31.13
GND on TOP: 64.81,86.89 63.79,87.9 63.79,90.95 64.05,91.2 64.05,92.98 63.92,93.11 63.92,94.76 64.17,95.01 69.51,95.01 70.02,94.51 70.02,91.2 69.25,90.44 66.71,90.44 66.08,89.81 66.08,87.14 65.83,86.89 ; 6 cut-outs
GND on TOP: 122.09,73.17 121.83,73.42 121.83,73.93 121.58,74.19 121.07,74.19 120.44,74.82 120.44,82.19 120.05,82.57 120.05,83.33 119.67,83.71 119.67,84.6 119.93,84.85 120.56,84.85 120.56,84.22 120.69,84.09 121.07,84.09 121.2,83.97 121.2,82.82 121.32,82.7 121.96,82.7 122.09,82.57 122.09,79.01 122.85,78.25 122.85,77.36 122.98,77.23 122.98,74.95 122.85,74.82 122.85,74.31 122.47,73.93 122.47,73.3 122.34,73.17 ; 18 cut-outs
GND on TOP: 118.02,16.02 117.13,16.91 117.13,19.2 116.75,19.58 115.36,19.58 115.23,19.7 115.23,20.85 116.12,21.74 116.12,22.24 116.37,22.5 116.37,24.4 116.88,24.91 117.51,24.91 118.4,24.02 121.07,24.02 121.83,23.26 121.83,16.78 121.07,16.02 ; 9 cut-outs
GND on TOP: 117.13,96.67 117.13,97.43 116.63,97.94 115.23,97.94 114.85,97.55 111.42,97.55 111.29,97.68 111.29,98.82 111.67,99.21 112.43,99.21 112.82,99.59 112.82,100.22 114.09,101.49 120.69,101.49 121.07,101.11 121.07,97.05 120.69,96.67 ; 13 cut-outs
GND on TOP: 45.12,28.97 45,29.1 45,29.86 44.24,30.63 44.24,35.71 43.73,36.21 43.73,37.23 44.49,37.99 44.49,39.64 46.65,41.8 47.28,41.8 47.28,40.53 46.39,39.64 46.39,37.99 46.27,37.86 45.76,37.86 45.51,37.61 45.51,29.74 45.63,29.61 45.63,28.97 ; 14 cut-outs
GND on TOP: 98.08,97.81 97.7,98.19 97.32,98.19 96.94,98.57 96.94,98.95 97.07,99.08 99.1,99.08 99.23,98.95 99.23,98.19 98.85,97.81
GND on TOP: 46.14,70.88 45.89,71.14 45.89,72.54 45.63,72.79 45.63,74.69 46.14,75.2 50.08,75.2 50.71,74.57 50.71,72.54 49.06,70.88 ; 8 cut-outs
GND on TOP: 72.56,62.5 72.18,62.88 72.18,68.09 70.52,69.74 70.52,75.08 71.29,75.84 71.54,75.84 72.2,76.5 72.2,77.62 71.03,78.78 71.03,85.24 72.3,86.51 72.3,87.52 72.05,87.78 72.05,90.44 74.08,92.47 74.08,93.74 75.99,95.65 77.89,95.65 78.02,95.52 78.02,92.73 77.89,92.6 77.51,92.6 76.87,91.97 76.11,91.97 73.06,88.92 73.06,79.06 73.94,78.19 73.94,77.45 74.33,77.06 76.19,77.06 76.75,76.5 76.75,74.69 76.11,74.06 76.11,73.42 75.86,73.17 72.68,73.17 72.18,72.66 72.18,70.25 73.95,68.47 73.95,62.76 73.7,62.5 ; 15 cut-outs
GND on TOP: 113.96,74.19 113.83,74.31 113.83,81.43 113.96,81.55 116.75,81.55 116.88,81.43 116.88,74.31 116.75,74.19 ; 10 cut-outs
GND on TOP: 99.86,96.79 99.73,96.92 99.73,97.43 99.86,97.55 99.86,99.08 100.24,99.46 100.24,99.97 100.37,100.09 100.62,100.09 100.75,99.97 100.75,99.46 100.37,99.08 100.37,96.92 100.24,96.79
GND on TOP: 169.33,75.33 168.82,75.84 168.82,78.61 169,78.78 172.58,78.78 172.94,78.43 172.94,75.66 172.61,75.33
GND on TOP: 184.7,69.11 183.94,69.87 183.94,75.33 186.63,78.02 186.63,88.41 186.88,88.66 188.51,88.66 188.89,88.28 188.89,69.49 188.51,69.11
GND on TOP: 64.05,11.7 63.67,12.08 49.95,12.08 49.57,12.46 49.57,13.61 50.97,15 50.97,16.25 49.92,17.29 48.17,17.29 47.92,17.54 47.92,18.69 48.17,18.94 49.06,18.94 49.07,18.93 49.58,18.93 49.98,19.32 53.63,19.32 55.28,20.97 65.65,20.97 66.71,19.91 66.71,13.23 65.95,12.46 65.95,12.08 65.57,11.7 ; 3 cut-outs
GND on TOP: 132.7,80.33 132.63,80.41 132.63,80.92 132.5,81.04 130.47,81.04 129.71,81.81 129.71,82.44 129.96,82.7 131.36,82.7 132.25,81.81 132.75,81.81 133.26,81.3 133.26,80.41 133.19,80.33 ; 2 cut-outs
GND on TOP: 29.91,72.76 29.73,72.94 29.73,73.68 29.88,73.83 30.39,73.83 30.49,73.73 31,73.73 31.13,73.86 31.13,75 30.87,75.25 30.52,75.25 30.47,75.2 27.22,75.2 26.71,75.71 26.71,78.5 27.01,78.81 30.77,78.81 32.02,77.56 32.02,73.32 31.46,72.76 ; 4 cut-outs
GND on TOP: 90.59,7.51 89.96,8.15 89.96,10.69 90.08,10.81 92.5,10.81 93,10.31 93,8.91 92.24,8.15 92.24,7.64 92.11,7.51 ; 1 cut-out
GND on TOP: 143.17,86 140.63,88.54 140.63,91.84 141.9,93.11 156.38,93.11 160.19,89.3 160.19,88.46 159.91,88.18 157.49,88.18 156.4,87.09 154.67,87.09 154.37,86.78 153.76,86.78 153.71,86.84 153.71,87.39 153.58,87.52 152.85,87.52 152.74,87.42 152.74,86.86 152.69,86.81 151.85,86.81 151.04,86 ; 1 cut-out
GND on TOP: 71.41,46.75 71.16,47.01 71.16,47.52 71.79,48.15 75.35,48.15 75.86,47.64 75.86,47.26 75.35,46.75 ; 3 cut-outs
GND on TOP: 131.23,75.46 131.1,75.58 131.1,77.74 131.23,77.87 131.48,77.87 131.61,78 131.61,78.5 131.48,78.63 125.9,78.63 125.52,78.25 124.88,78.25 124.75,78.38 124.75,78.5 124.5,78.76 124.5,81.04 124.63,81.17 125.39,81.17 125.52,81.04 125.9,81.04 126.4,80.54 126.4,79.52 126.66,79.27 128.31,79.27 128.56,79.52 129.96,79.52 130.21,79.27 131.99,79.27 132.12,79.14 132.12,76.85 132.37,76.6 133.14,76.6 133.26,76.73 133.52,76.73 133.64,76.6 133.64,76.22 133.26,75.84 131.99,75.84 131.61,75.46 ; 4 cut-outs
GND on BOTTOM: 58.97,52.34 58.84,52.47 58.84,54.12 59.22,54.5 59.22,56.15 59.09,56.28 59.09,56.79 59.22,56.91 61,56.91 61.38,56.53 61.38,52.85 61,52.47 59.98,52.47 59.86,52.34 ; 2 cut-outs
GND on BOTTOM: 135.42,26.31 135.17,26.56 135.17,27.7 135.8,28.34 136.31,28.34 136.56,28.59 138.34,28.59 138.85,28.09 138.85,27.07 138.09,26.31 ; 7 cut-outs
GND on BOTTOM: 149.77,89.55 149.52,89.81 149.52,92.6 149.65,92.73 151.42,92.73 151.68,92.98 152.31,92.98 152.44,92.86 152.44,92.35 152.57,92.22 153.07,92.22 153.46,91.84 153.46,91.2 151.93,91.2 150.28,89.55 ; 5 cut-outs
GND on BOTTOM: 119.55,97.55 119.04,98.06 119.04,100.48 119.17,100.6 120.82,100.6 121.07,100.35 121.07,97.68 120.94,97.55
GND on BOTTOM: 5.75,31.39 5.63,31.51 5.63,33.8 5.88,34.05 6.9,34.05 7.15,33.8 7.15,31.51 7.02,31.39 ; 2 cut-outs
GND on BOTTOM: 120.18,26.18 119.93,26.43 119.55,26.43 119.29,26.69 119.29,27.2 119.17,27.32 118.28,27.32 118.02,27.07 116.5,27.07 116.5,27.7 116.88,28.09 122.47,28.09 122.85,27.7 122.85,27.07 122.34,26.56 121.96,26.56 121.58,26.18 ; 3 cut-outs
GND on BOTTOM: 64.56,55.39 64.43,55.52 64.43,56.03 64.81,56.41 67.48,56.41 67.98,56.91 67.98,57.42 68.87,58.31 69.13,58.31 69.64,57.8 69.64,56.91 68.11,55.39
GND on BOTTOM: 64.17,21.86 63.92,22.12 63.92,24.78 64.3,25.16 66.84,25.16 67.1,24.91 67.1,23.77 67.48,23.39 68.24,23.39 68.37,23.26 68.49,23.26 69.25,22.5 69.25,21.99 69.13,21.86 ; 3 cut-outs
GND on BOTTOM: 74.08,60.22 72.18,62.12 72.18,63.9 72.56,64.28 78.91,64.28 85,70.38 87.42,70.38 87.92,69.87 89.7,69.87 89.96,69.61 89.96,63.39 86.78,60.22
GND on BOTTOM: outline of 467 points within 0.51,0.51 195.49,105.84 ; 28 cut-outs
GND on BOTTOM: 186.22,68.09 185.84,68.47 185.84,69.23 185.46,69.61 185.46,69.74 185.33,69.87 185.08,69.87 185.08,70.5 185.33,70.76 185.33,74.44 187.87,74.44 188.13,74.19 188.13,71.65 187.75,71.27 187.75,68.22 187.62,68.09 ; 4 cut-outs
GND on BOTTOM: 23.32,79.85 23.14,80.03 23.14,80.52 24.4,81.78 26.73,81.78 27.39,82.44 30.52,82.44 30.93,82.03 30.93,80.46 30.79,80.32 29.24,80.32 28.12,81.44 27.13,81.44 26.61,80.92 24.22,80.92 23.92,80.61 23.92,80.13 23.64,79.85
GND on BOTTOM: 62.52,46.63 62.52,47.77 63.03,48.28 86.02,48.28 86.4,48.66 93.64,48.66 94.53,47.77 94.53,46.88 94.27,46.63 ; 21 cut-outs
GND on BOTTOM: 167.98,14.72 167.43,15.28 167.43,15.97 167.6,16.15 167.93,16.15 168.14,16.35 168.14,16.99 168.21,17.06 168.64,17.06 168.77,16.93 168.77,14.95 168.54,14.72 ; 1 cut-out
GND on BOTTOM: 18.78,82.44 18.5,82.72 18.5,88.05 18.77,88.32 19.76,88.32 19.93,88.16 19.93,82.59 19.77,82.44 ; 7 cut-outs
GND on BOTTOM: 64.94,76.35 64.94,77.23 63.89,77.23 63.89,80.74 64.1,80.94 64.1,82.39 63.97,82.52 63.97,83.51 64.17,83.71 69.25,83.71 69.89,83.08 69.89,80.66 69.51,80.28 66.21,80.28 66.08,80.16 66.08,76.47 65.95,76.35 ; 3 cut-outs
GND on BOTTOM: 53.51,80.66 53.13,81.04 53.13,84.85 53.76,85.49 55.67,85.49 56.05,85.11 56.05,82.57 55.92,82.44 55.92,81.17 55.41,80.66
GND on BOTTOM: 118.02,13.61 117.77,13.86 117.77,19.07 116.5,20.34 116.5,21.23 116.63,21.35 116.63,22.5 117.13,23.01 123.1,23.01 123.61,22.5 123.61,16.27 120.94,13.61 ; 6 cut-outs
GND on BOTTOM: 165.77,65.93 165.65,66.06 165.65,67.71 166.41,68.47 166.41,69.74 166.66,70 166.66,71.01 168.44,71.01 168.57,71.14 169.33,71.14 169.58,70.88 169.58,69.87 169.84,69.61 169.84,68.47 169.58,68.22 168.57,68.22 168.31,67.96 167.43,67.96 167.04,67.58 167.04,66.06 166.92,65.93 ; 5 cut-outs
GND on BOTTOM: 93.51,86.38 92.88,87.01 92.88,88.03 93.89,89.05 95.42,89.05 95.8,88.66 95.8,88.54 96.05,88.28 96.05,88.03 95.42,88.03 94.6,87.22 94.6,86.45 94.53,86.38
GND on BOTTOM: 45.63,54.12 45.12,54.63 45.12,59.2 45.38,59.45 47.03,59.45 48.3,58.18 48.3,54.76 47.92,54.37 46.52,54.37 46.27,54.12 ; 2 cut-outs
GND on BOTTOM: 75.99,21.99 75.86,22.12 75.86,23.01 76.24,23.39 76.87,23.39 77.13,23.64 77.13,25.04 77.38,25.29 78.65,25.29 79.54,24.4 79.92,24.4 80.05,24.28 80.05,23.77 80.43,23.39 80.43,22.12 80.3,21.99 ; 4 cut-outs
GND on BOTTOM: 54.78,60.72 54.78,61.61 54.4,61.99 54.4,63.01 54.78,63.39 57.44,63.39 57.7,63.14 57.7,62.88 58.21,62.38 58.21,61.99 56.94,60.72
GND on BOTTOM: 167.55,6.62 167.17,7 167.17,10.43 167.43,10.69 167.81,10.69 168.7,9.8 168.7,6.75 168.57,6.62 ; 2 cut-outs
GND on BOTTOM: 102.02,69.11 101.89,69.23 101.89,71.14 101.77,71.27 100.5,71.27 98.97,72.79 98.97,73.17 98.72,73.42 98.72,73.81 98.85,73.93 99.35,73.93 99.61,74.19 99.61,74.57 99.1,75.08 96.43,75.08 95.92,75.58 95.92,75.71 96.05,75.84 99.73,75.84 99.99,75.58 99.99,72.66 100.75,71.9 102.27,71.9 102.4,71.77 102.4,69.23 102.27,69.11
GND on BOTTOM: 65.06,65.8 65.06,66.69 64.05,66.69 64.05,70 64.43,70.38 64.68,70.38 65.06,70.76 65.06,71.77 64.81,72.03 64.81,72.79 65.06,73.04 69.51,73.04 70.02,72.54 70.02,70.12 69.64,69.74 66.33,69.74 66.21,69.61 66.21,65.93 66.08,65.8 ; 2 cut-outs
GND on BOTTOM: 79.87,81.7 79.8,81.78 79.8,89.68 78.78,90.7 74.33,90.7 74.03,91 74.03,93.19 74.46,93.62 78.53,93.62 78.65,93.74 78.65,94.25 79.16,94.76 86.91,94.76 88.43,93.24 88.43,88.16 85.13,84.85 85.13,84.47 83.25,82.59 81.52,82.59 80.63,81.7 ; 3 cut-outs
GND on BOTTOM: 116.24,85.49 115.99,85.74 114.34,85.74 113.83,86.25 113.83,87.01 114.21,87.39 114.85,86.76 116.12,86.76 116.63,87.27 117.39,87.27 117.64,87.01 118.28,87.01 118.66,87.39 119.04,87.39 119.67,86.76 120.31,86.76 120.94,87.39 121.71,87.39 121.96,87.14 121.96,86.89 122.47,86.38 122.47,86 121.96,85.49 121.83,85.49 121.32,86 120.56,86 120.31,85.74 119.42,85.74 119.17,85.49 118.91,85.49 118.66,85.74 117.51,85.74 117.26,85.49 117.13,85.49 116.88,85.74 116.63,85.74 116.37,85.49
GND on BOTTOM: 43.6,37.48 42.58,38.5 39.03,38.5 38.77,38.25 38.01,38.25 37.89,38.37 37.89,38.63 38.14,38.88 38.65,38.88 39.41,39.64 44.74,39.64 44.87,39.52 44.87,39.26 45.38,38.75 45.38,37.86 45,37.48
GND on BOTTOM: 18.33,66.06 17.82,66.57 17.82,71.14 18.07,71.39 20.49,71.39 21.63,70.25 21.63,69.23 21.5,69.11 20.99,69.11 20.99,68.22 21.5,68.22 21.63,68.09 21.63,67.33 21.5,67.2 21.5,66.19 21.38,66.06 ; 7 cut-outs
GND on BOTTOM: 102.53,19.2 102.4,19.32 102.4,23.13 101,24.53 100.24,24.53 99.99,24.78 90.84,24.78 90.72,24.91 90.72,26.56 91.48,27.32 107.48,27.32 109.39,25.42 109.39,24.15 106.72,21.48 106.21,21.48 106.08,21.35 105.2,21.35 104.94,21.1 104.94,20.72 103.42,19.2 ; 3 cut-outs
GND on BOTTOM: 72.05,73.04 71.41,73.68 71.41,74.82 71.92,75.33 72.18,75.33 72.81,75.96 79.16,75.96 79.54,75.58 79.54,73.3 79.29,73.04
GND on BOTTOM: 132.63,97.43 132.25,97.81 132.25,100.35 132.37,100.48 134.53,100.48 135.8,99.21 135.8,98.82 134.41,97.43
GND on BOTTOM: 137.58,87.39 137.45,87.52 136.74,87.52 136.69,87.57 136.69,88.41 137.33,89.05 139.03,89.05 139.23,88.84 139.23,87.67 139.1,87.55 138.75,87.55 138.6,87.39
GND on BOTTOM: 35.35,83.97 35.09,84.22 34.71,84.22 34.46,84.47 34.46,84.98 34.33,85.11 33.82,85.11 33.69,85.24 33.69,85.87 33.82,86 34.33,86 34.46,86.12 34.46,87.65 34.35,87.75 33.82,87.75 33.54,88.03 31.79,88.03 31.28,88.54 31.28,92.09 34.46,95.27 35.47,95.27 35.73,95.01 35.73,92.22 35.6,92.09 35.6,85.87 35.98,85.49 36.36,85.49 36.49,85.36 36.49,84.09 36.36,83.97 ; 2 cut-outs
GND on BOTTOM: 44.49,92.6 43.73,93.36 43.73,95.01 43.98,95.27 45.25,95.27 45.51,95.01 46.27,95.01 46.39,95.14 46.39,95.65 46.52,95.78 47.92,95.78 48.3,95.4 48.3,93.36 47.54,92.6 ; 1 cut-out
GND on BOTTOM: 47.28,11.83 45.63,13.48 45.63,18.18 46.27,18.81 50.2,18.81 50.46,18.56 52.39,18.56 52.5,18.67 52.5,18.95 52.62,19.07 53.63,19.07 53.79,18.92 53.79,18.64 53.81,18.61 54.83,18.61 55.28,19.07 55.41,19.07 55.54,18.94 55.54,18.56 55.23,18.26 53.84,18.26 53.76,18.18 53.76,17.93 53.63,17.8 50.71,17.8 50.2,17.29 47.41,17.29 47.03,16.91 47.03,14.88 47.66,14.24 51.35,14.24 51.73,14.62 53.25,14.62 53.51,14.37 53.51,13.73 54.4,12.85 54.4,12.21 54.01,11.83 ; 2 cut-outs
GND on BOTTOM: 107.76,71.21 107.35,71.62 107.35,72.03 107.63,72.31 108.17,72.31 108.34,72.48 108.34,73.53 108.37,73.55 108.37,73.81 108.5,73.93 111.16,73.93 111.41,73.69 111.41,73.28 111.44,73.25 111.44,72.59 111.37,72.51 110.5,72.51 109.21,71.21
GND on BOTTOM: 76.37,14.24 75.86,14.75 75.86,16.15 75.99,16.27 81.32,16.27 81.57,16.02 81.57,14.62 81.19,14.24 ; 8 cut-outs
GND on BOTTOM: 125.9,95.4 125.82,95.47 125.82,96.92 125.77,96.97 125.77,98.06 125.9,98.19 127.42,98.19 127.55,98.06 127.55,95.52 127.42,95.4
GND on BOTTOM: 82.21,25.16 80.05,27.32 50.97,27.32 47.92,30.37 47.92,43.45 49.57,45.1 52.62,45.1 53.63,44.09 53.63,40.15 51.73,38.25 51.73,29.48 53,28.21 81.7,28.21 81.95,28.47 88.18,28.47 88.69,27.96 90.84,27.96 90.84,27.07 89.96,26.18 89.27,26.18 89.02,25.93 89.02,25.9 88.28,25.16 ; 17 cut-outs
GND on BOTTOM: 76.62,54.76 75.48,55.9 75.48,57.85 75.35,57.98 75.35,59.35 75.48,59.48 76.09,59.48 76.29,59.28 76.29,58.9 76.37,58.82 83.86,58.82 85.51,57.17 85.51,56.15 84.11,54.76
GND on BOTTOM: 10.83,31.39 10.58,31.64 10.58,31.9 10.96,32.28 10.96,32.78 11.09,32.91 11.6,32.91 11.72,32.78 11.72,32.28 11.85,32.15 13.63,32.15 14.52,33.04 14.52,34.44 14.64,34.56 16.93,34.56 17.95,35.58 17.95,37.74 18.07,37.86 19.34,37.86 19.98,37.23 19.98,35.2 20.49,34.69 20.49,33.04 20.23,32.78 17.82,32.78 16.93,33.67 15.79,33.67 15.28,33.17 15.28,31.77 14.9,31.39
GND on BOTTOM: 66.33,61.99 66.21,62.12 66.21,62.5 65.44,63.26 65.44,63.65 65.83,64.03 68.87,64.03 69.13,63.77 69.13,63.14 68.62,62.63 68.62,62.12 68.49,61.99 ; 2 cut-outs
GND on BOTTOM: 126.4,24.66 126.28,24.78 126.28,27.07 126.02,27.32 126.02,28.09 130.21,28.09 130.6,27.7 130.6,27.07 128.18,24.66 ; 5 cut-outs
GND on BOTTOM: 154.34,27.2 154.34,29.74 154.47,29.86 154.47,38.12 154.22,38.37 154.22,39.26 154.47,39.52 157.75,39.52 158.13,39.13 158.13,35.43 158.79,34.77 158.79,29.1 156.88,27.2 ; 12 cut-outs
GND on BOTTOM: 123.31,55.31 123.1,55.52 123.1,56.84 123.18,56.91 124.45,56.91 124.68,57.14 124.68,57.73 124.8,57.85 125.26,57.85 125.29,57.83 125.29,55.69 124.91,55.31 ; 1 cut-out
GND on BOTTOM: 57.06,21.74 56.68,22.12 56.68,24.4 57.19,24.91 63.03,24.91 63.16,24.78 63.16,22.5 62.78,22.12 58.97,22.12 58.59,21.74 ; 7 cut-outs
GND on BOTTOM: 23.97,74.87 23.28,75.56 23.28,75.84 23.13,75.99 22.14,75.99 21.63,76.5 21.63,77.03 21.81,77.21 24.58,77.21 25.06,76.73 28.41,76.73 28.49,76.65 28.49,75.38 27.98,74.87 ; 6 cut-outs
GND on BOTTOM: 155.69,62.71 155.56,62.83 155.56,64.03 155.64,64.1 156.5,64.1 156.55,64.05 156.55,62.83 156.43,62.71 ; 1 cut-out
GND on BOTTOM: 167.3,97.43 166.92,97.81 166.92,98.32 166.54,98.7 165.9,98.7 165.65,98.95 165.65,100.22 165.77,100.35 169.33,100.35 169.97,99.71 169.97,98.19 169.2,97.43 ; 4 cut-outs
GND on BOTTOM: 64.94,86.76 64.94,87.65 63.89,87.65 63.89,90.82 64,90.92 64,92.8 64.17,92.98 64.17,94.89 64.9,95.61 64.9,97.77 65.06,97.94 69.81,97.94 70.02,97.73 70.02,90.9 69.81,90.7 66.21,90.7 66.08,90.57 66.08,86.89 65.95,86.76 ; 3 cut-outs
GND on BOTTOM: 97.58,96.54 97.58,97.55 97.83,97.81 97.83,98.19 98.08,98.44 99.35,98.44 99.73,98.06 99.73,96.67 99.61,96.54
GND on BOTTOM: 149.9,39.77 149.65,40.02 149.65,40.4 146.72,43.33 146.72,43.71 146.34,44.09 146.34,45.99 145.84,46.5 109.64,46.5 108.88,47.26 108.88,47.9 109.51,48.53 127.42,48.53 128.82,47.14 131.48,47.14 132.37,48.02 134.41,48.02 135.17,47.26 139.1,47.26 139.82,47.97 142.91,47.97 143.6,48.66 144.92,48.66 144.95,48.63 144.95,48.15 145.2,47.9 146.09,47.9 148.38,50.18 153.2,50.18 155.61,47.77 155.61,47.74 155.97,47.39 155.97,45.92 156.3,45.59 156.3,45.46 156.33,45.46 156.6,45.18 159.45,45.18 159.68,44.95 159.68,43.27 159.3,42.89 156.07,42.89 152.95,39.77 ; 23 cut-outs
GND on BOTTOM: 12.74,56.15 11.85,57.04 11.85,59.07 11.6,59.33 10.71,59.33 10.45,59.58 10.45,62.25 10.58,62.38 13.5,62.38 14.52,63.39 15.66,63.39 15.79,63.26 15.79,62.38 16.04,62.12 16.04,57.04 15.15,56.15 ; 2 cut-outs
GND on BOTTOM: 46.78,82.57 46.52,82.82 46.52,83.46 46.65,83.58 49.82,83.58 49.95,83.46 49.95,82.7 49.82,82.57 ; 1 cut-out
GND on BOTTOM: 166.16,74.57 165.9,74.82 164.25,74.82 164.12,74.95 164.12,75.84 164.4,76.12 164.66,76.12 166.28,77.74 166.28,79.77 166.66,80.16 168.19,80.16 168.44,79.9 172.28,79.9 172.51,79.67 172.51,75.33 170.7,75.33 170.63,75.41 169.69,75.41 169.58,75.3 169.58,74.95 169.46,74.82 168.06,74.82 167.81,74.57 ; 8 cut-outs
GND on BOTTOM: 48.3,46.37 48.17,46.5 48.17,51.71 48.81,52.34 49.57,52.34 49.82,52.6 50.46,52.6 50.71,52.85 51.6,52.85 51.73,52.72 51.73,51.2 53.89,49.04 53.89,48.53 51.73,46.37
GND on BOTTOM: 62.4,12.72 62.02,13.1 62.02,14.24 62.52,14.75 70.52,14.75 70.78,14.5 70.78,13.56 70.7,13.48 69.13,13.48 69,13.35 67.98,13.35 67.35,12.72 ; 6 cut-outs
GND on BOTTOM: 22.65,82.44 22.26,82.82 22.26,83.71 22.39,83.84 25.19,83.84 25.31,83.97 25.31,84.47 25.19,84.6 25.19,85.62 25.44,85.87 25.95,85.87 26.07,85.74 26.07,82.82 25.69,82.44 ; 5 cut-outs
GND on BOTTOM: 102.02,13.23 102.02,15.64 102.4,16.02 103.54,16.02 103.8,15.77 103.8,14.24 102.78,13.23 ; 1 cut-out
GND on BOTTOM: 83.61,96.54 82.46,97.68 78.53,97.68 78.4,97.81 78.4,98.44 78.53,98.57 79.54,98.57 79.92,98.95 81.57,98.95 82.34,99.71 82.34,100.48 82.72,100.86 83.61,100.86 83.73,100.73 83.73,98.32 83.86,98.19 85.64,98.19 85.76,98.06 85.76,96.79 85.51,96.54 ; 4 cut-outs
GND on BOTTOM: 27.09,45.48 26.58,45.99 26.58,48.41 26.71,48.53 29.63,48.53 30.27,47.9 30.27,45.74 30.01,45.48 ; 3 cut-outs
GND on L2SGND: 1,0.51 0.65,0.65 0.51,1 0.51,8 0.65,8.35 1,8.49 1.17,8.49 2.24,8.93 2.68,10 2.68,63 2.38,63.71 1.67,64.01 0.51,64.01 0.51,65.21 3.75,65.21 4.88,64.74 5.63,65.72 5.63,74.67 4.88,75.64 3.75,75.17 0.51,75.17 0.51,77.21 1.67,77.21 2.38,77.51 2.68,78.22 2.68,80.21 9.52,80.21 10.49,80.96 10.03,82.09 10.03,94.95 10.49,96.08 9.52,96.83 0.81,96.83 0.81,102.95 0.95,103.3 1.3,103.44 3.89,103.44 4.07,103.4 4.23,103.3 4.4,103.13 4.89,102.81 5.46,102.69 46.3,102.69 47.37,103.13 47.95,104.55 48.3,104.69 76.49,104.69 77.3,104.93 78.04,105.77 78.3,105.84 191,105.84 191.35,105.7 191.49,105.35 191.49,58.95 191.38,58.64 191.1,58.47 187.69,54.3 191.1,50.13 191.38,49.96 191.49,49.65 191.49,45.9 191.93,44.83 193,44.39 195,44.39 195.35,44.25 195.49,43.9 195.49,1 195.35,0.65 195,0.51 ; 3 cut-outs
GND on L3SGND: 1,0.51 0.65,0.65 0.51,1 0.51,8 0.65,8.35 1,8.49 1.17,8.49 2.24,8.93 2.68,10 2.68,63 2.38,63.71 1.67,64.01 0.51,64.01 0.51,65.21 3.75,65.21 4.88,64.74 5.63,65.72 5.63,68.73 5.63,68.73 5.63,72.03 5.63,72.03 5.63,74.67 4.88,75.64 3.75,75.17 0.51,75.17 0.51,77.21 1.67,77.21 2.38,77.51 2.68,78.22 2.68,80.21 9.52,80.21 10.49,80.96 10.03,82.09 10.03,94.95 10.49,96.08 9.52,96.83 0.81,96.83 0.81,102.95 0.95,103.3 1.3,103.44 3.89,103.44 4.07,103.4 4.23,103.3 4.4,103.13 4.89,102.81 5.46,102.69 46.3,102.69 47.37,103.13 47.95,104.55 48.3,104.69 54.65,104.69 54.65,104.69 76.49,104.69 77.3,104.93 78.04,105.76 78.3,105.84 145.04,105.84 191,105.84 191.35,105.7 191.49,105.35 191.49,58.95 191.38,58.64 191.1,58.47 187.69,54.3 191.1,50.13 191.38,49.96 191.49,49.65 191.49,45.9 191.93,44.83 193,44.39 195,44.39 195.35,44.25 195.49,43.9 195.49,1 195.35,0.65 195,0.51 161.69,0.51 10.6,0.51 ; 4 cut-outs
GND on L3SGND: 134.28,101.36 134.28,97.68 135.29,96.67 140.63,96.67 141.64,97.68 141.64,103.14 141.39,103.4 136.31,103.4
GND on L3SGND: 67.86,11.83 51.47,11.83 46.14,17.16 46.14,21.23 46.52,21.61 53.51,21.61 54.4,22.5 62.52,22.5 65.06,19.96 69.38,19.96 69.64,19.7 69.64,13.61
GND on L3SGND: 73.83,2.18 88.81,2.18 89.19,2.56 118.91,2.56 119.55,3.19 120.94,3.19 123.18,5.43 121.6,7 121.6,13.99 122.7,15.08 122.7,21.76 121.83,22.62 117.9,22.62 115.23,19.96 95.67,19.96 94.15,21.48 81.7,21.48 80.68,20.47 77.51,20.47 75.22,18.18 75.22,8.53 73.19,6.5 73.19,2.81
GND on L3SGND: 75.6,75.96 72.56,75.96 69.89,73.3 66.46,73.3 64.05,70.88 64.05,67.71 63.54,67.2 62.65,67.2 62.27,66.82 62.27,65.8 62.78,65.3 68.87,65.3 71.92,68.34 71.92,72.03 73.06,73.17 75.99,73.17 76.75,73.93 76.75,74.82
GND on L3SGND: 136.18,17.16 132.75,17.16 129.71,14.12 129.71,9.54 130.72,8.53 134.28,8.53 137.2,11.45 137.2,16.15
GND on L3SGND: 156,8.53 172.51,8.53 174.28,10.31 174.28,11.58 172.63,13.23 172.63,26.94 172.38,27.2 169.71,27.2 169.46,26.94 169.46,25.42 167.17,23.13 167.17,22.88 155.49,11.19 155.49,9.04
GND on L4SGND: outline of 90 points within 0.51,0.51 195.49,105.84 ; 3 cut-outs
GND on L4SGND: 64.43,73.04 72.18,73.04 72.43,72.79 72.43,66.95 71.92,66.44 68.62,66.44 67.48,65.3 63.41,65.3 62.65,66.06 62.65,66.57 63.03,66.95 63.41,66.95 63.92,67.46 63.92,72.54
GND on L4SGND: 37.89,61.99 46.01,61.99 47.03,60.98 47.03,55.64 41.95,50.56 41.95,45.87 37.25,41.17 34.2,41.17 32.55,42.82 32.55,49.42 30.27,51.71 30.27,55.9 32.68,58.31 34.2,58.31
GND on L4SGND: 151.04,91.97 152.69,90.32 152.69,88.54 152.57,88.41 148.38,88.41 147.87,87.9 144.57,87.9 143.55,88.92 143.55,91.2 144.82,92.47 146.47,92.47 146.98,91.97
GND on L4SGND: 75.41,76.15 76.62,74.95 76.62,74.44 76.24,74.06 71.67,74.06 71.29,74.44 71.29,75.2 72.24,76.15
GND on L4SGND: 63.03,76.22 69.89,76.22 72.56,78.89 72.56,87.39 76.87,91.71 76.87,92.47 76.37,92.98 74.08,92.98 73.45,92.35 70.52,92.35 70.02,92.86 70.02,94.63 69.76,94.89 64.05,94.89 63.67,94.51 63.67,77.74 63.41,77.49 62.9,77.49 62.65,77.23 62.65,76.6
GND on L4SGND: 166.66,89.43 177.84,89.43 179.74,87.52 179.74,77.87 176.06,74.19 168.06,74.19 165.77,76.47 165.77,88.54
GND on L5GND: 1,0.51 0.65,0.65 0.51,1 0.51,8 0.65,8.35 1,8.49 1.17,8.49 2.24,8.93 2.68,10 2.68,63 2.38,63.71 1.67,64.01 0.51,64.01 0.51,65.21 3.75,65.21 4.88,64.74 5.63,65.72 5.63,74.67 4.88,75.64 3.75,75.17 0.51,75.17 0.51,77.21 1.67,77.21 2.38,77.51 2.68,78.22 2.68,80.21 9.52,80.21 10.49,80.96 10.03,82.09 10.03,94.95 10.49,96.08 9.52,96.83 0.81,96.83 0.81,102.95 0.95,103.3 1.3,103.44 3.89,103.44 4.07,103.4 4.23,103.3 4.4,103.13 4.89,102.81 5.46,102.69 46.3,102.69 47.37,103.13 47.95,104.55 48.3,104.69 76.49,104.69 77.3,104.93 78.04,105.76 78.3,105.84 191,105.84 191.35,105.7 191.49,105.35 191.49,58.95 191.38,58.64 191.1,58.47 187.69,54.3 191.1,50.13 191.38,49.96 191.49,49.65 191.49,45.9 191.93,44.83 193,44.39 195,44.39 195.35,44.25 195.49,43.9 195.49,1 195.35,0.65 195,0.51 ; 1 cut-out
GND on L6: outline of 162 points within 0.51,0.51 195.49,105.84 ; 2 cut-outs
GND on L6: 170.85,84.6 178.73,84.6 179.49,83.84 179.49,76.85 178.6,75.96 177.71,75.96 172.51,70.76 170.73,70.76 166.54,74.95 166.54,77.87 170.22,81.55 170.22,83.97
GND on L6: 106.85,28.34 108.37,28.34 109.13,27.58 119.93,27.58 120.05,27.7 129.83,27.7 130.6,26.94 132.75,26.94 133.26,27.45 144.18,27.45 146.22,25.42 146.22,23.64 145.84,23.26 144.82,23.26 144.18,23.89 132.5,23.89 130.72,22.12 126.4,22.12 126.02,21.74 106.85,21.74 105.2,23.39 105.2,26.69
GND on L6: 135.8,96.79 136.18,96.79 136.31,96.67 141.14,96.67 141.39,96.41 141.39,95.01 141.14,94.76 136.56,94.76 135.68,95.65 135.68,96.67
GND on L6: 134.66,8.78 135.17,9.29 150.66,9.29 150.79,9.42 150.79,9.67 142.91,17.54 129.45,17.54 127.04,15.13 127.04,9.54 127.8,8.78
GND on L6: 70.02,93.49 70.02,92.73 70.19,92.55 73.52,92.55 73.83,92.86 74.97,92.86 75.99,91.84 75.99,90.95 75.35,90.32 75.35,89.05 74.21,87.9 71.79,87.9 69,85.11 63.54,85.11 62.4,86.25 62.4,87.39 63.67,88.66 63.67,92.73 64.81,93.87 69.64,93.87
GND on L6: 64.43,83.71 69.64,83.71 71.67,85.74 72.68,85.74 73.06,85.36 73.06,80.54 76.76,76.84 76.76,74.71 76.62,74.57 61.89,74.57 60.87,75.58 60.87,76.35 62.02,77.49 63.16,77.49 63.79,78.12 63.79,83.08
GND on L6: 32.55,87.65 34.71,87.65 35.09,87.27 35.09,78.89 32.04,75.84 30.39,75.84 30.14,76.09 30.14,82.95 30.52,83.33 31.54,83.33 32.17,83.97 32.17,87.27
GND on L6: 72.3,67.71 70.78,66.19 67.86,66.19 67.22,65.55 63.16,65.55 62.65,66.06 62.65,66.57 63.03,66.95 63.41,66.95 63.92,67.46 63.92,72.54 64.43,73.04 71.79,73.04 72.3,72.54
GND on L6: 46.52,59.71 50.59,59.71 52.49,61.61 54.78,61.61 55.54,60.85 70.52,60.85 70.52,59.58 63.03,52.09 63.03,39.39 62.65,39.01 51.22,39.01 45.38,44.85 45.38,58.57
GND on L6: 16.68,71.65 19.98,71.65 20.49,71.14 20.49,66.44 17.69,63.65 17.69,56.28 16.42,55.01 13.88,55.01 12.74,56.15 12.74,59.33 14.64,61.23 14.64,63.26 13.63,64.28 13.63,68.6
GND on L6: 24.04,74.57 19.85,78.76 19.6,78.76 17.44,80.92 17.44,89.3 18.58,90.44 25.82,90.44 27.09,89.17 27.09,76.73 24.93,74.57
GND on L6: 47.16,86.51 50.84,86.51 51.09,86.25 51.09,83.2 50.71,82.82 50.71,79.52 53.13,77.11 53.13,69.49 51.6,67.96 46.78,67.96 46.27,68.47 46.27,73.55 44.11,75.71 44.11,78.38 46.14,80.41 46.14,85.49
GND on L7GND: 1,0.51 0.65,0.65 0.51,1 0.51,8 0.65,8.35 1,8.49 1.17,8.49 2.24,8.93 2.68,10 2.68,63 2.38,63.71 1.67,64.01 0.51,64.01 0.51,65.21 3.75,65.21 4.88,64.74 5.63,65.72 5.63,74.67 4.88,75.64 3.75,75.17 0.51,75.17 0.51,77.21 1.67,77.21 2.38,77.51 2.68,78.22 2.68,80.21 9.52,80.21 10.49,80.96 10.03,82.09 10.03,94.95 10.49,96.08 9.52,96.83 0.81,96.83 0.81,102.95 0.95,103.3 1.3,103.44 3.89,103.44 4.07,103.4 4.23,103.3 4.4,103.13 4.89,102.81 5.46,102.69 46.3,102.69 47.37,103.13 47.95,104.55 48.3,104.69 76.49,104.69 77.3,104.93 78.04,105.76 78.3,105.84 191,105.84 191.35,105.7 191.49,105.35 191.49,58.95 191.38,58.64 191.1,58.47 187.69,54.3 191.1,50.13 191.38,49.96 191.49,49.65 191.49,45.9 191.93,44.83 193,44.39 195,44.39 195.35,44.25 195.49,43.9 195.49,1 195.35,0.65 195,0.51 ; 29 cut-outs
0D6V_VREF_S0 on TOP: 46.65,28.47 45.76,29.36 45.76,37.48 45.89,37.61 46.27,37.61 46.52,37.86 46.52,39.64 47.16,40.28 47.16,40.4 47.41,40.66 47.41,42.06 49.06,43.71 49.06,47.14 49.44,47.52 51.86,47.52 51.98,47.39 51.98,46.25 51.73,45.99 51.22,45.99 51.09,45.87 51.09,29.36 51.35,29.1 102.53,29.1 102.91,29.48 148.38,29.48 148.76,29.86 152.06,29.86 152.44,29.48 152.44,28.72 152.19,28.47 ; 30 cut-outs
0D6V_VREF_S0 on BOTTOM: 149.14,27.07 148.63,27.58 148.63,40.02 148.76,40.15 149.52,40.15 149.65,40.02 149.65,39.77 149.9,39.52 153.84,39.52 153.96,39.39 153.96,38.37 154.22,38.12 154.22,29.86 153.96,29.61 153.96,27.32 153.71,27.07 ; 31 cut-outs
1D0V_PWR on BOTTOM: 168.44,80.16 168.31,80.28 166.92,80.28 166.66,80.54 166.66,88.03 173.62,88.03 174.31,87.34 177.99,87.34 178.86,86.48 178.86,83.97 178.6,83.71 178.6,81.22 177.53,80.16 ; 7 cut-outs
1D0V_S5 on TOP: 153.46,76.6 153.2,76.85 153.2,77.36 153.33,77.49 153.33,78.63 153.58,78.89 153.71,78.89 153.79,78.81 157.47,78.81 157.6,78.68 157.6,76.68 157.52,76.6 ; 5 cut-outs
1D0V_S5 on TOP: 125.39,75.33 125.13,75.58 125.13,75.96 125.26,76.09 126.15,76.09 126.53,76.47 126.53,76.73 126.28,76.98 126.28,78.25 126.53,78.5 130.85,78.5 131.1,78.25 131.1,77.87 130.98,77.74 130.98,75.58 130.85,75.46 128.69,75.46 128.56,75.58 128.56,76.6 128.44,76.73 128.06,76.73 127.55,76.22 126.79,76.22 126.53,75.96 126.53,75.58 126.28,75.33 ; 6 cut-outs
1D0V_S5 on TOP: 127.04,79.39 126.53,79.9 126.53,80.79 126.66,80.92 127.17,80.92 127.29,81.04 127.29,81.55 127.42,81.68 127.8,81.68 127.93,81.55 127.93,81.43 128.18,81.17 128.56,81.17 129.45,80.28 130.09,80.28 130.6,80.79 132.37,80.79 132.5,80.66 132.5,80.16 131.87,79.52 130.47,79.52 130.34,79.65 128.18,79.65 127.93,79.39 ; 4 cut-outs
1D0V_S5 on BOTTOM: 157.27,91.71 155.16,93.82 154.5,93.82 154.34,93.67 154.34,92.45 154.29,92.4 152.67,92.4 152.62,92.45 152.62,95.06 153.12,95.57 156.15,95.57 156.5,95.22 156.5,95.01 156.49,95 156.49,94.82 156.93,94.38 158.03,94.38 158.66,93.74 160.69,93.74 161.2,93.24 161.2,92.47 160.44,91.71 ; 6 cut-outs
1D0V_S5 on BOTTOM: 152.95,65.17 152.57,65.55 151.42,65.55 151.3,65.68 151.3,69.23 150.92,69.61 150.74,69.61 150.25,70.1 150.25,71.11 150.74,71.6 152.69,71.6 153.96,70.33 153.96,67.07 154.09,66.95 155.23,66.95 155.61,67.33 159.17,67.33 160.57,68.73 160.95,68.73 161.33,69.11 161.33,71.27 161.3,71.29 161.3,72.03 160.82,72.51 160.82,74.31 160.19,74.95 160.19,76.22 159.68,76.73 153.33,76.73 153.07,76.98 153.07,80.54 154.22,81.68 156.5,81.68 158.28,83.46 160.57,83.46 161.58,84.47 162.09,84.47 163.87,86.25 163.87,87.65 164.38,88.16 166.41,88.16 166.54,88.03 166.54,80.28 166.16,79.9 166.16,78 164.45,76.29 164.12,76.29 163.74,75.91 163.74,68.73 160.31,65.3 156.63,65.3 156.5,65.17 ; 9 cut-outs
1D0V_S5 on BOTTOM: 127.42,74.57 127.04,74.95 126.4,74.95 125.96,75.39 125.96,76.54 126.53,77.11 126.53,79.01 126.28,79.27 126.28,80.54 127.04,81.3 128.69,81.3 128.82,81.17 128.82,80.16 129.07,79.9 130.47,79.9 130.85,80.28 130.85,81.17 130.98,81.3 132.37,81.3 132.5,81.17 132.5,80.66 132.12,80.28 132.12,79.39 131.1,78.38 131.1,78 131.48,77.62 131.48,75.58 131.36,75.46 130.21,75.46 129.33,74.57
1D0V_S5 on L3SGND: 162.85,88.03 158.92,91.97 158.92,93.36 159.55,94 160.44,94 161.2,93.24 161.2,93.11 165.77,88.54 165.77,87.14 165.52,86.89 164.25,86.89 163.11,88.03
1D0V_S5 on L3SGND: 157.27,76.73 153.07,76.73 152.69,77.11 152.69,79.52 151.8,80.41 143.8,80.41 142.79,81.43 129.2,81.43 128.94,81.17 128.94,79.39 128.44,78.89 126.79,78.89 126.28,79.39 126.28,82.44 127.8,83.97 130.09,83.97 131.87,85.74 132.5,85.74 133.77,87.01 138.6,87.01 141.14,84.47 144.31,84.47 146.47,82.31 152.69,82.31 153.46,81.55 157.01,81.55 157.9,80.66 157.9,77.36
1D0V_S5 on L4SGND: 151.55,69.23 148.63,69.23 147.36,70.5 147.36,71.01 146.47,71.9 142.15,71.9 141.77,72.28 137.58,72.28 136.95,72.92 134.91,72.92 134.28,73.55 131.36,73.55 130.98,73.93 129.33,73.93 128.06,75.2 125.77,75.2 125.26,75.71 125.26,80.03 126.91,81.68 133.39,81.68 133.52,81.55 138.85,81.55 140.37,80.03 140.37,78.76 140.5,78.63 141.77,78.63 142.28,79.14 145.96,79.14 148.38,81.55 153.84,81.55 154.6,80.79 154.6,80.28 154.98,79.9 156.88,79.9 158.22,78.57 158.22,77.93 158.28,77.87 158.28,75.96
1D0V_VCCPRIM_MPHY on TOP: 151.42,77.23 150.41,78.25 150.41,79.24 151.7,80.54 152.82,80.54 153.07,80.28 153.07,77.62 152.69,77.23 ; 3 cut-outs
1D0V_VCCPRIM_MPHY on BOTTOM: 129.07,80.03 128.94,80.16 128.94,81.17 129.07,81.3 130.47,81.3 130.6,81.17 130.6,80.16 130.47,80.03
1D0V_VCCPRIM_MPHY on L3SGND: 129.07,78.76 129.07,80.92 129.45,81.3 142.41,81.3 143.55,80.16 151.55,80.16 152.19,79.52 152.19,77.62 151.42,76.85 150.15,76.85 149.65,76.35 141.64,76.35 139.74,78.25 139.23,78.25 138.85,77.87 133.52,77.87 133.26,78.12 133.26,78.5 133.01,78.76 132.5,78.76 132.25,78.5 129.33,78.5
1D2V_HDMI on TOP: 19.22,77.11 19.09,77.23 19.09,78.12 19.22,78.25 21.5,78.25 22.01,78.76 23.92,78.76 24.17,78.5 24.17,77.36 23.92,77.11 ; 2 cut-outs
1D2V_HDMI on BOTTOM: 21.07,77.41 20.92,77.56 20.89,77.56 20.89,78.68 21.12,78.91 22.52,78.91 22.72,79.11 24.93,79.11 25.05,79 25.05,78.24 24.5,77.69 24.5,77.54 24.37,77.41 ; 5 cut-outs
1D2V_HDMI_R on TOP: 26.3,79.14 26.18,79.27 26.18,79.95 26.51,80.28 28.74,80.28 29.12,79.9 29.12,79.27 29,79.14 ; 2 cut-outs
1D2V_HDMI_R on BOTTOM: 25.19,78.55 25.19,79.14 25.08,79.24 24.65,79.24 24.17,79.72 24.17,80.51 24.42,80.76 26.71,80.76 27.24,81.3 27.83,81.3 28.46,80.66 28.46,78.55 ; 3 cut-outs
1D2V_HDMI_VDD on BOTTOM: 22.47,83.97 22.37,84.07 22.37,84.4 22.47,84.5 23.23,84.5 23.41,84.68 23.41,85.08 23.13,85.36 22.24,85.36 21.88,85.72 21.88,86.58 22.02,86.72 22.45,86.72 22.7,86.48 23.25,86.48 25.19,84.55 25.19,84.09 25.06,83.97 ; 4 cut-outs
1D2V_HDMI_VDDTX on BOTTOM: 20.36,82.44 20.23,82.57 20.23,86.25 20.28,86.3 20.77,86.3 20.97,86.1 21.5,86.1 21.76,85.84 21.76,85.51 21.73,85.51 21.5,85.29 21.25,85.29 20.99,85.03 20.99,84.75 21.6,84.14 21.6,82.67 21.38,82.44 ; 4 cut-outs
1D2V_HDMI_VIN on BOTTOM: 28.74,76.42 28.64,76.52 28.64,80.03 28.74,80.13 30.9,80.13 31.23,80.46 31.23,81.43 31.48,81.68 33.29,81.68 33.47,81.5 33.47,79.85 33.41,79.8 31.84,79.8 31.66,79.62 31.66,76.5 31.59,76.42
1D2V_S3 on TOP: 115.86,30.12 115.61,30.37 115.61,35.58 115.43,35.76 114.29,35.76 114.14,35.91 114.14,36.11 112.51,37.74 112.05,37.74 112.05,37.86 111.93,37.99 108.37,37.99 108.37,39.13 108.12,39.39 107.61,39.39 107.48,39.52 107.48,40.28 107.1,40.66 107.1,41.22 107.35,41.47 107.35,41.93 107.1,42.18 107.1,42.56 106.85,42.82 106.85,43.2 106.97,43.33 108.75,43.33 110.15,44.72 110.15,46.12 114.09,50.06 114.09,66.69 114.07,66.71 114.07,67.65 112.92,68.8 112.92,69.41 112.99,69.49 114.97,69.49 115.23,69.74 115.23,70.12 115.74,70.12 115.74,69.61 115.86,69.49 117.64,69.49 118.28,70.12 118.45,70.12 118.45,70.25 118.61,70.4 120.44,70.4 120.44,70.38 121.32,69.49 122.98,69.49 122.98,66.69 123.48,66.19 123.48,60.22 123.14,59.87 123.14,52.51 123.99,51.66 123.99,47.01 124.75,46.25 142.41,46.25 144.06,44.6 145.58,44.6 145.84,44.34 145.84,38.75 145.2,38.12 145.2,36.98 145.45,36.72 145.45,33.8 145.96,33.29 145.96,32.02 145.84,31.9 145.45,31.9 144.82,31.26 144.82,30.75 144.18,30.12 ; 99 cut-outs
1D2V_S3 on TOP: 177.59,58.44 177.46,58.57 177.46,64.28 179.24,64.28 179.24,63.14 179.49,62.88 180.13,62.88 180.13,61.49 179.62,60.98 179.62,59.2 178.86,58.44 ; 3 cut-outs
1D2V_S3 on TOP: 53.73,29.36 53.35,29.74 53.35,45.15 54.65,46.45 64.3,46.45 65.57,47.72 65.57,51.78 66.64,52.85 67.1,52.85 67.25,53 67.25,53.46 67.98,54.2 67.98,56.36 67.73,56.61 66.03,56.61 65.95,56.53 64.43,56.53 63.29,55.39 58.46,55.39 58.46,56.91 59.09,57.55 62.02,57.55 65.32,60.85 65.32,61.44 65.44,61.56 72.56,61.56 75.48,58.64 75.48,56.36 77.26,54.58 84.62,54.58 88.91,50.28 88.91,49.83 89.45,49.29 89.7,49.29 93.13,45.87 93.13,38.7 92.62,38.19 90.13,38.19 89.73,38.6 88.51,38.6 87.31,37.41 87.31,37.08 84.11,33.88 84.11,32.23 84.75,31.59 86.78,31.59 87.29,31.08 87.29,29.56 87.08,29.36 ; 89 cut-outs
1D2V_S3 on BOTTOM: 62.52,56.79 62.02,57.3 62.02,61.11 62.4,61.49 68.95,61.49 69.51,60.93 69.51,58.69 69.25,58.44 68.75,58.44 67.73,57.42 67.73,56.91 67.6,56.79 ; 5 cut-outs
1D2V_S3 on L3SGND: 83.1,74.06 75.48,66.44 75.48,64.66 72.43,61.61 66.33,61.61 64.94,60.22 64.94,55.9 48.05,39.01 48.05,29.48 49,28.53 149.33,28.53 151.68,30.88 151.68,37.74 146.6,42.82 146.6,48.79 132.88,62.5 132.88,63.01 124.5,71.39 111.29,71.39 110.4,72.28 94.53,72.28 92.75,74.06
1D2V_VCCSFR_OC on TOP: 176.7,60.6 176.57,60.72 176.57,62.38 176.19,62.76 175.81,62.76 175.81,63.26 176.19,63.26 176.44,63.52 177.2,63.52 177.33,63.39 177.33,61.49 177.2,61.36 177.2,60.6
1D8V_PWR on BOTTOM: 170.47,6.62 170.35,6.75 170.35,8.53 169.58,9.29 169.58,10.86 169.81,11.09 171.64,11.09 171.74,11.19 172.76,11.19 172.89,11.07 172.89,8.53 172.63,8.27 172.63,6.88 172.38,6.62 ; 5 cut-outs
1D8V_S5 on TOP: 153.2,72.15 152.95,72.41 152.95,73.81 154.09,74.95 154.85,74.95 154.98,74.82 154.98,72.38 154.75,72.15 ; 1 cut-out
1D8V_S5 on BOTTOM: 149.37,71.04 149.24,71.16 149.24,75.61 149.34,75.71 150.03,75.71 150.28,75.46 150.28,72.92 150.92,72.28 150.92,72.03 149.92,71.04 ; 4 cut-outs
1D8V_S5 on BOTTOM: 173.04,6.57 172.96,6.65 172.96,7.92 173.24,8.2 173.24,9.8 173.62,10.18 173.62,11.07 173.75,11.19 175.53,11.19 176.8,9.92 176.8,9.04 176.67,8.91 174.77,8.91 174.77,8.65 174.51,8.4 174,8.4 173.57,7.97 173.57,6.65 173.5,6.57 ; 1 cut-out
1D8V_S5 on L6: 171.62,1.8 171.87,1.54 174.79,1.54 177.46,4.21 177.46,5.03 178.73,6.3 178.73,8.78 177.84,9.67 176.57,9.67 175.81,8.91 175.81,5.86 174.16,4.21 172,4.21 171.24,3.45 162.09,3.45 161.58,2.94 161.58,2.05 161.84,1.8
1D8V_VCCPRIM on TOP: 155.36,72.92 155.23,73.04 155.23,74.82 155.36,74.95 156.88,74.95 157.01,74.82 157.01,74.41 156.66,74.06 156.66,72.99 156.58,72.92 ; 1 cut-out
1D8V_VCCPRIM on TOP: 132.37,76.75 132.26,76.87 132.26,77.98 132.25,78 132.25,79.27 132.32,79.34 133.49,79.34 133.57,79.27 133.57,78.45 134.02,78 134.02,77.11 133.76,76.84 133.27,76.84 133.19,76.75 ; 3 cut-outs
1D8V_VCCPRIM on L3SGND: 132.5,78.63 132.88,78.63 133.14,78.38 133.14,78 133.39,77.74 139.1,77.74 139.36,78 139.74,78 141.9,75.84 146.98,75.84 147.36,76.22 149.9,76.22 150.28,76.6 152.06,76.6 152.57,76.09 154.85,76.09 156.63,74.31 156.63,72.92 155.74,72.03 151.68,72.03 151.17,72.54 140.12,72.54 137.07,75.58 133.26,75.58 132.25,76.6 132.25,78.38
2D5V_S3 on BOTTOM: outline of 220 points within 53.25,24.66 146.47,46.37 ; 67 cut-outs
3D3V_FPR_VDD on BOTTOM: 182.28,86.63 181.9,87.01 180.76,87.01 180.76,87.65 181.4,87.65 181.65,87.9 181.65,89.05 181.14,89.55 181.14,90.06 181.52,90.44 182.79,90.44 183.68,91.33 185.59,91.33 186.09,90.82 186.09,89.81 185.84,89.55 184.32,89.55 183.94,89.17 183.94,87.14 183.43,86.63 ; 3 cut-outs
3D3V_HDMI_VDD on BOTTOM: 21.04,86.25 20.79,86.51 20.26,86.51 20.16,86.61 20.16,88.77 20.64,89.25 21.58,89.25 21.71,89.12 21.71,88.64 21.48,88.41 21.04,88.41 20.87,88.23 20.87,87.27 21.25,86.89 21.63,86.89 21.76,86.76 21.76,86.38 21.63,86.25
3D3V_LCDVDD_R on TOP: 100.98,101.54 100.88,101.64 100.88,103.29 101,103.42 103.16,103.42 103.47,103.12 103.47,102.41 102.6,101.54
3D3V_LCDVDD_R on BOTTOM: 101,102.25 100.88,102.38 100.88,102.76 99.73,103.9 82.21,103.9 80.94,102.63 80.18,102.63 80.18,104.67 80.68,105.17 101,105.17 102.66,103.52 102.66,102.38 102.53,102.25 ; 2 cut-outs
3D3V_LCDVDD_S0 on TOP: 100.62,96.92 100.5,97.05 100.5,98.95 100.93,99.38 100.93,100.78 101.03,100.88 102.58,100.88 102.62,100.84 102.62,97.9 102.15,97.43 101.64,97.43 101.13,96.92 ; 4 cut-outs
3D3V_LCDVDD_S0 on BOTTOM: 100.5,96.54 100.5,98.06 100.62,98.19 102.15,98.19 102.27,98.06 102.27,96.67 102.15,96.54
3D3V_MUX on TOP: 20.94,70.96 20.94,71.72 21.12,71.9 21.76,71.9 22.14,71.52 21.58,70.96
3D3V_MUX on TOP: 17.23,71.47 16.68,72.03 16.68,72.54 16.8,72.66 17.06,72.66 17.62,72.1 18,72.1 18.02,72.08 18.02,71.47
3D3V_OPT on TOP: 153.84,3.45 153.71,3.57 153.71,6.11 153.33,6.5 153.33,7.38 153.07,7.64 152.31,7.64 152.29,7.66 149.11,7.66 146.6,10.18 146.6,15.77 150.41,19.58 150.41,21.48 150.79,21.86 156.5,21.86 156.76,21.61 156.76,19.32 156,18.56 156,18.43 154.47,16.91 149.9,16.91 148.76,15.77 148.76,10.94 149.65,10.05 152.82,10.05 153.71,9.16 154.98,9.16 157.01,7.13 157.01,4.72 155.74,3.45 ; 16 cut-outs
3D3V_OPT on BOTTOM: 154.73,3.7 154.22,4.21 154.22,7 155.23,8.02 158.66,8.02 158.66,6.24 157.77,6.24 157.52,5.99 157.52,4.72 157.65,4.59 158.66,4.59 158.79,4.46 158.79,3.83 158.66,3.7
3D3V_OPT on BOTTOM: 155.11,20.08 154.73,20.47 154.73,21.48 155.36,22.12 158.66,22.12 158.66,20.72 157.77,20.72 157.14,20.08
3D3V_S0 on TOP: 144.16,4.87 143.3,5.73 143.3,14.5 139.99,17.8 128.18,17.8 125.52,20.47 125.52,22.5 125.77,22.75 149.14,22.75 150.03,21.86 150.03,19.2 149.9,19.07 147.36,19.07 146.34,18.05 146.34,9.29 148.5,7.13 148.5,5.43 147.94,4.87 ; 2 cut-outs
3D3V_S0 on TOP: 172,61.49 171.74,61.74 171.74,64.79 172,65.04 173.01,65.04 173.27,64.79 173.27,61.61 173.14,61.49 ; 2 cut-outs
3D3V_S0 on TOP: 17.41,91.59 17.18,91.81 17.18,92.98 16.55,93.62 16.55,93.74 16.8,94 18.07,94 18.23,93.85 18.23,91.66 18.15,91.59
3D3V_S0 on TOP: 188,5.86 187.49,6.37 187.49,7.38 188.25,8.15 189.4,8.15 189.9,8.65 191.17,8.65 191.3,8.53 191.3,5.99 191.17,5.86 ; 4 cut-outs
3D3V_S0 on TOP: 111.67,99.46 111.55,99.59 111.55,103.14 111.93,103.52 127.8,103.52 128.69,104.41 143.93,104.41 144.31,104.03 144.31,102.51 144.06,102.25 141.9,102.25 141.77,102.38 141.77,102.76 141.64,102.89 134.41,102.89 133.9,102.38 133.9,101.62 132.88,100.6 132.37,100.6 132.25,100.73 132.25,101.49 132.12,101.62 129.33,101.62 128.69,100.98 128.69,100.22 128.56,100.09 127.55,100.09 127.42,100.22 127.42,101.49 127.04,101.87 113.73,101.87 112.43,100.58 112.43,99.71 112.18,99.46 ; 4 cut-outs
3D3V_S0 on TOP: 144.54,53.69 144.34,53.89 144.34,56.71 144.54,56.91 145.89,56.91 146.24,56.56 146.24,53.94 145.99,53.69
3D3V_S0 on TOP: 129.71,82.82 129.33,83.2 129.33,84.22 129.45,84.35 129.45,88.41 129.71,88.66 130.21,88.66 130.72,88.16 130.72,84.6 130.47,84.35 130.47,82.82
3D3V_S0 on TOP: 138.22,74.82 138.19,74.85 138.19,75.96 138.22,75.99 138.85,75.99 139.08,76.22 139.74,76.22 140.04,76.52 141.97,76.52 142.13,76.37 142.13,75.96 141.63,75.47 141.63,75.44 141.14,74.95 140.63,74.95 140.5,74.82 ; 1 cut-out
3D3V_S0 on BOTTOM: 37.89,31.77 37.76,31.9 37.76,34.94 38.01,35.2 38.01,36.47 38.14,36.59 39.92,36.59 40.04,36.72 40.04,37.86 40.17,37.99 41.06,37.99 41.31,37.74 41.31,34.94 41.19,34.82 40.43,34.82 39.66,35.58 39.03,35.58 38.65,35.2 38.65,33.04 38.77,32.91 38.77,31.9 38.65,31.77 ; 1 cut-out
